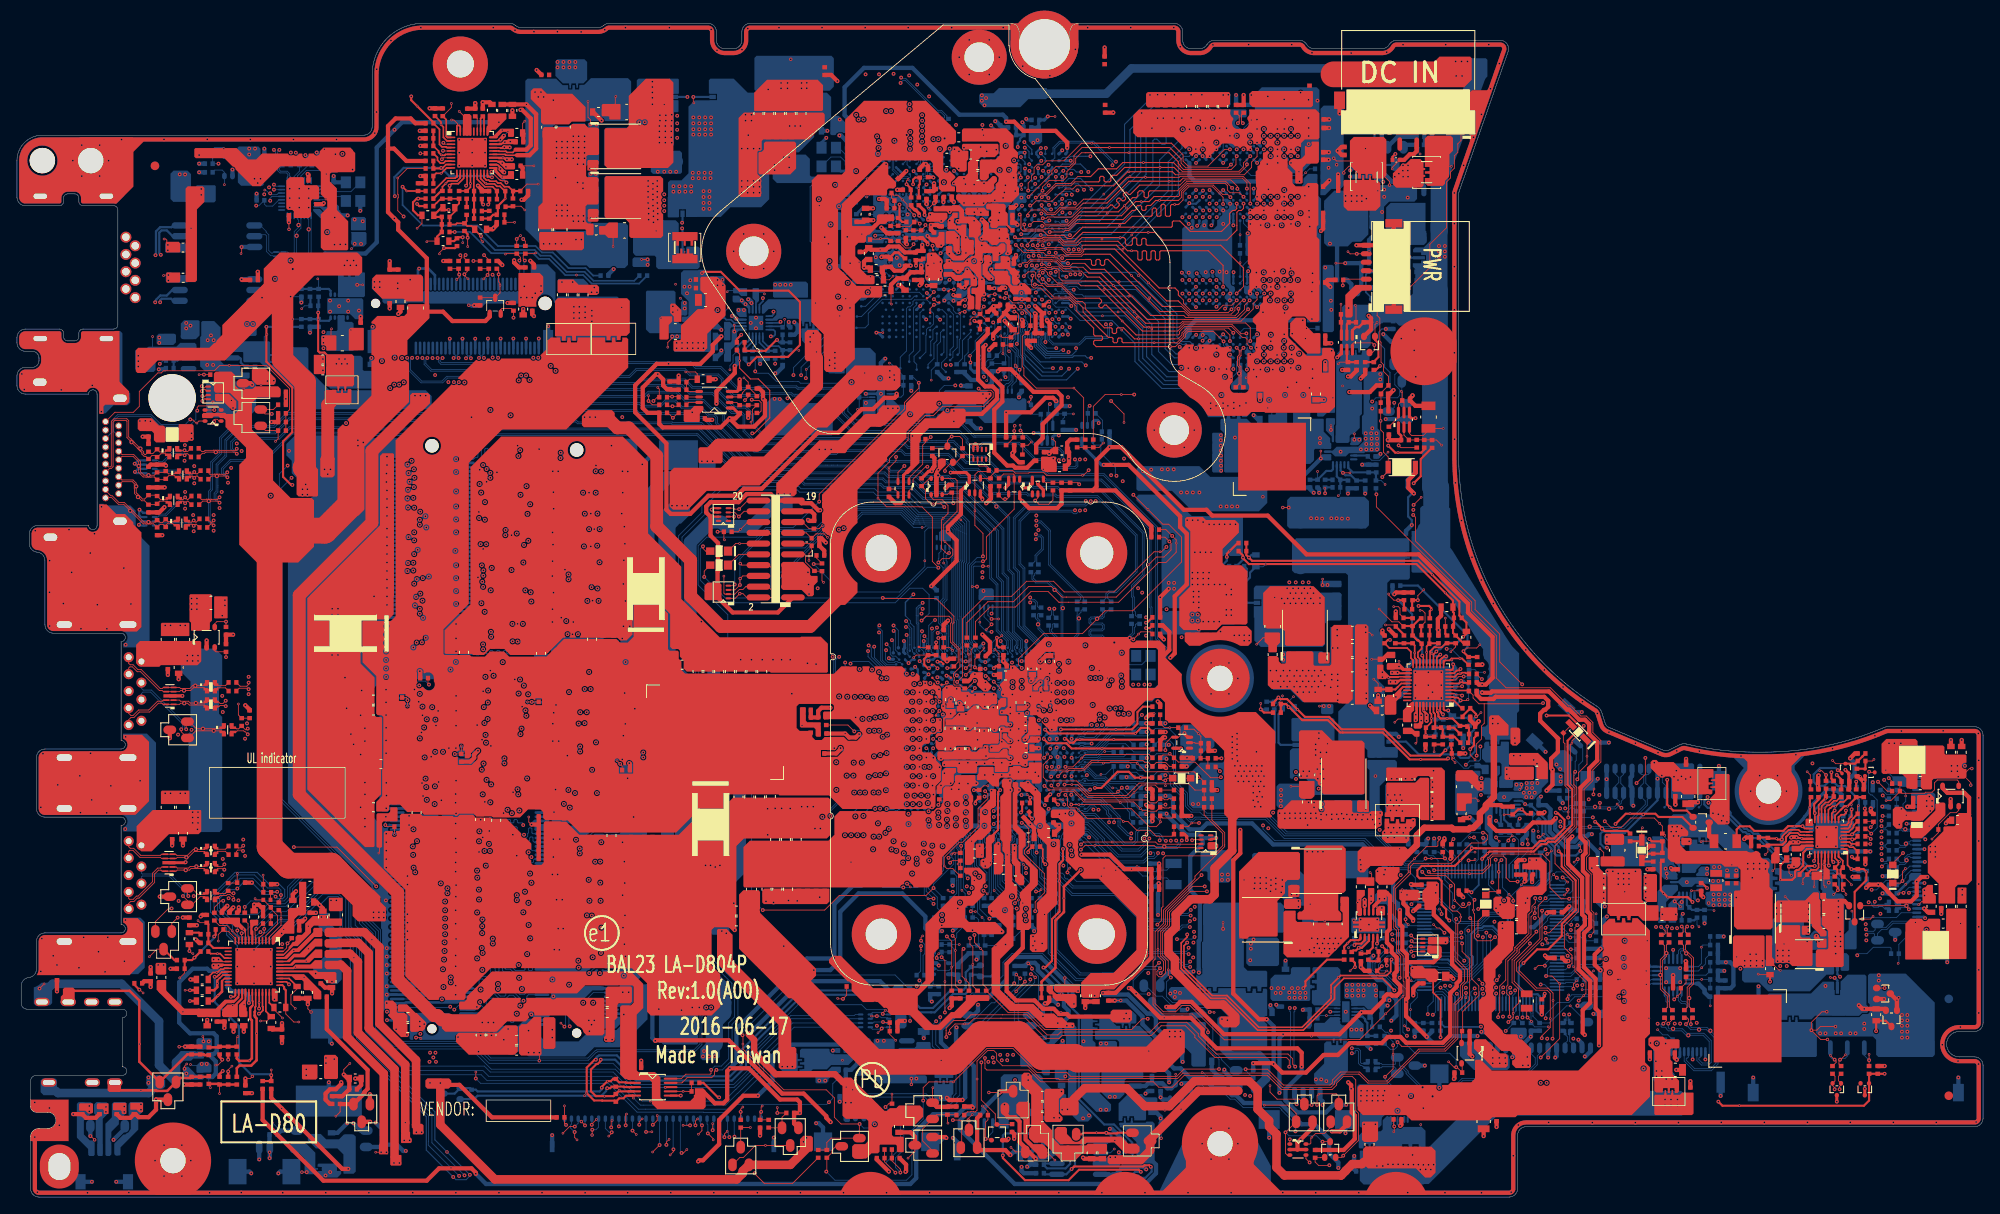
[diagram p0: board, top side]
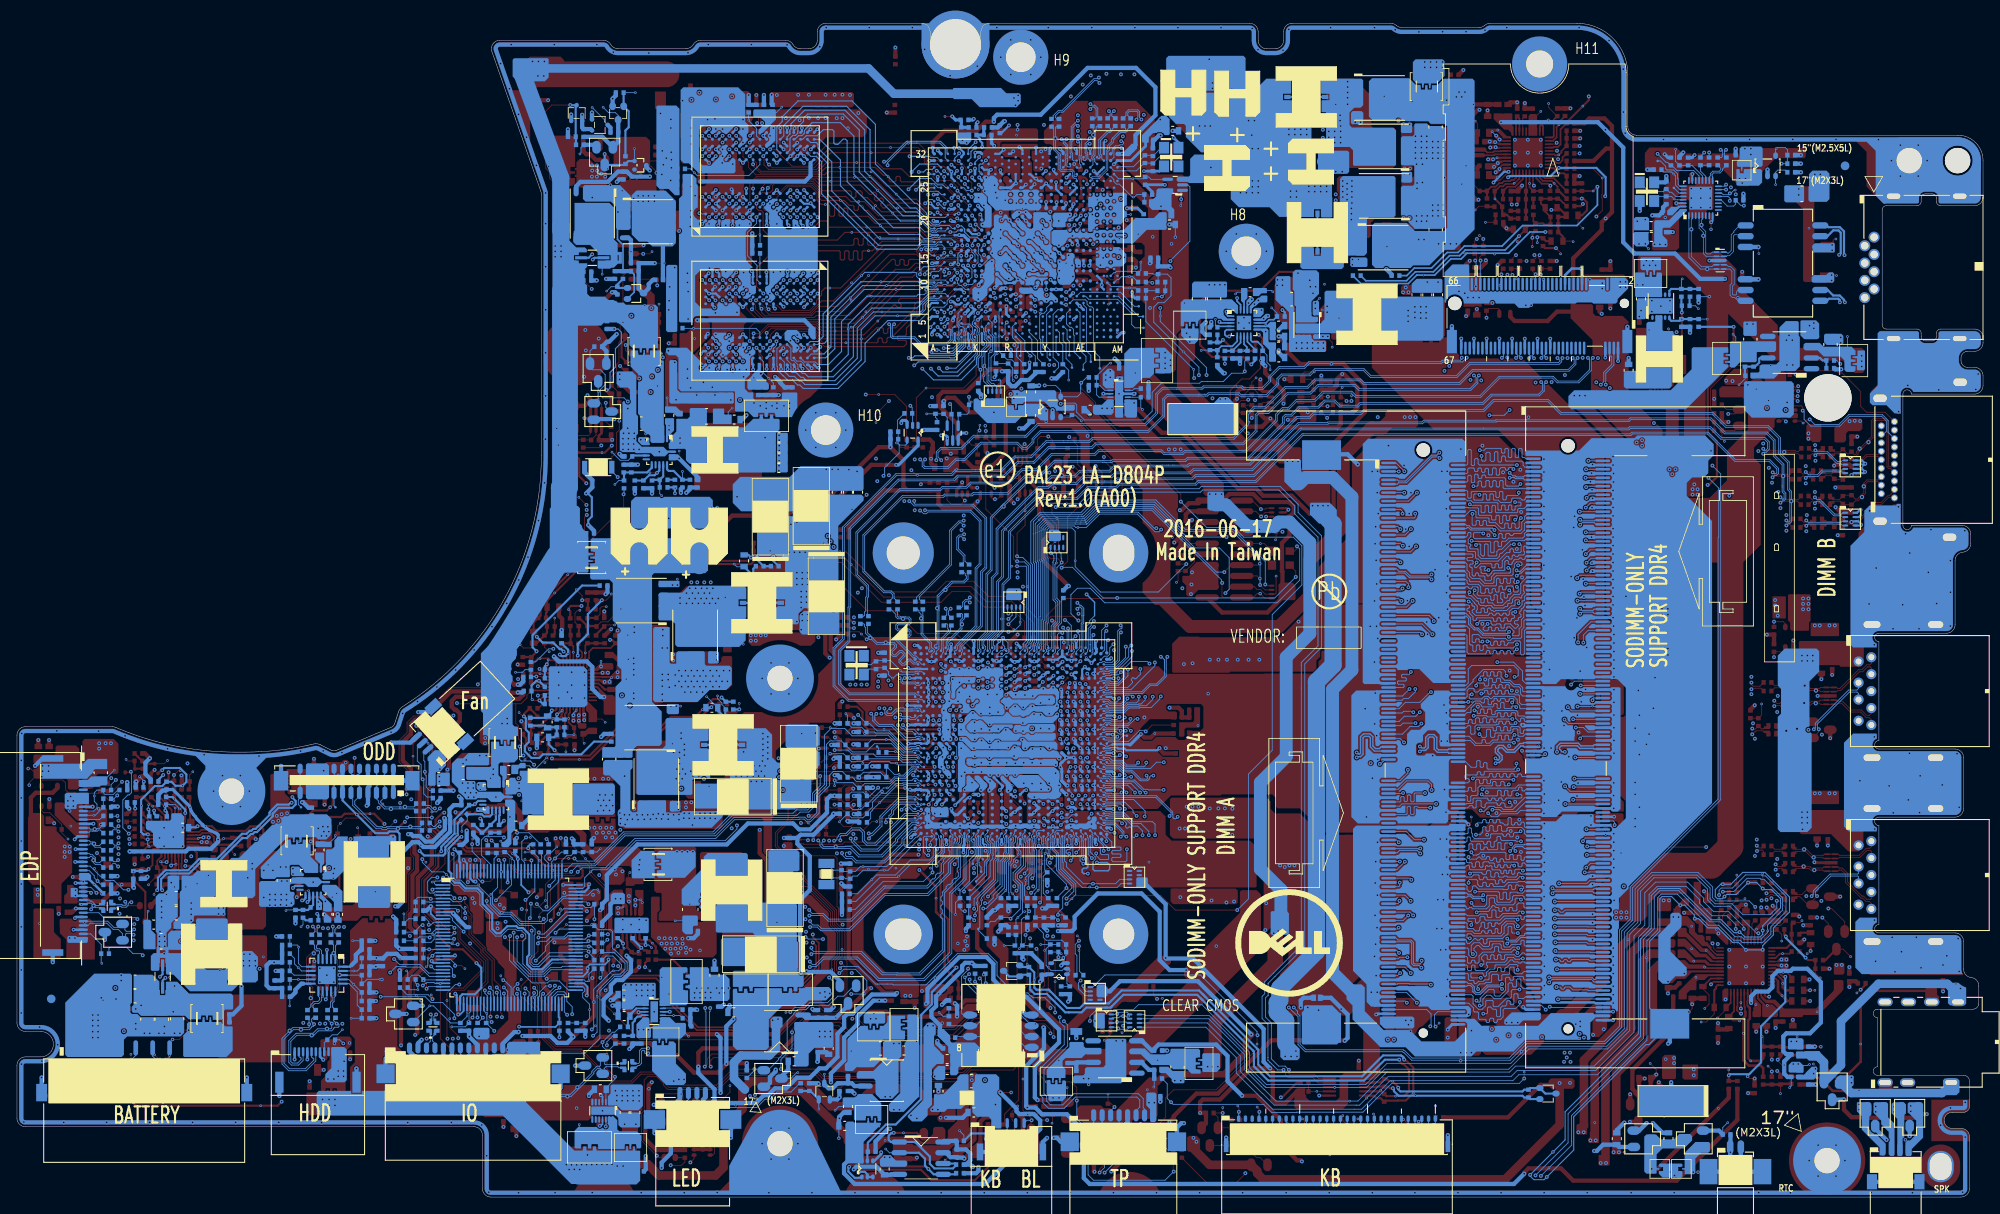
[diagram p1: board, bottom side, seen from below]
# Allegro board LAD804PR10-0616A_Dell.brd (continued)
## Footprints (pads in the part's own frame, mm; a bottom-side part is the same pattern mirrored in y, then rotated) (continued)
ACES_50271-0020N-001_2P
  oval 0.787x1.6 smd: 1(0,0) 2(1.25,0)
  rect 2.108x2.997 smd: 3(3.8,-2.9) 4(-2.55,-2.9)
ACES_50458-00601-001_6P-T
  oval 0.559x1.6 smd: 1(0,0) 2(2,0) 3(4,0) 4(6,0) 5(8,0) 6(10,0)
  rect 1.295x2.057 smd: 7(-3.1,-5.175) 8(13.1,-5.175)
ACES_50458-01001-P01_10P-T
  oval 0.559x1.803 smd: 1(0,0) 2(2,0) 3(4,0) 4(6,0) 5(8,0) 6(10,0) 7(12,0) 8(14,0) 9(16,0) 10(18,0)
  rect 1.295x2.057 smd: 11(-3.1,-5.275) 12(21.1,-5.275)
ACES_50673-0120N-001_12P-T
  oval 0.61x1.499 smd: 1(0,0) 3(-1,0) 5(-2,0) 7(-3,0) 9(-4,0) 11(-5,0) 13(-6,0) 15(-7,0) 17(-8,0) 19(-9,0) 21(-10,0) 23(-11,0)
  oval 0.61x1.194 smd: 2(0,2.85) 4(-1,2.85) 6(-2,2.85) 8(-3,2.85) 10(-4,2.85) 12(-5,2.85) 14(-6,2.85) 16(-7,2.85) 18(-8,2.85) 20(-9,2.85) 22(-10,2.85) 24(-11,2.85)
  rect 1.702x2.311 smd: 25(-13.25,1.425) 26(2.25,1.425)
ACES_51524-0040N-001_4P
  oval 0.61x1.448 smd: 1(0,0) 2(1,0) 3(2,0) 4(3,0)
  rect 2.489x2.21 smd: 5(-3,-3.125) 6(6,-3.125)
ACES_51524-0160N-001_16P
  oval 0.61x1.295 smd: 1(0,0) 2(1,0) 3(2,0) 4(3,0) 5(4,0) 6(5,0) 7(6,0) 8(7,0) 9(8,0) 10(9,0) 11(10,0) 12(11,0) 13(12,0) 14(13,0) 15(14,0) 16(15,0)
  rect 2.159x2.21 smd: 17(-2.825,-3.05) 18(17.825,-3.05)
ACES_51540-04001-P01_40P
  oval 0.305x1.092 smd: 1(0,0) 2(0.5,0) 3(1,0) 4(1.5,0) 5(2,0) 6(2.5,0) 7(3,0) 8(3.5,0) 9(4,0) 10(4.5,0) 11(5,0) 12(5.5,0) 13(6,0) 14(6.5,0) 15(7,0) 16(7.5,0) 17(8,0) 18(8.5,0) 19(9,0) 20(9.5,0) 21(10,0) 22(10.5,0) 23(11,0) 24(11.5,0) 25(12,0) 26(12.5,0) 27(13,0) 28(13.5,0) 29(14,0) 30(14.5,0) 31(15,0) 32(15.5,0) 33(16,0) 34(16.5,0) 35(17,0) 36(17.5,0) 37(18,0) 38(18.5,0) 39(19,0) 40(19.5,0)
  rect 0.787x2.489 smd: 41(21.2,-3.6) 42(-1.7,-3.6)
ACES_51575-00401-001_4P-T
  oval 0.406x1.194 smd: 1(0,0) 2(1,0) 3(2,0) 4(3,0)
  rect 0.787x2.007 smd: 5(-2.2,-3.4) 6(5.2,-3.4)
ACES_51625-01201-001_12P
  oval 0.305x1.092 smd: 1(0,0) 2(0.5,0) 3(1,0) 4(1.5,0) 5(2,0) 6(2.5,0) 7(3,0) 8(3.5,0) 9(4,0) 10(4.5,0) 11(5,0) 12(5.5,0)
  rect 0.991x2.489 smd: 13(-1.8,-3.6) 14(7.3,-3.6)
ACES_91960-0084L_8P-T
  oval 0.889x1.346 smd: 1(0,0) 2(-1.27,0) 3(-2.54,0) 4(-3.81,0) 5(-3.81,-7.35) 6(-2.54,-7.35) 7(-1.27,-7.35) 8(0,-7.35)
ACON_TARA4-9K1311_9P
  round 1.194 hole 0.711: 1(0,0) 2(-2.5,0) 3(-4.5,0) 4(-7,0) 5(-7.5,-1.5) 6(-5.5,-1.5) 7(-3.5,-1.5) 8(-1.5,-1.5) 9(0.5,-1.5)
  oval 1.397x2.591 hole 0.787x2.007: 10(-11.35,-1.59) 13(4.35,-1.59)
  oval 1.397x2.388 hole 0.787x1.803: 11(-11.35,-9.09) 12(4.35,-9.09)
ALC3246-CG_MQFN48_6X6-S
  oval 0.889x0.203 smd: 1(0,0) 2(0,-0.4) 3(0,-0.8) 4(0,-1.2) 5(0,-1.6) 6(0,-2) 7(0,-2.4) 8(0,-2.8) 9(0,-3.2) 10(0,-3.6) 11(0,-4) 12(0,-4.4) 25(6.1,-4.4) 26(6.1,-4) 27(6.1,-3.6) 28(6.1,-3.2) 29(6.1,-2.8) 30(6.1,-2.4) 31(6.1,-2) 32(6.1,-1.6) 33(6.1,-1.2) 34(6.1,-0.8) 35(6.1,-0.4) 36(6.1,0)
  oval 0.203x0.889 smd: 13(0.85,-5.25) 14(1.25,-5.25) 15(1.65,-5.25) 16(2.05,-5.25) 17(2.45,-5.25) 18(2.85,-5.25) 19(3.25,-5.25) 20(3.65,-5.25) 21(4.05,-5.25) 22(4.45,-5.25) 23(4.85,-5.25) 24(5.25,-5.25) 37(5.25,0.85) 38(4.85,0.85) 39(4.45,0.85) 40(4.05,0.85) 41(3.65,0.85) 42(3.25,0.85) 43(2.85,0.85) 44(2.45,0.85) 45(2.05,0.85) 46(1.65,0.85) 47(1.25,0.85) 48(0.85,0.85)
  rect 4.394x4.394 smd: 49(3.05,-2.2)
AO3416_SOT23-3
  oval 1.016x1.524 smd: 1(0,0) 2(0.965,2.083) 3(-0.965,2.083)
AO4430L_SO8
  oval 0.635x1.854 smd: 1(0,0) 2(1.27,0) 3(2.54,0) 4(3.81,0) 5(3.81,5.165) 6(2.54,5.165) 7(1.27,5.165) 8(0,5.165)
AON7934_DFN3X3A8-10
  oval 0.457x0.508 smd: 1(0,0) 2(0.65,0) 3(1.3,0) 4(1.95,0) 5(1.95,2.76) 6(1.3,2.76) 7(0.65,2.76) 8(0,2.76)
  rect 2.54x1.041 smd: 9(0.975,1.813)
  rect 2.54x0.559 smd: 10(0.975,0.708)
AP2138N-1P5TRG1_SOT23-3
  oval 1.016x1.524 smd: 1(0,0) 2(0.965,2.083) 3(-0.965,2.083)
APL5336KAI-TRL_SOP8P8
  oval 0.635x1.854 smd: 1(0,0) 2(1.27,0) 3(2.54,0) 4(3.81,0) 5(3.81,5.165) 6(2.54,5.165) 7(1.27,5.165) 8(0,5.165)
  rect 2.87x2.489 smd: 9(1.905,2.582)
AZ5123-02SPR7G_SOT23-3
  oval 1.016x1.524 smd: 1(0,0) 2(0.965,2.083) 3(-0.965,2.083)
AZ5125-02SPR7G_SOT23-3
  oval 1.016x1.524 smd: 1(0,0) 2(0.965,2.083) 3(-0.965,2.083)
AZ5725-01F_DFN2
  rect 0.559x0.61 smd: 1(0,0) 2(0.85,0)
AZC199-02SPR7G_SOT23-3
  oval 1.016x1.524 smd: 1(0,0) 2(0.965,2.083) 3(-0.965,2.083)
BAS40C_SOT23-3
  oval 1.016x1.524 smd: 1(0,0) 2(0.965,2.083) 3(-0.965,2.083)
BAT54C-7-F_SOT23-3
  oval 1.016x1.524 smd: 1(0,0) 2(0.965,2.083) 3(-0.965,2.083)
BAV99W_SC70-3
  oval 0.508x0.559 smd: 1(0,0) 2(-0.65,-1.85) 3(0.65,-1.85)
BOTH_NS14-1-LF_12P
  oval 0.762x1.905 smd: 1(0,0) 2(1.27,0) 3(2.54,0) 4(6.35,0) 5(7.62,0) 6(8.89,0) 7(8.89,8.8) 8(7.62,8.8) 9(6.35,8.8) 10(2.54,8.8) 11(1.27,8.8) 12(0,8.8)
C_5X4P5
  oval 2.997x1.6 smd: 1(0,0) 2(-4.4,0)
C_25CL33LD
  oval 3.607x1.803 smd: 1(0,0) 2(5.4,0)
C_0402
  rect 0.508x0.559 smd: 1(0,0) 2(0.914,0)
C_0603
  rect 0.635x0.889 smd: 1(0,0) 2(1.397,0)
C_0805
  rect 0.813x1.397 smd: 1(0,0) 2(1.702,0)
C_1206
  rect 1.016x1.651 smd: 1(0,0) 2(2.667,0)
C_D2
  rect 2.388x2.794 smd: 1(0,0) 2(6.4,0)
C_D3
  rect 2.388x2.794 smd: 1(0,0) 2(6.4,0)
CONCR_099AKAC19NBLCNF_19P
  round 0.813 hole 0.559: 1(0,0) 2(0.5,1.55) 3(1,0) 4(1.5,1.55) 5(2,0) 6(2.5,1.55) 7(3,0) 8(3.5,1.55) 9(4,0) 10(4.5,1.55) 11(5,0) 12(5.5,1.55) 13(6,0) 14(6.5,1.55) 15(7,0) 16(7.5,1.55) 17(8,0) 18(8.5,1.55) 19(9,0)
  oval 1.499x2.21 hole 0.889x1.6: 20(-2.75,1.7) 21(-4.65,-6.5) 22(11.75,1.7) 23(13.65,-7.75)
DB2J31400L_SOD323-2
  rect 0.991x1.092 smd: 1(0,0)
  rect 0.991x0.889 smd: 2(2.1,0)
DEREN_40-42261-26001RHF_260P-T
  round 1.092 hole 1.092 unplated: (-67.775,-4.1)
  round 1.6 hole 1.6 unplated: (1.025,-4.1)
  oval 0.305x1.753 smd: 1(0,0) 2(-0.25,-8.2) 3(-0.5,0) 4(-0.75,-8.2) 5(-1,0) 6(-1.25,-8.2) 7(-1.5,0) 8(-1.75,-8.2) 9(-2,0) 10(-2.25,-8.2) 11(-2.5,0) 12(-2.75,-8.2) 13(-3,0) 14(-3.25,-8.2) 15(-3.5,0) 16(-3.75,-8.2) 17(-4,0) 18(-4.25,-8.2) 19(-4.5,0) 20(-4.75,-8.2) 21(-5,0) 22(-5.25,-8.2) 23(-5.5,0) 24(-5.75,-8.2) 25(-6,0) 26(-6.25,-8.2) 27(-6.5,0) 28(-6.75,-8.2) 29(-7,0) 30(-7.25,-8.2) 31(-7.5,0) 32(-7.75,-8.2) 33(-8,0) 34(-8.25,-8.2) 35(-8.5,0) 36(-8.75,-8.2) 37(-9,0) 38(-9.25,-8.2) 39(-9.5,0) 40(-9.75,-8.2) 41(-10,0) 42(-10.25,-8.2) 43(-10.5,0) 44(-10.75,-8.2) 45(-11,0) 46(-11.25,-8.2) 47(-11.5,0) 48(-11.75,-8.2) 49(-12,0) 50(-12.25,-8.2) 51(-12.5,0) 52(-12.75,-8.2) 53(-13,0) 54(-13.25,-8.2) 55(-13.5,0) 56(-13.75,-8.2) 57(-14,0) 58(-14.25,-8.2) 59(-14.5,0) 60(-14.75,-8.2) 61(-15,0) 62(-15.25,-8.2) 63(-15.5,0) 64(-15.75,-8.2) 65(-16,0) 66(-16.25,-8.2) 67(-16.5,0) 68(-16.75,-8.2) 69(-17,0) 70(-17.25,-8.2) 71(-17.5,0) 72(-17.75,-8.2) 73(-18,0) 74(-18.25,-8.2) 75(-18.5,0) 76(-18.75,-8.2) 77(-19,0) 78(-19.25,-8.2) 79(-19.5,0) 80(-19.75,-8.2) 81(-20,0) 82(-20.25,-8.2) 83(-20.5,0) 84(-20.75,-8.2) 85(-21,0) 86(-21.25,-8.2) 87(-21.5,0) 88(-21.75,-8.2) 89(-22,0) 90(-22.25,-8.2) 91(-22.5,0) 92(-22.75,-8.2) 93(-23,0) 94(-23.25,-8.2) 95(-23.5,0) 96(-23.75,-8.2) 97(-24,0) 98(-24.25,-8.2) 99(-24.5,0) 100(-24.75,-8.2) 101(-25,0) 102(-25.25,-8.2) 103(-25.5,0) 104(-25.75,-8.2) 105(-26,0) 106(-26.25,-8.2) 107(-26.5,0) 108(-26.75,-8.2) 109(-27,0) 110(-27.25,-8.2) 111(-27.5,0) 112(-27.75,-8.2) 113(-28,0) 114(-28.25,-8.2) 115(-28.5,0) 116(-28.75,-8.2) 117(-29,0) 118(-29.25,-8.2) 119(-29.5,0) 120(-29.75,-8.2) 121(-30,0) 122(-30.25,-8.2) 123(-30.5,0) 124(-30.75,-8.2) 125(-31,0) 126(-31.25,-8.2) 127(-31.5,0) 128(-31.75,-8.2) 129(-32,0) 130(-32.25,-8.2) 131(-32.5,0) 132(-32.75,-8.2) 133(-33,0) 134(-33.25,-8.2) 135(-33.5,0) 136(-33.75,-8.2) 137(-34,0) 138(-34.25,-8.2) 139(-34.5,0) 140(-34.75,-8.2) 141(-35,0) 142(-35.25,-8.2) 143(-35.5,0) 144(-35.75,-8.2) 145(-38,0) 146(-38.25,-8.2) 147(-38.5,0) 148(-38.75,-8.2) 149(-39,0) 150(-39.25,-8.2) 151(-39.5,0) 152(-39.75,-8.2) 153(-40,0) 154(-40.25,-8.2) 155(-40.5,0) 156(-40.75,-8.2) 157(-41,0) 158(-41.25,-8.2) 159(-41.5,0) 160(-41.75,-8.2) 161(-42,0) 162(-42.25,-8.2) 163(-42.5,0) 164(-42.75,-8.2) 165(-43,0) 166(-43.25,-8.2) 167(-43.5,0) 168(-43.75,-8.2) 169(-44,0) 170(-44.25,-8.2) 171(-44.5,0) 172(-44.75,-8.2) 173(-45,0) 174(-45.25,-8.2) 175(-45.5,0) 176(-45.75,-8.2) 177(-46,0) 178(-46.25,-8.2) 179(-46.5,0) 180(-46.75,-8.2) 181(-47,0) 182(-47.25,-8.2) 183(-47.5,0) 184(-47.75,-8.2) 185(-48,0) 186(-48.25,-8.2) 187(-48.5,0) 188(-48.75,-8.2) 189(-49,0) 190(-49.25,-8.2) 191(-49.5,0) 192(-49.75,-8.2) 193(-50,0) 194(-50.25,-8.2) 195(-50.5,0) 196(-50.75,-8.2) 197(-51,0) 198(-51.25,-8.2) 199(-51.5,0) 200(-51.75,-8.2) 201(-52,0) 202(-52.25,-8.2) 203(-52.5,0) 204(-52.75,-8.2) 205(-53,0) 206(-53.25,-8.2) 207(-53.5,0) 208(-53.75,-8.2) 209(-54,0) 210(-54.25,-8.2) 211(-54.5,0) 212(-54.75,-8.2) 213(-55,0) 214(-55.25,-8.2) 215(-55.5,0) 216(-55.75,-8.2) 217(-56,0) 218(-56.25,-8.2) 219(-56.5,0) 220(-56.75,-8.2) 221(-57,0) 222(-57.25,-8.2) 223(-57.5,0) 224(-57.75,-8.2) 225(-58,0) 226(-58.25,-8.2) 227(-58.5,0) 228(-58.75,-8.2) 229(-59,0) 230(-59.25,-8.2) 231(-59.5,0) 232(-59.75,-8.2) 233(-60,0) 234(-60.25,-8.2) 235(-60.5,0) 236(-60.75,-8.2) 237(-61,0) 238(-61.25,-8.2) 239(-61.5,0) 240(-61.75,-8.2) 241(-62,0) 242(-62.25,-8.2) 243(-62.5,0) 244(-62.75,-8.2) 245(-63,0) 246(-63.25,-8.2) 247(-63.5,0) 248(-63.75,-8.2) 249(-64,0) 250(-64.25,-8.2) 251(-64.5,0) 252(-64.75,-8.2) 253(-65,0) 254(-65.25,-8.2) 255(-65.5,0) 256(-65.75,-8.2) 257(-66,0) 258(-66.25,-8.2) 259(-66.5,0) 260(-66.75,-8.2)
  rect 3.505x4.597 smd: 261(0.425,-16.1) 262(-67.175,-16.1)
DEREN_40-42271-26001RHF_260P-T
  round 1.6 hole 1.6 unplated: (-1.025,4.1)
  round 1.092 hole 1.092 unplated: (67.775,4.1)
  oval 0.305x1.753 smd: 1(0,0) 2(0.25,8.2) 3(0.5,0) 4(0.75,8.2) 5(1,0) 6(1.25,8.2) 7(1.5,0) 8(1.75,8.2) 9(2,0) 10(2.25,8.2) 11(2.5,0) 12(2.75,8.2) 13(3,0) 14(3.25,8.2) 15(3.5,0) 16(3.75,8.2) 17(4,0) 18(4.25,8.2) 19(4.5,0) 20(4.75,8.2) 21(5,0) 22(5.25,8.2) 23(5.5,0) 24(5.75,8.2) 25(6,0) 26(6.25,8.2) 27(6.5,0) 28(6.75,8.2) 29(7,0) 30(7.25,8.2) 31(7.5,0) 32(7.75,8.2) 33(8,0) 34(8.25,8.2) 35(8.5,0) 36(8.75,8.2) 37(9,0) 38(9.25,8.2) 39(9.5,0) 40(9.75,8.2) 41(10,0) 42(10.25,8.2) 43(10.5,0) 44(10.75,8.2) 45(11,0) 46(11.25,8.2) 47(11.5,0) 48(11.75,8.2) 49(12,0) 50(12.25,8.2) 51(12.5,0) 52(12.75,8.2) 53(13,0) 54(13.25,8.2) 55(13.5,0) 56(13.75,8.2) 57(14,0) 58(14.25,8.2) 59(14.5,0) 60(14.75,8.2) 61(15,0) 62(15.25,8.2) 63(15.5,0) 64(15.75,8.2) 65(16,0) 66(16.25,8.2) 67(16.5,0) 68(16.75,8.2) 69(17,0) 70(17.25,8.2) 71(17.5,0) 72(17.75,8.2) 73(18,0) 74(18.25,8.2) 75(18.5,0) 76(18.75,8.2) 77(19,0) 78(19.25,8.2) 79(19.5,0) 80(19.75,8.2) 81(20,0) 82(20.25,8.2) 83(20.5,0) 84(20.75,8.2) 85(21,0) 86(21.25,8.2) 87(21.5,0) 88(21.75,8.2) 89(22,0) 90(22.25,8.2) 91(22.5,0) 92(22.75,8.2) 93(23,0) 94(23.25,8.2) 95(23.5,0) 96(23.75,8.2) 97(24,0) 98(24.25,8.2) 99(24.5,0) 100(24.75,8.2) 101(25,0) 102(25.25,8.2) 103(25.5,0) 104(25.75,8.2) 105(26,0) 106(26.25,8.2) 107(26.5,0) 108(26.75,8.2) 109(27,0) 110(27.25,8.2) 111(27.5,0) 112(27.75,8.2) 113(28,0) 114(28.25,8.2) 115(28.5,0) 116(28.75,8.2) 117(29,0) 118(29.25,8.2) 119(29.5,0) 120(29.75,8.2) 121(30,0) 122(30.25,8.2) 123(30.5,0) 124(30.75,8.2) 125(31,0) 126(31.25,8.2) 127(31.5,0) 128(31.75,8.2) 129(32,0) 130(32.25,8.2) 131(32.5,0) 132(32.75,8.2) 133(33,0) 134(33.25,8.2) 135(33.5,0) 136(33.75,8.2) 137(34,0) 138(34.25,8.2) 139(34.5,0) 140(34.75,8.2) 141(35,0) 142(35.25,8.2) 143(35.5,0) 144(35.75,8.2) 145(38,0) 146(38.25,8.2) 147(38.5,0) 148(38.75,8.2) 149(39,0) 150(39.25,8.2) 151(39.5,0) 152(39.75,8.2) 153(40,0) 154(40.25,8.2) 155(40.5,0) 156(40.75,8.2) 157(41,0) 158(41.25,8.2) 159(41.5,0) 160(41.75,8.2) 161(42,0) 162(42.25,8.2) 163(42.5,0) 164(42.75,8.2) 165(43,0) 166(43.25,8.2) 167(43.5,0) 168(43.75,8.2) 169(44,0) 170(44.25,8.2) 171(44.5,0) 172(44.75,8.2) 173(45,0) 174(45.25,8.2) 175(45.5,0) 176(45.75,8.2) 177(46,0) 178(46.25,8.2) 179(46.5,0) 180(46.75,8.2) 181(47,0) 182(47.25,8.2) 183(47.5,0) 184(47.75,8.2) 185(48,0) 186(48.25,8.2) 187(48.5,0) 188(48.75,8.2) 189(49,0) 190(49.25,8.2) 191(49.5,0) 192(49.75,8.2) 193(50,0) 194(50.25,8.2) 195(50.5,0) 196(50.75,8.2) 197(51,0) 198(51.25,8.2) 199(51.5,0) 200(51.75,8.2) 201(52,0) 202(52.25,8.2) 203(52.5,0) 204(52.75,8.2) 205(53,0) 206(53.25,8.2) 207(53.5,0) 208(53.75,8.2) 209(54,0) 210(54.25,8.2) 211(54.5,0) 212(54.75,8.2) 213(55,0) 214(55.25,8.2) 215(55.5,0) 216(55.75,8.2) 217(56,0) 218(56.25,8.2) 219(56.5,0) 220(56.75,8.2) 221(57,0) 222(57.25,8.2) 223(57.5,0) 224(57.75,8.2) 225(58,0) 226(58.25,8.2) 227(58.5,0) 228(58.75,8.2) 229(59,0) 230(59.25,8.2) 231(59.5,0) 232(59.75,8.2) 233(60,0) 234(60.25,8.2) 235(60.5,0) 236(60.75,8.2) 237(61,0) 238(61.25,8.2) 239(61.5,0) 240(61.75,8.2) 241(62,0) 242(62.25,8.2) 243(62.5,0) 244(62.75,8.2) 245(63,0) 246(63.25,8.2) 247(63.5,0) 248(63.75,8.2) 249(64,0) 250(64.25,8.2) 251(64.5,0) 252(64.75,8.2) 253(65,0) 254(65.25,8.2) 255(65.5,0) 256(65.75,8.2) 257(66,0) 258(66.25,8.2) 259(66.5,0) 260(66.75,8.2)
  rect 3.505x4.597 smd: 261(-0.425,-7.9) 262(67.175,-7.9)
DMN66D0LDW-7_SOT363-6
  oval 0.432x0.61 smd: 1(0,0) 2(0.65,0) 3(1.3,0) 4(1.3,1.9) 5(0.65,1.9) 6(0,1.9)
EMC1403-2-AIZL-TR_MSOP10
  oval 0.254x1.626 smd: 1(0,0) 2(0.5,0) 3(1,0) 4(1.5,0) 5(2,0) 6(2,4.3) 7(1.5,4.3) 8(1,4.3) 9(0.5,4.3) 10(0,4.3)
EMIST_SQ-55G_1P
  rect 7.798x3.658 smd: 1(0,0)
F_1206L150PR
  rect 0.991x1.803 smd: 1(0,0) 2(2.8,0)
F_MF-NSMF050-2
  rect 0.991x1.6 smd: 1(0,0) 2(3,0)
F_SMD1812P110TF-24
  rect 1.778x3.15 smd: 1(0,0) 2(5.23,0)
FDV301N_NL_SOT23-3
  oval 1.016x1.524 smd: 1(0,0) 2(0.965,2.083) 3(-0.965,2.083)
FIDUCIAL_C40M80
  round 1.016 smd: 1(0,0)
H5GC4H24AJR-R0C_BGA_170P
  round 0.343 smd: A1(0,0) A2(0.8,0) A3(1.6,0) A4(2.4,0) A5(3.2,0) A10(7.201,0) A11(8.001,0) A12(8.801,0) A13(9.601,0) A14(10.401,0) B1(0,-0.8) B2(0.8,-0.8) B3(1.6,-0.8) B4(2.4,-0.8) B5(3.2,-0.8) B10(7.201,-0.8) B11(8.001,-0.8) B12(8.801,-0.8) B13(9.601,-0.8) B14(10.401,-0.8) C1(0,-1.6) C2(0.8,-1.6) C3(1.6,-1.6) C4(2.4,-1.6) C5(3.2,-1.6) C10(7.201,-1.6) C11(8.001,-1.6) C12(8.801,-1.6) C13(9.601,-1.6) C14(10.401,-1.6) D1(0,-2.4) D2(0.8,-2.4) D3(1.6,-2.4) D4(2.4,-2.4) D5(3.2,-2.4) D10(7.201,-2.4) D11(8.001,-2.4) D12(8.801,-2.4) D13(9.601,-2.4) D14(10.401,-2.4) E1(0,-3.2) E2(0.8,-3.2) E3(1.6,-3.2) E4(2.4,-3.2) E5(3.2,-3.2) E10(7.201,-3.2) E11(8.001,-3.2) E12(8.801,-3.2) E13(9.601,-3.2) E14(10.401,-3.2) F1(0,-4) F2(0.8,-4) F3(1.6,-4) F4(2.4,-4) F5(3.2,-4) F10(7.201,-4) F11(8.001,-4) F12(8.801,-4) F13(9.601,-4) F14(10.401,-4) G1(0,-4.801) G2(0.8,-4.801) G3(1.6,-4.801) G4(2.4,-4.801) G5(3.2,-4.801) G10(7.201,-4.801) G11(8.001,-4.801) G12(8.801,-4.801) G13(9.601,-4.801) G14(10.401,-4.801) H1(0,-5.601) H2(0.8,-5.601) H3(1.6,-5.601) H4(2.4,-5.601) H5(3.2,-5.601) H10(7.201,-5.601) H11(8.001,-5.601) H12(8.801,-5.601) H13(9.601,-5.601) H14(10.401,-5.601) J1(0,-6.401) J2(0.8,-6.401) J3(1.6,-6.401) J4(2.4,-6.401) J5(3.2,-6.401) J10(7.201,-6.401) J11(8.001,-6.401) J12(8.801,-6.401) J13(9.601,-6.401) J14(10.401,-6.401) K1(0,-7.201) K2(0.8,-7.201) K3(1.6,-7.201) K4(2.4,-7.201) K5(3.2,-7.201) K10(7.201,-7.201) K11(8.001,-7.201) K12(8.801,-7.201) K13(9.601,-7.201) K14(10.401,-7.201) L1(0,-8.001) L2(0.8,-8.001) L3(1.6,-8.001) L4(2.4,-8.001) L5(3.2,-8.001) L10(7.201,-8.001) L11(8.001,-8.001) L12(8.801,-8.001) L13(9.601,-8.001) L14(10.401,-8.001) M1(0,-8.801) M2(0.8,-8.801) M3(1.6,-8.801) M4(2.4,-8.801) M5(3.2,-8.801) M10(7.201,-8.801) M11(8.001,-8.801) M12(8.801,-8.801) M13(9.601,-8.801) M14(10.401,-8.801) N1(0,-9.601) N2(0.8,-9.601) N3(1.6,-9.601) N4(2.4,-9.601) N5(3.2,-9.601) N10(7.201,-9.601) N11(8.001,-9.601) N12(8.801,-9.601) N13(9.601,-9.601) N14(10.401,-9.601) P1(0,-10.401) P2(0.8,-10.401) P3(1.6,-10.401) P4(2.4,-10.401) P5(3.2,-10.401) P10(7.201,-10.401) P11(8.001,-10.401) P12(8.801,-10.401) P13(9.601,-10.401) P14(10.401,-10.401) R1(0,-11.201) R2(0.8,-11.201) R3(1.6,-11.201) R4(2.4,-11.201) R5(3.2,-11.201) R10(7.201,-11.201) R11(8.001,-11.201) R12(8.801,-11.201) R13(9.601,-11.201) R14(10.401,-11.201) T1(0,-12.002) T2(0.8,-12.002) T3(1.6,-12.002) T4(2.4,-12.002) T5(3.2,-12.002) T10(7.201,-12.002) T11(8.001,-12.002) T12(8.801,-12.002) T13(9.601,-12.002) T14(10.401,-12.002) U1(0,-12.802) U2(0.8,-12.802) U3(1.6,-12.802) U4(2.4,-12.802) U5(3.2,-12.802) U10(7.201,-12.802) U11(8.001,-12.802) U12(8.801,-12.802) U13(9.601,-12.802) U14(10.401,-12.802)
H_3P0-G
  round 3.505 hole 2.997: 1(0,0)
H_3P0N
  round 2.997 hole 2.997 unplated: (0,0)
H_3P2
  round 3.708 hole 3.2: 1(0,0)
H_3P2X2P6
  oval 3.708x3.099 hole 3.2x2.591: 1(0,0)
H_3P5-G
  round 4.013 hole 3.505: 1(0,0)
H_3P7
  round 4.216 hole 3.708: 1(0,0)
H_3P7X4P3
  oval 4.216x4.801 hole 3.708x4.293: 1(0,0)
H_3P9
  round 4.42 hole 3.912: 1(0,0)
H_5P6N
  round 5.588 hole 5.588 unplated: (0,0)
H_6P0
  round 6.502 hole 5.994: 1(0,0)
INPAQ_HCM1012GD670A05P_4P
  rect 0.508x0.305 smd: 1(0,0) 2(1.25,0) 3(1.25,-0.55) 4(0,-0.55)
INPAQ_HCM1012GH900BP_4P
  rect 0.711x0.305 smd: 1(0,0) 2(1.25,0) 3(1.25,-0.5) 4(0,-0.5)
INPAQ_MCM1012B900F06BP_4P
  rect 0.711x0.305 smd: 1(0,0) 2(1.25,0) 3(1.25,-0.5) 4(0,-0.5)
ISL62771HRTZ-T_TQFN40_5X5-S
  oval 0.203x1.016 smd: 1(0,0) 2(0.4,0) 3(0.8,0) 4(1.2,0) 5(1.6,0) 6(2,0) 7(2.4,0) 8(2.8,0) 9(3.2,0) 10(3.6,0) 21(3.6,4.975) 22(3.2,4.975) 23(2.8,4.975) 24(2.4,4.975) 25(2,4.975) 26(1.6,4.975) 27(1.2,4.975) 28(0.8,4.975) 29(0.4,4.975) 30(0,4.975)
  oval 1.016x0.203 smd: 11(4.288,0.688) 12(4.288,1.088) 13(4.288,1.488) 14(4.288,1.888) 15(4.288,2.288) 16(4.288,2.688) 17(4.288,3.088) 18(4.288,3.488) 19(4.288,3.888) 20(4.288,4.288) 31(-0.688,4.288) 32(-0.688,3.888) 33(-0.688,3.488) 34(-0.688,3.088) 35(-0.688,2.688) 36(-0.688,2.288) 37(-0.688,1.888) 38(-0.688,1.488) 39(-0.688,1.088) 40(-0.688,0.688)
  rect 3.505x3.505 smd: 41(1.8,2.488)
ISL95520HRZ-T_QFN32_4X4-S
  oval 0.889x0.203 smd: 1(0,0) 2(0,-0.4) 3(0,-0.8) 4(0,-1.2) 5(0,-1.6) 6(0,-2) 7(0,-2.4) 8(0,-2.8) 17(4.1,-2.8) 18(4.1,-2.4) 19(4.1,-2) 20(4.1,-1.6) 21(4.1,-1.2) 22(4.1,-0.8) 23(4.1,-0.4) 24(4.1,0)
  oval 0.203x0.889 smd: 9(0.65,-3.45) 10(1.05,-3.45) 11(1.45,-3.45) 12(1.85,-3.45) 13(2.25,-3.45) 14(2.65,-3.45) 15(3.05,-3.45) 16(3.45,-3.45) 25(3.45,0.65) 26(3.05,0.65) 27(2.65,0.65) 28(2.25,0.65) 29(1.85,0.65) 30(1.45,0.65) 31(1.05,0.65) 32(0.65,0.65)
  rect 2.642x2.642 smd: 33(2.05,-1.4)
JUMP_43X39
  custom 0.191x0.191 smd: 1(0,0) 2(0.914,0)
JUMP_43X79
  custom 0.188x0.188 smd: 1(0,0) 2(1.1,0)
JUMP_43X79-NPM
  custom 0.188x0.188 smd: 1(0,0) 2(1.1,0)
JUMP_43X118
  custom 0.187x0.187 smd: 1(0,0) 2(1.1,0)
JUMP_43X118-NPM
  custom 0.187x0.187 smd: 1(0,0) 2(1.1,0)
JXT_FP202DH-008M10M_8P
  oval 0.61x1.448 smd: 1(0,0) 2(1,0) 3(2,0) 4(3,0) 5(4,0) 6(5,0) 7(6,0) 8(7,0)
  rect 2.159x2.21 smd: 9(-2.825,-3.125) 10(9.825,-3.125)
JXT_FP226H-006S1BM_6P
  oval 0.61x1.295 smd: 1(0,0) 2(1,0) 3(2,0) 4(3,0) 5(4,0) 6(5,0)
  rect 0.991x2.007 smd: 7(-2.6,-3.25) 8(7.6,-3.25)
JXT_WB247H-004S10M_4P
  oval 0.61x1.549 smd: 1(0,0) 2(1,0) 3(2,0) 4(3,0)
  rect 1.194x1.803 smd: 5(-1.3,-3.875) 6(4.3,-3.875)
KB9022QD_LQFP128_14X14
  oval 1.753x0.203 smd: 1(0,0) 2(0,-0.4) 3(0,-0.8) 4(0,-1.2) 5(0,-1.6) 6(0,-2) 7(0,-2.4) 8(0,-2.8) 9(0,-3.2) 10(0,-3.6) 11(0,-4) 12(0,-4.4) 13(0,-4.8) 14(0,-5.2) 15(0,-5.6) 16(0,-6) 17(0,-6.4) 18(0,-6.8) 19(0,-7.2) 20(0,-7.6) 21(0,-8) 22(0,-8.4) 23(0,-8.8) 24(0,-9.2) 25(0,-9.6) 26(0,-10) 27(0,-10.4) 28(0,-10.8) 29(0,-11.2) 30(0,-11.6) 31(0,-12) 32(0,-12.4) 65(15.654,-12.4) 66(15.654,-12) 67(15.654,-11.6) 68(15.654,-11.2) 69(15.654,-10.8) 70(15.654,-10.4) 71(15.654,-10) 72(15.654,-9.6) 73(15.654,-9.2) 74(15.654,-8.8) 75(15.654,-8.4) 76(15.654,-8) 77(15.654,-7.6) 78(15.654,-7.2) 79(15.654,-6.8) 80(15.654,-6.4) 81(15.654,-6) 82(15.654,-5.6) 83(15.654,-5.2) 84(15.654,-4.8) 85(15.654,-4.4) 86(15.654,-4) 87(15.654,-3.6) 88(15.654,-3.2) 89(15.654,-2.8) 90(15.654,-2.4) 91(15.654,-2) 92(15.654,-1.6) 93(15.654,-1.2) 94(15.654,-0.8) 95(15.654,-0.4) 96(15.654,0)
  oval 0.203x1.753 smd: 33(1.627,-14.027) 34(2.027,-14.027) 35(2.427,-14.027) 36(2.827,-14.027) 37(3.227,-14.027) 38(3.627,-14.027) 39(4.027,-14.027) 40(4.427,-14.027) 41(4.827,-14.027) 42(5.227,-14.027) 43(5.627,-14.027) 44(6.027,-14.027) 45(6.427,-14.027) 46(6.827,-14.027) 47(7.227,-14.027) 48(7.627,-14.027) 49(8.027,-14.027) 50(8.427,-14.027) 51(8.827,-14.027) 52(9.227,-14.027) 53(9.627,-14.027) 54(10.027,-14.027) 55(10.427,-14.027) 56(10.827,-14.027) 57(11.227,-14.027) 58(11.627,-14.027) 59(12.027,-14.027) 60(12.427,-14.027) 61(12.827,-14.027) 62(13.227,-14.027) 63(13.627,-14.027) 64(14.027,-14.027) 97(14.027,1.627) 98(13.627,1.627) 99(13.227,1.627) 100(12.827,1.627) 101(12.427,1.627) 102(12.027,1.627) 103(11.627,1.627) 104(11.227,1.627) 105(10.827,1.627) 106(10.427,1.627) 107(10.027,1.627) 108(9.627,1.627) 109(9.227,1.627) 110(8.827,1.627) 111(8.427,1.627) 112(8.027,1.627) 113(7.627,1.627) 114(7.227,1.627) 115(6.827,1.627) 116(6.427,1.627) 117(6.027,1.627) 118(5.627,1.627) 119(5.227,1.627) 120(4.827,1.627) 121(4.427,1.627) 122(4.027,1.627) 123(3.627,1.627) 124(3.227,1.627) 125(2.827,1.627) 126(2.427,1.627) 127(2.027,1.627) 128(1.627,1.627)
KC_FBMA-L11-160808-800LMT_2P
  rect 0.889x1.092 smd: 1(0,0) 2(1.5,0)
KC_FBMA-L11-201209-121LMA50_2P
  rect 0.991x1.702 smd: 1(0,0) 2(1.5,0)
L2N7002WT1G_SC70-3
  oval 0.711x0.889 smd: 1(0,0) 2(0.65,1.9) 3(-0.65,1.9)
L03ESDL5V0CC3-2_SOT23-3
  oval 1.016x1.524 smd: 1(0,0) 2(0.965,2.083) 3(-0.965,2.083)
L05ESDL5V0NA-4_SLP2510P8-10-9
  rect 0.203x0.686 smd: 1(0,0) 2(-0.5,0) 4(-1.5,0) 5(-2,0) 6(-2,-0.875) 7(-1.5,-0.875) 8(-0.5,-0.875) 9(0,-0.875)
  rect 0.406x1.549 smd: 3(-1,-0.437)
L_5X5X3_M_2P
  rect 2.159x2.794 smd: 1(0,0) 2(4.35,0)
L_7X7X3_M_2P
  rect 2.362x3.505 smd: 1(0,0) 2(6.05,0)
L_7X7X4_M
  custom 0.591x0.591 smd: 1(0,0) 4(6.05,0)
  rect 0.762x0.508 smd: 2(0.8,0) 3(5.25,0)
LCN_DAN05-67406-0100_67P
  round 1.092 hole 1.092 unplated: (-0.75,-5.275)
  round 1.6 hole 1.6 unplated: (19.25,-5.275)
  oval 0.305x1.549 smd: 1(0,0) 2(0.25,-7.55) 3(0.5,0) 4(0.75,-7.55) 5(1,0) 6(1.25,-7.55) 7(1.5,0) 8(3.75,-7.55) 9(4,0) 10(4.25,-7.55) 11(4.5,0) 12(4.75,-7.55) 13(5,0) 14(5.25,-7.55) 15(5.5,0) 16(5.75,-7.55) 17(6,0) 18(6.25,-7.55) 19(6.5,0) 20(6.75,-7.55) 21(7,0) 22(7.25,-7.55) 23(7.5,0) 24(7.75,-7.55) 25(8,0) 26(8.25,-7.55) 27(8.5,0) 28(8.75,-7.55) 29(9,0) 30(9.25,-7.55) 31(9.5,0) 32(9.75,-7.55) 33(10,0) 34(10.25,-7.55) 35(10.5,0) 36(10.75,-7.55) 37(11,0) 38(11.25,-7.55) 39(11.5,0) 40(11.75,-7.55) 41(12,0) 42(12.25,-7.55) 43(12.5,0) 44(12.75,-7.55) 45(13,0) 46(13.25,-7.55) 47(13.5,0) 48(13.75,-7.55) 49(14,0) 50(14.25,-7.55) 51(14.5,0) 52(14.75,-7.55) 53(15,0) 54(15.25,-7.55) 55(15.5,0) 56(15.75,-7.55) 57(16,0) 58(16.25,-7.55) 59(16.5,0) 60(16.75,-7.55) 61(17,0) 62(17.25,-7.55) 63(17.5,0) 64(17.75,-7.55) 65(18,0) 66(18.25,-7.55) 67(18.5,0)
  rect 1.194x2.743 smd: 68(-1.1,-0.775) 69(19.6,-0.775)
LM393DR_SO8
  oval 0.635x1.854 smd: 1(0,0) 2(1.27,0) 3(2.54,0) 4(3.81,0) 5(3.81,5.165) 6(2.54,5.165) 7(1.27,5.165) 8(0,5.165)
LMUN5113T1G_SOT323-3
  oval 0.711x0.889 smd: 1(0,0) 2(0.65,1.9) 3(-0.65,1.9)
LN2306LT1G_SOT23-3
  oval 1.016x1.524 smd: 1(0,0) 2(0.965,2.083) 3(-0.965,2.083)
LRB715FT1G_SOT323-3
  oval 0.711x0.889 smd: 1(0,0) 2(0.65,1.9) 3(-0.65,1.9)
LTC015EUBFS8TL_UMT3F
  oval 0.787x0.889 smd: 1(0,0) 2(-0.65,-1.6) 3(0.65,-1.6)
MDU1512RH_POWERDFN56-8-5
  oval 0.61x1.27 smd: 1(0,0) 2(1.27,0) 3(2.54,0) 4(3.81,0)
  custom 1.105x1.105 smd: 5(1.905,3.715)
MESS138W-G_SOT323-3
  oval 0.711x0.889 smd: 1(0,0) 2(-0.65,-1.9) 3(0.65,-1.9)
MMBT3904_NL_SOT23-3
  oval 1.016x1.524 smd: 1(0,0) 2(0.965,2.083) 3(-0.965,2.083)
MMST3904-7-F_SOT323-3
  oval 0.711x0.889 smd: 1(0,0) 2(0.65,1.9) 3(-0.65,1.9)
MURAT_BLM15AG102SN1D_2P
  rect 0.457x0.508 smd: 1(0,0) 2(0.85,0)
MURAT_BLM15BB221SN1D_2P
  rect 0.457x0.508 smd: 1(0,0) 2(0.85,0)
MURAT_BLM15PX330SN1D_2P
  rect 0.508x0.762 smd: 1(0,0) 2(0.75,0)
NC7SZ08P5X_NL_SC70-5
  oval 0.457x0.711 smd: 1(-0.65,-0.925) 2(0,-0.925) 3(0.65,-0.925) 4(0.65,0.925) 5(-0.65,0.925)
PESD5V0U2BT_SOT23-3
  oval 1.016x1.524 smd: 1(0,0) 2(0.965,2.083) 3(-0.965,2.083)
PS8520BTQFN20GTR2_TQFN20_4X4-S
  oval 0.254x1.194 smd: 1(0,0) 2(0.5,0) 3(1,0) 4(1.5,0) 5(2,0) 11(2,3.8) 12(1.5,3.8) 13(1,3.8) 14(0.5,3.8) 15(0,3.8)
  oval 1.194x0.254 smd: 6(2.9,0.9) 7(2.9,1.4) 8(2.9,1.9) 9(2.9,2.4) 10(2.9,2.9) 16(-0.9,2.9) 17(-0.9,2.4) 18(-0.9,1.9) 19(-0.9,1.4) 20(-0.9,0.9)
  rect 2.108x2.108 smd: 21(1,1.9)
R0402_0OHM
  rect 0.508x0.559 smd: 1(0,0) 2(0.914,0)
R0603_0OHM
  rect 0.635x0.889 smd: 1(0,0) 2(1.397,0)
R0805_0OHM
  rect 0.813x1.397 smd: 1(0,0) 2(1.702,0)
R_0402
  rect 0.508x0.559 smd: 1(0,0) 2(0.914,0)
R_0402-NPM
  rect 0.508x0.559 smd: 1(0,0) 2(0.914,0)
R_0603
  rect 0.635x0.889 smd: 1(0,0) 2(1.397,0)
R_0805
  rect 0.813x1.397 smd: 1(0,0) 2(1.702,0)
R_1206
  rect 1.016x1.651 smd: 1(0,0) 2(2.667,0)
R_1206_4P
  custom 0.476x0.476 smd: 1(0,0) 4(5.08,0)
  rect 1.397x0.381 smd: 2(1.206,0) 3(3.873,0)
RB751V-40_SOD323-2
  rect 0.787x0.889 smd: 1(0,0) 2(2.14,0)
RB751V-40TE17_SOD323-2
  rect 0.787x0.889 smd: 1(0,0) 2(0,-2.1)
RHU002N06_SOT323-3
  oval 0.813x0.914 smd: 1(0,0) 2(0.65,1.6) 3(-0.65,1.6)
RP_0804_8P4R
  oval 0.66x0.254 smd: 1(0,0) 2(0,-0.5) 3(0,-1) 4(0,-1.5) 5(1.15,-1.5) 6(1.15,-1) 7(1.15,-0.5) 8(1.15,0)
RT8207PGQW_WQFN20_3X3-S
  oval 0.203x0.889 smd: 1(0,0) 2(0.4,0) 3(0.8,0) 4(1.2,0) 5(1.6,0) 11(1.6,3.1) 12(1.2,3.1) 13(0.8,3.1) 14(0.4,3.1) 15(0,3.1)
  oval 0.889x0.203 smd: 6(2.35,0.75) 7(2.35,1.15) 8(2.35,1.55) 9(2.35,1.95) 10(2.35,2.35) 16(-0.75,2.35) 17(-0.75,1.95) 18(-0.75,1.55) 19(-0.75,1.15) 20(-0.75,0.75)
  rect 1.702x1.702 smd: 21(0.8,1.55)
RT904225GSP_SO8
  oval 0.635x1.854 smd: 1(0,0) 2(1.27,0) 3(2.54,0) 4(3.81,0) 5(3.81,5.157) 6(2.54,5.157) 7(1.27,5.157) 8(0,5.157)
  rect 2.159x2.159 smd: 9(1.905,2.579)
RTL8106E-CG_QFN32_4X4-S
  oval 0.203x0.838 smd: 1(0,0) 2(0.4,0) 3(0.8,0) 4(1.2,0) 5(1.6,0) 6(2,0) 7(2.4,0) 8(2.8,0) 17(2.8,4.15) 18(2.4,4.15) 19(2,4.15) 20(1.6,4.15) 21(1.2,4.15) 22(0.8,4.15) 23(0.4,4.15) 24(0,4.15)
  oval 0.838x0.203 smd: 9(3.475,0.675) 10(3.475,1.075) 11(3.475,1.475) 12(3.475,1.875) 13(3.475,2.275) 14(3.475,2.675) 15(3.475,3.075) 16(3.475,3.475) 25(-0.675,3.475) 26(-0.675,3.075) 27(-0.675,2.675) 28(-0.675,2.275) 29(-0.675,1.875) 30(-0.675,1.475) 31(-0.675,1.075) 32(-0.675,0.675)
  rect 2.692x2.692 smd: 33(1.4,2.075)
RUM002N02GT2L_VMT3
  oval 0.508x0.457 smd: 1(0,0)
  oval 0.406x0.457 smd: 2(-0.4,-1.15) 3(0.4,-1.15)
SAMTE_ASP-136446-07-B_20P-T
  oval 0.737x2.794 smd: 1(0,0) 2(0,4.07) 3(1.27,0) 4(1.27,4.07) 5(2.54,0) 6(2.54,4.07) 7(3.81,0) 8(3.81,4.07) 9(5.08,0) 10(5.08,4.07) 11(6.35,0) 12(6.35,4.07) 13(7.62,0) 14(7.62,4.07) 15(8.89,0) 16(8.89,4.07) 17(10.16,0) 18(10.16,4.07) 19(11.43,0) 20(11.43,4.07)
SANTA_130460-N_8P-T
  round 1.295 hole 0.889: 1(0,0) 2(-1.02,1.1) 3(-2.04,0) 4(-3.06,1.1) 5(-4.08,0) 6(-5.1,1.1) 7(-6.12,0) 8(-7.14,1.1)
  oval 0.991x2.007 hole 0.61x1.6: 9(4.83,-10.1) 10(4.83,-2.3) 11(-11.97,-2.3) 12(-11.97,-10.1)
SDMK0340L-7-F_SOD323-2
  rect 1.346x0.66 smd: 1(0,0) 2(2.4,0)
SHORTPADS
  custom 0.19x0.19 smd: 1(-0.483,0) 2(0.483,0)
SIR472DP-T1-GE3_POWERPAK8-5
  oval 0.61x1.27 smd: 1(0,0) 2(1.27,0) 3(2.54,0) 4(3.81,0)
  custom 1.105x1.105 smd: 5(1.905,3.715)
SIS412DN-T1-GE3_POWERPAK8-5
  oval 0.406x0.991 smd: 1(0,0) 2(0.66,0) 3(1.32,0) 4(1.98,0)
  custom 0.559x0.559 smd: 5(0.99,2.247)
SN74AHC1G08DCKR_SC70-5
  oval 0.381x1.295 smd: 1(0,0.15) 2(0.65,0.15) 3(1.3,0.15) 4(1.3,1.89) 5(0,1.89)
SN74LVC1G07DCKR_SC70-5
  oval 0.381x0.864 smd: 1(0,0) 2(0.65,0) 3(1.3,0) 4(1.3,1.74) 5(0,1.74)
SN74LVC2T45DCTR_SM8
  oval 0.381x0.914 smd: 1(0,0) 2(0.65,0) 3(1.3,0) 4(1.95,0) 5(1.95,3.6) 6(1.3,3.6) 7(0.65,3.6) 8(0,3.6)
SSM3K7002FU_SC70-3
  oval 0.508x0.991 smd: 1(0,0) 2(0.65,1.9) 3(-0.65,1.9)
STARC_132C30-100020-A2-R_30P
  oval 0.406x0.787 smd: 1(0,0) 2(0.8,0) 3(1.6,0) 4(2.4,0) 5(3.2,0) 6(4,0) 7(4.8,0) 8(5.6,0) 9(6.4,0) 10(7.2,0) 11(8,0) 12(8.8,0) 13(9.6,0) 14(10.4,0) 15(11.2,0) 16(12,0) 17(12.8,0) 18(13.6,0) 19(14.4,0) 20(15.2,0) 21(16,0) 22(16.8,0) 23(17.6,0) 24(18.4,0) 25(19.2,0) 26(20,0) 27(20.8,0) 28(21.6,0) 29(22.4,0) 30(23.2,0)
  rect 0.559x1.295 smd: 31(-1.475,-3.3) 32(24.675,-3.3)
SW_TST71-N-220-T170-S017_2P
  rect 0.61x1.499 smd: 1(0,0) 2(3.2,0)
SY6288C20AAC_SOT23-5
  oval 0.559x0.787 smd: 1(0,0) 2(0.95,0) 3(1.9,0) 4(1.9,2.4) 5(0,2.4)
SY6288D20AAC_SOT23-5
  oval 0.559x0.787 smd: 1(0,0) 2(0.95,0) 3(1.9,0) 4(1.9,2.4) 5(0,2.4)
SY8033BDBC_DFN10_3X3-S
  oval 0.305x0.559 smd: 1(0,0) 2(0.5,0) 3(1,0) 4(1.5,0) 5(2,0) 6(2,2.7) 7(1.5,2.7) 8(1,2.7) 9(0.5,2.7) 10(0,2.7)
  rect 2.591x1.753 smd: 11(1,1.35)
SY8286BRAC_QFN20_3X3-S
  oval 0.889x0.254 smd: 1(0,0) 2(0,-0.45) 3(0,-0.9) 4(0,-1.35) 5(0,-1.8) 11(3.1,-1.8) 12(3.1,-1.35) 13(3.1,-0.9) 14(3.1,-0.45) 15(3.1,0)
  oval 0.254x0.889 smd: 6(0.65,-2.45) 7(1.1,-2.45) 8(1.55,-2.45) 9(2,-2.45) 10(2.45,-2.45) 16(2.45,0.65) 17(2,0.65) 18(1.55,0.65) 19(1.1,0.65) 20(0.65,0.65)
  rect 0.991x0.991 smd: 21(1.55,-0.9)
SY8286CRAC_QFN20_3X3-S
  oval 0.889x0.254 smd: 1(0,0) 2(0,-0.45) 3(0,-0.9) 4(0,-1.35) 5(0,-1.8) 11(3.1,-1.8) 12(3.1,-1.35) 13(3.1,-0.9) 14(3.1,-0.45) 15(3.1,0)
  oval 0.254x0.889 smd: 6(0.65,-2.45) 7(1.1,-2.45) 8(1.55,-2.45) 9(2,-2.45) 10(2.45,-2.45) 16(2.45,0.65) 17(2,0.65) 18(1.55,0.65) 19(1.1,0.65) 20(0.65,0.65)
  rect 0.991x0.991 smd: 21(1.55,-0.9)
SY8286RAC_QFN20_3X3-S
  oval 0.889x0.254 smd: 1(0,0) 2(0,-0.45) 3(0,-0.9) 4(0,-1.35) 5(0,-1.8) 11(3.1,-1.8) 12(3.1,-1.35) 13(3.1,-0.9) 14(3.1,-0.45) 15(3.1,0)
  oval 0.254x0.889 smd: 6(0.65,-2.45) 7(1.1,-2.45) 8(1.55,-2.45) 9(2,-2.45) 10(2.45,-2.45) 16(2.45,0.65) 17(2,0.65) 18(1.55,0.65) 19(1.1,0.65) 20(0.65,0.65)
  rect 0.991x0.991 smd: 21(1.55,-0.9)
TAI-T_HCB2012KF-221T30_2P
  rect 0.991x0.991 smd: 1(0,0) 2(2,0)
TPC12
  round 0.305 smd: 1(0,0)
TPS22966DPUR_SON14_2X3-S
  oval 0.254x0.813 smd: 1(0,0) 2(0.4,0) 6(2,0) 7(2.4,0) 8(2.4,2.05) 9(2,2.05) 13(0.4,2.05) 14(0,2.05)
  oval 0.203x0.762 smd: 3(0.8,0) 4(1.2,0) 5(1.6,0) 10(1.6,2.05) 11(1.2,2.05) 12(0.8,2.05)
  rect 2.489x0.889 smd: 15(1.2,1.025)
TPS51212DSCR_SON10_3X3-S
  oval 0.279x0.838 smd: 1(0,0) 2(0.5,0) 3(1,0) 4(1.5,0) 5(2,0) 6(2,2.95) 7(1.5,2.95) 8(1,2.95) 9(0.5,2.95) 10(0,2.95)
  custom 0.412x0.412 smd: 11(1,1.475)
TVNST52302AB0_SOT523-3
  oval 0.508x0.559 smd: 1(0,0) 2(-0.5,-1.4) 3(0.5,-1.4)
TVWDF1004AD0_DFN9
  oval 0.203x0.686 smd: 1(0,0) 2(0.5,0) 4(1.5,0) 5(2,0) 6(2,0.875) 7(1.5,0.875) 8(0.5,0.875) 9(0,0.875)
  oval 0.406x1.549 smd: 3(1,0.437)
W25Q128FVSIQ_SO8
  oval 0.635x1.676 smd: 1(0,0) 2(1.27,0) 3(2.54,0) 4(3.81,0) 5(3.81,7.25) 6(2.54,7.25) 7(1.27,7.25) 8(0,7.25)
Y_7V25000014_4P
  rect 1.397x1.194 smd: 1(0,0) 2(2.2,0) 3(2.2,1.7) 4(0,1.7)
Y_7V27000011_4P
  rect 1.397x1.194 smd: 1(0,0) 2(2.2,0) 3(2.2,1.7) 4(0,1.7)
Y_CM31532768DZFT_2P
  rect 1.092x1.905 smd: 1(0,0) 2(2.5,0)
Y_X3S048000D81H-W_4P
  rect 1.397x1.194 smd: 1(0,0) 2(2.2,0) 3(2.2,1.7) 4(0,1.7)
YUQIU_PJ753-F07J1BE-B_7P-T
  oval 0.991x1.803 hole 0.61x1.397: 1(0,0) 2(9.5,-5.5) 3(9.5,-8.6) 4(0,-7.8) 5(9.5,0) 6(9.5,-2.75) 7(0,-2.65)

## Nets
0.95VS_GATE: C16.1 Q84.1 R1674.2 U4.4
0.95VS_PWR_EN#: Q83.2 Q84.2 RE505.1 UE1.99
0.95VSDGPU_OUT: C625.2 J11.1 U15.13 U15.14
0.775VALW_GATE: Q2514.2 Q2515.2 R54.1 U2.7
1.5VS_VIN: PC402.1 PJP401.2 PU400.3
1.8VGS_0.95VSDGPU_ON: C983.2 R438.2 U15.3 U15.5
1.8VS_GATE: C987.2 R437.2 U2302.5
2.5V_VIN: PC902.1 PJP901.2 PU900.3
3V_FB: PC113.1 PR109.2 PR110.1 PU100.13
3V_SN: PC112.1 PR106.2
3V_VIN: PC100.1 PC103.1 PC104.1 PC105.1 PC130.1 PC131.1 PJP105.2 PL102.2 PU100.2 PU100.3 PU100.4 PU100.5
3VS_GATE: C2322.2 R2318.2 U2302.3
3VS_LS: J511.2 U2302.13 U2302.14
5V_FB: PC127.1 PR115.2 PR118.1 PU102.13
5V_SN: PC125.1 PR112.2
5V_VIN: PC115.1 PC116.1 PC117.1 PC118.1 PC132.1 PC133.1 PJP106.2 PL103.2 PU102.2 PU102.3 PU102.4 PU102.5
5VS: J509.2 J510.2 U2301.13 U2301.14
5VS_GATE: C2309.1 R2313.2 U2301.3
+0.6V_DDR_VTT: CD208.1 CD209.1 CD210.1 CD214.1 CD217.1 CD226.1 CD227.1 CD253.1 CD254.1 CD255.1 JDIMM1.258 JDIMM2.258 PJP203.1
+0.6VSP: PC205.1 PC211.1 PJP203.2 PU200.2 PU200.20
+0.95VALW: C940.1 CC1118.1 CC1119.1 PJP301.2 PJP302.2 RC645.2 U4.5 U4.6 U4.7 U4.8 U15.1 U15.2 UC1.AJ11 UC1.AL11 UC1.AL13
+0.95VALWP: PC307.1 PC310.1 PJP301.1 PJP302.1 PL302.2 PR309.1
+0.95VS: C46.1 C939.1 CC934.1 CC935.1 LC22.2 R1671.1 RC96.2 U4.1 U4.2 U4.3
+0.95VS_APU_GFX: CC203.1 CC245.1 CC949.1 CC950.1 CC951.1 CC1080.1 CC1083.1 CC1104.1 CC1105.1 CC1106.1 CC1107.1 CC1147.1 CC1148.1 CC1150.1 CC1151.1 LC22.1 RC542.1 UC1.AJ21 UC1.AJ23 UC1.AJ25 UC1.AJ27 UC1.AL23 UC1.AL25 UC1.AL27 UC1.AL29
+0.95VSDGPU: J11.2 LV8.1 RV1.2 RV3.2 RV30.2 RV31.1 RV364.1
+0.775VALW: C2619.1 PJP802.1 Q2515.1 Q2516.6
+1.2V_DDR: CC1008.1 CC1057.1 CC1058.1 CC1059.1 CC1060.1 CC1061.1 CC1062.1 CC1063.1 CC1064.1 CC1065.1 CC1066.1 CC1087.1 CC1088.1 CC1089.1 CC1090.1 CC1091.1 CC1092.1 CC1093.1 CC1111.1 CC1112.1 CC1113.1 CC1114.1 CC1115.1 CC1116.1 CD194.1 CD195.1 CD196.1 CD197.1 CD198.1 CD199.1 CD200.1 CD201.1 CD202.1 CD203.1 CD204.1 CD205.1 CD206.1 CD207.1 CD211.1 CD212.1 CD213.1 CD215.1 CD216.1 CD221.1 CD222.1 CD223.1 CD224.1 CD225.1 CD229.1 CD230.1 CD239.1 CD240.1 CD241.1 CD242.1 CD243.1 CD244.1 CD245.1 CD246.1 CD247.1 CD248.1 CD249.1 CD250.1 CD251.1 CD252.1 CD258.1 JDIMM1.111 JDIMM1.112 JDIMM1.117 JDIMM1.118 JDIMM1.123 JDIMM1.124 JDIMM1.129 JDIMM1.130 JDIMM1.135 JDIMM1.136 JDIMM1.141 JDIMM1.142 JDIMM1.147 JDIMM1.148 JDIMM1.153 JDIMM1.154 JDIMM1.159 JDIMM1.160 JDIMM1.163 JDIMM2.111 JDIMM2.112 JDIMM2.117 JDIMM2.118 JDIMM2.123 JDIMM2.124 JDIMM2.129 JDIMM2.130 JDIMM2.135 JDIMM2.136 JDIMM2.141 JDIMM2.142 JDIMM2.147 JDIMM2.148 JDIMM2.153 JDIMM2.154 JDIMM2.159 JDIMM2.160 JDIMM2.163 PJP200.2 PJP201.2 RC5.2 RC6.1 RC75.2 RD23.1 RD24.2 RD27.1 RD32.2 UC1.AA35 UC1.AC32 UC1.AC37 UC1.AE32 UC1.AE35 UC1.AG32 UC1.AG37 UC1.AJ32 UC1.AJ35 UC1.AL32 UC1.AL37 UC1.AR35 UC1.J35 UC1.L32 UC1.L37 UC1.N35 UC1.R37 UC1.U32 UC1.U35 UC1.W32 UC1.W37
+1.2VP: PC215.1 PC216.1 PC217.1 PC218.1 PC219.1 PC220.1 PJP200.1 PJP201.1 PL200.1 PR211.2 PU200.5 PU200.19
+1.5VS: CC1005.1 CC1006.1 CC1007.1 PJP402.2 PR1028.1 RA16.1 RC11.1
+1.5VSP: PC404.1 PC405.1 PJP402.1 PR401.1 PU400.6
+1.8V_ALW: C24.2 C623.2 CC1085.1 CC1086.1 PJP401.1 PJP602.2 PJP801.1 RC346.1 RC1672.1 RE69.1 U15.6 U15.7 U2302.6 U2302.7 UC1.AJ13 UC1.AL15
+1.8V_AVDD: CA12.1 RA5.2 UA1.40
+1.8VALWP: PC603.1 PC605.1 PC606.1 PC607.1 PJP602.1 PL601.2 PR603.2
+1.8VGS: C622.2 CV38.1 CV39.1 CV46.1 CV179.1 CV183.2 LV2.1 LV3.1 LV6.1 LV7.1 PR1113.1 RV8.1 RV11.1 RV15.1 RV27.2 RV28.1 RV71.1 RV81.2 RV82.2 RV152.2 U15.8 U15.9 UV1.AM30 UV4.8
+1.8VS: CC1100.1 CC1101.1 CC1102.1 J10.2 JHDT1.1 JHDT1.19 PR1023.1 QA1.1 QC2.2 QC79.2 QC79.5 RA15.1 RC2.1 RC4.1 RC7.1 RC9.1 RC10.1 RC18.1 RC48.2 RC55.1 RC61.1 RC80.1 RC81.1 RC117.2 RC155.2 RC159.1 RC1675.1 RPC25.6 RPC25.7 RPC25.8 RPC36.1 RPC36.2 RPH1.5 RPH1.6 RPH1.7 RPH1.8 RPH2.7 UC1.AJ15 UC1.AL17 UC64.5 UC65.5
+1.8VS_LS: C26.2 J10.1 U2302.8 U2302.9
+1.35V_MEM_GFX: CV40.1 CV41.1 CV42.1 CV43.1 CV44.1 CV45.1 CV47.1 CV48.1 CV49.1 CV50.1 CV51.1 CV52.1 CV53.1 CV153.1 CV155.1 CV157.1 CV158.1 CV160.1 CV161.1 CV162.1 CV164.1 CV165.1 CV166.1 CV169.1 CV170.1 CV173.1 CV174.1 CV175.1 CV176.1 CV177.1 CV178.1 CV198.1 CV210.1 CV211.1 CV213.1 CV216.1 CV219.1 CV221.1 CV225.1 CV227.1 CV230.1 CV233.1 CV235.1 CV238.1 CV242.1 CV243.1 CV247.1 CV248.1 CV333.1 CV334.1 CV335.1 CV336.1 CV341.1 CV342.1 CV343.1 CV344.1 PJP1402.2 RV32.1 RV33.1 RV48.1 RV50.1 RV52.1 RV54.1 RV79.1 RV80.1 RV85.1 RV86.1 UV1.H13 UV1.H16 UV1.H19 UV1.J9 UV1.J10 UV1.J23 UV1.J24 UV1.K9 UV1.K10 UV1.K23 UV1.K24 UV1.L11 UV1.L12 UV1.L13 UV1.L20 UV1.L21 UV1.L22 UV13.B1 UV13.B3 UV13.B12 UV13.B14 UV13.C5 UV13.C10 UV13.D1 UV13.D3 UV13.D11 UV13.D12 UV13.D14 UV13.E5 UV13.E10 UV13.F1 UV13.F3 UV13.F12 UV13.F14 UV13.G1 UV13.G2 UV13.G4 UV13.G11 UV13.G13 UV13.G14 UV13.H3 UV13.H12 UV13.K3 UV13.K12 UV13.L1 UV13.L2 UV13.L4 UV13.L11 UV13.L13 UV13.L14 UV13.M1 UV13.M3 UV13.M12 UV13.M14 UV13.N5 UV13.N10 UV13.P1 UV13.P3 UV13.P11 UV13.P12 UV13.P14 UV13.R5 UV13.R10 UV13.T1 UV13.T3 UV13.T12 UV13.T14 UV15.B1 UV15.B3 UV15.B12 UV15.B14 UV15.C5 UV15.C10 UV15.D1 UV15.D3 UV15.D11 UV15.D12 UV15.D14 UV15.E5 UV15.E10 UV15.F1 UV15.F3 UV15.F12 UV15.F14 UV15.G1 UV15.G2 UV15.G4 UV15.G11 UV15.G13 UV15.G14 UV15.H3 UV15.H12 UV15.K3 UV15.K12 UV15.L1 UV15.L2 UV15.L4 UV15.L11 UV15.L13 UV15.L14 UV15.M1 UV15.M3 UV15.M12 UV15.M14 UV15.N5 UV15.N10 UV15.P1 UV15.P3 UV15.P11 UV15.P12 UV15.P14 UV15.R5 UV15.R10 UV15.T1 UV15.T3 UV15.T12 UV15.T14
+1.35VGPUP: PC1409.1 PC1411.1 PC1412.1 PC1413.1 PC1414.1 PJP1402.1 PL1401.2 PR1409.2
+2.5V_MEM: CD231.1 CD232.1 CD233.1 CD237.1 CD259.1 CD260.1 CD261.1 CD265.1 JDIMM1.257 JDIMM1.259 JDIMM2.257 JDIMM2.259 PJP902.2
+2.5VP: PC903.1 PC904.1 PJP902.1 PR901.1 PU900.6
+3V_1.8V_CPVDD: CA13.1 CA14.1 RA6.2 RA7.2 UA1.36
+3V_DVDD: CA5.1 CA6.1 CA15.1 CA16.1 RA2.2 RA7.1 RA8.1 RA10.2 UA1.1
+3VALW: C2316.1 C2318.1 CC14.1 CC1124.1 CC1126.1 CL9.1 JP3.2 JPWR1.1 PC802.1 PJP102.2 PJP601.1 PJP803.1 PJP901.1 PR3.2 PR16.2 PR28.1 PR209.1 PR756.2 PR791.1 PR1405.1 PR1406.1 PU800.5 PU800.6 PU800.7 PU800.8 R35.1 R2634.2 RA11.2 RC21.1 RC33.1 RC654.1 RC678.1 RC683.1 RC693.2 RC905.1 RC906.1 RC928.1 RC932.1 RC933.1 RC942.1 RC943.1 RC944.1 RC949.1 RC951.1 RC954.1 RE13.1 RE19.1 RE20.2 RE21.1 RE23.2 RE61.1 RE62.1 RE63.1 RE70.1 RE75.1 RL7.1 RPE1.1 RPE1.2 RV165.2 U2302.1 U2302.2 UC1.AJ17 UC1.AL19 UC4.5 UL3.5
+3VALW_EC: CE3.1 CE4.1 CE10.2 CE13.2 CE14.1 CE17.1 LE3.1 RE4.2 RE13.2 RE50.1 RE505.2 UC61.5 UC62.5 UC63.5 UE1.9 UE1.22 UE1.33 UE1.96 UE1.125
+3VALWP: PC106.1 PC107.1 PC108.1 PC109.1 PC110.1 PJP102.1 PL100.2 PR107.1 PR108.2 PR109.1 PR113.1 PU100.14
+3VGS: C621.2 CV185.2 JP2.1 LV4.1 PR1115.1 QV1.2 QV1.5 RPV34.1 RPV34.2 RPV34.3 RPV34.4 RV5.1 RV6.1 RV72.2 RV73.2 RV91.2 RV92.2 RV102.2 RV154.1 RV162.1 RV164.2 RV260.1 U74.1 UV2.5 UV4.1
+3VLP: JP12.1 JP14.1 PC111.1 PU100.16 PU100.17 RE4.1 RE14.1 RE49.1
+3VS: C17.1 C620.2 C2323.1 C2324.1 C2498.1 CD234.1 CD262.1 CS27.1 CS42.1 CX1.1 J511.1 JDIMM1.255 JDIMM2.255 JDIMM2.256 JIOB1.12 JP2.2 PR302.1 PR1021.1 PR1070.1 PR1112.1 PR1119.1 PR1401.1 Q6.2 QA1.2 QI1.2 QI2.2 QI2.5 QI3.1 QW1.2 R11.1 R16.2 R23.2 R28.1 R439.1 R2448.1 RA2.1 RC16.1 RC17.1 RC43.1 RC44.1 RC45.1 RC46.1 RC50.1 RC70.2 RC119.1 RC350.1 RC690.2 RC691.2 RC708.2 RC710.2 RC712.2 RC902.1 RC904.1 RC925.1 RC938.1 RE66.1 RE68.2 RF1.2 RF2.2 RI19.1 RI20.1 RL3.1 RL11.2 RM7.1 RPC36.3 RPC64.5 RPC64.6 RPE1.3 RPE1.4 RPI3.7 RPI3.8 RS19.1 RS20.1 RS25.1 RS26.1 RS27.1 RS28.1 RS29.1 RS30.1 RS33.2 RS34.2 RS38.2 RX9.1 U1.5 U74.5 U2407.1
+3VS_APU: CC1137.1 RC119.2 UC1.AJ19 UC1.AL21
+3VS_CAM: C18.1 JEDP1.30 R16.1
+3VS_TOUCH: C19.1 JTP1.8 Q9.2 Q12.1 R31.2 R32.2 R38.2 R41.1 RP20.6 RP20.7 RP20.8
+3VS_WLAN_NGFF: CW10.1 CW11.1 CW12.1 CW13.1 CW14.1 CW15.1 CW16.1 CW17.1 JWLAN1.2 JWLAN1.4 JWLAN1.64 JWLAN1.66 RM7.2 RW12.1
+5V_AVDD: CA10.1 CA11.1 RA4.2 UA1.26
+5V_HDD: CS5.1 CS6.1 CS7.1 JHDD1.10 JHDD1.11 JHDD1.12 JP13.2
+5V_HDMI: CI9.1 FI1.1 JHDMI1.18 RPI3.5 RPI3.6
+5V_PVDD: CA1.1 CA2.1 CA3.1 CA4.1 RA1.2 UA1.41 UA1.46
+5V_USB_PWR1: CU11.1 CU12.1 CU13.1 CU14.1 CU16.1 CU17.1 CU18.1 CU19.1 JUSB1.1 JUSB2.1 UI5.1
+5V_USB_PWR2: JIOB1.13 JIOB1.14 JIOB1.15 JIOB1.16 UU3.1
+5VALW: C2305.1 C2306.1 CU6.1 CU7.1 CU20.1 CU21.1 PC306.1 PC401.1 PC901.1 PC1111.1 PD5.3 PD6.3 PJP103.2 PR8.1 PR206.1 PR210.2 PR1114.2 PU300.7 PU400.4 PU900.4 PU1100.26 PU1100.31 Q2.2 Q2.5 Q3.3 Q15.3 Q16.2 Q6102.3 R53.1 R54.2 R56.2 R1674.1 R2635.2 RE504.2 U2.8 U15.4 U2301.1 U2301.2 U2301.4 U2302.4 UI5.5 UU3.5
+5VALWP: PC120.1 PC121.1 PC122.1 PC123.1 PC124.1 PJP103.1 PL101.2 PR115.1 PR117.2 PU102.14
+5VS: C2307.1 C2308.1 CE56.1 CF4.1 CS15.1 F3.2 FI1.2 J509.1 J510.1 JFAN1.1 JP7.1 JP13.1 PC1055.1 PR1026.2 PU1001.12 PU1001.26 Q7.3 R12.1 RA1.1 RA4.1 RE59.1 RE60.1 RF3.2
+5VS_KBL: C34.1 F3.1 JKBBL1.1 RE59.2
+5VS_ODD: CS10.1 CS11.1 CS12.1 JODD1.17 JODD1.18 JODD1.19 JODD1.20 JODD1.21 JODD1.22 JP7.2
+17.4V_BATT+: PC7.1 PC761.1 PC766.1 PC775.1 PC776.1 PC777.1 PC778.1 PJP3.2 PL3.1 PQ710.3 PR745.2 PR765.4 PR780.2
+17.4V_BATT++: PBATT1.8 PBATT1.9 PBATT1.10 PC8.1 PJP3.1 PL3.2
+19V_ADPIN: PC1.1 PC2.1 PJP1.2 PJPDC1.5 PJPDC1.6 PL1.1
+19V_VIN: PC3.1 PC4.1 PC742.2 PD704.2 PJP1.1 PL1.2 PQ740.5 PR5.1 PR7.2 PR31.2 PR729.1
+19VB: C35.2 C36.2 C37.2 C38.2 C39.2 C40.2 C41.1 C42.1 C43.1 C44.1 C45.1 C47.1 C48.1 C49.1 F1.1 PJP105.1 PJP106.1 PJP206.2 PJP303.1 PJP701.1 PJP1001.1 PJP1101.1 PJP1401.1 PL102.1 PL103.1 PL201.1 PL301.2 PL704.1 PL1001.2 PL1101.2 PL1402.1 PQ717.5 PR102.2 PR703.4 R4.1
+19VB_1.2V: PC201.1 PC206.1 PC208.1 PC212.1 PC230.1 PC231.1 PJP206.1 PL201.2 PQ201.2 PQ201.3 PQ201.4 PQ201.10 PR208.1
+19VB_+1.35VGPU: PC1401.1 PC1402.1 PC1403.1 PC1420.1 PC1421.1 PJP1401.2 PL1402.2 PU1400.2 PU1400.3 PU1400.4 PU1400.5
+19VB_APU: PC1000.1 PC1001.1 PC1002.1 PC1003.1 PC1039.1 PC1056.1 PC1067.1 PC1069.1 PC1070.1 PC1071.1 PC1072.1 PC1073.1 PC1074.1 PC1075.1 PC1076.1 PJP1001.2 PL1001.1 PQ1001.5 PQ1007.5
+19VB_GPU: PC1103.1 PC1104.1 PC1105.1 PC1106.1 PC1107.1 PC1112.1 PC1113.1 PC1114.1 PC1115.1 PC1116.1 PC1140.1 PC1141.1 PC1142.1 PC1143.1 PJP1101.2 PL1101.1 PQ1101.5 PQ1104.5
+19VB_VDDP_ALWP: PC302.1 PC303.1 PC304.1 PC308.1 PC320.1 PC321.1 PJP303.2 PL301.1 PQ301.5
+V18R: RE50.2 RE69.2 UE1.124
+VDD_CT: CV61.1 CV62.1 CV63.1 LV3.2 UV1.AA20 UV1.AA21 UV1.AB20 UV1.AB21
+VDD_TOUCH: F2.2 JEDP1.40 R14.2
+VDDCR_FCH_ALW: C431.1 C432.1 C2620.1 C2621.1 C2622.1 CC1108.1 CC1109.1 CC1110.1 Q2513.1 Q2514.1 UC1.AR4 UC1.AR5 UC1.AR7 UC1.AU7
+VDDR3: CV64.1 CV65.1 CV66.1 CV123.1 LV4.2 UV1.AA17 UV1.AA18 UV1.AB17 UV1.AB18
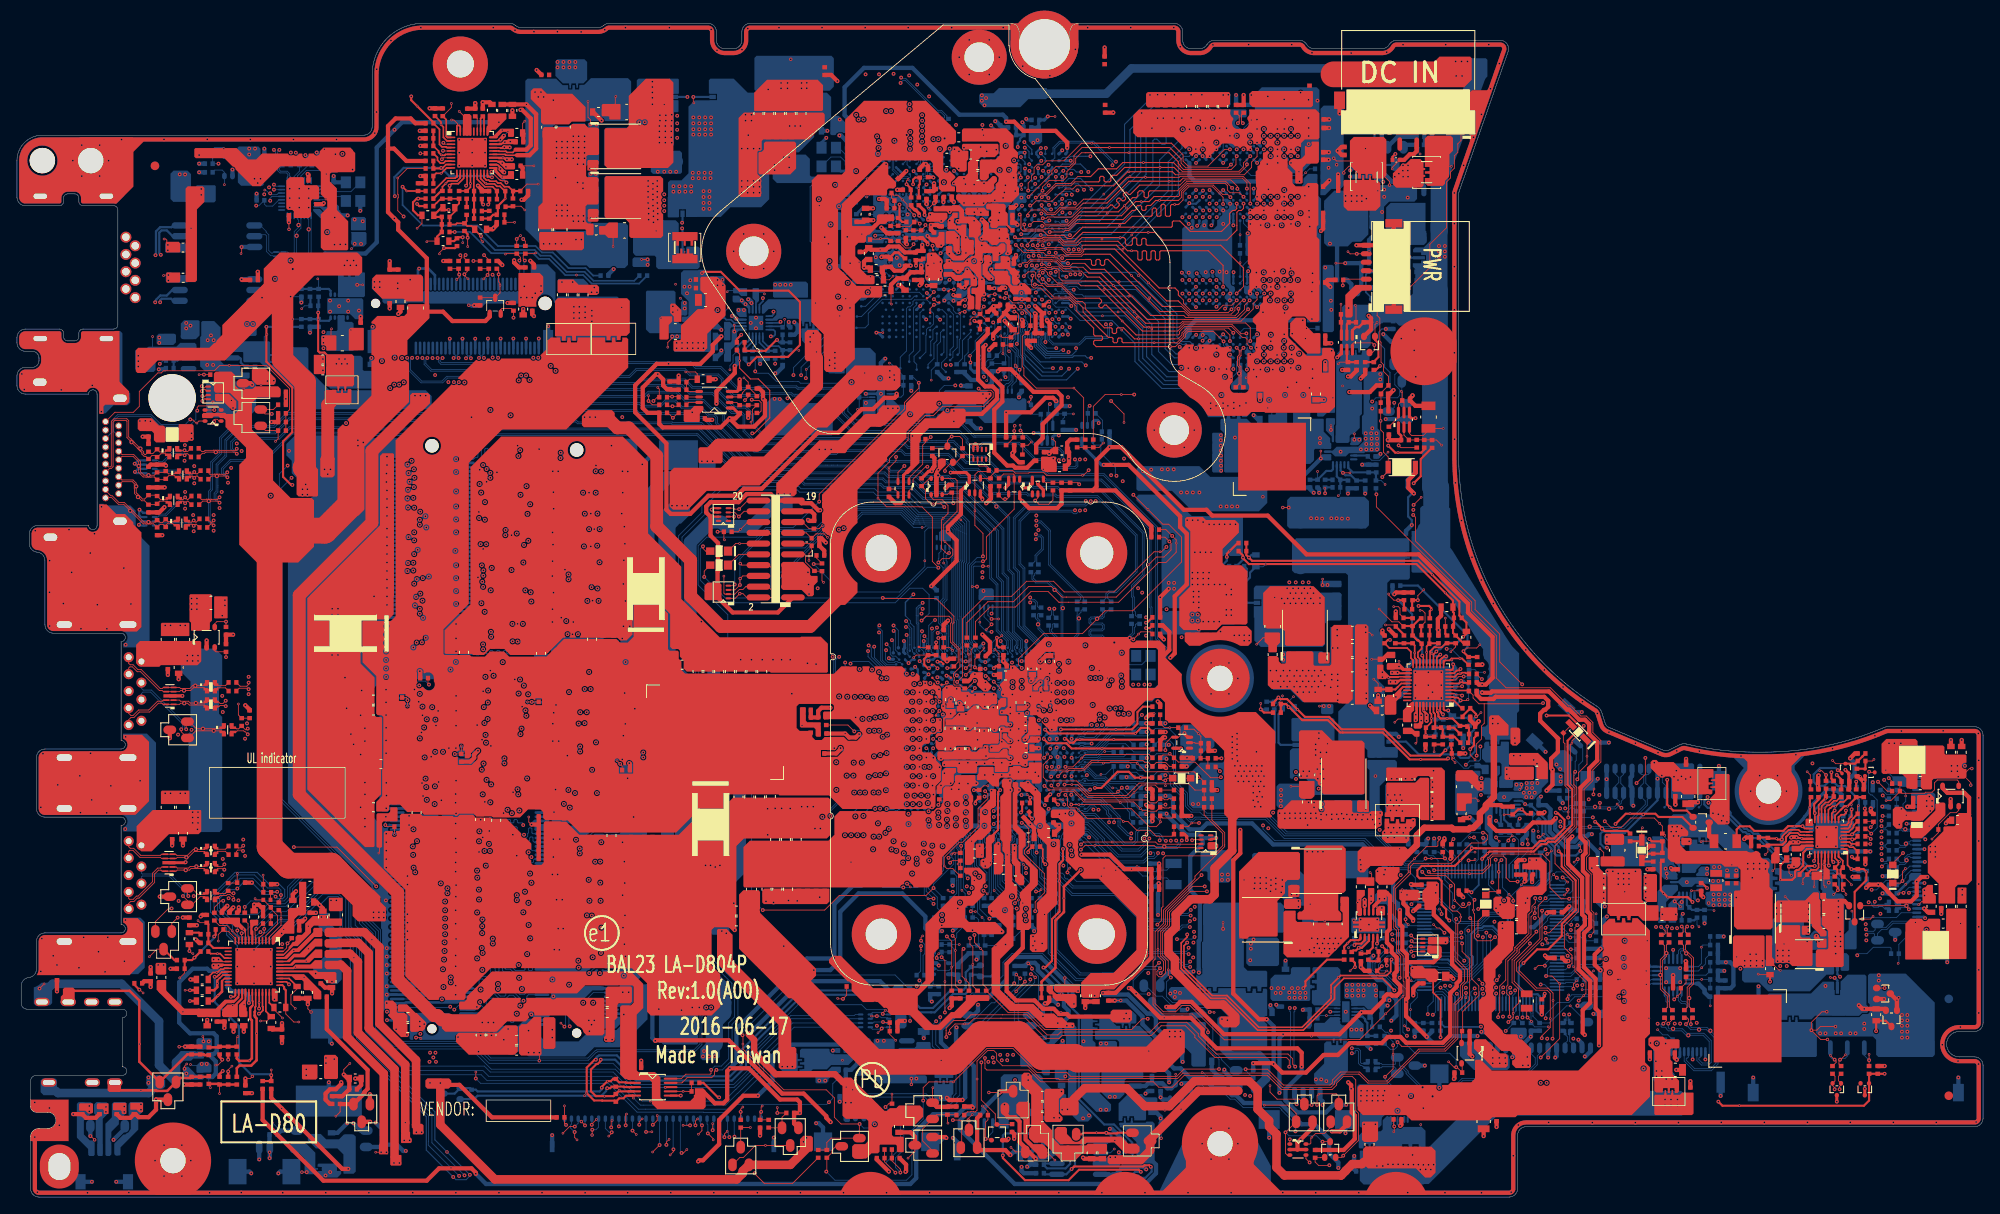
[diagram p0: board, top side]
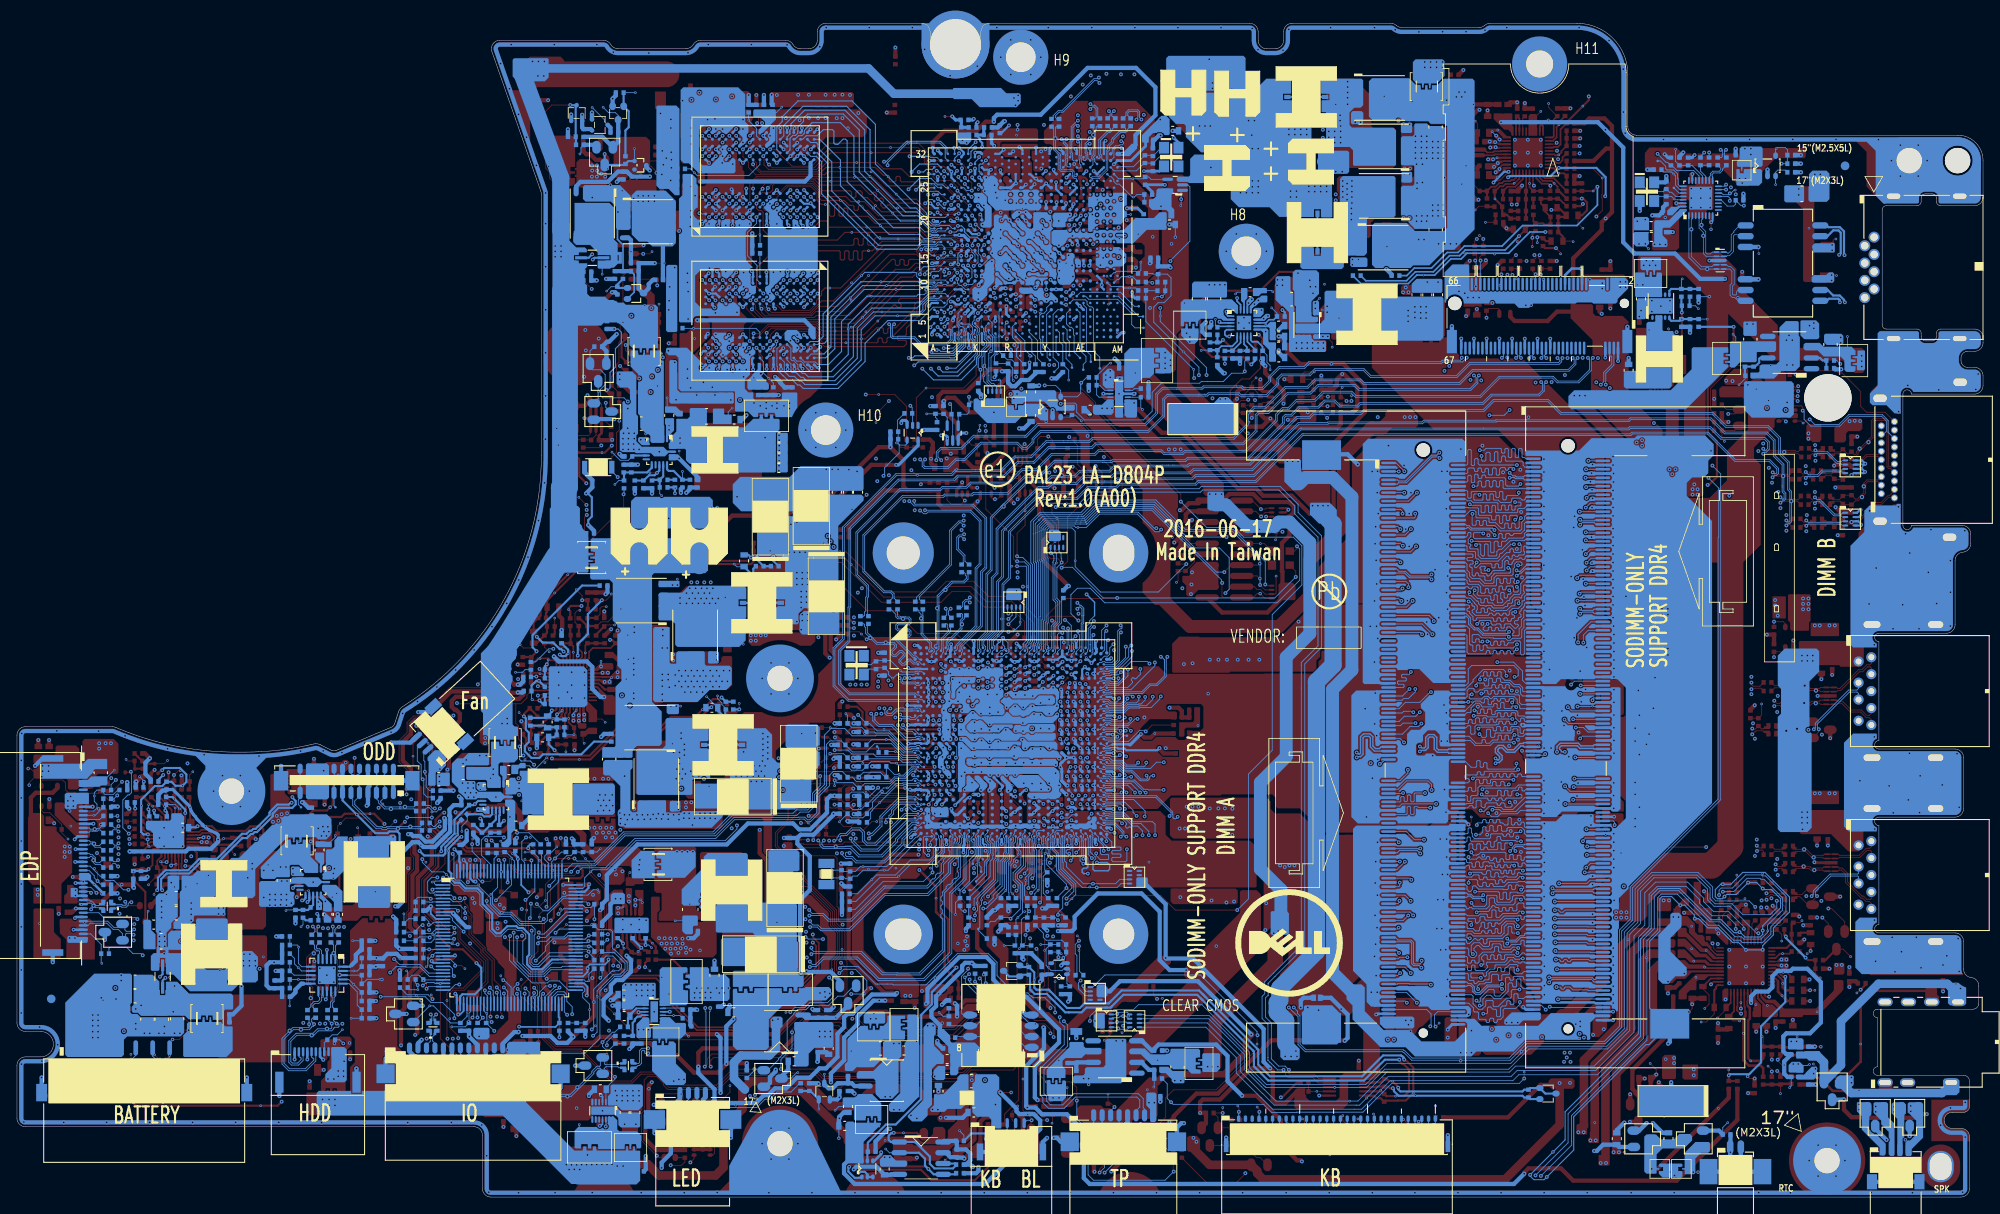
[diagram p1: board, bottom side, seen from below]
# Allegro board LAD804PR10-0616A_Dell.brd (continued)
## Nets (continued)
GND: C2.2 C3.2 C4.2 C5.2 C6.2 C16.2 C17.2 C18.2 C19.2 C24.1 C26.1 C27.2 C34.2 C35.1 C36.1 C37.1 C38.1 C39.1 C40.1 C41.2 C42.2 C43.2 C44.2 C45.2 C46.2 C47.2 C48.2 C49.2 C343.1 C344.1 C349.1 C431.2 C432.2 C551.2 C553.2 C620.1 C621.1 C622.1 C623.1 C625.1 C636.2 C796.2 C797.2 C939.2 C940.2 C983.1 C987.1 C2305.2 C2306.2 C2307.2 C2308.2 C2309.2 C2316.2 C2318.2 C2322.1 C2323.2 C2324.2 C2498.2 C2618.2 C2619.2 C2620.2 C2621.2 C2622.2 C5216.2 C5219.2 CA1.2 CA2.2 CA3.2 CA4.2 CA5.2 CA6.2 CA8.2 CA13.2 CA14.2 CA15.2 CA16.2 CA17.2 CA22.1 CA25.1 CA27.2 CA28.2 CA29.2 CA30.2 CA31.2 CA39.2 CC14.2 CC15.2 CC16.2 CC23.2 CC29.2 CC30.2 CC31.1 CC32.1 CC50.2 CC51.2 CC52.2 CC53.2 CC99.1 CC119.2 CC120.2 CC166.2 CC203.2 CC245.2 CC615.2 CC635.2 CC682.2 CC686.2 CC912.2 CC923.2 CC934.2 CC935.2 CC949.2 CC950.2 CC951.2 CC999.1 CC1000.1 CC1005.2 CC1006.2 CC1007.2 CC1008.2 CC1009.2 CC1010.2 CC1011.2 CC1015.2 CC1016.2 CC1052.2 CC1053.2 CC1054.2 CC1055.2 CC1057.2 CC1058.2 CC1059.2 CC1060.2 CC1061.2 CC1062.2 CC1063.2 CC1064.2 CC1065.2 CC1066.2 CC1067.2 CC1068.2 CC1078.2 CC1079.2 CC1080.2 CC1081.2 CC1082.2 CC1083.2 CC1084.2 CC1085.2 CC1086.2 CC1087.2 CC1088.2 CC1089.2 CC1090.2 CC1091.2 CC1092.2 CC1093.2 CC1095.2 CC1096.2 CC1097.2 CC1098.2 CC1100.2 CC1101.2 CC1102.2 CC1104.2 CC1105.2 CC1106.2 CC1107.2 CC1108.2 CC1109.2 CC1110.2 CC1111.2 CC1112.2 CC1113.2 CC1114.2 CC1115.2 CC1116.2 CC1117.2 CC1118.2 CC1119.2 CC1120.2 CC1121.2 CC1122.2 CC1123.2 CC1124.2 CC1125.2 CC1126.2 CC1127.2 CC1128.2 CC1129.1 CC1137.2 CC1139.2 CC1140.2 CC1141.2 CC1142.2 CC1143.2 CC1144.2 CC1145.2 CC1146.2 CC1147.2 CC1148.2 CC1150.2 CC1151.2 CD193.2 CD194.2 CD195.2 CD196.2 CD197.2 CD198.2 CD199.2 CD200.2 CD201.2 CD202.2 CD203.2 CD204.2 CD205.2 CD206.2 CD207.2 CD208.2 CD209.2 CD210.2 CD211.2 CD212.2 CD213.2 CD214.2 CD215.2 CD216.2 CD217.2 CD218.2 CD219.2 CD220.2 CD221.2 CD222.2 CD223.2 CD224.2 CD225.2 CD226.2 CD227.2 CD228.2 CD229.2 CD230.2 CD231.2 CD232.2 CD233.2 CD234.2 CD237.2 CD239.2 CD240.2 CD241.2 CD242.2 CD243.2 CD244.2 CD245.2 CD246.2 CD247.2 CD248.2 CD249.2 CD250.2 CD251.2 CD252.2 CD253.2 CD254.2 CD255.2 CD256.2 CD258.2 CD259.2 CD260.2 CD261.2 CD262.2 CD265.2 CD266.2 CD267.2 CD268.2 CE3.2 CE4.2 CE10.1 CE13.1 CE14.2 CE17.2 CE20.2 CE23.2 CE24.2 CE25.2 CE33.2 CE39.2 CE40.1 CE41.2 CE42.2 CE47.2 CE56.2 CF4.2 CH1.2 CH2.2 CI9.2 CI10.2 CI11.2 CI12.2 CI13.2 CI14.2 CI15.2 CI16.2 CI17.2 CI18.2 CL5.2 CL6.2 CL7.2 CL8.2 CL9.2 CL10.2 CL11.2 CL12.1 CL13.2 CL14.2 CLIP1.1(TP-1) CLIP2.1(TP-1) CLRP1.2 CS5.2 CS6.2 CS7.2 CS10.2 CS11.2 CS12.2 CS15.2 CS27.2 CS42.2 CU6.2 CU7.2 CU8.2 CU9.2 CU10.2 CU11.2 CU12.2 CU13.2 CU14.2 CU15.2 CU16.2 CU17.2 CU18.2 CU19.2 CU20.2 CU21.2 CU22.2 CU23.2 CV11.2 CV15.2 CV17.2 CV18.2 CV19.2 CV20.2 CV21.2 CV26.2 CV27.2 CV28.2 CV29.2 CV30.2 CV33.2 CV34.2 CV35.2 CV38.2 CV39.2 CV40.2 CV41.2 CV42.2 CV43.2 CV44.2 CV45.2 CV46.2 CV47.2 CV48.2 CV49.2 CV50.2 CV51.2 CV52.2 CV53.2 CV54.2 CV55.2 CV56.2 CV57.2 CV58.2 CV59.2 CV60.2 CV61.2 CV62.2 CV63.2 CV64.2 CV65.2 CV66.2 CV67.2 CV68.2 CV69.2 CV70.2 CV71.2 CV72.2 CV73.2 CV74.2 CV75.2 CV76.2 CV77.2 CV78.2 CV79.2 CV80.2 CV81.2 CV82.2 CV84.2 CV85.2 CV86.2 CV87.2 CV88.2 CV89.2 CV90.2 CV91.2 CV92.2 CV93.2 CV94.2 CV95.2 CV96.2 CV97.2 CV100.2 CV101.2 CV102.2 CV103.2 CV104.2 CV105.2 CV106.2 CV107.2 CV108.2 CV109.2 CV110.2 CV111.2 CV112.2 CV113.2 CV114.2 CV115.2 CV116.2 CV117.2 CV118.2 CV119.2 CV120.2 CV121.2 CV122.2 CV123.2 CV124.2 CV125.2 CV126.2 CV127.2 CV153.2 CV155.2 CV157.2 CV158.2 CV160.2 CV161.2 CV162.2 CV164.2 CV165.2 CV166.2 CV169.2 CV170.2 CV173.2 CV174.2 CV175.2 CV176.2 CV177.2 CV178.2 CV179.2 CV180.1 CV181.1 CV182.1 CV183.1 CV184.1 CV185.1 CV186.2 CV198.2 CV210.2 CV211.2 CV213.2 CV216.2 CV219.2 CV221.2 CV225.2 CV227.2 CV230.2 CV233.2 CV235.2 CV238.2 CV242.2 CV243.2 CV247.2 CV248.2 CV333.2 CV334.2 CV335.2 CV336.2 CV341.2 CV342.2 CV343.2 CV344.2 CV390.2 CV391.2 CV394.2 CV395.2 CVT90.1 CW10.2 CW11.2 CW12.2 CW13.2 CW14.2 CW15.2 CW16.2 CW17.2 CX1.2 DA1.1 DA2.1 DA4.1 DA5.1 DU1.1 DX2.1 EC2901.2 EC2902.2 ED2901.2 EU2601.3 EU2602.1 EU2603.3 EU2604.1 EU3501.3 H1.1(TP-1) H2.1(TP-1) H3.1(TP-1) H4.1(TP-1) H5.1(TP-1) H8.1(TP-1) H9.1(TP-1) H10.1(TP-1) H11.1(TP-1) H12.1(TP-1) H13.1(TP-1) HCPU1.1(TP-1) HCPU2.1(TP-1) HCPU3.1(TP-1) HCPU4.1(TP-1) JDIMM1.1 JDIMM1.2 JDIMM1.5 JDIMM1.6 JDIMM1.9 JDIMM1.10 JDIMM1.14 JDIMM1.15 JDIMM1.18 JDIMM1.19 JDIMM1.22 JDIMM1.23 JDIMM1.26 JDIMM1.27 JDIMM1.30 JDIMM1.31 JDIMM1.35 JDIMM1.36 JDIMM1.39 JDIMM1.40 JDIMM1.43 JDIMM1.44 JDIMM1.47 JDIMM1.48 JDIMM1.51 JDIMM1.52 JDIMM1.56 JDIMM1.57 JDIMM1.60 JDIMM1.61 JDIMM1.64 JDIMM1.65 JDIMM1.68 JDIMM1.69 JDIMM1.72 JDIMM1.73 JDIMM1.77 JDIMM1.78 JDIMM1.81 JDIMM1.82 JDIMM1.85 JDIMM1.86 JDIMM1.89 JDIMM1.90 JDIMM1.93 JDIMM1.94 JDIMM1.98 JDIMM1.99 JDIMM1.102 JDIMM1.103 JDIMM1.106 JDIMM1.107 JDIMM1.166 JDIMM1.167 JDIMM1.168 JDIMM1.171 JDIMM1.172 JDIMM1.175 JDIMM1.176 JDIMM1.180 JDIMM1.181 JDIMM1.184 JDIMM1.185 JDIMM1.188 JDIMM1.189 JDIMM1.192 JDIMM1.193 JDIMM1.196 JDIMM1.197 JDIMM1.201 JDIMM1.202 JDIMM1.205 JDIMM1.206 JDIMM1.209 JDIMM1.210 JDIMM1.213 JDIMM1.214 JDIMM1.217 JDIMM1.218 JDIMM1.222 JDIMM1.223 JDIMM1.226 JDIMM1.227 JDIMM1.230 JDIMM1.231 JDIMM1.234 JDIMM1.235 JDIMM1.238 JDIMM1.239 JDIMM1.243 JDIMM1.244 JDIMM1.247 JDIMM1.248 JDIMM1.251 JDIMM1.252 JDIMM1.256 JDIMM1.260 JDIMM1.261 JDIMM1.262 JDIMM2.1 JDIMM2.2 JDIMM2.5 JDIMM2.6 JDIMM2.9 JDIMM2.10 JDIMM2.14 JDIMM2.15 JDIMM2.18 JDIMM2.19 JDIMM2.22 JDIMM2.23 JDIMM2.26 JDIMM2.27 JDIMM2.30 JDIMM2.31 JDIMM2.35 JDIMM2.36 JDIMM2.39 JDIMM2.40 JDIMM2.43 JDIMM2.44 JDIMM2.47 JDIMM2.48 JDIMM2.51 JDIMM2.52 JDIMM2.56 JDIMM2.57 JDIMM2.60 JDIMM2.61 JDIMM2.64 JDIMM2.65 JDIMM2.68 JDIMM2.69 JDIMM2.72 JDIMM2.73 JDIMM2.77 JDIMM2.78 JDIMM2.81 JDIMM2.82 JDIMM2.85 JDIMM2.86 JDIMM2.89 JDIMM2.90 JDIMM2.93 JDIMM2.94 JDIMM2.98 JDIMM2.99 JDIMM2.102 JDIMM2.103 JDIMM2.106 JDIMM2.107 JDIMM2.167 JDIMM2.168 JDIMM2.171 JDIMM2.172 JDIMM2.175 JDIMM2.176 JDIMM2.180 JDIMM2.181 JDIMM2.184 JDIMM2.185 JDIMM2.188 JDIMM2.189 JDIMM2.192 JDIMM2.193 JDIMM2.196 JDIMM2.197 JDIMM2.201 JDIMM2.202 JDIMM2.205 JDIMM2.206 JDIMM2.209 JDIMM2.210 JDIMM2.213 JDIMM2.214 JDIMM2.217 JDIMM2.218 JDIMM2.222 JDIMM2.223 JDIMM2.226 JDIMM2.227 JDIMM2.230 JDIMM2.231 JDIMM2.234 JDIMM2.235 JDIMM2.238 JDIMM2.239 JDIMM2.243 JDIMM2.244 JDIMM2.247 JDIMM2.248 JDIMM2.251 JDIMM2.252 JDIMM2.260 JDIMM2.261 JDIMM2.262 JEDP1.9 JEDP1.13 JEDP1.16 JEDP1.19 JEDP1.22 JEDP1.27 JEDP1.33 JEDP1.35 JEDP1.38 JEDP1.41 JEDP1.42 JFAN1.4 JFAN1.5 JFAN1.6 JH1.4 JHDD1.1 JHDD1.4 JHDD1.7 JHDD1.13 JHDD1.14 JHDMI1.2 JHDMI1.5 JHDMI1.8 JHDMI1.11 JHDMI1.17 JHDMI1.20 JHDMI1.21 JHDMI1.22 JHDMI1.23 JHDT1.3 JHDT1.5 JHDT1.7 JHDT1.17 JIOB1.1 JIOB1.2 JIOB1.5 JIOB1.6 JIOB1.9 JIOB1.10 JIOB1.17 JIOB1.18 JKB1.31 JKB1.32 JKBBL1.5 JKBBL1.6 JLAN1.9 JLAN1.10 JLAN1.11 JLAN1.12 JLED1.1 JLED1.4 JLED1.5 JLED1.6 JODD1.1 JODD1.2 JODD1.7 JODD1.8 JODD1.13 JODD1.14 JODD1.25 JODD1.26 JPWR1.6 JPWR1.7 JPWR1.8 JRTC1.2 JRTC1.3 JRTC1.4 JSPK1.5 JSPK1.6 JTP1.5 JTP1.9 JTP1.10 JUSB1.4 JUSB1.7 JUSB1.10 JUSB1.11 JUSB1.12 JUSB1.13 JUSB2.4 JUSB2.7 JUSB2.10 JUSB2.11 JUSB2.12 JUSB2.13 JWLAN1.1 JWLAN1.7 JWLAN1.10 JWLAN1.18 JWLAN1.25 JWLAN1.31 JWLAN1.37 JWLAN1.43 JWLAN1.49 JWLAN1.55 JWLAN1.61 JWLAN1.67 JWLAN1.68 JWLAN1.69 LE4.1 PBATT1.1 PBATT1.2 PBATT1.3 PBATT1.4 PBATT1.11 PBATT1.12 PC1.2 PC2.2 PC3.2 PC4.2 PC7.2 PC8.2 PC100.2 PC103.2 PC104.2 PC105.2 PC106.2 PC107.2 PC108.2 PC109.2 PC110.2 PC111.2 PC112.2 PC115.2 PC116.2 PC117.2 PC118.2 PC119.2 PC120.2 PC121.2 PC122.2 PC123.2 PC124.2 PC125.2 PC126.2 PC128.2 PC130.2 PC131.2 PC132.2 PC133.2 PC201.2 PC202.2 PC203.2 PC204.1 PC205.2 PC206.2 PC208.2 PC209.2 PC210.2 PC211.2 PC212.2 PC213.2 PC215.2 PC216.2 PC217.2 PC218.2 PC219.2 PC220.2 PC230.2 PC231.2 PC301.2 PC302.2 PC303.2 PC304.2 PC306.2 PC307.2 PC308.2 PC309.2 PC310.2 PC320.2 PC321.2 PC401.2 PC402.2 PC403.2 PC405.2 PC601.2 PC602.2 PC604.2 PC605.2 PC606.2 PC607.2 PC705.2 PC711.1 PC748.2 PC749.1 PC751.1 PC752.1 PC753.1 PC757.1 PC760.2 PC761.2 PC762.2 PC763.2 PC764.2 PC765.2 PC766.2 PC767.2 PC768.1 PC769.1 PC775.2 PC776.2 PC777.2 PC778.2 PC780.2 PC781.2 PC790.2 PC801.1 PC802.2 PC803.2 PC804.2 PC805.2 PC836.2 PC837.2 PC838.2 PC839.2 PC901.2 PC902.2 PC904.2 PC905.2 PC911.2 PC912.2 PC913.2 PC914.2 PC915.2 PC916.2 PC917.2 PC931.2 PC932.2 PC954.2 PC955.2 PC956.2 PC959.2 PC960.2 PC1000.2 PC1001.2 PC1002.2 PC1003.2 PC1004.1 PC1010.1 PC1013.2 PC1014.2 PC1018.1 PC1037.2 PC1039.2 PC1054.2 PC1055.2 PC1056.2 PC1058.2 PC1059.2 PC1062.1 PC1063.2 PC1064.2 PC1065.2 PC1067.2 PC1069.2 PC1070.2 PC1071.2 PC1072.2 PC1073.2 PC1074.2 PC1075.2 PC1076.2 PC1101.2 PC1103.2 PC1104.2 PC1105.2 PC1106.2 PC1107.2 PC1109.2 PC1110.2 PC1111.2 PC1112.2 PC1113.2 PC1114.2 PC1115.2 PC1116.2 PC1117.1 PC1121.2 PC1124.2 PC1128.2 PC1129.2 PC1131.2 PC1140.2 PC1141.2 PC1142.2 PC1143.2 PC1401.2 PC1402.2 PC1403.2 PC1404.2 PC1405.2 PC1406.2 PC1408.2 PC1411.2 PC1412.2 PC1413.2 PC1414.2 PC1420.2 PC1421.2 PD2.1 PD3.1 PD4.1 PD5.2 PD6.2 PH1001.1 PH1002.1 PH1101.1 PJP2.1 PJPDC1.7 PJPDC1.8 PL4.2 PQ1.1 PQ1.4 PQ2.1 PQ2.4 PQ3.3 PQ5.3 PQ201.5 PQ201.6 PQ201.7 PQ302.1 PQ302.2 PQ302.3 PQ708.1 PQ708.2 PQ708.3 PQ711.3 PQ712.3 PQ720.3 PQ721.3 PQ801.3 PQ1002.1 PQ1002.2 PQ1002.3 PQ1003.1 PQ1003.2 PQ1003.3 PQ1008.1 PQ1008.2 PQ1008.3 PQ1009.1 PQ1009.2 PQ1009.3 PQ1102.1 PQ1102.2 PQ1102.3 PQ1103.1 PQ1103.2 PQ1103.3 PQ1105.1 PQ1105.2 PQ1105.3 PQ1106.1 PQ1106.2 PQ1106.3 PR2.2 PR9.1 PR10.1 PR29.2 PR32.2 PR33.1 PR103.2 PR110.2 PR118.2 PR122.2 PR203.2 PR204.2 PR304.1 PR306.2 PR308.2 PR311.1 PR402.2 PR602.1 PR605.2 PR727.2 PR731.2 PR732.2 PR738.2 PR751.1 PR752.1 PR753.1 PR755.1 PR779.1 PR803.2 PR902.2 PR1005.2 PR1018.1 PR1067.2 PR1076.1 PR1078.2 PR1081.1 PR1086.1 PR1087.1 PR1101.1 PR1105.1 PR1106.1 PR1111.1 PR1117.1 PR1120.1 PR1130.2 PR1140.2 PR1404.2 PR1407.2 PR1411.2 PU100.7 PU100.8 PU100.18 PU100.21 PU102.7 PU102.8 PU102.18 PU102.21 PU200.1 PU200.3 PU200.14 PU200.21 PU300.11 PU400.8 PU400.9 PU600.11 PU703.33 PU800.2 PU800.9 PU900.8 PU900.9 PU1001.41 PU1100.41 PU1400.7 PU1400.8 PU1400.18 PU1400.21 Q8.3 Q83.3 Q84.3 Q85.3 Q91.3 Q2516.4 QE4.3 QI1.3 R5.2 R7.2 R37.2 R1563.2 R2636.1 RA17.2 RA18.2 RA19.2 RA20.2 RA21.2 RA22.2 RA45.1 RC1.1 RC8.1 RC13.1 RC26.1 RC40.1 RC41.1 RC42.1 RC49.1 RC90.2 RC118.2 RC154.2 RC400.2 RC401.2 RC541.2 RC641.2 RC643.2 RC644.2 RC646.2 RC692.1 RC694.1 RC695.1 RC696.1 RC697.1 RC703.1 RC706.1 RC707.1 RC709.1 RC711.1 RC903.2 RC926.2 RC927.2 RC929.2 RC950.2 RC952.2 RC953.2 RD25.1 RD26.1 RD28.1 RD29.2 RD33.1 RE22.1 RE24.1 RE46.2 RE48.2 RE58.2 RH22.1 RH23.1 RH24.1 RI16.2 RI17.2 RI20.2 RL2.1 RL4.2 RL6.1 RP1.2 RP2.2 RP3.2 RPC14.1 RPC14.2 RPC14.3 RPC14.4 RPC30.1 RPC30.2 RPC30.3 RPC30.4 RPC45.3 RPC45.4 RPH2.5 RPH2.6 RS18.2 RS21.2 RS22.1 RS23.2 RS24.2 RS31.2 RS35.2 RS36.2 RS37.2 RV2.1 RV4.2 RV9.2 RV12.2 RV13.2 RV16.2 RV17.1 RV21.1 RV29.1 RV34.2 RV35.2 RV38.2 RV39.1 RV40.1 RV41.1 RV49.2 RV51.2 RV53.2 RV55.2 RV59.1 RV74.1 RV75.1 RV83.2 RV88.1 RV89.1 RV117.2 RV119.2 RV121.2 RV131.2 RV132.2 RV133.2 RV151.1 RV160.2 RV163.2 RV368.1 RV369.2 RW8.2 RW13.2 SW1.1 SW2.1 U1.2 U2.4 U15.11 U15.15 U74.2 U2301.11 U2301.15 U2302.11 U2302.15 U2407.6 UA1.49 UC1.A2 UC1.A8 UC1.A13 UC1.A18 UC1.A23 UC1.A32 UC1.A35 UC1.A39 UC1.AA1 UC1.AA2 UC1.AA3 UC1.AA5 UC1.AA10 UC1.AA39 UC1.AC3 UC1.AC7 UC1.AC10 UC1.AC11 UC1.AC13 UC1.AC15 UC1.AC17 UC1.AC19 UC1.AC21 UC1.AC23 UC1.AC25 UC1.AC27 UC1.AC29 UC1.AC31 UC1.AC38 UC1.AC39 UC1.AC41 UC1.AE3 UC1.AE5 UC1.AE10 UC1.AE39 UC1.AG3 UC1.AG7 UC1.AG10 UC1.AG11 UC1.AG13 UC1.AG15 UC1.AG17 UC1.AG19 UC1.AG21 UC1.AG23 UC1.AG25 UC1.AG27 UC1.AG29 UC1.AG31 UC1.AG39 UC1.AG41 UC1.AJ3 UC1.AJ5 UC1.AJ10 UC1.AJ29 UC1.AJ31 UC1.AJ39 UC1.AL1 UC1.AL2 UC1.AL3 UC1.AL7 UC1.AL10 UC1.AL31 UC1.AL39 UC1.AL41 UC1.AM25 UC1.AM27 UC1.AM29 UC1.AM31 UC1.AN3 UC1.AN5 UC1.AN39 UC1.AR3 UC1.AR11 UC1.AR19 UC1.AR23 UC1.AR27 UC1.AR31 UC1.AR39 UC1.AR41 UC1.AU3 UC1.AU9 UC1.AU21 UC1.AU25 UC1.AU29 UC1.AU39 UC1.AW3 UC1.AW5 UC1.AW7 UC1.AW9 UC1.AW11 UC1.AW13 UC1.AW15 UC1.AW17 UC1.AW19 UC1.AW21 UC1.AW23 UC1.AW25 UC1.AW27 UC1.AW29 UC1.AW31 UC1.AW33 UC1.AW35 UC1.AW37 UC1.AW39 UC1.AW41 UC1.AY1 UC1.AY11 UC1.B8 UC1.B13 UC1.B32 UC1.B39 UC1.BA7 UC1.BA11 UC1.BA15 UC1.BA19 UC1.BA23 UC1.BA31 UC1.BA35 UC1.BA39 UC1.C3 UC1.C5 UC1.C7 UC1.C9 UC1.C11 UC1.C13 UC1.C15 UC1.C17 UC1.C19 UC1.C21 UC1.C23 UC1.C25 UC1.C27 UC1.C29 UC1.C31 UC1.C33 UC1.C35 UC1.C37 UC1.C39 UC1.C41 UC1.E1 UC1.E2 UC1.E3 UC1.E21 UC1.E25 UC1.E29 UC1.E35 UC1.E38 UC1.E39 UC1.G1 UC1.G2 UC1.G3 UC1.G11 UC1.G13 UC1.G23 UC1.G27 UC1.G31 UC1.G35 UC1.G37 UC1.G39 UC1.G41 UC1.H23 UC1.J3 UC1.J8 UC1.J39 UC1.L3 UC1.L8 UC1.L13 UC1.L19 UC1.L21 UC1.L23 UC1.L25 UC1.L27 UC1.L29 UC1.L31 UC1.L39 UC1.L41 UC1.N1 UC1.N2 UC1.N3 UC1.N39 UC1.R3 UC1.R11 UC1.R13 UC1.R15 UC1.R17 UC1.R19 UC1.R21 UC1.R23 UC1.R25 UC1.R27 UC1.R29 UC1.R31 UC1.R39 UC1.R41 UC1.U1 UC1.U2 UC1.U3 UC1.U10 UC1.U39 UC1.W3 UC1.W10 UC1.W11 UC1.W13 UC1.W15 UC1.W17 UC1.W19 UC1.W21 UC1.W23 UC1.W25 UC1.W27 UC1.W29 UC1.W31 UC1.W39 UC1.W41 UC4.3 UC5.4 UC61.3 UC62.3 UC63.3 UC64.3 UC65.3 UC101.2 UE1.11 UE1.24 UE1.35 UE1.94 UE1.113 UI5.2 UL1.33 UL3.2 US2.3 US2.21 UU3.2 UV1.A3 UV1.A30 UV1.AA11 UV1.AA13 UV1.AA16 UV1.AA27 UV1.AB6 UV1.AB10 UV1.AB15 UV1.AB24 UV1.AB32 UV1.AC9 UV1.AC17 UV1.AC24 UV1.AC26 UV1.AC27 UV1.AD6 UV1.AD8 UV1.AD25 UV1.AD32 UV1.AE7 UV1.AE14 UV1.AE27 UV1.AF32 UV1.AG12 UV1.AG27 UV1.AH10 UV1.AH28 UV1.AH32 UV1.B6 UV1.B8 UV1.B10 UV1.B12 UV1.B14 UV1.B16 UV1.B18 UV1.B20 UV1.B22 UV1.B24 UV1.B26 UV1.C1 UV1.C32 UV1.E28 UV1.F2 UV1.F6 UV1.F8 UV1.F10 UV1.F12 UV1.F14 UV1.F16 UV1.F18 UV1.F20 UV1.F22 UV1.F24 UV1.F26 UV1.G8 UV1.G10 UV1.G27 UV1.G31 UV1.H2 UV1.H6 UV1.H14 UV1.H17 UV1.H20 UV1.J7 UV1.J27 UV1.J31 UV1.K2 UV1.K6 UV1.K11 UV1.K22 UV1.K28 UV1.K32 UV1.L27 UV1.M6 UV1.M12 UV1.M32 UV1.N11 UV1.N13 UV1.N16 UV1.N18 UV1.N21 UV1.N25 UV1.N27 UV1.P6 UV1.P9 UV1.P25 UV1.P32 UV1.R11 UV1.R12 UV1.R15 UV1.R17 UV1.R20 UV1.R27 UV1.T6 UV1.T11 UV1.T13 UV1.T16 UV1.T18 UV1.T21 UV1.T25 UV1.T32 UV1.U9 UV1.U15 UV1.U17 UV1.U20 UV1.U25 UV1.U27 UV1.V11 UV1.V13 UV1.V16 UV1.V18 UV1.V32 UV1.W25 UV1.W26 UV1.W27 UV1.Y10 UV1.Y15 UV1.Y17 UV1.Y20 UV1.Y25 UV1.Y32 UV2.3 UV3.3 UV4.4 UV13.A1 UV13.A3 UV13.A12 UV13.A14 UV13.B5 UV13.B10 UV13.C1 UV13.C3 UV13.C4 UV13.C11 UV13.C12 UV13.C14 UV13.D10 UV13.E1 UV13.E3 UV13.E12 UV13.E14 UV13.F5 UV13.F10 UV13.G5 UV13.G10 UV13.H1 UV13.H2 UV13.H13 UV13.H14 UV13.K1 UV13.K2 UV13.K13 UV13.K14 UV13.L5 UV13.L10 UV13.M5 UV13.M10 UV13.N1 UV13.N3 UV13.N12 UV13.N14 UV13.P10 UV13.R1 UV13.R3 UV13.R4 UV13.R11 UV13.R12 UV13.R14 UV13.T5 UV13.T10 UV13.U1 UV13.U3 UV13.U12 UV13.U14 UV15.A1 UV15.A3 UV15.A12 UV15.A14 UV15.B5 UV15.B10 UV15.C1 UV15.C3 UV15.C4 UV15.C11 UV15.C12 UV15.C14 UV15.D10 UV15.E1 UV15.E3 UV15.E12 UV15.E14 UV15.F5 UV15.F10 UV15.G5 UV15.G10 UV15.H1 UV15.H2 UV15.H13 UV15.H14 UV15.K1 UV15.K2 UV15.K13 UV15.K14 UV15.L5 UV15.L10 UV15.M5 UV15.M10 UV15.N1 UV15.N3 UV15.N12 UV15.N14 UV15.P10 UV15.R1 UV15.R3 UV15.R4 UV15.R11 UV15.R12 UV15.R14 UV15.T5 UV15.T10 UV15.U1 UV15.U3 UV15.U12 UV15.U14 YL1.2 YL1.4 YV1.2 YV1.4
GNDA: CA10.2 CA11.2 CA12.2 CA20.1 CA21.1 CA23.2 CA26.2 CA34.2 CA35.2 CA36.2 CA37.2 CA40.2 JHP1.7 RA13.2 RA17.1 RA18.1 RA19.1 RA20.1 RA21.1 RA22.1 RA30.2 RA34.2 RA40.2 UA1.25 UA1.38
V3D3_STB: RA11.1 RA12.1 UA1.20
VCCSENSE_VGA: PR1138.2 RV159.1 RV161.1
VDD_1.2V: PC209.1 PR205.1 PR206.2 PU200.11
VDD_CHG: PC768.2 PR741.1 PR749.2 PR750.2 PR760.1 PR781.1 PU703.19
VDDCR_FCH_S5: PC804.1 PJP802.2 PU800.4
VDDIO_APU: PC1064.1 PR1023.2 PR1028.2 PU1001.6
VDDIO_AUDIO: RC11.2 RC18.2 UC1.AM13
VDDIO_VGA: PC1101.1 PR1113.2 PR1115.2 PU1100.6
VDDP_CHG: PC769.2 PR760.2 PU703.20
VDDR4: UV1.U12 UV1.V12 UV1.Y12
VSS_MECH: UV1.A32 UV1.AM1 UV1.AM32
VSSSENSE_VGA: PR1139.2 RV158.1 RV160.1
0.95_1.8VALW_PWREN: PR301.1 PR601.1 RE46.1 UE1.127
0.775PW_EN: PR801.1 UE1.17
32K_X1: CC686.1 RC914.2 UC1.BA2 YC3.1
32K_X2: CC682.1 RC914.1 UC1.AY2 YC3.2
48M_X1: C797.1 RC939.2 UC1.F2 YC2.1
48M_X2: C796.1 RC939.1 UC1.F1 YC2.3
+0.775MOS: Q2516.1 R2636.2 U2.2 U2.5
+APU_CORE: CC1009.1 CC1010.1 CC1011.1 CC1015.1 CC1016.1 CC1052.1 CC1053.1 CC1054.1 CC1055.1 CC1068.1 CC1117.1 CC1120.1 CC1121.1 CC1122.1 CC1123.1 CC1125.1 CC1127.1 CC1128.1 PC911.1 PC912.1 PC913.1 PC914.1 PC915.1 PC916.1 PC917.1 PC954.1 PC955.1 PC956.1 PL1004.4 PR1051.2 UC1.AA25 UC1.AA27 UC1.AA29 UC1.AA31 UC1.K21 UC1.K23 UC1.K25 UC1.K27 UC1.K29 UC1.K31 UC1.N21 UC1.N23 UC1.N25 UC1.N27 UC1.N29 UC1.N31 UC1.U23 UC1.U25 UC1.U27 UC1.U29 UC1.U31
+APU_CORE_NB: C2618.1 CC1067.1 CC1078.1 CC1079.1 CC1081.1 CC1082.1 CC1084.1 CC1095.1 CC1096.1 CC1097.1 CC1098.1 CC1139.1 CC1140.1 CC1141.1 CC1142.1 CC1143.1 CC1144.1 CC1145.1 CC1146.1 PC931.1 PC932.1 PC959.1 PC960.1 PL1002.4 PR1002.1 Q135.1 U2.3 UC1.AA11 UC1.AA13 UC1.AA15 UC1.AA17 UC1.AA19 UC1.AA21 UC1.AA23 UC1.AE11 UC1.AE13 UC1.AE15 UC1.AE17 UC1.AE19 UC1.AE21 UC1.AE23 UC1.AE25 UC1.AE27 UC1.AE29 UC1.AE31 UC1.E9 UC1.E11 UC1.E13 UC1.E15 UC1.E17 UC1.E19 UC1.G7 UC1.J7 UC1.K11 UC1.K13 UC1.K15 UC1.K17 UC1.K19 UC1.L7 UC1.L10 UC1.L15 UC1.L17 UC1.N7 UC1.N11 UC1.N13 UC1.N15 UC1.N17 UC1.N19 UC1.R7 UC1.U7 UC1.U11 UC1.U13 UC1.U15 UC1.U17 UC1.U19 UC1.U21 UC1.W7
+BIF_VDDC: CV122.1 CV180.2 CV181.2 RV31.2 UV1.R21 UV1.U21
+CHGRTC: DC3803.2 JP12.2
+DCBAT_CAM: JEDP1.3 JEDP1.4 R51.2
+DP_VDDC: CV30.1 CV33.1 CV34.1 RV30.1 UV1.AD14
+DP_VDDR: CV26.1 CV27.1 CV35.1 RV27.1 UV1.AF14
+EC_VCCA: CE21.1 LE3.2 PR24.2 UE1.67
+FB0_VREFCL: CV395.1 RV54.2 RV55.1 UV13.J14
+FB0_VREFDL: CV394.1 RV52.2 RV53.1 UV13.A10 UV13.U10
+FB1_VREFCL: CV391.1 RV50.2 RV51.1 UV15.J14
+FB1_VREFDL: CV390.1 RV48.2 RV49.1 UV15.A10 UV15.U10
+INV_PWR_SRC: C4.1 C5.1 F1.2 JEDP1.1 JEDP1.2 R4.2 R51.1
+LAN_VDD10: CL5.1 CL6.1 UL1.8 UL1.30
+LAN_VDD33: CL7.1 CL8.1 JP3.1 RL1.1 RL5.2 RL10.1 RL12.2 UL1.32 UL3.1
+LAN_VDDREG: CL14.1 RL5.1 UL1.23
+LCDVDD: LX1.1 U1.1
+LCDVDD_CONN: C2.1 C3.1 JEDP1.6 JEDP1.7 JEDP1.8 LX1.2
+LINE1-VREFO-L: RA29.1 UA1.31
+LINE1-VREFO-R: RA33.1 UA1.30
+MEM_VREF: CC29.1 CC99.2 RC5.1 RC8.2 RC458.1
+MIC2-VREFO: RA25.1 RA26.1 UA1.29
+MPLL_PVDD: CV81.1 CV82.1 CV124.1 LV6.2 UV1.L8
+MVREFDA: CV94.1 RV33.2 RV34.1 UV1.K26
+MVREFSA: CV95.1 RV32.2 RV35.1 UV1.J26
+PCIE_VDDC: CV54.1 CV55.1 CV56.1 CV57.1 CV58.1 CV59.1 CV60.1 CV120.1 CV121.1 RV364.2 UV1.L23 UV1.L24 UV1.L25 UV1.L26 UV1.M22 UV1.N22 UV1.N23 UV1.N24 UV1.R22 UV1.T22 UV1.U22 UV1.V22
+RTC_APU: CC119.1 RC93.2 UC101.3
+RTC_APU_R: CC166.1 CC923.1 CC1129.2 CLRP1.1 Q91.1 RC93.1 UC1.AM11
+RTCBATT: JRTC1.1 RC31.2
+RTCVCC: CC120.1 DC3803.1 JP14.2 RA12.2 UC101.1
+SPI_VCC: CC635.1 JH1.8 RC639.2 RC640.2 RC642.2 RC1672.2 RC1675.2 UC5.8
+SPLL_PVDD: CV84.1 CV85.1 CV86.1 LV7.2 UV1.H7
+SPLL_VDDC: CV91.1 CV92.1 CV93.1 LV8.2 UV1.H8
+TSVDD: CV19.1 CV20.1 CV21.1 LV2.2 UV1.AD17
+V_DAC: CL12.2 TL1.3 TL1.4
+VGA_CORE: CV67.1 CV68.1 CV69.1 CV70.1 CV71.1 CV72.1 CV73.1 CV74.1 CV75.1 CV76.1 CV77.1 CV78.1 CV79.1 CV80.1 CV87.1 CV88.1 CV89.1 CV90.1 CV100.1 CV101.1 CV102.1 CV103.1 CV104.1 CV105.1 CV106.1 CV107.1 CV108.1 CV109.1 CV110.1 CV111.1 CV112.1 CV113.1 CV114.1 CV115.1 CV116.1 CV117.1 CV118.1 CV119.1 CV125.1 CV126.1 CV127.1 PC836.1 PC837.1 PC838.1 PC839.1 PL1102.4 PL1103.4 RV161.2 RV367.1 UV1.AA12 UV1.AA15 UV1.M11 UV1.M13 UV1.M15 UV1.M16 UV1.M17 UV1.M18 UV1.M20 UV1.M21 UV1.N12 UV1.N15 UV1.N17 UV1.N20 UV1.R13 UV1.R16 UV1.R18 UV1.T12 UV1.T15 UV1.T17 UV1.T20 UV1.U11 UV1.U13 UV1.U16 UV1.U18 UV1.V15 UV1.V17 UV1.V20 UV1.V21 UV1.Y13 UV1.Y16 UV1.Y18 UV1.Y21
+VGA_CORE_M70: RV367.2 UV1.AB11 UV1.AB12 UV1.AB13 UV1.AC11 UV1.AC13 UV1.AC14 UV1.T10 UV1.U10 UV1.W9 UV1.W10 UV1.Y9
+VREF_CA: CD218.1 CD219.1 CD220.1 CD228.1 JDIMM1.164 RD24.1 RD26.2
+VREFB_CA: CD256.1 CD266.1 CD267.1 CD268.1 JDIMM2.164 RD32.1 RD33.2
A_MIC_CLK: JEDP1.28 LA1.1 RA56.1
A_MIC_DATA: JEDP1.29 RA55.1
ACIN: CE40.2 PR12.1 PR731.1 PR741.2 PU703.2 UE1.110 UV3.1
ACIN_65W: RE51.1 RV150.2 UV3.2
ACIN_CHG: PC711.2 PQ712.1 PR729.2 PR732.1 PU703.1
ACLIM: PR749.1 PR751.2 PU703.16
ACOFF: PQ712.2 UE1.27
AD_BID0: CE39.1 RE20.1 RE22.2 UE1.66
ADJ_1.5VS: PC404.2 PR401.2 PR402.1 PU400.7
ADJ_2.5V: PC903.2 PR901.2 PR902.1 PU900.7
ADP_I: PC748.1 PR774.1 UE1.65
AGPIO5: RC933.2 UC1.AK1
AGPIO8: RC22.1 RC932.2 UC1.AJ4
AGPIO11: RC953.1 RC954.2 UC1.AJ8
AGPIO21: RC643.1 UC1.AC1
AGPIO25: RC661.1 UC1.AY13
APU_ALERT#: RPC25.2 UC1.A30
APU_DBRDY: JHDT1.14 UC1.A26
APU_DBREQ#: RH25.2 RPH1.4 UC1.A25
APU_DBREQ#_R: JHDT1.16 RH25.1
APU_FCH_POK: RC52.2 UE1.32
APU_FCH_PWRGD: CC23.1 CC999.2 CC1000.2 RC51.2 RC52.1 RC53.1 UC61.2
APU_FCH_PWRGD_R: RC21.2 RC53.2 RC350.2 UC1.AE2 UC61.4
APU_HDMI_CLK: QI2.1 RPI3.1 UC1.G17
APU_HDMI_DATA: QI2.4 RPI3.2 UC1.H17
APU_I2C1_SCL: RPC36.8 UC1.AU19
APU_I2C1_SDA: RPC36.7 UC1.AV19
APU_ID: RC707.2 RC708.1 UC1.AL5
APU_MAB_VREFDQ: T45.1(TP-1) UC1.Y41
APU_PCIE_RST#: RC27.1 RC28.2 RC30.2 RL9.2 RW11.2 UC4.4 UV2.2
APU_PCIE_RST#_C: CC912.1 RC25.1 RC30.1 RC907.1
APU_PCIE_RST#_R: RC907.2 UC1.AE4
APU_PCIE_WAKE#: RC967.1 RE41.1 RL10.2 UL1.21
APU_PCIE_WAKE#_R: RC967.2 UC1.AE7
APU_PWRGD: CC50.1 DH1.2 PU1001.9 RC4.2 RC54.1 RC81.2 RC663.2 UC1.G25 UC62.4
APU_PWRGD_BUF: DH1.1 JHDT1.10
APU_PWRGD_EC: RC54.2 UC62.2 UE1.108
APU_PWRGD_R: CC32.2 RC663.1 UC1.AJ2
APU_RST#: CC51.1 DH2.2 RC7.2 RC57.1 RC80.2 RC662.2 UC1.D29 UC63.4
APU_RST#_BUF: DH2.1 JHDT1.12
APU_RST#_EC: RC57.2 UC63.2 UE1.118
APU_RST#_R: CC31.2 RC662.1 UC1.AL4
APU_SCLK0: JDIMM1.253 JDIMM2.253 RPC64.3 UC1.AY33
APU_SDATA0: JDIMM1.254 JDIMM2.254 RPC64.4 UC1.BA32
APU_SIC: QC79.4 RPC25.3 UC1.B30
APU_SID: QC79.1 RPC25.1 UC1.B29
APU_SPI_CLK: C27.1 JH1.6 RC106.1 RC617.1 UC5.6
APU_SPI_CLK_R: RC106.2 UC1.AY17
APU_SPI_CS1#: JH1.1 RC639.1 UC1.AY21 UC5.1
APU_SPI_CS1#_R: RC48.1 T52.1(TP-1) UC1.AY19
APU_SPI_HOLD#: JH1.7 RC642.1 UC1.BA18 UC5.7
APU_SPI_MISO: JH1.2 UC1.BA17 UC5.2
APU_SPI_MOSI: JH1.5 UC1.AY20 UC5.5
APU_SPI_TPMCS#: RC646.1 UC1.BA21
APU_SPI_WP#: JH1.3 RC640.1 UC1.BA20 UC5.3
APU_SPKR: CC15.1 DA3.3 UC1.AP29
APU_SVC: PU1001.3 RC9.2 RC669.1
APU_SVC_R: RC669.2 UC1.E27
APU_SVD: PU1001.5 RC10.2 RC670.1
APU_SVD_R: RC670.2 UC1.D27
APU_SVT: PU1001.7 RC2.2 RC673.1
APU_SVT_R: RC673.2 UC1.H27
APU_TCK: JHDT1.2 RPH1.1 UC1.B27
APU_TDI: JHDT1.6 RPH1.3 UC1.B25
APU_TDO: JHDT1.8 UC1.A27
APU_TEST0: RC40.2 RC678.2 UC1.AF2
APU_TEST1: RC33.2 RC41.2 UC1.AE1
APU_TEST2: RC42.2 RC683.2 UC1.AC8
APU_TEST4: T34.1(TP-1) UC1.H29
APU_TEST5: T35.1(TP-1) UC1.G29
APU_TEST6: T36.1(TP-1) UC1.H25
APU_TEST9: T38.1(TP-1) UC1.R32
APU_TEST10: T39.1(TP-1) UC1.N32
APU_TEST14: RPC30.7 UC1.G21
APU_TEST15: RPC30.8 UC1.H21
APU_TEST16: RPC30.6 UC1.D23
APU_TEST17: RPC30.5 UC1.E23
APU_TEST18: JHDT1.20 RPH2.4 UC1.A28
APU_TEST19: JHDT1.18 RPH2.3 UC1.B28
APU_TEST28_H: T43.1(TP-1) UC1.N8
APU_TEST28_L: T42.1(TP-1) UC1.N10
APU_TEST31: T41.1(TP-1) UC1.H31
APU_TEST36: RC154.1 RC155.1 UC1.D25
APU_TEST41: RC117.1 RC118.1 UC1.B31
APU_TMS: JHDT1.4 RPH1.2 UC1.B26
APU_TRST#: CH2.1 RH21.1 RPH2.2 UC1.A29
APU_TRST#_R: CH1.1 JHDT1.9 RH21.2
APU_VDD_RUN_FB_L: PR1067.1 PR1069.2 RC32.2
APU_VDD_SEN: PR1051.1 PR1075.2 T46.1(TP-1) UC1.D31
APU_VDDIO_MEM_S3_FB_H: PR212.2 UC1.D35
APU_VDDNB_SEN: PR1002.2 PR1006.1 T44.1(TP-1) UC1.E33
APU_VDDP_RUN_FB_H: PR310.2 UC1.AM21
APU_VDDP_RUN_FB_L: PR311.2 RC23.2
APU_VSS_SENSE_A: RC29.1 RC32.1 UC1.D33
APU_VSS_SENSE_B: RC23.1 UC1.AM23
ASGATE: PR762.2 PU703.30
AUD_HP1_JACK_L1: LA8.1 RA27.2 RA28.2 RA29.2
AUD_HP1_JACK_R1: LA9.1 RA31.2 RA32.2 RA33.2
AUD_PORTA_L_R_B: CA35.1 DA4.2 JHP1.1 LA8.2 RA30.1
AUD_PORTA_R_R_B: CA34.1 DA4.3 JHP1.2 LA9.2 RA34.1
AUD_SENSE_A: CA40.1 RA10.1 RA41.1 UA1.13
BA: PD704.3 PQ710.1 PR780.1
BATT_CHG_LED: JLED1.3 Q6102.1
BATT_CHG_LED#: Q2.4 UE1.21
BATT_CHG_LED_R#: Q2.3 Q5.1 Q6102.2
BATT_I: PC749.2 PR775.1 UE1.75
BATT_LOW_LED: JLED1.2 Q3.1
BATT_LOW_LED#: Q2.1 UE1.93
BATT_LOW_LED_R#: Q2.6 Q3.2
BATT_TEMP: CE43.2 PC14.1 PC753.2 PD3.2 PR15.2 PR16.1 PR756.1 PR764.1 UE1.63
BEEP#: DA3.2 UE1.23
BKOFF#: DX1.2 UE1.105
BP_0: RV82.1 UV1.U1
BP_1: RV81.1 UV1.U3
BST1_APU: PR1082.1 PU1001.21
BST1_VGA: PR1123.1 PU1100.21
BST2_VGA: PR1103.1 PU1100.30
BST_1.2V: PR200.2 PU200.18
BST_1.2V_R: PC200.1 PR200.1
BST_3V: PR100.1 PU100.1
BST_5V: PR111.1 PU102.1
BST_+1.35VGPU: PR1402.1 PU1400.1
BST_+1.35VGPU_R: PC1407.1 PR1402.2
BST_NB: PR1008.1 PU1001.31
BST_VDDP_ALWP: PR303.1 PU300.10
BT_ON#: JWLAN1.46 RC45.2 UC1.AV33
CAM_DETECT#: JEDP1.34 UC1.AY26
CAP_LED: JKB1.4 R27.2
CAP_LED_Q: Q7.1 R27.1
CAP_LED_R#: Q6.1 Q7.2
CAPS_LED: Q6.3 R28.2 R36.1 UE1.91
CCLIM: PR750.1 PR752.2 PU703.11
CLK_PCIE_LAN: UC1.M2 UL1.15
CLK_PCIE_LAN#: UC1.M1 UL1.16
CLK_PCIE_WLAN: JWLAN1.39 UC1.L2
CLK_PCIE_WLAN#: JWLAN1.41 UC1.L1
CLK_PEG_VGA: UC1.H2 UV1.AK30
CLK_PEG_VGA#: UC1.H1 UV1.AK32
CLK_SMB: PBATT1.7 PR18.1
CMSRC: PR763.2 PU703.29
COMP: PC751.2 PR754.2 PU703.10
CORE_NB_GATE: Q135.2 Q2513.2 R56.1 U2.1 U2.6
CORETYPE: RC654.2 UC1.D9
CPU_DPB_CTRLCLK_R: JHDMI1.15 QI2.6 RPI3.4
CPU_DPB_CTRLDAT_R: JHDMI1.16 QI2.3 RPI3.3
CS_1.2V: PR205.2 PU200.13
DAT_SMB: PBATT1.6 PR20.1
DBC_EN: R6.2 UE1.89
DBC_EN_R: JEDP1.10 R5.1 R6.1
DDRA_CKE0: JDIMM1.109 UC1.J38
DDRA_CKE1: JDIMM1.110 UC1.J34
DDRA_CLK0: JDIMM1.137 UC1.AC35
DDRA_CLK0#: JDIMM1.139 UC1.AC34
DDRA_CLK1: JDIMM1.138 UC1.AA34
DDRA_CLK1#: JDIMM1.140 UC1.AA32
DDRA_ODT0: JDIMM1.155 UC1.AN37
DDRA_ODT1: JDIMM1.161 UC1.AU38
DDRA_SCS0#: JDIMM1.149 UC1.AL35
DDRA_SCS1#: JDIMM1.157 UC1.AR37
DDRAB_BG0: JDIMM1.115 JDIMM2.115 UC1.N34
DDRAB_BG1: JDIMM1.113 JDIMM2.113 UC1.L38
DDRAB_SBS0#: JDIMM1.150 JDIMM2.150 UC1.AJ38
DDRAB_SBS1#: JDIMM1.145 JDIMM2.145 UC1.AG35
DDRAB_SCAS#: JDIMM1.156 JDIMM2.156 UC1.AN38
DDRAB_SDM0: JDIMM1.12 JDIMM2.12 UC1.B35
DDRAB_SDM1: JDIMM1.33 JDIMM2.33 UC1.D40
DDRAB_SDM2: JDIMM1.54 JDIMM2.54 UC1.K40
DDRAB_SDM3: JDIMM1.75 JDIMM2.75 UC1.T41
DDRAB_SDM4: JDIMM1.178 JDIMM2.178 UC1.AE41
DDRAB_SDM5: JDIMM1.199 JDIMM2.199 UC1.AL40
DDRAB_SDM6: JDIMM1.220 JDIMM2.220 UC1.AU40
DDRAB_SDM7: JDIMM1.241 JDIMM2.241 UC1.BA37
DDRAB_SDQ0: JDIMM1.8 JDIMM2.8 UC1.A34
DDRAB_SDQ1: JDIMM1.7 JDIMM2.7 UC1.B34
DDRAB_SDQ2: JDIMM1.20 JDIMM2.20 UC1.A38
DDRAB_SDQ3: JDIMM1.21 JDIMM2.21 UC1.B38
DDRAB_SDQ4: JDIMM1.4 JDIMM2.4 UC1.A33
DDRAB_SDQ5: JDIMM1.3 JDIMM2.3 UC1.B33
DDRAB_SDQ6: JDIMM1.16 JDIMM2.16 UC1.A37
DDRAB_SDQ7: JDIMM1.17 JDIMM2.17 UC1.B37
DDRAB_SDQ8: JDIMM1.28 JDIMM2.28 UC1.B41
DDRAB_SDQ9: JDIMM1.29 JDIMM2.29 UC1.C40
DDRAB_SDQ10: JDIMM1.41 JDIMM2.41 UC1.F41
DDRAB_SDQ11: JDIMM1.42 JDIMM2.42 UC1.G40
DDRAB_SDQ12: JDIMM1.24 JDIMM2.24 UC1.A40
DDRAB_SDQ13: JDIMM1.25 JDIMM2.25 UC1.B40
DDRAB_SDQ14: JDIMM1.38 JDIMM2.38 UC1.E41
DDRAB_SDQ15: JDIMM1.37 JDIMM2.37 UC1.F40
DDRAB_SDQ16: JDIMM1.50 JDIMM2.50 UC1.J40
DDRAB_SDQ17: JDIMM1.49 JDIMM2.49 UC1.J41
DDRAB_SDQ18: JDIMM1.62 JDIMM2.62 UC1.N40
DDRAB_SDQ19: JDIMM1.63 JDIMM2.63 UC1.N41
DDRAB_SDQ20: JDIMM1.46 JDIMM2.46 UC1.H40
DDRAB_SDQ21: JDIMM1.45 JDIMM2.45 UC1.H41
DDRAB_SDQ22: JDIMM1.58 JDIMM2.58 UC1.M40
DDRAB_SDQ23: JDIMM1.59 JDIMM2.59 UC1.M41
DDRAB_SDQ24: JDIMM1.70 JDIMM2.70 UC1.R40
DDRAB_SDQ25: JDIMM1.71 JDIMM2.71 UC1.T40
DDRAB_SDQ26: JDIMM1.83 JDIMM2.83 UC1.W40
DDRAB_SDQ27: JDIMM1.84 JDIMM2.84 UC1.Y40
DDRAB_SDQ28: JDIMM1.66 JDIMM2.66 UC1.P40
DDRAB_SDQ29: JDIMM1.67 JDIMM2.67 UC1.P41
DDRAB_SDQ30: JDIMM1.79 JDIMM2.79 UC1.V40
DDRAB_SDQ31: JDIMM1.80 JDIMM2.80 UC1.V41
DDRAB_SDQ32: JDIMM1.174 JDIMM2.174 UC1.AD41
DDRAB_SDQ33: JDIMM1.173 JDIMM2.173 UC1.AD40
DDRAB_SDQ34: JDIMM1.187 JDIMM2.187 UC1.AH41
DDRAB_SDQ35: JDIMM1.186 JDIMM2.186 UC1.AH40
DDRAB_SDQ36: JDIMM1.170 JDIMM2.170 UC1.AB40
DDRAB_SDQ37: JDIMM1.169 JDIMM2.169 UC1.AC40
DDRAB_SDQ38: JDIMM1.183 JDIMM2.183 UC1.AF40
DDRAB_SDQ39: JDIMM1.182 JDIMM2.182 UC1.AG40
DDRAB_SDQ40: JDIMM1.195 JDIMM2.195 UC1.AK41
DDRAB_SDQ41: JDIMM1.194 JDIMM2.194 UC1.AK40
DDRAB_SDQ42: JDIMM1.207 JDIMM2.207 UC1.AP41
DDRAB_SDQ43: JDIMM1.208 JDIMM2.208 UC1.AP40
DDRAB_SDQ44: JDIMM1.191 JDIMM2.191 UC1.AJ41
DDRAB_SDQ45: JDIMM1.190 JDIMM2.190 UC1.AJ40
DDRAB_SDQ46: JDIMM1.203 JDIMM2.203 UC1.AN41
DDRAB_SDQ47: JDIMM1.204 JDIMM2.204 UC1.AN40
DDRAB_SDQ48: JDIMM1.216 JDIMM2.216 UC1.AT40
DDRAB_SDQ49: JDIMM1.215 JDIMM2.215 UC1.AU41
DDRAB_SDQ50: JDIMM1.228 JDIMM2.228 UC1.AY40
DDRAB_SDQ51: JDIMM1.229 JDIMM2.229 UC1.BA40
DDRAB_SDQ52: JDIMM1.211 JDIMM2.211 UC1.AR40
DDRAB_SDQ53: JDIMM1.212 JDIMM2.212 UC1.AT41
DDRAB_SDQ54: JDIMM1.224 JDIMM2.224 UC1.AW40
DDRAB_SDQ55: JDIMM1.225 JDIMM2.225 UC1.AY41
DDRAB_SDQ56: JDIMM1.237 JDIMM2.237 UC1.BA38
DDRAB_SDQ57: JDIMM1.236 JDIMM2.236 UC1.AY37
DDRAB_SDQ58: JDIMM1.249 JDIMM2.249 UC1.BA34
DDRAB_SDQ59: JDIMM1.250 JDIMM2.250 UC1.BA33
DDRAB_SDQ60: JDIMM1.232 JDIMM2.232 UC1.AY39
DDRAB_SDQ61: JDIMM1.233 JDIMM2.233 UC1.AY38
DDRAB_SDQ62: JDIMM1.245 JDIMM2.245 UC1.AY35
DDRAB_SDQ63: JDIMM1.246 JDIMM2.246 UC1.AY34
DDRAB_SDQS0: JDIMM1.13 JDIMM2.13 UC1.B36
DDRAB_SDQS0#: JDIMM1.11 JDIMM2.11 UC1.A36
DDRAB_SDQS1: JDIMM1.34 JDIMM2.34 UC1.E40
DDRAB_SDQS1#: JDIMM1.32 JDIMM2.32 UC1.D41
DDRAB_SDQS2: JDIMM1.55 JDIMM2.55 UC1.L40
DDRAB_SDQS2#: JDIMM1.53 JDIMM2.53 UC1.K41
DDRAB_SDQS3: JDIMM1.76 JDIMM2.76 UC1.U41
DDRAB_SDQS3#: JDIMM1.74 JDIMM2.74 UC1.U40
DDRAB_SDQS4: JDIMM1.179 JDIMM2.179 UC1.AF41
DDRAB_SDQS4#: JDIMM1.177 JDIMM2.177 UC1.AE40
DDRAB_SDQS5: JDIMM1.200 JDIMM2.200 UC1.AM40
DDRAB_SDQS5#: JDIMM1.198 JDIMM2.198 UC1.AM41
DDRAB_SDQS6: JDIMM1.221 JDIMM2.221 UC1.AV40
DDRAB_SDQS6#: JDIMM1.219 JDIMM2.219 UC1.AV41
DDRAB_SDQS7: JDIMM1.242 JDIMM2.242 UC1.BA36
DDRAB_SDQS7#: JDIMM1.240 JDIMM2.240 UC1.AY36
DDRAB_SMA0: JDIMM1.144 JDIMM2.144 UC1.AG38
DDRAB_SMA1: JDIMM1.133 JDIMM2.133 UC1.W35
DDRAB_SMA2: JDIMM1.132 JDIMM2.132 UC1.W38
DDRAB_SMA3: JDIMM1.131 JDIMM2.131 UC1.W34
DDRAB_SMA4: JDIMM1.128 JDIMM2.128 UC1.U38
DDRAB_SMA5: JDIMM1.126 JDIMM2.126 UC1.U37
DDRAB_SMA6: JDIMM1.127 JDIMM2.127 UC1.U34
DDRAB_SMA7: JDIMM1.122 JDIMM2.122 UC1.R35
DDRAB_SMA8: JDIMM1.125 JDIMM2.125 UC1.R38
DDRAB_SMA9: JDIMM1.121 JDIMM2.121 UC1.N38
DDRAB_SMA10: JDIMM1.146 JDIMM2.146 UC1.AG34
DDRAB_SMA11: JDIMM1.120 JDIMM2.120 UC1.R34
DDRAB_SMA12: JDIMM1.119 JDIMM2.119 UC1.N37
DDRAB_SMA13: JDIMM1.158 JDIMM2.158 UC1.AN35
DDRAB_SRAS#: JDIMM1.152 JDIMM2.152 UC1.AJ37
DDRAB_SWE#: JDIMM1.151 JDIMM2.151 UC1.AL38
DDRB_CKE0: JDIMM2.109 UC1.L34
DDRB_CKE1: JDIMM2.110 UC1.J37
DDRB_CLK0: JDIMM2.137 UC1.AE38
DDRB_CLK0#: JDIMM2.139 UC1.AE37
DDRB_CLK1: JDIMM2.138 UC1.AA37
DDRB_CLK1#: JDIMM2.140 UC1.AA38
DDRB_ODT0: JDIMM2.155 UC1.AL34
DDRB_ODT1: JDIMM2.161 UC1.AN34
DDRB_SCS0#: JDIMM2.149 UC1.AJ34
DDRB_SCS1#: JDIMM2.157 UC1.AR38
DEVSLP0_HDD: RC44.2 RS8.1 UC1.AV31
DEW1: RS34.1 RS36.1 US2.16
DEW2: RS33.1 RS35.1 US2.6
DGPU_PWROK: PR1122.2 PR1403.1 UE1.18
DIR: CV182.2 CV184.2 RV102.1 UV4.5
DISPOFF#: DX1.1 JEDP1.24 RP2.1
DP0_HPD: R13.2 UC1.D15
DP1_HPD: QI3.3 RI17.1 UC1.D17
DP_AUX_ZVSS: RC401.1 UC1.D21
DP_VSSR: UV1.AF19 UV1.AF20 UV1.AF23 UV1.AG14 UV1.AG23 UV1.AH14 UV1.AM14 UV1.AM16 UV1.AM18 UV1.AM20 UV1.AM22 UV1.AM24
DP_ZVSS: RC400.1 UC1.B18
DRAM_RST: RV36.1 UV13.J2 UV15.J2
DRAM_RST_G: CV97.1 RV37.1 RV38.1 UV1.L10
E51_RX1: JWLAN1.32 RW7.2
E51_RX2: JWLAN1.60 RW10.2
E51_TX1: JWLAN1.30 RW6.2 RW8.1
E51_TX2: JWLAN1.58 RW9.2
EC_ENVDD: RX8.2 UE1.71
EC_LID_OUT#: CE42.1 RC943.2 RE44.1 UC1.AG5
EC_LID_OUT#_R: RE44.2 UE1.101
EC_MUTE#: RA8.2 UA1.47 UE1.83
EC_ON: PR114.1 UE1.112
EC_PME#: RE21.2 RE41.2 UE1.29
EC_RSMRST#: CE41.1 DC3.1 RE48.1 UE1.100
EC_RSMRST#_R: CC52.1 DC3.2 RC346.2 UC1.AG1
EC_RST#: CE23.1 UE1.37
EC_RX: RW7.1 RW10.1 UE1.31
EC_SCI#: RE61.2 RE66.2 UC1.AA8 UE1.20
EC_SMB_CK1: PD2.3 PR18.2 PR770.1 RE31.1
EC_SMB_CK1_R: RE31.2 RPE1.8 UE1.77
EC_SMB_CK2: QC79.3 QV1.6 RC16.2 RE33.1 U2407.10
EC_SMB_CK2_R: RE33.2 RPE1.6 UE1.79
EC_SMB_DA1: PD2.2 PR20.2 PR769.1 RE32.1
EC_SMB_DA1_R: RE32.2 RPE1.7 UE1.78
EC_SMB_DA2: QC79.6 QV1.3 RC17.2 RE34.1 U2407.9
EC_SMB_DA2_R: RE34.2 RPE1.5 UE1.80
EC_SMI#: RC665.1 RC666.2 RE19.2 RE40.1
EC_SMI#_R: RE40.2 UE1.15
EC_TP_INT#: RE338.1 UE1.106
EC_TX: RW6.1 RW9.1 UE1.30
ECAGND: CE21.2 CE43.1 LE4.2 PH1.2 UE1.69
EDP_AUXN: C4322.2 UC1.H15
EDP_AUXN_C: C4322.1 JEDP1.15
EDP_AUXP: C4321.2 UC1.G15
EDP_AUXP_C: C4321.1 JEDP1.14
EDP_HPD: JEDP1.11 R13.1 RP1.1
EDP_TXN0: C4311.2 UC1.B9
EDP_TXN0_C: C4311.1 JEDP1.17
EDP_TXN1: C4313.2 UC1.B10
EDP_TXN1_C: C4313.1 JEDP1.20
EDP_TXP0: C4312.2 UC1.A9
EDP_TXP0_C: C4312.1 JEDP1.18
EDP_TXP1: C4314.2 UC1.A10
EDP_TXP1_C: C4314.1 JEDP1.21
EGPIO131: RC697.2 UC1.AP31
EGPIO145: RC55.2 UC1.AY22
EGPIO146: RC61.2 UC1.BA22
EN_0.6VSP: PC203.1 PR202.2 PU200.7
EN_1.2V: PC202.1 PR201.2 PU200.8
EN_1.5VS: PC403.1 PR403.2 PU400.2
EN_1.8VALW: PC602.1 PR601.2 PR602.2 PU600.5
EN_2.5V: PC905.1 PR903.2 PU900.2
EN_3V: PR121.1 PU100.12
EN_5V: PR120.1 PU102.12
EN_+1.35VGPU: PC1404.1 PR1403.2 PR1404.1 PU1400.11
EN_VDDP_ALWP: PC301.1 PR301.2 PU300.3
ENABLE_APU: PR1085.2 PU1001.8
ENABLE_VGA: PR1116.2 PU1100.8
ENLDO_3V5V: PR102.1 PR103.1 PU100.11 PU102.11
ENVDD: RC59.1 RC690.1 RX7.2 UC64.4
ENVDD_R: RC59.2 RPC45.6 UC1.B24 UC64.2
ENVDD_RE: RX7.1 RX8.1 U1.4
ERP_LOT6: PR14.1 UE1.73
FAN_PWM: JFAN1.2 RF2.1 UE1.26
FAN_SPEED1: DF1.2 RF1.1 UE1.28
FB_1.2V: PC214.1 PR204.1 PR207.1 PU200.6
FB_1.8VALW: PC603.2 PR604.1 PR605.1 PU600.6
FB_+1.35VGPU: PC1409.2 PR1410.1 PR1411.1 PU1400.14
FB_GND: RV158.2 UV1.AD20
FB_VDDC: RV159.2 UV1.AC20
FB_VDDCI: T222.1(TP-1) UV1.W1
FB_VDDP_ALWP: PR307.1 PR308.1 PU300.4
GATEA20: RPC36.6 UC1.AU35 UE1.1
GFX_PWRGD_APU: RC664.2 UC1.AD1
GPIO19_CTF: RV151.2 RV152.1 UV1.M2
GPIO28: RV21.2 UV1.R5
GPU_AC_LIGHT: RE51.2 UE1.68
GPU_VID1: RV76.1 RV94.1 UV1.P8
GPU_VID1_GPIO_20: RV73.1 RV74.2 RV76.2 UV4.3
GPU_VID3: RV93.1 RV103.1 UV1.N1
GPU_VID3_GPIO_15: RV75.2 RV92.1 RV103.2 UV4.2
H_PROCHOT#: PQ2.6 PQ3.1 PQ721.1 PR777.1 PR1021.2 PU1001.4 RC159.2 RC661.2 RE42.2 UC1.A31
HDA_BITCLK: RC13.2 RC706.2 RPC13.7 RPC14.6 UC1.AY6
HDA_BITCLK_AUDIO: RA44.1 RPC13.2 UA1.6
HDA_RST: RPC13.5 RPC14.8 UC1.AY4
HDA_RST#_AUDIO: RA14.1 RPC13.4
HDA_SDIN0: RA43.2 RC703.2 UC1.BA6
HDA_SDIN0_R: RA43.1 UA1.8
HDA_SDIN1: RC695.2 UC1.AY5
HDA_SDIN2: RC696.2 UC1.BA5
HDA_SDOUT: RPC13.8 RPC14.5 UC1.BA4
HDA_SDOUT_AUDIO: RPC13.1 UA1.5
HDA_SYNC: RPC13.6 RPC14.7 UC1.BA3
HDA_SYNC_AUDIO: RPC13.3 UA1.10
HDD_A0_PRE0: RS24.1 RS27.2 US2.9
HDD_A0_PRE1: RS23.1 RS30.2 US2.19
HDD_B0_EQ: RS37.1 RS38.1 US2.13
HDD_B0_PRE0: RS21.1 RS28.2 US2.8
HDD_B0_PRE1: RS18.1 RS29.2 US2.17
HDD_REXT_SATA0: RS26.2 RS31.1 US2.20
HDMI_DP1_TXN0: CI7.2 UC1.B14
HDMI_DP1_TXN1: CI5.2 UC1.B15
HDMI_DP1_TXN2: CI3.2 UC1.B16
HDMI_DP1_TXN3: CI1.2 UC1.B17
HDMI_DP1_TXP0: CI8.2 UC1.A14
HDMI_DP1_TXP1: CI6.2 UC1.A15
HDMI_DP1_TXP2: CI4.2 UC1.A16
HDMI_DP1_TXP3: CI2.2 UC1.A17
HDMI_HPLUG: CI10.1 JHDMI1.19 RI16.1 RI18.2
HPOUT-L: RA27.1 UA1.32
HPOUT-R: RA31.1 UA1.33
HVB_FUNCTION: RC49.2 UC1.AP27
I2C_CLK_TP: JTP1.6 RP20.2 UC1.AC5
I2C_DAT_TP: JTP1.7 RP20.3 UC1.AC4
ILMT_+1.35VGPU: PR1406.2 PR1407.1 PU1400.13
IMON_APU: PC1062.2 PR1076.2 PU1001.10
IMON_NB: PC1018.2 PR1018.2 PU1001.2
IMON_VGA: PC1117.2 PR1117.2 PU1100.10
INT-SPK-L+: LA5.1 UA1.42
INT-SPK-L-: LA6.1 UA1.43
INT-SPK-R+: LA3.1 UA1.45
INT-SPK-R-: LA4.1 UA1.44
INVTPWM: JEDP1.23 RC58.1 RC691.1 RP3.1 UC65.4
INVTPWM_R: RC58.2 UC1.A24 UC65.2
IR_GND: JEDP1.25 JEDP1.26 R7.1
ISEN1_VGA: PC1120.2 PR1124.1 PU1100.13
ISEN2_VGA: PC1119.2 PR1104.1 PU1100.12
ISOLATEB: RL3.2 RL4.1 UL1.20
JACK_PLUG_DET: JHP1.6 RA40.1
JACK_SENSE#: JHP1.5 RA42.2
JACK_SENSE_1#: RA41.2 RA42.1
JHDD_P10: JHDD1.8 RS8.2
JTAG_TCK: RPV34.6 UV1.L3
JTAG_TDI_GPU: RPV34.8 UV1.L5
JTAG_TDO_GPU: RV369.1 UV1.K4
JTAG_TMS_GPU: RPV34.7 UV1.L1
JTAG_TRSTB: RPV34.5 UV1.L6
KB_BL_PWM: JKBBL1.4 Q8.1
KB_DET: JKBBL1.2 QE4.2 RE58.1
KB_DET#: QE4.1 RE68.1 UC1.BA28
KB_LED_PWM: Q8.2 UE1.25
KB_RST#: RC50.2 UC1.BA30 UE1.2
KSI0: JKB1.22 UE1.55
KSI1: JKB1.24 UE1.56
KSI2: JKB1.26 UE1.57
KSI3: JKB1.23 UE1.58
KSI4: JKB1.27 UE1.59
KSI5: JKB1.25 UE1.60
KSI6: JKB1.28 UE1.61
KSI7: JKB1.29 UE1.62
KSO0: JKB1.13 UE1.39
KSO1: JKB1.15 RE62.2 UE1.40
KSO2: JKB1.14 RE63.2 UE1.41
KSO3: JKB1.16 UE1.42
KSO4: JKB1.20 UE1.43
KSO5: JKB1.21 UE1.44
KSO6: JKB1.18 UE1.45
KSO7: JKB1.19 UE1.46
KSO8: JKB1.17 UE1.47
KSO9: JKB1.7 UE1.48
KSO10: JKB1.5 UE1.49
KSO11: JKB1.6 UE1.50
KSO12: JKB1.12 UE1.51
KSO13: JKB1.9 UE1.52
KSO14: JKB1.8 UE1.53
KSO15: JKB1.10 UE1.54
KSO16: JKB1.11 UE1.81
LAN_CLKREQ#: RL11.1 UC1.AY32 UL1.12
LCD_TEST: RX2.1 UE1.72
LCD_TST_C: JEDP1.12 RX2.2
LDO_+1.35VGPU: PC1406.1 PU1400.16 PU1400.17
LG1_APU: PQ1008.4 PQ1009.4 PU1001.24
LG1_VGA: PQ1105.4 PQ1106.4 PU1100.24
LG2_VGA: PQ1102.4 PQ1103.4 PU1100.27
LG_1.2V: PQ201.8 PU200.15
LG_NB: PQ1002.4 PQ1003.4 PU1001.34
LG_VDDP_ALWP: PQ302.4 PU300.6
LGATE_CHG: PQ708.4 PU703.21
LID_SW#: D4.1 EC2902.1 JPWR1.2 RE75.2 UE1.115
LINE1-L: CA32.1 UA1.22
LINE1-L_C: CA32.2 RA28.1
LINE1-L_R: CA33.2 RA32.1
LINE1-R: CA33.1 UA1.21
LPC_AD0: UC1.BA26 UE1.10
LPC_AD1: UC1.AY28 UE1.8
LPC_AD2: UC1.AY25 UE1.7
LPC_AD3: UC1.AY23 UE1.5
LPC_CLK0_EC: CC30.1 RC449.1 RC904.2 RC926.1 RE16.1 UE1.12
LPC_CLK1: RC450.1 RC925.2 RC927.1
LPC_FRAME#: RC902.2 RC903.1 UC1.AY24 UE1.4
LPC_RST_A#: RC602.2 UC1.AY27
LX1_APU: PC1038.2 PL1004.1 PQ1007.1 PQ1007.2 PQ1007.3 PQ1008.5 PQ1009.5 PR1074.1 PU1001.23
LX1_VGA: PC1118.2 PL1103.1 PQ1104.1 PQ1104.2 PQ1104.3 PQ1105.5 PQ1106.5 PR1125.1 PU1100.23
LX2_VGA: PC1108.2 PL1102.1 PQ1101.1 PQ1101.2 PQ1101.3 PQ1102.5 PQ1103.5 PR1107.1 PU1100.28
LX_1.2V: PC200.2 PC207.1 PL200.2 PQ201.9 PU200.16
LX_1.8VALW: PL601.1 PR606.1 PU600.2 PU600.3
LX_3V: PC102.2 PL100.1 PR106.1 PU100.6 PU100.19 PU100.20
LX_5V: PC114.2 PL101.1 PR112.1 PU102.6 PU102.19 PU102.20
LX_+1.35VGPU: PC1407.2 PL1401.1 PR1408.1 PU1400.6 PU1400.19 PU1400.20
LX_NB: PC1009.2 PL1002.1 PQ1001.1 PQ1001.2 PQ1001.3 PQ1002.5 PQ1003.5 PR1010.1 PU1001.33
LX_VDDP_ALWP: PC305.2 PL302.1 PQ301.1 PQ301.2 PQ301.3 PQ302.5 PR305.1 PU300.8
M0_MA0: UV1.K17 UV13.H4
M0_MA1: UV1.J20 UV13.H5
M0_MA2: UV1.H23 UV13.H11
M0_MA3: UV1.G23 UV13.H10
M0_MA4: UV1.G24 UV13.K11
M0_MA5: UV1.H24 UV13.K10
M0_MA6: UV1.J19 UV13.K5
M0_MA7: UV1.K19 UV13.K4
M0_MA8: UV1.G20 UV13.J5
M1_MA0: UV1.J14 UV15.H4
M1_MA1: UV1.K14 UV15.H5
M1_MA2: UV1.J11 UV15.H11
M1_MA3: UV1.J13 UV15.H10
M1_MA4: UV1.H11 UV15.K11
M1_MA5: UV1.G11 UV15.K10
M1_MA6: UV1.J16 UV15.K5
M1_MA7: UV1.L15 UV15.K4
M1_MA8: UV1.G14 UV15.J5
M_ADBI0: UV1.L18 UV13.J4
M_ADBI1: UV1.K16 UV15.J4
M_CAS#0: UV1.G19 UV13.L3
M_CAS#1: UV1.G16 UV15.L3
M_CKE0: UV1.K20 UV13.J3
M_CKE1: UV1.J17 UV15.J3
M_CLK0: RV79.2 UV1.H26 UV13.J12
M_CLK1: RV85.2 UV1.G9 UV15.J12
M_CLK#0: RV80.2 UV1.H25 UV13.J11
M_CLK#1: RV86.2 UV1.H9 UV15.J11
M_CS0B#0: UV1.H22 UV13.G12
M_CS1B#0: UV1.G13 UV15.G12
M_DA0: UV1.K27 UV13.A2
M_DA1: UV1.J29 UV13.B2
M_DA2: UV1.H30 UV13.A4
M_DA3: UV1.H32 UV13.B4
M_DA4: UV1.G29 UV13.F2
M_DA5: UV1.F28 UV13.F4
M_DA6: UV1.F32 UV13.E4
M_DA7: UV1.F30 UV13.E2
M_DA8: UV1.C30 UV13.F11
M_DA9: UV1.F27 UV13.B13
M_DA10: UV1.A28 UV13.E11
M_DA11: UV1.C28 UV13.B11
M_DA12: UV1.E27 UV13.E13
M_DA13: UV1.G26 UV13.A13
M_DA14: UV1.D26 UV13.F13
M_DA15: UV1.F25 UV13.A11
M_DA16: UV1.A25 UV13.M4
M_DA17: UV1.C25 UV13.T4
M_DA18: UV1.E25 UV13.N4
M_DA19: UV1.D24 UV13.U4
M_DA20: UV1.E23 UV13.T2
M_DA21: UV1.F23 UV13.N2
M_DA22: UV1.D22 UV13.U2
M_DA23: UV1.F21 UV13.M2
M_DA24: UV1.E21 UV13.M11
M_DA25: UV1.D20 UV13.M13
M_DA26: UV1.F19 UV13.N13
M_DA27: UV1.A19 UV13.N11
M_DA28: UV1.D18 UV13.U13
M_DA29: UV1.F17 UV13.T13
M_DA30: UV1.A17 UV13.U11
M_DA31: UV1.C17 UV13.T11
M_DA32: UV1.E17 UV15.F4
M_DA33: UV1.D16 UV15.E4
M_DA34: UV1.F15 UV15.F2
M_DA35: UV1.A15 UV15.E2
M_DA36: UV1.D14 UV15.B4
M_DA37: UV1.F13 UV15.A2
M_DA38: UV1.A13 UV15.A4
M_DA39: UV1.C13 UV15.B2
M_DA40: UV1.E11 UV15.B11
M_DA41: UV1.A11 UV15.A11
M_DA42: UV1.C11 UV15.B13
M_DA43: UV1.F11 UV15.A13
M_DA44: UV1.A9 UV15.E11
M_DA45: UV1.C9 UV15.E13
M_DA46: UV1.F9 UV15.F11
M_DA47: UV1.D8 UV15.F13
M_DA48: UV1.E7 UV15.U2
M_DA49: UV1.A7 UV15.M2
M_DA50: UV1.C7 UV15.N2
M_DA51: UV1.F7 UV15.T2
M_DA52: UV1.A5 UV15.T4
M_DA53: UV1.E5 UV15.M4
M_DA54: UV1.C3 UV15.N4
M_DA55: UV1.E1 UV15.U4
M_DA56: UV1.G7 UV15.M11
M_DA57: UV1.G6 UV15.N11
M_DA58: UV1.G1 UV15.N13
M_DA59: UV1.G3 UV15.M13
M_DA60: UV1.J6 UV15.T13
M_DA61: UV1.J1 UV15.U13
M_DA62: UV1.J3 UV15.U11
M_DA63: UV1.J5 UV15.T11
M_DBI0#: UV1.H27 UV13.D2
M_DBI1#: UV1.A27 UV13.D13
M_DBI2#: UV1.C23 UV13.P2
M_DBI3#: UV1.C19 UV13.P13
M_DBI4#: UV1.C15 UV15.D2
M_DBI5#: UV1.E9 UV15.D13
M_DBI6#: UV1.C5 UV15.P2
M_DBI7#: UV1.H4 UV15.P13
M_EDC_0: UV1.H28 UV13.C2
M_EDC_1: UV1.C27 UV13.C13
M_EDC_2: UV1.A23 UV13.R2
M_EDC_3: UV1.E19 UV13.R13
M_EDC_4: UV1.E15 UV15.C2
M_EDC_5: UV1.D10 UV15.C13
M_EDC_6: UV1.D6 UV15.R2
M_EDC_7: UV1.G5 UV15.R13
M_RAS#0: UV1.G22 UV13.G3
M_RAS#1: UV1.G17 UV15.G3
M_WCKA0_0: UV1.E32 UV13.D4
M_WCKA0_0#: UV1.E30 UV13.D5
M_WCKA0_1: UV1.A21 UV13.P4
M_WCKA0_1#: UV1.C21 UV13.P5
M_WCKA1_0: UV1.E13 UV15.D4
M_WCKA1_0#: UV1.D12 UV15.D5
M_WCKA1_1: UV1.E3 UV15.P4
M_WCKA1_1#: UV1.F4 UV15.P5
M_WE#0: UV1.G25 UV13.L12
M_WE#1: UV1.H10 UV15.L12
MCT0: RL14.1 TL1.10
MCT1: RL15.1 TL1.9
MDI0+: EU3501.5 EU3501.6 TL1.6 UL1.1
MDI0-: EU3501.4 EU3501.7 TL1.5 UL1.2
MDI1+: EU3501.2 EU3501.8 TL1.2 UL1.4
MDI1-: EU3501.1 EU3501.9 TL1.1 UL1.5
MDO0+: JLAN1.1 TL1.7
MDO0-: JLAN1.2 TL1.8
MDO1+: JLAN1.3 TL1.11
MDO1-: JLAN1.6 TL1.12
MEM_MAB_ACT#: JDIMM1.114 JDIMM2.114 UC1.L35
MEM_MAB_EVENT#: JDIMM1.134 JDIMM2.134 RC6.2 UC1.AA41
MEM_MAB_RST#: CD193.1 JDIMM1.108 JDIMM2.108 UC1.G38
MEM_MAB_ZVDDIO: RC75.1 UC1.AB41
MEM_VOLT_SEL: RC928.2 RC929.1 UC1.AJ7
MIC1-L: CA26.1 UA1.19
MIC_CLK_C: CA39.1 LA1.2 UA1.3
MIC_DATA_C: RA55.2 UA1.2
OCP_L: PR1112.2 PU1100.4 RV90.2 RV91.1
ODD_DA#: JODD1.23 JODD1.24 T75.1(TP-1)
ODD_DETECT#: JODD1.15 JODD1.16 T74.1(TP-1)
ON/OFF#: CE20.1 EC2901.1 ED2901.1 JPWR1.3 RE49.2 SW1.2 SW2.2 UE1.114
P_ZVDDP: RC542.2 UC1.U8
P_ZVSS: RC541.1 UC1.W8
PANEL_BKLEN: QC2.1 RC60.1 RC70.1 UE1.76
PANEL_BKLEN_EC: QC2.3 RC60.2 RPC45.5 UC1.B23
PBTN_OUT#: RC942.2 UC1.AD2 UE1.122
PC_BEEP: DA3.1 RA49.2
PC_BEEP_C: CA41.2 CA42.1 RA45.2 RA49.1
PCC_GPIO_6: CVT90.2 RV90.1 UV1.T8
PCIE_ARX_DTX_N0: CL2.1 UC1.U5
PCIE_ARX_DTX_N0_C: CL2.2 UL1.18
PCIE_ARX_DTX_N1: JWLAN1.35 UC1.R10
PCIE_ARX_DTX_P0: CL1.1 UC1.U4
PCIE_ARX_DTX_P0_C: CL1.2 UL1.17
PCIE_ARX_DTX_P1: JWLAN1.33 UC1.R8
PCIE_ATX_C_DRX_N0: CC225.2 UL1.14
PCIE_ATX_C_DRX_N1: CC227.2 JWLAN1.29
PCIE_ATX_C_DRX_P0: CC224.2 UL1.13
PCIE_ATX_C_DRX_P1: CC226.2 JWLAN1.27
PCIE_ATX_DRX_N0: CC225.1 UC1.D1
PCIE_ATX_DRX_N1: CC227.1 UC1.C1
PCIE_ATX_DRX_P0: CC224.1 UC1.D2
PCIE_ATX_DRX_P1: CC226.1 UC1.C2
PEG_CLKREQ#: RC56.2 RV153.1
PEG_CLKREQ#_G: RV153.2 RV368.2 UV1.N7
PEG_CLKREQ#_R: RC56.1 UC1.AV35
PEG_GTX_C_HRX_N0: CV2.2 UC1.L4
PEG_GTX_C_HRX_N1: CV4.2 UC1.J4
PEG_GTX_C_HRX_N2: CV6.2 UC1.G4
PEG_GTX_C_HRX_N3: CV8.2 UC1.E7
PEG_GTX_C_HRX_P0: CV1.2 UC1.L5
PEG_GTX_C_HRX_P1: CV3.2 UC1.J5
PEG_GTX_C_HRX_P2: CV5.2 UC1.G5
PEG_GTX_C_HRX_P3: CV7.2 UC1.D7
PEG_GTX_HRX_N0: CV2.1 UV1.AG31
PEG_GTX_HRX_N1: CV4.1 UV1.AF28
PEG_GTX_HRX_N2: CV6.1 UV1.AF26
PEG_GTX_HRX_N3: CV8.1 UV1.AD26
PEG_GTX_HRX_P0: CV1.1 UV1.AH30
PEG_GTX_HRX_P1: CV3.1 UV1.AG29
PEG_GTX_HRX_P2: CV5.1 UV1.AF27
PEG_GTX_HRX_P3: CV7.1 UV1.AD27
PEG_HTX_C_GRX_N0: CV306.1 UC1.B4
PEG_HTX_C_GRX_N1: CV305.1 UC1.B5
PEG_HTX_C_GRX_N2: CV309.1 UC1.B6
PEG_HTX_C_GRX_N3: CV304.1 UC1.B7
PEG_HTX_C_GRX_P0: CV312.1 UC1.A4
PEG_HTX_C_GRX_P1: CV308.1 UC1.A5
PEG_HTX_C_GRX_P2: CV307.1 UC1.A6
PEG_HTX_C_GRX_P3: CV313.1 UC1.A7
PEG_HTX_GRX_N0: CV306.2 UV1.AE31
PEG_HTX_GRX_N1: CV305.2 UV1.AD28
PEG_HTX_GRX_N2: CV309.2 UV1.AC31
PEG_HTX_GRX_N3: CV304.2 UV1.AB28
PEG_HTX_GRX_P0: CV312.2 UV1.AF30
PEG_HTX_GRX_P1: CV308.2 UV1.AE29
PEG_HTX_GRX_P2: CV307.2 UV1.AD30
PEG_HTX_GRX_P3: CV313.2 UV1.AC29
PHASE_CHG: PC721.2 PL700.1 PQ704.1 PQ704.2 PQ704.3 PQ708.5 PR766.1 PU703.22
PID0: CE47.1 RE23.1 RE24.2 UE1.97
PLL_ANALOG_IN: T221.1(TP-1) UV1.AA1
PLL_ANALOG_OUT: RV83.1 UV1.AA3
PLT_RST#: CC615.1 RC1.2 RC27.2 RC602.1 RL8.1 RW4.2 UE1.13
PLT_RST#_R: RL8.2 RL9.1 UL1.19
PLT_RST#_RW: JWLAN1.44 RW4.1 RW11.1
PLT_RST_VGA#: RV4.1 UV1.AL27 UV2.4
PM_SLP_S3#: CE25.1 RE37.1 UC1.AC2
PM_SLP_S3#_R: RE37.2 UE1.6
PM_SLP_S5#: CE33.1 PQ711.2 RE38.1 UC1.AG4
PM_SLP_S5#_R: RE38.2 UE1.14
POK: PR13.1 PR107.2 PR113.2 PU100.9 PU102.9 UE1.34
PROG: PR753.2 PU703.9
PROH: PQ720.2 PR777.2 PR781.2 PU703.5
PS_0: CV29.1 RV8.2 RV9.1 UV1.AC19
PS_1: CV28.1 RV11.2 RV12.1 UV1.AD19
PS_2: CV11.1 RV13.1 RV28.2 UV1.AE17
PS_3: CV15.1 RV15.2 RV16.1 UV1.AE20
PS_ID: PD5.1 PR3.1 PR4.2 UE1.16
PSID: PJPDC1.3 PL2.2
PSID-1: PQ5.2 PR6.1 PR9.2
PSID-2: PQ5.1 PQ6.2 PR8.2 PR11.1
PSID-3: PQ6.3 PR4.1
PTP_DIS#: JTP1.3 R41.2 RE5.1
PTP_DIS#_R: RE5.2 UE1.38
PWR_LED#: Q16.3 R53.2 UE1.92
PWR_LED_R#: Q15.2 Q16.1
PWRGD_VGA: PR1119.2 PR1122.1 PU1100.9 PU1100.20 UC1.AV29
PX_EN: T218.1(TP-1) UV1.AB16
PXS_PWREN: PR1116.1 R438.1 RC938.2 U74.4 UC1.BA29
PXS_RST#: UC1.AU33 UV2.1
REMOTE1+: C2500.1 C2502.1 Q2407.1 Q2407.2 U2407.2
REMOTE1-: C2500.2 C2502.2 Q2407.3 U2407.3
REMOTE2+: C2504.1 C2505.1 Q2408.1 Q2408.2 U2407.4
REMOTE2-: C2504.2 C2505.2 Q2408.3 U2407.5
RESERVE_1: RC711.2 RC712.1 UC1.AK2
RESERVE_2: RC709.2 RC710.1 UC1.AY29
RF_VDDP_ALWP: PR306.1 PU300.5
RING2: LA7.1 RA25.2 UA1.17
RING2_R: CA36.1 DA5.2 JHP1.4 LA7.2
RTC_CLK: RC949.2 RC950.1 UC1.AN4
RTC_DIS: Q91.2 R1563.1 UE1.36
S0A3: RC694.2 RC944.2 UC1.AB1
S5_MUX_CTRL: Q2516.5 R2634.1 UC1.AA7
SATA_ACT#: Q5.3 RC43.2 RE43.2 UC1.AY30
SATA_ACT#_RR: RD15.2 RE43.1 UE1.117
SATA_ARX_C_DTX_N0: CS33.2 US2.4
SATA_ARX_C_DTX_P0: CS35.2 US2.5
SATA_ARX_DTX_N0: CS33.1 RS44.1 UC1.AY12
SATA_ARX_DTX_N1: CS14.1 UC1.BA8
SATA_ARX_DTX_N1_C: CS14.2 JODD1.9 JODD1.10
SATA_ARX_DTX_P0: CS35.1 RS43.1 UC1.BA12
SATA_ARX_DTX_P1: CS13.1 UC1.AY8
SATA_ARX_DTX_P1_C: CS13.2 JODD1.11 JODD1.12
SATA_ARX_RC_DTX_N0: CS31.1 US2.12
SATA_ARX_RC_DTX_N0_C: CS31.2 CS41.2 JHDD1.5
SATA_ARX_RC_DTX_P0: CS34.1 US2.11
SATA_ARX_RC_DTX_P0_C: CS34.2 CS40.2 JHDD1.6
SATA_ATX_C_DRX_N0: CS36.2 US2.2
SATA_ATX_C_DRX_P0: CS37.2 US2.1
SATA_ATX_DRX_N0: CS36.1 RS42.1 UC1.AY10
SATA_ATX_DRX_N1: CS9.1 UC1.BA9
SATA_ATX_DRX_N1_C: CS9.2 JODD1.5 JODD1.6
SATA_ATX_DRX_P0: CS37.1 RS41.1 UC1.BA10
SATA_ATX_DRX_P1: CS8.1 UC1.AY9
SATA_ATX_DRX_P1_C: CS8.2 JODD1.3 JODD1.4
SATA_ATX_RC_DRX_N0: CS32.1 US2.14
SATA_ATX_RC_DRX_N0_C: CS32.2 CS39.2 JHDD1.3
SATA_ATX_RC_DRX_P0: CS30.1 US2.15
SATA_ATX_RC_DRX_P0_C: CS30.2 CS38.2 JHDD1.2
SATA_LED#_R: Q5.2 R23.1 RD15.1
SATA_RX_N0: CS41.1 RS44.2
SATA_RX_P0: CS40.1 RS43.2
SATA_TX_N0: CS39.1 RS42.2
SATA_TX_P0: CS38.1 RS41.2
SATA_ZVDD: RC96.1 UC1.AP11
SATA_ZVSS: RC90.1 UC1.AU11
SERIRQ: UC1.AV27 UE1.3
SKU_ID: RC692.2 RC693.1 UC1.AE8
SLEEVE: LA10.1 RA26.2 UA1.18
SLEEVE_R: CA37.1 DA5.3 JHP1.3 LA10.2
SNUB_+1.35VGPU: PC1408.1 PR1408.2
SPK_L+_CONN: CA28.1 DA1.3 JSPK1.3 LA5.2
SPK_L-_CONN: CA27.1 DA1.2 JSPK1.4 LA6.2
SPK_R+_CONN: CA30.1 DA2.3 JSPK1.1 LA3.2
SPK_R-_CONN: CA29.1 DA2.2 JSPK1.2 LA4.2
SUSP#: PR202.1 PR403.1 R437.1 R2313.1 R2318.1 UE1.116
SVI2_SVC: PU1100.3 RV84.1 RV89.2 RV94.2 RV100.2 RV157.2
SVI2_SVD: PU1100.5 RV87.1 RV88.2 RV93.2 RV101.2 RV155.2
SVI2_SVT: PU1100.7 RV156.2
SYS_RESET_L: CC53.1 RC951.2 RC952.1 UC1.AF1
SYSON: PR201.1 PR903.1 UE1.95
T-GND_L: CL13.1 RL14.2 RL15.2
TESTEN: RV17.2 RV154.2 UV1.K7
TMDS_L_TX0N: CI13.1 JHDMI1.9 LI2.1 RI4.2 RI6.1
TMDS_L_TX0P: CI14.1 JHDMI1.7 LI2.4 RI5.2 RI6.2
TMDS_L_TX1N: CI15.1 JHDMI1.6 LI3.1 RI7.2 RI9.1
TMDS_L_TX1P: CI16.1 JHDMI1.4 LI3.4 RI8.2 RI9.2
TMDS_L_TX2N: CI17.1 JHDMI1.3 LI4.1 RI11.2 RI12.2
TMDS_L_TX2P: CI18.1 JHDMI1.1 LI4.4 RI10.2 RI12.1
TMDS_L_TXCN: CI11.1 JHDMI1.12 LI1.1 RI1.2 RI3.1
TMDS_L_TXCP: CI12.1 JHDMI1.10 LI1.4 RI2.2 RI3.2
TMDS_TX0N: CI3.1 LI2.2 RI4.1 RPI1.1
TMDS_TX0P: CI4.1 LI2.3 RI5.1 RPI1.2
TMDS_TX1N: CI5.1 LI3.2 RI7.1 RPI2.1
TMDS_TX1P: CI6.1 LI3.3 RI8.1 RPI2.2
TMDS_TX2N: CI7.1 LI4.2 RI11.1 RPI2.3
TMDS_TX2P: CI8.1 LI4.3 RI10.1 RPI2.4
TMDS_TXCN: CI1.1 LI1.2 RI1.1 RPI1.3
TMDS_TXCP: CI2.1 LI1.3 RI2.1 RPI1.4
TON_1.2V: PR208.2 PU200.9
TP_CLK: C553.1 JTP1.1 R31.1 UE1.87
TP_DATA: C551.1 JTP1.2 R32.1 UE1.88
TP_EN: R39.1 UE1.82
TP_I2C_INT#: JTP1.4 Q9.3 R150.2 RE338.2 RP20.1
TP_I2C_INT#_APU: Q9.1 R150.1 RC12.2 RC22.2
TP_ON#_GATE: C22.2 Q12.2 Q85.2 R39.2
TPAN_VDD_F: F2.1 R11.2 R12.2 R14.1
TRIP_VDDP_ALWP: PR304.2 PU300.2
TS_EN_R: D4.2 RX25.2
TS_EN_RR: JEDP1.39 RX25.1
UG1_APU: PQ1007.4 PU1001.22
UG1_VGA: PQ1104.4 PU1100.22
UG2_VGA: PQ1101.4 PU1100.29
UG_1.2V: PQ201.1 PU200.17
UG_NB: PQ1001.4 PU1001.32
UG_VDDP_ALWP: PQ301.4 PU300.9
UGATE_CHG: PR761.1 PU703.23
USB3RN1_JUSB1: LU1.3 RU1.1 UC1.W1
USB3RN1_JUSB1_R: EU2601.1 EU2601.9 JUSB1.5 LU1.4 RU1.2
USB3RN2_JUSB2: LU4.3 RU7.1 UC1.Y1
USB3RN2_JUSB2_R: EU2603.1 EU2603.9 JUSB2.5 LU4.4 RU7.2
USB3RP1_JUSB1: LU1.2 RU2.1 UC1.W2
USB3RP1_JUSB1_R: EU2601.2 EU2601.8 JUSB1.6 LU1.1 RU2.2
USB3RP2_JUSB2: LU4.2 RU8.1 UC1.Y2
USB3RP2_JUSB2_R: EU2603.2 EU2603.8 JUSB2.6 LU4.1 RU8.2
USB3TN1_JUSB1: CU1.2 UC1.R2
USB3TN1_JUSB1_C: CU1.1 LU2.3 RU3.1
USB3TN1_JUSB1_R: EU2601.4 EU2601.7 JUSB1.8 LU2.4 RU3.2
USB3TN2_JUSB2: CU3.2 UC1.P2
USB3TN2_JUSB2_C: CU3.1 LU5.3 RU9.1
USB3TN2_JUSB2_R: EU2603.4 EU2603.7 JUSB2.8 LU5.4 RU9.2
USB3TP1_JUSB1: CU2.2 UC1.R1
USB3TP1_JUSB1_C: CU2.1 LU2.2 RU4.1
USB3TP1_JUSB1_R: EU2601.5 EU2601.6 JUSB1.9 LU2.1 RU4.2
USB3TP2_JUSB2: CU4.2 UC1.P1
USB3TP2_JUSB2_C: CU4.1 LU5.2 RU10.1
USB3TP2_JUSB2_R: EU2603.5 EU2603.6 JUSB2.9 LU5.1 RU10.2
USB20_CAM_N3: L3.4 R18.1 UC1.AT2
USB20_CAM_N3_R: JEDP1.31 L3.3 R18.2
USB20_CAM_P3: L3.1 R17.1 UC1.AT1
USB20_CAM_P3_R: JEDP1.32 L3.2 R17.2
USB20_CR_N0: LU8.2 RU17.1 UC1.AW2
USB20_CR_N0_R: JIOB1.3 LU8.1 RU17.2
USB20_CR_P0: LU8.3 RU18.1 UC1.AW1
USB20_CR_P0_R: JIOB1.4 LU8.4 RU18.2
USB20_JUSB1_N2: LU7.2 RU14.1 UC1.AU2
USB20_JUSB1_N2_R: DU1.3 JIOB1.8 LU7.1 RU14.2
USB20_JUSB1_N5: LU3.2 RU6.1 RU15.1 UC1.AP2
USB20_JUSB1_N5_R: EU2602.3 JUSB1.2 LU3.1 RU6.2
USB20_JUSB1_P2: LU7.3 RU13.1 UC1.AU1
USB20_JUSB1_P2_R: DU1.2 JIOB1.7 LU7.4 RU13.2
USB20_JUSB1_P5: LU3.3 RU5.1 UC1.AP1
USB20_JUSB1_P5_R: EU2602.2 JUSB1.3 LU3.4 RU5.2
USB20_JUSB2_N6: LU6.2 RU12.1 RU16.1 UC1.AN2
USB20_JUSB2_N6_R: EU2604.3 JUSB2.2 LU6.1 RU12.2
USB20_JUSB2_P6: LU6.3 RU11.1 UC1.AN1
USB20_JUSB2_P6_R: EU2604.2 JUSB2.3 LU6.4 RU11.2
USB20_MINI1_N4: JWLAN1.5 UC1.AR2
USB20_MINI1_P4: JWLAN1.3 UC1.AR1
USB20_TOUCH_N1: DX2.3 JEDP1.36 UC1.AV2
USB20_TOUCH_P1: DX2.2 JEDP1.37 UC1.AV1
USB_EN#: CU8.1 CU22.1 RE504.1 UE1.84 UI5.4 UU3.4
USB_OC0#: CU9.1 RC905.2 UC1.AB2 UI5.3
USB_OC1#: CU23.1 RC906.2 UC1.AG2 UU3.3
USB_ZVSS: RC641.1 UC1.AN7
USBSS_ZVDD: RC645.1 UC1.W5
USBSS_ZVSS: RC644.1 UC1.W4
VCIN0_PH: PH1.1 PR24.1 UE1.109
VCOUT0: RE39.2 UE1.104
VCOUT0_PH#: PR116.1 R2450.2 RE39.1
VCOUT1_PH: RE42.1 UE1.103
VGA_AC__BATT: RV150.1 RV260.2 UV1.T9 UV3.4
VGA_SMB_CK3: QV1.1 RV6.2 UV1.U7
VGA_SMB_DA3: QV1.4 RV5.2 UV1.U8
VGATE: PR1070.2 PU1001.20 RC51.1 UE1.74
VL: PC126.1 PU102.15
VR_ON: PR1085.1 UE1.121
VSUM+_APU: PC1053.1 PC1066.1 PR1071.1 PR1079.1 PR1084.1 PU1001.14
VSUM+_VGA: PC1125.1 PC1126.1 PR1108.1 PR1126.1 PR1131.1 PR1132.1 PU1100.14
VSUM-_APU: PC1053.2 PC1065.1 PC1066.2 PH1003.2 PR1066.1 PR1068.1 PR1071.2 PR1072.1
VSUM-_VGA: PC1119.1 PC1120.1 PC1125.2 PC1126.2 PC1129.1 PH1102.2 PR1110.1 PR1128.1 PR1132.2 PR1136.1 PR1137.1
VSUMN_NB: PC1011.2 PC1012.2 PC1014.1 PH1000.2 PR1011.2 PR1013.1 PR1014.1 PR1015.1
VSUMP_NB: PC1011.1 PC1012.1 PR1009.1 PR1011.1 PR1012.1 PU1001.40
VTTREF_1.2V: PC210.1 PU200.4
WAKEB: RV162.2 RV163.1 UV1.AJ27
WHITE_LED_PWR: JPWR1.5 Q15.1
WL_OFF#: QW1.3 RC46.2 RW13.1 UC1.AU31
WL_OFF#_R: C6.1 JWLAN1.48 QW1.1 RW12.2
WLAN_CLKREQ#: JWLAN1.45 UC1.AY31
WLAN_WAKE#: JWLAN1.47 RE70.2 UE1.90
WOL_EN: RL6.2 RL12.1 UE1.98 UL3.4
XTALIN: CV17.1 RV20.1 UV1.AM28 YV1.1
XTALOUT: CV18.1 RV20.2 UV1.AK28 YV1.3
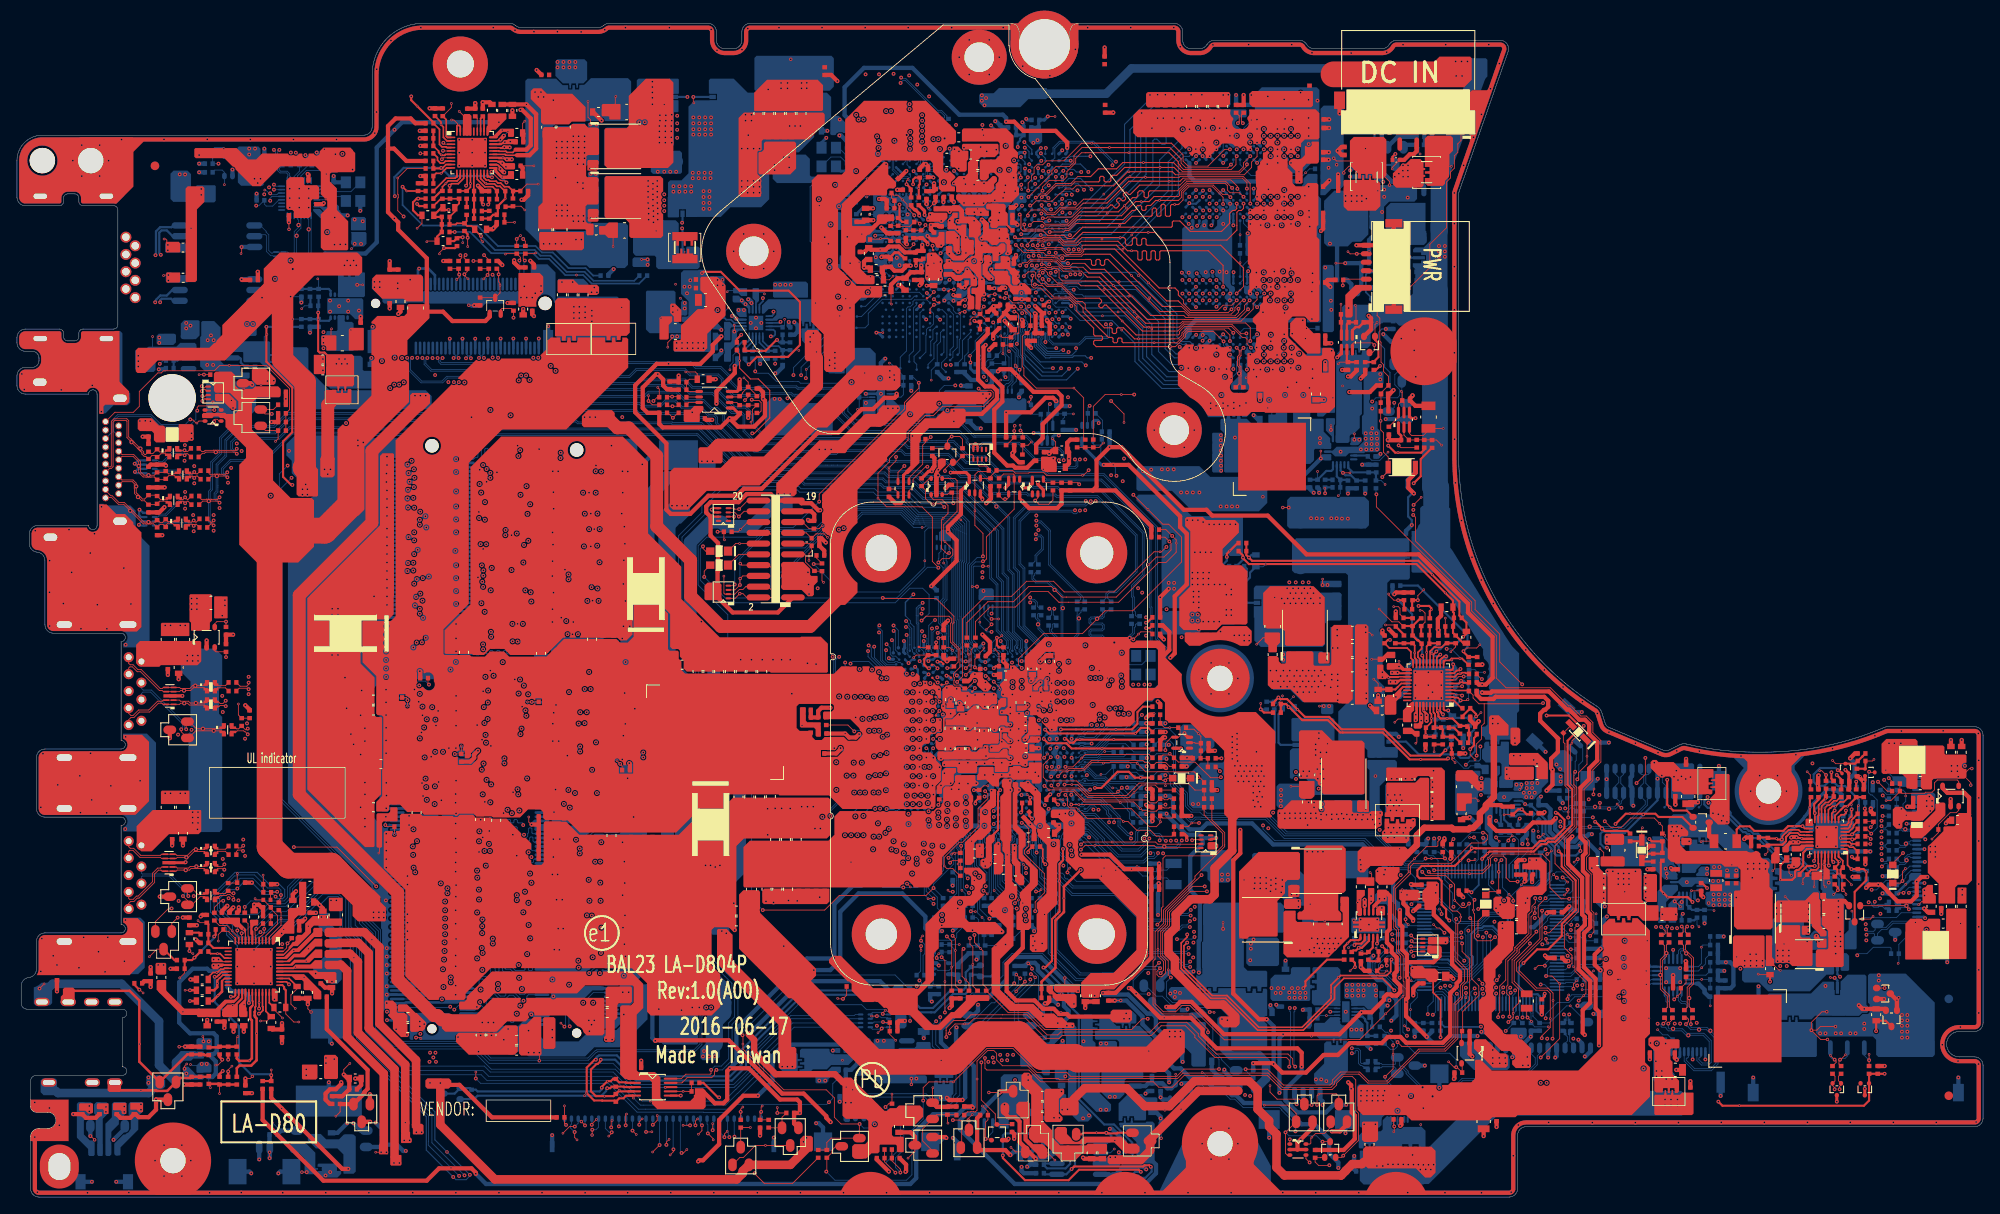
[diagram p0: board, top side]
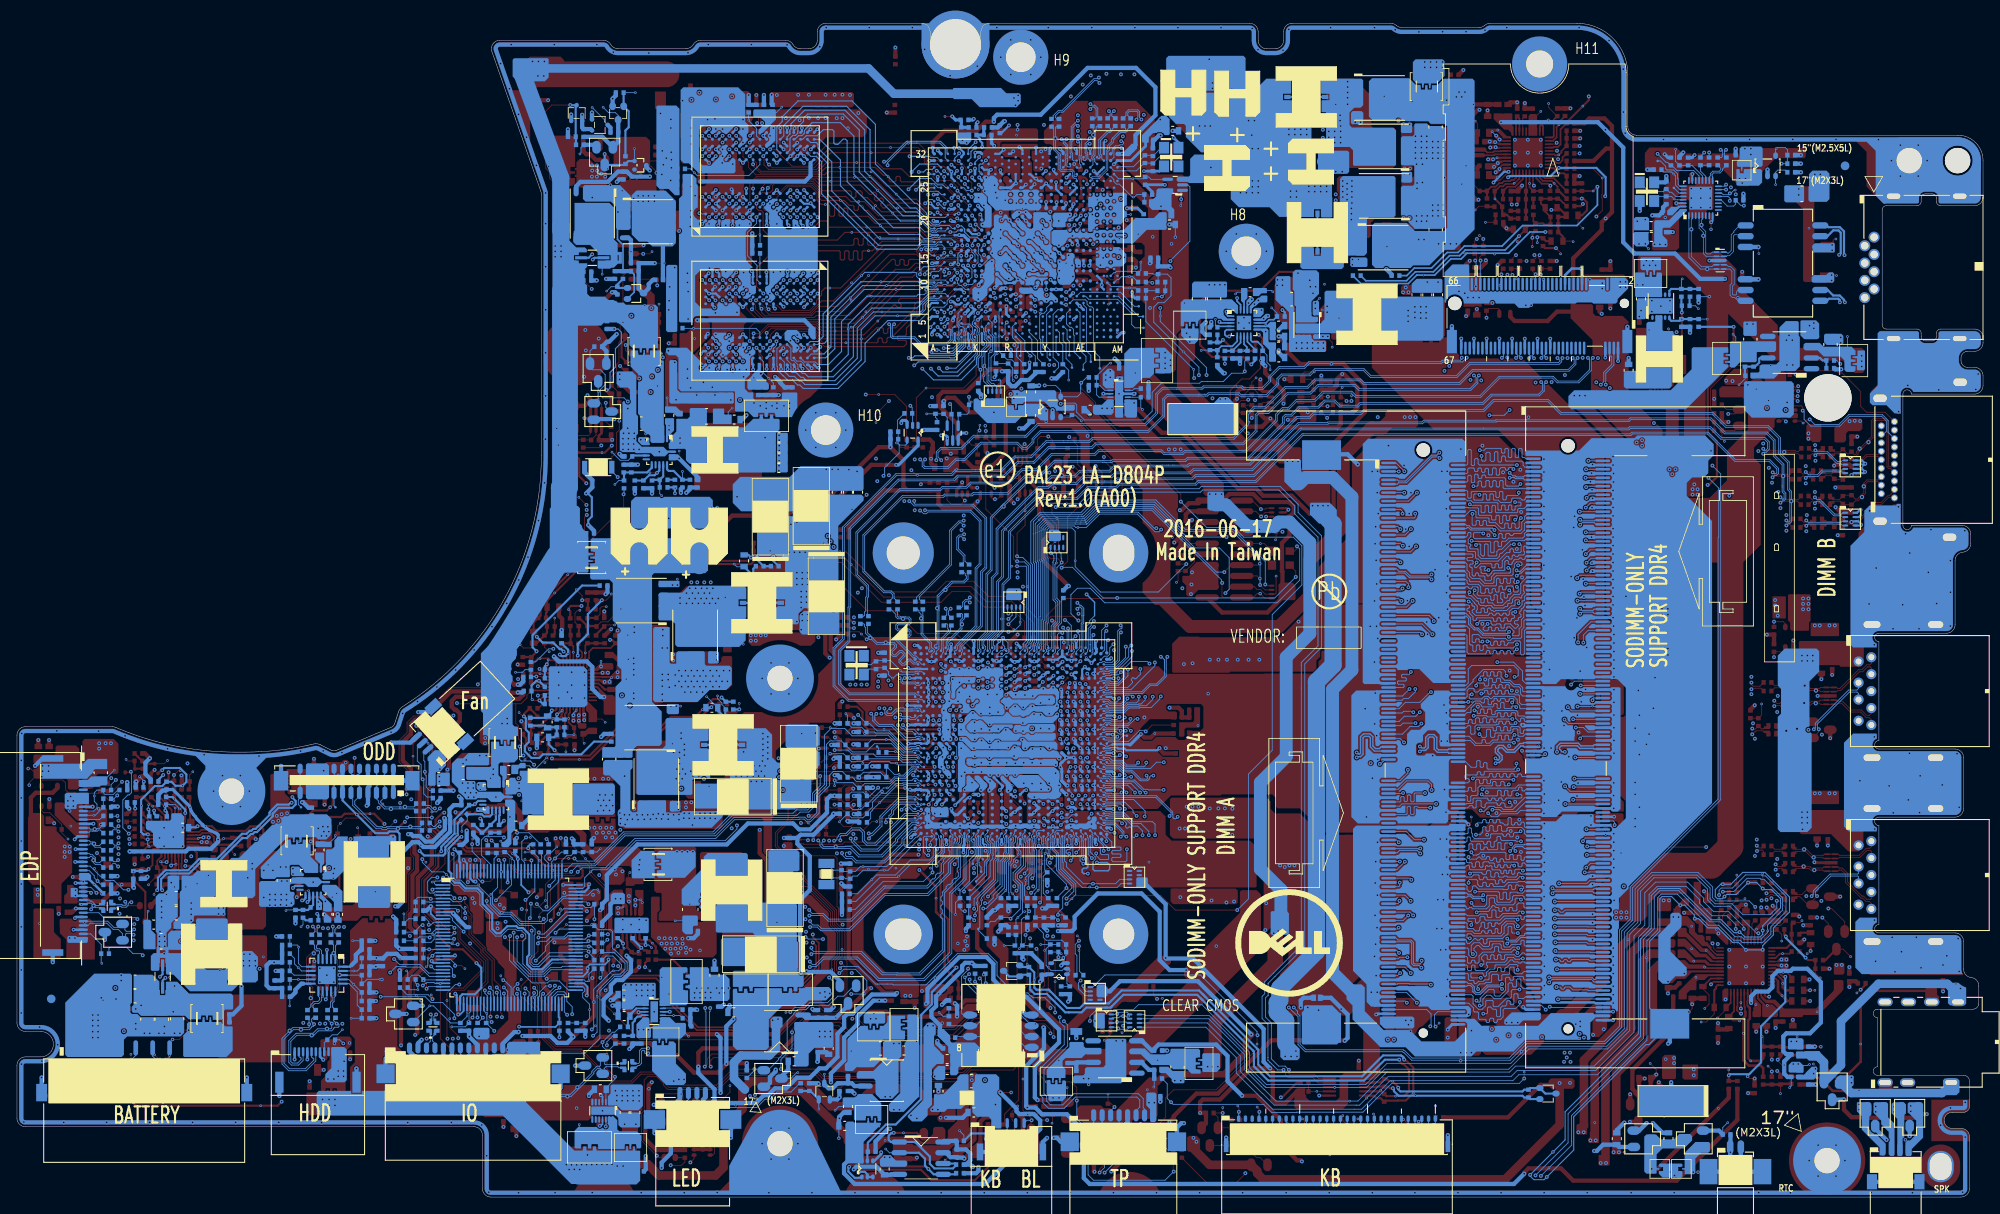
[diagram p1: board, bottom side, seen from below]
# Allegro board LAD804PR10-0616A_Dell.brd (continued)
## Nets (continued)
XTLI: CL10.1 UL1.28 YL1.1
XTLO: CL11.1 UL1.29 YL1.3
N16741477: T212.1(TP-1) UV1.AB8
N16741489: T208.1(TP-1) UV1.AD7
N16741505: T214.1(TP-1) UV1.AB4
N16741517: T206.1(TP-1) UV1.AD9
N16741525: T216.1(TP-1) UV1.Y8
N16741803: RV29.2 UV1.AC22
N16741825: RV59.2 UV1.AB22
N16751828: T209.1(TP-1) UV1.AC8
N16751830: T205.1(TP-1) UV1.AE8
N16751834: T203.1(TP-1) UV1.AE9
N16751836: T201.1(TP-1) UV1.N9
N16751838: T215.1(TP-1) UV1.AB2
N16751842: T211.1(TP-1) UV1.AB9
N16751844: T207.1(TP-1) UV1.AC10
N16751848: T202.1(TP-1) UV1.L9
N16751852: T213.1(TP-1) UV1.AB7
N16751854: T210.1(TP-1) UV1.AC7
N16751856: T204.1(TP-1) UV1.Y11
N16751858: T217.1(TP-1) UV1.Y7
N16808781: RV157.1 UV1.AJ11
N16808782: RV155.1 UV1.AK12
N16808783: RV156.1 UV1.AL11
N16813004: RV71.2 RV72.1 RV84.2 RV87.2
N16855208: R2448.2 R2450.1 U2407.7
N17072999: C5216.1 U2301.12
N17205184: RS19.2 US2.7
N17205187: RS20.2 RS22.2 US2.18
N17205206: RS25.2 US2.10
N17253873: RC12.1 UC1.AY14
N17382836: PC803.1 PQ801.1 PR802.2 PR803.1 PU800.3
N17382859: PC801.2 PJP801.2 PJP803.2 PR802.1 PU800.1
N17415515: PJP2.2 PJPDC1.1 PJPDC1.2 PL4.1
N17481633: PC705.1 PC760.1 PC762.1 PC763.1 PC764.1 PC765.1 PC780.1 PC781.1 PJP701.2 PL704.2 PQ704.5
N17511724: CU10.1 RU15.2
N17735595: Q2516.2 Q2516.3 R2635.1
N17847259: T4935.1(TP-1) UV1.AL9
N17877344: T223.1(TP-1) UV1.R1
N17877347: T224.1(TP-1) UV1.R3
N18155621: RC664.1 T76.1(TP-1)
N18202616: T73.1(TP-1) UC1.AY15
N18390627: PQ710.2 PQ711.1
N19609367: QI3.2 RI18.1
N20135010: PC1130.2 PR1136.2 PU1100.15
N20135022: PC1130.1 PR1137.2
N20135024: PC1110.1 PR1114.1 PU1100.25
N20135039: PR1121.2 PU1100.11
N20135040: PC1122.1 PC1124.1 PR1133.1 PR1138.1 PU1100.16
N20135043: PC1131.1 PR1139.1 PU1100.17
N20135074: PC1121.1 PR1125.2
N20135096: PL1103.2 PR1124.2 PR1126.2
N20135098: PL1103.3 PR1128.2
N20135126: PH1101.2 PR1120.2 PR1121.1
N20135134: PC1123.1 PR1129.2 PR1133.2 PR1134.1 PR1135.1 PU1100.18
N20135137: PC1122.2 PR1129.1
N20135139: PC1128.1 PR1135.2
N20135141: PC1123.2 PC1127.2 PR1130.1 PU1100.19
N20135144: PC1127.1 PR1134.2
N20135171: PH1102.1 PR1131.2
N20135184: PL1102.2 PR1104.2 PR1108.2
N20135197: PC1109.1 PR1107.2
N20135219: PL1102.3 PR1110.2
N20135248: PU1100.39 PU1100.40
N20135251: PR1140.1 PU1100.36 PU1100.37 PU1100.38
N20135257: PR1101.2 PU1100.1
N20135258: PR1111.2 PU1100.2
N20135263: PR1105.2 PU1100.34
N20135264: PR1106.2 PU1100.32 PU1100.33
N20141258: PR1016.2 PU1001.1
N20141272: PH1002.2 PR1080.1 PR1087.2
N20141325: PC1007.2 PR1007.1
N20141337: PC1008.1 PR1000.2 PR1003.2 PR1004.1 PR1007.2 PU1001.37
N20141361: PC1007.1 PC1010.2 PR1003.1 PR1006.2 PU1001.38
N20141372: PC1061.2 PR1066.2 PU1001.15
N20141380: PC1015.1 PR1015.2
N20141402: PC1061.1 PR1072.2
N20141406: PC1063.1 PR1026.1 PU1001.25
N20141448: PC1015.2 PR1013.2 PU1001.39
N20141457: PL1002.2 PR1012.2
N20141459: PL1002.3 PR1014.2
N20141467: PL1004.3 PR1068.2
N20141469: PL1004.2 PR1084.2
N20141477: PC1013.1 PR1010.2
N20141501: PR1080.2 PU1001.11
N20141511: PC1059.1 PC1060.1 PR1047.1 PR1075.1 PU1001.16
N20141517: PC1058.1 PR1069.1 PU1001.17
N20141713: PC1006.2 PC1008.2 PR1005.1 PU1001.36
N20141719: PC1054.1 PR1074.2
N20141862: PC1006.1 PR1004.2
N20141864: PC1004.2 PR1000.1
N20141906: PC1068.1 PR1047.2 PR1065.1 PR1073.2 PR1077.1 PU1001.18
N20141912: PC1060.2 PR1073.1
N20141916: PC1037.1 PR1065.2
N20141920: PC1057.2 PC1068.2 PR1078.1 PU1001.19
N20141926: PC1057.1 PR1077.2
N20142021: PH1000.1 PR1009.2
N20142108: PH1003.1 PR1079.2
N20142189: PH1001.2 PR1016.1 PR1086.2
N20277811: PR307.2 PR309.2 PR310.1
N20277821: PR302.2 PU300.1
N20277901: PC309.1 PR305.2
N20355294: RC449.2 UC1.BA25
N21021316: PC305.1 PR303.2
N21022260: PC1009.1 PR1008.2
N21022300: PC1038.1 PR1082.2
N21024525: PC1108.1 PR1103.2
N21024549: PC1118.1 PR1123.2
N21204075: PR1401.2 PU1400.9
N21204078: PC1405.1 PR1405.2 PU1400.15
N21204129: PR1409.1 PR1410.2
N21218602: PQ1.2 PR2.1 PR12.2 PR13.2 PR14.2
N21230662: PC790.1 PQ721.2 PR790.2
N21230690: PQ720.1 PR790.1 PR791.2
N21465372: CU15.1 RU16.2
N21499708: JDIMM1.116 RD23.2
N21505920: JDIMM1.143 RD25.2
N22072509: T50.1(TP-1) UC1.AY16
N22072512: T49.1(TP-1) UC1.BA16
N22072515: T48.1(TP-1) UC1.BA13
N22479416: JDIMM2.116 RD27.2
N22479746: JDIMM2.143 RD28.2
N22479749: JDIMM2.166 RD29.1
N22643329: T94.1(TP-1) UL1.27
N22643331: T95.1(TP-1) UL1.25
N22643429: RL2.2 UL1.31
N22643935: RL1.2 UL1.26
N22657839: CA17.1 RA15.2 RA16.2 UA1.9
N22661096: CA20.2 RA13.1 UA1.27
N22661869: CA21.2 UA1.39
N22662054: CA22.2 UA1.7
N22663765: CA23.1 UA1.28
N22664360: CA24.2 UA1.37
N22664751: CA24.1 UA1.35
N22664968: CA25.2 UA1.34
N22666744: CA41.1 UA1.16
N22673637: QA1.3 RA5.1 RA6.1
N22675171: CA31.1 RA44.2
N22737223: RL7.2 UL3.3
N23370623: RV100.1 UV4.6
N23370625: RV101.1 UV4.7
N23435447: DC3803.3 RC31.1
N23465138: CV186.1 RV164.1 RV165.1 UV3.5
N23674571: PC213.1 PC214.2 PR207.2 PR211.1 PR212.1
N23700319: PD4.2 PL2.1 PQ6.1 PR6.2
N23821471: C5219.1 U2302.12
N23821473: C349.2 U2302.10
N23827049: JKB1.1 R36.2 R37.1
N24106209: C22.1 Q12.3 R35.2
N24106231: Q85.1 R38.1
N24135897: Q135.3 Q2513.3
N24135899: Q2514.3 Q2515.3
N24142380: DF1.1 JFAN1.3 RF3.1
N24410627: RC29.2 T77.1(TP-1)
N24443071: T51.1(TP-1) UC1.BA14
N24718506: RA14.2 UA1.11
N24718549: CA42.2 UA1.12
N24924773: PC128.1 PD102.2 PR114.2 PR120.2 PR121.2 PR122.1
N25806005: R439.2 U74.3
N25892877: CA8.1 RA56.2
N25893892: RC666.1 UC1.BA27
N25893987: RC665.2 UC1.AH1
N25997876: PC744.2 PQ709.3 PQ718.1 PQ718.2 PQ718.3 PQ740.1 PQ740.2 PQ740.3 PR737.1 PR763.1
N25997900: PC742.1 PC744.1 PQ709.1 PQ718.4 PR762.1 PR778.2
N26351881: JKB1.30 RE60.2
N26702682: RX9.2 U1.3
N27121430: RC458.2 UC1.AA40
N27286345: PD704.1 PR743.2
N27352133: JHDT1.13 RH23.2
N27352135: JHDT1.15 RH24.2
N27352149: JHDT1.11 RH22.2
N27367990: C636.1 RC617.2
N27535100: RE14.2 UE1.111
N27535635: CE24.1 RE16.2
N27539530: CC16.1 RC25.2 RC26.2 RC28.1 UC4.1 UC4.2
N27700813: QI1.1 RPI1.5 RPI1.6 RPI1.7 RPI1.8 RPI2.5 RPI2.6 RPI2.7 RPI2.8
N27705118: Q83.1 R1671.2
N27707965: C344.2 U15.10
N27708054: C343.2 U15.12
N27920326: PR1081.2 PU1001.13
N28483985: PQ1.3 PR5.2
N28484391: PC16.1 PQ2.3 PR28.2
N28484395: PC16.2 PQ2.2 PR29.1
N28484412: PQ2.5 PR31.1 PR33.2
N28484439: PC14.2 PQ3.2 PR32.1
N28484451: PQ1.5 PQ1.6 PR7.1 PR10.2
N28714500: PR769.2 PU703.3
N28714504: PR770.2 PU703.4
N28714524: PC750.1 PU703.27
N28714534: PC752.2 PR754.1
N28714554: PR727.1 PU703.8
N28714559: PR774.2 PU703.6
N28714562: PR775.2 PU703.7
N28714564: PC721.1 PR771.2
N28714572: PC757.2 PR743.1 PU703.18
N28714582: PR755.2 PU703.12
N28714583: PC708.1 PR776.1 PU703.14
N28714585: PC708.2 PR742.1 PU703.15
N28714598: PC747.1 PR740.2 PU703.31
N28714599: PC747.2 PR772.2 PU703.32
N28714601: PC750.2 PU703.28
N28714604: PR773.1 PU703.25
N28714606: PQ704.4 PR761.2
N28714608: PR745.1 PU703.26
N28714612: PR771.1 PU703.24
N28714614: PR757.2 PU703.17
N28714617: PQ718.5 PR703.1
N28714625: PR757.1 PR779.2
N28714693: PC779.1 PL700.2 PQ717.1 PQ717.2 PQ717.3 PR765.1
N28714721: PR742.2 PR765.2
N28714724: PR765.3 PR776.2
N28714743: PQ709.2 PR737.2 PR738.1
N28714752: PR703.2 PR772.1
N28714753: PR703.3 PR740.1
N28714782: PC767.1 PR766.2
N28714793: PC779.2 PQ717.4 PR773.2
N28895147: PC805.1 PQ801.2 PR801.2
N29189918: PR764.2 PU703.13
N32434049: RV121.1 UV15.J13
N32434050: RV117.1 UV15.J1
N32434053: RV119.1 UV15.J10
N32437559: RV132.1 UV13.J13
N32437560: RV131.1 UV13.J1
N32437563: RV133.1 UV13.J10
N32646580: PBATT1.5 PR15.1
N33124395: PC204.2 PR210.1 PU200.12
N33124472: PC207.2 PR203.1
N33726059: PD102.1 PR116.2
N33745668: PR209.2 PU200.10
N36085760: PD6.1 PR11.2
N37640332: RV2.2 UV1.N10
N37640410: RV3.1 UV1.AA22
N37828209: RV1.1 UV1.Y22
N38038746: CV96.1 RV36.2 RV37.2
N38038992: CV98.2 UV1.K8
N38038994: CV99.2 UV1.L7
N38038995: CV98.1 RV40.2
N38038996: CV99.1 RV41.2
N38349725: RV39.2 UV1.K25
N39282118: PC601.1 PJP601.2 PU600.8 PU600.9 PU600.10
N39282176: PC604.1 PR606.2
N39282188: PR603.1 PR604.2
N39352229: PC102.1 PR100.2
N39352417: PC119.1 PU102.16 PU102.17
N39352440: PC114.1 PR111.2
N39352447: PC113.2 PR108.1
N39352755: PC127.2 PR117.1
N43437408: RC450.2 UC1.BA24
N55201771: JHDMI1.13 RI19.2
N279348080: PQ740.4 PR778.1

Pads without a net: FD1 1; FD2 1; FD3 1; FD4 1; JDIMM1 87 88 91 92 95 96 97 100 101 104 105 162 165; JDIMM2 87 88 91 92 95 96 97 100 101 104 105 162 165; JEDP1 5; JHDD1 9; JHDMI1 14; JIOB1 11; JKB1 2 3; JKBBL1 3; JLAN1 4 5 7 8; JPWR1 4; JWLAN1 6 8 9 11 12 13 14 15 16 17 19 20 21 22 23 24 26 28 34 36 38 40 42 50 51 52 53 54 56 57 59 62 63 65; PD3 3; PD4 3; PJPDC1 4; PU100 10 15; PU102 10; PU400 1 5; PU600 1 4 7; PU900 1 5; PU1001 27 28 29 30 35; PU1100 35; PU1400 10 12; RP20 4 5; RPC25 4 5; RPC36 4 5; RPC45 1 2 7 8; RPC64 1 2 7 8; RPH2 1 8; U2301 5 6 7 8 9 10; U2407 8; UA1 4 14 15 23 24 48; UC1 A3 A11 A12 A19 A20 A21 A22 AA4 AE34 AG8 AH2 AJ1 AL8 AM1 AM2 AM15 AM17 AM19 AN8 AP13 AP15 AP17 AP19 AP21 AP23 AP25 AR13 AR15 AR17 AR21 AR25 AR29 AU4 AU13 AU15 AU17 AU23 AU27 AV7 AV9 AV11 AV13 AV15 AV17 AV21 AV23 AV25 AY3 AY7 AY18 B1 B2 B3 B11 B12 B19 B20 B21 B22 D11 D13 D19 E4 E31 G19 H11 H13 H19 J1 J2 K1 K2 L11 N4 N5 R4 R5 T1 T2 V1 V2; UC61 1; UC62 1; UC63 1; UC64 1; UC65 1; UE1 19 64 70 85 86 102 107 119 120 123 126 128; UL1 3 6 7 9 10 11 22 24; UV1 AA5 AA6 AA29 AA31 AB23 AB25 AB26 AB27 AB30 AC1 AC3 AC5 AC6 AC16 AC23 AC25 AD2 AD4 AD10 AD11 AD13 AD16 AD22 AD23 AD24 AE1 AE3 AE5 AE6 AE10 AE11 AE13 AE16 AE19 AE22 AE23 AE24 AE25 AE26 AF2 AF4 AF6 AF7 AF8 AF9 AF10 AF11 AF13 AF16 AF17 AF22 AF24 AF25 AG1 AG3 AG5 AG6 AG7 AG8 AG9 AG10 AG11 AG13 AG15 AG16 AG17 AG18 AG19 AG20 AG21 AG22 AG24 AG25 AG26 AH1 AH3 AH5 AH6 AH8 AH12 AH16 AH18 AH20 AH22 AH24 AH26 AJ7 AJ9 AJ13 AJ15 AJ17 AJ19 AJ21 AJ23 AJ25 AK1 AK3 AK5 AK6 AK8 AK10 AK14 AK16 AK18 AK20 AK22 AK24 AK26 AL7 AL13 AL15 AL17 AL19 AL21 AL23 AL25 AM3 AM5 AM6 AM8 AM10 AM12 AM26 J8 J22 J25 K13 K30 L16 L17 L29 L31 M4 M27 M28 M30 N3 N5 N6 N8 N26 N29 N31 P2 P4 P7 P10 P23 P24 P26 P27 P28 P30 R6 R29 R31 T2 T4 T7 T23 T24 T26 T27 T28 T30 U5 U6 U23 U24 U26 U29 U31 V2 V4 V6 V27 V28 V30 W3 W5 W6 W7 W8 W23 W24 W29 W31 Y2 Y4 Y6 Y23 Y24 Y26 Y27 Y28 Y30; UV13 A5 U5; UV15 A5 U5; YC2 2 4

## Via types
v1: diameter 0.305, hole 0.152, TOP to BOTTOM, 727 vias
v2: diameter 0.457, hole 0.203, TOP to BOTTOM, 4877 vias
v3: diameter 0.508, hole 0.254, TOP to BOTTOM, 56 vias
v4: diameter 0.406, hole 0.203, TOP to BOTTOM, 120 vias

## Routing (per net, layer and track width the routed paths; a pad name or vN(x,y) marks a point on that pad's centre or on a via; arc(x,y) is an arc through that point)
0.95VS_GATE: length 6.3
  BOTTOM w0.508: Q84.1 133.88,22.59 v1(135.32,21.15) R1674.2 136.43,21.16 137.42,21.16 C16.1 138.84,21.15 U4.4
0.95VS_PWR_EN#: length 70.8
  TOP w0.102: v2(144.92,15.09) 147.51,15.09 149.39,13.21 154.88,13.21 155.15,13.48 155.15,13.8 156.1,14.75 158.37,14.75 159.43,13.69 161.57,13.69 165.21,17.32 165.34,17.46 168.39,17.46 169.72,18.78 169.72,22.71 170.49,23.49 170.49,24.9 171.09,25.5 171.09,26.82 169.94,27.96 169.94,32.23 170.29,32.58 v1(170.29,33.04) 170.29,33.36 169.9,33.74 169.31,33.74 168.99,34.05 168.99,36.59 v2(169.12,36.72)
  BOTTOM w0.102: v2(169.12,36.72) 168.42,37.42 UE1.99 ; RE505.1 144.92,14.93 v2(144.92,15.09) 143.94,15.09 Q83.2 143.33,14.95 142.07,16.21 142.07,16.34 141.05,17.35 141.05,20.78 140.27,21.57 140.27,21.69 139.85,22.12 138.83,22.12 138.32,22.63 136.16,22.63 135.08,23.7 134.39,23.7 133.15,24.94 Q84.2
0.95VSDGPU_OUT:
  vias: v1(99.99,97.24)
0.775VALW_GATE: length 12.8
  TOP w0.102: Q2514.2 117.77,5.33 v1(117.24,5.86)
  TOP w0.508: v2(120.17,4.53) 119.37,5.33 Q2514.2 118.94,5.81 118.26,6.5 118.26,8.91 117.75,9.42 116.99,9.42 116.53,9.87 Q2515.2
  BOTTOM w0.508: U2.7 122.32,5.23 121.8,4.7 R54.1 121,4.65 120.29,4.65 v2(120.17,4.53)
1.5VS_VIN:
  vias: v1(97.37,16.15)
1.8VGS_0.95VSDGPU_ON: length 8.1
  BOTTOM w0.102: C983.2 104.18,95.79 103.58,95.18 U15.3 ; C983.2 104.55,94.67 104.27,94.38 U15.5 ; C983.2 R438.2 104.55,96.88 103.03,98.4 v1(102.9,98.4)
1.8VS_GATE: length 4.5
  BOTTOM w0.203: 158.39,21.29 158.22,21.46 U2302.5
  BOTTOM w0.254: 158.39,21.29 158.71,21.29 159.02,20.97 159.02,20.8 159.28,20.55 C987.2 R437.2
2.5V_VIN: length 1.5
  BOTTOM w0.102: 16,100.07 v1(16,101.54)
3V_FB: length 4.8
  BOTTOM w0.254: PR110.1 177.97,43.91 PR109.2 176.96,42.99 PC113.1 175.41,44.54 PU100.13
3V_SN: length 1.8
  TOP w0.102: v1(172.36,46.75) 172.04,47.07 PR106.2
3V_VIN:
  vias: v1(176.04,49.42) v2(175.72,50.5) v2(175.72,49.87)
3VS_GATE: length 3.7
  BOTTOM w0.203: U2302.3 158.84,22.26
  BOTTOM w0.254: 158.84,22.26 159.6,21.5 C2322.2 159.84,21.11 R2318.2
3VS_LS:
  vias: v1(155.85,25.93)
5V_FB: length 4.6
  BOTTOM w0.102: PR118.1 200.09,33.88 v1(200.17,33.8)
  BOTTOM w0.254: PU102.13 196.97,34.48 PR115.2 197.56,33.88 PC127.1 PR118.1
5V_SN: length 1.6
  TOP w0.102: v1(186.71,41.1) 187.15,40.66 PC125.1
5V_VIN:
  vias: v1(202.27,39.2) v2(200.17,38.94) v2(200.81,38.94) v2(201.71,38.55) v2(202.79,38.55)
5VS: length 0.9
  BOTTOM w0.102: 165.58,7.69 v1(165.58,8.55)
5VS_GATE: length 9.2
  TOP w0.102: v2(162.32,17.92) v1(162.32,16.85) 162.32,15.14 v2(161.37,14.19)
  BOTTOM w0.102: R2313.2 161.61,19.02 162.32,18.31 v2(162.32,17.92) ; U2301.3 162.43,12.67 C2309.1 162.39,12.91 161.37,13.93 v2(161.37,14.19)
+0.6V_DDR_VTT: length 89.5
  TOP w0.102: v2(61.62,17.04) v4(61.62,16.08)
  TOP w1.524: 82.19,88.16 82.76,88.73 87.27,88.73 94.32,95.78 94.32,99.01
  BOTTOM w0.305: JDIMM1.258 60.95,20.87 60.35,20.27 v2(60.35,19.64)
  BOTTOM w1.524: 80.67,84.16 79.91,84.91 76.73,84.91 74.44,82.62 74.44,62.19 76.73,59.9 76.73,26.5 74.63,24.4 74.57,24.4
  vias: v2(47.52,20.72) v2(47.52,20.13) v2(48.04,20.41) v2(60.35,17.04) v2(60.98,17.04) v2(80.79,86.82) v2(81.43,86.82) v2(82.06,86.82) v2(93.56,101.49) v2(93.56,100.91) v2(93.94,101.94)
+0.6VSP:
  vias: v1(94.19,105.49)
+0.95VALW: length 91.3
  TOP w0.508: RC645.2 134.84,58.19 v2(134.56,58.47)
  IN1 w0.254: v2(119.25,48.9) 119.52,49.17 120.72,49.17 120.97,49.42 120.97,50.12 120.71,50.39 120.71,50.91 120.48,51.14 120.48,51.83 121.1,52.46 124.21,52.46 125.88,54.12 131.27,54.12 132.04,54.88 132.04,56.98 133.53,58.47 v2(134.56,58.47)
  BOTTOM w0.4: v2(120.12,48.05) UC1.AL11 119.65,48.51 v2(119.25,48.9) ; UC1.AJ11 119.34,49.19 119.34,48.99 v2(119.25,48.9) ; v2(119.25,48.9) 119.22,48.9 119.2,48.88 119.03,48.88 UC1.AL13
  BOTTOM w2.032: 82.25,18.12 82.25,20.8 83.26,21.8 83.26,22.94 82.95,23.24 82.95,24.66 78.63,28.97 78.63,60.8 76.66,62.77 76.66,79.39 77.24,79.96
  vias: v2(77.26,81.58) v2(77.85,81.58) v2(78.46,81.58) v2(79.09,81.58) v2(80.92,16.59) v2(81.05,17.23) v2(81.62,16.59) v2(82.32,16.59) v2(102.95,96.73) v2(102.95,97.49) v2(103.46,97) v2(103.49,96.41) v2(119.84,30.75) v2(119.84,29.66) v2(120.05,30.2) v2(120.16,29.16) v2(136.04,24.02) v2(136.61,24.21) v2(136.57,23.6) v2(137.18,24.08) v4(120.92,29.93)
+0.95VALWP: length 22.5
  TOP w0.102: v2(142.26,31.64) v1(142.26,32.4)
  TOP w0.254: v2(161.02,29.6) 161.51,29.11 PR309.1
  IN2 w0.254: v2(142.26,31.64) 145.31,28.59 150.26,28.59 150.87,27.99 156.51,27.99 157.41,28.89 159.18,28.89 159.39,29.1 160.36,29.1 160.86,29.6 v2(161.02,29.6)
+0.95VS: length 106.1
  TOP w0.254: v2(118.42,45.38) 118.56,45.52 RC96.2
  TOP w3.048: 134.2,16.27 134.16,16.24 125.09,16.24 124.8,16.53 120.88,16.53 118.19,19.22 113.69,19.22 110.43,15.96 101.05,15.96 86.7,30.31
  IN1 w0.254: v2(118.42,45.38) 117.28,45.38 116.5,46.16 114.05,46.16 112.81,44.91 111.59,44.91 111.2,45.31 110.47,45.31 110.29,45.13 110.29,41.73 108.9,40.33 108.9,38.43 108.85,38.37 108.85,33.72 108.61,33.48 108.61,31.7 108.92,31.39 v2(109.11,31.39)
  BOTTOM w0.508: v2(109.11,31.39) 107.46,31.39 107.14,31.7 107.14,33.1 104.41,35.83 99.27,35.83 97.11,33.67 97.11,27.96 95.94,26.78 v2(93.99,26.78)
  vias: v2(135.96,19.55) v2(135.96,18.91) v2(136.59,19.55) v2(136.59,18.91) v2(137.23,19.55) v2(137.23,18.91) v4(90.44,29.61)
+0.95VS_APU_GFX: length 33.1
  TOP w0.508: RC542.1 135.26,54.88 135.27,54.87 v2(135.48,54.87)
  IN1 w0.254: v2(135.48,54.87) 134.89,55.45 134.89,58.06 135.08,58.25 135.08,58.69 134.77,59.01 133.5,59.01 131.66,57.17 131.66,55.33 130.96,54.63 120.29,54.63 119.15,53.49 118.83,53.49 117.69,52.34 116.8,52.34 116.15,51.7 114.91,51.7 114.64,51.43 114.64,50.82 114.26,50.44 113.69,50.44 113.24,49.99 113.24,48.92 v2(113.15,48.83)
  vias: v1(98.38,39.52) v2(110.23,48.13) v2(111.14,48.82) v2(111.1,48.11) v2(112.17,48.78)
+0.95VSDGPU: length 38
  TOP w0.508: v2(114.26,100.54) 114,100.28 114,97.81 116.23,95.59 116.23,93.87 115.27,92.92 115.27,87.84 116.8,86.31 117.5,86.31 117.75,86.06 119.15,86.06 119.97,86.89 LV8.1
  IN1 w0.508: v2(98.25,104.92) 99.59,104.92 102.26,102.25 111.08,102.25 112.8,100.54 v2(114.26,100.54)
  vias: v2(95.84,98.76) v2(95.84,98.13) v2(96.48,99.65) v2(96.48,99.01) v2(96.48,98.38) v2(96.48,97.8) v4(95.71,112.48)
+0.775VALW: length 38.5
  TOP w0.102: v2(115.91,12.34) v4(114.64,12.34)
  TOP w0.508: Q2515.1 116.06,12.49 v2(115.91,12.34)
  BOTTOM w0.508: v2(115.91,12.34) 114,10.43 114,10.11 113.69,9.8 111.97,9.8 111.21,9.04 111.21,8.02 117.69,1.54 133.09,1.54 134.34,2.8 134.34,3.83 133.84,4.34 133.62,4.34
+1.2V_DDR: length 68.3
  BOTTOM w0.254: JDIMM2.136 v2(43.54,53.87)
  BOTTOM w0.3: UC1.AR35 107.22,45.96 107.26,45.96 107.3,46 107.63,46 107.65,46.03 107.72,46.03 107.79,45.96 107.84,45.96 107.86,45.98 107.91,45.98 107.91,45.98 v2(107.92,45.98) ; UC1.L37 106.26,59.36 v2(106.46,59.56) ; UC1.J35 107.06,60.58 v2(107.12,60.64)
  BOTTOM w0.305: JDIMM1.142 64.7,51.87 v2(64.92,52.09) ; v2(106.46,50.76) 106.46,50.41 UC1.AG37 ; JDIMM2.154 v2(43.58,47.38) ; v2(51.74,46.53) 52.14,46.12 JDIMM2.159 ; JDIMM2.112 v2(43.54,59.87) ; JDIMM1.111 71.52,59.62 v2(71.68,59.47) 71.68,58.41 71.4,58.13 JDIMM1.117 ; v2(51.79,49.13) 51.8,49.12 JDIMM2.147 ; v2(71.76,55.83) 71.76,56.22 71.35,56.62 JDIMM1.123 ; JDIMM1.147 71.36,48.62 72.03,49.29 v2(72.03,49.42) ; v2(51.79,45.27) 51.93,45.12 JDIMM2.163 ; JDIMM1.148 63.22,48.38 63.51,48.09 v2(63.52,48.09) 63.52,47.39 63.01,46.87 JDIMM1.154 ; JDIMM1.129 71.28,55.13 71.52,54.88 v2(71.52,54.44) 71.52,53.87 71.28,53.62 JDIMM1.135 ; v2(108.75,59.9) 108.66,59.81 UC1.L32 ; JDIMM2.124 v2(43.54,56.87) ; JDIMM2.135 52.01,54.12 51.77,53.88 v2(51.77,52.98) 52.12,52.62 JDIMM2.141 ; UC1.AJ32 UC1.AG32 108.66,50.56 v2(108.83,50.72) 108.83,51.14 UC1.AE32 108.62,51.31 v2(108.09,51.84) 108.07,51.86 v2(107.26,51.86) 107.06,51.66 UC1.AE35 ; JDIMM2.123 52.04,57.13 v2(51.79,57.38) ; JDIMM2.142 v2(43.54,52.38) ; JDIMM1.160 62.87,45.38 62.87,45.37 63.3,45.37 v2(63.34,45.42) ; JDIMM2.153 51.81,47.62 v2(51.75,47.56) ; JDIMM2.130 v2(43.54,55.38) ; v2(71.39,51.64) 71.39,51.76 71.03,52.13 JDIMM1.141 ; JDIMM2.160 v2(43.56,45.87) ; JDIMM2.118 v2(43.54,58.38) ; JDIMM2.117 52.1,58.62 51.79,58.93 v2(51.79,59.14) 51.79,60 51.92,60.13 JDIMM2.111 ; JDIMM2.148 v2(43.56,48.87) ; JDIMM2.129 v2(51.79,55.62) ; UC1.AC37 106.26,52.76 v2(106.46,52.96) 107.01,53.51 UC1.AA35
  BOTTOM w0.4: UC1.AL32 108.19,47.54 108.14,47.54 v2(108.1,47.5) ; v2(107.26,54.06) 107.06,53.86 UC1.AA35 ; UC1.AJ32 108.11,48.56 v2(108,48.56) ; UC1.R37 106.26,57.16 v2(106.46,57.36) ; UC1.U32 108.66,56.07 v2(108.88,56.29) ; UC1.U35 107.06,56.06 v2(107.26,56.26) ; v2(106.4,48.56) 106.26,48.42 UC1.AL37 ; v2(107.26,58.46) 107.06,58.26 UC1.N35 ; v2(107.26,49.66) 107.06,49.46 UC1.AJ35 ; UC1.W32 108.66,54.9 v2(108.86,55.11) ; UC1.W37 106.26,54.96 v2(106.46,55.16) ; UC1.AC32 v2(108.09,51.84)
  vias: v2(46.88,59.9) v2(47.39,58.44) v2(47.71,54.82) v2(47.84,56.85) v2(47.77,48.85) v2(47.9,47.33) v2(48.85,51.96) v2(49.42,55.64) v2(49.68,57.36) v2(49.74,48.98) v2(50.06,46.82) v2(50.95,52.98) v2(54.27,55.69) v2(54.86,53.97) v2(54.99,59.68) v2(55.19,46.63) v2(55.84,62.12) v2(55.9,53.23) v2(57.4,45.31) v2(58.52,47.77) v2(58.72,61.08) v2(59.58,57.87) v2(63.21,55.86) v2(63.2,53.8) v2(63.31,57.14) v2(63.58,58.06) v2(63.9,53.8) v2(72.73,44.85) v2(96.4,52.97) v2(98.92,56.6) v4(53.61,92.03) v4(72.88,57.63) v4(91.4,59.39)
+1.2VP: length 59.5
  TOP w0.254: PR211.2 84.91,101.22 v2(85.43,101.75)
  IN2 w0.254: v2(67.01,105.05) 67.08,105.11 67.99,105.11 68.33,104.77 68.33,100.81 69.74,99.4 83.27,99.4 85.43,101.55 v2(85.43,101.75)
  IN2 w0.762: v2(87.99,106.08) 87.99,104.46 88.92,103.52 v2(88.92,101.55) 87.4,100.03 84.86,100.03 83.52,98.7 69.43,98.7 67.08,101.05 67.08,103.02
  BOTTOM w0.203: v2(87.99,106.08) 87.99,105.71 87.57,105.3 PU200.19 ; v2(88.92,101.55) 89.22,101.55 89.43,101.76 89.43,102.14 89.22,102.35 PU200.5
  vias: v1(71.33,104.98) v2(65.69,105.05) v2(65.69,104.35) v2(65.69,103.71) v2(66.33,105.05) v2(66.33,104.35) v2(66.33,103.71) v2(67.01,104.41) v2(67.01,103.78) v2(67.81,104.6) v2(67.81,103.97) v2(67.81,103.33)
+1.5VS: length 276.1
  TOP w0.508: v2(25.52,34.17) 25.06,33.72 RA16.1 ; v2(186.6,17.91) 186.6,21.84 186.2,22.24 186.2,25.74 184.83,27.12 184.83,31.11 185.57,31.85 185.57,33.36 185.25,33.67 185.25,37.94 184.7,38.48 184.7,40.27 185.02,40.58 185.02,41.84 184.41,42.45 184.41,48.29 185.44,49.32 185.44,50.56 186.39,51.52 186.39,53.69 185.44,54.64 185.44,55.82 184.94,56.33 184.28,56.33 183.08,57.52 182.83,57.52 180.69,59.66 173.99,59.66 173.83,59.5 172.85,59.5 v2(172.82,59.54) ; v2(131.15,24.66) 131.34,24.66 v4(132,23.99) 134.83,21.16 138.45,21.16 139.85,19.77 139.85,19.2 141.5,17.54 151.02,17.54 151.53,17.04 v2(151.53,15.39) ; v2(111.53,11.45) 109.95,11.45 v2(109.69,11.7)
  IN1 w0.508: v2(108.99,11.7) 107.72,11.7 107.3,12.12 106.03,12.12 106.02,12.12 105.39,12.12 101.03,12.12 100.4,12.12 100.4,12.12 100.14,12.12 99.79,12.12 99.32,12.59 91.84,12.59 90.89,13.54 90.26,13.54 88.21,13.54 84.34,13.54 83.97,13.54 83.37,12.93 83.36,12.93 83.21,12.78 79.97,12.78 78.55,11.36 78.05,11.36 77.52,11.89 74.83,11.89 73.83,11.89 70.43,11.89 69.13,10.59 46.68,10.59 39.58,17.69 39.58,26.76 35.14,31.2 33.23,31.2 30.96,33.46 26.02,33.46 25.52,33.97 v2(25.52,34.17) ; v2(124.67,22.79) 124.35,23.11 124.35,24.53 124.86,25.04 129.62,25.04 130,24.66 v2(131.15,24.66)
  IN2 w0.508: v2(156.79,10.89) 156.87,10.89 158.41,9.34 166.08,9.34 167.07,10.33 168.38,10.33 172.17,14.12 175.29,14.12 177.34,16.17 178.92,16.17 179.58,15.51 186.1,15.51 186.6,16.02 v2(186.6,17.91)
  BOTTOM w0.508: v2(156.79,10.89) 155.29,10.89 154.39,9.99 151.03,9.99 150.26,10.76 149.63,11.39 149.63,12.72 151.53,14.62 v2(151.53,15.39) ; v2(124.67,22.79) 124.51,22.95 124.51,24.57 120.75,28.33 117.55,28.33 116.73,27.51 116.73,25.67 114.7,23.64 112.86,23.64 108.99,19.77 108.99,18.24 111.84,15.39 111.84,11.77 v2(111.53,11.45) ; v2(172.82,59.54) 172.28,59.54 PR1028.1
+1.5VSP:
  vias: v1(109.01,16.12)
+1.8V_ALW: length 195.7
  TOP w0.254: v2(127.15,48.28) 127.91,48.28 129.81,50.18 131.15,50.18 131.85,49.48 v4(132.54,49.48) RC346.1
  TOP w0.508: v2(177.82,39.78) 177.82,39.77 177.12,39.77 176.87,39.52 RE69.1 ; 118.64,31.77 118.64,29.42 116.73,27.51 116.73,24.31 117.85,23.2 120.03,23.2 121,22.22 122.3,22.22 122.92,21.6 123.86,21.6 124.16,21.29 129.05,21.29 129.18,21.16
  TOP w1.524: 97.3,88.6 100.35,91.65 101.68,91.65 102.13,92.09 ; 37.04,93.87 36.66,93.49 36.66,87.14 36.6,87.08 ; 90.51,17.04 90.57,17.1 90.57,20.66 83.65,27.58
  IN1 w0.254: v2(127.15,48.28) 126.88,48.54 125.13,48.54 124.61,48.02 120.99,48.02 120.42,48.6 119.59,48.6 119.44,48.45 118.6,48.45 v2(118.19,48.04)
  IN1 w0.508: v2(162.1,20.81) 162.07,20.78 161.15,20.78 160.69,20.33 158.91,20.33
  IN1 w1.524: 129.75,18.24 130.26,17.73 140.36,17.73 142.26,19.64 148.1,19.64 148.8,20.34 150.39,20.34 150.9,19.83 150.99,19.83 150.99,19.83 152.2,19.83 156.29,19.83
  IN2 w0.508: v2(159.99,28.48) 160.94,28.48 162.14,29.68 162.62,29.68 163.36,30.43 163.36,31.39 163.96,31.98 165.46,31.98 166.26,32.78 166.26,36.85 167.37,37.95 167.4,37.95 167.76,38.31 167.76,38.35 168.3,38.88 175.15,38.88 175.85,39.58 177.63,39.58 v2(177.82,39.78)
  BOTTOM w0.508: v2(162.1,20.81) 162.71,21.42 162.71,23.28 161.85,24.13 161.85,24.98 161.23,25.61 160.46,25.61 159.49,26.59 159.49,27.97 v2(159.99,28.48)
  BOTTOM w1.524: 90.57,81.68 89.3,81.68 86.76,79.14 83.59,79.14 83.08,79.65 81.81,79.65 79.41,77.25 79.41,66.49 82.19,63.71 82.19,51.96 85.24,48.91 85.24,38.69 82.82,36.28 82.82,33.04
  vias: v2(36.28,85.87) v2(36.66,85.3) v2(36.98,85.87) v2(83.14,31.39) v2(83.66,31.13) v2(89.81,82.95) v2(90.25,15.39) v2(90.51,82.95) v2(90.88,15.39) v2(91.21,82.95) v2(91.46,15.39) v2(94.64,88.22) v2(95.33,88.22) v2(96.03,88.22) v2(102.73,93.07) v2(103.32,93.07) v2(103.9,93.07) v2(123.65,14.24) v2(130.58,21.04) v2(130.83,21.67) v2(131.21,21.04) v2(157.41,19.75) v2(158,19.75) v2(158.58,19.75)
+1.8V_AVDD:
  vias: v1(33.87,25.93)
+1.8VALWP: length 8.3
  TOP w0.254: v2(35.53,104.36) v1(35.53,103.59) 35.53,99.83 35.71,99.65 36.28,99.65 36.79,99.14 PC605.1
  BOTTOM w0.254: PC603.1 35.58,105.22 PR603.2 v2(35.53,104.36)
  vias: v2(37.68,98.32) v2(37.99,98.89) v2(38.31,98.32) v2(38.69,98.89) v2(38.95,98.32)
+1.8VGS: length 206.5
  TOP w0.508: LV7.1 120.21,88.78 120.99,89.55 120.99,91.2 123.21,93.43 123.21,94.51 122.7,95.01 119.91,95.01 117.24,97.68 115.95,97.68 v2(115.71,97.44) ; LV6.1 115.15,101.83 v2(115.15,101.28) ; RV8.1 104.84,112.56 v2(104.97,112.44) ; PR1113.1 v2(47.52,125.82)
  IN1 w0.508: v2(97.05,127.15) 96.93,127.03 95.41,127.03 92.23,123.85 92.23,109.36 92.92,108.67 92.92,103.61 91.51,102.2 91.21,101.9 91.21,100.79 90.07,99.65 84.48,99.65 83.08,98.25 65.93,98.25 64.45,99.74 64.45,106.42 64.92,106.89 64.92,108.22 61.23,111.91 61.23,113.74 56.53,118.45 50.9,118.45 49.36,119.99 49.36,123.97 v2(47.52,125.82) ; v2(115.15,101.28) 113.57,101.28 111.97,102.89 102.57,102.89 98.64,106.83 98.64,108.16 98.25,108.54 98.25,110.18 v2(98.27,110.19) 99.41,109.05 104.41,109.05 104.8,109.43 104.8,112.22 104.97,112.39 v2(104.97,112.44) ; v2(115.71,97.44) 112.52,97.44 110.32,99.65 108.66,99.65 104.41,95.4 101.24,95.4 100.86,95.01 100.86,94.43 v2(100.13,93.71) 98.01,91.59 87.8,91.59 86.8,92.59 85.5,92.59 85.1,92.98 80.03,92.98 v2(79.65,92.6)
  IN2 w0.508: v2(115.15,101.28) 115.71,100.72 v2(115.71,97.44)
  BOTTOM w0.254: v2(102.51,121.87) 102.1,122.28 UV1.AM30
  BOTTOM w0.33: UV1.AM30 100.5,122.3 98.78,124.02 CV46.1
  BOTTOM w0.508: RV81.2 RV82.2 111.78,97.17 112.54,96.41 113.43,96.41 114.16,95.69 114.59,95.69 114.99,96.09 RV152.2 v2(115.71,97.44) ; CV179.1 98.2,110.26 v2(98.27,110.19)
  vias: v4(97.94,113.3)
+1.8VS: length 363.6
  TOP w0.254: RPH2.7 81.94,80.29 81.94,80.28
  TOP w0.381: 111.34,83.33 112.34,84.33 UC64.5 112.34,85.11 111.96,85.49 v2(110.13,85.49) ; UC65.5 118.27,82.43 118.59,82.11 v2(118.59,82.09)
  TOP w0.508: JHDT1.1 89.75,68.98 84.42,68.98 RPH1.8 ; QA1.1 v2(41.65,8.88) ; 126.89,83.38 127.34,83.83 127.34,86.95 v2(128.87,88.49) 130.25,88.49 137.64,81.09 140.3,81.09 140.99,80.41 147.53,80.41 152.1,75.84 165.34,75.84 171.15,70.02 171.15,68.98 174.05,66.08 174.05,61.27 173.25,60.47 v2(172.82,60.47) 172.44,60.47 PR1023.1 ; 126.89,83.38 129.57,83.38 133.8,79.15 RC9.1 RC10.1 ; 126.89,83.38 RC81.1 RC4.1 123.21,81.81 122.7,81.3 119.38,81.3 v2(118.59,82.09) ; v2(121.27,22.85) 121.51,22.85 121.75,23.09 RC18.1 ; RA15.1 24.18,33.74 24.79,34.36 v2(24.81,34.36) ; RC155.2 114.76,64.33 114.76,65.49 v2(113.88,66.38) ; v2(107.84,72.09) 110.83,75.08 110.83,77.49 v2(109.81,78.5) 109.81,79.08 111.34,80.6 111.34,83.33 ; v2(109.81,68.03) 109.3,67.52 RC117.2 ; 82.63,72.47 82.63,73.81 82.7,73.87 82.7,77.17 81.81,78.06 81.81,80.16 81.94,80.28 81.81,80.28 81.3,80.78 81.3,81.49 81.81,82 85.11,82 86.06,82.95 88.92,82.95 89.68,82.19 JHDT1.19 92.22,82.19 92.54,81.87 93.68,81.87 94.51,81.04 v2(94.74,81.04)
  IN1 w0.102: v2(109.81,68.03) 109.81,68.09
  IN1 w0.508: v2(41.65,8.88) 41.65,10.52 40.66,11.51 40.66,14.69 38.44,16.92 38.44,26.28 35.89,28.83 31.21,28.83 30.42,29.62 30.42,30.04 30.84,30.46 31.03,30.46 31.03,30.46 31.54,30.46 31.54,30.46 31.57,30.46 31.95,30.84 31.95,31.58 30.7,32.83 25.76,32.83 24.81,33.78 v2(24.81,34.36) ; v2(109.81,68.03) 111.46,66.38 v2(113.88,66.38) ; v2(107.84,72.09) 109.81,70.12 109.81,68.09 ; v2(118.59,82.09) 117.36,80.85 116.42,80.85 113.81,83.46 112.16,83.46 v2(110.13,85.49) 110.13,86.06 109.88,86.31 109.17,86.31 v2(108.67,85.81) ; v2(141.45,41.43) 140.85,41.43 138.96,43.33 133.61,43.33 133.42,43.52 130.12,43.52 129.61,43.01 129.61,38.49 129.1,37.98 125.01,37.98 124.5,38.49 124.5,39.24 123.78,39.96 123.08,39.96 121.75,41.29 121.75,41.32 121.68,41.39 121.68,43.99 119.94,45.73 119.56,45.73 118.82,46.46 117.74,46.46 117.2,47 117.2,48 v2(117.18,48.02) ; v2(94.74,81.04) 94.83,81.04 94.83,81.36 95.33,81.87 102.64,81.87 105.81,78.69 109.62,78.69 v2(109.81,78.5)
  IN2 w0.508: v2(41.65,8.88) 41.65,8.28 42.42,7.51 43.38,7.51 44.82,6.08 61.91,6.08 63.39,4.59 78.7,4.59 79.84,5.73 95.21,5.73 95.59,6.11 95.59,6.11 96.03,6.56 108.61,6.56 109.12,6.05 111.69,6.05 114.35,8.71 125.17,8.71 v2(125.75,9.29)
  BOTTOM w0.508: RC2.1 172.18,60.85 172.56,60.47 v2(172.82,60.47) ; v2(114.96,33.74) RC55.1 RC61.1 ; v2(121.01,21.32) 121.01,22.6 v2(121.27,22.85) ; v2(128.87,88.49) RC7.1 RC80.1 ; RC48.2 116.59,29.81 v2(116.61,29.8) ; RC159.1 107.98,72.09 v2(107.84,72.09)
  vias: v2(117.11,49.1) v2(123.85,20.21) v2(124.48,20.21) v2(126.45,9.64) v2(153.22,13.88) v2(153.83,13.89) v2(154.44,13.68) v4(122.77,20.53)
+1.8VS_LS: length 2.2
  BOTTOM w0.102: v1(152.69,18.98) 153.16,19.45 154.71,19.45
+1.35V_MEM_GFX: length 99.6
  TOP w0.381: CV177.1 119.25,105.95 v2(118.53,105.95) 118.48,105.99 CV176.1
  TOP w0.508: v2(152.34,127.34) CV230.1 CV248.1 ; v2(146.26,127.15) 146.59,127.48 CV247.1 ; CV235.1 CV242.1 148.5,127.72 148.99,127.22 v2(149.58,127.22) ; CV198.1 CV210.1 v2(152.36,126.15) ; CV221.1 146.62,96.37 146.2,96.79 v2(146.2,96.79) ; RV52.1 152.42,125.15 v2(152.36,125.2) ; CV243.1 CV233.1 v2(150.44,127.13) ; CV49.1 CV53.1 117.77,114.97 v2(118,114.74) ; RV79.1 RV80.1 v2(144.69,130.04) ; CV225.1 v2(152.45,95.48) ; CV211.1 153.06,115.1 v2(152.48,114.52) ; CV166.1 v2(152.81,97.7) ; v2(152.42,115.64) 152.67,115.64 CV213.1 ; v2(117.85,117.02) 117.59,116.77 CV42.1 ; CV155.1 v2(152.36,119.23) ; CV227.1 v2(152.81,107.92) ; RV48.1 v2(155.07,99.86)
  BOTTOM w0.254: v2(150.22,109.61) 149.87,109.26 UV15.T1 ; v2(146.69,114.69) 146.67,114.71 UV13.F1 ; UV15.G1 142.67,109.13 v2(142.67,109.13) ; UV15.D1 140.21,108.67 140.21,109.13 v2(140.22,109.14) ; v2(148.67,116.43) 148.29,116.81 UV13.D3 ; RV33.1 119.64,124.64 v2(119.88,124.39) ; UV15.F14 141.8,98.14 141.8,97.73 v2(141.78,97.72) ; UV15.D14 140.27,98.13 140.19,98.04 v2(140.19,97.71) ; v2(118.45,113.62) 119.22,113.62 UV1.H19 ; UV15.M12 146.65,99.81 v2(146.22,100.25) 145.87,100.59 UV15.L11 ; UV15.D12 140.27,99.81 v2(139.87,100.21) 140.27,100.61 UV15.D11 ; v2(148.72,122.03) 149.07,122.38 UV13.C10 ; v2(150.27,123.63) 149.89,124.01 UV13.B12 ; UV13.R10 139.45,122.41 v2(139.07,122.03) ; v2(138.57,114.37) 138.67,114.47 138.67,115.21 UV13.T1 ; UV13.M1 141.89,115.21 v2(142.27,114.83) 142.65,115.21 UV13.L1 ; UV15.P14 148.27,97.79 v2(148.13,97.64) ; UV13.P14 140.27,126.02 140.18,126.12 v2(140.18,126.13) ; UV13.G14 145.87,125.63 v2(146.27,126.03) 146.67,125.63 UV13.F14 ; UV13.N5 141.07,118.43 v2(140.67,118.83) ; UV13.B14 149.87,125.63 v2(149.47,126.03) ; v2(149.56,107.41) 149.87,107.1 UV15.T3 ; UV13.E5 147.47,118.77 v2(147.61,118.91) ; UV15.L4 v2(145.47,106.61) UV15.K3 ; v2(142.67,97.71) UV15.G14 UV15.G13 ; v2(145.47,114.83) 145.85,115.21 UV13.G1 ; UV13.H12 145.09,124.01 v2(145.47,123.63) 145.87,123.23 UV13.G11 ; v2(150.35,99.42) 149.96,99.81 UV15.T12 ; UV15.M3 146.67,107.01 146.28,107.4 v2(146.19,107.4) 146.19,107.49 145.87,107.81 UV15.L2 ; v2(141.86,126.13) 141.87,126.12 UV13.M14 ; v2(141.85,109.19) 141.87,109.18 UV15.F1 ; UV15.N10 147.47,101.41 v2(147.89,100.99) 148.27,100.61 UV15.P11 ; UV13.T3 138.69,116.81 v2(139.07,116.43) ; v2(118.47,117.94) 118.12,118.3 UV1.K24 ; v2(118.47,117.94) 118.83,118.3 UV1.J24 ; v2(118.47,117.94) 118.9,117.52 UV1.J23 ; v2(146.27,118.03) 145.87,117.63 UV13.G4 ; UV13.H3 145.09,116.81 v2(145.47,116.43) 145.87,116.03 UV13.G2 ; UV13.T12 138.69,124.01 v2(139.04,123.66) ; UV15.P3 147.9,107.38 v2(147.9,107.4) ; v2(148.67,126.03) 148.27,125.63 UV13.D14 ; UV15.P12 148.27,99.72 v2(148.63,99.37) ; UV15.B14 138.56,98.21 138.16,97.81 v2(138.16,97.8) ; UV13.G13 145.89,124.81 v2(146.27,124.43) 146.67,124.03 UV13.F12 ; v2(147.47,121.89) 147.47,121.89 UV13.E10 ; UV15.G2 UV15.H3 143.47,106.99 v2(143.09,106.61) ; v2(150.27,114.83) 149.89,115.21 UV13.B1 ; v2(138.21,109.07) 138.67,108.61 UV15.B1 ; UV13.P3 140.29,116.81 v2(140.67,116.43) ; RV32.1 120.52,124.85 v2(120.38,124.71) ; UV13.N10 141.07,122.43 v2(140.67,122.83) 140.29,123.21 UV13.P11 ; v2(143.07,125.23) 143.05,125.23 UV13.L14 142.67,126.13 v2(142.67,126.13) ; v2(138.3,126) 138.67,125.63 UV13.T14 ; UV15.M1 146.67,108.61 v2(146.19,109.09) 145.87,108.77 UV15.L1 ; UV13.M3 141.89,116.81 v2(142.27,116.43) 142.67,116.03 UV13.L2 ; UV15.F3 141.49,107.39 v2(141.49,107.4) ; UV15.R10 v2(149.47,101.81) ; UV13.D12 148.29,124.01 v2(148.67,123.63) ; UV15.C5 139.47,105.41 v2(139.07,105.81) ; v2(141.47,105.81) 141.07,105.41 UV15.E5 ; v2(149.47,118.03) 149.09,118.41 UV13.C5 ; UV13.M12 141.85,124.01 v2(141.47,123.63) ; v2(139.87,106.61) 140.27,107.01 UV15.D3 ; UV13.L11 142.65,123.21 v2(142.29,122.85) ; v2(149.47,116.43) 149.86,116.81 UV13.B3 ; UV13.R5 139.54,118.41 v2(139.89,118.76) ; v2(146.97,104.41) 146.97,104.91 UV15.N5 ; UV1.L21 UV1.L20 117.93,114.7 117.98,114.74 v2(118,114.74) ; UV13.D1 148.27,114.68 v2(148.29,114.66) ; UV13.L4 142.69,117.61 v2(143.09,117.21) 143.47,116.83 UV13.K3 ; UV13.L13 UV13.K12 ; UV15.M14 v2(146.67,97.64) ; v2(148.31,109.21) 148.27,109.17 UV15.P1 ; UV13.F3 146.69,116.81 v2(147.07,116.43) ; UV15.K12 v2(145.47,99.41) UV15.L13 ; UV15.G4 v2(143.07,105.82) ; v2(148.67,122.83) 148.29,123.21 UV13.D11 ; v2(139.87,101.72) 139.78,101.72 UV15.C10 ; v2(116.91,110.41) 117.3,110.02 UV1.L13 ; v2(149.52,104.33) 149.07,104.77 UV15.R5 ; UV13.P1 140.27,114.89 v2(140.04,114.66) ; UV15.B3 v2(139.06,107.4) ; UV15.H12 143.47,99.81 v2(143.07,100.21) 142.67,100.61 UV15.G11 ; UV15.F12 v2(141.51,100.16) ; v2(140.67,101.05) 141.04,101.41 UV15.E10 ; v2(150.24,97.84) UV15.T14 ; UV15.B12 138.67,99.81 v2(138.27,100.21) ; UV1.K10 UV1.L11 UV1.L12 117.76,108.9 118,108.67 v2(118.07,108.67) ; UV15.L14 v2(145.87,97.64) ; UV13.P12 v2(139.87,124.41)
  BOTTOM w0.3: UV1.H13 119.86,109.46 119.92,109.46 120.37,109.91 v2(120.3,109.91)
  BOTTOM w0.305: UV1.L22 117.53,116.7 v2(117.85,117.02) 118.1,117.27 UV1.K23 118.47,117.88 v2(118.47,117.94) ; UV1.K9 118.45,105.95 v2(118.53,105.95)
  BOTTOM w0.381: v2(119.91,111.08) 119.91,111.49 UV1.H16 ; UV1.J10 118.9,107.09 v2(118.49,106.67) 118.1,107.06 UV1.K10 ; UV1.J9 118.55,105.95 v2(118.53,105.95)
  BOTTOM w0.508: RV54.1 v2(143.8,130.04)
  vias: v2(132.65,127.92) v2(134.54,127.31) v2(135.2,127.31) v2(136.52,127.32) v2(137.4,127.32) v2(138.49,127.34) v2(139.58,127.07) v2(140.8,93.68) v2(140.8,93.05) v2(141.21,127.3) v2(141.43,93.36) v2(142.26,93.68) v2(142.26,93.07) v2(142.83,93.36) v2(143.53,93.74) v2(143.53,93.07) v2(144.23,93.36) v2(144.97,93.7) v2(149.88,95.55) v2(150.93,96.14) v2(151.91,118.16) v2(152.36,124.25) v2(152.4,116.38) v2(152.74,106.84) v2(152.74,103.61) v2(152.81,109) v2(152.81,96.62) v2(153.4,129.37) v4(133.88,126.13)
+1.35VGPUP: length 18.6
  TOP w0.102: v1(154.26,83.65) 154.29,83.61 v2(154.29,83.04)
  IN2 w0.254: v2(154.29,83.04) 154.29,83.93 153.75,84.47 144.55,84.47 143.66,85.36 v2(143.66,89.62)
  BOTTOM w0.254: PC1409.1 154.31,83.74 PR1409.2 v2(154.29,83.04)
+2.5V_MEM: length 86.3
  TOP w1.524: 50.88,20.91 50.12,20.91 49.61,21.42 49.17,21.42 44.91,25.67 44.91,35.9 33.29,47.52 33.29,71.01 41.87,79.58 41.87,88.03 47.26,93.43
  vias: v2(46.95,94.57) v2(47.58,94.57) v2(48.22,94.57) v2(54.88,20.59) v2(55.58,20.59) v2(56.22,20.59) v2(67.46,20.85) v2(67.77,20.34) v2(68.09,20.85) v4(67.52,19.58)
+2.5VP: length 1.3
  BOTTOM w0.102: 29.17,100.6 29.17,101.49 v1(29.48,101.81)
+3V_1.8V_CPVDD: length 29.8
  TOP w0.102: v1(39.26,15.77) 38.55,15.05 v2(38.55,14.46)
  TOP w0.508: v2(38.55,14.46) 39.01,13.99 CA13.1 39.2,12.73 CA14.1 38.37,11.91 RA6.2 RA7.2
  IN1 w0.508: v2(38.55,14.46) 37.05,15.95 37.05,17.23 36.25,18.03 36.25,26.26 35.38,27.13 30.75,27.13 29.32,25.7 29.32,24.97 29.68,24.62 30.16,24.62 30.37,24.4 v2(30.37,23.32)
+3V_DVDD: length 40.8
  TOP w0.508: RA7.1 36.9,10.99 36.4,11.49 36.4,12.21 36.91,12.72 37.61,12.72 38.25,13.35 v2(38.25,13.54) ; v2(21.67,33.11) 21.85,33.29 RA10.2
  IN1 w0.508: v2(21.67,33.11) 23.38,33.11 26.18,30.31 29.42,30.31 ; v2(38.25,13.54) 38.53,13.54 39.18,14.19 39.18,14.72 37.78,16.12 37.78,25.77 35.64,27.91 30.04,27.91 29.26,28.69 29.26,30.14 29.42,30.31 ; 29.42,30.31 30.22,31.11 v2(31.22,31.11)
  vias: v1(31.47,31.58)
+3VALW: length 631.1
  TOP w0.254: 114.94,42.44 114.94,42.55 115.72,43.33 115.72,47.77 v2(115.97,48.02)
  TOP w0.508: v2(82.51,93.62) 82.51,95.08 84.67,97.24 v2(84.67,98.06) ; RC943.1 RC932.1 v2(141.56,48.02) ; RC693.2 135.34,50.82 v2(135.53,50.63) ; 163.94,27.56 163.94,25.95 v2(164.04,25.85) 164.04,23.54 163.85,23.35 v4(163.85,23.01) 163.85,21.34 v2(166.29,18.9) ; 163.94,27.56 164.09,27.72 167.07,27.72 167.79,28.43 167.79,29.17 ; 163.94,27.56 163.94,28.63 163.41,29.16 163.41,31.9 163.12,32.18 v2(163.12,33.86) ; v2(216.23,51.78) 216.79,52.34 PR791.1 ; v2(54.12,2.75) 54.12,2.88 53.61,3.38 49.78,3.38 48.33,1.93 36.14,1.93 28.98,9.1 RA11.2 ; PR16.2 v2(220.29,15.46) ; RC654.1 134.84,66.24 v2(135.28,65.8) ; PR28.1 v2(157.08,104.9) ; RC21.1 v2(133.2,55.9) ; v2(186.77,26.75) 186.1,27.42 186.1,28.62 v2(186.77,29.29) ; v2(133.93,44.37) RC949.1 ; v2(112.73,10.56) 112.61,10.69 R35.1 ; v2(133.26,48.19) 133.76,48.19 RC928.1 RC954.1
  TOP w2.54: 34.06,85.81 33.8,86.06 33.99,86.25 33.99,96.16 31.33,98.82 31.33,106.76 34.69,110.13 36.91,110.13
  IN1 w0.508: v2(130.58,87.14) 131.08,86.63 131.08,83.13 131.07,83.12 131.07,82.61 133.75,79.93 133.75,72.85 137.24,69.36 137.24,67.47 138.45,66.26 138.45,59.64 140.67,57.42 140.67,49.87 141.56,48.98 v2(141.56,48.02) ; v2(124.92,90.52) 124.92,90.12 126.64,88.41 126.64,86.76 126.32,86.44 126.19,86.44 125.84,86.08 121.79,86.08 120.48,87.39 120.48,88.79 119.84,89.43 117.62,89.43 115.72,91.33 115.72,94.95 117.24,96.47 117.24,97.62 116.73,98.13 113.69,98.13 112.67,99.14 111.72,99.14 110.58,100.28 102.31,100.28 100.22,98.2 100.22,97.08 95.36,92.22 88.06,92.22 87.06,93.22 85.76,93.22 85.36,93.62 v2(82.51,93.62) ; v2(27.39,123.02) 23.58,123.02 v2(21.48,120.92) ; 113.58,39.13 112.34,39.13 111.02,37.81 111.02,35.4 110.36,34.74 110.36,33.12 111.53,31.95 111.53,30.43 110.7,29.61 110.7,25.93 v2(111.21,25.42) 111.21,20.4 v2(110.83,20.02) ; v2(135.45,55.9) 135.59,56.04 135.59,58.95 135.08,59.45 135.08,65.61 v2(135.28,65.8) ; v2(186.77,26.75) 186.77,21.8 191.16,17.42 201.57,17.42 202.59,16.4 211.22,16.4 212.16,15.46 v2(220.29,15.46) 220.29,21.62 223.77,25.1 223.77,49.04 221.03,51.78 v2(216.23,51.78) ; v2(166.91,125.99) 166.79,125.88 157.63,125.88 156.61,124.86 156.61,120.48 155.33,119.19 155.33,116.3 155.6,116.03 155.6,105.54 156.24,104.9 v2(157.08,104.9)
  IN2 w0.508: v2(177.39,18.95) 176.81,18.95 176.14,18.28 173,18.28 v2(172.27,19) ; v2(141.56,48.02) 140.42,46.88 140.42,43.9 139.78,43.26 135.97,43.26 134.83,44.4 134.77,44.4 ; v2(157.08,104.9) 157.08,99.46 155.7,98.07 155.7,97.1 156.81,95.98 157.25,95.98 159.2,94.03 159.2,92.25 161.01,90.44 162.45,90.44 163.75,89.15 163.75,87.1 162.58,85.93 162.58,84.46 162.07,83.95 159.96,83.95 v2(159.02,83.01) 158.39,82.38 154.1,82.38 153.59,82.89 v2(153.59,83.1) 153.59,83.62 153.37,83.84 141.12,83.84 139.91,85.04 131.78,85.04 130.58,86.25 v2(130.58,87.14) 130,87.71 128.73,87.71 126.45,90 125.44,90 v2(124.92,90.52) ; v2(128.91,8.05) 128.47,8.49 v2(128.47,10.31)
  IN2 w1.524: 37.42,110.38 36.02,111.78 29.74,111.78 26.56,114.95 26.56,121.43 27.01,121.87
  BOTTOM w0.254: UC1.AJ17 UC1.AL19 115.66,48.34 115.72,48.28 v2(115.97,48.02)
  BOTTOM w0.457: CC14.1 110.52,26.23 110.46,26.29 UC4.5
  BOTTOM w0.508: v2(128.91,8.05) 129.15,8.05 130.63,6.57 R2634.2 ; RV165.2 v2(124.92,90.52) ; PR1406.1 v2(159.02,83.01) ; RE61.1 184.94,29.29 v2(186.77,29.29) 187.17,29.69 RE19.1 ; v2(135.45,49.78) 135.07,49.78 RC906.1 ; v2(54.12,2.75) 55.33,1.54 105.37,1.54 106.07,2.24 106.07,7.78 108.06,9.77 110.99,9.77 111.78,10.56 v2(112.73,10.56) 112.86,10.69 112.86,15.45 110.76,17.54 110.76,19.96 v2(110.83,20.02) ; v2(163.12,33.86) 162.88,34.09 RE70.1 162.33,35.12 162.33,37.99 158.71,41.61 148.17,41.61 145.69,44.09 140.36,44.09 139.66,43.39 138.32,43.39 136.35,45.36 136.35,46.94 135.96,47.34 v2(135.47,47.34) 135.45,47.34 135.43,47.33 RC683.1 ; v2(153.59,83.1) 153.59,83.54 PR1405.1 ; RE23.2 164.1,42.12 v2(163.85,42.37) ; RE21.1 186.72,26.7 v2(186.77,26.75) ; v2(133.93,44.37) 133.9,44.34 133.81,44.34 133.79,44.32 132.66,44.32 RC933.1 ; v2(172.27,19) 168.97,19 168.14,18.18 167.01,18.18 v2(166.29,18.9) 166.9,19.51 RE20.2 ; RC693.2 RC33.1 135.45,51.83 v2(135.58,51.71) ; CC14.1 111.02,25.61 v2(111.21,25.42) ; RC905.1 v2(133.2,55.9) ; RL7.1 v2(21.48,120.92) ; RC951.1 v2(131.02,50.82) ; RC944.1 135.4,55.9 135.41,55.9 v2(135.45,55.9) ; RC942.1 v2(135.86,53.36) ; v2(216.23,51.78) 216.75,51.26 216.75,49.93 216.12,49.31 PR756.2 ; PR209.1 84.98,98.38 v2(84.67,98.06) ; PR3.2 v2(166.91,125.99)
  vias: v2(14.31,99.27) v2(14.31,98.63) v2(14.31,98) v2(27.39,123.72) v2(28.09,123.72) v2(33.68,83.52) v2(33.68,82.89) v2(34.06,84.09) v2(34.26,83.52) v2(34.26,82.89) v2(38.63,109.94) v2(38.95,110.51) v2(39.33,109.94) v2(39.71,110.51) v2(40.03,109.94) v2(48.72,17.04) v2(48.66,15.96) v2(49.11,16.46) v2(49.36,17.04) v2(49.42,15.96) v2(113.99,39.6) v2(114.2,39.06) v2(125.8,18.38) v2(127.81,10.3) v2(156.87,25.04) v2(156.87,24.4) v2(156.87,23.77) v2(157.5,25.04) v2(157.5,24.4) v2(157.5,23.77) v2(158.2,25.04) v2(158.2,24.4) v2(158.2,23.77) v2(158.83,25.04) v2(158.83,24.4) v2(158.83,23.77) v2(159.47,25.04) v2(160.1,25.04) v2(160.29,24.4) v2(160.29,23.77) v2(161.31,43.01) v2(161.69,42.44) v2(161.75,43.58) v2(162.07,43.01) v2(162.39,43.58) v2(162.45,42.44) v2(162.77,43.01) v2(163.09,43.58) v2(163.51,42.97) v2(163.79,43.58) v2(164.42,43.57) v2(164.69,44.4) v2(174.45,34.08) v2(174.95,34.49) v4(28.91,106.13) v4(174.71,33.55)
+3VALW_EC: length 171.7
  TOP w0.254: v2(180.2,24) 180.2,23.68 CE14.1
  TOP w0.381: v2(137.32,52.91) 137.28,52.96 UC61.5 ; UC62.5 119.77,84.2 119.26,83.69 v2(118.64,83.69)
  TOP w0.508: v2(144.29,43.33) 144.29,40.57 143.47,39.74 143.47,24.01 146.5,20.97 v2(147.4,20.97) ; CE3.1 167.45,36.85 v2(167.47,36.82) ; v2(180.23,28.5) 180.53,28.21 CE13.2 ; v2(128.2,86.4) v1(129.31,86.4) 131.13,86.4 137.19,80.34 137.19,79.07 137.98,78.28 137.98,72.31 136.56,70.88 136.56,64.16 v2(136.04,63.65) ; v2(145.82,15.8) 148.14,15.8 v2(148.23,15.7) 149.25,14.69 152.04,14.69 154.12,16.76 155.8,16.76 157.2,18.16 160.98,18.16 161.71,18.89 163.18,18.89 163.86,18.21 168.18,18.21 169.06,19.09 169.06,24.08 169.81,24.83 169.81,25.21 170.21,25.61 170.21,26.56 169.28,27.48 169.28,31.14 167.11,33.31 167.11,34.68 ; v2(180.42,33.48) 180.55,33.61 CE4.1
  IN1 w0.508: v2(144.29,43.33) 143.98,43.02 142.56,43.02 139.84,45.74 138.45,45.74 136.55,47.64 136.55,52.13 v2(137.32,52.91) ; v2(118.64,83.69) 120.37,85.43 125.75,85.43 126.07,85.11 126.91,85.11 v2(128.2,86.4)
  IN2 w0.508: v2(137.32,52.91) 137.1,53.13 137.1,56.15 136.04,57.21 136.04,63.65 v2(136.04,63.65)
  IN2 w1.016: 169.18,37.8 169.37,37.99 175.72,37.99 176.36,38.63 178.26,38.63 178.52,38.88
  BOTTOM w0.203: UE1.125 178.82,39.37 v2(179.22,39.77) ; UE1.22 181.64,28.43 180.3,28.43 v2(180.23,28.5) ; UE1.9 180.57,33.63 v2(180.42,33.48) ; v2(167.47,36.82) UE1.96
  BOTTOM w0.254: UE1.33 180.02,23.82 v2(180.2,24)
  BOTTOM w0.381: v2(128.2,86.4) 127.91,86.4 125.61,88.69 UC63.5
  BOTTOM w0.508: 178.57,31.84 178.9,31.84 179.89,32.83 179.89,32.91 180.42,33.44 v2(180.42,33.48) ; RE505.2 v2(145.82,15.8) ; v2(148.23,15.7) 148.23,20.15 v2(147.4,20.97)
  vias: v2(167.34,35.9) v2(177.93,34.7) v2(178.16,35.26) v2(178.46,39.77)
+3VALWP: length 94.2
  TOP w0.102: PR113.1 197.52,36.14 v1(197.51,36.15)
  TOP w0.508: v2(198.9,35.39) 198.65,35.64 PR113.1
  IN1 w0.508: v2(187.28,34.31) 188.36,33.23 192.84,33.23 193.8,34.18 198.3,34.18 198.88,34.75 198.88,34.79 198.9,34.82 v2(198.9,35.39)
  IN2 w0.254: v2(174.45,44.4) 173.94,44.4 173.87,44.33 166.59,44.33 164.1,46.82 v2(163.34,46.82) ; v2(163.02,46.18) 164.1,46.18 166.36,43.92 174.86,43.92 175.6,44.66 v2(177.25,44.66)
  IN2 w0.508: v2(161.69,47.45) 161.56,47.45 161.18,47.83 161.18,49.55 162.58,50.95 169.31,50.95 170.01,51.64 171.41,51.64 172.11,50.95 174.33,50.95 176.3,52.91 178.58,52.91 180.36,51.14 180.36,48.79 179.73,48.15 179.73,47.29 v2(179.76,47.26)
  BOTTOM w0.254: v2(174.45,44.4) 174.95,43.91 PR108.2 175.03,45 174.96,45.07 PU100.14 ; PR109.1 177.06,44.47 v2(177.25,44.66)
  BOTTOM w0.508: v2(187.28,34.31) 186.96,34.31 186.46,34.82 186.46,40.66 185.25,41.87 184.53,41.87 183.97,41.31 182.6,41.31 180.8,43.11 180.8,44.92 180.89,45 180.89,45.74 180.38,46.25 PR107.1 179.48,46.99 v2(179.76,47.26)
  vias: v2(161.63,46.18) v2(162.01,46.82) v2(162.01,45.61) v2(162.39,46.18) v2(162.52,47.45) v2(162.71,46.82) v2(162.71,45.61) v2(163.15,47.45) v2(163.41,45.55)
+3VGS: length 168.5
  TOP w0.356: 104.27,81.88 104.57,82.17 QV1.5 QV1.2 104.57,85.17 105.06,85.67 ; UV4.1 84.47,93.11 85.06,92.52 RV92.2
  TOP w0.508: v2(122.56,93.92) 122.56,93.95 122.19,94.32 121.31,94.32 119.59,92.6 v2(116.67,92.6) RV154.1 ; 111.84,92.41 113.81,92.41 115.59,94.19 115.59,95.14 115.08,95.65 114.19,95.65 113.37,96.47 113.37,100.73 114.49,101.86 RV91.2 ; v2(84.06,91.87) 84.73,91.87 85.24,92.38 RV92.2 ; v2(84.06,91.87) 85.02,90.91 86.97,90.91 88.22,92.16 88.22,93.96 v2(88,94.19) 88,94.98 87.57,95.41 RV73.2 ; v2(84.06,91.87) 83.01,90.82 76.16,90.82 75.76,91.22 RV72.2 74.38,92.54 73.81,93.11 73.81,95.52 75.39,97.11 v2(75.59,97.11) 76.22,96.47 76.22,95.76 76.66,95.32 CV185.2 77.12,95.32 77.17,95.27 RV102.2 ; PR1115.1 v2(47.58,124.04) ; RV5.1 103.6,81.88 104.27,81.88
  IN1 w0.508: v2(75.59,97.11) 75.59,97.05 75.08,96.54 66.7,96.54 63.81,99.42 63.81,106.47 63.67,106.61 63.67,108.57 60.54,111.71 60.54,113.54 56.26,117.81 50.31,117.81 48.66,119.46 48.66,120.92 48.22,121.37 48.22,123.4 v2(47.58,124.04) ; v2(84.06,91.87) 84.58,91.87 85.37,91.08 86.99,91.08 87.37,90.7 104.73,90.7 v2(105.62,89.81) ; v2(88,94.19) 88.7,93.49 91.46,93.49 94.25,96.28 94.25,99.9 96.41,102.06 96.41,105.17 96.79,105.56 97.05,105.56 97.49,106 97.49,106.57 96.96,107.1 v2(96.96,116.91)
  BOTTOM w0.381: UV2.5 96.83,118.79 97.3,118.32 97.3,118.02 97.68,117.64 97.76,117.64 RV162.1
  BOTTOM w0.508: RV164.2 122.61,93.87 v2(122.56,93.92) ; v2(96.96,116.91) 97.16,117.11 97.73,117.11 RV162.1
  vias: v2(110.51,92.76) v4(110.51,91.52)
+3VLP: length 249.3
  TOP w0.508: RE49.1 160.36,95.78 159.57,94.99 v2(157.16,94.99) ; v2(173.76,44.85) 173.69,44.79 173.69,44.02 174.52,43.2 177.82,43.2 178.82,44.2 181,44.2 181.5,44.7 v2(181.5,44.72)
  IN1 w0.508: v2(173.76,44.85) 174.07,45.17 174.07,52.47 173.67,52.88 173.67,53.38 171.79,55.26 171.79,55.99 170.42,57.36 169.75,57.36 168.84,58.27 167.7,58.27 167.2,58.78 167.2,60.74 166.64,61.3 166.2,61.3 165.82,61.68 165.82,62.18 165.12,62.88 165.12,65.36 163.91,66.57 163.91,70.76 160.36,74.31 160.36,81.18 159.67,81.87 159.67,84.98 161.46,86.78 161.46,88 161.07,88.4 161.07,90.49 157.16,94.4 v2(157.16,94.99)
  IN2 w0.508: 175.85,32.56 178.03,32.56 178.27,32.8 178.27,33.66 179.01,34.4 181.57,34.4 182.07,34.9 182.07,36.31 182.65,36.89 182.87,36.89 186.35,40.37 186.35,42.31 185.85,42.82 v2(185.76,42.82)
  IN2 w1.016: 177.31,14.69 175.6,12.97 172.4,12.97 166.75,7.32 158.47,7.32 156.83,8.96 149.84,8.96 147.73,11.07 145.84,11.07 145.8,11.03 136.33,11.03 136.23,10.93 135.95,10.93 135.43,10.4 133.85,10.4 129.56,6.11 119.78,6.11 117.56,3.89 109.05,3.89 107.97,4.97 96.67,4.97 95.78,4.08 81.94,4.08 80.92,3.07 79.33,3.07 62.63,3.07 61.17,4.53 48.09,4.53 46.25,2.69 40.96,2.69 39.19,4.46 37.57,4.46 37.28,4.16
  BOTTOM w0.508: v2(185.76,42.82) 185.4,42.82 185.19,42.6 184.36,42.6 183.71,41.94 182.88,41.94 181.43,43.38 181.43,44.65 v2(181.5,44.72)
  vias: v2(36.39,2.54) v2(36.94,2.95) v2(175.21,32.31) v2(175.22,31.7) v2(177.62,15.53) v2(178.25,15.55) v4(178.14,16.53)
+3VS: length 542
  TOP w0.254: v2(151.72,24.66) 151.98,24.91 151.98,25.47 154.52,28.01 PR302.1 ; RPC36.3 140.89,42.27 141.33,42.27 v2(141.43,42.37) ; U2407.1 72.17,13.97 71.9,14.24 71.9,15 72.16,15.26 C2498.1
  TOP w0.381: v2(107.91,85.65) 107.64,85.65 107.6,85.62 107.51,85.62 RC17.1
  TOP w0.508: v2(117.62,6.88) 117.62,7.43 RE68.2 ; PR1070.1 161.06,66.52 v2(161.06,66.85) ; v2(196.83,27.83) 196.87,27.79 RS38.2 ; 48.34,105.17 48.34,110.76 44.97,114.14 44.97,115.02 v2(44.51,115.48) 43.77,116.22 43.77,123.72 ; RC16.1 109.92,84.04 109.52,83.64 v2(109.52,83.64) ; RC70.2 108.22,87.2 108.22,86.23 108.06,86.07 108.06,85.99 107.91,85.84 v2(107.91,85.65) ; PR1112.1 47,126.71 46.44,127.27 44.66,127.27 43.77,126.38 43.77,123.72 ; v2(133.18,56.53) 133.56,56.91 RC350.1 ; QW1.2 55.76,103.88 55.25,103.37 51.35,103.37 50.25,104.48 48.41,104.48 ; R2448.1 80.92,12.46 82.32,11.07 83.33,11.07 83.78,11.51 83.78,14.88 v2(84.09,15.19) 86.32,15.19 90,11.51 92.03,11.51 92.35,11.19 v2(92.35,9.92) R28.1 91.66,8.68 Q6.2 ; v2(71.58,21.54) 71.52,21.61 CD234.1 ; v2(183.45,42.55) 182.96,42.06 182.96,39.32 184.61,37.67 184.61,33.36 184.93,33.04 184.93,32.11 184.2,31.38 184.2,26.85 185.57,25.48 185.57,22.94 184.68,22.05 184.68,19.39 v2(184.93,19.13) ; v2(180.42,47.96) 181.12,48.66 v2(181.12,50.44) 180.96,50.61 180.96,51.73 181.75,52.52 RF1.2 179.66,56.2 179.66,57.04 180.11,57.49 180.25,57.49 180.61,57.84 180.61,58.55 180.13,59.03 174.41,59.03 174.15,58.77 172.69,58.77 172.18,59.28 PR1021.1 ; 43.77,123.72 44.48,123.72 45.93,122.26 PR1119.1 ; 71.53,17.29 72.71,16.11 C2498.1 ; v2(157.02,13.54) 157.37,13.2 v4(157.37,12.78) 157.44,12.71 157.44,9.99 157.79,9.63 157.79,6.85 156.49,5.56 R23.2 ; RC690.2 114.83,82.87 RC691.2 114.88,82.43 v2(114.32,81.87) ; QA1.2 v2(41.63,12.13) ; C17.1 230.25,45.12 230.25,47.13 229.68,47.71 227.69,47.71 227.13,48.27 U1.5 ; v2(133.19,46.28) 133.4,46.08 133.84,46.08 RC708.2
  TOP w1.524: 96.92,70.69 93.56,67.33 83.01,67.33 79.46,70.88 79.46,75.14 75.46,79.14 75.46,87.46 72.16,90.76 70.82,90.76 69.87,91.71
  TOP w3.048: 29.8,78.19 29.8,41.34 32.04,39.11 37.05,39.11 37.75,38.41 ; 33.23,78.57 33.29,78.63 36.28,78.63 39.33,81.68
  IN1 w0.254: v2(162.07,19.64) 162.37,19.64 166.54,23.81 166.54,25.52 168.5,27.48 v2(168.5,30.07)
  IN1 w0.508: v2(114.32,81.87) 113.81,81.36 112.86,81.36 110.64,83.58 109.58,83.58 v2(109.52,83.64) 107.91,85.26 v2(107.91,85.65) 107.91,85.81 108.03,85.93 108.03,89.05 108.41,89.43 108.41,91.08 107.53,91.97 107.53,93.24 108.67,94.38 113.56,94.38 v2(113.94,94.76) ; v2(181.12,50.44) 181.12,50.11 181.31,49.92 181.31,48.72 181.95,48.09 182.33,48.09 183.57,46.84 183.57,42.67 v2(183.45,42.55) ; 158.39,83.08 158.39,82.25 159.72,80.92 159.72,74 161.82,71.9 161.82,68.15 161.06,67.39 v2(161.06,66.85) ; 158.39,83.08 158.39,84.6 160.83,87.04 v2(160.83,87.69) ; 158.39,83.08 157.69,82.38 133.56,82.38 131.72,84.22 131.72,86.9 131.66,86.96 131.66,92.66 129.75,94.57 124.16,94.57 v2(123.97,94.38) ; v2(201.57,27.7) 201.44,27.83 v2(196.83,27.83) ; v2(34.03,122.95) 32.92,121.85 32.84,121.85 32.61,121.61 32.57,121.57 30.54,121.57 29.36,120.38 29.36,119.72 28.26,118.62 v2(28.26,118.39) 28.26,117.8 28.82,117.24 28.82,116.98 34.17,111.64 41.65,111.64 44.51,114.5 v2(44.51,115.48) ; v2(135.59,45.23) 134.91,45.23 133.86,46.28 v2(133.19,46.28) 132.39,47.08 132.39,53.59 132.94,54.13 133.74,54.13 134.39,54.78 134.39,56.09 133.94,56.53 v2(133.18,56.53)
  IN2 w0.508: v2(172.73,19.5) 173.31,18.91 175.87,18.91 176.55,19.59 181.36,19.59 181.54,19.41 184.65,19.41 v2(184.93,19.13) ; v2(114.7,94.76) 116.48,94.76 117.88,93.36 120.04,93.36 121.24,94.57 123.78,94.57 v2(123.97,94.38) ; v2(139.4,26.5) 141.06,24.84 141.92,24.84 142.17,24.84 142.86,24.84 144.32,24.84 144.39,24.77 147.86,24.77 v2(147.98,24.66)
  BOTTOM w0.254: JDIMM2.256 v2(43.64,21.87)
  BOTTOM w0.305: v2(54.25,22.43) 53.94,22.12 JDIMM2.255 ; v2(71.58,21.54) 71.46,21.54 71.38,21.63 JDIMM1.255
  BOTTOM w0.381: v2(34.03,122.95) 34.32,122.65 RL3.1
  BOTTOM w0.508: RF2.2 180.42,47.96 v2(180.42,47.96) ; RC904.1 112.73,31.52 v2(112.71,31.49) ; 139.85,42.37 v2(141.43,42.37) ; 139.85,42.37 139.85,41.67 138.39,40.21 138.39,36.21 139.53,35.07 139.53,30.35 139.39,30.21 139.39,26.89 139.42,26.86 139.42,26.52 v2(139.4,26.5) ; 139.85,42.37 139.47,42.75 137.94,42.75 135.59,45.1 v2(135.59,45.23) RC712.2 ; 98.83,36.98 96.41,34.56 v2(96.41,28.21) 96.35,28.15 93.17,28.15 84.86,19.83 84.86,15.96 v2(84.09,15.19) ; v2(110.97,34.06) 110.55,34.06 RC710.2 RC938.1 ; RS25.1 RS27.1 200.64,24.64 CS42.1 202.13,24.64 202.46,24.97 202.46,27.32 202.08,27.7 v2(201.57,27.7) RS28.1 RS19.1 RS33.2 ; JIOB1.12 174.6,18.1 173.24,19.46 172.76,19.46 v2(172.73,19.5) ; RS20.1 RS29.1 v2(189.5,24.15) ; v2(116.15,31.34) 115.84,31.64 RC902.1 115.18,32.07 RC925.1 ; RC50.1 v2(109.09,32.07) ; v2(160.83,87.69) 160.53,87.39 PR1401.1 ; v2(189.5,21.1) RS34.2 ; RL11.2 v2(28.26,118.39) ; RS26.1 RS30.1 v2(189.5,28.21) 189.45,28.16 CS27.1 188.21,28.69 187.09,28.69 186.61,28.21 RE66.1
  vias: v2(40.22,89.3) v2(40.22,88.66) v2(40.85,89.05) v2(42.06,33.61) v2(42.06,32.97) v2(42.69,33.61) v2(42.69,32.97) v2(43.28,33.61) v2(43.28,32.97) v2(66.95,92.03) v2(67.58,92.03) v2(68.22,92.03) v2(114.32,94.25) v2(148.47,24.08) v2(148.74,24.66) v2(149.05,24.08) v2(149.37,24.66) v2(150.07,24.15) v2(150.07,23.51) v2(150.39,24.66) v2(150.71,24.15) v2(150.71,23.51) v2(151.09,24.66) v2(151.34,24.1) v2(151.34,23.51) v2(151.98,24.1) v2(151.98,23.51) v2(225.68,41.36) v2(225.69,40.72) v2(226.26,41.36) v2(226.27,40.72) v2(226.27,40.14)
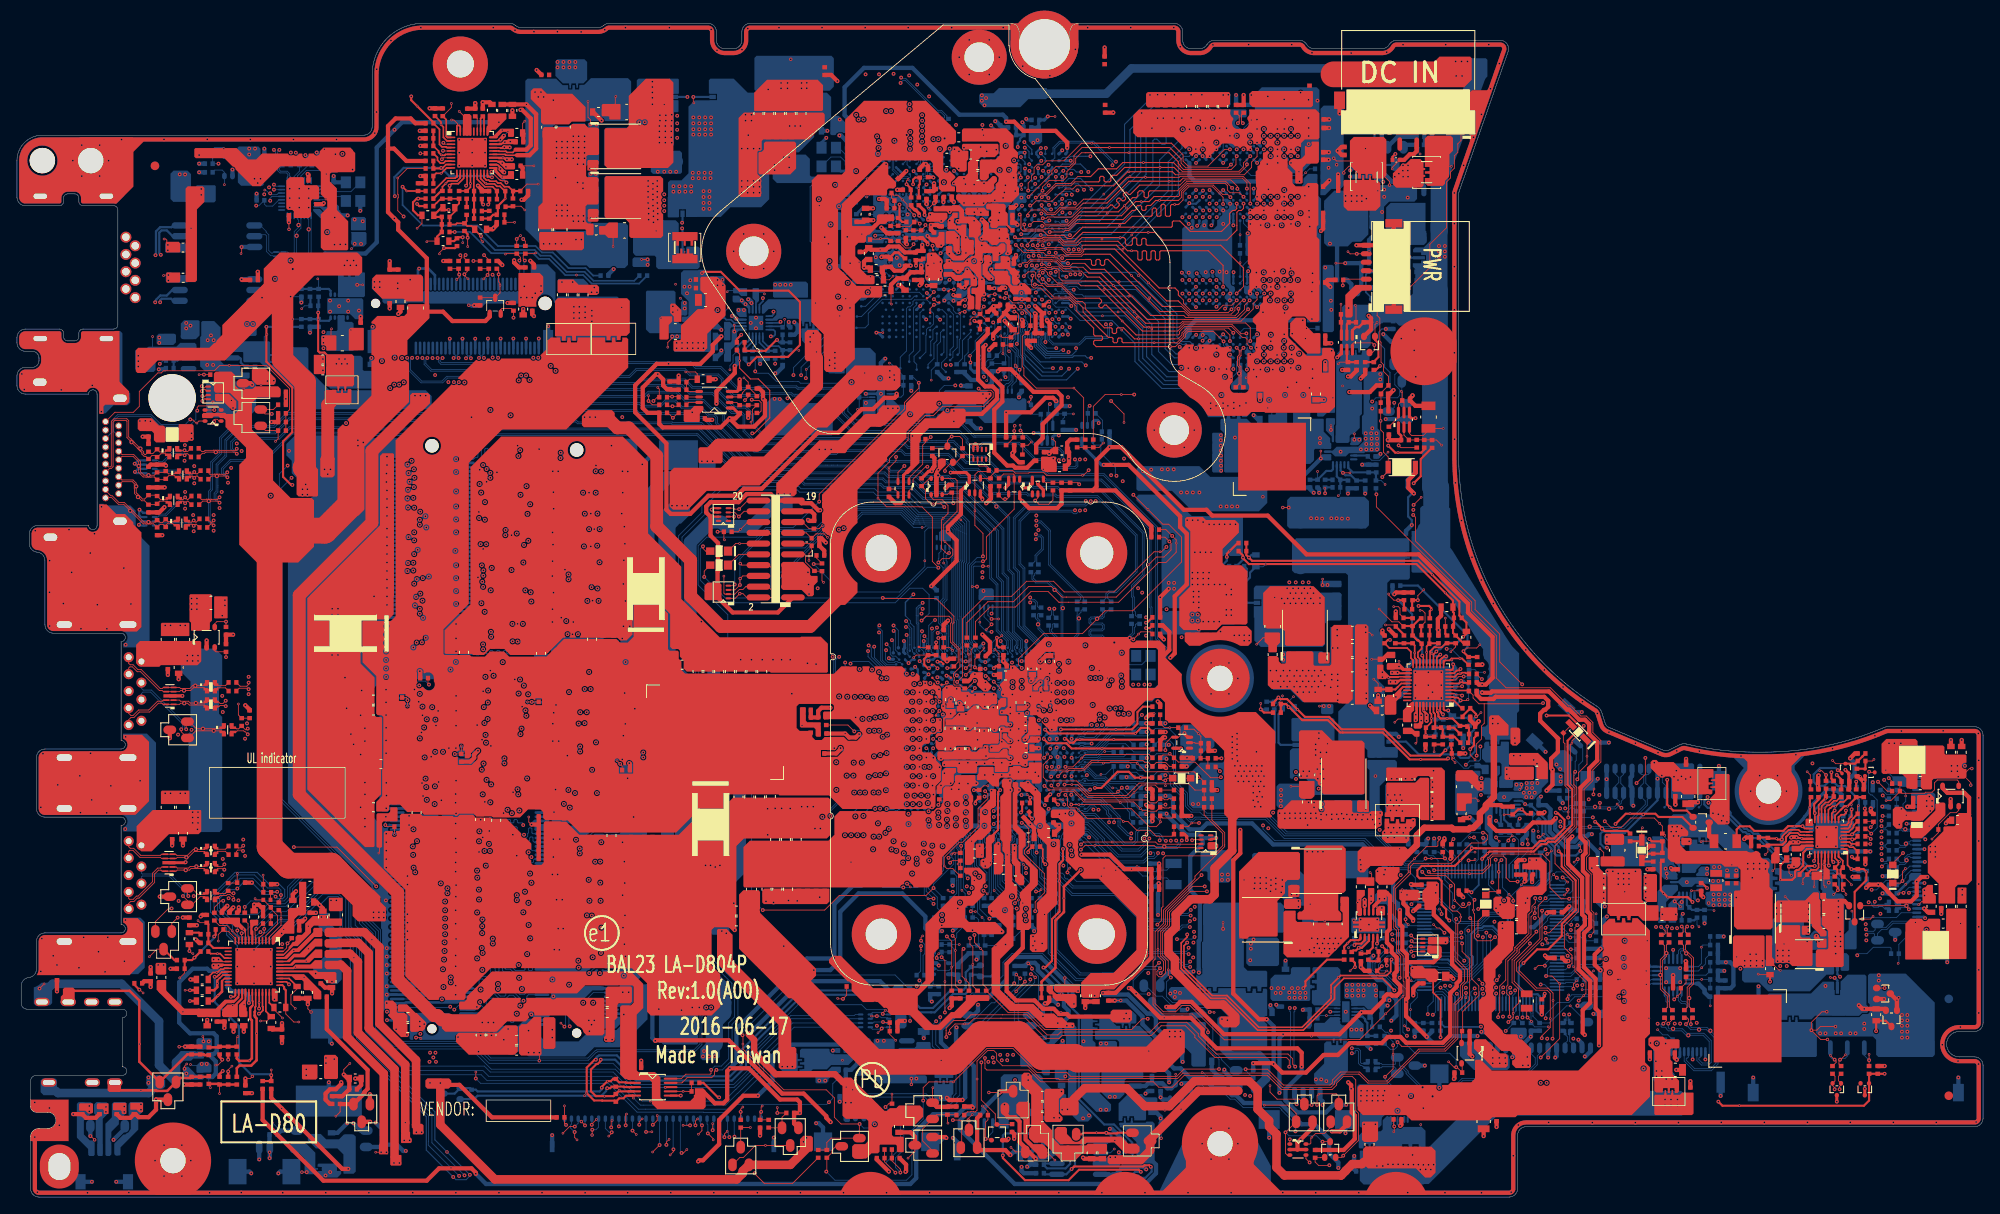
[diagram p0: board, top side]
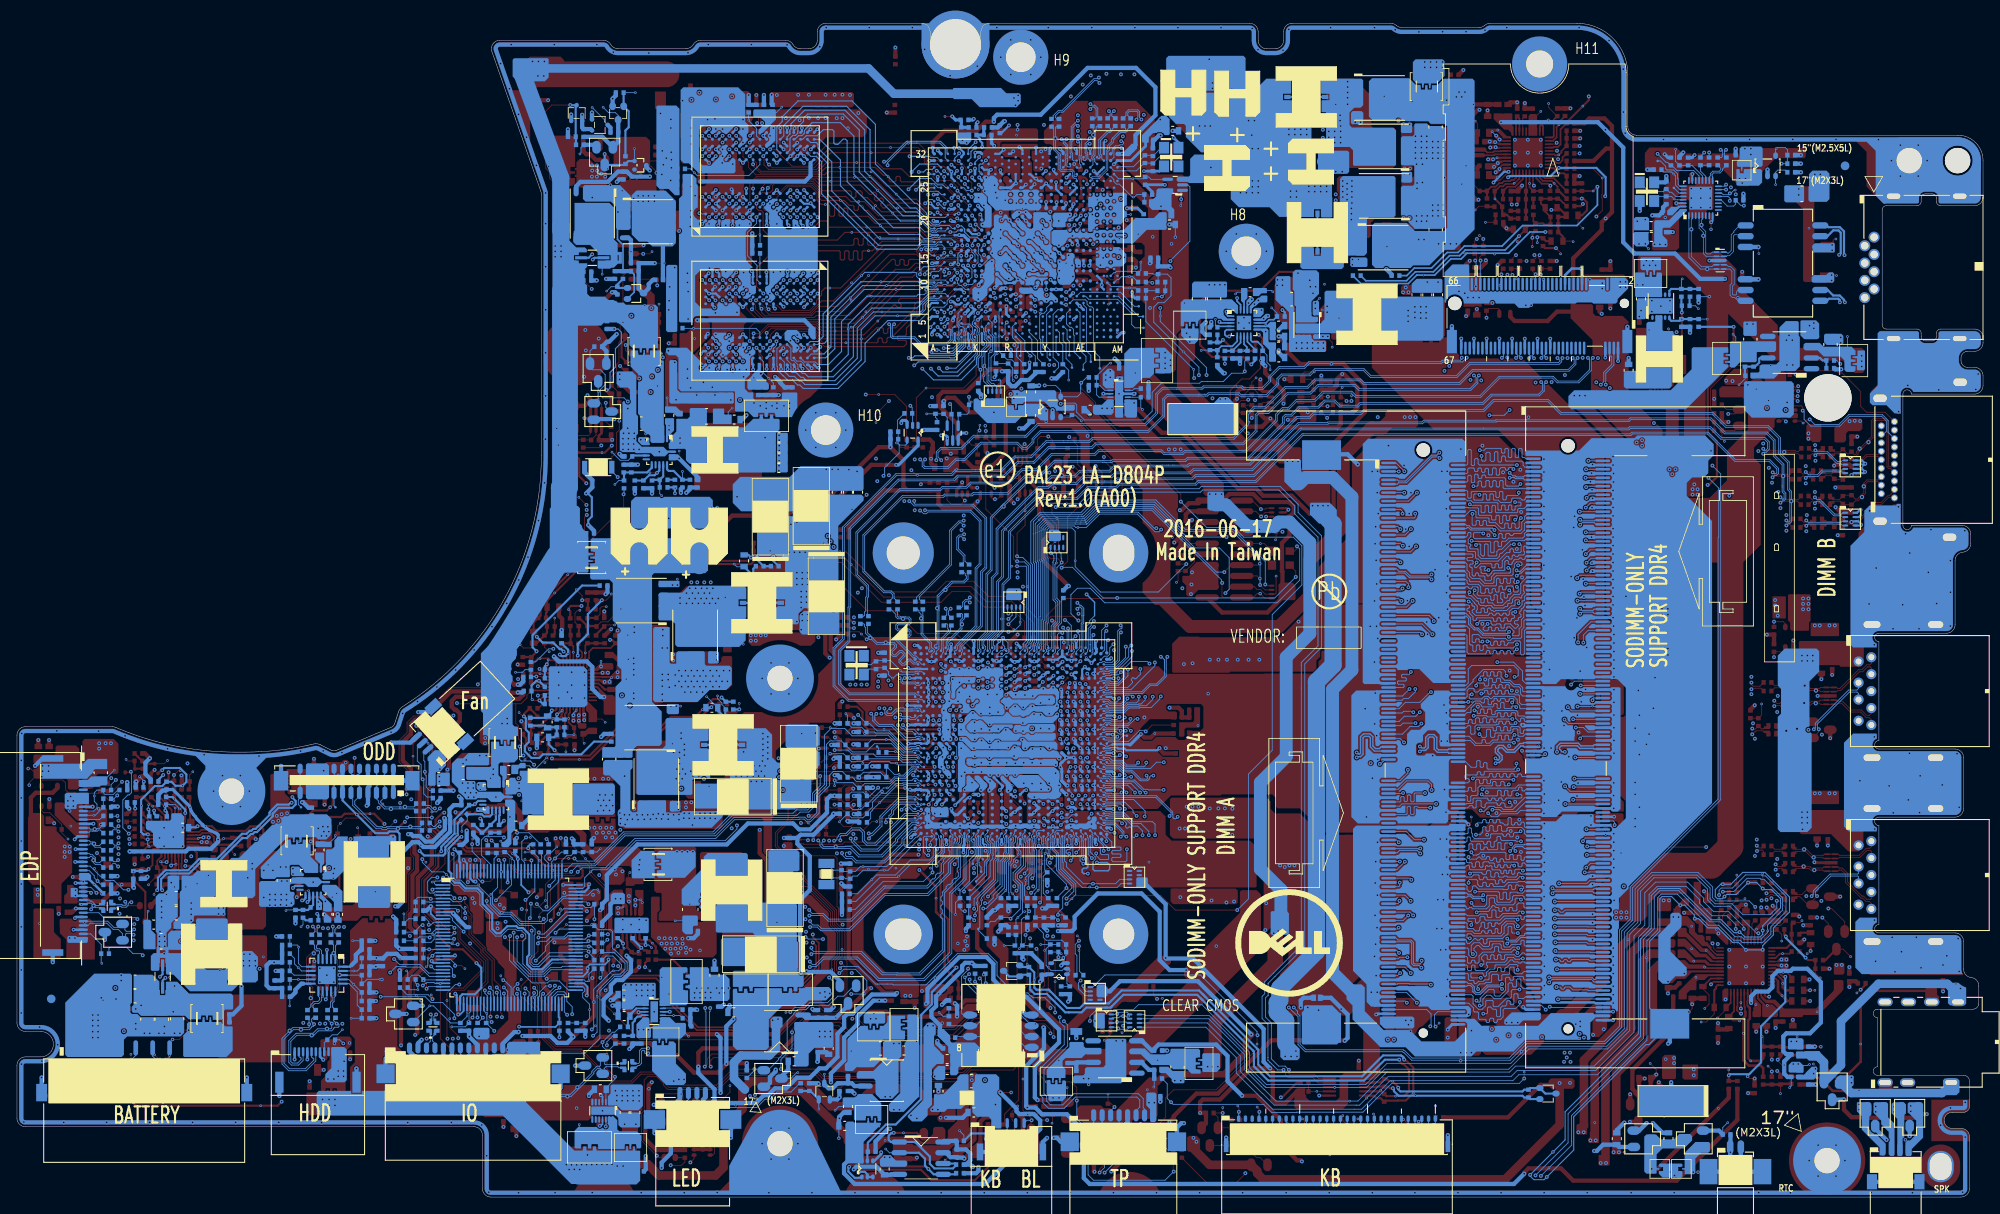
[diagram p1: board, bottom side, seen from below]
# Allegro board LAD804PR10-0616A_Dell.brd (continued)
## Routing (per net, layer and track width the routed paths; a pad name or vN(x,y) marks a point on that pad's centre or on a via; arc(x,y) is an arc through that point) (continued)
+3VS_APU:
  vias: v1(112.61,41.99) v2(114.96,47.96)
+3VS_CAM: length 0.7
  TOP w0.102: 224.87,34.88 224.68,34.88 v1(224.3,34.5)
  vias: v2(224.98,36.21) v2(225,35.58)
+3VS_TOUCH: length 35.2
  TOP w0.762: 97.94,13.54 97.43,13.54 96.48,14.5 89.49,14.5 86.95,17.04 86.95,18.54 v2(86.31,19.18)
  BOTTOM w0.508: v2(86.31,19.18) 92.61,25.47 101.8,25.47 103,24.27 103.57,24.27
  vias: v1(98.57,12.65) v2(97.75,11.13) v2(98.38,11.13)
+3VS_WLAN_NGFF: length 1.3
  TOP w0.102: v2(53.93,105.22) 53.92,105.24 v4(53.3,105.24)
  TOP w0.508: RW12.1 v2(53.93,105.22)
  vias: v2(42.16,107.99) v2(42.16,107.36) v2(42.79,107.99) v2(42.79,107.36) v2(44.91,107.84) v2(44.91,107.21) v2(59.44,106.14) v2(60.13,106.14) v2(60.78,106.14) v2(61.13,106.65) v2(61.82,107.51) v2(61.82,106.88) v4(46.38,108.25) v4(59.84,107.46)
+5V_AVDD: length 5.4
  TOP w0.762: 17.04,24.4 v1(19.58,21.86) 21.42,21.86
+5V_HDD:
  vias: v2(193.38,14.88) v2(193.38,14.24) v2(194.01,14.88) v2(194.01,14.24) v2(194.52,13.92) v2(195.22,13.92) v4(192.68,18.18) v4(193.31,16.02) v4(194.46,18.12)
+5V_HDMI: length 11.5
  IN2 w0.508: v2(25.48,93.11) 25.48,92.41 23.81,90.73 16.56,90.73 v2(15.74,91.55)
  vias: v1(25.29,94) v2(14.5,91.57) v2(15.13,91.6)
+5V_PVDD:
  vias: v1(34.37,31.96) v2(35.22,26.37) v2(35.91,33.04) v2(36.53,33.05) v2(37.15,25.42)
+5V_USB_PWR1:
  vias: v2(20.09,63.9) v2(20.09,63.26) v2(20.72,63.9) v2(20.72,63.26) v2(20.72,45.42) v2(20.72,44.79) v2(20.72,44.15) v2(21.36,63.9) v2(21.36,63.26) v2(21.36,45.42) v2(21.36,44.79) v2(21.36,44.15) v4(21.29,43.39)
+5V_USB_PWR2:
  vias: v2(174.07,16.42) v2(174.07,15.78) v2(174.84,16.42) v2(174.9,15.78) v2(175.53,16.42) v2(175.6,15.78) v4(174.07,17.35)
+5VALW: length 513.1
  TOP w0.203: PU1100.26 56.82,123.44 56.85,123.4 57.67,123.4 57.8,123.26 58.49,123.26 58.82,123.59
  TOP w0.406: Q2.5 Q2.2
  TOP w0.508: v2(155.1,7.75) 156.05,7.75 156.88,8.58 Q3.3 ; 151.02,5.61 151.04,5.62 151.04,6.41 v2(151.44,6.81) 152.81,8.18 Q6102.3 ; PC306.1 161.56,35.9 161.96,35.5 161.96,33.43 161.93,33.4 161.93,31.6 161.59,31.26 161.59,30.03 162.15,29.47 162.15,28.88 162.74,28.29 162.74,26.63 162.48,26.38 162.48,26.12 162.48,26.12 162.48,25.62 163.16,24.93 163.16,24.2 162.75,23.79 162.73,23.79 162.72,23.78 162.21,23.78 162.2,23.79 162.16,23.79 162.05,23.91 161.58,23.91 161.23,23.56 161.23,23.27 159.77,21.8 v2(158.58,21.8) 156,19.22 v2(149.34,19.22) 142.35,19.22 138.54,23.03 137.21,23.03 136.62,22.44 v2(135.57,22.44) ; v2(87.4,11.96) 85.68,11.96 82.82,9.1 82.82,6.24 80.92,4.34 80.47,4.34 v2(80.35,4.21) ; v2(103.76,94.79) 103.76,94.55 103.53,94.32 102.32,94.32 100.99,92.98 99.65,92.98 96.86,90.19 94.44,90.19 87.84,83.58 85.75,83.58 84.92,82.76 81.55,82.76 79.41,80.61 77.11,80.61 76.6,81.12 76.6,88.92 72.92,92.6 72.92,95.78 75.46,98.32 v4(76.86,98.32) 80.6,98.32 82.06,99.78 82.06,100.54 v2(83.08,101.55) ; v2(59.39,128.29) 59.58,128.29 60.6,127.28 60.6,124.1 60.09,123.59 58.82,123.59
  IN1 w0.508: v2(59.39,128.29) 58.69,127.59 57.61,127.59 v2(56.85,126.83) 56.35,126.83 54.57,125.05 54.57,120.1 55.33,119.33 56.54,119.33 61.74,114.13 62.38,114.13 63.27,113.24 64.35,113.24 66.19,111.4 66.19,107.21 65.08,106.1 65.08,100.56 66.7,98.95 80.98,98.95 81.62,99.59 81.62,101.05 82.13,101.55 v2(83.08,101.55) ; 24.21,102.89 25.55,104.22 29.29,104.22 29.99,104.92 29.99,107.9 v2(30.44,108.35)
  IN1 w1.524: 20.98,71.96 20.98,76.76 22.05,77.84 22.05,87.14 26.63,91.71 26.63,93.87 25.23,95.27 25.23,101.87 24.21,102.89 21.61,102.89
  IN2 w0.508: v2(161.45,91.8) 161.45,94.37 159.79,96.03 159.79,98 161.34,99.55 161.34,101.64 v2(161.16,101.82) 160.8,102.18 160.8,104.55 156.06,109.29 156.06,118.6 156.57,119.11 156.88,119.11 157.92,120.15 157.92,125.15 159.34,126.57 164.1,126.57 v2(165.23,127.7) 165.23,131.35 163.47,133.11 163.41,133.11 162.9,133.62 126.39,133.62 123.78,131.02 108.86,131.02 106.13,133.75 82.51,133.75 81.87,134.38 70.19,134.38 68.09,132.29 59.47,132.29 57.73,130.55 46.1,130.55 44.53,128.99 v2(44.53,125.94)
  BOTTOM w0.203: U2301.4 162.83,11.83 v2(163.02,12.02) ; v2(158.58,21.8) 158.57,21.8 158.52,21.86 U2302.4 ; v2(103.76,94.79) 103.75,94.78 U15.4
  BOTTOM w0.508: v2(135.57,22.44) 135.94,22.07 R1674.1 ; 119.97,3.83 119.46,3.83 119.27,3.64 119.21,3.64 v2(119.15,3.57) ; 119.97,3.83 R56.2 ; 119.97,3.83 119.46,4.34 119.46,5.11 119.97,5.62 121.05,5.62 R54.2 121.05,6.55 R2635.2 122.53,6.62 U2.8 ; v2(148.91,12.29) 148.91,18.79 v2(149.34,19.22) ; 161.64,34.79 161.9,34.53 161.9,33.41 162.88,32.43 RE504.2 ; v2(83.08,101.55) PR210.2 PR206.1 ; PD6.3 164.23,126.02 PR8.1 165.23,126.2 PD5.3 v2(165.23,127.7) ; PU400.4 99.21,18.43 98.06,17.29 PC401.1 97.76,17.48 97.25,17.99 90.45,17.99 89.11,16.66 89.11,13.67 v2(87.4,11.96) ; v2(161.45,91.8) 163.77,91.8 Q15.3 ; v2(56.85,126.83) 45.43,126.83 v2(44.53,125.94) 42.44,123.84 42.44,112.67 41.1,111.33 36.34,111.33 33.36,108.35 v2(30.44,108.35) ; v2(161.16,101.82) 162.05,100.93 162.3,100.93 R53.1 162.38,99.84 Q16.2
  vias: v2(19.96,103.14) v2(19.96,102.51) v2(20.47,102.82) v2(20.59,70.63) v2(20.59,70) v2(20.59,69.36) v2(21.23,70.63) v2(21.23,70) v2(21.23,69.36) v2(158.54,12.54) v2(158.52,11.95) v2(158.52,11.33) v2(159.23,11.95) v2(159.23,11.37) v2(159.25,12.54) v2(159.92,12.54) v2(159.9,11.95) v2(159.86,11.36) v2(160.53,12.54) v2(160.5,11.95) v2(160.53,11.36) v2(160.71,35.19) v2(161.14,11.98) v2(161.15,11.37) v2(161.3,35.21) v2(161.32,12.54) v4(165.88,10.5) v4(188.84,25.67)
+5VALWP: length 19.5
  IN2 w0.254: v2(189.5,36.91) 189.63,36.78 189.63,34.56 190.23,33.97 195.94,33.97 v2(196.49,33.42) ; v2(190.14,36.91) 190.01,36.78 190.01,34.75 190.42,34.35 195.89,34.35 v2(196.36,34.82)
  BOTTOM w0.254: PR117.2 196.35,33.28 v2(196.49,33.42)
  vias: v1(189.63,36.02) v2(187.6,38.44) v2(188.23,38.44) v2(188.87,38.18) v2(188.87,37.55) v2(188.87,36.91) v2(189.5,38.18) v2(189.5,37.55) v2(190.14,38.18) v2(190.14,37.55) v2(190.9,38.44)
+5VS: length 288.3
  TOP w0.203: PU1001.12 167.87,63.4 168.02,63.55 168.06,63.55 168.14,63.63 168.15,63.63 168.31,63.8 v2(168.56,63.8)
  TOP w0.508: RE60.1 56.03,9.4 52.19,13.24 51.12,13.24
  TOP w1.016: 159.41,4.15 158.88,4.15 158.63,3.89 157.5,3.89 156.72,3.11 156.72,3.08 156.21,2.58 156.18,2.58 156.16,2.55 149.5,2.55 148.56,3.49 148.56,7.43 147.69,8.3 147.69,9.02 146.34,10.37 146.34,12.66 145.32,13.67 138.88,13.67 135.93,10.72 133.02,10.72 130.89,12.85 125.94,12.85 124.61,11.51 ; v2(49.94,13.45) 49.94,8.52 56.37,2.09 84.89,2.09 85.61,2.8 85.61,3.08 Q7.3 91.23,3.8 93.14,5.72
  IN1 w0.508: v2(168.56,63.8) 168.79,63.57 169.55,63.57 170.06,63.06 170.38,63.06 170.87,62.56 170.87,62.06 171.25,61.68 171.25,60.24 172.61,58.88 173.53,58.88 179.09,53.32 179.09,52.25 180.24,51.1 181.54,51.1 v2(181.59,51.05)
  IN1 w1.016: 18.7,87.27 18.7,75.78 16.59,73.68 16.59,49.87 ; v2(48.72,13.47) 48.67,13.52 45.66,13.52 40.72,18.46 40.72,28.35 40.09,28.99 38.86,30.22 38.86,34.08 38.8,34.14 ; 16.59,49.87 25.48,49.87 37.42,37.93 37.42,35.9 ; 16.59,49.87 16.59,39.52 17.74,38.37 17.74,34.82 17.19,34.27 17.19,28.49 17.17,28.47
  IN2 w1.016: 121.73,10.43 114.82,10.43 112.35,7.96 108.99,7.96 108.6,7.57 95.79,7.57 95.22,7 94.57,7
  BOTTOM w0.508: v2(168.56,63.8) 168.56,63.76 168,63.2 164.68,63.2 164.04,62.57 164.04,59.96 163.09,59.01 v2(162.64,59.01) ; RF3.2 181.93,46.94 182.21,46.67 182.21,46.63 182.33,46.52 v2(182.33,46.49)
  vias: v2(16.66,27.39) v2(17.29,27.39) v2(20.59,90.12) v2(20.59,89.49) v2(37.04,35.01) v2(37.68,35.01) v2(92.78,6.52) v2(93.13,6.98) v2(123.27,10.31) v2(123.91,10.35) v2(160.4,3.66) v2(161.1,3.66) v2(161.72,3.87) v2(162.3,3.85) v2(162.91,3.87) v2(163.52,3.85) v2(164.1,3.83) v2(164.71,3.83) v2(165.3,3.83) v2(165.53,3.24) v2(165.88,3.8) v2(166.16,3.27) v2(166.49,3.8) v2(166.77,3.24) v2(167.1,3.83) v2(182.01,50.5) v2(194.39,11.51) v2(194.39,10.81) v2(195.09,11.51) v2(195.09,10.81) v2(195.85,11.51) v2(195.85,10.81) v2(200.05,45.29) v2(200.68,45.17) v2(201.06,44.4) v2(201.25,44.98) v2(201.7,44.28) v2(229.45,36.28) v2(229.45,35.65) v4(164.61,4.97)
+5VS_KBL:
  vias: v4(116.48,10.91)
+5VS_ODD:
  vias: v2(195.45,49.6) v2(195.92,49.21) v2(196.32,49.64) v2(196.83,49.33) v2(197.39,49.56) v4(193.12,51.26) v4(194.01,49.74) v4(195.73,50.31)
+17.4V_BATT+: length 24.3
  TOP w0.254: PR745.2 210.26,38.17 211.16,39.07 v2(212.05,39.07)
  TOP w0.508: v2(217.25,22.62) 217.68,22.2 v4(217.89,22.2) PR780.2 220.28,22.2 PQ710.3
  IN2 w0.254: v2(212.05,39.07) 212.24,39.07 213.57,37.74 214.75,37.74 215.84,36.64 215.84,25.75 215,24.91 v2(213.32,24.91)
+17.4V_BATT++: length 8.6
  TOP w0.102: v4(213.55,18.6) 212.75,18.6 v2(211.65,19.69) ; v4(213.47,21.86) 212.9,21.86 211.65,20.62 v2(211.65,19.69) ; v2(211.65,19.69) 212.29,19.69 212.72,20.12 v4(214.5,20.12)
+19V_ADPIN: length 5.1
  TOP w0.102: v4(155.32,122.59) 155.65,122.26 157.45,122.26 ; v4(156.5,120.85) 156.5,121.02 157.12,121.65 157.55,121.65 ; v4(161.89,119.41) 161.89,119.83 161.23,120.49
+19V_VIN: length 161.7
  TOP w0.254: v2(194.65,49.23) 194.65,46.31 v4(194.96,45.99) 195.35,45.61 196.95,45.61 PD704.2
  TOP w0.508: v2(218.1,36.49) 218.49,36.87 v4(219.54,36.87) 219.88,36.87 220.67,36.09 220.67,36.04 221.81,34.89 223.41,34.89 224.07,35.55 v4(224.07,37.23) 224.61,37.76 v2(225.32,37.76) ; v2(156.99,96.83) 157.32,96.83 158.01,97.52 PR31.2 ; v2(164.61,94.6) 164.61,94.56 164.31,94.26 PR7.2 164.94,93.36 PR5.1
  IN1 w0.254: v2(156.99,96.83) 156.99,100.67 154.17,103.49 154.17,108.45 154.87,109.15 v2(154.87,112.5)
  IN1 w0.508: v2(211.78,51.17) 211.55,50.95 204.74,50.95 203.9,50.1 198.27,50.1 197.91,50.46 195.45,50.46 195,50.01 ; 195,50.01 194.65,49.66 v2(194.65,49.23) ; 195,50.01 193.94,51.07 190.62,51.07 188.79,52.9 186.64,52.9 182.75,56.79 182.75,57.02 181.29,58.48 181.29,58.63 179.59,60.33 179.59,60.95 177.12,63.42 177.12,63.53 174.83,65.83 174.34,66.31 173.86,66.79 170.96,69.69 170.96,71.84 166.77,76.03 166.77,92.4 164.61,94.56 v2(164.61,94.6)
  IN2 w0.508: v2(164.61,94.6) 164.61,94.12 163.66,93.17 163.66,91.78 162.96,91.08 161.27,91.08 160.52,91.84 160.52,93.97 160.46,94.02 160.46,94.12 160.1,94.48 159.64,94.48 157.3,96.83 v2(156.99,96.83) ; v2(211.78,51.17) 215.95,51.17 215.97,51.15 216.48,51.15 216.5,51.17 221.97,51.17 223.59,49.55 223.59,39.49 v2(225.32,37.76)
  BOTTOM w0.508: PR729.1 218.18,36.57 v2(218.1,36.49) ; PC742.2 155.71,112.44
  vias: v2(156.71,118.14) v2(156.71,117.51) v2(157.41,118.14) v2(157.41,117.51) v2(158.05,118.14) v2(158.05,117.51) v2(158.63,118.14) v2(158.63,117.51) v2(159.16,117.81)
+19VB: length 164.9
  TOP w0.508: 173.26,46.25 175.03,46.25 175.2,46.07 PR102.2
  TOP w0.762: 174.2,55.01 174.2,47.19 173.26,46.25 173.26,45.97 172.55,45.26 172.55,44.34 171.76,43.55 171.39,43.55 171.22,43.39 169.41,43.39 169.22,43.58 166.01,43.58 165.12,42.69 165.12,41.55 164.01,40.44
  TOP w3.048: 167.41,132.48 155.29,132.48
  IN1 w1.524: 171.22,131.02 171.22,128.86 167.98,118.95 167.98,113.37
  BOTTOM w1.016: 170.33,133.18 131.45,133.18 128.47,130.19 121.2,130.19 121.19,130.21
  BOTTOM w2.032: 167.76,114.04 167.76,120.24 172.3,132.48
  BOTTOM w3.048: 167.4,81.52 167.4,83.68 167.26,83.82 167.26,106.93 ; 168.04,75.46 173.95,65.87 175.41,63.65
  vias: v2(63.76,133.94) v2(63.76,133.3) v2(64.46,133.94) v2(64.46,133.3) v2(65.16,133.94) v2(65.16,133.3) v2(65.86,133.94) v2(65.86,133.3) v2(113.81,130) v2(113.81,129.37) v2(114.12,128.82) v2(114.3,129.68) v2(158.43,39.79) v2(158.52,39.21) v2(158.52,38.63) v2(167.72,112.22) v2(167.72,111.59) v2(167.72,110.95) v2(168.42,112.22) v2(168.42,111.59) v2(168.42,110.95) v2(169.69,134) v2(169.76,132.29) v2(170.39,134) v2(170.45,132.29) v2(171.09,134) v2(174.07,56.47) v2(174.06,55.86) v2(174.68,55.87) v2(195.12,43.12) v2(195.23,43.69) v2(195.4,42.6) v2(195.7,43.13) v2(195.82,43.71) v2(195.98,42.61) v2(196.36,43.5) v2(204.15,39.35) v2(204.15,38.71) v2(204.85,39.35) v2(204.85,38.71) v2(205.54,39.35) v2(205.54,38.71) v2(206.24,39.35) v2(206.24,38.71) v2(220.81,53.55) v2(221.44,53.55) v2(222.21,53.55) v2(222.21,52.91) v4(204.68,37.67)
+19VB_1.2V: length 26
  TOP w0.254: v2(86.32,98.25) 86.38,98.25 87.27,99.14 90.95,99.14 92.35,100.54 92.35,105.62 91.02,106.95 85.24,106.95 83.01,109.17 80.95,109.17 v2(80.8,109.02)
  BOTTOM w0.254: PR208.1 85.87,98.7 v2(86.32,98.25)
  vias: v1(77.68,107.71) v2(78.73,107.42) v2(79.03,106.65) v2(79.35,107.42) v2(79.42,108.18)
+19VB_+1.35VGPU:
  vias: v1(156.36,95.71)
+19VB_APU: length 0.9
  TOP w0.102: v2(159.09,66.63) 159.53,66.63 v1(159.85,66.31)
  vias: v2(159.09,67.26) v2(159.15,63.58) v2(159.15,62.95) v2(159.15,62.25) v2(159.15,61.61) v2(159.15,59.45) v2(159.15,58.82)
+19VB_GPU:
  vias: v2(61.11,130.38) v2(61.49,129.81) v2(61.81,130.38) v2(62.12,129.81) v2(62.12,112.48) v2(62.82,112.48) v2(63.52,112.48) v2(64.22,112.48) v2(65.93,112.98) v2(66.57,112.98) v4(63.27,129.43)
+19VB_VDDP_ALWP:
  vias: v1(152.55,34.56) v2(152.17,40.75) v2(152.81,40.75) v2(153.45,40.75) v2(154.04,40.75)
+V18R: length 4
  TOP w0.102: v2(177.82,37.23) v1(177.44,36.85)
  TOP w0.508: v2(177.82,37.23) 177.9,37.31 177.9,38.03 RE50.2 RE69.2
  BOTTOM w0.254: UE1.124 178.42,37.57 178.07,37.23 v2(177.82,37.23)
+VDD_CT: length 13.5
  TOP w0.508: v2(101.01,115.27) CV61.1 99.91,115.08 LV3.2
  IN1 w0.508: v2(101.01,115.27) 101.18,115.27 102.38,116.48 104.67,116.48 104.8,116.6 107.04,116.6 107.1,116.54 107.34,116.54 107.72,116.16 v2(107.72,115.92)
  BOTTOM w0.254: v2(109.02,115.18) 108.54,114.7 UV1.AB20 ; v2(109.02,115.18) 109.3,115.47 109.5,115.66 UV1.AA21 ; v2(109.02,115.18) UV1.AB21 108.28,115.92 v2(107.72,115.92) ; v2(109.02,115.18) UV1.AA20
  vias: v1(107.46,115.35)
+VDD_TOUCH:
  vias: v1(223.92,32.4) v2(225.06,30.56) v2(225.7,30.56)
+VDDCR_FCH_ALW: length 12.5
  IN1 w1.016: 126.91,22.88 126.91,21.86 126.27,21.23 123.5,21.23 122,19.73 122,16.65 120.12,14.77
  vias: v1(128.23,38.82) v2(119.27,14.41) v2(119.27,13.8) v2(122.96,45.17) v2(123.65,45.26) v2(126.52,23.74) v2(127.12,23.75)
+VDDR3: length 4.5
  BOTTOM w0.254: v2(107.41,113.41) 107.43,113.43 108.23,113.43 UV1.AB18 UV1.AA18 UV1.AA17 109.11,112.31 v2(109.01,112.31) 108.62,112.7 UV1.AB17
  vias: v1(99.65,113.62)
GND: length 2726.8
  TOP w0.102: v4(112.42,99.27) 112.46,99.22 v2(112.46,98.48) ; v2(105.5,13.98) 105.5,13.3 v4(105.49,13.29) ; v2(150.01,81.36) v4(149.31,81.36) ; CC1006.2 v4(123.59,25.85) ; v4(9.16,6.75) 8.72,7.19 v2(8.66,7.19)
  TOP w0.127: v2(55.96,120.98) 55.97,120.98 56.92,120.03 56.98,120.03 57.04,119.97 57.17,119.97 57.23,119.91 57.55,119.91 v2(57.74,119.72)
  TOP w0.254: CV93.2 121.17,105.22 121.61,105.67 v2(121.75,105.67) ; v2(111.83,105.86) 111.56,105.86 CV114.2 ; U2407.6 v2(78.3,11.97) ; RPC45.4 112.81,88.61 v2(113.05,88.85) 113.31,88.6 RPC45.3 ; RPH2.6 82.26,80.79 v2(81.94,81.11) 82.11,81.29 RPH2.5 ; CV28.2 104.41,115.06 RV12.2 104.1,115.68 v2(104.1,117.11) ; CV53.2 117.4,114.07 CV89.2
  TOP w0.305: v2(164.96,91.91) 164.93,91.91 164.92,91.9 164.49,91.9 164.25,92.14 PQ1.4 ; CV35.2 104.66,110.77 103.98,111.45 103.53,111.45 103.05,110.97 CV26.2 ; PQ2.1 157.52,102.27 157.91,102.66 158.31,102.66 158.85,103.2 PR29.2 ; PQ1.1 162.95,90.15 163.26,89.84 PR2.2
  TOP w0.356: PC753.1 216.07,49.1 PQ720.3 216.07,50 215.67,50.4 v2(215.67,50.41) ; 85.24,95.34 84.95,95.06 UV4.4 ; PQ2.4 156.22,99.57 v2(155.72,99.08) ; v2(19.9,39.52) 19.83,39.45 EU2603.3 ; PD3.1 v2(217.95,12.78) ; PD2.1 v2(214.65,11.26)
  TOP w0.381: v2(106.04,109.9) 106.04,110.52 CV21.2 106.73,110.55 CV20.2 ; v2(116.59,83.69) 116.97,84.08 UC65.3 ; v2(121.53,61.12) 121.37,60.96 CC1078.2 ; PQ721.3 217.97,49.19 v2(217.83,49.04) ; v2(121.88,47.52) 121.42,47.07 RC641.2 ; UC61.3 138.09,54.26 137.71,54.64 v2(137.71,54.74) ; CV74.2 112.01,107.67 111.77,107.43 v2(111.77,107.32) 111.4,107.32 CV100.2 ; v2(108.1,120.3) 108.06,120.34 CV80.2 ; v2(137.98,42.12) 137.98,42.54 137.7,42.82 CC31.1 ; v2(107.41,112.41) 107.41,112.58 106.83,113.16 CV29.2 RV9.2 ; v2(120.42,84.35) 120.42,84.09 121.07,83.44 UC62.3
  TOP w0.406: EU2601.3 v2(19.51,59.14) ; v2(113.88,82.34) 113.88,82.44 113.64,82.68 UC64.3
  TOP w0.508: CC99.1 CC29.2 94.5,56.6 RC8.1 94.51,57.36 94.89,57.74 v2(95.95,57.74) ; CA31.2 CA39.2 28.84,34.18 28.52,34.5 v2(27.97,34.5) CA22.1 ; v2(43.96,110.44) CW14.2 CW12.2 ; v2(171.34,44.81) 171.25,44.72 170.58,44.72 PC112.2 ; v2(120.73,60.72) 120.16,60.15 CC1084.2 ; RC541.2 RC644.2 135.21,54.24 v2(135.41,54.24) ; CU22.2 169.55,14 v2(169.49,13.94) ; JPWR1.8 162.4,113.55 161.16,112.31 JPWR1.6 v2(157.99,112.31) ; RI20.2 v2(31.72,94.19) RI17.2 ; CC1085.2 119.97,43.52 v2(119.53,43.96) 119.34,44.15 119.34,44.2 RC90.2 ; CV11.2 RV13.2 102.63,113.73 v2(101.95,114.4) ; v2(195.09,38.82) 195.23,38.68 C49.2 ; PR122.2 v2(192.31,38.68) ; RC118.2 109.3,63.63 v2(109.7,63.23) 110,63.53 CC51.2 ; v2(61.3,132.99) 61.86,132.43 C41.2 ; CA5.2 35.33,34.82 v2(35.71,34.44) 36.09,34.05 CA1.2 ; PC751.1 v2(217.83,49.04) 217.78,49.04 217.19,49.63 PC790.2 ; v2(155.83,120.67) PC4.2 PC3.2 ; v2(115.2,105.11) 114.54,104.45 CVT90.1 ; v2(115.2,105.11) 115.8,105.11 CV124.2 ; v2(115.2,105.11) 115.2,104.59 CV82.2 ; LE4.1 169.12,26.05 v2(169.41,25.76) ; v2(195.62,46.31) 195.6,46.33 CS10.2 ; v2(68.96,127.03) 67.95,128.03 PC1109.2 ; SW1.1 164.94,85.43 164.12,84.6 164.12,83.67 v2(164.76,83.03) ; CS7.2 v2(195.71,15) ; v2(195.78,16.2) 195.55,16.43 CS6.2 ; CL12.1 28.42,109.16 v2(28.4,109.17) ; PR308.2 v2(158.52,27.13) 158.96,26.69 PR311.1 ; CS11.2 v2(196.87,51.71) ; PQ3.3 159.71,102.38 159.71,103.21 ; CC1098.2 115.85,61.61 v2(115.22,61.61) ; v2(82,91.71) 81.3,91.71 CV183.1 ; CU10.2 27.44,57.52 v2(26.93,58.03) ; CU19.2 v2(18.31,41.48) ; v2(57.25,109.97) 56.76,110.46 C6.2 ; CD208.2 CD214.2 63.14,18.81 v2(63.14,18.82) ; CU15.2 v2(27.71,37.1) ; v2(14.83,89.73) CI9.2 CI13.2 ; v2(78.05,96.93) CV184.1 77.97,96.23 CV185.1 ; 124.09,87.2 v2(124.09,87.12) 124.09,86.56 CV91.2 ; v2(126,22.31) CC1109.2 CC1108.2 ; 159.71,103.21 159.71,103.71 v2(159.43,103.99) ; 159.71,103.21 159.7,103.22 PR29.2 ; RA19.2 v2(4.72,27.39) ; v2(192.3,41.17) 192.56,41.43 PC128.2 ; CE10.1 165.35,34.35 164.87,33.86 164.8,33.86 v2(164.68,33.74) ; RC929.2 RC953.2 RC707.1 RC950.2 v2(138.51,44.98) ; v2(32.91,36.09) 32.53,35.71 CA15.2 ; CA14.2 40.6,13.21 CA13.2 v2(39.9,13.99) ; RA45.1 v2(18.12,26.94) ; v2(164.42,36.91) 164.49,36.91 164.55,36.85 CE3.2 ; CA2.2 33.29,32.48 CA16.2 33.68,32.53 v2(33.99,32.85) ; RC401.2 116.75,62.81 116.35,63.2 v2(116.35,63.26) RC400.2 ; v2(121.5,103.46) 121.5,103.46 121.55,103.41 121.55,103.34 121.83,103.07 CV92.2 CV86.2 ; C551.2 101.42,4.43 v2(102.83,3.01) ; v2(54.37,119.34) 54.83,118.88 PC1124.2 PC1131.2 ; v2(154.91,107.4) 154.38,107.92 CV227.2 154.61,108.22 EC2902.2 ; v2(103.84,118.85) 103.84,118.85 RV160.2 ; PC1.2 156.25,123.91 v2(155.79,123.45) 156.28,122.96 PC2.2 ; CU21.2 v2(174.52,8.27) ; RV75.1 v2(86.25,91.94) ; CV27.2 100.46,109.69 v2(99.92,109.69) 99.91,109.7 99.91,110.38 100.16,110.64 100.48,110.64 ; v2(114.66,99.97) 115.29,100.6 RV41.1 ; CV155.2 v2(154.79,119.96) ; CV34.2 CV33.2 106.73,107.88 106.63,107.78 106.63,107.74 v2(106.48,107.59) ; v2(161.82,67.01) 162.57,66.26 PR1078.2 ; 171.99,55.69 171.42,56.27 PR1086.1 ; 171.99,55.69 171.99,55.72 172.4,56.13 v2(172.4,56.15) ; 171.99,55.69 PC1010.1 ; CD193.2 47.57,62.01 v2(47.52,62.06) ; CV66.2 109.05,114.55 108.75,114.55 108.6,114.7 v2(107.8,114.7) 107.8,114.18 CV65.2 ; CV213.2 CV211.2 154.06,114.26 v2(153.8,114) ; C2620.2 C2621.2 125.88,4.53 v2(125.75,4.65) ; R37.2 v2(87.65,7.26) ; PC753.1 216.12,48.18 PR755.1 ; C17.2 227.87,44.47 v2(227.52,44.11) ; CU9.2 CU8.2 v2(25.5,66.36) ; CV210.2 v2(154.77,126.15) ; v2(103.95,107.61) 104.16,107.61 CV30.2 ; v2(104.73,20.78) 104.05,20.78 RC13.1 RC706.1 ; PR731.2 v2(218.02,39.26) ; v2(154.15,94.08) CV225.2 ; CV81.2 117.5,102.38 v2(116.5,103.39) ; v2(119.62,100.2) 119.15,100.67 RV38.2 CV85.2 ; CC935.2 84.16,34.28 v2(84.56,34.67) ; PC1065.2 167.98,68.6 167.6,68.22 167.6,66.97 v2(167.66,66.91) PC1059.2 ; v2(63.14,19.75) 63.14,20.34 62.63,20.85 CD226.2 ; CC1139.2 116.53,54.3 117.04,53.79 v2(117.17,53.79) ; CI14.2 15.77,86.43 CI11.2 17.44,86.43 v2(17.57,86.3) ; CS5.2 v2(192.6,16.26) ; v2(101.97,110.91) 102.02,110.96 102.76,110.96 CV26.2 ; PR1106.1 54.95,129.18 v2(54.95,129.18) 55.78,129.18 PC1111.2 ; CW13.2 60.98,110.05 v2(60.55,110.48) ; CE14.2 v2(179.85,21.54) ; v2(159.6,57.99) 160.17,57.42 PC1055.2 ; Q85.3 109.51,7.08 v2(109.61,6.98) ; v2(218.66,45.84) 218.66,45.51 PC748.2 ; PC769.1 PC768.1 203.93,42.44 v2(203.73,42.24) ; v2(30.03,91.46) CI10.2 RI16.2 ; v2(212.5,49.75) 212.44,49.69 PR779.1 212.44,48.15 PR751.1 ; CC1110.2 122.58,43.88 v2(122.92,43.88) 122.92,43.48 CC1118.2 ; CU13.2 v2(19.07,61.11) ; C2498.2 v2(73.63,16.09) ; C40.1 v2(128.29,135.64) ; RV49.2 CV390.2 v2(155.02,100.75) ; CW17.2 60.78,104.16 v2(60.98,103.95) ; v2(110.15,58.73) 110.08,58.65 CC1010.2 ; v2(93.3,73.72) 92.45,74.57 JHDT1.7 ; PQ712.3 215.55,34.94 v2(214.84,34.94) ; 85.24,95.34 RV74.1 v2(85.24,96.47) ; v2(198.27,46.59) 197.3,46.59 CS12.2 ; CV178.2 117.59,110.69 117.83,110.93 v2(117.83,111.16) ; CC999.1 138.63,51.83 v2(138.01,51.83) CC912.2 ; RA18.2 v2(27.72,12.26) ; CC23.2 CC1000.1 v2(141.31,52.66) ; CW11.2 v2(59.71,104.79) ; UI5.2 v2(22.37,65.68) ; CA29.2 11.78,9.78 12.21,9.35 13.37,9.35 CA30.2 14,9.78 14.36,9.42 15.52,9.42 16.4,10.31 v2(16.4,11.51) 16.43,11.49 DA4.1 ; CV15.2 RV16.2 102.38,117.77 v2(101.68,117.77) ; EU2602.1 v2(18.03,54.15) ; PC1063.2 v2(160.55,59.2) ; PR1120.1 48.17,119.63 PR1117.1 PC1117.1 v2(47.58,120.48) ; PC1101.2 v2(47.52,124.93) ; C553.2 104.87,3.83 104.87,3.05 v2(104.81,2.99) ; CC934.2 84.16,32 v2(84.66,31.51) ; CC166.2 CC923.2 v2(134.72,39.35) ; C18.2 225.39,33.61 v2(224.95,34.05) ; CA6.2 v2(35.26,33.55) ; RC49.1 CC15.2 110.26,22.56 v2(110,22.31) ; PR2.2 163.23,89.3 161.75,89.3 v2(161.7,89.35) 161.82,89.46 PR10.1 ; PC1128.2 56.58,114.69 v2(56.22,114.32) 56.09,114.2 PC1129.2 ; v2(113.8,112.29) 113.48,111.97 113.48,111.56 CV103.2 ; v2(180.17,45.42) 180.04,45.29 PR103.2 ; CW15.2 59.22,109.7 58.64,110.27 v2(58.64,110.53) ; CV96.2 124.24,89.38 123.88,89.02 123.88,88.12 CV84.2 124.1,87.9 124.1,87.2 ; PR1067.2 PC1058.2 162.67,71.34 v2(162.46,71.14) ; PQ711.3 v2(220.22,23.37) ; PC1004.1 v2(170.84,52.34) ; v2(222.97,46.05) 222.98,46.06 C2.2 C3.2 ; v2(120.71,63.21) 121.39,63.89 CC1096.2 ; v2(54.04,129.08) 54.06,129.07 PR1105.1 53.12,128.43 PR1140.2 ; v2(169.07,39.92) 169.18,40.02 CE42.2 ; v2(172.84,62.84) 172.8,62.81 PR1087.1 ; v2(17.39,81.4) 16.78,80.79 CI17.2 CI16.2 ; CA28.2 9.72,9.78 9.29,9.35 8.14,9.35 CA27.2 v2(6.64,9.78) ; v2(37.17,24.03) 37.17,24.66 CA3.2 36.33,24.72 CA4.2 ; v2(168.37,42.33) 168.37,42.11 168.17,41.91 CE41.2 ; v2(116.95,6.88) 116.79,6.71 QE4.3 ; v2(31.26,20.53) RA21.2 30.11,19.78 CA25.1 ; CU23.2 171.34,19.56 UU3.2 171.34,16.91 v2(171.66,16.59) ; v2(195.35,26.18) 195.33,26.17 RS37.2 ; PC931.2 118.87,57.69 v2(119.2,58.02) ; v2(178.71,37.17) 178.71,37.97 CE17.2 ; JHDT1.17 93.68,80.92 94.04,80.56 94.04,79.83 RH24.1 93.42,79.79 v2(93.3,79.9) ; RE58.2 113.25,9.31 Q8.3 113.55,5.54 116.58,5.54 v2(117.16,4.96) ; C5216.2 163.29,8.54 v2(163.15,8.4) ; CE20.2 EC2901.2 161.74,93.78 ED2901.2 161.91,94.76 v2(162.37,95.22) ; v2(129.31,127.97) 129.29,127.96 C35.1 ; RA17.2 v2(19.57,32.99) ; CV198.2 v2(154.77,127.16) ; CI18.2 v2(17.14,78.1) ; PJPDC1.8 v2(156,127.87) ; CC1016.2 111.3,58.17 v2(111.17,58.3) ; CX1.2 v2(226.97,33.42) ; PC604.2 v2(40.54,103.9) ; RV40.1 118.19,86.7 117.43,87.46 v2(117.43,87.79) 117.62,87.98 RV17.1 ; v2(119.61,60.91) 119.77,61.07 PC932.2 ; CV182.1 v2(82.41,96.5) ; EU2604.1 v2(16.85,35.45) ; C39.1 96.04,132.4 v2(96.76,131.69) ; v2(48.67,128.47) PR1111.1 49.32,128.46 PR1101.1 ; PR732.2 v2(216.52,37.79) ; U1.2 v2(228.08,46.96) ; CV394.2 v2(154.73,123.29) ; CH2.2 95.22,76.28 RH22.1 RH23.1 94.89,77.74 v2(95.4,77.23) ; CV61.2 v2(100.98,116.67) ; CS15.2 v2(197.38,13.67) ; CC1095.2 120.51,52.98 v2(120.53,52.96) ; PR33.1 v2(156.31,97.6) ; C4.2 v2(228.11,53.93) ; v2(161.71,106.76) 162.4,106.07 JPWR1.7 ; C5.2 v2(229.38,53.93) ; v2(118.54,103.51) 118.63,103.43 CV97.2 ; v2(54.38,52.66) 53.93,52.22 53.93,51.83 53.47,51.38 RD28.1 ; CW10.2 45.23,104.48 v2(44.98,104.22) ; PC1110.2 v2(58.44,128.23) ; v2(17.42,83.74) CI12.2 CI15.2 ; RD25.1 72.3,51.12 v2(72.22,51.2) ; v2(26.17,34.18) 26.17,33.75 CA17.2 ; PC1037.2 v2(162.63,69.11) ; v2(183.09,34.31) 182.39,33.61 CE4.2 ; CE13.1 182.64,27.85 v2(182.98,27.85) ; PJPDC1.7 v2(169.25,129.42) ; CV39.2 103.99,120.17 v2(104.89,121.07) ; CU18.2 v2(19.58,41.48) ; RA20.2 v2(15.77,27.13) ; v2(108.17,119.62) 108.17,119.1 RV59.1 108.11,118.7 RV29.1 ; CU20.2 v2(172.99,7.19) ; RC692.1 v2(137.97,50.82) ; RW8.2 v2(50.29,110.46) ; CC1129.1 134.72,36.96 v2(134.67,37.01) ; CA8.2 v2(30.69,36.91) ; CV221.2 v2(146.62,94.06) ; PR32.2 159.02,97.11 v2(158.5,96.59) ; v2(154.71,122.4) RV53.2 ; RW13.2 v2(57.87,105.5) ; CV166.2 v2(154.31,98.49) ; PR1005.2 v2(166.14,52.72) ; PR1130.2 60.29,118.19 59.78,117.68 v2(59.52,117.68) ; CU14.2 v2(17.8,61.61) ; CW16.2 v2(43.96,104.86)
  VCC w0.203: JLAN1.10 11.73,118.1 ; JLAN1.10 11.73,118.77 ; JLAN1.10 9.37,118.1 ; JLAN1.10 9.37,118.77 ; JLAN1.10 10.55,117.43 ; JLAN1.10 9.37,117.43 ; JLAN1.10 11.73,117.43 ; JLAN1.10 10.55,118.77 ; JHDMI1.21 3.95,78.78 ; JHDMI1.21 2.67,77.85 ; JHDMI1.21 2.67,78.78 ; JHDMI1.21 5.23,76.92 ; JHDMI1.21 5.23,78.78 ; JHDMI1.21 2.67,76.92 ; JHDMI1.21 5.23,77.85 ; JHDMI1.21 3.95,76.92 ; JUSB2.12 6.96,45.85 ; JUSB2.12 4.22,46.73 ; JUSB2.12 4.22,45.85 ; JUSB2.12 5.59,46.73 ; JUSB2.12 6.96,46.73 ; JLAN1.9 2.75,118.77 ; JLAN1.9 3.93,118.77 ; JLAN1.9 1.57,118.1 ; JLAN1.9 3.93,118.1 ; JLAN1.9 3.93,117.43 ; JLAN1.9 1.57,118.77 ; JLAN1.9 2.75,117.43 ; JLAN1.9 1.57,117.43 ; 4.22,50.97 JUSB1.11 ; JUSB1.11 4.22,51.85 ; JUSB1.11 6.96,50.97 ; JUSB1.11 5.59,50.97 ; JUSB1.11 6.96,51.85 ; H2.1 8.7,124.23 ; H2.1 8.7,120.37 ; H2.1 10.12,123.72 ; H2.1 7.28,120.88 ; H2.1 10.63,122.3 ; H2.1 10.12,120.88 ; H2.1 7.28,123.72 ; H2.1 6.77,122.3 ; 11.62,46.73 JUSB2.13 ; JUSB2.13 13.09,44.97 ; JUSB2.13 11.62,45.85 ; JUSB2.13 14.56,44.97 ; JUSB2.13 13.09,46.73 ; JUSB2.13 14.56,45.85 ; JUSB2.13 14.56,46.73 ; 124.78,31.01 HCPU4.1 ; HCPU4.1 129.94,31.01 ; HCPU4.1 129.94,33.3 ; HCPU4.1 127.36,28.72 ; HCPU4.1 124.78,33.3 ; HCPU4.1 127.36,33.3 ; HCPU4.1 124.78,28.72 ; HCPU4.1 129.94,28.72 ; 1.42,95.22 JHDMI1.23 ; JHDMI1.23 3.98,97.08 ; JHDMI1.23 3.98,95.22 ; JHDMI1.23 1.42,96.15 ; JHDMI1.23 3.98,96.15 ; JHDMI1.23 1.42,97.08 ; JHDMI1.23 2.7,95.22 ; JHDMI1.23 2.7,97.08 ; 13.09,29.27 JUSB2.10 ; JUSB2.10 14.56,30.15 ; JUSB2.10 14.56,29.27 ; JUSB2.10 11.62,29.27 ; JUSB2.10 11.62,30.15 ; JUSB2.10 13.09,31.03 ; JUSB2.10 14.56,31.03 ; H12.1 6.73,5.63 ; H12.1 3.27,5.63 ; H12.1 6.73,1.57 ; H12.1 6.73,3.6 ; H12.1 3.27,1.57 ; H12.1 3.27,3.6 ; H12.1 5,5.63 ; H12.1 5,1.57 ; JHDMI1.20 13.43,78.82 ; JHDMI1.20 10.87,80.68 ; JHDMI1.20 13.43,80.68 ; JHDMI1.20 10.87,79.75 ; JHDMI1.20 12.15,80.68 ; JHDMI1.20 10.87,78.82 ; JHDMI1.20 13.43,79.75 ; JHDMI1.20 12.15,78.82 ; 11.54,85.54 JHDMI1.8 ; JHDMI1.8 12.46,86.46 ; JHDMI1.8 11.54,86.46 ; JHDMI1.8 12.46,85.54 ; JHDMI1.8 12.58,86 ; JHDMI1.8 11.42,86 ; 1.57,100.63 JLAN1.12 ; JLAN1.12 1.57,101.97 ; JLAN1.12 3.93,101.3 ; JLAN1.12 1.57,101.3 ; JLAN1.12 2.75,100.63 ; JLAN1.12 3.93,100.63 ; JLAN1.12 3.93,101.97 ; JLAN1.12 2.75,101.97 ; H11.1 52.3,135.73 ; H11.1 54.33,133.7 ; H11.1 52.3,131.67 ; H11.1 53.79,132.21 ; H11.1 53.79,135.19 ; H11.1 50.81,135.19 ; H11.1 50.81,132.21 ; H11.1 50.27,133.7 ; 10.87,93.32 JHDMI1.22 ; JHDMI1.22 13.43,95.18 ; JHDMI1.22 10.87,95.18 ; JHDMI1.22 13.43,94.25 ; JHDMI1.22 13.43,93.32 ; JHDMI1.22 10.87,94.25 ; JHDMI1.22 12.15,95.18 ; JHDMI1.22 12.15,93.32 ; 136.5,88.32 H10.1 ; H10.1 136.5,92.68 ; H10.1 138.1,88.9 ; H10.1 138.1,92.1 ; H10.1 134.9,92.1 ; H10.1 138.69,90.5 ; H10.1 134.9,88.9 ; H10.1 134.32,90.5 ; 12,82.42 JHDMI1.2 ; JHDMI1.2 12.46,83.46 ; JHDMI1.2 11.42,83 ; JHDMI1.2 12.58,83 ; JHDMI1.2 11.54,83.46 ; JHDMI1.2 11.54,82.54 ; JHDMI1.2 12.46,82.54 ; 9.99,90.04 JHDMI1.17 ; JHDMI1.17 9.99,90.96 ; JHDMI1.17 11.03,90.5 ; JHDMI1.17 10.91,90.04 ; JHDMI1.17 10.91,90.96 ; JHDMI1.17 9.87,90.5 ; 14.08,35.1 JUSB2.4 ; JUSB2.4 14.68,33.72 ; JUSB2.4 15.46,34.5 ; JUSB2.4 14.08,33.9 ; JUSB2.4 13.9,34.5 ; JUSB2.4 14.68,35.28 ; JUSB2.4 15.28,35.1 ; JUSB2.4 15.28,33.9 ; 11.62,50.97 JUSB1.10 ; JUSB1.10 11.62,51.85 ; JUSB1.10 14.56,52.73 ; JUSB1.10 13.09,50.97 ; JUSB1.10 14.56,51.85 ; JUSB1.10 13.09,52.73 ; JUSB1.10 14.56,50.97 ; 11.62,68.43 JUSB1.13 ; JUSB1.13 14.56,66.67 ; JUSB1.13 14.56,67.55 ; JUSB1.13 13.09,66.67 ; JUSB1.13 11.62,67.55 ; JUSB1.13 13.09,68.43 ; JUSB1.13 14.56,68.43 ; JLAN1.11 11.73,101.3 ; JLAN1.11 9.37,100.63 ; JLAN1.11 9.37,101.3 ; JLAN1.11 10.55,100.63 ; JLAN1.11 11.73,100.63 ; JLAN1.11 10.55,101.97 ; JLAN1.11 9.37,101.97 ; JLAN1.11 11.73,101.97 ; JUSB2.7 13.96,38 ; JUSB2.7 13.78,38.6 ; JUSB2.7 13.78,37.4 ; JUSB2.7 13.18,38.78 ; JUSB2.7 13.18,37.22 ; JHDMI1.5 10.91,84.04 ; JHDMI1.5 9.99,84.04 ; JHDMI1.5 10.91,84.96 ; JHDMI1.5 9.87,84.5 ; JHDMI1.5 11.03,84.5 ; JHDMI1.5 9.99,84.96 ; 16.98,2.88 H1.1 ; H1.1 18.4,6.23 ; H1.1 19.82,5.72 ; H1.1 18.4,2.37 ; H1.1 20.33,4.3 ; H1.1 19.82,2.88 ; H1.1 16.98,5.72 ; H1.1 16.47,4.3 ; H8.1 88.5,113.2 ; H8.1 88.5,110 ; H8.1 85.3,113.2 ; H8.1 89.08,111.6 ; H8.1 85.3,110 ; H8.1 86.9,109.42 ; H8.1 84.72,111.6 ; H8.1 86.9,113.78 ; 13.9,56.2 JUSB1.4 ; JUSB1.4 14.68,56.98 ; JUSB1.4 14.08,56.8 ; JUSB1.4 15.28,55.6 ; JUSB1.4 14.68,55.42 ; JUSB1.4 15.28,56.8 ; JUSB1.4 14.08,55.6 ; JUSB1.4 15.46,56.2 ; 100.29,29.34 HCPU2.1 ; HCPU2.1 101.96,33.3 ; HCPU2.1 99.67,31.01 ; HCPU2.1 103.63,32.68 ; HCPU2.1 103.63,29.34 ; HCPU2.1 101.96,28.72 ; HCPU2.1 104.25,31.01 ; HCPU2.1 100.29,32.68 ; JHDMI1.11 10.91,87.04 ; JHDMI1.11 11.03,87.5 ; JHDMI1.11 9.99,87.96 ; JHDMI1.11 9.99,87.04 ; JHDMI1.11 10.91,87.96 ; JHDMI1.11 9.87,87.5 ; HCPU1.1 104.25,78.59 ; HCPU1.1 101.96,78.59 ; HCPU1.1 99.67,73.43 ; HCPU1.1 99.67,76.01 ; HCPU1.1 104.25,76.01 ; HCPU1.1 101.96,73.43 ; HCPU1.1 99.67,78.59 ; HCPU1.1 104.25,73.43 ; 4.22,29.27 JUSB2.11 ; JUSB2.11 5.59,29.27 ; JUSB2.11 6.96,30.15 ; JUSB2.11 6.96,29.27 ; JUSB2.11 4.22,30.15 ; 4.22,67.55 JUSB1.12 ; JUSB1.12 6.96,68.43 ; JUSB1.12 6.96,67.55 ; JUSB1.12 5.59,68.43 ; JUSB1.12 4.22,68.43 ; JUSB1.7 13.78,59.1 ; JUSB1.7 13.96,59.7 ; JUSB1.7 13.18,58.92 ; JUSB1.7 13.18,60.48 ; JUSB1.7 13.78,60.3 ; 111.9,136.1 H9.1 ; H9.1 111.9,132.9 ; H9.1 115.1,136.1 ; H9.1 111.32,134.5 ; H9.1 115.69,134.5 ; H9.1 113.5,132.32 ; H9.1 115.1,132.9 ; H9.1 113.5,136.69
  IN1 w0.254: v2(55.96,120.98) 56.48,120.98 v2(57.74,119.72)
  IN2 w0.127: v2(53.42,2.62) 53.42,2.49 53.61,2.3 54.57,2.3 55.84,3.57 60.03,3.57 61.3,2.3 97.43,2.3 99.4,4.27 106.57,4.27 107.65,3.19 118.13,3.19 v2(118.49,3.56) 118.95,4.02 119.4,4.02 120.16,3.26 122.19,3.26 123.85,4.91 125.5,4.91 v2(125.75,4.65) 125.88,4.65 126.64,5.42 129.84,5.42 v2(129.97,5.29) 130.89,5.29 v2(134.89,9.29) 135.59,9.29 136.61,10.31 146.45,10.31 149.05,7.7 149.05,6.75 149.75,6.05 154.33,6.05 155.53,7.26 156.42,7.26 v2(156.7,7.54) 157.03,7.54 158.07,6.5 168.42,6.5 174.14,12.21 174.88,12.21 176.74,12.21 178.26,13.73 178.26,14.05 179.15,14.94 186.01,14.94 187.85,13.1 189.79,13.1 v2(191.86,15.17) 191.86,15.04 193.86,13.04 196.43,13.04 198.65,10.81 214.21,10.81 v2(214.65,11.26) 214.65,11.13 214.97,10.81 218.9,10.81 221.13,13.04 221.13,22.43 221.7,23.01 221.7,30.18 v2(221.53,30.35) 221.53,34.46 222.02,34.94 222.02,36.02 222.33,36.34 223.48,36.34 223.79,36.02 223.79,33.72 222.84,32.77 222.84,21.99 v2(222.33,21.48) v2(222.33,20.85) v2(222.33,20.21) v2(222.33,19.51) v2(222.33,18.81) 222.4,18.75 222.4,12.27 219.92,9.8 198.2,9.8 196.04,11.96 187.28,11.96 185.31,13.92 179.53,13.92 179.28,13.67 179.28,13.1 177.44,11.26 174.65,11.26 168.55,5.16 159.02,5.16 158.71,4.84 v2(157.73,4.84) 157.73,4.93 157.06,5.61 155.72,5.61 155.02,4.91 149.5,4.91 149.25,5.16 149.18,5.16 147.7,6.64 v2(147.7,7) 145.47,9.23 136.99,9.23 133.19,5.43 v2(133.19,3.27) 133.13,3.27 132.85,3.55 124.95,3.55 124.73,3.76 124.23,3.76 122.7,2.24 107.21,2.24 106.46,2.99 v2(104.81,2.99) 104.48,3.32 103.14,3.32 v2(102.83,3.01) 102.7,2.88 99.72,2.88 98.19,1.35 52.47,1.35 v2(51.46,2.37) ; v2(148.17,45.36) 148.17,44.53 148.58,44.11 159.19,44.11 159.79,43.52 160.55,43.52 v2(160.74,43.33)
  IN2 w0.254: v2(57.74,119.72) 57.36,119.72 56.1,120.98 v2(55.96,120.98)
  IN2 w0.508: v2(54.38,52.66) 54.13,52.66 53.14,53.65 49.52,53.65 48.98,53.1 41.74,53.1 v2(41.04,53.8)
  GND w0.203: 124.78,31.01 HCPU4.1 ; HCPU4.1 124.78,28.72 ; HCPU4.1 129.94,31.01 ; HCPU4.1 124.78,33.3 ; HCPU4.1 127.36,33.3 ; HCPU4.1 129.94,33.3 ; HCPU4.1 129.94,28.72 ; HCPU4.1 127.36,28.72 ; 1.42,97.08 JHDMI1.23 ; JHDMI1.23 2.7,95.22 ; JHDMI1.23 1.42,96.15 ; JHDMI1.23 2.7,97.08 ; JHDMI1.23 3.98,95.22 ; JHDMI1.23 1.42,95.22 ; JHDMI1.23 3.98,96.15 ; JHDMI1.23 3.98,97.08 ; JUSB2.10 14.56,31.03 ; JUSB2.10 11.62,29.27 ; JUSB2.10 11.62,30.15 ; JUSB2.10 13.09,31.03 ; JUSB2.10 14.56,29.27 ; JUSB2.10 14.56,30.15 ; JUSB2.10 13.09,29.27 ; 11.62,46.73 JUSB2.13 ; JUSB2.13 13.09,46.73 ; JUSB2.13 13.09,44.97 ; JUSB2.13 11.62,45.85 ; JUSB2.13 14.56,44.97 ; JUSB2.13 14.56,46.73 ; JUSB2.13 14.56,45.85 ; 136.5,88.32 H10.1 ; H10.1 138.1,88.9 ; H10.1 138.69,90.5 ; H10.1 134.32,90.5 ; H10.1 138.1,92.1 ; H10.1 134.9,92.1 ; H10.1 136.5,92.68 ; H10.1 134.9,88.9 ; 5.59,50.97 JUSB1.11 ; JUSB1.11 4.22,50.97 ; JUSB1.11 6.96,50.97 ; JUSB1.11 6.96,51.85 ; JUSB1.11 4.22,51.85 ; JUSB1.12 6.96,67.55 ; JUSB1.12 6.96,68.43 ; JUSB1.12 4.22,67.55 ; JUSB1.12 5.59,68.43 ; JUSB1.12 4.22,68.43 ; HCPU2.1 104.25,31.01 ; HCPU2.1 100.29,29.34 ; HCPU2.1 103.63,32.68 ; HCPU2.1 101.96,33.3 ; HCPU2.1 99.67,31.01 ; HCPU2.1 100.29,32.68 ; HCPU2.1 101.96,28.72 ; HCPU2.1 103.63,29.34 ; JLAN1.11 11.73,101.3 ; JLAN1.11 9.37,101.97 ; JLAN1.11 9.37,101.3 ; JLAN1.11 10.55,100.63 ; JLAN1.11 11.73,101.97 ; JLAN1.11 9.37,100.63 ; JLAN1.11 11.73,100.63 ; JLAN1.11 10.55,101.97 ; JUSB2.7 13.18,38.78 ; JUSB2.7 13.96,38 ; JUSB2.7 13.78,38.6 ; JUSB2.7 13.18,37.22 ; JUSB2.7 13.78,37.4 ; JUSB2.12 6.96,45.85 ; JUSB2.12 6.96,46.73 ; JUSB2.12 4.22,45.85 ; JUSB2.12 4.22,46.73 ; JUSB2.12 5.59,46.73 ; JUSB1.7 13.18,60.48 ; JUSB1.7 13.96,59.7 ; JUSB1.7 13.78,59.1 ; JUSB1.7 13.78,60.3 ; JUSB1.7 13.18,58.92 ; JHDMI1.20 13.43,80.68 ; JHDMI1.20 13.43,79.75 ; JHDMI1.20 10.87,79.75 ; JHDMI1.20 13.43,78.82 ; JHDMI1.20 12.15,78.82 ; JHDMI1.20 10.87,78.82 ; JHDMI1.20 12.15,80.68 ; JHDMI1.20 10.87,80.68 ; 11.54,82.54 JHDMI1.2 ; JHDMI1.2 11.54,83.46 ; JHDMI1.2 12.46,82.54 ; JHDMI1.2 12.46,83.46 ; JHDMI1.2 12,82.42 ; JHDMI1.2 11.42,83 ; JHDMI1.2 12.58,83 ; 2.67,77.85 JHDMI1.21 ; JHDMI1.21 5.23,78.78 ; JHDMI1.21 3.95,76.92 ; JHDMI1.21 2.67,78.78 ; JHDMI1.21 2.67,76.92 ; JHDMI1.21 5.23,77.85 ; JHDMI1.21 5.23,76.92 ; JHDMI1.21 3.95,78.78 ; 1.57,100.63 JLAN1.12 ; JLAN1.12 1.57,101.3 ; JLAN1.12 2.75,101.97 ; JLAN1.12 3.93,100.63 ; JLAN1.12 1.57,101.97 ; JLAN1.12 3.93,101.97 ; JLAN1.12 2.75,100.63 ; JLAN1.12 3.93,101.3 ; JUSB1.13 14.56,67.55 ; JUSB1.13 11.62,68.43 ; JUSB1.13 11.62,67.55 ; JUSB1.13 14.56,66.67 ; JUSB1.13 13.09,68.43 ; JUSB1.13 13.09,66.67 ; JUSB1.13 14.56,68.43 ; HCPU3.1 129.1,77.75 ; HCPU3.1 125.62,77.75 ; HCPU3.1 124.97,76.01 ; HCPU3.1 129.1,74.27 ; HCPU3.1 125.62,74.27 ; HCPU3.1 127.36,73.62 ; HCPU3.1 129.75,76.01 ; HCPU3.1 127.36,78.4 ; 9.37,118.1 JLAN1.10 ; JLAN1.10 10.55,118.77 ; JLAN1.10 11.73,118.77 ; JLAN1.10 9.37,117.43 ; JLAN1.10 9.37,118.77 ; JLAN1.10 11.73,117.43 ; JLAN1.10 10.55,117.43 ; JLAN1.10 11.73,118.1 ; H5.1 143.32,62.62 ; H5.1 141.9,59.27 ; H5.1 141.9,63.13 ; H5.1 140.48,59.78 ; H5.1 140.48,62.62 ; H5.1 143.32,59.78 ; H5.1 143.83,61.2 ; H5.1 139.97,61.2 ; H9.1 113.5,136.69 ; H9.1 115.69,134.5 ; H9.1 113.5,132.32 ; H9.1 111.9,136.1 ; H9.1 115.1,136.1 ; H9.1 111.32,134.5 ; H9.1 115.1,132.9 ; H9.1 111.9,132.9 ; H4.1 208.02,49.32 ; H4.1 208.53,47.9 ; H4.1 204.67,47.9 ; H4.1 206.6,49.83 ; H4.1 206.6,45.97 ; H4.1 205.18,46.48 ; H4.1 208.02,46.48 ; H4.1 205.18,49.32 ; 85.3,110 H8.1 ; H8.1 86.9,109.42 ; H8.1 86.9,113.78 ; H8.1 88.5,110 ; H8.1 88.5,113.2 ; H8.1 89.08,111.6 ; H8.1 84.72,111.6 ; H8.1 85.3,113.2 ; JLAN1.9 3.93,117.43 ; JLAN1.9 1.57,118.77 ; JLAN1.9 1.57,117.43 ; JLAN1.9 2.75,117.43 ; JLAN1.9 3.93,118.77 ; JLAN1.9 3.93,118.1 ; JLAN1.9 2.75,118.77 ; JLAN1.9 1.57,118.1 ; 99.67,78.59 HCPU1.1 ; HCPU1.1 101.96,73.43 ; HCPU1.1 104.25,78.59 ; HCPU1.1 104.25,76.01 ; HCPU1.1 104.25,73.43 ; HCPU1.1 101.96,78.59 ; HCPU1.1 99.67,76.01 ; HCPU1.1 99.67,73.43 ; 14.08,33.9 JUSB2.4 ; JUSB2.4 14.08,35.1 ; JUSB2.4 14.68,35.28 ; JUSB2.4 15.28,35.1 ; JUSB2.4 13.9,34.5 ; JUSB2.4 15.28,33.9 ; JUSB2.4 15.46,34.5 ; JUSB2.4 14.68,33.72 ; 52.3,131.67 H11.1 ; H11.1 53.79,135.19 ; H11.1 53.79,132.21 ; H11.1 50.81,135.19 ; H11.1 52.3,135.73 ; H11.1 50.27,133.7 ; H11.1 50.81,132.21 ; H11.1 54.33,133.7 ; 12.15,93.32 JHDMI1.22 ; JHDMI1.22 10.87,93.32 ; JHDMI1.22 12.15,95.18 ; JHDMI1.22 10.87,94.25 ; JHDMI1.22 13.43,94.25 ; JHDMI1.22 13.43,93.32 ; JHDMI1.22 10.87,95.18 ; JHDMI1.22 13.43,95.18 ; H12.1 6.73,5.63 ; H12.1 3.27,1.57 ; H12.1 3.27,3.6 ; H12.1 5,5.63 ; H12.1 6.73,3.6 ; H12.1 3.27,5.63 ; H12.1 5,1.57 ; H12.1 6.73,1.57 ; 8.7,120.37 H2.1 ; H2.1 10.12,120.88 ; H2.1 8.7,124.23 ; H2.1 7.28,120.88 ; H2.1 10.63,122.3 ; H2.1 10.12,123.72 ; H2.1 7.28,123.72 ; H2.1 6.77,122.3 ; 5.59,29.27 JUSB2.11 ; JUSB2.11 6.96,30.15 ; JUSB2.11 6.96,29.27 ; JUSB2.11 4.22,30.15 ; JUSB2.11 4.22,29.27 ; 11.54,85.54 JHDMI1.8 ; JHDMI1.8 12.58,86 ; JHDMI1.8 11.54,86.46 ; JHDMI1.8 12.46,85.54 ; JHDMI1.8 12.46,86.46 ; JHDMI1.8 11.42,86 ; 11.62,51.85 JUSB1.10 ; JUSB1.10 11.62,50.97 ; JUSB1.10 13.09,50.97 ; JUSB1.10 14.56,52.73 ; JUSB1.10 13.09,52.73 ; JUSB1.10 14.56,50.97 ; JUSB1.10 14.56,51.85 ; 9.87,90.5 JHDMI1.17 ; JHDMI1.17 9.99,90.96 ; JHDMI1.17 9.99,90.04 ; JHDMI1.17 10.91,90.04 ; JHDMI1.17 11.03,90.5 ; JHDMI1.17 10.91,90.96 ; 18.4,2.37 H1.1 ; H1.1 19.82,5.72 ; H1.1 19.82,2.88 ; H1.1 20.33,4.3 ; H1.1 18.4,6.23 ; H1.1 16.47,4.3 ; H1.1 16.98,2.88 ; H1.1 16.98,5.72 ; JHDMI1.5 10.91,84.96 ; JHDMI1.5 10.91,84.04 ; JHDMI1.5 9.99,84.04 ; JHDMI1.5 11.03,84.5 ; JHDMI1.5 9.87,84.5 ; JHDMI1.5 9.99,84.96 ; JUSB1.4 15.46,56.2 ; JUSB1.4 14.08,56.8 ; JUSB1.4 14.68,56.98 ; JUSB1.4 15.28,55.6 ; JUSB1.4 14.08,55.6 ; JUSB1.4 15.28,56.8 ; JUSB1.4 13.9,56.2 ; JUSB1.4 14.68,55.42 ; JHDMI1.11 11.03,87.5 ; JHDMI1.11 10.91,87.04 ; JHDMI1.11 9.99,87.04 ; JHDMI1.11 9.87,87.5 ; JHDMI1.11 10.91,87.96 ; JHDMI1.11 9.99,87.96 ; 140.48,7.72 H3.1 ; H3.1 139.97,6.3 ; H3.1 141.9,4.37 ; H3.1 143.83,6.3 ; H3.1 140.48,4.88 ; H3.1 143.32,7.72 ; H3.1 143.32,4.88 ; H3.1 141.9,8.23
  BOTTOM w0.102: v4(32.28,106.25) 32.29,106.24 PR605.2 ; CV123.2 v4(95.27,113.26) ; v4(113.88,125.94) v2(113.88,126.51) ; v4(134.96,6.94) C2619.2
  BOTTOM w0.127: v2(162.37,95.22) 162.21,95.22 161.95,95.48 161.95,97.3 161.31,97.94 161.31,100.11 160.61,100.81 160.61,102.05 160.99,102.43 v2(161.46,102.43) ; v2(170.9,51.01) 171.34,51.45 172.42,51.45 172.61,51.64 v2(172.61,53.17) ; 30.94,36.91 31.58,36.28 31.58,35.45 31.33,35.2 30.75,35.2 v2(30.5,35.45) 30.25,35.71 29.1,35.71 v2(27.71,37.1) 26.69,37.1 v2(25.99,36.4) 25.86,36.28 24.95,36.28 23.89,35.21 23.89,34.11 25.99,32.01 v2(25.99,31.45) 25.99,31.01 26.31,30.69 28.09,30.69 28.66,31.26 v2(28.72,31.26) 28.79,31.2 29.36,31.2 30.88,32.72 32.09,32.72 35.77,36.4 38.31,36.4 39.14,35.58 39.14,31.7 40.41,30.43 40.41,18.94 49.3,10.05 49.3,6.75 v4(50.72,5.32) v2(53.42,2.62) 53.42,2.49 52.98,2.05 51.77,2.05 v2(51.46,2.37) 48.28,5.54 48.28,9.48 39.77,17.99 39.41,17.99 JDIMM2.262 37.47,20.45 39.33,22.31 39.33,30.18 38.12,31.39 38.12,35.2 37.87,35.45 36.72,35.45 v2(35.71,34.44) 35.2,34.44 34.06,33.29 34.06,32.91 v2(33.99,32.85) 33.55,32.85 32.47,31.77 31.26,31.77 29.55,30.05 28.85,30.05 v2(27.96,29.16) v2(25.99,29.16) 25.99,29.67 24.73,30.94 24.73,31.74 22.83,33.63 22.83,35.41 25.72,38.31 28.34,38.31 29.74,36.91 v2(30.69,36.91) 30.94,36.91
  BOTTOM w0.152: UC1.AY11 UC1.BA11 ; UC1.A18 116.3,64.47 116.3,65.22 116.1,65.42 116.1,65.55 v2(116.03,65.61)
  BOTTOM w0.178: UV1.B10 124.61,107.1 v2(124.65,107.06)
  BOTTOM w0.203: PU200.14 84.96,103.55 v2(84.86,103.65) ; PU200.1 89.03,103.95 89.24,104.16 v2(89.24,104.48) ; v2(183.09,34.31) 183.09,33.43 182.49,32.82 UE1.11 ; PU200.3 89.93,103.15 v2(90.06,103.27) ; v2(179.85,21.54) 179.63,21.54 179.22,21.96 179.22,22.8 UE1.35 ; v2(182.98,27.85) 182.98,27.83 182.78,27.63 UE1.24 ; U2302.11 v2(154.9,21.86) ; U2301.11 162.83,8.6 163.04,8.4 v2(163.15,8.4)
  BOTTOM w0.254: UC1.AL39 104.76,48.39 v2(104.96,48.59) 104.76,48.79 UC1.AJ39 ; UV15.F10 v2(142.27,101.81) 142.67,101.41 UV15.G10 ; v2(139.15,109) 139.26,108.89 139.26,108.82 UV15.C1 ; v2(109.62,121.23) 109.62,121.04 109.3,120.72 UV1.AA27 ; v2(147.13,107.4) 147.13,107.35 147.47,107.01 UV15.N3 ; UC1.N39 104.76,57.56 v2(104.96,57.36) 104.76,57.16 UC1.R39 ; UC1.E39 104.76,61.96 v2(104.96,61.76) 104.76,61.56 UC1.G39 ; RPC14.3 104.49,20.54 v2(104.73,20.78) 104.47,21.04 RPC14.2 ; UV15.M10 146.67,101.41 v2(146.27,101.81) UV15.L10 ; UV1.F2 121.3,100.9 v2(121.31,100.89) ; UV15.U1 150.67,108.66 v2(150.33,109) ; UV1.L27 117.3,120.94 v2(117.02,121.22) 117.82,121.22 UV1.K28 ; UV13.A3 150.67,116.83 v2(150.27,117.23) ; v2(102.64,54.56) 102.69,54.61 UC1.W41 ; v2(142.5,104.83) 142.67,105.01 UV15.G5 ; UV1.AA13 109.96,110.36 v2(109.96,110.43) 110.42,110.9 UV1.Y15 110.5,110.95 v2(111.04,111.49) 111.45,111.9 UV1.V16 ; v2(145.47,124.43) 145.09,124.81 UV13.H13 ; v2(121.66,117.88) 121.3,118.25 UV1.F24 ; UV1.M32 116,123.1 v2(115.51,123.59) ; UV1.V32 v2(111.7,123.83) ; v2(145.87,118.99) 145.87,118.99 UV13.G5 ; v2(118.86,123.23) 118.9,123.19 UV1.J31 ; UV1.AG12 103.95,108.15 v2(103.95,107.61) 103.95,107.35 UV1.AH10 ; v2(138.27,123.63) 137.89,124.01 UV13.U12 ; UV13.M5 141.87,118.43 v2(142.27,118.83) 142.67,118.43 UV13.L5 ; UV15.F5 141.84,105.41 v2(141.48,105.05) ; v2(149.47,118.83) 149.87,118.43 UV13.B5 ; UC1.AW29 109.88,43.61 v2(109.71,43.78) 109.54,43.61 UC1.AW31 ; UV13.U1 137.87,115.18 v2(138.21,114.83) ; v2(147.07,117.23) 147.47,116.83 UV13.E3 ; UC1.N2 125.33,57.98 125.89,57.98 UC1.N1 126.04,57.99 126.81,57.99 126.88,58.07 v2(126.88,58.07) ; v2(145.22,109.26) 145.07,109.11 UV15.K1 145.13,108.56 145.13,107.87 UV15.K2 ; UV13.H14 v2(145.44,125.24) ; v2(150.27,126.03) 150.27,126.01 UV13.A14 ; UV1.K2 118.09,101.89 118.09,100.96 117.94,100.82 v2(117.94,100.67) ; UV1.F10 UV1.G10 120.5,107.06 v2(120.18,106.74) ; UV13.U3 137.87,116.83 138.26,117.21 138.26,117.26 v2(138.28,117.28) 138.35,117.21 139.07,117.21 UV13.R4 ; UV1.T18 UV1.R20 114.83,115.23 v2(114.83,115.27) 115.26,115.7 UV1.N21 115.74,115.26 v2(115.76,115.26) ; v2(149.22,97.7) 149.07,97.85 UV15.R14 ; UV15.R1 149.07,108.95 v2(149.34,109.23) ; UC1.N3 124.36,58.11 v2(124.36,58.48) 124.36,58.81 UC1.L3 124.37,59.2 v2(124.37,59.58) 124.37,59.91 UC1.J3 124.42,60.25 124.42,60.63 v2(124.4,60.65) 124.42,60.67 124.42,61.06 UC1.G3 ; UV1.V11 111.5,107.59 v2(111.77,107.32) ; v2(57.74,119.72) 56.48,120.98 v2(55.96,120.98) ; UV1.AA11 109.65,107.9 v2(109.99,108.24) ; UV15.A12 137.63,99.81 137.15,100.29 v2(137.15,100.32) ; US2.3 v2(195.35,29.16) ; UV13.R1 139.47,114.88 v2(139.2,114.61) ; v2(105.33,123.68) 105.3,123.65 105.31,123.11 UV1.AF32 ; UV13.L10 142.65,122.41 v2(142.27,122.03) 141.89,122.41 UV13.M10 ; UC1.C9 120.91,63.41 v2(120.71,63.21) ; UC1.AA3 UC1.AA2 125.29,53.51 125.36,53.57 125.86,53.57 125.88,53.56 125.91,53.56 UC1.AA1 126.76,53.51 v2(126.76,53.51) ; 107.45,61.68 107.4,61.68 107.16,61.91 UC1.E35 ; 107.45,61.68 107.06,61.28 UC1.G35 ; 107.45,61.68 v2(107.53,61.68) ; v2(187.54,41.23) 187.22,41.23 186.77,41.67 186.77,42.88 187.03,43.13 187.98,43.13 188.17,42.94 189.63,42.94 v4(191.82,45.13) 193.5,46.81 JODD1.13 193.5,47.85 ; v2(139.85,101.05) 140.21,101.41 UV15.D10 ; v2(141,97.7) 141,98.14 UV15.E14 ; v2(143.47,114.66) 143.47,114.66 UV13.K1 UV13.K2 ; UV15.E3 v2(141.47,106.61) ; v2(126.78,62.43) 126.66,62.31 UC1.E1 125.89,62.31 125.85,62.34 125.37,62.34 125.33,62.31 UC1.E2 UC1.E3 ; UC1.R41 102.52,56.81 v2(102.45,56.74) ; v2(110.53,121.08) 110.9,120.71 UV1.W27 ; v2(137.33,97.86) 137.51,97.86 UV15.A14 ; v2(139.91,116.41) 139.89,116.41 139.49,116.81 UV13.R3 ; UC1.AG39 104.76,50.56 v2(104.96,50.76) 104.76,50.96 UC1.AE39 ; UV13.T5 138.67,118.43 v2(139.07,118.83) ; UV15.C4 139.47,106.21 v2(139.07,106.61) 139.47,107.01 UV15.C3 ; UV1.G8 120.54,105.5 120.72,105.32 121.12,105.32 UV1.F8 121.47,105.67 v2(121.75,105.67) ; UV1.T21 113.3,115.6 v2(112.9,115.2) 112.5,114.8 UV1.U20 ; UV1.F18 120.78,113.5 v2(120.76,113.52) ; v2(109.33,119.75) 109.33,118.93 UV1.AB24 ; UV15.T10 v2(149.47,101.01) UV15.R11 ; UV13.T10 138.67,122.43 v2(139.07,122.83) 139.45,123.21 UV13.R11 v2(139.85,122.83) UV13.P10 ; UC1.L41 102.83,59.01 102.64,58.82 102.51,58.82 102.51,58.81 v2(102.5,58.81) ; UV13.E12 147.47,124.03 v2(147.07,124.43) ; v2(123.78,118.28) 123.77,118.3 UV1.B24 ; UV1.AE14 106.1,109.96 v2(106.04,109.9) ; UV15.N12 v2(147.07,99.41) ; v2(137.5,126) 137.87,125.63 UV13.U14 ; UV15.K13 145.18,98.9 145.18,98.32 UV15.K14 145.07,97.64 v2(145.07,97.64) ; v2(114.21,59.92) 113.83,60.31 UC1.H23 ; v2(104.89,121.07) 104.52,120.7 UV1.AG27 104.22,120.98 104.22,120.99 103.96,121.24 103.96,121.24 UV1.AH28 ; UV15.E1 141.01,108.67 141.01,109.18 v2(141.01,109.18) ; UV15.T5 149.87,105.21 v2(149.63,104.97) ; UV13.K14 143.49,125.61 v2(143.87,125.23) 143.47,124.83 UV13.K13 ; UV15.L5 v2(146.27,105.01) UV15.M5 ; UV1.H2 119.7,101.18 119.62,101.09 v2(119.62,100.2) ; UC1.AC3 124.4,52.25 v2(124.4,51.84) 124.56,51.68 UC1.AE3 ; UC1.AC38 105.46,52.76 v2(105.66,52.96) ; UV15.C12 139.47,99.81 v2(139.07,100.21) 139.47,100.61 UV15.C11 ; v2(121.7,108.23) 121.7,108.3 UV1.F12 ; UC1.C39 v2(105.16,63.01) 105.56,63.41 UC1.C37 ; UV13.N1 141.07,114.85 v2(140.88,114.66) ; UC1.AU29 109.82,45.55 v2(109.75,45.55) 109.39,45.91 UC1.AR31 ; UV1.B12 123.66,108.7 v2(123.77,108.59) ; v2(143.5,109.13) 143.47,109.1 UV15.H1 UV15.H2 ; v2(113.66,123.9) 113.3,123.54 UV1.T32 ; UV1.F16 121.3,111.98 v2(120.98,112.3) ; v2(137.4,109.07) 137.87,108.61 UV15.A1 ; UV1.T16 112.5,111.1 UV1.U15 112.5,110.88 112.09,110.47 v2(112.09,110.42) 112.09,110.34 111.64,109.9 UV1.V13 111.5,109.81 v2(110.98,109.29) ; UV13.D10 148.27,122.43 v2(147.87,122.83) ; UV13.A1 150.69,115.21 v2(151.07,114.83) ; v2(151.07,123.63) 150.69,124.01 UV13.A12 ; UC1.AE5 123.06,50.96 v2(122.86,50.76) 122.31,50.21 UC1.AG7 122.26,49.88 v2(121.99,49.61) ; v2(141.47,124.43) 141.07,124.03 UV13.N12 ; v2(149.47,122.83) 149.87,122.43 UV13.B10 ; UC1.J39 104.76,59.76 v2(104.96,59.56) 104.76,59.36 UC1.L39 ; UV1.G27 120.44,120.76 v2(120.44,121.4) ; v2(102.57,52.39) 102.59,52.41 UC1.AC41 ; v2(147.06,109.12) 147.47,108.71 UV15.N1 ; UV1.Y32 110.1,123.44 110.09,123.45 110.09,123.63 v2(110,123.72) ; UV15.U14 150.67,98.21 151.01,97.87 v2(151.15,97.87) ; UE1.94 164.93,36.02 164.49,36.47 164.49,36.85 v2(164.42,36.91) ; v2(114.07,106.53) 114.47,106.53 UV1.P9 ; v2(103.49,124.64) 103.7,124.43 UV1.AH32 ; UV13.R14 139.32,125.76 v2(139.32,126.14) ; UC1.BA15 117.96,41.74 v2(117.68,41.46) ; UV15.U12 150.94,99.81 v2(151.24,99.51) ; UV1.F26 121.68,120.28 v2(121.68,121.01) 122.1,121.42 UV1.E28 ; UC1.L13 118.71,58.51 v2(119.2,58.02) ; UV15.A3 v2(138.27,106.61) ; UV13.H2 145.09,116.01 v2(145.47,115.63) 145.07,115.23 UV13.H1 ; UV15.R4 149.47,106.61 v2(150.27,106.61) UV15.U3 ; UV1.U25 v2(111.87,119.53) ; v2(139.23,97.74) 139.47,97.97 UV15.C14 ; v2(119.33,111.02) 119.33,110.87 UV1.H14 ; v2(107.28,119.48) UV1.AD25 UV1.AC24 ; UV1.V18 111.41,113.7 v2(110.91,113.2) 110.5,112.79 UV1.Y17 ; UV13.C3 149.07,116.83 v2(149.47,117.23) 149.09,117.61 UV13.C4 ; UV1.W26 111.42,119.9 v2(111.7,120.18) 111.86,120.18 112.38,120.7 UV1.U27 ; UC1.C29 109.88,63.41 v2(109.7,63.23) 109.52,63.41 UC1.C31 108.81,63.76 UC1.B32 108.41,63.76 UC1.C33 107.67,63.41 v2(107.51,63.24) 107.35,63.41 UC1.C35 ; UC1.U39 104.76,55.36 v2(104.96,55.16) 104.76,54.96 UC1.W39 ; UV1.W25 111.02,119.1 v2(110.51,119.61) 109.99,119.1 UV1.Y25 ; v2(147.07,118.03) 146.69,118.41 UV13.F5 ; UV1.AC26 107.98,119.62 v2(108.17,119.62) ; UV13.E14 147.47,125.63 v2(147.07,126.03) ; v2(113.73,110.39) 113.3,109.96 UV1.T13 ; UV13.G10 145.89,122.41 v2(146.27,122.03) 146.65,122.41 UV13.F10 ; UV1.M12 UV1.N11 115.26,107.86 114.34,107.86 UV1.R11 114.21,107.9 v2(113.82,108.29) 114.3,108.77 UV1.R12 114.37,108.9 v2(114.9,109.43) 114.98,109.43 115.3,109.76 UV1.N13 ; UV1.U9 112.26,106.3 v2(111.83,105.86) ; UV15.E12 141.07,99.81 v2(141.47,99.41) ; UV1.T25 113.28,119.1 v2(112.9,119.48) ; UV15.R12 149.07,99.81 v2(149.47,99.41) ; UV13.E1 147.47,114.68 v2(147.49,114.66) ; UC1.AA39 104.76,53.16 v2(104.96,52.96) 104.76,52.76 UC1.AC39 ; UV15.P10 148.24,101.41 v2(147.89,101.75) ; UV1.AC17 107.41,112.61 v2(107.41,112.41) ; UV1.N18 UV1.R17 ; UV15.B5 v2(139.07,105.01) ; UV1.B18 v2(124.2,113.5) ; UV13.C14 149.09,125.61 v2(149.47,125.23) ; UV13.C1 149.07,114.77 v2(149.18,114.66) ; UV1.R27 114.1,119.65 v2(114.06,119.62) ; v2(126.6,61.25) 126.57,61.21 UC1.G1 125.9,61.27 125.88,61.27 125.87,61.28 125.35,61.28 125.34,61.27 125.32,61.27 UC1.G2 ; UV1.B8 124.01,105.5 v2(124.36,105.14) ; UC1.AR39 104.76,46.16 v2(104.96,46.36) 104.76,46.56 UC1.AN39 ; v2(141.47,116.43) 141.09,116.81 UV13.N3 ; v2(141.06,126.16) 141.07,126.14 UV13.N14 ; v2(143.07,99.41) 143.07,99.41 UV15.H13 ; UC1.E38 105.68,62.31 v2(105.94,62.57) 106.26,62.24 UC1.G37 ; UV1.AB15 108.5,110.94 v2(108.94,111.38) 109.46,111.9 UV1.AA16 ; UV1.G31 120.5,122.78 120.23,123.05 120.23,123.27 120.74,123.78 120.8,123.78 120.8,123.78 v2(120.77,123.78) ; UV1.N27 115.91,120.91 v2(115.91,121.18) ; UV1.B16 123.98,111.9 v2(124.07,111.81) ; UV1.H20 119.7,115.51 v2(120.04,115.84) ; v2(105.76,121.06) 105.76,121.04 UV1.AE27 ; v2(124.16,117.26) 123.6,116.7 UV1.B22 ; v2(164.52,79.29) 164.52,79.88 164.09,80.31 164.09,82.57 164.55,83.03 v2(164.76,83.03) ; UV13.R12 v2(139.87,123.61) ; UV15.H14 v2(143.47,97.71) ; UC1.C7 122.01,63.76 UC1.B8 ; v2(114.38,123.4) 114.68,123.1 UV1.P32 ; UC1.BA31 109.16,41.41 v2(109.18,41.39) ; UV13.C11 149.07,123.23 v2(149.47,123.63) 149.09,124.01 UV13.C12 ; UV15.B10 139.02,101.76 139.02,101.76 139.09,101.76 v2(139.09,101.75) ; UV1.AC27 v2(108.1,120.3) ; UC1.AC7 v2(122.74,51.93) ; UV15.R3 149.07,107.01 v2(148.67,107.41) ; UE1.113 v2(174.02,37.13) ; UV1.Y20 v2(110.95,115.15) ; v2(102.56,61.21) UC1.G41
  BOTTOM w0.305: JDIMM2.39 52.11,78.13 v2(51.79,78.44) 51.79,78.91 52.01,79.13 JDIMM2.35 ; JDIMM1.201 71,35.13 71.44,35.56 v2(71.44,35.62) 71.44,35.69 71,36.13 JDIMM1.197 ; JDIMM1.5 71.11,86.13 71.42,85.82 v2(71.42,85.64) 71.42,85.49 71.05,85.13 JDIMM1.9 ; JDIMM2.61 52.2,72.62 v2(51.79,73.03) 51.79,73.32 52.1,73.62 JDIMM2.57 ; JEDP1.35 224.93,33.05 v2(225.06,32.91) ; JDIMM1.231 71,27.63 v2(71.78,28.4) 71.55,28.63 JDIMM1.227 ; JDIMM1.196 63.1,36.38 63.65,35.83 v2(63.65,35.09) 63.44,34.87 JDIMM1.202 ; v2(51.79,30.46) 52.13,30.12 JDIMM2.223 ; JDIMM1.230 63.03,27.87 63.38,28.22 v2(63.38,29.2) 63.05,28.87 JDIMM1.226 ; UV1.A3 123.97,102.03 v2(123.97,101.78) ; JDIMM1.19 71.34,82.62 71.46,82.74 v2(71.46,83.11) 71.46,83.2 71.03,83.62 JDIMM1.15 ; JEDP1.9 v2(222.97,46.05) ; JDIMM1.43 71.41,76.62 71.71,76.93 v2(71.71,77.09) 71.71,77.29 71.38,77.62 JDIMM1.39 ; 71.42,42.41 v2(71.42,41.86) 71.18,41.63 JDIMM1.175 ; 71.42,42.41 71.21,42.63 ; 71.42,42.41 71.42,42.65 ; 51.77,67.65 51.77,68.28 52.12,68.62 JDIMM2.77 ; 51.77,67.65 51.77,67.64 v2(51.79,67.62) 51.8,67.62 ; 51.77,67.65 51.8,67.62 ; JEDP1.19 v2(224.99,41.05) ; JDIMM1.205 71.51,34.13 71.71,33.93 v2(71.71,33.24) 71.6,33.13 JDIMM1.209 ; 71.42,42.65 71.42,43.29 71.09,43.63 JDIMM1.167 ; 71.42,42.65 71.4,42.63 71.21,42.63 ; JHDD1.7 196.15,16.57 v2(195.78,16.2) ; JDIMM1.61 71.3,72.13 v2(71.52,72.34) 71.55,72.37 71.55,72.8 71.22,73.13 JDIMM1.57 ; v2(63.97,29.16) 63.96,29.16 63.96,29.48 63.57,29.87 JDIMM1.222 ; JDIMM1.89 71.09,65.13 71.39,65.43 v2(71.39,65.91) 71.18,66.13 JDIMM1.85 ; JDIMM2.176 v2(43.56,41.87) ; JDIMM2.103 52.09,62.13 51.77,62.44 v2(51.77,63.14) 51.78,63.13 JDIMM2.99 ; 71.21,42.63 JDIMM1.171 ; JDIMM1.176 62.98,41.38 63.27,41.66 v2(63.27,42.23) 63.12,42.38 JDIMM1.172 ; JDIMM1.243 71,24.63 v2(71.46,24.17) 71.46,23.89 71.19,23.63 JDIMM1.247 ; JDIMM1.213 71.14,32.13 v2(71.48,31.79) 71.46,31.77 71.46,31.32 71.26,31.13 JDIMM1.217 ; JWLAN1.55 v2(58.55,101.3) ; JDIMM2.175 51.92,42.12 v2(51.75,42.3) ; JEDP1.22 v2(225.04,39.55) ; JDIMM2.51 52.01,75.13 51.79,74.9 v2(51.79,74.55) ; JDIMM2.18 v2(43.64,83.37) ; JDIMM2.231 52.05,28.12 51.75,28.43 v2(51.75,28.51) 51.75,28.82 52.05,29.12 JDIMM2.227 ; JDIMM2.201 51.95,35.63 v2(51.77,35.45) 51.75,35.42 51.75,34.93 52.05,34.63 JDIMM2.205 ; JDIMM1.1 71.68,87.13 72.05,86.75 v2(72.05,85.62) ; JHDD1.1 v2(199.15,16.24) ; JDIMM2.189 51.97,38.63 v2(51.75,38.4) 51.77,38.37 51.77,37.99 52.14,37.63 JDIMM2.193 ; JDIMM2.260 v2(43.64,20.87) ; JDIMM2.202 43.82,35.38 43.52,35.07 v2(43.52,35.01) 43.52,34.63 43.77,34.38 JDIMM2.206 ; JDIMM2.214 v2(46.06,32.38) ; JDIMM2.239 52.03,26.12 51.75,25.84 v2(51.75,24.95) 51.92,25.12 JDIMM2.243 ; JWLAN1.31 v2(52.55,101.29) ; JDIMM1.248 62.97,23.38 v2(63.27,23.68) 63.27,24.07 62.97,24.38 JDIMM1.244 ; v2(51.79,79.96) 51.95,80.13 JDIMM2.31 ; 51.8,67.62 JDIMM2.81 ; v2(72.28,67.35) 72.28,68.66 71.82,69.13 JDIMM1.73 ; v2(225.09,42.21) 224.75,42.55 JEDP1.16 ; JEDP1.27 v2(224.99,37.05) ; JDIMM2.47 51.83,76.13 v2(51.71,76.25) 51.71,76.79 52.04,77.13 JDIMM2.43 ; JDIMM2.22 v2(43.64,82.37) ; JDIMM1.18 62.98,82.88 v2(63.27,83.17) 63.27,83.46 62.85,83.88 JDIMM1.14 ; JDIMM1.239 71.09,25.63 v2(71.58,26.12) 71.08,26.63 JDIMM1.235 ; JDIMM2.86 v2(43.54,66.38) ; JWLAN1.1 v2(43.05,98.65) ; JDIMM1.180 63.01,40.38 v2(63.27,40.12) 63.27,39.68 62.96,39.38 JDIMM1.184 ; UV1.B6 123.98,103.9 124.23,103.65 v2(124.29,103.65) ; JDIMM2.185 51.89,39.63 v2(51.75,39.48) ; JDIMM1.78 63.14,67.88 v2(63.16,67.86) 63.33,67.68 63.33,67.18 63.02,66.88 JDIMM1.82 ; JDIMM2.251 52.1,23.12 51.75,23.48 v2(51.75,23.87) 52,24.12 JDIMM2.247 ; JDIMM2.15 51.93,84.13 51.79,83.99 v2(51.79,83.27) 51.93,83.13 JDIMM2.19 ; JDIMM1.30 62.99,79.88 63.18,79.69 63.18,78.68 63.17,78.67 v2(63.17,78.43) 62.92,78.43 62.87,78.38 JDIMM1.36 ; JDIMM2.23 51.96,82.13 51.79,81.95 v2(51.79,81.49) 52.15,81.13 JDIMM2.27 ; JDIMM2.64 v2(43.64,71.87) ; JDIMM2.48 v2(43.64,75.87) ; JWLAN1.37 v2(54.05,101.29) ; JDIMM2.94 v2(43.54,64.38) ; JDIMM2.167 51.79,44.12 v2(51.75,44.08) 51.75,43.34 51.96,43.12 JDIMM2.171 ; JDIMM2.85 51.9,66.62 51.79,66.51 v2(51.79,65.92) 52.08,65.62 JDIMM2.89 ; JDIMM1.214 63.64,31.87 v2(63.84,31.68) 63.84,31.39 63.33,30.87 JDIMM1.218 ; JWLAN1.7 v2(44.55,99.05) ; JDIMM1.47 71.28,75.62 71.58,75.32 v2(71.58,75.14) 71.58,74.93 71.28,74.62 JDIMM1.51 ; v2(71.65,29.84) 71.44,29.63 JDIMM1.223 ; JDIMM2.181 51.84,40.63 v2(51.79,40.67) ; v2(51.79,64.39) 52.02,64.62 JDIMM2.93 ; JDIMM2.217 52.05,31.63 51.75,31.93 v2(51.75,32.25) 52.12,32.63 JDIMM2.213 ; JWLAN1.67 v2(61.55,101.3) ; JEDP1.13 v2(222.88,44.05) ; JDIMM1.188 62.85,38.38 v2(63.15,38.07) 63.15,37.77 62.76,37.38 JDIMM1.192 ; v2(63.29,71.32) 63.23,71.38 JDIMM1.64 ; JDIMM2.30 v2(43.64,80.37) ; JWLAN1.10 47.3,109.42 v2(47.44,109.56) 48.52,109.56 49.3,108.78 JWLAN1.18 ; JDIMM2.238 v2(43.62,26.38) ; JDIMM2.73 52.15,69.62 v2(51.79,69.98) 51.79,70.4 52.02,70.62 JDIMM2.69 ; JDIMM1.81 71.31,67.13 v2(71.54,67.35) 71.54,67.82 71.23,68.13 JDIMM1.77 ; v2(51.79,71.51) 51.91,71.62 JDIMM2.65 ; JDIMM1.2 63.13,86.88 63.84,86.17 v2(63.84,85.64) ; v2(51.79,85.55) 51.87,85.62 JDIMM2.9 ; JDIMM2.184 v2(43.56,39.87) ; JDIMM2.209 51.96,33.63 v2(51.75,33.84) ; JDIMM2.26 v2(43.64,81.37) ; JEDP1.33 v2(224.95,34.05) ; JWLAN1.49 v2(57.05,101.3) ; JDIMM1.234 62.85,26.87 63.16,26.56 v2(63.16,25.67) 62.96,25.67 62.76,25.87 JDIMM1.238 ; JDIMM1.168 62.9,43.38 v2(64.03,42.25) ; JDIMM2.196 v2(46.06,36.87) ; JDIMM1.256 60.89,21.38 60.72,21.54 v2(60.66,21.54) 60.73,21.61 60.73,22.07 61.03,22.38 JDIMM1.252 ; v2(72.16,24.17) 72.16,24.15 72.28,24.02 72.28,23.13 71.78,22.63 JDIMM1.251 ; JDIMM2.68 v2(43.64,70.87) ; v2(113.82,108.29) 113.69,108.29 UV1.T11 ; v2(118.54,103.51) 118.15,103.9 UV1.K6 ; JDIMM1.210 63.75,32.87 64.42,32.2 v2(64.42,31.68) ; UV1.AE7 v2(106.54,105.14) ; JDIMM1.40 62.9,77.38 63.23,77.04 v2(63.23,76.99) 63.23,76.68 62.92,76.38 JDIMM1.44 ; JDIMM2.172 v2(43.56,42.87) ; v2(64.31,35.09) 64.31,34.78 63.4,33.87 JDIMM1.206 ; JDIMM1.27 71.23,80.62 71.25,80.65 v2(71.33,80.65) 71.39,80.71 71.39,81.32 71.09,81.62 JDIMM1.23 ; JDIMM1.72 63.16,69.38 v2(63.16,69.37) 63.24,69.45 63.24,70.02 62.89,70.38 JDIMM1.68 ; JDIMM2.56 v2(43.64,73.87) ; JDIMM2.6 v2(43.64,86.37) ; JDIMM1.56 63.05,73.38 v2(63.15,73.28) 63.15,72.59 62.93,72.38 JDIMM1.60 ; JDIMM2.72 v2(43.64,69.87) ; JDIMM2.244 v2(43.62,24.87) ; v2(51.75,27.24) 51.86,27.12 JDIMM2.235 ; JDIMM1.185 71.27,39.13 71.58,39.43 71.58,39.52 v2(71.64,39.58) 71.61,39.61 71.61,39.82 71.31,40.13 JDIMM1.181 ; JDIMM1.31 71.29,79.62 71.64,79.28 v2(71.64,79.1) 71.64,79.05 71.22,78.62 JDIMM1.35 ; JDIMM2.40 v2(43.64,77.87) ; JEDP1.38 v2(225.23,31.55) ; JDIMM1.99 71.28,62.62 v2(71.79,63.13) 71.79,63.58 71.25,64.13 JDIMM1.93 ; JDIMM2.52 v2(43.64,74.87) ; JDIMM1.10 62.85,84.88 63.16,85.18 63.16,85.6 v2(63.2,85.64) 62.96,85.88 JDIMM1.6 ; JDIMM2.5 52.1,86.62 51.79,86.93 v2(51.79,87.08) 51.79,87.48 51.94,87.62 JDIMM2.1 ; JDIMM2.230 v2(43.62,28.38) ; JDIMM2.248 v2(43.62,23.87) ; JDIMM1.69 71.56,70.13 v2(71.78,70.34) 71.78,70.57 71.22,71.13 JDIMM1.65 ; JDIMM2.234 v2(43.62,27.38) ; v2(43.62,22.89) 43.64,22.87 JDIMM2.252 ; v2(129.97,5.29) 129.97,5.07 130.77,4.27 Q2516.4 ; v2(46.06,31.37) 46.06,31.38 JDIMM2.218 ; JHDD1.4 v2(197.65,16.24) ; JWLAN1.43 v2(55.55,101.3) ; JDIMM1.22 63,81.88 63.3,81.57 v2(63.3,81.22) 63.3,81.18 63,80.88 JDIMM1.26 ; JDIMM2.180 v2(43.56,40.87) ; v2(51.79,36.81) 51.98,36.63 JDIMM2.197 ; JDIMM1.103 71.08,61.62 ; JDIMM1.107 71.08,60.62 ; JDIMM2.90 v2(43.54,65.38) ; JDIMM2.82 v2(43.58,67.38) ; JDIMM2.10 v2(43.58,85.37) ; v2(147.46,97.64) 147.47,97.65 UV15.N14 ; JDIMM2.78 v2(43.64,68.38) ; JDIMM2.210 v2(46.06,33.38) ; JDIMM2.44 v2(43.64,76.87) ; JWLAN1.61 v2(60.05,101.3) ; JDIMM2.226 v2(43.62,29.38) ; JDIMM2.222 v2(46.06,30.38) ; JDIMM2.60 v2(43.64,72.87) ; JDIMM2.36 v2(43.64,78.87) ; JDIMM2.2 v2(43.64,87.37) ; JDIMM2.102 v2(43.54,62.38) ; JDIMM2.192 v2(46.06,37.87) ; JDIMM2.98 v2(43.54,63.38) ; JDIMM2.14 v2(43.58,84.37) ; JDIMM2.106 v2(43.54,61.38) ; JDIMM1.52 63.08,74.38 63.18,74.48 v2(63.18,75.04) 62.84,75.38 JDIMM1.48 ; JWLAN1.25 v2(51.05,101.29) ; JDIMM1.193 71.62,37.13 v2(71.69,37.06) 71.69,37.82 71.39,38.13 JDIMM1.189 ; JDIMM2.188 v2(43.56,38.87) ; JDIMM2.168 46.23,43.87 v2(46.25,43.9)
  BOTTOM w0.33: v2(108.56,61.33) 108.94,61.33 UC1.G31 ; v2(115.76,41.66) UC1.BA19 ; v2(115.21,45.55) 115.57,45.91 UC1.AR19 ; v2(116.61,96.74) 116.43,96.92 RV151.1 ; v2(123.53,46.32) 123.41,46.44 123.41,46.56 UC1.AN5 ; v2(106.96,41.69) UC1.BA35 ; v2(112.99,61.71) 112.78,61.91 UC1.E25 ; v2(63.14,19.75) 63.14,19.83 62.59,20.38 JDIMM1.260 ; v2(119.37,105.11) 118.96,104.7 UV1.J7 UV1.H6 ; UV1.K22 118.55,116.95 v2(118.55,116.98) ; v2(113.73,110.39) 114.24,110.9 UV1.R15 114.76,111.36 114.76,111.42 115.24,111.9 UV1.N16 115.82,111.38 v2(115.91,111.38) ; v2(96.5,119.44) 96.72,119.44 96.73,119.45 RV4.2 98.01,118.64 RV163.2 ; v2(121.69,45.8) 121.62,45.74 121.62,45.47 UC1.AU9 120.96,45.11 UC1.AR11 ; UV1.F14 121.54,110.06 v2(121.77,110.06) ; UC1.AL7 122.26,47.86 121.92,47.52 v2(121.88,47.52) ; UC1.B8 UC1.A8 121.75,64.52 121.75,64.55 121.71,64.59 v2(121.71,65.23) ; UC1.AW41 102.96,43.56 v2(102.84,43.44) ; 114.21,63.17 v2(114.21,63.12) ; 114.21,63.17 114.18,63.21 113.76,63.21 UC1.C23 ; 114.21,63.17 114.25,63.21 114.46,63.21 UC1.C21 ; UC1.C5 123.69,63.18 v2(124.03,63.18) 124.33,63.18 UC1.C3 ; v2(104.62,65.61) 104.71,65.51 UC1.A39 104.58,64.68 104.58,64.29 UC1.B39 ; UC1.A2 125.65,65.1 v2(126.02,65.1) ; UC1.AA5 123.06,53.46 v2(122.64,53.04) ; RV21.1 112.85,97.37 112.46,97.76 v2(112.46,98.48) ; v2(123.29,120.38) 123.3,120.38 UV1.B26 ; UV1.AD6 v2(107.24,103.56) ; v2(126.77,55.71) UC1.U1 125.95,55.72 125.93,55.72 125.88,55.78 125.35,55.78 125.3,55.72 125.28,55.72 UC1.U2 UC1.U3 124.46,55.81 124.46,56.18 124.4,56.23 124.4,56.3 v2(124.4,56.3) 124.4,56.65 UC1.R3 ; UC1.E21 114.92,61.91 v2(115.22,61.61) ; v2(113.8,112.29) 114.21,112.7 UV1.R17 ; UC1.AU25 112.2,45.11 v2(111.92,45.39) 111.4,45.91 UC1.AR27 v2(111.93,46.48) ; UC1.C13 118.9,63.24 118.5,63.24 v2(118.5,63.24) 118.5,63.24 118.13,63.24 UC1.C15 ; v2(120.71,63.21) 120.36,63.21 UC1.C11 ; UC1.BA39 104.71,41.74 v2(104.59,41.63) ; UV1.Y10 109.34,107.1 v2(109.34,107.11) 109.33,107.1 UV1.AB10 ; UV1.V16 112.3,112.7 UV1.U17 ; UV1.N25 UV1.P25 114.18,119.62 v2(114.06,119.62) ; v2(126.46,42.45) 126.1,42.81 UC1.AY1 ; UC1.AU21 114.35,45.42 v2(114.2,45.42) 113.7,45.91 UC1.AR23 ; UC1.B13 UC1.A13 119.01,64.86 119.01,65.56 v2(119.06,65.61) ; v2(113.99,65.32) 113.56,64.89 UC1.A23 ; UC1.AJ3 124.36,49.31 124.36,49.6 124.4,49.64 v2(124.4,49.65) 124.41,49.65 124.36,49.7 124.36,50.01 UC1.AG3 ; YV1.2 97.17,121.06 CV18.2 v2(98.97,121.06) ; UC1.A32 UC1.B32 ; v2(114.23,60.73) 114.2,60.73 113.83,61.11 UC1.G23 ; v2(121.5,103.46) 121.5,103.7 UV1.F6 ; v2(102.57,45.79) 102.59,45.81 UC1.AR41 ; UV1.F20 121.58,115.1 121.72,115.24 v2(121.76,115.24) ; v2(115.2,105.11) 115.2,104.2 UV1.P6 ; v2(123.8,115.21) 123.72,115.13 123.36,115.13 123.33,115.1 UV1.B20 ; RV89.1 100.02,106.06 100.35,106.39 v2(100.35,106.76) ; UC1.C25 112.26,63.21 v2(111.91,63.21) 111.56,63.21 UC1.C27 ; v2(108.88,103.53) 108.51,103.9 UV1.AB6 ; v2(118.47,107.59) 118.47,107.73 UV1.K11 ; v2(121.97,116.54) 121.94,116.54 121.94,116.57 121.43,116.57 UV1.F22 ; UV1.AD8 v2(106.54,105.14) ; UC1.G27 110.96,61.51 110.89,61.51 v2(110.85,61.55) 110.8,61.55 110.44,61.91 UC1.E29 ; UC1.C19 115.96,63.21 116.24,63.21 116.25,63.22 116.31,63.22 v2(116.35,63.26) 116.36,63.26 116.71,63.26 UC1.C17 ; v2(113.56,41.41) UC1.BA23 ; v2(102.5,48.01) UC1.AL41 ; v2(122.26,41.63) 122.26,42.11 UC1.BA7 ; v2(123.97,110.17) 123.91,110.22 123.38,110.22 UV1.B14 ; UV1.AB32 108.5,123.3 v2(108.86,123.66) ; UV1.M6 116.5,103.39 v2(116.5,103.39) ; v2(100.98,116.67) 100.95,116.69 99.72,116.69 CV64.2 ; v2(102.84,63.58) 102.97,63.46 UC1.C41 ; UV1.C32 123.29,123.49 v2(123.29,123.52) ; UV1.T6 v2(112.88,104.32) ; UC1.AJ5 123.06,48.91 v2(122.8,48.65) ; v2(102.51,49.99) 102.51,49.99 102.73,50.21 UC1.AG41 ; v2(126.58,48.09) 126.5,48.01 UC1.AL1 125.9,48.07 125.88,48.07 125.87,48.08 125.35,48.08 125.34,48.07 125.33,48.07 UC1.AL2 UC1.AL3 124.36,47.81 v2(124.36,47.46) 124.49,47.33 124.49,47.29 124.56,47.22 UC1.AN3 ; v2(123.35,101.78) 123.18,101.78 UV1.C1 ; v2(106.96,65.61) UC1.A35 ; v2(107.05,123.68) 106.9,123.53 UV1.AD32 ; v2(118.86,123.23) 118.81,123.28 118.28,123.28 UV1.K32 ; YV1.4 94.9,124.43 v2(95.46,124.99) ; UC1.BA11 120.16,41.55 120.26,41.45 120.26,40.66 v2(120.27,40.66) ; UC1.AA3 124.42,53.65 124.42,53.84 124.41,53.85 124.41,54.06 v2(124.4,54.08) 124.41,54.09 124.41,54.27 124.42,54.28 124.42,54.47 UC1.W3 ; UV1.A30 124.25,122.3 124.29,122.26 v2(124.29,122.29) ; UV1.J27 v2(118.9,121.37) ; RV368.1 v2(114.66,99.97) ; v2(107.32,106.68) UV1.AC9
  BOTTOM w0.356: v2(119.92,90.16) 120.52,90.16 120.88,89.8 UV3.3 ; UC63.3 126.91,91.47 127.08,91.65 127.46,91.65 127.59,91.52 v2(127.59,91.33)
  BOTTOM w0.381: v2(116.62,124.04) 116.95,124.36 CV94.2 ; CV95.2 118.73,126.68 v2(118.59,126.82) ; UV1.H17 119.7,112.94 120.24,113.47 120.71,113.47 v2(120.76,113.52) ; RV35.2 119.17,127.1 v2(119.04,127.23)
  BOTTOM w0.406: EU3501.3 v2(32.28,110.51)
  BOTTOM w0.457: UC4.3 108.46,27.59 v2(108.73,27.32)
  BOTTOM w0.508: v2(189.57,23.13) RS18.2 RS36.2 ; v2(205.42,24.86) 205.42,22.57 206.44,21.55 PC7.2 206.84,20.64 PC8.2 ; v2(164.76,83.03) 164.03,83.76 164.03,84.6 164.94,85.51 SW1.1 ; PR118.2 v2(199.05,32.3) ; v2(105.48,95.14) 105.48,95.78 C983.1 ; C796.2 v2(130.25,61.54) ; v2(152.95,83.1) 152.52,83.54 PC1405.2 PC1406.2 ; CS42.2 200.74,25.56 RS24.2 RS21.2 v2(201.38,26.69) ; PC804.2 134.39,9.99 134.89,9.48 v2(134.89,9.29) 134.96,9.23 C2619.2 ; JRTC1.2 v2(28.58,4.44) ; CV186.2 v2(124.17,93.34) ; PC401.2 v2(96.23,17.29) ; v2(110.36,36.76) 110.38,36.76 110.38,36.98 110.38,37.23 110.38,37.23 RC709.1 ; v2(161.46,102.43) 161.46,102.43 162.33,102.43 C38.1 ; C26.1 152.47,20.27 C349.1 C5219.2 151.81,22.12 151.79,22.09 v2(151.68,22.09) ; RC694.1 v2(133.24,54.88) ; RV83.2 109.29,96.6 v2(109.88,96.6) ; v2(11.39,6.75) 12.72,8.08 DA2.1 ; DX2.1 v2(221.53,30.35) ; v2(102.42,98.94) 101.9,98.42 C625.1 ; v2(37.36,120.48) CL10.2 37.48,119.74 YL1.4 ; PD6.2 v2(164.08,127.97) ; CC120.2 37.8,7.57 v2(38.95,8.72) ; v2(218.9,48.94) 218.89,48.94 R5.2 ; CV391.2 RV51.2 RV121.2 142.08,94.64 v2(142.07,94.63) ; PC602.2 PR602.1 v2(34.56,102) ; v2(187.54,33.1) 187.17,32.73 CE24.2 CE33.2 ; PBATT1.11 v2(228.99,14.11) ; v2(176.36,16.5) 176.6,16.74 JIOB1.10 ; JIOB1.1 185.6,17.2 185,16.59 v2(184.93,16.59) ; PR738.2 161.34,106.76 v2(161.71,106.76) ; v2(113.69,90.7) 113.11,90.7 112.29,91.52 C621.1 ; v2(220.05,35.83) R7.2 RP2.2 ; DA4.1 16.43,11.49 v2(16.4,11.51) ; PC119.2 194.03,33.31 v2(194.08,33.36) ; v2(91.68,103.24) 92.08,102.84 92.08,102.11 91.72,101.75 PC213.2 ; PD4.1 157.66,121.54 v2(157.27,121.14) ; JH1.4 UC5.4 112.85,21.48 113.36,21.99 v2(113.36,22.69) ; CC30.2 RC926.2 111.02,27.5 CC14.2 ; CC30.2 113.3,28.15 v2(113.18,28.02) ; CC30.2 RC927.2 ; v2(145.59,130.04) RV132.2 145.58,128.88 CV395.2 ; C19.2 97.04,11.27 v2(97.05,11.26) ; JDIMM2.261 v2(32.09,88.05) ; v2(184.07,22.58) 184.08,22.58 184.08,22.57 Q91.3 ; v2(171.34,44.81) 171.38,44.81 PC111.2 ; v2(156.99,83.01) PR1411.2 PR1407.2 ; PC126.2 195.27,32.96 v2(195.66,33.36) ; JHDD1.14 191.85,15.16 v2(191.86,15.17) ; JRTC1.4 31.03,3 v2(30.83,2.8) ; v2(152.72,30.55) 152.09,30.55 151.58,31.06 PC309.2 ; JRTC1.3 27.43,3 v2(27.63,2.8) ; RE24.1 CE47.2 166.26,41.75 166.26,42.12 v2(166.45,42.31) ; v2(220.02,46.08) 220.71,46.08 RP1.2 ; v2(142.41,15.03) 142.41,14.84 143.09,14.16 143.09,13.48 143.54,13.02 Q83.3 ; v2(142.88,130.07) 142.88,128.98 RV55.2 ; v2(163,54.3) 162.64,54.65 PH1001.1 ; CV17.2 97.91,124.68 CV46.2 97.74,124.73 97.2,125.26 v2(97.01,125.26) ; v2(80.47,22.37) 80.47,23.2 80.16,23.51 CLRP1.2 ; v2(117.16,4.96) 117.19,4.96 117.55,5.32 JKBBL1.5 ; v2(148.53,22.69) 148.75,22.47 C2324.2 ; PR1404.2 PC1404.2 v2(158.66,86.42) ; v2(83.08,102.32) 82.57,102.82 PC204.1 ; R1563.2 CE23.2 178.58,18.96 v2(178.55,18.92) 177.6,17.98 JIOB1.9 ; 170.58,54.25 v2(170.58,52.98) ; v2(178.85,43.24) 178.85,42.07 179.36,41.56 RE46.2 ; v2(181.44,16.46) 181.6,16.63 JIOB1.5 ; v2(111.34,95.77) 111.39,95.71 C620.1 ; v2(39.01,115.84) 38.2,115.84 RL2.1 37.74,116.3 37.74,116.78 CL11.2 ; PC210.2 91.04,102.82 v2(91.04,103.26) ; RC643.2 132.68,53.42 v2(133.25,53.42) ; C797.2 v2(130.31,64.23) ; v2(172.94,42.38) 173.12,42.2 CE40.1 ; RE22.1 CE39.2 v2(164.87,18.91) ; PR605.2 v2(33.55,105.56) ; JODD1.2 187.5,49.31 v2(187.5,49.31) 187.5,49.3 JODD1.1 ; C636.2 122.28,23.21 v2(122.8,22.69) ; v2(142.48,96.78) 141.84,96.14 141.84,96.05 141.33,95.55 CV333.2 CV153.2 ; v2(133.12,12.21) 133.42,12.51 PC803.2 ; v2(133.19,3.27) 132.88,3.58 130.52,3.58 C2618.2 128.84,2.62 128.77,2.69 U2.4 ; C24.1 C987.1 159.28,17.86 v2(159.67,17.47) ; PC752.1 217.9,48.96 v2(217.83,49.04) ; v2(137.34,13.36) 137.42,13.43 PC805.2 ; v2(164.43,11.93) 164.43,12.08 C2309.2 ; RV34.2 116.22,126.21 RV39.1 115.48,126.95 v2(115.39,126.95) ; JTP1.10 95.07,8.21 94.57,8.72 v2(94.25,8.72) ; PD5.2 v2(166.53,127.73) ; v2(187.76,53.63) 185.5,53.63 184.83,54.3 JFAN1.4 ; JEDP1.41 v2(227.68,27.71) ; RS35.2 v2(201.32,30.75) ; JODD1.8 190.5,49.68 190.33,49.51 190.33,48.49 190.5,48.32 JODD1.7 190.5,46.33 v2(190.65,46.18) ; JDIMM1.261 77.92,87.65 74.95,87.65 73.76,86.46 v2(73.76,86.46) ; JSPK1.6 v2(8.84,1.8) ; JFAN1.5 179.08,53.75 v2(180.3,52.53) ; v2(162.46,71.14) 162.25,71.35 PH1002.1 ; v2(123.34,18.43) 123.34,18.14 122.74,17.54 CC635.2 ; PH1101.1 69.76,108.87 v2(70.38,109.49) ; JODD1.14 v2(193.5,49.36) 193.5,47.85 ; v2(138.77,26.62) 138.7,26.56 138.64,26.56 138.63,26.55 138.12,26.55 138.11,26.56 135.89,26.56 134.84,25.51 Q84.3 ; v2(118.19,94.38) 118.19,94.7 118.51,95.01 RV369.2 ; C2318.2 161.6,23.28 161.81,23.28 v2(161.88,23.21) ; CC52.2 131.02,48.28 130.98,48.32 v2(130.93,48.32) ; JWLAN1.69 v2(62.65,102.76) ; v2(109.61,6.98) 109.23,6.98 108.78,6.53 JTP1.9 ; RC1.1 CC615.2 110.76,31.82 v2(110.39,31.44) ; UL3.2 v2(25.42,121.24) ; C939.2 136.41,17.09 C46.2 137.43,16.02 v2(137.5,15.96) ; RC41.1 133.26,51.83 v2(133.28,51.81) ; v2(107.91,23.07) 107.72,23.26 CC16.2 RC26.1 ; PC1408.2 146.38,91.74 v2(145.87,92.26) ; CL8.2 v2(36.6,113.86) ; v2(42.31,8.78) 43.2,7.89 CC119.2 ; C2322.1 C2316.2 161.02,22.6 v2(161.66,22.6) ; JFAN1.6 183.44,57.23 v2(184.57,57.23) ; v2(153.99,10.86) 153.99,11.3 153.7,11.59 JLED1.1 ; PC711.1 216.75,37.56 v2(216.52,37.79) ; JIOB1.18 v2(167.78,12.9) ; YL1.2 v2(40.49,116.37) ; RE48.2 v2(167.15,42.31) ; v2(105.35,92.37) 105.89,92.91 C623.1 ; C34.2 120.35,9.35 v2(122.32,9.35) ; JODD1.26 186.23,49.12 v2(186.46,49.35) ; v2(89.44,97.21) 89.58,97.21 90.32,97.94 PR204.2 ; RC646.2 116.03,34.36 v2(116.54,33.85) 116.75,33.85 117.5,33.1 RC903.2 ; CC53.2 v2(130.88,49.55) RC952.2 ; JEDP1.42 228.89,51.75 v2(229.76,50.88) ; v2(163.52,108.16) C36.1 164.17,109.17 C47.2 ; v2(118.49,3.56) 118.49,3.09 118.77,2.81 R2636.1 ; v2(147.85,22.65) 147.85,22.36 148.04,22.17 C940.2 ; PR803.2 v2(134.89,11.77) 135.15,11.51 PQ801.3 ; C45.2 197.52,45.94 198.17,46.59 v2(198.27,46.59) ; v2(134.67,37.01) 134.3,36.64 CC686.2 ; JSPK1.5 v2(11.71,1.8) ; v2(134.59,33.29) RC703.1 RC695.1 RC696.1 ; JDIMM2.262 36.95,18.29 v2(37.14,18.1) ; PBATT1.12 v2(204.79,14.1) ; DA1.1 v2(8.66,7.19) ; RL6.1 v2(21.48,121.94) ; RS31.2 v2(189.63,30.24) ; JKBBL1.6 110.9,6.49 v2(110.41,6.98) ; RS22.1 RS23.2 v2(189.57,27.2) 189.52,27.25 CS27.2 ; JODD1.25 v2(200.75,50.88) ; JKB1.31 v2(89.28,7.02) ; U74.2 v2(109.75,92.84) ; C2307.2 157.73,3.27 v2(157.73,4.84) ; v2(150.95,10.97) 150.95,11.52 150.7,11.77 JLED1.4 ; UC101.2 40.56,7.84 v2(39.68,8.72) ; JLED1.5 v2(156.7,7.54) ; C43.2 163.84,78.61 v2(164.52,79.29) ; JIOB1.6 v2(180.6,16.46) ; DU1.1 v2(166.05,15.51) ; PC601.2 v2(40.34,104.6) ; C2323.2 v2(149.63,27.89) ; PR9.1 161.26,129.99 v2(161.64,129.61) PQ5.3 ; PC1062.1 PR1076.1 ; RV117.2 RV131.2 v2(145.17,113.72) ; v2(183.09,34.31) 183.6,33.8 CE25.2 ; v2(106.95,18.75) PC405.2 ; CV179.2 97.29,109.83 RV88.1 95.98,109.82 v2(95.84,109.68) ; CV123.2 v2(95.97,114.76) ; v2(35.36,123.25) 35.8,122.81 RL4.2 ; CE56.2 v2(123.21,12.46) ; JIOB1.17 v2(188.43,16.34) ; v2(16.73,97.67) 17.44,97.67 PC905.2 ; v2(177.57,41.67) 177.57,42.21 178.07,42.72 PR110.2 ; JHDD1.13 v2(200.95,11.93) ; RC40.1 v2(133.24,50.82) ; C344.1 C343.1 v2(98.43,96.15) ; CLIP2.1 v2(36.79,13.54) ; RP3.2 v2(220.05,37.86) ; PC607.2 v2(41.8,99.01) ; v2(138.06,22.19) 137.94,22.07 C16.2 ; v2(83.08,99.9) 83.08,99.65 82.51,99.08 PC209.2 ; v2(184.17,18.56) 184.6,18.13 JIOB1.2 ; PC203.2 PC202.2 v2(87.65,98.32) ; CC32.1 RC42.1 v2(133.18,47.33) ; v2(119.97,31.39) 119.97,31.64 119.65,31.96 C27.2 ; JKB1.32 v2(63.13,7.3) ; v2(133.19,45.18) 132.68,45.18 132.64,45.23 RC711.1 ; JWLAN1.68 v2(41.95,102.7) ; v2(218.66,45.84) 218.92,46.09 PC749.1 ; 168.74,58.18 PC1018.1 PR1018.1 PC1064.2 ; CC682.2 133.63,39.35 v2(134.72,39.35) ; JLED1.6 v2(147.7,7) ; JTP1.5 100.9,8.87 v2(101.18,8.59) ; PC1059.2 v2(167.66,66.91) ; CL9.2 v2(29.18,123.7) ; CV38.2 v2(95.59,125.81)
  vias: v2(0.58,97.12) v2(0.86,95.29) v2(2.1,11.17) v2(2.1,7.08) v2(2.15,78.63) v2(2.41,0.58) v2(2.81,45.99) v2(2.81,26.62) v2(2.94,30.5) v2(3.07,52.32) v2(3.84,71.36) v2(3.83,10.51) v2(3.85,75.1) v2(3.86,67.38) v2(4.27,28.46) v2(4.81,48.63) v2(5,8.48) v2(5.23,95.24) v2(5.48,70.03) v2(6.14,78.76) v2(6.45,73.71) v2(6.59,122.3) v2(7.31,27.05) v2(7.42,49.7) v2(7.55,67.06) v2(7.49,45.36) v2(7.65,124.13) v2(7.65,120.47) v2(7.87,30.65) v2(8.33,0.5) v2(8.64,75.99) v2(8.68,52.37) v2(8.82,46.86) v2(8.88,95.78) v2(9.14,78.28) v2(9.48,69.89) v2(9.62,28.95) v2(9.75,124.13) v2(9.75,120.47) v2(9.95,92.68) v2(9.98,81.45) v2(10.39,26.58) v2(10.61,67.06) v2(10.59,45.33) v2(10.71,30.65) v2(10.81,122.3) v2(11.08,48.52) v2(12.34,124.78) v2(12.6,74.22) v2(12.67,27.82) v2(12.82,65.17) v2(12.82,54.3) v2(12.77,43.43) v2(12.8,32.68) v2(13.2,0.53) v2(13.44,69.98) v2(14.52,49.12) v2(16.29,4.3) v2(16.78,101.43) v2(16.78,100.79) v2(17.34,124.81) v2(17.35,6.13) v2(17.35,2.47) v2(17.48,67.46) v2(17.48,47.64) v2(18.12,67.46) v2(18.12,47.64) v2(19.01,54.56) v2(19.07,34.94) v2(19.2,120.68) v2(19.26,67.46) v2(19.26,47.64) v2(19.45,6.13) v2(19.45,2.47) v2(19.83,120.67) v2(19.81,88.73) v2(19.77,86.89) v2(19.83,83.2) v2(19.83,81.23) v2(19.84,67.46) v2(19.84,47.64) v2(20.51,4.3) v2(20.59,55.14) v2(20.78,80.47) v2(20.85,78.57) v2(20.85,35.51) v2(20.91,86.25) v2(20.91,84.22) v2(22.45,124.81) v2(22.44,98.19) v2(22.5,101.11) v2(22.73,0.5) v2(22.88,101.68) v2(23.13,98.19) v2(23.2,101.11) v2(23.2,80.47) v2(23.2,78.63) v2(23.9,81.3) v2(24.15,83.2) v2(24.21,68.6) v2(24.21,59.14) v2(24.21,37.99) v2(24.28,57.23) v2(24.28,39.9) v2(24.53,70.44) v2(24.53,69.8) v2(24.89,84.29) v2(24.96,35.26) v2(25.26,86.04) v2(25.93,88.92) v2(25.99,27.2) v2(25.99,25.23) v2(26.12,35.01) v2(26.5,88.03) v2(26.46,0.53) v2(26.69,42.18) v2(26.91,54.08) v2(26.91,40.25) v2(27.13,103.02) v2(27.13,55.9) v2(27.33,61.38) v2(27.33,59.34) v2(27.53,124.79) v2(27.83,103.02) v2(27.96,27.2) v2(27.96,25.23) v2(29.17,118.32) v2(29.55,96.28) v2(29.74,119.14) v2(29.93,29.16) v2(29.93,27.2) v2(29.93,25.23) v2(30.3,96.33) v2(31.35,0.51) v2(32.18,118.99) v2(32.18,117.87) v2(32.18,116.76) v2(32.61,124.79) v2(33.29,118.99) v2(33.29,117.87) v2(33.29,116.76) v2(34.41,118.99) v2(34.41,117.87) v2(34.41,116.76) v2(36.09,98.89) v2(36.09,97.55) v2(36.15,102.06) v2(36.15,100.16) v2(36.44,16.41) v2(36.44,15.8) v2(36.43,0.51) v2(36.93,105.77) v2(36.93,104.48) v2(37.18,69.42) v2(37.17,68.73) v2(37.17,64.72) v2(37.17,63.96) v2(37.69,124.79) v2(37.87,69.42) v2(37.87,68.73) v2(37.87,64.72) v2(37.87,63.96) v2(38,105.13) v2(38.69,61.3) v2(38.76,66.88) v2(38.88,57.68) v2(39.06,105.77) v2(39.06,104.48) v2(39.39,54.63) v2(39.71,53.42) v2(39.83,115.35) v2(40.53,56.85) v2(40.53,52.22) v2(40.53,45.99) v2(40.66,59.77) v2(40.79,115.14) v2(41.04,55.33) v2(41.04,48.91) v2(41.04,47.52) v2(41.04,44.66) v2(41.04,43.71) v2(41.51,0.51) v2(42.21,125.54) v2(42.44,133.09) v2(42.41,128.03) v2(44.02,95.46) v2(44.11,136.47) v2(44.72,19.8) v2(45.42,99) v2(45.62,96.14) v2(45.99,19.13) v2(46.06,86.44) v2(46.12,83.46) v2(46.06,82.44) v2(46.12,81.36) v2(46.12,74.82) v2(46.06,73.87) v2(46.18,85.43) v2(46.18,77.87) v2(46.25,44.98) v2(46.31,84.41) v2(46.69,0.51) v2(46.76,64.85) v2(46.95,69.8) v2(47.07,70.82) v2(47.23,99.03) v2(47.16,72.92) v2(47.26,76.37) v2(47.65,137.99) v2(47.9,68.34) v2(48.18,80.33) v2(48.22,65.99) v2(48.28,79.01) v2(48.58,73.22) v2(49.02,99) v2(50.89,96.17) v2(51.14,62.25) v2(51.77,0.51) v2(52.03,18.88) v2(52.16,124.76) v2(52.16,123.24) v2(52.16,121.71) v2(52.78,96.12) v2(53.69,124.76) v2(53.69,123.24) v2(53.69,121.71) v2(54.38,73.12) v2(54.48,80.84) v2(54.5,40.72) v2(54.58,85.82) v2(54.69,44.53) v2(54.69,19.08) v2(54.94,42.44) v2(54.99,76.47) v2(55.21,124.76) v2(55.21,123.24) v2(55.21,121.71) v2(55.39,84.4) v2(55.71,43.2) v2(55.96,19.08) v2(56.18,137.99) v2(56.61,85.51) v2(56.85,0.51) v2(57.42,18.56) v2(57.93,19.83) v2(58.34,78.1) v2(58.49,42.76) v2(58.74,137.69) v2(58.95,40.28) v2(59.05,88.66) v2(59.05,67.63) v2(59.18,96.37) v2(60.46,96.42) v2(60.98,137.51) v2(61.59,88.26) v2(61.93,0.51) v2(63.65,124.54) v2(63.65,123.84) v2(63.65,123.21) v2(63.65,122.57) v2(63.65,117.05) v2(63.65,116.41) v2(63.65,115.78) v2(63.75,137.51) v2(63.77,38.07) v2(64.2,68.37) v2(64.28,124.54) v2(64.28,123.84) v2(64.28,123.21) v2(64.28,122.57) v2(64.28,117.05) v2(64.28,116.41) v2(64.28,115.78) v2(64.28,107.97) v2(64.64,74.03) v2(64.92,124.54) v2(64.92,123.84) v2(64.92,123.21) v2(64.92,122.57) v2(64.92,117.05) v2(64.92,116.41) v2(64.92,115.78) v2(65.53,66.41) v2(65.62,125.18) v2(65.62,124.54) v2(65.62,123.84) v2(65.62,123.21) v2(65.62,122.57) v2(65.55,115.78) v2(65.63,115.16) v2(65.55,107.97) v2(65.62,67.85) v2(66.12,121.87) v2(66.12,119.72) v2(66.19,115.78) v2(66.24,115.14) v2(66.25,125.18) v2(66.25,124.54) v2(66.25,123.84) v2(66.25,123.21) v2(66.25,122.57) v2(66.54,137.48) v2(66.82,121.87) v2(66.76,119.65) v2(66.76,119.02) v2(66.82,115.78) v2(66.82,115.14) v2(66.95,125.18) v2(66.95,124.54) v2(66.95,123.84) v2(66.95,123.21) v2(66.95,122.57) v2(67.01,0.51) v2(67.48,83.11) v2(67.69,80.65) v2(67.69,76.78) v2(67.77,106.76) v2(67.89,70.38) v2(68.09,107.33) v2(68.09,78.81) v2(68.3,86.33) v2(68.41,106.76) v2(69.34,137.74) v2(69.49,18.58) v2(70.2,18.58) v2(71.78,137.99) v2(72.04,0.51) v2(75.59,120.99) v2(76.35,120.99) v2(76.35,118.32) v2(76.35,117.62) v2(76.35,116.99) v2(76.35,116.35) v2(76.96,137.99) v2(77.05,120.99) v2(77.12,0.51) v2(77.74,120.99) v2(77.81,100.79) v2(77.81,100.16) v2(77.87,127.59) v2(77.87,126.7) v2(77.87,125.94) v2(77.87,124.99) v2(78.44,100.79) v2(78.44,100.16) v2(78.38,22.05) v2(79.08,100.79) v2(79.08,100.16) v2(79.65,22.37) v2(79.71,100.79) v2(79.71,100.16) v2(80.35,100.79) v2(80.35,100.16) v2(80.73,67.9) v2(80.98,100.79) v2(80.98,100.16) v2(81.22,39.13) v2(81.81,39.13) v2(81.88,137.79) v2(82.2,0.51) v2(82.36,38.94) v2(82.57,135.32) v2(82.63,108.22) v2(82.63,107.59) v2(82.91,39.13) v2(83.27,107.59) v2(84.35,103.97) v2(84.54,111.6) v2(85.36,63.41) v2(85.52,135.4) v2(85.72,113.65) v2(85.72,109.55) v2(86.2,137.89) v2(86.55,103.15) v2(86.63,63.41) v2(87.17,103.77) v2(87.17,102.52) v2(87.33,0.51) v2(87.79,103.15) v2(87.9,63.41) v2(88.08,113.65) v2(88.08,109.55) v2(88.35,34.88) v2(88.54,45.81) v2(88.55,42.74) v2(89.17,63.41) v2(89.24,34.76) v2(89.26,111.6) v2(89.36,121.81) v2(89.36,121.18) v2(89.43,107.65) v2(89.36,94.19) v2(89.43,45.87) v2(89.88,137.99) v2(90.01,107.65) v2(89.98,94.16) v2(90.13,131.46) v2(90.13,130.83) v2(90.19,63.41) v2(90.19,45.87) v2(90.44,122.7) v2(90.63,107.65) v2(90.89,131.46) v2(90.89,130.83) v2(91,34.99) v2(91.08,122.7) v2(91.21,63.41) v2(91.21,45.85) v2(91.27,107.65) v2(92.03,34.94) v2(92.41,0.51) v2(92.54,131.46) v2(92.54,130.83) v2(92.56,46.06) v2(93.16,131.48) v2(93.16,130.84) v2(93.24,62.99) v2(93.24,46.06) v2(93.37,72.28) v2(93.43,71.15) v2(93.93,46.06) v2(94.13,43.49) v2(94.25,62.88) v2(94.44,71.84) v2(94.64,13.73) v2(94.68,35.39) v2(94.76,43.49) v2(94.96,137.99) v2(95.33,13.73) v2(97.49,0.51) v2(98.99,127.7) v2(100.04,137.99) v2(100.1,132.48) v2(100.13,94.78) v2(101.43,20.21) v2(101.45,125.16) v2(101.49,18.43) v2(101.68,132.48) v2(101.81,96.6) v2(101.91,94.78) v2(102.26,18.43) v2(102.57,0.51) v2(103.4,132.54) v2(105.12,137.99) v2(105.24,132.35) v2(105.16,44.01) v2(105.37,125.68) v2(106.08,13.98) v2(106.19,131.27) v2(106.69,68.84) v2(106.76,127.65) v2(106.76,125.81) v2(107.59,129.88) v2(107.61,43.83) v2(107.65,0.51) v2(108.99,51.73) v2(108.99,48.57) v2(109.21,56.95) v2(109.39,50.01) v2(110.01,116.26) v2(110.14,48.83) v2(110.26,137.99) v2(110.76,126.51) v2(111.14,134.5) v2(111.17,56.9) v2(111.16,52.86) v2(111.93,56.98) v2(111.91,47.2) v2(111.96,43.77) v2(112.03,36.66) v2(112.12,52.88) v2(112.16,55.3) v2(112.32,136.55) v2(112.32,132.45) v2(112.73,0.51) v2(113.2,57.79) v2(113.25,55.94) v2(113.49,37.8) v2(114,71.52) v2(114.11,43.81) v2(114.22,53.03) v2(114.16,49.8) v2(114.29,52.04) v2(114.26,36.67) v2(114.68,136.55) v2(114.68,132.45) v2(115.1,16.46) v2(115.17,57.76) v2(115.16,49.83) v2(115.27,55.12) v2(115.86,134.5) v2(115.87,116.16) v2(116.16,49.8) v2(116.33,138) v2(116.8,16.15) v2(117.11,49.8) v2(117.16,55.76) v2(117.2,51.83) v2(117.64,40.86) v2(117.81,0.51) v2(118.13,50.16) v2(118.63,133.44) v2(118.93,54.02) v2(118.92,52.01) v2(119.15,57.1) v2(119.15,50.13) v2(120.11,50.12) v2(120.23,80.42) v2(120.49,78.71) v2(120.54,55.16) v2(120.49,49.67) v2(120.66,43.8) v2(121.84,132.31) v2(122.89,0.51) v2(122.96,9.35) v2(124.36,45.26) v2(124.37,44.09) v2(124.84,135.43) v2(125.15,24.31) v2(126,87.04) v2(126,81.04) v2(126.29,137.99) v2(127.24,82.12) v2(127.85,18.12) v2(127.97,0.51) v2(128.29,56.6) v2(128.48,18.12) v2(128.91,11.83) v2(129.5,11.83) v2(129.94,57.04) v2(130.18,57.69) v2(131.37,137.99) v2(133.05,0.51) v2(133.24,42.84) v2(133.64,130.05) v2(133.78,85.83) v2(134.14,90.5) v2(134.54,130.08) v2(135.05,85.87) v2(135.19,40.56) v2(135.32,92.55) v2(135.32,88.45) v2(135.45,130.07) v2(135.74,85.87) v2(136.1,42.06) v2(136.44,85.87) v2(136.45,137.99) v2(136.52,130.07) v2(137.21,135.73) v2(137.31,83.14) v2(137.68,92.55) v2(137.68,88.45) v2(138.01,83.14) v2(138.13,0.51) v2(138.49,130.07) v2(138.64,68.73) v2(138.64,68.03) v2(138.7,83.14) v2(138.74,28.27) v2(138.83,31.3) v2(138.77,30.03) v2(138.86,90.5) v2(138.92,34.24) v2(138.9,32.79) v2(139.28,68.73) v2(139.28,68.03) v2(139.47,83.14) v2(139.76,130.07) v2(139.79,61.2) v2(139.79,6.3) v2(140.85,63.03) v2(140.85,59.37) v2(140.85,8.13) v2(140.85,4.47) v2(141.07,135.96) v2(142.01,89.9) v2(141.99,89.31) v2(141.99,88.66) v2(141.99,88.08) v2(142.02,87.48) v2(142.01,86.87) v2(142.02,86.29) v2(142.03,85.7) v2(141.98,81.49) v2(141.97,66.73) v2(142.13,38.05) v2(142.13,37.42) v2(142.27,130.04) v2(142.68,81.49) v2(142.83,38.05) v2(142.83,37.42) v2(142.95,63.03) v2(142.95,59.37) v2(142.95,8.13) v2(142.95,4.47) v2(143.21,0.51) v2(143.31,81.49) v2(143.58,66.29) v2(143.95,81.49) v2(144.01,61.2) v2(144.01,6.3) v2(144.17,66.29) v2(144.75,66.3) v2(144.75,65.65) v2(145.28,135.99) v2(145.35,66.27) v2(145.33,65.65) v2(145.54,29.89) v2(145.54,29.3) v2(145.46,27.95) v2(145.85,30.38) v2(147.54,129.88) v2(147.7,94.06) v2(147.85,62.12) v2(148.55,62.12) v2(148.74,60.85) v2(148.93,45.29) v2(149.05,61.49) v2(149.05,60.22) v2(149.1,48.04) v2(149.1,47.41) v2(149.08,46.77) v2(149.08,46.13) v2(149.31,0.53) v2(149.37,62.12) v2(149.44,60.85) v2(149.46,129.52) v2(149.55,45.29) v2(149.57,94.64) v2(149.55,44.66) v2(149.82,61.49) v2(149.82,60.22) v2(150.07,72.54) v2(150.13,62.12) v2(150.13,60.85) v2(150.13,45.29) v2(150.13,44.71) v2(150.36,135.99) v2(150.64,61.49) v2(150.64,60.22) v2(150.83,72.54) v2(150.76,45.29) v2(150.77,44.71) v2(150.85,50.16) v2(150.86,49.34) v2(150.96,62.12) v2(150.96,60.85) v2(151.02,59.58) v2(151.34,61.49) v2(151.34,60.22) v2(151.34,45.29) v2(151.4,130.32) v2(151.37,44.7) v2(151.72,94.64) v2(151.66,72.54) v2(151.66,62.12) v2(151.66,60.85) v2(151.72,59.58) v2(152.04,61.49) v2(152.04,60.22) v2(151.98,45.28) v2(151.98,44.7) v2(152.34,129.48) v2(152.36,72.54) v2(152.36,62.12) v2(152.36,60.85) v2(152.42,59.58) v2(152.36,46.58) v2(152.46,29.19) v2(152.64,80.1) v2(152.61,45.28) v2(152.61,44.7) v2(152.74,61.49) v2(152.74,60.22) v2(152.75,135.02) v2(152.99,46.56) v2(152.99,45.98) v2(153,29.42) v2(152.98,28.83) v2(153.06,62.12) v2(153.06,60.85) v2(153.12,59.58) v2(153.19,45.29) v2(153.25,44.71) v2(153.19,0.51) v2(153.31,80.09) v2(153.41,30.49) v2(153.39,29.9) v2(153.5,61.49) v2(153.5,60.22) v2(153.54,48.2) v2(153.61,29.36) v2(153.82,62.12) v2(153.82,60.85) v2(153.82,45.16) v2(153.82,44.53) v2(153.94,80.05) v2(153.88,28.82) v2(154,29.93) v2(154.2,30.5) v2(154.22,29.32) v2(154.31,109.68) v2(154.26,61.61) v2(154.26,60.34) v2(154.45,45.1) v2(154.71,121.45) v2(154.66,29.91) v2(154.85,30.52) v2(154.82,29.3) v2(154.76,28.72) v2(154.98,105.77) v2(155.02,104.69) v2(155.02,80.09) v2(155.09,61.68) v2(155.09,61.04) v2(155.09,45.17) v2(155.09,44.58) v2(155.2,64.79) v2(155.26,29.91) v2(155.43,29.3) v2(155.51,30.54) v2(155.66,80.09) v2(155.72,66.95) v2(155.72,66.25) v2(155.67,45.17) v2(155.79,64.79) v2(155.79,61.68) v2(155.79,60.98) v2(155.79,60.28) v2(155.79,59.33) v2(155.79,58.63) v2(155.86,44.62) v2(155.86,29.91) v2(156.13,87.95) v2(156.17,30.55) v2(156.29,80.05) v2(156.25,45.23) v2(156.48,44.66) v2(156.74,21.86) v2(156.87,45.15) v2(156.98,80.05) v2(157.18,44.6) v2(157.37,134.99) v2(157.5,45.1) v2(157.9,44.57) v2(158.14,45.1) v2(158.27,0.51) v2(158.52,88.22) v2(158.5,32.75) v2(158.5,31.55) v2(158.64,44.53) v2(158.77,45.1) v2(158.9,8.59) v2(159.09,90.12) v2(159.09,89.49) v2(159.15,88.85) v2(159.15,88.22) v2(159.3,44.58) v2(159.47,32.15) v2(159.72,90.12) v2(159.66,45.1) v2(159.85,93.05) v2(159.79,89.49) v2(159.79,88.85) v2(159.79,88.22) v2(159.86,90.72) v2(159.9,44.53) v2(160.24,45.1) v2(160.17,43.96) v2(160.23,8.59) v2(160.36,90.12) v2(160.42,89.49) v2(160.42,88.85) v2(160.42,88.22) v2(160.44,32.75) v2(160.44,31.55) v2(160.48,38.44) v2(160.68,44.66) v2(160.74,44.08) v2(160.8,97.11) v2(160.8,96.47) v2(160.79,45.31) v2(161.25,38.05) v2(161.56,135.1) v2(162.14,49.36) v2(162.52,120.4) v2(162.77,49.36) v2(162.83,10.18) v2(163,120.76) v2(163.28,101.3) v2(163.49,135.98) v2(163.48,121.73) v2(163.47,121.11) v2(163.49,120.4) v2(163.79,49.36) v2(164.04,0.53) v2(164.08,121.73) v2(164.05,121.13) v2(164.08,120.4) v2(164.55,49.36) v2(164.8,99.9) v2(164.87,102.32) v2(164.95,61.93) v2(164.95,60.41) v2(164.95,58.88) v2(164.99,96.79) v2(166.47,61.93) v2(166.47,60.41) v2(166.47,58.88) v2(166.96,48.98) v2(166.96,48.34) v2(166.96,47.07) v2(166.96,46.44) v2(166.96,45.48) v2(166.96,44.85) v2(168,61.93) v2(168,60.41) v2(168,58.88) v2(168.43,0.51) v2(168.52,135.98) v2(169.54,118.48) v2(169.54,114.86) v2(169.54,109.78) v2(169.54,104.7) v2(169.54,99.62) v2(169.54,94.54) v2(169.57,89.43) v2(169.67,84.27) v2(170.38,79.82) v2(170.63,121.73) v2(171.62,75.51) v2(171.8,125.06) v2(172.74,127.75) v2(172.71,72.81) v2(172.74,49.42) v2(172.68,47.45) v2(172.74,0.5) v2(173.6,135.98) v2(173.81,130.78) v2(174.14,70.05) v2(174.85,133.75) v2(175.28,21.29) v2(175.41,47.2) v2(175.86,67.3) v2(176.25,0.58) v2(176.5,4.87) v2(176.55,52.09) v2(176.67,54.16) v2(176.69,53.55) v2(177.08,8.5) v2(177.31,52.09) v2(177.73,47.71) v2(177.97,64.56) v2(178.01,47.19) v2(178.07,48.85) v2(178.07,48.27) v2(178.39,47.71) v2(178.71,48.85) v2(178.71,48.27) v2(178.65,47.18) v2(178.9,51.58) v2(179.03,47.71) v2(179.03,32.92) v2(179.28,51.14) v2(179.34,48.85) v2(179.66,35.26) v2(180.16,62.2) v2(180.49,18.69) v2(180.66,8.81) v2(182.07,49.61) v2(182.08,49.03) v2(182.37,60.19) v2(183.28,31.51) v2(184.65,58.46) v2(185.76,38.82) v2(185.81,8.79) v2(186.41,57.07) v2(187.15,37.61) v2(187.15,36.91) v2(187.15,35.96) v2(187.15,35.26) v2(187.78,54.86) v2(190.9,53.56) v2(190.89,8.79) v2(192.11,37.67) v2(192.11,36.98) v2(192.11,36.02) v2(192.11,35.32) v2(193.33,31.87) v2(193.52,20.45) v2(193.57,52.44) v2(194.52,27.01) v2(194.52,25.35) v2(195.21,31.72) v2(195.54,20.47) v2(195.78,52.65) v2(195.8,31.73) v2(195.97,8.79) v2(196.17,27.01) v2(196.17,25.35) v2(196.17,20.47) v2(196.97,37.16) v2(197.23,41.98) v2(197.61,31.9) v2(198.13,20.55) v2(198.44,52.62) v2(200.05,37.29) v2(200.11,35.71) v2(200.11,35.07) v2(200.11,34.44) v2(200.68,37.29) v2(200.74,35.71) v2(200.74,35.07) v2(200.81,34.49) v2(201.03,8.81) v2(201.44,35.71) v2(201.44,35.07) v2(201.44,34.44) v2(202.08,35.71) v2(202.08,35.07) v2(202.08,34.44) v2(203.35,52.04) v2(203.28,26.94) v2(204.49,47.9) v2(205.55,49.73) v2(205.55,46.07) v2(206.11,8.81) v2(207.65,49.73) v2(207.65,46.07) v2(207.98,27.26) v2(208.71,47.9) v2(208.74,27.26) v2(209.82,52.19) v2(211.19,8.81) v2(211.35,40.21) v2(212.36,43.58) v2(212.36,41.39) v2(212.68,19.32) v2(213.32,19.32) v2(213.46,42.49) v2(213.7,37.1) v2(214.14,52.9) v2(214.55,43.58) v2(214.55,41.39) v2(214.49,30.75) v2(214.46,30.17) v2(214.46,29.59) v2(214.52,19.32) v2(214.84,34.24) v2(214.84,33.61) v2(214.84,32.97) v2(215.03,31.32) v2(215.1,30.74) v2(215.09,30.16) v2(215.09,29.57) v2(215.16,19.32) v2(216.24,19.32) v2(216.24,8.81) v2(216.87,19.32) v2(217.89,20.47) v2(217.89,19.83) v2(218.06,32.2) v2(218.13,30.29) v2(219.15,54.42) v2(219.6,26.18) v2(219.6,25.55) v2(219.74,35.24) v2(219.8,33.43) v2(219.92,44.4) v2(219.92,42.44) v2(219.92,40.47) v2(221.32,8.81) v2(222.27,54.98) v2(222.97,21.48) v2(222.97,20.85) v2(222.97,20.21) v2(222.97,19.51) v2(222.97,18.81) v2(226.38,8.81) v2(227.1,17.98) v2(227.2,55.01) v2(228.95,16.05) v2(229.23,20.06) v2(231.08,8.86) v2(231.34,54.7) v2(231.39,51.53) v2(231.39,47.1) v2(231.39,42.02) v2(231.39,36.94) v2(231.39,31.88) v2(231.39,26.8) v2(231.39,21.72) v2(231.36,15.69) v4(37.42,16.27) v4(42.12,70.88) v4(54.44,17.16) v4(63.52,120.29) v4(70.12,88.66) v4(75.71,22.18) v4(83.22,108.23) v4(88.6,130.7) v4(91.08,121.49) v4(91.27,134.26) v4(132.81,85.63) v4(139.4,66.95) v4(146.96,82.63) v4(148.1,60.85) v4(151.34,29.1) v4(152.23,43.9) v4(154.96,60.15) v4(155.66,121.81) v4(157.69,32.66) v4(160.23,49.68) v4(161.37,38.63) v4(166.96,59.58) v4(167.09,50.31) v4(199.54,34.69) v4(202.79,35.35) v4(214.52,28.72) v4(215.09,42.37) v4(221.95,23.51)
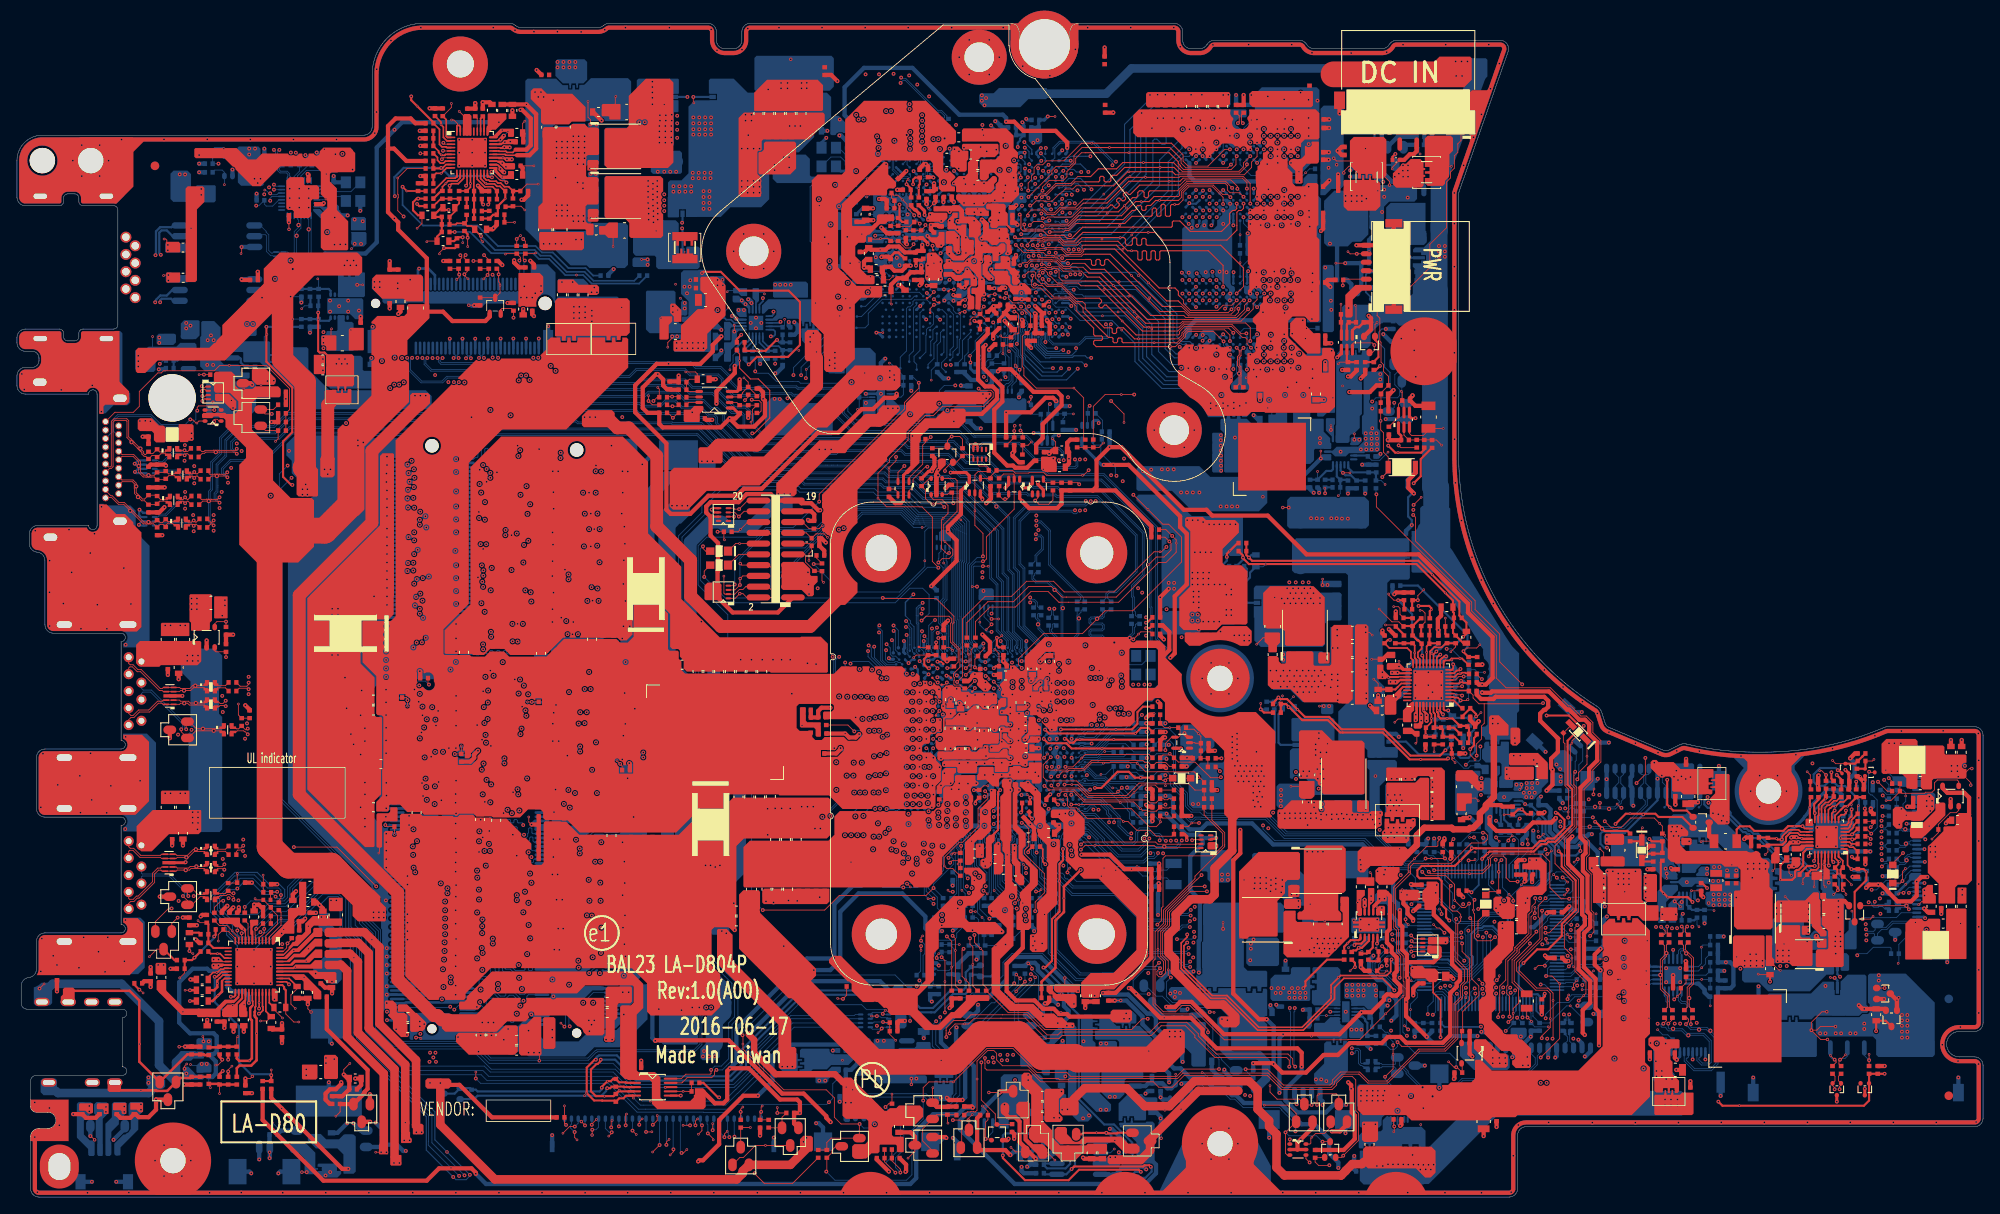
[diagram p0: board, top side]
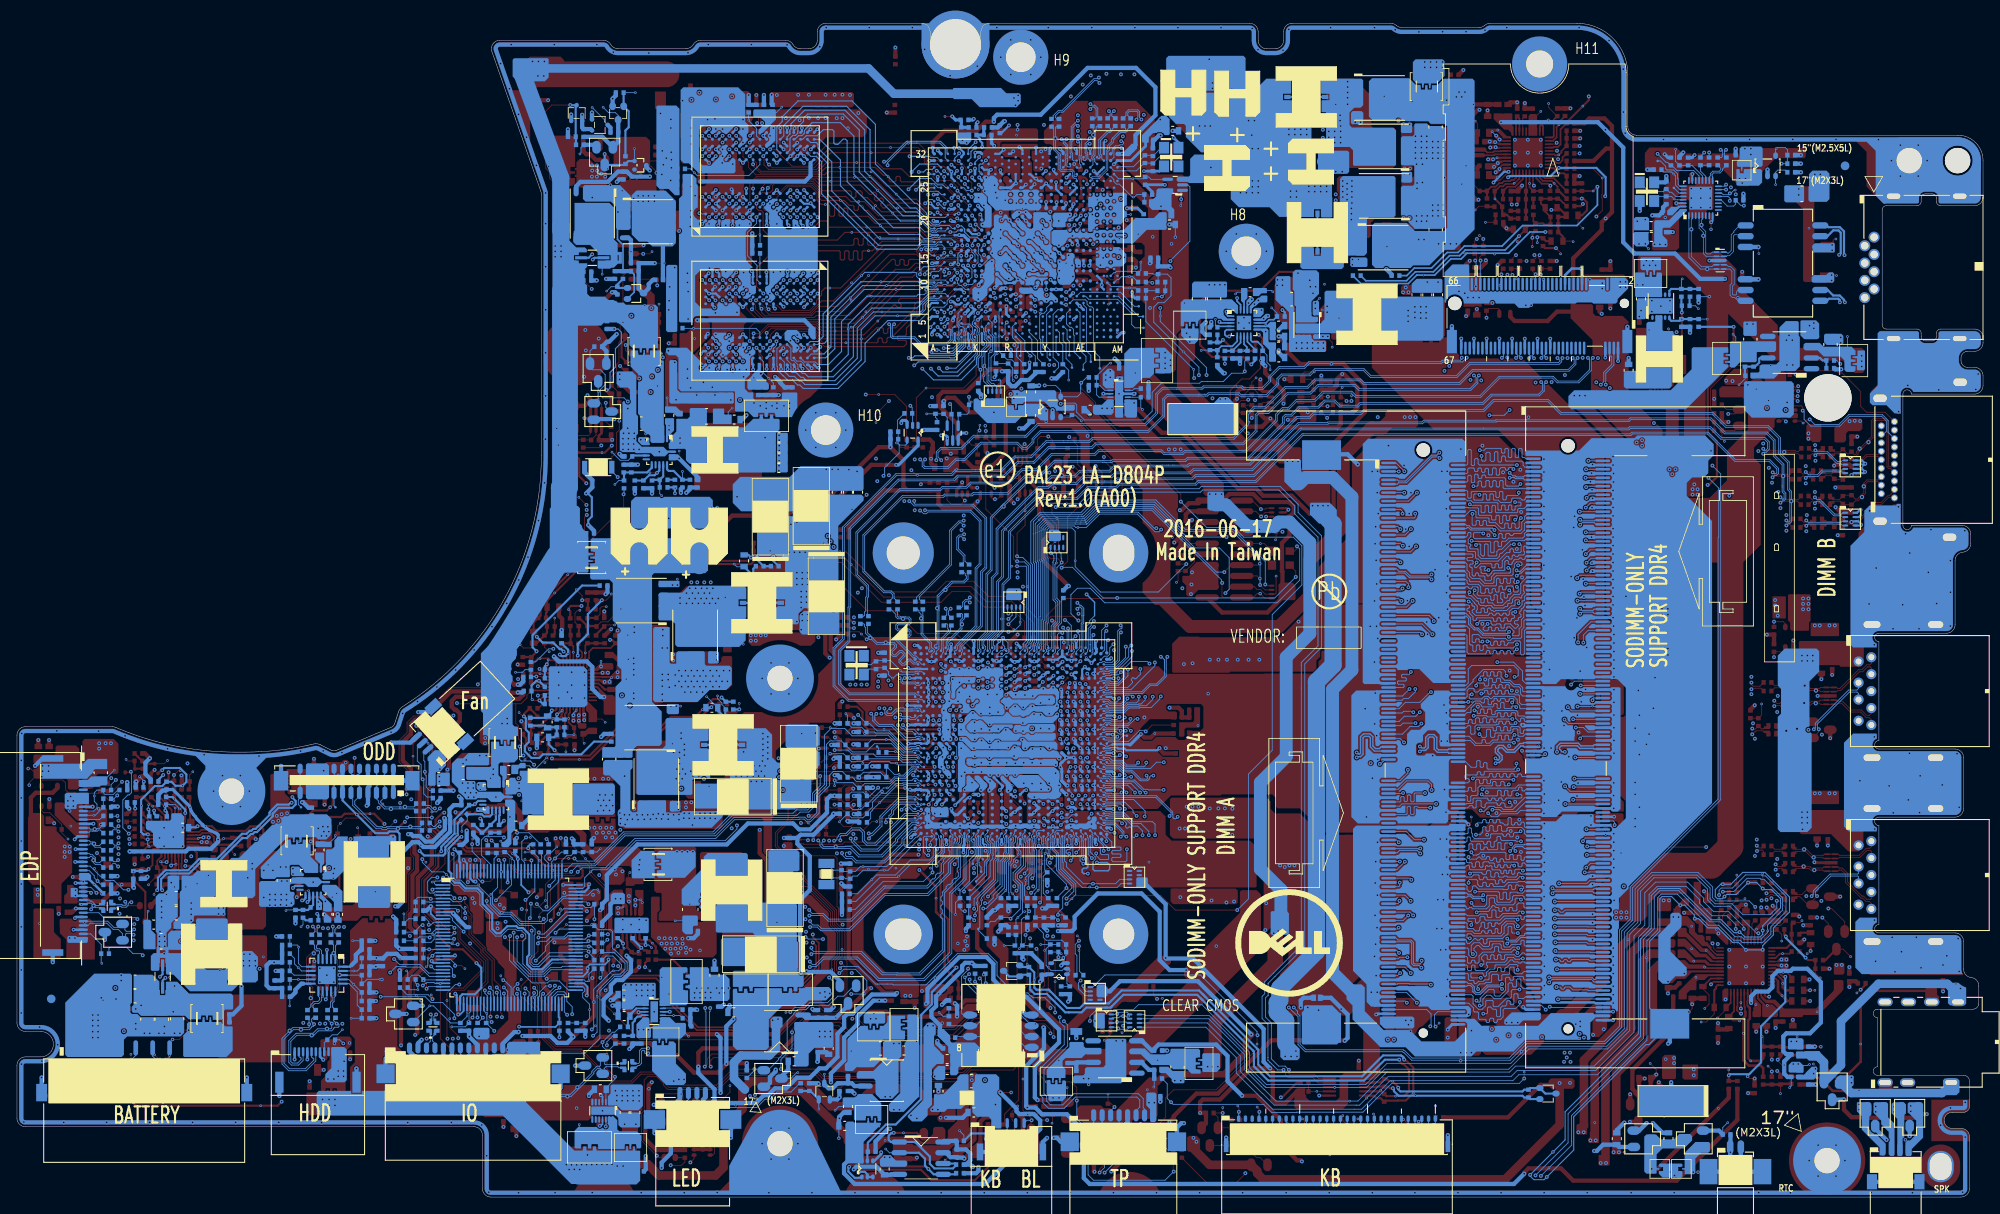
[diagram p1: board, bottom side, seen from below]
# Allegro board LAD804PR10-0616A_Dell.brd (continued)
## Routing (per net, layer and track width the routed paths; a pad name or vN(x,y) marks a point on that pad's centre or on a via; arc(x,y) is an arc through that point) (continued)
GNDA: length 33.5
  TOP w0.102: v4(34.69,21.84) 34.31,22.22 v2(34.31,22.75) ; v4(27.77,14.24) 27.52,13.99 v2(26.94,13.99) ; v4(19.13,17.73) 19.15,17.75 v2(19.83,17.75)
  TOP w0.203: v2(25.23,23.64) 25.61,23.64 25.76,23.79 UA1.25 ; UA1.38 31.79,25.4 v2(32.09,25.1)
  TOP w0.508: v2(21.09,30.4) 21.5,29.99 CA40.2 ; RA30.2 CA35.2 v2(19.72,13.28) ; RA21.1 v2(31.26,18.18) ; v2(19.83,17.75) CA34.2 RA34.2 ; RA40.2 15.01,25.47 RA20.1 v2(15.77,24.78) ; CA11.2 v2(22.44,20.91) ; CA26.2 v2(20.47,25.67) ; CA23.2 v2(26.75,19.51) ; CA21.1 CA12.2 v2(34.31,22.75) ; RA18.1 v2(26.94,13.99) ; CA20.1 v2(25.55,19.51) ; RA19.1 v2(4.72,24.28) ; RA17.1 v2(21.22,32.07) ; v2(24.47,19.96) RA13.2 CA10.2
  VCC w0.203: JHP1.7 9.98,12.84 ; JHP1.7 9.98,13.52 ; JHP1.7 8.9,12.84 ; JHP1.7 7.82,12.84 ; JHP1.7 7.82,13.52
  GND w0.203: 8.9,12.84 JHP1.7 ; JHP1.7 7.82,12.84 ; JHP1.7 9.98,12.84 ; JHP1.7 7.82,13.52 ; JHP1.7 9.98,13.52
  BOTTOM w0.508: CA34.2 v2(19.83,17.75) ; CA35.2 v2(19.72,13.28)
  vias: v2(34.12,15.07) v2(34.12,14.37)
V3D3_STB: length 19.9
  TOP w0.102: v2(29.99,14.37) v1(29.99,15)
  TOP w0.203: v2(23.32,25.99) 23.58,25.99 23.76,26.17 23.78,26.17 24.16,26.55 24.52,26.55 24.57,26.6 UA1.20
  TOP w0.254: RA11.1 RA12.1 v2(29.99,14.37)
  BOTTOM w0.254: v2(29.99,14.37) 29.87,14.5 27.58,14.5 26.18,15.89 26.18,20.15 23.32,23.01 v2(23.32,25.99)
VCCSENSE_VGA: length 93.7
  TOP w0.254: v2(105.7,119.52) 105.7,120.05 105.95,120.3 RV161.1 106.48,119.5 106.37,119.39 v1(106.37,119.02) RV159.1 ; v2(55,117.12) 55,117.13 54.83,117.3 PR1138.2
  IN1 w0.254: v2(105.7,119.52) 105.7,119.28 105.38,118.96 104.74,118.96 104.34,119.36 103.25,119.36 102.42,118.53 94.4,118.53 93.24,117.37 93.24,109.68 93.81,109.11 93.81,103.24 92.85,102.29 92.55,101.98 92.1,101.53 92.1,99.21 90.38,97.49 90.38,96.98 89.81,96.41 88.86,96.41 87.78,95.33 78.63,95.33 78.44,95.14 78.35,95.14 63.15,95.14 62.1,96.19 62.1,99.12 60.53,100.68 60.53,102.51 58.41,104.63 58.41,109.42 57.78,110.05 57.78,110.58 55.77,112.59 55.77,113.15 55,113.92 v2(55,117.12)
VDD_1.2V: length 5
  TOP w0.102: v1(84.6,102.89) 84.61,102.88 v2(84.61,102.12)
  IN1 w0.508: v2(82.63,104.67) 82.63,104.1 v2(84.61,102.12)
  BOTTOM w0.254: PR205.1 82.37,104.4 v2(82.63,104.67)
VDD_CHG: length 30
  TOP w0.203: v2(208.17,42.19) 208.22,42.24 208.22,42.58 208.96,43.31 209,43.31 209.01,43.33 210.14,43.33 210.38,43.09 PU703.19
  TOP w0.254: PR741.1 v2(218.6,40.78) ; v2(208.17,42.19) 207.66,42.19 v1(207.54,42.31) 206.6,42.31 PR760.1 206.47,42.44 PC768.2
  BOTTOM w0.381: PR781.1 213.51,48.09 211.57,46.15 211.33,45.52 211.08,45.13 210.86,44.9 210.66,44.59 210.01,43.93 209.98,43.91 209.98,43.83 209.21,43.29 208.32,42.9 208.16,42.74 208.16,42.2 v2(208.17,42.19)
  BOTTOM w0.508: PR750.2 PR749.2 215.23,47.47 214.73,47.97 214.37,47.97 PR781.1 ; v2(218.6,40.78) 218.6,40.79 211.98,40.79 211.67,41.1 209,41.1 208.17,41.93 v2(208.17,42.19)
VDDCR_FCH_S5: length 1.4
  BOTTOM w0.102: v1(135.4,10.24) 134.96,10.69 134.2,10.69
VDDIO_APU: length 6.4
  TOP w0.203: 170.33,60.88 170.33,60.81 170.12,60.6 PU1001.6 ; 170.33,60.88 170.49,60.71 170.63,60.71 170.67,60.67 171.22,60.67 PR1023.2 ; 170.33,60.88 v2(170.33,60.91)
  BOTTOM w0.102: v1(171.15,58.69) 171.2,58.74 PR1028.2
  BOTTOM w0.254: PR1028.2 171.2,60.36 170.64,60.91 v2(170.33,60.91) 170.33,60.9 PC1064.1
VDDIO_AUDIO: length 35.2
  TOP w0.305: v2(125.46,38.59) 123.49,36.62 v1(123.49,35.26) 123.49,33.63 123.49,33.63 122.49,32.63 122.49,27.04 120.85,25.41 RC11.2 120.85,23.51 RC18.2
  IN1 w0.381: v2(118.49,47.44) 118.82,47.77 119.66,47.77 119.91,47.53 120.15,47.53 120.8,46.88 125.43,46.88 126.04,46.27 126.04,45.51 127.08,44.47 127.08,39.39 126.29,38.59 v2(125.46,38.59)
  BOTTOM w0.4: v2(118.49,47.44) 118.47,47.44 118.47,47.45 118.52,47.51 UC1.AM13
VDDIO_VGA: length 4.5
  TOP w0.203: PU1100.6 50.57,123.04 50.45,122.92 50.1,122.92 v1(50.05,122.98) 50.02,122.98 49.74,123.26 49.74,123.42 PR1115.2
  TOP w0.254: PR1113.2 PC1101.1 PR1115.2
VDDP_CHG: length 8.2
  TOP w0.102: v1(206.2,40.4) 206.52,40.72 PR760.2
  TOP w0.203: 209.13,42.96 210.04,42.96 210.24,42.76 210.27,42.76 210.32,42.71 210.8,42.71 210.82,42.69 PU703.20
  TOP w0.254: PC769.2 206.47,41.42 PR760.2 206.62,41.57 208.24,41.57 208.65,41.99 208.65,42.49 209.13,42.96
VDDR4: length 2.1
  BOTTOM w0.254: UV1.Y12 110.64,108.75 111.35,108.75 UV1.V12 UV1.U12
VSS_MECH: length 69.2
  TOP w0.102: v2(101.37,102) v1(102.13,102)
  TOP w0.508: v2(116.67,126.89) 117.62,126.89 118.7,125.81 122.51,125.81 123.87,124.45 v2(123.87,123.81)
  IN2 w0.508: v2(101.56,123.1) 102.55,123.1 103.14,122.51 103.14,121.3 102.32,120.48 102.32,116.54 101.81,116.03 99.97,116.03 99.14,115.21 99.14,109.37 99.65,108.86 100.22,108.86 101.37,107.71 v2(101.37,102)
  BOTTOM w0.254: v2(123.87,123.81) 123.87,123.27 UV1.A32
  BOTTOM w0.33: v2(101.56,123.1) UV1.AM32 ; v2(101.37,102) 101.6,102 UV1.AM1
  BOTTOM w0.508: 100.19,123.94 99.97,124.16 99.97,125.3 97.62,127.65 97.62,130.96 99.91,133.24 105.62,133.24 111.15,127.72 116.29,127.72 116.67,127.34 v2(116.67,126.89)
VSSSENSE_VGA: length 90.1
  TOP w0.102: v1(105.11,120.1) 104.93,119.92 v2(104.93,119.51)
  TOP w0.254: PR1139.2 55.7,117.23 v2(55.58,117.12) ; RV158.1 105.47,118.8 RV160.1 105.41,119.03 v2(104.93,119.51)
  IN1 w0.254: v2(104.93,119.51) 104.67,119.78 102.82,119.78 101.96,118.92 94.22,118.92 92.79,117.49 92.79,109.56 93.43,108.92 93.43,103.4 92.69,102.67 92.17,102.14 91.71,101.69 91.71,99.36 90.09,97.74 88.86,97.74 86.82,95.71 78.38,95.71 78.19,95.52 63.51,95.52 62.48,96.56 62.48,99.27 60.91,100.84 60.91,102.9 58.96,104.86 58.96,109.43 58.16,110.22 58.16,110.73 56.47,112.43 56.47,113.31 55.58,114.19 v2(55.58,117.12)
0.95_1.8VALW_PWREN: length 258.4
  TOP w0.102: v1(157.25,26.69) 157.69,27.13 v2(157.82,27.13)
  TOP w0.254: v2(29.42,102.68) 29.42,98.57 32.47,95.52 32.47,90.25 31.39,89.17 31.39,84.98 32.34,84.03 v2(32.48,84.03) ; v2(157.82,27.13) 157.82,27.63 PR301.1
  IN1 w0.254: v2(157.82,27.13) 156.56,25.88 143.5,25.88 139.29,21.67 134.7,21.67 134.07,22.31 132.74,22.31 131.85,23.2 130.33,23.2 129.75,22.62 128.75,22.62 125.8,19.68 125.09,19.68 124.39,18.98 123.2,18.98 122.77,18.54 122.77,16.34 119.72,13.29 117.11,13.29 116.8,13.61 112.16,13.61 109.81,15.96 94.44,15.96 93.77,16.63 88.83,16.63 87.88,15.68 83.89,15.68 82.59,14.37 68.51,14.37 67.56,13.42 53.87,13.42 52.2,15.08 46.39,15.08 42.25,19.22 42.25,29.28 40.38,31.14 40.38,37.17 32.48,45.06 v2(32.48,84.03)
  IN2 w0.254: v2(180.3,41.04) 179.85,40.59 179.85,38.82 178.77,37.74 176.82,37.74 176.18,37.1 174.79,37.1 174.15,36.47 170.26,36.47 168.55,34.75 167.72,34.75 166.77,33.8 166.77,32.57 165.67,31.48 164.17,31.48 163.87,31.18 163.87,30.21 162.31,28.65 161.96,28.65 161.15,27.84 158.27,27.84 157.82,27.39 v2(157.82,27.13)
  BOTTOM w0.254: v2(180.3,41.04) 179.9,40.65 RE46.1 179.73,40.58 179.73,39.58 179.62,39.47 UE1.127 ; PR601.1 v2(29.42,102.68)
0.775PW_EN: length 67.8
  TOP w0.102: v2(180.35,30.46) 180.35,30.2 v1(180.55,29.99)
  IN1 w0.127: v2(180.35,30.46) 181.33,29.48 181.33,21.34 182.02,20.65 182.02,14.06 179.79,11.83 173.08,11.83 168.1,6.85 154.65,6.85 153.74,7.75 v2(150.79,7.75)
  BOTTOM w0.102: PR801.1 139.57,13.43 140.6,12.39 142.25,12.39 143.1,11.55 143.65,11.55 144.64,10.56 148.92,10.56 149.18,10.31 149.18,10.24 150.79,8.63 v2(150.79,7.75) ; v2(180.35,30.46) 180.38,30.42 UE1.17
32K_X1: length 13.4
  BOTTOM w0.102: UC1.BA2 125.5,42.21 129.15,38.56 v1(129.6,38.56) 132.1,38.56 132.79,37.88 133.31,37.88 CC686.1 134.17,37.56 134.27,37.66 RC914.2 135.63,37.66 YC3.1
32K_X2: length 13.4
  BOTTOM w0.102: UC1.AY2 125.28,42.91 125.72,42.47 125.85,42.47 129.33,38.99 v1(132.11,38.99) 132.43,38.99 133,38.42 CC682.1 134.49,38.42 RC914.1 135.63,38.58 YC3.2
48M_X1: length 10.2
  BOTTOM w0.102: YC2.1 132.68,62.82 131.15,62.82 130.75,63.21 RC939.2 130.47,63.31 C797.1 128.85,63.31 v1(127.66,62.12) 127.49,61.96 125.96,61.96 125.9,61.98 125.82,61.98 125.74,62.06 125.48,62.06 125.4,61.98 125.13,61.98 UC1.F2
48M_X2: length 7.6
  BOTTOM w0.102: UC1.F1 125.91,61.76 126.23,61.63 128.15,61.63 128.54,61.23 v1(128.61,61.23) 128.67,61.23 129.1,61.66 129.1,61.99 C796.1 130.42,62.45 RC939.1 131.37,62.3 YC2.3
+0.775MOS: length 22.2
  TOP w0.254: v2(133.74,3.57) 133.56,3.75 132.99,3.75 132.85,3.61 124.69,3.61 v2(124.4,3.31)
  BOTTOM w0.102: v1(129.43,5.67) 128.99,5.23 U2.2
  BOTTOM w0.254: R2636.2 121.25,2.69 U2.5 123.77,2.69 v2(124.4,3.31) 124.8,3.71 124.8,4.53 125.5,5.23 U2.2 ; v2(133.74,3.57) 133.84,3.47 133.84,3.01 133.1,2.27 132.34,2.27 Q2516.1
+APU_CORE: length 4.4
  TOP w0.508: v2(135.85,71.77) v4(134.84,70.77) PR1051.2
  BOTTOM w0.254: UC1.K21 114.98,59.51 v2(115.22,59.26)
  vias: v2(109.24,57.93) v2(109.68,60.09) v2(110.13,57.04) v2(110.13,52.95) v2(110.15,55.25) v2(110.84,59.97) v2(111.16,55.3) v2(112.08,59.12) v2(112.12,57.9) v2(113.01,59.24) v2(112.97,52.96) v2(113.24,54.98) v2(113.3,53.95) v2(114.1,59.28) v2(114.08,55) v2(114.17,57.88) v2(128.8,60.41) v2(129.12,60.97) v2(130.32,60.85) v2(130.32,60.22) v2(131.66,60.47) v2(132.29,60.47) v2(132.99,60.47) v2(133.62,60.47) v2(135.85,72.47) v2(136.48,72.47) v2(136.48,71.77) v2(138.03,79.88) v2(138.64,73.68) v2(138.64,72.98) v2(138.64,72.28) v2(138.66,79.88) v2(138.77,71.46) v2(138.77,70.82) v2(138.77,70.19) v2(138.93,76.08) v2(139.3,79.88) v2(139.28,73.68) v2(139.28,72.98) v2(139.28,72.28) v2(139.4,71.46) v2(139.4,70.82) v2(139.4,70.19) v2(139.4,69.55) v2(139.57,76.08) v2(139.91,79.65) v2(139.91,73.68) v2(139.91,72.98) v2(139.91,72.28) v2(139.91,67.9) v2(140.2,76.08) v2(140.55,72.98) v2(140.55,72.28) v2(140.55,67.9) v2(140.62,79.38) v2(140.61,73.68) v2(140.84,76.08) v2(141.2,79.37) v2(141.24,72.28) v2(141.18,67.9) v2(141.82,79.39) v2(141.82,67.9) v2(141.88,72.28) v2(142.45,79.39) v2(142.51,72.28) v2(142.64,71.07) v2(142.64,69.3) v2(142.64,68.66) v2(143.09,79.39) v2(143.23,71.71) v2(143.23,71.07) v2(143.23,69.3) v2(143.23,68.66) v2(143.72,79.39)
+APU_CORE_NB: length 70.6
  TOP w0.254: CC1078.1 121.82,59.58 v2(122.01,59.58)
  TOP w0.508: PR1002.1 135.15,67.46 135.92,66.68 135.92,64.55 135.02,63.65 135.02,62.38
  TOP w1.016: 143.7,20.62 143.7,21.3 142.29,22.71 140.52,22.71 136.58,26.65 136.58,28.05 135.82,28.81 135.82,30.94 136.67,31.79 136.67,33.36 138.45,35.13 140.71,35.13 141.26,35.68 141.26,38.79 143.34,40.87 143.34,44.72 144.1,45.48 ; 144.05,12.53 139.36,12.53 133.65,6.82 Q135.1 133.65,5.49 132.53,4.37 130.4,4.37
  BOTTOM w1.016: 142.37,20.07 142.37,17.51 143.17,16.71 146.51,16.71 147.33,15.89 147.33,13.98 146.03,12.68
  vias: v2(109.37,51.01) v2(111.14,51.18) v2(112.16,51.25) v2(113.16,51.25) v2(114.14,51.17) v2(114.97,53.04) v2(115.16,51.24) v2(116.18,57.22) v2(116.15,55.22) v2(116.16,53.73) v2(116.16,51.24) v2(116.31,59.31) v2(117.16,57.79) v2(117.16,57.06) v2(117.18,55.1) v2(117.18,53.1) v2(117.16,51.13) v2(117.43,62.44) v2(117.41,59.31) v2(118.13,53.87) v2(118.19,57.04) v2(118.16,55.24) v2(118.16,51.25) v2(118.92,55.01) v2(118.93,51.01) v2(118.95,56.03) v2(119.02,52.98) v2(119.53,59.07) v2(119.62,62.38) v2(120.42,57.36) v2(120.53,54.06) v2(120.73,62.31) v2(120.77,59.56) v2(120.9,58.49) v2(121.81,61.77) v2(121.81,54.06) v2(121.94,58.51) v2(122.03,60.63) v2(122.06,55.16) v2(122.31,56.28) v2(122.58,57.42) v2(122.64,54.06) v2(128.95,4.69) v2(129.55,4.7) v2(138.7,46.37) v2(139.34,46.37) v2(142.13,21) v2(142.77,20.87) v2(143.34,54.31) v2(143.34,53.68) v2(143.34,53.04) v2(143.34,52.41) v2(143.34,51.71) v2(143.66,50.88) v2(143.72,49.68) v2(143.91,54.69) v2(143.91,54.06) v2(143.91,53.42) v2(143.91,52.79) v2(143.91,52.09) v2(143.97,51.45) v2(144.04,49.04) v2(144.1,50.25) v2(144.29,50.88) v2(144.42,49.68) v2(144.74,50.25) v2(144.67,49.04) v2(144.85,12.04) v2(144.99,50.88) v2(145.05,49.68) v2(145.31,49.04) v2(145.44,50.25) v2(145.45,11.93) v2(145.63,50.88) v2(145.75,49.68) v2(145.82,48.47) v2(145.82,47.71) v2(145.82,46.82) v2(146.01,46.06) v2(146.13,50.25) v2(146.07,49.04) v2(146.26,50.88) v2(146.26,47.26) v2(146.39,46.63) v2(146.45,49.68) v2(146.45,48.47) v2(146.58,47.83) v2(146.71,49.04) v2(146.71,46.06) v2(146.84,50.88) v2(146.77,50.25) v2(146.87,47.22) v2(147.09,49.68) v2(147.09,48.47) v4(146.2,52.53)
+BIF_VDDC: length 1.5
  BOTTOM w0.254: v2(112.92,116.21) 112.5,115.79 UV1.U21 ; UV1.R21 114.3,115.72 113.85,116.17 v2(113.7,116.17)
  vias: v1(113.3,116.6) v2(110.58,123.65) v2(111.1,123.39) v2(111.08,121.37)
+CHGRTC: length 0.6
  TOP w0.102: v2(34.18,2.94) v4(33.61,2.94)
+DCBAT_CAM: length 2.1
  BOTTOM w0.102: R51.2 221.6,49.21 v1(220.43,50.37)
+DP_VDDC: length 8.1
  TOP w0.102: RV30.1 103.1,105.41 v1(103.14,105.36)
  TOP w0.508: RV30.1 103.1,107.66 103.85,108.41 CV30.1 104.75,108.45 105.43,109.13 CV34.1 CV33.1 106.66,109.21 v2(106.66,109.92)
  BOTTOM w0.254: v2(106.66,109.92) 106.9,110.17 UV1.AD14
+DP_VDDR: length 7.3
  TOP w0.102: v1(103.33,108.67) 102.9,108.23 RV27.1
  TOP w0.508: v2(105.42,109.91) 104.81,109.91 CV35.1 104.75,109.67 104.39,109.31 103.49,109.31 CV26.1 102.33,109.76 CV27.1 102.06,109.05 102.2,108.91 RV27.1
  BOTTOM w0.254: v2(105.42,109.91) 105.3,110.02 UV1.AF14
+EC_VCCA: length 25.9
  TOP w0.508: v2(164.68,32.59) 164.68,32.78 164.03,33.43 164.03,34.13 163.53,34.63 163.53,35.07 ; v2(164.69,23.8) 164.69,24.6 165.31,25.21 CE21.1 ; PR24.2 170.06,35.71 170.26,35.71 v2(170.58,35.39)
  IN1 w0.508: v2(163.95,35.66) 163.99,35.66 164.1,35.77 164.86,35.77 165.62,35.01 168.04,35.01 168.42,35.39 v2(170.58,35.39) ; v2(164.68,32.59) 165.98,31.29 165.98,26.76 165.27,26.04 165.27,24.37 v2(164.69,23.8)
  BOTTOM w0.203: UE1.67 164.99,25.22 164.61,24.84 164.61,23.88 v2(164.69,23.8)
  vias: v1(163.28,35.96)
+FB0_VREFCL: length 1.4
  BOTTOM w0.102: RV55.1 142.33,127.96 v1(141.69,128.61)
+FB0_VREFDL: length 15.9
  BOTTOM w0.254: UV13.A10 150.66,122.41 v2(150.27,122.03) ; UV13.U10 137.92,122.41 138.3,122.03
  BOTTOM w0.508: v2(151.28,119.84) 138.96,119.84 138.3,120.5 138.3,122.03
  vias: v1(151.21,120.99)
+FB1_VREFCL:
  vias: v1(144.99,96.67)
+FB1_VREFDL: length 14.6
  BOTTOM w0.254: UV15.U10 150.67,101.62 v2(150.41,101.88)
  BOTTOM w0.508: v2(151.66,103.46) 139.02,103.46 138.01,102.44
  vias: v1(151.98,101.3)
+INV_PWR_SRC: length 2.5
  TOP w0.102: v4(230.58,50.56) 230.3,50.56 229.79,50.06 ; 229.56,49.75 229.6,49.75 230.45,48.9 v4(230.45,48.61)
  vias: v2(228.18,50.88) v2(228.18,50.25) v2(228.87,50.88) v2(228.87,50.25) v4(228.98,49.6)
+LAN_VDD10: length 9.7
  TOP w0.102: v2(32.07,115.03) 32.07,114.2 v4(32.09,114.19)
  TOP w0.508: CL5.1 36.07,117.16 v2(36.18,117.27) ; CL6.1 v2(32.07,115.03)
  IN1 w0.508: v2(32.07,115.03) 34.76,115.03 36.18,116.45 v2(36.18,117.27)
  BOTTOM w0.203: UL1.30 v2(36.18,117.27) ; v2(32.07,115.03) 31.89,115.21 UL1.8
+LAN_VDD33: length 2.3
  BOTTOM w0.381: v2(37.56,123.06) 37.16,122.65 RL10.1
  BOTTOM w0.508: v2(39.58,121.24) 39.58,121.23 RL1.1 ; RL12.2 v2(21.48,122.95)
  vias: v2(28.02,120.16) v2(28.4,119.65) v2(28.72,120.16) v2(37.46,112.38) v2(38.12,112.41) v2(38.76,112.41) v4(37.49,115.59)
+LAN_VDDREG: length 2.3
  TOP w0.508: CL14.1 34.39,120.62 v2(34.29,120.72)
  BOTTOM w0.102: v2(39.83,112.48) 39.83,112.29 v1(39.45,111.91)
  BOTTOM w0.203: UL1.23 v2(34.29,120.72)
  vias: v2(40.58,112.46)
+LCDVDD:
  vias: v1(225.55,43.77)
+LCDVDD_CONN:
  vias: v2(225.25,46.75) v2(225.25,46.12) v2(225.57,47.26) v2(225.89,46.75) v2(225.89,46.12) v4(222.02,43.96) v4(222.27,45.8) v4(225.67,45.56)
+LINE1-VREFO-L: length 11.9
  TOP w0.203: 28.08,21.9 28.08,22.41 28.16,22.49 UA1.31
  TOP w0.305: RA29.1 25.93,15.21 26.23,15.51 27.63,15.51 28.26,16.14 v1(28.26,19.32) 28.26,21.08 28.09,21.26 28.09,21.35 28.03,21.41 28.03,21.85 28.08,21.9
+LINE1-VREFO-R: length 10.5
  TOP w0.203: 27.71,22.5 27.82,22.61 27.82,23.1 27.76,23.16 UA1.30
  TOP w0.305: 27.71,22.5 27.52,22.31 27.52,21.04 27.71,20.85 27.71,16.38 v1(27.4,16.07) 26.21,16.07 25.93,16.36 RA33.1
+MEM_VREF:
  vias: v1(92.6,55.64)
+MIC2-VREFO: length 30.6
  TOP w0.203: UA1.29 v2(27.36,22.91)
  BOTTOM w0.102: v1(22.82,12.91) 22.63,13.1 RA25.1
  BOTTOM w0.508: v2(27.36,22.91) 27.36,23.67 26.78,24.25 25.36,24.25 24.85,24.76 24.85,26.05 24.21,26.69 22.69,26.69 22.44,26.94 20.72,26.94 19.13,25.35 19.13,20.59 20.4,19.32 23.2,19.32 23.56,18.96 23.56,17.2 23.22,16.87 22.66,16.87 RA26.1 23.45,16.01 23.45,14.56 23.06,14.17 RA25.1
+MPLL_PVDD: length 6.9
  TOP w0.102: v2(117.6,105.07) 117.8,105.07 118.18,104.69 118.71,104.69 119.05,104.36 v1(119.05,104.29)
  TOP w0.381: CV82.1 116.43,104.14 115.84,103.55 LV6.2
  TOP w0.508: CV81.1 117.14,103.75 116.61,104.28 CV82.1 116.87,104.73 CV124.1 117.08,105.07 v2(117.6,105.07)
  BOTTOM w0.381: UV1.L8 117.18,105.5 v2(117.6,105.07)
+MVREFDA: length 9.2
  TOP w0.102: v2(118.4,120.3) 118.4,120.65 v1(118.19,120.86)
  IN1 w0.254: v2(118.05,123.9) 117.07,122.93 117.07,121.97 117.55,121.49 117.55,121.15 v2(118.4,120.3)
  BOTTOM w0.254: v2(118.4,120.3) 118.1,120 UV1.K26 ; v2(118.05,123.9) 118.05,124.39 118.31,124.65 118.31,124.88 118.73,125.3 RV33.2
  BOTTOM w0.381: RV33.2 CV94.1 117.86,126.17 RV34.1
+MVREFSA: length 13.3
  TOP w0.102: v2(121.59,127.51) v1(122.44,127.51)
  IN1 w0.254: v2(119.23,120.33) 119.21,120.35 119.21,120.44 118.96,120.69 118.73,120.69 118.43,120.99 118.43,121.6 119.41,122.59 119.41,125.34 v2(121.59,127.51)
  BOTTOM w0.254: v2(119.23,120.33) 119.23,120.21 118.92,119.9 UV1.J26
  BOTTOM w0.381: v2(121.59,127.51) 121.18,127.1 RV35.1 120.52,127.03 RV32.2 119.65,126.23 CV95.1
+PCIE_VDDC: length 13.1
  BOTTOM w0.254: UV1.N24 116.14,118.54 v2(116.46,118.54) 116.7,118.3 UV1.L24 ; v2(111.7,117.31) UV1.V22 UV1.U22 v2(112.9,117.23) 113.3,116.83 UV1.T22 113.43,116.7 v2(114.02,117.29) 114.22,116.74 UV1.R22 UV1.N22 115.3,117.52 115.34,117.56 v2(115.34,117.62) 115.65,117.62 115.77,117.5 UV1.N23 ; UV1.L25 116.81,119.39 v2(116.59,119.39) ; UV1.L23 v2(116.32,117.9) 115.92,117.5 UV1.N23 ; UV1.N23 116.3,117.1 UV1.M22 ; v2(117.56,120.29) 117.49,120.29 UV1.L26
  BOTTOM w0.381: v2(117.75,118.7) 117.35,118.3 UV1.L24
  vias: v1(114,125.3)
+RTC_APU: length 116.5
  TOP w0.102: v4(130.2,23.2) 130.18,23.18 v2(129.5,23.18)
  TOP w0.508: RC93.2 v2(129.5,23.18)
  IN2 w0.508: v2(135.89,13.54) 135.17,12.82 134.64,12.82 132.95,11.13 127.66,11.13 127.15,10.62 127.15,9.35 127.13,9.33 127.13,8.25 126.21,7.34 119.25,7.34 117.52,5.61 115.59,5.61 114.76,4.78 109.43,4.78 108.35,5.86 96.3,5.86 95.47,5.03 80.09,5.03 79.01,3.96 78.96,3.96 78.96,3.95 78.43,3.95 78.43,3.96 63.08,3.96 61.59,5.44 v2(45.87,5.44)
  BOTTOM w0.508: v2(129.5,23.18) 130.87,23.18 132.76,21.29 132.76,20.4 134.33,18.83 134.33,16.15 135.89,14.58 v2(135.89,13.54) ; UC101.3 42.93,5.91 CC119.1 44.82,6.18 45.56,5.44 v2(45.87,5.44)
+RTC_APU_R: length 192
  TOP w0.508: v2(128.1,24.08) 128.71,24.08 RC93.1 129.57,24.1 131.4,25.93 131.47,25.93 133.8,28.26 CC1129.2 CC166.1 CC923.1 v1(131.47,38.69) 130.64,38.69 128.93,40.4 v2(125.56,40.4) ; v2(75.28,18.44) 75.34,18.5 83.97,18.5 90.25,12.21 92.79,12.21 95.46,9.54 95.46,9.35 v2(95.97,8.84)
  IN1 w0.508: v2(128.1,24.08) 127.78,24.4 125.99,24.4 125.76,24.17 125.76,24 125.31,23.54 125.31,22.5 124.92,22.12 123.13,22.12 121,19.98 121,17.26 117.72,13.99 v2(117.72,13.8) ; v2(155.86,3.44) 157.92,3.44 159.32,4.84 167.92,4.84 169.48,4.84 174.55,9.91 178.46,9.91 180.92,9.91 187.41,16.4 187.41,20.15 v2(185.95,21.61) ; v2(125.56,40.4) 125.75,40.4 126.13,40.79 126.13,41.8 126.08,41.85 125.74,42.19 125.74,44.99 124.89,45.83
  IN2 w0.508: v2(95.97,8.84) 96.67,9.54 98.83,9.54 99.21,9.92 108.86,9.92 110.32,11.38 110.45,11.38 112.86,13.8 v2(117.72,13.8)
  BOTTOM w0.254: v2(121.24,46.25) 120.16,47.33 UC1.AM11
  BOTTOM w0.508: Q91.1 v2(185.95,21.61) ; v2(75.28,18.44) 74.95,18.77 74.95,21.54 76.92,23.51 CLRP1.1 ; v2(128.1,24.08) 128.29,23.89 131.06,23.89 133.31,21.65 133.62,21.65 133.66,21.61 133.96,21.61 134.33,21.24 134.33,20.05 135.12,19.26 135.12,16.54 136.48,15.19 137.26,15.19 138.37,14.08 139.92,14.08 141.17,12.83 142.49,12.83 143.3,12.02 143.8,12.02 144.72,11.1 149,11.1 151.51,8.59 153.05,8.59 154.77,6.87 154.77,5.16 155.86,4.08 v2(155.86,3.44)
+RTCBATT: length 3.5
  TOP w0.102: v2(29.8,4.59) v4(29.8,5.29)
  BOTTOM w0.508: RC31.2 29.79,5.94 JRTC1.1 29.83,4.61 v2(29.8,4.59)
+RTCVCC: length 13.6
  TOP w0.508: RA12.2 29.99,11.7 v1(31.23,10.46) 38.37,3.32 v2(39.07,3.32)
+SPI_VCC: length 13.1
  BOTTOM w0.508: 123.03,19.1 123.03,20.25 124.04,21.27 124.04,21.98 123.49,22.53 123.49,23.69 v1(123.2,23.98) 120.42,26.76 120.42,27.28 120.06,27.64 119.26,27.64 RC639.2 RC640.2
+SPLL_PVDD: length 25.7
  TOP w0.102: CV84.1 122.51,89.11 v1(122.13,89.49)
  TOP w0.508: v2(120.07,104.27) 120.15,104.19 120.15,102.11 120.04,102 CV85.1 120.05,101.94 CV86.1 ; CV84.1 122.13,88.09 v2(121.75,87.71) 121.56,87.9 LV7.2
  IN1 w0.508: v2(120.07,104.27) 120.07,101.59 118.96,100.48 118.96,99.4 119.53,98.82 119.53,95.59 118.96,95.01 118.96,92.41 120.54,90.82 120.54,89.68 121.75,88.47 v2(121.75,87.71)
  BOTTOM w0.381: v2(120.07,104.27) 119.7,104.64 UV1.H7
+SPLL_VDDC: length 22.9
  TOP w0.508: v2(120.09,105.15) 120.93,104.31 CV93.1 120.86,104.04 120.86,102.88 CV92.1
  IN1 w0.508: v2(120.09,105.15) 120.8,104.44 120.8,101.3 120.67,101.17 120.67,92.54 122,91.2 122,89.87 122.74,89.13 122.74,87.75 122.27,87.28 122.27,87.19 v2(122.23,87.15)
  BOTTOM w0.305: v2(120.09,105.15) 120.05,105.15 UV1.H8
  vias: v1(121.05,85.87)
+TSVDD: length 9.7
  TOP w0.508: LV2.2 99.97,111.52 CV19.1 100.73,111.78 v1(101.81,111.78) 102.45,111.78 102.83,112.16 104.02,112.16 104.72,111.47 CV21.1 106.19,111.65 CV20.1 106.78,111.77 v2(106.78,112.35)
  BOTTOM w0.254: UV1.AD17 106.78,112.78 v2(106.78,112.35)
+V_DAC: length 8.6
  TOP w0.102: v1(26.44,111.33) 26.5,111.4 v2(26.5,112.1)
  TOP w0.508: v2(26.5,108.29) 26.56,108.22 CL12.2
  IN2 w0.508: v2(26.5,112.1) v2(26.5,108.29)
  BOTTOM w0.508: TL1.4 26.51,108.3 v2(26.5,108.29) ; v2(26.5,112.1) 26.51,112.11 TL1.3
+VGA_CORE: length 30.8
  TOP w0.381: CV114.1 110.56,106.35 v2(110.45,106.46) ; CV87.1 117.05,111.55 v2(116.87,111.37) ; RV367.1 v2(107.29,107.55)
  TOP w0.508: CV112.1 116.14,107.3 v2(116.57,107.3) ; v2(113.83,115.31) 114.32,114.82 CV78.1 ; CV80.1 107.46,121.63 v2(107.2,121.89) 106.99,121.89 106.48,121.38 RV161.2
  BOTTOM w0.254: UV1.Y18 110.93,114.13 v2(110.93,114.2) 111,114.2 UV1.V20 ; v2(116.8,113.1) 116.3,113.61 UV1.M18 ; v2(112.08,109.46) 112.5,109.88 UV1.U13 112.5,110.04 v2(112.9,110.44) 113.3,110.84 UV1.T15 UV1.R16 ; v2(110.02,115.22) UV1.Y21 110.65,115.85 111.35,115.85 UV1.V21 ; v2(114.92,108.38) 115.3,108.76 UV1.N12 ; UV1.AA12 UV1.Y13 110.93,110.33 110.93,110.4 111.43,110.9 UV1.V15 111.93,111.33 v2(111.93,111.4) 112.43,111.9 UV1.U16 ; UV1.R18 114.3,113.61 v2(113.77,113.09) ; UV1.V17 111.5,112.77 v2(111.93,113.2) 112.43,113.7 UV1.U18 ; UV1.N20 115.86,114.14 v2(115.87,114.14) 115.87,114.27 UV1.M20 UV1.M21 ; UV1.T20 113.3,114.78 v2(113.83,115.31) ; UV1.U11 112.5,108.01 v2(112.91,108.41) 113.3,108.81 UV1.T12 ; UV1.AA15 109.54,110.9 109.94,111.3 v2(109.98,111.3) 109.98,111.34 110.5,111.86 UV1.Y16
  BOTTOM w0.381: UV1.N15 115.3,110.76 v2(114.8,110.26) 114.44,109.9 UV1.R13 ; UV1.R16 114.37,111.9 115.17,112.7 UV1.N17 ; v2(113.77,113.09) 113.39,112.7 UV1.T17 ; UV1.M11 116.3,107.57 v2(116.57,107.3)
  vias: v2(77.43,119.27) v2(77.43,118.64) v2(78.13,119.27) v2(78.13,118.64) v2(78.82,119.27) v2(78.82,118.64) v2(79.52,119.27) v2(79.52,118.64) v2(79.71,120.86) v2(79.71,120.22) v2(79.78,127.4) v2(79.78,126.7) v2(79.78,126) v2(79.78,125.37) v2(80.41,120.86) v2(80.41,120.22) v2(80.47,127.4) v2(80.47,126.7) v2(80.47,126) v2(80.47,125.37) v2(80.98,118.7) v2(80.98,118) v2(80.98,117.3) v2(80.98,116.6) v2(81.11,120.86) v2(81.11,120.22) v2(81.17,127.4) v2(81.17,126.7) v2(81.17,126) v2(81.17,125.37) v2(81.68,118.7) v2(81.68,118) v2(81.68,117.3) v2(81.68,116.6) v2(81.81,120.86) v2(81.81,120.22) v2(81.87,127.4) v2(81.87,126.7) v2(81.87,126) v2(81.87,125.37) v2(85.49,123.72) v2(85.49,119.91) v2(85.49,119.21) v2(85.49,118.51) v2(85.94,127.72) v2(85.94,127.02) v2(86.19,123.72) v2(86.19,119.91) v2(86.19,119.21) v2(86.19,118.51) v2(86.63,127.72) v2(86.63,127.02) v2(86.89,123.72) v2(86.89,119.91) v2(86.89,119.21) v2(86.89,118.51) v2(87.59,123.72) v2(87.59,119.91) v2(87.59,119.21) v2(87.59,118.51) v2(91.14,126.38) v2(91.78,126.38) v2(92.41,126.38) v2(115.88,113.15) v4(86.25,125.3)
+VGA_CORE_M70: length 10.8
  TOP w0.381: RV367.2 108.59,108.95 v2(108.95,109.31)
  BOTTOM w0.254: UV1.Y9 v2(109.39,105.79) ; v2(108.92,110.35) 108.5,109.93 UV1.AB13 ; UV1.AB11 108.5,107.93 v2(108.97,108.4) ; UV1.T10 UV1.U10 111.5,106.3 UV1.W9 ; v2(110.46,105.76) 110.56,105.76 UV1.W9 ; UV1.W9 UV1.W10 ; UV1.AB12 108.54,108.9 v2(108.95,109.31) ; UV1.AC13 107.7,109.67 v2(107.45,109.92) 107.45,110.25 UV1.AC14 107.86,110.66 v2(107.86,111.13) ; UV1.AC11 107.34,108.46 v2(107.34,108.63)
  vias: v1(108.16,110.19)
+VREF_CA: length 8.3
  TOP w0.102: v2(60.7,43.96) 60.66,43.96 60.37,44.25 v1(60.37,44.85)
  TOP w0.508: CD219.1 CD220.1 CD218.1 CD228.1 RD26.2 ; CD219.1 v2(60.7,43.96) ; CD219.1 RD24.1
  BOTTOM w0.305: JDIMM1.164 61.09,44.38 60.7,43.98 v2(60.7,43.96)
+VREFB_CA: length 2.4
  TOP w0.102: RD33.2 42.77,40.67 v1(42.69,40.59)
  BOTTOM w0.305: JDIMM2.164 v2(43.52,44.87)
A_MIC_CLK: length 279.4
  TOP w0.102: v2(222.52,35.9) 222.08,35.9 v1(221.95,35.77) ; v2(30.69,36.02) 30.63,35.96 RA56.1 29.91,35.89 LA1.1
  IN2 w0.127: v2(222.52,35.9) 222.6,35.82 222.6,34.81 221.95,34.16 221.95,22.8 221.4,22.25 221.4,12.73 219.23,10.56 198.52,10.56 196.3,12.78 187.66,12.78 185.83,14.61 179.23,14.61 178.59,13.98 178.59,13.68 176.87,11.96 174.35,11.96 168.37,5.97 157.89,5.97 157.5,6.37 155.29,6.37 154.7,5.77 149.64,5.77 148.8,6.61 148.8,7.58 146.33,10.05 136.8,10.05 130.98,4.23 125.26,4.23 125.04,4.45 123.92,4.45 122.41,2.94 107.5,2.94 106.43,4.01 99.54,4.01 97.57,2.04 79.15,2.04 79.14,2.05 60.89,2.05 60.01,2.93 55.89,2.93 55.01,2.05 53.3,2.05 v2(52.79,2.56)
  BOTTOM w0.102: v2(30.69,36.02) 30.65,36.06 29.38,36.06 27.83,37.61 26.31,37.61 26.19,37.49 25.82,37.49 23.65,35.31 23.65,33.86 25.43,32.07 25.43,31.18 26.18,30.43 28.21,30.43 28.49,30.71 29.26,30.71 31.02,32.48 32.22,32.48 35.89,36.15 38.12,36.15 38.78,35.49 38.78,31.68 40.05,30.41 40.05,18.73 48.94,9.84 48.94,6.41 v2(52.79,2.56) ; v2(222.52,35.9) 223.18,36.55 JEDP1.28
A_MIC_DATA: length 280.5
  TOP w0.102: RA55.1 30.88,35.01 31.14,35.26 v2(31.14,35.64)
  IN2 w0.127: v2(52.15,2.49) 53.04,1.61 55.27,1.61 56.16,2.5 59.84,2.5 60.71,1.62 78.94,1.62 78.95,1.61 97.75,1.61 99.72,3.57 106.26,3.57 107.32,2.51 122.59,2.51 124.1,4.02 124.86,4.02 125.08,3.8 131.16,3.8 136.98,9.62 146.15,9.62 148.37,7.4 148.37,6.43 149.46,5.34 154.52,5.34 154.87,5.34 155.47,5.94 157.32,5.94 157.71,5.54 158.07,5.54 168.55,5.54 174.53,11.52 177.05,11.52 179.03,13.5 179.03,13.8 179.41,14.18 185.65,14.18 187.48,12.35 196.12,12.35 198.34,10.13 219.41,10.13 221.83,12.55 221.83,22.07 222.38,22.62 222.38,33.98 223.03,34.63 223.03,35.77 v2(223.16,35.9)
  BOTTOM w0.102: v2(31.14,35.64) 31.14,36.21 30.88,36.47 29.55,36.47 28,38.02 26.14,38.02 26.02,37.9 25.66,37.9 23.24,35.48 23.24,33.69 25.03,31.9 25.03,31.02 26.01,30.03 28.38,30.03 28.66,30.31 29.42,30.31 31.19,32.07 32.39,32.07 36.06,35.74 37.95,35.74 38.37,35.32 38.37,31.51 39.64,30.24 39.64,18.5 48.53,9.61 48.53,6.56 48.52,6.55 48.52,6.13 v1(51.2,3.45) v2(52.15,2.49) ; JEDP1.29 223.31,36.05 v2(223.16,35.9)
ACIN: length 168.4
  TOP w0.203: PU703.2 215.98,41.49 216.17,41.29 216.59,41.29 PR741.2 PR731.1
  TOP w0.254: PR731.1 216.67,39.9 v2(216.43,40.15) ; v2(180.42,56.82) 183.07,56.82 184.29,55.6 184.29,55.24 182.9,53.85 182.9,48.67 183.45,48.12 183.45,43.91 181.46,41.93 180.65,41.93 180.35,41.64 179.78,41.64 178.91,40.77 178.6,40.77 178.6,40.77 173.7,40.77 v1(173.45,40.52) v2(172.82,39.9) ; v2(164.75,84.23) 165.58,85.06 165.58,87.08 PR12.1
  IN1 w0.254: v2(164.75,84.23) 164.21,83.69 164.21,80.29 165.06,79.44 165.06,75.41 169.31,71.15 169.31,69.01 175.47,62.85 175.47,62.71 176.96,61.21 176.96,59.93 180.07,56.82 v2(180.42,56.82) 180.42,56.76 185.93,51.24 187.89,51.24 189.71,49.42 191.64,49.42 193.52,47.54 196.59,47.54 198.25,45.88 202.8,45.88 204.82,43.86 209.08,43.86 210.01,44.79 211.37,44.79 211.37,44.79 215.18,44.79 216.96,43.01 216.96,40.68 v2(216.43,40.15)
  IN2 w0.254: v2(122.89,89.87) 123.43,89.34 125.77,89.34 127.91,87.2 128.73,87.2 131.66,84.28 139.55,84.28 140.86,82.97 150.87,82.97 150.87,82.97 151.21,82.97 152.32,81.87 158.6,81.87 160.17,83.44 163.96,83.44 v2(164.75,84.23)
  BOTTOM w0.203: UE1.110 v2(172.82,39.9)
  BOTTOM w0.254: v2(122.89,89.87) 122.32,89.87 122.18,89.73 UV3.1 ; CE40.2 173.12,40.4 172.82,40.1 v2(172.82,39.9)
ACIN_65W: length 113.4
  TOP w0.102: v2(167.76,42.37) 167.76,42.13 167.6,41.97 167.6,41.47 167.47,41.35 166.26,41.35 v1(164.83,39.93) 164.1,39.2 164.1,38.27 162.39,36.56 162.39,33.39 162.39,33.2 162.39,33.2 162.39,31.77 162.71,31.45 162.71,28.93 163.22,28.42 163.22,26 v2(163.09,25.87)
  IN1 w0.127: v2(121.84,93.58) 123.63,91.79 129.84,91.79 130.13,91.51 130.13,87.71 129.81,87.39 129.81,86.63 130.13,86.31 130.13,84.77 130.01,84.65 130.01,84.3 130.13,84.18 130.13,82.31 132.99,79.46 132.99,72.6 136.55,69.04 136.55,66.72 136.95,66.31 136.95,64.64 137.75,63.84 137.75,59.5 137.75,59.26 139.59,57.42 139.59,49.89 139.76,49.72 139.76,48.77 143.17,45.36 143.38,45.36 143.38,45.36 146.58,45.36 146.58,45.36 146.79,45.36 148.44,43.71 158.66,43.71 161.01,41.36 167.16,41.36 167.76,41.95 v2(167.76,42.37)
  BOTTOM w0.102: v2(163.09,25.87) 162.88,26.07 RE51.1 ; v2(121.84,93.58) 121.67,93.41 RV150.2 121.53,92.23 UV3.2
ACIN_CHG: length 13.1
  TOP w0.203: v2(216.38,38.7) 215.92,39.16 215.92,40.88 215.72,41.09 PU703.1
  TOP w0.254: PQ712.1 216.76,36.01 218.14,37.39 v1(218.14,38.37) 217.81,38.7 PR732.1 v2(216.38,38.7)
  BOTTOM w0.254: PR729.2 PC711.2 216.61,38.47 v2(216.38,38.7)
ACLIM: length 6.2
  TOP w0.203: 212.06,45.23 PU703.16
  TOP w0.254: PR751.2 212.49,46.88 211.98,46.37 211.98,45.3 212.06,45.23 v2(212.06,45.31)
  BOTTOM w0.254: PR749.1 213.55,47.2 v1(213.32,46.97) 212.06,45.71 v2(212.06,45.31)
ACOFF: length 71.1
  TOP w0.102: PQ712.2 222.73,34.38 v2(223.16,33.96) ; v2(187.42,28.09) v1(186.71,28.09)
  IN1 w0.127: v2(187.42,28.09) 187.42,27.67 187.23,27.48 187.23,21.97 190.26,18.94 193.5,18.94 194.54,17.9 201.72,17.9 202.77,16.85 217.27,16.85 219.84,19.42 219.84,21.8 223.32,25.28 223.32,33.79 v2(223.16,33.96)
  BOTTOM w0.102: v2(187.42,28.09) 186.79,27.45 184.35,27.45 183.33,26.42 UE1.27
AD_BID0: length 7.9
  BOTTOM w0.102: UE1.66 165.17,24.82 164.94,24.59 164.94,24.31 165.17,24.07 165.17,23.57 164.36,22.75 v1(164.36,22.12) 164.36,21.05 CE39.1 RE22.2 RE20.1
ADJ_1.5VS: length 4
  BOTTOM w0.508: PR402.1 PC404.2 ; PC404.2 PR401.2 ; PC404.2 106.88,15.89 PU400.7
ADJ_2.5V: length 5.9
  BOTTOM w0.102: v1(28.79,95.84) 28.04,96.59 PR902.1
  BOTTOM w0.254: PU900.7 26.31,99.01 26.4,98.92 26.4,98.47 26.89,97.99 PC903.2 PR901.2 28.09,96.97 PR902.1
ADP_I: length 79.9
  TOP w0.102: PR774.1 218.92,44.34 PC748.1 218.97,43.96 v2(218.65,43.64) ; v1(188.74,46.37) 189.19,45.93 v2(189.25,45.93)
  IN1 w0.127: v2(189.25,45.93) 189.57,45.61 189.94,45.61 191.68,43.87 192.84,43.87 194.91,41.8 196.43,41.8 197.12,42.5 198.37,42.5 199.74,41.13 206.67,41.13 207.61,40.19 210.61,40.19 211.22,39.58 211.22,39.26 212.71,37.78 215.5,37.78 216.16,37.11 217.05,37.11 219.13,39.19 219.13,43.29 218.78,43.64 v2(218.65,43.64)
  IN2 w0.127: v2(173.74,30.8) 173.73,30.8 173.73,31.37 173.69,31.41 173.69,33.96 175.44,35.71 179.41,35.71 180.23,36.53 180.23,37.25 185.06,42.08 185.06,43.33 185.59,43.86 186.52,43.86 186.84,44.18 186.84,44.53 187.09,44.79 188.3,44.79 189.25,45.74 v2(189.25,45.93)
  BOTTOM w0.102: v2(173.74,30.8) 173.71,30.8 173.8,30.7 173.8,27.94 171.13,25.27 169.33,25.27 169.1,25.49 167.93,25.49 166.86,24.42 UE1.65
AGPIO5: length 8.4
  BOTTOM w0.102: UC1.AK1 125.65,48.6 126.93,48.6 126.99,48.66 127.31,48.66 127.37,48.6 128.09,48.6 v1(130.13,46.56) 131.02,45.67 131.02,45.6 131.21,45.41 131.21,44.65 RC933.2
AGPIO8: length 19.5
  TOP w0.102: v2(123.56,48.67) v1(124.42,48.67) 125.11,48.67 126.39,47.39 130.89,47.39 132.35,48.85 134.34,48.85 134.43,48.76 138.21,48.76 138.94,48.02 RC932.2 RC22.1
  BOTTOM w0.1: v2(123.56,48.67) 123.86,48.97 UC1.AJ4
AGPIO11: length 17.1
  TOP w0.102: v2(121.2,48.51) 121.26,48.51 v1(121.73,48.04) 124.71,48.04 125.9,46.86 133.29,46.86 133.64,46.51 134.35,46.51 RC954.2 135.22,47.01 135.34,46.88 135.72,46.88 135.85,47.01 RC953.1
  BOTTOM w0.1: UC1.AJ8 121.46,48.76 121.21,48.51 v2(121.2,48.51)
AGPIO21: length 6.7
  BOTTOM w0.102: UC1.AC1 127.34,52.41 128.93,53.99 v1(129.37,53.99) 131.07,53.99 RC643.1
AGPIO25: length 10.9
  BOTTOM w0.102: UC1.AY13 119.06,42.64 119.37,42.34 119.37,42.08 119.12,41.84 119.12,41.27 118.88,41.03 118.88,40.44 119.53,39.79 119.53,37.3 120.67,36.15 RC661.1 121.21,34.74 v1(121.21,33.34)
APU_ALERT#: length 12.7
  BOTTOM w0.102: RPC25.2 109.49,76.13 109.3,75.94 v1(109.3,74.82) 109.47,74.66 109.47,70.56 109.14,70.23 109.14,67.87 109.68,67.33 109.68,66.51 109.68,64.49 UC1.A30
APU_DBRDY: length 42.2
  TOP w0.102: v2(89.24,77.88) 88.74,78.38 JHDT1.14
  BOTTOM w0.102: v2(89.24,77.88) 93.92,77.88 97.71,81.68 97.71,81.68 97.76,81.73 104.67,81.73 106.07,80.33 106.13,80.33 106.32,80.33 106.7,80.33 106.7,80.33 110.9,80.33 v1(111.34,79.9) 111.79,79.44 111.79,78.34 111.79,78.34 111.79,74.97 111.66,74.83 111.65,74.83 111.65,65.43 111.79,65.29 111.79,65.1 111.87,65.02 111.87,64.67 111.91,64.62 UC1.A26
APU_DBREQ#: length 60.3
  TOP w0.102: v1(83.46,77.55) 83.38,77.63 RH25.2 v2(82.63,78.5) ; v2(84.66,72.28) 84.52,72.14 RPH1.4
  IN1 w0.127: v2(82.63,78.5) 83.08,78.5 85.68,75.9 85.68,73.3 v2(84.66,72.28)
  BOTTOM w0.102: UC1.A25 112.32,64.95 112.32,65.34 112.11,65.55 112.11,74.64 112.32,74.85 112.32,79.71 111.24,80.79 106.38,80.79 104.92,82.25 97.56,82.25 94.09,78.78 88.44,78.78 84.66,75 v2(84.66,72.28)
APU_DBREQ#_R: length 3.6
  TOP w0.102: RH25.1 85.05,78.5 v1(85.33,78.79) 86.19,79.65 JHDT1.16
APU_FCH_POK: length 83.4
  TOP w0.102: RC52.2 v2(141.89,50.25) ; v2(140.69,21.82) 141.17,21.82 v1(141.21,21.79) ; v2(140.36,36.07) 138.42,36.07 135.94,33.59 135.94,32.03 135.14,31.23 135.14,28.53 135.8,27.87 v1(135.8,26.82) 135.8,26.22 v2(136.1,25.91)
  IN2 w0.127: v2(140.36,36.07) 140.42,36.07 140.74,36.39 140.74,42.69 142.58,44.53 142.58,49.74 142.06,50.25 v2(141.89,50.25) ; v2(140.69,21.82) 141.89,21.82 142.29,21.42 142.96,21.42 143.82,20.55 147.58,20.55 147.68,20.66 153.44,20.66 153.63,20.47 153.68,20.47 153.68,20.46 153.74,20.41 157.94,20.41 157.94,20.4 158,20.4 158,20.4 160.25,20.4 161.08,21.23 162.39,21.23 163.2,22.04 163.39,22.04 163.41,22.05 165.69,22.05 165.7,22.04 167.01,22.04 170.14,25.17 171.43,25.17 171.83,25.57 173.7,25.57 174.11,25.17 176.53,25.17 176.78,24.93 179.58,24.93 v2(179.73,25.08)
  BOTTOM w0.102: v2(140.69,21.82) 140.14,22.37 138.96,22.37 138.39,22.94 136.29,22.94 135.59,23.64 135.59,25.4 v2(136.1,25.91) ; v2(179.73,25.08) 180.19,25.08 180.85,24.42 UE1.32
APU_FCH_PWRGD: length 8
  TOP w0.102: RC52.1 RC51.2 CC999.2 139.64,51.81 CC1000.2 CC23.1 ; CC23.1 139.64,54.39 v1(139.34,54.69) 138.83,55.2 138.08,55.2 RC53.1 ; CC23.1 138.98,53.55 138.92,53.61 UC61.2
APU_FCH_PWRGD_R: length 18.1
  TOP w0.102: v2(135.45,52.74) 135.45,53.53 136.19,54.26 UC61.4 137,54.26 137.18,54.44 137.18,55.19 RC53.2 v1(135.97,55.39) 135.35,55.39 RC21.2 RC350.2
  BOTTOM w0.102: UC1.AE2 125.53,51.31 125.83,51.61 127.47,51.61 127.82,51.96 130.55,51.96 130.88,52.29 133.44,52.29 133.89,52.74 v2(135.45,52.74)
APU_HDMI_CLK: length 130.8
  TOP w0.102: v2(23.26,91.52) 23.26,91.67 23.36,91.78 23.64,91.78 23.85,91.57 QI2.1 ; v2(21.81,95.68) 22,95.49 22.14,95.49 22.29,95.64 RPI3.1
  IN2 w0.102: 117.55,65.55 117.55,65.52 117.56,65.51 117.56,63.42 117.88,63.1 117.88,62.99 117.89,62.98 117.89,60.88 117.74,60.72 117.48,60.72 v2(117.43,60.77)
  IN2 w0.127: v2(21.81,95.68) 21.91,95.79 22.25,95.79 22.39,95.65 22.39,92.33 22.87,91.85 22.94,91.78 23.01,91.78 v2(23.26,91.52) 23.77,92.03 23.77,93.43 24.85,94.51 27.01,94.51 28.45,93.07 34.43,93.07 34.64,93.28 35.78,93.28 40.6,93.28 44.37,97.05 47.48,97.05 50.51,94.02 73.02,94.02 76.47,90.57 96.73,90.57 98.45,88.85 103.15,88.85 105.24,86.77 105.24,85.89 108.83,82.3 109.42,82.3 109.75,81.97 109.75,81.68 109.76,81.67 109.76,81.59 109.83,81.52 109.83,81.41 111.78,79.46 111.78,74.13 113.97,71.94 114.28,71.94 117.55,68.67 117.55,65.55
  BOTTOM w0.102: UC1.G17 116.86,60.91 117,60.77 v2(117.43,60.77)
APU_HDMI_DATA: length 133.2
  TOP w0.102: v2(21.81,95.1) 22,95.29 22.2,95.29 22.35,95.14 RPI3.2 ; QI2.4 v2(23.28,92.87)
  IN2 w0.102: 117.81,65.55 117.81,65.54 117.8,65.52 117.8,63.52 118.12,63.2 118.12,63.09 118.13,63.08 118.13,60.78 117.52,60.17 v2(117.43,60.17)
  IN2 w0.127: 117.81,65.55 117.81,68.78 114.39,72.2 114.08,72.2 112.04,74.24 112.04,79.57 110.09,81.52 110.09,81.63 110.03,81.7 110.03,81.78 110.01,81.79 110.01,82.08 109.53,82.57 108.94,82.57 105.5,86 105.5,86.88 103.26,89.12 98.55,89.12 96.84,90.84 76.58,90.84 73.13,94.29 50.62,94.29 47.59,97.32 44.26,97.32 40.49,93.55 39.09,93.55 35.89,93.55 34.53,93.55 34.32,93.34 28.56,93.34 28.18,93.71 27.12,94.77 24.74,94.77 23.5,93.54 23.5,93 23.38,92.87 v2(23.28,92.87) 23.45,92.7 23.45,92.23 23.26,92.04 23.05,92.04 22.65,92.44 22.65,95.76 22.26,96.14 21.6,96.14 21.37,95.92 21.37,95.47 21.74,95.1 v2(21.81,95.1)
  BOTTOM w0.102: v2(117.43,60.17) 117.43,60.24 117.2,60.47 116.99,60.47 116.86,60.34 UC1.H17
APU_I2C1_SCL: length 29.6
  TOP w0.102: v2(125.49,41) 125.98,41.48 v1(127.15,41.48) 134.13,41.48 134.39,41.22 139.07,41.22 139.12,41.18 RPC36.8
  IN2 w0.102: 124.66,41.78 124.66,42.51 124.46,42.71 115.02,42.71 114.49,43.24 114.49,44.12 v2(115.22,44.85)
  IN2 w0.127: 124.66,41.78 124.66,41.51 124.83,41.34 124.83,41.29 125.12,41 v2(125.49,41)
  BOTTOM w0.1: UC1.AU19 115.56,45.11 115.3,44.85 v2(115.22,44.85)
APU_I2C1_SDA: length 27.8
  TOP w0.102: v2(125.5,41.61) 125.53,41.61 125.81,41.89 v1(129.18,41.89) 134.3,41.89 134.56,41.63 139.07,41.63 139.12,41.68 RPC36.7
  IN2 w0.102: v2(115.21,44.02) 115.12,43.93 115,43.93 114.9,43.83 114.9,43.4 115.19,43.12 124.75,43.12 125.14,42.72 125.14,41.83
  IN2 w0.127: v2(125.5,41.61) 125.27,41.61 125.14,41.74 125.14,41.83
  BOTTOM w0.1: 115.6,44.31 115.5,44.31 v2(115.21,44.02)
  BOTTOM w0.102: UC1.AV19 115.6,44.31
APU_ID: length 15.6
  TOP w0.102: RC707.2 135.97,45.99 135.88,45.9 135.3,45.9 135.21,45.99 RC708.1 134.39,45.53 133.4,45.53 133.34,45.59 132.76,45.59 v1(132.51,45.83) 131.72,46.63 125.84,46.63 124.63,47.84 123.24,47.84 v2(122.86,47.46)
  BOTTOM w0.1: UC1.AL5 123.06,47.66 v2(122.86,47.46)
APU_MAB_VREFDQ: length 3
  BOTTOM w0.102: UC1.Y41 103.58,53.93 101.94,53.93 101.43,54.44 T45.1
APU_PCIE_RST#: length 291.8
  TOP w0.102: RW11.2 55.65,110.59 v2(55.09,111.14) ; v2(108.48,28.21) 108.48,28.47 v1(108.73,28.72)
  IN1 w0.127: v2(108.48,28.21) 108.16,27.89 108.16,27.87 107.45,27.16 105.28,27.16 102.9,24.78 100.98,24.78 97.56,21.36 80.74,21.36 76.54,17.16 72.94,17.16 72.75,16.97 62.46,16.97 62.11,16.62 53.02,16.62 50.88,18.75 48.6,18.75 48.34,19 47.84,19 v2(47.58,19.26) ; v2(32.31,123.25) 32.31,123.56 32.66,123.91 42.44,123.91 44.15,122.19 44.15,119.53 50.96,112.72 51.85,112.72 52.37,112.2 54.04,112.2 v2(55.09,111.14) 55.09,108.22 56.94,106.37 56.94,104.07 58.13,102.88 58.13,97.54 57.51,96.92 57.51,94.55 v2(55.84,92.88) ; v2(58.22,92.25) 58.68,92.7 75.88,92.7 76.92,93.74 79.1,93.74 79.33,93.74 80.35,94.76 88.01,94.76 89.04,95.79 90.05,95.79 90.95,96.69 90.95,96.75 90.95,97.26 92.67,98.97 92.67,101.29 94.59,103.22 94.59,109.26 95.78,110.44 v2(95.84,110.44)
  IN2 w0.127: v2(55.84,92.88) 45.83,92.88 43.9,90.95 39.39,90.95 39.14,90.7 37.61,90.7 31.96,85.04 31.96,83.9 32.09,83.77 32.09,76.35 31.39,75.65 31.39,47.9 41.8,37.48 41.8,35.77 43.93,33.64 43.93,31.61 45.42,30.12 45.42,20.78 46.95,19.26 v2(47.58,19.26)
  BOTTOM w0.102: v2(55.84,92.88) 56.48,92.25 v2(58.22,92.25) ; RC27.1 110.84,31.13 110.84,30.64 110.51,30.31 108.66,30.31 RC28.2 RC30.2 108.15,28.55 v2(108.48,28.21) 108.8,27.89 109.61,27.89 UC4.4 ; v2(95.84,110.44) 95.84,110.51 93.56,112.79 93.56,119.21 93.79,119.44 UV2.2 ; RL9.2 v2(32.31,123.25)
APU_PCIE_RST#_C: length 78
  TOP w0.102: RC907.1 135.17,52.16 136.14,52.16 CC912.1 136.48,51.83 136.99,51.33 138.35,51.33 138.36,51.31 138.97,51.31 140.8,49.48 141.94,49.48 v2(142.01,49.55) ; v2(140.1,36.66) 138.68,36.66 135.71,33.69 135.71,32.12 134.91,31.32 134.91,28.43 135.47,27.87 135.47,26.42 135.03,25.99 134.7,25.99 134.46,26.23 134.46,26.64 v2(134.83,27.01) ; v2(109.06,28.3) 109.45,27.91 v1(109.45,25.42) v2(109.45,21.78)
  IN2 w0.127: v2(140.1,36.66) 140.48,37.04 140.48,42.82 142.01,44.34 v2(142.01,49.55)
  BOTTOM w0.102: v2(109.45,21.78) 109.47,21.8 109.47,22.34 110.65,23.53 112.04,23.53 112.22,23.7 112.29,23.7 112.67,24.08 114.26,24.08 116.3,26.13 116.3,27.69 117.37,28.76 120.95,28.76 124.67,25.04 128.54,25.04 128.63,25.13 129.25,25.13 130.6,25.13 132.67,27.2 134.64,27.2 v2(134.83,27.01) ; v2(109.06,28.3) RC30.1 109.99,28.91 RC25.1
APU_PCIE_RST#_R: length 11.7
  TOP w0.102: v2(123.66,50.76) 124.54,50.76 v1(125.59,51.8) 126,52.22 133.55,52.22 RC907.2
  BOTTOM w0.102: v2(123.66,50.76) 123.86,50.96 UC1.AE4
APU_PCIE_WAKE#: length 328.2
  IN1 w0.127: v2(29.93,82.76) 29.93,83 33.36,86.43 33.36,88.81 42.1,97.55 47.71,97.55 48.34,98.18 55.27,98.18 55.6,98.5 55.6,99.29 55.48,99.4 55.48,99.95 54.76,100.68 54.76,102.88 48.15,109.49 48.15,114.12 45.17,117.09 44.95,117.09 43.63,118.41 43.63,121.82 42.36,123.1 v2(38.39,123.1) ; v2(184.64,25.01) 184.57,25.01 184.43,25.16 184.21,25.38 183.79,25.38 183.17,24.76 183.17,24.11 183.31,23.97 183.31,22.67 184.49,21.49 184.49,18.94 184.74,18.69 184.74,18.24 182.76,16.26 182.76,13.79 180.08,11.12 179.49,11.12 173.49,11.12 168.42,6.05 156.06,6.05 153.43,3.42 151.47,3.42 149.63,1.59 89,1.59 87.14,3.45 74.38,3.45 71.64,6.2 66.45,6.2 62.88,9.76 46.22,9.76 38.88,17.1 38.88,26.47 36.07,29.28 31.86,29.28 v2(31.29,29.85)
  IN2 w0.127: v2(31.29,29.85) 31.29,29.89 31.2,29.98 26.24,29.98 22.12,34.11 22.12,34.29 22.12,34.5 22.12,34.71 22.12,62.61 22.13,62.62 22.13,63.21 23.64,64.72 23.64,71.2 30.25,77.81 30.25,82.44 v2(29.93,82.76)
  BOTTOM w0.102: v2(38.39,123.1) 37.39,122.1 37.2,122.1 36.84,121.74 RL10.2 36.71,121.74 36.1,121.12 34.13,121.12 33.49,120.49 UL1.21 ; RE41.1 184.88,25.26 v2(184.64,25.01) 184.61,24.99 v1(184.61,24.47) 185.55,24.47 RC967.1
APU_PCIE_WAKE#_R: length 88.8
  TOP w0.102: v2(182.89,23.36) 182.89,23.69 v1(183.04,23.85)
  IN1 w0.102: v2(122.06,50.76) 122.13,50.76 122.51,50.37 124,50.37 124.07,50.44 127.59,50.44 129.31,48.72
  IN1 w0.127: v2(182.89,23.36) 182.89,25.06 184.78,26.95 184.78,31.85 184.7,31.93 184.7,32.84 184.11,33.44 184.11,34.02 184.11,37.46 182.92,38.65 181.02,38.65 180.82,38.45 180.8,38.45 180.8,38.45 180.59,38.45 177.26,38.45 177.26,38.45 170.63,38.45 169.88,39.2 168.19,39.2 167.85,39.53 165.97,39.53 165.23,40.27 160.66,40.27 158.47,42.46 158.43,42.46 158.33,42.56 142.39,42.56 140.1,44.85 139.02,44.85 138.7,44.53 134.98,44.53 133.91,45.6 132.43,45.6 129.31,48.72
  BOTTOM w0.102: v2(122.06,50.76) 122.26,50.96 UC1.AE7 ; RC967.2 185.87,23.87 183.4,23.87 v2(182.89,23.36)
APU_PWRGD: length 211.3
  TOP w0.102: v2(108.68,74.26) 108.68,74.3 107.97,75.01 107.97,80.22 106.74,81.45 102.57,81.45 v1(101.56,82.47) 101.56,85.4 102.93,86.77 102.93,87.15 105.11,89.34 105.11,90.19 107.14,92.22 108.1,92.22 109.18,93.3 114.04,93.3 115.15,94.4 115.15,94.95 114.89,95.2 113.62,95.2 v2(113.43,95.4) ; DH1.2 81.06,73.86 v2(81.06,73.17) ; UC62.4 121.07,84.55 121.32,84.3 RC54.1 RC4.2 RC81.2 125.1,84.3 v2(125.29,84.11) ; v2(112.99,60.91) 112.09,60.01 CC50.1 111.67,60.01 111.27,60.41 110.61,60.41 110.51,60.51 110.51,60.93 110.56,60.98 110.56,61.31 110.47,61.4 110.47,61.77 111.22,62.51 111.22,64.66 110.38,65.5 110.38,67.65 110.51,67.77 110.51,68.53 108.41,70.63 102.19,70.63 v2(102.13,70.69)
  TOP w0.203: PU1001.9 169.5,61.8 169.74,62.05 169.77,62.05 169.86,62.13 170.15,62.13 170.26,62.25 v2(170.26,62.31)
  IN1 w0.127: v2(132.24,71.85) 132.24,77.92 126.05,84.11 v2(125.29,84.11)
  IN2 w0.127: v2(125.29,84.11) 125.29,84.59 125.69,84.98 125.69,85.74 126.45,86.51 126.45,87.33 125.62,88.16 123.4,88.16 119.02,92.54 117.69,92.54 116.48,93.74 115.51,93.74 114.23,93.74 113.66,94.31 113.66,94.31 113.43,94.54 v2(113.43,95.4) ; v2(170.26,62.31) 169.18,62.31 168.12,63.37 167.62,63.37 165.95,65.04 165.95,70.36 161.14,75.17 149.09,75.17 148.17,76.09 142.01,76.09 141.24,75.33 134.74,75.33 132.24,72.82 v2(132.24,71.85) 132.24,65.6 132.8,65.04 134.6,65.04 135.11,64.53 135.11,57.06 136.34,55.83 136.34,47.19 v2(135.47,46.31)
  BOTTOM w0.102: UC1.G25 112.78,61.11 v2(112.99,60.91) ; v2(81.06,73.17) 83.54,70.69 v2(102.13,70.69) 103.78,70.69 107.4,74.31 108.63,74.31 v2(108.68,74.26) ; RC663.2 v2(135.47,46.31)
APU_PWRGD_BUF: length 4.1
  TOP w0.102: DH1.1 85.14,75.84 JHDT1.10
APU_PWRGD_EC: length 93.7
  TOP w0.102: RC54.2 122.19,82.25 121.69,81.74 120.54,81.74 v2(120.1,82.19) 120.42,82.5 UC62.2 ; v2(171.85,42.44) v1(171.34,42.44)
  IN1 w0.127: v2(135.59,69.36) 134.64,70.31 125.88,70.31 122.16,74.03 122.16,80.13 v2(120.1,82.19)
  IN2 w0.127: v2(171.85,42.44) 171.34,42.94 166.39,42.94 164.68,41.23 161.27,41.23 158.89,43.6 148.2,43.6 147.53,44.28 143.78,44.28 142.96,45.1 142.96,50.12 142.39,50.69 140.23,50.69 138.13,52.79 138.13,55.96 136.61,57.49 136.61,68.34 v2(135.59,69.36)
  BOTTOM w0.102: UE1.108 172.02,39.49 172.36,39.83 172.36,41.93 v2(171.85,42.44)
APU_PWRGD_R: length 10.6
  BOTTOM w0.102: RC663.1 133.36,45.74 132.34,45.74 131.77,46.31 CC32.2 129.67,48.28 v1(129.24,48.28) 129.12,48.28 128.23,49.17 126.33,49.17 126.09,49.41 125.83,49.41 125.71,49.29 125.7,49.29 125.51,49.11 UC1.AJ2
APU_RST#: length 133.1
  TOP w0.102: v2(139.42,44.14) v1(138.57,44.14) 138.13,43.71 RC662.2 ; DH2.2 81.24,76.22 80.92,76.54 v2(80.92,76.79) ; v2(106.7,68.03) 107.21,68.53 109.94,68.53 110.26,68.22 110.26,67.84 110.13,67.71 110.13,65.47 111.02,64.58 111.02,63.12 CC51.1 110.31,62.42 v2(109.73,62.42)
  IN1 w0.102: 129.31,66.25 125.88,66.25 123.27,63.65 110.95,63.65 109.73,62.42 v2(109.73,62.42)
  IN1 w0.127: 129.31,66.25 v2(133.18,66.25) ; v2(129.69,85.11) 129.56,84.98 129.56,81.17 132.72,78.01 v2(132.72,71.32)
  IN2 w0.127: v2(132.72,71.32) 132.71,71.31 132.71,66.72 v2(133.18,66.25) 134.07,65.36 134.8,65.36 135.59,64.57 135.59,57.03 136.66,55.96 136.66,45.75 138.27,44.14 v2(139.42,44.14)
  BOTTOM w0.102: v2(129.69,85.11) 129.56,85.24 129.56,86.06 127.85,87.78 127.85,88.79 ; UC63.4 126.91,88.9 127.08,88.73 127.78,88.73 127.85,88.79 ; 127.85,88.79 127.96,88.91 RC7.2 RC80.2 128.04,90.39 128.04,91.66 RC57.1 ; v2(109.73,62.42) 109.97,62.42 UC1.D29 ; v2(106.7,68.03) 106.76,68.03 107.59,68.85 107.59,71.07 106.83,71.84 105.3,71.84 103.59,70.12 83.27,70.12 80.6,72.79 80.6,76.47 v2(80.92,76.79)
APU_RST#_BUF: length 4
  TOP w0.102: JHDT1.12 v1(85.24,77.11) 84.76,77.11 DH2.1
APU_RST#_EC: length 107.5
  TOP w0.102: v2(174.45,42.44) 174.45,42.37 v1(174.84,41.99)
  IN1 w0.127: v2(137.37,66.06) 137.37,66.44 136.8,67.01 136.8,69.17 133.26,72.71 133.26,79.44 133.24,79.46 133.24,79.56 130.43,82.38 v2(130.43,84.47)
  IN2 w0.127: v2(174.45,42.44) 173.44,43.45 171.6,43.45 171.41,43.26 166.33,43.26 165.76,42.69 165.76,42.67 164.57,41.48 161.37,41.48 159,43.86 148.33,43.86 147.59,44.6 143.97,44.6 143.28,45.29 143.28,50.18 142.51,50.95 140.36,50.95 138.39,52.91 138.39,56.15 136.93,57.61 136.93,65.87 137.12,66.06 v2(137.37,66.06) ; v2(130.43,84.47) 130.43,85 128.61,86.82 127.78,86.82 125.81,88.79 123.34,88.79 122.38,89.74 122.38,91.46 123.46,92.54 125.69,92.54 v2(126.53,93.37)
  BOTTOM w0.102: UC63.2 126.26,92.42 RC57.2 126.31,93.15 v2(126.53,93.37) ; v2(174.45,42.44) 174.58,42.56 176.68,42.56 177.12,42.12 177.12,40.34 176.02,39.24 UE1.118
APU_RST#_R: length 17.1
  TOP w0.102: v2(123.66,47.46) 123.91,47.21 123.91,46.18 124.16,45.93 124.99,45.93 126.23,44.68 130.13,44.68 v1(130.5,44.31) 131.05,44.31 132.09,43.27 133.68,43.27 134.38,42.58 136.23,42.58 CC31.2 RC662.1
  BOTTOM w0.1: v2(123.66,47.46) 123.86,47.66 UC1.AL4
APU_SCLK0: length 84.4
  TOP w0.102: v2(104.98,36.98) 104.99,36.98 v1(105.37,36.59)
  IN1 w0.127: v2(51.58,22.12) 52.52,21.18 56.29,21.18 56.62,20.85 56.75,20.85 57.13,20.47 63.61,20.47 64.41,19.67 64.91,19.67 65.2,19.96 v2(65.2,20.15) 65.34,20.29 66.39,20.29 67.23,19.45 68.66,19.45 69.17,19.96 72.19,19.96 78.99,26.76 90.98,26.76 98.66,34.44 103.06,34.44 104.97,36.35 104.97,36.39 104.98,36.4 v2(104.98,36.98)
  BOTTOM w0.102: JDIMM2.253 52.09,22.63 v2(51.58,22.12) ; v2(65.2,20.15) 65.11,20.24 65.11,21.61 65.62,22.12 JDIMM1.253 ; UC1.AY33 108.3,42.67 108.3,42.43 108.38,42.35 108.38,42.08 108.36,42.07 108.36,41.9 108.36,41.9 108.36,41.83 108.36,41.83 108.36,39.79 108.34,39.78 108.34,39.69 108.1,39.45 108.1,38.96 106.12,36.98 v2(104.98,36.98) 102.32,36.98 101.81,37.49 RPC64.3
APU_SDATA0: length 86.4
  TOP w0.102: v2(64.58,20.11) 64.57,20.11 v1(64.16,20.53)
  IN1 w0.127: v2(104.54,36.53) 102.89,34.88 98.49,34.88 91,27.38 78.73,27.38 71.93,20.58 69.19,20.58 68.49,19.89 67.4,19.89 66.57,20.72 64.89,20.72 64.58,20.41 v2(64.58,20.11) 63.65,21.04 61.69,21.04 61.55,20.9 57.55,20.9 57.17,21.28 56.93,21.28 56.6,21.61 52.73,21.61 51.77,22.56 51.21,22.56 v2(51.11,22.46)
  BOTTOM w0.102: v2(64.58,20.11) 64.7,20.23 64.7,21.51 64.33,21.87 JDIMM1.254 ; v2(51.11,22.46) 51.14,22.46 51.14,22.43 51.08,22.38 JDIMM2.254 ; UC1.BA32 108.61,41.86 108.56,41.81 108.56,41.75 108.56,41.75 108.56,39.54 108.51,39.49 108.51,38.79 106.25,36.53 v2(104.54,36.53) 102.13,36.53 101.67,36.99 RPC64.4
APU_SIC: length 27.6
  TOP w0.102: v2(108.68,74.88) 109.13,75.33 109.94,75.33 110.38,75.77 110.38,76.41 v1(109.46,77.33) 109.3,77.49 109.3,79.33 110.89,80.92 110.89,84.54 110.64,84.79 QC79.4
  BOTTOM w0.102: RPC25.3 108.99,76.21 108.74,75.96 108.74,75.39 108.68,75.33 v2(108.68,74.88) 108.68,74.83 109.24,74.27 109.24,70.66 108.91,70.33 108.91,67.81 109.46,67.26 109.46,64.67 109.4,64.6 109.4,64.33 109.71,64.01 UC1.B30
APU_SID: length 22.5
  TOP w0.102: QC79.1 107.83,82.58 108.14,82.28 109.14,82.28 109.82,81.6 109.82,80.67 v1(109.24,80.09) 109.05,79.9 109.05,76.55 109.68,75.92 109.86,75.92 v2(109.94,76)
  BOTTOM w0.102: UC1.B29 110.26,64.28 110.24,64.29 110.24,64.38 109.88,64.74 109.88,66.09 109.91,66.12 109.91,67.39 109.37,67.93 109.37,70.14 109.39,70.16 109.7,70.47 109.7,74.83 109.7,74.83 109.7,75.02 109.6,75.12 109.6,75.66 109.85,75.91 109.85,75.91 v2(109.94,76) 109.94,76 109.99,76.05 RPC25.1
APU_SPI_CLK: length 20.1
  TOP w0.102: v2(119.59,26.31) 119.72,26.31 v4(120.1,25.93)
  IN2 w0.127: v2(118.99,32.66) 118.99,30.01 118.99,30.01 118.99,29.31 118.99,29.31 118.99,26.91 v2(119.59,26.31)
  BOTTOM w0.102: v2(118.99,32.66) 119.32,32.99 C27.1 RC106.1 ; v2(119.59,26.31) 120.04,25.86 120.04,25.32 118.1,23.38 118.1,20.9 118.79,20.21 UC5.6 JH1.6 121.77,20.21 RC617.1
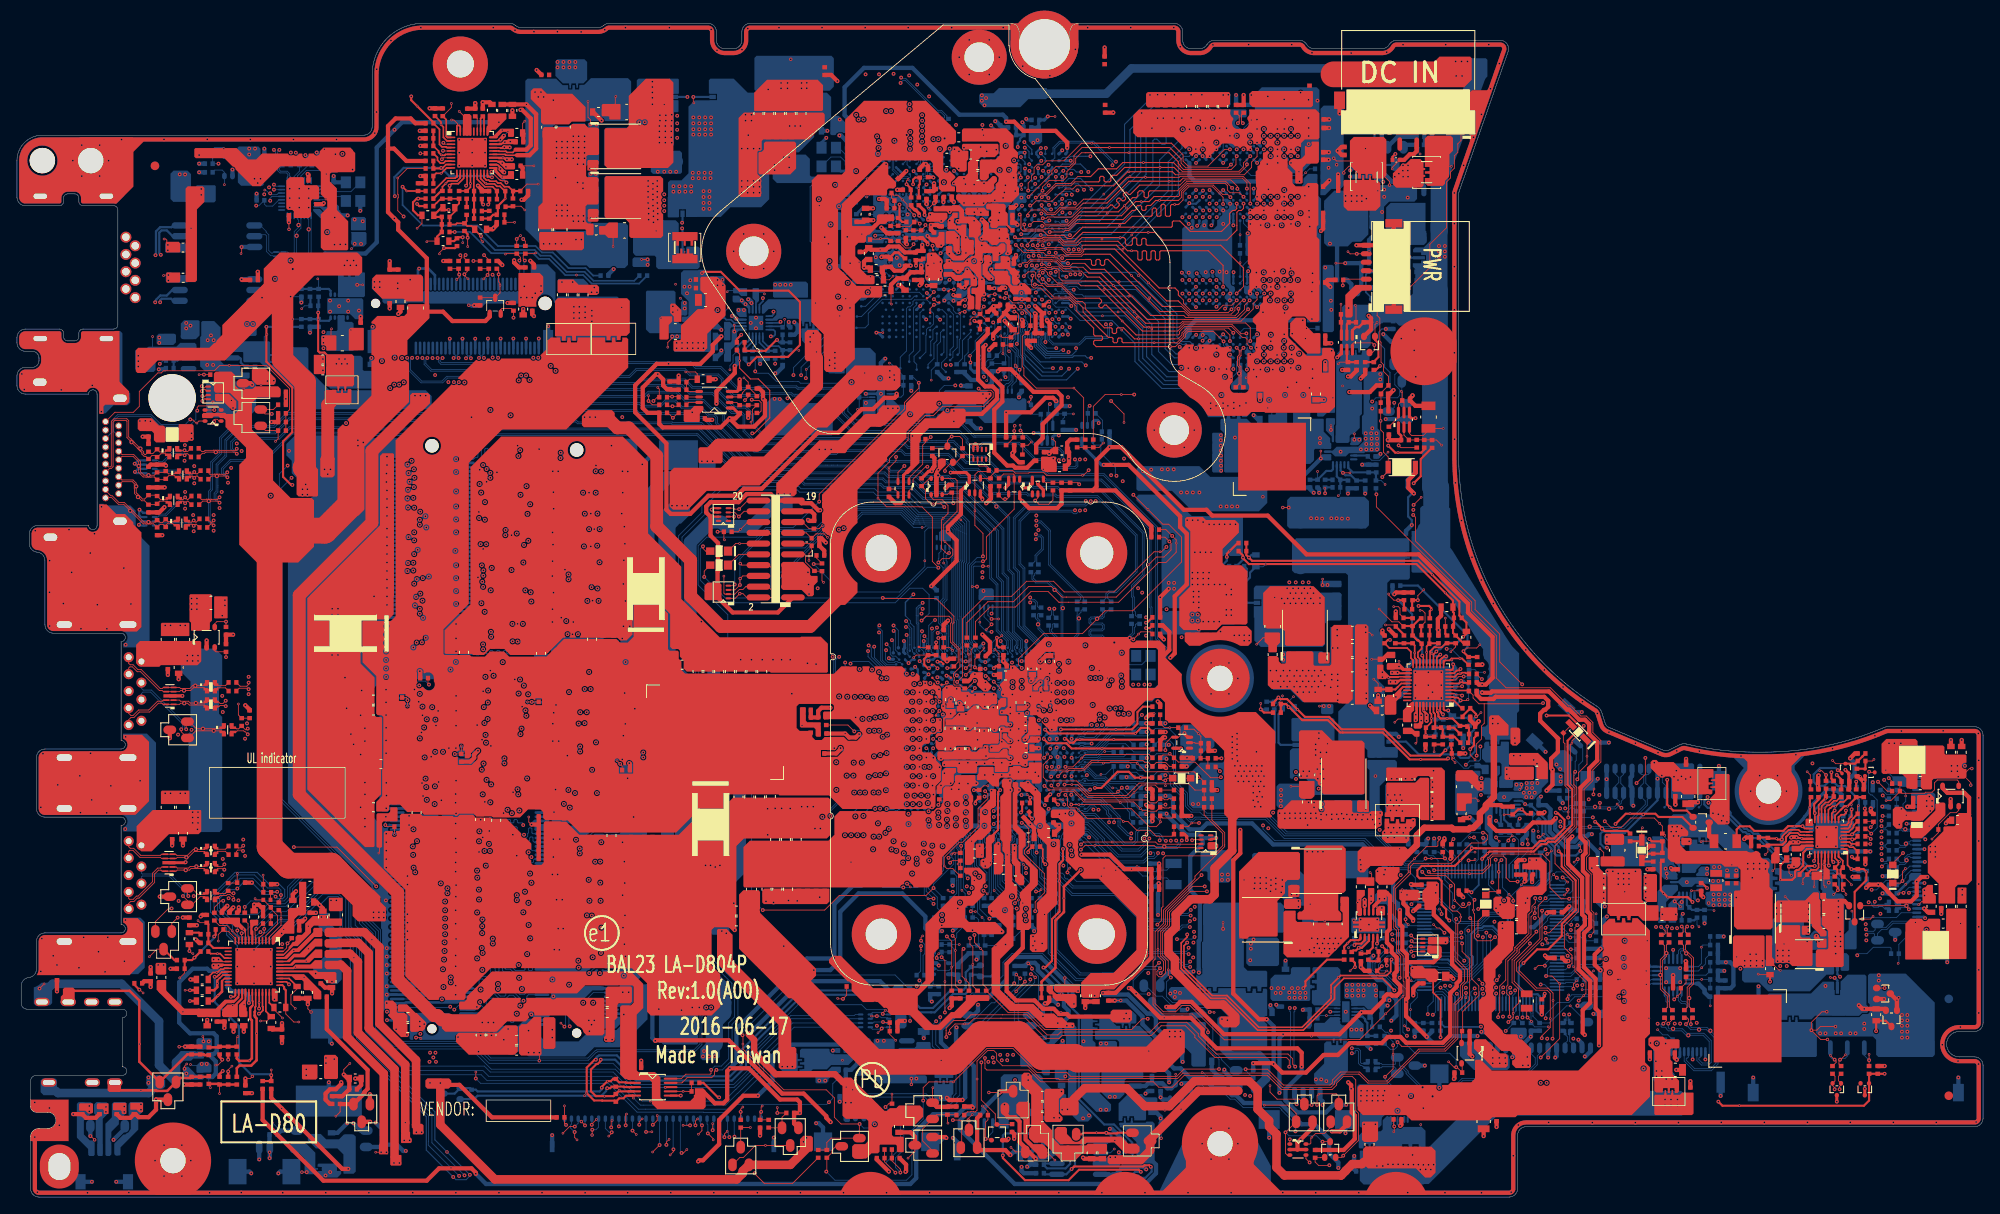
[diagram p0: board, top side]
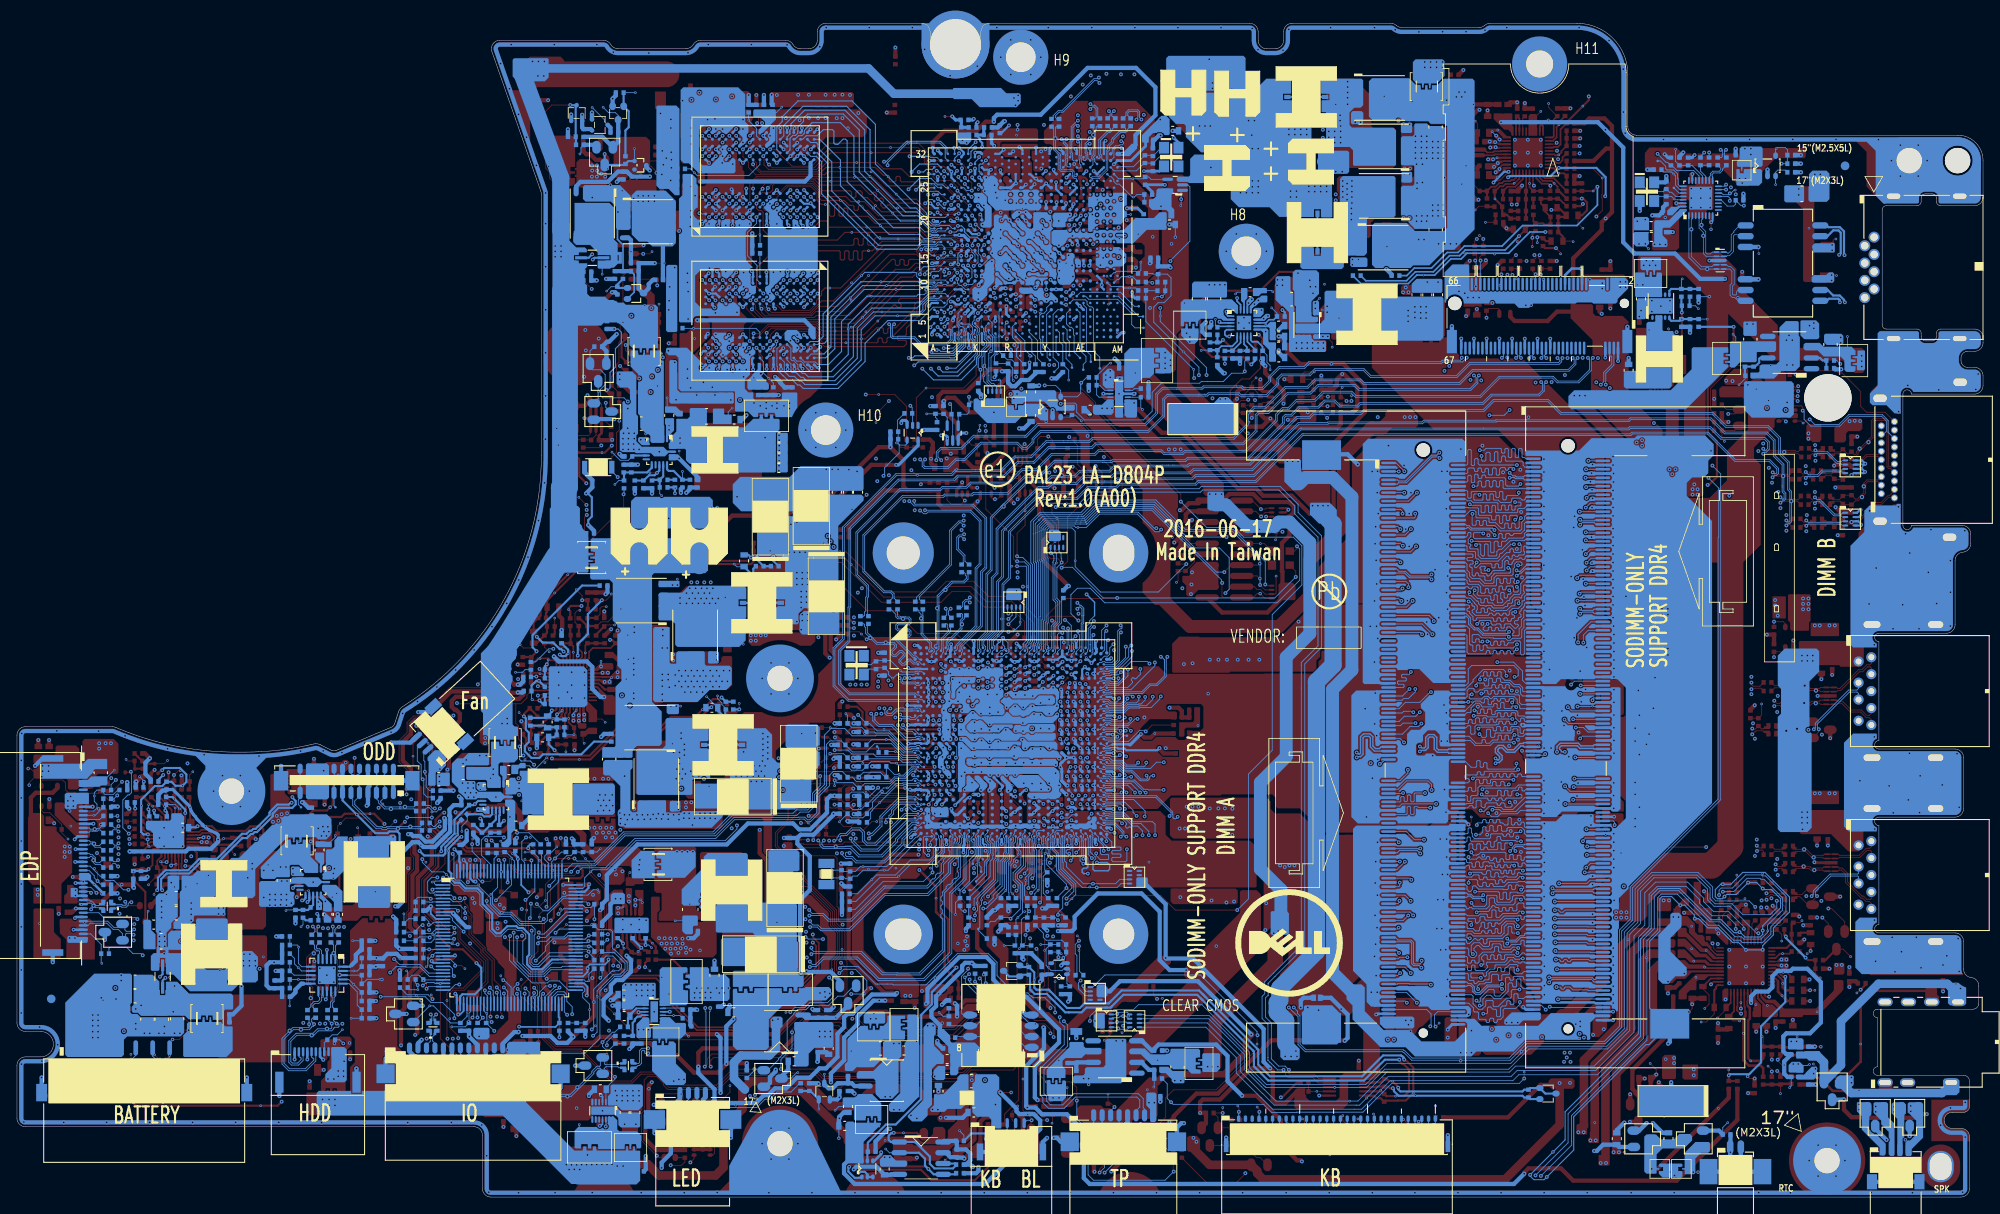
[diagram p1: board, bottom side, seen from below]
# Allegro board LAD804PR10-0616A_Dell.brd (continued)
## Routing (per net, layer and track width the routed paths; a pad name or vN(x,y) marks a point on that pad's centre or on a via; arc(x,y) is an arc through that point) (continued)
APU_SPI_CLK_R: length 9.1
  BOTTOM w0.102: UC1.AY17 117.03,42.74 117.03,42.48 117.18,42.34 117.18,42.09 116.78,41.69 116.78,40.43 116.8,40.4 v1(116.8,40.38) 116.8,39.93 117.11,39.62 117.11,37.81 RC106.2
APU_SPI_CS1#: length 33.5
  TOP w0.102: v4(117.85,24.28) 117.85,24.38 v2(118.89,25.42)
  IN2 w0.127: v2(118.89,25.42) 118.77,25.29 118.25,25.29 117.9,25.64 117.9,26.01 118,26.11 118,28.9 118,33.97 v2(117.92,34.05)
  BOTTOM w0.102: UC1.AY21 114.66,42.66 114.98,42.34 114.98,42.02 114.95,41.99 114.95,40.58 115.03,40.5 115.03,39.95 115.44,39.54 115.44,36.46 116.3,35.6 116.3,35.32 117.58,34.05 v2(117.92,34.05) ; RC639.1 v2(118.89,25.42) 118.64,25.17 118.64,24.96 114.07,20.38 114.07,18.81 112.92,17.67 UC5.1
APU_SPI_CS1#_R: length 14
  BOTTOM w0.102: UC1.AY19 115.91,42.76 115.91,42.51 116.08,42.34 116.08,42.34 116.11,42.31 116.11,41.89 116.14,41.86 116.14,41.5 116.09,41.44 116.09,39.75 116.2,39.64 116.2,37.3 118.13,35.37 118.13,34.5 118.34,34.29 118.34,31.81 T52.1 118.51,31.5 RC48.1
APU_SPI_HOLD#: length 29.4
  IN2 w0.127: v2(118.9,33.23) 118.56,32.89 118.56,30.19 118.56,30.19 118.56,29.13 118.56,29.13 118.56,26.64 v2(119.53,25.67)
  BOTTOM w0.102: RC642.1 121.1,18.94 JH1.7 UC5.7 118.32,18.94 117.64,19.62 117.64,23.5 119.53,25.39 v2(119.53,25.67) ; v2(118.9,33.23) 118.9,33.54 118.6,33.84 118.6,34.46 118.66,34.52 118.66,34.67 v1(118.64,34.69) 118.64,35.22 116.45,37.4 116.45,39.68 116.29,39.84 116.29,41.22 116.37,41.29 116.37,41.92 116.31,41.98 UC1.BA18
APU_SPI_MISO: length 28.3
  TOP w0.102: v4(117.88,26.24) 118.32,25.8 v2(118.34,25.8)
  IN2 w0.127: v2(118.34,25.8) 118.28,25.86 118.28,29.01 118.28,33.2 119,33.93 v2(119,34.02)
  BOTTOM w0.102: UC1.BA17 116.57,41.92 116.57,41.21 116.5,41.13 116.5,39.92 116.71,39.71 116.71,37.51 119,35.21 v2(119,34.02) ; v2(118.34,25.8) 118.13,25.58 118.13,25 116.48,23.35 116.47,23.35 116.23,23.11 116.23,23.1 113.56,20.43 113.56,19.65 112.85,18.94 UC5.2
APU_SPI_MOSI: length 26.2
  TOP w0.102: v2(119.72,26.94) 119.72,27.13 v4(119.27,27.58)
  IN2 w0.127: v2(119.72,26.94) 119.42,27.24 119.42,29.49 119.42,34.24 118.27,35.39 117.45,35.39 v2(117.37,35.47)
  BOTTOM w0.102: v2(119.72,26.94) 119.72,26.82 120.48,26.05 120.48,21.68 120.28,21.48 JH1.5 ; v2(117.37,35.47) 115.95,36.89 115.95,39.61 115.54,40.02 115.54,40.57 115.36,40.75 115.36,41.83 115.4,41.87 115.4,42.3 115.45,42.34 115.45,42.35 115.53,42.43 115.53,42.69 115.33,42.88 115.21,43.01 UC1.AY20
APU_SPI_TPMCS#: length 7.4
  BOTTOM w0.102: RC646.1 115.84,35.59 v1(115.26,36.17) 115.26,36.21 115.18,36.29 115.18,39.51 114.83,39.87 114.83,40.4 114.75,40.48 114.75,42.12 UC1.BA21
APU_SPI_WP#: length 28.1
  TOP w0.102: v2(117.71,34.67) 117.73,34.67 v1(118.13,35.07)
  IN2 w0.127: v2(117.71,34.67) 117.49,34.45 117.49,33.54 117.72,33.32 117.72,26.72 117.62,26.62 v2(117.62,25.23)
  BOTTOM w0.102: v2(117.71,34.67) 117.36,34.67 116.76,35.28 116.76,35.62 115.69,36.69 115.69,39.58 115.23,40.03 115.23,40.59 115.16,40.67 115.16,41.91 115.2,41.95 115.2,42.38 115.21,42.4 UC1.BA20 ; RC640.1 117.69,25.29 v2(117.62,25.23) 115.32,22.93 114.93,22.93 112.22,20.21 UC5.3 JH1.3
APU_SPKR: length 157.8
  TOP w0.102: CC15.1 v1(110.26,27.13) 110.26,30.18 v2(109.68,30.75) ; v2(18.24,34.05) 17.88,34.05 16.33,32.5 DA3.3 ; v2(42.37,36.66) 37.74,41.29 v2(32.66,41.29)
  IN1 w0.127: v2(42.37,36.66) 43.01,36.02 43.01,34.75 43.82,33.94 43.82,30.17 43.2,29.55 43.2,19.77 44.72,18.24 50.5,18.24 53.93,14.81 63.65,14.81 63.9,15.07 75.33,15.07 81.11,20.85 97.81,20.85 101.24,24.28 103.14,24.28 105.49,26.62 109.06,26.62 109.82,27.39 109.82,29.92 109.68,30.05 v2(109.68,30.75) ; v2(32.66,41.29) 30.25,43.71 23.39,43.71 18.44,38.75 18.44,34.24 v2(18.24,34.05)
  IN2 w0.102: v2(109.75,46.37) 109.68,46.37 109.18,45.87 108.41,45.87 108.19,45.64 108.19,43.33 109.56,41.95 109.56,41.01 109.12,40.57 109.12,38.88
  IN2 w0.127: v2(109.68,30.75) 109.53,30.9 109.53,33.46 108.8,34.2 108.8,37.48 109.12,37.81 109.12,38.88
  BOTTOM w0.102: v2(109.75,46.37) 110.08,46.71 UC1.AP29
APU_SVC: length 84.2
  TOP w0.102: RC669.1 113.05,67.9 114.76,69.61 117.76,69.61 119.59,71.44 121.64,71.44 122.89,70.19 123.02,70.19 124.03,70.19 124.03,70.19 129.94,70.19 134.64,74.88 135.53,74.88 136.74,76.09 v1(136.74,77.17) 136.74,77.54 v2(136.27,78.01) 135.52,78.76 RC9.2 ; PU1001.3 169.55,59.41 169.69,59.26 170.37,59.26 v2(170.45,59.17)
  IN2 w0.127: v2(136.27,78.01) 149.3,78.01 150.17,77.14 161.86,77.14 167.48,71.52 167.85,71.15 167.85,69.23 170.07,67.01 170.07,64.02 171.83,62.27 171.83,60.62 170.45,59.25 v2(170.45,59.17)
APU_SVC_R: length 4.6
  TOP w0.102: v2(111.91,61.61) 111.91,61.62 v1(112.42,62.12) 112.54,62.25 112.54,64.58 RC669.2
  BOTTOM w0.102: UC1.E27 111.61,61.91 v2(111.91,61.61)
APU_SVD: length 81
  TOP w0.102: v2(170.45,60.28) 170.38,60.2 169.95,60.2 PU1001.5 ; RC10.2 135.42,77.87 v2(135.92,77.36) 136.13,77.16 136.13,76.36 135.29,75.52 134.39,75.52 v1(133.5,74.63) 129.66,70.8 123.78,70.8 123.78,70.79 123.27,70.79 122.01,72.05 119.34,72.05 117.53,70.25 114.51,70.25 112.03,67.77 RC670.1
  IN2 w0.127: v2(135.92,77.36) 149.05,77.36 149.54,76.88 149.91,76.5 161.6,76.5 167.22,70.89 167.22,68.92 169.31,66.82 169.31,63.89 171.19,62.01 171.19,61.02 v2(170.45,60.28)
APU_SVD_R: length 3.6
  TOP w0.102: RC670.2 112.16,64.97 112.16,64.09 v1(112.19,64.06) 112.29,63.96 112.29,62.76 111.94,62.41 v2(111.91,62.41)
  BOTTOM w0.102: v2(111.91,62.41) 111.61,62.71 UC1.D27
APU_SVT: length 5.3
  TOP w0.102: PU1001.7 169.66,61 170.07,61.42 v2(170.64,61.42)
  BOTTOM w0.102: v2(170.64,61.42) 171.2,61.42 RC2.2 171.28,61.37 RC673.1 171.97,62.24 172.28,61.92 v1(173.1,61.92)
APU_SVT_R: length 80.6
  TOP w0.102: v2(135.58,76.71) 135.01,76.14 v1(134.83,76.14) 134.12,76.14 129.38,71.4 123.52,71.4 122.27,72.66 119.08,72.66 117.3,70.88 114.19,70.88 111.53,68.22 111.53,61.42 v2(110.89,60.79)
  IN2 w0.127: v2(168.64,64.69) 168.64,66.54 166.58,68.6 166.58,70.62 161.34,75.87 149.34,75.87 148.48,76.73 135.59,76.73 v2(135.58,76.71)
  BOTTOM w0.102: RC673.2 170.72,63.15 169.18,64.69 v2(168.64,64.69) ; v2(110.89,60.79) 110.89,60.78 UC1.H27
APU_TCK: length 49
  TOP w0.102: RPH1.1 84.7,70.64 v4(85.26,71.2) 85.63,71.2 86.08,70.76 JHDT1.2 89.62,70.76 89.77,70.91 89.77,72.45 v2(89.75,72.47)
  BOTTOM w0.102: UC1.B27 111.36,64.36 111.06,64.67 111.06,64.93 111.11,64.98 111.11,65.11 111.02,65.2 111.02,68.09 110.97,68.14 110.97,75.11 110.97,75.12 111.11,75.25 111.11,78.63 111.11,78.63 111.11,79.01 110.47,79.65 106.98,79.65 106.98,79.65 106.41,79.65 105.85,79.65 105.84,79.65 105.78,79.65 104.39,81.04 98.05,81.04 89.83,72.83 89.83,72.69 89.75,72.6 v2(89.75,72.47)
APU_TDI: length 54.1
  TOP w0.102: JHDT1.6 85.62,73.3 v4(85.3,72.98) 85.28,72.95 v2(85.28,72.23) 84.69,71.64 RPH1.3
  BOTTOM w0.102: UC1.B25 112.46,64.36 112.07,64.75 112.07,65.11 112.02,65.16 112.02,65.35 111.91,65.46 111.91,68.48 111.88,68.5 111.88,74.73 112.02,74.87 112.02,78.25 112.02,79.68 111.14,80.56 106.23,80.56 104.8,82 97.68,82 94.24,78.55 88.54,78.55 85.28,75.29 v2(85.28,72.23)
APU_TDO: length 44.9
  TOP w0.102: v2(89.49,73.74) 88.67,74.57 JHDT1.8 85.49,74.57 v4(85.31,74.74)
  BOTTOM w0.102: UC1.A27 111.36,64.99 111.34,65.02 111.34,65.17 111.22,65.29 111.22,68.48 111.2,68.5 111.2,75.02 111.34,75.16 111.34,78.53 111.34,79.1 110.56,79.88 106.89,79.88 106.32,79.88 106.32,79.88 105.94,79.88 105.88,79.88 104.48,81.27 97.95,81.27 90.42,73.74 90.23,73.74 v2(89.49,73.74)
APU_TEST0: length 10
  BOTTOM w0.102: RC678.2 133.47,50.36 132.16,50.36 RC40.2 131.13,51.39 129,51.39 128.81,51.2 v1(128.16,51.2) 127.96,50.99 125.83,50.99 125.75,51.07 125.48,51.07 125.16,50.76 UC1.AF2
APU_TEST1: length 10.8
  BOTTOM w0.102: UC1.AE1 127.45,51.31 127.85,51.71 131.58,51.71 RC41.2 132.16,51.38 133.47,51.38 RC33.2 134.41,52.32 v4(135.99,52.32)
APU_TEST2: length 18.2
  TOP w0.102: v2(130.32,48.3) v4(129.86,47.85) 129.66,47.64 126.45,47.64 124.99,49.1 121.5,49.1 121.05,49.55 121.05,51.01 v2(121.94,51.9)
  BOTTOM w0.102: v2(121.94,51.9) 121.94,51.93 UC1.AC8 ; RC683.2 133.47,47.78 132.1,47.78 RC42.2 131.3,47.33 130.32,48.3 v2(130.32,48.3)
APU_TEST4: length 1.5
  TOP w0.102: v2(109.68,60.71) 109.43,60.46 T34.1
  BOTTOM w0.102: v2(109.68,60.71) 109.86,60.71 UC1.H29
APU_TEST5: length 1.4
  TOP w0.102: v2(109.64,61.52) 109.92,61.52 T35.1
  BOTTOM w0.25: v2(109.64,61.52) 110.05,61.11 UC1.G29
APU_TEST6: length 1.2
  TOP w0.102: v2(112.99,60.06) 112.99,59.96 T36.1
  BOTTOM w0.102: UC1.H25 112.74,60.31 v2(112.99,60.06)
APU_TEST9: length 1.3
  TOP w0.102: T38.1 108.39,56.96 v2(108.79,57.36)
  BOTTOM w0.102: UC1.R32 108.66,57.23 v2(108.79,57.36)
APU_TEST10: length 1.4
  TOP w0.102: v2(108.81,58.46) 108.81,58.55 T39.1
  BOTTOM w0.102: v2(108.81,58.46) 108.66,58.31 UC1.N32
APU_TEST14: length 12.8
  TOP w0.102: v1(115.91,59.9) 115.91,60.12 v2(115.22,60.81) ; v1(114.32,66.95) v2(114.96,67.58)
  IN2 w0.102: v2(115.22,60.81) 115.65,61.24 115.65,62.57 114.89,63.33 114.89,65.55
  IN2 w0.127: 114.89,65.55 114.89,65.93 115.4,66.44 115.4,67.14 v2(114.96,67.58)
  BOTTOM w0.102: RPC30.7 114.07,68.47 v2(114.96,67.58) ; v2(115.22,60.81) 114.92,61.11 UC1.G21
APU_TEST15: length 11.6
  IN2 w0.102: 114.64,65.55 114.64,60.79 115.22,60.2 v2(115.22,60.01)
  IN2 w0.127: 114.64,65.55 114.64,66.38 v2(114.96,66.69)
  BOTTOM w0.102: RPC30.8 v1(113.57,67.84) 113.57,67.51 114.38,66.69 v2(114.96,66.69) ; UC1.H21 114.92,60.31 v2(115.22,60.01)
APU_TEST16: length 10.9
  TOP w0.102: v2(114.96,68.22) v1(115.78,68.22)
  IN2 w0.102: v2(114.23,62.32) 113.81,62.74 113.81,64.28 113.05,65.04 113.05,65.55
  IN2 w0.127: 113.05,65.55 113.05,67.07 114.07,68.09 114.83,68.09 v2(114.96,68.22)
  BOTTOM w0.102: UC1.D23 113.95,62.32 v2(114.23,62.32) ; RPC30.6 114.57,69.1 114.51,69.04 114.51,68.66 v2(114.96,68.22)
APU_TEST17: length 12.1
  TOP w0.102: v2(114.25,61.48) 114.45,61.48 114.64,61.3 v1(114.64,61.11)
  IN2 w0.102: v2(114.25,61.48) 114.21,61.52 114.21,61.53 113.56,62.18 113.56,64.09 112.61,65.04 112.61,65.55
  IN2 w0.127: 112.61,65.55 112.61,67.77 113.56,68.73 114.83,68.73 v2(114.96,68.85)
  BOTTOM w0.102: UC1.E23 113.83,61.91 v2(114.25,61.48) ; RPC30.5 115.07,68.97 v2(114.96,68.85)
APU_TEST18: length 46.8
  TOP w0.102: RPH2.4 84.55,81.29 84.67,81.17 v2(85.17,81.17) 86.19,82.19 JHDT1.20
  IN1 w0.127: v2(97.51,78.93) 96.98,79.46 86.89,79.46 v2(85.17,81.17)
  BOTTOM w0.102: UC1.A28 110.81,64.46 110.81,67.96 110.74,68.04 110.74,75.21 110.88,75.35 110.88,78.72 110.88,78.91 110.37,79.42 107.08,79.42 106.51,79.42 105.75,79.42 105.69,79.42 104.29,80.82 99.65,80.82 99.6,80.77 97.76,78.93 v2(97.51,78.93)
APU_TEST19: length 47.4
  TOP w0.102: JHDT1.18 85.76,80.92 v2(85.15,80.3) 84.67,80.79 RPH2.3
  IN1 w0.127: v2(96.95,78.76) 96.5,79.2 86.25,79.2 v2(85.15,80.3)
  BOTTOM w0.102: v2(96.95,78.76) 97.2,78.5 97.66,78.5 99.75,80.59 104.2,80.59 105.77,79.01 v1(106.76,79.01) 107.02,79.01 107.2,79.19 110.28,79.19 110.65,78.82 110.65,75.44 110.51,75.3 110.51,67.87 110.61,67.77 110.61,64.73 110.45,64.57 110.45,64.38 110.81,64.01 UC1.B28
APU_TEST28_H: length 1.2
  TOP w0.102: v2(121.84,57.45) 121.88,57.49 T43.1
  BOTTOM w0.102: v2(121.84,57.45) 121.46,57.84 UC1.N8
APU_TEST28_L: length 1.5
  TOP w0.102: T42.1 120.61,57.93 v2(121.11,57.42)
  BOTTOM w0.102: v2(121.11,57.42) 121.11,57.46 UC1.N10
APU_TEST31: length 1.6
  TOP w0.102: T41.1 108.52,60.72 v2(108.61,60.72)
  BOTTOM w0.102: UC1.H31 109.02,60.31 v2(108.61,60.72)
APU_TEST36: length 4.1
  TOP w0.102: v1(114.05,64.81) 114.05,64.68 113.35,63.99 RC155.1 112.99,63.47 v2(112.99,62.51) 113.17,62.32 RC154.1
  BOTTOM w0.102: UC1.D25 112.78,62.71 v2(112.99,62.51)
APU_TEST41: length 5.1
  TOP w0.102: v1(110.36,64.51) 110,64.86 RC118.1 RC117.1 109.25,66.03 108.74,66.03 v2(108.68,65.97)
  BOTTOM w0.102: UC1.B31 109.16,64.36 108.8,64.72 108.8,65.87 108.69,65.97 v2(108.68,65.97)
APU_TMS: length 55
  TOP w0.102: v2(89.36,71.27) 88.6,72.03 JHDT1.4 85.96,72.03 85.63,71.7 85.22,71.7 84.66,71.14 RPH1.2 83.51,71.14 83.38,71.27 v1(83.38,73.27)
  BOTTOM w0.102: v2(89.36,71.27) 88.92,71.71 88.92,75.46 90.06,76.6 92.95,76.6 97.86,81.5 104.57,81.5 105.97,80.1 106.03,80.1 106.04,80.1 106.22,80.1 106.79,80.1 110.66,80.1 110.79,79.97 111.56,79.2 111.56,78.44 111.56,75.06 111.56,75.06 111.42,74.92 111.42,65.37 111.56,65.23 111.56,65.04 111.67,64.94 111.67,64.68 111.6,64.61 111.6,64.33 111.91,64.01 UC1.B26
APU_TRST#: length 53.7
  TOP w0.102: RPH2.2 v2(84.57,80.29) ; CH2.1 94.3,75.42 RH21.1 94.88,74.69 v2(93.97,74.69)
  IN1 w0.127: v2(84.57,80.29) 85.91,78.95 92.41,78.95 93.97,77.39 v2(93.97,74.69)
  BOTTOM w0.102: v2(93.97,74.69) 97.28,71.39 104.1,71.39 107.08,74.38 v1(107.08,75.08) 107.08,78.57 107.47,78.96 110.18,78.96 110.41,78.73 110.41,75.53 110.28,75.4 110.28,67.75 110.38,67.65 110.38,65.16 110.26,65.04 UC1.A29
APU_TRST#_R: length 6.1
  TOP w0.102: v1(95.14,72.54) 94.95,72.73 RH21.2 94.09,73.86 CH1.1 93.01,74.94 93.01,75.74 92.91,75.84 JHDT1.9
APU_VDD_RUN_FB_L: length 69.8
  TOP w0.102: v1(165.93,71.67) 165.23,70.97 v2(165.23,70.43)
  TOP w0.254: v2(108.41,65.45) RC32.2 ; PR1069.2 164.56,70.38 PR1067.1 v2(165.23,70.43)
  IN1 w0.254: v2(133.18,68.41) 133.12,68.34 125.88,68.34 122.26,64.72 110.1,64.72 109.4,65.42 108.44,65.42 v2(108.41,65.45)
  IN2 w0.254: v2(165.23,70.43) 165.23,70.6 161.21,74.63 143.91,74.63 143.59,74.95 135.15,74.95 133.88,73.68 133.88,69.11 v2(133.18,68.41)
APU_VDD_SEN: length 72
  TOP w0.203: T46.1 109,63.17 v2(108.57,63.17)
  TOP w0.254: v2(133.18,67.77) 133.29,67.77 PR1051.1 ; PR1075.2 166.64,69.13 v1(166.82,69.31) 166.82,69.5 166.57,69.75 v2(165.32,69.75)
  IN1 w0.254: v2(133.18,67.77) 125.94,67.77 122.51,64.34 109.37,64.34 108.56,63.54 108.56,63.18 v2(108.57,63.17)
  IN2 w0.254: v2(133.18,67.77) 133.33,67.92 133.38,67.92 133.66,68.21 133.66,68.26 134.27,68.87 134.27,73.5 135.34,74.57 143.4,74.57 143.75,74.22 160.83,74.22 164.74,70.31 164.74,70.19 165.17,69.75 v2(165.32,69.75)
  BOTTOM w0.254: UC1.D31 109.03,62.71 v2(108.57,63.17)
APU_VDDIO_MEM_S3_FB_H: length 68.9
  TOP w0.127: PR212.2 84.91,99.8 85.24,99.47 v1(85.24,98.7) 85.24,97.81 86.51,96.54 87.44,96.54 88.79,95.19 88.79,91.93 86.98,90.12 v2(86.73,90.12)
  IN1 w0.102: v2(106.47,63.24) 107.53,64.3 107.53,67.33 107.78,67.58 109.43,67.58 111.2,65.82 114.21,65.82 114.45,66.06 114.45,68.09
  IN1 w0.127: v2(86.73,90.12) 86.73,90.12 86.91,89.94 86.94,89.94 87.33,89.55 96.32,89.55 106.61,79.27 109.88,79.27 111.34,77.81 111.34,71.27 114.45,68.15 114.45,68.09
  BOTTOM w0.125: UC1.D35 106.96,62.75 v2(106.47,63.24)
APU_VDDNB_SEN: length 91.9
  TOP w0.102: v2(171.41,52.85) 171.41,52.19 v1(171.98,51.62) ; v2(108.58,62.39) 108.16,62.81 T44.1
  TOP w0.254: v2(133.18,67.14) 133.61,67.14 PR1002.2 ; v2(171.41,52.85) 171.86,53.31 171.86,54.17 172.18,54.49 PR1006.1
  IN1 w0.254: v2(108.58,62.39) 109.24,63.06 109.24,63.45 109.75,63.96 122.83,63.96 126,67.14 v2(133.18,67.14)
  IN2 w0.254: v2(171.41,52.85) 171.41,56.66 169.76,58.31 169.76,61.28 168,63.04 167.38,63.04 165.63,64.79 165.63,68.41 164.36,69.68 164.36,70.12 160.68,73.81 143.59,73.81 143.21,74.19 135.53,74.19 134.7,73.36 134.7,68.61 133.38,67.29 133.33,67.29 v2(133.18,67.14)
  BOTTOM w0.125: v2(108.58,62.39) 108.09,61.91 UC1.E33
APU_VDDP_RUN_FB_H: length 66
  TOP w0.102: v2(119.02,38.82) 119.02,38.94 v1(118.7,39.26)
  TOP w0.254: PR310.2 161.51,27.37 161.56,27.32 v2(161.57,27.32)
  IN1 w0.254: v2(161.57,27.32) 161.57,27.42 161.26,27.73 159.97,27.73 159.45,28.25 157.35,28.25 156,26.9 141.9,26.9 140.74,25.74 138.46,25.74 135.78,28.41 135.78,32.25 135.78,33.04 134.83,33.99 133.18,33.99 132.04,35.13 132.01,35.13 131.99,35.15 122.78,35.15 119.5,38.43 119.5,38.45 119.13,38.82 v2(119.02,38.82)
  IN2 w0.254: v2(114.13,47.26) 113.62,46.75 113.62,42.75 115.27,41.1 115.27,40.72 115.78,40.21 117.62,40.21 v2(119.02,38.82)
  BOTTOM w0.254: v2(114.13,47.26) 114.41,47.26 UC1.AM21
APU_VDDP_RUN_FB_L: length 65.8
  TOP w0.102: PR311.2 160.7,26.42 161.3,26.42 v1(161.56,26.69)
  TOP w0.254: RC23.2 113.05,46.68 v2(113.05,46.44) ; PR311.2 v2(160.99,27.25)
  IN1 w0.254: v2(160.99,27.25) 159.8,27.25 159.18,27.87 157.51,27.87 156.16,26.51 142.05,26.51 140.89,25.35 138.3,25.35 135.4,28.25 135.4,32.4 135,32.8 133.83,32.8 131.88,34.75 131.85,34.75 131.83,34.77 122.62,34.77 119.16,38.23 v2(119.02,38.23)
  IN2 w0.254: v2(113.05,46.44) 113.25,46.24 113.25,42.62 114.89,40.98 114.89,40.59 115.78,39.71 117.43,39.71 118.9,38.23 v2(119.02,38.23)
APU_VSS_SENSE_A: length 5.4
  TOP w0.102: v1(105.76,63.65) 106.07,63.95 RC29.1
  TOP w0.254: v2(107.57,62.4) 107.44,62.4 107.02,62.82 107.02,63.51 RC29.1 RC32.1
  BOTTOM w0.254: v2(107.57,62.4) 107.88,62.71 UC1.D33
APU_VSS_SENSE_B: length 2.8
  TOP w0.102: v1(114.51,48.53) 114,48.53 113.51,48.04 RC23.1
  TOP w0.254: v2(112.86,48.02) 112.88,48.04 RC23.1
  BOTTOM w0.254: v2(112.86,48.02) 112.86,48.02 112.86,48.02 113.05,48.02 UC1.AM23
ASGATE: length 122.6
  TOP w0.203: v2(214.25,39.53) 214.26,39.53 214.26,39.54 214.06,39.74 PU703.30
  IN1 w0.508: v2(214.25,39.53) 214.25,39.53 214.25,40.56 212.62,42.19 211.39,42.19 210.46,41.27 208.06,41.27 206.94,42.39 204.53,42.39 204.03,42.89 199.51,42.89 197,45.4 193.54,45.4 191.55,47.39 189.25,47.39 187.94,48.7 185.76,48.7 185.03,49.42 185.03,50.44 182.2,53.28 181.99,53.28 174.57,60.7 174.57,61.78 173.71,62.64 173.71,62.99 171.2,65.5 170.08,65.5 168.74,66.84 168.74,67.23 167.37,68.61 167.37,71.22 163.06,75.53 163.06,85 164.35,86.28 164.35,89.72 162.76,91.31 162.76,92.48 161.13,94.11 161.13,94.36 159.54,95.94 159.54,96.95 158.68,97.82 158.68,101.98 160.28,103.58 160.28,109.28 158.96,110.6 158.96,115.11 159.93,116.07 159.93,118.57 v2(161.14,119.79)
  BOTTOM w0.102: v2(214.25,39.53) 214.26,39.53 214.28,39.51 214.9,39.51 v1(214.97,39.58)
  BOTTOM w0.508: v2(161.14,119.79) 160.85,120.08 PR762.2
AUD_HP1_JACK_L1: length 4.4
  TOP w0.102: RA27.2 v1(23.9,12.21)
  TOP w0.305: RA29.2 RA28.2 RA27.2 23.81,13.36 LA8.1
AUD_HP1_JACK_R1: length 4.6
  TOP w0.102: RA33.2 25.93,18.81 v1(26.06,18.94)
  TOP w0.305: LA9.1 23.81,17.66 RA31.2 RA32.2 RA33.2
AUD_PORTA_L_R_B: length 11.5
  TOP w0.305: LA8.2 22.54,14.19 RA30.1 CA35.1 20.45,14.05 19.25,14.05 DA4.2 17.72,12.53 16.47,12.53 16.4,12.59 v1(14.63,12.59) 11.89,12.59
AUD_PORTA_R_R_B: length 26.5
  TOP w0.305: LA9.2 22.12,16.75 22.04,16.83 RA34.1 CA34.1 20.1,16.83 DA4.3 14.43,15.97 v1(14.43,18.05) 14.43,23.2 13.29,24.34 6.18,24.34
AUD_SENSE_A: length 6.2
  TOP w0.102: v1(21.36,32.62) 21.6,32.38 RA10.1
  TOP w0.203: UA1.13 24.36,29.4
  TOP w0.254: RA10.1 22.58,32.19 RA41.1 CA40.1 23.17,29.4 24.36,29.4
BA: length 90.4
  TOP w0.254: PD704.3 196.41,44.85 193.63,44.85 193.25,45.23 v1(190.27,45.23) 189.76,45.23 v2(188.55,44.02) ; PQ710.1 220.42,20.8 PR780.1 219.29,19.58 v2(219.29,19.58)
  IN1 w0.254: v2(219.29,19.58) 216.87,17.16 203.05,17.16 202,18.22 194.67,18.22 193.63,19.26 190.46,19.26 188.04,21.67 188.04,23.58 192.11,27.64 195.73,27.64 196.58,28.5 198.49,28.5 198.9,28.91 198.9,31.53 197.9,32.53 187.83,32.53 187.79,32.49 187.28,32.49 186.93,32.85 186.93,33.77 186.65,34.05 186.65,34.05 186.54,34.16 186.54,38.33 186.9,38.69 186.9,42.88 188.04,44.02 v2(188.55,44.02)
BATT_CHG_LED: length 8.5
  TOP w0.102: v2(152.71,10.86) 151.95,10.86 Q6102.1 151.26,11.55 148.64,11.55 147.8,12.39 v1(147.8,13.15)
  BOTTOM w0.102: v2(152.71,10.86) 152.09,10.86 151.7,11.26 151.7,12.27 JLED1.3
BATT_CHG_LED#: length 53.3
  TOP w0.102: v2(152.47,4.09) 152.04,4.52 Q2.4
  IN1 w0.102: v2(152.47,4.09) 154.93,6.54 168.15,6.54 173.19,11.59 179.69,11.59 179.89,11.59 182.29,13.99 182.29,20.72 181.63,21.38 181.63,26.13 182.52,27.02 182.52,28.09 v2(182.9,28.47)
  BOTTOM w0.102: v1(183.6,27.17) 183.44,27.33 183.44,27.97 182.94,28.47 v2(182.9,28.47) 182.54,28.82 UE1.21
BATT_CHG_LED_R#: length 15.7
  TOP w0.102: v1(147.12,10.84) 149.9,10.84 150.88,9.86 Q6102.2 149.64,7.64 v2(149.63,7.64) 149.63,5.16 149.83,4.96 Q2.3 ; v2(153.99,6.53) Q5.1
  BOTTOM w0.102: v2(149.63,7.64) 150.03,7.23 153.29,7.23 v2(153.99,6.53)
BATT_I: length 80.9
  TOP w0.102: v2(185.95,47.52) 185.95,48.09 v1(186.01,48.15)
  TOP w0.254: PR775.1 218.02,45.77 v2(217.95,45.84)
  IN1 w0.127: v2(217.95,45.84) 217.95,40.85 217.13,40.02 217.13,38.86 216.51,38.25 216.38,38.25 216.17,38.03 213.47,38.03 212.47,39.03 212.47,39.86 211.69,40.63 211.17,40.63 210.98,40.44 207.72,40.44 206.78,41.38 199.84,41.38 196.72,44.51 191.72,44.51 189.89,46.35 189.12,46.35 187.6,47.87 186.3,47.87 v2(185.95,47.52)
  IN2 w0.127: v2(171.19,31.44) 171.16,31.47 171.16,31.65 171.91,32.4 171.91,34.14 172.19,34.41 172.91,34.41 174.96,36.47 179.09,36.47 179.41,36.78 179.41,37.5 184.3,42.39 184.3,43.71 184.81,44.21 184.81,45.61 185.88,46.69 185.88,47.45 v2(185.95,47.52)
  BOTTOM w0.102: v2(171.19,31.44) 171.15,31.4 171.15,28.47 171.41,28.21 171.41,27.58 171.03,27.2 170.39,27.2 170.37,27.22 170.3,27.22 169.09,28.42 UE1.75
  BOTTOM w0.254: v2(217.95,45.84) 218,45.89 PC749.2
BATT_LOW_LED: length 6.4
  TOP w0.102: v2(153.35,10.88) 153.35,11.94 v1(153.55,12.15) 153.59,12.18 155.61,12.18 155.91,11.88 Q3.1
  BOTTOM w0.102: v2(153.35,10.88) 152.7,11.52 JLED1.2
BATT_LOW_LED#: length 84
  TOP w0.102: v2(150.14,6.81) Q2.1
  IN1 w0.102: v2(150.14,6.81) 150.14,4.97 151.43,3.68 153.09,3.68 155.72,6.31 168.05,6.31 168.3,6.31 173.35,11.36 179.59,11.36 179.59,11.36 179.98,11.36 182.52,13.89 182.52,20.83 181.88,21.47 181.88,25.48 183.46,27.05 183.46,28.48 183.07,28.87 183.06,28.87 182.87,29.06 182.87,29.06 182.23,29.7 182.23,34.23 180.73,35.73 178.99,35.73 177.52,35.73 176.89,35.1 176.89,34.7 175.48,33.29 174.45,33.29 173.35,34.4 172.19,34.4 172.01,34.22 171.44,34.22 170.92,34.22 v2(170.58,34.56)
  BOTTOM w0.102: v1(163.39,36.26) 163.92,36.26 164.56,35.63 UE1.93 167.04,35.63 167.17,35.49 167.53,35.49 169.18,33.84 169.86,33.84 v2(170.58,34.56)
BATT_LOW_LED_R#: length 4.7
  TOP w0.102: Q3.2 154.95,8.23 154.21,7.5 153.17,7.5 v1(152.74,7.07) 152.61,6.94 152.61,6.37 152.5,6.26 Q2.6
BATT_TEMP: length 212
  TOP w0.254: PR764.1 215.21,48.15 PC753.2 215.21,49.24 v2(214.65,49.8) ; v2(220.29,14.55) PR16.1 PR15.2 218.46,13.43 PD3.2 218.46,13.41 218.46,11.39 217.85,10.77 v1(203.16,10.77) 201.16,10.77 v2(200.68,11.26) ; v2(160.77,98.07) 160.3,97.6 PC14.1
  IN1 w0.254: v2(160.77,98.07) 161.11,98.07 163.72,95.46 163.72,94.73 164.1,94.35 164.1,94.34 164.4,94.05 164.4,94.05 166.2,92.25 166.2,75.88 170.45,71.63 170.45,69.48 173.65,66.28 173.65,66.28 174.13,65.8 174.32,65.62 176.61,63.32 176.61,63.2 177.82,61.99 177.82,61.99 179.08,60.74 179.08,60.12 180.78,58.42 180.78,58.27 182.24,56.81 182.24,56.58 186.44,52.38 188.57,52.38 190.39,50.56 193.1,50.56 194.03,49.64 194.03,49.1 194.44,48.68 197.28,48.68 197.71,49.12 201.29,49.12 205.4,45 206.89,45 207.44,45.12 207.72,45.23 208.67,45.23 211.97,48.54 214.25,48.54 214.9,49.19 214.9,49.55 v2(214.65,49.8) 213.89,49.04 212.17,49.04 211.92,49.29 211.92,49.85 212.57,50.5 213.14,50.5 214.34,51.71 215.35,51.71 215.93,52.28 221.24,52.28 224.3,49.22 224.3,18.56 v2(220.29,14.55)
  IN2 w0.254: v2(172.67,20.11) 172.68,20.11 172.68,20.08 175.39,20.08 175.4,20.08 175.8,20.08 175.81,20.08 175.92,20.08 176.01,20.17 181.5,20.17 181.75,19.92 188.21,19.92 190.67,17.46 192.51,17.46 198.71,11.26 v2(200.68,11.26)
  BOTTOM w0.203: v2(172.67,20.11) 172.68,20.11 172.68,20.08 168.38,20.08 CE43.2 167.91,21.16 168.02,21.26 UE1.63
  BOTTOM w0.254: PC753.2 215.21,49.24 v2(214.65,49.8)
BEEP#: length 202.5
  TOP w0.102: v1(179.06,26.95) 179.45,27.33 180.19,27.33 v2(180.22,27.3) ; v2(18.96,32.97) 18.26,32.28 DA3.2
  IN1 w0.127: v2(18.96,32.97) 19.54,33.56 20.67,33.56 24.06,36.95 26.27,36.95 28.98,34.24 31.01,34.24 33.48,31.77 35.2,31.77 40.03,26.94 40.03,18.01 46.65,11.38 69.3,11.38 69.99,12.08 71.2,13.29 83.09,13.29 83.79,13.99 84.53,13.99 84.53,13.99 90.07,13.99 91.07,13.99 91.07,13.99 91.14,13.99 92.03,13.1 99.82,13.1 100.35,12.57 101.22,12.57 105.21,12.57 107.54,12.57 107.84,12.27 109.75,12.27 111.02,11 121.37,11 122.38,12.02 123.85,12.02 124.67,12.85 125.56,12.85 129.37,16.66 140.77,16.66 142.71,18.59 152.87,18.59 155.89,18.59 156.45,18.59 156.74,18.88 159.87,18.88 161.33,20.34 162.26,20.34 165.97,24.05 165.97,25.75 167.83,27.61 167.83,32.11 169.14,33.42 169.9,33.42 171.11,32.21 173.6,32.21 173.99,31.81 174.15,31.81 174.62,31.35 175.22,30.75 178.26,30.75 179.35,29.67 179.35,29.63 179.72,29.26 179.72,27.8 v2(180.22,27.3)
  BOTTOM w0.102: v2(180.22,27.3) 180.22,27.5 180.74,28.02 UE1.23
BKOFF#: length 94
  TOP w0.102: DX1.2 221.25,39.39 v2(222.46,40.59) ; v2(174.34,30.67) 174.35,30.67 174.35,30.68 174.33,30.68 174.33,30.69 173.88,30.24 172.3,30.24 171.91,30.63 171.91,33.42 171.79,33.55 v1(171.79,33.86) 171.79,34.94 v2(171.91,35.07)
  IN1 w0.127: v2(174.34,30.67) 174.34,28.16 175.05,27.45 176.73,27.45 178.06,26.12 178.06,24.25 180.31,22 v2(180.31,21.1) ; v2(222.46,40.59) 222.91,40.15 222.91,36.91 222.59,36.59 222.27,36.59 221.64,35.96 221.64,34.09 223.07,32.66 223.07,25.51 219.59,22.03 219.59,20.47 216.72,17.61 203.41,17.61 201.25,19.77 192.11,19.77 189,22.88 v2(189,23.64)
  BOTTOM w0.102: UE1.105 170.82,36.1 171.85,35.07 v2(171.91,35.07) ; v2(189,23.64) 183.74,23.64 183.06,22.95 181.69,22.95 180.31,21.58 v2(180.31,21.1)
BP_0: length 3.5
  BOTTOM w0.102: UV1.U1 112.2,101.2 112.2,99.65 111.79,99.24 111.79,98.27 RV82.1
BP_1: length 4.7
  BOTTOM w0.102: UV1.U3 112.5,102.05 111.53,101.07 111.53,98.96 RV81.1
BST1_APU: length 0.6
  BOTTOM w0.102: v2(163.01,62.6) v1(163.01,63.21)
BST1_VGA:
  vias: v1(57.24,120.36)
BST2_VGA:
  vias: v1(57.24,125.9)
BST_1.2V: length 1.1
  BOTTOM w0.102: PR200.2 87.97,106.77 v1(88.17,106.57)
BST_1.2V_R: length 1.1
  BOTTOM w0.102: PC200.1 83.92,106.97 v1(83.78,106.83)
BST_+1.35VGPU: length 0.5
  TOP w0.102: v2(154.99,90.52) v1(154.99,91.03)
BST_+1.35VGPU_R: length 1.5
  BOTTOM w0.102: v1(155.21,94.32) 155.21,93.17 PR1402.2
BST_NB: length 1.6
  TOP w0.102: v1(162.52,56.03) 162.9,56.41 PR1008.1
BST_VDDP_ALWP:
  vias: v1(158.14,34.75)
BT_ON#: length 219.4
  TOP w0.102: RC45.2 112.75,24.91 v1(112.75,27.45) 112.75,29.5 112.4,29.84 v2(112.4,30.53)
  IN1 w0.127: v2(56.1,108.83) 56.36,108.57 56.36,107.93 57.2,107.09 57.2,104.18 59.1,102.27 59.1,98.15 57.76,96.82 57.76,94.21 56,92.45 41.19,92.45 37.73,88.99 37.73,83.51 35.73,81.51 35.73,44.65 44.58,35.8 44.58,25.44 53.05,16.97 58.57,16.97 59.33,17.73 62,17.73 62.44,17.29 72.49,17.29 76.84,21.63 97.39,21.63 100.79,25.04 102.8,25.04 105.17,27.41 107.09,27.41 108.8,29.12 108.8,31.06 108.29,31.57 108.29,33.61 108.53,33.85 108.53,38.51 108.58,38.56 108.58,43.71 v2(108.77,43.9)
  IN2 w0.102: v2(108.77,43.9) 108.91,43.9 110.64,42.17 110.64,38.88
  IN2 w0.127: 110.64,38.88 110.64,38.16 109.56,37.08 109.56,34.52 110.3,33.78 110.3,32.95 112.4,30.84 v2(112.4,30.53)
  BOTTOM w0.102: UC1.AV33 108.36,44.31 v2(108.77,43.9) ; v2(56.1,108.83) 56.3,108.63 JWLAN1.46
CAM_DETECT#: length 155.8
  TOP w0.102: v1(218.93,33.11) 218.61,32.8 v2(217.7,32.8)
  IN1 w0.127: v2(112.61,36.47) 112.61,36.72 112.25,37.08 112.06,37.08 111.73,37.41 111.73,37.79 112.54,38.6 113.65,38.6 114.6,37.65 116.17,37.65 117.85,39.32 119.16,39.32 123.02,35.47 132.76,35.47 133.79,34.44 135.04,34.44 136.1,33.37 136.1,32.11 136.1,28.54 138.59,26.05 140.6,26.05 141.77,27.22 155.88,27.22 157.22,28.57 159.19,28.57 159.62,29 161.14,29 161.53,29.38 161.53,31.48 164.02,33.97 164.02,34.69 164.31,34.98 164.66,34.98 165.33,34.31 168.48,34.31 168.86,34.69 169.69,34.69 169.91,34.47 169.91,34.28 170.62,33.57 173.19,33.57 v2(174.27,32.49)
  IN2 w0.127: v2(217.7,32.8) 216.54,31.64 216.54,25.55 216.54,25.55 216.54,25.21 215.31,23.98 201.1,23.98 199.71,25.37 199.71,30.89 197.94,32.67 185.61,32.67 185.49,32.8 179.65,32.8 177.71,30.85 177.03,30.85 176.98,30.8 175.29,30.8 174.27,31.82 v2(174.27,32.49)
  BOTTOM w0.102: v2(217.7,32.8) 217.87,32.97 221,32.97 221.01,32.98 221.68,32.98 222.25,33.55 JEDP1.34 ; v2(112.61,36.47) 112.55,36.52 112.55,37.78 112.32,38.02 112.24,38.02 112.24,38.09 112.17,38.16 112.17,39.25 112.17,39.46 112.17,39.47 112.17,42 112.15,42.02 112.15,42.34 112.23,42.42 112.23,42.69 112.05,42.86 112.05,43.12 UC1.AY26
CAP_LED: length 2.4
  TOP w0.102: R27.2 v2(85.36,10.05) 85.36,10.37 v1(85.62,10.62)
  BOTTOM w0.102: v2(85.36,10.05) 85.4,10.01 JKB1.4
CAP_LED_Q: length 3.5
  TOP w0.102: Q7.1 R27.1 86.49,8.2 v1(86.51,8.21)
CAP_LED_R#: length 7.8
  TOP w0.102: Q7.2 85.26,4.67 85.68,4.67 87.1,6.09 v1(88.29,6.09) Q6.1
CAPS_LED: length 98.1
  TOP w0.102: v1(89.68,10.56) v2(89.68,9.92) R28.2 90.24,9.42 Q6.3 88.69,8.17 R36.1
  IN1 w0.127: v2(164.49,34.56) 164.28,34.35 164.28,33.87 161.78,31.37 161.78,29.07 162.55,28.31 162.55,27.71 161.59,26.75 159.84,26.75 159.04,27.55 157.64,27.55 156.29,26.2 142.19,26.2 140.95,24.96 136.19,24.96 135.16,25.99 133.88,25.99 v2(133.43,26.43)
  IN2 w0.127: v2(133.43,26.43) 133.31,26.31 133.31,25.48 130.26,22.43 128.74,22.43 124.55,18.25 124.36,18.25 124.04,17.93 116.06,17.93 115.36,17.23 115.35,17.23 115.28,17.16 113.96,17.16 113.05,16.25 113.05,16.04 113.05,15.94 110.47,13.35 107.72,13.35 106.26,11.89 97.05,11.89 96.48,11.32 96.48,11.13 96.1,10.75 90.51,10.75 v2(89.68,9.92)
  BOTTOM w0.102: UE1.91 164.75,34.82 v2(164.49,34.56)
CCLIM: length 4.5
  TOP w0.203: v2(214.4,45.61) 214.06,45.27 PU703.11
  BOTTOM w0.102: PR750.1 213.24,46.31 v1(212.72,45.79)
  BOTTOM w0.254: PR750.1 214.4,46.23 v2(214.4,45.61) 214.22,45.43 PR752.2
CLK_PCIE_LAN: length 160.8
  IN2 w0.127: v2(30.31,118.87) 30.45,119.02 31.01,119.02 31.33,118.7 31.33,116.48 31.9,115.91 37.61,115.91 39.2,114.32 42.82,114.32 45.6,111.53 45.6,110.18 45.6,109.66 45.6,109.44 45.6,109.44 45.6,109.02 45.89,108.73 46.38,108.25 46.38,107.61 47.94,106.04 47.94,99.13 v2(47.82,99.01)
  BOTTOM w0.102: v2(30.31,118.87) UL1.15 ; v2(47.82,99.01) 48.03,98.8 48.03,98.26 48.83,97.45 60.14,97.45 61.69,95.9 73.08,95.9 73.5,96.32 78.75,96.32 79.63,95.45 82.23,95.45 84.58,93.1 85.91,93.1 86.66,92.35 86.66,91.11 88.35,89.43 104.99,89.43 105.37,89.05 107.16,89.05 107.16,89.04 108,89.04 110.43,89.04 110.71,88.77 110.71,88.76 112.23,87.24 112.4,87.24 114.06,87.24 114.06,87.23 114.15,87.23 115.78,85.61 118.92,85.61 121.15,85.61 121.16,85.6 121.17,85.6 121.62,85.15 128.14,85.15 134.32,78.97 134.32,65.84 134.86,65.3 134.86,65.3 135.21,64.94 135.22,64.94 135.43,64.72 135.43,60.36 133.78,58.71 126.09,58.71 126.07,58.69 125.85,58.69 125.83,58.71 125.79,58.71 125.74,58.76 125.44,58.76 125.36,58.68 125.13,58.68 UC1.M2
CLK_PCIE_LAN#: length 160.9
  IN2 w0.127: v2(48.4,99.01) 48.21,99.21 48.21,106.15 46.64,107.72 46.64,108.35 45.87,109.13 45.87,111.64 42.93,114.58 39.31,114.58 37.72,116.17 32.01,116.17 31.59,116.59 31.59,118.81 31.12,119.28 30.5,119.28 30.31,119.46 v2(30.31,119.46)
  BOTTOM w0.102: UL1.16 30.5,119.27 v2(30.31,119.46) ; v2(48.4,99.01) 48.23,98.84 48.23,98.34 48.92,97.66 60.23,97.66 61.78,96.11 72.99,96.11 73.41,96.53 78.84,96.53 79.71,95.65 82.32,95.65 84.67,93.3 86,93.3 86.86,92.44 86.86,91.2 88.43,89.63 105.07,89.63 105.45,89.25 107.25,89.25 107.92,89.25 107.92,89.25 108.49,89.25 110.52,89.25 110.91,88.85 110.91,88.84 112.31,87.44 114.14,87.44 114.15,87.44 114.24,87.44 115.86,85.81 118.84,85.81 118.84,85.81 121.23,85.81 121.24,85.81 121.25,85.81 121.7,85.36 128.22,85.36 134.52,79.06 134.52,65.92 135.06,65.38 135.06,65.38 135.3,65.14 135.3,65.14 135.64,64.81 135.64,60.28 133.86,58.51 126.18,58.51 126.16,58.49 125.76,58.49 125.75,58.5 125.65,58.5 UC1.M1
CLK_PCIE_WLAN: length 120.5
  IN2 w0.127: v2(59.47,96.95) 59.58,97.06 59.58,97.39 59.38,97.59 55.11,97.59 54.58,98.12 54.58,98.94 v2(54.5,99.02)
  BOTTOM w0.102: v2(59.47,96.95) 59.59,96.82 59.59,96.03 60.43,95.19 73.64,95.19 74.13,95.69 78.37,95.69 79.31,94.75 81.98,94.75 84.26,92.46 84.48,92.46 84.65,92.46 84.65,92.46 85.41,92.46 85.64,92.22 85.64,90.34 87.21,88.78 104.62,88.78 105.06,88.35 110.16,88.35 111.9,86.61 111.97,86.61 111.97,86.61 112.66,86.61 113.79,86.61 113.8,86.6 113.8,86.6 115.43,84.97 115.52,84.97 120.87,84.97 121.33,84.52 127.86,84.52 133.56,78.81 133.56,69.62 133.67,69.51 133.67,65.53 134.8,64.41 134.8,60.63 133.64,59.47 125.95,59.47 125.73,59.24 125.5,59.24 UC1.L2 ; JWLAN1.39 54.55,99.45 54.66,99.34 54.66,99.18 v2(54.5,99.02)
CLK_PCIE_WLAN#: length 120.4
  IN2 w0.127: v2(60.05,96.95) 60.02,96.95 59.85,97.12 59.85,97.49 59.49,97.85 55.22,97.85 54.84,98.23 54.84,98.78 v2(55.08,99.02)
  BOTTOM w0.102: v2(55.08,99.02) 54.86,99.24 54.86,99.32 55.05,99.51 JWLAN1.41 ; UC1.L1 125.95,59.02 125.95,59.16 126.05,59.27 133.73,59.27 135,60.54 135,64.49 133.88,65.61 133.88,69.59 133.76,69.71 133.76,78.9 127.94,84.72 121.44,84.72 120.98,85.18 115.96,85.18 115.51,85.18 113.89,86.8 113.88,86.8 113.88,86.81 112.58,86.81 111.98,86.81 110.24,88.55 105.14,88.55 104.71,88.98 87.29,88.98 85.85,90.43 85.85,92.31 85.49,92.66 84.35,92.66 82.06,94.95 79.4,94.95 78.46,95.89 74.05,95.89 73.55,95.4 60.51,95.4 59.79,96.11 59.79,96.71 60.04,96.95 v2(60.05,96.95)
CLK_PEG_VGA: length 86.5
  IN2 w0.127: v2(101.63,123.78) 101.5,123.91 100.92,123.91 100.73,123.72 100.73,122.76 101.31,122.18 101.31,118.52 97.75,114.95 97.75,109.37 98.95,108.16 98.95,103.02 102.24,99.72 103.42,99.72 103.42,99.72 103.7,99.72 109.86,93.56 111.19,93.56 113.36,91.39 114.64,91.39 117.24,88.79 117.94,88.79 119.35,87.38 119.35,85.47 119.54,85.28 119.54,76.63 127.66,68.51 127.66,61.37 v2(127.78,61.24)
  BOTTOM w0.102: UV1.AK30 102.51,122.69 102.51,123.59 102.26,123.84 101.69,123.84 v2(101.63,123.78) ; v2(127.78,61.24) 127.64,61.1 127.64,60.78 127.42,60.56 125.98,60.56 125.78,60.36 125.48,60.36 125.18,60.66 UC1.H2
CLK_PEG_VGA#: length 86.5
  IN2 w0.127: v2(101.66,124.6) 101.66,124.36 101.51,124.2 100.84,124.2 100.47,123.83 100.47,122.65 100.81,122.31 101.05,122.07 101.05,118.63 97.48,115.06 97.48,114.52 97.48,109.78 97.48,109.26 97.64,109.1 97.64,109.1 98.69,108.05 98.69,102.91 98.84,102.75 102.14,99.46 103.59,99.46 109.75,93.3 111.08,93.3 113.25,91.13 114.53,91.13 117.13,88.53 117.83,88.53 119.08,87.27 119.08,85.36 119.27,85.17 119.27,76.52 127.39,68.4 127.39,61.42 127.21,61.24 v2(127.2,61.24)
  BOTTOM w0.089: 101.62,124.6 v2(101.66,124.6)
  BOTTOM w0.102: v2(127.2,61.24) 127.27,61.24 127.44,61.08 127.44,60.86 127.34,60.76 125.89,60.76 125.77,60.64 125.63,60.64 UC1.H1 ; UV1.AK32 102.81,123.1 102.71,123.2 102.71,123.67 102.34,124.05 101.9,124.05 101.79,124.16 101.53,124.16 101.39,124.31 101.39,124.5 101.49,124.6 101.62,124.6
CLK_SMB: length 3.4
  TOP w0.102: PR18.1 214.57,15.89 214.57,16.03 v2(214.4,16.21) v1(213.89,16.72)
  BOTTOM w0.102: v2(214.4,16.21) 214.27,16.34 214.08,16.34 213.89,16.52 PBATT1.7
CMSRC: length 115.4
  TOP w0.203: PU703.29 213.66,39.19 v2(213.72,39.12)
  IN1 w0.508: v2(162.41,108.34) 161.42,108.34 160.92,107.83 160.92,103.32 159.32,101.72 159.32,98.08 160.18,97.21 160.18,96.2 161.94,94.44 162.59,94.44 163.39,93.64 163.39,91.57 165.06,89.91 165.06,89.1 165.06,86.09 163.7,84.73 163.7,75.79 168,71.48 168,69.18 170.21,66.97 170.63,66.97 174.35,63.25 174.35,62.9 175.2,62.05 175.2,60.97 182.25,53.92 182.46,53.92 185.64,50.73 187.66,50.73 190.37,48.02 192.32,48.02 193.31,47.03 196.26,47.03 199.77,43.52 204.3,43.52 204.46,43.35 209.34,43.35 209.61,43.08 210.84,43.08 211.32,43.56 211.32,43.73 211.83,44.24 215,44.24 215.46,43.78 215.46,39.4 214.95,38.89 213.95,38.89 v2(213.72,39.12)
  BOTTOM w0.102: v2(213.72,39.12) 213.58,39.26 v1(213.13,39.26)
  BOTTOM w0.508: PR763.2 v2(162.41,108.34)
COMP: length 4.8
  TOP w0.203: PU703.10 214.46,45.02 215.09,45.66
  TOP w0.254: PC751.2 PR754.2 216.94,47.14 215.92,46.12 v1(215.89,46.12) 215.55,46.12 215.09,45.66
CORE_NB_GATE: length 19.6
  TOP w0.254: Q135.2 129.83,7.59 129.75,7.51 128.68,7.51 128.62,7.57 v2(128.48,7.57) v1(127.34,7.57) 125.75,7.57 125.58,7.41 Q2513.2
  BOTTOM w0.254: v2(128.48,7.57) 128.67,7.57 128.7,7.54 128.76,7.54 129.08,7.23 129.08,6.75 128.83,6.5 U2.1 125.94,6.5 124.22,4.78 124.22,3.92 123.69,3.38 121.5,3.38 121.13,3.75 R56.1 121.25,3.96 122.66,3.96
CORETYPE: length 14.4
  TOP w0.102: v2(131.67,65.81) v1(132.29,66.44) 132.55,66.69 133.67,66.69 RC654.2
  IN1 w0.102: 129.31,65.81 125.82,65.81 123.4,63.39 121.94,63.39 v2(121.75,63.2)
  IN1 w0.127: v2(131.67,65.81) 129.31,65.81
  BOTTOM w0.102: v2(121.75,63.2) 121.26,62.71 UC1.D9
CPU_DPB_CTRLCLK_R: length 19
  TOP w0.102: RPI3.4 22.33,94.14 22.28,94.19 22.14,94.19 v2(21.87,93.93) ; v2(20.44,91.76) 20.5,91.7 20.75,91.7 21.13,91.33 v1(21.23,91.33) 21.47,91.57 QI2.6
  IN1 w0.127: v2(21.87,93.93) 21.87,93.93 21.74,93.8 21.74,93.56 21.99,93.31 21.99,92.41 21.59,92.01 20.69,92.01 v2(20.44,91.76)
  BOTTOM w0.102: JHDMI1.15 11.21,90.26 11.2,90.26 11.2,91.65 11.87,92.32 15.84,92.32 17,91.17 19.85,91.17 v2(20.44,91.76)
CPU_DPB_CTRLDAT_R: length 21.9
  TOP w0.102: RPI3.3 22.35,94.64 22.15,94.44 21.95,94.44 v2(21.87,94.51) ; v2(21.27,92.79) 21.27,93.19 21.43,93.36 23.6,93.36 QI2.3
  IN1 w0.127: v2(21.27,92.79) 21.13,92.78 21.01,92.63 20.96,92.58 20.96,92.41 21.1,92.27 21.48,92.27 21.73,92.52 21.73,93.2 21.45,93.48 21.45,94.23 21.74,94.51 v2(21.87,94.51)
  BOTTOM w0.102: v2(21.27,92.79) 21.1,92.63 21.1,91.76 20.3,90.96 16.91,90.96 15.76,92.12 11.96,92.12 11.4,91.56 11.4,90.35 11.75,90 JHDMI1.16
CS_1.2V: length 3.9
  BOTTOM w0.102: PR205.2 83.28,104.3 v1(83.9,104.92)
  BOTTOM w0.203: PR205.2 83.66,103.52 84.22,103.52 84.6,103.15 PU200.13
DAT_SMB: length 3.8
  TOP w0.102: PR20.1 214.9,15.72 214.9,16.08 v2(215.03,16.21) 215.09,16.21 v1(215.67,16.78)
  BOTTOM w0.102: PBATT1.6 215.89,16.63 215.6,16.34 215.16,16.34 v2(215.03,16.21)
DBC_EN: length 80.9
  TOP w0.102: v1(167.79,33.99) 168.03,33.75 v2(168.03,33.4)
  IN1 w0.127: v2(220.23,49.22) 220.63,48.83 220.63,39.04 220.17,38.59 219.25,38.59 217.27,36.61 215.95,36.61 215.62,36.94 214.4,36.94 214.11,36.64 213.08,36.64 210.71,39.01 210.71,39.32 210.36,39.68 207.4,39.68 206.46,40.62 199.53,40.62 198.85,41.29 194.94,41.29 194.7,41.29 192.63,43.36 191.46,43.36 189.73,45.1 188.95,45.1 187.13,46.93 v2(185.39,46.93)
  IN2 w0.127: v2(168.03,33.4) 170.82,33.4 172.08,34.66 172.8,34.66 174.86,36.72 175.41,36.72 175.41,36.72 178.96,36.72 179.15,36.91 179.15,37.61 181.06,39.52 181.06,40.85 184.42,44.21 184.42,45.96 v2(185.39,46.93)
  BOTTOM w0.102: R6.2 220.8,48.66 v2(220.23,49.22) ; UE1.89 167.41,34.02 v2(168.03,33.4)
DBC_EN_R: length 7.4
  BOTTOM w0.102: R5.1 220.01,48.02 220.52,47.52 221.52,47.52 221.71,47.71 R6.1 222.46,48.02 222.78,47.71 v1(222.78,47.33) 222.78,46.69 222.46,46.37 222.46,45.93 222.84,45.55 JEDP1.10
DDRA_CKE0: length 62.5
  IN1 w0.102: 100.1,67.36 100.53,67.36 100.79,67.1 100.79,66.24 100.91,66.13 101.85,65.19 101.85,64.63 101.92,64.55 101.92,63.66 105.06,60.53 v2(105.85,60.53)
  IN1 w0.211: v2(67.49,61.96) 66.05,61.96 65.68,62.33 65.68,63.38 65.89,63.59 73.35,63.59 74.16,64.41 74.73,64.41 74.94,64.62 74.94,65.12 75.15,65.33 75.82,65.33 76.08,65.59 76.08,65.89 75.98,65.98 75.98,66.28 76.28,66.58 76.58,66.58 76.63,66.53 76.93,66.53 77.17,66.77 77.17,67.13 77.4,67.36 77.8,67.36 78.01,67.15 78.01,66.77 78.22,66.56 78.64,66.56 78.85,66.77 78.85,67.13 79.09,67.36 79.49,67.36 79.7,67.15 79.7,66.77 79.91,66.56 80.41,66.56 80.72,66.86 81.26,66.86 81.56,66.56 82.19,66.56 82.5,66.86 83.1,66.86 83.61,67.36 84.18,67.36 84.58,66.96 85.02,66.96 85.43,67.36 85.87,67.36 86.27,66.96 86.71,66.96 87.11,67.36 87.55,67.36 87.96,66.96 88.4,66.96 88.8,67.36 89.24,67.36 89.64,66.96 90.08,66.96 90.49,67.36 90.93,67.36 91.33,66.96 91.77,66.96 92.17,67.36 92.61,67.36 93.02,66.96 93.46,66.96 93.86,67.36 94.3,67.36 94.7,66.96 95.14,66.96 95.55,67.36 95.99,67.36 96.39,66.96 96.83,66.96 97.23,67.36 97.67,67.36 98.08,66.96 98.4,66.96 98.8,67.36 100.1,67.36
  BOTTOM w0.102: v2(67.49,61.96) 67.49,61.87 67.68,61.68 68.47,61.68 68.57,61.58 68.57,61.38 68.47,61.28 68.13,61.28 68.03,61.17 68.03,60.99 68.13,60.89 68.99,60.89 69.07,60.81 69.07,60.61 68.96,60.51 68.38,60.51 68.28,60.41 68.28,60.23 68.38,60.13 JDIMM1.109 ; UC1.J38 105.85,60.5 v2(105.85,60.53)
DDRA_CKE1: length 67.7
  IN1 w0.102: 101.68,68.09 101.87,67.9 102.45,67.9 102.56,67.79 102.56,66.83 103.29,66.1 103.36,66.1 104.03,65.43 104.03,63.6 105.29,62.34 105.61,62.34 106.94,61.02 107.37,61.02 v2(107.73,60.65)
  IN1 w0.211: v2(56.22,61.51) 56.77,61.51 58.01,62.76 61.59,62.76 63.5,64.66 72.01,64.66 76.38,69.03 100.74,69.03 101.68,68.09
  BOTTOM w0.102: v2(107.73,60.65) 107.86,60.53 UC1.J34 ; v2(56.22,61.51) 56.34,61.64 56.34,62.02 56.57,62.25 58.95,62.25 60.15,61.05 60.15,60.84 61.11,59.88 JDIMM1.110
DDRA_CLK0: length 68
  IN1 w0.102: v2(107.26,52.96) 107.34,52.88 107.34,52.71 107.2,52.58 104.48,52.58 104.33,52.72 103.52,52.72 103.19,52.39 103.11,52.39 102.87,52.16 102.87,52.07 102.81,52.01 102.81,51.99
  IN1 w0.221: v2(73.88,52.46) 74.01,52.33 78.9,52.33 79.46,51.77 79.46,51.01 79.69,50.78 81.47,50.78 82.13,50.12 82.13,48.76 82.35,48.54 83.06,48.54 83.28,48.76 83.28,50.72 83.77,51.21 84.91,51.21 85.4,50.72 85.4,48.62 85.62,48.4 86.28,48.4 86.44,48.55 86.44,50.53 86.99,51.08 88.16,51.08 88.78,50.47 88.78,48.69 89.06,48.41 89.72,48.41 90.01,48.69 90.01,52.82 90.5,53.31 91.67,53.31 92.16,52.82 92.16,48.72 92.47,48.41 93.23,48.41 93.47,48.65 93.47,50.63 93.96,51.11 95.74,51.11 96.49,50.36 97.19,50.36 97.63,50.8 99.84,50.8 100.61,51.56 101.51,51.56 102.18,50.89 102.59,50.89 102.81,51.11 102.81,51.99
  BOTTOM w0.102: v2(107.26,52.96) 107.42,52.96 107.53,52.86 107.53,52.53 107.3,52.31 107.16,52.31 UC1.AC35
  BOTTOM w0.163: v2(73.88,52.46) 73.7,52.28 73.53,52.28 73.43,52.38 73.43,54.32 73.09,54.65 72.3,54.65 71.97,54.32 71.97,53.23 71.66,52.92 71.19,52.92 70.99,53.13 JDIMM1.137
DDRA_CLK0#: length 68
  IN1 w0.102: 103.27,51.99 103.66,52.39 104.19,52.39 104.34,52.24 107.34,52.24 v2(108.06,52.96)
  IN1 w0.221: 103.27,51.99 103.27,50.92 102.78,50.43 101.99,50.43 101.32,51.1 100.8,51.1 100.03,50.34 97.82,50.34 97.38,49.9 96.3,49.9 95.55,50.66 94.15,50.66 93.92,50.44 93.92,48.46 93.42,47.95 92.28,47.95 91.7,48.53 91.7,52.63 91.48,52.85 90.69,52.85 90.47,52.63 90.47,48.5 89.91,47.95 88.87,47.95 88.32,48.5 88.32,50.28 87.98,50.62 87.18,50.62 86.9,50.34 86.9,48.37 86.47,47.94 85.43,47.94 84.94,48.43 84.94,50.53 84.72,50.75 83.96,50.75 83.74,50.53 83.74,48.57 83.25,48.09 82.16,48.09 81.67,48.57 81.67,49.93 81.28,50.32 79.5,50.32 79,50.82 79,51.58 78.71,51.87 v2(73.88,51.87)
  BOTTOM w0.102: v2(108.06,52.96) 107.86,52.76 UC1.AC34
  BOTTOM w0.163: JDIMM1.139 71.78,52.62 72.26,53.11 72.26,54.19 72.43,54.36 72.97,54.36 73.13,54.19 73.13,52.26 73.43,51.96 73.79,51.96 v2(73.88,51.87)
DDRA_CLK1: length 64.7
  IN1 w0.102: v2(108.06,54.06) 108.15,53.97 108.15,53.83 108,53.68 103.4,53.68 102.83,53.11 101.13,53.11 100.48,52.46 100.14,52.46 100.1,52.5
  IN1 w0.221: v2(66.43,53.16) 66.56,53.04 68.41,53.04 69.35,53.98 73.57,53.98 73.82,53.72 78.48,53.72 79.46,54.7 80.47,54.7 81.15,54.01 81.15,52.39 81.37,52.17 82.1,52.17 82.32,52.39 82.32,54.21 82.81,54.7 83.8,54.7 84.34,54.16 84.34,52.82 84.56,52.6 85.22,52.6 85.44,52.82 85.44,54.21 85.93,54.7 86.97,54.7 87.46,54.21 87.46,52.69 87.68,52.47 88.35,52.47 88.57,52.69 88.57,54.21 89.06,54.7 92.55,54.7 93.94,53.3 93.94,52.73 94.17,52.5 96.95,52.5 97.27,52.18 98.16,52.18 98.48,52.5 100.1,52.5
  BOTTOM w0.102: UC1.AA34 107.95,53.42 108.1,53.42 108.34,53.66 108.34,53.91 108.19,54.06 v2(108.06,54.06)
  BOTTOM w0.163: v2(66.43,53.16) 66.37,53.16 66.21,53 65.89,53 65.74,53.14 65.74,54.24 65.41,54.58 64.77,54.58 64.43,54.24 64.43,52.97 64.23,52.77 63.12,52.77 63.02,52.87 JDIMM1.138
DDRA_CLK1#: length 64.8
  IN1 w0.102: v2(108.86,54.06) 108.14,53.34 103.54,53.34 102.97,52.77 101.27,52.77 100.62,52.12 100.2,52.12 100.13,52.05 100.1,52.05
  IN1 w0.221: 100.1,52.05 98.67,52.05 98.35,51.73 97.08,51.73 96.76,52.05 93.98,52.05 93.49,52.54 93.49,53.11 92.36,54.24 89.25,54.24 89.03,54.02 89.03,52.5 88.54,52.01 87.49,52.01 87.01,52.5 87.01,54.02 86.79,54.24 86.12,54.24 85.9,54.02 85.9,52.63 85.41,52.14 84.37,52.14 83.88,52.63 83.88,53.97 83.61,54.24 83,54.24 82.78,54.02 82.78,52.2 82.29,51.71 81.18,51.71 80.69,52.2 80.69,53.83 80.28,54.24 79.65,54.24 78.67,53.26 73.64,53.26 73.38,53.52 69.54,53.52 68.6,52.58 v2(66.43,52.58)
  BOTTOM w0.102: v2(108.86,54.06) 108.66,53.86 UC1.AA32
  BOTTOM w0.163: JDIMM1.140 63.02,52.38 63.12,52.48 64.35,52.48 64.73,52.85 64.73,54.12 64.89,54.28 65.28,54.28 65.45,54.12 65.45,53.02 65.77,52.7 66.3,52.7 66.34,52.66 66.35,52.66 v2(66.43,52.58)
DDRA_ODT0: length 62.3
  IN1 w0.102: v2(105.87,47.36) 105.47,47.77 104.81,47.77 103.93,46.89 103.93,45.39 102.95,44.41 102.95,44.1 102.06,43.2 102.06,42.7 102.08,42.68 102.08,42.37 102,42.29 102,42.28 101.37,41.65 101.37,40.88 100.89,40.4 100.1,40.4
  IN1 w0.211: 100.1,40.4 99.67,40.4 98.73,39.46 95.8,39.46 95.51,39.74 95.51,40.24 95.3,40.45 94.88,40.45 94.67,40.24 94.67,39.67 94.46,39.46 94.11,39.46 93.82,39.74 93.82,40.24 93.61,40.45 93.19,40.45 92.98,40.24 92.98,39.67 92.77,39.46 92.35,39.46 92.14,39.67 92.14,40.24 91.93,40.45 91.51,40.45 91.29,40.24 91.29,39.67 91.08,39.46 84.61,39.46 83.96,40.11 80.37,40.11 75.05,45.43 73.82,45.43 72.11,47.14 71.81,47.14 71.59,46.92 71.29,46.92 70.5,47.71 69.09,47.71 68.6,47.21 67.75,47.21 67.19,47.77 65.97,47.77 65.87,47.67 v2(65.82,47.67)
  BOTTOM w0.102: v2(65.82,47.67) 67,47.67 67.1,47.57 67.1,46.75 67.2,46.64 67.4,46.64 67.5,46.75 67.5,47.34 67.62,47.45 67.8,47.45 67.9,47.35 67.9,46.76 68,46.66 68.19,46.66 68.29,46.76 68.29,47.17 68.39,47.27 68.57,47.27 68.68,47.17 68.68,46.73 68.78,46.63 JDIMM1.155 ; UC1.AN37 106.26,46.97 v2(105.87,47.36)
DDRA_ODT1: length 62.6
  IN1 w0.102: v2(105.15,45.23) 104.1,44.18 104.1,43.23 102.57,41.7 102.57,40.39 101.07,38.88
  IN1 w0.211: v2(65.21,45.95) 65.35,46.09 66.1,46.09 66.43,45.76 70.07,45.76 72.7,43.13 73.68,43.13 73.98,42.83 73.98,42.53 73.58,42.13 73.58,41.83 73.88,41.54 74.18,41.54 74.96,42.31 75.25,42.31 75.55,42.01 75.55,41.72 74.71,40.88 74.71,40.58 74.95,40.34 75.25,40.34 76.09,41.18 76.39,41.18 76.69,40.88 76.69,40.58 75.97,39.87 75.97,39.57 78.14,37.4 99.58,37.4 101.07,38.88
  BOTTOM w0.102: v2(65.21,45.95) 66.6,45.95 66.73,46.08 67,46.08 67.11,45.98 67.11,45.23 67.21,45.13 67.42,45.13 67.52,45.23 67.52,46 67.63,46.1 67.82,46.1 67.93,45.99 67.93,45.23 68.03,45.13 JDIMM1.161 ; v2(105.15,45.23) 105.46,44.92 UC1.AU38
DDRA_SCS0#: length 62.4
  IN1 w0.102: v2(107.21,48.57) 107.21,48.47 106.89,48.15 105.53,48.15 105.38,48 104.75,48 103.73,46.98 103.73,45.47 102.75,44.49 102.75,44.18 101.73,43.16 101.14,43.16 100.66,42.68 100.66,42.25 100.31,41.9
  IN1 w0.211: v2(65.04,48.04) 65.2,48.04 65.3,48.14 69.61,48.14 69.67,48.07 70.65,48.07 71.21,47.51 72.26,47.51 73.82,45.95 75.26,45.95 80.59,40.63 84.17,40.63 84.59,40.21 89.76,40.21 90.51,40.96 95.8,40.96 96.01,40.75 96.01,40.45 96.24,40.21 96.71,40.21 96.87,40.37 96.87,41.49 97.1,41.72 97.52,41.72 97.73,41.51 97.73,40.42 97.94,40.21 98.31,40.21 98.52,40.42 98.52,41.51 98.73,41.72 99.11,41.72 99.32,41.51 99.32,41.13 99.53,40.92 99.85,40.92 100.06,41.13 100.06,41.65 100.31,41.9
  BOTTOM w0.102: v2(107.21,48.57) 107.2,48.55 107.2,48.49 107.06,48.36 UC1.AL35 ; JDIMM1.149 68.98,48.13 68,49.1 65.46,49.1 65.04,48.68 v2(65.04,48.04)
DDRA_SCS1#: length 62.5
  IN1 w0.102: 100.34,38.88 100.59,39.13 100.86,39.13 102.37,40.64 102.37,41.79 103.78,43.2 103.78,44.34 104.54,45.1 104.54,46.48 104.84,46.78 105.87,46.78 106.3,46.36 v2(106.46,46.36)
  IN1 w0.211: v2(64.51,46.39) 64.7,46.39 64.8,46.49 66.22,46.49 66.58,46.12 70.22,46.12 72.85,43.49 74.8,43.49 77.52,40.78 77.52,40.4 76.86,39.74 76.86,39.45 77.16,39.15 77.46,39.15 78.15,39.84 78.45,39.84 78.77,39.52 78.77,39.22 78.06,38.51 78.06,38.21 78.36,37.91 78.66,37.91 79.37,38.63 79.67,38.63 80.38,37.91 99.37,37.91 100.34,38.88
  BOTTOM w0.102: v2(106.46,46.36) 106.26,46.16 UC1.AR37 ; v2(64.51,46.39) 68.55,46.39 68.81,46.13 JDIMM1.157
DDRAB_BG0: length 76.7
  IN1 w0.102: v2(107.99,58.46) 107.99,58.63 107.61,59.01 106.2,59.01 106.12,59.09 104.9,59.09 103.86,60.12 103.86,60.82 101.39,63.29 100.18,63.29 100.1,63.38
  IN1 w0.211: 100.1,63.38 99.27,63.38 97.86,64.78 94.67,64.78 94.67,64.78 94.31,64.78 94.14,64.96 94.14,65.21 93.94,65.42 83.85,65.42 83.44,65.01 77.71,65.01 75.44,62.74 74.43,62.74 74.01,62.33 73.42,62.33 73.03,61.94 69.92,61.94 68.76,60.77 64.36,60.77 63.72,61.42 63.01,61.42 62.45,60.86 61.66,60.86 61.45,60.65 61.45,60.53 61.24,60.32 59.82,60.32 v2(59.79,60.35)
  IN2 w0.211: v2(66.96,59.95) 66.33,60.58 63.95,60.58 63.67,60.3 59.83,60.3 v2(59.79,60.35)
  BOTTOM w0.102: v2(66.96,59.95) 66.96,59.63 67.75,58.84 68.32,58.84 68.54,58.62 JDIMM1.115 ; v2(59.79,60.35) 59.79,60.52 59.65,60.66 58.92,60.66 58.82,60.56 58.82,60.41 58.71,60.3 58.42,60.3 58.31,60.41 58.31,61.11 58.2,61.22 57.97,61.22 57.87,61.12 57.87,60.83 57.77,60.72 57.5,60.72 57.4,60.83 57.4,61.12 57.3,61.22 57.02,61.22 56.92,61.12 56.92,60.85 56.79,60.72 55.89,60.72 55.38,60.22 54.76,60.22 54.55,60.01 54.55,59.38 54.3,59.13 JDIMM2.115 ; v2(107.99,58.46) 107.86,58.33 UC1.N34
DDRAB_BG1: length 77.3
  IN1 w0.102: v2(105.66,59.56) 105.66,59.66 105.24,60.08 104.89,60.08 101.07,63.89 100.1,63.89
  IN1 w0.211: 100.1,63.89 99.66,63.89 99.46,64.09 99.46,64.39 99.75,64.69 99.75,64.99 99.53,65.21 99.24,65.21 98.9,64.88 98.52,64.88 98.31,65.09 98.31,65.72 98.09,65.93 97.59,65.93 97.37,65.72 97.37,65.57 97.16,65.36 96.74,65.36 96.53,65.57 96.53,65.72 96.32,65.93 95.9,65.93 95.69,65.72 95.69,65.57 95.48,65.36 95.06,65.36 94.84,65.57 94.84,65.72 94.63,65.93 83.63,65.93 83.23,65.52 77.5,65.52 75.23,63.26 74.05,63.26 73.64,62.84 73.42,62.84 72.88,62.31 69.77,62.31 68.6,61.14 64.51,61.14 63.84,61.81 62.89,61.81 62.3,61.22 59.76,61.22 59.61,61.07 v2(59.34,61.07)
  IN2 w0.211: v2(59.34,61.07) 60.19,61.07 60.43,60.83 61.27,60.83 61.86,61.42 63.59,61.42 66.22,61.42 67.65,59.98 67.65,59.95 v2(67.66,59.95)
  BOTTOM w0.102: v2(67.66,59.95) 67.66,59.94 68.47,59.13 JDIMM1.113 ; v2(59.34,61.07) 59.34,61.35 59.22,61.47 59.01,61.47 58.91,61.57 58.91,61.89 58.8,61.99 58.6,61.99 58.5,61.89 58.5,61.57 58.4,61.47 58.19,61.47 58.09,61.57 58.09,61.89 57.99,61.99 57.79,61.99 57.69,61.89 57.69,61.57 57.59,61.47 57.36,61.47 57.25,61.57 57.25,61.89 57.15,61.99 56.95,61.99 56.85,61.89 56.85,61.41 56.42,60.98 55.79,60.98 55.28,60.47 54.65,60.47 54.3,60.12 54.3,59.73 54.2,59.62 JDIMM2.113 ; v2(105.66,59.56) 105.66,59.21 UC1.L38
DDRAB_SBS0#: length 80.3
  IN1 w0.102: 100.1,44.19 100.82,44.19 101.31,44.68 101.79,44.68 102.19,45.08 102.19,46.31 102.92,47.03 102.92,47.32 103.42,47.82 103.42,48.16 104.92,49.66 v2(105.66,49.66)
  IN1 w0.211: 100.1,44.19 96.55,44.19 95.38,43.03 89.65,43.03 88.89,42.27 85.46,42.27 85.05,42.69 81.44,42.69 76.12,48.01 73.81,48.01 72.89,48.93 72.87,48.96 71.82,48.96 71.25,49.52 70.27,49.52 70.21,49.59 63,49.59 61.99,48.57 59.76,48.57 59.2,49.13 56.19,49.13 56.09,49.23 v2(55.39,49.23)
  IN2 w0.211: v2(55.39,49.23) 55.07,49.23 54.45,49.86 49.76,49.86 v2(48.28,48.38)
  BOTTOM w0.102: v2(55.39,49.23) 55.46,49.29 58,49.29 58.1,49.19 58.1,48.88 58.2,48.78 58.41,48.78 58.51,48.88 58.51,49.19 58.61,49.29 58.88,49.29 58.95,49.23 58.95,48.89 59.06,48.78 59.29,48.78 59.39,48.88 59.39,49.17 59.49,49.27 59.74,49.27 59.84,49.17 59.84,47.98 59.94,47.87 60.21,47.87 60.32,47.98 60.32,48.24 60.42,48.34 60.62,48.34 60.72,48.24 60.72,47.98 60.82,47.87 JDIMM1.150 ; UC1.AJ38 105.66,49.31 v2(105.66,49.66) ; JDIMM2.150 v2(48.28,48.38)
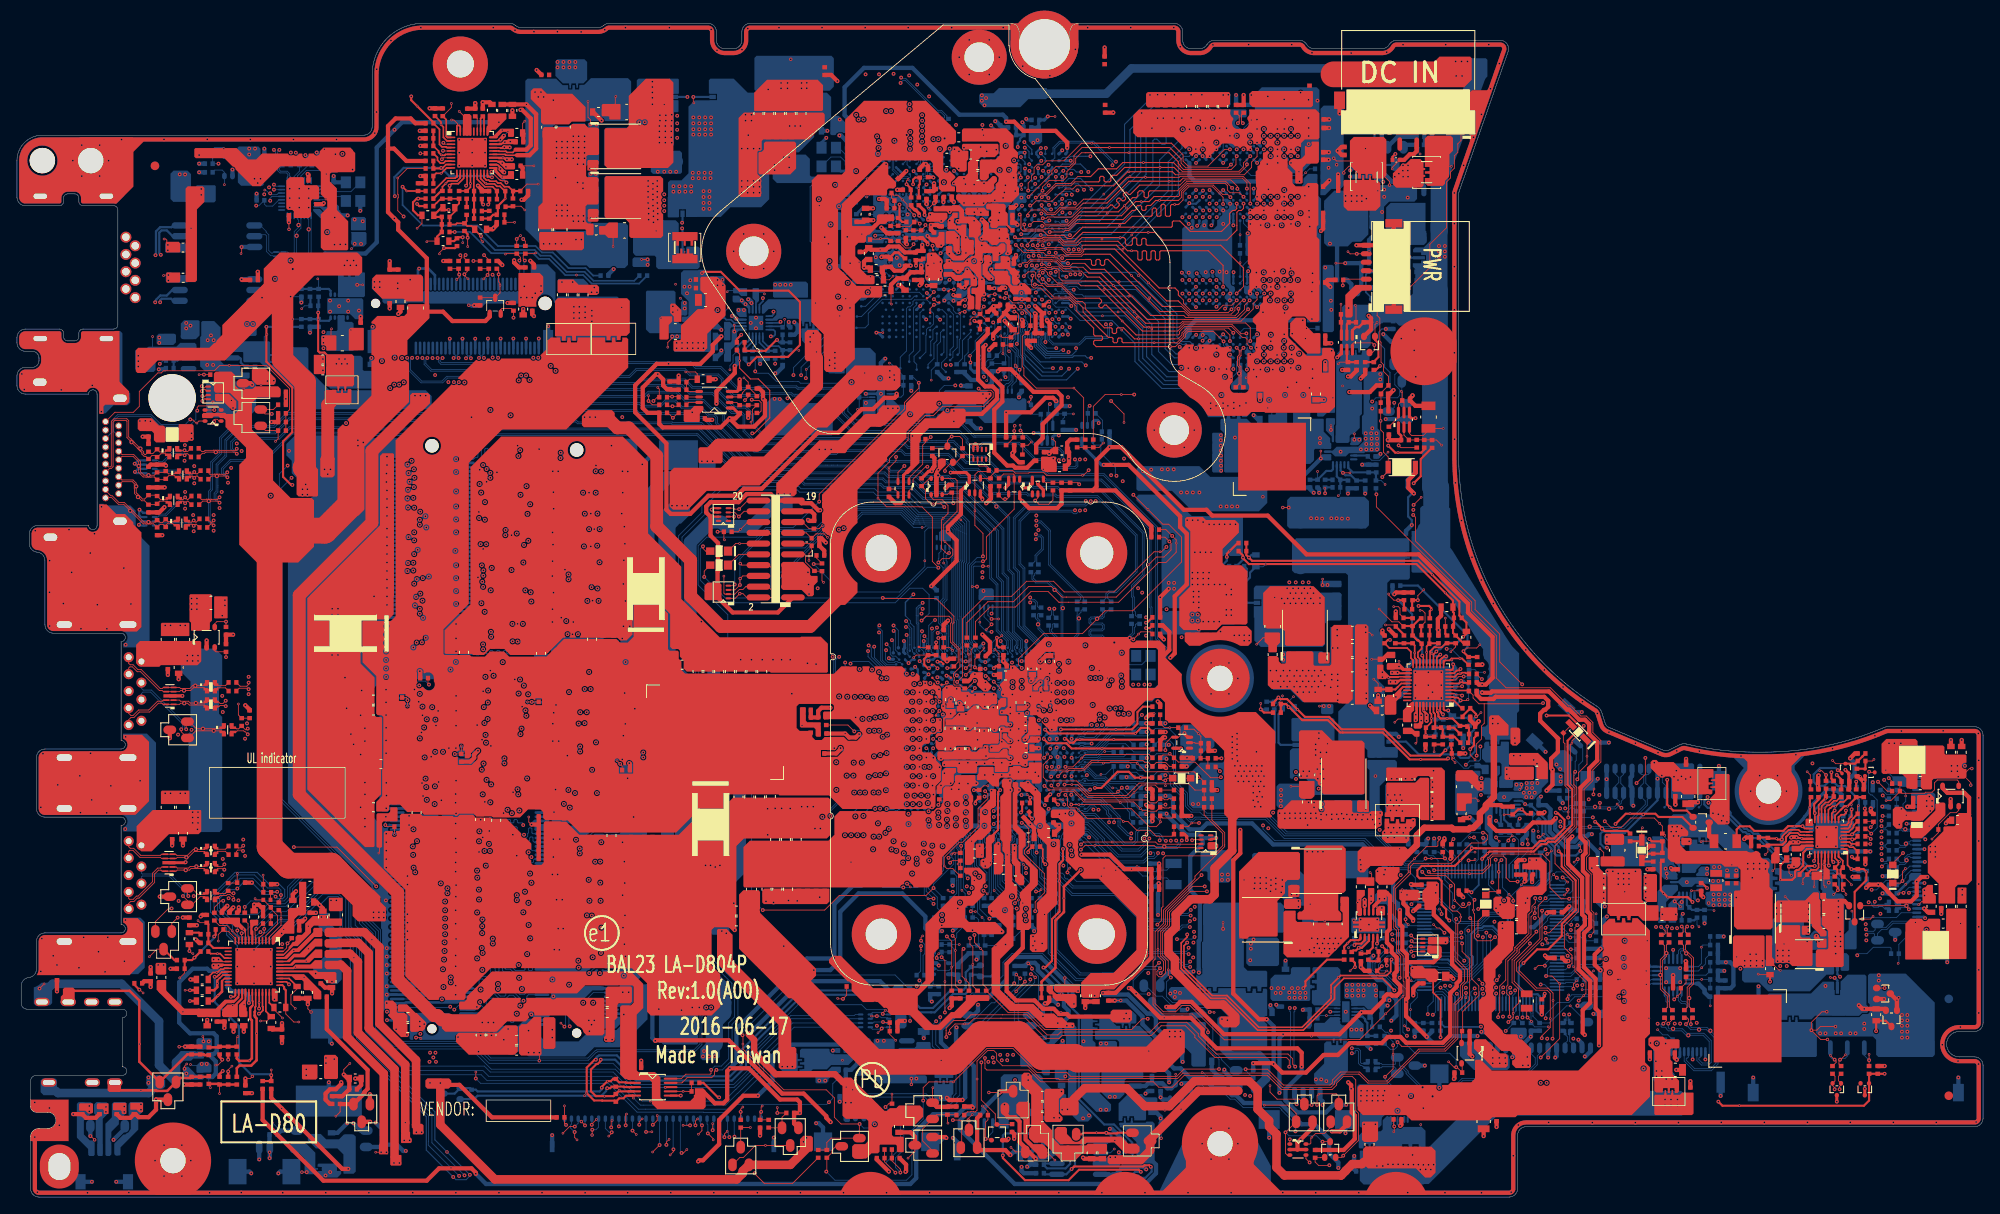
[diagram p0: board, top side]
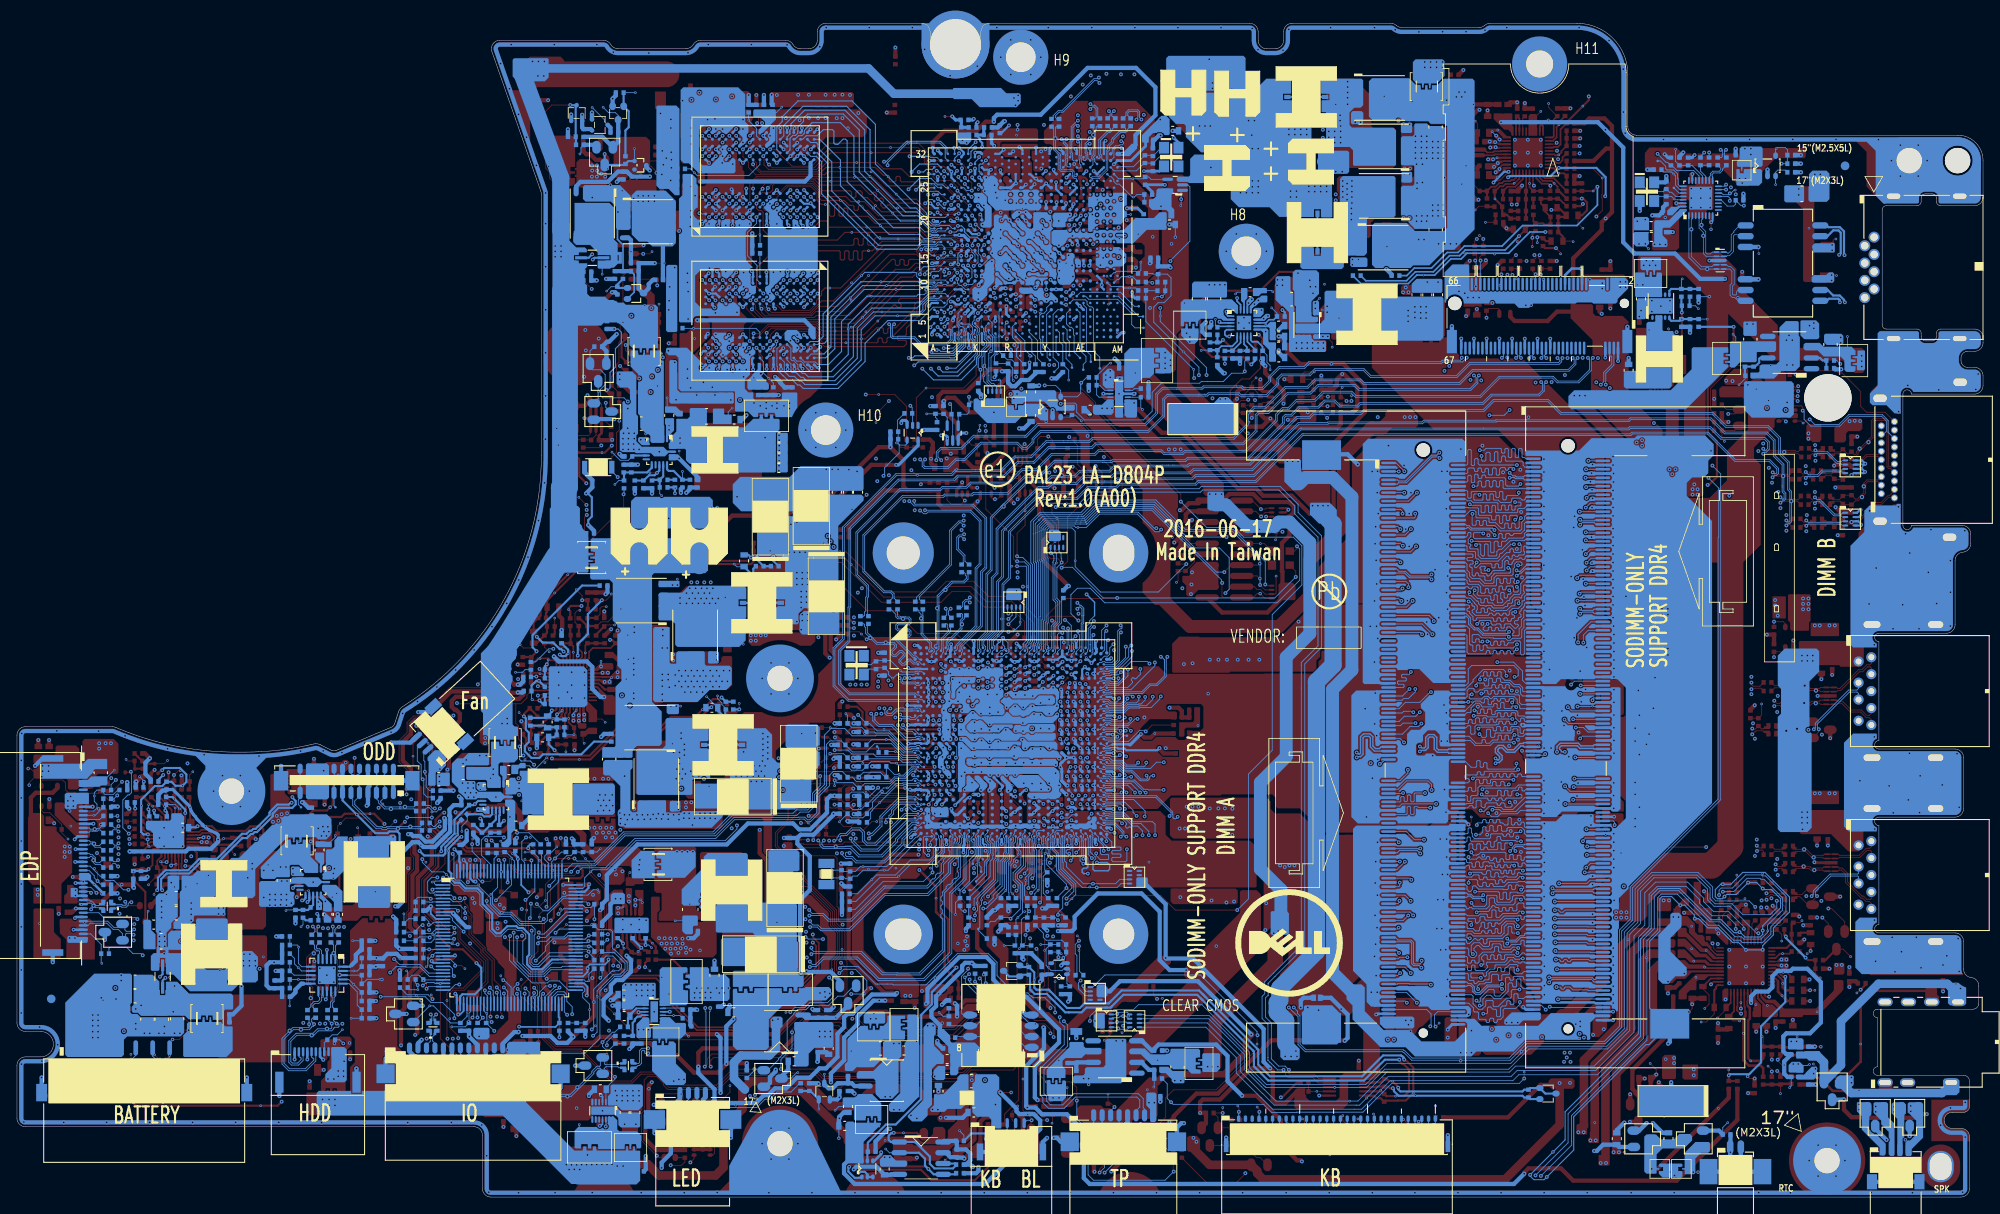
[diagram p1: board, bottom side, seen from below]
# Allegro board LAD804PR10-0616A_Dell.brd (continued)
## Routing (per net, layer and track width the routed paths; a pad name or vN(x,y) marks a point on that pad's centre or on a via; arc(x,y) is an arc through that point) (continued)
DDRAB_SBS1#: length 75.8
  IN1 w0.102: 100.1,45.96 100.55,45.96 101.01,46.42 101.72,46.42 102.51,47.2 102.51,47.48 103.01,47.99 103.01,48.33 104.8,50.12 105.24,50.12 105.43,50.31 106.81,50.31 107.04,50.54 v2(107.04,50.75)
  IN1 w0.211: v2(60.18,49.4) 61.78,49.4 62.77,50.38 65.81,50.38 66.31,50.87 69.98,50.87 70.57,50.29 72,50.29 72.01,50.29 72.31,50.29 72.35,50.25 72.37,50.25 72.85,49.76 72.85,49.74 72.91,49.68 73.17,49.68 73.18,49.68 73.24,49.68 73.87,49.04 76.55,49.04 81.86,43.73 88.39,43.73 89.17,44.51 93.98,44.51 95.43,45.96 100.1,45.96
  IN2 w0.211: v2(60.18,49.4) 60.35,49.23 65.62,49.23 66.8,50.41 v2(67.84,50.41)
  BOTTOM w0.102: UC1.AG35 107.06,50.74 v2(107.04,50.75) ; JDIMM1.145 68.77,49.13 67.84,50.05 v2(67.84,50.41) ; v2(60.18,49.4) 60.03,49.55 58.34,49.55 58.24,49.65 58.24,49.89 58.13,49.99 57.93,49.99 57.83,49.89 57.83,49.65 57.73,49.55 57.53,49.55 57.42,49.65 57.42,49.89 57.32,49.99 57.12,49.99 57.02,49.89 57.02,49.65 56.92,49.55 56.71,49.55 56.61,49.65 56.61,49.89 56.51,49.99 56.31,49.99 56.2,49.89 56.2,49.65 56.1,49.55 55.9,49.55 55.8,49.65 55.8,49.84 55.65,49.99 55.46,49.99 55.29,49.82 55.29,49.68 55.19,49.58 54.98,49.58 54.88,49.68 54.88,49.83 54.78,49.93 54.54,49.93 54.44,49.83 54.44,49.7 54.36,49.62 JDIMM2.145
DDRAB_SCAS#: length 80.7
  IN1 w0.102: v2(104.96,47.38) 104.87,47.38 104.13,46.65 104.13,45.3 103.37,44.54 103.37,43.37 101.87,41.87 101.87,41.1 100.66,39.88 100.1,39.88
  IN1 w0.211: v2(54.94,47.52) 55.14,47.52 55.6,47.06 63.12,47.06 63.28,47.21 67.24,47.21 67.6,46.85 70.79,46.85 71.27,46.37 72.37,46.37 73.82,44.92 74.84,44.92 80.16,39.6 83.74,39.6 84.4,38.94 98.94,38.94 99.88,39.88 100.1,39.88
  IN2 w0.211: v2(48.34,46.87) 48.92,47.45 50.19,47.45 50.63,47.01 52.79,47.01 52.93,46.86 54.33,46.86 54.94,47.47 v2(54.94,47.52)
  BOTTOM w0.102: v2(54.94,47.52) 54.5,47.52 54.4,47.41 54.4,47.18 54.5,47.08 56.23,47.08 56.33,46.98 56.33,46.91 56.43,46.8 56.63,46.8 56.74,46.91 56.74,46.99 56.84,47.09 57.04,47.09 57.14,46.99 57.14,46.87 57.24,46.77 57.42,46.77 57.55,46.89 57.55,46.98 57.65,47.08 57.88,47.08 57.99,46.98 57.99,46.87 58.09,46.77 58.27,46.77 58.39,46.89 58.39,46.98 58.49,47.08 60.05,47.08 60.15,46.97 60.15,46.54 60.26,46.44 60.89,46.44 60.95,46.38 JDIMM1.156 ; JDIMM2.156 v2(48.34,46.87) ; v2(104.96,47.38) 104.99,47.38 UC1.AN38
DDRAB_SDM0: length 100.9
  IN1 w0.211: v2(54.57,84.14) 54.3,84.41 50.6,84.41 50.47,84.54 50.47,85.16 50.34,85.28 49.75,85.28 49.63,85.16 49.63,84.54 49.5,84.41 47.48,84.41 47.01,84.88 v2(46.89,84.88)
  IN2 w0.211: v2(54.57,84.14) 54.57,83.87 54.78,83.66 55.87,83.66 56.08,83.87 56.08,84 56.29,84.22 56.72,84.22 56.93,84 56.93,83.87 57.14,83.66 57.67,83.66 60.63,86.62 64.63,86.62 65.09,86.15 67.47,86.15 68.1,86.79 68.87,86.79 69.08,86.58 69.08,86.46 69.29,86.25 69.3,86.26 69.8,86.26 70.01,86.47 70.01,86.61 70.22,86.82 70.64,86.82 70.85,86.61 70.85,86.47 71.06,86.26 71.4,86.26 71.61,86.47 71.61,86.68 71.82,86.89 72.16,86.89 72.38,86.68 72.38,86.08 72.93,85.52 91.83,85.52 92.6,84.76 99.15,84.76 99.36,84.55 99.36,83.75 99.57,83.54 99.99,83.54 100.2,83.75 100.2,84.55 100.41,84.76 100.99,84.76 107.38,78.37 107.38,73.59 106.25,72.47 106.25,70.37 106.07,70.19 106.07,67.46 v2(106.75,66.77)
  BOTTOM w0.102: JDIMM2.12 v2(46.89,84.88) ; JDIMM1.12 60.9,84.37 60.78,84.5 60.78,85.07 60.68,85.17 60.47,85.17 60.37,85.07 60.37,84.39 60.27,84.29 60.07,84.29 59.96,84.39 59.96,85.2 59.86,85.3 59.66,85.3 59.56,85.2 59.56,84.9 59.46,84.8 59.21,84.8 59.11,84.9 59.11,85.08 58.99,85.21 58.8,85.21 58.69,85.11 58.69,84.98 58.59,84.88 56.43,84.88 56.31,84.75 56.31,84.05 56.14,83.89 54.82,83.89 v2(54.57,84.14) ; v2(106.75,66.77) 106.75,66.51 106.58,66.33 106.58,64.74 106.96,64.36 UC1.B35
DDRAB_SDM1: length 88.2
  IN1 w0.211: v2(58.95,78.3) 60.18,79.53 68.03,79.53 68.73,78.83 v2(68.73,78.81)
  IN2 w0.211: v2(58.95,78.3) 58.95,78.29 59.73,79.07 61.1,79.07 61.95,79.92 62.44,79.92 64.99,79.92 65.28,79.63 65.28,79.63 65.57,79.34 67.61,79.34 67.83,79.34 67.83,79.35 68.85,79.35 69.32,78.87 69.66,78.87 69.93,79.14 70.72,79.14 70.99,78.87 71.25,78.61 72.58,78.61 73,79.03 73.48,79.03 73.91,78.61 74.68,78.61 77.22,76.06 77.56,76.06 77.77,76.27 77.77,76.61 77.98,76.82 78.4,76.82 78.61,76.61 78.61,76.27 78.82,76.06 79.25,76.06 79.46,76.27 79.46,76.61 79.67,76.82 80.09,76.82 80.27,76.64 80.27,76.54 80.3,76.5 80.3,76.27 80.51,76.06 80.89,76.06 81.24,76.41 81.73,76.41 82.08,76.06 83.87,76.06 84.08,76.27 84.08,76.52 84.3,76.73 84.72,76.73 84.93,76.52 84.93,76.27 85.14,76.06 85.56,76.06 85.77,76.27 85.77,76.61 85.98,76.82 86.4,76.82 86.61,76.61 86.61,76.27 86.83,76.06 87.25,76.06 87.46,76.27 87.46,76.52 87.67,76.73 88.09,76.73 88.3,76.52 88.3,76.27 88.51,76.06 88.9,76.06 89.11,76.27 89.11,76.37 89.32,76.58 89.99,76.58 90.25,76.32 90.25,76.03 90.08,75.86 90.08,75.56 90.38,75.26 90.68,75.26 90.89,75.47 91.19,75.47 91.6,75.07 91.6,74.77 91.37,74.54 91.37,74.15 91.47,74.05 91.47,73.19 91.99,72.66 92.52,72.66 92.78,72.4 92.78,71.89 92.99,71.68 93.89,71.68 94.1,71.47 94.1,71.4 94.31,71.19 94.82,71.19 94.99,71.37 94.99,71.57 95.1,71.68 96.06,71.68 100.48,67.26 100.48,67.06 102.01,65.53 102.01,64.27 102.16,64.12 102.35,64.12 102.51,64.28 v2(102.51,64.53)
  BOTTOM w0.102: v2(102.51,64.53) 102.45,64.47 102.45,63.4 102.75,63.09 103.5,63.09 103.6,63.17 103.84,63.17 103.93,63.08 104.19,63.08 UC1.D40 ; JDIMM2.33 53.94,79.62 54.1,79.46 54.1,78.69 54.5,78.3 55.3,78.3 55.41,78.2 55.41,78.16 55.51,78.06 55.71,78.06 55.81,78.16 55.81,78.2 55.91,78.3 56.2,78.3 56.31,78.2 56.31,77.81 56.43,77.69 56.59,77.69 56.71,77.81 56.71,78.2 56.81,78.3 57.02,78.3 57.12,78.2 57.12,77.81 57.24,77.69 59.98,77.69 60.11,77.82 60.11,78.3 60.01,78.4 59.05,78.4 v2(58.95,78.3) ; v2(68.73,78.81) 68.73,78.82 69.03,79.13 JDIMM1.33
DDRAB_SDM2: length 81.1
  IN1 w0.211: v2(54.88,72.61) 53.77,72.61 52.57,73.81 50.57,73.81 50.36,74.02 50.36,74.03 50.14,74.25 49.73,74.25 49.26,73.78 46.91,73.78 v2(46.76,73.93)
  IN2 w0.211: v2(54.88,72.61) 54.9,72.63 57.99,72.63 58.19,72.43 58.61,72.43 59.61,73.43 61.96,73.43 62.26,73.12 62.57,72.81 63.92,72.81 64.28,72.45 64.28,72.45 64.31,72.42 68.51,72.42 69.07,71.86 69.58,71.86 69.9,72.19 70.29,72.19 70.62,71.86 71.93,71.86 72.26,72.19 73.2,72.19 74.16,71.23 79.06,66.33 83.44,66.33 83.69,66.08 83.69,65.52 84.03,65.17 84.51,65.17 84.72,65.38 84.72,65.9 84.94,66.12 85.35,66.12 85.56,65.91 85.56,65.38 85.77,65.17 94.14,65.17 96.31,63 97.61,63 v2(97.68,63.07)
  BOTTOM w0.102: v2(46.76,73.93) 46.31,74.38 JDIMM2.54 ; v2(97.68,63.07) 97.68,62.69 100.51,59.87 103.1,59.87 103.18,59.79 103.49,59.79 103.57,59.87 103.84,59.87 103.93,59.78 104.19,59.78 UC1.K40 ; JDIMM1.54 61.2,73.88 60.87,73.54 60.87,73.16 60.55,72.84 60.55,72.67 60.48,72.61 59.41,72.61 58.91,72.12 57.48,72.12 57.38,72.22 57.38,72.92 57.28,73.02 57.14,73.02 56.97,72.85 56.97,72.51 56.87,72.41 56.67,72.41 56.57,72.51 56.57,72.92 56.47,73.02 56.26,73.02 56.16,72.92 56.16,72.51 56.06,72.41 55.86,72.41 55.75,72.51 55.75,72.92 55.65,73.02 55.37,73.02 55.27,72.92 55.27,72.75 55.36,72.65 55.36,72.51 55.26,72.41 54.99,72.41 54.88,72.51 v2(54.88,72.61)
DDRAB_SDM3: length 82.5
  IN1 w0.211: v2(64.79,67.96) 64.22,67.39 60.24,67.39 60.02,67.17 58.86,67.17 58.44,67.59 v2(58.44,67.63)
  IN2 w0.211: v2(58.44,67.63) 58.02,68.05 57.37,68.05 57.16,67.84 57.16,67.33 57.37,67.12 61.38,67.12 61.72,66.78 63.71,66.78 64.53,65.95 67.76,65.95 69.93,65.95 71.12,64.77 72.16,64.77 72.53,65.14 72.83,65.14 77.4,60.57 77.7,60.57 77.83,60.7 78.13,60.7 78.43,60.4 78.43,60.1 78.29,59.97 78.29,59.67 78.59,59.37 78.89,59.37 79.02,59.51 79.32,59.51 79.62,59.21 79.62,58.91 79.49,58.78 79.49,58.48 79.92,58.05 81.09,58.05 81.3,57.84 81.3,57.55 81.53,57.32 82.26,57.32 82.47,57.53 82.47,57.84 82.68,58.05 83.09,58.05 83.31,57.82 83.31,57.53 83.52,57.32 90,57.32 90.42,57.74 92.48,57.74 92.69,57.95 92.69,58.12 92.9,58.33 93.32,58.33 93.53,58.12 93.53,57.95 93.74,57.74 94.79,57.74 94.95,57.9 94.95,58.12 95.16,58.33 96.28,58.33 96.71,57.9 100.26,57.9 101.24,56.91 v2(101.24,56.6)
  BOTTOM w0.102: JDIMM2.75 53.84,69.13 53.97,69.26 54.07,69.26 54.17,69.16 54.17,68.41 54.46,68.12 54.46,67.32 54.71,67.07 54.71,66.34 54.82,66.23 55.41,66.23 55.49,66.31 55.49,66.46 55.33,66.63 55.33,66.78 55.83,67.28 56.07,67.28 56.17,67.18 56.17,67 56.35,66.82 57.04,66.82 57.14,66.92 57.14,67.1 57.24,67.2 57.44,67.2 57.54,67.1 57.54,66.92 57.65,66.82 57.85,66.82 57.95,66.92 57.95,67.17 58.05,67.27 58.26,67.27 58.36,67.17 58.36,66.92 58.46,66.82 58.79,66.82 58.97,67 58.97,67.14 58.47,67.63 v2(58.44,67.63) ; v2(101.24,56.6) 101.68,56.15 102.85,56.15 102.96,56.26 UC1.T41 ; v2(64.79,67.96) 64.79,68.09 65.32,68.62 JDIMM1.75
DDRAB_SDM4: length 78.1
  IN1 w0.211: v2(55.67,41.67) 55.67,41.64 55.36,41.32 47.17,41.32 47.12,41.38 v2(46.69,41.38)
  IN2 w0.211: v2(55.67,41.67) 56.16,41.67 56.37,41.88 56.37,42.48 56.58,42.69 57,42.69 57.21,42.48 57.21,41.57 57.49,41.29 58.13,41.29 58.94,42.11 61.54,42.11 61.67,42.24 62.62,42.24 63.12,42.74 64.19,42.74 64.56,42.36 64.56,41.94 64.79,41.7 66.89,41.7 67.21,42.02 68.42,42.02 68.73,42.33 73.87,42.33 83.02,51.48 94.09,51.48 94.5,51.89 95.37,51.89 95.78,51.48 96.46,51.48 v2(96.63,51.31)
  BOTTOM w0.102: v2(96.63,51.31) 97.48,51.31 98.22,50.57 101.17,50.57 101.73,51.13 103.18,51.13 UC1.AE41 ; JDIMM2.178 v2(46.69,41.38) ; JDIMM1.178 60.78,40.87 60.65,41 60.65,41.58 60.55,41.68 60.29,41.68 60.19,41.58 60.19,41.14 60.03,40.98 59.82,40.98 59.72,41.08 59.72,41.58 59.62,41.68 59.39,41.68 59.29,41.58 59.29,41.09 59.19,40.99 58.96,40.99 58.86,41.09 58.86,41.2 58.76,41.31 58.55,41.31 58.45,41.2 58.45,41.09 58.35,40.99 57.34,40.99 57.23,41.09 57.23,41.75 57.15,41.84 56.94,41.84 56.85,41.75 56.85,41.09 56.75,40.99 56.51,40.99 56.41,41.09 56.41,41.67 56.31,41.78 55.77,41.78 v2(55.67,41.67)
DDRAB_SDM5: length 81.2
  IN1 w0.211: v2(67.52,34.96) 66.45,36.03 v2(59.92,36.03)
  IN2 w0.211: v2(59.92,36.03) 59.94,36.05 61.37,36.05 61.87,35.55 66.05,35.55 66.18,35.42 69.17,35.42 69.44,35.16 73.04,35.16 73.51,35.63 80.33,35.63 80.54,35.84 80.54,37.34 80.75,37.55 81.23,37.55 81.44,37.34 81.44,35.9 81.65,35.69 81.98,35.69 82.25,35.96 82.25,37.48 82.37,37.6 82.88,37.6 83.15,37.86 83.5,37.86 83.7,37.67 84.11,37.67 84.41,37.97 84.41,38.27 84.07,38.61 84.07,38.91 84.37,39.21 84.67,39.21 85.01,38.87 85.31,38.87 85.61,39.16 85.61,39.46 85.26,39.8 85.26,40.1 85.56,40.4 85.86,40.4 86.2,40.06 86.5,40.06 86.8,40.36 86.8,40.65 86.46,41 86.46,41.3 86.75,41.59 87.05,41.59 87.39,41.26 87.7,41.26 87.99,41.55 87.99,41.85 87.65,42.19 87.65,42.49 88.52,43.36 88.82,43.36 89.16,43.02 89.46,43.02 90.15,43.71 91.53,43.71 92.9,45.08 94.33,45.08 94.72,45.47 100.27,45.47 101.07,46.27 101.41,46.27 101.62,46.48 v2(101.62,47.73)
  BOTTOM w0.102: UC1.AL40 103.84,47.79 103.59,47.79 103.49,47.69 103.49,47.69 103.44,47.64 102.84,47.64 102.79,47.59 101.76,47.59 v2(101.62,47.73) ; v2(67.52,34.96) 68.19,35.63 JDIMM1.199 ; v2(59.92,36.03) 57.18,36.03 57.02,35.87 57.02,35.22 56.9,35.1 56.72,35.1 56.61,35.2 56.61,35.87 56.51,35.97 56.31,35.97 56.21,35.87 56.21,35.22 56.09,35.1 55.9,35.1 55.8,35.2 55.8,35.87 55.7,35.97 54.96,35.97 54.86,35.87 54.31,35.87 54.06,36.12 JDIMM2.199
DDRAB_SDM6: length 81.5
  IN1 w0.211: v2(54.87,31.15) 54.57,31.15 54.44,31.28 53.53,31.28 53.32,31.06 53.32,30.96 53.11,30.75 52.69,30.75 52.48,30.96 52.48,31.06 52.26,31.28 50.77,31.28 v2(50.5,31.01)
  IN2 w0.211: v2(54.87,31.15) 54.87,30.64 55.07,30.43 55.37,30.43 55.58,30.65 55.58,30.89 55.79,31.1 57.46,31.1 58.15,30.41 59.9,30.41 60.34,29.97 60.8,29.97 61.21,29.56 62.36,29.56 63.29,28.63 66.65,28.63 67.46,27.83 70.73,27.83 71.14,27.42 74.9,27.42 75.96,28.48 87.82,28.48 91.85,32.51 91.85,33.96 93.38,35.49 93.38,35.93 94.21,36.75 94.64,36.75 101.24,43.35 101.24,43.79 v2(101.55,44.1)
  BOTTOM w0.102: JDIMM1.220 61.04,30.38 60.92,30.25 60.92,30.05 60.77,29.9 60.58,29.9 60,30.49 59.83,30.49 59.65,30.31 59.44,30.31 59.27,30.49 59.04,30.49 58.94,30.39 58.94,30.01 58.81,29.88 58.65,29.88 58.52,30.01 58.52,30.39 58.42,30.49 56.7,30.49 56.3,30.9 56.17,30.9 56.03,31.04 56.03,31.84 55.93,31.94 55.69,31.94 55.59,31.84 55.59,31.27 55.47,31.15 v2(54.87,31.15) ; v2(50.5,31.01) 46.74,31.01 46.61,30.87 JDIMM2.220 ; v2(101.55,44.1) 101.85,44.39 103.49,44.39 103.58,44.49 103.84,44.49 UC1.AU40
DDRAB_SDM7: length 102.6
  IN1 w0.211: v2(59.75,23.17) 59.75,23.23 60.35,23.83 62.39,23.83 63.21,24.65 64.72,24.65 v2(65.13,25.06)
  IN2 w0.211: v2(59.75,23.17) 59.75,22.95 60.03,22.67 60.03,22.26 60.28,22.01 60.85,22.01 61.12,21.74 61.12,21.16 62.07,20.21 63.82,20.21 64.39,19.65 64.83,19.65 65.11,19.37 65.11,18.43 65.33,18.22 66.93,18.22 67.14,18.43 67.14,18.83 67.35,19.04 67.77,19.04 67.98,18.83 67.98,18.43 68.19,18.22 68.77,18.22 69.03,18.47 69.03,18.77 69.3,19.04 70.45,19.04 70.66,18.83 70.66,18.43 70.87,18.22 71.29,18.22 71.5,18.43 71.5,18.83 71.71,19.04 72.14,19.04 72.35,18.83 72.35,18.43 72.56,18.22 72.98,18.22 73.19,18.43 73.19,18.83 73.4,19.04 73.77,19.04 74,18.81 74,18.43 74.21,18.22 74.61,18.22 74.82,18.43 74.82,18.83 75.03,19.04 75.56,19.04 75.78,18.83 75.78,18.43 75.99,18.22 76.38,18.22 76.59,18.43 76.59,18.83 76.8,19.04 77.3,19.04 79.3,21.03 83.94,21.03 84.77,21.86 91.93,21.86 93.64,23.57 96.23,23.57 97.02,24.36 99.37,24.36 100.19,25.18 100.49,25.18 100.79,24.88 101.15,24.88 101.44,25.17 101.44,25.47 101.1,25.8 101.1,26.1 101.4,26.39 101.71,26.39 102.03,26.06 102.33,26.06 102.63,26.36 102.63,26.66 102.17,27.12 102.17,27.42 102.46,27.72 102.77,27.72 103.23,27.26 103.53,27.26 105.59,29.32 105.59,33.19 105.37,33.41 104.43,33.41 104.22,33.62 104.22,34.04 104.43,34.25 105.37,34.25 105.59,34.46 105.59,34.88 105.37,35.09 104.91,35.09 104.7,35.3 104.7,35.72 104.91,35.93 105.37,35.93 105.59,36.15 v2(105.59,38.17)
  BOTTOM w0.102: 105.59,39.39 105.59,39.99 105.86,40.26 UC1.BA37 ; JDIMM2.241 54.08,25.63 54.2,25.74 54.2,25.94 54.3,26.04 55.31,26.04 55.41,25.94 55.41,25.69 55.51,25.58 55.71,25.58 55.81,25.69 55.81,25.83 55.92,25.94 56.22,25.94 56.33,25.83 56.33,24.39 57.01,23.71 57.53,23.71 57.66,23.84 57.66,24.39 57.76,24.49 58.29,24.49 59.29,23.49 59.29,23.12 59.42,23 59.57,23 v2(59.75,23.17) ; JDIMM1.241 69.08,25.13 69.02,25.19 67.72,25.19 67.68,25.15 65.22,25.15 v2(65.13,25.06)
  BOTTOM w0.163: 105.59,39.39 105.59,38.96 105.75,38.8 106.09,38.8 106.26,38.63 106.26,38.33 106.09,38.17 v2(105.59,38.17)
DDRAB_SDQ0: length 101.2
  IN1 w0.211: v2(46.82,85.88) 48.98,85.88 49.12,86.01 53.11,86.01 53.77,85.36 54.85,85.36 v2(55.39,85.9)
  IN2 w0.211: v2(108.29,68.09) 108.29,68.57 110.45,70.73 110.45,78.81 102.02,87.24 101.59,87.24 101.59,87.24 94.12,87.24 92.22,89.14 75.54,89.14 74.34,90.34 59.72,90.34 59.1,89.72 59.1,89.61 57,87.51 57,87.21 57.26,86.95 57.26,86.65 56.97,86.35 56.67,86.35 56.4,86.62 56.1,86.62 v2(55.39,85.9)
  BOTTOM w0.102: JDIMM2.8 v2(46.82,85.88) ; v2(108.29,68.09) 108.19,67.99 108.1,67.99 107.54,67.44 107.54,65.19 107.51,65.16 UC1.A34 ; v2(55.39,85.9) 55.56,86.07 55.9,86.07 56,85.97 56,85.87 56.1,85.77 56.24,85.77 56.34,85.87 56.34,86 56.42,86.07 56.84,86.07 57.02,85.9 57.02,85.29 57.12,85.18 57.32,85.18 57.42,85.29 57.42,85.92 57.53,86.02 57.77,86.02 57.87,85.92 57.87,85.31 57.97,85.21 58.24,85.21 58.34,85.31 58.34,85.9 58.44,86 58.64,86 58.74,85.9 58.74,85.62 58.85,85.51 59.05,85.51 59.15,85.62 59.15,85.92 59.25,86.02 59.48,86.02 59.58,85.92 59.58,85.7 59.68,85.6 59.89,85.6 59.99,85.7 59.99,85.92 60.09,86.02 60.65,86.02 60.77,85.9 60.77,85.5 60.9,85.37 JDIMM1.8
DDRAB_SDQ1: length 104.7
  IN1 w0.211: v2(59.15,87.44) 60.49,86.1 64.03,86.1 64.95,85.18 68.45,85.18 68.88,85.62 v2(68.91,85.62)
  IN2 w0.211: v2(59.15,87.44) 59.4,87.44 60.03,88.07 60.9,88.07 61.11,88.28 61.11,89.1 61.32,89.31 61.98,89.31 62.19,89.1 62.19,88.98 62.4,88.77 62.82,88.77 63.03,88.98 63.03,89.1 63.24,89.31 63.63,89.31 63.84,89.1 63.84,88.63 64.05,88.42 64.47,88.42 64.68,88.63 64.68,89.1 64.89,89.31 68.2,89.31 68.41,89.1 68.41,88.93 68.62,88.72 69.05,88.72 69.26,88.93 69.26,89.1 69.47,89.31 69.89,89.31 70.1,89.1 70.1,88.93 70.31,88.72 70.73,88.72 70.94,88.93 70.94,89.1 71.15,89.31 71.58,89.31 71.79,89.1 71.79,88.93 72,88.72 72.34,88.72 72.55,88.93 72.55,89.1 72.76,89.31 73.18,89.31 73.39,89.1 73.39,88.93 73.6,88.72 73.77,88.72 75.51,86.98 75.85,86.98 76.06,87.19 76.06,87.63 76.27,87.84 76.69,87.84 76.9,87.63 76.9,87.19 77.11,86.98 77.53,86.98 77.74,87.19 77.74,87.58 77.98,87.81 78.4,87.81 78.61,87.6 78.61,87.19 78.82,86.98 80.19,86.98 80.54,87.33 82.37,87.33 82.72,86.98 84.6,86.98 84.89,87.27 85.53,87.27 85.82,86.98 86.29,86.98 86.58,87.27 87.27,87.27 87.56,86.98 87.98,86.98 88.26,87.27 88.91,87.27 89.19,86.98 89.66,86.98 89.95,87.27 90.59,87.27 90.88,86.98 91.35,86.98 91.57,87.2 92.21,87.2 93.21,86.21 101.59,86.21 108.83,78.97 108.83,75.37 109.14,75.07 109.14,74.01 108.83,73.7 108.83,72.52 108.62,72.31 108.54,72.31 108.33,72.1 108.33,71.68 108.54,71.47 108.97,71.47 109.18,71.26 109.18,70.92 107.19,68.93 107.19,66.33 v2(107.04,66.19)
  BOTTOM w0.102: UC1.B34 107.51,64.01 107.2,64.33 107.2,64.59 107.28,64.67 107.28,64.68 107.28,64.68 107.28,65.28 107.34,65.34 107.34,65.89 v2(107.04,66.19) ; v2(68.91,85.62) 68.92,85.62 68.93,85.62 JDIMM1.7 ; v2(59.15,87.44) 59.15,86.96 59.02,86.84 58.77,86.84 58.64,86.96 58.64,87.75 58.52,87.88 58.26,87.88 58.14,87.75 58.14,86.94 58.01,86.81 57.75,86.81 57.63,86.94 57.63,87.83 57.51,87.95 57.34,87.95 57.22,87.83 57.22,86.86 57.09,86.73 56.92,86.73 56.79,86.86 56.79,87.32 56.66,87.44 56.47,87.44 56.34,87.32 56.34,86.94 56.24,86.84 54.41,86.84 54.24,86.67 54.24,86.33 54.04,86.13 JDIMM2.7
DDRAB_SDQ2: length 101.4
  IN1 w0.211: v2(46.76,82.5) 47.87,82.5 48.08,82.72 48.08,82.8 48.3,83.01 48.72,83.01 48.93,82.8 48.93,82.72 49.14,82.5 50.72,82.5 51.22,82 v2(55.2,82)
  IN2 w0.211: v2(104.86,67.26) 104.86,66.95 105.07,66.74 105.37,66.74 105.55,66.92 105.55,69.61 105.22,69.94 105.22,72.89 106.35,74.02 106.35,77.94 101.78,82.5 94.74,82.5 94.53,82.72 94.53,83.51 94.32,83.73 93.99,83.73 93.77,83.51 93.77,82.72 93.56,82.5 93.14,82.5 92.93,82.72 92.93,83.51 92.72,83.73 91.92,83.73 91.15,84.49 90.59,84.49 90.3,84.2 89.75,84.2 89.46,84.49 88.9,84.49 88.61,84.2 88.06,84.2 87.77,84.49 87.22,84.49 86.93,84.2 86.37,84.2 86.08,84.49 85.53,84.49 85.24,84.2 84.69,84.2 84.4,84.49 83.84,84.49 83.55,84.2 83,84.2 82.71,84.49 82.16,84.49 81.87,84.2 81.32,84.2 81.02,84.49 80.47,84.49 80.18,84.2 79.63,84.2 79.34,84.49 78.79,84.49 78.49,84.2 77.94,84.2 77.65,84.49 77.31,84.49 77.02,84.2 76.47,84.2 76.18,84.49 72.51,84.49 72.4,84.61 71.54,84.61 67,84.61 66.84,84.77 65.01,84.77 64.61,85.18 60.65,85.18 57.47,82 56.45,82 55.49,81.04 54.93,81.04 54.67,81.3 54.65,81.3 54.44,81.51 54.44,81.81 54.65,82.02 55.18,82.02 v2(55.2,82)
  BOTTOM w0.102: UC1.A38 105.31,65.16 105.31,65.16 105.31,65.22 105.32,65.23 105.32,65.99 105.31,65.99 105.31,66.99 105.04,67.26 v2(104.86,67.26) ; JDIMM1.20 61.04,82.37 60.82,82.16 60.37,82.16 60.14,81.93 57.32,81.93 57.22,81.83 57.22,81.16 57.11,81.06 56.89,81.06 56.79,81.16 56.79,81.55 56.69,81.65 56.48,81.65 56.38,81.55 56.38,81.16 56.27,81.06 56.07,81.06 55.97,81.16 55.97,81.55 55.87,81.65 55.68,81.65 55.58,81.55 55.58,81.13 55.51,81.06 55.29,81.06 55.19,81.16 55.19,81.45 55.09,81.55 54.6,81.55 54.5,81.65 54.5,81.9 54.61,82 v2(55.2,82) ; JDIMM2.20 46.39,82.87 v2(46.76,82.5)
DDRAB_SDQ3: length 104.5
  IN1 w0.211: v2(59.39,82.87) 61.76,82.87 61.92,82.71 63.8,82.71 63.93,82.84 63.93,83.05 64.05,83.18 65.12,83.18 65.25,83.05 65.25,82.67 65.37,82.54 66.2,82.54 v2(66.78,83.11)
  IN2 w0.211: v2(104.93,66.33) 104.42,66.84 104.42,68.29 104.19,68.53 104.19,69.52 103.98,69.73 103.2,69.73 102.99,69.94 102.99,70.37 103.2,70.58 103.98,70.58 104.19,70.79 104.19,71.21 103.98,71.42 101.64,71.42 101.43,71.63 101.43,72.05 101.64,72.26 103.98,72.26 104.19,72.47 104.19,73.32 105.32,74.45 105.32,77.51 103.3,79.53 99.24,79.53 99.03,79.32 99.03,78.27 98.81,78.06 98.39,78.06 98.18,78.27 98.18,78.91 97.7,79.39 96.04,79.39 95.83,79.18 95.83,78.08 95.62,77.87 95.2,77.87 94.99,78.08 94.99,78.98 94.78,79.19 94.28,79.19 93.76,79.7 93.76,80.42 93.01,81.17 92.72,81.17 92.28,80.73 91.98,80.73 91.68,81.03 91.68,81.33 91.9,81.55 91.9,82 91.52,82.38 89.56,82.38 89.35,82.58 89.35,82.96 89.14,83.17 88.85,83.17 88.64,82.96 88.64,82.33 88.43,82.11 88,82.11 87.79,82.33 87.79,82.96 87.58,83.17 87.24,83.17 87.03,82.96 87.03,82.33 86.82,82.11 86.4,82.11 86.19,82.33 86.19,82.96 85.98,83.17 72.38,83.17 71.97,83.58 66.58,83.58 66.41,83.74 64.59,83.74 64.18,84.15 61.2,84.15 60.4,83.35 59.87,83.35 v2(59.39,82.87)
  BOTTOM w0.102: v2(59.39,82.87) 59.49,82.97 59.96,82.97 60.07,82.87 60.07,82.34 59.96,82.24 59.08,82.24 58.98,82.34 58.98,82.87 58.88,82.97 58.67,82.97 58.57,82.87 58.57,82.34 58.47,82.24 58.27,82.24 58.17,82.34 58.17,82.87 58.07,82.97 57.86,82.97 57.76,82.87 57.76,82.34 57.66,82.24 57.19,82.24 56.91,81.96 55.75,81.96 55.59,82.11 55.59,82.38 55.5,82.47 54.59,82.47 54.38,82.25 54.12,82.25 54,82.37 54,82.52 53.89,82.62 JDIMM2.21 ; JDIMM1.21 67.76,82.13 v2(66.78,83.11) ; v2(104.93,66.33) 105.08,66.18 105.08,64.67 105,64.58 105,64.33 105.09,64.24 105.09,63.98 UC1.B38
DDRAB_SDQ4: length 101.4
  IN1 w0.211: v2(54.99,86.37) 53.86,86.37 53.44,86.79 53.44,87.11 53.23,87.32 52.81,87.32 52.6,87.11 52.6,86.74 52.39,86.53 51.23,86.53 50.88,86.88 v2(46.55,86.88)
  IN2 w0.211: v2(108.51,67.19) 108.8,67.48 108.8,68.36 110.97,70.52 110.97,78.6 110.97,79.03 104.44,85.56 102.24,87.76 102.23,87.76 94.33,87.76 92.44,89.66 75.75,89.66 74.55,90.86 59.36,90.86 54.99,86.48 v2(54.99,86.37)
  BOTTOM w0.102: JDIMM1.4 60.9,86.37 60.78,86.5 60.78,88.12 60.68,88.22 60.47,88.22 60.37,88.12 60.37,86.43 60.27,86.33 60.07,86.33 59.96,86.43 59.96,87.04 59.86,87.14 59.66,87.14 59.56,87.04 59.56,86.53 59.4,86.37 v2(54.99,86.37) ; v2(108.51,67.19) 108.51,67.13 108.03,66.65 108.03,64.84 UC1.A33 ; JDIMM2.4 v2(46.55,86.88)
DDRAB_SDQ5: length 104.5
  IN1 w0.211: v2(59.35,88.13) 60.87,86.62 67.28,86.62 v2(68.26,85.64)
  IN2 w0.211: v2(107.93,67.09) 107.7,67.31 107.7,68.72 109.93,70.95 109.93,75.36 109.35,75.94 109.35,79.18 101.81,86.73 93.42,86.73 92.43,87.72 91.31,87.72 90.95,88.08 90.34,88.08 90.05,87.78 89.62,87.78 89.41,87.99 89.41,88.35 89.2,88.56 88.78,88.56 88.57,88.35 88.57,87.99 88.36,87.78 87.94,87.78 87.73,87.99 87.73,88.35 87.52,88.56 87.09,88.56 86.88,88.35 86.88,87.99 86.67,87.78 86.25,87.78 86.04,87.99 86.04,88.35 85.83,88.56 85.41,88.56 85.2,88.35 85.2,87.99 84.99,87.78 84.56,87.78 84.35,87.99 84.35,88.35 84.14,88.56 83.72,88.56 83.51,88.35 83.51,87.76 83.3,87.55 82.88,87.55 82.67,87.76 82.67,88.35 82.46,88.56 82.03,88.56 81.82,88.35 81.82,88.06 81.61,87.84 81.19,87.84 80.98,88.06 80.98,88.35 80.77,88.56 80.43,88.56 80.22,88.35 80.22,87.74 80.01,87.53 79.59,87.53 79.38,87.74 79.38,88.35 79.17,88.56 75.39,88.56 74.83,89.13 74.13,89.83 59.93,89.83 59.61,89.5 59.61,88.39 v2(59.35,88.13)
  BOTTOM w0.102: JDIMM1.3 69.24,86.62 v2(68.26,85.64) ; UC1.B33 107.84,64.33 107.84,64.59 107.75,64.68 107.75,65.04 107.83,65.13 107.83,66.99 v2(107.93,67.09) ; v2(59.35,88.13) 58.85,88.13 58.63,88.35 56.91,88.35 56.81,88.24 56.81,87.88 56.71,87.78 56.5,87.78 56.4,87.88 56.4,88.24 56.3,88.35 56.1,88.35 56,88.24 56,87.35 55.89,87.25 55.69,87.25 55.59,87.35 55.59,88.24 55.49,88.35 55.28,88.35 55.18,88.24 55.18,87.35 55.08,87.25 54.88,87.25 54.78,87.35 54.78,88.24 54.68,88.35 54.47,88.35 54.37,88.24 54.37,87.35 54.27,87.25 54.04,87.25 53.92,87.13 JDIMM2.3
DDRAB_SDQ6: length 101.4
  IN1 w0.211: v2(54.76,83.12) 54.44,82.8 53.76,82.8 53.55,83.02 53.55,83.26 53.34,83.47 52.93,83.47 52.7,83.25 52.7,83.02 52.49,82.8 51.47,82.8 50.5,83.77 v2(46.82,83.77)
  IN2 w0.211: v2(54.76,83.12) 54.69,83.05 54.69,82.75 54.9,82.54 55.68,82.54 55.89,82.75 55.89,82.98 56.1,83.19 56.52,83.19 56.73,82.98 56.73,82.75 56.94,82.54 57.28,82.54 60.61,85.87 62.2,85.87 62.43,86.1 64.41,86.1 64.81,85.71 64.81,85.71 65.23,85.29 67.05,85.29 67.22,85.12 69.37,85.12 69.59,85.33 69.59,85.53 69.8,85.74 70.22,85.74 70.43,85.53 70.43,85.33 70.64,85.12 71.33,85.12 71.33,85.12 72.61,85.12 72.73,85.01 91.62,85.01 92.39,84.24 95.05,84.24 95.26,84.03 95.26,83.23 95.47,83.02 95.89,83.02 96.1,83.23 96.1,84.03 96.31,84.24 96.74,84.24 96.95,84.03 96.95,83.23 97.16,83.02 97.58,83.02 97.79,83.23 97.79,84.03 98,84.24 98.42,84.24 98.63,84.03 98.63,83.23 98.84,83.02 100.52,83.02 100.74,83.24 100.74,83.52 100.91,83.69 101.33,83.69 106.86,78.15 106.86,73.81 105.73,72.68 v2(105.73,71.12)
  BOTTOM w0.102: 104.8,68.6 104.8,68.59 105.4,67.99 105.4,67.71 105.81,67.3 105.81,64.86 UC1.A37 ; JDIMM2.16 46.72,83.87 v2(46.82,83.77) ; v2(54.76,83.12) 54.76,82.9 54.88,82.77 56.1,82.77 56.24,82.63 56.24,82.36 56.34,82.26 56.54,82.26 56.64,82.36 56.64,83.17 56.74,83.27 56.95,83.27 57.05,83.17 57.05,82.64 57.15,82.54 57.35,82.54 57.46,82.64 57.46,83.17 57.56,83.27 60.27,83.27 60.37,83.17 60.37,82.58 60.49,82.46 60.66,82.46 60.78,82.58 60.78,83.25 60.9,83.37 JDIMM1.16
  BOTTOM w0.163: 104.8,68.6 104.8,70.18 v2(105.73,71.12)
DDRAB_SDQ7: length 104.7
  IN1 w0.211: v2(60.1,83.88) 63.33,83.88 63.54,84.09 63.54,84.95 63.67,85.07 64.26,85.07 64.38,84.95 64.38,84.44 64.94,83.88 67.5,83.88 v2(68.27,83.11)
  IN2 w0.211: v2(60.1,83.88) 60.89,84.66 64.39,84.66 64.8,84.26 66.62,84.26 66.79,84.09 71.76,84.09 72.18,84.09 72.3,83.97 73.22,83.97 73.22,83.98 73.77,83.98 74.06,83.68 91.23,83.68 93.22,81.69 93.52,81.69 93.76,81.94 94.06,81.94 94.36,81.64 94.36,81.34 94.28,81.26 94.28,80.64 94.28,80.64 94.28,80.07 94.57,79.78 94.92,79.78 95.2,80.06 95.2,81.78 95.41,81.99 95.75,81.99 95.98,81.75 95.98,80.37 96.19,80.16 96.62,80.16 96.83,80.37 96.83,81.78 97.04,81.99 97.35,81.99 97.59,81.75 97.59,80.1 97.8,79.89 98.22,79.89 98.43,80.1 98.43,81.78 98.64,81.99 99.04,81.99 99.25,81.78 99.25,80.26 99.46,80.05 99.82,80.05 100.09,80.32 100.09,81.78 100.3,81.99 100.72,81.99 100.93,81.78 100.93,80.26 101.15,80.05 101.57,80.05 101.78,80.26 101.78,80.94 101.99,81.15 102.41,81.15 102.62,80.94 102.62,80.26 102.83,80.05 103.51,80.05 105.83,77.73 105.83,74.24 104.7,73.11 104.7,69.71 105.03,69.38 105.03,68.13 v2(104.88,67.97)
  BOTTOM w0.102: JDIMM1.17 68.28,83.13 v2(68.27,83.11) ; UC1.B37 105.64,64.33 105.64,64.59 105.55,64.68 105.55,67.08 105.21,67.42 105.21,67.64 v2(104.88,67.97) ; v2(60.1,83.88) 59.68,83.88 59.56,84.01 59.56,84.37 59.43,84.5 59.28,84.5 59.15,84.37 59.15,83.91 59.02,83.79 58.77,83.79 58.64,83.91 58.64,84.44 58.52,84.56 58.36,84.56 58.24,84.44 58.24,83.91 58.12,83.79 57.95,83.79 57.83,83.91 57.83,84.44 57.71,84.56 57.54,84.56 57.42,84.44 57.42,83.91 57.3,83.79 57.14,83.79 57.02,83.91 57.02,84.44 56.9,84.56 56.73,84.56 56.61,84.44 56.61,83.7 56.49,83.58 56.32,83.58 55.49,83.58 54.69,83.58 54.65,83.62 JDIMM2.17
DDRAB_SDQ8: length 85
  IN1 w0.211: v2(47.57,80.87) 49.44,80.87 49.56,80.75 49.56,80.16 49.69,80.03 50.08,80.03 50.21,80.16 50.21,80.74 50.34,80.87 50.79,80.87 50.92,80.74 50.92,80.6 51.05,80.47 54.13,80.47 54.48,80.13 v2(54.51,80.13)
  IN2 w0.211: v2(54.51,80.13) 54.66,80.13 54.92,80.39 55.57,80.39 56.66,81.48 57.71,81.48 58.63,82.41 59.66,82.41 60.09,82.83 60.62,82.83 61.42,83.63 63.97,83.63 64.37,83.23 65.93,83.23 66.5,82.65 85.07,82.65 86.13,81.6 90.38,81.6 96.15,75.82 96.16,75.82 103.84,68.14 103.84,66.36 v2(103.2,65.72)
  BOTTOM w0.102: JDIMM1.28 61.12,80.37 60.47,81.02 60,81.02 59.81,80.83 59.81,80.24 59.71,80.14 58.37,80.14 58.27,80.04 58.27,79.69 58.17,79.58 57.5,79.58 56.82,78.91 56.51,78.91 56.41,79.01 56.41,79.42 56.31,79.52 56.11,79.52 56,79.42 56,79.01 55.9,78.91 55.7,78.91 55.6,79.01 55.6,79.42 55.5,79.52 55.29,79.52 55.19,79.42 55.19,79.01 55.09,78.91 54.84,78.91 54.71,79.04 54.71,79.93 v2(54.51,80.13) ; UC1.B41 103.36,65.56 v2(103.2,65.72) ; JDIMM2.28 v2(47.57,80.87)
DDRAB_SDQ9: length 87.9
  IN1 w0.211: v2(60.22,80.61) 60.32,80.51 65.18,80.51 65.39,80.72 65.39,81.02 65.6,81.23 66.03,81.23 66.24,81.02 66.24,80.62 66.45,80.41 66.75,80.41 v2(66.97,80.64)
  IN2 w0.211: v2(102.57,65.23) 102.32,65.48 102.32,67.47 96.66,73.13 95.22,73.13 94.44,73.91 94.44,74.95 94.23,75.16 93.56,75.16 90.38,78.34 89.38,78.34 89.17,78.55 89.17,78.9 88.96,79.11 88.54,79.11 88.32,78.9 88.32,78.55 88.11,78.34 87.69,78.34 87.48,78.55 87.48,78.9 87.27,79.11 86.85,79.11 86.64,78.9 86.64,78.55 86.43,78.34 86.01,78.34 85.79,78.55 85.79,78.9 85.58,79.11 85.16,79.11 84.95,78.9 84.95,78.55 84.74,78.34 84.4,78.34 84.19,78.55 84.19,78.86 83.98,79.08 83.56,79.08 83.35,78.86 83.35,78.08 83.14,77.87 82.27,77.87 82.06,78.08 82.06,79.09 81.85,79.31 81.43,79.31 81.22,79.09 81.22,78.48 81.01,78.27 80.59,78.27 80.38,78.48 80.38,79.12 80.17,79.33 79.75,79.33 79.53,79.12 79.53,78.48 79.32,78.27 78.99,78.27 78.77,78.48 78.77,79.18 78.56,79.39 78.14,79.39 77.93,79.18 77.93,78.48 77.72,78.27 77.07,78.27 74.83,80.51 72.12,80.51 71.52,81.11 70.95,81.11 70.64,80.8 69.03,80.8 68.73,81.11 65.86,81.11 65.59,81.38 63.79,81.38 63.5,81.68 63.11,81.68 62.81,81.37 61.35,81.37 61.21,81.23 60.85,81.23 60.23,80.61 v2(60.22,80.61)
  BOTTOM w0.102: JDIMM1.29 67.11,80.13 66.97,80.26 v2(66.97,80.64) ; v2(102.57,65.23) 103,64.8 103,64.06 103.24,63.82 103.65,63.82 UC1.C40 ; v2(60.22,80.61) 60.26,80.57 60.26,79.37 60.15,79.27 59.89,79.27 59.79,79.37 59.79,79.74 59.69,79.84 59.49,79.84 59.39,79.74 59.39,79.33 59.28,79.23 59.08,79.23 58.98,79.33 58.98,79.74 58.88,79.84 58.67,79.84 58.57,79.74 58.57,79.33 58.47,79.23 57.58,79.23 56.95,78.61 54.62,78.61 54.41,78.82 54.41,79.62 54.1,79.93 54.1,80.26 53.74,80.62 JDIMM2.29
DDRAB_SDQ10: length 88.5
  IN1 w0.211: v2(68.44,76.86) 67.85,77.45 66.9,77.45 66.77,77.58 66.77,78.07 66.64,78.2 65.88,78.2 65.76,78.07 65.76,77.58 65.63,77.45 61.48,77.45 60.88,76.85 59.9,76.85 v2(59.81,76.94)
  IN2 w0.211: v2(59.81,76.94) 62.08,76.94 62.59,77.45 63.42,77.45 63.83,77.04 64.95,77.04 65.19,76.81 66.07,76.81 66.56,76.32 67.88,76.32 67.96,76.4 70.29,76.4 70.58,76.11 74.25,76.11 78.34,72.03 78.84,72.03 79.05,71.82 79.05,71.57 79.26,71.36 79.68,71.36 79.89,71.57 79.89,72.58 80.1,72.79 80.53,72.79 80.74,72.58 80.74,71.57 80.95,71.36 81.37,71.36 81.58,71.57 81.58,72.72 81.79,72.93 82.13,72.93 82.34,72.72 82.34,71.57 82.55,71.36 82.97,71.36 83.18,71.57 83.18,72.72 83.39,72.93 83.82,72.93 84.03,72.72 84.03,71.59 84.24,71.37 85.53,71.37 85.74,71.59 85.74,72.72 85.95,72.93 86.37,72.93 86.58,72.72 86.58,71.59 86.79,71.37 87.13,71.37 87.34,71.59 87.34,72.65 87.55,72.86 87.97,72.86 88.18,72.65 88.18,71.38 89.02,70.54 89.32,70.54 89.44,70.67 89.74,70.67 89.95,70.46 89.95,69.61 90.81,68.76 96.06,68.76 100.39,64.43 v2(100.39,64.43)
  BOTTOM w0.102: UC1.F41 103.06,61.76 102.89,61.93 102.22,61.93 100.39,63.77 v2(100.39,64.43) ; v2(59.81,76.94) 59.7,77.05 59.34,77.05 59.25,76.96 59.25,75.84 59.06,75.65 58.91,75.65 58.81,75.75 58.81,76.95 58.71,77.05 58.48,77.05 58.38,76.95 58.38,75.75 58.28,75.65 57.45,75.65 57.35,75.75 57.35,76.17 57.07,76.44 56.77,76.44 55.76,77.45 54.11,77.45 53.93,77.62 JDIMM2.41 ; v2(68.44,76.86) 68.48,76.86 68.75,77.13 JDIMM1.41
DDRAB_SDQ11: length 84.5
  IN1 w0.211: v2(46.86,77.49) 47.3,77.04 47.7,77.04 47.91,77.25 47.91,77.7 48.12,77.91 48.54,77.91 48.75,77.7 48.75,77.25 48.96,77.04 v2(54.69,77.04)
  IN2 w0.211: v2(101.68,61.93) 101.92,62.17 102.45,62.17 102.66,62.38 102.66,62.81 101.7,63.77 101.7,65.28 100.41,66.57 100.41,66.59 96.33,70.68 93.25,70.68 90.87,73.06 90.87,74.04 89.36,75.55 77.01,75.55 74.46,78.09 74.24,78.09 71.75,78.09 71.04,78.09 70.77,78.35 65.83,78.35 65.18,79 65.05,79.14 64.78,79.4 62.65,79.4 62.65,79.4 62.16,79.4 61.56,78.79 61.32,78.55 59.95,78.55 58.9,77.51 57.36,77.51 57.13,77.74 54.84,77.74 54.57,77.47 54.57,77.17 v2(54.69,77.04)
  BOTTOM w0.102: JDIMM2.42 46.74,77.38 v2(46.86,77.49) ; UC1.G40 103.84,61.43 103.59,61.43 103.49,61.53 103.49,61.53 103.46,61.56 102.98,61.56 102.97,61.56 102.86,61.56 102.79,61.63 101.98,61.63 v2(101.68,61.93) ; JDIMM1.42 60.97,76.88 60.87,76.77 60.87,76.28 60.76,76.18 59.96,76.18 59.86,76.08 59.86,75.43 59.72,75.29 59.56,75.29 59.31,75.04 57.2,75.04 56.19,76.04 55.87,76.04 55.8,76.12 55.8,76.37 55.66,76.51 55.52,76.51 55.38,76.37 55.38,76.17 55.28,76.07 54.82,76.07 54.82,76.07 54.58,76.07 54.48,76.17 54.48,76.94 54.58,77.04 v2(54.69,77.04)
DDRAB_SDQ12: length 85.3
  IN1 w0.211: v2(46.86,81.35) 46.9,81.39 51.23,81.39 51.59,81.03 54.01,81.03 54.29,81.3 54.67,81.3 55.19,80.78 v2(55.19,79.93)
  IN2 w0.211: v2(55.19,79.93) 55.19,79.58 55.4,79.37 56.45,79.37 56.66,79.58 56.66,80.76 56.87,80.97 57.92,80.97 58.84,81.89 59.87,81.89 60.3,82.31 60.83,82.31 60.93,82.41 61.23,82.71 62.08,82.71 65.72,82.71 66.02,82.41 66.29,82.14 72.5,82.14 72.71,81.93 72.71,81.8 72.92,81.59 73.34,81.59 73.55,81.8 73.55,81.93 73.76,82.14 82.38,82.14 82.59,81.93 82.59,81.74 82.8,81.53 83.23,81.53 83.44,81.74 83.44,81.93 83.65,82.14 84.86,82.14 85.91,81.08 90.17,81.08 96.48,74.77 96.48,74.77 103.39,67.86 v2(103.39,67.44)
  BOTTOM w0.102: JDIMM2.24 46.33,81.87 v2(46.86,81.35) ; v2(103.39,67.44) 103.96,66.87 103.96,64.81 UC1.A40 ; JDIMM1.24 60.7,81.37 60.64,81.32 59.61,81.32 59.51,81.22 59.51,80.55 59.41,80.45 58.06,80.45 57.96,80.35 57.96,79.99 57.86,79.89 57.56,79.89 57.46,79.99 57.46,80.35 57.36,80.45 57.15,80.45 57.05,80.35 57.05,79.59 56.95,79.49 56.77,79.49 56.64,79.62 56.64,80.35 56.54,80.45 56.34,80.45 56.24,80.35 56.24,79.93 56.14,79.82 55.93,79.82 55.83,79.93 55.83,80.35 55.73,80.45 55.05,80.45 54.94,80.35 54.94,80.13 55.14,79.93 v2(55.19,79.93)
DDRAB_SDQ13: length 87.9
  IN1 w0.211: v2(60.54,81.75) 63.84,81.75 63.96,81.62 63.96,81.17 64.09,81.04 64.65,81.04 64.78,81.17 64.78,81.62 64.9,81.75 67.37,81.75 v2(68.47,80.65)
  IN2 w0.211: v2(103.41,66.81) 102.85,66.81 102.64,67.02 102.64,67.89 96.88,73.65 96.3,73.65 95.6,74.35 95.6,74.92 93.99,76.53 93.69,76.53 93.45,76.3 93.15,76.3 92.86,76.59 92.86,76.89 93.09,77.13 93.09,77.43 92.79,77.73 92.5,77.73 92.26,77.49 91.96,77.49 91.66,77.79 91.66,78.09 91.9,78.32 91.9,78.62 91.66,78.86 91.36,78.86 91.13,78.62 90.83,78.62 90.53,78.92 90.53,79.22 90.77,79.46 90.77,79.75 89.95,80.57 89.62,80.57 89.4,80.36 89.4,79.83 89.19,79.62 88.77,79.62 88.56,79.83 88.56,80.36 88.35,80.57 87.93,80.57 87.72,80.36 87.72,80.03 87.51,79.82 87.17,79.82 86.96,80.03 86.96,80.33 86.75,80.54 86.33,80.54 86.11,80.33 86.11,80.03 85.9,79.82 83.97,79.82 83.76,80.03 83.76,80.39 83.54,80.6 83.12,80.6 82.91,80.39 82.91,80.03 82.7,79.82 81.74,79.82 80.54,81.03 80.2,81.03 79.99,80.82 79.99,80.18 79.78,79.96 79.36,79.96 79.15,80.18 79.15,80.82 78.93,81.03 78.51,81.03 78.3,80.82 78.3,80.18 78.09,79.96 77.67,79.96 77.46,80.18 77.46,80.82 77.25,81.03 72.33,81.03 71.74,81.62 70.73,81.62 70.43,81.32 69.25,81.32 68.94,81.62 66.08,81.62 65.5,82.19 65.18,82.19 64.88,81.9 64.13,81.9 63.83,82.19 62.9,82.19 62.6,81.89 62.04,81.89 61.74,82.19 61.44,82.19 61.14,81.9 60.99,81.75 v2(60.54,81.75)
  BOTTOM w0.102: v2(68.47,80.65) 68.47,80.9 68.7,81.13 JDIMM1.25 ; v2(103.41,66.81) 103.6,66.61 103.6,64.57 UC1.B40 ; JDIMM2.25 53.74,81.62 54.12,81.25 54.78,81.25 54.88,81.15 54.88,80.85 54.99,80.75 57.42,80.75 57.52,80.85 57.52,81.53 57.62,81.63 57.83,81.63 57.93,81.53 57.93,80.85 58.03,80.75 58.23,80.75 58.33,80.85 58.33,81.53 58.43,81.63 58.64,81.63 58.74,81.53 58.74,80.85 58.84,80.75 59.1,80.75 59.2,80.85 59.2,81.55 59.28,81.63 60.42,81.63 v2(60.54,81.75)
DDRAB_SDQ14: length 84.5
  IN1 w0.211: v2(55.34,77.03) 55.34,77.1 54.63,77.81 51.53,77.81 50.9,78.44 v2(46.86,78.44)
  IN2 w0.211: v2(55.34,77.03) 55.46,77.03 55.67,76.82 55.67,76.33 55.91,76.09 56.37,76.09 56.54,76.26 56.54,76.8 56.68,76.94 59.07,76.94 60.12,78 60.15,78 60.15,78 61.49,78 61.56,78.07 61.56,78.07 61.77,78.28 62.07,78.58 62.38,78.89 62.86,78.89 64.56,78.89 64.83,78.62 64.97,78.48 65.61,77.84 67.07,77.84 67.08,77.83 67.26,77.83 67.27,77.84 70.56,77.84 70.82,77.57 71.54,77.57 71.54,77.57 74.25,77.57 76.79,75.03 81.71,75.03 81.92,74.82 81.92,74.69 82.13,74.48 82.55,74.48 82.76,74.69 82.76,74.82 82.97,75.03 83.39,75.03 83.61,74.82 83.61,74.69 83.82,74.48 84.24,74.48 84.45,74.69 84.45,74.82 84.66,75.03 86.02,75.03 86.57,74.48 86.95,74.48 87.5,75.03 87.92,75.03 88.13,74.82 88.13,74.17 88.34,73.96 88.7,73.96 88.91,74.17 88.91,74.43 89.12,74.64 89.54,74.64 90.35,73.83 90.35,72.84 91.57,71.63 91.57,71.27 91.32,71.02 91.32,70.72 91.62,70.42 91.91,70.42 92.16,70.67 92.52,70.67 93.08,70.12 96.16,70.12 101.11,65.17 v2(101.11,64.95)
  BOTTOM w0.102: v2(101.11,64.95) 101.11,64.95 101.15,64.91 101.15,63.66 102.47,62.34 103.21,62.34 103.23,62.31 UC1.E41 ; JDIMM2.38 46.79,78.38 v2(46.86,78.44) ; v2(55.34,77.03) 55.7,77.03 56.76,75.96 56.92,75.96 57.04,75.84 57.04,75.62 57.32,75.34 59.18,75.34 59.55,75.71 59.55,76.38 59.66,76.48 60.44,76.48 60.54,76.59 60.54,76.73 60.42,76.85 60.42,76.99 60.51,77.08 60.68,77.08 60.73,77.13 60.73,77.61 60.41,77.92 60.41,78.33 60.5,78.42 60.68,78.42 60.78,78.31 60.78,78.1 61,77.88 JDIMM1.38
DDRAB_SDQ15: length 88.4
  IN1 w0.211: v2(60.32,77.44) 60.85,77.97 63.6,77.97 63.72,78.09 63.72,78.89 63.85,79.01 64.31,79.01 64.43,78.89 64.43,78.63 64.56,78.5 65.02,78.5 65.15,78.63 65.15,78.89 65.27,79.01 67.28,79.01 v2(67.48,78.81)
  IN2 w0.211: v2(60.32,77.44) 60.37,77.49 61.89,77.49 62.37,77.97 63.63,77.97 63.92,77.68 64.22,77.68 64.48,77.94 64.78,77.94 65.4,77.32 66.86,77.32 66.86,77.32 67.47,77.32 67.48,77.32 68.63,77.32 69.04,76.92 69.62,76.92 70.02,77.32 70.35,77.32 71.04,76.63 72.14,76.63 72.35,76.84 72.35,76.85 72.56,77.06 73.09,77.06 73.3,76.85 73.3,76.84 73.51,76.63 74.47,76.63 76.58,74.51 77.73,74.51 77.94,74.3 77.94,73.15 78.15,72.94 78.58,72.94 78.79,73.15 78.79,74.3 79,74.51 79.37,74.51 79.59,74.3 79.59,73.52 79.8,73.3 80.18,73.3 80.39,73.52 80.39,74.3 80.6,74.51 81.02,74.51 81.23,74.3 81.23,73.66 81.44,73.45 81.86,73.45 82.08,73.66 82.08,73.75 82.29,73.96 82.71,73.96 82.92,73.75 82.92,73.66 83.13,73.45 83.55,73.45 83.76,73.66 83.76,73.75 83.97,73.96 84.33,73.96 84.55,73.75 84.55,73.13 84.76,72.92 85.18,72.92 85.39,73.13 85.39,74.05 85.6,74.26 86.06,74.26 86.28,74.04 86.28,73.64 86.49,73.43 86.91,73.43 87.12,73.64 87.12,73.72 87.33,73.93 87.63,73.93 88.34,73.23 88.61,73.23 88.78,73.4 89.07,73.4 89.28,73.19 89.28,72.99 89.08,72.79 89.08,72.49 89.6,71.97 89.89,71.97 90.05,72.12 90.35,72.12 90.64,71.82 90.64,71.53 90.49,71.37 90.49,71.08 90.8,70.76 90.8,70.46 90.46,70.13 90.46,69.83 90.91,69.38 91.21,69.38 91.72,69.89 92.01,69.89 92.58,69.32 93.19,69.32 93.47,69.61 93.98,69.61 94.32,69.27 94.83,69.27 95.16,69.61 95.94,69.61 v2(100.46,65.09)
  BOTTOM w0.102: v2(67.48,78.81) 68.17,78.13 JDIMM1.37 ; UC1.F40 104.19,61.98 103.93,61.98 103.84,62.07 103.57,62.07 103.49,61.99 103.18,61.99 103.1,62.07 103.04,62.07 102.97,62.13 102.39,62.13 100.77,63.75 100.77,64.78 v2(100.46,65.09) ; JDIMM2.37 53.74,78.62 54.1,78.26 54.1,77.95 54.3,77.76 55.93,77.76 56.3,77.39 56.69,77.39 56.79,77.28 56.79,76.85 56.9,76.75 57.1,76.75 57.2,76.85 57.2,77.28 57.3,77.39 57.54,77.39 57.67,77.26 57.67,76.13 57.77,76.03 57.97,76.03 58.07,76.13 58.07,77.26 58.18,77.36 60.24,77.36 v2(60.32,77.44)
DDRAB_SDQ16: length 81
  IN1 w0.211: v2(46.76,74.85) 46.92,75.01 47.84,75.01 48.05,74.8 48.05,74.63 48.29,74.39 48.64,74.39 48.89,74.64 48.89,74.8 49.1,75.01 54.36,75.01 v2(54.83,74.54)
  IN2 w0.211: v2(54.83,74.54) 55.63,74.54 57.52,76.43 62.29,76.43 62.39,76.53 64.58,76.53 64.81,76.29 65.86,76.29 66.35,75.8 68.09,75.8 68.17,75.88 70.08,75.88 70.36,75.6 74.04,75.6 78.79,70.84 87.99,70.84 90.59,68.24 95.85,68.24 100.86,63.23 v2(100.86,62.25)
  BOTTOM w0.102: JDIMM1.50 61.07,74.88 60.87,74.67 60.87,73.97 60.56,73.67 60.56,73.29 60.25,72.97 59.34,72.97 58.78,72.42 57.81,72.42 57.69,72.55 57.69,73.04 57.41,73.32 55.6,73.32 55.43,73.49 55.43,74.12 55.24,74.3 55.24,74.71 55,74.95 54.54,74.95 54.38,74.78 54.38,74.64 54.47,74.54 v2(54.83,74.54) ; UC1.J40 103.79,60.11 103.49,60.41 103.12,60.41 103.09,60.39 101.97,60.39 100.86,61.51 v2(100.86,62.25) ; JDIMM2.50 46.23,75.38 v2(46.76,74.85)
DDRAB_SDQ17: length 84.2
  IN1 w0.211: v2(58.33,73.99) 62.78,73.99 63.69,74.9 v2(68.71,74.9)
  IN2 w0.211: v2(99.4,62.31) 99.32,62.39 99.32,63.31 95.42,67.21 89.17,67.21 88.96,67.42 88.96,68.41 88.75,68.62 88.33,68.62 88.12,68.41 88.12,67.52 87.81,67.21 87.23,67.21 87.02,67.42 87.02,68.45 87.75,69.18 87.75,69.48 87.41,69.81 78.37,69.81 74.02,74.16 69.56,74.16 69.3,74.42 65.77,74.42 65.33,74.85 65.1,75.09 64.55,75.09 64.25,75.39 64.15,75.5 62.82,75.5 62.72,75.4 59.3,75.4 59.04,75.14 59.04,75.02 58.78,74.76 58.34,74.76 58,75.1 57.65,75.1 57.24,74.7 57.24,74.31 57.45,74.1 58.22,74.1 v2(58.33,73.99)
  BOTTOM w0.102: v2(58.33,73.99) 58.42,73.91 58.74,73.91 58.82,73.98 58.82,74.09 58.72,74.19 58.72,74.34 58.81,74.43 59.18,74.43 59.33,74.28 59.33,74.15 59.21,74.03 59.21,73.7 59.09,73.58 58.61,73.58 58.52,73.49 58.52,73.35 58.46,73.3 58.29,73.3 58.01,73.58 58.01,73.66 57.74,73.93 56.51,73.93 56.41,74.03 56.41,74.96 56.25,75.12 56.1,75.12 56,75.02 56,74.74 55.9,74.64 55.65,74.64 55.54,74.74 55.54,74.87 55.34,75.08 55.34,75.15 55.24,75.25 54.79,75.25 54.62,75.42 54.48,75.42 54.3,75.24 54.12,75.24 54.01,75.35 54.01,75.52 53.91,75.62 JDIMM2.49 ; UC1.J41 100.9,60.11 100.32,60.69 100.32,60.84 100.46,60.98 100.46,61.12 100.32,61.27 100.17,61.27 100.06,61.16 99.92,61.16 99.4,61.68 v2(99.4,62.31) ; v2(68.71,74.9) 68.94,75.13 JDIMM1.49
DDRAB_SDQ18: length 81.1
  IN1 w0.211: v2(46.86,72.38) 47.21,72.03 52.89,72.03 53.38,71.54 55.83,71.54 v2(55.88,71.6)
  IN2 w0.211: v2(100.92,58.84) 101.11,59.03 101.11,59.43 100.68,59.86 100.22,59.86 98.14,61.94 95.91,61.94 93.76,64.09 92.87,64.09 92.66,63.88 92.66,63.78 92.45,63.57 91.91,63.57 91.76,63.72 91.76,63.93 91.6,64.09 83.66,64.09 82.78,64.97 82.27,64.97 82.03,64.72 80.83,64.72 80.62,64.94 80.62,65.09 80.41,65.3 79.99,65.3 79.78,65.09 79.78,64.94 79.57,64.72 79.21,64.72 73.1,70.83 71.62,70.83 71.18,70.39 70.62,70.39 70.17,70.83 68.08,70.83 68.08,70.84 66.39,70.84 65.85,71.38 64.32,71.38 63.9,71.38 63.86,71.42 63.85,71.42 63.49,71.78 62.96,71.78 62.82,71.65 62.28,71.65 61.84,72.08 61.84,72.09 61.53,72.4 60.04,72.4 59.04,71.4 56.08,71.4 v2(55.88,71.6)
  BOTTOM w0.102: v2(55.88,71.6) 55.68,71.4 55.68,71.25 55.78,71.15 55.97,71.15 56.07,71.05 56.07,70.78 56.18,70.68 56.38,70.68 56.48,70.78 56.48,71.25 56.58,71.35 56.79,71.35 56.89,71.25 56.89,70.64 56.79,70.54 56.76,70.54 56.65,70.43 56.65,70.24 56.77,70.12 57.22,70.12 57.29,70.19 57.29,70.97 57.4,71.07 57.6,71.07 57.68,71 57.68,70.52 57.78,70.41 57.97,70.41 58.07,70.52 58.07,70.85 58.17,70.95 59.48,70.95 59.67,71.13 59.67,71.31 59.56,71.43 59.56,71.9 59.66,72 60.18,72 60.27,71.91 60.27,71.87 60.37,71.77 60.56,71.77 60.66,71.87 60.66,71.91 60.76,72.01 61,72.01 61.13,71.88 JDIMM1.62 ; UC1.N40 103.84,58.13 103.58,58.13 103.49,58.22 103.24,58.22 103.02,58 101.61,58 100.92,58.69 v2(100.92,58.84) ; JDIMM2.62 v2(46.86,72.38)
DDRAB_SDQ19: length 83.5
  IN1 w0.211: v2(68.47,71.81) 68.04,71.38 67.42,71.38 67.21,71.59 67.21,71.68 67,71.89 66.57,71.89 66.36,71.68 66.36,71.59 66.15,71.38 65.73,71.38 65.52,71.59 65.52,71.68 65.31,71.89 64.89,71.89 64.68,71.68 64.68,71.59 64.47,71.38 64,71.38 63.48,71.89 61.12,71.89 v2(60.59,71.36)
  IN2 w0.211: v2(99.57,59.05) 98.56,60.07 98.37,60.07 97.52,60.91 91.81,60.91 91.6,61.12 91.6,61.55 91.39,61.77 90.96,61.77 90.75,61.55 90.75,61.12 90.54,60.91 90.2,60.91 89.99,61.12 89.99,61.51 89.72,61.78 89.36,61.78 89.15,61.57 89.15,61.12 88.94,60.91 88.52,60.91 88.31,61.12 88.31,61.47 88.05,61.73 87.67,61.73 87.46,61.52 87.46,61.12 87.25,60.91 86.83,60.91 86.62,61.12 86.62,61.38 86.41,61.59 85.67,61.59 85.46,61.38 85.46,61.12 85.25,60.91 84.76,60.91 84.55,61.12 84.55,62.48 84.34,62.69 83.9,62.69 83.69,62.48 83.69,61.12 83.48,60.91 83.06,60.91 82.84,61.12 82.84,62.48 82.63,62.69 82.21,62.69 82,62.48 82,61.25 81.79,61.04 81.43,61.04 81.16,61.32 81.16,62.48 80.95,62.69 79.78,62.69 73.12,69.36 72.78,69.36 72.47,69.05 71.93,69.05 71.63,69.36 71.09,69.36 70.79,69.05 70.25,69.05 69.94,69.36 65.56,69.36 65.35,69.57 65.35,70.15 65.16,70.35 64.81,70.35 64.6,70.13 64.6,70.06 64.41,69.86 64.11,69.86 63.9,70.07 63.9,70.15 63.71,70.35 63.47,70.35 62.12,70.35 61.1,71.36 v2(60.59,71.36)
  BOTTOM w0.102: UC1.N41 103.25,57.8 101.49,57.8 101.39,57.91 101.39,57.91 100.97,58.32 99.86,58.32 99.58,58.6 99.58,58.77 99.57,58.77 v2(99.57,59.05) ; JDIMM1.63 68.66,71.62 v2(68.47,71.81) ; JDIMM2.63 53.86,72.13 53.96,72.22 54.12,72.22 54.22,72.12 54.22,71.52 54.1,71.4 54.1,71.27 54.41,70.97 54.41,70.74 54.46,70.69 54.57,70.69 54.66,70.78 55.23,70.78 55.51,70.5 55.51,70.17 55.61,70.07 55.96,70.07 56.05,69.98 56.05,69.78 56.15,69.68 56.36,69.68 56.52,69.51 57.77,69.51 57.91,69.65 57.91,69.71 58.01,69.8 58.5,69.8 58.58,69.73 58.72,69.73 58.8,69.8 59.27,69.8 59.53,70.06 59.53,70.25 59.62,70.34 59.74,70.34 60.38,70.98 60.59,70.98 60.7,71.09 60.7,71.26 v2(60.59,71.36)
DDRAB_SDQ20: length 81.6
  IN1 w0.211: v2(46.86,75.86) 47.19,75.53 54.71,75.53 v2(56,74.24)
  IN2 w0.211: v2(56,74.24) 56.14,74.1 56.46,74.1 56.73,74.36 56.73,74.91 57.73,75.91 62.51,75.91 62.61,76.01 64.36,76.01 64.77,75.61 65.81,75.61 66.13,75.28 68.3,75.28 68.38,75.36 69.75,75.36 70.43,74.67 74.23,74.67 78.58,70.33 87.78,70.33 90.38,67.72 95.64,67.72 99.99,63.37 99.99,62.35 101.13,61.21 v2(101.98,61.21)
  BOTTOM w0.102: JDIMM1.46 60.26,75.88 60.16,75.77 60.16,75.56 60.26,75.46 60.76,75.46 60.87,75.36 60.87,75.19 60.76,75.09 60.24,75.09 60.14,74.99 60.14,74.79 60.24,74.68 60.45,74.68 60.55,74.58 60.55,74.41 60.45,74.31 60.35,74.31 60.26,74.22 60.26,73.41 60.13,73.29 59.96,73.29 59.86,73.39 59.86,73.55 59.76,73.65 59.62,73.65 59.52,73.55 59.52,73.39 59.4,73.28 58.87,73.28 58.76,73.16 58.76,72.83 58.66,72.73 58.11,72.73 57.99,72.85 57.99,73.17 57.71,73.45 57.71,73.53 57.61,73.63 55.83,73.63 55.73,73.73 55.73,74.14 55.83,74.24 v2(56,74.24) ; v2(46.86,75.86) 46.35,76.38 JDIMM2.46 ; v2(101.98,61.21) 101.98,60.97 102.14,60.81 102.81,60.81 102.9,60.89 103.5,60.89 103.58,60.97 103.84,60.97 103.93,60.88 104.19,60.88 UC1.H40
DDRAB_SDQ21: length 84
  IN1 w0.211: v2(59.73,74.88) 60.91,76.06 66.16,76.06 v2(66.87,76.78)
  IN2 w0.211: v2(59.73,74.88) 62.68,74.88 62.99,74.57 64.88,74.57 65.12,74.34 65.55,73.91 69.09,73.91 69.35,73.64 73.81,73.64 78.15,69.3 79.17,69.3 79.38,69.09 79.38,68.07 79.65,67.8 80.01,67.8 80.22,68.01 80.22,69.09 80.43,69.3 80.86,69.3 81.07,69.09 81.07,68.3 81.3,68.07 81.7,68.07 81.91,68.28 81.91,69.09 82.12,69.3 82.54,69.3 82.75,69.09 82.75,68.25 82.96,68.04 83.39,68.04 83.6,68.25 83.6,69.09 83.81,69.3 84.39,69.3 84.6,69.09 84.6,68.22 84.81,68.01 85.39,68.01 85.6,68.22 85.6,69.09 85.81,69.3 86.29,69.3 86.5,69.09 86.5,67.09 86.9,66.69 95.21,66.69 95.53,66.37 95.53,66.32 96,65.85 96.05,65.85 98.32,63.58 v2(98.32,62.95)
  BOTTOM w0.102: UC1.H41 103.01,60.66 102.95,60.6 102.05,60.6 101.24,61.41 101.24,62.44 100.48,63.2 98.57,63.2 v2(98.32,62.95) ; JDIMM2.45 53.69,76.62 53.88,76.81 54.1,76.81 54.17,76.74 54.17,76.22 54.1,76.15 54.1,75.87 54.21,75.76 54.75,75.76 54.81,75.7 54.81,75.66 54.92,75.56 55.1,75.56 55.31,75.76 55.42,75.76 55.54,75.64 55.54,75.38 55.64,75.28 55.82,75.28 55.92,75.38 55.92,75.51 56.03,75.62 56.19,75.62 56.71,75.09 56.71,74.34 56.81,74.24 57.05,74.24 57.15,74.34 57.15,74.63 57.25,74.73 57.45,74.73 57.55,74.63 57.55,74.34 57.66,74.24 57.83,74.24 57.93,74.34 57.93,74.62 58.05,74.73 59.31,74.73 59.77,74.27 59.89,74.27 59.97,74.35 59.97,74.52 59.84,74.66 59.84,74.78 v2(59.73,74.88) ; v2(66.87,76.78) 67.52,76.13 JDIMM1.45
DDRAB_SDQ22: length 81
  IN1 w0.211: v2(54.99,72) 54.89,72.1 53.55,72.1 53.11,72.54 50.35,72.54 50.14,72.75 50.14,72.88 49.93,73.09 49.52,73.09 49.3,72.87 49.3,72.75 49.09,72.54 48.36,72.54 v2(47.87,73.03)
  IN2 w0.211: v2(101.91,58.85) 101.91,59.48 100.92,60.47 100.34,60.47 98.32,62.49 96.1,62.49 93.98,64.61 83.87,64.61 82.66,65.81 82.21,65.81 82,65.6 82,65.42 81.82,65.24 81.32,65.24 81.11,65.45 81.11,65.62 80.92,65.81 78.85,65.81 73.64,71.02 73.64,71.02 73.31,71.35 68.3,71.35 68.29,71.35 67.73,71.35 67.19,71.89 64.11,71.89 64.07,71.93 64.07,71.93 63.7,72.3 62.35,72.3 61.74,72.91 59.82,72.91 58.82,71.91 56.56,71.91 56.36,72.11 55.11,72.11 55.1,72.1 55.08,72.1 v2(54.99,72)
  BOTTOM w0.102: v2(54.99,72) 54.93,72 54.83,71.9 54.83,71.49 54.93,71.39 55.29,71.39 55.39,71.49 55.39,71.96 55.53,72.1 56.14,72.1 56.25,71.99 56.25,71.76 56.35,71.66 56.58,71.66 56.68,71.76 56.68,72 56.79,72.1 56.99,72.1 57.09,72 57.09,71.49 57.2,71.38 57.39,71.38 57.5,71.48 57.5,71.68 57.6,71.79 57.8,71.79 57.9,71.68 57.9,71.35 58,71.25 58.21,71.25 58.31,71.35 58.31,71.71 58.41,71.81 58.61,71.81 58.72,71.71 58.72,71.35 58.82,71.25 59.15,71.25 59.25,71.35 59.25,72.03 59.53,72.31 60.69,72.31 60.85,72.47 60.85,72.71 61.01,72.88 JDIMM1.58 ; v2(101.91,58.85) 101.91,58.7 102.2,58.41 102.85,58.41 103.14,58.69 103.5,58.69 103.58,58.77 103.84,58.77 103.93,58.68 104.19,58.68 UC1.M40 ; v2(47.87,73.03) 47.53,73.38 JDIMM2.58
DDRAB_SDQ23: length 83.4
  IN1 w0.211: v2(59.96,71.6) 59.96,72.2 60.17,72.41 67.56,72.41 67.77,72.2 v2(67.77,71.96)
  IN2 w0.211: v2(100.29,59.05) 100.29,59.06 97.93,61.42 95.7,61.42 95.45,61.68 95.21,61.68 94.95,61.42 94.75,61.42 94.53,61.63 94.53,62.21 94.32,62.42 93.9,62.42 93.69,62.21 93.69,61.63 93.48,61.42 92.99,61.42 92.78,61.63 92.78,62.74 92.57,62.95 92.14,62.95 91.93,62.74 91.93,62.51 91.72,62.3 91.29,62.3 91.08,62.51 91.08,62.82 90.87,63.03 90.45,63.03 90.24,62.82 90.24,62.51 90.03,62.3 89.5,62.3 89.29,62.51 89.29,62.77 89.11,62.95 88.74,62.95 88.52,62.74 88.52,62.46 88.31,62.25 87.87,62.25 87.66,62.46 87.66,62.95 87.45,63.16 87.03,63.16 86.82,62.94 86.82,62.31 86.61,62.1 86.19,62.1 85.98,62.31 85.98,62.42 85.77,62.63 85.13,62.63 84.91,62.86 84.91,63.34 84.67,63.57 83.26,63.57 83.07,63.76 83.07,63.94 82.86,64.15 82.44,64.15 82.23,63.94 82.23,63.41 81.97,63.15 81.6,63.15 81.39,63.36 81.39,63.94 81.18,64.15 80.75,64.15 80.54,63.94 80.54,63.42 80.33,63.21 80,63.21 72.89,70.32 72.41,70.32 71.97,69.87 70.4,69.87 69.96,70.32 69.23,70.32 68.78,69.87 66.16,69.87 65.95,70.09 65.95,70.56 65.64,70.86 63.68,70.86 63.68,70.86 62.33,70.86 61.31,71.88 60.25,71.88 v2(59.96,71.6)
  BOTTOM w0.102: v2(100.29,59.05) 100.46,59.22 101.15,59.22 101.3,59.07 101.3,58.6 101.69,58.21 102.94,58.21 103.19,58.46 UC1.M41 ; v2(59.96,71.6) 60.09,71.47 60.09,71.12 59.61,70.64 59.33,70.64 59.23,70.54 59.23,70.21 59.13,70.11 58.93,70.11 58.83,70.21 58.83,70.53 58.72,70.64 58.54,70.64 58.43,70.53 58.43,70.21 58.32,70.11 57.88,70.11 57.59,69.82 56.65,69.82 56.09,70.38 55.91,70.38 55.81,70.48 55.81,70.63 55.35,71.09 54.72,71.09 54.53,71.28 54.53,72.39 53.8,73.13 JDIMM2.59 ; JDIMM1.59 68.05,72.62 67.77,72.34 v2(67.77,71.96)
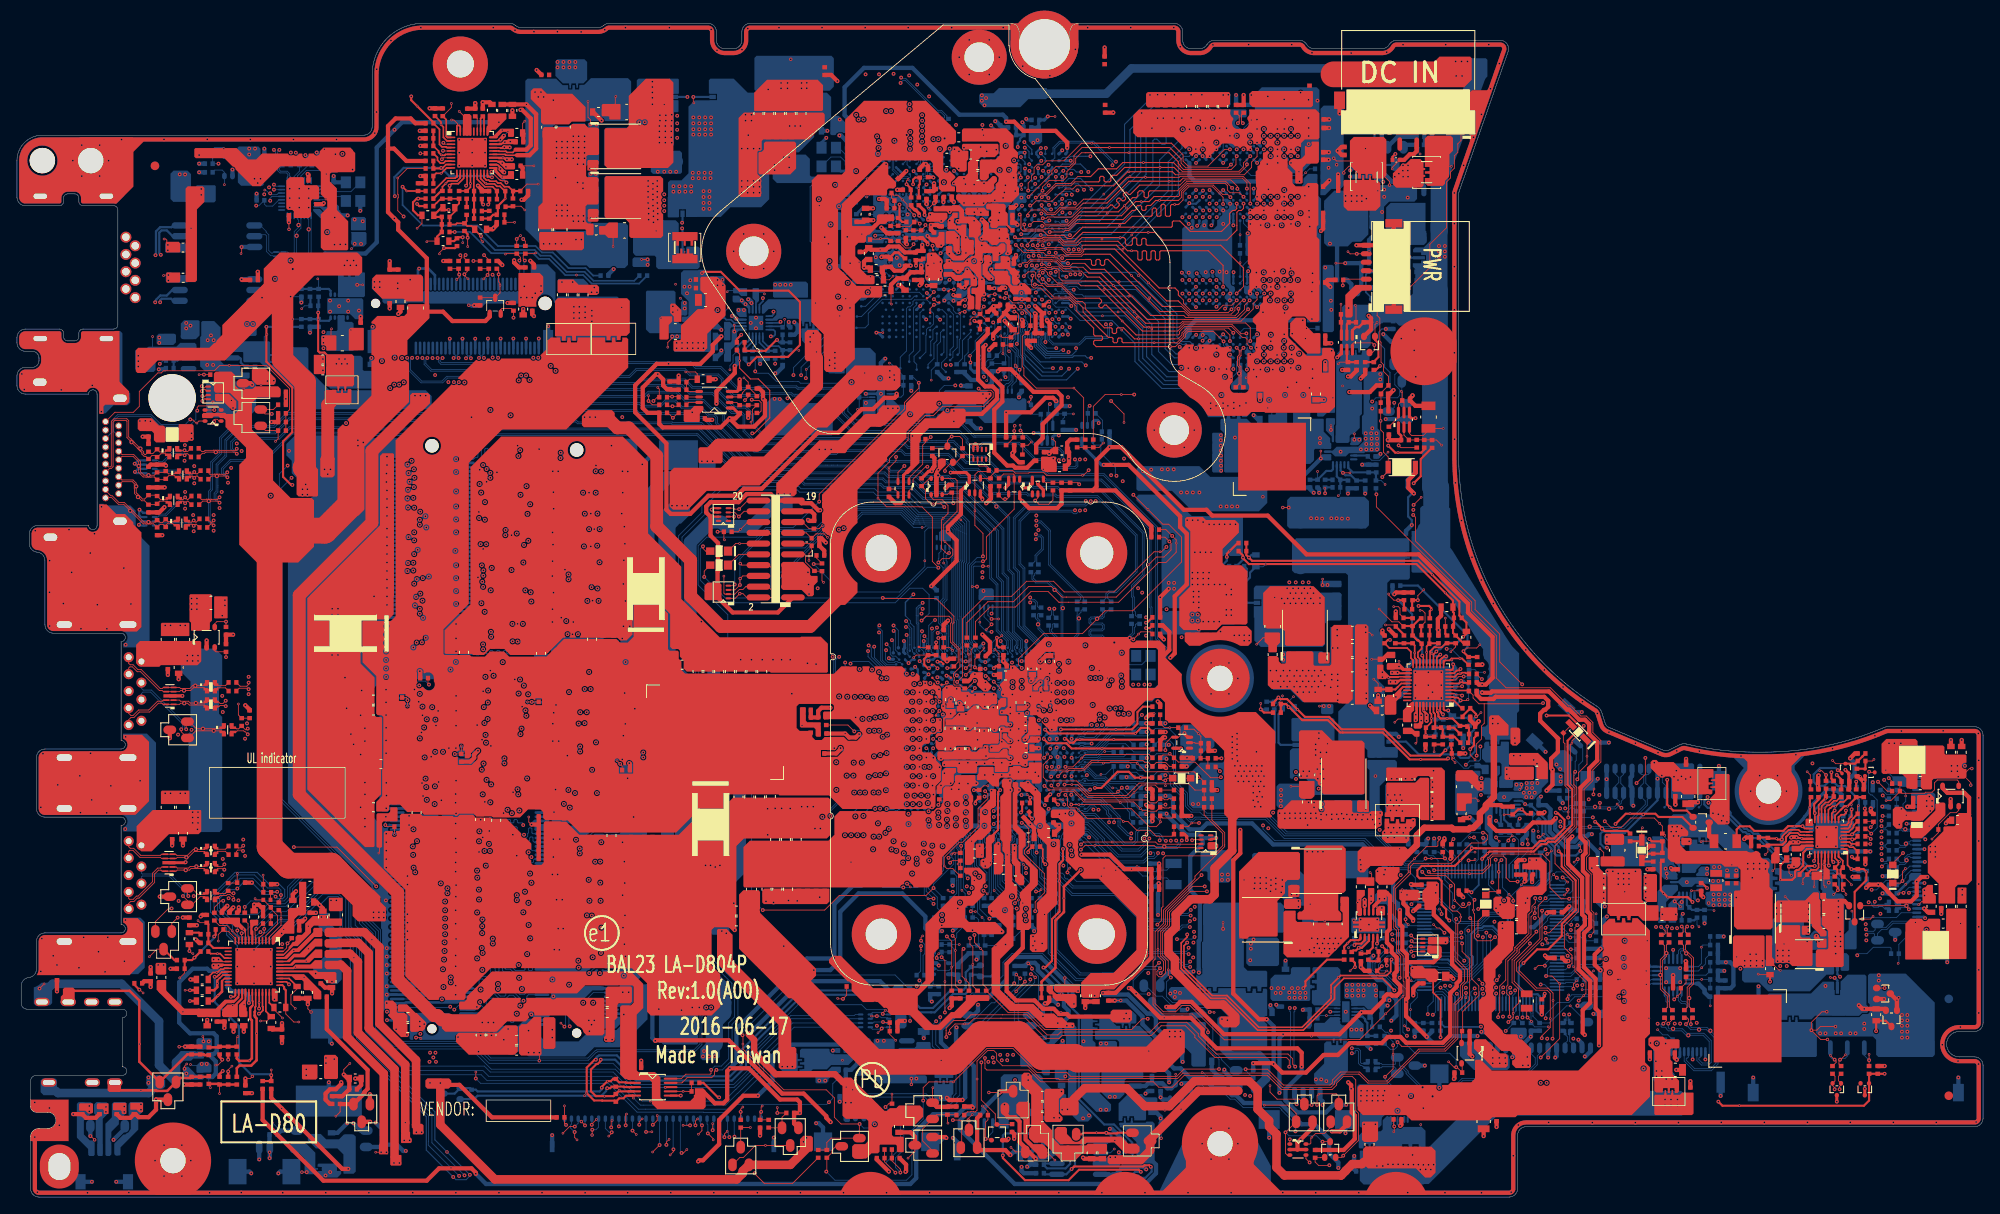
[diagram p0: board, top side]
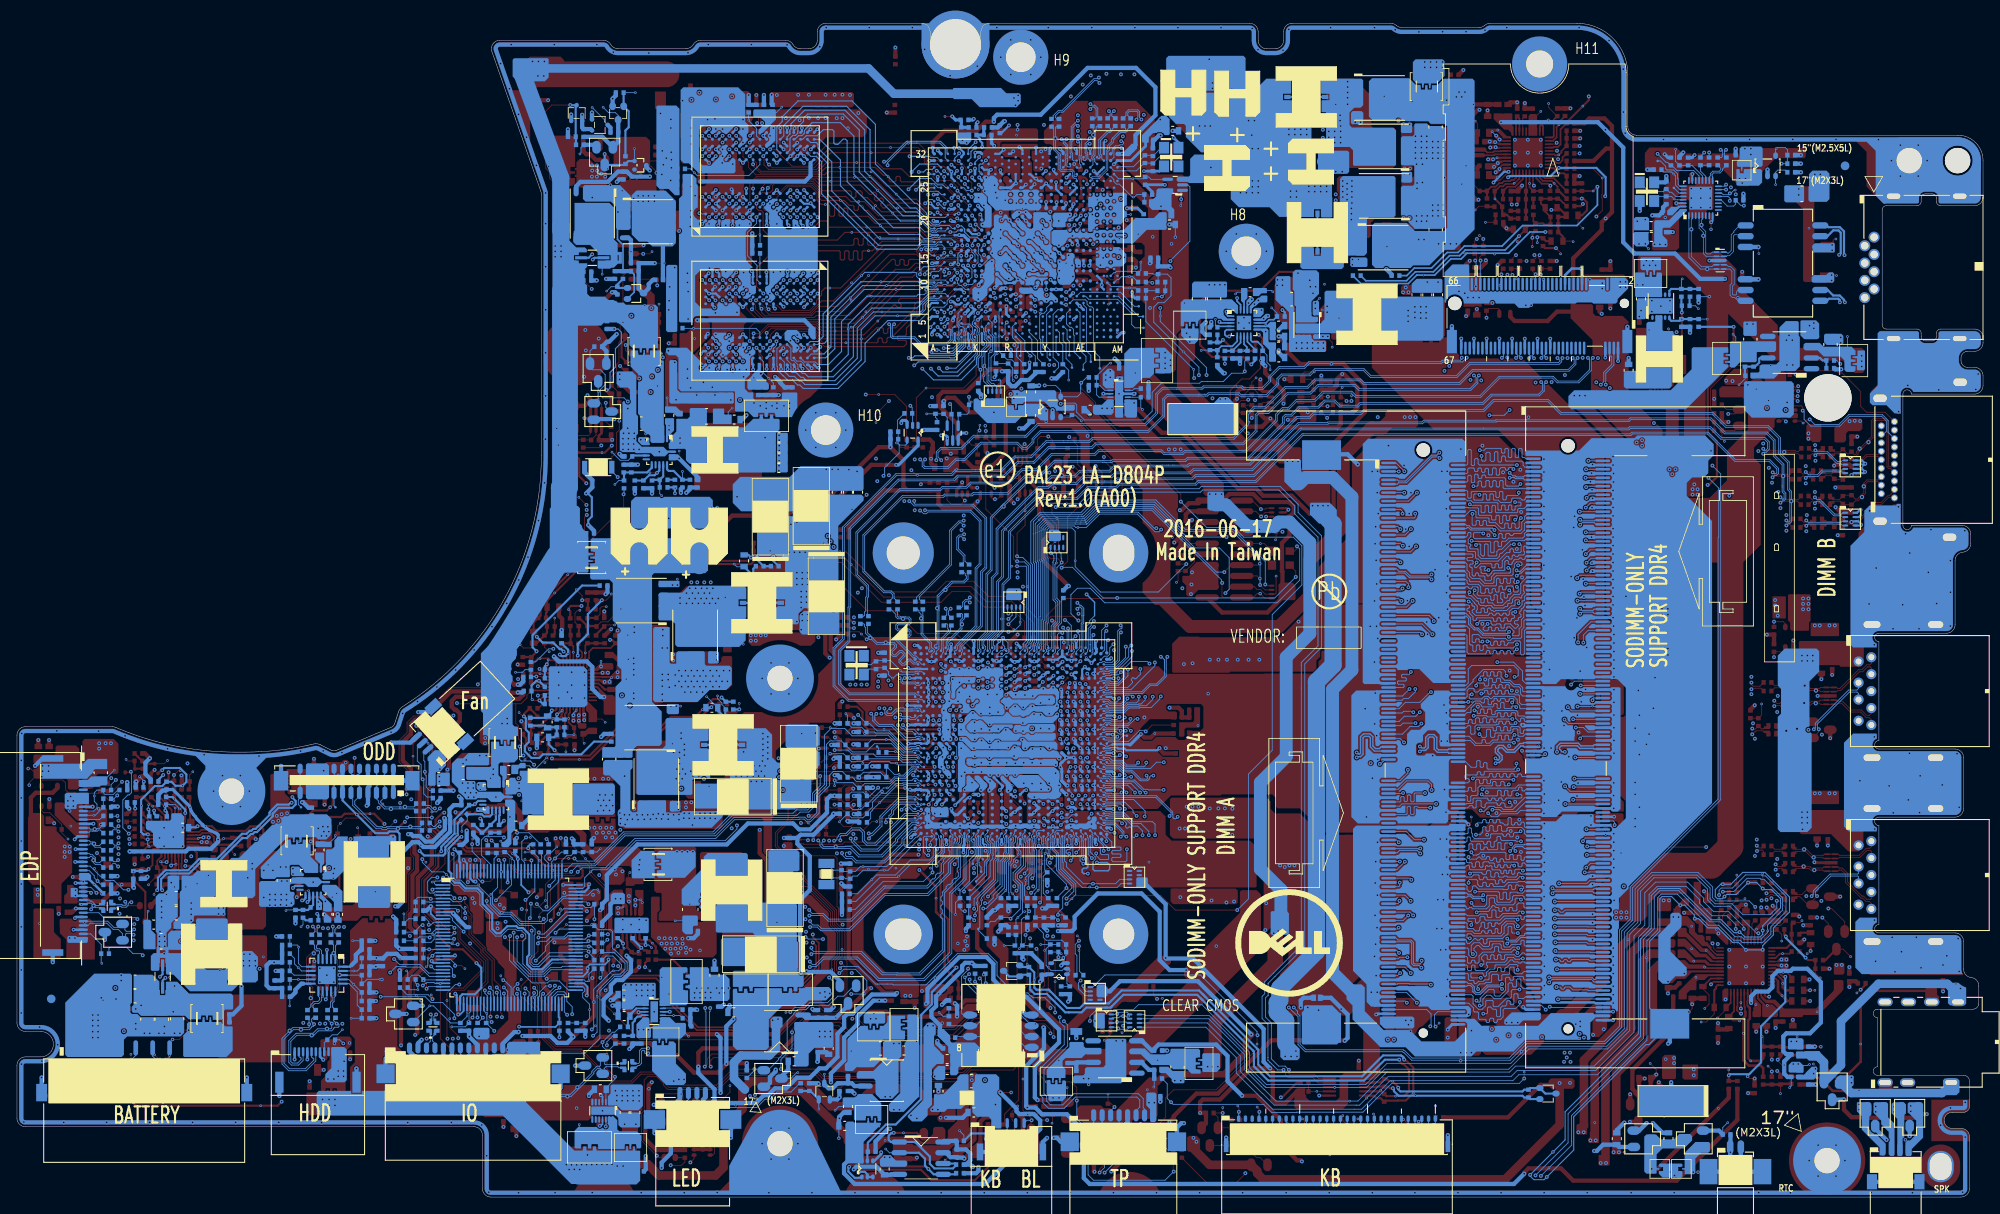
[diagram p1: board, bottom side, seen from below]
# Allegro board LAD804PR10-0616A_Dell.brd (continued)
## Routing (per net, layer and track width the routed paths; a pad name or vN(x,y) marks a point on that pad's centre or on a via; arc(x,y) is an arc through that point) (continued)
DDRAB_SDQ24: length 79.2
  IN1 w0.211: v2(55.17,69.06) 54.7,69.52 51.39,69.52 51.18,69.73 51.18,70 50.97,70.21 50.4,70.21 50.19,69.99 50.19,69.73 49.98,69.52 48.69,69.52 v2(47.84,70.38)
  IN2 w0.211: v2(55.17,69.06) 55.8,69.06 56.01,68.84 56.01,68.58 56.22,68.37 56.65,68.37 56.86,68.58 56.86,68.84 57.07,69.06 58.05,69.06 58.26,68.84 58.26,68.59 58.47,68.38 58.97,68.38 59.18,68.59 59.18,68.84 59.39,69.06 61.17,69.06 61.9,68.32 63.62,68.32 63.74,68.2 63.74,68.18 64.01,67.91 64.03,67.91 64.55,67.39 66.57,67.39 66.97,66.98 71.23,66.98 71.33,66.88 71.78,66.88 71.78,66.89 72.63,66.89 77.78,61.73 78.55,61.73 79.13,61.16 79.13,61.16 80.92,59.36 96.71,59.36 96.98,59.09 v2(96.98,59.07)
  BOTTOM w0.102: v2(96.98,59.07) 97.1,58.95 97.1,58.77 98.1,57.78 98.97,57.78 99.08,57.78 99.41,57.78 99.48,57.71 100.72,57.71 101.24,57.19 102.83,57.19 102.86,57.16 102.97,57.16 102.98,57.16 103.46,57.16 103.58,57.03 103.84,57.03 UC1.R40 ; v2(55.17,69.06) 55.48,69.06 55.58,68.95 55.58,68.8 55.48,68.7 55.37,68.7 55.27,68.6 55.27,68.39 55.37,68.29 55.54,68.29 55.65,68.19 55.65,68.04 55.75,67.94 56,67.94 56.1,68.04 56.1,68.24 56.21,68.34 56.41,68.34 56.51,68.24 56.51,68.04 56.61,67.94 56.81,67.94 56.92,68.04 56.92,68.24 57.02,68.34 57.22,68.34 57.32,68.24 57.32,68.04 57.42,67.94 57.65,67.94 57.74,68.03 57.74,68.24 57.84,68.34 59.67,68.34 59.77,68.24 59.77,68.11 59.85,68.04 60.06,68.04 60.16,68.14 60.16,68.49 60.56,68.89 60.56,69.04 60.63,69.11 60.76,69.11 60.87,69.21 60.87,69.39 60.76,69.49 60.67,69.49 60.57,69.59 60.57,69.73 60.7,69.87 60.92,69.87 60.92,69.88 JDIMM1.70 ; v2(47.84,70.38) JDIMM2.70
DDRAB_SDQ25: length 82
  IN1 w0.211: v2(59.67,67.63) 60.89,68.85 65.79,68.85 v2(67.28,70.35)
  IN2 w0.211: v2(101.85,56.65) 101.85,57.19 100.63,58.41 96.93,58.41 96.49,58.85 92.25,58.85 91.72,58.32 91.1,58.32 90.89,58.53 90.89,58.63 90.68,58.85 90.11,58.85 89.83,58.57 89.83,58.03 89.63,57.83 89.13,57.83 88.96,58 88.96,58.56 88.74,58.78 88.43,58.78 88.22,58.57 88.22,58.07 87.98,57.83 87.56,57.83 87.35,58.04 87.35,58.56 87.13,58.78 86.74,58.78 86.53,58.57 86.53,58.07 86.3,57.83 85.88,57.83 85.66,58.04 85.66,58.52 85.44,58.74 85.06,58.74 84.85,58.53 84.85,58.07 84.61,57.83 84.19,57.83 83.98,58.04 83.98,58.24 83.65,58.57 80.99,58.57 78.34,61.22 77.57,61.22 72.41,66.37 72.08,66.37 71.86,66.15 71.86,65.5 71.64,65.28 71.33,65.28 70.15,66.47 67.55,66.47 67.55,66.47 66.76,66.47 66.35,66.87 64.34,66.87 63.92,67.29 61.94,67.29 61.6,67.63 60.79,67.63 60.6,67.82 60.6,68.33 60.39,68.54 59.88,68.54 59.67,68.33 v2(59.67,67.63)
  BOTTOM w0.102: JDIMM1.71 68,69.62 v2(67.28,70.35) ; JDIMM2.71 53.97,70.13 54.07,70.02 54.07,69.78 54.18,69.67 54.18,69.58 54.28,69.48 54.37,69.48 54.48,69.37 54.48,69.19 54.65,69.02 54.65,68.88 54.5,68.72 54.5,68.51 54.62,68.4 54.72,68.4 54.82,68.29 54.82,68.12 54.92,68.01 55.16,68.01 55.27,67.91 55.27,67.71 55.16,67.61 54.92,67.61 54.82,67.51 54.82,67.39 55.09,67.12 55.24,67.12 55.75,67.63 56.36,67.63 56.47,67.52 56.47,67.21 56.56,67.12 56.76,67.12 56.86,67.23 56.86,67.51 56.99,67.63 57.35,67.63 57.48,67.5 57.85,67.5 58.03,67.69 58.03,67.94 58.14,68.04 59.34,68.04 59.44,67.94 59.44,67.75 59.56,67.63 v2(59.67,67.63) ; UC1.T40 104.19,56.48 103.93,56.48 103.84,56.57 103.58,56.57 103.5,56.49 102.9,56.49 102.76,56.36 102.15,56.36 v2(101.85,56.65)
DDRAB_SDQ26: length 82.5
  IN1 w0.211: v2(66.16,66.41) 65.99,66.59 65.99,66.6 65.72,66.87 64.67,66.87 64.5,66.7 60.28,66.7 60.08,66.51 59.28,66.51 58.49,65.72 58.49,65.6 v2(58.47,65.58)
  IN2 w0.211: v2(101.12,55.03) 101.12,54.79 100.91,54.58 100.21,54.58 99.47,55.32 99.27,55.32 99.09,55.5 98.37,55.5 97.94,55.93 97.53,55.93 97.11,55.5 96.2,55.5 95.96,55.74 94.99,55.74 94.75,55.5 93.83,55.5 93.59,55.74 92.99,55.74 92.75,55.5 92.14,55.5 91.91,55.74 91.21,55.74 90.56,55.09 88.88,55.09 88.62,55.34 88.03,55.34 87.78,55.09 87.19,55.09 86.93,55.34 86.35,55.34 86.09,55.09 85.5,55.09 85.25,55.34 84.66,55.34 84.4,55.09 83.82,55.09 83.56,55.34 82.97,55.34 82.72,55.09 82.13,55.09 81.87,55.34 81.29,55.34 81.03,55.09 79.81,55.09 79.6,55.3 79.6,55.58 79.39,55.79 78.97,55.79 78.75,55.58 78.75,55.3 78.54,55.09 77.62,55.09 77.27,55.43 77.27,55.78 77.48,55.99 77.48,56.27 77.16,56.58 76.78,56.58 76.6,56.4 76.3,56.4 75.98,56.72 75.98,57.12 76.27,57.4 76.27,58.03 72.34,61.96 70.7,61.96 70.45,62.21 70.45,62.65 70.22,62.89 69.77,62.89 69.49,63.17 69.49,63.61 69.12,63.98 63.63,63.98 62.99,64.61 62.38,64.61 62.19,64.81 61.52,64.81 61.33,64.61 60.32,64.61 59.81,65.12 59.38,65.12 58.91,64.65 58.61,64.65 58.24,65.03 58.24,65.35 v2(58.47,65.58)
  BOTTOM w0.102: v2(101.12,55.03) 101.51,54.65 101.93,54.65 102.23,54.94 103.47,54.94 103.58,54.83 103.84,54.83 UC1.W40 ; JDIMM2.83 53.79,67.13 54.1,66.81 54.1,64.1 54.23,63.98 54.44,63.98 54.57,64.1 54.57,65.49 54.7,65.62 55.19,65.62 55.42,65.4 55.99,65.4 56.09,65.3 56.09,65.21 56.19,65.11 56.37,65.11 56.47,65.21 56.47,65.5 56.57,65.6 56.81,65.6 56.88,65.53 56.88,65.19 56.98,65.09 57.16,65.09 57.28,65.22 57.28,65.5 57.39,65.6 57.56,65.6 57.69,65.47 57.69,65.22 57.82,65.09 57.97,65.09 58.1,65.22 58.1,65.47 58.22,65.6 58.44,65.6 v2(58.47,65.58) ; JDIMM1.83 66.37,66.62 v2(66.16,66.41)
DDRAB_SDQ27: length 78.8
  IN1 w0.211: v2(54.99,64.63) 53.79,64.63 53.49,64.94 47.63,64.94 v2(47.14,65.42)
  IN2 w0.211: v2(102.11,54.31) 101.53,54.31 100.87,53.65 98.58,53.65 97.76,54.47 91.4,54.47 90.98,54.06 77.19,54.06 74.95,56.29 74.95,57.75 71.78,60.93 70.28,60.93 68.3,62.91 63.24,62.91 62.57,63.58 58.22,63.58 57.17,64.63 v2(54.99,64.63)
  BOTTOM w0.102: v2(102.11,54.31) 102.24,54.18 103.39,54.18 103.57,54.36 103.85,54.36 103.91,54.31 104.16,54.31 UC1.Y40 ; JDIMM2.84 46.57,66.87 47.14,66.3 v2(47.14,65.42) ; v2(54.99,64.63) 55.14,64.48 55.24,64.48 55.34,64.38 55.34,64.19 55.44,64.09 55.64,64.09 55.75,64.19 55.75,64.38 55.85,64.48 56.05,64.48 56.15,64.38 56.15,64.19 56.25,64.09 56.46,64.09 56.56,64.19 56.56,64.38 56.66,64.48 56.86,64.48 56.97,64.38 56.97,64.19 57.07,64.09 57.27,64.09 57.37,64.19 57.37,64.38 57.47,64.48 57.68,64.48 57.78,64.38 57.78,64.19 57.88,64.09 58.08,64.09 58.18,64.19 58.18,64.38 58.29,64.48 58.49,64.48 58.59,64.38 58.59,64.19 58.69,64.09 60.66,64.09 60.87,64.29 60.87,66.25 60.99,66.38 JDIMM1.84
DDRAB_SDQ28: length 78.9
  IN1 w0.211: v2(47.58,71.2) 48.72,71.2 48.85,71.07 48.85,70.69 48.98,70.57 49.61,70.57 49.74,70.69 49.74,70.85 49.87,70.98 54.63,70.98 54.88,70.72 54.88,70.27 54.78,70.17 v2(54.78,70.07)
  IN2 w0.211: v2(98.83,59.01) 98.29,59.55 98.15,59.55 97.6,60.1 97.31,60.39 81.35,60.39 73.21,68.54 69.35,68.54 69.04,68.84 65.32,68.84 64.81,69.35 63.84,69.35 63.36,69.83 63.26,69.83 61.85,69.83 60.83,70.85 56.1,70.85 55.33,70.07 v2(54.78,70.07)
  BOTTOM w0.102: v2(47.58,71.2) 47.41,71.38 JDIMM2.66 ; v2(98.83,59.01) 98.83,58.66 99.3,58.18 99.58,58.18 99.64,58.12 100.89,58.12 101.41,57.6 103.17,57.6 103.18,57.59 103.49,57.59 103.57,57.67 103.84,57.67 103.93,57.58 104.19,57.58 UC1.P40 ; JDIMM1.66 61.12,70.88 60.92,70.68 60.51,70.68 60,70.17 60,70.1 59.66,69.76 59.66,69.3 59.78,69.18 59.78,69.03 59.71,68.95 59.27,68.95 59.2,69.02 59.2,69.4 59.1,69.5 58.92,69.5 58.82,69.4 58.82,69.06 58.72,68.95 58.55,68.95 58.45,69.06 58.45,69.38 58.34,69.5 58.19,69.5 58.09,69.4 58.09,69.32 57.98,69.21 57.84,69.21 57.74,69.1 57.6,69.1 57.49,69.21 56.19,69.21 55.63,69.77 55.3,69.77 55.2,69.87 55.2,70.38 55.1,70.48 54.78,70.48 54.68,70.38 54.68,70.17 v2(54.78,70.07)
DDRAB_SDQ29: length 82.4
  IN1 w0.211: v2(60.68,70.27) 61.45,70.27 62.04,70.86 63.08,70.86 63.29,70.65 63.29,70.27 63.5,70.06 63.92,70.06 64.13,70.27 64.13,70.65 64.34,70.86 64.76,70.86 64.98,70.65 64.98,70.27 65.19,70.06 65.61,70.06 65.82,70.27 65.82,70.65 66.03,70.86 68.23,70.86 68.44,70.65 68.44,70.47 68.57,70.34 v2(68.6,70.34)
  IN2 w0.211: v2(97.94,59.04) 97.1,59.88 81.14,59.88 78.37,62.65 78.07,62.65 77.98,62.56 77.68,62.56 77.39,62.86 77.39,63.16 77.47,63.24 77.47,63.54 77.18,63.84 76.88,63.84 76.79,63.75 76.49,63.75 76.19,64.05 76.19,64.35 76.28,64.44 76.28,64.73 75.98,65.03 75.68,65.03 75.6,64.95 75.3,64.95 75,65.24 75,65.54 75.09,65.63 75.09,65.93 74.82,66.19 74.52,66.19 74.44,66.11 74.14,66.11 73.84,66.4 73.84,66.7 73.93,66.79 73.93,67.09 73.61,67.41 72.98,67.41 72.36,68.02 69.13,68.02 68.83,68.33 68.41,68.33 68.2,68.12 68.2,67.71 67.99,67.5 67.56,67.5 67.35,67.71 67.35,68.12 67.14,68.33 65.1,68.33 64.6,68.83 62.12,68.83 61.38,69.57 57.91,69.57 57.7,69.78 57.7,70.12 57.91,70.33 60.62,70.33 v2(60.68,70.27)
  BOTTOM w0.102: JDIMM2.67 53.82,71.13 54.1,70.84 54.1,70.42 54.18,70.35 54.31,70.35 54.38,70.29 54.38,69.9 54.82,69.46 55.5,69.46 55.89,69.08 55.89,68.74 55.98,68.65 56.14,68.65 56.24,68.75 56.24,68.8 56.34,68.9 56.55,68.9 56.65,68.8 56.65,68.75 56.75,68.65 56.95,68.65 57.06,68.75 57.06,68.8 57.16,68.9 57.36,68.9 57.46,68.8 57.46,68.75 57.56,68.65 57.77,68.65 57.87,68.75 57.87,68.8 57.97,68.9 58.17,68.9 58.27,68.8 58.27,68.75 58.38,68.65 59.89,68.65 60.25,69.01 60.25,69.22 60.15,69.33 60.07,69.33 59.96,69.43 59.96,69.63 60.07,69.73 60.18,69.73 60.28,69.83 60.28,69.99 60.57,70.27 v2(60.68,70.27) ; v2(97.94,59.04) 97.94,58.71 98.67,57.98 99.08,57.98 99.49,57.98 99.56,57.91 100.8,57.91 101.32,57.39 103.03,57.39 103.06,57.36 UC1.P41 ; JDIMM1.67 68.93,70.62 68.65,70.34 v2(68.6,70.34)
DDRAB_SDQ30: length 82.6
  IN1 w0.211: v2(64.94,66.41) 64.72,66.19 60.49,66.19 60.3,65.99 59.49,65.99 v2(59.05,65.55)
  IN2 w0.211: v2(100.52,55.02) 100.52,55.62 100.3,55.84 99.48,55.84 99.18,56.14 98.46,56.14 98.16,56.44 97.32,56.44 96.97,56.09 96.6,56.09 96.25,56.44 95.79,56.44 95.6,56.25 90.99,56.25 90.34,55.6 89.09,55.6 88.83,55.86 81.07,55.86 80.82,55.6 80.31,55.6 80.08,55.83 80.08,56.33 79.82,56.59 79.03,56.59 78.56,56.13 78.26,56.13 77.97,56.42 77.97,56.72 78.43,57.18 78.43,57.48 78.16,57.75 77.86,57.75 77.38,57.27 77.08,57.27 76.78,57.56 76.78,57.86 77.27,58.34 77.27,58.64 76.44,59.47 76.13,59.47 75.99,59.33 75.7,59.33 75.4,59.63 75.4,59.93 75.54,60.07 75.54,60.36 75.24,60.66 74.94,60.66 74.8,60.52 74.5,60.52 74.2,60.82 74.2,61.12 74.35,61.26 74.35,61.56 74.05,61.86 73.75,61.86 73.61,61.72 73.31,61.72 73.01,62.01 73.01,62.31 73.15,62.45 73.15,62.76 72.76,63.15 72.46,63.15 71.79,62.47 71.3,62.47 71.04,62.74 71.04,63.1 70.83,63.31 70.51,63.31 69.33,64.5 68.37,64.5 63.84,64.5 63.21,65.13 62.6,65.13 62.4,65.32 61.31,65.32 61.19,65.2 60.46,65.2 60,65.66 59.16,65.66 v2(59.05,65.55)
  BOTTOM w0.102: v2(59.05,65.55) 59.15,65.45 59.33,65.45 59.43,65.55 59.43,65.77 59.53,65.87 59.74,65.87 59.84,65.77 59.84,65.55 59.94,65.45 60.16,65.45 60.26,65.55 60.26,66.27 60.16,66.38 59.52,66.38 59.13,65.98 57.78,65.98 57.7,65.91 56.3,65.91 56.1,65.7 55.76,65.7 55.53,65.93 54.56,65.93 54.41,66.08 54.41,66.94 54.15,67.2 54.15,68 54.03,68.13 JDIMM2.79 ; v2(100.52,55.02) 100.94,55.44 101.97,55.44 102.06,55.35 103.46,55.35 103.61,55.51 103.8,55.51 104.14,55.16 UC1.V40 ; v2(64.94,66.41) 66.15,67.62 JDIMM1.79
DDRAB_SDQ31: length 78.9
  IN1 w0.211: v2(54.98,65.22) 54.95,65.19 54.69,65.19 54.43,65.46 v2(47.76,65.46)
  IN2 w0.211: v2(54.98,65.22) 55.88,65.22 56.24,65.58 57.18,65.58 57.39,65.36 57.39,65.15 58.44,64.1 62.35,64.1 62.78,64.1 63.45,63.42 68.51,63.42 70.49,61.44 72.12,61.44 75.47,58.1 75.47,56.51 77.4,54.57 90.77,54.57 91.18,54.98 97.97,54.98 98.79,54.17 100.94,54.17 101.72,54.94 v2(101.72,55.03)
  BOTTOM w0.102: JDIMM1.80 60.9,67.38 60.56,67.04 60.56,65.26 60.45,65.14 60.28,65.14 60.18,65.04 60.18,64.5 60.07,64.39 59.87,64.39 59.77,64.5 59.77,65.04 59.67,65.14 59.46,65.14 59.36,65.04 59.36,64.58 59.26,64.48 59.08,64.48 58.96,64.61 58.96,65.04 58.86,65.14 58.61,65.14 58.5,65.04 58.5,64.89 58.4,64.79 55.41,64.79 54.98,65.22 v2(54.98,65.22) ; v2(47.76,65.46) 47.76,66.37 46.26,67.87 JDIMM2.80 ; v2(101.72,55.03) 101.77,55.03 101.9,55.15 103.7,55.15 UC1.V41
DDRAB_SDQ32: length 76.9
  IN1 w0.211: v2(47.19,41.99) 49.2,41.99 49.35,41.84 53.59,41.84 53.79,42.04 54.44,42.04 v2(54.5,41.98)
  IN2 w0.211: v2(99.65,51.26) 99.08,51.83 97.73,51.83 97.05,52.51 96.21,52.51 95.79,52.92 92.04,52.92 91.62,52.51 82.54,52.51 82.07,52.03 81.02,52.03 76.11,47.12 75.19,47.12 73.85,45.78 73.85,44.59 72.62,43.36 68.3,43.36 68.08,43.14 65.24,43.14 64.62,43.77 61.16,43.77 60.61,43.22 56.38,43.22 55.14,41.98 v2(54.5,41.98)
  BOTTOM w0.102: v2(47.19,41.99) 47.19,42.07 46.88,42.38 JDIMM2.174 ; v2(54.5,41.98) 55.03,41.98 55.13,42.08 56.75,42.08 56.92,42.25 56.92,42.46 57.02,42.56 57.23,42.56 57.33,42.46 57.33,42.11 57.46,41.98 57.56,41.98 57.66,41.88 57.66,41.39 57.76,41.29 57.97,41.29 58.07,41.39 58.07,41.88 58.17,41.98 58.4,41.98 58.5,41.88 58.5,41.71 58.6,41.61 58.81,41.61 58.91,41.71 58.91,41.88 59.01,41.98 60.37,41.98 60.47,42.09 60.47,42.37 60.59,42.49 60.76,42.49 60.87,42.39 60.87,42.02 61.01,41.87 JDIMM1.174 ; UC1.AD41 103.54,51.86 103.54,51.86 103.06,51.86 102.74,51.54 101.56,51.54 101,50.97 99.94,50.97 v2(99.65,51.26)
DDRAB_SDQ33: length 80.7
  IN1 w0.211: v2(59.81,42.75) 60.79,41.77 65.55,41.77 65.73,41.59 66.27,41.59 66.45,41.77 68.82,41.77 v2(68.92,41.86)
  IN2 w0.211: v2(59.81,42.75) 59.94,42.62 60.97,42.62 61.18,42.83 61.18,43.04 61.39,43.25 64.4,43.25 65.03,42.63 68.3,42.63 68.51,42.84 72.83,42.84 73.16,43.17 73.46,43.17 73.58,43.04 73.86,43.04 74.29,43.48 74.29,43.77 74.18,43.89 74.18,44.19 74.47,44.48 74.77,44.48 74.89,44.37 75.18,44.37 75.51,44.7 75.51,45 74.8,45.71 74.8,46.01 75.1,46.3 75.4,46.3 76.11,45.59 76.41,45.59 76.71,45.89 76.71,46.19 76.46,46.43 76.46,46.73 76.76,47.03 77.06,47.03 77.3,46.79 77.6,46.79 77.9,47.08 77.9,47.38 77.66,47.63 77.66,47.92 77.95,48.22 78.25,48.22 78.5,47.98 78.79,47.98 79.09,48.28 79.09,48.58 78.85,48.82 78.85,49.12 79.15,49.42 79.44,49.42 79.69,49.17 79.99,49.17 80.28,49.47 80.28,49.77 80.04,50.01 80.04,50.31 80.34,50.61 80.64,50.61 80.88,50.36 81.18,50.36 81.55,50.74 81.55,51.31 81.77,51.52 82.33,51.52 82.81,51.99 91.84,51.99 92.25,52.41 93.03,52.41 93.45,51.99 93.87,51.99 94.29,52.41 95.58,52.41 95.99,51.99 96.84,51.99 97.52,51.31 98.31,51.31 98.36,51.26 v2(98.7,51.26)
  BOTTOM w0.102: v2(59.81,42.75) 59.32,42.75 59.01,43.06 59.01,43.6 58.91,43.7 58.74,43.7 58.63,43.6 58.63,43.27 58.53,43.17 58.29,43.17 58.19,43.27 58.19,43.74 58.08,43.85 57.88,43.85 57.78,43.74 57.78,43.27 57.68,43.17 57.35,43.17 57.25,43.27 57.25,43.74 57.15,43.85 56.9,43.85 56.79,43.73 56.79,43.27 56.69,43.17 56.25,43.17 56.15,43.27 56.15,43.46 56,43.6 54.41,43.6 54.1,43.3 54.1,42.93 53.8,42.63 JDIMM2.173 ; JDIMM1.173 69.18,42.13 v2(68.92,41.86) ; v2(98.7,51.26) 98.7,51.05 98.97,50.77 101.08,50.77 101.64,51.33 102.88,51.33 103.18,51.62 103.49,51.62 103.57,51.54 103.84,51.54 103.93,51.64 104.19,51.64 UC1.AD40
DDRAB_SDQ34: length 80.5
  IN1 w0.211: v2(60.68,40.12) 61.44,40.12 61.99,39.57 v2(68.2,39.57)
  IN2 w0.211: v2(60.68,40.12) 60.68,40.29 60.92,40.53 62.02,40.53 62.27,40.78 63.27,40.78 63.96,40.09 64.6,40.09 64.73,39.96 67.2,39.96 67.81,40.57 72.29,40.57 72.44,40.41 74.01,40.41 74.51,40.91 80.87,47.27 81.17,47.27 82.21,46.23 82.51,46.23 82.81,46.53 82.81,46.82 81.77,47.87 81.77,48.17 82.08,48.48 82.38,48.48 83.43,47.44 83.72,47.44 84.02,47.74 84.02,48.03 82.99,49.07 82.99,49.39 83.62,50.02 84.59,50.02 84.8,49.81 84.8,49.34 85.01,49.13 85.43,49.13 85.64,49.34 85.64,49.81 85.85,50.02 86.21,50.02 86.42,49.81 86.42,49.42 86.63,49.21 87.05,49.21 87.26,49.42 87.26,49.81 87.47,50.02 87.89,50.02 88.1,49.81 88.1,49.42 88.31,49.21 88.74,49.21 88.95,49.42 88.95,49.81 89.16,50.02 89.58,50.02 89.79,49.81 89.79,49.42 90,49.21 90.42,49.21 90.63,49.42 90.63,49.81 90.84,50.02 95.86,50.02 96.14,49.74 97.2,49.74 97.67,49.27 100.16,49.27 v2(100.48,49.58)
  BOTTOM w0.102: v2(68.2,39.57) 69.14,38.63 JDIMM1.187 ; UC1.AH41 103.53,49.66 103.53,49.66 103.06,49.66 102.81,49.41 101.04,49.41 100.87,49.58 v2(100.48,49.58) ; JDIMM2.187 53.8,39.12 54.09,39.42 54.27,39.42 54.38,39.32 54.38,39.08 54.48,38.98 54.73,38.98 54.83,39.08 54.83,39.39 54.96,39.52 56.46,39.52 56.56,39.62 56.56,39.81 56.67,39.91 56.87,39.91 56.97,39.81 56.97,39.62 57.07,39.52 57.28,39.52 57.38,39.61 57.38,39.91 57.48,40.02 57.67,40.02 57.78,39.91 57.78,39.82 57.88,39.72 58.08,39.72 58.19,39.82 58.19,40.08 58.29,40.18 58.49,40.18 58.59,40.08 58.59,39.95 58.67,39.87 59.12,39.87 59.37,40.12 59.51,40.12 59.76,39.87 60.57,39.87 60.68,39.98 v2(60.68,40.12)
DDRAB_SDQ35: length 78
  IN1 w0.211: v2(46.79,38.87) 47.53,38.87 47.74,39.08 47.74,39.24 47.95,39.45 48.38,39.45 48.59,39.24 48.59,39.08 48.8,38.87 49.22,38.87 49.55,39.2 50.16,39.2 50.48,38.87 53.92,38.87 v2(54.27,38.52)
  IN2 w0.211: v2(54.27,38.52) 54.66,38.13 56.9,38.13 57.69,38.92 58.94,38.92 59.23,38.63 62.44,38.63 62.54,38.53 63.96,38.53 64.09,38.41 68,38.41 68.19,38.59 72.48,38.59 72.72,38.83 74.62,38.83 77.92,42.13 78.73,42.13 79.44,41.42 80.19,41.42 86.43,47.67 91.22,47.67 91.63,48.07 96.63,48.07 v2(96.65,48.05)
  BOTTOM w0.102: v2(54.27,38.52) 54.42,38.67 55.13,38.67 55.23,38.57 55.23,38.21 55.35,38.09 55.49,38.09 55.6,38.19 55.6,38.47 55.69,38.57 55.83,38.57 55.93,38.47 55.93,38.28 56.03,38.18 56.16,38.18 56.23,38.25 56.23,38.5 56.31,38.57 56.43,38.57 56.53,38.47 56.53,38.25 56.63,38.15 56.77,38.15 56.87,38.25 56.87,38.48 57,38.6 57.83,38.6 57.93,38.7 57.93,39 58.03,39.1 58.17,39.1 58.25,39.02 58.4,39.02 58.49,39.11 58.58,39.11 58.68,39.01 58.68,38.72 58.78,38.62 60.46,38.62 60.57,38.73 60.57,39.04 60.67,39.15 60.86,39.15 61.13,38.87 JDIMM1.186 ; v2(46.79,38.87) 46.28,39.38 JDIMM2.186 ; UC1.AH40 104.19,49.44 103.93,49.44 103.85,49.36 103.56,49.36 103.49,49.42 103.18,49.42 102.95,49.2 100.07,49.2 98.98,48.11 98.53,48.11 98.47,48.05 v2(96.65,48.05)
DDRAB_SDQ36: length 77.3
  IN1 w0.211: v2(54.54,43.16) 49.92,43.16 49.69,43.39 48.47,43.39 48.22,43.65 47.57,43.65 47.32,43.39 v2(46.77,43.39)
  IN2 w0.211: v2(54.54,43.16) 55.02,43.16 55.61,43.75 57.96,43.75 58.66,44.44 59.56,44.44 60.05,44.94 64.91,44.94 65.48,44.37 67.84,44.37 67.86,44.39 71.01,44.39 72.82,46.2 72.82,46.98 79.37,53.54 91.2,53.54 91.61,53.95 97.54,53.95 98.63,52.87 101.1,52.87 v2(101.81,52.15)
  BOTTOM w0.102: UC1.AB40 104.41,52.29 104.22,52.11 103.94,52.11 103.87,52.17 103.55,52.17 103.48,52.11 102.91,52.11 102.81,52.01 101.95,52.01 v2(101.81,52.15) ; JDIMM1.170 60.84,42.87 60.74,42.98 60.74,43.46 60.64,43.56 60.43,43.56 60.33,43.46 60.33,42.98 60.24,42.89 60.24,42.57 59.96,42.29 58.21,42.29 58.08,42.41 58.08,42.76 57.98,42.86 56.72,42.86 56.61,42.76 56.61,42.66 56.51,42.56 56.31,42.56 56.21,42.66 56.21,42.76 56.11,42.86 55.94,42.86 55.84,42.76 55.84,42.6 55.73,42.5 55.52,42.5 55.39,42.63 55.39,42.88 55.26,43.01 54.69,43.01 v2(54.54,43.16) ; JDIMM2.170 46.75,43.38 v2(46.77,43.39)
DDRAB_SDQ37: length 81.3
  IN1 w0.211: v2(65.94,42.17) 65.1,43.01 60.6,43.01 v2(59.71,43.9)
  IN2 w0.211: v2(101.09,52) 100.74,52.35 98.42,52.35 97.33,53.44 91.83,53.44 91.41,53.02 79.59,53.02 79.22,52.66 79.22,52.36 79.77,51.81 79.77,51.52 79.48,51.22 79.18,51.22 78.63,51.77 78.33,51.77 78.03,51.47 78.03,51.17 78.58,50.62 78.58,50.32 78.28,50.02 77.98,50.02 77.44,50.57 77.14,50.57 76.84,50.28 76.84,49.98 77.39,49.43 77.39,49.13 77.09,48.83 76.79,48.83 76.24,49.38 75.94,49.38 75.65,49.08 75.65,48.78 76.2,48.24 76.2,47.94 75.9,47.64 75.6,47.64 75.21,48.03 74.91,48.03 73.33,46.46 73.33,44.8 72.4,43.87 68.09,43.87 67.87,43.66 65.46,43.66 64.69,44.42 60.27,44.42 59.74,43.9 v2(59.71,43.9)
  BOTTOM w0.102: v2(59.71,43.9) 59.71,44.05 59.61,44.15 59.13,44.15 59.02,44.25 59.02,44.44 58.92,44.54 58.72,44.54 58.62,44.44 58.62,44.25 58.52,44.15 58.31,44.15 58.21,44.25 58.21,44.47 58.11,44.57 57.91,44.57 57.81,44.47 57.81,44.25 57.7,44.15 57.5,44.15 57.4,44.25 57.4,44.47 57.3,44.57 57.09,44.57 56.99,44.47 56.99,44.25 56.89,44.15 56.66,44.15 56.41,43.9 56.13,43.9 56.03,44 56.03,44.68 55.93,44.79 55.75,44.79 55.65,44.68 55.65,44.01 55.54,43.91 55.33,43.91 55.23,44.01 55.23,44.11 55.13,44.21 54.99,44.21 54.88,44.11 54.88,44.02 54.77,43.91 54.61,43.91 54.51,44.01 54.51,44.14 54.41,44.24 54.21,44.24 54.1,44.14 54.1,43.73 54,43.63 JDIMM2.169 ; JDIMM1.169 68.02,43.13 67.06,42.17 v2(65.94,42.17) ; UC1.AC40 103.87,52.6 103.61,52.6 103.47,52.73 102.8,52.73 102.74,52.79 102.4,52.79 102.21,52.6 101.68,52.6 v2(101.09,52)
DDRAB_SDQ38: length 80.3
  IN1 w0.211: v2(60.35,40.68) 64.28,40.68 64.88,40.09 68.33,40.09 68.79,39.63 v2(68.79,39.59)
  IN2 w0.211: v2(60.35,40.68) 60.09,40.43 60.09,39.87 60.3,39.66 63.08,39.66 63.18,39.56 64.39,39.56 64.51,39.44 67.42,39.44 68.02,40.05 69.28,40.05 69.49,39.84 69.49,39.84 69.7,39.63 70.74,39.63 71.17,40.05 72.07,40.05 72.23,39.9 74.23,39.9 78.19,43.85 78.48,43.85 79.63,42.71 80.02,42.71 80.34,43.03 80.34,43.33 79.2,44.47 79.2,44.87 79.55,45.22 79.85,45.22 81.01,44.06 81.37,44.06 81.58,44.27 81.58,44.7 80.45,45.82 80.45,46.12 80.87,46.54 81.17,46.54 82.1,45.62 82.63,45.62 85.71,48.7 90.64,48.7 91.45,49.51 95.64,49.51 96.05,49.1 97.11,49.1 97.46,48.75 100.66,48.75 101.24,49.33 v2(101.24,49.79)
  BOTTOM w0.102: v2(60.35,40.68) 60.35,40.6 60.09,40.34 59.72,40.34 59.64,40.43 59.5,40.43 59.24,40.68 56.41,40.68 56.28,40.56 56.28,39.92 56.18,39.82 55.92,39.82 55.82,39.92 55.82,40.33 55.72,40.43 55.51,40.43 55.41,40.33 55.41,39.92 55.31,39.82 55.05,39.82 54.94,39.93 54.94,40.25 54.87,40.33 54.6,40.33 54.5,40.22 54.5,39.83 54.4,39.73 54.22,39.73 54.12,39.83 54.12,40.02 54.02,40.12 JDIMM2.183 ; v2(68.79,39.59) 69.17,39.59 69.21,39.63 JDIMM1.183 ; v2(101.24,49.79) 101.98,50.53 103.49,50.53 103.49,50.52 103.5,50.52 103.58,50.44 103.84,50.44 103.93,50.54 104.19,50.54 UC1.AF40
DDRAB_SDQ39: length 77.3
  IN1 w0.211: v2(46.73,40.38) 47.02,40.09 54.33,40.09 v2(55.3,39.11)
  IN2 w0.211: v2(55.3,39.11) 55.38,39.04 57.08,39.04 57.52,39.48 59.11,39.48 59.44,39.15 62.64,39.15 62.74,39.05 64.18,39.05 64.3,38.92 67.78,38.92 67.97,39.11 72.27,39.11 72.51,39.35 74.41,39.35 78.06,42.99 78.59,42.99 79.41,42.18 80.22,42.18 86.22,48.18 91.01,48.18 91.82,48.99 92.59,48.99 92.82,48.76 93.61,48.76 93.84,48.99 95.43,48.99 95.83,48.58 96.89,48.58 97.26,48.21 100.79,48.21 101.82,49.25 v2(101.82,49.79)
  BOTTOM w0.102: v2(46.73,40.38) JDIMM2.182 ; v2(101.82,49.79) 102.01,49.61 102.72,49.61 102.97,49.86 102.97,49.86 103.01,49.89 103.49,49.89 103.59,49.99 103.84,49.99 UC1.AG40 ; JDIMM1.182 61.02,39.87 60.92,39.77 60.92,39.56 60.82,39.45 60.37,39.45 60.26,39.35 60.26,39.03 60.16,38.93 59.96,38.93 59.86,39.03 59.86,39.44 59.73,39.57 59.49,39.57 59.39,39.46 59.39,39.03 59.29,38.93 59.08,38.93 58.98,39.03 58.98,39.44 58.86,39.57 58.36,39.57 58.21,39.42 57.72,39.42 57.62,39.32 57.62,39.03 57.5,38.91 57.33,38.91 57.23,39.01 57.23,39.14 57.16,39.21 56.99,39.21 56.92,39.14 56.92,38.95 56.81,38.85 56.63,38.85 56.53,38.95 56.53,39.11 56.43,39.21 56.23,39.21 56.13,39.11 56.13,38.98 56.03,38.88 55.82,38.88 55.72,38.98 55.72,39.11 55.62,39.21 55.4,39.21 v2(55.3,39.11)
DDRAB_SDQ40: length 80.7
  IN1 w0.211: v2(68.8,37.1) 68.74,37.04 68.54,37.04 68.26,36.76 61.64,36.76 61.3,37.1 60.69,37.1 v2(60.68,37.08)
  IN2 w0.211: v2(60.68,37.08) 61.79,37.08 62.3,36.58 66.62,36.58 66.75,36.45 69.42,36.45 69.56,36.59 72.09,36.59 72.4,36.9 78.07,36.9 81.27,40.11 81.57,40.11 81.98,39.69 82.37,39.69 82.62,39.94 82.62,40.24 82.16,40.7 82.16,41 82.43,41.27 82.73,41.27 83.7,40.3 84,40.3 84.28,40.57 84.28,40.91 83.32,41.86 83.32,42.16 83.62,42.46 83.94,42.46 84.9,41.5 85.2,41.5 85.49,41.79 85.49,42.08 84.52,43.06 84.52,43.35 84.81,43.65 85.11,43.65 85.97,42.79 86.27,42.79 86.57,43.09 86.57,43.39 85.71,44.25 85.71,44.55 85.98,44.82 86.35,44.82 87.14,44.02 87.51,44.02 88.27,44.79 91.14,44.79 91.91,45.55 91.91,46.16 92.27,46.52 99.82,46.52 100.03,46.73 v2(100.03,47.73)
  BOTTOM w0.102: JDIMM1.195 68.92,36.63 68.8,36.74 v2(68.8,37.1) ; v2(60.68,37.08) 60.68,37.36 60.58,37.46 59.76,37.46 59.6,37.31 59.6,36.88 59.36,36.64 59.11,36.64 59,36.74 59,37.04 58.9,37.14 58.7,37.14 58.6,37.04 58.6,36.74 58.5,36.64 58.3,36.64 58.2,36.74 58.2,36.9 58.1,37 57.89,37 57.79,36.9 57.79,36.75 57.68,36.64 56.5,36.64 55.99,37.14 54.88,37.14 54.77,37.24 54.08,37.24 53.96,37.12 JDIMM2.195 ; UC1.AK41 103.01,48.56 102.98,48.59 100.89,48.59 v2(100.03,47.73)
DDRAB_SDQ41: length 78.1
  IN1 w0.211: v2(49.99,37.01) 50.97,37.01 51.33,36.65 51.33,36.62 51.6,36.35 54.41,36.35 v2(54.48,36.28)
  IN2 w0.211: v2(54.48,36.28) 54.67,36.47 58.51,36.47 58.61,36.57 61.58,36.57 62.09,36.06 66.41,36.06 66.53,35.94 69.63,35.94 69.77,36.08 72.55,36.08 72.86,36.39 78.28,36.39 80.01,38.12 80.78,38.12 80.99,38.33 80.99,38.46 81.2,38.67 81.62,38.67 81.83,38.46 81.83,38.33 82.04,38.12 82.55,38.12 87.37,42.94 87.37,43.16 88.48,44.27 91.36,44.27 92.69,45.6 94.12,45.6 94.5,45.98 100.35,45.98 101.23,46.86 101.23,47.55 v2(101.04,47.74)
  BOTTOM w0.102: UC1.AK40 104.19,48.34 103.93,48.34 103.84,48.24 103.58,48.24 103.5,48.32 103.49,48.32 103.49,48.33 102.89,48.33 102.83,48.39 101.69,48.39 v2(101.04,47.74) ; v2(49.99,37.01) 46.72,37.01 46.35,37.38 JDIMM2.194 ; v2(54.48,36.28) 54.34,36.28 54.22,36.39 54.22,36.61 54.33,36.71 54.73,36.71 54.85,36.84 55.05,36.84 55.16,36.73 55.16,36.39 55.27,36.28 55.49,36.28 55.59,36.38 55.59,36.71 55.69,36.81 55.9,36.81 56,36.71 56,36.39 56.11,36.28 56.57,36.28 56.63,36.34 59.49,36.34 59.87,36.72 60.12,36.72 60.22,36.61 60.22,36.3 60.46,36.07 60.64,36.07 60.87,36.29 60.87,36.7 61.05,36.87 JDIMM1.194
DDRAB_SDQ42: length 80.8
  IN1 w0.211: v2(67.22,33.24) 66.85,33.6 v2(59.73,33.6)
  IN2 w0.211: v2(59.73,33.6) 60.17,33.16 60.75,33.16 60.85,33.06 62.08,33.06 62.49,32.65 65.4,32.65 66.33,31.73 67.93,31.73 68.33,31.33 72.67,31.33 73.12,31.78 73.42,31.78 73.87,31.33 74.2,31.33 74.42,31.55 74.42,31.85 74,32.28 74,32.59 74.32,32.92 74.62,32.92 75.09,32.45 75.5,32.45 75.71,32.66 75.71,32.93 75.92,33.14 76.38,33.14 76.59,32.93 76.59,32.66 76.81,32.45 77.23,32.45 77.44,32.66 77.44,32.93 77.65,33.14 78.07,33.14 78.28,32.93 78.28,32.7 78.53,32.45 78.91,32.45 79.12,32.66 79.12,32.93 79.34,33.14 79.76,33.14 79.97,32.93 79.97,32.66 80.18,32.45 80.6,32.45 80.81,32.66 80.81,32.93 81.02,33.14 81.44,33.14 81.65,32.93 81.65,32.66 81.86,32.45 83.42,32.45 84.04,33.07 84.04,33.37 83.83,33.57 83.83,33.87 84.13,34.17 84.43,34.17 84.77,33.83 85.07,33.83 85.48,34.23 85.48,34.53 85.13,34.87 85.13,35.17 85.37,35.41 85.67,35.41 85.92,35.16 86.22,35.16 86.52,35.46 86.52,35.76 86.27,36.01 86.27,36.31 86.56,36.61 86.86,36.61 87.07,36.4 87.37,36.4 87.62,36.66 89.07,36.66 92.67,40.25 93.77,40.25 97.44,43.92 99.52,43.92 101.22,45.63 v2(101.22,45.8)
  BOTTOM w0.102: v2(101.22,45.8) 101.22,45.93 101.69,46.39 103.68,46.39 UC1.AP41 ; JDIMM1.207 67.61,33.63 v2(67.22,33.24) ; JDIMM2.207 54.04,34.12 54.16,34.24 54.16,34.6 54.26,34.7 54.78,34.7 54.98,34.5 54.98,33.89 55.1,33.77 55.38,33.77 55.48,33.87 55.48,34.07 55.58,34.18 55.78,34.18 55.89,34.07 55.89,33.87 55.99,33.77 56.19,33.77 56.29,33.87 56.29,34.07 56.39,34.18 56.6,34.18 56.7,34.07 56.7,33.81 56.8,33.71 57,33.71 57.11,33.81 57.11,34.07 57.21,34.18 57.47,34.18 57.7,34.4 57.84,34.4 57.94,34.3 57.94,34.2 58.23,33.91 58.23,33.82 58.35,33.7 59.62,33.7 v2(59.73,33.6)
DDRAB_SDQ43: length 78
  IN1 w0.211: v2(54.28,33.58) 54.08,33.38 51.37,33.38 50.91,33.84 v2(50.5,33.84)
  IN2 w0.211: v2(54.28,33.58) 56.86,33.58 56.87,33.57 59.03,33.57 59.95,32.64 60.53,32.64 60.63,32.54 61.87,32.54 62.28,32.14 65.19,32.14 66.11,31.21 67.72,31.21 68.12,30.81 74.65,30.81 75.77,31.94 83.63,31.94 85,33.31 85.29,33.31 88.06,36.09 89.23,36.09 92.88,39.74 93.98,39.74 97.65,43.41 99.73,43.41 101.81,45.48 v2(101.81,45.83)
  BOTTOM w0.102: v2(101.81,45.83) 102.16,46.19 103.39,46.19 103.45,46.13 103.49,46.13 103.56,46.06 103.84,46.06 104.14,46.36 UC1.AP40 ; v2(50.5,33.84) 50.47,33.87 50.1,33.87 49.83,33.61 49.55,33.61 49.28,33.87 JDIMM2.208 ; JDIMM1.208 61,33.38 60.82,33.19 59.56,33.19 59.35,33.4 58.56,33.4 58.46,33.3 58.46,33.08 58.36,32.98 58.03,32.98 57.93,33.08 57.93,33.78 57.83,33.88 57.56,33.88 57.45,33.77 57.45,33.1 57.35,32.99 57.09,32.99 56.62,33.46 54.97,33.46 54.7,33.74 54.44,33.74 v2(54.28,33.58)
DDRAB_SDQ44: length 80.6
  IN1 w0.211: v2(67.44,37.43) 67.15,37.43 66.97,37.61 61.52,37.61 60.96,38.17 v2(60.52,38.17)
  IN2 w0.211: v2(60.52,38.17) 60.58,38.12 62.22,38.12 62.73,37.61 63.96,37.61 64.24,37.89 68.21,37.89 68.4,38.08 72.7,38.08 72.94,38.32 74.84,38.32 75.78,39.26 76.08,39.26 77.37,37.96 77.67,37.96 77.96,38.26 77.96,38.56 76.67,39.86 76.67,40.15 77,40.48 77.3,40.48 78.59,39.19 78.89,39.19 79.17,39.46 79.17,39.81 77.9,41.08 77.9,41.38 78.13,41.62 78.51,41.62 79.67,40.45 80.16,40.45 85.55,45.85 86.18,45.85 86.39,46.06 86.39,46.9 86.65,47.15 86.98,47.15 87.2,46.94 87.2,46.09 87.43,45.85 87.83,45.85 88.04,46.06 88.04,46.94 88.25,47.15 88.67,47.15 88.88,46.94 88.88,46.55 89.11,46.33 89.57,46.33 89.72,46.48 89.72,46.94 89.94,47.15 91.44,47.15 91.84,47.55 98.58,47.55 v2(98.76,47.73)
  BOTTOM w0.102: v2(67.44,37.43) 67.44,37.52 67.54,37.63 JDIMM1.191 ; JDIMM2.191 54.02,38.12 54.03,38.11 54.44,38.11 54.6,38.28 54.81,38.28 54.93,38.16 54.93,37.95 55.13,37.75 56.06,37.75 56.18,37.87 56.46,37.87 56.58,37.75 57.06,37.75 57.17,37.86 57.17,38.18 57.27,38.28 57.47,38.28 57.57,38.18 57.57,37.85 57.67,37.75 57.95,37.75 58.06,37.86 58.06,38.41 58.22,38.56 58.41,38.56 58.57,38.4 58.57,38.18 58.67,38.08 58.98,38.08 59.08,38.18 59.08,38.22 59.18,38.32 60.42,38.32 60.52,38.22 v2(60.52,38.17) ; v2(98.76,47.73) 98.89,47.73 100.16,49 103.25,49 UC1.AJ41
DDRAB_SDQ45: length 77.7
  IN1 w0.211: v2(54.3,37.69) 49.79,37.69 49.23,38.25 47.05,38.25 v2(46.98,38.32)
  IN2 w0.211: v2(54.3,37.69) 54.38,37.61 55.17,37.61 55.24,37.54 57.36,37.54 57.86,38.05 59.68,38.05 60.13,37.6 62.01,37.6 62.51,37.09 66.83,37.09 66.96,36.97 68.02,36.97 68.61,37.56 72.91,37.56 73.15,37.8 73.71,37.8 74.1,37.42 74.52,37.42 74.84,37.74 75.26,37.74 75.83,38.31 76.25,38.31 76.46,38.1 76.46,37.63 76.67,37.42 77.85,37.42 85.77,45.33 86.56,45.33 87.05,44.85 87.6,44.85 88.09,45.33 90.44,45.33 90.65,45.54 90.65,46.42 90.86,46.63 91.65,46.63 92.05,47.04 99.21,47.04 99.43,47.26 v2(99.43,47.73)
  BOTTOM w0.102: UC1.AJ40 103.84,48.89 103.58,48.89 103.49,48.79 103.13,48.79 103.12,48.8 100.49,48.8 v2(99.43,47.73) ; v2(46.98,38.32) 46.47,38.32 46.41,38.38 JDIMM2.190 ; v2(54.3,37.69) 54.3,37.7 54.41,37.81 54.64,37.81 55,37.45 56.2,37.45 56.31,37.35 56.31,37.26 56.45,37.12 56.61,37.12 56.71,37.22 56.71,37.35 56.81,37.45 57.02,37.45 57.12,37.35 57.12,37.05 57.22,36.94 57.42,36.94 57.53,37.05 57.53,37.35 57.63,37.45 58.41,37.45 58.51,37.55 58.51,37.67 58.61,37.77 58.81,37.77 58.92,37.67 58.92,37.55 59.02,37.45 59.31,37.45 59.44,37.57 59.44,37.91 59.54,38.01 60.1,38.01 60.35,37.76 60.97,37.76 61.08,37.87 JDIMM1.190
DDRAB_SDQ46: length 80.6
  IN1 w0.211: v2(68.84,34.96) 68.82,34.94 68.76,34.94 68.32,34.5 65.74,34.5 65.62,34.62 60.42,34.62 v2(60.33,34.72)
  IN2 w0.211: v2(60.33,34.72) 60.45,34.6 60.76,34.6 61.27,34.09 62.51,34.09 62.92,33.68 65.85,33.68 66.78,32.76 68.52,32.76 68.54,32.78 71.41,32.78 72.72,32.78 74.12,34.17 82.67,34.17 86.95,38.45 87.25,38.45 87.88,37.82 88.18,37.82 88.48,38.12 88.48,38.42 87.85,39.05 87.85,39.35 88.15,39.65 88.45,39.65 89.38,38.72 89.68,38.72 89.98,39.02 89.98,39.32 89.05,40.25 89.05,40.55 89.33,40.83 89.63,40.83 89.99,40.48 90.29,40.48 90.5,40.69 90.5,42 90.71,42.21 91.08,42.21 91.27,42.02 91.27,41.04 91.48,40.83 91.78,40.83 92.03,41.08 92.03,42.06 92.23,42.26 92.65,42.26 92.86,42.05 92.86,41.58 93.07,41.37 93.43,41.37 93.68,41.63 93.68,42.54 93.89,42.75 94.81,42.75 97.01,44.95 98.85,44.95 v2(98.89,44.91)
  BOTTOM w0.102: v2(98.89,44.91) 98.83,44.98 98.83,45.55 100.19,46.91 UC1.AN41 ; JDIMM1.203 69.01,34.63 68.84,34.8 v2(68.84,34.96) ; v2(60.33,34.72) 60.18,34.56 60.18,34.45 60.04,34.31 58.78,34.31 58.55,34.55 58.55,35.5 58.45,35.6 57.43,35.6 57.33,35.5 57.33,34.89 57.22,34.79 55.79,34.79 55.5,35.08 55.5,35.43 55.36,35.57 54.28,35.57 54.12,35.41 54.12,35.25 54,35.12 JDIMM2.203
DDRAB_SDQ47: length 78.1
  IN1 w0.211: v2(50.5,34.87) 52.67,34.87 52.88,34.66 52.88,34.65 53.09,34.44 53.5,34.44 53.93,34.87 54.27,34.87 v2(54.5,35.11)
  IN2 w0.211: v2(54.5,35.11) 54.1,34.7 54.1,34.4 54.4,34.11 57.37,34.11 57.4,34.08 60.55,34.08 61.06,33.58 62.3,33.58 62.7,33.17 65.62,33.17 65.83,32.96 65.85,32.96 66.57,32.24 68.73,32.24 68.75,32.26 72.94,32.26 74.33,33.66 82.89,33.66 86.4,37.17 88.86,37.17 92.45,40.77 93.55,40.77 97.22,44.44 99.3,44.44 v2(99.84,44.98)
  BOTTOM w0.102: v2(99.84,44.98) 100.26,45.39 100.26,45.64 101.21,46.59 103.49,46.59 103.58,46.69 103.84,46.69 UC1.AN40 ; v2(50.5,34.87) JDIMM2.204 ; JDIMM1.204 61.07,34.38 60.97,34.27 60.97,34.12 60.87,34.01 60.72,34.01 60.55,34.18 60.35,34.18 60.17,34.01 58.57,34.01 58.24,34.33 58.24,35.17 58.11,35.3 57.73,35.3 57.63,35.2 57.63,34.76 57.35,34.48 55.43,34.48 55.19,34.72 55.19,35.15 55.08,35.26 54.66,35.26 v2(54.5,35.11)
DDRAB_SDQ48: length 81.6
  IN1 w0.211: v2(54.88,31.96) 54.71,31.79 53.21,31.79 52.92,32.09 52.44,32.09 52.14,31.79 50.61,31.79 v2(50.5,31.9)
  IN2 w0.211: v2(99.14,42.7) 99.13,42.7 94.62,38.19 93.52,38.19 90.21,34.88 90.21,33.78 85.94,29.51 80.78,29.51 79.9,30.39 76.41,30.39 74.88,28.86 71.16,28.86 70.75,29.27 67.48,29.27 67.08,29.66 65.47,29.66 64.95,30.18 63.2,30.18 62.79,30.59 61.64,30.59 61.23,31 60.01,31 59.55,31.45 59.14,31.45 58.69,31 58.29,31 57.67,31.61 56.75,31.61 56.53,31.82 56.53,32.22 56.31,32.44 55.91,32.44 55.69,32.22 55.69,31.87 55.48,31.66 55.18,31.66 v2(54.88,31.96)
  BOTTOM w0.102: JDIMM2.216 46.61,31.87 46.64,31.9 50.5,31.9 v2(50.5,31.9) ; v2(99.14,42.7) 99.14,43.19 99.72,43.77 100.3,43.77 101.48,44.95 103.1,44.95 103.18,45.02 103.49,45.02 103.57,44.94 103.84,44.94 103.93,45.04 104.19,45.04 UC1.AT40 ; v2(54.88,31.96) 54.88,32.16 55.27,32.55 56.24,32.55 56.41,32.38 56.41,32.38 56.79,32 56.79,31.27 56.96,31.1 57.14,31.1 57.23,31.2 57.23,31.62 57.31,31.69 57.48,31.69 57.55,31.62 57.55,31.2 57.65,31.1 57.86,31.1 57.96,31.2 57.96,31.39 58.06,31.49 58.27,31.49 58.37,31.39 58.37,31.2 58.47,31.1 58.65,31.1 58.75,31.2 58.75,31.31 58.86,31.42 59.06,31.42 59.16,31.31 59.16,31.2 59.26,31.1 60.01,31.1 60.28,31.38 JDIMM1.216
DDRAB_SDQ49: length 84.1
  IN1 w0.211: v2(68.93,31.79) 68.05,31.79 66.74,30.48 60.59,30.48 v2(60.53,30.53)
  IN2 w0.211: v2(60.53,30.53) 60.58,30.48 61.02,30.48 61.42,30.08 62.58,30.08 62.98,29.67 64.74,29.67 65.26,29.15 66.87,29.15 67.26,28.75 68.12,28.75 68.53,28.34 69.18,28.34 69.58,28.75 70.16,28.75 70.56,28.34 70.94,28.34 71.35,27.94 72.4,27.94 72.8,28.34 73.8,28.34 74.21,27.94 74.69,27.94 76.27,29.52 76.5,29.52 76.66,29.35 76.66,29.19 76.86,29 77.22,29 77.43,29.21 77.43,29.66 77.64,29.88 78,29.88 78.21,29.66 78.21,29.21 78.42,29 78.84,29 79.05,29.21 79.05,29.66 79.26,29.88 79.68,29.88 79.89,29.66 79.89,29.21 80.1,29 87.35,29 87.56,29.21 87.56,29.5 87.26,29.8 87.26,30.1 87.52,30.36 87.81,30.36 88.24,29.93 88.54,29.93 88.84,30.23 88.84,30.52 88.41,30.95 88.41,31.25 88.77,31.61 89.07,31.61 89.5,31.18 89.8,31.18 90.09,31.48 90.09,31.78 89.67,32.21 89.67,32.51 90.02,32.86 90.32,32.86 90.74,32.44 91.05,32.44 91.33,32.72 91.33,33.04 90.88,33.49 90.88,33.79 91.46,34.37 91.46,35.32 91.67,35.53 92.02,35.53 92.16,35.39 92.55,35.39 92.78,35.62 92.78,35.91 92.53,36.17 92.53,36.46 92.82,36.76 93.07,36.76 93.12,36.71 93.42,36.71 93.62,36.91 93.62,37.46 93.83,37.67 94.83,37.67 99.84,42.68 v2(99.84,42.7)
  BOTTOM w0.102: JDIMM2.215 54.08,32.12 54.65,31.55 55.05,31.55 55.29,31.79 55.29,32.11 55.42,32.25 56.11,32.25 56.28,32.08 56.49,31.87 56.49,31.14 56.83,30.8 60.14,30.8 60.41,31.07 60.76,31.07 60.87,30.96 60.87,30.63 60.76,30.53 v2(60.53,30.53) ; JDIMM1.215 69.1,31.63 v2(68.93,31.79) ; v2(99.84,42.7) 100.1,42.44 100.29,42.44 100.45,42.6 100.45,43.53 100.59,43.67 100.73,43.67 100.87,43.54 101.01,43.54 101.15,43.68 101.15,43.83 101.02,43.96 101.02,44.11 101.62,44.71 UC1.AU41
DDRAB_SDQ50: length 81.3
  IN1 w0.211: v2(54.92,28.81) 54.85,28.74 52.17,28.74 51.62,29.28 50.69,29.28 v2(50.44,29.04)
  IN2 w0.211: v2(103.4,41.99) 101.54,40.13 94.7,33.29 94.7,31.03 89.66,25.99 76.99,25.99 75.63,24.63 70.51,24.63 70.21,24.94 65.9,24.94 65.21,25.63 64.53,25.63 64.02,26.14 62.26,26.14 61.33,27.07 60.15,27.07 58.79,28.44 56.56,28.44 56.07,27.95 55.77,27.95 v2(54.92,28.81)
  BOTTOM w0.102: JDIMM2.228 46.31,28.87 46.34,28.9 50.31,28.9 v2(50.44,29.04) ; JDIMM1.228 60.92,28.38 60.81,28.27 60.81,27.7 60.71,27.6 60.44,27.6 60.34,27.7 60.34,27.85 60.24,27.96 60.04,27.96 59.94,27.85 59.94,27.71 59.83,27.61 59.58,27.61 59.45,27.74 59.45,28.45 58.99,28.9 57.75,28.9 57.61,29.04 57.61,29.48 57.5,29.58 57.24,29.58 57.14,29.48 57.14,29 57.04,28.9 55.64,28.9 55.35,29.18 55.19,29.18 54.92,28.91 v2(54.92,28.81) ; v2(103.4,41.99) 103.4,41.99 103.4,42.25 UC1.AY40
DDRAB_SDQ51: length 84.7
  IN1 w0.211: v2(67.9,28.29) 67.84,28.35 64.81,28.35 63.84,27.39 v2(59.19,27.39)
  IN2 w0.211: v2(59.19,27.39) 59.11,27.39 58.74,27.75 56.81,27.75 56.6,27.54 56.6,27.06 56.81,26.85 59.65,26.85 59.94,26.56 61.12,26.56 62.05,25.63 62.5,25.63 62.95,25.17 64.29,25.17 65.05,24.42 69.85,24.42 70.06,24.21 70.06,23.77 70.4,23.43 70.93,23.43 71.21,23.71 72.37,23.71 72.78,24.12 73.2,24.12 73.41,23.9 73.41,23.64 73.62,23.43 74.01,23.43 74.25,23.66 74.25,23.96 74.41,24.12 75.84,24.12 77.2,25.48 89.88,25.48 95.21,30.82 95.21,33.08 v2(103.16,41.02)
  BOTTOM w0.102: JDIMM2.229 53.96,28.63 54.14,28.8 54.35,28.8 54.75,28.4 55.09,28.4 55.28,28.59 56.35,28.59 56.45,28.49 56.45,28.11 56.55,28.01 56.76,28.01 56.86,28.11 56.86,28.49 56.96,28.59 57.16,28.59 57.26,28.49 57.26,28.11 57.36,28.01 57.55,28.01 57.67,28.13 57.67,28.49 57.77,28.59 57.97,28.59 58.08,28.49 58.08,28.11 58.18,28.01 58.37,28.01 58.48,28.13 58.48,28.49 58.59,28.6 58.86,28.6 59.14,28.32 59.14,28.09 58.88,27.83 58.88,27.48 58.99,27.38 59.18,27.38 v2(59.19,27.39) ; v2(103.16,41.02) 103.16,41.16 103.96,41.97 UC1.BA40 ; JDIMM1.229 68.98,28.13 68.81,28.29 v2(67.9,28.29)
DDRAB_SDQ52: length 84.6
  IN1 w0.211: v2(60.36,32.11) 60.5,32.25 66.88,32.25 67.8,33.17 v2(67.8,33.22)
  IN2 w0.211: v2(97.66,42.7) 97.66,42.69 94.19,39.22 93.09,39.22 89.06,35.18 88.75,35.18 88.47,35.47 88.17,35.47 87.77,35.06 87.77,34.76 88.52,34.01 88.52,33.57 88.22,33.27 87.87,33.27 87.07,34.06 86.77,34.06 86.56,33.85 86.56,33.55 87.39,32.72 87.39,32.42 87.09,32.12 86.8,32.12 86.05,32.87 85.73,32.87 85.45,32.59 85.45,32.38 86.25,31.58 86.25,31.28 86.04,31.07 85.74,31.07 85.24,31.58 85.24,31.58 84.79,32.02 84.45,32.02 84.13,31.71 84.13,31.38 84.46,31.05 84.46,30.75 84.25,30.54 82.89,30.54 82.68,30.75 82.68,31.21 82.47,31.42 82.05,31.42 81.84,31.21 81.84,30.75 81.62,30.54 81.2,30.54 80.99,30.75 80.99,31.21 80.78,31.42 75.99,31.42 74.86,30.3 67.91,30.3 67.51,30.7 65.9,30.7 65.38,31.22 63.62,31.22 63.22,31.62 62.06,31.62 61.66,32.03 60.43,32.03 v2(60.36,32.11)
  BOTTOM w0.102: v2(97.66,42.7) 97.66,44 97.95,44.29 100.24,44.29 101.36,45.41 102.81,45.41 102.86,45.46 103.46,45.46 103.49,45.49 103.49,45.49 103.59,45.59 103.84,45.59 UC1.AR40 ; JDIMM2.211 54.02,33.12 54.12,33.02 54.12,32.85 54.22,32.75 54.4,32.75 54.5,32.85 54.5,33.17 54.58,33.24 54.76,33.24 54.85,33.16 56.49,33.16 56.98,32.67 58.64,32.67 58.76,32.8 58.76,32.99 58.86,33.09 59.23,33.09 59.33,32.99 59.33,32.62 59.62,32.33 59.76,32.33 59.86,32.43 59.86,32.79 59.96,32.89 60.66,32.89 60.76,32.79 60.76,32.62 60.66,32.51 60.36,32.51 60.26,32.41 60.26,32.2 v2(60.36,32.11) ; JDIMM1.211 68.4,32.63 v2(67.8,33.22)
DDRAB_SDQ53: length 81.5
  IN1 w0.211: v2(50.5,32.86) 53.23,32.86 53.57,32.53 54.08,32.53 54.41,32.86 54.75,32.86 54.86,32.75 v2(54.9,32.75)
  IN2 w0.211: v2(54.9,32.75) 55.18,33.04 57.04,33.04 57.3,32.78 57.3,32.34 57.51,32.13 57.95,32.13 58.16,32.34 58.16,32.77 58.37,32.98 58.79,32.98 59,32.77 59,32.34 59.21,32.13 59.6,32.13 60.22,31.51 61.44,31.51 61.85,31.11 63,31.11 63.41,30.7 65.17,30.7 65.69,30.18 67.29,30.18 67.69,29.78 70.97,29.78 71.37,29.38 72.66,29.38 73.02,29.74 73.55,29.74 73.91,29.38 74.67,29.38 76.2,30.91 80.11,30.91 80.99,30.03 85.73,30.03 89.7,33.99 89.7,35.09 93.31,38.7 94.41,38.7 v2(98.4,42.7)
  BOTTOM w0.102: JDIMM1.212 60.96,32.38 60.85,32.27 60.85,31.78 60.75,31.68 60.16,31.68 59.88,31.41 59.49,31.41 59.39,31.51 59.39,31.77 59.2,31.96 59.2,32.31 59.08,32.43 58.89,32.43 58.79,32.33 58.79,31.79 58.69,31.69 58.5,31.69 58.38,31.81 58.38,32.27 58.28,32.37 58.08,32.37 57.97,32.27 57.97,32.02 57.87,31.92 57.69,31.92 57.57,32.04 57.57,32.27 57.47,32.37 57.32,32.37 57.19,32.24 56.99,32.24 56.37,32.85 55,32.85 v2(54.9,32.75) ; v2(98.4,42.7) 98.4,43.15 99.33,44.09 100.33,44.09 101.43,45.19 102.99,45.19 103.03,45.23 103.68,45.23 UC1.AT41 ; JDIMM2.212 50.49,32.87 v2(50.5,32.86)
DDRAB_SDQ54: length 81.7
  IN1 w0.211: v2(50.44,30.05) 50.69,29.8 54.4,29.8 v2(54.82,29.38)
  IN2 w0.211: v2(54.82,29.38) 55.17,29.38 55.6,28.95 59,28.95 60.37,27.59 61.55,27.59 62.47,26.66 64.23,26.66 64.74,26.15 65.42,26.15 66.12,25.45 70.42,25.45 70.73,25.15 75.41,25.15 76.78,26.51 89.45,26.51 94.14,31.2 94.14,33.47 102.44,41.76 v2(102.44,42.97)
  BOTTOM w0.102: JDIMM1.224 60.81,29.38 60.67,29.23 60.67,28.58 60.35,28.26 60,28.26 59.77,28.5 59.77,28.84 60.06,29.13 60.06,29.32 59.71,29.67 59.47,29.67 59.05,29.25 58.09,29.25 57.91,29.43 57.91,29.78 57.81,29.88 57,29.88 56.84,29.72 56.84,29.4 56.64,29.2 55.76,29.2 55.48,29.48 54.92,29.48 v2(54.82,29.38) ; UC1.AW40 103.62,43.17 103.21,43.17 103.02,42.97 v2(102.44,42.97) ; JDIMM2.224 46.59,29.87 46.77,30.05 v2(50.44,30.05)
DDRAB_SDQ55: length 85.2
  IN1 w0.211: v2(60.17,28.67) 60.25,28.59 63.01,28.59 63.01,28.58 63.39,28.58 63.4,28.59 64.15,28.59 64.88,29.32 68.63,29.32 68.88,29.07 v2(68.88,28.81)
  IN2 w0.211: v2(60.17,28.67) 60.17,28.51 60.58,28.1 61.76,28.1 62.69,27.18 64.44,27.18 64.96,26.66 65.64,26.66 66.33,25.97 67.69,25.97 67.98,26.25 68.27,26.25 68.56,25.97 69.21,25.97 69.57,26.33 70.17,26.33 70.55,25.95 71,25.95 71.29,25.66 71.83,25.66 72.13,25.97 72.75,25.97 73.06,25.66 73.54,25.66 73.85,25.97 74.34,25.97 74.64,25.66 75.2,25.66 76.56,27.02 88.43,27.02 88.8,27.4 89.1,27.4 89.2,27.3 89.52,27.3 89.8,27.59 89.8,27.89 89.7,28 89.7,28.3 89.99,28.59 90.31,28.59 90.41,28.5 90.71,28.5 91,28.79 91,29.08 90.89,29.19 90.89,29.49 91.19,29.79 91.49,29.79 91.59,29.68 91.89,29.68 92.19,29.98 92.19,30.28 92.08,30.38 92.08,30.68 92.38,30.98 92.68,30.98 92.79,30.87 93.08,30.87 93.38,31.17 93.38,31.47 93.27,31.58 93.28,31.87 93.63,32.23 93.63,32.58 93.39,32.83 93.39,33.12 93.63,33.36 93.63,33.68 v2(100.99,41.04)
  BOTTOM w0.102: JDIMM2.225 54.02,29.63 54.12,29.73 54.12,30.21 54.22,30.31 54.39,30.31 54.5,30.19 54.5,29.89 54.6,29.79 55.61,29.79 55.89,29.51 56.42,29.51 56.53,29.62 56.53,30.06 56.66,30.19 58.11,30.19 58.22,30.09 58.22,29.69 58.35,29.56 58.92,29.56 59.37,30.01 60.05,30.01 60.36,29.69 60.36,28.86 v2(60.17,28.67) ; v2(68.88,28.81) 69.2,29.13 JDIMM1.225 ; UC1.AY41 103.36,42.5 102.76,41.9 102.76,41.4 102.66,41.3 101.79,41.3 101.68,41.2 101.68,40.99 101.79,40.89 102.66,40.89 102.76,40.79 102.76,40.59 102.66,40.49 101.79,40.49 101.68,40.38 101.68,40.18 101.79,40.08 102.66,40.08 102.76,39.98 102.76,39.71 102.63,39.57 101.12,39.57 100.99,39.71 v2(100.99,41.04)
DDRAB_SDQ56: length 102.6
  IN1 w0.211: v2(68.75,26.43) 68.69,26.36 68.69,26.36 68.17,25.84 64.76,25.84 64.08,25.17 60.18,25.17 59.57,24.55 v2(59.56,24.55)
  IN2 w0.211: v2(59.56,24.55) 59.61,24.49 60.26,24.49 61.2,23.56 61.36,23.56 62.56,22.36 63.79,22.36 64,22.15 64,21.88 64.21,21.67 64.63,21.67 64.84,21.88 64.84,22.15 65.05,22.36 65.55,22.36 65.96,21.95 66.27,21.95 66.42,21.8 66.42,21.41 66.63,21.2 67.02,21.2 67.18,21.37 67.18,21.82 67.31,21.95 67.73,21.95 69.19,20.49 76.44,20.49 76.65,20.7 76.65,21 76.29,21.35 76.29,21.65 76.56,21.92 76.86,21.92 77.21,21.57 77.51,21.57 77.74,21.81 77.74,22.11 77.43,22.43 77.43,22.78 78.06,23.42 78.56,23.42 78.77,23.2 78.77,23 78.98,22.79 79.4,22.79 79.61,23 79.61,23.2 79.82,23.42 80.25,23.42 80.46,23.2 80.46,23 80.67,22.79 81.09,22.79 81.3,23 81.3,23.2 81.51,23.42 81.93,23.42 82.25,23.09 82.25,22.7 82.46,22.49 82.78,22.49 82.99,22.7 82.99,23.2 83.2,23.42 91.43,23.42 93.04,25.03 95.39,25.03 96.67,26.31 97.09,26.31 97.58,25.82 97.87,25.82 98.22,26.17 98.22,26.47 97.71,26.98 97.71,27.35 97.98,27.62 98.28,27.62 99.24,26.66 99.6,26.66 99.86,26.91 99.86,27.21 97.79,29.28 97.79,32.74 100.23,35.18 102.53,35.18 103.24,35.89 103.24,37.08 104.12,37.95 104.12,39.07 v2(104.52,39.47)
  BOTTOM w0.102: JDIMM2.237 54.12,26.63 54.4,26.35 55.18,26.35 55.3,26.47 55.3,27.04 55.4,27.14 55.7,27.14 55.84,27 55.84,26.37 55.97,26.24 56.66,26.24 56.76,26.14 56.76,25.65 56.86,25.55 57.06,25.55 57.17,25.65 57.17,26.18 57.27,26.29 57.84,26.29 57.96,26.17 57.96,25.42 58.05,25.33 58.64,25.33 58.81,25.16 59.37,25.16 59.66,24.87 59.66,24.65 v2(59.56,24.55) ; v2(68.75,26.43) 69.05,26.13 JDIMM1.237 ; 104.99,39.39 104.99,39.58 104.73,39.83 104.73,40.15 105.31,40.73 UC1.BA38
  BOTTOM w0.163: v2(104.52,39.47) 103.31,39.47 103.02,39.18 103.02,38.69 103.21,38.5 104.8,38.5 104.99,38.69 104.99,39.39
DDRAB_SDQ57: length 99.2
  IN1 w0.211: v2(54.9,26.81) 53.69,26.81 53.48,27.02 53.48,27.21 53.27,27.42 52.85,27.42 52.64,27.21 52.64,26.99 52.43,26.78 50.35,26.78 v2(50.25,26.87)
  IN2 w0.211: v2(54.9,26.81) 54.53,27.18 52.87,27.18 52.35,27.7 51.09,27.7 50.88,27.49 50.88,26.71 51.09,26.5 52.09,26.5 52.77,25.81 55.89,25.81 56.06,25.64 57.71,25.64 58.34,25.01 60.48,25.01 61.41,24.08 61.67,24.08 62.12,23.63 62.36,23.63 62.79,23.2 64.08,23.2 64.41,22.87 65.76,22.87 66.17,22.47 67.95,22.47 69.41,21.01 74.92,21.01 77.84,23.93 91.21,23.93 92.83,25.54 95.17,25.54 97.61,27.98 97.61,28.74 97.28,29.07 97.28,32.95 100.02,35.7 102.32,35.7 102.73,36.1 102.73,37.29 103.6,38.16 103.6,39.17 104.42,39.99 v2(105.11,39.99)
  BOTTOM w0.102: UC1.AY37 105.64,42.69 105.64,42.43 105.55,42.34 105.55,40.42 v2(105.11,39.99) ; JDIMM2.236 v2(50.25,26.87) ; JDIMM1.236 60.82,26.38 60.71,26.27 60.71,25.71 60.57,25.57 60.14,25.57 60.04,25.46 60.04,25.28 59.94,25.18 59.78,25.18 59.5,25.46 58.93,25.46 58.77,25.63 58.37,25.63 58.27,25.73 58.27,26.39 58.07,26.59 57.41,26.59 57.26,26.74 57.26,27 57.16,27.1 56.95,27.1 56.85,27 56.85,26.69 56.75,26.59 56.51,26.59 56.41,26.69 56.41,26.97 56.28,27.1 56.17,27.1 55.83,27.44 55,27.44 54.88,27.32 54.88,26.83 v2(54.9,26.81)
DDRAB_SDQ58: length 102.5
  IN1 w0.211: v2(67.97,22.93) 67.14,22.1 60.47,22.1 60.23,21.86 59.18,21.86 v2(58.95,21.64)
  IN2 w0.211: v2(107.78,40.53) 107.02,39.76 107.02,38.75 106.62,38.35 106.62,31.01 107.34,30.28 107.34,29.62 101.58,23.85 100.95,23.85 100.43,23.33 99.63,23.33 99.42,23.12 99.42,22.32 99.21,22.11 98.84,22.11 98.58,22.37 98.58,23.12 98.37,23.33 98.02,23.33 97.37,22.67 97.37,22.28 97.13,22.05 96.56,22.05 96.41,22.2 96.41,22.33 96.2,22.54 95.67,22.54 95.46,22.33 95.46,22.26 95.25,22.05 94.83,22.05 94.62,22.26 94.62,22.33 94.41,22.54 94.07,22.54 92.36,20.83 85.2,20.83 84.37,20 79.73,20 76.91,17.19 63.58,17.19 63.24,17.52 62.95,17.52 62.88,17.45 62.58,17.45 62.29,17.74 62.29,18.05 62.63,18.39 62.63,18.69 62.2,19.12 61.9,19.12 60.95,18.16 60.65,18.16 60.38,18.43 60.38,18.73 61.06,19.4 61.06,19.77 60.32,20.51 59.98,20.51 59.77,20.3 59.77,19.76 59.56,19.54 59.2,19.54 58.96,19.79 58.96,20.44 58.72,20.68 58.72,21.4 v2(58.95,21.64)
  BOTTOM w0.102: UC1.BA34 107.51,42.67 107.61,42.77 107.76,42.77 107.84,42.7 107.84,42.44 107.58,42.18 107.58,41.62 107.58,41.17 107.74,41.02 107.99,41.02 108.15,40.85 108.15,40.63 108.05,40.53 v2(107.78,40.53) ; JDIMM2.249 53.98,23.63 54.2,23.41 54.75,23.41 54.85,23.51 54.85,23.87 54.97,23.99 55.23,23.99 55.34,23.87 55.34,22.8 55.44,22.7 55.66,22.7 55.77,22.81 55.77,23.06 55.88,23.17 56.08,23.17 56.18,23.06 56.18,22.72 56.35,22.54 56.7,22.54 56.92,22.33 56.92,21.38 57.02,21.28 57.29,21.28 57.39,21.38 57.39,22.06 57.49,22.16 57.81,22.16 58.07,22.42 58.34,22.42 58.44,22.32 58.44,21.74 58.54,21.64 v2(58.95,21.64) ; JDIMM1.249 68.16,23.12 v2(67.97,22.93)
DDRAB_SDQ59: length 99.4
  IN1 w0.211: v2(54.63,23.01) 54.63,23.28 54.42,23.49 53.93,23.49 53.72,23.28 53.72,22.9 53.51,22.69 53.09,22.69 52.88,22.9 52.88,23.15 52.67,23.36 50.93,23.36 50.89,23.33 v2(50.13,23.33)
  IN2 w0.211: v2(107.96,41.46) 108.32,41.1 108.32,38.27 107.65,37.59 107.65,31.43 108.38,30.71 108.38,29.08 100.32,21.02 94.01,21.02 92.79,19.8 85.63,19.8 84.8,18.97 80.15,18.97 76.81,15.63 61.1,15.63 56.68,20.05 56.68,20.96 v2(54.63,23.01)
  BOTTOM w0.102: v2(107.96,41.46) 107.96,42.11 UC1.BA33 ; v2(50.13,23.33) 50.08,23.38 JDIMM2.250 ; JDIMM1.250 60.66,22.87 60.09,22.3 60.09,21.96 59.96,21.84 59.62,21.84 59.51,21.72 59.51,21.07 59.41,20.97 58.71,20.97 58.61,20.87 58.61,20.69 58.51,20.59 58.31,20.59 58.2,20.69 58.2,20.97 58.08,21.1 57.81,21.1 57.71,21 57.71,20.69 57.61,20.59 57.41,20.59 57.31,20.69 57.31,20.87 57.2,20.97 56.89,20.97 56.61,21.25 56.61,22.08 56.45,22.24 55.14,22.24 54.63,22.75 v2(54.63,23.01)
DDRAB_SDQ60: length 99.1
  IN1 w0.211: v2(50.38,28.02) 50.38,27.65 50.59,27.44 51.26,27.44 51.84,28.02 54.15,28.02 v2(54.28,28.15)
  IN2 w0.211: v2(103.71,40.85) 95.73,32.86 95.73,30.6 90.09,24.96 77.42,24.96 75.36,22.91 70.19,22.91 69.2,23.9 64.83,23.9 64.08,24.66 62.74,24.66 62.28,25.11 61.83,25.11 60.9,26.04 59.72,26.04 59.43,26.33 56.6,26.33 55.23,27.69 53.51,27.69 53.3,27.9 53.3,28.76 53.09,28.97 51.86,28.97 51.65,29.18 51.65,29.68 51.86,29.9 53.09,29.9 53.3,30.11 53.3,30.71 53.09,30.92 51.92,30.92 51.71,31.13 51.71,31.55 51.92,31.76 54.07,31.76 54.28,31.55 v2(54.28,28.15)
  BOTTOM w0.102: v2(54.28,28.15) 54.54,28.15 54.64,28.05 55.17,28.05 55.41,28.29 56.04,28.29 56.15,28.19 56.15,27.99 56.43,27.71 58.48,27.71 58.58,27.61 58.58,27.4 58.45,27.27 58.45,27.06 58.78,26.74 59.82,26.74 59.92,26.84 59.92,27.26 60.02,27.37 60.23,27.37 60.33,27.26 60.33,26.82 60.43,26.71 60.7,26.71 60.8,26.82 60.8,27.25 60.92,27.38 JDIMM1.232 ; JDIMM2.232 46.38,27.87 46.53,28.02 48.52,28.02 48.62,27.92 48.62,27.87 48.72,27.77 48.93,27.77 49.03,27.87 49.03,27.92 49.13,28.02 49.36,28.02 49.46,27.92 49.46,27.87 49.56,27.77 49.77,27.77 49.87,27.87 49.87,27.92 49.97,28.02 v2(50.38,28.02) ; v2(103.71,40.85) 103.78,40.91 103.78,41.5 104.35,42.06 104.35,42.49 UC1.AY39
DDRAB_SDQ61: length 102.4
  IN1 w0.211: v2(67.5,26.43) 64.21,26.43 63.94,26.16 59.51,26.16 59.24,25.89 v2(59.24,25.87)
  IN2 w0.211: v2(104.6,40.56) 104.04,40.56 102.68,39.2 102.68,38.79 102.94,38.53 102.94,38.23 102.64,37.94 102.35,37.94 102.09,38.19 101.79,38.19 101.49,37.9 101.49,37.6 102.21,36.88 102.21,36.53 101.94,36.25 101.64,36.25 100.89,37 100.6,37 96.76,33.16 96.76,32.37 96.55,32.16 96.46,32.16 96.25,31.95 96.25,31.53 96.46,31.32 96.55,31.32 96.76,31.11 96.76,30.46 96.6,30.31 96.17,30.31 95.87,30.01 95.87,29.58 97.03,28.42 97.03,28.13 96.59,27.69 96.28,27.69 95.15,28.83 94.74,28.83 94.5,28.59 94.5,28.29 95.65,27.13 95.65,26.77 95.3,26.42 95,26.42 93.84,27.58 93.44,27.58 93.16,27.31 93.16,27.01 93.57,26.6 93.57,26.3 93.33,26.06 92.85,26.06 92.53,26.38 92.23,26.38 91.52,25.67 91.52,25.08 91.16,24.72 90.58,24.72 90.3,24.45 77.63,24.45 75.58,22.39 74.89,22.39 74.68,22.18 74.68,21.74 74.47,21.52 74.05,21.52 73.84,21.74 73.84,22.18 73.63,22.39 73.21,22.39 73,22.18 73,21.74 72.78,21.52 72.36,21.52 72.15,21.74 72.15,22.18 71.94,22.39 71.18,22.39 70.97,22.18 70.97,21.74 70.76,21.52 70.33,21.52 70.12,21.74 70.12,22.22 69.91,22.43 68.71,22.43 68.43,22.72 68.43,23.17 68.2,23.39 64.62,23.39 63.87,24.14 62.33,24.14 61.88,24.59 61.63,24.59 60.69,25.53 59.45,25.53 59.24,25.74 v2(59.24,25.87)
  BOTTOM w0.102: v2(67.5,26.43) 68.2,27.13 JDIMM1.233 ; v2(59.24,25.87) 60.31,25.87 60.41,25.97 60.41,26.33 60.31,26.43 59.05,26.43 58.95,26.33 58.95,26.16 58.85,26.05 58.67,26.05 58.57,26.16 58.57,26.52 58.19,26.9 57.67,26.9 57.57,27 57.57,27.3 57.46,27.4 56.3,27.4 55.72,27.98 55.53,27.98 55.3,27.75 54.87,27.75 54.73,27.61 54.53,27.61 54.4,27.75 54.14,27.75 54.01,27.63 JDIMM2.233 ; UC1.AY38 105.09,43.04 105.09,42.78 105,42.69 105,42.45 105.08,42.35 105.08,41.45 104.87,41.25 104.28,41.25 104.1,41.06 104.1,40.53 103.97,40.4 103.21,40.4 103.14,40.33 103.14,39.9 103.21,39.83 104.13,39.83 104.6,40.31 v2(104.6,40.56)
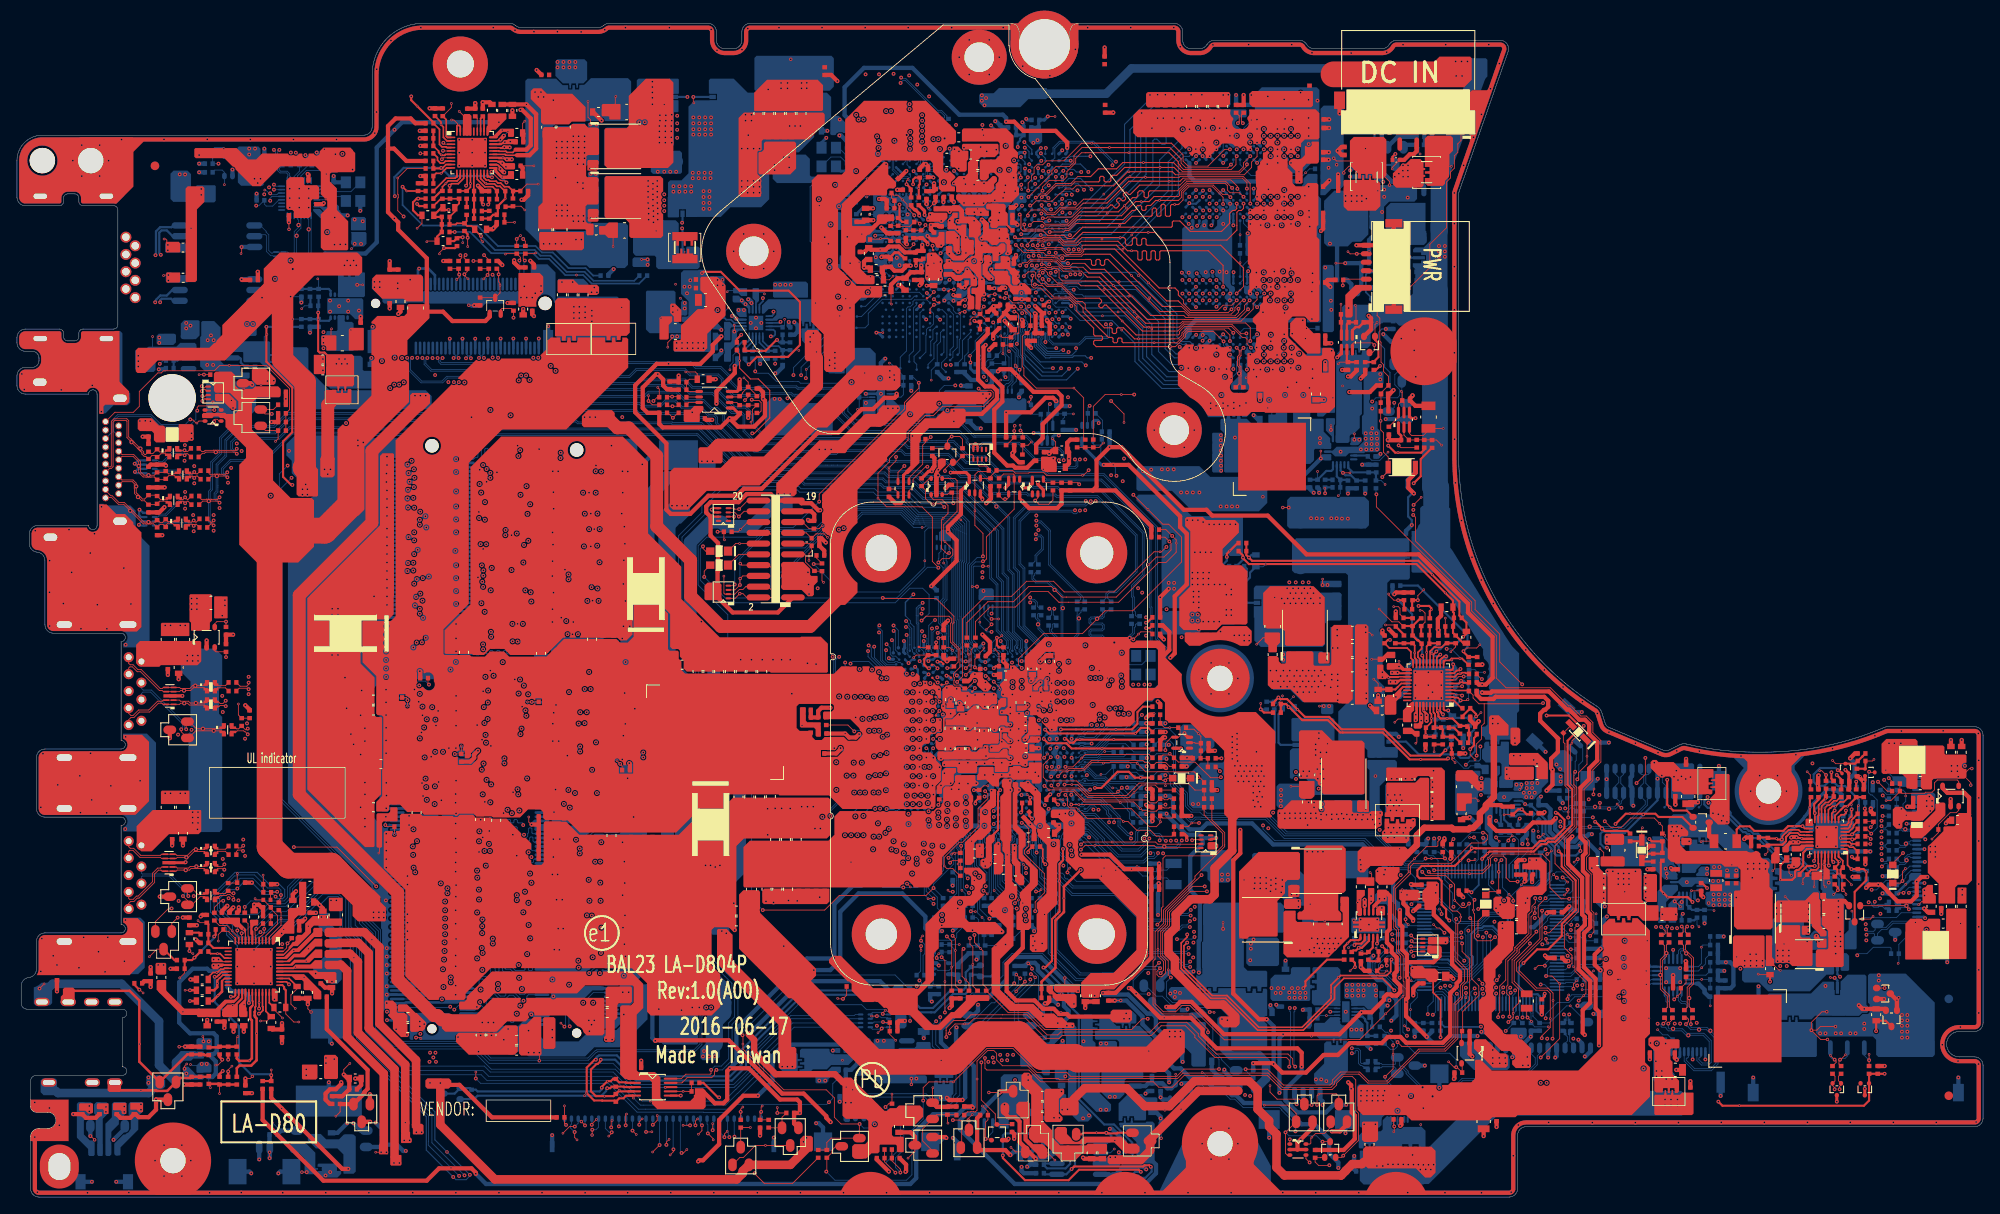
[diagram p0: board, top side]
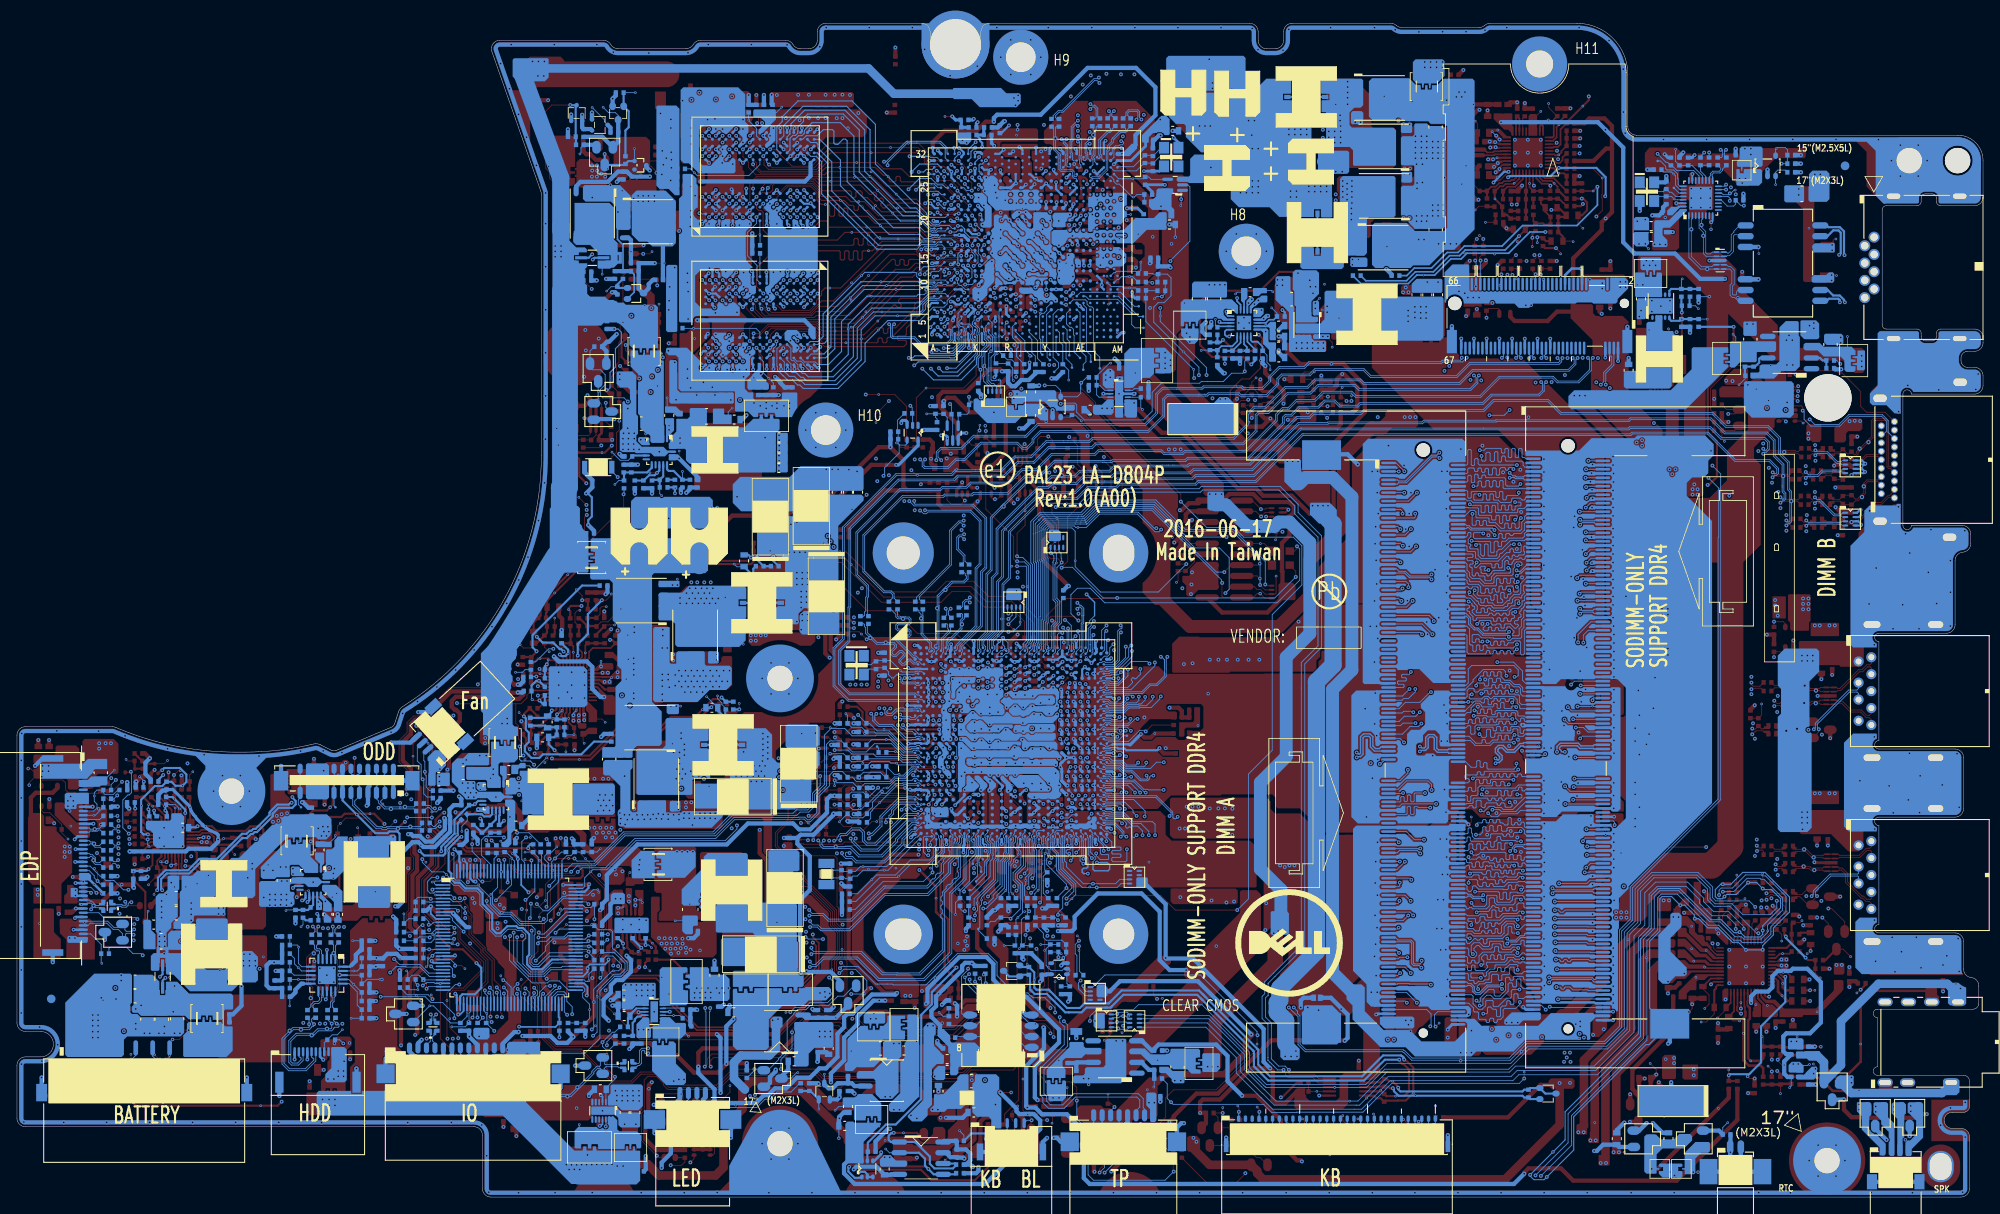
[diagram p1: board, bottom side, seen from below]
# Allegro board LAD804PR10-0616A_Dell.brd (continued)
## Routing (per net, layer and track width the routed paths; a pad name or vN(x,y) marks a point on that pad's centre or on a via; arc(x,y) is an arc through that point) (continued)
DDRAB_SDQ62: length 102.5
  IN1 w0.211: v2(66.79,22.93) 65.69,22.93 65.37,22.61 59.39,22.61 v2(59.37,22.59)
  IN2 w0.211: v2(106.96,40.65) 106.96,40.95 106.27,41.64 105.98,41.64 105.68,41.35 105.68,40.98 106.64,40.02 106.64,39.1 106.1,38.57 106.1,29.1 101.36,24.36 100.1,24.36 99.58,23.85 97.24,23.85 96.45,23.06 93.86,23.06 92.15,21.35 84.99,21.35 84.16,20.52 79.51,20.52 76.7,17.7 63.79,17.7 63.63,17.86 63.63,18.22 63.84,18.43 64.39,18.43 64.6,18.64 64.6,18.92 64.39,19.13 64.17,19.13 64.01,19.29 62.95,19.29 62.54,19.7 61.86,19.7 60.42,21.14 60.1,21.14 59.02,22.22 58.57,22.22 58.34,21.99 57.92,21.99 56.58,23.33 56.58,23.63 56.97,24.02 57.27,24.02 58.25,23.04 58.93,23.04 v2(59.37,22.59)
  BOTTOM w0.102: v2(66.79,22.93) 67.98,24.13 JDIMM1.245 ; v2(59.37,22.59) 59.34,22.56 59.11,22.56 58.99,22.69 58.99,23.36 58.54,23.81 58.07,23.81 57.66,23.41 56.88,23.41 56.02,24.26 56.02,25.12 55.87,25.28 55.62,25.28 55.48,25.15 55.48,24.9 55.38,24.8 55.12,24.8 55.02,24.9 55.02,25.63 54.91,25.74 54.62,25.74 54.5,25.62 54.5,24.88 54.25,24.63 JDIMM2.245 ; v2(106.96,40.65) 106.56,41.06 106.56,41.86 106.64,41.94 106.64,42.34 106.83,42.53 106.83,42.53 106.96,42.65 UC1.AY35
DDRAB_SDQ63: length 99.1
  IN1 w0.211: v2(54.69,24.49) 54.11,24.49 53.77,24.15 53.37,24.15 53.03,24.49 51.94,24.49 50.6,24.49 v2(50.31,24.78)
  IN2 w0.211: v2(54.69,24.49) 55.39,23.79 55.39,23.02 58.44,19.97 58.44,19.02 59.96,17.5 61.81,17.5 62.63,16.67 77.12,16.67 79.94,19.49 84.59,19.49 85.42,20.32 92.57,20.32 93.79,21.53 99.37,21.53 100.99,23.16 101.62,23.16 107.86,29.4 107.86,30.49 107.13,31.22 107.13,37.98 107.61,38.46 v2(107.61,39.71)
  BOTTOM w0.102: v2(54.69,24.49) 55.47,24.49 55.64,24.32 55.64,23.57 55.75,23.47 56.2,23.47 57.21,22.47 57.68,22.47 57.78,22.57 57.78,23.1 57.88,23.2 58.56,23.2 58.66,23.1 58.66,22.57 59.07,22.16 59.51,22.16 60.15,22.8 60.15,23.7 60.33,23.87 JDIMM1.246 ; JDIMM2.246 46.55,24.38 46.63,24.45 48.4,24.45 48.72,24.78 49.27,24.78 49.37,24.68 49.37,24.63 49.47,24.53 49.67,24.53 49.78,24.63 49.78,24.68 49.88,24.78 v2(50.31,24.78) ; UC1.AY34 107.29,43.04 107.29,42.78 107.2,42.69 107.2,42.43 107.36,42.26 107.36,39.96 v2(107.61,39.71)
DDRAB_SDQS0: length 84.9
  IN2 w0.147: v2(106.83,70.12) 106.85,70.1 107.13,70.1 107.32,70.3 107.32,70.62 106.95,70.99 106.95,72.34 107.96,73.35 107.96,78.61 101.23,85.34 92.84,85.34 92.08,86.11 74.72,86.11 72.98,87.85 67.72,87.85 66.61,86.74 65.33,86.74 64.69,87.38 64.31,87.38 64.13,87.2 v2(64.11,87.2) 64.11,87.23 63.91,87.43 62.66,87.43 62.43,87.2 60.39,87.2 57.99,84.8 56.32,84.8 56.1,85.01 55.98,85.01 v2(55.84,84.87)
  BOTTOM w0.102: UC1.B36 106.41,64 106.07,64.34 106.07,64.55 106.17,64.66 106.17,67.61 106.08,67.7 106.08,68.59 106.07,68.6
  BOTTOM w0.114: v2(106.83,70.12) 106.54,69.83 106.41,69.83 106.07,69.5 106.07,68.6 ; v2(55.84,84.87) 55.81,84.9 55.27,84.9 55.15,84.77 54.22,84.77 54.08,84.62 JDIMM2.13 ; v2(64.11,87.2) 64.24,87.33 64.97,87.33 68.02,84.28 68.94,84.28 69.09,84.13 JDIMM1.13
DDRAB_SDQS0#: length 84.9
  IN2 w0.147: v2(106.83,69.41) 106.85,69.43 106.85,69.54 107.13,69.81 107.24,69.81 107.61,70.18 107.61,70.74 107.24,71.11 107.24,72.22 108.25,73.23 108.25,78.73 101.35,85.63 92.96,85.63 92.2,86.39 74.84,86.39 73.1,88.13 67.6,88.13 66.49,87.02 65.45,87.02 64.81,87.67 64.3,87.67 v2(64.13,87.84) 64.06,87.84 63.94,87.72 62.55,87.72 62.31,87.49 60.27,87.49 57.87,85.09 56.43,85.09 56.22,85.3 56,85.3 v2(55.84,85.46)
  BOTTOM w0.102: 106.28,68.6 106.28,68.58 106.27,68.57 106.27,67.78 106.37,67.69 106.37,64.5 UC1.A36
  BOTTOM w0.114: v2(64.13,87.84) 64.43,87.54 65.06,87.54 68.11,84.49 68.94,84.49 69.07,84.62 JDIMM1.11 ; v2(55.84,85.46) 55.49,85.11 55.19,85.11 55.06,84.98 54.22,84.98 54.08,85.13 JDIMM2.11 ; 106.28,68.6 106.28,69.41 106.5,69.63 106.61,69.63 v2(106.83,69.41)
DDRAB_SDQS1: length 76.8
  IN2 w0.147: v2(101.68,66.63) 101.4,66.92 101.08,66.92 100.76,67.24 100.76,67.81 96.3,72.26 94.86,72.26 94.14,72.99 93.02,72.99 92.59,73.42 92.59,74.9 90.32,77.17 88.47,77.17 88.24,77.4 84.15,77.4 83.74,77 81.6,77 81.19,77.4 76.71,77.4 74.49,79.62 71.74,79.62 71.43,79.93 67.59,79.93 67.61,79.92 67.39,79.92 67.38,79.93 67.37,79.92 66.68,79.92 66.68,79.92 66.48,79.92 66.47,79.93 65.81,79.93 65.6,80.14 65.6,80.14 65.23,80.51 63.61,80.51 63.6,80.5 62.19,80.5 61.71,80.5 61.09,79.89 60.86,79.66 59.36,79.66 58.23,78.53 58.16,78.53 58.06,78.42 58.02,78.42 57.7,78.1 v2(57.6,78.1) 57.35,78.35 52.88,78.35 52.02,79.2 48.72,79.2 48.38,79.54 47.73,79.54 v2(47.52,79.33)
  BOTTOM w0.102: UC1.E40 103.79,62.31 103.49,62.61 102.54,62.61 101.87,63.29 101.87,66.51 101.75,66.63 101.69,66.63 v2(101.68,66.63)
  BOTTOM w0.114: v2(57.6,78.1) 58.22,78.71 60.4,78.71 60.7,79.01 60.83,79.01 60.97,78.88 JDIMM1.34 ; v2(47.52,79.33) 47.27,79.58 45.87,79.58 45.66,79.38 JDIMM2.34
DDRAB_SDQS1#: length 76.7
  IN2 w0.147: v2(47.52,79.92) 47.61,79.83 48.5,79.83 48.84,79.49 52.14,79.49 53,78.63 57.55,78.63 v2(57.63,78.71) 57.66,78.67 57.89,78.67 57.92,78.71 57.94,78.71 58.04,78.81 58.11,78.81 59.24,79.94 60.74,79.94 60.81,80.01 61.59,80.79 61.83,80.79 61.83,80.79 62.31,80.79 63.48,80.79 63.49,80.8 65.35,80.8 65.75,80.39 65.75,80.39 65.92,80.22 66.79,80.22 66.8,80.21 67.15,80.21 67.16,80.22 71.54,80.22 71.86,79.9 74.61,79.9 76.83,77.69 81.31,77.69 81.72,77.28 83.62,77.28 84.03,77.69 88.36,77.69 88.59,77.45 90.44,77.45 92.87,75.02 92.87,73.54 93.14,73.27 94.25,73.27 94.98,72.55 96.42,72.55 101.04,67.93 101.04,67.36 101.2,67.2 101.54,67.2 101.68,67.35 101.68,67.42 v2(101.72,67.46)
  BOTTOM w0.102: v2(101.72,67.46) 101.66,67.46 101.56,67.35 101.56,67.15 101.66,67.05 101.81,67.05 102.07,66.8 102.07,63.37 102.62,62.81 103.66,62.81 UC1.D41
  BOTTOM w0.114: v2(57.63,78.71) 57.84,78.92 60.32,78.92 60.61,79.22 60.88,79.22 61.04,79.38 JDIMM1.32 ; v2(47.52,79.92) 47.39,79.79 45.85,79.79 45.77,79.87 JDIMM2.32
DDRAB_SDQS2: length 65.3
  IN2 w0.147: v2(55.01,73.32) 55.21,73.32 55.32,73.21 58.57,73.21 59.37,74.01 62.2,74.01 62.34,73.87 62.51,73.7 63.85,73.7 64.36,73.2 64.52,73.04 64.9,73.04 v2(65.05,72.89) 65.2,73.04 68.73,73.04 68.99,72.77 73.45,72.77 79.31,66.91 85.45,66.91 86.61,65.75 94.38,65.75 95.51,64.63 96.04,64.63 96.46,64.22 96.46,63.99 v2(96.22,63.75)
  BOTTOM w0.102: 96.34,62.3 96.34,61.43 97.43,60.34 98.23,60.34 99.15,59.43 102.79,59.43 102.86,59.36 103.45,59.36 103.58,59.23 103.84,59.23 UC1.L40
  BOTTOM w0.114: 96.34,62.3 96.34,63.62 v2(96.22,63.75) ; v2(65.05,72.89) 65.24,73.07 67.66,73.07 68.21,73.62 JDIMM1.55 ; JDIMM2.55 53.98,74.13 54.48,73.62 54.61,73.62 54.81,73.42 54.91,73.42 v2(55.01,73.32)
DDRAB_SDQS2#: length 65.5
  IN2 w0.147: v2(96.98,63.75) 96.74,63.99 96.74,64.33 96.16,64.92 95.63,64.92 94.5,66.04 86.73,66.04 85.57,67.2 79.42,67.2 73.56,73.06 69.11,73.06 68.85,73.32 65.2,73.32 v2(65.05,73.47) 64.9,73.32 64.64,73.32 63.97,73.99 62.62,73.99 62.32,74.3 59.25,74.3 58.45,73.5 55.44,73.5 55.02,73.92 v2(55.02,73.95)
  BOTTOM w0.102: 96.55,62.51 96.55,61.88 96.54,61.87 96.54,61.51 97.51,60.54 98.31,60.54 99.23,59.62 102.87,59.62 102.94,59.56 UC1.K41
  BOTTOM w0.114: v2(65.05,73.47) 65.24,73.28 67.57,73.28 68.12,73.83 68.88,73.83 69.17,74.13 JDIMM1.53 ; v2(96.98,63.75) 96.9,63.75 96.55,63.4 96.55,62.51 ; v2(55.02,73.95) 54.9,73.83 54.57,73.83 54.22,74.18 54.22,74.19 53.78,74.62 JDIMM2.53
DDRAB_SDQS3: length 73.7
  IN2 w0.147: v2(47.52,68.83) 47.67,68.98 48.4,68.98 48.79,68.6 51.59,68.6 53.48,66.7 55.28,66.7 55.72,66.27 55.78,66.27 55.93,66.12 ; 55.93,66.12 55.96,66.12 56.24,66.4 56.86,66.4 57.01,66.25 61.02,66.25 61.36,65.91 63.35,65.91 64.17,65.08 68.12,65.08 68.12,65.08 69.57,65.08 70.76,63.9 72.84,63.9 79.56,57.18 80.44,57.18 81.17,56.45 90.36,56.45 90.75,56.84 95.36,56.84 95.55,57.03 99.99,57.03 100.18,56.83 100.18,56.58 100.03,56.42 v2(99.73,56.42) ; 55.93,66.12 v2(55.93,66.11)
  BOTTOM w0.102: v2(99.73,56.42) 100.02,56.42 100.79,55.65 102.91,55.65 103.09,55.83 103.24,55.83 UC1.U41
  BOTTOM w0.114: v2(55.93,66.11) 55.93,66.19 56.04,66.3 59,66.3 59.63,66.93 60.01,66.93 60.68,67.6 60.68,68.28 60.95,68.55 61.12,68.55 61.29,68.38 JDIMM1.76 ; JDIMM2.76 45.88,68.87 46.02,69.02 47.29,69.02 47.47,68.83 v2(47.52,68.83)
DDRAB_SDQS3#: length 73.5
  IN2 w0.147: v2(47.52,69.42) 47.67,69.27 48.52,69.27 48.9,68.88 51.7,68.88 53.6,66.99 55.61,66.99 v2(55.9,66.69) 55.91,66.68 56.98,66.68 57.13,66.53 61.14,66.53 61.48,66.19 63.46,66.19 64.29,65.37 68,65.37 68.01,65.37 69.69,65.37 70.87,64.18 72.95,64.18 79.67,57.46 80.56,57.46 81.29,56.73 90.24,56.73 90.63,57.12 95.24,57.12 95.43,57.31 100.1,57.31 100.48,56.94 100.48,56.5 v2(100.56,56.42)
  BOTTOM w0.102: v2(100.56,56.42) 100.56,56.16 100.88,55.84 102.82,55.84 103.01,56.03 103.48,56.03 103.79,55.71 UC1.U40
  BOTTOM w0.114: JDIMM2.74 45.88,69.38 46.02,69.23 47.33,69.23 v2(47.52,69.42) ; v2(55.9,66.69) 56.09,66.51 58.92,66.51 59.55,67.14 59.93,67.14 60.47,67.68 60.47,68.36 60.99,68.88 JDIMM1.74
DDRAB_SDQS4: length 63.2
  IN2 w0.147: v2(55.15,40.83) 55.36,40.62 55.36,40.48 55.68,40.17 58.23,40.17 59.26,41.2 60.66,41.2 60.75,41.11 61.77,41.11 62.03,41.37 63.74,41.37 64.43,40.68 66.25,40.68 v2(66.38,40.55) 66.5,40.67 67.08,40.67 67.57,41.15 72.53,41.15 72.68,41 73.77,41 83.38,50.61 96.1,50.61 96.27,50.44 98.01,50.44 98.21,50.24 98.21,50.08 v2(97.86,49.73)
  BOTTOM w0.102: v2(97.86,49.73) 98.15,49.73 98.33,49.55 98.33,49.34 98.54,49.12 99.42,49.12 100.46,50.17 101.33,50.17 101.89,50.73 103.68,50.73 UC1.AF41
  BOTTOM w0.114: v2(66.38,40.55) 66.57,40.74 66.74,40.91 68.81,40.91 69.09,40.63 JDIMM1.179 ; v2(55.15,40.83) 55.31,40.99 55.31,41.16 55.11,41.36 54.31,41.36 54.08,41.12 JDIMM2.179
DDRAB_SDQS4#: length 63.1
  IN2 w0.147: 66.38,41.12 v2(66.38,41.13) ; 66.38,41.12 66.22,40.96 64.55,40.96 63.86,41.65 61.91,41.65 61.66,41.4 60.86,41.4 60.78,41.48 59.14,41.48 58.12,40.45 55.8,40.45 55.65,40.6 55.65,40.7 v2(55.79,40.83) ; 66.38,41.12 66.54,40.95 66.97,40.95 67.45,41.44 72.65,41.44 72.8,41.28 73.65,41.28 83.26,50.89 96.22,50.89 96.39,50.72 98.13,50.72 98.5,50.36 98.5,49.89 v2(98.66,49.73)
  BOTTOM w0.102: v2(98.66,49.73) 98.52,49.59 98.52,49.42 98.62,49.32 99.34,49.32 100.38,50.36 101.25,50.36 101.81,50.93 103.42,50.93 103.61,51.11 103.86,51.11 UC1.AE40
  BOTTOM w0.114: v2(66.38,41.13) 66.38,41.12 66.43,41.06 66.6,41.06 66.65,41.12 70.11,41.12 JDIMM1.177 ; v2(55.79,40.83) 55.52,41.1 55.52,41.24 55.2,41.56 54.14,41.56 54.08,41.63 JDIMM2.177
DDRAB_SDQS5: length 70
  IN2 w0.147: v2(50.78,35.85) 50.93,35.99 53.22,35.99 53.67,35.54 57.25,35.54 57.66,35.13 58.86,35.13 v2(58.95,35.04) 59.1,35.18 61,35.18 61.51,34.68 62.75,34.68 63.16,34.27 66.1,34.27 66.12,34.25 73.36,34.25 73.87,34.76 82.43,34.76 90.52,42.84 92.21,42.84 93.28,43.92 95.14,43.92 95.69,44.46 95.69,44.72 v2(95.95,44.97)
  BOTTOM w0.102: v2(95.95,44.97) 95.78,45.14 95.78,45.36 97.58,47.15 103.1,47.15 103.18,47.22 103.49,47.22 103.57,47.14 103.84,47.14 103.93,47.24 104.19,47.24 UC1.AM40
  BOTTOM w0.114: JDIMM2.200 45.88,35.87 46.04,36.04 50.59,36.04 v2(50.78,35.85) ; JDIMM1.200 60.89,35.38 60.75,35.52 60.48,35.52 60.18,35.22 59.13,35.22 v2(58.95,35.04)
DDRAB_SDQS5#: length 69.9
  IN2 w0.147: v2(95,44.87) 95.19,44.87 95.34,44.72 95.34,44.51 95.03,44.2 93.17,44.2 92.09,43.13 90.4,43.13 82.31,35.04 73.76,35.04 73.25,34.53 66.24,34.53 66.22,34.55 63.28,34.55 62.87,34.96 61.63,34.96 61.12,35.47 59.11,35.47 v2(58.95,35.62) 58.75,35.42 57.77,35.42 57.37,35.82 53.78,35.82 53.33,36.28 50.94,36.28 v2(50.78,36.43)
  BOTTOM w0.102: 95.27,44.65 95.46,44.65 95.56,44.76 95.56,45.14 95.58,45.16 95.58,45.44 97.49,47.35 103.02,47.35 103.09,47.42 103.67,47.42 UC1.AM41
  BOTTOM w0.114: JDIMM1.198 60.89,35.87 60.75,35.73 60.39,35.73 60.09,35.43 59.15,35.43 v2(58.95,35.62) ; v2(95,44.87) 95,44.82 95.17,44.65 95.27,44.65 ; JDIMM2.198 45.88,36.38 46.01,36.24 50.59,36.24 v2(50.78,36.43)
DDRAB_SDQS6: length 68.8
  IN2 w0.147: v2(56.13,29.91) 57.03,29.91 57.41,29.54 59.54,29.54 59.98,29.1 60.44,29.1 60.85,28.69 62,28.69 62.93,27.76 64.69,27.76 65.09,27.36 65.96,27.36 v2(66.25,27.07) 66.27,27.09 66.97,27.09 67.15,26.91 70.42,26.91 70.77,26.55 75.26,26.55 76.32,27.61 88.18,27.61 92.72,32.14 92.72,33.6 94.25,35.13 94.25,35.57 94.57,35.88 95,35.88 100.56,41.44 101.03,41.44 101.62,42.03 101.62,42.45 v2(101.7,42.52)
  BOTTOM w0.102: UC1.AV40 103.93,43.94 103.84,43.84 103.6,43.84 103.48,43.94 102.43,43.94 101.54,43.05 101.54,42.68 v2(101.7,42.52)
  BOTTOM w0.114: v2(56.13,29.91) 55.94,30.1 55.04,30.1 54.51,30.63 JDIMM2.221 ; JDIMM1.221 67.56,30.13 67.39,29.96 67.39,27.54 67.16,27.31 66.49,27.31 v2(66.25,27.07)
DDRAB_SDQS6#: length 69.1
  IN2 w0.147: v2(101.04,42.52) 101.16,42.52 101.34,42.35 101.34,42.15 100.91,41.72 100.44,41.72 94.88,36.16 94.45,36.16 93.97,35.68 93.97,35.25 92.43,33.71 92.43,32.26 88.06,27.89 76.2,27.89 75.14,26.84 70.89,26.84 70.53,27.2 67.27,27.2 67.09,27.37 66.56,27.37 66.25,27.68 66.25,27.86 v2(66.22,27.89) 66.12,27.8 66.12,27.79 65.98,27.64 65.21,27.64 64.8,28.05 63.05,28.05 62.12,28.97 60.97,28.97 60.56,29.38 60.1,29.38 59.66,29.82 57.53,29.82 57.15,30.2 56.45,30.2 56.15,30.5 v2(56.13,30.5)
  BOTTOM w0.102: v2(101.04,42.52) 101.21,42.52 101.34,42.66 101.34,43.13 102.35,44.14 103.48,44.14 103.5,44.16 UC1.AV41
  BOTTOM w0.114: JDIMM1.219 69.3,30.63 69.01,30.33 67.47,30.33 67.19,30.05 67.19,27.63 67.07,27.51 66.39,27.51 66.22,27.69 v2(66.22,27.89) ; v2(56.13,30.5) 55.94,30.31 55.12,30.31 54.6,30.83 54.17,30.83 54.06,30.94 54.06,31.07 54.01,31.12 JDIMM2.219
DDRAB_SDQS7: length 90.3
  IN2 w0.147: v2(51.17,25.33) 51.32,25.48 51.82,25.48 52.36,24.94 55.47,24.94 55.7,24.71 56.58,24.71 v2(56.73,24.56) 56.94,24.77 57.35,24.77 58.5,23.62 59.9,23.62 60.84,22.69 61,22.69 62.89,20.8 65.81,20.8 66.98,19.62 77.06,19.62 79.06,21.62 83.14,21.62 84.06,22.55 91.79,22.55 93.4,24.16 95.99,24.16 96.78,24.95 99.13,24.95 100.73,26.55 100.73,27.57 98.66,29.64 98.66,32.38 100.59,34.31 103.02,34.31 104.11,35.4 104.11,36.71 104.99,37.59 104.99,38.86 105.62,39.5 105.96,39.5 105.97,39.48 105.97,39.48 v2(106.12,39.33)
  BOTTOM w0.102: UC1.BA36 106.36,42.51 106.36,41.98 106.31,41.93 106.31,40.27 106.5,40.08 106.5,39.71 106.18,39.39
  BOTTOM w0.114: JDIMM2.242 45.88,25.38 46.17,25.67 50.83,25.67 v2(51.17,25.33) ; JDIMM1.242 60.89,24.87 60.79,24.97 60.47,24.97 60.18,24.69 60.18,24.23 59.87,23.92 59.3,23.92 58.42,24.81 56.98,24.81 v2(56.73,24.56) ; 106.18,39.39 v2(106.12,39.33)
DDRAB_SDQS7#: length 90.1
  IN2 w0.147: v2(106.12,39.92) 105.99,39.78 105.5,39.78 104.7,38.98 104.7,37.71 103.83,36.83 103.83,35.52 102.9,34.59 100.48,34.59 98.38,32.49 98.38,29.53 100.45,27.46 100.45,26.67 99.01,25.23 96.66,25.23 95.87,24.44 93.28,24.44 91.67,22.83 83.95,22.83 83.02,21.9 78.94,21.9 76.94,19.91 67.1,19.91 65.92,21.08 63.01,21.08 61.12,22.97 60.96,22.97 60.02,23.91 58.62,23.91 57.47,25.05 56.82,25.05 v2(56.73,25.14) 56.59,25 55.82,25 55.59,25.23 52.48,25.23 51.94,25.77 51.32,25.77 v2(51.17,25.92)
  BOTTOM w0.102: v2(106.12,39.92) 106.11,39.93 106.11,42.01 106.16,42.06 106.16,42.37 106.11,42.43 106.11,42.73 106.41,43.03 UC1.AY36
  BOTTOM w0.114: v2(51.17,25.92) 51.1,25.85 50.94,25.85 50.92,25.87 46.08,25.87 45.88,25.68 45.72,25.68 45.52,25.87 JDIMM2.240 ; JDIMM1.240 60.89,25.38 60.7,25.18 60.38,25.18 59.97,24.77 59.97,24.32 59.78,24.13 59.39,24.13 58.5,25.01 56.86,25.01 v2(56.73,25.14)
DDRAB_SMA0: length 79
  IN1 w0.102: v2(105.66,50.76) 105.5,50.76 105.12,50.38 104.33,50.38 102.11,48.17 102.11,47.31 101.75,46.94 101.11,46.94 100.64,46.47 100.1,46.47
  IN1 w0.211: 100.1,46.47 95.22,46.47 93.77,45.02 88.95,45.02 88.18,44.25 82.07,44.25 76.76,49.56 74.06,49.56 73.55,50.07 73.06,50.07 72.48,50.65 72.46,50.65 70.72,50.65 70.13,51.24 66.16,51.24 65.66,50.75 62.62,50.75 61.73,49.86 56.88,49.86 55.59,51.15 v2(55.03,51.15)
  IN2 w0.211: v2(55.03,51.15) 48.81,51.15 v2(48.09,51.87)
  BOTTOM w0.102: v2(48.09,51.87) JDIMM2.144 ; v2(105.66,50.76) 105.66,50.41 UC1.AG38 ; JDIMM1.144 61.03,51.38 60.37,50.71 59.83,50.71 59.72,50.82 59.72,51.41 59.62,51.52 59.42,51.52 59.32,51.41 59.32,50.82 59.22,50.71 59.01,50.71 58.91,50.82 58.91,51.16 58.81,51.26 58.61,51.26 58.51,51.16 58.51,50.63 58.38,50.5 55.33,50.5 55.03,50.8 v2(55.03,51.15)
DDRAB_SMA1: length 76.3
  IN1 w0.102: v2(107.26,55.16) 106.84,55.58 105.37,55.58 105.2,55.74 103.74,55.74 103.53,55.96 100.1,55.96
  IN1 w0.211: 100.1,55.96 98.91,55.96 98.27,56.6 95.71,56.6 94.24,58.06 85.48,58.06 84.79,58.76 82.34,58.76 82.13,58.97 82.13,59.43 81.91,59.64 81.47,59.64 81.3,59.48 81.3,58.97 81.09,58.76 80.79,58.76 80.54,59.01 80.54,59.33 80.22,59.64 79.78,59.64 79.48,59.35 79.48,59.05 79.79,58.75 79.79,58.45 79.51,58.17 79.21,58.17 78.84,58.55 78.54,58.55 77.17,57.18 77.17,57.17 70.29,57.17 69.39,56.27 67.98,56.27 67.11,55.4 62.26,55.4 61.56,54.7 59.46,54.7 v2(59.39,54.63)
  IN2 w0.211: v2(68.29,53.65) 65.2,53.65 64.19,54.66 59.42,54.66 v2(59.39,54.63)
  BOTTOM w0.102: JDIMM2.133 54,54.62 54.26,54.37 54.75,54.37 54.86,54.48 54.86,55.13 54.98,55.25 55.35,55.25 55.46,55.15 55.46,54.92 55.62,54.76 57.48,54.76 57.58,54.65 57.58,54.35 57.68,54.25 57.99,54.25 58.09,54.35 58.09,55.1 58.19,55.2 58.47,55.2 58.57,55.1 58.57,54.37 58.7,54.24 59.07,54.24 59.19,54.36 59.19,54.42 v2(59.39,54.63) ; v2(68.29,53.65) 68.77,54.13 JDIMM1.133 ; UC1.W35 107.06,54.96 v2(107.26,55.16)
DDRAB_SMA2: length 76.4
  IN1 w0.102: 100.1,55.44 100.41,55.44 100.5,55.54 105.12,55.54 105.5,55.16 v2(105.66,55.16)
  IN1 w0.211: 100.1,55.44 95.83,55.44 93.73,57.55 85.26,57.55 84.75,58.06 83.03,58.06 82.51,57.55 78.28,57.55 77.39,56.66 70.29,56.66 69.54,55.9 68.13,55.9 67.2,54.97 64.46,54.97 64.37,54.88 62.47,54.88 61.43,53.84 60.2,53.84 59.9,53.55 58.86,53.55 57.21,55.2 55.48,55.2 55.27,54.99 v2(55.27,54.54)
  IN2 w0.211: v2(55.27,54.54) 55.06,54.54 54.52,55.07 48.36,55.07 v2(48.03,55.41)
  BOTTOM w0.102: v2(48.03,55.41) 47.14,55.41 46.6,54.87 JDIMM2.132 ; v2(55.27,54.54) 55.52,54.28 55.52,54.06 55.65,53.93 55.88,53.93 55.98,54.03 55.98,54.4 56.08,54.5 56.28,54.5 56.39,54.4 56.39,54.03 56.49,53.93 56.69,53.93 56.79,54.03 56.79,54.4 56.89,54.5 57.1,54.5 57.2,54.4 57.2,54.03 57.3,53.93 57.85,53.93 58.23,53.55 58.58,53.55 58.69,53.65 58.69,53.88 58.79,53.98 58.99,53.98 59.09,53.88 59.09,53.65 59.19,53.55 59.8,53.55 60.62,54.38 JDIMM1.132 ; UC1.W38 105.66,54.81 v2(105.66,55.16)
DDRAB_SMA3: length 75.9
  IN1 w0.102: 100.1,57.12 102.66,57.12 103.83,55.95 105.29,55.95 105.45,55.78 106.92,55.78 107.06,55.64 107.58,55.64 v2(108.06,55.16)
  IN1 w0.211: 100.1,57.12 95.92,57.12 95.49,57.55 95.49,58.37 95.28,58.58 86.12,58.58 85.69,59.01 85.26,59.01 84.7,59.57 84.7,60 84.55,60.15 83.75,60.15 83.54,59.94 83.54,59.8 83.33,59.59 82.9,59.59 82.69,59.8 82.69,59.95 82.48,60.16 79.43,60.16 76.95,57.69 73.4,57.69 73.27,57.56 70.16,57.56 69.24,56.63 67.83,56.63 67.59,56.38 64.42,56.38 64.35,56.32 62.45,56.32 61.33,55.2 59.6,55.2 v2(59.52,55.28)
  IN2 w0.211: v2(59.52,55.28) 65.48,55.28 66.07,55.87 v2(66.25,55.87)
  BOTTOM w0.102: v2(108.06,55.16) 107.86,54.96 UC1.W34 ; JDIMM2.131 54.11,55.13 54.19,55.05 54.19,54.8 54.29,54.7 54.48,54.7 54.6,54.82 54.6,55.36 54.78,55.53 55.61,55.53 55.71,55.43 55.71,55.11 55.81,55.01 56.01,55.01 56.12,55.11 56.12,55.43 56.22,55.53 56.42,55.53 56.52,55.43 56.52,55.11 56.62,55.01 56.83,55.01 56.93,55.11 56.93,55.43 57.03,55.53 57.27,55.53 57.38,55.43 57.38,55.11 57.48,55.01 57.68,55.01 57.78,55.11 57.78,55.35 57.88,55.45 59.34,55.45 v2(59.52,55.28) ; JDIMM1.131 68.49,54.62 67.6,55.52 66.6,55.52 v2(66.25,55.87)
DDRAB_SMA4: length 75.4
  IN1 w0.102: 100.1,57.63 102.62,57.63 103.99,56.26 v2(105.66,56.26)
  IN1 w0.211: v2(55.14,55.94) 55.47,55.94 55.53,55.88 61.5,55.88 62.3,56.68 64.2,56.68 64.26,56.75 67.44,56.75 67.68,56.99 69.08,56.99 70.01,57.92 73.12,57.92 73.4,58.2 76.74,58.2 79.21,60.68 84.76,60.68 86.34,59.1 95.58,59.1 97.04,57.63 100.1,57.63
  IN2 w0.211: v2(55.14,55.94) 54.72,55.94 54.46,56.19 49.51,56.19 v2(49.36,56.34)
  BOTTOM w0.102: JDIMM1.128 60.99,55.38 60.75,55.62 60.54,55.62 60.43,55.52 60.43,54.72 60.33,54.62 60.05,54.62 59.93,54.75 59.93,55.52 59.74,55.71 57.46,55.71 57.38,55.79 57.19,55.79 57.09,55.89 57.09,56.05 56.99,56.15 56.79,56.15 56.69,56.05 56.69,55.89 56.59,55.79 56.38,55.79 56.28,55.89 56.28,56.05 56.18,56.15 55.98,56.15 55.87,56.05 55.87,55.89 55.77,55.79 55.29,55.79 v2(55.14,55.94) ; v2(105.66,56.26) 105.66,55.91 UC1.U38 ; JDIMM2.128 48.89,55.87 v2(49.36,56.34)
DDRAB_SMA5: length 76.8
  IN1 w0.102: 100.1,58.15 102.39,58.15 103.9,56.64 106.08,56.64 v2(106.46,56.26)
  IN1 w0.211: 100.1,58.15 97.25,58.15 95.79,59.61 86.55,59.61 84.87,61.3 79.1,61.3 76.52,58.72 73.4,58.72 73.27,58.59 72.97,58.28 69.86,58.28 69.25,57.67 64.18,57.67 64.11,57.6 62.71,57.6 61.35,56.24 55.68,56.24 v2(55.52,56.41)
  IN2 w0.211: v2(48.34,56.38) 48.82,56.85 49.14,56.85 49.15,56.86 49.57,56.86 49.58,56.85 52.92,56.85 53.06,56.71 54.68,56.71 54.93,56.46 55.35,56.46 55.4,56.41 v2(55.52,56.41)
  BOTTOM w0.102: JDIMM1.126 60.78,55.88 60.67,55.98 60.67,56.24 60.57,56.34 60.37,56.34 60.27,56.24 60.27,55.98 60.17,55.88 59.94,55.88 59.85,55.96 59.85,56.44 59.75,56.55 59.5,56.55 59.4,56.44 59.4,56.06 59.3,55.96 59.09,55.96 58.99,56.06 58.99,56.44 58.89,56.55 58.69,56.55 58.59,56.44 58.59,56.06 58.48,55.96 58.28,55.96 58.18,56.06 58.18,56.31 58.08,56.41 57.87,56.41 57.77,56.31 57.77,56.13 57.67,56.03 57.47,56.03 57.37,56.13 57.37,56.31 57.27,56.41 55.52,56.41 v2(55.52,56.41) ; JDIMM2.126 v2(48.34,56.38) ; v2(106.46,56.26) 106.26,56.06 UC1.U37
DDRAB_SMA6: length 75.8
  IN1 w0.102: 100.1,59.79 101.35,59.79 101.9,59.23 102.61,59.23 103.91,57.93 103.91,57.87 104.84,56.94 106.21,56.94 106.49,56.66 107.4,56.66 107.8,56.26 v2(108.05,56.26)
  IN1 w0.211: 100.1,59.79 96.59,59.79 96.25,60.13 86.76,60.13 86.44,60.45 86.44,60.75 86.81,61.11 86.81,61.41 86.55,61.67 86.17,61.67 85.85,61.34 85.55,61.34 85.08,61.81 78.89,61.81 76.31,59.23 73.4,59.23 72.82,58.65 69.71,58.65 69.1,58.03 64.43,58.03 63.88,58.59 63.12,58.59 61.75,57.22 60.51,57.22 v2(60.08,56.79)
  IN2 w0.211: v2(60.08,56.79) 60.51,57.22 61.12,57.22 61.81,56.53 66.42,56.53 66.95,56 v2(66.95,55.92)
  BOTTOM w0.102: v2(60.08,56.79) 60.05,56.79 60.04,56.8 58.58,56.8 58.44,56.66 57.39,56.66 57.29,56.76 57.29,57.05 57.19,57.15 56.99,57.15 56.89,57.05 56.89,56.76 56.78,56.66 56.58,56.66 56.48,56.76 56.48,57.05 56.38,57.15 56.17,57.15 56.07,57.05 56.07,56.83 55.97,56.73 55.77,56.73 55.67,56.83 55.67,57.04 55.56,57.15 55.23,57.15 55.12,57.04 55.12,56.5 54.75,56.13 54.61,56.13 54.54,56.19 54.54,56.42 54.45,56.51 54.21,56.51 54.11,56.41 54.11,56.22 54.02,56.13 JDIMM2.127 ; v2(66.95,55.92) 68.41,55.92 68.7,55.62 JDIMM1.127 ; UC1.U34 107.86,56.07 v2(108.05,56.26)
DDRAB_SMA7: length 78.9
  IN1 w0.102: v2(107.26,57.36) 107.26,57.37 106.89,57.74 105.41,57.74 105.2,57.94 104.81,57.94 102.96,59.79 101.92,59.79 100.89,60.82 100.1,60.82
  IN1 w0.211: v2(55.06,57.81) 55.45,57.42 58.49,57.42 59.39,58.33 59.77,58.33 60.13,57.97 61.47,57.97 62.81,59.32 64.18,59.32 64.73,58.76 68.8,58.76 69.97,59.93 73.07,59.93 73.41,60.26 74.87,60.26 75.28,60.68 76.3,60.68 78.5,62.88 88.32,62.88 88.77,62.43 89.05,62.43 89.29,62.19 90.76,62.19 91.79,61.16 96.69,61.16 97.03,60.82 100.1,60.82
  IN2 w0.211: v2(55.06,57.81) 52.66,57.81 52.54,57.93 49.11,57.93 v2(48.98,57.8)
  BOTTOM w0.102: v2(107.26,57.36) 107.06,57.16 UC1.R35 ; v2(55.06,57.81) 55.2,57.95 55.51,57.95 55.59,57.87 55.59,57.74 55.67,57.66 56.39,57.66 56.5,57.76 56.5,58.27 56.6,58.37 56.8,58.37 56.9,58.27 56.9,57.76 57,57.66 57.21,57.66 57.31,57.76 57.31,58.15 57.41,58.25 57.61,58.25 57.71,58.15 57.71,57.97 57.84,57.84 59.06,57.84 59.19,57.97 59.19,58.05 59.41,58.27 59.83,58.27 60.39,57.71 60.39,57.27 60.49,57.17 60.87,57.17 61.16,56.88 JDIMM1.122 ; v2(48.98,57.8) 48.55,57.38 JDIMM2.122
DDRAB_SMA8: length 76.3
  IN1 w0.102: v2(105.66,57.36) 105.5,57.36 105.12,57.74 104.73,57.74 102.88,59.59 101.83,59.59 101.12,60.3 100.1,60.3
  IN1 w0.211: 100.1,60.3 96.82,60.3 96.48,60.64 90.87,60.64 90.61,60.91 90.61,61.47 90.4,61.68 89.98,61.68 89.77,61.47 89.77,60.85 89.56,60.64 89.1,60.64 88.88,60.85 88.88,61.71 88.67,61.92 88.28,61.92 88.07,61.71 88.07,60.88 87.83,60.64 87.53,60.64 87.32,60.85 87.32,62.12 87.11,62.33 78.67,62.33 76.1,59.75 73.41,59.75 72.66,59.01 71.4,59.01 71.01,59.39 70.5,59.39 70.12,59.01 69.56,59.01 68.95,58.4 64.58,58.4 64.03,58.95 62.96,58.95 61.6,57.58 60.14,57.58 v2(59.99,57.42)
  IN2 w0.211: v2(66.44,57.21) 66.27,57.37 63.73,57.37 63.5,57.6 62.64,57.6 62.5,57.74 60.3,57.74 v2(59.99,57.42)
  BOTTOM w0.102: JDIMM1.125 68.87,56.13 68.25,56.74 66.91,56.74 v2(66.44,57.21) ; v2(105.66,57.36) 105.66,57.01 UC1.R38 ; JDIMM2.125 53.96,56.62 54.1,56.76 54.77,56.76 54.87,56.86 54.87,57.22 55.05,57.4 57.41,57.4 57.55,57.27 57.55,57.02 57.65,56.91 57.85,56.91 57.95,57.02 57.95,57.48 58.05,57.58 58.35,57.58 58.45,57.48 58.45,57.16 58.55,57.05 58.76,57.05 58.86,57.16 58.86,57.48 58.96,57.58 59.16,57.58 59.27,57.48 59.27,57.16 59.37,57.05 59.57,57.05 59.67,57.16 59.67,57.32 59.77,57.42 v2(59.99,57.42)
DDRAB_SMA9: length 75.5
  IN1 w0.102: 100.1,61.87 100.54,61.87 102.21,60.2 103.21,60.2 104.95,58.46 v2(105.58,58.46)
  IN1 w0.211: 100.1,61.87 100.08,61.85 97.52,61.85 97.09,62.29 97.09,63.02 96.86,63.24 96.57,63.24 96.3,62.98 96.3,62.44 96.09,62.23 95.79,62.23 95.54,62.48 95.54,63.15 95.33,63.36 94.93,63.36 94.72,63.15 94.72,62.4 94.5,62.19 92.86,62.19 92.48,62.58 92.48,63.51 92.27,63.72 91.54,63.72 90.88,64.38 84.27,64.38 83.8,63.91 78.07,63.91 75.87,61.71 74.85,61.71 74.44,61.3 73.41,61.3 72.77,60.66 69.67,60.66 68.49,59.49 65.87,59.49 65.31,60.04 64.61,60.04 64.6,60.04 62.51,60.04 61.8,59.32 v2(60.3,59.32)
  IN2 w0.211: v2(60.3,59.32) 60.68,58.95 65.7,58.95 67.2,57.45 v2(67.2,57.21)
  BOTTOM w0.102: JDIMM2.121 54.55,57.62 54.66,57.73 54.66,57.98 54.94,58.27 54.94,58.69 55.34,59.08 57.71,59.08 57.97,58.82 58.11,58.82 58.37,59.08 58.82,59.08 59.13,58.78 60.5,58.78 60.6,58.88 60.6,59.28 60.5,59.38 60.35,59.38 v2(60.3,59.32) ; v2(67.2,57.21) 67.31,57.32 68.33,57.32 68.53,57.13 JDIMM1.121 ; v2(105.58,58.46) 105.58,58.33 105.46,58.2 UC1.N38
DDRAB_SMA10: length 80.9
  IN1 w0.102: v2(107.63,50.75) 106.91,50.04 105.5,50.04 105.33,49.87 104.84,49.87 103.21,48.24 103.21,47.9 102.71,47.4 102.71,47.12 101.81,46.21 101.1,46.21 100.32,45.44 100.1,45.44
  IN1 w0.211: 100.1,45.44 97.07,45.44 95.62,43.99 89.38,43.99 88.6,43.21 81.64,43.21 76.33,48.53 73.81,48.53 73.02,49.32 72.76,49.32 72.49,49.59 72.49,49.61 72.22,49.88 72.2,49.88 72.16,49.92 70.39,49.92 70.36,49.95 62.85,49.95 61.84,48.93 59.99,48.93 59.43,49.49 56.52,49.49 55.59,50.42 54.83,50.42 v2(54.82,50.44)
  IN2 w0.211: v2(48.2,49.38) 49.26,50.44 v2(54.82,50.44)
  BOTTOM w0.102: UC1.AG34 107.86,50.52 v2(107.63,50.75) ; v2(54.82,50.44) 55.01,50.25 58.74,50.25 58.84,50.14 58.84,49.9 58.95,49.8 59.15,49.8 59.25,49.9 59.25,50.08 59.35,50.18 59.56,50.18 59.66,50.08 59.66,49.9 59.76,49.8 61.01,49.8 61.11,49.7 61.11,49.48 61.01,49.38 60.75,49.38 60.6,49.23 60.6,49.04 60.76,48.87 JDIMM1.146 ; v2(48.2,49.38) JDIMM2.146
DDRAB_SMA11: length 80.1
  IN1 w0.102: 100.1,61.33 100.78,61.33 101.6,60.52 102.12,60 103.05,60 104.9,58.15 105.29,58.15 105.49,57.94 107.26,57.94 107.85,57.35 v2(108.02,57.35)
  IN1 w0.211: 100.1,61.33 97.25,61.33 96.91,61.67 92.01,61.67 90.97,62.71 89.73,62.71 89.49,62.95 88.98,62.95 88.54,63.39 88.54,63.43 88.1,63.87 84.49,63.87 84.02,63.4 78.29,63.4 76.08,61.19 75.07,61.19 74.65,60.78 73.41,60.78 72.92,60.29 69.82,60.29 68.64,59.12 64.89,59.12 64.33,59.68 62.66,59.68 61.88,58.89 60.53,58.89 60.33,58.69 59.07,58.69 58.9,58.52 55.71,58.52 v2(55.54,58.35)
  IN2 w0.211: v2(47.84,57.87) 48.46,58.5 53.23,58.5 53.82,59.09 54.48,59.09 55.21,58.35 v2(55.54,58.35)
  BOTTOM w0.102: UC1.R34 107.86,57.19 v2(108.02,57.35) ; JDIMM1.120 61.09,57.38 59.94,58.53 59.31,58.53 59.09,58.31 58.89,58.31 58.82,58.38 58.82,58.73 58.72,58.83 58.48,58.83 58.38,58.73 58.38,58.19 58.27,58.09 58.07,58.09 57.97,58.19 57.97,58.4 57.87,58.5 57.78,58.5 57.68,58.6 57.68,58.76 57.61,58.83 57.4,58.83 57.3,58.73 57.3,58.6 57.2,58.5 57.03,58.5 56.92,58.62 56.92,58.76 56.84,58.83 56.45,58.83 56.34,58.73 56.34,58.57 56.24,58.47 56,58.47 55.9,58.57 55.9,58.73 55.8,58.83 55.45,58.83 55.34,58.73 55.34,58.55 v2(55.54,58.35) ; JDIMM2.120 v2(47.84,57.87)
DDRAB_SMA12: length 76.8
  IN1 w0.102: 100.1,62.77 101.62,62.77 103.6,60.79 103.6,60.1 104.81,58.88 106.04,58.88 v2(106.46,58.46)
  IN1 w0.211: v2(59.17,59.41) 59.54,59.79 61.74,59.79 62.37,60.41 68.91,60.41 70.07,61.58 73.18,61.58 73.42,61.81 74.23,61.81 74.64,62.22 75.65,62.22 77.92,64.49 83.65,64.49 84.06,64.9 91.73,64.9 91.94,64.69 91.94,64.48 92.18,64.24 92.54,64.24 92.78,64.48 92.78,64.69 92.99,64.9 93.41,64.9 93.63,64.69 93.63,63.82 93.87,63.57 94.38,63.57 95.08,64.27 97.65,64.27 99.14,62.77 100.1,62.77
  IN2 w0.211: v2(59.17,59.41) 59.54,59.79 64.92,59.79 v2(65.12,59.58)
  BOTTOM w0.102: v2(59.17,59.41) 58.95,59.41 58.82,59.54 58.82,59.69 58.72,59.79 58.51,59.79 58.41,59.69 58.41,59.45 58.29,59.34 58.11,59.34 58.01,59.44 58.01,59.69 57.91,59.79 57.7,59.79 57.6,59.69 57.6,59.44 57.5,59.34 57.3,59.34 57.2,59.44 57.2,59.69 57.09,59.79 56.89,59.79 56.79,59.69 56.79,59.44 56.69,59.34 56.49,59.34 56.38,59.44 56.38,59.69 56.28,59.79 56.08,59.79 55.98,59.69 55.98,59.46 55.88,59.36 55.26,59.36 55.16,59.26 54.79,59.26 54.69,59.16 54.69,58.37 54.44,58.13 JDIMM2.119 ; v2(106.46,58.46) 106.26,58.26 UC1.N37 ; v2(65.12,59.58) 65.23,59.58 66.43,58.37 68.13,58.37 68.88,57.62 JDIMM1.119
DDRAB_SMA13: length 81.9
  IN1 w0.102: 100.1,39.37 100.24,39.52 100.58,39.52 102.17,41.1 102.17,41.87 103.58,43.28 103.58,44.46 104.34,45.22 104.34,46.56 104.76,46.98 106.24,46.98 v2(106.67,47.4)
  IN1 w0.211: 100.1,39.37 99.15,38.43 80.6,38.43 75.02,44.01 72.85,44.01 70.37,46.49 67.45,46.49 67.09,46.85 63.43,46.85 63.27,46.69 55.95,46.69 v2(55.84,46.58)
  IN2 w0.211: v2(55.84,46.58) 55.33,46.07 50.05,46.07 49.74,46.38 v2(49.27,46.38)
  BOTTOM w0.102: UC1.AN35 107.06,47.01 v2(106.67,47.4) ; v2(55.84,46.58) 55.55,46.29 55.55,46.14 55.7,45.99 56.28,45.99 56.38,46.09 56.38,46.35 56.55,46.51 56.8,46.51 56.9,46.41 56.9,46.32 57,46.22 57.21,46.22 57.31,46.32 57.31,46.41 57.41,46.51 58.55,46.51 58.73,46.33 58.73,46.05 58.83,45.94 59.03,45.94 59.2,46.11 59.2,46.72 59.3,46.82 59.67,46.82 59.79,46.7 59.79,46.02 59.89,45.92 60.09,45.92 60.17,45.99 60.17,46.08 60.27,46.18 60.53,46.18 60.78,45.93 61.04,45.93 61.1,45.87 JDIMM1.158 ; v2(49.27,46.38) JDIMM2.158
DDRAB_SRAS#: length 80.3
  IN1 w0.102: 100.1,43.67 100.59,43.67 101.4,44.48 101.88,44.48 103.12,45.72 103.12,47.23 103.62,47.73 103.62,48.07 104.83,49.28 106.05,49.28 106.43,49.66 v2(106.46,49.66)
  IN1 w0.211: v2(55.93,48.69) 56.03,48.59 59.23,48.59 59.61,48.21 62.14,48.21 63.15,49.23 70.06,49.23 70.12,49.16 71.1,49.16 71.67,48.59 72.72,48.59 72.74,48.57 73.81,47.5 75.9,47.5 81.23,42.17 84.81,42.17 85.23,41.76 89.12,41.76 89.87,42.51 95.6,42.51 96.76,43.67 100.1,43.67
  IN2 w0.211: v2(49.3,48.47) 55.21,48.47 55.33,48.59 55.83,48.59 v2(55.93,48.69)
  BOTTOM w0.102: JDIMM2.152 48.7,47.87 v2(49.3,48.47) ; v2(106.46,49.66) 106.26,49.46 UC1.AJ37 ; v2(55.93,48.69) 56.1,48.52 56.38,48.52 56.48,48.63 56.48,48.94 56.58,49.04 56.78,49.04 56.89,48.94 56.89,48.63 56.99,48.52 57.34,48.52 57.44,48.63 57.44,48.94 57.54,49.04 57.75,49.04 57.85,48.94 57.85,48.63 57.95,48.52 59.34,48.52 59.58,48.28 59.58,47.52 59.72,47.38 60.32,47.38 60.42,47.27 60.42,46.79 60.52,46.69 60.73,46.69 60.83,46.79 60.83,47.27 60.93,47.38 JDIMM1.152
DDRAB_SWE#: length 76.2
  IN1 w0.102: 100.1,42.24 100.35,42.24 100.46,42.34 100.46,42.83 100.99,43.37 101.65,43.37 102.55,44.27 102.55,44.58 103.53,45.55 103.53,47.06 104.67,48.21 105.29,48.21 105.65,48.56 v2(105.66,48.56)
  IN1 w0.211: v2(59.14,47.52) 59.17,47.48 62.5,47.48 62.6,47.58 63.93,47.58 64.85,48.5 69.76,48.5 69.82,48.43 70.8,48.43 71.37,47.87 72.41,47.87 73.82,46.46 75.48,46.46 80.8,41.14 84.39,41.14 84.8,40.73 89.55,40.73 90.3,41.48 96.03,41.48 96.78,42.24 100.1,42.24
  IN2 w0.211: v2(59.14,47.52) 59.15,47.5 65,47.5 65.28,47.21 67.95,47.21 v2(68.41,47.67)
  BOTTOM w0.102: v2(105.66,48.56) 105.46,48.36 UC1.AL38 ; JDIMM1.151 68.46,47.62 v2(68.41,47.67) ; v2(59.14,47.52) 58.95,47.33 57.36,47.33 57.26,47.43 57.26,47.9 57.16,48 56.95,48 56.85,47.9 56.85,47.43 56.75,47.33 56.55,47.33 56.44,47.43 56.44,47.9 56.34,48 56.14,48 56.04,47.9 56.04,47.43 55.94,47.33 55.71,47.33 55.58,47.46 55.58,47.82 55.4,48 54.89,48 54.79,48.1 54.79,48.27 54.69,48.37 54.48,48.37 54.38,48.27 54.38,48.02 54.28,47.92 54.1,47.92 53.89,48.12 JDIMM2.151
DDRB_CKE0: length 66.7
  IN1 w0.102: v2(108,59.56) 108.16,59.72 108.16,60.77 107.67,61.25 107.25,61.25 106.83,61.68 106.83,62.27 104.23,64.86 104.23,65.51 103.3,66.44 103.23,66.44 102.76,66.91 102.76,68.09
  IN1 w0.211: v2(57.3,63.12) 57.32,63.14 61.46,63.14 63.44,65.12 71.74,65.12 76.17,69.55 101.88,69.55 102.76,68.66 102.76,68.09
  BOTTOM w0.102: JDIMM2.109 53.96,60.62 54.32,60.99 54.32,62.06 55.37,63.12 v2(57.3,63.12) ; UC1.L34 107.86,59.42 v2(108,59.56)
DDRB_CKE1: length 70.5
  IN1 w0.102: 100.1,67.88 100.4,67.88 101.1,67.18 101.1,66.23 102.05,65.28 102.05,65.06 102.13,64.98 102.13,63.76 104.91,60.97 106.15,60.97 v2(106.52,60.6)
  IN1 w0.211: 100.1,67.88 83.39,67.88 82.89,67.38 80.54,67.38 80.03,67.88 76.86,67.88 72.93,63.95 63.7,63.95 61.74,61.99 58.25,61.99 56.87,60.61 55.34,60.61 55.12,60.39 51.46,60.39 51.07,60.01 47.82,60.01 v2(47.45,60.38)
  BOTTOM w0.102: v2(47.45,60.38) JDIMM2.110 ; v2(106.52,60.6) 106.26,60.34 UC1.J37
DDRB_CLK0: length 70.6
  IN1 w0.102: v2(105.66,51.86) 105.74,51.78 105.74,51.62 105.6,51.48 104.12,51.48 103.7,51.05 103.7,50.61 102.2,49.11 101.99,49.11
  IN1 w0.221: v2(57.5,51.76) 57.63,51.64 58.13,51.64 59.01,50.75 60.4,50.75 60.88,51.24 61.71,51.24 62.75,52.28 64.07,52.28 64.72,51.62 65.3,51.62 65.79,52.11 68.74,52.11 69.72,53.09 70.45,53.09 70.98,52.57 71.29,52.57 71.82,53.09 72.68,53.09 73.24,52.54 73.24,51.24 73.53,50.94 77.56,50.94 79.12,49.39 80.11,49.39 80.6,48.9 80.6,47.67 81.08,47.2 81.87,47.2 82.36,46.71 82.36,45.91 82.65,45.63 83.61,45.63 83.83,45.85 83.83,46.52 84.32,47.01 85.62,47.01 86.13,46.5 86.13,45.89 86.39,45.63 87.39,45.63 87.62,45.85 87.62,46.5 88.1,46.98 93.77,46.98 94.64,47.86 95.42,47.86 95.64,48.08 95.64,48.48 96.13,48.97 97.03,48.97 97.52,48.48 98.07,48.48 98.88,49.29 99.91,49.29 100.53,48.67 101,48.67 101.44,49.11 101.99,49.11
  BOTTOM w0.102: v2(105.66,51.86) 105.7,51.9 105.91,51.9 106.01,51.8 106.01,51.59 105.73,51.31 UC1.AE38
  BOTTOM w0.163: JDIMM2.137 54.15,53.62 54.25,53.52 54.63,53.52 55.37,52.79 56.09,52.79 56.6,53.29 57.16,53.29 57.52,52.94 57.52,52.46 57.02,51.97 57.02,51.74 57.19,51.58 57.31,51.58 57.5,51.77 v2(57.5,51.76)
DDRB_CLK0#: length 70.6
  IN1 w0.102: 101.99,48.65 102,48.65 102.06,48.71 102.15,48.71 102.21,48.77 102.34,48.77 104.03,50.47 104.03,50.91 104.26,51.14 105.74,51.14 v2(106.46,51.86)
  IN1 w0.221: 101.99,48.65 101.63,48.65 101.19,48.21 100.34,48.21 99.72,48.84 99.07,48.84 98.25,48.02 97.33,48.02 96.84,48.51 96.32,48.51 96.1,48.29 96.1,47.89 95.61,47.4 94.83,47.4 93.96,46.53 88.29,46.53 88.07,46.31 88.07,45.66 87.58,45.17 86.2,45.17 85.67,45.7 85.67,46.31 85.43,46.55 84.51,46.55 84.29,46.33 84.29,45.66 83.8,45.17 82.46,45.17 81.9,45.73 81.9,46.52 81.68,46.74 80.89,46.74 80.14,47.48 80.14,48.71 79.92,48.93 78.93,48.93 77.37,50.49 73.35,50.49 72.78,51.05 72.78,52.35 72.49,52.64 72.01,52.64 71.48,52.11 70.79,52.11 70.26,52.64 69.91,52.64 68.93,51.66 65.98,51.66 65.49,51.16 64.53,51.16 63.88,51.82 62.94,51.82 61.9,50.78 61.07,50.78 60.59,50.3 58.82,50.3 57.94,51.18 v2(57.5,51.18)
  BOTTOM w0.102: v2(106.46,51.86) 106.26,51.66 UC1.AE37
  BOTTOM w0.163: JDIMM2.139 54.15,53.12 54.25,53.23 54.51,53.23 55.24,52.49 56.22,52.49 56.72,53 57.04,53 57.22,52.82 57.22,52.59 56.73,52.09 56.73,51.62 57.06,51.28 57.4,51.28 v2(57.5,51.18)
DDRB_CLK1: length 67.3
  IN1 w0.102: 100.1,53.98 100.11,53.98 100.17,53.92 100.26,53.92 100.27,53.91 100.67,53.91 102.53,53.91 103.39,54.78 105.48,54.78 106.2,54.06 v2(106.46,54.06)
  IN1 w0.221: 100.1,53.98 95.23,53.98 93.12,56.09 78.89,56.09 77.91,55.11 73.78,55.11 73.53,55.36 70.11,55.36 69.86,55.12 68.46,55.12 67.61,54.27 65.23,54.27 64.29,53.34 62.39,53.34 61.69,52.64 60.34,52.64 60.29,52.69 55.15,52.69 54.28,51.81 50.65,51.81 50.25,52.21 v2(50.25,52.53)
  BOTTOM w0.102: UC1.AA37 106.26,53.86 v2(106.46,54.06)
  BOTTOM w0.163: v2(50.25,52.53) 50.25,53.16 49.87,53.55 47.73,53.55 47.42,53.24 45.99,53.24 45.85,53.38 JDIMM2.138
DDRB_CLK1#: length 67.2
  IN1 w0.102: v2(105.66,54.06) 105.66,54.12 105.34,54.44 103.53,54.44 102.67,53.57 100.53,53.57 100.53,53.57 100.19,53.57 100.14,53.53 100.1,53.53
  IN1 w0.221: 100.1,53.53 95.04,53.53 92.93,55.63 79.08,55.63 78.1,54.65 73.59,54.65 73.34,54.91 70.29,54.91 70.05,54.66 68.65,54.66 67.8,53.82 65.42,53.82 64.48,52.88 62.58,52.88 61.88,52.18 60.15,52.18 60.1,52.23 55.34,52.23 54.47,51.36 50.46,51.36 49.33,52.49 v2(49.33,52.53)
  BOTTOM w0.102: UC1.AA38 105.46,53.86 v2(105.66,54.06)
  BOTTOM w0.163: JDIMM2.140 45.89,52.87 45.96,52.94 47.54,52.94 47.86,53.25 49.74,53.25 49.96,53.04 49.96,52.85 49.64,52.53 v2(49.33,52.53)
DDRB_ODT0: length 67.8
  IN1 w0.102: 102.52,38.88 104.16,40.52 104.16,42.18 105.74,43.77 105.74,45.54 106.07,45.87 106.51,45.87 106.84,46.2 106.84,46.78 v2(107.41,47.35)
  IN1 w0.211: v2(59.27,45.61) 59.61,45.96 61.71,45.96 62.71,44.96 69.76,44.96 72.86,41.86 72.86,40.98 77.47,36.36 100.01,36.36 102.52,38.88
  BOTTOM w0.102: UC1.AL34 107.43,47.58 107.43,47.43 107.42,47.42 107.42,47.36 v2(107.41,47.35) ; JDIMM2.155 54.07,47.12 55.46,45.74 56.6,45.74 56.83,45.97 57.56,45.97 57.7,46.11 58.24,46.11 58.86,45.48 59.14,45.48 v2(59.27,45.61)
DDRB_ODT1: length 66.8
  IN1 w0.102: v2(107.43,46.48) 106.56,45.61 106.1,45.61 105.95,45.46 105.95,43.39 105.27,42.71 105.27,40.69 104.73,40.15 104.66,40.15 103.39,38.88
  IN1 w0.211: v2(58.38,45.29) 58.63,45.04 62.11,45.04 62.56,44.6 69.61,44.6 71.97,42.24 72.34,41.86 72.34,40.76 77.25,35.85 100.35,35.85 103.39,38.88
  BOTTOM w0.102: JDIMM2.161 54.55,45.63 54.95,45.23 56.9,45.23 57.26,44.87 57.96,44.87 v2(58.38,45.29) ; v2(107.43,46.48) 107.86,46.91 UC1.AN34
DDRB_SCS0#: length 64.3
  IN1 w0.102: v2(108.06,49.66) 108.06,49.64 107.5,49.08 104.91,49.08 103.82,47.99 103.82,47.65 103.32,47.15 103.32,45.64 102.34,44.66 102.34,44.35 101.56,43.57 100.91,43.57 100.5,43.16 100.1,43.16
  IN1 w0.211: v2(59.05,48.12) 59.08,48.09 59.22,48.09 59.46,47.84 62.29,47.84 63.3,48.86 69.91,48.86 69.97,48.79 70.95,48.79 71.52,48.23 72.57,48.23 73.82,46.98 75.69,46.98 81.01,41.66 84.6,41.66 85.01,41.24 89.34,41.24 90.09,41.99 95.81,41.99 96.98,43.16 100.1,43.16
  BOTTOM w0.102: UC1.AJ34 107.86,49.46 v2(108.06,49.66) ; JDIMM2.149 54.79,48.62 55.16,48.25 58.91,48.25 v2(59.05,48.12)
DDRB_SCS1#: length 64.7
  IN1 w0.102: 101.8,38.88 102.78,39.86 102.78,41.18 103.14,41.55 103.49,41.55 103.96,42.01 103.96,42.27 105.54,43.85 105.54,46.24 v2(105.66,46.36)
  IN1 w0.211: v2(57.87,45.7) 57.87,45.74 58.08,45.74 58.66,46.32 63.4,46.32 64.32,45.4 69.92,45.4 73.22,42.1 73.22,41.34 77.68,36.88 99.8,36.88 101.8,38.88
  BOTTOM w0.102: JDIMM2.157 53.97,46.63 55.11,45.48 56.79,45.48 57.02,45.71 57.86,45.71 v2(57.87,45.7) ; v2(105.66,46.36) 105.46,46.16 UC1.AR38
DEVSLP0_HDD: length 112.3
  TOP w0.102: v2(112.93,30.92) 112.93,30.05 v1(113.66,29.33) 113.94,29.04 113.94,25.09 114.32,24.71 RC44.2 116.91,21.76 119.25,21.76 121.24,19.77 131.47,19.77 132.74,21.04 v2(133.37,21.04)
  IN2 w0.102: 110.89,38.88 110.89,42.25 110.37,42.77 110.37,43.85 v2(109.68,44.53)
  IN2 w0.127: v2(133.37,21.04) 134.07,21.04 135.02,20.08 137.69,20.08 139.85,17.93 144.3,17.93 144.3,17.93 144.54,17.93 145.46,17.93 145.65,17.73 155.6,17.73 157.19,16.15 160.42,16.15 161.25,16.97 166.83,16.97 171.28,21.42 174.14,21.42 174.45,21.74 178.96,21.74 180.21,20.49 181.63,20.49 181.88,20.24 188.34,20.24 188.74,19.83 190.45,18.13 v2(193.41,18.13) ; 110.89,38.88 110.89,38.05 109.81,36.97 109.81,34.62 110.55,33.89 110.55,33.05 112.68,30.92 v2(112.93,30.92)
  BOTTOM w0.102: v2(193.41,18.13) 193.84,18.56 RS8.1 ; UC1.AV31 109.42,44.31 109.64,44.53 v2(109.68,44.53)
DEW1: length 6.7
  BOTTOM w0.102: v1(192.49,21.1) RS34.1 RS36.1 191.76,22.65 191.76,24.21 192.73,25.18 US2.16
DEW2: length 5.7
  BOTTOM w0.102: US2.6 198.31,27.18 198.68,27.55 v1(198.68,29.48) 198.68,29.58 198.84,29.74 RS33.1 RS35.1
DGPU_PWROK: length 355.4
  TOP w0.102: v2(45.61,115.71) 44.91,116.4 44.91,117.87 44.98,117.93 44.98,118.27 44.91,118.33 v1(44.91,120.24) 46.04,121.37 PR1122.2 ; v2(160.34,82.92) 160.34,81.44 171.58,70.2 171.58,69.16 174.48,66.26 174.48,61.24 175.63,60.1 180.87,60.1 183.01,57.96 183.26,57.96 184.46,56.76 185.12,56.76 185.88,56 185.88,54.82 186.82,53.87 186.82,51.34 185.87,50.38 185.87,49.14 184.84,48.11 184.84,42.63 185.45,42.02 185.45,40.4 185.13,40.09 185.13,38.66 185.68,38.12 185.68,33.85 186,33.53 186,31.26 v2(185.55,30.82)
  IN1 w0.127: v2(45.61,115.71) 45.73,115.58 45.73,103.38 43.9,101.55 43.9,100.15 32.85,89.11 32.85,88.43 32.85,88.43 32.85,88.01 32.85,86.64 29.14,82.93 29.14,52.15 29.17,52.12 29.17,47.21 39.56,36.82 39.56,30.51 41.42,28.64 41.42,18.75 45.91,14.26 46.04,14.26 46.73,14.26 46.73,14.26 51.86,14.26 53.53,12.59 67.9,12.59 68.85,13.54 82.99,13.54 83.69,14.24 87.97,14.24 89.53,15.8 93.43,15.8 94.1,15.13 109.47,15.13 111.82,12.78 116.45,12.78 116.77,12.46 120.1,12.46 124.42,16.78 124.42,17.8 125.47,18.85 126.14,18.85 129.03,21.74 130.2,21.74 130.66,22.2 131.67,22.2 132.39,21.48 133.65,21.48 134.32,20.81 134.34,20.81 140.98,20.81 142.25,22.08 142.85,22.08 143.51,21.42 147.85,21.42 147.98,21.29 148.02,21.29 150.83,21.29 151.28,20.85 160.58,20.85 161.23,21.49 163.06,21.49 165.71,24.15 165.71,25.86 167.57,27.72 167.57,32.25 168.99,33.67 170.01,33.67 171.19,32.49 173.68,32.49 174.1,32.07 174.26,32.07 174.72,31.61 174.72,31.61 175.32,31.01 178.52,31.01 179.7,29.82 v2(179.92,29.82)
  IN2 w0.127: v2(185.55,30.82) 183.76,30.82 183.52,31.06 182.58,31.06 181.35,29.82 v2(179.92,29.82)
  BOTTOM w0.102: PR1403.1 160.29,82.97 v2(160.34,82.92) ; v2(179.92,29.82) 180.64,29.82 180.84,30.02 UE1.18
DIR: length 6
  TOP w0.102: v1(78.89,97.36) 80.02,97.36 80.24,97.15 CV182.2 79.31,96.5 CV184.2 RV102.1 79.17,95.06 UV4.5
DISPOFF#: length 6.1
  TOP w0.102: DX1.1 222.15,37.05 v2(222.4,37.29) 222.4,38.42 v1(222.75,38.78)
  BOTTOM w0.102: JEDP1.24 223.41,38.55 222.78,37.92 222.78,37.68 v2(222.4,37.29) 221.95,36.85 RP2.1
DP0_HPD: length 151.2
  TOP w0.102: v2(118.52,62.44) 118.12,62.83 118.12,63.51 121.11,66.5 125.69,66.5 128.36,69.18 131.6,69.18 137.37,74.95 137.37,77.87 135.85,79.39 135.15,79.39 v1(133.4,81.14) v2(131.68,82.86) ; v2(192.07,51.82) 192.07,49.89 v2(191.03,48.85) ; v2(164.69,80.49) 164.95,80.22 164.95,77.4 171.99,70.37 171.99,69.33 174.89,66.43 174.89,63.15 v2(177.54,60.5)
  IN2 w0.127: v2(131.68,82.86) 132.64,81.91 150.86,81.91 151.98,80.79 164.39,80.79 v2(164.69,80.49) ; v2(177.54,60.5) 177.54,58.78 183.6,52.72 184.74,52.72 185.65,51.82 186.35,51.82 186.79,51.37 188.7,51.37 191.03,49.03 191.03,48.85 v2(191.03,48.85) ; v2(192.07,51.82) 192.86,51.03 197.89,51.03 199.42,49.51 202.99,49.51 204.22,50.74 208.11,50.74 209.86,48.99 215.45,48.99 215.99,49.54 217.98,49.54 218.33,49.18 218.33,48.7 218.73,48.3 219.05,48.3 219.96,47.39 v2(220.07,47.39)
  BOTTOM w0.102: v2(118.52,62.44) 118.52,62.5 118.3,62.71 UC1.D15 ; v2(220.07,47.39) 220.45,47.01 R13.2
DP1_HPD: length 115
  TOP w0.102: v2(30.06,92.41) 29.27,92.41 QI3.3 30.25,92.93 RI17.1 ; v2(113.24,72.03) v1(112.67,72.03)
  IN1 w0.127: v2(113.24,72.03) 113.24,77.87 111.08,80.03 106.38,80.03 96.16,90.25 87.19,90.25 86.81,90.63 77.74,90.63 76.35,92.03 v2(71.39,92.03)
  IN2 w0.102: v2(117.37,63.07) 116.92,63.52 116.92,65.55
  IN2 w0.127: 116.92,65.55 116.92,68.53 115.15,70.31 113.94,70.31 113.3,70.95 113.3,71.96 v2(113.24,72.03) ; v2(30.06,92.41) 30.28,92.64 34.61,92.64 34.82,92.85 35.61,92.85 40.78,92.85 44.55,96.62 47.26,96.62 50.29,93.59 69.83,93.59 v2(71.39,92.03)
  BOTTOM w0.102: UC1.D17 116.94,62.71 117.3,63.07 v2(117.37,63.07)
DP_AUX_ZVSS: length 3.6
  TOP w0.102: v1(115.34,64.64) 115.83,64.14 RC401.1
  TOP w0.254: v2(115.22,62.41) 115.44,62.63 RC401.1
  BOTTOM w0.25: UC1.D21 114.92,62.71 v2(115.22,62.41)
DP_VSSR: length 7.2
  BOTTOM w0.102: 101.29,115.94 v1(100.53,115.94)
  BOTTOM w0.254: UV1.AH14 103.78,110.38 v2(103.78,110.82) ; UV1.AG14 104.45,110.3 v2(104.1,109.96)
  BOTTOM w0.305: UV1.AM18 101.29,113.5 v2(101.23,113.44) ; UV1.AM14 101.7,110.3 101.3,110.7 v2(101.3,110.89) 101.3,111.22 101.99,111.9 UV1.AM16
  BOTTOM w0.381: UV1.AF19 UV1.AF20 105.29,115.31 105.29,115.71 v2(105.05,115.94)
DP_ZVSS: length 8.9
  TOP w0.102: v1(116.16,66.25) 115.91,65.99 v2(115.59,65.99)
  TOP w0.254: RC400.1 115.83,64.86 115.58,65.12 115.58,65.8 115.59,65.82 v2(115.59,65.99)
  BOTTOM w0.102: 115.65,65.93 v2(115.59,65.99) 115.02,65.42 115.02,64.72 114.89,64.6 114.89,64.34 115.08,64.15 115.27,64.15 115.67,63.76 UC1.B18 116.31,64 115.84,64.47 115.65,64.47 115.4,64.72 115.4,64.98 115.65,65.23 115.65,65.93
DRAM_RST: length 67.9
  TOP w0.102: RV36.1 126.96,93.3 128.35,94.7 v1(130.26,94.7) v2(131.78,94.7)
  IN2 w0.102: v2(144.67,115.63) 144.93,115.37 144.93,114.65
  IN2 w0.127: v2(131.78,94.7) 137.43,94.7 137.94,94.19 142.45,94.19 142.74,94.48 148.51,94.48 148.93,94.06 152.67,94.06 153.69,95.08 153.69,109.37 149.88,113.18 146.39,113.18 144.93,114.64 144.93,114.65
  BOTTOM w0.102: UV13.J2 144.29,116.01 v2(144.67,115.63) 144.67,114.89 145.75,113.81 145.75,111.08 144.61,109.94 144.61,108.22 144.27,107.88 UV15.J2
DRAM_RST_G: length 26
  TOP w0.102: RV37.1 125.81,89.57 125.81,94.32 v1(124.67,95.46) 120.23,95.46 118.77,96.92 118.77,97.81 118.57,98 118.57,101.55 118.97,101.95 RV38.1 119.54,102.34 CV97.1 119.54,104.29 118.98,104.85 118.98,105.19 118.66,105.51 117.46,105.51 116.98,105.98 116.98,106.35 v2(116.66,106.67)
  BOTTOM w0.102: v2(116.66,106.67) 117.09,107.1 UV1.L10
E51_RX1: length 2.7
  TOP w0.102: v1(53.18,108.35) 52.78,108.76 v2(52.78,108.88) 53.11,109.21 RW7.2
  BOTTOM w0.102: JWLAN1.32 52.8,108.86 v2(52.78,108.88)
E51_RX2: length 5.1
  TOP w0.102: v2(59.9,110.51) 59.71,110.7 59.71,111.07 RW10.2 61.09,111.32 v1(61.17,111.4)
  BOTTOM w0.102: JWLAN1.60 59.8,110.41 v2(59.9,110.51)
E51_TX1: length 3.6
  TOP w0.102: RW8.1 RW6.2 52.09,108.93 v2(52.17,108.86) 52.17,108.55 v1(51.89,108.27)
  BOTTOM w0.102: v2(52.17,108.86) 52.3,108.72 JWLAN1.30
E51_TX2: length 5.2
  TOP w0.102: v1(57.61,111.27) 57.67,111.32 RW9.2 59.39,110.88 59.39,110.64 v2(59.27,110.51)
  BOTTOM w0.102: v2(59.27,110.51) 59.3,110.47 JWLAN1.58
EC_ENVDD: length 86.8
  TOP w0.102: v2(220.78,49.43) 221.18,49.03 RX8.2 ; v2(186.71,46.51) v1(186.71,45.93)
  IN1 w0.127: v2(220.78,49.43) 220.88,49.33 220.88,38.94 220.28,38.33 219.35,38.33 217.37,36.35 215.84,36.35 215.51,36.68 214.51,36.68 214.22,36.39 212.88,36.39 210.46,38.82 210.46,39.2 210.23,39.43 207.3,39.43 206.36,40.37 199.36,40.37 198.75,40.98 194.65,40.98 193.76,41.86 193.76,41.88 192.53,43.11 191.36,43.11 189.62,44.85 188.63,44.85 186.96,46.51 v2(186.71,46.51)
  IN2 w0.127: v2(186.71,46.51) 186.71,46.37 185.31,44.98 185.31,43.96 184.81,43.45 184.81,42.18 179.98,37.36 179.98,36.64 179.3,35.96 175.33,35.96 173.43,34.05 173.43,31.31 v2(173.31,31.2)
  BOTTOM w0.102: UE1.71 168.91,26.82 169.66,26.08 169.67,26.08 169.69,26.05 171.53,26.05 173.31,27.83 v2(173.31,31.2)
EC_LID_OUT#: length 55.7
  TOP w0.102: v2(122.79,49.65) 123.32,50.18 123.9,50.18 124.08,50.35 124.71,50.35 124.73,50.37 125.88,50.37 126.77,51.26 132.04,51.26 v1(132.13,51.17) 133.12,50.18 138.89,50.18 138.96,50.12 138.96,50.06 139.21,49.8 139.28,49.8 139.34,49.74 v2(139.34,49.55) 139.47,49.55 140.02,48.99 RC943.2 ; CE42.1 169.18,41.99 v2(169.44,42.25)
  IN1 w0.127: v2(169.44,42.25) 168.3,41.1 160.91,41.1 158.56,43.45 148.34,43.45 146.68,45.1 143.48,45.1 143.48,45.1 143.06,45.1 139.34,48.83 v2(139.34,49.55)
  BOTTOM w0.1: v2(122.79,49.65) 122.85,49.65 123.06,49.86 UC1.AG5
  BOTTOM w0.102: CE42.1 169.18,41.99 v2(169.44,42.25)
EC_LID_OUT#_R: length 3.8
  BOTTOM w0.102: v1(168.22,41.32) 168.83,40.71 RE44.2 169.64,40.25 169.64,39.81 169.22,39.39 UE1.101
EC_MUTE#: length 171.3
  TOP w0.102: RA8.2 32.41,30.43 v2(31.91,29.93) 31.81,29.83 31.81,29.39 31.41,29 UA1.47 ; v2(168.37,31.18) 167.8,31.75 167.49,31.75 v1(167.09,32.15)
  IN1 w0.127: v2(168.37,31.18) 168.08,30.89 168.08,27.51 166.22,25.65 166.22,23.94 162.36,20.08 161.44,20.08 159.98,18.62 156.87,18.62 156.58,18.34 155.78,18.34 152.77,18.34 142.81,18.34 140.88,16.4 129.5,16.4 125.69,12.59 124.86,12.59 124.04,11.77 122.51,11.77 121.43,10.69 114.2,10.69 113.62,10.69 113.62,10.69 113.56,10.69 112.99,10.12 111.91,10.12 111.34,10.69 111.09,10.69 103.91,10.69 102.92,11.68 100.85,11.68 100.85,11.68 100.59,11.68 100.59,11.68 100.32,11.68 99.5,11.68 99.22,11.96 99.03,12.15 91.66,12.15 90.7,13.1 90.44,13.1 88.4,13.1 88.4,13.1 87.03,13.1 87.03,13.1 84.16,13.1 83.81,12.75 83.55,12.49 83.55,12.49 83.4,12.34 80.16,12.34 78.74,10.92 77.86,10.92 77.46,11.32 73.77,11.32 73.65,11.45 70.75,11.45 69.45,10.15 69.32,10.15 69.32,10.15 68.95,10.15 68.95,10.15 46.34,10.15 39.14,17.35 39.14,26.57 36.18,29.53 32.31,29.53 v2(31.91,29.93)
  BOTTOM w0.102: v2(168.37,31.18) 167.93,31.63 UE1.83
EC_ON: length 32.4
  TOP w0.102: v2(187.28,44.34) 188.03,43.59 189.2,43.59 190.33,44.72 193.12,44.72 v1(193.76,44.09) 194.08,43.77 PR114.1
  IN2 w0.127: v2(175.41,35.01) 175.41,34.84 176.11,34.13 178.12,34.13 178.83,34.84 181.27,34.84 181.63,35.2 181.63,36.5 182.46,37.33 182.69,37.33 184.68,39.32 184.68,40.15 185.31,40.79 185.31,43.07 185.82,43.58 186.84,43.58 187.28,44.02 v2(187.28,44.34)
  BOTTOM w0.102: v2(175.41,35.01) 173.57,36.85 173.57,37.42 173.62,37.47 UE1.112
EC_PME#: length 5.7
  BOTTOM w0.102: UE1.29 183.92,25.63 RE41.2 183.98,25.67 184.49,26.18 185.3,26.18 RE21.2 185.81,26.55 v1(185.95,26.69)
EC_RSMRST#: length 42.5
  TOP w0.102: v2(137.16,49.68) 137.42,49.42 DC3.1 ; CE41.1 168.29,40.58 168.29,40.1 v2(168.44,39.95) v1(166.83,39.95) 166.15,39.95 v2(166.14,39.95)
  BOTTOM w0.102: v2(137.16,49.68) 137.16,48.55 138.07,47.64 138.07,46.25 138.64,45.67 139.97,45.67 140.35,45.29 147.59,45.29 149.8,43.08 160.36,43.08 163.8,39.64 165.83,39.64 166.14,39.95 v2(166.14,39.95) ; UE1.100 168.82,39.57 v2(168.44,39.95) 167.68,40.71 RE48.1
EC_RSMRST#_R: length 13.1
  TOP w0.102: DC3.2 135.7,49.42 v2(135.45,49.17) 135.11,49.17 RC346.2
  BOTTOM w0.102: UC1.AG1 126,50.25 126.28,50.25 127.16,49.37 128.31,49.37 128.9,48.79 131.92,48.79 132.43,48.28 CC52.1 132.67,48.28 133.31,48.91 135.2,48.91 v2(135.45,49.17) 135.45,48.55 v1(135.47,48.53)
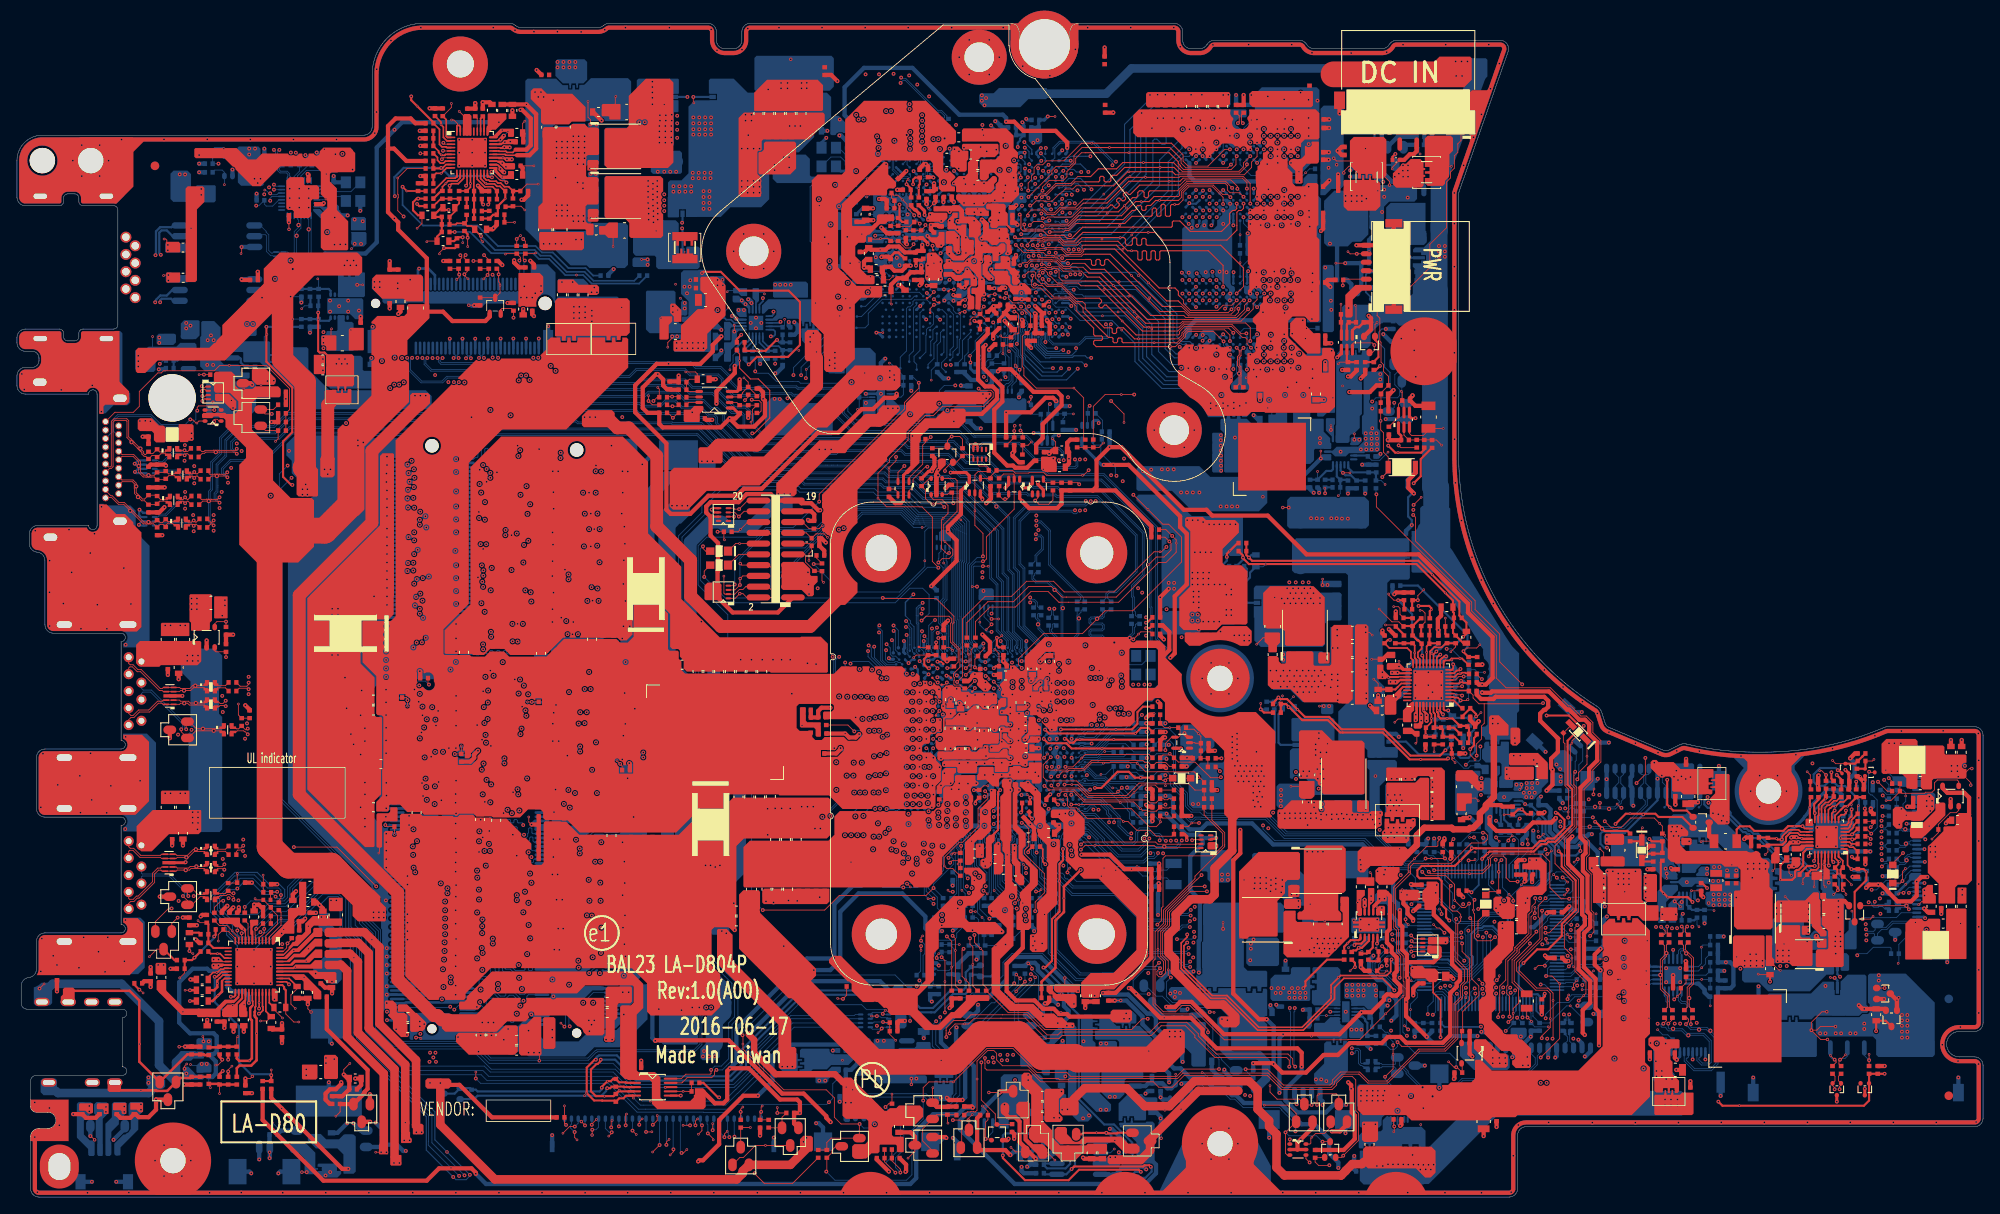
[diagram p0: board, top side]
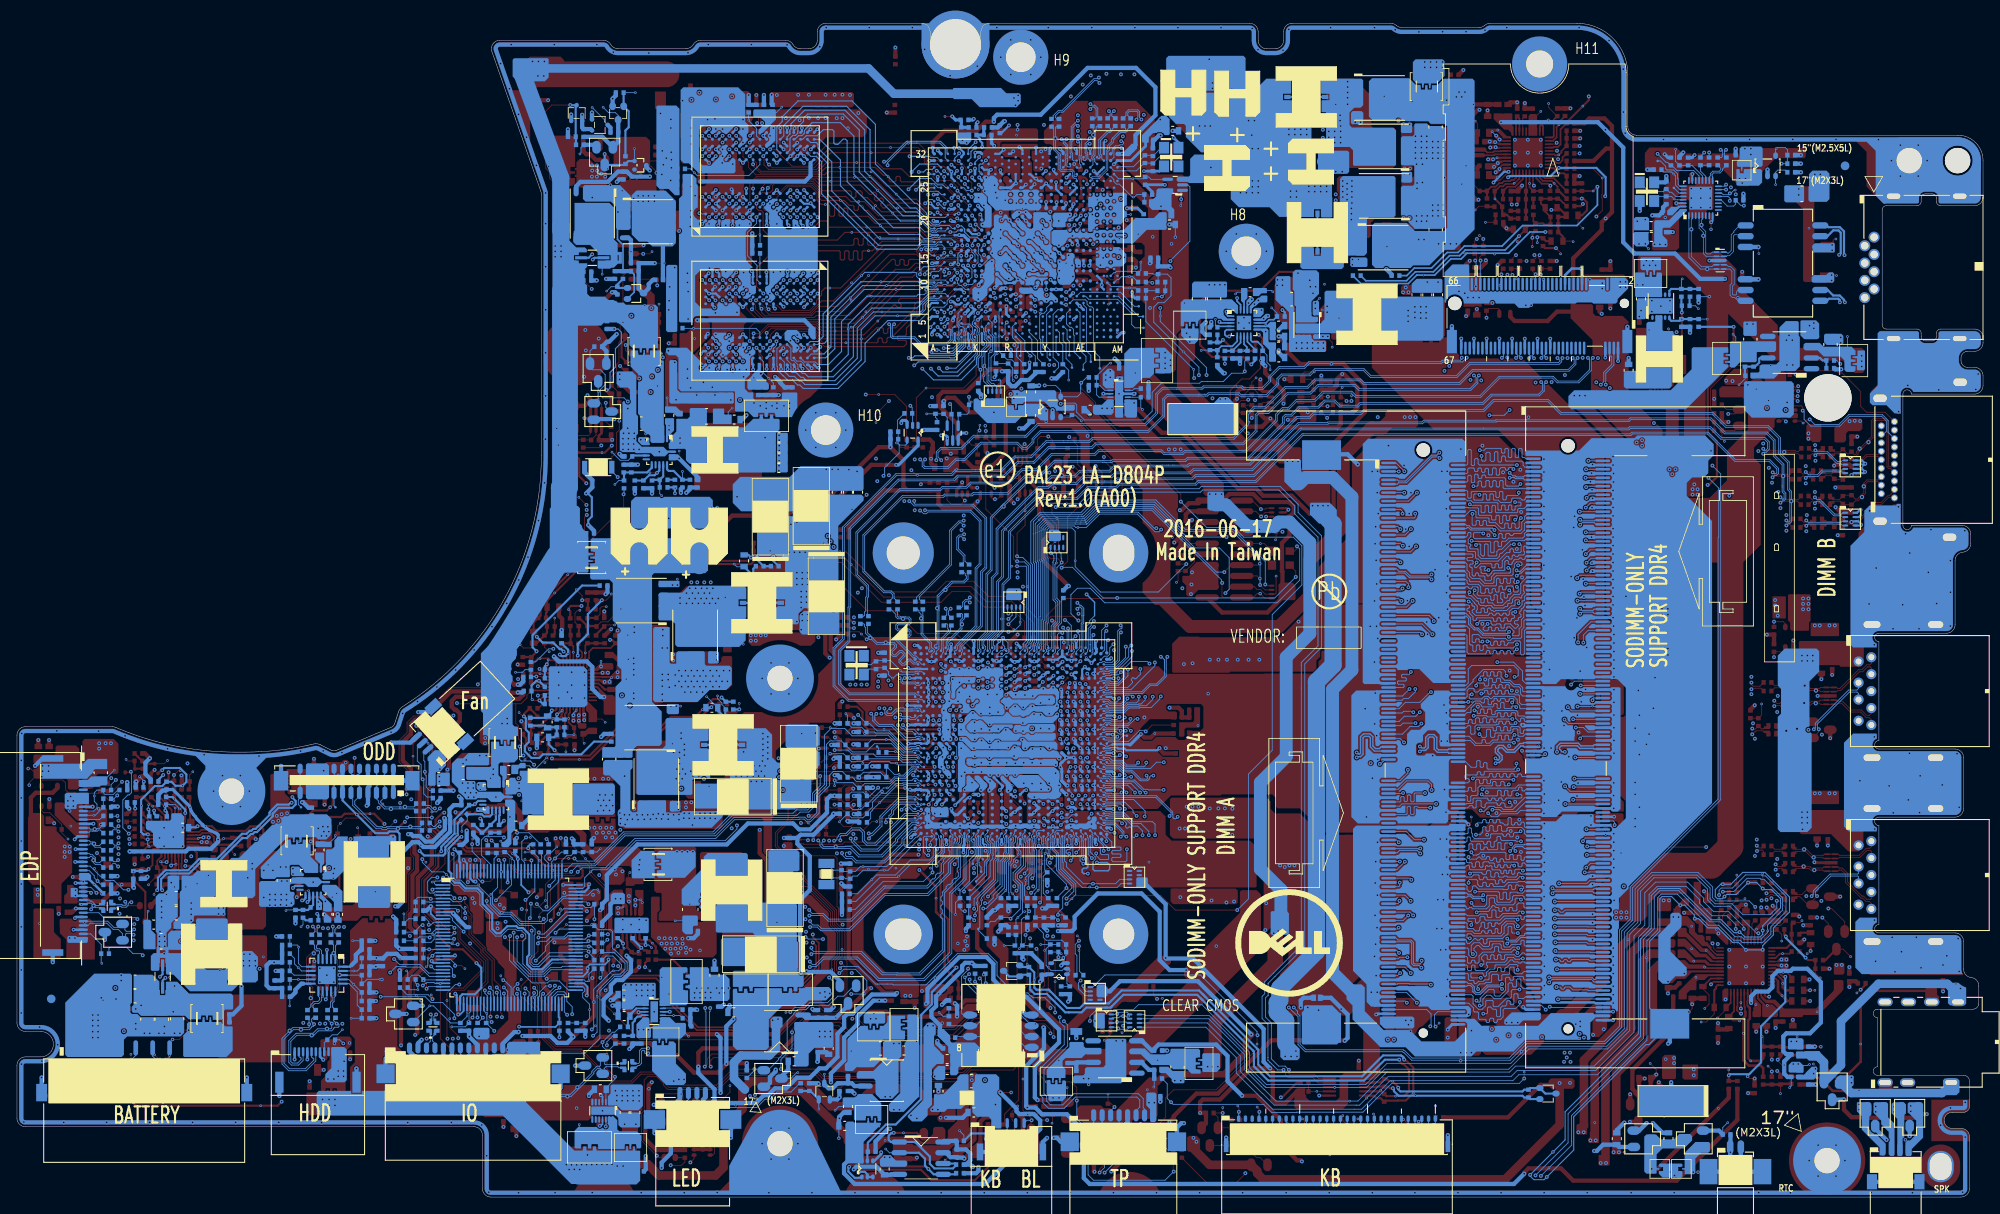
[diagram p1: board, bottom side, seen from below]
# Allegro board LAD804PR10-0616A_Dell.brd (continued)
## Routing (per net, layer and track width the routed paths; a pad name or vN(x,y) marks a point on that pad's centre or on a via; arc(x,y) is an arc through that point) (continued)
EC_RST#: length 4.6
  BOTTOM w0.102: v1(180.61,20.08) 179.03,20.08 178.58,20.53 CE23.1 178.58,21.71 178.42,21.87 UE1.37
EC_RX: length 210.4
  TOP w0.102: v2(52.92,111.16) 52.74,110.98 52.74,110.83 RW7.1 ; v2(183.59,24.58) 183.59,25.14 v1(183.97,25.52) ; v2(59.71,113.05) 59.96,112.79 RW10.1
  IN1 w0.127: v2(113.88,73.74) 115.28,72.34 121.48,72.34 124.57,69.24 134.37,69.24 134.83,68.79 134.83,68.69 134.83,67.24 136.04,66.03 136.04,64.34 136.52,63.86 136.52,59.25 138.7,57.07 138.7,50.37 138.39,50.06 138.39,48.7 143.06,44.02 145.6,44.02 145.61,44.02 145.82,44.02 146.77,43.07 158.58,43.07 160.83,40.82 168.99,40.82 170.86,38.96 177.47,38.96 180.61,38.96 180.82,39.17 183.11,39.17 184.61,37.67 184.61,33.65 185.21,33.05 185.21,32.14 186.04,31.31 186.04,30.26 185.31,29.54 185.31,24.54 185.03,24.26 183.91,24.26 v2(183.59,24.58)
  IN2 w0.127: v2(59.71,113.05) 59.46,112.79 59.46,112.03 59.05,111.63 52.96,111.63 52.78,111.44 52.78,111.3 v2(52.92,111.16) 52.73,110.97 52.73,110.28 53.94,109.06 53.94,106.25 56.95,103.24 60.42,103.24 60.61,103.43 62.93,103.43 64.87,101.49 64.87,100.29 67.16,98 83.63,98 84.78,99.14 91.25,99.14 91.31,99.21 91.52,99.21 94.45,96.28 94.46,96.28 98.97,91.77 99.52,91.22 99.52,91.2 100.67,90.06 103.23,90.06 103.23,90.06 103.44,90.06 106.45,87.05 106.45,86.26 108.1,84.61 109.53,84.61 111.21,82.93 111.21,81.43 112.8,79.84 112.8,74.55 113.6,73.74 v2(113.88,73.74)
  BOTTOM w0.102: UE1.31 183.35,24.82 v2(183.59,24.58)
EC_SCI#: length 85
  TOP w0.102: v2(121.16,51.83) 121.16,51.87 v1(121.56,52.28)
  IN1 w0.102: v2(121.16,51.83) 120.99,51.67 120.99,50.5 121.28,50.21 121.28,49.61 121.72,49.17 122.13,49.17 122.19,49.23 128.04,49.23 129.31,47.96
  IN1 w0.127: v2(183.28,29.23) 183.28,30.1 183.74,30.56 183.74,30.74 183.43,31.04 183.12,31.04 182.86,31.3 182.86,32.77 183.6,33.51 183.6,34.23 183.6,37.25 182.71,38.14 181.27,38.14 181.07,37.94 181.01,37.94 177.05,37.94 170.42,37.94 169.67,38.69 167.91,38.69 167.56,39.02 165.76,39.02 165.02,39.77 160.45,39.77 158.26,41.95 140.96,41.95 139.09,43.83 133.74,43.83 133.46,44.11 133.16,44.11 129.31,47.96
  BOTTOM w0.102: v2(121.16,51.83) 121.05,51.94 121.05,53.1 UC1.AA8 ; RE66.2 RE61.2 v2(183.28,29.23) 182.6,29.23 182.6,29.22 UE1.20
EC_SMB_CK1: length 111.6
  TOP w0.102: v2(218.65,42.25) 218.34,42.56 PR770.1 ; v2(164.09,19.78) v1(163.66,20.21) ; PR18.2 214.43,14.25 214.43,13.7 PD2.3 214.15,13.15 214.4,12.91 v2(214.4,12.72)
  IN2 w0.127: v2(164.09,19.78) 164.09,19.82 164.2,19.93 164.87,19.93 165.29,19.51 168.13,19.51 170.78,22.17 179.14,22.17 179.22,22.09 180.64,22.09 182.06,20.67 188.64,20.67 190.59,18.72 195.85,18.72 196.53,18.04 199.68,18.04 202.33,15.38 202.69,15.38 202.69,15.39 213.57,15.39 214.52,14.43 214.52,12.85 v2(214.4,12.72) 214.4,12.17 214.92,11.65 218.41,11.65 219.51,12.75 219.51,16.06 220.49,17.05 220.49,22.26 221.37,23.13 221.37,26.42 221.04,26.75 221.04,34.35 221.37,34.68 221.37,36.1 221.37,36.46 220.85,36.98 220.49,36.98 219.82,36.98 219.31,37.48 219.31,40.28 219.45,40.43 219.45,41.61 218.81,42.25 v2(218.65,42.25)
  BOTTOM w0.102: v2(164.09,19.78) 163.88,19.99 163.88,24.51 161.68,26.7 160.92,26.7 160.59,27.03 160.59,27.42 160.82,27.65 161.61,28.44 162.41,28.44 162.77,28.09 162.77,28.07 RE31.1
EC_SMB_CK1_R: length 4.3
  TOP w0.102: RPE1.8 164.47,28.99 v2(164.46,28.97)
  BOTTOM w0.102: UE1.77 164.72,29.22 164.47,28.97 v2(164.46,28.97) 164.45,28.96 164.45,28.81 163.8,28.16 RE31.2
EC_SMB_CK2: length 233.1
  TOP w0.102: v2(107.38,86.17) 107.17,86.17 105.7,84.7 105.7,83.83 105.22,83.35 QV1.6 ; v2(150.07,15.39) 150.07,16.14 149.74,16.47 141.3,16.47 141.06,16.71 138.93,18.84 138.93,19.09 137.82,20.21 134.96,20.21 133.81,19.07 123.44,19.07 123.27,19.07 122.93,18.73 121.34,18.73 118.96,21.1 116.07,21.1 112.91,21.1 112.24,20.43 v1(111.78,20.43) 110.66,20.43 110,19.77 v2(110,19.32) ; v2(110.45,81.87) 110.38,81.93 110.38,83 RC16.2 109.99,83.13 109.75,82.89 QC79.3 ; v2(81.87,15) 81.87,14.6 81.77,14.5 78.89,14.5 78.36,13.97 U2407.10
  IN1 w0.127: v2(110,19.32) 109.63,19.69 106.08,19.69 105.82,19.44 101.16,19.44 100.57,20.03 98.22,20.03 81.72,20.03 79.41,17.72 79.41,17.09 79.41,15.94 79.95,15.4 81.48,15.4 v2(81.87,15) ; v2(150.13,22.31) 150.13,22.43 150.69,22.99 160.37,22.99 160.74,23.36 160.74,25.29 163.02,27.57 163.02,28.44 162.26,29.2 v2(162.26,30.36) ; v2(107.38,86.17) 107.31,86.24 107.13,86.24 106.26,85.36 106.26,83.9 107.65,82.5 109.81,82.5 v2(110.45,81.87)
  BOTTOM w0.102: RE33.1 162.63,29.99 v2(162.26,30.36) ; v2(150.07,15.39) 150.22,15.54 150.22,21.83 150.13,21.92 v2(150.13,22.31) ; v2(81.87,15) 81.96,15.09 82.32,15.45 83.08,15.45 83.94,16.31 83.94,20.21 83.94,20.55 84.63,21.23 84.63,23.51 84.32,23.81 84.32,23.81 84.32,24.09 84.32,24.09 84.32,25.22 84.32,25.22 80,29.54 80,62.91 78.04,64.88 78.04,78.03 80.79,80.79 80.79,81.75 82.88,83.84 92.22,83.84 92.48,83.58 101.18,83.58 101.56,83.2 105.24,83.2 106.64,81.81 108.92,81.81 108.99,81.87 v2(110.45,81.87)
EC_SMB_CK2_R: length 3.8
  TOP w0.102: RPE1.6 164.71,29.99 v2(164.49,30.21)
  BOTTOM w0.102: RE33.2 164.02,30.21 v2(164.49,30.21) 164.67,30.02 UE1.79
EC_SMB_DA1: length 112.3
  TOP w0.102: v2(218.6,41.67) PR769.1 ; v2(214.98,12.72) 214.98,13.05 215.15,13.22 PD2.2 214.84,13.73 214.84,14.23 PR20.2
  IN2 w0.127: v2(218.6,41.67) 218.78,41.67 219.02,41.43 219.02,40.61 218.88,40.46 218.88,37.3 219.64,36.54 220.67,36.54 220.94,36.28 220.94,34.86 220.61,34.52 220.61,26.57 220.94,26.24 220.94,23.31 220.06,22.44 220.06,17.23 219.08,16.24 219.08,15.88 219.08,12.93 218.23,12.08 215.09,12.08 214.9,12.27 214.9,12.64 v2(214.98,12.72) 214.95,12.74 214.95,14.61 213.75,15.82 202.51,15.82 199.86,18.47 196.7,18.47 196.03,19.15 190.77,19.15 188.82,21.1 182.24,21.1 180.82,22.52 180.47,22.52 179.4,22.52 179.32,22.6 170.61,22.6 167.95,19.94 165.46,19.94 165.05,20.36 164.4,20.36 164.36,20.4 164.04,20.4 163.66,20.02 163.66,20 163.66,20 163.66,19.35 163.66,19.35 163.66,19.32 v2(163.95,19.03)
  BOTTOM w0.102: RE32.1 162.76,28.85 161.44,28.85 160.66,28.06 160.66,28.06 160.18,27.58 160.18,26.86 160.75,26.29 161.51,26.29 163.47,24.34 v1(163.47,23.69) 163.47,19.47 163.9,19.03 v2(163.95,19.03)
EC_SMB_DA1_R: length 4
  TOP w0.102: RPE1.7 164.64,29.49 164.56,29.57 v2(164.43,29.57)
  BOTTOM w0.102: UE1.78 164.61,29.63 164.55,29.57 v2(164.43,29.57) 164.19,29.57 163.8,29.18 RE32.2
EC_SMB_DA2: length 234.3
  TOP w0.102: v2(104.67,86.26) 103.92,85.51 QV1.3 ; QC79.6 107.6,84.79 RC17.2 107.16,83.43 107.16,82.43 107.78,81.81 v1(108.1,81.81) 108.99,81.81 v2(109.38,81.41) ; v2(109.62,18.88) 109.62,19.13 109.6,19.15 109.6,19.34 109.6,19.34 109.6,19.68 109.6,19.94 110.49,20.83 111.84,20.83 112.51,21.51 112.74,21.51 113.08,21.51 113.08,21.51 116.24,21.51 119.13,21.51 121.51,19.13 122.76,19.13 123.11,19.47 123.61,19.47 133.65,19.47 134.79,20.62 137.98,20.62 139.34,19.26 139.34,19 141.46,16.88 149.91,16.88 150.48,16.31 150.48,15.68 v2(150.77,15.39) ; U2407.9 78.43,13.47 78.53,13.57 78.53,13.57 79.06,14.09 81.94,14.09 82.28,14.43 82.28,14.84 82.44,15 v2(82.51,15)
  IN1 w0.127: v2(109.38,81.41) 108.72,82.07 107.47,82.07 105.82,83.72 105.82,84.46 104.67,85.62 v2(104.67,86.26) ; v2(162.2,31.01) 162.33,31.01 162.69,30.64 162.69,29.38 163.46,28.62 163.46,27.39 161.17,25.11 161.17,23.18 160.55,22.56 150.9,22.56 150.72,22.38 v2(150.72,22.31) ; v2(109.62,18.88) 109.24,19.26 106.26,19.26 106,19 100.99,19 100.39,19.6 81.9,19.6 79.84,17.54 79.84,16.12 80.13,15.83 81.68,15.83 v2(82.51,15)
  BOTTOM w0.102: v2(150.72,22.31) 150.72,21.92 150.63,21.83 150.63,15.52 v2(150.77,15.39) ; v2(109.38,81.41) 109.37,81.43 109.15,81.43 109.12,81.4 106.8,81.4 106.47,81.4 105.07,82.8 101.39,82.8 101.01,83.18 92.31,83.18 92.05,83.43 83.05,83.43 81.2,81.58 81.2,80.62 78.44,77.87 78.44,65.05 80.17,63.31 80.41,63.08 80.41,60.06 80.41,29.71 83.69,26.43 84.73,25.39 84.73,25.39 84.73,23.98 85.03,23.67 85.03,21.07 84.35,20.38 84.35,16.48 84.35,16.14 83.93,15.72 83.21,15 v2(82.51,15) ; RE34.1 v2(162.2,31.01)
EC_SMB_DA2_R: length 4
  TOP w0.102: RPE1.5 164.82,30.49 v2(164.44,30.87)
  BOTTOM w0.102: RE34.2 163.8,30.99 163.93,30.87 v2(164.44,30.87) 164.88,30.42 UE1.80
EC_SMI#: length 106.6
  TOP w0.102: v2(183.22,30.63) v1(182.85,31) ; RC665.1 RC666.2 110.31,39.69 v2(110.07,39.45)
  IN1 w0.102: 122.04,38.88 122.04,38.99 122.07,39.01 122.07,39.67 120.38,41.36 118.7,41.36 117.75,42.31 111.27,42.31 110.26,41.29 110.26,39.64 v2(110.07,39.45)
  IN1 w0.127: 122.04,38.88 122.04,38.66 122.57,38.13 122.57,38.13 123.13,37.57 123.13,37.57 123.72,36.98 134,36.98 134.96,36.02 139.12,36.02 140.46,34.68 140.46,31.6 143.44,28.62 149.85,28.62 150.36,28.11 154.98,28.11 157.31,30.44 157.31,32.21 158.26,33.17 160.68,33.17 160.83,33.01 161.21,33.01 161.88,33.67 161.88,35.11 161.88,35.54 162.07,35.73 162.07,38.5 162.53,38.95 163.72,38.95 165.34,37.33 165.41,37.33 165.41,37.33 167.02,37.33 167.24,37.55 169.67,37.55 170.09,37.12 170.3,37.12 172.68,37.12 173.52,36.28 181.67,36.28 182.24,36.84 183.03,36.84 183.34,36.53 183.34,36.03 183.08,35.77 182.84,35.77 182.52,35.45 182.52,31.07 182.96,30.63 v2(183.22,30.63)
  BOTTOM w0.102: v2(183.22,30.63) 183.29,30.7 184.43,30.7 184.88,30.25 RE40.1 RE19.2
EC_SMI#_R: length 3.2
  BOTTOM w0.102: RE40.2 183.78,30.05 183.05,30.05 182.7,30.41 182.7,30.94 182.42,31.22 UE1.15
EC_TP_INT#: length 154.2
  TOP w0.102: v2(87.02,2.81) 87.02,2.75 88.15,1.61 91.48,1.61 RE338.1 ; v2(171.22,39.72) 171.87,39.72 v1(171.98,39.83)
  IN1 w0.127: v2(87.02,2.81) 88.49,1.33 149.75,1.33 151.47,3.05 153.5,3.05 156.24,5.8 168.32,5.8 168.67,5.8 173.74,10.86 179.39,10.86 180.19,10.86 185.5,16.18 185.5,20.71 185,21.21 185,22.08 185.69,22.78 185.69,29.56 186.29,30.16 186.29,31.42 185.47,32.24 185.47,33.16 184.87,33.76 184.87,37.78 183.22,39.43 180.72,39.43 180.5,39.21 171.69,39.21 171.22,39.69 v2(171.22,39.72)
  BOTTOM w0.102: UE1.106 v2(171.22,39.72)
EC_TX: length 209.1
  TOP w0.102: RW9.1 v2(58.95,113.05) 59.35,113.45 v1(59.41,113.45) ; v2(52.3,111.14) 52.46,110.97 52.46,110.83 RW6.1
  IN1 w0.127: v2(184.03,24.96) 184.04,24.96 184.04,24.97 184.5,24.51 184.89,24.51 185.06,24.68 185.06,31.93 184.96,32.03 184.96,32.95 184.36,33.55 184.36,37.57 183.02,38.91 182.2,38.91 180.91,38.91 180.71,38.71 180.69,38.71 170.75,38.71 170,39.45 168.32,39.45 167.25,40.53 160.76,40.53 158.47,42.82 146.66,42.82 145.71,43.77 142.96,43.77 138.07,48.66 138.07,50.25 138.45,50.63 138.45,56.96 135.56,59.85 135.56,63.81 135.78,64.03 135.78,65.93 134.58,67.13 134.58,67.35 134.58,68.39 134.07,68.9 124.28,68.9 121.09,72.08 114.9,72.08 v2(113.88,73.11)
  IN2 w0.127: v2(58.95,113.05) 59.2,112.79 59.2,112.14 58.94,111.88 52.85,111.88 52.52,111.55 52.52,111.36 v2(52.3,111.14) 52.47,110.97 52.47,110.17 53.69,108.95 53.69,106.14 56.84,102.99 60.52,102.99 60.71,103.18 62.82,103.18 64.56,101.44 64.56,100.19 67.01,97.74 83.42,97.74 83.74,97.74 84.88,98.89 91.35,98.89 91.42,98.95 94.34,96.03 94.35,96.03 98.86,91.52 99.27,91.11 99.27,91.1 100.56,89.81 103.33,89.81 106.19,86.95 106.19,86.31 106.19,86.1 107.93,84.36 109.42,84.36 110.95,82.82 110.95,81.3 112.54,79.71 112.54,74.44 v2(113.88,73.11)
  BOTTOM w0.102: v2(184.03,24.96) 184.04,24.96 184.04,24.97 183.98,24.97 183.74,25.21 183.64,25.21 183.54,25.32 183.54,25.32 182.71,25.32 182.61,25.22 UE1.30
ECAGND: length 75
  TOP w0.203: v2(119.27,40.69) 119.27,40.86 PH1.2 ; v2(138.03,30.03) 137.65,29.65 137.65,27.1 140.97,23.78 142.73,23.78 146.48,20.03 151.59,20.03 155,23.44 v1(155,23.96) 155,25.01 156.13,26.14 161.56,26.14 162.04,26.62 162.04,27.95 v2(162.13,28.03) ; v2(167.91,18.85) 167.91,23.25 167.04,24.13 LE4.2
  IN1 w0.203: v2(138.03,30.03) 136.67,31.39 136.67,33.95 135.58,35.04 135.2,35.04 134.67,35.04 133.7,36.01 123.24,36.01 120.97,38.29 120.97,38.99 v2(119.27,40.69)
  BOTTOM w0.203: CE43.1 v2(167.91,18.85) ; UE1.69 165.14,26.02 164.6,26.56 v2(164.6,26.98) 164.6,27.17 164.32,27.45 162.54,27.45 162.13,27.86 v2(162.13,28.03)
EDP_AUXN: length 148
  IN2 w0.102: 126.22,57.04 126.22,57.04 124.77,55.6 120.19,55.6 119.73,56.05 119.73,58.16 119.99,58.41 119.99,59.67 119.37,60.29 119.35,60.29 119.25,60.39 118.79,60.39 v2(118.51,60.11)
  IN2 w0.127: v2(219.92,43.13) 219.74,43.31 219.44,43.31 219.16,43.6 219.16,44.32 218.94,44.53 217.83,44.53 217.14,45.22 217.14,45.62 216.48,46.28 212.01,46.28 208.69,42.96 204.61,42.96 204.24,43.33 203.3,43.33 202.69,42.72 200.4,42.72 199.04,44.08 198.98,44.08 198.92,44.08 197.49,44.08 197.21,44.08 196.6,44.68 194.89,44.68 193.58,45.99 191.42,45.99 191.07,46.34 191.07,46.36 190.82,46.6 190.81,46.6 187.63,49.77 185.24,49.77 184.05,50.96 182.84,50.96 182.25,51.55 182.19,51.55 174.71,59.03 174.71,61.97 171.2,65.48 171.2,66.78 168.54,69.44 168.54,71.36 168.49,71.41 168.11,71.79 167.74,72.16 162.12,77.78 161.6,77.78 161.6,77.77 150.67,77.77 149.79,78.66 135.93,78.66 131.06,73.79 131.06,59.48 129.9,58.32 128.62,58.32 127.71,57.41 126.58,57.41 126.22,57.04
  BOTTOM w0.102: v2(219.92,43.13) 220.12,43.34 220.54,43.34 220.8,43.08 C4322.2 ; v2(118.51,60.11) 118.31,60.31 UC1.H15
EDP_AUXN_C: length 2.6
  BOTTOM w0.102: C4322.1 222.08,43.31 222.28,43.31 222.42,43.17 223.01,43.17 223.04,43.2 223.23,43.2 223.38,43.05 JEDP1.15
EDP_AUXP: length 148
  IN2 w0.102: 126.03,57.23 126.02,57.22 126.02,57.2 125.97,57.15 125.97,57.13 124.67,55.83 120.29,55.83 119.97,56.15 119.97,58.06 120.23,58.31 120.23,59.77 119.47,60.53 119.45,60.53 119.35,60.63 118.79,60.63 v2(118.51,60.91)
  IN2 w0.127: v2(219.92,43.77) 219.73,43.58 219.55,43.58 219.42,43.71 219.42,44.43 219.05,44.8 217.94,44.8 217.4,45.33 217.4,45.73 216.59,46.54 211.9,46.54 208.58,43.23 204.72,43.23 204.35,43.59 203.19,43.59 202.58,42.98 200.51,42.98 199.15,44.34 198.98,44.34 197.6,44.34 197.31,44.34 196.71,44.94 195,44.94 193.68,46.26 191.53,46.26 191.33,46.45 191.33,46.47 190.93,46.87 190.92,46.87 187.74,50.04 185.35,50.04 184.16,51.23 182.95,51.23 182.36,51.82 182.3,51.82 174.97,59.14 174.97,62.08 171.46,65.59 171.46,66.89 168.8,69.55 168.8,71.47 168.75,71.52 167.93,72.35 167.85,72.42 162.23,78.04 161.49,78.04 161.49,78.04 150.78,78.04 149.9,78.92 135.82,78.92 130.8,73.9 130.8,59.59 129.79,58.59 128.51,58.59 127.6,57.67 126.47,57.67 126.03,57.23
  BOTTOM w0.102: v2(219.92,43.77) 220.15,43.54 220.38,43.54 C4321.2 ; v2(118.51,60.91) 118.31,61.11 UC1.G15
EDP_AUXP_C: length 2.7
  BOTTOM w0.102: JEDP1.14 223.38,43.55 223.23,43.4 v3(222.73,43.4) 222.48,43.4 222.37,43.52 222.16,43.52 C4321.1
EDP_HPD: length 3.8
  BOTTOM w0.102: JEDP1.11 v1(222.84,45.05) 222.65,45.05 RP1.1 R13.1
EDP_TXN0: length 147
  IN2 w0.127: v2(219.92,41.74) 220.49,41.74 220.62,41.86 220.62,45 220.23,45.39 219.7,45.39 218.84,46.26 217.78,46.26 216.95,47.08 211.64,47.08 208.31,43.76 205.09,43.76 204.55,44.31 202.95,44.31 202.16,43.52 200.88,43.52 200.72,43.68 200.69,43.68 199.5,44.87 198.71,44.87 197.82,44.87 197.82,44.87 197.65,44.87 196.92,45.6 195.36,45.6 193.97,47 191.55,47 187.98,50.57 185.57,50.57 184.38,51.76 183.17,51.76 176.36,58.57 176.36,61.44 172,65.81 172,66.66 172,67.11 172,67.12 169.36,69.75 169.36,71.66 169.28,71.74 169.28,71.75 168.15,72.88 168.07,72.96 162.46,78.57 161.27,78.57 151.17,78.57 149.93,79.81 140.77,79.81 140.28,80.3 125.48,80.3 125.19,80.59 125.19,80.59 124.8,80.98 v2(124.8,81.04)
  BOTTOM w0.102: v2(124.8,81.04) 119.39,81.04 118.19,79.84 118.19,74.63 118.68,74.15 118.68,67.3 120.95,65.03 120.95,64.69 121.13,64.51 121.2,64.51 121.31,64.4 121.31,64.15 UC1.B9 ; v2(219.92,41.74) 220.14,41.52 220.39,41.52 C4311.2
EDP_TXN0_C: length 2.8
  BOTTOM w0.102: JEDP1.17 223.38,42.05 223.23,41.9 223,41.9 v3(222.8,41.7) 222.59,41.48 222.16,41.48 C4311.1
EDP_TXN1: length 152.9
  IN2 w0.127: v2(126.07,82.14) 126.07,82.12 126.23,81.96 126.23,81.67 126.8,81.1 140.8,81.1 141.3,80.61 150.26,80.61 151.5,79.37 160.94,79.37 162.84,79.37 170.19,72.02 170.19,70.07 172.79,67.47 172.79,66.42 172.79,66.16 178.8,60.15 178.8,58.39 179.89,57.3 180.61,57.3 184.3,53.61 185.34,53.61 187.05,51.9 189.18,51.9 192.87,48.21 195.61,48.21 197.94,45.88 198.15,45.67 198.15,45.67 199.04,45.67 199.83,45.67 199.87,45.71 199.9,45.71 199.94,45.75 202.01,45.75 204.24,45.75 205.31,44.68 207.99,44.68 208.1,44.79 211.51,48.2 217.3,48.2 218.35,47.15 219.08,47.15 219.73,46.49 221.15,46.49 221.64,46 221.64,40.15 221.01,39.53 220.22,39.53 v2(219.97,39.77)
  BOTTOM w0.102: v2(126.07,82.14) 126.07,81.86 125.97,81.76 119.11,81.76 117.52,80.17 117.52,74.23 118.04,73.71 118.04,67.36 120.47,64.93 120.47,64.66 120.4,64.59 120.4,64.33 120.49,64.24 120.49,63.98 UC1.B10 ; v2(219.97,39.77) 220.16,39.58 220.48,39.58 C4313.2
EDP_TXN1_C: length 3.3
  BOTTOM w0.102: JEDP1.20 223.38,40.55 223.23,40.4 223,40.4 222.65,40.05 222.65,39.55 222.55,39.45 222.16,39.45 C4313.1
EDP_TXP0: length 147
  IN2 w0.127: v2(125.38,81.01) 125.38,80.78 125.59,80.57 140.39,80.57 140.88,80.07 150.04,80.07 151.28,78.84 161.16,78.84 161.16,78.84 162.56,78.84 168.18,73.22 168.26,73.14 169.55,71.85 169.63,71.77 169.63,69.86 172.26,67.23 172.26,67.21 172.26,65.92 176.62,61.55 176.62,58.68 182.69,52.62 183.28,52.02 184.49,52.02 185.68,50.84 188.09,50.84 191.66,47.26 194.08,47.26 195.47,45.87 197.03,45.87 197.76,45.14 197.93,45.14 198.59,45.14 198.59,45.14 198.82,45.14 199.61,45.14 200.8,43.94 200.83,43.94 200.99,43.78 202.05,43.78 202.84,44.57 204.66,44.57 205.2,44.02 208.2,44.02 211.53,47.35 217.06,47.35 217.88,46.52 218.95,46.52 219.81,45.66 220.34,45.66 220.88,45.11 220.88,41.76 220.68,41.55 220.48,41.36 220.12,41.36 v2(219.92,41.15)
  BOTTOM w0.102: UC1.A9 121.26,64.88 121.15,64.99 121.15,65.12 118.88,67.38 118.88,74.23 118.4,74.71 118.4,79.76 119.48,80.84 124.43,80.84 124.63,80.64 124.97,80.64 125.34,81.01 125.34,81.01 v2(125.38,81.01) ; v2(219.92,41.15) 220.09,41.32 220.39,41.32 C4312.2
EDP_TXP0_C: length 2.7
  BOTTOM w0.102: C4312.1 222.08,41.28 222.71,41.28 223.11,41.68 223.25,41.68 223.38,41.55 JEDP1.18
EDP_TXP1: length 152.9
  IN2 w0.127: v2(126.65,82.12) 126.49,81.96 126.49,81.78 126.91,81.37 140.91,81.37 141.41,80.87 144.12,80.87 150.37,80.87 151.61,79.63 160.83,79.63 162.95,79.63 163.1,79.48 170.45,72.13 170.45,70.18 173.06,67.57 173.06,66.31 173.06,66.27 179.06,60.26 179.06,58.5 180,57.56 180.72,57.56 184.41,53.88 185.45,53.88 187.16,52.17 189.29,52.17 192.98,48.48 195.72,48.48 198.26,45.93 199.72,45.93 199.76,45.98 199.79,45.98 199.83,46.01 201.9,46.01 204.35,46.01 205.41,44.94 207.88,44.94 207.99,45.05 208.07,45.13 208.09,45.15 211.4,48.46 217.41,48.46 218.46,47.41 219.19,47.41 219.84,46.76 221.25,46.76 221.9,46.11 221.9,40.04 221.12,39.26 220.23,39.26 v2(219.97,39.01)
  BOTTOM w0.102: UC1.A10 120.67,64.5 120.67,65.02 118.24,67.44 118.24,73.8 117.73,74.32 117.73,80.08 119.2,81.55 126.07,81.55 126.64,82.12 v2(126.65,82.12) ; C4314.2 220.8,39.13 220.56,39.38 220.34,39.38 v2(219.97,39.01)
EDP_TXP1_C: length 3.3
  BOTTOM w0.102: C4314.1 221.71,38.91 222.05,39.25 222.66,39.25 222.88,39.47 v3(222.88,39.74) 222.88,39.99 223.09,40.2 223.23,40.2 223.38,40.05 JEDP1.21
EGPIO131: length 1.4
  TOP w0.102: RC697.2 108.8,46.39 v2(108.68,46.28)
  BOTTOM w0.102: v2(108.68,46.28) 109.11,46.71 UC1.AP31
EGPIO145: length 8.4
  BOTTOM w0.102: RC55.2 114.89,35.34 114.89,35.89 114.93,35.93 114.93,39.33 v1(114.83,39.43) 114.57,39.69 114.57,40.36 114.55,40.39 114.55,41.82 114.35,42.02 114.35,42.34 114.42,42.41 114.42,42.7 114.25,42.87 114.25,43.12 UC1.AY22
EGPIO146: length 8.2
  BOTTOM w0.102: UC1.BA22 114.11,41.91 114.32,41.7 114.32,41.34 113.8,40.82 v1(113.8,40.39) 113.8,40.32 114.37,39.76 114.37,39.46 114.67,39.16 114.67,35.99 114.07,35.39 RC61.2
EN_0.6VSP: length 3
  BOTTOM w0.203: PC203.1 87.57,100.82 PU200.7
  BOTTOM w0.254: PR202.2 PC203.1
EN_1.2V: length 2.8
  BOTTOM w0.203: PU200.8 87.17,100.63 86.82,100.28 86.82,99.92 PR201.2
  BOTTOM w0.254: PR201.2 PC202.1
EN_1.5VS: length 4.5
  BOTTOM w0.102: v1(97.81,12.97) 97.76,13.02 PR403.2
  BOTTOM w0.508: PU400.2 99.27,15.89 98.38,15 PC403.1 PR403.2
EN_1.8VALW: length 4.8
  BOTTOM w0.102: v1(32.53,103.59) 32.54,103.6 PR601.2
  BOTTOM w0.254: PR601.2 PR602.2 PC602.1 35.78,103.4 36.79,103.4 37,103.6 PU600.5
EN_2.5V: length 2.8
  BOTTOM w0.254: PC905.1 PR903.2 18.93,98.72 19.22,99.01 PU900.2
EN_3V: length 6
  BOTTOM w0.102: v1(179.42,43.15) 179.42,43.75 178.79,44.39 178.79,44.87 178.83,44.91 PR121.1
  BOTTOM w0.254: PU100.12 175.86,45.17 176.11,44.91 176.8,44.91 177.06,45.17 177.19,45.17 177.19,45.17 PR121.1
EN_5V: length 8.8
  TOP w0.254: v2(197.63,34.82) 197.06,35.39 v1(194.71,35.39) 193.89,36.21 193.89,39.5 PR120.1
  BOTTOM w0.254: PU102.12 197.42,35.03 v2(197.63,34.82)
EN_+1.35VGPU: length 6.1
  BOTTOM w0.102: v1(161.37,84.09) 160.92,84.55 PR1403.2
  BOTTOM w0.254: PR1403.2 160.29,85.47 PR1404.1 PC1404.1 157.57,85.51 157.03,86.05 PU1400.11
EN_VDDP_ALWP: length 5.2
  TOP w0.254: PR301.2 157.61,29.1 157.94,29.1 v2(158.26,29.42) 158.64,29.42 159.47,30.24 PU300.3
  BOTTOM w0.102: v1(158.64,28.97) 158.26,29.36 v2(158.26,29.42)
  BOTTOM w0.254: v2(158.26,29.42) 159.28,30.43 PC301.1
ENABLE_APU: length 2.6
  TOP w0.203: PR1085.2 171.2,61.8 170.91,61.8 170.83,61.88 170.46,61.88 170.33,61.75 v1(170.2,61.75) 169.95,61.75 169.6,61.41 PU1001.8
ENABLE_VGA: length 2.8
  TOP w0.203: PU1100.8 50.54,122.24 50.31,122.01 49.94,122.01 49.6,122.34 49.6,122.67 PR1116.2
ENLDO_3V5V: length 35.9
  TOP w0.102: v1(175.41,45.1) 175.46,45.15 PR102.1
  TOP w0.254: PR102.1 176.47,45.15 177.07,45.75 v2(177.49,45.75) 178.08,45.16 178.44,45.16 PR103.1
  IN2 w0.254: v2(198.27,35.01) 198.27,35.07 197.89,35.45 196.36,35.45 195.94,35.87 194.26,35.87 193.5,36.63 193.5,42.66 191.19,44.98 190.39,44.98 189.76,45.61 189.76,46.22 188.65,47.33 188.08,47.33 187.31,48.09 187.28,48.09 186.99,48.38 182.65,48.38 180.2,45.93 178.19,45.93 178.01,45.75 v2(177.49,45.75)
  BOTTOM w0.254: PU102.11 197.87,35.26 198.11,35.02 198.11,35.01 198.12,35.01 v2(198.27,35.01)
ENVDD: length 133.7
  TOP w0.102: v2(126.41,85.77) 125.8,85.17 v1(125.69,85.17) 121.43,85.17 121.12,85.48 119.39,85.48 119.34,85.43 117.75,85.43 117.46,85.72 115.57,85.72 RC59.1 114.83,85.03 RC690.1 113.67,84.8 UC64.4 ; v2(219.51,49) 220.61,47.9 RX7.2
  IN1 w0.127: v2(164.7,81.09) 165.37,80.41 165.37,75.54 169.63,71.28 169.63,70.14 169.63,69.14 173.31,65.46 175.79,62.98 175.79,62.84 177.47,61.16 177.49,61.16 178.05,60.6 178.05,59.29 180.06,57.27 180.59,57.27 180.81,57.05 180.81,57.04 181.41,56.44 181.41,56.22 186.07,51.56 188.13,51.56 189.95,49.74 191.77,49.74 193.65,47.86 197.67,47.86 198.06,48.25 200.96,48.25 205.03,44.18 206.97,44.18 207.69,44.32 207.79,44.37 209.14,44.37 212.48,47.71 214.81,47.71 218.26,47.71 219.51,48.96 v2(219.51,49)
  IN2 w0.127: v2(164.7,81.09) 164.49,81.3 152.08,81.3 151.04,82.34 133.39,82.34 132.37,83.36 130.2,83.36 127.79,85.77 v2(126.41,85.77)
ENVDD_R: length 27.5
  TOP w0.102: RPC45.6 113.31,86.44 113.5,86.25 114.38,86.25 114.62,86.01 RC59.2 114.5,85.62 113.37,85.62 112.99,85.24 UC64.2 v1(112.99,80.98) 112.99,79.27 113.94,78.31 v2(113.94,75.61)
  BOTTOM w0.102: v2(113.94,75.61) 113.94,75.56 113.84,75.46 113.25,75.46 112.34,74.54 112.34,65.61 112.53,65.42 112.53,65.24 112.78,64.99 112.78,64.68 112.7,64.6 112.7,64.33 113.01,64.01 UC1.B24
ENVDD_RE: length 11.8
  TOP w0.102: RX7.1 222.09,47.85 221.03,46.78 v1(220.47,46.78) ; RX7.1 222.35,47.64 225,47.64 225.13,47.77 225.89,47.77 226.17,48.05 226.17,48.87 226.51,49.22 228.85,49.22 229.03,49.04 U1.4 ; RX7.1 RX8.1
ERP_LOT6: length 92.7
  TOP w0.102: v2(162.98,88.69) 163.23,88.43 PR14.1 ; v2(184.09,39.87) 184.02,39.87 v1(183.66,39.52)
  IN1 w0.127: v2(184.09,39.87) 183.52,40.44 183.52,40.94 184.23,41.65 184.23,41.67 184.55,41.99 184.55,47.69 182.98,49.26 182.98,50.92 182.98,50.97 181.75,52.2 181.54,52.2 173.46,60.28 173.46,61.36 173.06,61.77 172.12,61.77 171.55,62.34 171.55,62.84 170.66,63.73 170.34,63.73 169.78,64.29 169.76,64.29 167.81,66.24 167.38,66.24 166.29,67.33 166.29,70.77 161.98,75.08 161.98,85.45 162.77,86.23 162.77,88.49 v2(162.98,88.69)
  BOTTOM w0.102: UE1.73 168.77,27.63 169.82,26.57 169.87,26.57 169.88,26.56 171.28,26.56 172.23,27.51 172.23,30.18 171.88,30.53 171.88,30.96 172.36,31.44 172.9,31.44 173.07,31.61 173.98,31.61 174.8,30.79 175.44,30.79 176.15,31.5 176.15,33.32 177.3,34.47 177.3,35.72 177.69,36.11 179.12,36.11 179.79,36.79 180.39,36.79 180.97,37.37 180.97,37.78 181.57,38.37 182.96,38.37 184.09,39.5 v2(184.09,39.87)
FAN_PWM: length 33
  TOP w0.102: v2(183.79,50.18) 183.64,50.03 183.64,48.68 183.98,48.34 183.98,43.69 182.52,42.23 182.52,39.13 184.17,37.48 184.17,33.69 182.52,32.04 182.52,29.42 182.87,29.06 182.87,29.06 183.11,28.82 183.12,28.82 183.31,28.63 183.31,28.63 183.42,28.52 v1(183.42,28.21) 183.42,27.58 v2(183.05,27.22)
  BOTTOM w0.102: UE1.26 182.66,26.82 v2(183.05,27.22) ; RF2.1 183.22,47.96 183.64,48.38 183.64,49.71 183.79,49.87 v2(183.79,50.18) 183.79,51.39 183.92,51.52 183.92,52.33 JFAN1.2
FAN_SPEED1: length 41
  TOP w0.102: 183.33,55.73 183.33,55.68 RF1.1 182.4,53.67 182.58,53.49 182.58,48.55 183.02,48.11 183.02,45.49 v1(182.96,45.43) v2(182.96,44.79)
  IN1 w0.127: v2(187.88,26.5) 187.88,31.3 187.13,32.05 187.1,32.05 186.48,32.66 186.48,33.58 186.2,33.86 186.2,33.87 186.08,34 186.08,38.5 186.2,38.63 186.2,43.33 185.69,43.83 185.69,44.62 v2(185.88,44.8)
  BOTTOM w0.102: UE1.28 183.25,26.02 184.36,27.13 186.01,27.13 186.08,27.2 187.18,27.2 v2(187.88,26.5) ; v2(182.96,44.79) 185.88,44.79 185.88,44.8 v2(185.88,44.8)
FB_1.2V: length 6.2
  BOTTOM w0.102: PR207.1 92.19,99.94 v1(92.22,99.9)
  BOTTOM w0.203: PU200.6 87.97,100.98 88.54,100.41 89.83,100.41 PC214.1
  BOTTOM w0.254: PR207.1 91.18,99.93 PC214.1 90.32,99.93 PR204.1
FB_1.8VALW: length 5.2
  BOTTOM w0.102: PC603.2 35.58,108.25 v1(35.48,108.35)
  BOTTOM w0.254: PR605.1 PR604.1 PC603.2 36.77,107.16 37,106.93 PU600.6
FB_+1.35VGPU: length 4.9
  BOTTOM w0.102: v1(155.85,82.76) 156.09,83 PC1409.2
  BOTTOM w0.254: PR1410.1 155.68,85.04 PU1400.14 ; PR1410.1 PC1409.2 ; PR1410.1 156.91,84.63 PR1411.1
FB_GND: length 2.4
  TOP w0.381: v2(106.42,115.81) 106.42,116.05 105.99,116.48 105.88,116.48 105.47,116.89 RV158.2
  BOTTOM w0.254: UV1.AD20 106.42,115.78 v2(106.42,115.81)
FB_VDDC: length 2.3
  TOP w0.381: v2(107.05,115.89) 107.05,116.35 RV159.2
  BOTTOM w0.254: v2(107.05,115.89) 107.05,115.85 107.6,115.3 UV1.AC20
FB_VDDCI: length 3.1
  BOTTOM w0.102: UV1.W1 110.9,100.23 110.4,99.73 110.4,99.09 T222.1
FB_VDDP_ALWP: length 3
  TOP w0.254: PR308.1 159.21,28.73 PR307.1 159.91,29.43 159.91,30.12 159.97,30.17 PU300.4
GATEA20: length 91.4
  TOP w0.102: v2(138.6,42.1) 138.68,42.18 RPC36.6 ; v1(181.25,38.05) 181.62,37.68 v2(181.63,37.68)
  IN1 w0.102: 122.89,38.88 122.89,39.58 121.18,41.29 121.18,43.91 119.77,45.32 119.39,45.32 118.65,46.06 117.57,46.06 117.19,46.44 113.94,46.44 113.43,45.93 110.7,45.93 109.81,45.04 109.43,45.04 109.18,44.79 v2(108.67,44.79)
  IN1 w0.127: 122.89,38.88 122.89,38.6 123.96,37.54 130.18,37.54 130.96,38.31 130.96,40.91 131.59,41.55 138.05,41.55 v2(138.6,42.1) 139.55,42.1 140.74,40.91 142.39,40.91 142.74,41.26 142.79,41.26 143.16,41.64 158.22,41.64 160.34,39.51 164.02,39.51 165.58,37.95 165.93,37.95 165.93,37.95 166.86,37.95 167.01,38.11 169.9,38.11 170.32,37.68 v2(181.63,37.68)
  BOTTOM w0.102: UC1.AU35 107.45,45.11 107.84,44.72 108.61,44.72 v2(108.67,44.79) ; v2(181.63,37.68) 182.02,37.29 182.54,37.29 182.65,37.19 182.65,36.98 182.5,36.82 UE1.1
GFX_PWRGD_APU: length 4.1
  BOTTOM w0.102: RC664.2 129.25,52.57 v1(128.29,52.57) 128.14,52.57 127.43,51.86 UC1.AD1
GPIO19_CTF: length 7.4
  BOTTOM w0.102: v1(114.37,96.33) 114.4,96.33 114.5,96.44 114.5,97.86 114.99,98.35 RV152.1 116.41,98.36 RV151.2 116.61,98.55 116.61,99.21 116.42,99.39 116.42,101.82 UV1.M2
GPIO28: length 5.7
  BOTTOM w0.102: UV1.R5 114.49,102.71 114.49,101.42 113.81,100.74 113.81,100.28 114,100.09 114,99.18 RV21.2
GPU_AC_LIGHT: length 3.4
  BOTTOM w0.102: RE51.2 164.45,26.29 v1(164.45,25.52) 164.53,25.43 164.81,25.43 165,25.63 UE1.68
GPU_VID1: length 58.6
  TOP w0.102: v2(75.08,93.93) 75.52,94.38 RV94.1 75.76,95.34 v1(75.59,95.52) ; RV76.1 86.25,94.42 v2(85.87,94.03)
  IN1 w0.127: v2(115.18,105.9) 114.62,105.34 114.62,104.48 116.1,103 116.1,99.8 115.57,99.27 115.36,99.27 113.49,99.27 113.05,99.71 111.78,99.71 110.76,100.73 102.13,100.73 94.06,92.66 88.25,92.66 87.25,93.67 86.24,93.67 v2(85.87,94.03)
  IN2 w0.127: v2(75.08,93.93) 75.08,93.43 76.98,91.52 80.03,91.52 81.49,92.98 84.82,92.98 v2(85.87,94.03)
  BOTTOM w0.102: UV1.P8 114.78,105.5 v2(115.18,105.9)
GPU_VID1_GPIO_20: length 5.5
  TOP w0.102: RV76.2 85.59,94.94 85.59,94.85 RV74.2 85.15,94.41 UV4.3 ; RV76.2 87.21,94.65 87.21,94.56 RV73.1 ; RV76.2 86.25,96.16 v1(85.75,96.67)
GPU_VID3: length 59
  TOP w0.102: RV93.1 74.94,93.49 v2(74.49,93.93) v1(74.49,94.56) ; RV103.1 87.55,92.52 87.78,92.75 87.78,93.74 87.52,94 86.76,94 v2(86.67,94.08)
  IN1 w0.127: v2(115.15,103.21) 115.46,103.21 115.84,102.82 115.84,99.9 115.46,99.52 113.75,99.52 113.3,99.97 111.91,99.97 110.89,100.98 101.94,100.98 93.87,92.92 88.35,92.92 87.19,94.08 v2(86.67,94.08)
  IN2 w0.127: v2(86.67,94.08) 85.12,92.54 81.68,92.54 80.41,91.27 76.86,91.27 74.49,93.63 v2(74.49,93.93)
  BOTTOM w0.102: UV1.N1 115.52,101.67 115.35,101.85 115.35,102.94 115.15,103.14 v2(115.15,103.21)
GPU_VID3_GPIO_15: length 5.6
  TOP w0.102: UV4.2 84.92,93.76 RV92.1 RV75.2 RV103.2 86.75,92.92 86.75,91.61 v1(86.58,91.44)
H_PROCHOT#: length 283.8
  TOP w0.102: 173.07,58.21 179.89,58.21 179.97,58.29 v2(180,58.29) ; 173.07,58.21 172.43,58.21 171.75,58.89 171.75,59.23 PR1021.2 ; 173.07,58.21 173.07,55.91 172.74,55.58 172.74,54.06 172.17,53.49 v2(172.17,52.09) ; PQ721.1 218.53,50.11 v2(218.46,50.18) ; v2(218.71,42.88) 218.14,43.45 PR777.1 ; PQ2.6 157.52,100.64 157.67,100.79 159.85,100.79 v2(160.1,100.54) 160.1,99.89 159.86,99.65 PQ3.1 ; v2(134.7,27.64) 134.23,27.17 134.23,22.84 135.21,21.86 136.67,21.86 137.41,22.6 138.36,22.6 142.4,18.56 156.99,18.56 157.02,18.59 158.41,18.59 v1(161.43,21.62) 163.6,23.79 163.6,25.41 163.51,25.5 163.51,28.45 162.96,29 162.96,31.58 162.62,31.92 162.62,36.4 164.36,38.14 164.36,39.01 164.74,39.39 169.16,39.39 171.55,41.78 173.04,41.78 173.44,42.18 173.44,42.69 173.14,42.99 v2(172.91,42.99) ; v2(118.51,44.15) 118.61,44.06 118.73,44.06 119.34,43.45 119.34,41.42 118.83,40.91 118.83,40.53 121.18,38.18 121.18,35.9 120.1,34.82 v2(120.1,33.74)
  TOP w0.203: PU1001.4 169.6,59.8 169.63,59.77 171.2,59.77 PR1021.2
  IN1 w0.102: v2(118.51,44.15) 117.24,42.88 114.19,42.88 112.67,44.4 v2(111.91,44.4)
  IN1 w0.127: v2(218.46,50.18) 218.07,50.57 216.73,50.57 214.38,48.22 212.11,48.22 208.77,44.87 207.69,44.87 207.54,44.81 206.92,44.69 205.27,44.69 202.41,47.55 202.38,47.55 201.15,48.79 197.84,48.79 197.42,48.37 193.9,48.37 192.02,50.25 190.24,50.25 188.42,52.06 186.31,52.06 181.92,56.45 181.92,56.65 181.32,57.25 181.32,57.27 180.81,57.78 180.74,57.78 180.74,57.78 180.51,57.78 v2(180,58.29) 179.15,59.14 179.15,59.36 178.56,59.96 178.56,60.81 177.71,61.66 177.68,61.66 176.3,63.05 176.3,63.19 174,65.48 170.14,69.35 170.14,71.49 165.88,75.75 165.88,92.09 163.41,94.57 163.41,95.27 161.12,97.55 160.59,97.55 160.26,97.88 160.26,100.39 v2(160.1,100.54) ; v2(134.7,27.64) 134.32,27.64 132.39,29.56 132.39,32.57 130.77,34.2 120.56,34.2 v2(120.1,33.74) ; v2(172.91,42.99) 173.18,43.26 173.18,44.91 173.57,45.29 173.57,50.69 v2(172.17,52.09)
  IN2 w0.102: v2(111.91,44.4) 111.91,44.79 111.27,45.42 111.27,46.88 110.95,47.2 109.24,47.2 108.54,47.9 108.54,50.44 108.41,50.56 108.41,50.88 108.48,50.95 108.48,55.33 109.62,56.47 109.62,59.2 109.24,59.58 109.24,65.99 108.67,66.57 v2(108.61,66.57)
  BOTTOM w0.102: RC661.2 120.67,34.06 120.35,33.74 v2(120.1,33.74) ; UC1.A31 109.16,66.39 108.99,66.57 v2(108.61,66.57) 109.08,67.04 109.08,67.36 108.68,67.76 108.68,70.48 RC159.2 ; RE42.2 171.5,42.99 v2(172.91,42.99) ; v2(218.71,42.88) 219.41,43.58 219.41,46.85 218.81,47.45 218.65,47.45 218.4,47.71 218.4,50.12 v2(218.46,50.18)
HDA_BITCLK: length 43.9
  TOP w0.097: v1(103.65,18.5) 102.94,19.21 RC706.2 RC13.2 102.21,20.59 v2(102.15,20.66)
  IN2 w0.122: v2(123.43,39.1) 123.11,39.1 120.82,36.81 118.32,36.81 118.09,37.04 116.86,37.04 115.59,35.77 115.59,35.76 115.59,33.26 115.62,33.23 115.62,32.47 115.15,31.99 115.15,31.04 115.15,31.04 115.15,27.58 114.57,27 111.79,27 109.45,24.66 108.2,24.66 106.78,23.24 106.47,23.24 106.47,23.24 105.82,23.24 104.56,21.98 104.14,21.98 103.81,21.98 102.5,20.66 102.42,20.66 102.42,20.66 v2(102.15,20.66)
  BOTTOM w0.097: RPC14.6 102.26,20.54 v2(102.15,20.66) 101.09,20.66 100.98,20.54 RPC13.7 ; UC1.AY6 122.91,43.01 122.6,42.69 122.6,42.42 122.68,42.34 122.68,41.7 122.64,41.67 122.64,41.48 122.48,41.32 122.48,40.7 122.68,40.5 122.68,40.07 123.43,39.32 v2(123.43,39.1)
HDA_BITCLK_AUDIO: length 101.4
  TOP w0.097: UA1.6 28.16,30.86 28.09,30.93 28.09,31.51 v2(28.21,31.64) 28.39,31.64 RA44.1
  BOTTOM w0.097: v2(28.21,31.64) 28.21,31.9 29.99,33.67 31.77,33.67 32.34,34.25 32.97,34.88 32.97,35.3 34.84,37.17 38.63,37.17 39.9,35.9 39.9,32.09 41.17,30.82 41.17,19.45 45.68,14.94 54.95,14.94 55.65,14.24 70.15,14.24 v1(72.71,11.68) 73.55,10.84 73.94,10.84 83.59,10.84 84.96,12.21 84.98,12.21 87.6,14.83 87.6,15.23 87.6,16.65 91.5,20.54 RPC13.2
HDA_RST: length 39.8
  TOP w0.097: v1(102.45,22.05) 102.13,21.74 v2(102.13,21.61)
  IN2 w0.102: 121.5,38.88 121.5,38.93 121.62,39.06 121.62,39.07 121.68,39.13 121.68,40.02 123.21,41.55 v2(124.16,41.55)
  IN2 w0.122: v2(102.13,21.61) 103.43,22.91 104.17,22.91 104.19,22.92 105.44,24.17 106.15,24.17 106.15,24.17 106.39,24.17 107.81,25.59 107.83,25.59 107.97,25.74 109.21,25.74 111.41,27.93 111.43,27.93 111.49,27.99 112.45,27.99 114.22,29.76 114.22,31.42 114.22,31.93 113.91,32.24 113.91,35.42 116.42,37.93 116.43,37.93 116.47,37.97 118.47,37.97 118.7,37.74 120.44,37.74 121.5,38.8 121.5,38.88
  BOTTOM w0.097: RPC14.8 102.19,21.54 v2(102.13,21.61) 101.94,21.8 100.91,21.8 RPC13.5
  BOTTOM w0.102: v2(124.16,41.55) 124.16,41.94 123.71,42.4 123.71,42.69 124.01,42.99 UC1.AY4
HDA_RST#_AUDIO: length 104.9
  TOP w0.097: v2(24.33,34.96) 24.06,34.96 23.29,34.18 RA14.1
  BOTTOM w0.097: RPC13.4 98.89,21.54 98.76,21.42 91.27,21.42 86.83,16.97 86.83,15.15 86.65,14.98 84.66,12.99 84.62,12.99 84.56,12.93 v1(76.47,12.93) 72.72,12.93 70.57,15.09 55.94,15.09 53.55,17.48 44.28,17.48 41.99,19.77 41.99,31.13 40.72,32.4 40.72,36.21 38.95,37.99 33.72,37.99 32.2,36.47 32.2,35.2 32.02,35.02 31.6,34.61 29.61,34.61 28.32,33.32 25.12,33.32 24.33,34.12 v2(24.33,34.96)
HDA_SDIN0: length 156.1
  TOP w0.097: RA43.2 v2(26.87,34.23) ; v2(123.91,38.31) 123.91,38.56 v1(124.16,38.82)
  IN2 w0.122: v2(105.34,20.78) 106.87,22.31 107.91,22.31 109.29,23.7 109.36,23.7 109.37,23.7 109.81,23.7 110.68,24.57 111.56,24.57 112.97,25.99 116.16,25.99 117.29,27.11 117.29,33.02 116.96,33.35 116.96,34.46 116.87,34.54 116.87,35.59 117.24,35.96 117.69,35.96 117.81,35.83 118.83,35.83 119.59,35.07 120.61,35.07 123.71,38.17 123.74,38.17 123.88,38.31 v2(123.91,38.31)
  BOTTOM w0.097: UC1.BA6 122.91,42.43 122.87,42.39 122.87,41.62 122.84,41.59 122.84,41.39 122.68,41.23 122.68,40.78 122.87,40.58 122.87,40.55 123.9,39.52 123.9,38.31 v2(123.91,38.31) 124.96,37.25 129.71,37.25 133.04,33.93 RC703.2 ; v2(105.34,20.78) 105.34,21.33 104.75,21.93 103.51,21.93 102.45,21.93 102.26,22.12 100.21,22.12 99.63,22.7 92.13,22.7 86.53,17.1 86.53,15.28 84.54,13.29 72.79,13.29 70.3,15.78 55.7,15.78 53.68,17.8 44.41,17.8 42.31,19.89 42.31,31.26 41.04,32.53 41.04,36.34 39.07,38.31 33.61,38.31 31.9,36.59 31.9,35.32 31.52,34.94 27.58,34.94 v2(26.87,34.23)
HDA_SDIN0_R: length 2.6
  TOP w0.097: UA1.8 27.36,30.72 27.26,30.82 27.26,32.25 RA43.1
HDA_SDIN1: length 15.6
  BOTTOM w0.097: RC695.2 132.96,34.87 130.12,37.7 128.07,37.7 v1(127.91,37.86) 126.51,39.26 124.46,39.26 124.03,39.69 124.03,39.71 122.87,40.86 122.87,41.15 123.03,41.31 123.03,41.5 123.07,41.54 123.07,42.25 123.21,42.39 123.21,42.66 UC1.AY5
HDA_SDIN2: length 13.8
  BOTTOM w0.097: RC696.2 132.75,35.78 v1(131.07,37.46) 130.53,38 128.28,38 126.51,39.77 124.26,39.77 123.75,40.28 123.75,41.23
  BOTTOM w0.102: UC1.BA5 123.46,41.52 123.75,41.23
HDA_SDOUT: length 43.4
  TOP w0.097: v1(101.56,19.39) 102,19.83 v2(102,19.89)
  IN2 w0.122: v2(124.42,40.33) 123.97,39.89 123.97,39.01 123.56,38.6 123.53,38.6 120.51,35.58 120.04,35.58 119.31,36.31 118.11,36.31 118.07,36.34 118.07,36.34 117.94,36.47 117,36.47 116.1,35.57 116.1,33.46 116.12,33.44 116.12,32.26 116.1,32.23 116.1,32.21 115.65,31.77 115.65,27.13 115.02,26.5 112.99,26.5 112.98,26.49 112.87,26.49 111.38,25 110.55,25 110.54,24.99 110.5,24.99 109.66,24.16 108.41,24.16 106.99,22.74 106.26,22.74 106.03,22.74 104.77,21.47 104.03,21.47 102.71,20.16 102.63,20.16 102.62,20.15 102.26,20.15 v2(102,19.89)
  BOTTOM w0.097: RPC13.8 100.89,19.81 101.91,19.81 v2(102,19.89) 102.15,20.04 RPC14.5
  BOTTOM w0.102: UC1.BA4 124.02,42.57 124.86,42.57 124.99,42.44 124.99,40.72 124.61,40.34 124.42,40.34 124.42,40.33 v2(124.42,40.33)
HDA_SDOUT_AUDIO: length 99.5
  TOP w0.097: UA1.5 28.56,30.59 28.7,30.73 28.71,30.73 28.84,30.86 28.89,30.86 29.13,31.1 29.13,31.15 29.17,31.19 v2(29.17,31.64)
  BOTTOM w0.097: v2(29.17,31.64) 29.17,32.15 30.21,33.2 31.97,33.2 32.54,33.77 33.45,34.68 33.45,35.1 35.01,36.66 38.44,36.66 39.39,35.71 39.39,31.9 40.66,30.63 40.66,19.26 45.49,14.43 54.76,14.43 55.46,13.73 69.93,13.73 v1(71.04,12.62) 73.3,10.37 74.14,10.37 74.14,10.37 83.79,10.37 85.16,11.73 85.18,11.74 88.08,14.63 88.08,15.43 88.08,16.45 91.67,20.04 RPC13.1
HDA_SYNC: length 41.3
  TOP w0.097: v2(101.43,21.35) v1(100.79,21.35)
  IN2 w0.122: v2(124.35,40.91) 123.81,40.91 123.61,40.71 123.52,40.71 123.41,40.59 123.4,40.59 123.34,40.53 123.31,40.53 122.07,39.29 122.07,38.77 120.61,37.31 118.52,37.31 118.3,37.54 116.65,37.54 115.09,35.98 115.09,35.96 114.34,35.21 114.34,33.63 114.7,33.26 114.87,33.26 115.12,33.02 115.12,32.67 114.64,32.2 114.64,31.96 114.64,28.09 114.11,27.56 111.67,27.56 111.61,27.5 111.58,27.5 109.24,25.16 107.99,25.16 106.57,23.74 105.97,23.74 105.62,23.74 104.35,22.48 103.6,22.48 102.29,21.16 101.62,21.16 v2(101.43,21.35)
  BOTTOM w0.097: RPC13.6 100.8,21.04 101.11,21.35 v2(101.43,21.35) 101.75,21.35 101.94,21.16 102.69,21.16 RPC14.7
  BOTTOM w0.102: v2(124.35,40.91) 124.42,40.91 124.61,41.11 UC1.BA3
HDA_SYNC_AUDIO: length 102.3
  TOP w0.097: v2(26.5,31.13) 26.5,30.82 26.56,30.76 UA1.10
  BOTTOM w0.097: v2(26.5,31.13) 26.69,31.13 29.87,34.31 30.99,34.31 31.73,34.31 32.15,34.72 32.5,35.08 32.5,36.35 33.82,37.67 38.82,37.67 40.41,36.09 40.41,32.28 41.68,31.01 41.68,19.64 45.87,15.45 55.14,15.45 55.84,14.75 70.31,14.75 70.56,14.51 73.74,11.32 v1(74.7,11.32) 83.4,11.32 84.76,12.69 84.79,12.69 85.14,13.04 85.14,13.04 86.78,14.68 87.13,15.03 87.13,16.85 91.32,21.04 RPC13.3
HDD_A0_PRE0: length 3.5
  BOTTOM w0.102: US2.9 v1(198.71,25.68) 199.71,25.68 RS24.1 RS27.2
HDD_A0_PRE1: length 3.4
  BOTTOM w0.102: US2.19 v1(192.17,26.68) 191.75,26.68 RS23.1 RS30.2
HDD_B0_EQ: length 4.2
  TOP w0.102: RS38.1 196.87,25.28 RS37.1 196.25,24.1 v1(195.84,23.68) v2(195.47,23.32)
  BOTTOM w0.102: v2(195.47,23.32) 195.47,23.39 195.35,23.51 US2.13
HDD_B0_PRE0: length 3.7
  BOTTOM w0.102: US2.8 199.21,26.18 RS21.1 RS28.2
HDD_B0_PRE1: length 3.9
  BOTTOM w0.102: RS18.1 RS29.2 v1(192.18,25.09) 192.76,25.68 US2.17
HDD_REXT_SATA0: length 5.6
  BOTTOM w0.102: v1(192.3,30.24) RS31.1
  BOTTOM w0.254: US2.20 192.62,27.18 192.44,27.35
  BOTTOM w0.508: 192.44,27.35 191.93,27.87 191.93,28.59 191.42,29.09 191.37,29.09 RS26.2 RS31.1
HDMI_DP1_TXN0: length 129.4
  TOP w0.102: v2(23.2,79.84) 23.2,79.81 23,79.62 22.86,79.62 CI7.2
  BOTTOM w0.102: v2(23.2,79.84) 23.2,79.82 23.04,79.66 22.89,79.66 22.79,79.76 22.79,83.2 23.06,83.47 23.06,86.65 24.1,87.69 24.1,87.92 24.1,89.52 25.39,90.81 30.35,90.81 31.91,92.37 49.83,92.37 51.35,93.9 57.68,93.9 58.86,92.72 72.96,92.72 73.32,92.35 78.94,92.35 79.4,91.89 79.57,91.89 80.89,91.89 86.4,86.38 93.57,86.38 93.78,86.16 102.37,86.16 102.98,85.55 106.48,85.55 107.07,84.96 108.35,84.96 108.37,84.93 108.94,84.93 108.96,84.96 109.8,84.96 110.47,84.28 112.73,84.28 v3(115.53,81.49) 116.89,80.13 116.89,73.97 117.41,73.45 117.41,66.63 118.37,65.67 118.37,64.77 118.21,64.6 118.21,64.33 118.57,63.97 118.57,63.82 UC1.B14
HDMI_DP1_TXN1: length 124.1
  TOP w0.102: v2(23.9,82.57) 23.65,82.32 22.93,82.32 22.91,82.35 22.34,82.35 22.32,82.32 21.75,82.32 21.5,82.58 CI5.2
  BOTTOM w0.102: UC1.B15 117.83,64.24 117.83,64.5 117.65,64.68 117.65,64.94 117.76,65.05 117.76,65.06 117.86,65.16 117.86,65.6 116.77,66.69 116.77,73 116.2,73.58 116.2,78.8 111.36,83.65 110.21,83.65 109.78,84.08 106.93,84.08 106.1,84.92 103.42,84.92 102.72,84.92 102.29,85.35 93.47,85.35 93.09,85.73 86.15,85.73 80.69,91.19 77.26,91.19 77.2,91.25 66.1,91.25 65.9,91.46 57.41,91.46 57.36,91.51 41.75,91.51 41.52,91.74 32.18,91.74 30.5,90.06 25.54,90.06 24.73,89.26 24.73,87.43 23.7,86.39 23.7,83.94 23.7,83.93 23.7,83.77 23.7,83.2 23.46,82.97 23.46,82.45 23.57,82.35 23.68,82.35 v2(23.9,82.57)
HDMI_DP1_TXN2: length 117.8
  TOP w0.102: CI3.2 21.81,87.97 22.05,87.97 22.19,88.11 23.14,88.11 23.17,88.13 23.73,88.13 23.76,88.11 25.83,88.11 25.93,88.21 v2(25.93,88.3)
  BOTTOM w0.102: UC1.B16 117.41,64.01 117.1,64.33 117.1,64.59 117.21,64.7 117.21,65.68 116.14,66.75 116.14,72.56 115.55,73.15 115.55,78.56 111.09,83.01 107.05,83.01 105.78,84.28 103.68,84.28 102.46,84.28 102.09,84.65 93.22,84.65 92.84,85.03 85.95,85.03 80.45,90.53 76.14,90.53 76.13,90.53 41.76,90.53 41.61,90.68 32.2,90.68 30.94,89.43 25.8,89.43 25.42,89.05 25.42,88.32 25.63,88.11 25.83,88.11 25.93,88.21 v2(25.93,88.3)
HDMI_DP1_TXN3: length 116
  TOP w0.102: CI1.2 22.58,85.48 22.77,85.29 23.27,85.29 23.3,85.31 23.86,85.31 23.89,85.29 24.6,85.29 24.81,85.49 v2(24.81,85.52)
  BOTTOM w0.102: UC1.B17 116.86,64.38 116.56,64.68 116.56,64.94 116.64,65.02 116.64,65.03 116.71,65.1 116.71,65.61 115.5,66.81 115.5,72.24 114.73,73.02 114.73,78.48 110.9,82.31 106.86,82.31 106.79,82.38 106.78,82.38 105.51,83.65 103.94,83.65 102.19,83.65 101.83,84.02 92.84,84.02 92.52,84.33 85.75,84.33 80.23,89.86 41.53,89.86 41.34,90.05 32.52,90.05 29.28,86.81 25.23,86.81 24.33,85.91 24.33,85.46 24.43,85.36 24.65,85.36 v2(24.81,85.52)
HDMI_DP1_TXP0: length 129.5
  TOP w0.102: v2(23.2,79.25) 23.04,79.42 22.85,79.42 CI8.2
  BOTTOM w0.102: UC1.A14 118.51,64.62 118.57,64.68 118.57,65.75 117.61,66.72 117.61,73.53 117.09,74.05 117.09,80.21 115.89,81.41 115.89,81.45 115.49,81.85 115.45,81.85 112.82,84.49 110.56,84.49 109.88,85.16 v3(108.66,85.16) 107.16,85.16 106.56,85.76 103.07,85.76 102.46,86.37 96.8,86.37 96.8,86.36 96.27,86.36 96.27,86.37 96.1,86.37 96.1,86.36 95.58,86.36 95.58,86.37 95.4,86.37 95.4,86.36 93.87,86.36 93.65,86.58 86.48,86.58 80.97,92.09 80.8,92.09 80.8,92.09 79.48,92.09 79.02,92.56 73.41,92.56 73.05,92.92 58.95,92.92 57.77,94.1 51.27,94.1 49.75,92.58 31.83,92.58 30.27,91.01 25.3,91.01 23.9,89.61 23.9,88 23.9,88 23.9,87.78 22.86,86.74 22.86,83.55 22.59,83.28 22.59,79.68 22.81,79.46 22.99,79.46 v2(23.2,79.25)
HDMI_DP1_TXP1: length 124.1
  TOP w0.102: CI6.2 21.91,82.12 v3(22.63,82.12) 23.71,82.12 v2(23.9,81.93)
  BOTTOM w0.102: UC1.A15 117.96,64.97 118.07,65.08 118.07,65.69 116.97,66.78 116.97,73.09 116.4,73.66 116.4,78.89 111.44,83.85 110.29,83.85 109.86,84.28 107.02,84.28 106.18,85.12 103.33,85.12 103.33,85.12 102.8,85.12 102.37,85.55 93.56,85.55 93.17,85.93 86.23,85.93 80.77,91.39 77.35,91.39 77.28,91.46 66.19,91.46 65.98,91.66 57.5,91.66 57.45,91.71 41.84,91.71 41.61,91.94 32.09,91.94 30.42,90.26 25.45,90.26 24.53,89.34 24.53,87.51 23.49,86.47 23.49,83.29 23.26,83.06 23.26,82.37 23.48,82.15 23.68,82.15 v2(23.9,81.93)
HDMI_DP1_TXP2: length 117.8
  TOP w0.102: CI4.2 21.86,87.76 22.13,87.76 22.27,87.9 v3(23.45,87.9) 25.74,87.9 v2(25.93,87.71)
  BOTTOM w0.102: v2(25.93,87.71) 25.74,87.9 25.55,87.9 25.22,88.23 25.22,89.13 25.72,89.63 30.86,89.63 32.12,90.89 41.69,90.89 41.84,90.73 58.95,90.73 58.95,90.73 80.38,90.73 80.54,90.73 86.03,85.24 92.92,85.24 93.3,84.85 102.17,84.85 102.54,84.49 103.59,84.49 105.86,84.49 107.13,83.22 111.18,83.22 115.75,78.64 115.75,73.23 116.34,72.64 116.34,66.84 117.41,65.77 UC1.A16
HDMI_DP1_TXP3: length 116
  TOP w0.102: v2(24.82,84.93) 24.82,84.93 24.71,85.04 24.7,85.04 24.66,85.08 v3(23.58,85.08) 22.96,85.08 CI2.2
  BOTTOM w0.102: UC1.A17 116.91,64.86 116.91,65.69 115.7,66.9 115.7,72.33 114.93,73.1 114.93,78.56 110.98,82.51 106.94,82.51 106.88,82.58 106.87,82.58 105.6,83.85 103.86,83.85 102.28,83.85 101.91,84.22 92.92,84.22 92.6,84.54 85.83,84.54 80.31,90.06 80.15,90.06 80.15,90.06 41.62,90.06 41.43,90.25 32.44,90.25 29.2,87.01 25.15,87.01 24.13,85.99 24.13,85.38 24.35,85.16 24.6,85.16 v2(24.82,84.93)
HDMI_HPLUG: length 31.7
  TOP w0.102: JHDMI1.19 11.55,92.6 13.74,92.6 14.43,93.3 14.43,95.06 16.62,97.25 17.03,97.25 17.28,97.5 23.27,97.5 23.9,98.13 v1(25.04,98.13) 29.42,98.13 32.15,95.4 32.15,92.91 RI16.1 CI10.1 RI18.2
HPOUT-L: length 13.7
  TOP w0.203: UA1.32 v1(28.56,22.94) v2(28.56,22.24)
  TOP w0.305: RA27.1 23.9,14.5 v2(24.28,14.88)
  IN2 w0.305: v2(28.56,22.24) 28.28,22.24 27.58,21.54 27.58,19.35 26.9,18.67 25.06,18.67 23.58,17.19 23.58,15.77 24.28,15.07 v2(24.28,14.88)
HPOUT-R: length 12.9
  TOP w0.102: v1(23.45,15.58) 23.71,15.58 24.21,16.08 v2(24.21,16.21)
  TOP w0.203: v2(28.54,21.64) 28.63,21.64 29.02,22.03 29.02,22.43 28.96,22.49 UA1.33
  TOP w0.305: v2(24.21,16.21) 23.9,16.53 RA31.1
  IN2 w0.305: v2(28.54,21.64) 28.15,21.25 28.15,19.13 27.13,18.12 25.29,18.12 24.21,17.04 v2(24.21,16.21)
HVB_FUNCTION: length 26.3
  TOP w0.102: v2(110.36,30.83) 110.68,30.51 v1(110.68,29.1) 110.68,24.94 RC49.2
  IN2 w0.102: v2(110.83,46.4) 110.66,46.4 110.26,46 109.89,45.99 109.62,45.99 109.33,45.7 109.33,44.75 108.99,44.4 108.56,44.4 108.39,44.24 108.39,43.41 109.86,41.94 109.86,41.02 109.39,40.56 109.39,38.88
  IN2 w0.127: v2(110.36,30.83) 109.79,31.4 109.79,33.57 109.05,34.31 109.05,37.38 109.39,37.72 109.39,38.88
  BOTTOM w0.102: UC1.AP27 111.14,46.71 v2(110.83,46.4)
I2C_CLK_TP: length 79.4
  IN1 w0.127: v2(108.9,21.23) 106.21,23.92 106.21,24.83 v2(106.13,24.91)
  IN2 w0.102: 113.62,38.88 113.19,39.31 112.86,39.31 112.61,39.57 112.61,46.82 113.81,48.02 113.81,48.09 114.19,48.47 116.16,48.47 116.35,48.28 116.35,46.69 116.73,46.31 120.1,46.31 120.8,47.01 120.8,48.66 121.31,49.17 121.31,49.74 121.05,49.99 121.05,50.99 121.26,51.2 122.83,51.2 v2(123.55,51.92)
  IN2 w0.127: v2(106.13,24.91) 106.44,24.91 107.75,26.21 109.08,26.21 110.26,27.39 110.26,28.29 110.38,28.42 111.99,28.42 113.79,30.22 113.79,31.6 113.56,31.83 113.56,31.84 113.48,31.92 113.48,36.71 113.72,36.95 113.85,36.95 114.35,37.45 114.35,38.15 113.85,38.65 113.85,38.65 113.62,38.88
  BOTTOM w0.1: UC1.AC5 v2(123.55,51.92)
  BOTTOM w0.102: JTP1.6 99.9,10.18 99.46,10.62 99.46,11.45 99.8,11.79 107.06,11.79 107.3,11.55 108.14,10.71 108.38,10.47 110.23,10.47 110.89,11.13 110.89,11.7 111.21,12.02 111.21,15.16 108.38,17.99 108.38,20.11 108.9,20.63 v2(108.9,21.23) ; v2(106.13,24.91) 106.13,24.6 105.8,24.27 RP20.2
I2C_DAT_TP: length 82
  IN1 w0.127: v2(106.45,25.55) 106.14,25.55 105.51,24.93 105.51,23.87 108.42,20.96 v2(108.42,20.75)
  IN2 w0.102: v2(123.46,52.98) 123.46,52.37 123.17,52.08 123.17,51.83 122.8,51.46 121.24,51.46 120.73,50.96 120.73,49.99 121.05,49.68 121.05,49.29 120.54,48.79 120.54,47.26 119.84,46.56 116.8,46.56 116.61,46.75 116.61,48.41 116.29,48.72 114.13,48.72 113.56,48.15 113.56,48.09 112.35,46.88 112.35,46.75 112.4,46.7 112.4,39.48 113.01,38.88
  IN2 w0.127: 113.01,38.88 113.01,38.8 113.2,38.6 113.22,38.6 113.47,38.36 113.47,38.33 113.58,38.22 113.67,38.22 113.91,37.97 113.91,37.63 113.67,37.38 113.54,37.38 113.05,36.89 113.05,36.53 113.05,31.74 113.13,31.66 113.13,31.65 113.36,31.42 113.36,30.4 111.81,28.85 109.95,28.85 109.82,28.72 109.82,27.57 108.9,26.65 107.57,26.65 106.48,25.55 v2(106.45,25.55)
  BOTTOM w0.1: UC1.AC4 123.86,52.58 v2(123.46,52.98)
  BOTTOM w0.102: v2(106.45,25.55) 106.7,25.3 106.7,24.59 105.88,23.77 RP20.3 ; v2(108.42,20.75) 107.97,20.3 107.97,17.82 110.76,15.03 110.76,12.21 110.45,11.89 110.45,11.32 110,10.88 108.55,10.88 107.7,11.72 107.47,11.96 107.23,12.2 99.64,12.2 99.05,11.62 99.05,10.53 98.9,10.38 JTP1.7
ILMT_+1.35VGPU: length 4.9
  TOP w0.102: v2(156.4,85.46) v1(157.23,85.46)
  BOTTOM w0.254: PU1400.13 156.13,85.73 v2(156.4,85.46) 156.69,85.17 157.34,85.17 157.96,84.55 PR1407.1 PR1406.2
IMON_APU: length 3.3
  TOP w0.203: PU1001.10 169.2,62.2 169.4,62.41 v2(169.4,62.86)
  BOTTOM w0.102: v2(169.4,62.86) 169.4,62.98 169.25,63.14 v1(169.25,63.39)
  BOTTOM w0.254: PR1076.2 PC1062.2 169.64,62.62 v2(169.4,62.86)
IMON_NB: length 4.2
  TOP w0.102: v1(171.09,58.69) 171,58.6 v2(170.28,58.6)
  TOP w0.203: PU1001.2 169.46,59 169.53,58.93 169.95,58.93 v2(170.28,58.6)
  BOTTOM w0.254: v2(170.28,58.6) 169.86,58.18 PC1018.2 PR1018.2
IMON_VGA: length 3.4
  TOP w0.203: PU1100.10 50.68,121.44 v1(50.04,120.8) 49.43,120.8 PC1117.2
  TOP w0.254: PR1117.2 PC1117.2
INT-SPK-L+:
  vias: v1(32.85,27.13)
INT-SPK-L-:
  vias: v1(34.12,27.83)
INT-SPK-R+:
  vias: v1(32.66,29.1)
INT-SPK-R-:
  vias: v1(34.37,29.29)
INVTPWM: length 157.1
  TOP w0.102: UC65.4 116.97,82.55 116.77,82.35 v2(116.54,82.35) 116.26,82.35 RC691.1 115.79,83.15 115.84,83.2 RC58.1 ; v2(164.73,81.67) v1(165.63,82.57)
  IN1 w0.127: v2(129.05,85.18) 128.54,84.66 124.8,84.66 123.27,83.14 117.33,83.14 v2(116.54,82.35) ; v2(164.73,81.67) 164.73,81.65 165.63,80.75 165.63,75.64 169.88,71.39 169.88,69.24 173.41,65.71 173.75,65.38 173.75,65.38 176.04,63.08 176.04,62.94 177.58,61.41 177.6,61.41 178.3,60.71 178.3,59.39 180.17,57.53 180.7,57.53 181.07,57.16 181.07,57.14 181.67,56.54 181.67,56.34 186.2,51.81 188.26,51.81 190.08,49.99 191.9,49.99 193.78,48.11 197.56,48.11 197.96,48.51 201.07,48.51 202.13,47.44 205.14,44.43 206.94,44.43 207.61,44.57 207.74,44.62 209,44.62 212.34,47.96 214.66,47.96 216.29,49.59 218.06,49.59 218.26,49.4 219.07,49.4 219.59,49.92 221.06,49.92 221.44,49.53 221.44,42.89 221.2,42.64 221.2,38.19 220.36,37.35 220.36,36.75 219.86,36.25 v2(218.76,36.25)
  IN2 w0.127: v2(129.05,85.18) 129.05,85.11 130.48,83.68 139.7,83.68 140.54,82.84 140.54,82.84 140.73,82.65 151.08,82.65 152.18,81.55 164.61,81.55 v2(164.73,81.67)
  BOTTOM w0.102: v2(218.76,36.25) 219.35,36.25 220.45,37.36 221.41,37.36 221.71,37.66 RP3.1 222.08,37.86 223.27,39.05 JEDP1.23
INVTPWM_R: length 25.6
  TOP w0.102: v2(113.94,75.02) 113.96,75.05 114.11,75.05 114.35,75.29 114.35,77.89 v1(115.27,78.82) 117.62,81.17 UC65.2 117.62,85.22 117.52,85.32 116.36,85.32 RC58.2
  BOTTOM w0.102: UC1.A24 112.99,64.48 112.99,65.13 112.73,65.39 112.73,65.5 112.57,65.67 112.57,74.45 113.07,74.95 113.86,74.95 v2(113.94,75.02)
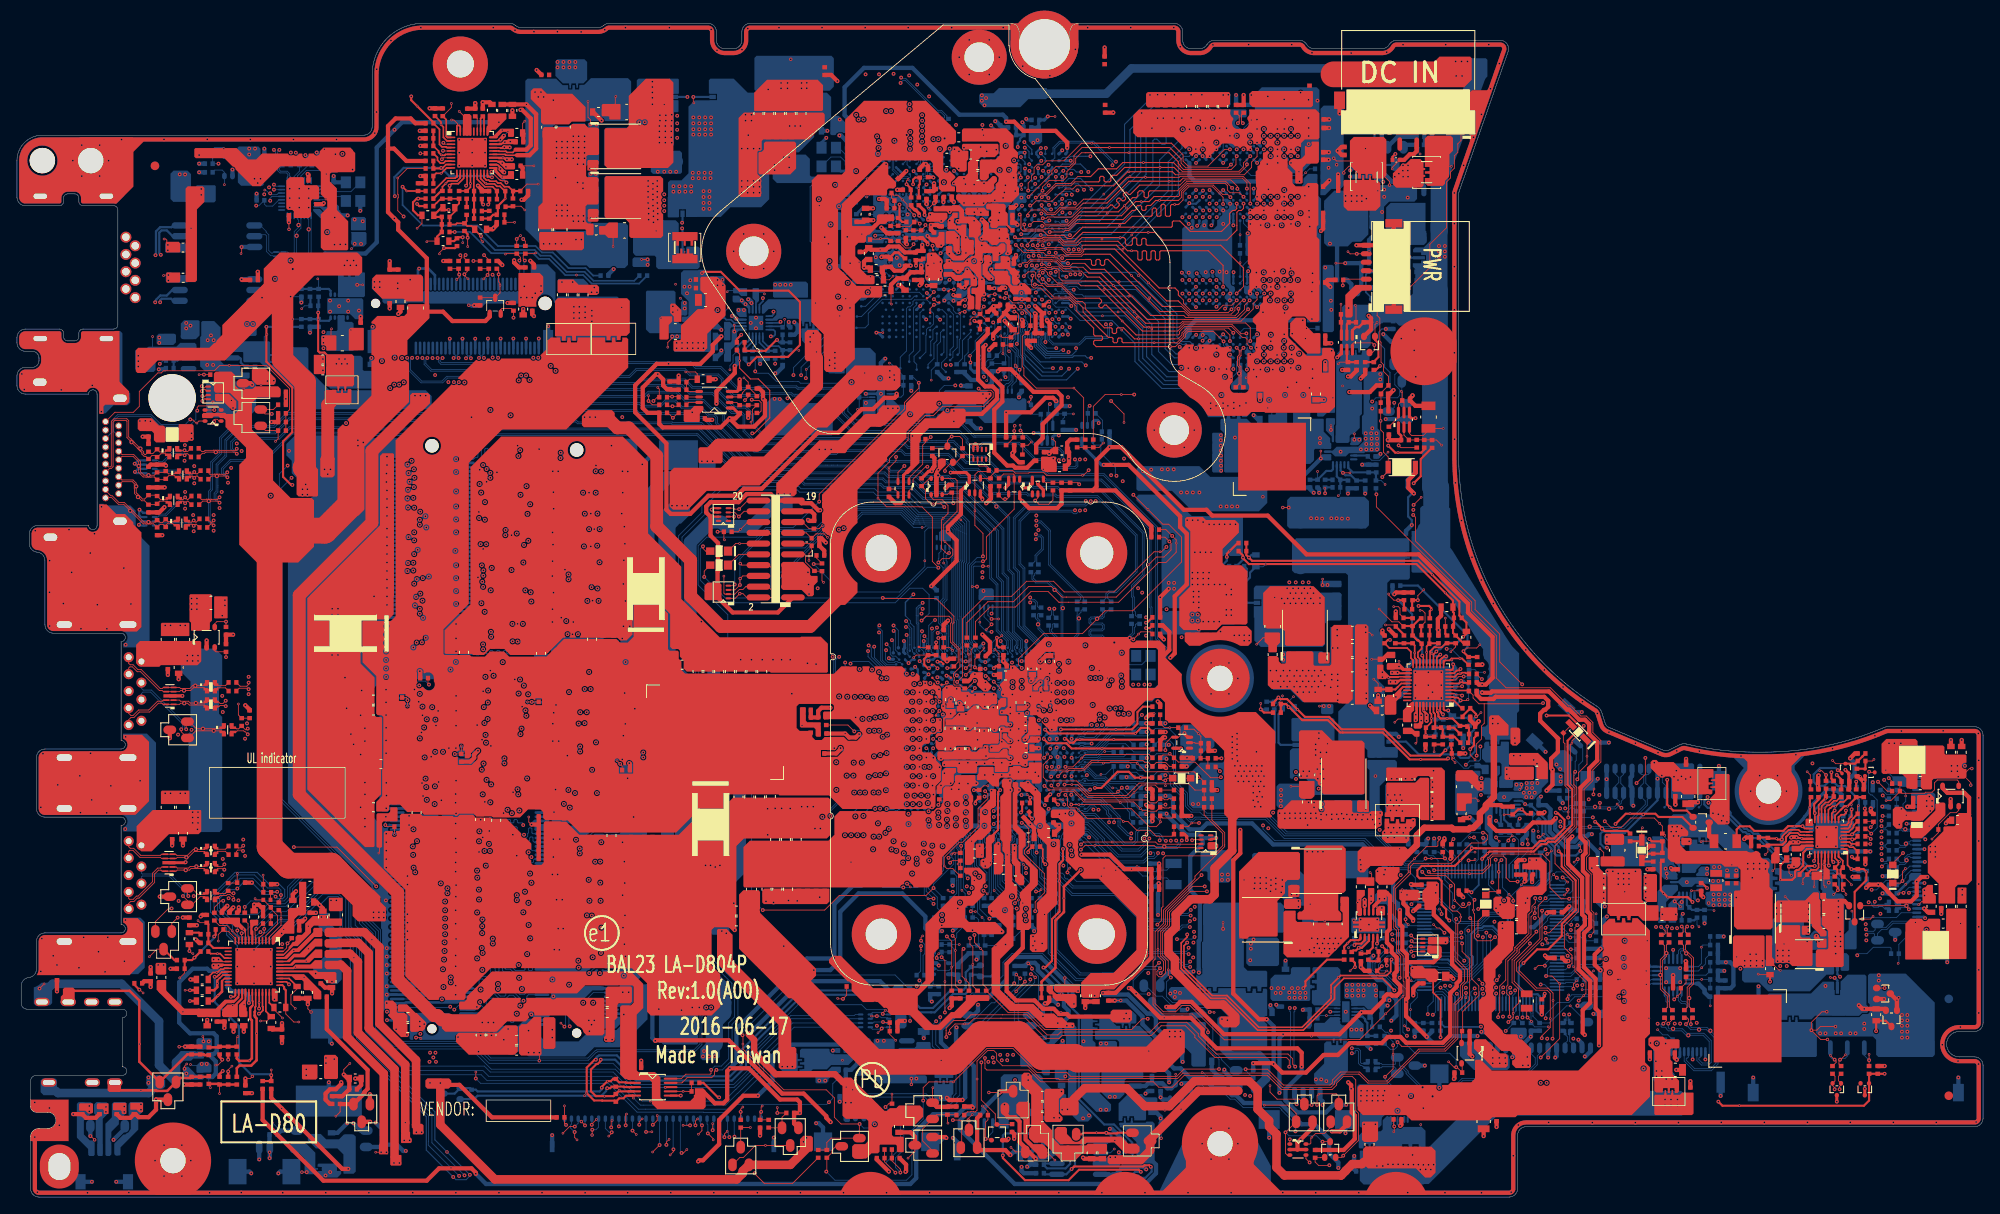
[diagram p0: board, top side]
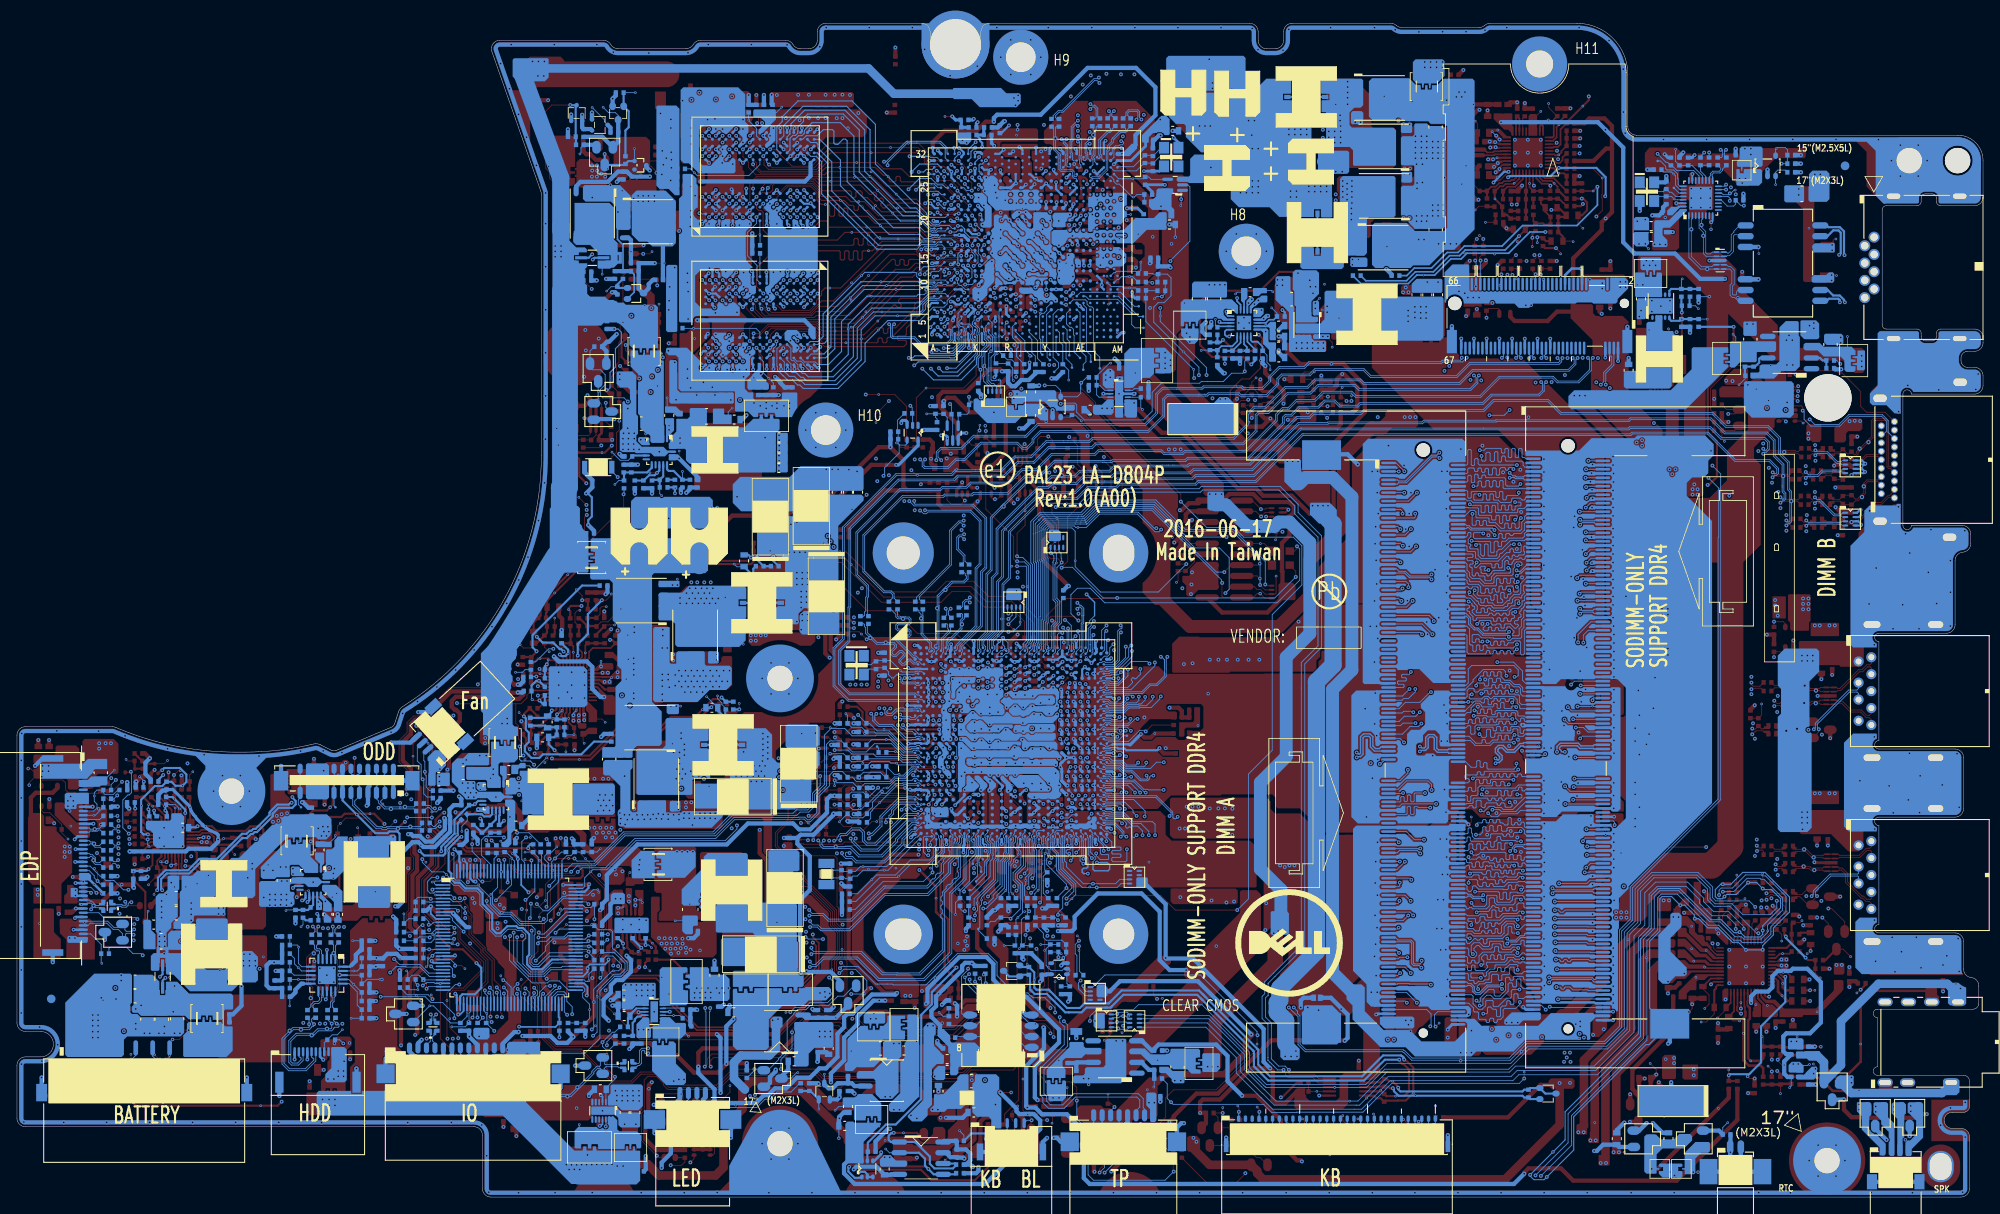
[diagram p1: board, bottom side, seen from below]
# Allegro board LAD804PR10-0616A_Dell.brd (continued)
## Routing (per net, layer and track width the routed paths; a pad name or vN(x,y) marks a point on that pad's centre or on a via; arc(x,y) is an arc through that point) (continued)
IR_GND: length 3.1
  BOTTOM w0.305: R7.1 v1(222.78,36.91) 223.43,37.55 JEDP1.26
ISEN1_VGA: length 13.4
  TOP w0.102: v1(49.83,111.3) 49.83,111.43 v2(50.37,111.97)
  TOP w0.203: PC1120.2 51.03,118.76 v2(51.03,119.34) 51.26,119.57 52.05,119.57 52.69,120.21 PU1100.13
  TOP w0.254: v2(50.37,111.97) 51.66,111.97 PR1124.1
  IN2 w0.254: v2(50.37,111.97) 50.37,118.68 v2(51.03,119.34)
ISEN2_VGA: length 5
  TOP w0.203: PU1100.12 52.29,120.28 51.91,119.9 50.87,119.9 v1(50.59,119.62) 50.18,119.21 PC1119.2
  TOP w0.254: PC1119.2 50.02,118.72 49.12,117.82 PR1104.1
ISOLATEB: length 5.9
  BOTTOM w0.102: UL1.20 33.09,120.5 34.33,121.74 RL3.2 RL4.1 36.27,122.2 v1(36.27,123.64)
JACK_PLUG_DET: length 7.2
  TOP w0.102: v1(14.88,24.08) 14.5,24.47 v2(14.43,24.47)
  TOP w0.254: v2(14.43,24.47) 13.85,25.05 RA40.1
  IN2 w0.254: v2(14.43,24.47) 9.67,24.47 9.1,23.89
JACK_SENSE#: length 13.3
  TOP w0.102: v2(20.34,29.04) 20.65,28.72 v1(20.75,28.72)
  TOP w0.254: RA42.2 v2(20.34,29.04)
  IN2 w0.254: 12.4,23.58 12.59,23.77 18.05,23.77 19.83,25.55 19.83,28.53 v2(20.34,29.04)
JACK_SENSE_1#: length 1.4
  TOP w0.254: RA41.2 21.47,31.2 RA42.1
JHDD_P10: length 3.8
  BOTTOM w0.102: v1(193.52,19.74) 194.11,19.14 194.71,19.14 RS8.2 195.65,18.21 JHDD1.8
JTAG_TCK: length 8.1
  BOTTOM w0.102: RPV34.6 116.36,95.65 116.7,95.99 116.95,95.99 117.27,96.31 117.27,96.93 117.28,96.93 117.28,97.39 117.27,98.91 117.27,99.55 v4(117.01,99.81) 116.83,99.99 116.83,101.49 117.3,101.96 UV1.L3
JTAG_TDI_GPU: length 9
  BOTTOM w0.102: RPV34.8 117.36,95.75 117.88,96.27 v1(117.88,96.91) 117.88,97.78 118.07,97.97 118.07,99.09 117.95,99.21 117.95,99.83 117.24,100.54 117.24,100.98 117.6,101.35 117.6,101.68 117.59,101.69 117.59,102.11 117.6,102.12 117.67,102.18 117.67,102.45 117.61,102.5 117.61,102.79 UV1.L5
JTAG_TDO_GPU: length 8.2
  TOP w0.102: v2(118.26,97.62) v4(117.81,98.06)
  BOTTOM w0.102: UV1.K4 117.87,102.47 117.87,102.1 117.79,102.03 117.79,101.77 117.81,101.76 117.81,101.23 117.53,100.95 117.53,100.54 118.15,99.92 118.15,99.29 118.51,98.93 118.51,97.87 v2(118.26,97.62) 118.26,96.3 RV369.1
JTAG_TMS_GPU: length 7.2
  BOTTOM w0.102: UV1.L1 117.03,101.23 117.03,100.33 117.74,99.63 v1(117.74,98.19) 117.74,97.92 117.48,97.67 117.48,96.2 116.86,95.58 RPV34.7
JTAG_TRSTB: length 10.4
  BOTTOM w0.102: RPV34.5 115.86,96.31 115.96,96.41 v1(116.03,96.41) 116.37,96.41 116.44,96.33 116.91,96.33 117.01,96.44 117.01,99.09 116.63,99.47 116.63,101.58 116.87,101.82 116.87,103.15 117.3,103.58 UV1.L6
KB_BL_PWM: length 3
  TOP w0.102: v1(112.67,9.73) 112.22,9.29 v2(112.22,9.06) 112.29,9 Q8.1
  BOTTOM w0.102: JKBBL1.4 112.77,9.06 112.22,9.06 v2(112.22,9.06)
KB_DET: length 7.2
  TOP w0.102: QE4.2 114.8,6.85 v2(114.26,6.85) 114.26,6.86 114.26,8.84 114.52,9.11 RE58.1 114.52,10.1 v1(113.88,10.75)
  BOTTOM w0.102: JKBBL1.2 115.1,7.69 v2(114.26,6.85)
KB_DET#: length 38.5
  TOP w0.102: RE68.1 117.33,8.56 QE4.1 115.4,8.75 115.4,9.8 113.75,11.45 v2(113.75,15.89)
  IN1 w0.127: v2(111.24,34.75) 111.24,34.55 111.97,33.82 111.97,30.24 111.15,29.42 111.15,26.18 111.72,25.61 111.72,22.62 113.74,20.6 113.74,15.91 v2(113.75,15.89)
  BOTTOM w0.102: UC1.BA28 110.85,42.52 110.85,42 110.86,42 110.86,41.76 110.78,41.68 110.78,41.19 111.01,40.96 v1(111.01,39.3) 111.08,39.22 111.08,34.91 v2(111.24,34.75)
KB_LED_PWM: length 96.6
  TOP w0.102: v2(180.36,26.08) 181.05,26.08 v1(181.97,25.17) 181.97,18.7 v2(179.73,16.47) ; v2(110.39,9.08) 111.21,9.08 111.43,8.85 111.43,5.94 Q8.2
  IN2 w0.127: v2(110.39,9.08) 110.39,9.93 111.15,10.69 111.91,10.69 114,12.78 120.65,12.78 121.22,13.35 123.72,13.35 124.86,14.5 131.47,14.5 132.42,15.45 136.8,15.45 137.05,15.19 138.77,15.19 139.66,14.31 149.43,14.31 149.82,14.69 154.52,14.69 155.4,13.8 155.4,12.75 156.43,11.72 157.09,11.72 158.79,10.02 161.63,10.02 162.86,11.25 165.43,11.25 168.61,14.43 170.91,14.43 171.41,14.93 175.46,14.93 177.12,16.59 177.19,16.59 177.38,16.78 179.42,16.78 v2(179.73,16.47)
  BOTTOM w0.102: UE1.25 180.81,27.22 180.54,26.95 180.54,26.26 v2(180.36,26.08)
KB_RST#: length 112.5
  TOP w0.102: v1(182.52,35.64) 182.9,36.02 v2(182.9,36.28)
  IN1 w0.102: 121.75,38.88 121.75,39.64 121.11,40.28 120.1,40.28 119.84,40.53 119.84,40.79 119.53,41.1 118.64,41.1 117.69,42.06 112.56,42.06 112.11,41.61 112.11,40.93 110.07,38.88
  IN1 w0.127: v2(109.11,33.29) 109.16,33.34 109.16,37.98 110.07,38.88 ; v2(182.9,36.28) 182.65,36.02 173.42,36.02 172.57,36.87 170.4,36.87 169.98,36.87 169.56,37.29 167.35,37.29 167.13,37.07 165.24,37.07 163.62,38.7 162.63,38.7 162.33,38.39 162.33,35.62 162.14,35.43 162.14,35.42 162.14,35.21 162.14,35.21 162.14,33.55 160.87,32.28 160.08,32.28 159.98,32.28 159.66,32.59 159.28,32.59 159.02,32.34 159.02,31.43 158.19,30.6 157.83,30.6 155.09,27.86 150.26,27.86 149.75,28.36 143.16,28.36 140.15,31.37 140.15,34.58 138.96,35.77 134.85,35.77 133.89,36.73 123.61,36.73 122.32,38.02 122.32,38.03 121.75,38.6 121.75,38.88
  BOTTOM w0.102: RC50.2 108.53,33.29 v2(109.11,33.29) 109.11,33.55 108.55,34.1 108.55,35.39 107.47,36.47 107.47,36.76 109.28,38.57 109.28,40.51 109.78,41 109.78,41.72 109.74,41.76 109.74,41.76 109.71,41.79 UC1.BA30 ; UE1.2 182.75,36.42 v2(182.9,36.28)
KSI0: length 115.7
  TOP w0.102: v1(170.9,23.51) 170.91,23.53 v2(170.91,24.08)
  IN1 w0.127: v2(71,8.35) 72.07,9.42 72.8,9.42 72.99,9.23 76.68,9.23 77.02,8.89 79.58,8.89 79.92,9.23 84.32,9.23 84.48,9.07 85.6,9.07 85.73,8.95 91.99,8.95 93.87,7.07 94.38,7.07 106.53,7.07 107.42,6.18 114.33,6.18 114.54,6.18 115.94,7.57 119.7,7.57 120.27,7 120.29,7 121.56,7 121.56,7 121.69,7 121.69,7 125.66,7 125.66,7 125.81,7 128.1,9.29 129.43,9.29 130.26,10.11 136.21,10.11 138.94,12.84 141.04,12.84 141.04,12.85 143.53,12.85 144.16,13.48 151.66,13.48 152.89,14.71 155.06,14.71 155.53,14.25 155.56,14.25 159.47,14.25 159.9,14.25 160.42,14.77 160.79,14.77 160.93,14.91 166.13,14.91 168.49,17.27 168.49,18.14 168.49,18.35 168.49,18.35 168.49,18.98 168.48,20.25 168.87,20.63 168.87,21.72 170.91,23.77 v2(170.91,24.08)
  BOTTOM w0.102: v2(170.91,24.08) 170.91,23.89 171.22,23.58 UE1.55 ; JKB1.22 v2(71,8.35)
KSI1: length 119.1
  TOP w0.102: v1(69.81,7.19) 70.15,7.54 v2(70.15,7.64)
  IN1 w0.127: v2(70.15,7.64) 70.56,8.05 70.56,8.5 71.73,9.67 72.91,9.67 73.1,9.48 76.79,9.48 77.12,9.14 79.47,9.14 79.81,9.48 84.45,9.48 84.6,9.33 85.7,9.33 85.83,9.2 91.89,9.2 92.1,9.2 93.98,7.32 94.28,7.32 94.28,7.32 95.12,7.32 106.63,7.32 107.52,6.43 114.44,6.43 115.83,7.83 119.8,7.83 120.38,7.26 120.4,7.26 121.45,7.26 121.45,7.26 122.77,7.26 125.56,7.26 128.16,9.86 128.62,9.86 129.19,10.43 136.16,10.43 138.83,13.1 138.98,13.1 138.98,13.1 140.93,13.1 140.93,13.1 143.42,13.1 144.06,13.73 151.55,13.73 153.49,15.67 155.63,15.67 156.8,14.5 159.58,14.5 159.79,14.5 160.31,15.02 160.68,15.02 160.88,15.21 164.39,15.21 167.48,18.31 167.48,19.61 168.61,20.74 168.61,21.91 170.48,23.78 170.48,24.28 v2(170.9,24.7)
  BOTTOM w0.102: JKB1.24 69.4,8.1 69.86,7.64 v2(70.15,7.64) ; v2(170.9,24.7) 170.49,24.29 170.49,23.93 170.82,23.6 UE1.56
KSI2: length 120.1
  TOP w0.102: v1(68.35,9.16) 67.8,8.62 v2(67.8,8.53)
  IN1 w0.127: v2(169.03,24.91) 169.03,23.55 168.1,22.62 168.1,20.95 166.98,19.82 166.98,19.4 166.98,19.4 166.98,18.52 164.18,15.72 160.67,15.72 160.47,15.53 160.1,15.53 159.63,15.06 159.21,15.06 159.21,15.06 156.96,15.06 155.84,16.18 153.28,16.18 151.34,14.24 143.85,14.24 143.21,13.61 140.72,13.61 140.72,13.61 139.19,13.61 139.19,13.61 138.58,13.61 135.97,11 127.2,11 126.89,10.69 126.89,10.68 126.81,10.61 126.64,10.43 126.64,10.43 126.28,10.06 126.26,10.06 125.91,10.06 125.31,9.46 125.31,9.46 123.61,7.76 122.98,7.76 122.98,7.77 121.24,7.77 120.61,7.76 120.04,8.34 114.66,8.34 113.39,7.07 112.97,7.07 111.34,7.07 110.7,7.7 108.22,7.7 107.51,7.7 107.38,7.83 95.55,7.83 95.02,8.36 95.02,8.84 93.39,10.47 84.47,10.47 84.18,10.18 84.18,10.18 83.99,9.99 79.6,9.99 79.26,9.65 77.34,9.65 77,9.99 73.31,9.99 73.12,10.18 71.35,10.18 69.69,8.53 v2(67.8,8.53)
  BOTTOM w0.102: JKB1.26 v2(67.8,8.53) ; UE1.57 170.42,23.57 170.25,23.74 170.25,24.19 169.52,24.91 v2(169.03,24.91)
KSI3: length 116.2
  TOP w0.102: v2(70.09,8.22) 70.09,8.93 v1(70.19,9.04)
  IN1 w0.127: v2(169.83,23.99) 168.36,22.51 168.36,20.85 167.23,19.72 167.23,19.51 167.23,19.5 167.23,18.42 164.28,15.47 160.77,15.47 160.58,15.28 160.21,15.28 159.69,14.76 156.9,14.76 155.73,15.93 153.38,15.93 151.45,13.99 143.95,13.99 143.32,13.35 140.83,13.35 138.68,13.35 136.08,10.75 127.66,10.75 127.27,10.36 127.27,9.48 125.31,7.51 122.87,7.51 122.87,7.51 121.35,7.51 121.35,7.51 120.5,7.51 119.93,8.08 114.89,8.08 113.62,6.81 113.49,6.81 113.49,6.81 112.86,6.81 112.86,6.81 111.21,6.81 110.57,7.45 108.33,7.45 107.4,7.45 107.27,7.57 95.23,7.57 94.09,7.57 92.21,9.45 85.94,9.45 85.81,9.58 84.79,9.58 84.64,9.73 79.71,9.73 79.37,9.39 77.23,9.39 76.89,9.73 73.21,9.73 73.01,9.92 71.45,9.92 70.09,8.56 v2(70.09,8.22)
  BOTTOM w0.102: JKB1.23 70.2,8.34 v2(70.09,8.22) ; v2(169.83,23.99) 170.02,23.81 UE1.58
KSI4: length 120
  TOP w0.102: v2(67,8.45) 67,8.48 v4(66.57,8.91)
  IN1 w0.127: v2(67,8.45) 67.57,9.02 69.83,9.02 71.24,10.43 73.23,10.43 73.42,10.24 77.1,10.24 77.44,9.9 79.16,9.9 79.5,10.24 83.88,10.24 84.37,10.72 93.52,10.72 95.27,8.97 95.27,8.46 95.65,8.08 107.48,8.08 107.61,7.96 108.12,7.96 110.83,7.96 111.46,7.32 113.07,7.32 113.28,7.32 114.55,8.59 120.14,8.59 120.71,8.02 121.13,8.02 121.13,8.02 123.08,8.02 123.08,8.02 123.51,8.02 125.05,9.56 125.05,9.57 125.8,10.31 126.17,10.31 126.42,10.57 126.43,10.58 126.53,10.69 126.53,10.69 126.63,10.79 126.78,10.94 127.12,11.28 135.86,11.28 138.44,13.86 139.3,13.86 143.11,13.86 143.74,14.5 145.63,14.5 147.56,16.43 155.94,16.43 157.06,15.31 159.31,15.31 159.52,15.31 159.99,15.78 160.37,15.78 160.56,15.98 164.07,15.98 166.72,18.63 166.72,19.29 166.72,19.29 166.72,19.93 167.85,21.06 167.85,22.73 168.45,23.33 v2(168.45,24.94)
  BOTTOM w0.102: JKB1.27 v2(67,8.45) ; v2(168.45,24.94) 168.45,24.8 169.62,23.63 UE1.59
KSI5: length 122.4
  TOP w0.102: v2(67.85,7.94) 67.85,7.34 v4(67.84,7.32)
  IN1 w0.127: v2(167.91,24.72) 167.91,23.14 167.6,22.83 167.6,21.2 165.84,19.45 165.84,18.37 163.76,16.29 160.51,16.29 160.26,16.04 159.89,16.04 159.42,15.57 157.17,15.57 156.05,16.69 145.57,16.69 143,14.12 140.51,14.12 140.51,14.11 139.4,14.11 139.4,14.12 138.3,14.12 138.3,14.11 138.09,14.11 138.09,14.12 129.6,14.12 126.36,10.88 126.24,10.76 126.23,10.75 126.06,10.57 126.05,10.57 125.84,10.57 125.69,10.57 124.8,9.67 123.4,8.27 123.19,8.27 120.82,8.27 120.25,8.84 114.38,8.84 113.11,7.57 111.59,7.57 110.95,8.21 108.01,8.21 107.72,8.21 107.59,8.34 102.03,8.34 101.08,9.29 95.31,9.29 93.62,10.98 84.26,10.98 83.78,10.5 79.39,10.5 79.05,10.16 77.55,10.16 77.21,10.5 73.52,10.5 73.33,10.69 71.13,10.69 69.72,9.27 66.92,9.27 66.53,8.88 66.53,8.15 66.73,7.94 v2(67.85,7.94)
  BOTTOM w0.102: UE1.60 169.22,23.63 168.35,24.5 168.13,24.5 v2(167.91,24.72) ; v2(67.85,7.94) 68.3,7.94 68.6,8.25 JKB1.25
KSI6: length 120.9
  TOP w0.102: v1(64.4,7.54) 65.18,8.32 v2(65.8,8.32)
  IN1 w0.127: v2(166.41,21.58) 166.41,20.75 165.29,19.63 165.29,18.53 163.55,16.79 160.3,16.79 160.05,16.55 159.53,16.55 159.11,16.12 157.33,16.12 156.26,17.2 143.29,17.2 141.36,15.27 141.36,15.26 141.35,15.26 141.2,15.11 140.71,14.62 140.3,14.62 140.3,14.62 139.61,14.62 139.61,14.62 129.38,14.62 126,11.23 125.92,11.15 125.84,11.08 125.48,11.08 124.29,9.88 124.29,9.88 123.19,8.78 121.11,8.78 120.54,9.35 114.07,9.35 112.8,8.08 111.89,8.08 111.29,8.68 111.29,8.82 110.57,9.54 106.52,9.54 106.52,9.54 102.45,9.54 102.19,9.8 95.52,9.8 93.83,11.49 93.62,11.49 93.62,11.49 84.05,11.49 83.88,11.32 79.5,11.32 78.84,10.66 77.76,10.66 77.42,11 73.73,11 73.54,11.19 70.92,11.19 69.51,9.78 66.34,9.78 65.8,9.24 v2(65.8,8.32)
  BOTTOM w0.102: UE1.61 168.82,23.57 168.17,24.22 167.36,24.22 167.05,23.91 167.05,23.1 166.41,22.46 v2(166.41,21.58) ; JKB1.28 66.2,8.72 v2(65.8,8.32)
KSI7: length 120.5
  TOP w0.102: v1(66.06,6.75) 65.78,7.03 v2(65.78,7.67)
  IN1 w0.127: v2(167,21.51) 167,20.99 165.54,19.53 165.54,18.43 163.65,16.54 160.41,16.54 160.16,16.29 159.72,16.29 159.27,15.83 157.26,15.83 156.15,16.94 145.47,16.94 142.9,14.37 140.4,14.37 129.49,14.37 126.18,11.06 126.08,10.96 125.95,10.82 125.59,10.82 124.54,9.78 124.54,9.77 123.3,8.53 120.92,8.53 120.35,9.1 114.26,9.1 112.99,7.83 111.72,7.83 111.08,8.46 107.91,8.46 107.78,8.59 102.14,8.59 101.19,9.54 95.42,9.54 93.73,11.23 84.15,11.23 83.67,10.75 79.29,10.75 78.95,10.41 77.65,10.41 77.31,10.75 73.63,10.75 73.44,10.94 71.03,10.94 69.62,9.53 66.69,9.53 66.23,9.07 66.23,8.13 v2(65.78,7.67)
  BOTTOM w0.102: v2(65.78,7.67) 65.76,7.67 65.29,8.15 65.29,8.49 65.4,8.6 JKB1.29 ; v2(167,21.51) 167.33,21.84 167.33,23.81 167.44,23.92 168.11,23.92 168.42,23.6 UE1.62
KSO0: length 120.4
  TOP w0.102: v2(78.39,5.21) 78.62,5.21 v1(79.01,5.61)
  IN1 w0.127: v2(78.39,5.21) 79.9,3.7 87.25,3.7 89.11,1.84 136.19,1.84 136.58,2.24 146.07,2.24 148.8,4.97 148.8,7.57 149.4,8.17 154.93,8.17 154.93,8.17 156.88,8.17 157.91,7.14 157.96,7.14 168.03,7.14 176.98,16.09 176.98,17.74 176.68,18.05 176.68,19.07 177.58,19.98 v2(177.58,21.2)
  BOTTOM w0.102: UE1.39 177.62,21.23 v2(177.58,21.2) ; JKB1.13 78.25,9.2 78.25,5.35 v2(78.39,5.21)
KSO1: length 121.4
  TOP w0.102: v1(76.92,6.81) 76.6,6.49 v2(76.6,6.16)
  IN1 w0.127: v2(76.6,6.16) 77.87,6.16 77.98,6.05 79.31,6.05 80.33,5.03 80.83,5.03 81.66,4.21 87.7,4.21 89.56,2.35 135.97,2.35 136.37,2.75 145.86,2.75 148.29,5.18 148.29,7.3 148.29,7.51 148.29,7.51 148.29,7.72 148.29,7.79 149.19,8.68 157.09,8.68 157.12,8.65 157.16,8.65 158.17,7.65 167.39,7.65 173.4,13.66 173.4,18 175.5,20.1 176.25,20.1 176.94,20.79 v2(176.94,21.16)
  BOTTOM w0.102: v2(76.6,6.16) JKB1.15 ; RE62.2 v2(176.94,21.16) 177.22,21.44 UE1.40
KSO2: length 120
  TOP w0.102: v2(77.43,5.63) 77.43,5.36 v1(77.05,4.97)
  IN1 w0.127: v2(77.43,5.63) 79.24,5.63 80.09,4.78 80.22,4.78 80.23,4.78 80.73,4.78 81.55,3.96 87.35,3.96 89.21,2.1 136.08,2.1 136.48,2.49 145.96,2.49 148.55,5.08 148.55,7.41 148.55,7.68 149.29,8.43 156.98,8.43 158.02,7.39 158.07,7.39 167.66,7.39 173.65,13.38 173.65,17.66 v2(175.6,19.6)
  BOTTOM w0.102: v2(175.6,19.6) 175.61,19.6 RE63.2 176.48,20.61 176.48,21.63 176.82,21.97 UE1.41 ; JKB1.14 77.4,5.66 v2(77.43,5.63)
KSO3: length 126.6
  TOP w0.102: v1(74.98,5.31) 75.8,6.14 v2(75.8,6.14)
  IN1 w0.127: v2(75.8,6.14) 76.24,6.58 77.81,6.58 78.08,6.3 79.42,6.3 80.44,5.29 80.94,5.29 81.76,4.46 87.87,4.46 89.73,2.6 94.43,2.6 95.33,3.51 97.55,3.51 104.88,3.51 105.79,2.6 128.53,2.6 129.43,3.5 130.21,3.5 130.98,4.27 135.63,4.27 136.9,3 145.75,3 147.09,4.34 147.09,7.77 148.28,8.96 157.22,8.96 158.26,7.92 167.3,7.92 169.97,10.59 169.97,10.6 173.15,13.77 173.15,18.1 173.97,18.92 173.97,21.09 176.71,23.83 v2(176.71,24.39)
  BOTTOM w0.102: JKB1.16 v2(75.8,6.14) ; UE1.42 176.42,23.76 176.71,24.05 v2(176.71,24.39)
KSO4: length 122.9
  TOP w0.102: v1(73.05,7.38) 72.6,7.83 v2(72.6,7.84)
  IN1 w0.127: v2(176.19,24.12) 176.19,23.77 173.6,21.17 173.6,18.91 172.89,18.21 172.89,13.88 168.01,9 160.7,9 160.58,9.13 157.51,9.13 157.4,9.24 150.05,9.24 145.4,9.24 140.43,9.24 135.72,4.53 130.88,4.53 130.11,3.76 129.26,3.76 128.36,2.86 105.89,2.86 104.99,3.76 97.44,3.76 95.23,3.76 94.32,2.86 89.84,2.86 87.98,4.72 81.87,4.72 81.05,5.54 80.54,5.54 79.53,6.56 78.19,6.56 77.73,7.01 73.42,7.01 v2(72.6,7.84)
  BOTTOM w0.102: UE1.43 176.02,23.94 v2(176.19,24.12) ; JKB1.20 v2(72.6,7.84)
KSO5: length 126.1
  TOP w0.102: v2(71.8,8.47) 71.8,9.7 v1(71.9,9.8)
  IN1 w0.127: v2(71.8,8.47) 72.83,8.47 74.03,7.27 77.84,7.27 78.3,6.81 79.63,6.81 80.65,5.8 81.15,5.8 81.98,4.97 88.08,4.97 89.94,3.11 94.22,3.11 95.12,4.02 97.34,4.02 105.09,4.02 106,3.11 123.61,3.11 124.26,3.76 124.61,3.76 125.26,3.11 128.26,3.11 129.16,4.01 130,4.01 130.86,4.87 135.7,4.87 140.32,9.49 140.53,9.49 140.53,9.49 157.51,9.49 157.62,9.38 160.68,9.38 160.81,9.25 167.83,9.25 172.05,13.47 172.05,15.76 172.55,16.25 172.55,17.8 171.85,18.5 171.85,19.2 171.98,19.32 171.98,20.12 175.75,23.89 175.75,24.41 176.06,24.71 v2(176.13,24.71)
  BOTTOM w0.102: JKB1.21 v2(71.8,8.47) ; v2(176.13,24.71) 175.72,24.3 175.72,23.77 175.62,23.67 UE1.44
KSO6: length 121.8
  TOP w0.102: v2(74.2,7.69) 74.87,7.69 v1(74.89,7.7)
  IN1 w0.127: v2(175.31,24.12) 175.15,23.96 175.15,23.77 175.14,23.76 175.14,23.74 174.75,23.35 174.73,23.35 171.66,20.27 171.66,19.39 171.6,19.32 171.6,18.31 172.3,17.61 172.3,16.36 170.99,15.05 170.99,13.07 167.42,9.5 160.92,9.5 160.79,9.63 157.72,9.63 157.53,9.82 150.22,9.82 140.3,9.82 135.59,5.12 130.75,5.12 129.89,4.26 129.05,4.26 128.15,3.37 125.37,3.37 124.71,4.02 124.14,4.02 123.5,3.38 120,3.38 119.24,4.15 118.49,4.15 118.32,3.98 118.32,3.98 118.07,3.73 117.71,3.37 106.1,3.37 105.2,4.27 97.23,4.27 96.14,4.27 96.14,4.27 95.93,4.27 95.02,4.27 94.11,3.37 90.05,3.37 88.19,5.23 82.08,5.23 81.26,6.05 81.17,6.05 80.75,6.05 79.74,7.07 78.4,7.07 77.78,7.69 v2(74.2,7.69)
  BOTTOM w0.102: UE1.45 175.22,24.03 v2(175.31,24.12) ; JKB1.18 v2(74.2,7.69)
KSO7: length 122.6
  TOP w0.102: v2(73.4,8.53) 73.4,8.88 v1(73.74,9.23)
  IN1 w0.127: v2(73.4,8.53) 73.82,8.11 77.72,8.11 78.51,7.32 79.84,7.32 80.86,6.3 81.36,6.3 82.19,5.48 88.29,5.48 90.15,3.62 94.01,3.62 94.91,4.53 95.75,4.53 97.13,4.53 105.3,4.53 106.21,3.62 117.54,3.62 118.32,4.4 119.34,4.4 120.1,3.64 123.4,3.64 124.03,4.27 124.82,4.27 125.37,3.73 125.79,3.73 125.79,3.73 127.38,3.73 129.01,5.36 129.39,5.36 129.96,5.92 130.32,5.92 130.53,5.92 130.53,5.92 131.17,5.92 131.17,5.92 131.53,5.92 132.16,5.92 132.37,5.92 132.58,5.92 133.73,5.92 133.94,5.92 133.94,5.92 136.04,5.92 140.19,10.08 157.64,10.08 157.83,9.89 160.89,9.89 161.02,9.76 167.31,9.76 170.73,13.18 170.73,15.15 171.03,15.45 171.03,19.2 171.41,19.58 171.41,20.38 174.63,23.6 174.64,23.6 174.89,23.85 174.89,23.86 174.89,23.86 174.89,24.32 v2(175.3,24.74)
  BOTTOM w0.102: v2(175.3,24.74) 174.88,24.31 174.88,23.87 174.82,23.82 UE1.46 ; JKB1.19 v2(73.4,8.53)
KSO8: length 118.9
  TOP w0.102: v1(75.52,9.61) 75.52,9.05 v2(75,8.53)
  IN1 w0.127: v2(75,8.53) 77.75,8.53 78.7,7.57 79.95,7.57 80.96,6.56 81.47,6.56 82.29,5.73 88.4,5.73 90.26,3.87 93.9,3.87 94.81,4.78 95.65,4.78 97.02,4.78 105.41,4.78 106.32,3.87 117.43,3.87 118.21,4.65 119.45,4.65 120.17,3.93 123.33,3.93 123.93,4.53 124.92,4.53 125.47,3.98 125.68,3.98 127.28,3.98 128.91,5.61 129.28,5.61 129.85,6.18 130.43,6.18 130.43,6.18 130.64,6.18 130.64,6.18 131.06,6.18 131.06,6.18 131.42,6.18 131.43,6.18 132.27,6.18 132.48,6.18 132.69,6.18 133.84,6.18 135.09,6.18 135.89,6.18 140.06,10.35 157.72,10.35 157.93,10.14 162.2,10.14 162.76,10.71 167.9,10.71 170.48,13.28 170.48,15.26 170.77,15.55 170.77,19.09 170.77,19.3 171.15,19.68 171.15,20.49 174.31,23.64 174.31,23.86 v2(174.47,24.02)
  BOTTOM w0.102: JKB1.17 v2(75,8.53) ; UE1.47 174.42,23.97 v2(174.47,24.02)
KSO9: length 112.5
  TOP w0.102: v1(83.78,7.77) 83.44,7.43 v2(83.44,7.07)
  IN1 w0.127: v2(174.47,24.73) 174.04,24.31 174.04,23.73 170.9,20.59 170.9,19.79 170.52,19.41 170.52,19.2 170.52,19.2 170.52,18.98 170.52,15.66 170.22,15.36 170.22,15.15 170.22,13.39 167.8,10.96 162.65,10.96 162.09,10.4 158.04,10.4 157.04,11.4 152.81,11.4 152.8,11.38 150.04,11.38 149.34,10.69 140.04,10.69 135.78,6.43 135.61,6.43 135.19,6.43 135.19,6.43 132.8,6.43 132.58,6.43 132.37,6.43 131.32,6.43 130.96,6.43 130.96,6.43 130.75,6.43 130.74,6.43 130.53,6.43 129.96,6.43 129.75,6.43 129.18,5.86 128.8,5.86 127.17,4.23 125.58,4.23 124.84,4.97 119.45,4.97 119.45,4.97 119.07,4.97 119.01,4.91 118.11,4.91 117.33,4.13 106.53,4.13 105.62,5.03 96.92,5.03 95.54,5.03 94.7,5.03 93.79,4.13 90.36,4.13 88.5,5.99 84.52,5.99 83.86,6.65 83.85,6.65 83.61,6.9 83.61,6.9 v2(83.44,7.07)
  BOTTOM w0.102: UE1.48 174.02,23.83 174.02,23.83 174.02,24.28 v2(174.47,24.73) ; v2(83.44,7.07) 83.46,7.07 83,7.53 JKB1.7
KSO10: length 110.4
  TOP w0.102: v1(174.84,26.12) 174.84,25.88 v2(174.54,25.59)
  IN1 w0.127: v2(174.54,25.59) 174.42,25.59 173.75,24.91 173.75,23.8 170.64,20.7 170.64,19.89 170.26,19.51 170.26,19.09 170.26,19.09 170.26,18.88 170.26,16.53 164.95,11.21 162.55,11.21 161.98,10.65 158.14,10.65 157.1,11.7 153.57,11.7 151.1,11.7 149.99,11.7 149.23,10.94 139.76,10.94 135.51,6.69 135.3,6.69 132.9,6.69 132.69,6.69 132.48,6.69 132.48,6.69 131.21,6.69 130.85,6.69 130.06,6.69 129.64,6.69 129.07,6.12 128.63,6.12 127.73,5.22 119.55,5.22 119.18,5.23 119.17,5.23 118.96,5.23 118.9,5.16 117.98,5.16 117.2,4.38 106.63,4.38 105.73,5.29 96.81,5.29 95.44,5.29 94.6,5.29 93.69,4.38 90.47,4.38 88.61,6.24 85.52,6.24 v2(84.63,7.13)
  BOTTOM w0.102: UE1.49 173.62,24.79 174.42,25.59 v2(174.54,25.59) ; JKB1.5 84.6,7.45 84.63,7.42 v2(84.63,7.13)
KSO11: length 109.8
  TOP w0.102: v1(172.42,25.67) 172.86,25.24 v2(172.86,25.15)
  IN1 w0.127: v2(172.86,25.15) 173.38,24.63 173.38,23.79 170.39,20.8 170.39,20 170.01,19.62 170.01,18.98 170.01,18.98 170.01,18.77 170.01,16.63 164.84,11.47 162.44,11.47 161.88,10.9 158.25,10.9 157.2,11.95 153.46,11.95 151,11.95 151,11.95 149.88,11.95 149.13,11.19 139.66,11.19 135.4,6.94 133.01,6.94 132.8,6.94 132.8,6.94 132.58,6.94 131.11,6.94 131.11,6.94 129.53,6.94 128.97,6.37 128.52,6.37 127.63,5.48 119.66,5.48 119.66,5.48 119.28,5.48 119.07,5.48 118.86,5.48 118.86,5.48 118.52,5.48 118.45,5.42 116.07,5.42 115.29,4.64 106.74,4.64 105.83,5.54 96.71,5.54 96.7,5.54 96.66,5.54 94.49,5.54 93.58,4.64 90.57,4.64 88.61,6.6 85.92,6.6 84.97,7.55 84.45,7.55 84.03,7.12 v2(84.03,7.07)
  BOTTOM w0.102: v2(172.86,25.15) 173.39,24.62 173.39,23.88 173.22,23.71 UE1.50 ; JKB1.6 83.8,7.67 83.9,7.57 83.9,7.19 v2(84.03,7.07)
KSO12: length 109.9
  TOP w0.102: v2(79.4,8.46) v1(78.57,8.46)
  IN1 w0.127: v2(172.92,23.99) 172.92,23.89 170.14,21.1 170.14,20.1 169.75,19.72 169.75,19.51 169.76,19.51 169.76,18.88 169.76,18.88 169.76,18.67 169.76,16.74 165.99,12.97 158.21,12.97 157.44,12.2 153.36,12.2 150.89,12.2 149.78,12.2 149.02,11.45 139.53,11.45 135.58,7.5 129.61,7.5 128.8,6.69 128.42,6.69 127.46,5.73 119.76,5.73 119.39,5.73 119.39,5.73 119.18,5.73 119.18,5.73 118.75,5.73 118.75,5.73 118.35,5.73 118.28,5.67 115.94,5.67 115.16,4.89 106.91,4.89 106,5.8 95.23,5.8 95.23,5.8 94.38,5.8 93.48,4.89 91.99,4.89 89.21,7.68 85.2,7.68 85.07,7.8 83.16,7.8 82.36,7 80.98,7 80.09,7.89 79.97,7.89 v2(79.4,8.46)
  BOTTOM w0.102: JKB1.12 79,8.57 79.1,8.46 v2(79.4,8.46) ; v2(172.92,23.99) 172.82,23.89 UE1.51
KSO13: length 109.5
  TOP w0.102: v1(82.13,6.75) 82.13,6.88 v2(81.49,7.51)
  IN1 w0.127: v2(81.49,7.51) 81.53,7.47 82.38,7.47 82.97,8.06 85.18,8.06 85.3,7.93 89.31,7.93 92.07,5.17 93.4,5.17 94.28,6.05 95.12,6.05 106.11,6.05 106.99,5.16 113.91,5.16 114.12,5.16 114.96,5.16 114.97,5.17 115.07,5.17 115.82,5.92 118.15,5.92 118.22,5.99 118.65,5.99 119.28,5.99 119.49,5.99 119.49,5.99 119.87,5.99 119.87,5.99 127.27,5.99 128.29,7 128.67,7 129.5,7.83 135,7.83 135.21,7.83 135.42,7.83 139.42,11.83 141.46,11.83 143.95,11.83 144.58,12.46 145.69,12.46 146.39,11.77 148.98,11.77 149.67,12.46 153.04,12.46 157.33,12.46 158.1,13.22 165.88,13.22 169.5,16.84 169.5,18.56 169.5,18.56 169.5,18.77 169.5,18.77 169.5,19.41 169.5,19.83 169.88,20.21 169.88,21.21 172.5,23.83 172.5,24.23 v2(172.84,24.57)
  BOTTOM w0.102: UE1.52 172.42,23.56 172.51,23.65 172.51,24.23 v2(172.84,24.57) ; JKB1.9 81.4,8.62 81.49,8.53 v2(81.49,7.51)
KSO14: length 106
  TOP w0.102: v2(82.06,7.89) v1(82.06,8.65)
  IN1 w0.127: v2(172.02,24.01) 171.85,23.84 171.85,23.62 169.63,21.41 169.63,20.31 169.25,19.93 169.25,19.3 169.25,18.67 169.25,18.67 169.25,18.46 169.25,16.95 165.78,13.48 157.99,13.48 157.23,12.71 153.14,12.71 153.14,12.72 144.48,12.72 143.84,12.08 141.35,12.08 141.35,12.08 139.32,12.08 135.32,8.08 135.11,8.08 130.07,8.08 129.62,8.53 128.42,8.53 126.13,6.24 119.98,6.24 119.6,6.24 119.6,6.24 119.39,6.24 118.54,6.24 118.54,6.24 118.01,6.24 117.94,6.18 115.63,6.18 114.89,5.44 114.88,5.44 114.86,5.42 114.22,5.42 114.01,5.42 107.1,5.42 106.21,6.3 95.02,6.3 94.7,6.3 94.17,6.3 93.31,5.44 92.16,5.44 89.42,8.18 85.41,8.18 85.28,8.31 82.48,8.31 v2(82.06,7.89)
  BOTTOM w0.102: v2(172.02,24.01) UE1.53 ; JKB1.8 82.2,8.03 v2(82.06,7.89)
KSO15: length 108.1
  TOP w0.102: v2(80.79,8.46) 80.79,7.83 v1(80.38,7.42)
  IN1 w0.127: v2(80.79,8.46) 80.89,8.57 85.39,8.57 85.51,8.44 89.52,8.44 92.22,5.74 93.25,5.74 94.07,6.56 94.5,6.56 94.59,6.56 106.32,6.56 107.21,5.67 114.12,5.67 114.12,5.67 114.33,5.67 114.75,5.67 115.51,6.43 117.84,6.43 117.9,6.5 118.44,6.5 119.49,6.5 119.7,6.5 120.08,6.5 120.08,6.49 126.02,6.49 128.31,8.78 129.75,8.78 130.2,8.34 135.21,8.34 139.21,12.34 141.25,12.34 143.74,12.34 144.37,12.97 153.24,12.97 153.25,12.97 157.13,12.97 157.89,13.73 165.67,13.73 168.99,17.06 168.99,18.35 168.99,18.56 168.99,18.56 168.99,19.19 168.99,19.2 168.99,20.04 169.37,20.42 169.37,21.51 171.59,23.73 171.59,24.28 v2(171.93,24.62)
  BOTTOM w0.102: JKB1.10 80.6,8.66 v2(80.79,8.46) ; v2(171.93,24.62) 171.49,24.18 171.49,23.75 171.62,23.62 UE1.54
KSO16: length 116.7
  TOP w0.102: v1(80.28,9.23) 80.03,8.97 v2(80.03,8.46)
  IN1 w0.127: v2(170.71,27.89) 170.77,27.89 171.34,27.33 171.34,23.84 169.12,21.62 169.12,20.52 168.74,20.14 168.74,19.09 168.74,18.46 168.74,18.46 168.74,18.25 168.74,17.16 166.21,14.63 161.01,14.63 160.9,14.51 160.52,14.51 160,13.99 159.37,13.99 159.37,13.99 156.09,13.99 155.42,13.99 154.96,14.46 152.99,14.46 151.76,13.23 144.27,13.23 143.63,12.59 141.14,12.59 141.14,12.59 139.04,12.59 135.21,8.76 130.6,8.76 130.32,9.04 128.21,9.04 125.92,6.75 120.16,6.75 119.59,7.32 116.04,7.32 114.65,5.92 114.44,5.92 114.43,5.92 114.22,5.92 107.31,5.92 106.42,6.81 94.91,6.81 94.32,6.81 93.96,6.81 93.17,6.02 92.31,6.02 89.63,8.69 85.62,8.69 85.49,8.82 84.16,8.82 84.01,8.97 80.6,8.97 80.09,8.46 v2(80.03,8.46)
  BOTTOM w0.102: v2(170.71,27.89) 169.57,29.04 169.57,29.58 168.67,30.47 167.29,30.47 166.94,30.82 UE1.81 ; JKB1.11 79.8,8.69 v2(80.03,8.46)
LAN_CLKREQ#: length 217.4
  TOP w0.102: v1(107.46,35.2) 107.48,35.22 v2(108.11,35.22)
  IN1 w0.127: v2(31.93,86.31) 32.6,86.98 32.6,87.9 32.6,89.21 43.64,100.26 43.64,101.65 45.48,103.49 45.48,110.37 44.73,111.11 33.74,111.11 28.21,116.64 v2(28.21,116.99) ; v2(81.88,22.37) 82.2,22.69 97.73,22.69 100.58,25.55 102.59,25.55 104.96,27.92 106.88,27.92 108.27,29.31 108.27,30.87 107.63,31.51 107.63,34.74 v2(108.11,35.22)
  BOTTOM w0.102: UL1.12 30.91,117.67 30.16,116.93 29.41,116.93 29.18,117.16 RL11.1 28.54,116.99 v2(28.21,116.99) ; v2(108.11,35.22) 107.25,36.08 107.25,36.86 109.05,38.66 109.05,39.9 109.07,39.92 109.07,40.59 109.57,41.09 109.57,41.64 109.54,41.67 109.54,41.68 109.51,41.71 109.51,42.31 109.5,42.32 109.5,42.32 109.4,42.42 109.4,42.69 109.48,42.77 109.48,43.04 109.26,43.26 UC1.AY32 ; v2(31.93,86.31) 30.95,85.33 30.95,46.88 41.36,36.47 41.36,32.66 42.63,31.39 42.63,20.02 44.53,18.12 53.8,18.12 55.77,16.15 67.4,16.15 68.31,17.06 68.38,17.06 68.47,17.15 79.95,17.15 80.79,17.99 80.79,21.28 v2(81.88,22.37)
LCD_TEST: length 80.9
  IN1 w0.127: v2(220.06,44.97) 219.9,44.97 219.38,44.46 219.38,39.08 217.16,36.86 216.05,36.86 215.39,37.52 212.58,37.52 210.97,39.13 210.97,39.45 210.48,39.93 207.51,39.93 206.57,40.87 199.63,40.87 198.96,41.55 194.81,41.55 192.74,43.62 191.57,43.62 189.83,45.36 189.12,45.36 187.03,47.45 v2(186.65,47.45)
  IN2 w0.127: v2(172.91,30.66) 172.8,30.76 172.8,32.57 173.12,32.89 173.12,34.11 175.23,36.21 179.2,36.21 179.66,36.68 179.66,37.4 184.55,42.29 184.55,43.58 185.06,44.09 185.06,45.48 186.14,46.56 186.14,46.94 v2(186.65,47.45)
  BOTTOM w0.102: v2(172.91,30.66) 172.91,27.81 171.41,26.31 169.76,26.31 168.99,27.07 167.72,27.07 167.57,27.22 UE1.72 ; v2(220.06,44.97) 220.09,44.94 220.76,44.94 RX2.1
LCD_TST_C: length 2.5
  BOTTOM w0.102: JEDP1.12 222.14,44.55 RX2.2
LDO_+1.35VGPU: length 0.9
  TOP w0.102: v2(153.79,87.15) v1(153.79,88.03)
LG1_APU: length 7.8
  IN2 w0.762: 161.27,60.61 158.5,60.61 155.4,63.71 155.34,63.71
  BOTTOM w0.102: v2(162.01,60.79) 162.01,61.04 v1(161.75,61.3)
  vias: v2(149.35,64.03) v2(149.35,63.39) v2(154.52,64.03) v2(154.52,63.33) v2(162.59,60.79)
LG1_VGA: length 7.8
  IN2 w0.762: 59.71,122.38 60.54,121.56 65.36,121.56 66.12,120.8 66.82,120.8
  vias: v1(57.32,122.64) v2(57.79,122.45) v2(58.38,122.45) v2(67.65,120.73) v2(67.65,115.52) v2(68.28,120.73) v2(68.35,115.52)
LG2_VGA: length 15.3
  TOP w0.102: v2(67.65,126.57) 67.65,127.13 67.36,127.42 v1(67.36,129.28)
  IN2 w0.762: 67.9,125.81 67.9,122.13 ; 59.39,123.78 60.41,123.78 62.63,126 67.27,126
  vias: v2(57.49,123.87) v2(58.12,123.84) v2(67.58,121.37) v2(68.22,121.37) v2(68.35,126.57)
LG_1.2V: length 7.8
  TOP w0.102: v1(76.77,100.28) 76.77,100.84 77.29,101.36 v2(77.29,101.55)
  IN2 w0.762: 78.7,101.68 79.14,102.13 81.24,102.13 83.78,104.67
  vias: v2(77.87,101.55) v2(85.11,104.67) v2(85.75,104.67)
LG_NB: length 13.5
  IN2 w0.762: 166.39,55.39 166.39,54.82 165.18,53.61 163.66,53.61 159.91,49.87 159.91,46.12
  BOTTOM w0.102: v2(166.26,56.85) 166.26,57.1 v1(165.95,57.42)
  vias: v2(153.92,46.37) v2(153.88,45.74) v2(159.09,46.56) v2(159.09,45.8) v2(166.26,56.22)
LG_VDDP_ALWP: length 9
  IN2 w0.762: 151.91,34.44 152.86,33.48 159.91,33.48
  BOTTOM w0.102: v2(160.99,34.12) 160.55,34.12 v1(160.42,34.24)
  vias: v2(151.15,34.94) v2(151.15,34.24) v2(160.99,33.48)
LGATE_CHG: length 13.5
  IN2 w0.762: 212.87,30.94 212.94,31.01 212.94,33.42 212.17,34.18 212.17,37.36 210.59,38.94 210.59,40.59 211.16,41.17 211.16,42.5
  BOTTOM w0.102: v1(210.52,42.31) 210.4,42.44 v2(209.9,42.44)
  vias: v2(209.28,42.42) v2(212.24,30.82) v2(212.55,30.18)
LID_SW#: length 97.1
  TOP w0.102: JPWR1.2 156.52,108.31 EC2902.1 156.38,108.17 v2(156.38,107.57) ; D4.1 173.65,36.04 RE75.2 v4(174.77,38.37) 174.77,39.45 v2(175.09,39.77)
  IN1 w0.127: v2(156.38,107.57) 156.38,106.83 157.6,105.61 157.6,94.61 162.29,89.93 162.29,86.43 161.5,85.65 161.5,74.88 165.81,70.57 165.81,66.32 166.96,65.17 166.96,64.22 169.69,61.49 169.69,60.45 170.28,59.86 171.01,59.86 172.43,58.44 173.34,58.44 178.37,53.42 178.37,51.33 179.45,50.25 180.36,50.25 180.87,49.74 180.87,48.53 181.12,48.28 181.12,47.64 181.08,47.6 181.08,43.01 179.9,41.83 178.62,41.83 177.25,43.2 176.4,43.2 175.47,42.27 175.47,40.49 175.19,40.2 175.19,39.86 v2(175.09,39.77)
  BOTTOM w0.102: UE1.115 174.82,39.5 v2(175.09,39.77)
LINE1-L: length 4.2
  TOP w0.203: UA1.22 24.49,25.8 24.19,25.49
  TOP w0.305: CA32.1 23.07,23.13 v1(23.71,23.77) 24.19,24.25 24.19,25.49
LINE1-L_C: length 16.1
  TOP w0.102: v2(24.91,14.81) 24.91,15 v1(25.36,15.45)
  TOP w0.305: RA28.1 v2(24.91,14.81) ; CA32.2 v2(20.4,23.13)
  IN2 w0.305: v2(24.91,14.81) 24.91,14.52 24.5,14.12 22.53,14.12 18.99,17.65 18.99,21.72 v2(20.4,23.13)
LINE1-L_R: length 20.9
  TOP w0.102: v2(20.4,24.4) v1(19.83,24.4)
  TOP w0.305: RA32.1 v2(24.91,16.21) ; CA33.2 v2(20.4,24.4)
  IN2 w0.305: v2(20.4,24.4) 20.4,24.08 18.44,22.12 18.44,17.42 22.31,13.54 24.72,13.54 25.48,14.31 25.48,15.64 v2(24.91,16.21)
LINE1-R: length 3.6
  TOP w0.203: 23.63,25.57 23.89,25.84 23.92,25.84 24.27,26.2 UA1.21
  TOP w0.305: CA33.1 23.26,24.4 23.63,24.77 v1(23.63,25.21) 23.63,25.57
LPC_AD0: length 108.9
  TOP w0.102: v2(179.22,31.32) 179.22,31.26 178.29,30.33 178.29,30.33 178.05,30.09 178.05,30.09 177.19,29.23 177.19,28.83 176.35,27.99 176.35,25.32 177.11,24.56 177.11,22.88 176.48,22.24 v1(176.48,21.67) 176.48,21.16 176.45,21.13 176.45,21.12 176.21,20.88 176.14,20.88 v2(175.92,20.66)
  IN1 w0.127: v2(112.15,37.61) 112.22,37.61 113.18,36.66 113.18,34.92 114.83,33.27 114.87,33.27 115.12,33.02 115.12,27.07 115.17,27.02 115.17,23.08 116.16,22.09 116.16,17.18 116.39,16.96 116.39,16.61 116.16,16.38 v2(116.16,16.15)
  IN2 w0.127: v2(175.92,20.66) 175.69,20.43 173.94,20.43 173.94,20.44 173.01,20.44 172.9,20.54 171.74,20.54 167.18,15.98 161.59,15.98 160.8,15.19 156.96,15.19 155.26,16.9 149.39,16.9 149.34,16.89 149.29,16.89 149.21,16.81 145.39,16.81 145.11,17.09 144.88,17.09 144.65,17.09 144.65,17.09 139.46,17.09 138.88,17.67 131.21,17.67 131.2,17.66 131.2,17.66 129.94,16.4 118.48,16.4 117.72,15.64 116.48,15.64 116.16,15.96 v2(116.16,16.15)
  BOTTOM w0.102: UE1.10 180.85,33.22 180.53,32.9 180.53,32.63 v2(179.22,31.32) ; UC1.BA26 111.91,41.74 111.97,41.68 111.97,40.91 111.92,40.86 111.92,37.84 v2(112.15,37.61)
LPC_AD1: length 120.5
  TOP w0.102: v2(181.12,18.69) 181.18,18.75 v1(181.18,23.2) 181.18,24.06 180.59,24.66 179.26,24.66 177.2,26.72 177.2,27.69 179.88,30.37 v2(179.88,33.79)
  IN1 w0.127: v2(115.21,15.89) 115.21,15.89 115.21,15.89 115.21,15.89 115.53,16.21 115.53,21.93 114.61,22.85 114.61,25.95 114.32,26.24 114.32,32.59 112.29,34.63 v2(112.29,35.9)
  IN2 w0.127: v2(181.12,18.69) 180.34,17.9 176.91,17.9 176.49,17.48 169.57,17.48 166.71,14.62 161.12,14.62 161.06,14.56 156.8,14.56 155.02,16.34 149.63,16.34 149.54,16.25 145.16,16.25 144.88,16.53 139.23,16.53 138.88,16.88 131.99,16.88 131.86,16.75 131.53,16.75 130.54,15.77 125.39,15.77 118.64,15.77 117.95,15.08 115.75,15.08 115.21,15.62 v2(115.21,15.89)
  BOTTOM w0.102: v2(179.88,33.79) 180.12,34.02 UE1.8 ; UC1.AY28 111.46,43.26 111.67,43.06 111.67,42.76 111.56,42.66 111.56,42.46 111.71,42.32 111.71,41.65 111.75,41.61 111.75,41.1 111.63,40.98 111.63,36.49 112.22,35.9 v2(112.29,35.9)
LPC_AD2: length 109.3
  TOP w0.102: v1(179.03,34.18) v2(179.03,33.51) 178.58,33.06 178.58,30.99 178.18,30.59 176.93,29.34 176.93,29.33 176.93,29.12 176.93,29.12 176.93,28.94 175.85,27.86 175.85,25.01 175.72,24.88 175.72,24.01 176.04,23.69 v2(176.04,21.29)
  IN1 w0.127: v2(116.84,16.78) 116.84,21.81 115.45,23.19 115.45,26.9 115.45,27.13 115.4,27.18 115.4,34.13 113.46,36.07 113.46,36.77 113.05,37.18 v2(113.05,38.18)
  IN2 w0.127: v2(116.84,16.78) 116.9,16.78 117.41,16.27 117.69,16.27 118.19,16.78 129.61,16.78 130.79,17.97 131.07,17.97 131.08,17.99 138.96,17.99 139.58,17.37 144.54,17.37 144.77,17.37 145.23,17.37 145.5,17.1 149.05,17.1 149.13,17.18 155.37,17.18 157.03,15.51 160.68,15.51 161.5,16.34 167.09,16.34 171.53,20.78 171.58,20.78 171.62,20.82 173.02,20.82 173.12,20.72 174.05,20.72 174.06,20.71 175.34,20.71 175.84,21.22 175.97,21.22 v2(176.04,21.29)
  BOTTOM w0.102: UC1.AY25 112.46,42.66 112.78,42.34 112.78,41.97 112.67,41.87 112.67,38.63 113.05,38.25 v2(113.05,38.18) ; v2(179.03,33.51) 179.03,33.8 179.65,34.42 UE1.7
LPC_AD3: length 109.4
  TOP w0.102: v2(174.7,21.23) 174.71,21.23 174.71,21.61 174.89,21.79 174.89,24.9 175.6,25.61 175.6,28 176.68,29.08 176.68,29.44 177.28,30.05 177.54,30.3 177.54,30.31 178.08,30.84 178.33,31.09 178.33,33.38 178.7,33.74 178.7,34.32 179.09,34.71 179.09,35.26 v2(179.08,35.26) ; v2(114,36.15) 114.07,36.15 v1(114.45,35.77)
  IN1 w0.127: v2(117.5,16.78) 117.5,21.55 115.73,23.31 115.73,26.78 115.73,27.25 115.7,27.27 115.7,34.97 114.52,36.15 v2(114,36.15)
  IN2 w0.127: v2(117.5,16.78) 117.81,17.1 129.42,17.1 130.61,18.28 130.68,18.28 130.7,18.31 139.04,18.31 139.7,17.65 144.42,17.65 144.65,17.65 145.35,17.65 145.58,17.42 148.93,17.42 148.97,17.46 155.49,17.46 157.11,15.83 160.55,15.83 161.37,16.66 166.96,16.66 171.41,21.1 174.57,21.1 v2(174.7,21.23)
  BOTTOM w0.102: v2(114,36.15) 113.81,36.34 113.81,36.81 114.41,37.4 114.41,38.27 113.49,39.19 113.49,40.81 113.94,41.25 113.94,41.68 113.91,41.71 113.91,41.82 113.91,41.83 113.91,42.31 113.88,42.34 113.88,42.36 113.56,42.68 UC1.AY23 ; UE1.5 180.83,35.22 180.7,35.1 180.7,35.09 180.46,34.85 180.46,34.85 179.5,34.85 179.49,34.85 179.26,35.09 179.26,35.1 179.09,35.26 v2(179.08,35.26)
LPC_CLK0_EC: length 118.3
  TOP w0.102: v2(112.51,33.72) 113,33.72 v1(113.05,33.67)
  IN1 w0.127: v2(183.57,18.69) 183.59,18.69 183.54,18.75 183.54,21.72 182.38,22.88 182.38,25.27 183.95,26.84 183.95,30.05 184.27,30.37 184.27,30.93 183.79,31.41 183.79,31.66 v2(183.33,32.12) ; v2(114.57,15.96) 114.57,16.08 114.68,16.19 114.68,20.74 113.81,21.61 113.81,32.28 112.51,33.57 v2(112.51,33.72)
  IN2 w0.127: v2(114.57,15.96) 114.57,15.54 115.54,14.57 115.64,14.57 115.65,14.56 118.19,14.56 118.89,15.26 124.55,15.26 131.08,15.26 132.2,16.38 138.67,16.38 139.02,16.02 144.67,16.02 145.44,15.26 149.31,15.26 149.88,15.83 154.64,15.83 156.49,13.98 157.91,13.98 158.23,13.66 166.51,13.66 169.1,16.25 171.37,16.25 171.47,16.15 172.79,16.15 173.62,16.97 176.74,16.97 176.87,17.1 176.93,17.1 177.21,17.38 182.2,17.38 182.33,17.5 182.33,17.59 183.42,18.69 183.6,18.69 183.6,18.69 v2(183.57,18.69)
  BOTTOM w0.102: RC926.1 CC30.1 113.43,29.81 113.43,32.72 113.16,32.99 RC904.2 112.73,33.5 v2(112.51,33.72) 112.73,33.94 RC449.1 ; RE16.1 183.66,32.85 183.33,32.51 v2(183.33,32.12) 183.06,32.12 182.76,32.42 UE1.12
LPC_CLK1: length 3.5
  BOTTOM w0.102: RC925.2 RC450.1 114.07,29.81 RC927.1 115.45,29.69 v1(115.46,29.67)
LPC_FRAME#: length 123.3
  TOP w0.102: v2(179.85,18.75) 179.85,19 180.85,20.01 v1(180.85,21.05) 180.85,24.03 180.48,24.41 179.15,24.41 176.85,26.7 176.85,27.7 179.63,30.48 179.63,32.87 179.43,33.06 179.43,34.4 v2(180.3,35.26)
  IN1 w0.127: v2(114.7,32.85) 114.7,26.25 114.89,26.06 114.89,22.96 115.84,22.01 115.84,16.91 v2(115.97,16.78)
  IN2 w0.127: v2(179.85,18.75) 179.85,18.47 179.73,18.34 176.93,18.34 176.83,18.24 176.8,18.24 176.37,17.81 169.45,17.81 166.58,14.94 160.99,14.94 160.93,14.88 156.88,14.88 155.14,16.62 149.51,16.62 149.49,16.62 149.48,16.61 149.45,16.61 149.37,16.53 145.28,16.53 145,16.81 144.77,16.81 139.35,16.81 138.8,17.35 131.36,17.35 130.05,16.05 125.5,16.05 118.52,16.05 117.84,15.36 115.87,15.36 115.72,15.51 115.72,16.53 v2(115.97,16.78)
  BOTTOM w0.102: RC903.1 117.04,32.53 116.54,32.53 116.09,32.99 RC902.2 114.84,32.99 v2(114.7,32.85) 113.56,33.99 113.56,36.78 113.56,36.78 113.56,36.91 114.15,37.51 114.15,38.17 113.18,39.14 113.18,41.57 113.23,41.61 113.23,42.32 113.32,42.42 113.32,42.72 113.01,43.03 UC1.AY24 ; UE1.4 180.66,35.63 v2(180.3,35.26)
LPC_RST_A#: length 8.2
  BOTTOM w0.102: UC1.AY27 111.36,42.66 111.13,42.43 111.13,42.43 111.06,42.36 111.06,42.34 111.06,42.34 111.06,42.08 111.06,42.08 111.06,41.68 110.98,41.6 110.98,41.28 111.34,40.91 111.34,36.31 v1(111.46,36.19) 111.84,35.81 RC602.2
LX1_APU: length 11.3
  IN2 w0.762: 160.93,62.88 160.89,62.88 159.11,64.66 158.01,64.66 156.74,65.93 156.74,68.99 155.42,70.31 154.52,70.31
  vias: v1(148.36,70.76) v2(149.18,70.63) v2(149.5,70.06) v2(149.82,71.84) v2(149.88,70.63) v2(150.2,71.27) v2(150.2,70.06) v2(150.52,71.84) v2(150.58,70.63) v2(150.83,71.27) v2(150.83,70.06) v2(151.15,71.84) v2(151.21,70.63) v2(151.53,71.27) v2(151.53,70.06) v2(151.85,71.84) v2(151.91,70.63) v2(152.23,71.27) v2(152.23,70.06) v2(152.55,71.84) v2(152.61,70.63) v2(152.93,71.27) v2(152.93,70.06) v2(153.69,70.69) v2(153.69,70.06) v2(161.06,61.93) v2(161.06,61.35)
LX1_VGA: length 16.5
  IN2 w0.762: 73.59,117.91 66.6,117.91 64.54,119.97 60.28,119.97 59.01,121.24 58.5,121.24
  vias: v1(75.39,114) v2(57.23,122.01) v2(57.68,121.56) v2(74.44,119.91) v2(74.44,119.27) v2(74.44,118.64) v2(74.44,118) v2(74.44,117.3) v2(74.51,116.67) v2(74.51,116.03) v2(74.51,115.33) v2(75.01,119.59) v2(75.01,118.95) v2(75.01,118.32) v2(75.01,117.68) v2(75.01,116.99) v2(75.08,116.35) v2(75.08,115.72) v2(75.08,115.02) v2(75.52,119.91) v2(75.52,119.27) v2(75.52,118.64) v2(75.52,118) v2(75.52,117.3) v2(75.59,116.67) v2(75.59,116.03) v2(75.59,115.33)
LX2_VGA: length 17.5
  IN2 w0.762: 59.46,125.49 61.93,127.97 69.3,127.97 71.65,125.62 74.92,125.62 74.94,125.63
  vias: v1(76.35,128.92) v2(57.55,124.48) v2(58.19,124.54) v2(74.95,131.62) v2(74.95,130.98) v2(74.95,130.35) v2(74.95,129.71) v2(74.95,128.95) v2(75.84,127.65) v2(75.84,127.02) v2(75.78,126.38) v2(75.78,125.75) v2(75.78,125.05) v2(75.78,124.41) v2(76.54,127.65) v2(76.54,127.02) v2(76.47,126.38) v2(76.47,125.75) v2(76.47,125.05) v2(76.47,124.41) v2(77.24,127.72) v2(77.24,127.02) v2(77.17,126.38) v2(77.17,125.75) v2(77.17,125.05) v2(77.24,124.41)
LX_1.2V: length 7.9
  IN2 w0.762: 77.55,103.46 79.75,103.46 81.91,105.62 84.54,105.62
  vias: v1(77.93,104.67) v2(77.36,105.11) v2(77.36,104.41) v2(85.49,105.81) v2(85.94,105.36)
LX_1.8VALW: length 1.7
  TOP w0.102: v1(37.1,102.44) 37.04,102.38 PR606.1
  vias: v2(36.15,101.43) v2(36.15,100.79)
LX_3V: length 0.7
  TOP w0.102: v1(177.25,48.09) 177.45,48.29 v2(177.45,48.66)
  vias: v2(172.68,48.84) v2(172.68,48.21) v2(176.87,48.66)
LX_5V: length 0.6
  TOP w0.102: v2(194.58,38.18) v1(194.58,37.61)
  vias: v2(187.54,42.5) v2(187.54,41.86) v2(194.46,38.75) v2(199.35,38.75) v2(199.35,38.12)
LX_+1.35VGPU: length 0.7
  TOP w0.102: v2(157.74,89.36) 157.74,90.05 v1(157.75,90.06)
  vias: v2(153.69,89.55) v2(153.69,88.97) v2(158.33,89.36)
LX_NB: length 11.5
  IN2 w0.762: 154.83,54.44 156.47,56.08 163.41,56.08 164.16,55.33 165.37,55.33
  vias: v1(154.58,53.49) v2(151.47,49.68) v2(151.72,50.25) v2(152.17,49.68) v2(152.42,50.25) v2(153.06,49.93) v2(153.18,53.42) v2(153.18,52.79) v2(153.18,52.15) v2(153.37,50.5) v2(153.44,49.36) v2(153.56,54.76) v2(153.56,54.12) v2(153.75,52.47) v2(153.75,51.77) v2(153.75,51.14) v2(153.75,49.93) v2(153.82,48.85) v2(154.07,50.5) v2(154.13,49.36) v2(154.45,52.47) v2(165.63,56.85) v2(165.63,56.22)
LX_VDDP_ALWP: length 9.9
  IN2 w0.762: 159.3,36.13 158.07,37.36 149.94,37.36
  vias: v1(144.74,37.42) v2(145.94,36.4) v2(146.01,37.67) v2(146.01,37.04) v2(146.64,37.67) v2(146.64,37.04) v2(146.64,36.4) v2(147.34,37.67) v2(147.34,37.04) v2(147.34,36.4) v2(147.85,36.09) v2(147.91,37.42) v2(147.91,36.78) v2(148.48,37.61) v2(148.48,36.98) v2(148.48,36.34) v2(149.12,35.96) v2(149.25,37.42) v2(149.25,36.66) v2(159.72,35.51) v2(159.72,34.88)
M0_MA0: length 31.4
  TOP w0.102: v2(144.67,118.03) 144.19,118.51 143.09,118.51 142.77,118.83 142.77,119.35 142.5,119.62 138.04,119.62 137.14,118.71 137.14,118.21 136.99,118.06 ; v2(120.92,114.59) 124.01,114.59 125.22,115.8 126,115.8
  TOP w0.127: 136.99,118.06 136.52,118.06
  TOP w0.13: 126,115.8 130.28,115.8 131.95,117.47 v1(132.61,117.47) 133.53,117.47 134.12,118.06 136.52,118.06
  BOTTOM w0.102: v2(144.67,118.03) 145.07,117.63 UV13.H4
  BOTTOM w0.127: v2(120.92,114.59) 120.47,114.59 120.13,114.25 120.13,113.87 119.53,113.27 118.65,113.27 118.28,112.9 UV1.K17
M0_MA1: length 30.4
  TOP w0.102: 126,117.29 125.77,117.29 125.07,116.59 123.13,116.59 122.47,115.93 121.5,115.93 120.95,116.48 119.65,116.48 119.24,116.06 v2(119.24,115.81) ; v2(145.07,118.99) 145.07,119.7 144.54,120.22 137.54,120.22 137.39,120.07
  TOP w0.127: 137.39,120.07 137.18,119.86 136.52,119.86
  TOP w0.13: 136.52,119.86 v1(135.91,119.86) 131.14,119.86 128.57,117.29 126,117.29
  BOTTOM w0.102: v2(119.24,115.81) 118.9,115.48 UV1.J20 ; v2(145.07,118.99) 145.07,118.99 UV13.H5
M0_MA2: length 29.7
  TOP w0.102: 126,120.41 125.12,120.41 124.29,119.59 122.51,119.59 121.29,118.37 120.73,118.37 120.3,117.94 120.17,117.94 v2(120.17,117.93) ; 137.21,121.27 137.44,121.04 144.14,121.04 144.67,121.57 144.67,122.03 v2(145.47,122.83)
  TOP w0.13: 126,120.41 126.64,120.41 127.55,121.33 129.7,121.33 130.43,122.07 v1(132.86,122.07) 136.42,122.07 137.21,121.27
  BOTTOM w0.102: UV1.H23 120.13,117.93 v2(120.17,117.93) ; v2(145.47,122.83) 145.09,123.21 UV13.H11
M0_MA3: length 28.9
  TOP w0.102: 126,119.79 124.78,119.79 124.32,119.33 122.55,119.33 121.37,118.16 121.06,118.16 v2(120.88,117.99) ; 136.92,121.05 137.14,120.83 144.22,120.83 145.07,121.68 v2(145.07,121.86)
  TOP w0.13: 126,119.79 127.57,119.79 127.7,119.92 127.7,120.31 127.83,120.44 128.09,120.44 128.22,120.31 128.22,119.92 128.35,119.79 128.9,119.79 129.03,119.92 129.03,120.39 129.2,120.57 129.71,120.57 130.64,121.49 v1(134.83,121.49) 136.48,121.49 136.92,121.05
  BOTTOM w0.102: v2(145.07,121.86) 145.07,121.86 UV13.H10 ; UV1.G23 120.88,117.88 v2(120.88,117.99)
M0_MA4: length 29.1
  TOP w0.102: v2(120.97,118.75) 120.97,119.19 121.75,119.97 123.42,119.97 123.85,120.4 123.85,121.02 124.87,122.05 124.87,122.55 125.55,123.23 126,123.23 ; v2(143.87,122.83) 143.78,122.74 143.78,121.81 143.21,121.24 137.61,121.24 137.37,121.48
  TOP w0.127: 136.98,121.96 137.21,121.73 137.21,121.64 137.37,121.48
  TOP w0.13: 126,123.23 v1(131.15,123.23) 135.9,123.23 136.98,122.15 136.98,121.96
  BOTTOM w0.102: UV13.K11 143.49,123.21 v2(143.87,122.83) ; v2(120.97,118.75) 120.52,118.3 UV1.G24
M0_MA5: length 29.6
  TOP w0.102: 137.31,122.51 137.31,122.01 137.88,121.44 142.8,121.44 v2(143.19,121.83) ; v2(119.31,118.02) 122.07,120.78 122.07,121.12 122.56,121.62 124.16,121.62 124.67,122.13 124.67,122.89 125.62,123.84 126,123.84
  TOP w0.13: 126,123.84 v1(128.86,123.84) 135.97,123.84 137.31,122.51
  BOTTOM w0.102: v2(143.19,121.83) 143.47,122.11 UV13.K10 ; v2(119.31,118.02) 119.42,118.02 UV1.H24
M0_MA6: length 29.6
  TOP w0.102: 136.52,118.74 136.88,118.74 137.96,119.82 142.59,119.82 v2(143.33,119.08) ; v2(119.46,114.68) 119.9,115.11 120.95,115.11 121.27,114.8 123.93,114.8 125.39,116.26 126,116.26
  TOP w0.13: 126,116.26 129.91,116.26 v1(130.64,116.98) 131.59,117.93 132,117.93 132.2,118.13 132.2,118.54 132.39,118.74 132.77,118.74 132.95,118.56 132.95,118.08 133.1,117.92 133.33,117.92 133.46,118.05 133.46,118.56 133.64,118.74 136.52,118.74
  BOTTOM w0.102: UV13.K5 143.47,118.94 v2(143.33,119.08)
  BOTTOM w0.127: UV1.J19 118.9,114.12 v2(119.46,114.68)
M0_MA7: length 30.5
  TOP w0.102: v2(118.81,114.76) 118.81,114.34 118.94,114.21 121.26,114.21 121.31,114.25 123.98,114.25 125.06,115.34 ; 137,117.6 137.34,117.95 137.34,118.63 138.12,119.41 141.1,119.41 142.2,118.32 142.79,118.32 v2(143.13,117.98)
  TOP w0.127: 136.52,117.6 137,117.6
  TOP w0.13: 125.06,115.34 130.47,115.34 131.55,116.42 131.86,116.42 132.05,116.6 132.05,116.88 132.18,117.01 132.53,117.01 132.66,116.88 132.66,116.56 132.79,116.43 133.04,116.43 133.17,116.56 133.17,116.88 133.3,117.01 133.72,117.01 134.31,117.6 v1(134.77,117.6) 136.52,117.6
  BOTTOM w0.102: UV1.K19 118.15,114.1 v2(118.81,114.76) ; v2(143.13,117.98) 143.47,117.64 UV13.K4
M0_MA8: length 29
  TOP w0.102: v2(121,115.49) 121.4,115.49 121.56,115.65 124.42,115.65 125.48,116.72 126,116.72 ; 137.16,119.4 137.78,120.02 143.19,120.02 143.95,119.26 v2(143.95,118.97)
  TOP w0.127: 137.16,119.4 136.63,119.4
  TOP w0.13: 126,116.72 v1(128.04,116.72) 128.65,116.72 129,117.07 129.17,117.07 129.52,116.72 129.72,116.72 130.02,117.01 130.02,117.19 129.7,117.5 129.7,117.69 129.89,117.87 130.07,117.87 130.38,117.56 130.57,117.56 130.76,117.75 130.76,117.93 130.5,118.2 130.5,118.38 130.68,118.56 130.86,118.56 131.12,118.3 131.31,118.3 132.41,119.4 136.63,119.4
  BOTTOM w0.102: v2(121,115.49) 120.8,115.3 UV1.G20 ; v2(143.95,118.97) 144.27,118.65 UV13.J5
M1_MA0: length 32.2
  TOP w0.102: v2(143.87,105.81) 143.3,105.24 142.26,105.24 141.65,104.63 138.41,104.63 137.58,105.45 137.58,105.85 137.16,106.28 ; 126,112.32 125.72,112.32 125.62,112.22 125.62,111.65 125.4,111.43 123.88,111.43 123.26,112.05 121.32,112.05 121.18,111.91 120.23,111.91 v2(119.82,112.32)
  TOP w0.13: 137.16,106.28 136.99,106.44 136.99,106.87 136.59,107.27 v1(136.04,107.27) 134.73,107.27 129.67,112.32 126,112.32
  BOTTOM w0.102: v2(119.82,112.32) 119.27,111.77 119.27,111.53 118.9,111.17 UV1.J14 ; UV15.H4 v2(143.87,105.81)
M1_MA1: length 31.7
  TOP w0.102: 137.16,105.57 138.34,104.39 142.88,104.39 v2(143.25,104.76) ; v2(118.51,112.35) 119.16,111.7 121.29,111.7 121.44,111.85 123.17,111.85 123.79,111.23 125.48,111.23 125.82,111.57 125.82,111.76 125.93,111.86 126,111.86
  TOP w0.13: 126,111.86 129.48,111.86 v1(133.47,107.88) 135.6,105.75 136.98,105.75 137.16,105.57
  BOTTOM w0.102: UV15.H5 143.47,104.97 v2(143.25,104.76) ; v2(118.51,112.35) 118.51,111.35 118.19,111.03 118.19,110.83 118.1,110.73 UV1.K14
M1_MA2: length 30.9
  TOP w0.102: 126,104.17 125.75,104.43 125.75,104.95 125.22,105.48 124.85,105.48 124.14,106.19 122.31,106.19 120.92,107.57 120.49,107.57 120.38,107.68 v2(120.07,107.68) ; v2(143.07,101.01) 143.07,101.7 142.44,102.33 138.05,102.33 137.61,101.89 137.61,101.61 136.81,100.81 136.52,100.81
  TOP w0.13: 126,104.17 128.74,101.44 129.15,101.44 129.28,101.31 129.28,100.94 129.41,100.81 129.69,100.81 129.82,100.94 129.82,101.23 129.95,101.36 130.21,101.36 130.34,101.23 130.34,100.94 130.47,100.81 v1(134.13,100.81) 136.52,100.81
  BOTTOM w0.102: v2(120.07,107.68) 119.24,107.68 118.9,108.02 UV1.J11 ; v2(143.07,101.01) 143.47,100.61 UV15.H11
M1_MA3: length 32.1
  TOP w0.102: v2(118.77,108.67) 119.27,109.17 120.04,109.17 120.16,109.05 120.16,108.41 120.8,107.78 121.18,107.78 121.51,107.44 123.18,107.44 124.94,105.68 125.66,105.68 126,105.34 126,104.82 ; v2(143.47,101.98) 142.91,102.53 137.97,102.53 137.41,101.97 137.41,101.72 136.96,101.27 136.52,101.27
  TOP w0.13: 136.52,101.27 v1(132.29,101.27) 131.82,101.27 130.51,102.57 129.83,102.57 129.7,102.44 129.7,102.03 129.57,101.9 129.31,101.9 129.19,102.03 129.19,102.44 129.06,102.57 128.26,102.57 126,104.82
  BOTTOM w0.102: v2(118.77,108.67) 118.9,108.8 UV1.J13 ; v2(143.47,101.98) 143.47,101.97 UV15.H10
M1_MA4: length 34.3
  TOP w0.102: 126,108.1 123.31,108.1 122.92,108.49 122.92,109.34 122.69,109.57 122.14,109.57 122.05,109.47 121.45,109.47 121.25,109.67 120.77,109.67 120.59,109.49 120.16,109.49 v2(119.72,109.94) ; v2(145.47,101.01) 145.47,102.6 144.93,103.14 137.58,103.14 137.08,102.65 136.52,102.65
  TOP w0.13: 136.52,102.65 v1(133.5,102.65) 132.94,102.65 127.49,108.1 126,108.1
  BOTTOM w0.102: UV15.K11 v2(145.47,101.01) ; v2(119.72,109.94) 119.26,109.47 119.26,108.54 UV1.H11
M1_MA5: length 30.1
  TOP w0.102: 126,107.52 125.5,107.52 125.18,107.85 122.73,107.85 121.91,108.67 121.78,108.67 121.55,108.89 121.55,109.05 121.15,109.45 120.83,109.45 120.55,109.17 v2(120.55,108.73) ; 136.52,102.19 136.91,102.19 137.66,102.94 143.33,102.94 144.4,101.87 144.97,101.87 v2(145.01,101.91)
  TOP w0.13: 136.52,102.19 v1(135.4,102.19) 132.75,102.19 127.41,107.52 126,107.52
  BOTTOM w0.102: v2(145.01,101.91) 145.07,101.85 UV15.K10 ; v2(120.55,108.73) 120.5,108.68 UV1.G11
M1_MA6: length 32.8
  TOP w0.102: v2(145.22,104.76) 144.01,103.55 137.73,103.55 137.71,103.57 136.52,103.57 ; 126,109.46 125.74,109.72 124.34,109.72 124.21,109.59 123.38,109.59 122.6,110.36 122.04,110.36 121.96,110.44 119.62,110.44 v2(119.05,109.87)
  TOP w0.13: 126,109.46 126.45,109.01 127.87,109.01 v1(129.33,107.55) 133.32,103.57 136.52,103.57
  BOTTOM w0.102: v2(119.05,109.87) 118.96,109.87 118.54,110.28 118.54,111.1 118.9,111.45 UV1.J16 ; v2(145.22,104.76) 145.07,104.9 UV15.K5
M1_MA7: length 33.7
  TOP w0.102: v2(145.39,105.81) 144.8,105.22 144.8,104.73 143.85,103.78 137.88,103.78 137.63,104.03 136.52,104.03 ; 126,110.11 125.93,110.18 124.51,110.18 124.12,109.79 123.46,109.79 122.69,110.57 122.12,110.57 122.04,110.65 119.54,110.65 119.53,110.64 119.53,110.64 119.15,110.25 118.64,110.25 v2(118.32,109.94)
  TOP w0.13: 126,110.11 126.64,109.47 128.28,109.47 v1(131.42,106.33) 133.73,104.03 136.52,104.03
  BOTTOM w0.102: v2(118.32,109.94) 118.07,109.94 117.3,110.7 UV1.L15 ; UV15.K4 145.07,106.13 v2(145.39,105.81)
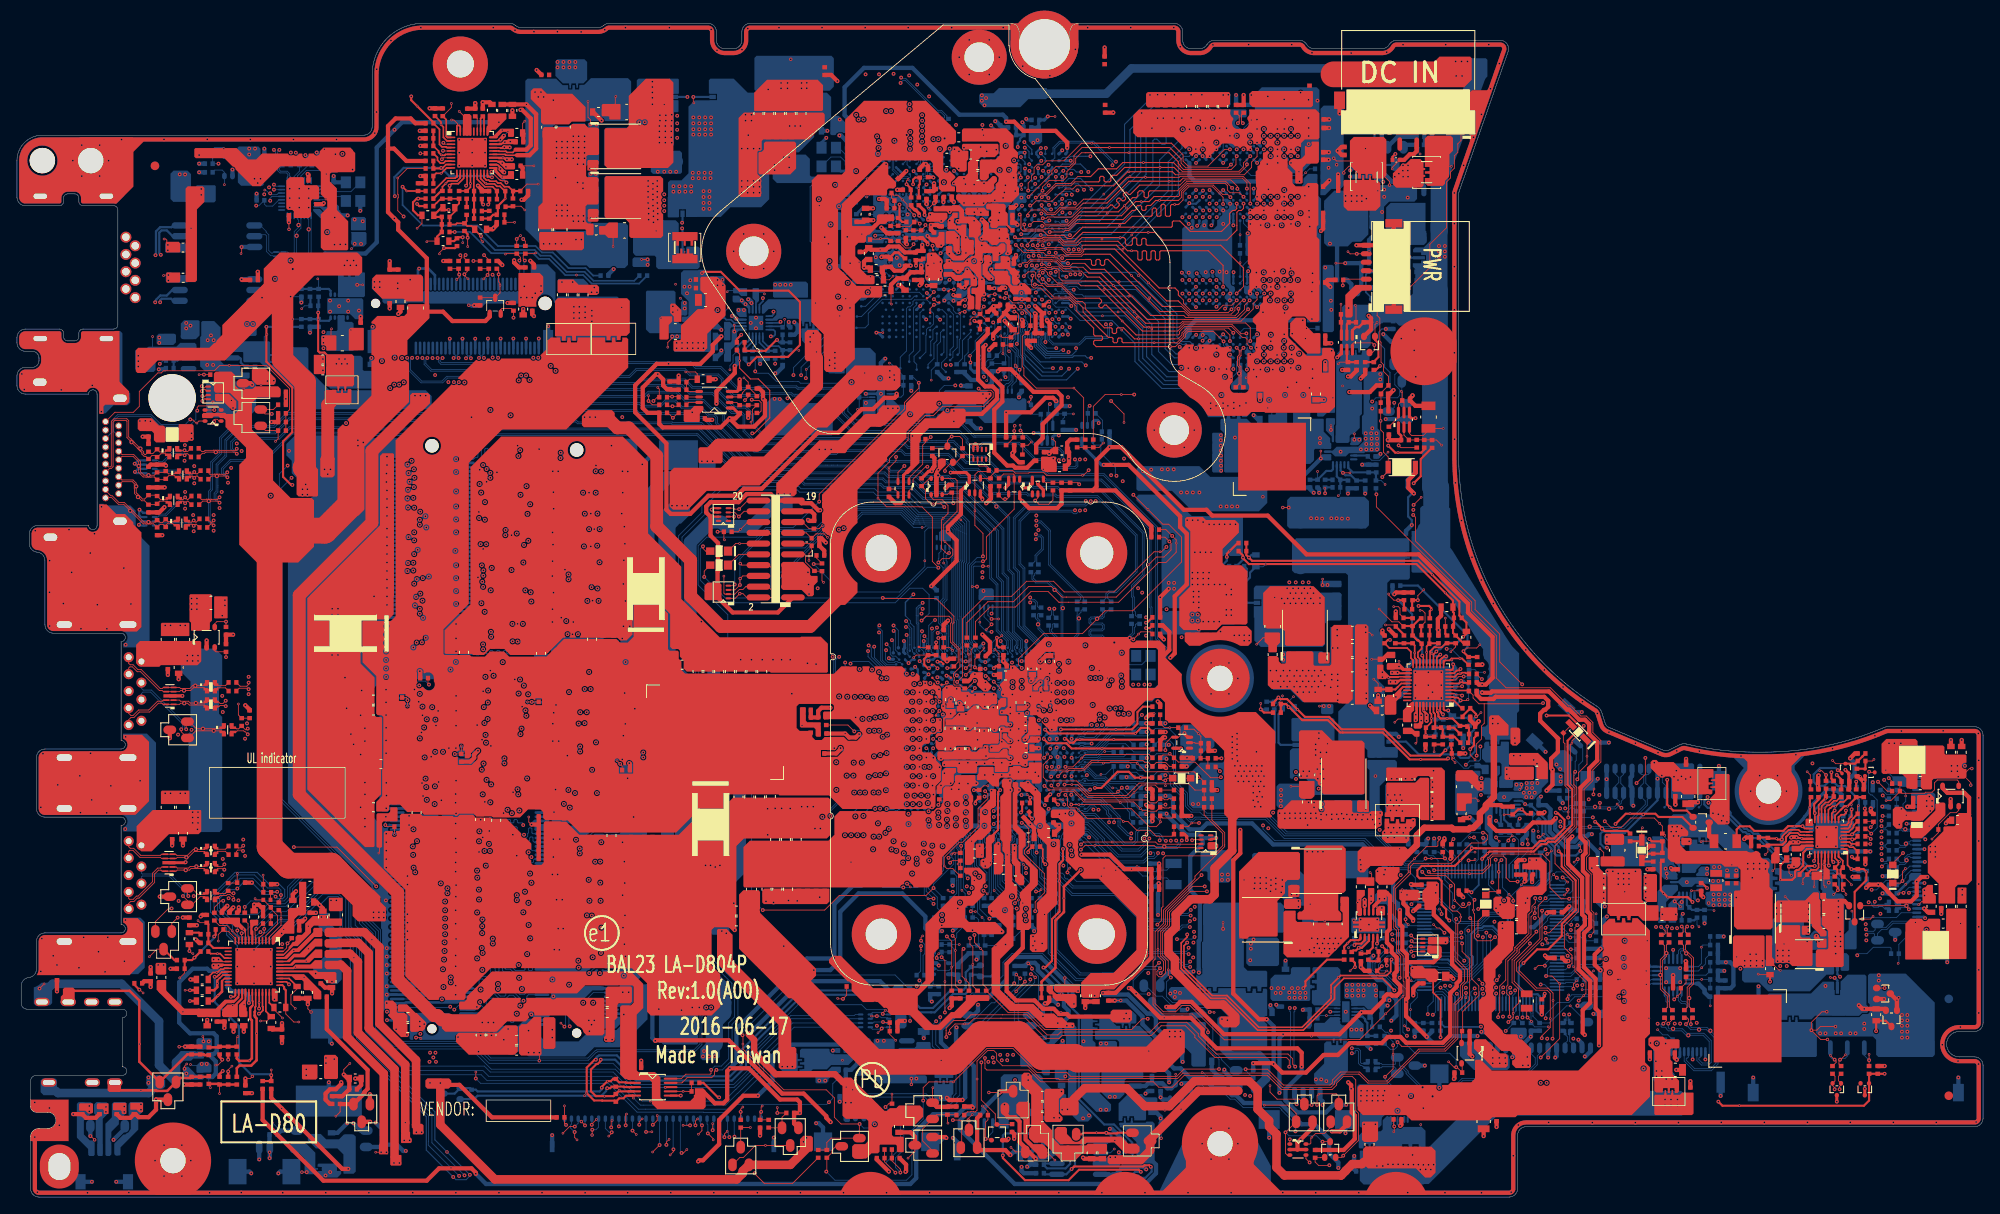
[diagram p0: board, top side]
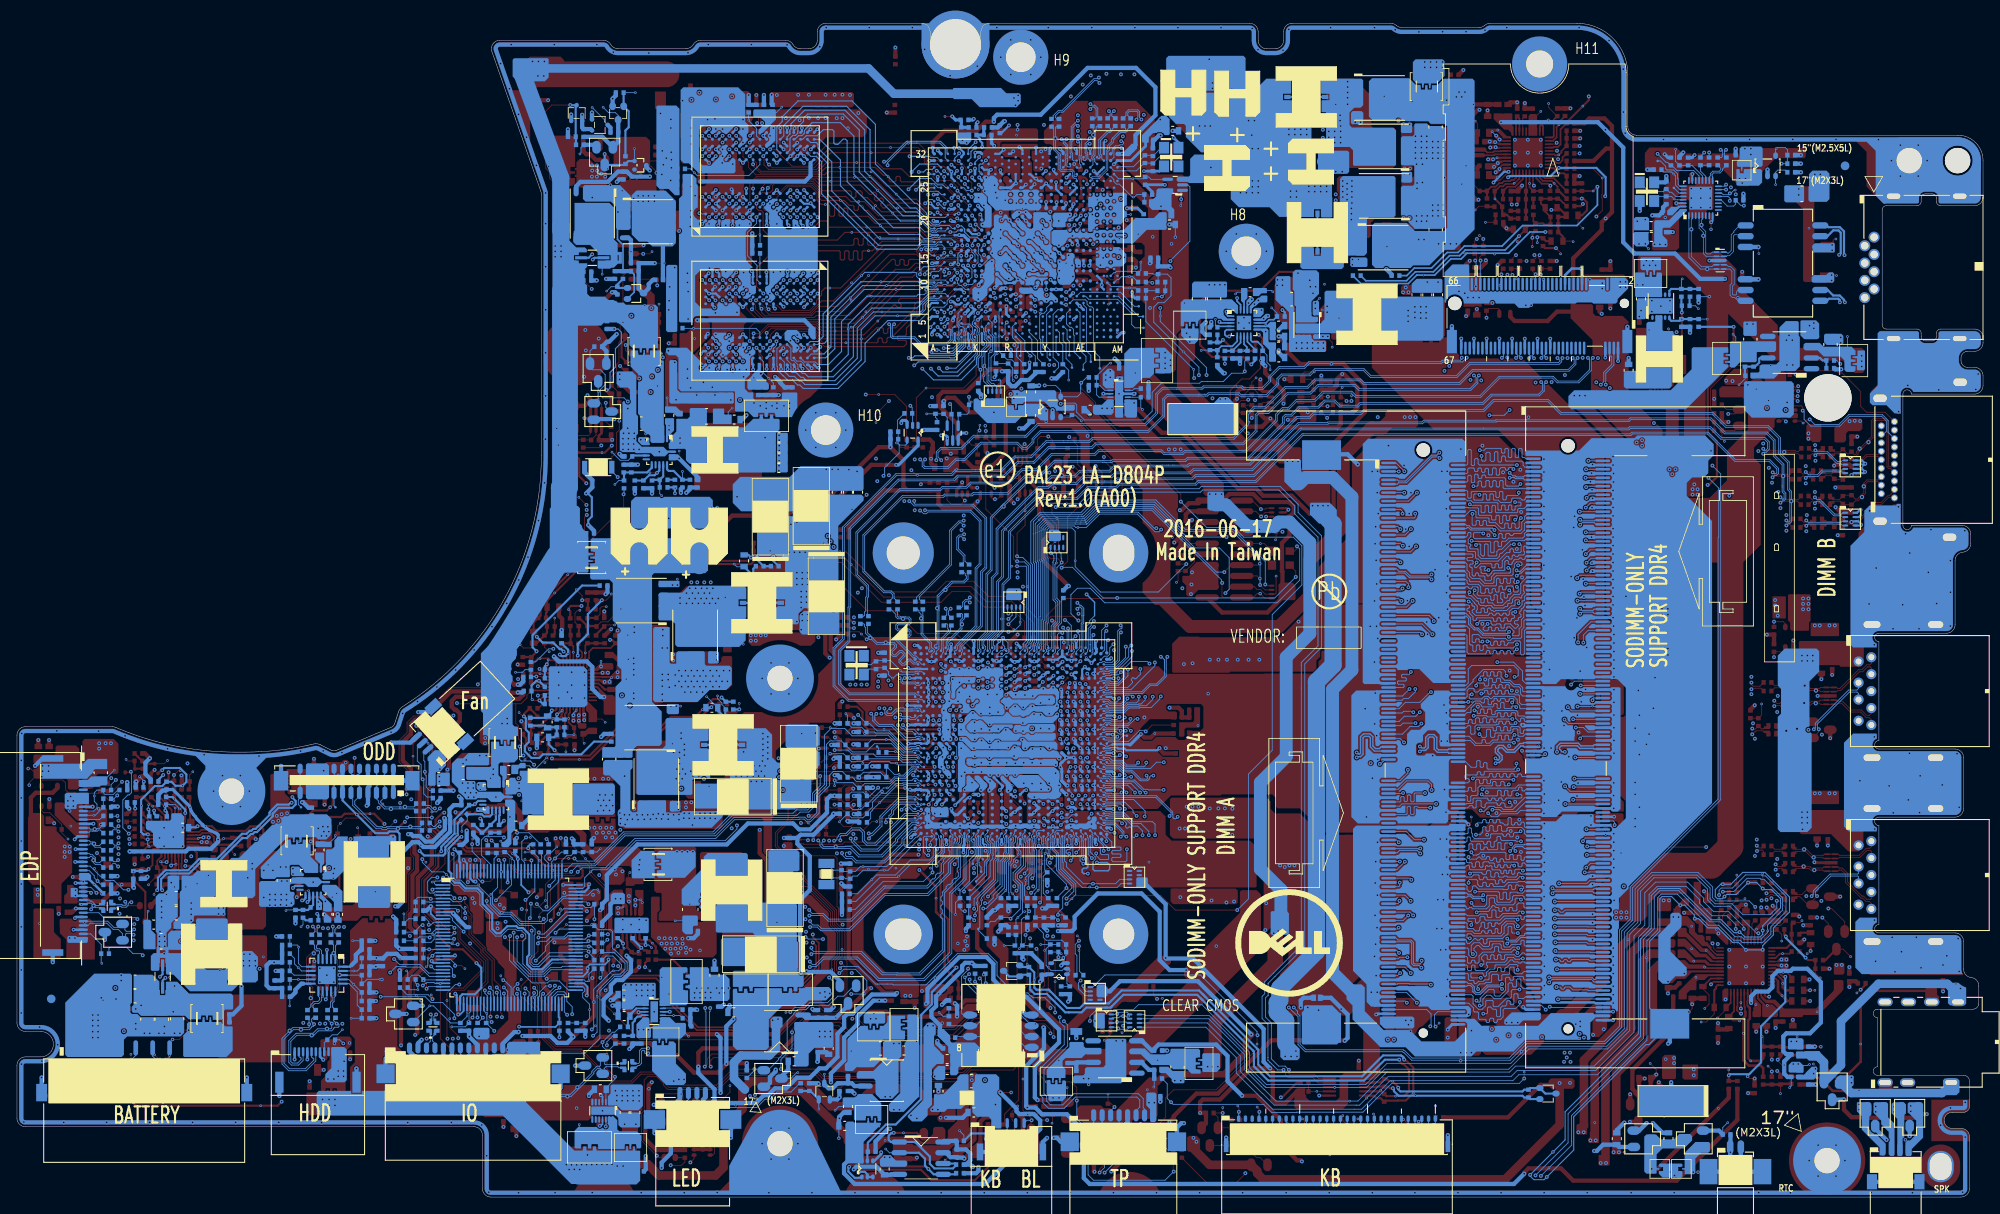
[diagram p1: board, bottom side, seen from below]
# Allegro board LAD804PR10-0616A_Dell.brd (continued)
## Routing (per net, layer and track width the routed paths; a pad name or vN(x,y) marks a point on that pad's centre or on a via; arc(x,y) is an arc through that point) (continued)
M1_MA8: length 30.7
  TOP w0.102: v2(120.53,111.08) 120.73,110.88 122.23,110.88 122.28,110.83 122.71,110.83 123.12,110.42 123.57,110.42 123.79,110.64 126,110.64 ; 136.52,104.49 137.67,104.49 138.17,103.98 143.67,103.98 144.08,104.39 v2(144.08,104.81)
  TOP w0.13: 126,110.64 126.61,110.64 126.74,110.51 126.74,110.09 126.89,109.93 127.13,109.93 127.26,110.06 127.26,110.51 127.39,110.64 127.65,110.64 127.78,110.51 127.78,110.09 127.93,109.93 128.16,109.93 128.29,110.06 128.29,110.51 128.42,110.64 128.69,110.64 v1(133.51,105.82) 134.84,104.49 136.52,104.49
  BOTTOM w0.102: UV1.G14 120.53,110.53 v2(120.53,111.08) ; v2(144.08,104.81) 144.27,105.01 UV15.J5
M_ADBI0: length 32.6
  TOP w0.127: v2(144.67,117.23) 144.67,116.67 144.42,116.41 144.1,116.41 143.89,116.2 143.89,114.65 ; 126,113.83 125.73,113.83 124.69,112.79 123.47,112.79 123.01,113.25 121.05,113.25 120.92,113.13 117.85,113.13 v2(117.71,113.26)
  TOP w0.13: 143.89,114.65 143.89,114.1 142.71,112.92 135.15,112.92 134.24,113.83 v1(133.43,113.83) 126,113.83
  BOTTOM w0.102: UV1.L18 117.71,113.29 v2(117.71,113.26) ; UV13.J4 144.29,117.61 v2(144.67,117.23)
M_ADBI1: length 32.9
  TOP w0.102: 126,111.25 125.79,111.25 125.57,111.02 123.6,111.02 123.44,111.18 123.12,111.18 122.98,111.04 122.36,111.04 122.32,111.08 121.43,111.08 121.05,111.46 118.7,111.46 v2(117.81,112.35) ; 136.52,105.1 137.34,105.1 138.26,104.18 143.22,104.18 143.66,104.62 143.66,104.93 144.53,105.81 v2(144.74,105.81)
  TOP w0.13: 136.52,105.1 135.1,105.1 v1(131.47,108.73) 128.94,111.25 126,111.25
  BOTTOM w0.102: v2(144.74,105.81) 144.33,106.21 UV15.J4 ; v2(117.81,112.35) 118.1,112.06 UV1.K16
M_CAS#0: length 31.2
  TOP w0.102: v2(142.26,117.18) 142.26,117.97 141.02,119.21 138.21,119.21 137.55,118.54 137.55,117.66 137.08,117.2 ; v2(121.81,113.87) 123.46,113.87 123.64,114.05 124.07,114.05 124.89,114.88 126,114.88
  TOP w0.13: 126,114.88 130.66,114.88 131.51,115.73 133.77,115.73 133.9,115.86 133.9,116.54 134.06,116.7 134.27,116.7 134.42,116.54 134.42,115.86 134.55,115.73 134.81,115.73 134.94,115.86 134.94,117.01 135.07,117.14 135.3,117.14 135.46,116.99 135.46,115.86 135.59,115.73 135.93,115.73 136.06,115.86 136.06,116.99 136.19,117.12 v1(136.55,117.12) 137,117.12 137.08,117.2
  BOTTOM w0.102: v2(142.26,117.18) 142.63,116.81 UV13.L3 ; v2(121.81,113.87) 121.11,113.87 120.89,114.1 UV1.G19
M_CAS#1: length 33
  TOP w0.102: v2(120.87,110.06) 121.19,110.06 121.57,109.68 121.97,109.68 122.06,109.77 122.91,109.77 123.42,109.26 125.55,109.26 126,108.81 ; v2(146.27,106.61) 146.27,105.88 145.82,105.43 145.82,104.79 144.37,103.35 137.49,103.35 137.25,103.11 136.52,103.11
  TOP w0.13: 126,108.81 126.26,108.55 127.68,108.55 v1(131.77,104.46) 133.13,103.11 136.52,103.11
  BOTTOM w0.102: UV15.L3 v2(146.27,106.61)
  BOTTOM w0.127: UV1.G16 120.92,111.28 120.92,110.11 v2(120.87,110.06)
M_CKE0: length 33
  TOP w0.127: v2(143.87,117.23) 143.87,116.63 143.66,116.41 143.38,116.41 143.02,116.06 143.02,114.89 142.78,114.65 ; v2(118.28,115.94) 118.42,115.8 118.42,114.25 118.68,113.99 121.06,113.99 121.57,113.48 123.51,113.48 123.88,113.11 124.36,113.11 125.7,114.44 126,114.44
  TOP w0.13: 142.78,114.65 142.08,113.95 138.39,113.95 137.16,115.18 136.41,115.18 136.28,115.05 136.28,114.57 136.15,114.44 v1(131.66,114.44) 126,114.44
  BOTTOM w0.102: v2(143.87,117.23) 144.27,116.83 UV13.J3
  BOTTOM w0.127: UV1.K20 118.1,115.76 v2(118.28,115.94)
M_CKE1: length 35.6
  TOP w0.102: v2(119.19,112.29) 119.19,112.42 119.69,112.91 121.01,112.91 121.14,113.04 122.92,113.04 123.38,112.57 124.96,112.57 125.6,113.22 126,113.22 ; v2(143.86,106.62) 144.67,107.43 144.67,109.3
  TOP w0.13: 126,113.22 v1(130.13,113.22) 130.56,113.22 130.74,113.04 130.74,112.53 130.95,112.31 131.43,112.31 131.56,112.44 131.56,113.07 131.69,113.2 131.95,113.2 132.08,113.07 132.08,112.44 132.21,112.31 132.53,112.31 132.66,112.44 132.66,112.99 132.79,113.12 133.05,113.12 133.18,112.99 133.18,112.44 133.31,112.31 141.99,112.31 144.67,109.62 144.67,109.3
  BOTTOM w0.102: v2(143.86,106.62) 144.25,107.01 UV15.J3
  BOTTOM w0.127: v2(119.19,112.29) 119.19,112.61 UV1.J17
M_CLK0: length 34.4
  TOP w0.114: RV79.2 144.17,127.58 144.17,126.87 v2(144.01,126.72)
  IN1 w0.147: v2(144.01,126.72) 144.19,126.54 144.19,126.27 144.39,126.07 144.39,124.66 144.13,124.4 144.13,123.89 v2(143.87,123.63)
  IN2 w0.147: v2(143.87,123.63) 144.28,123.22 144.28,121.7 144.39,121.59 144.39,121.14 144.05,120.79 144.03,120.8 143.02,120.8 142.51,121.3 127.52,121.3 126.56,120.35 124.46,120.35 123.85,119.75 122.44,119.75 122.06,120.13 121.23,120.13 121.07,119.97 120.4,119.97 v2(120.1,120.27)
  BOTTOM w0.102: UV13.J12 144.25,124.01 v2(143.87,123.63) ; UV1.H26 119.73,119.9 v2(120.1,120.27)
M_CLK1: length 36.5
  TOP w0.114: v2(144.67,100.21) 144.37,99.91 144.37,99.29 144.17,99.08 144.17,98.19 144.36,97.99 144.36,97.49 144.39,97.46 144.39,96.89 144.36,96.85 144.36,95.84 RV85.2
  IN2 w0.147: v2(120.9,105.9) 120.78,105.78 120.78,102.59 122,101.36 124.94,101.36 125.64,102.07 133.99,102.07 134.65,102.73 143.69,102.73 144.16,102.26 144.16,101.88 144.3,101.74 144.3,100.58 v2(144.67,100.21)
  BOTTOM w0.102: v2(120.9,105.9) UV1.G9 ; UV15.J12 v2(144.67,100.21)
M_CLK#0: length 34.7
  TOP w0.114: v2(144.6,126.72) 144.42,126.9 144.42,127.68 RV80.2
  IN1 w0.147: v2(144.6,126.72) 144.48,126.6 144.48,126.39 144.67,126.19 144.67,124.54 144.41,124.28 144.41,123.89 v2(144.67,123.63)
  IN2 w0.147: v2(144.67,123.63) 144.56,123.52 144.56,121.82 144.67,121.71 144.67,121.02 144.17,120.51 143.91,120.51 142.9,120.51 142.4,121.02 127.64,121.02 126.68,120.06 124.57,120.06 123.97,119.46 122.32,119.46 121.94,119.84 121.35,119.84 121.18,119.68 120.23,119.68 v2(120.1,119.55)
  BOTTOM w0.102: UV1.H25 120.1,119.5 v2(120.1,119.55) ; v2(144.67,123.63) 144.27,123.23 UV13.J11
M_CLK#1: length 36.5
  TOP w0.114: RV86.2 144.15,95.95 v3(144.15,97.17) 144.15,97.91 143.96,98.1 143.96,99.16 144.17,99.37 144.17,99.91 v2(143.87,100.21)
  IN2 w0.147: v2(120.1,105.9) 120.1,105.88 120.49,105.49 120.49,102.47 121.89,101.08 125.06,101.08 125.76,101.78 134.1,101.78 134.77,102.44 143.57,102.44 143.87,102.14 143.87,101.76 144.01,101.62 144.01,100.35 v2(143.87,100.21)
  BOTTOM w0.102: v2(120.1,105.9) UV1.H9 ; UV15.J11 v2(143.87,100.21)
M_CS0B#0: length 31.9
  TOP w0.102: v2(119.5,117) 119.67,117 120.23,117.56 121.11,117.56 121.17,117.5 122.08,117.5 122.96,118.38 123.08,118.38 123.65,118.95 124.54,118.95 124.92,119.33 126,119.33 ; 136.65,120.63 144.76,120.63 145.63,121.49 145.63,122.13 146.27,122.77 v2(146.27,123.63)
  TOP w0.127: 136.65,120.63 136.52,120.76
  TOP w0.13: 136.52,120.76 136.29,120.99 v1(131.15,120.99) 131,120.99 129.34,119.33 128.3,119.33 128.29,119.33 126,119.33
  BOTTOM w0.102: v2(146.27,123.63) 145.89,124.01 UV13.G12 ; UV1.H22 119.7,116.81 v2(119.5,117)
M_CS1B#0: length 33.7
  TOP w0.102: 126,103.52 124.92,104.6 124.92,105.12 124.06,105.99 122.02,105.99 120.73,107.27 119.94,107.27 119.68,107.52 119.68,108.19 119.78,108.29 v2(119.78,108.73) ; v2(142.32,100.97) 142.3,100.97 141.14,102.13 138.14,102.13 137.82,101.8 137.82,101.52 136.64,100.35 136.52,100.35
  TOP w0.13: 126,103.52 126.99,102.53 126.99,101.77 127.15,101.62 127.91,101.62 128.04,101.49 128.04,101.23 127.91,101.1 127.12,101.1 126.99,100.97 126.99,100.65 127.3,100.35 v1(136.1,100.35) 136.52,100.35
  BOTTOM w0.102: v2(142.32,100.97) 142.32,100.48 142.67,100.13 UV15.G12 ; v2(119.78,108.73) 119.93,108.73 UV1.G13
M_DA0: length 61
  IN2 w0.168: v2(151.4,116.09) 153.39,118.08 153.39,128.49 152.9,128.98 152.9,129.55 150.51,131.94 126.32,131.94 124.17,129.78 120.18,129.78 117.16,126.76 117.16,123.36 117.61,122.9 v2(117.61,122.33)
  BOTTOM w0.102: 151.34,116.03 151.32,116.01 UV13.A2
  BOTTOM w0.127: v2(117.61,122.33) 118.05,121.89 118.3,121.89 118.42,121.77 118.42,121.02 UV1.K27
  BOTTOM w0.13: 151.34,116.03 v2(151.4,116.09)
M_DA1: length 57.9
  IN2 w0.168: v2(118.42,122.72) 117.63,123.5 117.63,126.56 120.38,129.3 124.36,129.3 126.52,131.46 149.5,131.46 152.8,128.16 152.8,118.43 151.34,116.96
  IN2 w0.175: 151.34,116.96 150.27,115.9 v2(150.27,115.63)
  BOTTOM w0.102: UV13.B2 149.89,116.01 v2(150.27,115.63)
  BOTTOM w0.127: v2(118.42,122.72) 118.42,122.72 118.42,122.59 118.9,122.12 UV1.J29
M_DA2: length 52
  IN2 w0.168: 151.34,118.29 151.82,118.78 151.82,128.19 149.02,130.99 126.72,130.99 124.46,128.73 121.17,128.73 118.36,125.92 118.36,124.35 v2(118.87,123.83)
  IN2 w0.175: 151.34,118.29 v2(151.07,118.03)
  BOTTOM w0.102: UV13.A4 150.67,117.63 v2(151.07,118.03)
  BOTTOM w0.127: UV1.H30 119.7,122.33 119.38,122.66 119.38,123.35 118.9,123.83 v2(118.87,123.83)
M_DA3: length 48.3
  IN2 w0.102: 150.69,125.62 150.69,118.45 v2(150.27,118.03)
  IN2 w0.168: 118.83,124.99 118.83,125.37 121.55,128.1 124.49,128.1 126.91,130.52 147.68,130.52 150.88,127.32 150.88,125.81 150.69,125.62
  IN2 w0.175: 118.83,124.99 118.82,124.98 v2(118.82,124.48)
  BOTTOM w0.102: UV13.B4 149.87,117.63 v2(150.27,118.03)
  BOTTOM w0.127: v2(118.82,124.48) 119.7,123.6 UV1.H32
M_DA4: length 46.5
  IN2 w0.102: 144.97,124.82 145.66,124.82 145.89,124.59 145.89,124.27 146.11,124.05 146.43,124.05 146.69,123.79 146.69,116.05 v2(146.27,115.63)
  IN2 w0.168: 137.16,124.9 131.35,124.9 131.18,124.73 131.18,123.35 131.01,123.18 130.67,123.18 130.5,123.35 130.5,124.73 130.34,124.9 129.99,124.9 129.83,124.73 129.83,123.35 129.66,123.18 129.32,123.18 129.15,123.35 129.15,124.73 128.98,124.9 128.64,124.9 128.48,124.73 128.48,123.35 128.31,123.18 127.97,123.18 127.8,123.35 127.8,124.73 127.63,124.9 127.06,124.9 126.12,123.96 126,123.96
  IN2 w0.175: 144.97,124.82 144.96,124.81 142.9,124.81 142.4,125.31 139.12,125.31 138.72,124.9 137.16,124.9 ; v2(120.82,122.27) 121.13,122.59 123.25,122.59 124.61,123.96 126,123.96
  BOTTOM w0.102: v2(146.27,115.63) 146.65,116.01 UV13.F2
  BOTTOM w0.127: v2(120.82,122.27) 120.82,122.22 UV1.G29
M_DA5: length 47.8
  IN2 w0.102: 144.65,124.31 144.91,124.05 145.59,124.05 145.85,123.79 145.85,119.51 145.49,119.15 145.49,117.94 146.2,117.23 v2(146.27,117.23)
  IN2 w0.168: 122.31,121.89 122.51,121.7 124.77,121.7 124.94,121.86 124.94,122.89 125.1,123.05 125.59,123.05 125.76,122.89 125.76,121.86 125.93,121.7 126.78,121.7 127.79,122.71 131.74,122.71 131.9,122.88 131.9,124.11 132.07,124.28 132.41,124.28 132.58,124.11 132.58,122.88 132.75,122.71 133.09,122.71 133.26,122.88 133.26,124.11 133.42,124.28 133.76,124.28 133.93,124.11 133.93,122.88 134.1,122.71 134.44,122.71 134.61,122.88 134.61,124.11 134.77,124.28 135.12,124.28 135.28,124.11 135.28,122.88 135.45,122.71 136,122.71 136.17,122.88 136.17,123.96 136.34,124.13 136.68,124.13 136.85,123.96 136.85,122.88 137.01,122.71 137.58,122.71 137.78,122.91 137.78,123.9 138.09,124.22
  IN2 w0.175: 122.31,121.89 121.77,121.89 v2(121.68,121.8) ; 138.09,124.22 138.78,124.22 139.41,124.85 142.01,124.85 142.55,124.31 144.65,124.31
  BOTTOM w0.102: UV13.F4 146.65,117.61 v2(146.27,117.23)
  BOTTOM w0.127: UV1.F28 121.6,121.8 v2(121.68,121.8)
M_DA6: length 45.8
  IN2 w0.102: v2(147.87,117.23) 148.25,117.61 148.25,118.19 148.2,118.23 148.2,122.62 148.25,122.67 148.25,125.39 147.66,125.98
  IN2 w0.168: 147.66,126.07 147.15,126.57 145.82,126.57 144.61,127.78 142.3,127.78 142.06,127.54 142.06,127.03 141.83,126.8 140.86,126.8 140.6,127.06 140.6,127.41 140.23,127.78 139.26,127.78 139.09,127.61 139.09,126.73 138.92,126.56 138.09,126.56 137.94,126.71 137.94,127.6 137.75,127.78 136.16,127.78 135.83,127.45 135.83,127.01 136.07,126.78 136.73,126.78 136.85,126.65 136.85,126.16 136.71,126.02 135.78,126.02 135.08,126.72 127.16,126.72 125.74,125.3 122.87,125.3 122.15,124.59
  IN2 w0.175: 147.66,126.07 147.66,125.98 ; v2(121.35,123.79) 122.15,124.59
  BOTTOM w0.102: UV13.E4 147.49,117.61 v2(147.87,117.23)
  BOTTOM w0.127: v2(121.35,123.79) 121.34,123.79 121.34,123.8 121.3,123.76 UV1.F32
M_DA7: length 46
  IN2 w0.102: 145.66,125.65 146.39,125.65 146.65,125.39 146.65,125.11 146.91,124.85 147.19,124.85 147.45,124.59 147.45,122.41 147.09,122.05 147.09,118.55 147.45,118.19 147.45,116.11 147.44,116.1 147.44,116.05 147.07,115.68 v2(147.07,115.63)
  IN2 w0.168: 126,124.64 126.1,124.64 126.86,125.4 127.26,125.4 127.42,125.57 127.42,125.98 127.59,126.15 127.93,126.15 128.1,125.98 128.1,125.57 128.27,125.4 128.61,125.4 128.78,125.57 128.78,125.98 128.94,126.15 129.28,126.15 129.45,125.98 129.45,125.57 129.62,125.4 129.96,125.4 130.13,125.57 130.13,125.98 130.29,126.15 130.63,126.15 130.8,125.98 130.8,125.57 130.97,125.4 131.31,125.4 131.48,125.57 131.48,125.98 131.65,126.15 131.99,126.15 132.15,125.98 132.15,125.57 132.32,125.4 132.66,125.4 132.83,125.57 132.83,125.98 133,126.15 133.34,126.15 133.5,125.98 133.5,125.57 133.67,125.4 134.01,125.4 134.18,125.57 134.18,125.98 134.35,126.15 134.69,126.15 134.86,125.98 134.86,125.57 135.02,125.4 137.16,125.4
  IN2 w0.175: 126,124.64 123.68,124.64 122.2,123.16 v2(120.77,123.16) ; 145.66,125.65 145.62,125.65 145.61,125.66 145.27,125.66 145.25,125.65 138.54,125.65 138.29,125.4 137.16,125.4
  BOTTOM w0.102: UV13.E2 147.45,116.01 v2(147.07,115.63)
  BOTTOM w0.127: v2(120.77,123.16) 120.77,123.1 121.3,122.57 UV1.F30
M_DA8: length 30.9
  IN1 w0.168: v2(126.61,122.81) 126.61,123.53 128.26,125.18 132.89,125.18 133.05,125.35 133.05,126.41 133.22,126.57 133.56,126.57 133.73,126.41 133.73,125.35 133.89,125.18 141.56,125.18 142.47,124.27 142.47,123.44 143.53,122.38 145.83,122.38 v2(147.07,123.63)
  BOTTOM w0.102: v2(147.07,123.63) 146.67,123.23 UV13.F11 ; 124.47,122.81 124.28,122.81 124.15,122.68 123.39,122.68 123.01,122.3 UV1.C30
  BOTTOM w0.127: 124.47,122.81 126,122.81
  BOTTOM w0.13: 126,122.81 v2(126.61,122.81)
M_DA9: length 41.4
  IN1 w0.145: v2(121.02,121.1) 121.02,121.91 121.22,122.11 121.22,122.87 121.94,123.59
  IN1 w0.168: v2(150.27,125.23) 150.88,125.84 150.88,127.48 146.75,131.61 128.3,131.61 121.94,125.25 121.94,123.59
  BOTTOM w0.102: UV13.B13 149.87,124.83 v2(150.27,125.23)
  BOTTOM w0.127: v2(121.02,121.1) 121.3,120.82 UV1.F27
M_DA10: length 29.5
  IN1 w0.168: v2(147.87,123.63) 146.95,122.71 146.95,121.91 146.36,121.32 144.77,121.32 144.19,121.89 143.86,121.89 143.39,121.42 143.02,121.42 142.82,121.61 134.52,121.61 131.78,124.35 129.08,124.35 126.16,121.43 126,121.43 v2(125.53,120.96)
  BOTTOM w0.102: UV13.E11 147.47,123.23 v2(147.87,123.63)
  BOTTOM w0.127: v2(125.53,120.96) 124.95,120.96 124.65,121.26 123.94,121.26 UV1.A28
M_DA11: length 31.9
  IN1 w0.168: v2(150.27,122.83) 149.66,122.22 149.66,121.58 149.01,120.92 134.04,120.92 131.34,123.62 129.15,123.62 126.49,120.97 v2(126.37,120.97)
  BOTTOM w0.102: UV13.B11 149.89,123.21 v2(150.27,122.83)
  BOTTOM w0.127: UV1.C28 122.92,121.5 123.31,121.89 125.44,121.89 126,121.33
  BOTTOM w0.13: 126,121.33 v2(126.37,120.97)
M_DA12: length 37.9
  IN1 w0.145: 122.51,123.8 122.51,121.11 v2(122.55,121.07)
  IN1 w0.168: v2(147.87,125.23) 148.23,125.59 148.23,128.57 146.02,130.78 130.98,130.78 130.81,130.61 130.81,130.51 130.64,130.35 130.17,130.35 129.97,130.54 129.97,130.58 129.81,130.75 128.59,130.75 122.51,124.67 122.51,123.8
  BOTTOM w0.102: UV1.E27 122.47,121.07 v2(122.55,121.07) ; v2(147.87,125.23) 147.47,124.83 UV13.E13
M_DA13: length 45.1
  IN1 w0.145: 121.01,124.99 121.01,124.71 119.96,123.67 119.96,121.31 120.86,120.41 v2(120.86,120.38)
  IN1 w0.168: v2(151.07,125.23) 151.59,125.75 151.59,128.16 147.46,132.29 128.31,132.29 121.01,124.99
  BOTTOM w0.102: v2(151.07,125.23) 150.67,124.83 UV13.A13 ; UV1.G26 120.86,120.26 v2(120.86,120.38)
M_DA14: length 36
  IN1 w0.145: v2(122.54,120.38) 123.02,120.86 123.02,122.32 122.83,122.51 122.83,124.1 123.72,124.99
  IN1 w0.168: v2(147.07,125.23) 147.66,125.81 147.66,128.16 146.22,129.6 128.33,129.6 123.72,124.99
  BOTTOM w0.102: v2(147.07,125.23) 146.67,124.83 UV13.F13
  BOTTOM w0.127: UV1.D26 122.54,119.94 v2(122.54,120.38)
M_DA15: length 34.6
  IN1 w0.168: v2(121.69,119.38) 125.73,119.38 129.32,122.97 131.02,122.97 133.64,120.35 149.52,120.35 151.07,121.91 v2(151.07,122.83)
  BOTTOM w0.102: UV1.F25 121.38,119.1 121.66,119.38 v2(121.69,119.38) ; v2(151.07,122.83) 150.69,123.21 UV13.A11
M_DA16: length 21.5
  IN2 w0.168: v2(141.47,117.23) 141.47,119.01 140.39,120.1 137.85,120.1 137.65,120.3 127.86,120.3 126.96,119.4 125.71,119.4 v2(125.09,118.78)
  BOTTOM w0.102: v2(125.09,118.78) 125.03,118.72 124.58,118.72 124.2,119.1 UV1.A25 ; v2(141.47,117.23) 141.85,117.61 UV13.M4
M_DA17: length 18.2
  IN2 w0.168: v2(125.86,118.85) 126.48,118.23 128.18,118.23 128.89,118.93 138.17,118.93 v2(139.07,118.03)
  BOTTOM w0.102: UV1.C25 123.27,119.1 123.71,119.54 124.01,119.54 ; UV13.T4 138.67,117.63 v2(139.07,118.03)
  BOTTOM w0.127: 124.01,119.54 124.03,119.57 125.14,119.57 v2(125.86,118.85)
M_DA18: length 23
  IN2 w0.168: v2(140.67,117.23) 141.09,117.65 141.09,119 140.7,119.39 137.6,119.39 137.38,119.61 127.91,119.61 127.21,118.91 v2(126.74,118.91)
  BOTTOM w0.102: UV13.N4 141.05,117.61 v2(140.67,117.23) ; UV1.E25 122.35,119.1 122.69,119.44 123.32,119.44 124.03,120.16
  BOTTOM w0.127: 126,119.65 125.45,120.2 124.08,120.2 124.03,120.16
  BOTTOM w0.13: 126,119.65 v2(126.74,118.91)
M_DA19: length 17.5
  IN2 w0.168: v2(124.42,118.27) 124.7,118 125.15,118 125.25,117.89 125.85,117.89 126.2,117.54 128.46,117.54 129.17,118.25 136.95,118.25 137.17,118.03 v2(138.27,118.03)
  BOTTOM w0.102: v2(138.27,118.03) 137.87,117.63 UV13.U4 ; UV1.D24 122.87,118.3 123.25,118.68 124.19,118.68 124.42,118.45 v2(124.42,118.27)
M_DA20: length 18.9
  IN2 w0.168: v2(138.27,115.63) 136.83,114.19 125.54,114.19 123.73,116.01 123.73,116.36 123.36,116.73 122.95,116.73 v2(122.49,117.2)
  BOTTOM w0.102: v2(122.49,117.2) 122.4,117.2 UV1.E23 ; v2(138.27,115.63) 138.65,116.01 UV13.T2
M_DA21: length 23.9
  IN2 w0.168: v2(140.67,115.63) 140.45,115.41 140.45,114.29 139.88,113.71 125.26,113.71 124.19,114.78 123.31,114.78 122,116.1 121.57,116.1 121.33,116.34 121.33,116.68 121.57,116.92 121.58,116.92 v2(121.73,117.07)
  BOTTOM w0.102: UV13.N2 141.05,116.01 v2(140.67,115.63) ; UV1.F23 v2(121.73,117.07)
M_DA22: length 17.1
  IN2 w0.168: v2(123.26,117.18) 123.46,117.18 123.89,116.75 124.47,116.75 124.77,116.45 124.77,115.87 125.54,115.1 136.94,115.1 v2(137.46,115.62)
  BOTTOM w0.102: v2(137.46,115.62) 137.85,116.01 UV13.U2
  BOTTOM w0.127: v2(123.26,117.18) 123.09,117.18 122.61,116.7 UV1.D22
M_DA23: length 25.1
  IN2 w0.168: v2(141.51,115.63) 141.51,113.95 140.98,113.42 140.98,113.41 140.58,113.02 137.84,113.02 137.61,113.24 125.05,113.24 124.16,114.13 123.46,114.13 121.78,115.81 121.4,115.81 121.15,116.06 v2(120.82,116.06)
  BOTTOM w0.102: UV13.M2 141.87,115.99 v2(141.51,115.63)
  BOTTOM w0.127: v2(120.82,116.06) 121.14,116.06 UV1.F21
M_DA24: length 33.6
  BOTTOM w0.102: 126,117.26 125.77,117.26 124.61,116.1 124.61,115.97 124.23,115.6 122.4,115.6 UV1.E21
  BOTTOM w0.13: UV13.M11 142.28,123.62 142.28,126.27 141.63,126.91 141.63,127.48 139.77,129.34 133.41,129.34 130.64,126.58 130.64,121.89 v1(129.14,120.39) 126,117.26
M_DA25: length 30.2
  BOTTOM w0.102: 126,116.7 125.85,116.7 123.95,114.81 123.49,114.81 123.46,114.78 123.17,114.78 122.98,114.97 122.98,114.99 122.87,115.1 UV1.D20
  BOTTOM w0.13: 126,116.7 126.55,116.7 v1(128.2,118.35) 131.28,121.43 131.28,125.94 134.04,128.71 139.18,128.71 141.45,126.44 141.45,125.23 UV13.M13
M_DA26: length 30.7
  BOTTOM w0.102: UV1.F19 121.57,114.3 121.91,114.64 123.03,114.64 123.08,114.58 123.55,114.58 123.57,114.6 124.1,114.6 125.74,116.24
  BOTTOM w0.13: 125.74,116.24 127.1,116.24 v1(131.27,120.41) 131.91,121.05 131.91,125.93 134.23,128.25 138.99,128.25 140.61,126.63 140.61,126.05 140.74,125.92 140.74,125.76 140.73,125.75 140.73,125.47 140.74,125.47 140.74,125.43 141.07,125.1 UV13.N13
M_DA27: length 29.2
  BOTTOM w0.102: UV1.A19 124.14,114.3 125.63,115.78 126,115.78
  BOTTOM w0.13: 126,115.78 127.4,115.78 v1(130.41,118.8) 132.55,120.93 132.55,125.91 134.42,127.79 138.64,127.79 139.12,127.31 139.12,126.93 139.78,126.27 139.78,125.77 139.81,125.75 139.81,125.53 140.07,125.27 140.39,125.27 140.72,124.93 140.72,123.56 UV13.N11
M_DA28: length 22.2
  BOTTOM w0.102: UV1.D18 122.87,113.5 123.17,113.2 123.48,113.2 123.49,113.21 123.95,113.21 124.04,113.12 124.93,113.12 125.4,113.59 126,113.59
  BOTTOM w0.13: 126,113.59 129.02,113.59 v1(130.07,114.64) 134.77,119.34 134.77,122.38 137.21,124.81 UV13.U13
M_DA29: length 24.8
  BOTTOM w0.102: 126,113.05 125.37,113.05 125.24,112.92 123.96,112.92 123.87,113 123.57,113 123.56,112.99 123.09,112.99 123.01,113.07 121.67,113.07 UV1.F17
  BOTTOM w0.127: UV13.T13 138.29,124.43 137.62,124.43 137.43,124.24
  BOTTOM w0.13: 137.43,124.24 137.43,123.79 135.79,122.15 135.79,118.71 130.13,113.05 v1(127.97,113.05) 126,113.05
M_DA30: length 21
  BOTTOM w0.102: UV1.A17 125.21,112.7
  BOTTOM w0.127: UV13.U11 137.5,123.21 ; 125.21,112.7 125.61,112.3 126,112.3
  BOTTOM w0.13: 137.5,123.21 136.25,121.96 136.25,118.3 v1(131.49,113.53) 130.26,112.3 126,112.3
M_DA31: length 23
  BOTTOM w0.102: UV1.C17 123.26,112.7 123.57,112.4 125.2,112.4 125.75,111.84
  BOTTOM w0.127: 136.99,119.3 136.99,122.16 137.63,122.8 138.25,122.8 UV13.T11 ; 125.75,111.84 126,111.84
  BOTTOM w0.13: 136.99,119.3 136.99,118.38 v1(130.45,111.84) 126,111.84
M_DA32: length 29
  IN1 w0.102: v2(142.28,106.62) 142.43,106.62 143.09,107.27 143.09,109.3 ; v2(121.7,112.43) 121.7,112.68 123.25,114.23 125.21,114.23 125.37,114.38 126,114.38
  IN1 w0.168: 143.09,109.3 143.09,109.87 142.45,110.51 141.88,110.51 139.35,113.04 137.14,113.04 135.8,114.38 126,114.38
  BOTTOM w0.102: v2(121.7,112.43) 121.69,112.43 121.69,112.44 121.83,112.44 122.1,112.7 UV1.E17 ; UV15.F4 v2(142.28,106.62)
M_DA33: length 24.6
  IN1 w0.102: v2(125.24,111.81) 125.24,112.58 125.47,112.81 126,112.81 ; 140.61,109.3 140.61,108.86 140.29,108.54 140.29,106.99 v2(140.67,106.61)
  IN1 w0.168: 140.61,109.3 140.61,109.47 138.46,111.62 136.55,111.62 135.36,112.81 126,112.81
  BOTTOM w0.102: v2(140.67,106.61) 141.07,106.21 UV15.E4 ; v2(125.24,111.81) 125.26,111.81 125.26,111.83 125.18,111.83 124.81,112.19 123.48,112.19 123.32,112.36 122.78,112.36 122.5,112.08 UV1.D16
M_DA34: length 26.2
  IN1 w0.102: v2(141.47,108.21) 141.61,108.21 142.13,108.73 142.16,108.73 142.26,108.83 142.26,109.3 ; 126,113.91 125.21,113.91 123.72,112.41 122.89,112.41 121.94,111.46 v2(121.75,111.46)
  IN1 w0.168: 142.26,109.3 142.26,109.4 139.1,112.56 136.95,112.56 135.6,113.91 126,113.91
  BOTTOM w0.102: UV1.F15 121.39,111.1 v2(121.75,111.46) ; UV15.F2 v2(141.47,108.21)
M_DA35: length 23.1
  IN1 w0.102: v2(124.65,111.81) 124.65,112.84 125.25,113.44 126,113.44 ; v2(140.73,108.18) 140.82,108.18 141.43,108.79 141.43,109.3
  IN1 w0.168: 126,113.44 135.4,113.44 136.75,112.09 138.77,112.09 141.43,109.43 141.43,109.3
  BOTTOM w0.102: v2(124.65,111.81) 124.65,111.76 124,111.1 UV1.A15 ; v2(140.73,108.18) 140.73,108.15 UV15.E2
M_DA36: length 18.5
  IN1 w0.102: v2(138.27,105.81) 138.27,105.81 137.16,105.81 ; v2(125.39,108.88) 125.47,108.96 126,108.96
  IN1 w0.168: 126,108.96 133.4,108.96 136.55,105.81 137.16,105.81
  BOTTOM w0.102: v2(125.39,108.88) 125.39,109.01 125.27,109.13 125.27,109.46 124.94,109.79 123.8,109.79 123.72,109.87 122.93,109.87 UV1.D14 ; v2(138.27,105.81) 138.67,106.21 UV15.B4
M_DA37: length 19
  IN1 w0.102: 126,110.38 125.17,110.38 124.92,110.13 124.8,110.13 124.35,109.68 122.13,109.68 122,109.56 121.62,109.56 121.14,109.07 v2(120.99,109.07) ; v2(137.47,108.21) 137.16,108.21
  IN1 w0.168: 126,110.38 133.98,110.38 136.15,108.21 137.16,108.21
  BOTTOM w0.102: v2(120.99,109.07) 120.99,109.11 121.3,109.42 UV1.F13 ; UV15.A2 v2(137.47,108.21)
M_DA38: length 16.3
  IN1 w0.102: 137.16,106.57 137.43,106.57 v2(137.47,106.61) ; 126,109.43 125.03,109.43 124.83,109.24 v2(124.83,108.88)
  IN1 w0.168: 126,109.43 133.59,109.43 136.45,106.57 137.16,106.57
  BOTTOM w0.102: UV15.A4 v2(137.47,106.61) ; UV1.A13 124.35,109.5 124.55,109.3 124.55,109.3 124.83,109.02 v2(124.83,108.88)
M_DA39: length 18.5
  IN1 w0.102: 137.16,107.46 138.03,107.46 138.13,107.56 138.13,108.07 v2(138.27,108.21) ; 126,109.9 124.86,109.9 124.52,109.56 124.52,109.34 124.27,109.1 v2(124.27,108.88)
  IN1 w0.168: 137.16,107.46 136.23,107.46 133.79,109.9 126,109.9
  BOTTOM w0.102: v2(124.27,108.88) 123.96,109.2 123.2,109.2 UV1.C13 ; UV15.B2 v2(138.27,108.21)
M_DA40: length 22.4
  BOTTOM w0.102: 126,109.11 125.87,109.11 125.77,109.01 125.77,108.62 125.36,108.2 122.4,108.2 UV1.E11
  BOTTOM w0.13: UV15.B11 138.33,100.95 137.41,100.95 136.81,101.54 136.81,104.2 v1(132.29,108.73) 131.9,109.11 126.01,109.11 126,109.11
M_DA41: length 19
  BOTTOM w0.102: UV15.A11 137.43,100.61 137.31,100.73 136.67,100.73 136.52,100.88
  BOTTOM w0.127: UV1.A11 123.75,107.95 125.52,107.95 125.58,108.01
  BOTTOM w0.13: 136.52,100.88 136.35,101.05 136.35,104.01 132.35,108.01 v1(130,108.01) 125.58,108.01
M_DA42: length 21.6
  BOTTOM w0.102: 137.16,99.49 138.19,99.49 UV15.B13 ; UV1.C11 123.27,107.9 123.57,107.6 123.83,107.6 123.96,107.73 125.31,107.73 125.48,107.55 126,107.55
  BOTTOM w0.13: 126,107.55 132.16,107.55 v1(133.61,106.11) 135.89,103.82 135.89,100.3 136.71,99.49 137.16,99.49
M_DA43: length 22.4
  BOTTOM w0.102: 137.16,99.03 137.85,99.03 UV15.A13 ; UV1.F11 121.6,107.6 122.23,107.6 122.33,107.69 122.63,107.69 122.73,107.6 123.29,107.6 123.49,107.39 124.11,107.39 124.16,107.44 124.99,107.44 125.34,107.09 126,107.09
  BOTTOM w0.13: 126,107.09 v1(128.23,107.09) 131.97,107.09 135.44,103.63 135.44,100.11 136.52,99.03 137.16,99.03
M_DA44: length 26
  BOTTOM w0.102: UV15.E11 140.61,100.15 140.61,98.81 140.48,98.69 140.25,98.69 139.79,98.23 139.79,97.74 ; 125.74,104.9 124.44,106.2 123.8,106.2 UV1.A9
  BOTTOM w0.127: 125.74,104.9 126,104.9
  BOTTOM w0.13: 126,104.9 131.06,104.9 v1(132.14,103.82) 133.24,102.72 133.24,99.16 135.61,96.79 138.58,96.79 138.98,97.2 139.25,97.2 139.79,97.74
M_DA45: length 26.5
  BOTTOM w0.102: 126,104.44 125.31,104.44 125.05,104.7 125.05,105.28 124.85,105.48 124.34,106 123.57,106 123.52,106.04 123.16,106.04 122.9,106.3 UV1.C9 ; UV15.E13 141.07,98.78 140.61,98.32 140.61,97.91 140.61,97.9 140.61,97.63
  BOTTOM w0.13: 126,104.44 v1(129.88,104.44) 130.87,104.44 132.78,102.53 132.78,98.97 135.42,96.33 138.77,96.33 139.17,96.74 139.44,96.74 140.01,97.3 140.48,97.3 140.61,97.43 140.61,97.49 140.61,97.5 140.61,97.63
M_DA46: length 31
  BOTTOM w0.102: UV15.F11 141.87,100.48 142.26,100.09 142.26,98.04 142.19,97.96 142.19,97.63 ; 126,103.43 125.4,103.43 123.83,105 122.56,105 122.18,105.38 122.18,105.77 121.66,106.3 UV1.F9
  BOTTOM w0.13: 126,103.43 129.18,103.43 v1(130.31,102.3) 131.86,100.75 131.86,98.59 135.04,95.41 139.15,95.41 139.55,95.82 139.82,95.82 140.39,96.38 140.99,96.38 141.53,96.92 141.54,96.92 142.19,97.57 142.19,97.63
M_DA47: length 28
  BOTTOM w0.102: 125.3,104.16 124.74,104.72 124.74,105.3 124.25,105.79 123.49,105.79 123.44,105.84 122.93,105.84 122.58,105.5 UV1.D8 ; UV15.F13 141.39,98.53 141.39,97.63
  BOTTOM w0.127: 125.3,104.16 125.48,103.98
  BOTTOM w0.13: 125.48,103.98 v1(128.04,103.98) 130.68,103.98 132.32,102.34 132.32,98.78 135.23,95.87 138.96,95.87 139.36,96.28 139.63,96.28 140.2,96.84 140.8,96.84 141.39,97.43 141.39,97.63
M_DA48: length 36.2
  IN2 w0.168: v2(121.75,105.04) 121.92,105.21 121.94,105.21 122.18,105.45 122.18,107.76 125.55,111.13 149.38,111.13 150.83,109.68 150.83,108.79 150.96,108.67 150.96,108.34 v2(151.08,108.22)
  BOTTOM w0.13: UV15.U2 150.67,107.81 v2(151.08,108.22) ; UV1.E7 122.09,104.7 v2(121.75,105.04)
M_DA49: length 27.9
  IN2 w0.168: v2(123.32,104.4) 123.32,105.1 123.78,105.56 124.19,105.56 128.24,109.61 144.05,109.61 145.31,108.35 146.45,108.35 146.51,108.29 146.96,108.29 v2(147.03,108.21)
  BOTTOM w0.13: UV1.A7 123.64,104.7 123.34,104.4 v2(123.32,104.4) ; v2(147.03,108.21) 146.67,107.85 UV15.M2
M_DA50: length 31.1
  IN2 w0.168: v2(147.78,108.21) 147.72,108.27 147.72,109.62 147.26,110.08 127.9,110.08 125.34,107.52 124.1,107.52 123.62,107.05 123.62,105.9 122.51,104.79 v2(122.51,104.38)
  BOTTOM w0.13: UV1.C7 122.83,104.7 v2(122.51,104.38) ; v2(147.78,108.21) 147.47,107.91 UV15.N2
M_DA51: length 34.5
  IN2 w0.168: v2(150.18,108.21) 149.94,108.44 149.94,108.6 149.82,108.73 149.82,109.4 148.64,110.57 127.72,110.57 125.31,108.16 124.04,108.16 122.83,106.95 122.83,105.49 121.76,104.43 v2(121.76,104.33)
  BOTTOM w0.13: v2(150.18,108.21) 149.87,107.89 UV15.T2 ; v2(121.76,104.33) 121.39,104.7 UV1.F7
M_DA52: length 27.9
  IN2 w0.168: v2(149.51,105.81) 149.31,105.61 149.31,105.49 148.8,104.98 146.9,104.98 145.84,103.93 127.57,103.93 126.87,103.23 125.71,103.23 125.12,102.64 v2(124.16,102.64)
  BOTTOM w0.13: v2(149.51,105.81) 149.87,106.17 UV15.T4 ; UV1.A5 v2(124.16,102.64)
M_DA53: length 27.4
  IN2 w0.102: 124.93,103.77 124.67,103.52 124.67,103.46 124.48,103.27 124.42,103.27 124.39,103.24 123.84,103.24 123.72,103.11 122.91,103.11 v2(122.5,102.7) ; 138.1,106.23 146.72,106.23 v2(147.11,106.62)
  IN2 w0.168: 138.1,106.23 137.82,106.23 137.61,106.03 128.33,106.03 126.48,104.18 125.33,104.18 124.93,103.77
  BOTTOM w0.13: UV1.E5 v2(122.5,102.7) ; v2(147.11,106.62) 146.7,106.21 UV15.M4
M_DA54: length 27.4
  IN2 w0.102: v2(123.31,102.66) 123.52,102.88 123.82,102.88 123.94,103 123.99,103 124.01,103.02 124.61,103.02
  IN2 w0.168: v2(147.87,106.61) 147.53,106.27 147.53,106.19 147.15,105.81 146.26,105.81 145.75,105.3 142.31,105.3 141.49,104.48 127.45,104.48 126.68,103.71 125.81,103.71 125.61,103.5 125.6,103.5 125.5,103.4 124.99,103.4 124.61,103.02
  BOTTOM w0.13: UV15.N4 147.47,106.21 v2(147.87,106.61) ; UV1.C3 123.23,102.63 123.28,102.63 v2(123.31,102.66)
M_DA55: length 31.4
  IN2 w0.168: v2(122.49,101.89) 122.82,102.22 123.51,102.22 123.54,102.19 125.05,102.19 125.62,102.76 127.07,102.76 127.74,103.43 149.34,103.43 150.26,104.35 150.26,105.81 v2(150.25,105.82)
  BOTTOM w0.13: UV1.E1 v2(122.49,101.89) ; v2(150.25,105.82) 150.64,106.21 UV15.U4
M_DA56: length 33.6
  IN2 w0.102: v2(147.1,100.22) 147.09,100.22 146.64,100.67 145.69,100.67 145.63,100.6 145.24,100.6 145.05,100.41 145.05,99.96 144.93,99.83 142.78,99.83 141.98,100.63 138.61,100.63 137.53,101.71 136.52,101.71
  IN2 w0.168: 136.52,101.71 135.34,101.71 134.74,101.12 126.04,101.12 125.51,100.59 124.75,100.59 124.74,100.57 122.99,100.57 v2(122.58,100.17)
  BOTTOM w0.102: UV15.M11 146.71,100.61 v2(147.1,100.22) ; v2(122.58,100.17) 121.48,100.17 120.88,100.77 120.88,101.16 121.01,101.29 121.01,101.71 120.87,101.84 120.87,101.94 120.8,102.01 120.8,102.64 121.01,102.84 121.01,103.63 120.9,103.74 120.9,104.3 UV1.G7
M_DA57: length 35.5
  IN2 w0.102: v2(147.85,100.22) 147.43,99.81 145.19,99.81 144.85,99.46 144.09,99.46 143.66,99.03 140.91,99.03 140.23,99.71 138.23,99.71 137.88,100.06 137.88,100.79 137.43,101.24 136.52,101.24
  IN2 w0.168: 136.52,101.24 135.53,101.24 134.93,100.64 126.23,100.64 125.82,100.23 125.81,100.23 125.75,100.17 v2(124.92,100.17)
  BOTTOM w0.102: 120.22,100.82 120.2,100.84 120.2,101.64 120.2,101.64 120.2,101.68 120.21,101.69 120.21,102.11 120.2,102.12 120.2,102.17 120.16,102.21 120.16,102.51 120.35,102.71 120.58,102.71 120.8,102.92 120.8,103.31 120.5,103.61 UV1.G6 ; UV15.N11 147.47,100.6 v2(147.85,100.22)
  BOTTOM w0.127: 120.22,100.82 120.22,100.47 121.12,99.57 121.12,99.56 121.36,99.32 124.41,99.32 124.92,99.83 v2(124.92,100.17)
M_DA58: length 30.5
  IN2 w0.102: 136.52,100.77 137.23,100.77 137.68,100.33 137.68,99.98 138.14,99.51 140.14,99.51 140.83,98.83 143.74,98.83 144.17,99.26 144.94,99.26 145.18,99.01 146.66,99.01 v2(147.07,98.61)
  IN2 w0.168: 136.52,100.77 135.73,100.77 135.13,100.17 126.43,100.17 126.02,99.76 124.08,99.76 v2(124.04,99.72)
  BOTTOM w0.102: UV15.N13 v2(147.07,98.61) ; UV1.G1 120.45,101.45 120.45,100.89
  BOTTOM w0.127: v2(124.04,99.72) 124.04,99.68 123.91,99.55 121.46,99.55 120.45,100.56 120.45,100.89
M_DA59: length 30.1
  IN2 w0.102: v2(146.27,98.61) 146.07,98.81 145.1,98.81 144.86,99.05 144.26,99.05 143.83,98.62 140.74,98.62 140.06,99.31 138.01,99.31
  IN2 w0.168: 138.01,99.31 137.44,99.88 135.88,99.88 135.7,99.7 126.62,99.7 126,99.08 124.04,99.08 123.41,99.7 v2(123.41,99.94)
  BOTTOM w0.102: 120.68,100.66 120.68,101.25 120.8,101.37 120.8,101.63 120.67,101.76 120.67,101.85 120.5,102.02 UV1.G3 ; UV15.M13 v2(146.27,98.61)
  BOTTOM w0.127: 120.68,100.66 121.56,99.78 122.94,99.78 123.11,99.94 v2(123.41,99.94)
M_DA60: length 40.6
  IN2 w0.168: v2(124.1,97.74) 125.19,96.66 140.94,96.66 141.25,96.34 146.76,96.34 147.05,96.63 148.99,96.63 149.69,97.33 149.69,98.39 v2(149.47,98.61)
  BOTTOM w0.102: UV1.J6 119,103.8 119,103.45 119.2,103.24 119.2,102.97 119.2,102.97 119.2,102.96 118.97,102.72 118.89,102.72 118.58,102.41 118.58,102.18 118.68,102.08 118.68,101.71 118.59,101.62 118.59,99.47 118.97,99.09 118.97,98.82 ; UV15.T13 v2(149.47,98.61)
  BOTTOM w0.13: 118.97,98.82 120.9,96.89 123.24,96.89 v2(124.1,97.74)
M_DA61: length 38.3
  IN2 w0.168: v2(123.15,97.81) 123.37,97.81 124.99,96.18 140.74,96.18 141.06,95.87 147.24,95.87 147.53,96.16 149.19,96.16 150.2,97.17 150.39,97.17 150.68,97.47 150.68,98.2 v2(150.27,98.61)
  BOTTOM w0.102: UV1.J1 118.79,101.39 118.79,99.55 119.49,98.86 ; UV15.U13 v2(150.27,98.61)
  BOTTOM w0.13: v2(123.15,97.81) 122.69,97.35 120.99,97.35 119.49,98.86
M_DA62: length 42.2
  IN2 w0.168: v2(150.35,100.22) 150.82,99.75 150.82,99.34 150.83,99.33 150.83,99.08 151.66,98.25 151.66,97.17 151.15,96.67 150.36,96.67 148.96,95.26 141,95.26 140.55,95.71 124.79,95.71 124.03,96.47 123.27,96.47 122.19,97.55 v2(122.19,97.81)
  BOTTOM w0.102: v2(150.35,100.22) 150.67,100.54 UV15.U11 ; UV1.J3 118.97,102.23 118.97,101.9 119.2,101.67 119.2,101.37 118.99,101.16 118.99,99.96 121.15,97.81 121.73,97.81
  BOTTOM w0.13: 121.73,97.81 v2(122.19,97.81)
M_DA63: length 40.5
  IN2 w0.102: v2(149.41,100.24) 149.05,99.88 149.05,98.44 148.57,97.96 148.57,97.63
  IN2 w0.168: 148.57,97.63 148.57,97.46 148.33,97.23 125.63,97.23 v2(125.12,97.74)
  BOTTOM w0.102: UV1.J5 118.9,103.04 118.36,102.5 118.36,102.11 118.43,102.04 118.43,101.75 118.37,101.69 118.37,99.38 ; UV15.T11 149.79,100.61 v2(149.41,100.24)
  BOTTOM w0.13: 118.37,99.38 118.73,99.01 118.73,98.22 120.53,96.43 123.8,96.43 v2(125.12,97.74)
M_DBI0#: length 46.6
  IN2 w0.102: 148.23,126.17 148.23,125.93 148.51,125.65 148.79,125.65 149.05,125.39 149.05,122.23 149.1,122.19 149.1,121.87 148.84,121.61 148.84,118.4 149.05,118.19 149.05,116.01 v2(148.67,115.63)
  IN2 w0.168: 121.11,124.78 122.4,126.07 125.54,126.07 126.9,127.42 133.73,127.42 134.77,128.46 146.22,128.46 147.43,127.25 147.43,127.25 148.08,126.6 148.08,126.6 148.23,126.45 148.23,126.17
  IN2 w0.175: v2(119.42,121.09) 119.44,121.09 120.16,121.82 120.16,123.83 121.11,124.78
  BOTTOM w0.102: UV13.D2 148.29,116.01 v2(148.67,115.63)
  BOTTOM w0.127: v2(119.42,121.09) 119.44,121.09 119.44,120.96 UV1.H27
M_DBI1#: length 33
  IN1 w0.102: 145.85,125.58 145.85,124.31 145.89,124.27 145.89,124.27 146.11,124.05 148.29,124.05 v2(148.67,124.43)
  IN1 w0.145: 145.76,126.32 145.76,125.68 145.85,125.58
  IN1 w0.168: 145.76,126.32 145.76,127.42 145.33,127.84 133.2,127.84 131.21,125.85 127.73,125.85 125.13,123.25 125.13,121.52 v2(124.36,120.75)
  BOTTOM w0.102: UV13.D13 148.29,124.81 v2(148.67,124.43)
  BOTTOM w0.127: v2(124.36,120.75) 124.31,120.7 UV1.A27
M_DBI2#: length 19.6
  IN2 w0.168: v2(123.28,117.79) 124.05,117.79 124.12,117.72 125.01,117.72 125.87,116.86 128.75,116.86 129.45,117.56 137.34,117.56 137.99,116.92 137.99,116.92 138.1,116.81 138.44,116.81 138.55,116.92 139.28,116.92 139.49,116.71 139.49,116.01 v2(139.87,115.63)
  BOTTOM w0.102: v2(139.87,115.63) 140.25,116.01 UV13.P2
  BOTTOM w0.127: v2(123.28,117.79) 122.99,117.5 UV1.C23
M_DBI3#: length 26.4
  BOTTOM w0.102: 126,115.17 125.3,115.17 124.23,114.1 123.93,114.1 123.83,114 123.57,114 123.27,114.3 UV1.C19
  BOTTOM w0.13: 126,115.17 127.68,115.17 v1(128.61,116.1) 133.18,120.67 133.18,125.18 134.78,126.77 138.12,126.77 139.02,125.87 139.02,125.53 139.3,125.25 139.71,125.25 140.15,124.81 UV13.P13
M_DBI4#: length 21.4
  IN1 w0.102: 126,112.13 125.79,112.13 125.62,111.97 125.62,111.65 125.11,111.14 123.97,111.14 123.7,111.42 v2(122.52,111.42) ; 139.82,109.3 139.84,109.28 139.84,108.24 v2(139.87,108.21)
  IN1 w0.168: 126,112.13 135.08,112.13 136.27,110.94 138.18,110.94 139.82,109.3
  BOTTOM w0.102: v2(122.52,111.42) 122.84,111.1 UV1.C15 ; UV15.D2 v2(139.87,108.21)
M_DBI5#: length 25
  BOTTOM w0.102: UV1.E9 122.4,106.6 123.08,106.6 123.09,106.59 123.51,106.59 123.55,106.63 124.2,106.63 124.35,106.48 124.47,106.48 125.25,105.69 125.25,105.67 125.41,105.51 126,105.51 ; UV15.D13 139.89,98.63 139.4,98.63 139.09,98.32 139.09,98.17 138.55,97.63
  BOTTOM w0.13: 126,105.51 131.32,105.51 133.86,102.97 v1(133.86,102.44) 133.86,99.42 135.87,97.41 138.32,97.41 138.45,97.53 138.55,97.63
M_DBI6#: length 30.1
  IN2 w0.102: 137.16,107.79 148.24,107.79 v2(148.65,108.19)
  IN2 w0.168: v2(122.13,103.59) 122.51,103.97 122.68,103.97 122.75,104.04 123.1,104.04 123.15,103.99 123.49,103.99 124.24,104.73 124.53,104.73 124.78,104.97 124.78,105.19 127.37,107.79 137.16,107.79
  BOTTOM w0.102: v2(148.65,108.19) 148.27,107.82 UV15.P2
  BOTTOM w0.13: UV1.C5 122.62,103.1 v2(122.13,103.59)
M_DBI7#: length 32.4
  IN2 w0.102: v2(147.87,98.61) 147.61,98.61 147.23,98.23 144.51,98.23 144.32,98.42 140.66,98.42 139.98,99.09 138.98,99.09 138.91,99.02 137.69,99.02 137.51,99.2 137.16,99.2
  IN2 w0.168: 137.16,99.2 136.16,99.2 135.98,99.02 v2(126.7,99.02)
  BOTTOM w0.102: 119.99,100.77 119.99,100.77 119.99,101.72 120,101.72 120,101.77 120,101.77 120,102.03 120,102.03 120,102.09 119.96,102.13 119.96,102.45 UV1.H4 ; UV15.P13 v2(147.87,98.61)
  BOTTOM w0.127: 119.99,100.77 119.99,100.37 121.34,99.02 121.82,99.02
  BOTTOM w0.13: 121.82,99.02 121.89,99.09 124.51,99.09 124.69,99.27 126,99.27 126.24,99.02 v2(126.7,99.02)
M_EDC_0: length 53.5
  IN2 w0.102: v2(149.47,115.63) 149.47,115.67 149.86,116.05 149.86,126.23
  IN2 w0.168: 149.86,126.23 146.73,129.36 132.86,129.36 132.58,129.64 132.24,129.64 132.08,129.47 132.08,128.47 131.91,128.3 131.57,128.3 131.41,128.47 131.41,129.47 131.24,129.64 130.9,129.64 130.74,129.47 130.74,128.47 130.57,128.3 130.23,128.3 130.06,128.47 130.06,129.47 129.9,129.64 129.56,129.64 129.39,129.47 129.39,128.58 129.22,128.4 126.5,128.4 125.04,126.94 121.85,126.94 119.89,124.99
  IN2 w0.175: 119.89,124.99 119.4,124.49 v2(119.4,121.87)
  BOTTOM w0.102: v2(149.47,115.63) 149.09,116.01 UV13.C2
  BOTTOM w0.127: UV1.H28 119.7,121.57 v2(119.4,121.87)
M_EDC_1: length 37.3
  IN1 w0.102: 146.68,126.32 146.68,125.04 146.87,124.85 148.29,124.85 v2(148.67,125.23)
  IN1 w0.168: 146.68,126.32 146.68,126.94 146.71,126.97 146.71,127.72 145.7,128.72 131.31,128.72 131.05,128.47 131.05,127.25 130.8,126.99 130.38,126.99 130.12,127.25 130.12,128.47 129.87,128.72 128.7,128.72 124.29,124.31 124.29,123.19 123.73,122.64 123.73,121.41 v2(123.42,121.09)
  BOTTOM w0.102: UV13.C13 149.07,124.83 v2(148.67,125.23)
  BOTTOM w0.127: v2(123.42,121.09) 123.4,121.07 123.27,121.07 UV1.C27
M_EDC_2: length 17.7
  IN2 w0.168: v2(139.07,115.63) 138.15,116.54 129.69,116.54 129.13,115.98 125.49,115.98 125.28,116.19 125.28,116.75 v2(124.77,117.26)
  BOTTOM w0.102: v2(139.07,115.63) 139.45,116.01 UV13.R2 ; v2(124.77,117.26) 124.33,117.7 123.9,117.7 UV1.A23
M_EDC_3: length 27.2
  BOTTOM w0.102: UV1.E19 122.4,114 123.29,114 123.49,113.79 123.91,113.79 124.01,113.89 124.82,113.89 125.31,114.38 126,114.38
  BOTTOM w0.13: 126,114.38 128.54,114.38 v1(130.86,116.7) 133.98,119.82 133.98,124.64 134.17,124.83 134.45,124.83 135.06,124.22 135.39,124.22 135.55,124.38 135.55,125.78 135.72,125.96 136.78,125.96 137.5,125.24 138.8,125.24 139.23,124.81 UV13.R13
M_EDC_4: length 21.8
  IN1 w0.102: v2(123.28,110.8) 123.42,110.94 124.15,110.94 124.25,110.84 124.25,110.43 124.35,110.33 124.55,110.33 124.65,110.43 124.65,110.84 124.75,110.94 125.36,110.94 125.67,111.25 126,111.25 ; 138.58,109.3 138.66,109.22 138.66,108.03 138.74,107.96 138.97,107.96 139.07,108.06 v2(139.07,108.21)
  IN1 w0.168: 138.58,109.3 137.82,110.06 137.21,110.06 137.04,109.9 137.04,109.66 136.88,109.49 136.54,109.49 136.37,109.66 136.37,109.9 136.2,110.06 135.91,110.06 134.72,111.25 126,111.25
  BOTTOM w0.102: v2(123.28,110.8) 123.28,110.8 122.54,110.8 122.24,111.1 UV1.E15 ; UV15.C2 v2(139.07,108.21)
M_EDC_5: length 23.1
  BOTTOM w0.102: UV1.D10 122.79,106.81 123.16,106.81 123.17,106.8 123.43,106.8 123.46,106.83 124.28,106.83 124.44,106.68 124.69,106.68 124.89,106.48 125.62,106.48 125.8,106.3 126,106.3 ; UV15.C13 138.99,98.53 137.73,98.53 137.43,98.24 137.16,98.24
  BOTTOM w0.13: 126,106.3 v1(131.15,106.3) 131.64,106.3 134.65,103.3 134.65,99.77 136.18,98.24 137.16,98.24
M_EDC_6: length 30
  IN2 w0.102: 137.65,107.02 148.86,107.02 149.05,107.21 149.05,107.8 v2(149.48,108.22)
  IN2 w0.168: v2(122.9,103.58) 122.97,103.65 123.65,103.65 124.29,104.29 124.8,104.29 126.05,105.54 126.6,105.54 127.97,106.91 137.18,106.91 137.3,107.02 137.64,107.02 137.65,107.02
  BOTTOM w0.102: UV15.R2 v2(149.48,108.22)
  BOTTOM w0.13: UV1.D6 122.82,103.58 v2(122.9,103.58)
M_EDC_7: length 35.5
  IN2 w0.102: 137.16,98.32 140.42,98.32 140.53,98.22 144.24,98.22 144.43,98.03 148.09,98.03 v2(148.67,98.61)
  IN2 w0.168: v2(126.07,98.14) 136.35,98.14 136.53,98.32 137.16,98.32
  BOTTOM w0.102: UV1.G5 120.4,103 119.57,103 119.2,102.64 119.2,101.96 119.41,101.76 119.41,101.29 119.21,101.09 119.21,100.05 ; UV15.R13 v2(148.67,98.61)
  BOTTOM w0.127: 119.21,100.05 119.67,99.59
  BOTTOM w0.13: 119.67,99.59 120.71,98.55 125.6,98.55 126,98.14 v2(126.07,98.14)
M_RAS#0: length 30.9
  TOP w0.102: v2(120.86,117.05) 120.86,116.85 121.59,116.13 122.35,116.13 123.02,116.79 124.85,116.79 125.8,117.75 126,117.75 ; 136.52,120.32 137.09,120.32 137.19,120.43 144.63,120.43 145.45,119.6 145.45,117.25 v2(145.47,117.23)
  TOP w0.13: 126,117.75 128.38,117.75 130.95,120.32 v1(133.12,120.32) 136.52,120.32
  BOTTOM w0.102: v2(145.47,117.23) 145.87,116.83 UV13.G3
  BOTTOM w0.127: UV1.G22 120.86,116.86 v2(120.86,117.05)
M_RAS#1: length 33.2
  TOP w0.102: v2(120.4,112.29) 120.4,112.46 120.65,112.71 121.1,112.71 121.22,112.83 122.83,112.83 123.35,112.31 125.08,112.31 125.55,112.78 126,112.78 ; 142.27,109.3 142.27,109.02 142.26,109.01 v2(142.26,107.4)
  TOP w0.13: 142.27,109.3 142.27,109.37 142.26,109.38 142.26,109.93 140.53,111.66 134.93,111.66 134.8,111.53 134.8,110.7 134.67,110.57 134.41,110.57 134.28,110.7 134.28,111.53 134.15,111.66 133.89,111.66 133.76,111.53 133.76,110.7 133.63,110.57 133.37,110.57 133.24,110.7 133.24,111.53 133.11,111.66 132.85,111.66 132.72,111.53 132.72,110.7 132.59,110.57 132.34,110.57 132.21,110.7 132.21,111.53 132.08,111.66 v1(131.47,111.66) 130.99,111.66 130.5,112.15 130.5,112.15 129.87,112.78 126,112.78
  BOTTOM w0.102: v2(120.4,112.29) 120.4,112.29 120.4,112.8 UV1.G17 ; UV15.G3 142.28,107.4 v2(142.26,107.4)
M_WCKA0_0: length 39.3
  IN1 w0.147: v2(148.67,118.03) 148.44,118.26 148.44,119.4 147.97,119.86 147.5,119.86 138.51,119.86 138.34,119.69 137.52,119.69 137.2,119.37 137.2,117.8 137.05,117.66 136.61,117.66 136.47,117.8 136.47,119.37 136.15,119.69 135.47,119.69 135.16,119.37 135.16,117.8 135.01,117.66 134.57,117.66 134.42,117.8 134.42,119.37 134.11,119.69 132.28,119.69 132.13,119.83 132.13,120.57 131.4,121.3 130.26,121.3 129.63,121.94 129.62,122.07 v2(129.62,122.17)
  BOTTOM w0.102: UV13.D4 148.27,117.63 v2(148.67,118.03)
  BOTTOM w0.114: UV1.E32 122.2,123.2 122.2,123.82 122.96,124.58 125.74,124.58 125.74,124.58 126.89,124.58 126.89,124.58 126.99,124.58 129.39,122.17 v2(129.62,122.17)
M_WCKA0_0#: length 39.4
  IN1 w0.147: v2(129.21,121.76) 129.4,121.76 130.14,121.02 131.28,121.02 131.85,120.45 131.85,119.71 132.16,119.4 133.99,119.4 134.14,119.25 134.14,117.69 134.45,117.37 135.13,117.37 135.44,117.69 135.44,119.25 135.59,119.4 136.03,119.4 136.18,119.25 136.18,117.69 136.49,117.37 137.17,117.37 137.49,117.69 137.49,119.25 137.63,119.4 138.45,119.4 138.63,119.58 147.62,119.58 147.86,119.58 148.15,119.28 148.15,118.31 v2(147.87,118.03)
  BOTTOM w0.102: UV13.D5 148.25,118.41 v2(147.87,118.03)
  BOTTOM w0.114: v2(129.21,121.76) 129.21,122.06 126.9,124.37 126.8,124.37 126.8,124.37 125.83,124.37 125.83,124.37 123.04,124.37 122.41,123.74 122.41,122.61 UV1.E30
M_WCKA0_1: length 18.6
  IN1 w0.147: v2(140.67,118.03) 140.35,117.71 140.35,117.53 139.86,117.04 139.06,117.04 138.46,116.43 124.35,116.43 124.2,116.28 v2(124.2,116.12)
  BOTTOM w0.102: UV13.P4 140.27,117.63 v2(140.67,118.03)
  BOTTOM w0.112: v2(124.2,116.12) 123.92,116.12 UV1.A21
M_WCKA0_1#: length 18.9
  IN1 w0.147: v2(139.87,118.03) 140.07,117.83 140.07,117.64 139.75,117.32 138.95,117.32 138.34,116.72 124.23,116.72 123.92,116.4 123.81,116.4 123.6,116.19 v2(123.31,116.19)
  BOTTOM w0.102: v2(139.87,118.03) 140.25,118.41 UV13.P5
  BOTTOM w0.112: UV1.C21 123.02,115.9 v2(123.31,116.19)
M_WCKA1_0: length 23.4
  IN1 w0.147: v2(122.53,109.18) 122.39,109.04 122.39,108.36 125.03,105.71 135.7,105.71 136.77,104.64 138.91,104.64 139.04,104.51 139.56,104.51 140.37,105.31 140.37,105.54 140.1,105.81 v2(139.87,105.81)
  BOTTOM w0.102: UV15.D4 140.22,106.26 140.02,106.26 139.79,106.03 139.79,105.89 v2(139.87,105.81)
  BOTTOM w0.112: v2(122.53,109.18) 122.6,109.25 122.6,109.43 122.39,109.64 122.24,109.64 UV1.E13
M_WCKA1_0#: length 23.4
  IN1 w0.147: v2(121.93,109.05) 122.1,108.88 122.1,108.24 124.91,105.43 135.58,105.43 136.65,104.36 138.79,104.36 138.92,104.22 139.68,104.22 140.67,105.21 v2(140.67,105.81)
  BOTTOM w0.102: v2(140.67,105.81) 140.27,105.41 UV15.D5
  BOTTOM w0.112: UV1.D12 122.28,108.7 v2(121.93,109.05)
M_WCKA1_1: length 34.5
  IN1 w0.147: v2(128.44,102.99) 128.58,103.13 128.58,103.58 129.34,104.34 132.74,104.34 133.83,103.25 146.69,103.25 147.71,104.28 147.71,104.67 148.24,105.2 148.24,105.83 148.13,105.93 147.91,105.93 v2(147.79,105.81)
  BOTTOM w0.102: UV15.P4 147.87,105.81 v2(147.79,105.81) ; UV1.E3 122.08,102.37 121.95,102.43 121.74,102.37 121.72,102.34 121.72,102.19 121.81,102.1 121.81,101.64 121.8,101.63 121.8,101.22 122.26,100.75 125.26,100.75 125.8,101.28 125.8,101.3 126,101.51
  BOTTOM w0.114: v2(128.44,102.99) 128.65,102.78 128.65,101.62 128.54,101.51 126,101.51
M_WCKA1_1#: length 34.5
  IN1 w0.147: v2(148.67,105.81) 148.52,105.66 148.52,105.08 148,104.56 148,104.16 146.8,102.96 133.72,102.96 132.62,104.06 129.46,104.06 128.86,103.46 128.86,103.16 v2(129.03,102.99)
  BOTTOM w0.102: 126,101.21 125.34,100.55 122.18,100.55 121.6,101.14 121.6,101.71 121.62,101.73 121.62,102.01 121.52,102.11 121.52,102.59 UV1.F4 ; UV15.P5 148.27,105.41 v2(148.67,105.81)
  BOTTOM w0.114: v2(129.03,102.99) 128.86,102.83 128.86,101.54 128.63,101.3 126.09,101.3 126,101.21
M_WE#0: length 31.6
  TOP w0.102: 126,124.35 125.56,124.35 123.48,122.28 121.45,122.28 120.99,121.81 120.31,121.81 119.97,121.47 119.97,120.8 119.65,120.48 119.65,120.03 119.27,119.65 v2(119.27,118.76) ; v2(143.07,123.63) 142.46,123.63 140.48,121.65 138.14,121.65 137.54,122.24 137.54,122.97 137.16,123.36
  TOP w0.13: 126,124.35 v1(126.77,124.35) 136.16,124.35 137.16,123.36
  BOTTOM w0.102: v2(119.27,118.76) 119.87,118.76 120.21,119.1 UV1.G25 ; v2(143.07,123.63) 142.69,124.01 UV13.L12
M_WE#1: length 33
  TOP w0.102: v2(120.98,108.34) 121.67,107.64 123.26,107.64 124.85,106.06 126,106.06 ; v2(145.55,100.22) 145.09,100.68 145.09,101.21 144.86,101.43 144.55,101.43 143.25,102.74 137.75,102.74 137.12,102.11 137.12,101.86 136.99,101.73 136.52,101.73
  TOP w0.13: 136.52,101.73 132.01,101.73 v1(130.36,103.37) 128.48,105.26 128.29,105.26 127.97,104.94 127.79,104.94 127.61,105.12 127.61,105.3 127.93,105.62 127.93,105.81 127.67,106.06 126,106.06
  BOTTOM w0.102: UV1.H10 120.05,107.1 120.54,107.59 120.73,107.59 120.98,107.83 v2(120.98,108.34) ; UV15.L12 145.87,99.9 v2(145.55,100.22)
MCT0: length 1
  TOP w0.102: v2(17.8,112.35) 17.67,112.48 17.67,112.92 17.55,113.05 v1(17.36,113.05)
  vias: v2(17.8,111.71)
MCT1: length 0.6
  TOP w0.102: v1(17.29,108.73) 17.36,108.79 v2(17.86,108.79)
  vias: v2(17.86,108.16)
MDI0+: length 15.7
  BOTTOM w0.089: TL1.6 28.9,105.76 29.3,106.16 29.58,106.16 29.84,106.42 29.84,107.61 29.63,107.82 29.63,109.26 29.88,109.51 EU3501.6 EU3501.5 v3(32.53,109.51) 33.32,109.51 34.41,110.59 34.41,110.59 34.58,110.76 34.69,110.88 UL1.1
MDI0-: length 15.7
  BOTTOM w0.089: TL1.5 28.9,107.03 29.08,106.85 29.08,106.53 29.17,106.44 29.47,106.44 29.56,106.54 29.56,107.49 29.35,107.7 29.35,109.37 29.76,109.79 30.04,109.79 30.25,110.01 EU3501.7 EU3501.4 31.76,110.01 31.98,109.79 33.21,109.79 34.41,110.99 v3(34.41,114.19) 34.41,115.36 34.29,115.48 UL1.2
MDI1+: length 12
  BOTTOM w0.089: UL1.4 33.49,114.32 32.99,113.82 v3(32.99,113.43) 32.99,111.33 32.67,111.01 EU3501.2 EU3501.8 30.25,111.01 30.18,111.08 29.92,111.08 29.42,111.58 29.42,113.43 29.29,113.56 28.79,113.56 28.61,113.38 TL1.2
MDI1-: length 12
  BOTTOM w0.089: UL1.5 33.09,115.41 33.21,115.29 v3(33.21,114.7) 33.21,114.44 32.71,113.93 32.71,111.45 32.55,111.29 32.15,111.29 31.93,111.51 EU3501.1 EU3501.9 30.27,111.51 30.14,111.38 30.02,111.38 29.7,111.7 29.7,113.55 29.39,113.86 29.39,113.97 28.71,114.65 TL1.1
MDO0+: length 16.7
  IN2 w0.178: JLAN1.1 12.87,113.29 17.55,113.29 17.62,113.36 18.12,113.36 18.55,112.93 18.55,110.89 16.89,109.22 v2(16.89,105.59)
  BOTTOM w0.267: v2(16.89,105.59) 16.89,105.82 17.07,106 18.18,106 18.42,105.76 TL1.7
MDO0-: length 16.7
  IN2 w0.178: v2(16.3,105.59) 16.3,105.63 16.58,105.91 16.58,109.35 18.24,111.01 18.24,112.81 18,113.06 17.74,113.06 17.67,112.98 14.13,112.98 13.95,112.81 JLAN1.2
  BOTTOM w0.267: v2(16.3,105.59) 16.4,105.69 16.4,105.87 16.91,106.38 17.67,106.38 18.32,107.03 TL1.8
MDO1+: length 11.3
  IN2 w0.178: v2(16.97,111.18) 16.72,111.43 16.72,111.71 16.4,112.03 15.77,112.03 15.37,111.64 15.37,110.99 15.05,110.67 14.91,110.67 14.35,111.23 JLAN1.3
  BOTTOM w0.267: TL1.11 18.36,113.38 17.67,114.06 17.05,114.06 16.78,113.8 16.78,111.36 v2(16.97,111.18)
MDO1-: length 11.3
  IN2 w0.178: JLAN1.6 13.95,108.99 15.01,110.04 15.01,110.19 15.68,110.86 15.68,111.51 15.89,111.73 16.28,111.73 16.4,111.6 16.4,111.21 v2(16.34,111.14)
  BOTTOM w0.267: TL1.12 18.45,114.65 18.24,114.45 16.89,114.45 16.4,113.96 16.4,111.21 v2(16.34,111.14)
MEM_MAB_ACT#: length 80.8
  IN1 w0.102: v2(107.22,59.57) 106.64,60.15 105.49,60.15 105.37,60.28 105.02,60.28 101.72,63.58 101.72,64.46 101.64,64.54 101.64,64.96 100.3,66.3 100.1,66.3
  IN1 w0.211: 100.1,66.3 99.85,66.3 99.65,66.1 99.65,65.9 99.47,65.73 99.01,65.73 98.74,65.99 98.74,66.22 98.51,66.45 83.42,66.45 83.01,66.04 77.28,66.04 75.01,63.77 74.05,63.77 73.49,63.21 73.27,63.21 72.73,62.67 69.62,62.67 68.45,61.5 64.66,61.5 63.98,62.18 62.44,62.18 61.87,61.61 58.44,61.61 56.59,59.77 v2(55.58,59.77)
  IN2 w0.211: v2(55.58,59.77) 55.19,60.15 54.38,60.15 53.93,59.71 51.58,59.71 51.25,59.38 v2(47.52,59.38)
  BOTTOM w0.102: JDIMM2.114 v2(47.52,59.38) ; UC1.L35 107.06,59.41 v2(107.22,59.57) ; v2(55.58,59.77) 55.89,60.08 55.89,60.37 56,60.47 56.2,60.47 56.3,60.37 56.3,60.15 56.4,60.05 56.61,60.05 56.71,60.15 56.71,60.37 56.81,60.47 57.01,60.47 57.11,60.37 57.11,60.15 57.22,60.05 57.42,60.05 57.52,60.15 57.52,60.37 57.62,60.47 57.83,60.47 57.93,60.37 57.93,60.15 58.03,60.05 58.83,60.05 59.03,59.85 59.32,59.85 59.57,59.59 59.9,59.59 60.03,59.73 60.03,59.92 60.13,60.03 60.6,60.03 60.85,59.77 60.85,59.07 61.05,58.88 JDIMM1.114
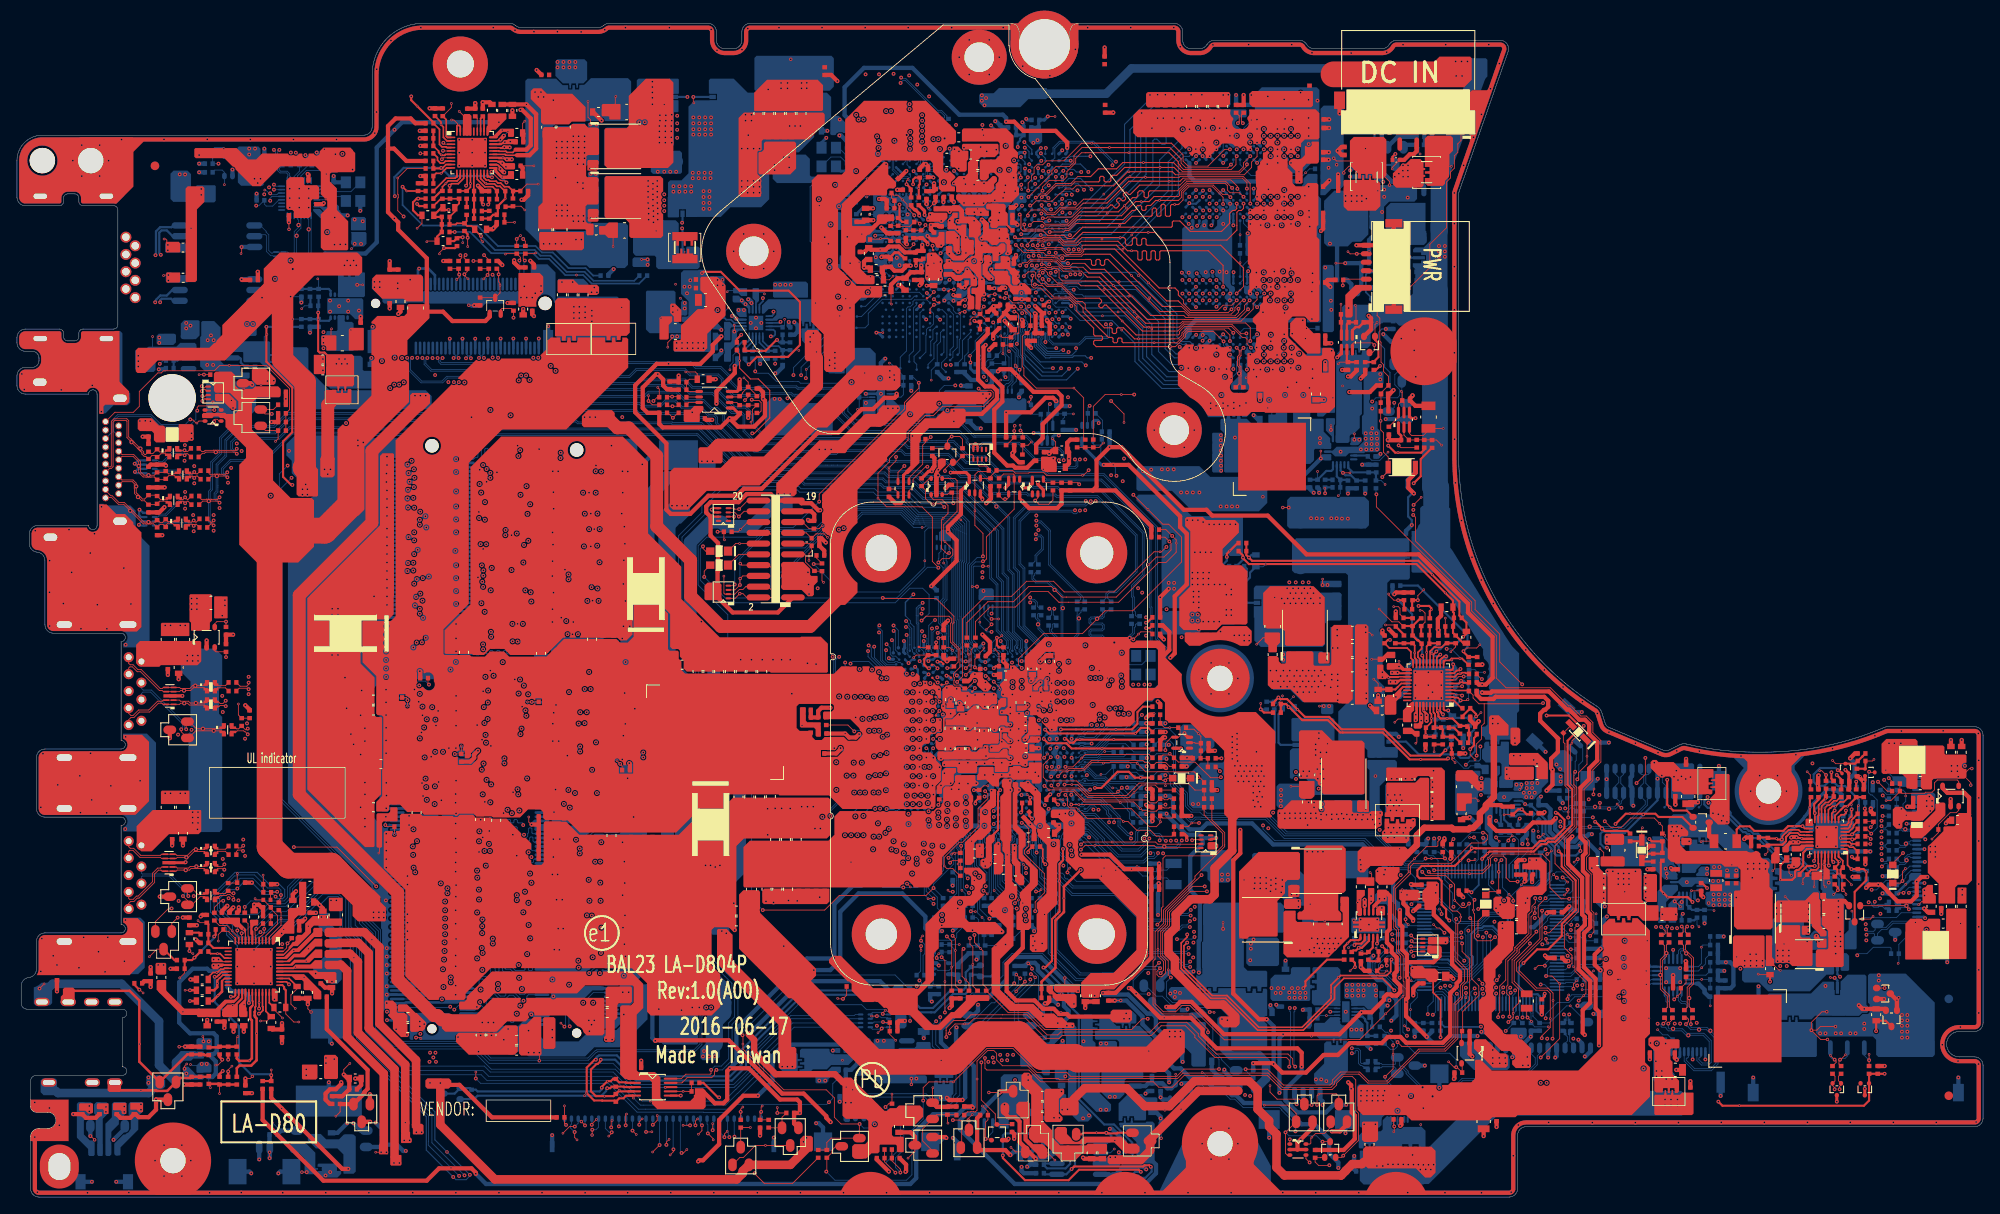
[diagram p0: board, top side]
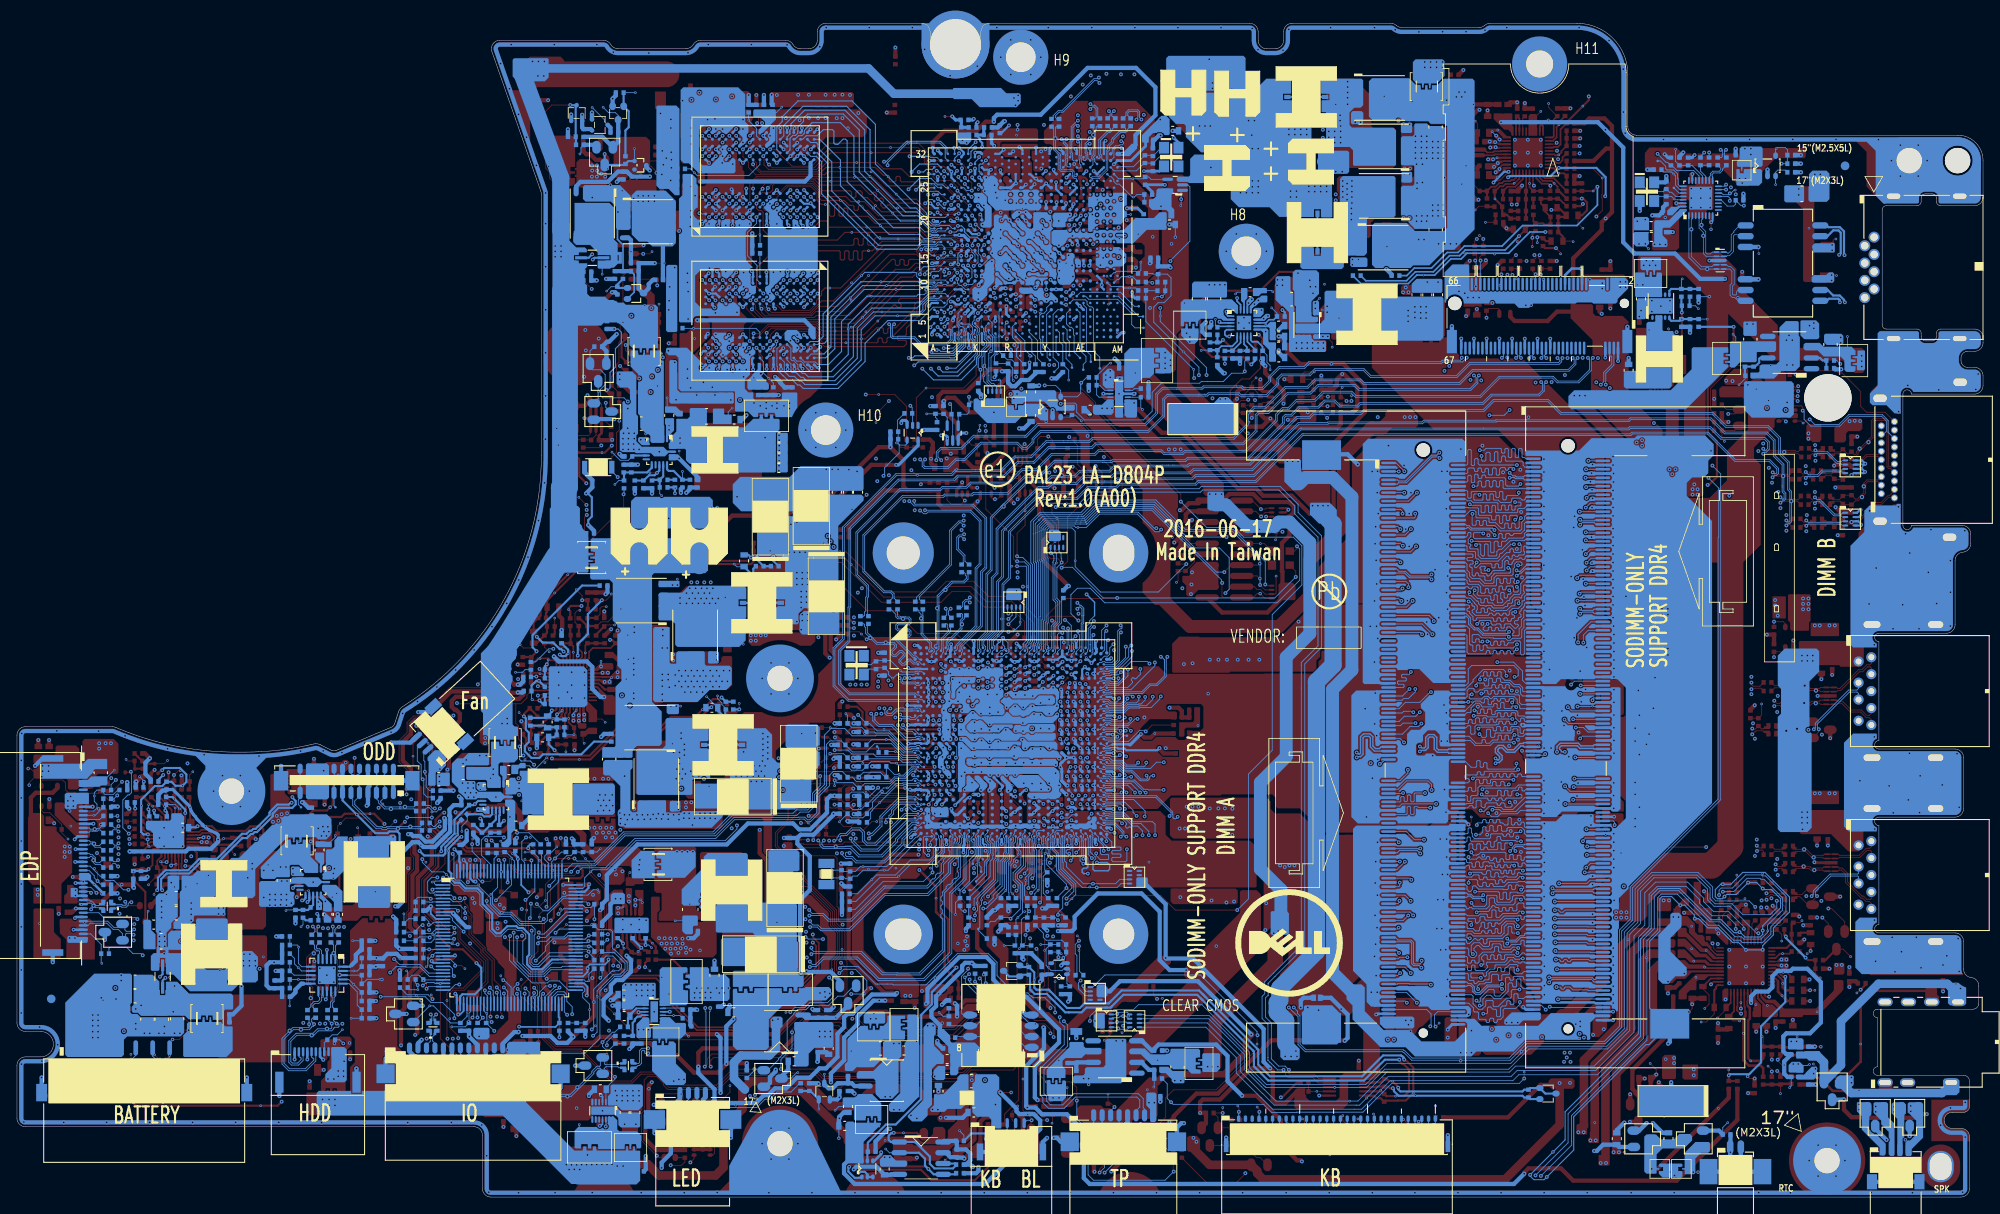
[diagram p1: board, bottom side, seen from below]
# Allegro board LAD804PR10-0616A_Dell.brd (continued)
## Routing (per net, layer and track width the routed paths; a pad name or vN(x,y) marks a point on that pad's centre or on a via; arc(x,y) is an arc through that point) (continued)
MEM_MAB_EVENT#: length 74.9
  TOP w0.102: RC6.2 98.01,55.69 v2(98.76,54.95)
  IN1 w0.127: v2(98.76,54.95) 98.69,54.87 95.59,54.87 93.49,56.97 84.77,56.97 84.64,57.1 84.64,57.36 84.51,57.49 84.28,57.49 84.13,57.33 84.13,57.1 84,56.97 83.75,56.97 83.62,57.1 83.62,57.36 83.49,57.49 83.26,57.49 83.11,57.33 83.11,57.1 82.98,56.97 78.52,56.97 77.62,56.08 73.7,56.08 73.5,56.28 70.43,56.28 69.66,55.52 68.26,55.52 67.39,54.65 65.01,54.65 64.61,54.25 62.71,54.25 61.99,53.52 60.36,53.52 60.07,53.23 58.72,53.23 58.03,53.93 55.65,53.93 v2(55.33,53.61)
  IN2 w0.127: v2(47.52,54.12) 48.71,54.12 48.96,54.37 53.04,54.37 53.88,53.54 55.26,53.54 v2(55.33,53.61)
  BOTTOM w0.102: JDIMM1.134 60.48,53.87 59.9,53.29 58.12,53.29 57.74,53.68 55.58,53.68 55.52,53.61 v2(55.33,53.61) ; v2(98.76,54.95) 98.89,55.07 99.48,55.07 100.81,53.74 101.46,53.74 101.47,53.73 103.14,53.73 UC1.AA41 ; v2(47.52,54.12) 47.26,54.38 JDIMM2.134
MEM_MAB_RST#: length 80.9
  TOP w0.102: CD193.1 48.48,60.58 v2(48.6,60.47)
  IN1 w0.102: v2(105.66,61.76) 105.28,62.14 104.97,62.14 103.83,63.28 103.83,64.55 102.26,66.12 101.49,66.12 101.3,66.31 101.3,67.66 100.87,68.09
  IN1 w0.127: v2(55.26,61.38) 55.66,60.98 56.69,60.98 58.09,62.38 61.66,62.38 63.63,64.34 72.51,64.34 76.62,68.46 100.5,68.46 100.87,68.09
  IN2 w0.127: v2(48.6,60.47) 48.72,60.34 53.11,60.34 54.14,61.38 v2(55.26,61.38)
  BOTTOM w0.102: v2(105.66,61.76) 105.46,61.56 UC1.G38 ; v2(48.6,60.47) 48.19,60.87 JDIMM2.108 ; JDIMM1.108 61.01,60.38 60.73,60.66 60.73,62.31 60.33,62.71 55.33,62.71 54.82,62.21 54.82,61.56 55,61.38 v2(55.26,61.38)
MEM_MAB_ZVDDIO: length 9.1
  TOP w0.508: RC75.1 96.63,52.34 97.14,52.85 v2(97.14,52.98)
  BOTTOM w0.15: 103.6,52.96 103,52.96 102.93,53.03 102.12,53.03
  BOTTOM w0.152: UC1.AB41 103.6,52.96
  BOTTOM w0.254: 102.12,53.03 102,52.91 101.24,52.91 101.05,52.72 97.39,52.72 v2(97.14,52.98)
MEM_VOLT_SEL: length 16.6
  TOP w0.102: v2(122.01,48.56) 122.3,48.27 125.19,48.27 126.3,47.16 131.17,47.16 v1(131.75,47.74) 132.63,48.62 134.25,48.62 RC928.2 RC929.1
  BOTTOM w0.1: v2(122.01,48.56) 122.06,48.56 122.26,48.76 UC1.AJ7
MIC1-L: length 3.1
  TOP w0.203: CA26.1 22.56,25.94 23.12,26.5 23.53,26.5 23.54,26.51 v1(23.57,26.51) 23.65,26.51 24.02,26.88 24.35,26.88 24.47,27 UA1.19
MIC_CLK_C: length 7.1
  TOP w0.102: v1(28.09,35.21) 28.09,35.17 28.19,35.07 LA1.2 29.06,35.06 CA39.1 29.94,34 30.74,33.2 30.74,32.24 29.36,30.86 UA1.3
MIC_DATA_C: length 4.3
  TOP w0.102: RA55.2 31.15,33.58 v1(31.15,32.87) 31.15,32.07 29.76,30.69 29.76,30.67 29.76,30.67 UA1.2
OCP_L: length 105.6
  TOP w0.203: PU1100.4 50.7,123.84 50.62,123.92 50.13,123.92 49.84,124.21 49.84,125.99 PR1112.2
  TOP w0.254: v2(112.92,103.4) 113.04,103.28 RV90.2 113.59,102.42 RV91.1 ; v2(46.5,129.88) 46.5,129.43 v1(47.2,128.73) 49.12,126.82 PR1112.2
  IN2 w0.254: v2(46.5,129.88) 46.67,130.04 57.94,130.04 59.68,131.78 68.35,131.78 70.31,133.75 80.6,133.75 81.3,133.05 105.68,133.05 109.75,128.99 109.75,125.11 109.49,124.86 109.49,123.21 108.73,122.45 108.73,117.05 108.41,116.73 108.41,114.32 110.51,112.22 110.51,111.27 111.53,110.25 111.53,108.86 113.56,106.83 113.56,105.3 113.49,105.24 113.49,104.86 113.56,104.79 113.56,103.9 113.05,103.4 v2(112.92,103.4)
ODD_DA#: length 4.8
  BOTTOM w0.102: T75.1 198.71,46.31 198.71,46.88 198.5,47.09 JODD1.23 JODD1.24
ODD_DETECT#: length 5
  BOTTOM w0.102: JODD1.16 194.5,49.95 194.08,49.52 194.08,48.94 194.5,48.51 JODD1.15 194.5,46.16 T74.1
ON/OFF#: length 92.6
  TOP w0.102: v2(161.04,84.95) 161.74,85.65 SW1.2 161.74,87.33 161.18,87.89 161.18,90.19 160.85,90.52 v4(160.85,91.59) CE20.1 EC2901.1 160.89,93.78 ED2901.1 160.89,94.89 RE49.2 161.77,96.84 161.18,97.43 161.18,98.23 160.89,98.52 160.89,100.87 160.75,101.01 160.75,103.7 160.43,104.02 160.43,108.69 159.82,109.31 JPWR1.3
  IN1 w0.127: v2(174.42,39.8) 175.22,40.59 175.22,42.37 176.3,43.45 177.35,43.45 178.72,42.08 179.77,42.08 180.83,43.14 180.83,47.73 180.87,47.77 180.87,48.15 180.61,48.41 180.61,49.63 180.25,49.99 179.34,49.99 178.11,51.22 178.11,53.31 176.46,54.96 173.68,54.96 173.24,55.41 173.24,57.74 172.8,58.18 172.32,58.18 170.9,59.61 170.17,59.61 169.44,60.34 169.44,61.36 166.71,64.09 166.71,65.06 164.78,67 164.78,71.16 161.25,74.69 161.25,83.15 161.04,83.36 v2(161.04,84.95)
  BOTTOM w0.102: UE1.114 v2(174.42,39.8) ; SW1.2 161.74,85.65 v2(161.04,84.95)
P_ZVDDP: length 14
  TOP w0.254: RC542.2 133.45,55.36 132.58,55.36 v1(131.92,54.7) 121.73,54.7 v2(121.27,55.16)
  BOTTOM w0.2: UC1.U8 121.46,55.35 v2(121.27,55.16)
P_ZVSS: length 14
  TOP w0.254: v2(121.11,54.06) 121.62,53.55 123.77,53.55 124.06,53.26 124.07,53.26 124.4,52.93 v1(127.97,52.93) 133.85,52.93 RC541.1
  BOTTOM w0.2: v2(121.11,54.06) 121.11,54.26 UC1.W8
PANEL_BKLEN: length 130.7
  TOP w0.102: v2(176.49,34.94) 176.49,35.24 v1(175.99,35.73) ; RC60.1 111.53,89.43 111.21,89.74 v2(110.26,89.74) 110.19,89.74 109.75,89.3 QC2.1 109.51,88.36 RC70.1
  IN1 w0.127: v2(147.59,43.52) 147.59,43.83 146.9,44.53 146.03,44.53 143.27,44.53 138.89,48.91 138.89,49.85 139.21,50.16 139.21,50.75 139.21,50.75 139.21,50.96 139.21,51.17 139.21,57.34 137.03,59.52 137.03,64.11 136.55,64.6 136.55,66.24 135.4,67.39 135.4,68.96 134.38,69.98 126.25,69.98 126.16,69.89 125.02,69.89 119.34,75.58 119.34,82.42 118.93,82.82 118.26,82.82 116.99,81.55 116.71,81.55 111.32,86.94 111.32,88.68 v2(110.26,89.74) ; v2(176.49,34.94) 176.49,35.01 175.72,35.77 174.26,35.77 174.01,35.51 171.09,35.51 170.77,35.83 168.17,35.83 167.79,35.45 165.82,35.45 164.87,36.4 164.23,36.4 163.22,37.42 v2(163.22,37.99)
  IN2 w0.127: v2(163.22,37.99) 163.22,38.5 161.64,40.07 161.64,40.5 158.79,43.35 147.76,43.35 v2(147.59,43.52)
  BOTTOM w0.102: UE1.76 169.09,28.82 170.49,27.42 170.93,27.42 171.18,27.67 171.18,28.06 170.9,28.34 170.9,30.88 170.78,30.99 170.78,31.61 171.23,32.05 172.65,32.05 173.7,33.1 175.03,33.1 176.49,34.56 v2(176.49,34.94)
PANEL_BKLEN_EC: length 30.2
  TOP w0.102: v2(109.45,85.67) 109.45,85.9 110.25,86.7 QC2.3 110.78,86.7 RC60.2 111.68,87.59 112.67,87.59 112.81,87.45 RPC45.5 ; v2(113.94,74.44) v1(114.57,74.44)
  IN2 w0.127: v2(113.94,74.44) 113.85,74.53 113.77,74.53 113.49,74.8 113.49,79.58 111.65,81.43 111.65,83.17 109.45,85.37 v2(109.45,85.67)
  BOTTOM w0.102: v2(113.94,74.44) 112.9,74.44 112.8,74.34 112.8,65.72 113.21,65.31 113.21,65.2 113.21,65.19 113.21,64.69 113.56,64.34 UC1.B23
PBTN_OUT#: length 70.1
  TOP w0.102: v2(166.53,38.38) 166.76,38.15 v1(171.34,38.15) 172.85,38.15 173.79,39.1 173.79,39.93 174.1,40.24 175.32,40.24 175.66,39.9 175.66,37.67 176.11,37.23 v2(176.99,37.23)
  BOTTOM w0.102: UC1.AD2 125.16,51.86 125.48,52.17 125.75,52.17 125.84,52.09 127.34,52.09 128.75,53.5 130.75,53.5 131.73,52.52 133.34,52.52 RC942.2 134.2,53.36 134.67,53.83 136,53.83 136.42,53.41 136.42,48.53 137.56,47.39 137.56,45.35 138.39,44.52 138.67,44.52 138.97,44.82 139.75,44.82 139.78,44.79 147.34,44.79 149.5,42.63 160.17,42.63 163.72,39.08 165.83,39.08 v2(166.53,38.38) ; UE1.122 177.62,37.66 177.19,37.23 v2(176.99,37.23)
PC_BEEP: length 4.2
  TOP w0.102: DA3.1 16.5,29.25 v1(15.62,28.36)
  TOP w0.254: DA3.1 18.59,27.96 RA49.2
PC_BEEP_C: length 9
  TOP w0.102: RA45.2 19.78,26.45 v1(19.2,25.86)
  TOP w0.254: RA45.2 RA49.1 20.64,27.96 v2(20.94,28.25) CA41.2 ; CA42.1 23.44,30.93 v2(23.26,30.75)
  BOTTOM w0.254: v2(20.94,28.25) 23.26,30.57 v2(23.26,30.75)
PCC_GPIO_6: length 4.9
  TOP w0.102: RV90.1 114.25,103.54 CVT90.2 ; RV90.1 113.82,104.42 113.82,104.85 v2(114.04,105.07) ; RV90.1 113.53,104.2 113.18,103.84 112.73,103.84 112.42,103.52 v1(112.42,103.02)
  BOTTOM w0.102: UV1.T8 113.61,105.5 v2(114.04,105.07)
PCIE_ARX_DTX_N0: length 164.1
  IN2 w0.102: 126.33,58.62 126.31,58.61 126.31,58.59 125.06,57.34 124.07,57.34 124.07,57.34 123.87,57.34 123.35,56.82 123.35,56.62 123.35,56.39 123.23,56.28 v2(123.11,56.28)
  IN2 w0.127: v2(30.95,123.57) 30.9,123.57 30.64,123.3 30.64,122.84 31.08,122.4 41.71,122.4 42.89,121.22 42.89,115.89 46.87,111.92 46.87,111.74 46.87,109.82 46.87,109.4 47.54,108.73 47.54,108.09 49.98,105.65 49.98,99.21 50.18,99.01 v2(50.2,99.01) ; v2(124.79,87.04) 124.79,85.41 123.87,84.49 123.87,77.82 123.86,77.81 123.86,77.5 123.76,77.4 123.76,74.59 129.55,68.79 129.55,60.39 128.69,59.53 127.23,59.53 126.33,58.62
  BOTTOM w0.102: CL2.1 30.86,122.67 30.76,122.77 30.76,122.96 30.71,123.01 30.71,123.47 30.81,123.57 v2(30.95,123.57) ; v2(124.79,87.04) 124.8,87.04 124.92,86.92 124.92,86.31 124.8,86.19 122.13,86.19 121.21,87.11 120.19,87.11 118.24,89.06 113.86,89.06 113.25,88.45 112.82,88.45 112.16,89.11 112.16,89.49 111.2,90.44 98.53,90.44 96.74,92.22 96.74,94.04 96.74,94.21 96.23,94.73 96.06,94.73 92.48,94.73 91.56,94.73 91.38,94.9 87.73,94.9 87.53,94.7 84.54,94.7 83.28,95.95 83.28,96.59 82.76,97.11 79.45,97.11 78.82,97.74 73.01,97.74 72.19,96.92 62.13,96.92 60.58,98.47 50.08,98.47 49.91,98.64 49.91,98.72 50.19,99.01 v2(50.2,99.01) ; v2(123.11,56.28) 123.15,56.28 123.39,56.04 123.39,55.86 123.24,55.71 UC1.U5
PCIE_ARX_DTX_N0_C: length 3
  BOTTOM w0.102: UL1.18 32.29,120.36 32.16,120.49 32.16,120.76 31.87,121.05 31.11,121.05 30.93,121.22 30.93,121.39 CL2.2
PCIE_ARX_DTX_N1: length 119.7
  IN2 w0.102: v2(120.53,56.26) 120.81,56.54 120.81,56.79 121.05,57.03 122.72,57.03 123.76,58.06 124.76,58.06 125.57,58.88 125.57,59.21 126.33,59.96
  IN2 w0.127: v2(122.88,86.95) 122.88,86.94 123.2,86.62 123.2,86.39 122.97,86.16 122.97,85.36 122.97,78.19 122.96,78.18 122.96,77.87 122.82,77.73 122.82,74.25 128.34,68.73 128.34,61.02 127.8,60.48 126.85,60.48 126.69,60.33 126.33,59.96 ; v2(60.9,99.04) 61.07,99.21 61.07,99.5 60.9,99.67 53.47,99.67 53.31,99.51 53.31,99.22 v2(53.55,98.98)
  BOTTOM w0.102: JWLAN1.35 53.55,99.42 53.4,99.27 53.4,99.13 v2(53.55,98.98) ; v2(122.88,86.95) 122.89,86.95 123.26,87.32 123.26,87.85 122.86,88.25 120.45,88.25 119.02,89.68 113.12,89.68 113,89.68 112.83,89.68 111.44,91.06 98.77,91.06 97.37,92.46 97.37,94.7 96.73,95.34 95.11,95.34 92.23,95.34 92.06,95.34 91.88,95.51 87.99,95.51 87.48,95.51 87.28,95.31 84.94,95.31 84.03,96.22 84.03,96.39 84.03,96.39 84.03,96.73 82.96,97.8 80.01,97.8 79.44,98.37 63.88,98.37 63.7,98.54 61.4,98.54 v2(60.9,99.04) ; UC1.R10 120.8,56.67 120.8,56.36 120.7,56.26 v2(120.53,56.26)
PCIE_ARX_DTX_P0: length 164.2
  IN2 w0.102: v2(123.81,56.27) 123.69,56.27 123.59,56.37 123.59,56.72 123.97,57.1 125.16,57.1 126.48,58.42 126.49,58.42 126.51,58.44
  IN2 w0.127: 126.51,58.44 127.34,59.27 128.8,59.27 129.82,60.29 129.82,68.9 124.02,74.7 124.02,77.29 124.12,77.39 124.12,77.7 124.13,77.71 124.13,84.38 125.05,85.3 125.05,86.35 125.37,86.67 v2(125.37,87.04) ; v2(49.61,99.01) 49.71,99.11 49.71,105.54 47.27,107.98 47.27,108.62 46.6,109.29 46.6,109.93 46.6,111.81 42.63,115.78 42.63,121.11 41.6,122.14 30.97,122.14 30.37,122.73 30.37,123.51 v2(30.31,123.57)
  BOTTOM w0.102: CL1.1 30.5,122.89 30.5,123.38 v2(30.31,123.57) ; v2(123.81,56.27) 123.69,56.27 123.59,56.16 123.59,55.81 123.69,55.71 UC1.U4 ; v2(49.61,99.01) 49.7,98.92 49.7,98.56 49.99,98.27 60.5,98.27 62.05,96.72 72.27,96.72 73.1,97.54 78.74,97.54 79.37,96.91 82.67,96.91 83.08,96.5 83.08,96.04 83.08,95.87 84.45,94.49 87.61,94.49 87.82,94.7 91.3,94.7 91.47,94.52 91.72,94.52 92.56,94.52 92.56,94.52 96.14,94.52 96.54,94.13 96.54,92.14 98.44,90.24 111.12,90.24 111.96,89.4 111.96,89.02 112.74,88.24 113.33,88.24 113.94,88.85 118.16,88.85 120.11,86.91 121.13,86.91 122.05,85.98 124.88,85.98 125.13,86.23 125.13,86.82 125.35,87.04 v2(125.37,87.04)
PCIE_ARX_DTX_P0_C: length 3
  BOTTOM w0.102: UL1.17 31.89,120.42 31.96,120.48 31.96,120.68 31.79,120.85 31.02,120.85 30.73,121.14 30.73,121.3 CL1.2
PCIE_ARX_DTX_P1: length 119.7
  IN2 w0.102: v2(121.33,56.26) 121.05,56.54 121.05,56.69 121.15,56.79 122.82,56.79 123.85,57.82 124.85,57.82 125.86,58.83 125.86,59.12 126.51,59.77
  IN2 w0.127: v2(123.46,86.95) 123.46,86.28 123.23,86.05 123.23,85.25 123.23,78.09 123.22,78.08 123.22,77.76 123.08,77.62 123.08,74.36 128.61,68.84 128.61,60.91 127.91,60.22 126.96,60.22 126.51,59.77 ; v2(61.49,99.04) 61.34,99.19 61.34,99.61 61.01,99.94 53.36,99.94 53.04,99.62 53.04,99.06 v2(52.96,98.98)
  BOTTOM w0.102: v2(52.96,98.98) 53.2,99.21 53.2,99.28 53.05,99.43 JWLAN1.33 ; v2(61.49,99.04) 61.49,98.9 61.64,98.75 63.79,98.75 63.96,98.57 79.52,98.57 80.09,98 83.05,98 84.23,96.81 84.23,96.64 84.23,96.3 85.03,95.51 87.19,95.51 87.4,95.71 88.07,95.71 91.97,95.71 92.14,95.54 95.02,95.54 95.02,95.54 96.81,95.54 97.57,94.78 97.57,92.55 98.85,91.27 111.36,91.27 111.53,91.27 112.91,89.88 113,89.88 119.1,89.88 120.53,88.45 122.78,88.45 122.95,88.45 123.46,87.94 v2(123.46,86.95) ; v2(121.33,56.26) 121.33,56.68 UC1.R8
PCIE_ATX_C_DRX_N0: length 144.1
  IN2 w0.127: v2(46.6,99.03) 46.44,99.19 46.44,106.64 45.74,107.34 45.74,107.98 44.79,108.93 44.79,109.08 44.79,111.05 44.79,111.27 42.61,113.45 42.45,113.6 42.23,113.6 38.74,113.6 37.08,115.26 36.86,115.26 36.86,115.26 33.51,115.26 32.68,114.44 31.3,114.44 30.68,115.06 30.68,117.49 30.68,117.49 30.68,117.54 30.68,117.65 30.68,117.65 30.68,118.07 30.5,118.26 30.05,118.26 v2(29.87,118.44)
  BOTTOM w0.102: v1(29.23,118.83) 29.36,118.83 29.75,118.44 v2(29.87,118.44) 30.03,118.28 30.65,118.28 30.85,118.47 UL1.14 ; CC225.2 132.02,68.55 131.92,68.65 131.92,69.04 131.8,69.17 131.8,70.78 131.66,70.92 131.66,72.09 132.94,73.38 132.94,78.44 127.8,83.58 123.03,83.58 122.76,83.85 119.96,83.85 119.45,84.36 114.99,84.36 113.42,85.93 111.71,85.93 109.91,87.74 104.8,87.74 104.37,88.17 96.9,88.17 96.54,87.81 94.47,87.81 94.17,88.11 87.02,88.11 83.46,91.66 83.46,92.35 82.63,93.17 81.94,93.17 81,94.11 78.84,94.11 77.87,95.08 74.44,95.08 73.95,94.58 59.33,94.58 57.07,96.84 50.7,96.84 50.14,96.28 47.75,96.28 46.41,97.62 46.41,98.83 v2(46.6,99.03)
PCIE_ATX_C_DRX_N1: length 103.4
  IN2 w0.127: v2(52.09,99.01) 51.93,98.85 51.93,96.35 v2(52.12,96.17)
  BOTTOM w0.102: JWLAN1.29 52.05,99.48 51.91,99.34 51.91,99.19 v2(52.09,99.01) ; v2(52.12,96.17) 51.96,96.01 51.96,95.19 52.42,94.73 58.03,94.73 59.02,93.74 73.49,93.74 73.81,93.43 75.82,93.43 76.43,94.04 77.7,94.04 78.44,93.3 80.67,93.3 81.61,92.36 82.3,92.36 82.63,92.02 82.63,91.34 86.69,87.28 93.85,87.28 94.13,87 102.72,87 102.83,86.89 103.76,86.89 103.79,86.92 109.56,86.92 111.36,85.12 113.08,85.12 115.07,83.13 119.11,83.13 119.3,82.95 122.52,82.95 122.69,82.77 127.46,82.77 132.12,78.11 132.12,73.76 129.67,71.32 128.84,71.32 128.65,71.12 128.65,70.67 CC227.2
PCIE_ATX_C_DRX_P0: length 143.3
  IN2 w0.127: v2(29.87,117.56) 29.85,117.58 29.78,117.58 29.66,117.69 29.66,117.87 29.79,118 30.29,118 30.41,117.87 30.41,117.6 30.42,117.6 30.42,114.95 31.19,114.17 32.79,114.17 33.62,115 36.97,115 38.63,113.34 42.34,113.34 44.52,111.16 44.52,109.19 44.52,108.83 45.48,107.87 45.48,107.23 46.18,106.53 46.18,99.18 v2(46.02,99.03)
  BOTTOM w0.102: v2(29.87,117.56) 29.79,117.64 29.79,117.79 30.07,118.07 UL1.13 ; v2(46.02,99.03) 46.21,98.84 46.21,97.53 47.66,96.08 50.23,96.08 50.78,96.64 56.99,96.64 59.25,94.38 74.03,94.38 74.53,94.87 77.79,94.87 78.75,93.91 80.92,93.91 81.86,92.97 82.03,92.97 82.55,92.97 83.26,92.26 83.26,91.58 86.93,87.9 94.09,87.9 94.38,87.61 94.72,87.61 96.63,87.61 96.98,87.97 104.29,87.97 104.72,87.53 109.82,87.53 111.63,85.73 113.33,85.73 114.91,84.16 119.37,84.16 119.88,83.65 122.68,83.65 122.95,83.38 127.72,83.38 132.74,78.36 132.74,73.46 131.45,72.17 131.45,70.83 131.59,70.69 131.59,68.67 CC224.2
PCIE_ATX_C_DRX_P1: length 103.5
  IN2 w0.127: v2(51.53,96.17) 51.63,96.26 51.63,96.32 51.67,96.35 51.67,98.85 v2(51.51,99.01)
  BOTTOM w0.102: JWLAN1.27 51.55,99.5 51.71,99.34 51.71,99.21 v2(51.51,99.01) ; CC226.2 128.44,70.67 128.44,71.2 128.76,71.52 129.59,71.52 131.92,73.85 131.92,78.03 127.38,82.57 122.61,82.57 122.43,82.75 119.21,82.75 119.03,82.93 114.98,82.93 113,84.92 111.28,84.92 109.47,86.72 103.87,86.72 103.84,86.69 102.91,86.69 102.74,86.69 102.64,86.8 94.05,86.8 93.77,87.08 86.61,87.08 82.43,91.26 82.43,91.42 82.43,91.94 82.21,92.16 81.52,92.16 80.58,93.1 78.36,93.1 77.62,93.84 76.52,93.84 75.9,93.22 73.72,93.22 73.41,93.54 58.94,93.54 57.95,94.53 52.34,94.53 51.76,95.11 51.76,95.94 v2(51.53,96.17)
PCIE_ATX_DRX_N0: length 12.8
  BOTTOM w0.102: UC1.D1 125.65,62.9 126.19,62.9 126.56,63.27 126.71,63.27 127.22,62.76 127.53,62.76 127.87,63.1 127.87,63.41 127.35,63.92 127.35,64.06 127.57,64.28 127.71,64.28 128.23,63.77 128.54,63.77 128.87,64.1 128.87,64.41 128.36,64.93 128.36,65.07 128.52,65.23 129.12,65.23 129.15,65.21 129.72,65.21 129.74,65.23 130.52,65.23 v3(131.24,65.96) 131.8,66.51 131.8,67.18 131.92,67.31 131.92,67.54 132.02,67.64 132.41,67.64 CC225.1
PCIE_ATX_DRX_N1: length 13
  BOTTOM w0.102: UC1.C1 125.96,63.55 126.06,63.65 126.2,63.65 128.24,65.69 128.24,66.09 128.02,66.31 126.75,66.31 126.65,66.41 126.65,66.71 126.75,66.82 128.02,66.82 128.24,67.04 128.24,67.51 128.02,67.73 126.75,67.73 126.65,67.83 126.65,68.14 126.75,68.24 v3(127.4,68.24) 128.02,68.24 128.24,68.46 128.24,68.77 128.82,69.35 CC227.1
PCIE_ATX_DRX_P0: length 12.8
  BOTTOM w0.102: UC1.D2 125.18,62.86 125.48,63.16 125.74,63.16 125.8,63.1 126.11,63.1 126.48,63.48 126.79,63.48 127.3,62.96 127.45,62.96 127.66,63.18 127.66,63.32 127.15,63.84 127.15,64.15 127.49,64.48 127.8,64.48 128.31,63.97 128.45,63.97 128.67,64.19 128.67,64.33 128.16,64.84 128.16,65.15 128.44,65.44 v3(129.43,65.44) 130.43,65.44 130.88,65.89 130.88,65.92 131.28,66.32 131.32,66.32 131.59,66.6 131.59,67.51 CC224.1
PCIE_ATX_DRX_P1: length 12.9
  BOTTOM w0.102: CC226.1 128.04,68.54 127.93,68.44 127.71,68.44 127.68,68.47 127.12,68.47 127.09,68.44 126.67,68.44 126.45,68.22 126.45,67.75 126.67,67.53 127.93,67.53 128.04,67.43 128.04,67.12 127.93,67.02 126.67,67.02 126.45,66.8 126.45,66.32 126.67,66.1 127.93,66.1 128.04,66 128.04,65.77 126.12,63.85 125.85,63.85 125.41,63.41 UC1.C2
PEG_CLKREQ#: length 224.1
  TOP w0.102: v2(106.64,30.24) 106.64,30.63 v1(106.83,30.82)
  IN1 w0.127: v2(114.04,96.79) 113.83,97 112.34,97 110.13,99.21 108.84,99.21 103.68,94.04 101.34,94.04 98.44,91.14 87.62,91.14 87.24,91.52 85.55,91.52 84.54,92.54 80.21,92.54 79.71,92.03 79.01,92.03 78.59,92.45 60.76,92.45 59.7,91.39 41.56,91.39 38.74,88.57 38.74,85.6 38.74,83.09 36.75,81.09 36.75,45.07 45.41,36.4 45.42,36.4 45.61,36.21 45.61,25.93 51.01,20.53 52.98,20.53 53.04,20.47 53.82,20.47 54.59,19.7 57.17,19.7 58.12,18.75 61.57,18.75 62.5,18.75 62.95,18.31 68.28,18.31 69.24,19.26 72.73,19.26 77.62,24.15 97.43,24.15 99.91,26.62 100.1,26.62 100.14,26.58 102.18,26.58 105.85,30.24 v2(106.64,30.24)
  BOTTOM w0.102: RC56.2 106.88,26.33 106.88,28.52 107.08,28.72 107.08,29.8 v2(106.64,30.24) ; RV153.1 v2(114.04,96.79)
PEG_CLKREQ#_G: length 7.6
  BOTTOM w0.102: RV153.2 114.55,98.79 115.08,98.79 RV368.2 116.07,99.78 116.07,104.53 UV1.N7
PEG_CLKREQ#_R: length 20.7
  TOP w0.102: v2(106.64,29.61) v1(106.64,29.1)
  IN1 w0.127: v2(107.53,44.47) 106.57,43.51 106.57,38.66 106.25,38.34 106.25,35.05 106.61,34.68 106.61,31.09 107.08,30.62 107.08,30.05 v2(106.64,29.61)
  BOTTOM w0.102: UC1.AV35 107.37,44.31 v2(107.53,44.47) ; RC56.1 106.59,26.65 106.59,29.56 v2(106.64,29.61)
PEG_GTX_C_HRX_N0: length 92.2
  IN2 w0.102: 125.44,65.55 125.44,65.44 125.42,65.41 125.42,64.93 125.99,64.36 125.99,60.2 124.69,58.9 123.36,58.9 123.21,58.74 123.18,58.67 123.38,58.44 v2(123.52,58.43)
  IN2 w0.127: 125.44,65.55 125.44,69.45 118.52,76.37 118.52,81.34 118.14,81.73 118.14,86.43 114.31,90.26 113.2,90.26 111.12,92.34 109.47,92.34 105.63,96.19 104.89,96.19 104.42,96.65 104.42,97.44 104.42,97.66 104.42,97.66 103.8,98.29 102.35,98.29 96.16,104.48 96.16,107.39 96.41,107.64 96.8,108.03 96.8,115.53 100.37,119.1 100.37,119.32 100.37,121.85 99.83,122.39 99.83,124.22 100.9,125.29 103.02,127.41 103.02,128.06 v2(103.1,128.14)
  BOTTOM w0.102: UC1.L4 123.86,58.78 v2(123.52,58.43) ; CV2.2 102.97,127.58 102.97,128.01 v2(103.1,128.14)
PEG_GTX_C_HRX_N1: length 96
  IN2 w0.102: 124.51,65.55 124.51,65.44 124.48,65.41 124.48,64.72 125.16,64.04 125.16,60.43 124.71,59.98 123.31,59.98 123.17,59.83 123.17,59.64 123.27,59.53 v2(123.52,59.53)
  IN2 w0.127: 124.51,65.55 124.51,69.39 117.75,76.14 117.75,80.87 117.44,81.19 117.44,85.66 113.54,89.56 112.52,89.56 112.08,90.01 110.57,91.52 110.35,91.52 110.35,91.52 109.11,91.52 106.48,94.15 105.37,94.15 103.8,95.71 103.33,95.71 102.52,96.52 102.52,96.97 102.36,97.12 95.38,104.11 95.38,115.9 95.38,116.01 99.66,120.29 99.66,121.36 99.14,121.88 99.14,124.53 100.99,126.38 100.99,128.23 101.41,128.66 105,128.66 105.28,128.38 v2(105.28,128.38)
  BOTTOM w0.102: CV4.2 104.74,127.28 104.62,127.4 104.62,128.39 104.85,128.63 105.06,128.63 105.28,128.4 v2(105.28,128.38) ; v2(123.52,59.53) 123.46,59.59 123.46,60.01 123.56,60.11 UC1.J4
PEG_GTX_C_HRX_N2: length 87.3
  IN2 w0.102: 123.66,65.55 123.66,65.44 123.64,65.41 123.64,63.03 123.65,63.02 123.65,61.97 123.13,61.45 123.13,60.7 123.23,60.6 123.46,60.6 v2(123.53,60.67)
  IN2 w0.127: v2(99.85,127.15) 99.75,127.04 99.75,126.61 98.44,125.3 98.44,122.35 98.44,120.06 94.68,116.3 94.68,116.3 94.68,116.08 94.67,116.07 94.67,103.76 100.29,98.14 100.29,97.41 103.38,94.32 103.72,94.32 104.75,93.28 106.26,93.28 109.03,90.52 110.5,90.52 115.98,85.03 115.98,81.66 117.06,80.58 117.06,75.84 123.66,69.23 123.66,65.55
  BOTTOM w0.102: UC1.G4 123.82,61.25 123.57,61.25 123.39,61.08 123.39,60.77 123.49,60.67 v2(123.53,60.67) ; CV6.2 100.88,127.63 100.88,127.91 100.71,128.08 99.79,128.08 99.69,127.98 99.69,127.31 v2(99.85,127.15)
PEG_GTX_C_HRX_N3: length 102.2
  IN2 w0.102: v2(122.9,62.1) 122.62,62.39 122.38,62.39 122.14,62.63 122.14,63.71 121.81,64.04 120.95,64.04 119.86,65.13 119.86,65.51 119.85,65.52 119.85,65.55
  IN2 w0.127: v2(104.29,132.1) 104.22,132.03 99.59,132.03 99.21,131.65 93.72,126.16 92.85,125.29 92.85,120.52 92.09,119.76 92.09,119.48 92.09,103.42 92.1,103.41 92.1,103.06 92.09,103.05 92.09,100.37 92.09,99.76 92.09,99.76 92.09,99.54 94.71,96.91 94.72,96.91 99.23,92.41 100.16,91.48 100.16,91.47 100.93,90.7 102.97,90.7 103.7,90.7 103.72,90.7 107.47,86.94 109.27,86.94 112.29,83.92 112.29,81.75 114.69,79.35 114.69,73.5 119.85,68.34 119.85,65.55
  BOTTOM w0.102: CV8.2 109.68,127.41 109.68,127.59 109.05,128.22 108.61,128.22 104.86,131.97 104.41,131.97 v2(104.29,132.1) ; v2(122.9,62.1) 122.55,62.1 UC1.E7
PEG_GTX_C_HRX_P0: length 92.2
  IN2 w0.102: 125.18,65.55 125.18,64.83 125.75,64.26 125.75,60.3 124.59,59.14 123.26,59.14 123,58.87 122.93,58.67 v2(122.72,58.48)
  IN2 w0.127: 125.18,65.55 125.18,69.34 118.26,76.26 118.26,81.23 117.88,81.62 117.88,86.32 114.2,90 113.09,90 111.01,92.08 109.36,92.08 105.52,95.92 104.78,95.92 104.16,96.54 104.16,97.55 103.69,98.02 102.25,98.02 95.89,104.37 95.89,107.5 96.54,108.14 96.54,115.64 100.11,119.21 100.11,121.74 99.57,122.28 99.57,124.33 100.64,125.4 100.64,125.4 102.75,127.52 102.75,127.9 v2(102.51,128.14)
  BOTTOM w0.102: UC1.L5 123.06,58.83 v2(122.72,58.48) ; CV1.2 102.47,127.3 102.76,127.59 102.76,127.89 v2(102.51,128.14)
PEG_GTX_C_HRX_P1: length 96
  IN2 w0.102: 124.24,65.55 124.24,64.63 124.92,63.94 124.92,60.53 124.61,60.22 123.23,60.22 122.96,59.94 122.96,59.71 122.8,59.55 v2(122.71,59.55)
  IN2 w0.127: v2(105.28,128.97) 105.24,128.92 101.3,128.92 100.72,128.34 100.72,126.49 100.15,125.93 99.03,124.8 98.87,124.64 98.87,122.17 98.87,121.77 99.39,121.25 99.39,120.4 95.11,116.12 95.11,115.9 95.11,115.9 95.11,115.79 95.11,104 95.27,103.84 102.26,96.86 102.26,96.41 103.22,95.45 103.69,95.45 105.26,93.88 106.37,93.88 109,91.25 110.46,91.25 111.97,89.74 112.42,89.3 113.43,89.3 117.18,85.55 117.18,81.08 117.49,80.76 117.49,76.03 124.24,69.28 124.24,65.55
  BOTTOM w0.102: v2(105.28,128.97) 105.15,128.83 104.77,128.83 104.41,128.48 104.41,127.53 CV3.2 ; UC1.J5 123.06,59.9 v2(122.71,59.55)
PEG_GTX_C_HRX_P2: length 87.3
  IN2 w0.102: 123.4,65.55 123.4,62.93 123.41,62.92 123.41,62.07 122.89,61.55 122.89,60.83 v2(122.73,60.67)
  IN2 w0.127: v2(99.27,127.15) 99.48,126.94 99.48,126.72 98.33,125.56 98.18,125.41 98.18,122.46 98.18,120.17 94.42,116.41 94.42,116.36 94.42,116.19 94.4,116.18 94.4,103.87 94.4,103.65 100.02,98.04 100.02,97.3 103.27,94.05 103.61,94.05 104.64,93.02 106.15,93.02 108.92,90.25 110.39,90.25 115.72,84.93 115.72,81.55 116.79,80.48 116.79,75.73 123.4,69.12 123.4,65.55
  BOTTOM w0.102: UC1.G5 123.06,61 v2(122.73,60.67) ; v2(99.27,127.15) 99.49,127.37 99.49,128.07 99.71,128.29 100.79,128.29 101.09,128 101.09,127.63 CV5.2
PEG_GTX_C_HRX_P3: length 102.3
  IN2 w0.102: 120.11,65.55 120.11,65.44 120.1,65.43 120.1,65.23 121.05,64.28 121.91,64.28 122.38,63.81 122.38,62.73 122.48,62.63 122.63,62.63 v2(122.91,62.91)
  IN2 w0.127: v2(104.22,131.46) 104.22,131.57 104.03,131.77 99.7,131.77 99.32,131.39 93.83,125.9 93.11,125.18 93.11,120.41 92.35,119.65 92.35,119.37 92.35,119.37 92.35,118.79 92.35,103.53 92.36,103.52 92.36,102.95 92.35,102.94 92.35,100.27 92.35,100.26 92.35,99.65 94.82,97.18 94.83,97.18 94.91,97.1 95.91,96.1 99.34,92.67 100.42,91.59 100.42,91.58 101.04,90.96 102.86,90.96 103.83,90.96 107.58,87.2 109.38,87.2 112.55,84.03 112.55,81.86 114.96,79.46 114.96,73.61 120.03,68.53 120.11,68.45 120.11,68.45 120.11,68.11 120.11,68.11 120.11,65.55
  BOTTOM w0.102: CV7.2 109.27,127.22 109.42,127.37 109.42,127.57 108.96,128.02 108.69,128.02 108.52,128.02 104.77,131.77 104.52,131.77 104.22,131.47 v2(104.22,131.46) ; v2(122.91,62.91) 122.94,62.88 122.94,62.68 122.61,62.35 122.41,62.35 122.28,62.48 122.28,62.63 UC1.D7
PEG_GTX_HRX_N0: length 5.1
  BOTTOM w0.102: CV2.1 102.93,126.06 102.93,125.93 103.05,125.81 103.26,125.81 104.3,124.77 104.3,122.98 104.22,122.9 104.22,122.88 104.15,122.81 104.15,122.67 104.16,122.66 104.16,122.65 104.25,122.56 104.36,122.56 UV1.AG31
PEG_GTX_HRX_N1: length 5.2
  BOTTOM w0.102: UV1.AF28 104.99,121.81 104.99,122.42 105.12,122.55 105.12,122.83 104.95,123 v3(104.95,125.33) 104.95,126.25 CV4.1
PEG_GTX_HRX_N2: length 9.2
  BOTTOM w0.089: 102.49,124.84 102.5,124.83 102.51,124.83 102.52,124.83 102.59,124.76 102.59,124.45 103.06,123.98 103.06,123.77 103.05,123.77 103.05,123.55 103.24,123.37 103.24,121.19 104.22,120.2 105,120.2 UV1.AF26
  BOTTOM w0.102: CV6.1 100.92,125.99 100.92,125.83 101.14,125.61 101.73,125.61 102.49,124.84
PEG_GTX_HRX_N3: length 8.5
  BOTTOM w0.089: 109.62,123.58 109.01,122.97 109.01,122.84 109,122.83 109,122.54 109.01,122.52 109.01,122.05 109,122.04 109,121.76 109,121.25 108.8,121.05 108.74,121.05 108.7,121.01 108.3,121.01 108.26,121.05 107.53,121.05 107.39,120.92 107.39,120.41 107.19,120.2 106.99,120.2 106.9,120.12 UV1.AD26
  BOTTOM w0.102: CV8.1 109.62,126.05 109.62,123.58
PEG_GTX_HRX_P0: length 5.1
  BOTTOM w0.102: CV1.1 102.72,126.01 102.72,125.85 102.97,125.61 103.17,125.61 104.09,124.69 104.09,123.06 104.02,122.99 104.02,122.97 103.94,122.9 103.94,122.54 UV1.AH30
PEG_GTX_HRX_P1: length 5.2
  BOTTOM w0.102: UV1.AG29 104.78,122.18 104.78,122.5 104.92,122.64 104.92,122.74 104.75,122.92 104.75,125.02 104.72,125.05 104.72,125.61 104.75,125.64 104.75,125.86 104.61,126 104.61,126.26 104.51,126.36 CV3.1
PEG_GTX_HRX_P2: length 9.3
  BOTTOM w0.089: UV1.AF27 105.39,120.61 105.39,120.38 105.3,120.29 105.18,120.29 105.07,120.4 104.3,120.4 103.41,121.28 103.41,123.46 103.26,123.61 103.26,123.77 103.25,123.77 103.25,124.06 102.78,124.53 102.78,124.83 102.69,124.92 102.65,124.97 102.65,124.97 102.64,124.99
  BOTTOM w0.102: 102.64,124.99 101.81,125.81 101.23,125.81 101.12,125.91 101.12,126.08 101.42,126.37 CV5.1
PEG_GTX_HRX_P3: length 8.6
  BOTTOM w0.089: 109.42,123.65 108.8,123.04 108.8,122.93 108.79,122.92 108.79,122.45 108.8,122.44 108.8,122.15 108.79,122.14 108.79,121.66 108.8,121.65 108.8,121.33 108.72,121.24 108.66,121.24 108.62,121.2 108.38,121.2 108.34,121.24 107.45,121.24 107.2,121 107.2,120.48 107.11,120.4 106.97,120.4 106.85,120.52 106.85,120.65 UV1.AD27
  BOTTOM w0.102: 109.42,123.65 v3(109.42,124.92) 109.42,126.21 109.32,126.31 CV7.1
PEG_HTX_C_GRX_N0: length 6.3
  BOTTOM w0.102: CV306.1 125.05,68.59 125.03,68.56 125.03,68 125.05,67.97 125.05,66.44 124.02,65.41 124.02,64.84 123.95,64.76 123.88,64.76 123.71,64.59 123.71,64.33 124.01,64.03 UC1.B4
PEG_HTX_C_GRX_N1: length 12.1
  BOTTOM w0.102: CV305.1 119.72,73.6 119.72,72.92 120.16,72.47 121.56,72.47 v3(122.38,71.65) 123.16,70.87 123.16,69.8 123.13,69.77 123.13,69.2 123.16,69.18 123.16,64.94 123.16,64.94 123.16,64.68 123.46,64.38 UC1.B5
PEG_HTX_C_GRX_N2: length 4.2
  BOTTOM w0.102: CV309.1 121.8,67.33 121.8,66.71 122.66,65.84 122.66,64.68 122.61,64.62 122.61,64.33 122.69,64.25 122.91,63.77 UC1.B6
PEG_HTX_C_GRX_N3: length 5.5
  BOTTOM w0.102: CV304.1 120.16,68.39 120.16,68.25 120.44,67.97 v3(120.44,67.58) 120.44,67.04 122.09,65.39 122.09,65.07 122.06,65.04 122.06,64.69 122.07,64.68 122.07,64.66 122.18,64.55 UC1.B7
PEG_HTX_C_GRX_P0: length 6.3
  BOTTOM w0.102: UC1.A4 124.01,64.42 124.11,64.31 124.26,64.31 124.36,64.42 124.36,64.56 124.23,64.69 124.23,65.33 125.26,66.36 125.26,66.52 v3(125.25,68.28) 125.25,68.77 125.51,69.02 125.51,69.19 125.66,69.35 CV312.1
PEG_HTX_C_GRX_P1: length 12
  BOTTOM w0.102: CV308.1 120.21,73.73 120.05,73.56 120.05,73.4 119.92,73.27 119.92,73 120.25,72.67 121.64,72.67 122.31,72.01 122.35,72.01 122.75,71.61 122.75,71.57 123.36,70.96 v3(123.36,69.49) 123.36,65.27 123.46,65.17 123.6,65.17 123.7,65.07 123.7,64.91 123.6,64.81 UC1.A5
PEG_HTX_C_GRX_P2: length 4.1
  BOTTOM w0.102: CV307.1 122.37,67.65 122.22,67.65 122.12,67.54 122.12,67.06 122,66.95 122,66.79 122.87,65.93 122.87,64.5 UC1.A6
PEG_HTX_C_GRX_P3: length 5.5
  BOTTOM w0.102: CV313.1 120.8,68.67 120.61,68.86 120.47,68.86 120.37,68.76 120.37,68.33 120.64,68.06 120.64,67.13 121.73,66.04 121.96,66.04 122.17,65.82 122.17,65.59 122.29,65.47 122.29,64.88 UC1.A7
PEG_HTX_GRX_N0: length 77.9
  IN2 w0.127: v2(105.37,124.92) 105.52,124.92 105.81,125.21 105.81,125.88 105.56,126.13 104.73,126.13 104.42,125.82 104.42,120.24 103.41,119.22 103.41,113.82 100.87,111.28 100.87,110.36 102.46,108.78 102.46,108.56 102.46,102.24 110.08,94.61 111.42,94.61 113.71,92.32 115.05,92.32 116.64,90.72 116.65,90.72 117.56,89.81 118.26,89.81 120.25,87.82 120.25,86.23 121.39,85.09 121.39,79.84 121.11,79.56 120.56,79.56 120.24,79.24 v2(120.23,79.24)
  BOTTOM w0.102: v2(105.37,124.92) 105.37,124.82 105.58,124.61 105.59,124.61 105.91,124.28 105.91,123.23 105.81,123.12 105.81,122.89 105.8,122.88 105.8,122.41 105.9,122.31 106.04,122.31 106.14,122.41 106.14,122.66 UV1.AE31 ; v2(120.23,79.24) 120.23,79.25 120.56,79.58 120.71,79.58 121.69,78.6 121.69,74.6 125.46,70.82 125.46,70.52 125.21,70.26 CV306.2
PEG_HTX_GRX_N1: length 69
  IN2 w0.127: v2(106.76,124.54) 106.57,124.35 106.57,118.19 104.36,115.98 104.36,112.18 103.22,111.03 103.22,102.54 110.41,95.35 111.72,95.35 113.96,93.11 115.24,93.11 115.4,92.95 116.89,91.46 118.96,91.46 119.4,91.01 119.4,89.93 121.19,88.14 121.19,87 122.25,85.94 122.25,78.38 121.81,77.94 121.05,77.94 120.51,77.94 120.19,77.62 v2(120.18,77.62)
  BOTTOM w0.102: v2(120.18,77.62) 120.18,77.63 120.47,77.92 120.7,77.92 120.85,77.77 120.85,76.5 120.09,75.74 120.09,75.03 119.69,74.64 CV305.2 ; v2(106.76,124.54) 106.67,124.54 106.57,124.44 106.57,122.97 106.62,122.92 106.62,122.48 106.57,122.43 106.57,121.94 106.41,121.77 106.41,121.53 106.51,121.43 106.83,121.43 UV1.AD28
PEG_HTX_GRX_N2: length 94.6
  IN2 w0.127: v2(121.77,69.43) 121.92,69.58 121.92,69.6 116.1,75.43 116.1,80.1 115.02,81.18 115.02,84.41 110.89,88.54 109.58,88.54 108.95,89.16 108.94,89.16 106.71,91.39 105.34,91.39 104.39,92.35 102.38,92.35 101.94,92.79 101.94,93.69 99.32,96.3 99.32,97.64 93.71,103.25 93.71,103.37 93.71,118.53 95.24,120.07 95.24,120.07 95.4,120.22 95.79,120.61 96.01,120.61 96.01,120.61 97.32,120.61 97.48,120.77 97.48,121.38 97.48,124.01 97.48,124.9 97.48,127.96 97.75,128.23 99.78,130.26 100,130.26 105.23,130.26 106.26,129.24 106.26,127.04 106.38,126.91 106.65,126.91 v2(106.76,127.02)
  BOTTOM w0.102: CV309.2 122.03,68.7 122.03,69.16 v2(121.77,69.43) ; UV1.AC31 107.59,122.81 107.59,123.07 107.69,123.17 107.69,124.61 107.55,124.74 107.55,126.29 106.82,127.02 v2(106.76,127.02)
PEG_HTX_GRX_N3: length 96.3
  IN2 w0.127: v2(119.51,70.16) 119.4,70.27 118.94,70.27 115.4,73.81 115.4,79.71 113.04,82.07 113.04,84.31 109.59,87.76 108.5,87.76 105.69,90.57 105.18,90.57 104.24,91.51 101.13,91.51 92.78,99.86 92.78,100.3 92.78,102.76 92.79,102.77 92.79,103.7 92.78,103.71 92.78,118.97 92.78,119.19 93.55,119.95 93.55,125.01 96.78,128.25 99.5,130.96 100.29,130.96 105.55,130.96 108.23,128.28 108.23,125.99 108.66,125.57 108.66,124.86 v2(108.68,124.83)
  BOTTOM w0.102: v2(108.68,124.83) 108.49,124.64 108.49,124.37 108.16,124.03 108.16,123.01 108.18,122.99 108.18,122.97 108.25,122.9 108.25,122.49 108.2,122.43 108.2,122.16 108.25,122.1 108.25,121.75 UV1.AB28 ; v2(119.51,70.16) 119.67,70.32 119.93,70.32 120.16,70.1 120.16,69.81 CV304.2
PEG_HTX_GRX_P0: length 77.8
  IN2 w0.127: v2(105.37,124.29) 105.37,124.33 105.89,124.85 105.89,124.91 106.08,125.1 106.08,125.98 105.67,126.39 104.62,126.39 104.16,125.93 104.16,120.35 103.14,119.33 103.14,113.93 100.6,111.39 100.6,110.25 102.19,108.67 102.19,102.13 109.98,94.35 111.31,94.35 113.6,92.05 114.94,92.05 116.5,90.5 116.5,90.5 117.45,89.54 118.15,89.54 119.98,87.71 119.98,86.12 121.12,84.98 121.12,79.95 121,79.82 v2(120.23,79.82)
  BOTTOM w0.102: v2(105.37,124.29) 105.39,124.31 105.59,124.31 105.71,124.19 105.71,123.31 105.6,123.21 105.6,122.97 105.59,122.96 105.59,122.59 UV1.AF30 ; CV312.2 125.81,70.39 125.81,70.76 121.89,74.68 121.89,78.51 121.89,78.68 120.79,79.78 120.27,79.78 v2(120.23,79.82)
PEG_HTX_GRX_P1: length 69
  IN2 w0.127: v2(106.76,125.18) 106.31,124.72 106.31,118.3 104.1,116.09 104.1,112.29 102.95,111.14 102.95,102.43 110.3,95.08 111.61,95.08 113.85,92.84 115.13,92.84 116.78,91.19 118.85,91.19 119.14,90.9 119.14,89.82 120.92,88.03 120.92,86.89 121.99,85.83 121.99,78.49 121.7,78.2 121.05,78.2 120.36,78.21 v2(120.18,78.21)
  BOTTOM w0.102: v2(120.18,78.21) 120.27,78.12 120.78,78.12 121.05,77.85 121.05,76.41 120.29,75.65 120.29,74.83 CV308.2 ; UV1.AE29 106.37,122.17 106.37,122.54 106.4,122.57 106.4,122.84 106.36,122.89 106.36,123.6 106.36,123.6 106.36,124.77 v2(106.76,125.18)
PEG_HTX_GRX_P2: length 94.6
  IN2 w0.127: v2(106.76,126.4) 106.52,126.64 106.27,126.64 105.99,126.93 105.99,129.13 105.13,130 99.89,130 97.74,127.85 97.74,125.59 97.74,124.7 97.74,122.64 97.74,120.67 97.43,120.35 95.9,120.35 93.97,118.42 93.97,104.05 93.97,103.36 99.59,97.74 99.59,96.41 102.2,93.8 102.2,92.9 102.49,92.61 104.5,92.61 105.45,91.66 106.82,91.66 109.05,89.43 109.06,89.43 109.68,88.8 111,88.8 115.28,84.52 115.28,81.29 116.36,80.21 116.36,75.54 122.19,69.71 122.19,69.59 v2(122.35,69.43)
  BOTTOM w0.102: v2(122.35,69.43) 122.23,69.31 122.23,68.7 CV307.2 ; UV1.AD30 106.93,122.27 107.26,122.27 107.39,122.4 107.39,123.15 107.48,123.25 107.48,124.52 107.35,124.66 107.35,126.21 107.01,126.55 106.87,126.55 106.76,126.44 v2(106.76,126.4)
PEG_HTX_GRX_P3: length 96.3
  IN2 w0.127: v2(108.1,124.83) 108.1,124.84 108.39,125.13 108.39,125.46 107.97,125.88 107.97,128.17 105.44,130.69 100.18,130.69 99.61,130.69 97.57,128.66 93.81,124.9 93.81,119.84 93.05,119.08 93.05,103.82 93.06,103.81 93.06,103.59 93.06,102.66 93.05,102.65 93.05,100.55 93.05,99.97 101.24,91.78 104.35,91.78 105.29,90.84 105.8,90.84 108.6,88.03 109.7,88.03 113.3,84.42 113.3,82.18 115.66,79.82 115.66,73.92 119.05,70.54 119.3,70.54 v2(119.51,70.75)
  BOTTOM w0.102: v2(119.51,70.75) 119.73,70.52 120.01,70.52 120.36,70.18 120.36,69.69 120.49,69.56 CV313.2 ; UV1.AC29 107.64,121.84 107.64,121.63 107.72,121.56 107.95,121.56 108.05,121.66 108.05,122.02 107.99,122.07 107.99,122.51 108.03,122.55 108.03,122.57 108.04,122.57 108.04,122.83 107.98,122.88 107.98,122.9 107.96,122.92 107.96,124.12 108.29,124.45 108.29,124.64 v2(108.1,124.83)
PHASE_CHG: length 12.2
  IN2 w0.762: 208.81,29.86 208.94,29.99 208.94,37.17 208.11,37.99 208.11,39.77 209.44,41.1
  vias: v1(208.43,29.86) v2(207.67,29.1) v2(207.67,28.47) v2(207.67,27.83) v2(208.3,29.1) v2(208.3,28.47) v2(208.3,27.83) v2(209,29.1) v2(209,28.47) v2(209,27.83) v2(209.5,41.88) v2(210.12,41.89) v2(211.16,30.18)
PID0: length 6.4
  BOTTOM w0.102: UE1.97 167.62,39.71 167.05,40.28 166.57,40.28 CE47.1 RE24.2 RE23.1 163.48,40.71 v1(163.09,41.1)
PLL_ANALOG_IN: length 2.2
  BOTTOM w0.102: UV1.AA1 109.34,101.46 109.34,99.68 T221.1
PLL_ANALOG_OUT: length 6.5
  BOTTOM w0.102: UV1.AA3 109.22,102.3 108.92,102 108.92,100.92 108.54,100.54 RV83.1 107.84,97.57 v1(107.84,96.4)
PLT_RST#: length 327.3
  TOP w0.102: v1(47.65,18.71) 47.54,18.81 v2(47.07,18.81) ; RW4.2 v2(53.84,110.46)
  IN1 w0.127: v2(38.82,91.33) 40.91,93.43 55.75,93.43 57.26,94.94 57.26,97.33 57.88,97.95 57.88,102.78 56.62,104.03 56.62,106.1 53.84,108.88 v2(53.84,110.46) 53.84,111.53 53.43,111.94 52.26,111.94 51.74,112.46 50.85,112.46 48.87,114.45 48.85,114.45 43.9,119.4 43.9,119.78 43.89,119.79 43.89,121.93 42.16,123.65 36.41,123.65 35.58,122.83 35.14,122.83 34.88,123.08 34.88,123.35 34.57,123.65 33.04,123.65 32.89,123.51 v2(32.89,123.23) ; v2(136.82,30.43) 136.55,30.43 136.35,30.63 136.35,32.01 136.35,33.86 135.46,34.75 135.33,34.75 134.55,34.75 133.58,35.72 123.12,35.72 118.78,40.06 111.61,40.06 109.53,37.99 109.53,33.01 109.2,32.68 v2(109.11,32.68) 109.53,32.26 109.53,31.21 109.27,30.95 109.27,29.65 109.56,29.35 109.56,27.51 108.93,26.88 105.37,26.88 103.02,24.53 101.11,24.53 97.68,21.1 81,21.1 76.81,16.91 73.05,16.91 72.85,16.72 62.57,16.72 61.68,15.83 53.42,15.83 50.76,18.5 47.39,18.5 v2(47.07,18.81) ; v2(172.36,33.99) 172.34,33.98 170.57,33.98 170.16,34.39 170.16,34.58 169.8,34.94 168.61,34.94 168.23,34.56 165.44,34.56 164.76,35.24 164.21,35.24 163.88,34.9 163.46,34.9 162.39,33.84 162.39,33.44 161.21,32.26 161.21,31.3 159.74,29.83 159.74,29.48 159.08,28.82 157.12,28.82 155.77,27.48 142.7,27.48 139.49,30.69 v2(138.89,30.69)
  IN2 w0.127: v2(38.82,91.33) 38.76,91.27 37.61,91.27 31.71,85.36 31.71,83.58 31.83,83.46 31.83,76.79 31.14,76.09 31.14,47.71 41.55,37.29 41.55,32.85 42.31,32.09 43.01,32.09 45.11,29.99 45.11,21.35 45.17,21.29 45.17,20.66 47.01,18.81 v2(47.07,18.81) ; v2(180.3,31.77) 180.28,31.77 178.86,30.35 177.29,30.35 177.06,30.12 174.84,30.12 174.65,29.93 172.61,29.93 171.85,30.69 171.85,31.01 171.98,31.13 171.98,32.11 172.19,32.32 172.19,33.82 v2(172.36,33.99)
  BOTTOM w0.102: v2(180.3,31.77) 180.3,31.77 180.55,32.02 UE1.13 ; v2(136.82,30.43) 138.58,30.43 138.83,30.69 v2(138.89,30.69) ; RL8.1 33.33,122.8 v2(32.89,123.23) ; v2(109.11,32.68) 109.11,32.68 109.11,32.66 109.44,32.99 RC1.2 CC615.1 RC27.2 111.84,33.05 RC602.1
PLT_RST#_R: length 3.1
  BOTTOM w0.102: RL9.1 RL8.2 33.33,121.06 32.69,120.43 UL1.19
PLT_RST#_RW: length 3.7
  TOP w0.102: RW4.1 RW11.1 55.65,108.94 v2(55.51,108.81) v1(55.04,108.34)
  BOTTOM w0.102: JWLAN1.44 55.8,108.52 v2(55.51,108.81)
PLT_RST_VGA#: length 6.8
  BOTTOM w0.102: UV2.4 98.13,120.09 98.4,120.37 RV4.1 99.03,120.16 v1(100.29,120.16) 101.96,120.16 UV1.AL27
PM_SLP_S3#: length 78.9
  TOP w0.102: v2(167.15,38.56) v1(168.68,38.56) 172.93,38.56 173.57,39.2 173.57,40.02 174.01,40.47 178.47,40.47 179.04,40.47 179.04,40.47 179.92,40.47 180.8,39.58 180.8,36.53 182.14,35.2 v2(183.09,35.2)
  BOTTOM w0.102: CE25.1 RE37.1 184.88,35.1 184.6,35.37 183.27,35.37 v2(183.09,35.2) ; v2(167.15,38.56) 166.4,39.31 163.81,39.31 160.27,42.86 149.66,42.86 147.48,45.04 139.91,45.04 139.53,45.42 138.51,45.42 137.82,46.12 137.82,47.52 136.65,48.68 136.65,54.53 135.9,55.28 134.25,55.28 133.4,54.42 130.63,54.42 130.56,54.5 129.15,54.5 127.26,52.61 126.26,52.61 126.15,52.72 125.83,52.72 125.75,52.64 125.5,52.64 UC1.AC2
PM_SLP_S3#_R: length 2.4
  BOTTOM w0.102: RE37.2 183.96,34.82 183.29,34.82 183.26,34.79 182.92,34.79 182.89,34.82 UE1.6
PM_SLP_S5#: length 129
  TOP w0.102: PQ711.2 v2(220.29,24.67) ; v2(184.04,32.09) 183.76,31.81 183.76,26.65 185.06,25.35 185.06,24.03 v1(184.8,23.77) v2(184.21,23.18)
  IN1 w0.102: v2(123.59,49.65) 123.63,49.65 123.81,49.83 123.81,49.9 124.15,50.24 127.41,50.24 129.31,48.34
  IN1 w0.127: 129.31,48.34 132,45.64 132,45.62 132.97,44.66 133.54,44.66 133.69,44.81 134.31,44.81 134.88,44.24 138.93,44.24 139.25,44.56 140.01,44.56 142.32,42.25 146.07,42.25 146.11,42.21 153.02,42.21 158.36,42.21 160.55,40.02 165.12,40.02 165.87,39.28 167.75,39.28 168.08,38.94 169.78,38.94 170.52,38.2 177.16,38.2 180.48,38.2 180.48,38.2 180.9,38.2 180.95,38.2 181.15,38.4 182.81,38.4 183.85,37.36 183.85,34.13 183.85,33.34 184.04,33.14 v2(184.04,32.09)
  IN2 w0.127: v2(184.21,23.18) 186.96,23.18 188.49,21.66 189.9,21.66 191.64,19.92 199.05,19.92 201.12,17.85 216.72,17.85 219.5,20.63 219.5,23.79 220.29,24.59 v2(220.29,24.67)
  BOTTOM w0.1: UC1.AG4 123.86,49.86 123.65,49.65 v2(123.59,49.65)
  BOTTOM w0.102: CE33.1 RE38.1 184.88,31.44 184.23,32.09 v2(184.04,32.09)
PM_SLP_S5#_R: length 2.6
  BOTTOM w0.102: RE38.2 183.8,31.09 183,31.09 182.47,31.63 UE1.14
POK: length 126.8
  TOP w0.254: v2(161.74,88.66) 162.57,87.84 v1(162.9,87.84) 165.63,87.84 165.99,88.2 PR13.1 ; v2(177.7,27.61) 179.31,29.23 180.61,29.23 182.21,30.83 182.21,32.22 183.85,33.86 183.85,37.36 182.2,39.01 182.2,40.46 v2(181.85,40.81) ; v2(199.35,36.47) 198.76,37.05 PR113.2
  IN1 w0.254: v2(161.74,88.66) 161.97,88.43 161.97,86.57 160.18,84.77 160.18,83.77 160.87,83.09 160.87,74.57 164.42,71.01 164.42,66.88 166.39,64.92 166.39,63.45 167.41,62.44 167.41,61.3 167.79,60.91 168.49,60.91 168.99,60.41 168.99,59.14 170.26,57.87 172.66,57.87 172.92,57.61 172.92,55.28 173.55,54.64 175.47,54.64 175.88,54.23 175.88,53.36 176.55,52.68 177.46,52.68 177.79,52.35 177.79,50.6 176.3,49.1 176.3,47.96 v2(177.88,46.37)
  IN2 w0.254: v2(177.88,46.37) 178.21,46.7 180.43,46.7 182.49,48.76 187.18,48.76 188.23,47.71 188.81,47.71 190.14,46.37 190.14,45.8 190.58,45.36 191.35,45.36 193.89,42.82 193.89,36.78 194.42,36.25 196.09,36.25 196.45,35.9 198.78,35.9 v2(199.35,36.47)
  BOTTOM w0.254: v2(177.7,27.61) 177.13,27.05 177.13,24.68 177.88,23.93 179.37,23.93 179.62,23.68 UE1.34 ; v2(181.85,40.81) 181.85,41.35 180.29,42.9 180.29,44.52 PR107.2 178.01,46.25 v2(177.88,46.37) 177.51,46.75 PU100.9 ; v2(199.35,36.47) 199.11,36.71 PU102.9
PROG: length 2.4
  TOP w0.203: v2(215.72,45.61) 215.72,45.32 215.52,45.12 215.17,45.12 214.86,44.8 PU703.9
  BOTTOM w0.254: v2(215.72,45.61) 215.72,45.24 PR753.2
PROH: length 18
  TOP w0.203: PU703.5 216.34,42.69 v2(216.45,42.79) PR777.2
  TOP w0.254: PQ720.2 214.88,50.37 v2(214.77,50.37)
  BOTTOM w0.254: v2(214.77,50.37) 214.52,50.63 212.68,50.63 211.92,49.87 211.92,48.98 v1(212.36,48.53) 213.2,48.53 213.64,48.97 213.71,49 PR781.2 214.76,48.49 215.64,48.49 217.25,46.88 217.25,43.07 216.98,42.79 v2(216.45,42.79)
PS_0: length 3.5
  TOP w0.102: v2(107.16,114.7) 107.16,114.59 CV29.1 RV9.1 104.86,114.07 RV8.2
  BOTTOM w0.102: UV1.AC19 107.7,114.16 v2(107.16,114.7)
PS_1: length 4.7
  TOP w0.102: v2(106.49,114.85) 106.28,115.06 CV28.1 105.31,114.54 104.02,114.54 RV12.1 103.06,114.61 RV11.2
  BOTTOM w0.102: UV1.AD19 106.49,114.51 v2(106.49,114.85)
PS_2: length 6.5
  TOP w0.102: RV28.2 100.67,113.04 101.8,113.04 v1(101.87,113.11) 102.75,113.11 RV13.1 CV11.1 103.98,112.82 104.81,111.99 105.38,111.99 105.76,112.37 v2(105.76,112.44)
  BOTTOM w0.102: v2(105.76,112.44) 105.76,112.56 UV1.AE17
PS_3: length 6.6
  TOP w0.102: CV15.1 RV16.1 103.15,117.92 RV15.2 103.41,118.22 103.91,118.22 v1(104.46,117.67) 104.98,117.15 104.98,116.74 105.83,115.89 v2(105.83,115.85)
  BOTTOM w0.102: UV1.AE20 105.83,115.57 v2(105.83,115.85)
PS_ID: length 123
  TOP w0.102: v2(164.1,107.16) 166.64,109.7 166.64,112.41 168.61,114.38 168.61,119.78 169.09,120.26 169.09,120.95 169.54,121.4 169.54,122.87 169.95,123.27 169.95,124.29 170.33,124.67 170.33,127.34 168.8,128.86 v2(166.64,128.86) ; v2(180.29,31.19) 180.73,31.19 183.54,33.99 183.54,37.23 181.41,39.35 181.41,41.45 183.75,43.78 183.75,48.25 183.22,48.78 183.22,53.36 v1(183.41,53.55) 183.41,53.82 184.59,55 184.59,55.39 v2(184.8,55.6)
  IN1 w0.127: v2(164.1,107.16) 164.1,96.22 167.53,92.79 167.53,76.09 171.6,72.03 171.6,69.68 175.27,66.01 175.27,66.01 177.57,63.71 177.57,63.6 180.03,61.14 180.03,60.52 184.8,55.75 v2(184.8,55.6)
  BOTTOM w0.102: v2(180.29,31.19) 180.65,30.82 UE1.16
  BOTTOM w0.254: PR4.2 165.96,125.08 PR3.1 165.99,128.72 PD5.1 166.62,128.84 v2(166.64,128.86)
PSID: length 4.7
  TOP w0.102: PL2.2 162.22,121.51 v1(162.22,121.32)
  TOP w0.508: PJPDC1.3 165.1,123.41 164.74,123.05 164.29,123.05 163.62,122.38 PL2.2
PSID-1: length 9.3
  BOTTOM w0.102: PR9.2 v1(158.96,130.32)
  BOTTOM w0.254: PR6.1 160.13,125.85 159.74,126.24 159.74,128.11 PQ5.2 160.34,128.72 PR9.2
PSID-2: length 10.1
  BOTTOM w0.102: v1(162.76,128.59) 162.12,127.96 161.31,127.96 160.99,127.64 PQ5.1
  BOTTOM w0.508: PR8.2 162.85,125.11 PQ6.2 160.98,124.51 PR11.1 160.98,127.1 PQ5.1
PSID-3: length 2.9
  BOTTOM w0.102: v1(165.5,123.08) 165.37,123.21 165.37,123.84 165.05,124.17 PR4.1
  BOTTOM w0.508: PQ6.3 163.84,124.17 PR4.1
PTP_DIS#: length 103.4
  TOP w0.102: v2(102.45,10.62) 102.84,11.02 R41.2 v1(103.21,12.15) ; v2(178.46,29.93) 178.46,29.74 176.6,27.89 176.6,25.46 RE5.1
  IN1 w0.127: v2(178.46,29.93) 177.88,30.5 175.32,30.5 175.11,30.5 174.51,31.1 174.05,31.56 173.89,31.56 173.58,31.87 170.4,31.87 169.91,31.37 169.91,27.54 167.49,25.12 167.49,23.4 165.77,21.68 165.77,20.47 164.44,19.15 164.44,18.29 163.2,17.05 160.2,17.05 159.95,16.8 159.39,16.8 159.05,16.46 157.35,16.46 156.36,17.45 143.18,17.45 140.94,15.21 140.61,14.88 140.19,14.88 129.28,14.88 125.81,11.41 125.74,11.33 125.38,11.33 124.92,10.88 122.88,10.88 121.61,9.61 113.88,9.61 112.66,8.39 111.94,8.39 111.55,8.78 111.55,8.95 110.7,9.8 106.63,9.8 103.27,9.8 v2(102.45,10.62)
  BOTTOM w0.102: v2(102.45,10.62) 102.9,10.17 JTP1.3
PTP_DIS#_R: length 3.5
  TOP w0.102: RE5.2 178.07,21.28 v2(178.17,21.18) 178.18,21.18 v1(178.65,20.72)
  BOTTOM w0.102: UE1.38 178.02,21.33 v2(178.17,21.18)
PWR_LED#: length 102
  TOP w0.102: v1(181,40.85) 180.64,40.49 v2(180.5,40.49)
  IN1 w0.102: v2(180.5,40.49) 180.65,40.34 182.47,40.34 184.3,42.16 184.3,47.6 182.73,49.16 182.73,50.87 181.65,51.96 181.44,51.96 173.22,60.18 173.22,61.26 172.96,61.52 172.02,61.52 171.3,62.24 171.3,62.74 170.56,63.49 170.24,63.49 169.73,64 168.97,64 168.73,64.24 168.23,64.24 166.05,66.42 166.05,70.67 161.74,74.98 161.74,85.55 162.53,86.33 162.53,90.03 160.68,91.88 160.68,92.83 159.85,93.65 v2(159.85,93.87)
  BOTTOM w0.102: R53.2 164.31,99.84 Q16.3 164.31,97.88 164.04,97.62 163.09,97.62 162.52,97.05 162.52,95.86 163.09,95.29 163.09,94.57 162.83,94.32 160.29,94.32 v2(159.85,93.87) ; v2(180.5,40.49) 180.36,40.35 180.36,37.62 180.14,37.4 179.54,37.4 178.86,36.72 177.44,36.72 176.04,35.32 176.04,34.49 175.06,33.51 174.93,33.38 173.66,33.38 172.56,32.28 169.71,32.28 169.35,32.64 169.35,33.34 167.43,35.26 166.83,35.26 166.79,35.22 UE1.92
PWR_LED_R#: length 2.8
  BOTTOM w0.102: Q16.1 163.34,94.16 Q15.2
PWRGD_VGA: length 241.6
  TOP w0.102: v1(109.81,36.21) 110,36.02 v2(110.38,36.02)
  TOP w0.203: v2(50.04,121.44) 50.22,121.44 50.61,121.84 PU1100.9 ; v2(56.03,120.33) 55.98,120.38 55.69,120.38 55.49,120.58 PU1100.20
  TOP w0.254: PR1119.2 PR1122.1 49.97,121.37 v2(50.04,121.44)
  IN1 w0.254: v2(44.57,118.1) 44.61,118.1 48.47,114.24 48.47,112.05 48.46,112.04 48.46,109.62 52.32,105.77 55.05,105.77 56.31,104.51 56.31,103.9 57.56,102.64 57.56,98.08 56.94,97.46 56.94,95.07 55.62,93.74 40.71,93.74 40.23,93.74 34.82,88.33 34.82,43.63 41.02,37.43 41.02,31.41 42.51,29.91 42.88,29.54 42.88,19.49 44.6,17.77 50.46,17.77 53.74,14.5 63.84,14.5 64.09,14.75 75.52,14.75 81.3,20.53 97.92,20.53 98,20.53 101.43,23.96 103.33,23.96 105.68,26.31 109.24,26.31 110.14,27.2 110.14,29.81 111.02,30.69 111.02,31.7 109.85,32.87 109.85,35.49 v2(110.38,36.02)
  IN2 w0.254: v2(110.38,36.02) 111.08,36.72 111.08,37.79 111.91,38.62 111.91,42.25 111.4,42.75 111.4,44.03 v2(110.75,44.68)
  BOTTOM w0.254: UC1.AV29 110.38,44.31 v2(110.75,44.68) ; v2(44.57,118.1) 44.52,118.16 44.52,120.34 45.61,121.44 v2(50.04,121.44) 50.99,120.48 55.84,120.48 55.99,120.33 v2(56.03,120.33)
PX_EN: length 1.2
  TOP w0.102: T218.1 107.98,111.83 v2(107.98,112.26)
  BOTTOM w0.102: UV1.AB16 108.14,112.26 v2(107.98,112.26)
PXS_PWREN: length 348.7
  TOP w0.102: v2(94.62,82.06) 94.62,82.94 104.68,92.99 104.68,93.74 106.37,95.44 v2(106.37,96.08) ; v2(87.97,33.86) 95.27,33.86 96.98,35.58 107.22,35.58 v2(108.11,36.47) ; PR1116.1 v2(47.58,123.15) ; v2(129.05,93.93) 130.58,92.41 v1(130.58,91.39)
  IN1 w0.127: v2(108.11,36.47) 107.38,35.74 107.38,31.41 108.02,30.76 108.02,29.42 106.78,28.17 104.85,28.17 102.48,25.8 100.48,25.8 97.62,22.94 77.57,22.94 72.17,17.54 62.57,17.54 62.12,17.99 62.1,17.99 58.38,17.99 57.74,17.35 54.97,17.35 52.62,19.71 50.67,19.71 44.84,25.54 44.84,35.9 35.99,44.75 35.99,81.41 37.98,83.4 37.98,88.89 41.25,92.15 56.06,92.15 58.02,94.11 58.02,96.71 59.35,98.04 59.35,102.38 57.45,104.28 57.45,109.14 55.95,110.64 55.95,111.16 54.66,112.45 52.47,112.45 48.22,116.71 48.22,120.73 47.58,121.37 v2(47.58,123.15)
  IN2 w0.127: v2(129.05,93.93) 125.31,93.93 124.23,95.01 121.05,95.01 119.84,93.81 118.06,93.81 116.66,95.2 115.91,95.2 115.78,95.33 114.76,95.33 113.84,96.26 111.16,96.26 v2(110.68,95.77)
  BOTTOM w0.102: UC1.BA29 110.32,42.15 110.32,41.07 110.27,41.02 110.27,40.07 110.45,39.9 110.45,39.26 108.11,36.92 v2(108.11,36.47) 109.24,35.34 RC938.2 ; R438.1 105.74,96.72 v2(106.37,96.08) 106.45,96.01 106.45,95.4 106.43,95.38 106.43,94.84 106.83,94.44 U74.4 108.8,95.18 109.39,95.77 v2(110.68,95.77) ; v2(94.62,82.06) 91.57,79.01 88.35,79.01 87.21,77.87 81.36,77.87 80.35,76.85 80.35,72.22 83.84,68.73 83.84,52.72 86.63,49.93 86.63,35.2 v2(87.97,33.86)
PXS_RST#: length 236.4
  IN1 w0.127: v2(107.52,45.52) 108.05,45 108.05,43.14 107.39,42.49 107.39,40.4 107.02,40.02 107.02,38.75 106.5,38.24 106.5,35.16 106.87,34.79 106.87,31.19 107.51,30.55 107.51,29.63 106.56,28.68 104.64,28.68 102.29,26.33 100.01,26.33 97.53,23.85 77.7,23.85 71.9,18.05 62.82,18.05 62.38,18.5 62.31,18.5 58.12,18.5 57.55,17.93 55.2,17.93 52.85,20.27 50.88,20.27 45.34,25.81 45.34,36.11 36.49,44.96 36.49,81.2 38.49,83.19 38.49,85.29 38.49,88.67 41.46,91.64 56.78,91.64 58.1,92.96 75.75,92.96 76.79,94 79.2,94 80.22,95.01 87.91,95.01 88.99,96.09 89.94,96.09 90.13,96.28 90.7,96.85 90.7,97.36 92.41,99.07 92.41,101.4 94.13,103.11 94.13,109.3 93.56,109.87 93.56,116.72 v2(94.58,117.75)
  BOTTOM w0.102: v2(107.52,45.52) 107.52,45.52 107.52,45.54 107.53,45.54 107.96,45.11 UC1.AU33 ; UV2.1 94.58,118.64 v2(94.58,117.75) 94.58,117.04 v1(94.64,116.99)
REMOTE1+: length 23.8
  TOP w0.254: U2407.2 72.79,13.48 71.86,13.48 71.8,13.54 71.03,13.54 C2502.1 70.3,13.94 70.04,13.67 v1(69.64,13.67) 68.98,13.01 v2(68.98,12.91)
  BOTTOM w0.254: v2(68.98,12.91) 68.98,12.72 68.73,12.46 54.33,12.46 54.12,12.67 C2500.1 53.42,12.86 Q2407.2 51.63,12.21 Q2407.1
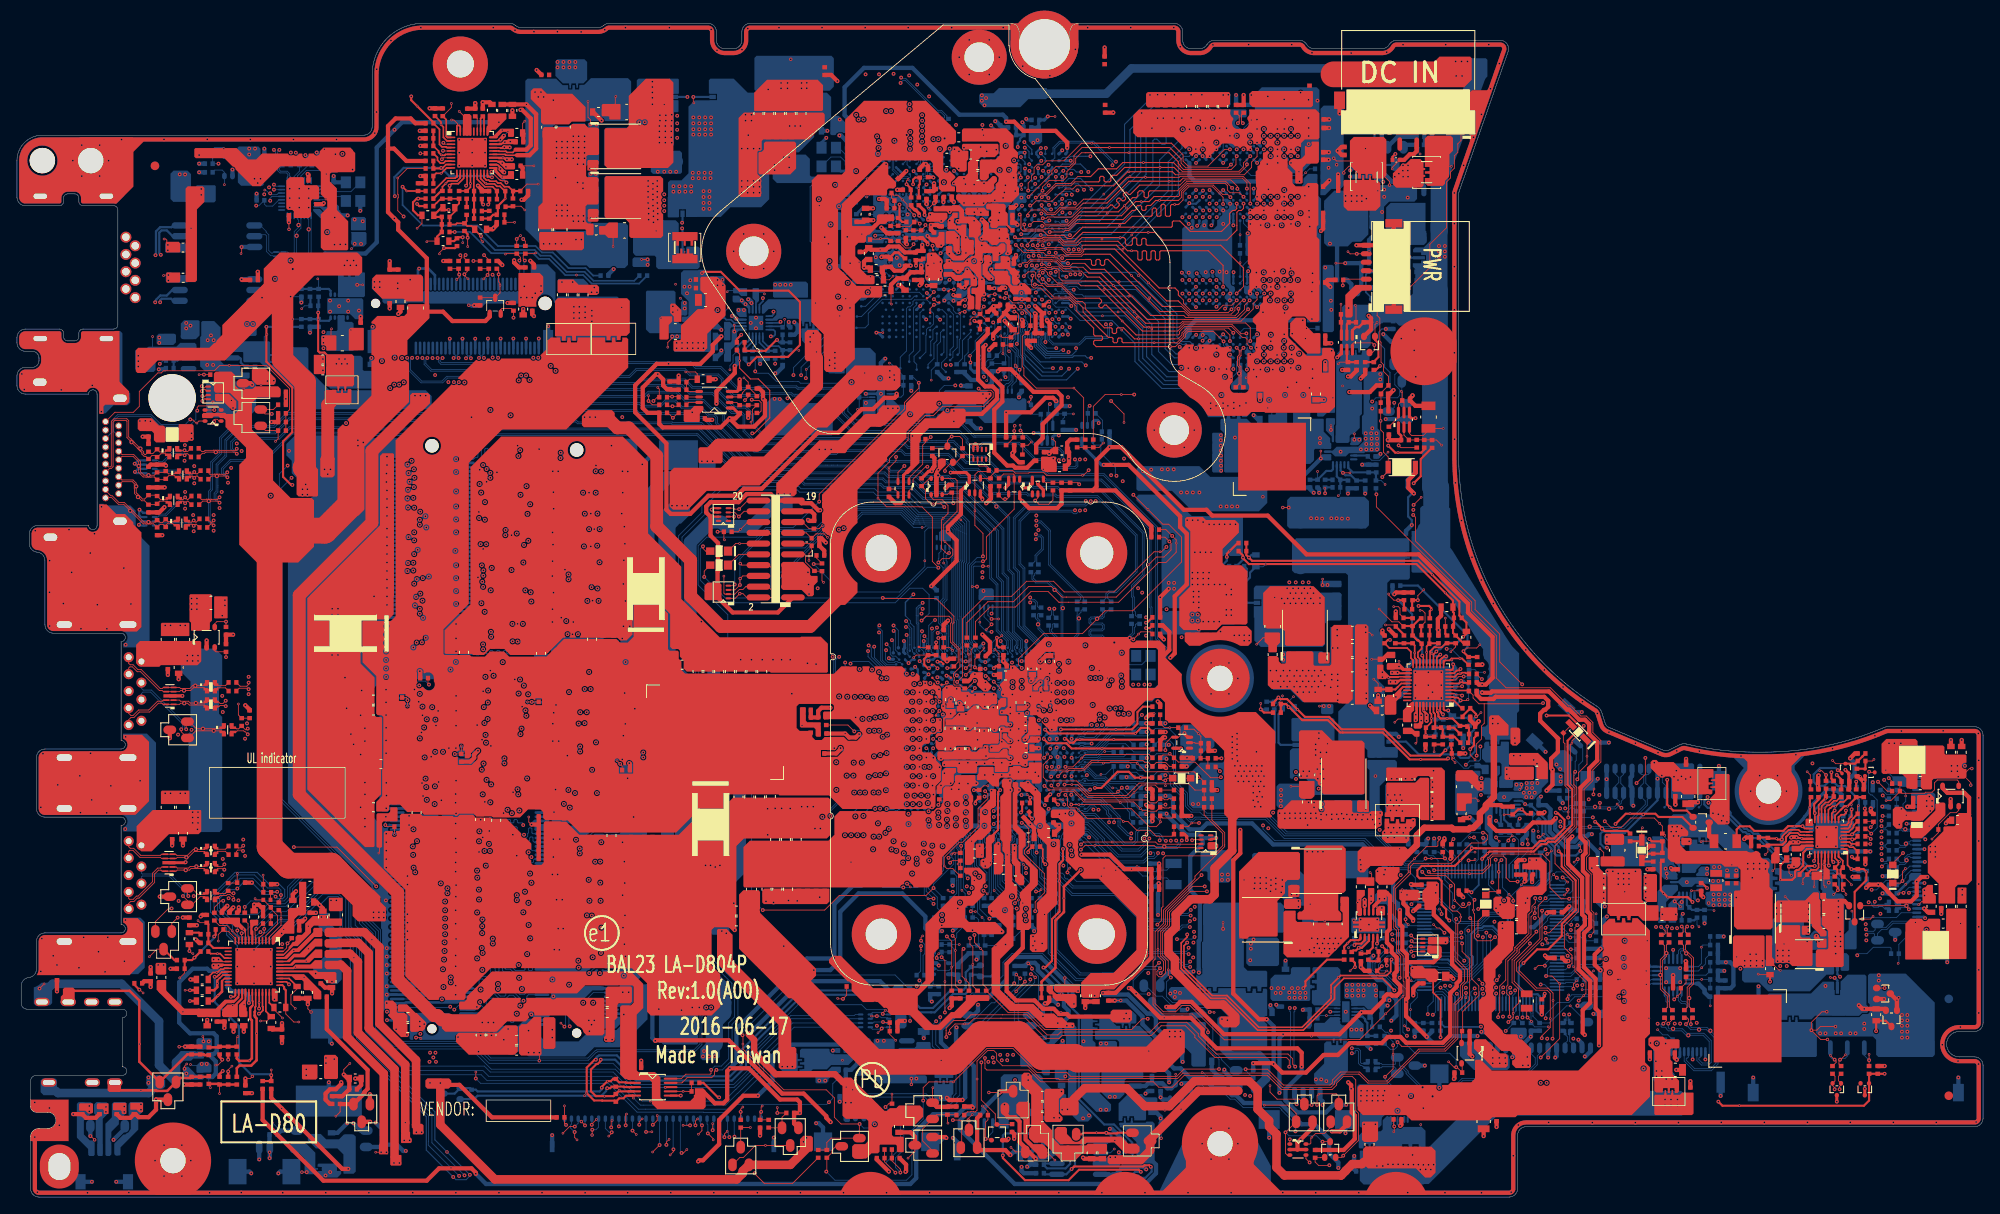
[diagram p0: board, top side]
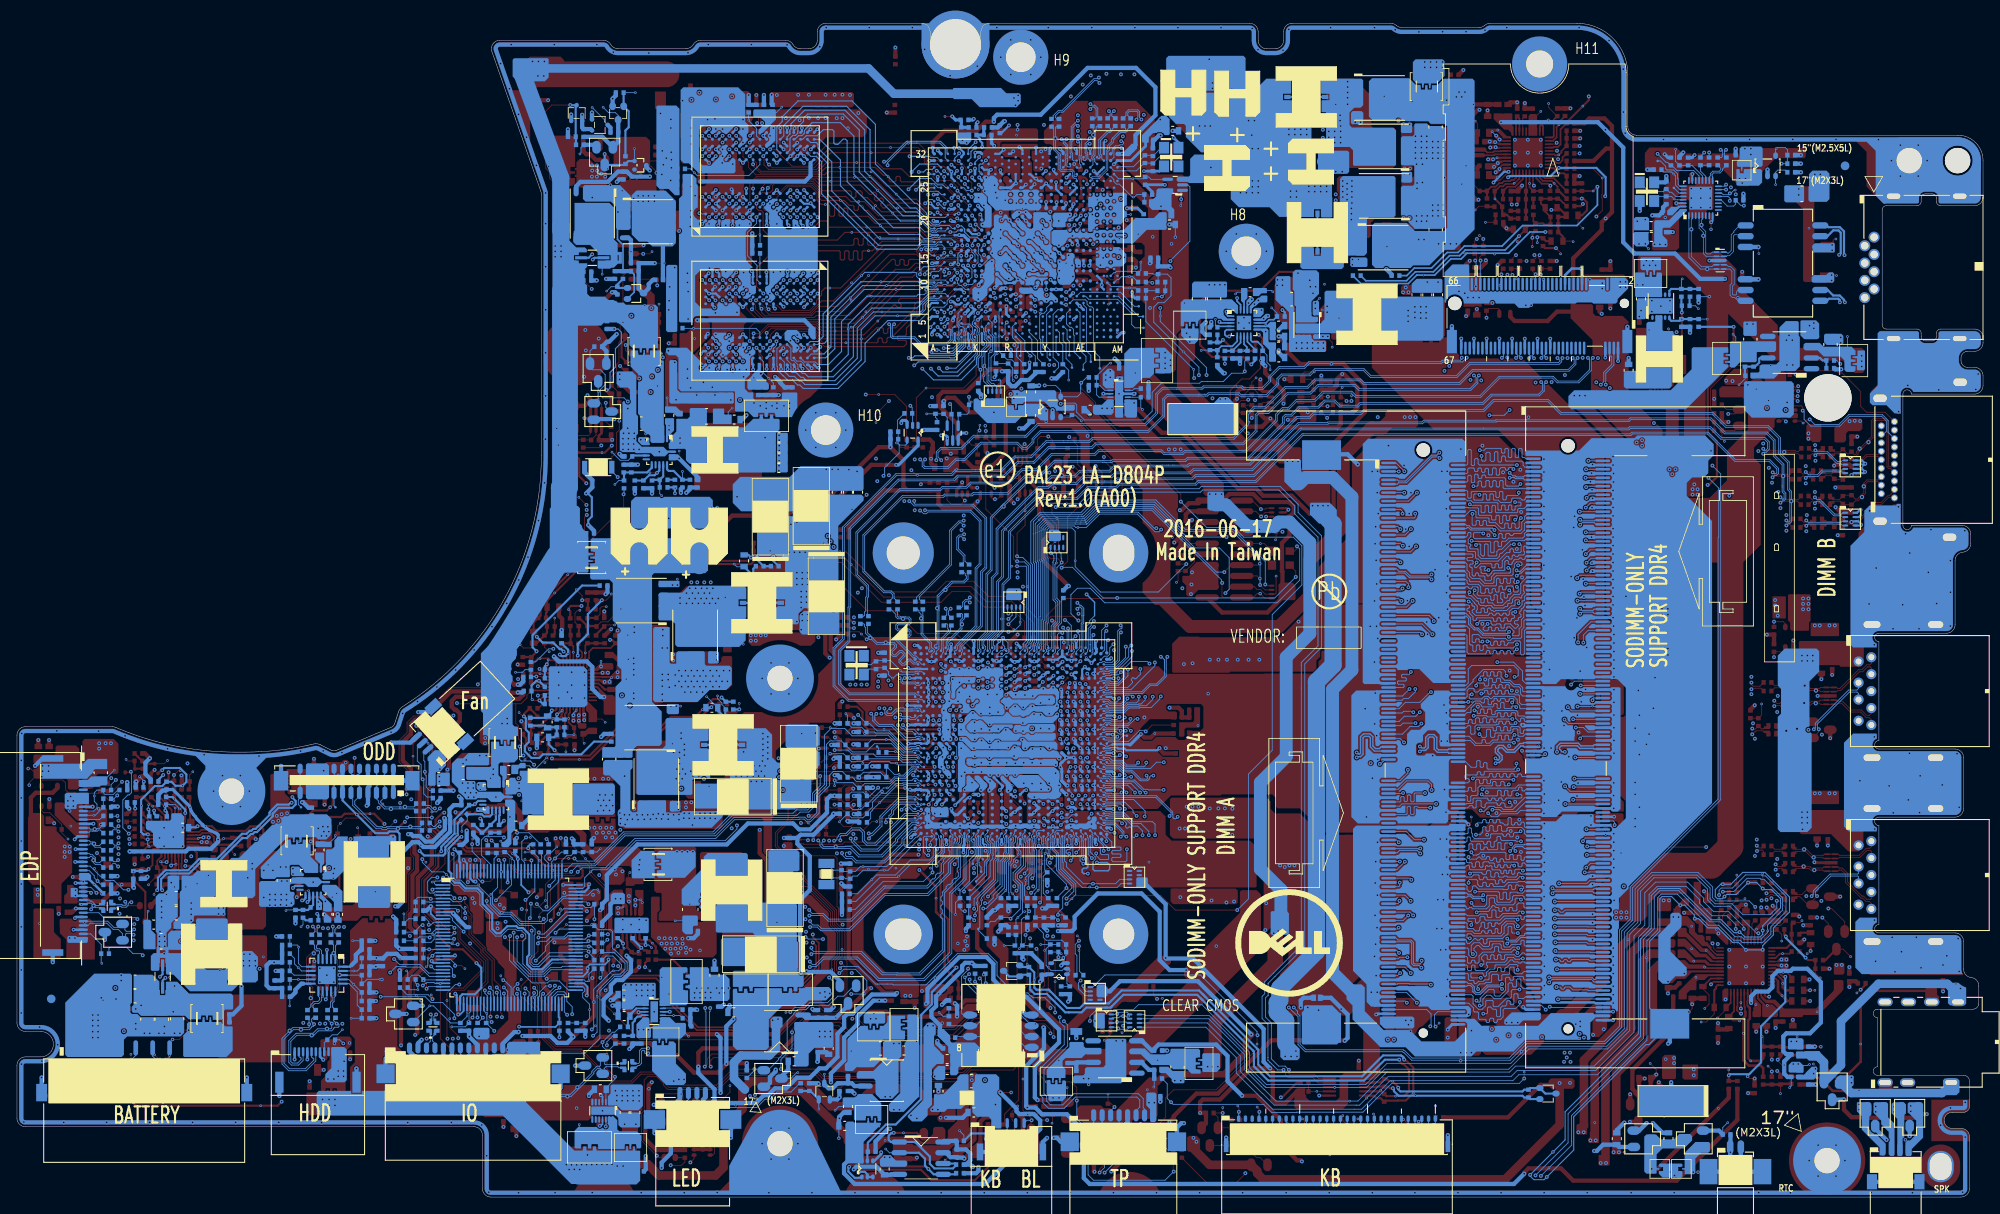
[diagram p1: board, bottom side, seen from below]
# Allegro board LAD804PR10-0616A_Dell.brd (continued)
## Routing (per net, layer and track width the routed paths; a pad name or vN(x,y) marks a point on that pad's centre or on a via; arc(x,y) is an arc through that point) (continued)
REMOTE1-: length 21.3
  TOP w0.254: v2(69.62,12.85) 69.97,12.85 70.15,13.02 C2502.2 70.75,13.02 70.76,13.04 71.58,13.04 71.65,12.97 U2407.3
  BOTTOM w0.254: Q2407.3 53.42,11.56 C2500.2 54.12,11.75 54.33,11.96 v1(66.95,11.96) 68.94,11.96 69.49,12.51 69.49,12.72 v2(69.62,12.85)
REMOTE2+: length 66.7
  TOP w0.254: v2(68.86,16.21) 68.79,16.13 68.79,16 68.49,15.7 68.35,15.7 67.71,15.06 67.71,12.48 68.28,11.91 v1(69.3,11.91) 70.38,11.91 C2504.1 70.94,12.47 U2407.4
  BOTTOM w0.254: v2(68.86,16.21) 70.55,16.21 73.02,13.74 84.31,13.74 86,15.43 86,17.16 86.1,17.26 86.1,17.28 92.1,23.28 92.25,23.42 92.25,23.42 92.69,23.87 101.4,23.87 102.76,22.5 102.91,22.35 103.33,22.35 103.33,22.36 103.54,22.36 103.54,22.35 105.76,22.35 106.32,21.8 107.83,21.8 108.25,21.8 110.41,23.96 111.86,23.96 112.42,24.51 112.42,26.1 C2505.1 113.43,26.23 Q2408.2 114.87,26.04 Q2408.1
REMOTE2-: length 66.7
  TOP w0.254: U2407.5 72.57,11.97 72.56,11.96 71.84,11.96 71.53,11.65 71.04,11.65 C2504.2 70.51,11.37 69.05,11.37 69.02,11.4 68.07,11.4 v1(67.2,12.27) 67.2,15.27 68.14,16.21 v2(68.28,16.21)
  BOTTOM w0.254: v2(68.28,16.21) 68.35,16.28 68.35,16.42 68.35,16.42 68.35,16.49 68.49,16.63 68.56,16.63 68.65,16.72 70.76,16.72 73.23,14.25 84.1,14.25 85.49,15.64 85.49,17.37 85.59,17.47 85.59,17.49 91.74,23.64 91.89,23.78 92.04,23.93 92.48,24.38 101.61,24.38 103.12,22.86 103.12,22.86 103.75,22.86 103.75,22.86 105.97,22.86 106.53,22.31 108.04,22.31 110.2,24.47 111.65,24.47 111.91,24.72 111.91,26.51 C2505.2 113.43,27.15 Q2408.3
RESERVE_1: length 12.9
  BOTTOM w0.102: UC1.AK2 125.16,48.56 125.48,48.87 125.75,48.87 125.83,48.8 126.84,48.8 126.9,48.86 127.39,48.86 127.45,48.8 128.21,48.8 129.37,47.64 129.94,47.64 130.99,46.6 130.99,46.02 131.64,45.37 RC711.2 132.12,44.75 133.45,44.75 RC712.1 133.94,45.23 v1(134.89,44.28)
RESERVE_2: length 8.4
  BOTTOM w0.102: UC1.AY29 110.26,42.66 110.58,42.34 110.58,42.08 110.52,42.03 110.52,40.63 v1(110.61,40.54) 110.68,40.48 110.68,38.61 RC709.2 110.85,37.85 110.85,37.34 110.84,37.33 110.84,35.86 RC710.1
RF_VDDP_ALWP: length 2.3
  TOP w0.254: v2(160.41,29.91) 160.47,29.97 PU300.5
  BOTTOM w0.102: v1(160.29,29.36) 160.41,29.47 v2(160.41,29.91)
  BOTTOM w0.254: PR306.1 160.99,30.55 160.41,29.97 v2(160.41,29.91)
RING2: length 13.3
  IN2 w1.016: 21.93,27.96 21.93,22.18 20.7,20.95 20.7,17.76 21.86,16.59
  BOTTOM w0.102: 21.36,15.51 20.72,15.51 20.59,15.64 v1(20.47,15.64)
  vias: v2(21.8,15.7) v2(22.38,15.7) v2(23.2,28.02) v2(23.78,28.02)
RING2_R: length 13.6
  TOP w0.102: v2(19.77,15.13) 19.77,15.45 v1(20.02,15.7)
  BOTTOM w1.016: 4.59,12.53 4.85,12.27 15.54,12.27 DA5.2
  vias: v2(15.51,14.12) v2(15.51,13.48) v2(19.98,14.58)
RTC_CLK: length 15.2
  TOP w0.102: v2(124.35,46.31) v1(125.24,46.31) 128.93,46.31 129.4,45.83 131.43,45.83 133.56,43.71 134.39,43.71 134.84,44.16 RC949.2 134.89,44.98 135.15,44.72 136.21,44.72 RC950.1
  BOTTOM w0.1: UC1.AN4 124.35,46.42 v2(124.35,46.31)
RTC_DIS: length 9.8
  BOTTOM w0.102: UE1.36 178.82,21.72 178.81,21.72 178.81,21.38 178.82,21.37 178.82,21.32 R1563.1 180.75,20.54 182.77,22.56 v1(183.22,22.56) 185.14,20.64 Q91.2
S0A3: length 10.9
  BOTTOM w0.102: UC1.AB1 125.78,52.96 125.78,52.96 126.34,52.96 126.46,52.84 127.13,52.84 129.05,54.76 130.64,54.76 130.77,54.88 RC694.2 132.27,55.44 133.47,55.44 RC944.2 133.93,56.84 v1(134.13,57.04)
S5_MUX_CTRL: length 63.1
  TOP w0.254: v2(123.37,41.07) 123.37,39.73 123.08,39.44 123.08,39.4 122.97,39.29 v1(122.97,37.29) 122.97,33.69 122.08,32.8 122.08,27.88 121.33,27.13 121.12,27.13 v2(121.07,27.09)
  IN1 w0.254: v2(121.88,52.91) 121.27,53.52 120.45,53.52 120.07,53.15 120.07,51.93 119.65,51.52 119.65,49.87 119.27,49.48 118.96,49.48 117.69,48.21 117.69,47.2 117.94,46.94 119.02,46.94 119.76,46.21 120.14,46.21 121.69,44.66 123.02,44.66 123.37,44.3 v2(123.37,41.07)
  BOTTOM w0.254: Q2516.5 131.59,5.3 R2634.1 131.54,6.42 129.4,8.56 128.25,8.56 125.24,11.56 125.24,21.5 124,22.74 124,24.16 v2(121.07,27.09) ; UC1.AA7 121.88,53.13 v2(121.88,52.91)
SATA_ACT#: length 163.6
  TOP w0.102: Q5.3 156.23,4.68 v2(156.43,4.88) 158.22,6.67 158.22,9.9 157.91,10.22 157.91,13.82 157.48,14.24 156.47,14.24 155.66,13.43 155.66,13.23 155.13,12.69 149.14,12.69 147.48,14.36 137.68,14.36 136.28,12.96 134.67,12.96 134.02,13.61 120.75,13.61 119.36,14.99 114.4,14.99 114.18,15.21 114.18,15.78 114.17,15.79 114.17,16.12 114.18,16.13 v2(114.18,16.4) ; RC43.2 112.29,25.24 v1(111.91,25.61) 111.47,26.05 111.47,29.11 v2(111.65,29.29)
  IN1 w0.127: v2(114.18,16.4) 114.18,20.52 112.05,22.65 112.05,25.8 111.67,26.18 111.67,29.27 v2(111.65,29.29) ; v2(156.43,4.88) 156.52,4.88 156.93,5.29 168.11,5.29 169.09,5.29 174.16,10.36 178.64,10.36 179.18,10.36 180.4,10.36 186.01,15.97 186.01,20.92 185.5,21.42 185.5,21.87 186.33,22.7 186.33,29.48 186.96,30.11 186.96,31.46 185.97,32.45 185.97,33.37 185.38,33.97 185.38,37.99 183.34,40.02 180.23,40.02 179.73,40.53 176.78,40.53 176.23,41.08 176.23,41.67 176.55,41.99 v2(176.55,42.12)
  IN2 w0.127: v2(111.65,29.29) 111.65,31.23 110.04,32.84 110.04,33.68 109.3,34.41 109.3,37.27 109.65,37.62 109.65,39.79 v2(109.88,40.02)
  BOTTOM w0.102: RE43.2 176.36,41.51 176.36,41.93 v2(176.55,42.12) ; UC1.AY30 109.71,43.01 110.03,42.69 110.03,42.42 109.95,42.34 109.95,41.84 109.98,41.8 109.98,41.12 110.07,41.04 110.07,40.28 109.88,40.09 v2(109.88,40.02)
SATA_ACT#_RR: length 3.3
  BOTTOM w0.102: RE43.1 RD15.2 175.35,40.18 175.62,39.91 UE1.117
SATA_ARX_C_DTX_N0: length 2.5
  BOTTOM w0.102: CS33.2 196.55,29.7 196.55,29.39 196.45,29.29 196.19,29.29 195.98,29.08 195.98,28.72 195.85,28.59 US2.4
SATA_ARX_C_DTX_P0: length 2.5
  BOTTOM w0.102: US2.5 196.35,28.61 196.22,28.74 196.22,28.98 196.29,29.05 196.49,29.05 196.55,29.05 196.79,29.29 196.79,29.56 196.79,29.71 CS35.2
SATA_ARX_DTX_N0: length 102.5
  TOP w0.102: RS44.1 196.54,31.28 196.54,31.74 v2(196.36,31.92)
  IN2 w0.127: v2(138.37,27.79) 138.5,27.67 140.41,27.67 141.78,26.29 152.62,26.29 152.88,26.29 153.38,25.79 159.71,25.79 159.9,25.98 160.15,25.98 162.09,25.98 162.84,26.73 164.19,26.73 164.36,26.56 165.38,26.56 167.44,28.63 171.01,28.63 171.13,28.51 178.23,28.51 178.61,28.14 179.93,28.14 180.02,28.05 181.63,28.05 182.88,26.8 185.2,26.8 186.07,27.67 187.91,27.67 188.8,26.78 190.16,26.78 192.11,28.73 195.68,28.73 196.49,29.55 196.49,31.79 v2(196.36,31.92)
  BOTTOM w0.102: v2(138.37,27.79) 138.37,27.73 138.08,27.43 137.72,27.43 136.83,28.32 132.76,28.32 130.24,25.8 130.08,25.8 128.35,25.8 128.33,25.77 124.97,25.77 121.88,28.87 121.88,35.9 120.2,37.57 120.2,40.19 119.89,40.5 119.89,41.06 119.75,41.19 119.75,41.83 119.84,41.92 119.84,42.34 119.91,42.41 119.91,42.69 119.55,43.05 119.55,43.2 UC1.AY12 ; v2(196.36,31.92) 196.49,31.79 196.49,31.23 RS44.1
SATA_ARX_DTX_N1: length 82.3
  IN2 w0.127: v2(138.46,33.87) 138.46,33.79 138.72,33.53 139.51,33.53 141.37,35.38 141.37,40.66 143.13,42.41 143.53,42.82 158.57,42.82 161.11,40.27 161.11,39.33 163.07,37.38 163.85,37.38 164.18,37.7 164.18,39.02 165.1,39.95 165.1,39.95 166.69,41.53 167.59,41.53 167.59,41.53 167.85,41.53 169.09,41.53 169.09,41.53 170.93,41.53 171.29,41.9 174.55,41.9 175.85,43.2 177.19,43.2 178.03,44.04 181.76,44.04 182.04,44.32 v2(182.04,44.32)
  BOTTOM w0.102: v2(182.04,44.32) 182.64,43.72 182.78,43.72 CS14.1 ; UC1.BA8 121.94,42.43 121.94,42.08 121.86,42 121.86,41.5 121.99,41.36 121.99,40.94 121.86,40.8 121.86,40.35 122.07,40.13 122.29,40.13 122.6,39.82 122.6,39.6 122.87,39.33 122.87,38.41 123.06,38.21 123.32,38.21 123.55,37.98 123.55,37.73 123.74,37.54 123.92,37.54 124.19,37.27 124.19,37.09 124.57,36.71 129.46,36.71 129.66,36.71 133.57,32.79 136.11,32.79 136.77,33.45 138.1,33.45 138.46,33.81 v2(138.46,33.87)
SATA_ARX_DTX_N1_C: length 14.3
  BOTTOM w0.102: CS14.2 184.12,43.92 184.32,43.72 184.71,43.72 184.73,43.71 v3(185.5,43.71) 188.29,43.71 188.38,43.62 188.72,43.62 188.81,43.71 189.44,43.71 192.06,46.32 192.06,46.74 191.5,47.3 JODD1.9 191.5,48.48 191.88,48.86 191.88,49.75 191.78,49.85 191.6,49.85 191.5,49.95 JODD1.10
SATA_ARX_DTX_P0: length 102.5
  TOP w0.102: RS43.1 196.8,31.28 196.8,31.73 v2(197,31.92)
  IN2 w0.127: v2(197,31.92) 196.81,31.73 196.81,29.42 195.81,28.42 192.24,28.42 190.29,26.46 188.67,26.46 187.78,27.35 186.2,27.35 185.33,26.49 182.75,26.49 181.5,27.73 179.89,27.73 179.8,27.82 178.48,27.82 178.1,28.2 171,28.2 170.88,28.31 167.57,28.31 165.51,26.25 164.23,26.25 164.06,26.41 162.97,26.41 162.22,25.67 160.02,25.67 159.84,25.48 153.25,25.48 152.75,25.98 141.66,25.98 140.28,27.35 138.57,27.35 v2(138.37,27.15)
  BOTTOM w0.102: UC1.BA12 119.6,42.55 119.6,42.01 119.51,41.92 119.51,41.1 119.65,40.96 119.65,40.4 119.96,40.09 119.96,37.48 121.64,35.8 121.64,28.77 124.87,25.53 128.43,25.53 128.45,25.56 129.43,25.56 130.33,25.56 132.86,28.09 136.74,28.09 137.62,27.2 138.33,27.2 v2(138.37,27.15) ; RS43.1 196.74,31.34 196.74,31.67 v2(197,31.92)
SATA_ARX_DTX_P1: length 82.3
  IN2 w0.127: v2(138.44,33.21) 139.64,33.21 141.68,35.26 141.68,40.53 143.35,42.19 143.66,42.5 158.44,42.5 160.8,40.14 160.8,39.2 162.94,37.06 163.98,37.06 164.49,37.57 164.49,38.89 165.23,39.63 165.23,39.63 166.82,41.22 168.96,41.22 168.96,41.22 171.06,41.22 171.42,41.59 171.77,41.59 171.78,41.58 171.84,41.58 171.84,41.59 174.68,41.59 175.98,42.89 177.32,42.89 178.16,43.73 v2(182.04,43.73)
  BOTTOM w0.102: UC1.AY8 121.81,43 121.51,42.7 121.51,42.43 121.62,42.31 121.62,40.25 122.63,39.23 122.63,38.31 124.47,36.47 129.56,36.47 133.47,32.56 136.21,32.56 136.87,33.21 v2(138.44,33.21) ; CS13.1 182.98,43.49 182.54,43.49 182.29,43.73 v2(182.04,43.73)
SATA_ARX_DTX_P1_C: length 14.3
  BOTTOM w0.102: CS13.2 184.33,43.47 v3(186.96,43.47) 188.2,43.47 188.28,43.38 188.82,43.38 188.91,43.47 189.54,43.47 192.3,46.23 192.3,46.93 192.5,47.13 JODD1.11 192.5,48.44 192.12,48.82 192.12,49.75 192.22,49.85 192.4,49.85 192.5,49.95 JODD1.12
SATA_ARX_RC_DTX_N0: length 3.1
  BOTTOM w0.102: CS31.1 196.98,22.38 196.98,22.62 196.77,22.83 196.32,22.83 195.96,23.18 195.96,23.57 195.85,23.69 US2.12
SATA_ARX_RC_DTX_N0_C: length 15.1
  TOP w0.102: v2(196.86,20.4) 197.14,20.68 197.14,21 196.98,21.15 CS41.2
  BOTTOM w0.102: CS41.2 196.97,21.15 197.14,20.99 197.14,20.68 v2(196.86,20.4) 196.85,20.4 196.85,20.25 196.95,20.15 197.09,20.15 197.19,20.04 197.19,19.99 197.42,19.76 v3(198.41,19.76) 199.27,19.76 200.4,18.62 200.4,15.8 199.75,15.15 197.89,15.15 196.89,16.15 196.89,16.31 196.99,16.41 197.05,16.41 197.15,16.52 JHDD1.5
SATA_ARX_RC_DTX_P0: length 3.1
  BOTTOM w0.102: US2.11 196.35,23.67 196.2,23.53 196.2,23.28 196.42,23.07 196.87,23.07 197.22,22.72 197.22,22.48 CS34.1
SATA_ARX_RC_DTX_P0_C: length 14.7
  TOP w0.102: CS40.2 197.44,20.96 v2(197.44,20.4)
  BOTTOM w0.102: CS40.2 197.44,20.96 v2(197.44,20.4) 197.43,20.39 197.43,20.09 197.52,20 199.37,20 v3(199.74,19.62) 200.64,18.72 200.64,15.7 199.85,14.91 197.79,14.91 196.65,16.05 JHDD1.6
SATA_ATX_C_DRX_N0: length 2.2
  BOTTOM w0.102: CS36.2 194.57,29.75 194.57,28.82 194.85,28.54 US2.2
SATA_ATX_C_DRX_P0: length 2.1
  BOTTOM w0.102: US2.1 194.35,28.7 194.33,28.72 194.33,29.66 CS37.2
SATA_ATX_DRX_N0: length 95.9
  TOP w0.102: v2(194.65,31.92) 194.65,31.92 194.65,31.17 RS42.1
  IN2 w0.127: v2(138.2,28.67) 138.22,28.69 140.32,28.69 142.04,26.97 153.63,26.97 154.27,26.33 159.24,26.33 159.43,26.51 159.54,26.51 161.87,26.51 162.88,27.52 165.34,27.52 166.98,29.16 171.23,29.16 171.35,29.04 178.58,29.04 178.67,28.95 182.24,28.95 183.09,29.8 188.52,29.8 189.01,29.31 190.45,29.31 192.19,31.05 194.22,31.05 194.53,31.36 194.53,31.81 v2(194.65,31.92)
  BOTTOM w0.102: v2(138.2,28.67) 138.11,28.76 132.39,28.76 129.86,26.23 128.17,26.23 128.15,26.2 125.36,26.2 122.51,29.05 122.51,35.87 120.63,37.75 120.63,40.11 120.67,40.15 120.67,41.6 120.48,41.8 120.48,42.34 120.47,42.35 120.47,42.35 120.41,42.42 120.41,42.7 120.71,43.01 UC1.AY10 ; v2(194.65,31.92) 194.65,31.65 194.65,31.65 194.65,31.17 RS42.1
SATA_ATX_DRX_N1: length 89.3
  IN2 w0.127: v2(138.35,32.56) 138.35,32.45 138.63,32.17 140,32.17 143.27,35.44 143.27,41.36 143.88,41.97 157.9,41.97 159.79,40.09 159.79,38.37 160.61,37.55 161.7,37.55 162.71,36.53 164.21,36.53 164.28,36.46 164.71,36.46 165.23,36.97 165.23,37.86 165.02,38.07 165.02,38.67 165.46,39.11 166.37,39.11 167.94,40.68 168.74,40.68 168.74,40.68 176.64,40.68 176.77,40.81 176.88,40.81 177.03,40.81 177.14,40.81 177.27,40.81 177.39,40.81 177.4,40.81 178.61,40.81 180.68,42.88 181.88,42.88 183.46,44.45 183.46,45.03 183.18,45.31 182.58,45.31 182.2,45.68 182.19,45.68 v2(182.01,45.86)
  BOTTOM w0.102: v2(182.01,45.86) 182.42,45.46 182.78,45.46 183.3,45.97 183.48,45.97 CS9.1 ; UC1.BA9 121.22,42.17 121.22,42.02 121.38,41.86 121.38,40.1 122.04,39.43 122.04,38.28 124.51,35.82 129.6,35.82 133.74,31.67 136.99,31.67 137.42,32.1 138.01,32.1 138.35,32.44 v2(138.35,32.56)
SATA_ATX_DRX_N1_C: length 9.3
  BOTTOM w0.102: CS9.2 185.07,45.8 v3(187.79,45.8) 188.55,45.8 189.23,46.49 189.23,46.73 189.5,46.99 JODD1.5 189.5,48.47 189.17,48.8 189.17,49.56 189.5,49.89 JODD1.6
SATA_ATX_DRX_P0: length 96.4
  TOP w0.102: v2(193.92,31.88) 194.41,31.4 194.41,31.08 194.28,30.96 RS41.1
  IN2 w0.127: v2(138.2,29.41) 138.2,29.26 138.45,29 140.45,29 142.17,27.28 153.76,27.28 154.4,26.64 159.11,26.64 159.3,26.82 159.54,26.82 159.55,26.83 160.5,26.83 160.5,26.82 161.74,26.82 162.75,27.83 165.21,27.83 166.86,29.48 171.36,29.48 171.48,29.36 178.71,29.36 178.8,29.27 182.12,29.27 182.96,30.11 188.65,30.11 189.14,29.62 190.32,29.62 192.06,31.36 194.09,31.36 194.22,31.49 194.22,31.59 v2(193.92,31.88)
  BOTTOM w0.102: v2(193.92,31.88) 194.11,31.88 194.41,31.59 194.41,31.23 194.13,30.96 RS41.1 ; UC1.BA10 120.72,42.55 120.72,41.89 120.91,41.7 120.91,40.06 120.87,40.02 120.87,38.92 121,38.79 121,38.41 120.87,38.28 120.87,37.85 121.13,37.59 121.33,37.59 121.59,37.33 121.59,37.13 121.85,36.87 122.05,36.87 122.31,36.61 122.31,36.41 122.75,35.97 122.75,35.56 122.93,35.38 122.93,35.06 122.75,34.88 122.75,34.55 122.93,34.37 122.93,34.04 122.75,33.86 122.75,33.53 122.93,33.35 122.93,33.02 122.75,32.84 122.75,29.15 125.46,26.44 128.05,26.44 128.07,26.47 129.76,26.47 132.29,28.99 137.95,28.99 138.2,29.24 v2(138.2,29.41)
SATA_ATX_DRX_P1: length 89.4
  IN2 w0.127: v2(182.62,45.86) 182.86,45.62 183.31,45.62 183.77,45.16 183.77,44.32 182.01,42.56 180.8,42.56 178.74,40.5 177.27,40.5 177.27,40.5 177.14,40.5 177.01,40.5 176.9,40.5 176.77,40.37 168.61,40.37 168.61,40.37 168.07,40.37 166.5,38.8 165.59,38.8 165.33,38.54 165.33,38.2 165.54,37.99 165.54,36.84 164.84,36.15 164.15,36.15 164.08,36.22 162.59,36.22 161.57,37.23 160.74,37.23 160.74,37.23 160.48,37.23 159.47,38.24 159.47,38.5 159.47,39.96 157.77,41.66 144.01,41.66 143.58,41.23 143.58,35.31 140.13,31.86 v2(138.35,31.86)
  BOTTOM w0.102: v2(138.35,31.86) 137.52,31.86 137.08,31.43 133.65,31.43 129.5,35.58 124.41,35.58 121.81,38.18 121.81,39.33 121.14,40 121.14,41.76 120.96,41.94 120.96,42.35 121.26,42.66 UC1.AY9 ; v2(182.62,45.86) 182.85,45.86 183.2,46.21 183.67,46.21 CS8.1
SATA_ATX_DRX_P1_C: length 9.2
  BOTTOM w0.102: CS8.2 184.82,46.29 185.07,46.04 v3(186.14,46.04) 188.45,46.04 189,46.59 189,46.72 188.5,47.21 JODD1.3 188.5,48.48 188.93,48.91 188.93,49.5 188.5,49.93 JODD1.4
SATA_ATX_RC_DRX_N0: length 2.5
  BOTTOM w0.102: US2.14 194.85,23.7 194.74,23.59 194.74,23.17 194.9,23.01 194.9,22.42 CS32.1
SATA_ATX_RC_DRX_N0_C: length 13.6
  TOP w0.102: v2(194.77,20.47) 195.26,20.95 CS39.2
  BOTTOM w0.102: JHDD1.3 198.15,16.11 198.68,15.58 199.52,15.58 199.84,15.9 199.84,18.46 198.98,19.32 196.98,19.32 196.45,19.86 v3(195.33,19.86) 194.88,19.86 194.77,19.96 v2(194.77,20.47) 195.26,20.95 CS39.2
SATA_ATX_RC_DRX_P0: length 2.5
  BOTTOM w0.102: CS30.1 194.66,22.4 194.66,22.91 194.5,23.07 194.5,23.55 194.35,23.7 US2.15
SATA_ATX_RC_DRX_P0_C: length 13.7
  TOP w0.102: v2(194.19,20.46) 194.53,20.8 194.53,20.95 CS38.2
  BOTTOM w0.102: CS38.2 194.53,20.95 194.53,20.8 v2(194.19,20.46) 194.02,20.46 193.92,20.36 193.92,20.13 194.02,20.03 194.43,20.03 194.54,19.93 194.54,19.86 194.78,19.62 196.35,19.62 196.88,19.09 v3(197.14,19.09) 198.88,19.09 199.6,18.36 199.6,15.99 199.42,15.82 198.78,15.82 198.39,16.21 198.39,16.4 198.49,16.5 198.53,16.5 198.65,16.62 JHDD1.2
SATA_LED#_R: length 76.1
  TOP w0.102: v2(154.79,3.76) 154.77,3.73 153.52,3.73 153.12,4.14 R23.1 153.75,4.64 153.79,4.68 Q5.2 ; v1(176.36,42.63) 175.92,42.18 v2(175.92,42.07)
  IN1 w0.127: v2(175.92,42.07) 175.92,42.07 175.98,42.01 175.98,40.98 176.68,40.28 179.62,40.28 180.13,39.77 183.24,39.77 185.12,37.89 185.12,33.86 185.72,33.27 185.72,32.35 186.71,31.36 186.71,30.22 186.08,29.58 186.08,22.8 185.25,21.98 185.25,21.32 185.76,20.81 185.76,16.07 180.29,10.61 179.28,10.61 179.28,10.61 178.96,10.61 173.97,10.61 168.9,5.54 168.78,5.54 156.36,5.54 154.79,3.98 v2(154.79,3.76)
  BOTTOM w0.102: v2(175.92,42.07) 175.92,42.07 RD15.1
SATA_RX_N0: length 8.9
  TOP w0.102: RS44.2 196.57,29.69 196.57,29.08 v3(196.89,28.75) 197.51,28.14 197.51,25.25 197,24.75 197,22.4 CS41.1
SATA_RX_P0: length 8.9
  TOP w0.102: CS40.1 197.24,22.45 v3(197.24,23.47) 197.24,24.65 197.74,25.15 197.74,28.23 196.8,29.17 196.8,29.72 RS43.2
SATA_TX_N0: length 8.8
  TOP w0.102: CS39.1 194.89,22.43 194.89,23.81 194.08,24.63 194.08,27.92 194.55,28.39 v3(194.55,28.78) 194.55,29.72 RS42.2
SATA_TX_P0: length 8.8
  TOP w0.102: RS41.2 194.31,29.68 194.31,28.49 193.84,28.02 v3(193.84,26.21) 193.84,24.53 194.66,23.71 194.66,22.39 CS38.1
SATA_ZVDD: length 2
  TOP w0.102: v2(119.53,47.14) v1(119.15,47.52)
  TOP w0.254: v2(119.53,47.14) 119.48,47.08 RC96.1
  BOTTOM w0.254: UC1.AP11 119.74,47.14 v2(119.53,47.14)
SATA_ZVSS: length 1.6
  TOP w0.254: v2(119.72,44.66) 119.41,44.97 RC90.1
  BOTTOM w0.254: UC1.AU11 120.16,45.04 119.78,44.66 v2(119.72,44.66)
SERIRQ: length 87.7
  TOP w0.102: v2(182.31,37.72) 182.34,37.72 v1(182.9,37.17)
  IN1 w0.102: v2(110.75,43.86) 110.75,43.73 111.97,42.51 117.83,42.51 118.79,41.56 120.46,41.56 122.51,39.51 122.51,38.88
  IN1 w0.127: 122.51,38.88 122.51,38.59 123.84,37.26 130.3,37.26 131.24,38.2 131.24,40.8 131.71,41.27 138.59,41.27 138.98,41.66 139.6,41.66 140.66,40.59 142.51,40.59 143.28,41.36 158.1,41.36 160.23,39.23 160.45,39.23 163.9,39.23 165.53,37.61 166.91,37.61 167.12,37.83 169.78,37.83 170.2,37.4 172.79,37.4 173.64,36.56 181.15,36.56 v2(182.31,37.72)
  BOTTOM w0.102: v2(110.75,43.86) 111.2,44.31 UC1.AV27 ; UE1.3 182.58,36.02 182.73,35.87 183.18,35.87 183.45,36.15 183.45,37.25 182.98,37.72 v2(182.31,37.72)
SKU_ID: length 17
  TOP w0.102: RC692.2 135.95,50.82 135.49,51.28 134.39,51.28 RC693.1 133.48,51.26 133.05,51.26 132.8,51.52 126.73,51.52 125.79,50.58 124.65,50.58 124.63,50.56 124,50.56 123.82,50.38 v1(122.51,50.38) 121.64,50.38 121.48,50.54 v2(121.48,50.75)
  BOTTOM w0.102: UC1.AE8 121.46,50.77 v2(121.48,50.75)
SLEEVE: length 8.6
  TOP w0.102: v1(21.93,18.94) 21.99,18.88 v2(21.99,18.37)
  IN2 w1.016: 22.31,19.51 24.34,21.54 24.34,26.62
  vias: v2(22.63,18.37) v2(23.19,27.31) v2(23.77,27.32)
SLEEVE_R: length 27.2
  TOP w0.102: v2(2.66,24.61) v1(3.2,25.14)
  BOTTOM w1.016: 19.58,16.72 18.77,15.91 DA5.3 16.76,15.58 16.76,20.74 12.34,25.16 4.21,25.16 3.83,24.78
SNUB_+1.35VGPU: length 1.6
  BOTTOM w0.102: PC1408.1 148.01,92.63 v1(147.53,93.11)
SPK_L+_CONN: length 56.5
  TOP w0.102: v2(42.95,5.29) v1(42.31,5.29)
  TOP w1.016: 38.18,27.45 38.95,26.69 38.95,18.89 43.26,14.57 43.26,6.24
  IN2 w1.016: 11.01,8.97 22.5,8.97 23.22,8.25 34.69,8.25 35.74,7.2 40.22,7.2 42.08,5.33
  vias: v2(10.5,10.64) v2(10.5,10.05) v2(43.58,5.29)
SPK_L-_CONN: length 64.4
  TOP w1.016: 37.99,28.72 39.26,28.72 v1(39.74,28.24) 40.22,27.77 40.22,19.41 44.53,15.09 44.53,4.88
  IN2 w1.016: 8.66,9.23 10.18,7.7 21.8,7.7 22.63,6.88 34.12,6.88 35.17,5.82 39.63,5.82 41.49,3.96 43.61,3.96
  vias: v2(8.53,10.75) v2(8.53,10.11) v2(44.47,4.02) v2(45.11,4.02)
SPK_R+_CONN: length 59.8
  TOP w1.016: 38.06,31.26 40.98,31.26 v1(41.87,30.37) 42.76,29.48 42.76,20.47 47.07,16.15 47.07,8.59
  IN1 w1.016: 15.64,10.69 15.96,10.37 36.02,10.37 38.62,7.77 46.15,7.77
  vias: v2(14.63,10.94) v2(14.63,10.31) v2(47.11,7.65) v2(47.74,7.65)
SPK_R-_CONN: length 58.8
  TOP w1.016: 37.99,29.99 40.28,29.99 41.49,28.78 41.49,19.94 45.8,15.62 v1(45.8,8.78) 45.8,7.64
  IN1 w1.016: 13.93,9.04 35.55,9.04 38.09,6.5 44.79,6.5
  vias: v2(12.66,10.69) v2(12.66,10.05) v2(45.68,6.69) v2(46.31,6.69)
SUSP#: length 329
  TOP w0.102: v2(169.76,32.81) 169.71,32.77 169.71,27.81 170.73,26.79 170.73,25.46 170.4,25.12 170.24,24.97 170.24,23.56 169.49,22.81 169.49,18.91 168.36,17.78 163.34,17.78 v2(162.84,18.28) ; v2(54.12,13.99) v1(54.12,14.75)
  IN1 w0.127: v2(62.96,98.07) 62.96,97.12 64.24,95.84 78,95.84 79.14,96.98 87.59,96.98 88.94,98.33 v2(89.43,98.33) ; v2(49.32,97) 49.12,96.79 42.44,96.79 34.12,88.47 34.12,85.55 32.9,84.33 32.9,45.09 40.7,37.3 40.7,31.28 42.38,29.6 42.57,29.41 42.57,19.35 44.46,17.45 44.73,17.45 44.73,17.46 50.28,17.46 53.75,13.99 v2(54.12,13.99) ; v2(169.76,32.81) 169.76,31.58 169.65,31.48 169.65,27.64 167.24,25.23 167.24,23.52 162.53,18.81 161.12,18.81 160.29,17.99 157.25,17.99 156.96,17.7 143.08,17.7 140.69,15.32 140.5,15.13 140.09,15.13 140.09,15.13 139.83,15.13 139.83,15.13 129.17,15.13 126.63,12.59 125.8,11.75 125.63,11.58 125.26,11.58 124.81,11.13 122.77,11.13 121.5,9.86 113.75,9.86 113.37,9.48 111.4,9.48 110.83,10.05 107.26,10.05 107.26,10.05 106.73,10.05 106.73,10.05 103.64,10.05 102.65,11.04 99.31,11.04 98.76,10.5 96.92,10.5 96.22,11.19 v2(95.78,11.19)
  IN2 w0.127: v2(49.32,97) 49.32,96.59 50.93,94.98 61.72,94.98 62.96,96.22 v2(62.96,98.07)
  BOTTOM w0.102: R437.1 R2313.1 161.98,17.43 162.48,17.43 162.84,17.78 v2(162.84,18.28) 161.67,19.45 161.39,19.45 R2318.1 ; UE1.116 175.22,36.53 175.81,35.93 175.81,34.59 174.83,33.61 173.56,33.61 172.46,32.5 170.06,32.5 v2(169.76,32.81) ; PR403.1 96.22,13.37 96.22,11.64 v2(95.78,11.19) 95.52,10.94 84.86,10.94 83.9,9.99 80.98,9.99 80.95,10.02 73.14,10.02 69.74,13.42 54.69,13.42 v2(54.12,13.99) ; v2(89.43,98.33) PR202.1
SVI2_SVC: length 89.6
  TOP w0.102: RV100.2 77.98,94.45 v2(77.27,94.45) 76.75,94.45 RV94.2 ; PU1100.3 50.46,124.24 v2(50.29,124.4)
  IN2 w0.127: v2(50.29,124.4) 49.73,124.4 48.28,122.95 48.28,108.25 50.64,105.89 50.64,104.11 54.17,100.57 61.37,100.57 62.25,99.7 62.36,99.7 66.58,95.48 72.84,95.48 72.98,95.33 76.39,95.33 v2(77.27,94.45) 77.05,94.45 76.6,94 76.6,93.04 76.99,92.65 78.11,92.65 80.79,95.33 91.72,95.33 91.98,95.59 91.99,95.59 92.06,95.65 92.06,95.65 v2(93.05,96.64)
  BOTTOM w0.102: RV84.1 98.7,106.95 RV157.2 98.75,106.95 RV89.2 98.75,103.31 v1(93.1,97.66) 93.1,96.73 93.05,96.68 v2(93.05,96.64)
SVI2_SVD: length 91.5
  TOP w0.102: v2(50.25,123.46) 50.27,123.44 PU1100.5 ; RV93.2 76.85,93.31 v2(77.32,93.31) 77.87,93.31 RV101.2
  IN2 w0.127: v2(50.25,123.46) 50.12,123.46 48.92,122.26 48.92,108.51 51.27,106.15 51.27,104.85 54.4,101.72 61.72,101.72 63.02,100.42 63.02,99.94 66.84,96.11 73.1,96.11 73.25,95.97 76.85,95.97 77.93,94.89 77.93,94.64 77.93,93.93 v2(77.32,93.31) 77.35,93.28 77.84,93.28 79.65,95.09 79.65,95.14 79.97,95.46 80.02,95.46 80.53,95.97 87.39,95.97 87.39,95.97 87.91,95.97 87.91,95.97 91.46,95.97 91.71,96.22 91.73,96.22 v2(92.49,96.98)
  BOTTOM w0.102: v2(92.49,96.98) 92.49,97.91 v1(94.3,99.73) 97.81,103.23 97.81,105.02 97.3,105.53 96.59,105.53 95.78,106.35 95.78,108.47 96.22,108.91 RV88.2 ; RV155.2 97.97,108.98 97.9,108.91 RV88.2 ; RV88.2 97.3,108.04 RV87.1
SVI2_SVT: length 78.1
  TOP w0.102: PU1100.7 50.3,122.64 v2(50.13,122.47)
  IN2 w0.127: v2(50.13,122.47) 50.02,122.47 49.55,121.99 49.55,108.77 51.91,106.41 51.91,105.11 54.67,102.35 61.99,102.35 63.69,100.65 63.69,100.16 67.11,96.75 73.36,96.75 73.51,96.6 77.49,96.6 77.74,96.35 79.01,96.35 79.59,96.92 82.24,96.92 82.24,96.92 82.59,96.92 82.59,96.92 86.38,96.92 86.44,96.86 89.2,96.86 89.27,96.79 89.62,96.79 89.69,96.86 91.45,96.86 v2(91.59,96.99) ; v2(97.05,104.92) 97.05,105.3 97.81,106.06 97.81,107.7 v2(97.99,107.88)
  BOTTOM w0.102: RV156.2 98.08,107.97 v2(97.99,107.88) ; v2(97.05,104.92) v1(97.05,103.97) 97.05,103.33 91.59,97.87 v2(91.59,96.99)
SYS_RESET_L: length 9.6
  BOTTOM w0.102: RC952.1 132.05,50.12 130.06,50.12 129.49,49.55 CC53.1 RC951.2 128.42,49.88 v1(127.86,49.88) 127.76,49.78 127.33,49.78 126.35,50.76 UC1.AF1
SYSON: length 206.8
  IN1 w0.127: v2(63.53,97.49) 64.92,96.09 77.87,96.09 79.14,97.36 87.08,97.36 v2(87.08,97.43) ; v2(146.98,43.85) 146.35,43.85 145.92,44.28 145.5,44.28 143.17,44.28 138.64,48.81 138.64,49.95 138.96,50.27 138.96,50.86 138.96,51.07 138.96,51.07 138.96,57.23 136.77,59.42 136.77,63.99 136.29,64.47 136.29,66.14 135.08,67.35 135.08,68.16 135.08,68.92 134.36,69.64 124.92,69.64 119.08,75.47 119.08,82.31 118.83,82.57 118.44,82.57 117.17,81.3 116.6,81.3 108.99,88.91 108.99,92.16 108.8,92.35 v2(108.8,93.62)
  IN2 w0.127: v2(63.53,97.49) 63.53,96.17 62.08,94.72 50.83,94.72 47.8,97.75 44.08,97.75 40.31,93.98 39.27,93.98 39.26,93.98 36.07,93.98 36.07,93.98 34.35,93.98 34.14,93.77 29.14,93.77 26.69,96.22 23.1,96.22 22.71,96.6 20.53,96.6 18.82,98.32 v2(16.85,98.32)
  BOTTOM w0.102: PR903.1 17.25,98.72 v2(16.85,98.32) ; PR201.1 87.08,98.62 v2(87.08,97.43) 87.3,97.21 88.63,97.21 89.6,96.24 91.53,96.24 91.53,96.24 92.05,96.24 92.21,96.24 92.41,96.03 96.92,96.03 96.98,95.97 96.99,95.97 98,94.96 98,92.73 99.03,91.7 105.99,91.7 106.9,92.61 106.9,93.48 107.11,93.68 108.73,93.68 v2(108.8,93.62) ; v2(146.98,43.85) 146.98,43.43 148.36,42.06 158.9,42.06 162.33,38.63 163.98,38.63 v1(164.23,38.37) 164.94,37.66 164.94,36.63 165.15,36.42 UE1.95
T-GND_L:
  vias: v1(20.53,114.32) v2(21.74,118.95) v2(21.74,118.26)
TESTEN: length 18.5
  TOP w0.102: v4(117.69,91.01) 117.62,90.95 v2(117.62,90.39) RV17.2 116.71,88.71 RV154.2
  IN1 w0.102: 118.41,102.63 118.41,102.68 118.99,103.26 118.99,103.96 118.65,104.3 v2(118.56,104.3)
  IN1 w0.127: v2(117.62,90.39) 117.3,90.71 117.3,95.9 117.69,96.28 117.69,98.45 117.5,98.64 117.5,100.86 118.13,101.49 118.13,102.35 118.41,102.63
  BOTTOM w0.102: v2(118.56,104.3) 118.5,104.3 UV1.K7
TMDS_L_TX0N: length 16.9
  TOP w0.102: JHDMI1.9 10.79,86.16 11.03,86.16 11.13,86.26 11.13,91.52 11.45,91.84 12.96,91.84 13.18,91.62 13.18,89.7 13.44,89.44 13.48,89.44 13.88,89.04 13.88,89 v3(14.56,88.32) 14.94,87.94 14.94,87.75 15.08,87.61 15.17,87.61 CI13.1 15.75,87.72 16.02,87.72 RI6.1 16.84,87.92 17.5,87.92 17.67,88.09 LI2.1 17.98,88.26 RI4.2
TMDS_L_TX0P: length 16.9
  TOP w0.102: RI5.2 17.98,87.42 LI2.4 17.75,87.65 17.55,87.65 17.48,87.72 16.98,87.72 16.58,87.32 RI6.2 16.34,87.51 15.93,87.51 CI14.1 15.2,87.41 15,87.41 14.74,87.67 14.74,87.85 14.63,87.96 14.6,87.96 14.2,88.36 14.2,88.39 v3(13.51,89.08) 12.97,89.62 12.97,91.53 12.87,91.64 11.53,91.64 11.34,91.44 11.34,86.18 11.12,85.96 10.91,85.96 JHDMI1.7
TMDS_L_TX1N: length 8.4
  TOP w0.102: RI7.2 18.04,82.63 LI3.1 17.73,82.31 16.94,82.31 RI9.1 16.43,82.82 CI15.1 15.06,82.36 14.8,82.36 14.64,82.53 14.64,82.56 14.24,82.96 14.2,82.96 14.07,83.1 v3(14.07,83.86) 14.07,84.24 13.69,84.61 12.39,84.61 JHDMI1.6
TMDS_L_TX1P: length 8.4
  TOP w0.102: JHDMI1.4 12.41,84.41 13.61,84.41 13.84,84.18 13.84,83.58 13.86,83.56 13.86,83.01 v3(14.28,82.6) 14.71,82.16 15.06,82.16 CI16.1 16.43,81.7 RI9.2 16.83,82.11 17.72,82.11 LI3.4 18.04,81.79 RI8.2
TMDS_L_TX2N: length 10.9
  TOP w0.102: JHDMI1.3 10.45,83.38 11.07,82.75 11.24,82.75 12.04,81.95 12.68,81.95 13.28,81.34 13.32,81.34 13.72,80.94 13.72,80.9 14.98,79.65 v3(15.51,79.65) 16.3,79.65 CI17.1 16.62,79.88 16.91,79.58 17.15,79.58 RI12.2 17.8,79.72 18.58,79.72 18.62,79.77 LI4.1 18.83,79.86 RI11.2
TMDS_L_TX2P: length 10.9
  TOP w0.102: JHDMI1.1 10.52,82.56 11.15,82.55 11.96,81.74 12.59,81.74 v3(13.36,80.98) 14.89,79.44 15.21,79.44 15.23,79.42 15.8,79.42 15.82,79.44 16.1,79.44 CI18.1 16.9,79.38 17.23,79.38 RI12.1 17.55,79.27 17.8,79.52 18.32,79.52 18.57,79.27 LI4.4 18.99,79.1 RI10.2
TMDS_L_TXCN: length 9.6
  TOP w0.102: RI1.2 19.12,85.63 LI1.1 18.68,85.46 18.56,85.34 17.88,85.34 RI3.1 17.39,85.51 CI11.1 16.19,85.17 v3(15.51,85.17) 14.98,85.17 14.56,85.59 14.56,85.96 14.59,85.98 14.59,86.55 14.56,86.57 14.56,86.82 13.78,87.6 12.4,87.6 JHDMI1.12
TMDS_L_TXCP: length 9.6
  TOP w0.102: RI2.2 19.12,84.79 LI1.4 18.75,84.96 18.58,85.13 17.92,85.13 RI3.2 17.44,84.65 CI12.1 16.21,84.97 15.82,84.97 15.8,84.94 15.23,84.94 15.21,84.97 14.89,84.97 14.36,85.5 v3(14.36,86.26) 14.36,86.74 13.7,87.4 12.4,87.4 JHDMI1.10
TMDS_TX0N: length 6.2
  TOP w0.102: RI4.1 18.89,88.26 LI2.2 19.74,88.09 v2(19.77,88.12) 19.93,87.96 20.13,87.96 CI3.1
  BOTTOM w0.102: v2(19.77,88.12) 19.59,87.94 18.33,87.94 17.16,86.78 16.74,86.78 16.59,86.92 RPI1.1
TMDS_TX0P: length 6.2
  TOP w0.102: CI4.1 20.14,87.71 19.96,87.71 v2(19.78,87.53) 19.73,87.59 LI2.3 18.89,87.42 RI5.1
  BOTTOM w0.102: v2(19.78,87.53) 19.58,87.74 18.41,87.74 17.25,86.57 16.8,86.57 16.65,86.42 RPI1.2
TMDS_TX1N: length 6.7
  TOP w0.102: RI7.1 19.12,82.55 LI3.2 19.27,82.31 19.58,82.31 v2(19.83,82.57) 20.09,82.31 20.17,82.31 CI5.1
  BOTTOM w0.102: RPI2.1 16.57,80.74 16.72,80.59 17.5,80.59 19.23,82.32 19.58,82.32 v2(19.83,82.57)
TMDS_TX1P: length 6.7
  TOP w0.102: RI8.1 19.12,81.87 LI3.3 19.27,82.11 19.59,82.11 v2(19.83,81.87) 20.07,82.11 20.17,82.11 CI6.1
  BOTTOM w0.102: v2(19.83,81.87) 19.58,82.12 19.31,82.12 17.58,80.38 16.75,80.38 16.6,80.24 RPI2.2
TMDS_TX2N: length 6.9
  TOP w0.102: CI7.1 21.53,80.02 21.17,79.65 21.04,79.65 v2(20.85,79.84) 20.78,79.84 20.59,79.65 20.2,79.65 LI4.2 19.91,79.94 RI11.1
  BOTTOM w0.102: v2(20.85,79.84) 20.63,79.62 16.75,79.62 16.63,79.74 RPI2.3
TMDS_TX2P: length 6.9
  TOP w0.102: RI10.1 19.91,79.1 LI4.3 20.2,79.39 20.66,79.39 v2(20.85,79.2) 21.04,79.39 21.15,79.39 CI8.1
  BOTTOM w0.102: v2(20.85,79.2) 20.63,79.42 16.76,79.42 16.58,79.24 RPI2.4
TMDS_TXCN: length 7.3
  TOP w0.102: CI1.1 21.28,85.34 21.13,85.34 v2(20.91,85.55) 20.7,85.34 20.33,85.34 LI1.2 20.2,85.55 RI1.1
  BOTTOM w0.102: RPI1.3 16.53,85.92 16.67,85.78 19.01,85.78 19.55,85.24 20.59,85.24 v2(20.91,85.55)
TMDS_TXCP: length 7.2
  TOP w0.102: CI2.1 21.28,85.08 21.14,85.08 v2(20.91,84.85) 20.68,85.08 20.33,85.08 LI1.3 20.2,84.87 RI2.1
  BOTTOM w0.102: v2(20.91,84.85) 20.73,85.03 19.46,85.03 18.92,85.57 16.65,85.57 16.5,85.43 RPI1.4
TON_1.2V: length 2.1
  BOTTOM w0.203: PU200.9 86.77,100.93 85.87,100.03 PR208.2
TP_CLK: length 120.3
  TOP w0.102: R31.1 C553.1 103.19,4.29 104.2,3.28 v2(104.2,2.9)
  IN1 w0.127: v2(170.39,30.63) 170.47,30.7 170.63,30.7 174.57,26.76 176.45,26.76 177.38,25.84 177.38,22.98 178.62,21.74 178.62,19.56 178.98,19.21 178.98,18.17 178.79,17.98 178.79,16.2 179.79,15.19 179.79,13.54 v2(179.73,13.48)
  IN2 w0.127: v2(179.73,13.48) 179.86,13.34 179.86,12.54 178.14,10.81 174.84,10.81 168.74,4.72 160.25,4.72 158.53,2.99 152.92,2.99 151.85,1.92 131.03,1.92 130.9,1.8 105.29,1.8 104.2,2.89 v2(104.2,2.9)
  BOTTOM w0.102: JTP1.1 104.9,8.78 104.6,8.48 104.6,5.6 103.63,4.63 103.63,3.47 v2(104.2,2.9) ; v2(170.39,30.63) 169.56,30.63 166.96,33.22 166,33.22 UE1.87
TP_DATA: length 123.3
  TOP w0.102: v2(103.61,2.88) 102.33,4.16 C551.1 R32.1
  IN1 w0.127: v2(170.35,31.22) 170.43,31.13 170.81,31.13 174.75,27.2 176.63,27.2 177.81,26.02 177.81,23.16 179.05,21.91 179.05,19.74 179.41,19.39 179.41,17.99 179.22,17.8 179.22,16.38 180.22,15.37 180.22,13.68 v2(180.42,13.48)
  IN2 w0.127: v2(180.42,13.48) 180.3,13.35 180.3,12.36 178.32,10.38 175.01,10.38 168.92,4.29 160.43,4.29 158.71,2.56 153.09,2.56 152.03,1.49 131.21,1.49 131.08,1.36 105.1,1.36 103.61,2.85 v2(103.61,2.88)
  BOTTOM w0.102: v2(103.61,2.88) 102.53,3.96 102.53,4.11 104.2,5.77 104.2,8.48 103.9,8.78 JTP1.2 ; UE1.88 167.13,33.63 169.72,31.03 170.24,31.03 170.35,31.13 v2(170.35,31.22)
TP_EN: length 88.4
  TOP w0.102: v2(170.45,29.93) 170.45,28.97 171.35,28.08 171.35,23.26 169.95,21.86 169.95,18.69 168.49,17.23 165.44,17.23 161.66,13.44 159.35,13.44 158.28,14.52 158.26,14.5 156.29,14.5 155.4,13.61 155.4,13.35 155,12.95 149.27,12.95 147.59,14.63 137.52,14.63 136.88,13.99 124.16,13.99 124.01,13.84 122.98,13.84 122.83,13.99 120.69,13.99 119.18,15.5 116.24,15.5 115.55,16.18 115.55,16.96 115.22,17.29 114.49,17.29 113.24,16.04 v1(113.24,13.92) 113.24,10.24 113.05,10.05 112.86,10.05 112.8,10.11 112.54,10.11 112.48,10.05 112.11,10.05 R39.1
  BOTTOM w0.102: UE1.82 166.86,31.22 167.38,30.7 168.91,30.7 169.43,30.18 170.35,30.18 170.45,30.08 v2(170.45,29.93)
TP_I2C_INT#: length 55.7
  TOP w0.102: v2(85.58,19.1) 85.63,19.04 v1(85.63,18.05) 85.63,17.47 90.44,12.65 95.46,12.65 96.41,11.7 96.41,9.42 97.21,8.62 v2(99.39,8.62) 99.36,8.59 Q9.3 96.03,6.95 95.52,6.44 R150.2 RE338.2
  BOTTOM w0.102: RP20.1 105.01,24.77 103.58,26.2 92.31,26.2 85.63,19.53 85.63,19.15 v2(85.58,19.1) ; v2(99.39,8.62) 99.87,8.15 101.75,8.15 101.9,8.3 JTP1.4
TP_I2C_INT#_APU: length 105.6
  TOP w0.102: Q9.1 96.59,5.99 96.12,5.52 96.12,5.24 R150.1 95.52,3.07 v2(95.46,3) ; RC22.2 RC12.2 140.94,44.51 142.45,43 142.45,41.55 142.45,41.36 141.27,40.18 138.95,37.86 138.95,37.57 135.22,33.85 135.22,32.29 134.25,31.31 134.25,28.07 134.01,27.83 134.01,22.69 135.08,21.61 138.64,21.61 140.48,19.77 v2(140.48,19.45) ; v2(106.89,11.38) 106.89,12.91 107.57,13.59 v1(110.46,13.59) 114.39,17.52 117.48,17.52 120.31,14.69 123.85,14.69 124.29,14.24 136.8,14.24 137.66,15.1 v2(141.78,15.1)
  BOTTOM w0.102: v2(106.89,11.38) 106.89,9.22 105.56,7.88 105.56,2.62 104.92,1.99 96.48,1.99 v2(95.46,3) ; v2(140.48,19.45) 140.48,17.54 141.78,16.24 v2(141.78,15.1)
TP_ON#_GATE: length 9.1
  TOP w0.102: C22.2 110.76,9.72 R39.2 ; C22.2 108.5,9.72 Q12.2 106.83,8.04 106.83,6.62 108,5.45 Q85.2 ; C22.2 109.75,8.78 v1(109.81,8.72)
TPAN_VDD_F:
  vias: v1(229.26,32.28)
TRIP_VDDP_ALWP: length 3.5
  TOP w0.254: PU300.2 158.97,30.32 158.55,29.9 157.92,29.9 v2(157.75,29.74)
  BOTTOM w0.102: v2(157.75,29.74) 157.37,29.74 v1(157.06,29.42)
  BOTTOM w0.254: PR304.2 v2(157.75,29.74)
TS_EN_R: length 65
  TOP w0.102: v2(172.33,30.83) v1(172.33,32.15) 172.33,32.57 D4.2
  IN2 w0.127: v2(217.06,28.53) 216.95,28.41 216.95,25.26 215.41,23.73 201,23.73 199.46,25.26 199.46,30.79 197.83,32.42 185.51,32.42 185.38,32.54 179.75,32.54 177.81,30.6 177.16,30.6 176.99,30.43 174.77,30.43 174.52,30.18 172.74,30.18 172.33,30.59 v2(172.33,30.83)
  BOTTOM w0.102: RX25.2 221.05,29.37 220.95,29.47 218.96,29.47 218.21,28.72 217.25,28.72 v2(217.06,28.53)
TS_EN_RR: length 4.9
  BOTTOM w0.102: JEDP1.39 223.2,31.05 221.97,29.81 RX25.1 221.97,27.65 v1(221.89,27.58)
UG1_APU: length 13.5
  TOP w0.102: v1(154.01,72.92) 153.99,72.9 v2(153.99,72.22)
  IN2 w0.762: 162.2,62.82 162.2,62.95 159.6,65.55 158.52,65.55 157.63,66.44 157.63,69.36 155.6,71.39 155.6,72.22
  vias: v2(154.58,72.22) v2(162.2,61.87) v2(162.83,61.87)
UG1_VGA: length 21.7
  TOP w0.102: v2(74.38,110.64) v1(73.68,110.64)
  IN2 w0.762: 73.74,111.52 73.17,112.1 73.17,115.72 72.06,116.83 66.28,116.83 64.16,118.95 59.65,118.95 58.44,120.16
  vias: v2(57.04,121.31) v2(57.49,120.93) v2(74.39,110)
UG2_VGA: length 16.8
  IN2 w0.762: 58.44,126.51 59.01,126.51 61.55,129.05 69.87,129.05 71.97,126.95 72.64,126.95 72.65,126.94
  BOTTOM w0.102: v2(57.42,125.25) 57.44,125.25 v1(57.91,125.71)
  vias: v2(57.03,124.79) v2(73.41,126.83) v2(74.05,126.83)
UG_1.2V: length 7.9
  IN2 w0.762: 79.59,105.36 80.4,105.36 81.54,106.51 83.52,106.51 84.06,107.05 85.33,107.05 85.81,106.57
  BOTTOM w0.102: v1(78.25,106.06) 78.76,105.56 v2(78.76,105.49)
  vias: v2(78.76,104.86) v2(86.25,105.94) v2(86.63,105.49)
UG_NB: length 9.4
  TOP w0.102: v2(154.13,57.93) v1(153.63,57.93)
  IN2 w0.762: 155.6,57.61 156.24,56.96 164.26,56.96
  vias: v2(154.77,57.93) v2(164.99,56.91) v2(164.99,56.28)
UG_VDDP_ALWP: length 7.9
  IN2 w0.762: 151.79,35.9 152.32,36.43 157.6,36.43 158.44,35.59
  BOTTOM w0.102: v2(158.96,35.07) v1(158.33,35.07)
  vias: v2(150.32,35.71) v2(150.96,35.71) v2(158.96,34.44)
USB3RN1_JUSB1: length 174
  TOP w0.102: v2(24.62,57.93) 24.56,57.99 23.95,57.99 23.84,57.88 LU1.3 23.34,57.72 RU1.1
  IN2 w0.127: v2(24.62,57.93) 24.76,57.93 24.77,57.94 25.82,57.94 28.29,55.47 28.29,46.36 38.41,36.24 38.41,31.54 41.87,28.08 41.87,18.64 48.42,12.09 77.62,12.09 77.75,12.22 77.76,12.22 79,13.46 83.63,13.46 86,15.83 92.79,15.83 93.36,16.4 93.42,16.4 93.42,16.4 94.21,16.4 94.21,16.4 103.06,16.4 104.65,17.99 108.29,17.99 109.13,18.83 109.13,19.06 109.9,19.84 109.96,19.84 111.77,21.65 112.13,21.65 112.65,21.65 112.96,21.96 113.66,21.96 114.09,22.38 114.09,22.39 114.13,22.43 120.16,22.43 122.83,25.11 122.83,26.22 122.83,33.04 128.34,38.54 128.34,38.63 128.34,38.63 128.34,40.46 128.34,40.46 128.34,43.02 128.26,43.1 128.26,44.32 128.93,44.98 128.93,46.02 127.9,47.04 127.9,49.05 127.9,52.1 127.9,52.1 127.9,54.77 127.84,54.83 127.84,55.57 127.97,55.7 v2(127.98,55.7)
  BOTTOM w0.102: v2(127.98,55.7) 127.93,55.7 127.55,55.32 127.35,55.32 126.99,54.96 126.31,54.96 UC1.W1
USB3RN1_JUSB1_R: length 11.1
  TOP w0.102: RU1.2 22.42,57.72 LU1.4 22.08,58.06 20.34,58.06 20.13,58.27 v3(19.73,58.27) 19.3,58.27 19.17,58.14 EU2601.1 EU2601.9 17.24,58.14 17.11,58.27 16.68,58.27 15.64,57.23 14.44,57.23 13.79,56.58 13.44,56.58 13.16,56.3 13.16,55.72 JUSB1.5
USB3RN2_JUSB2: length 180.6
  TOP w0.102: v2(24.46,38.63) 24.34,38.75 23.68,38.75 LU4.3 23.34,38.41 RU7.1
  IN2 w0.127: v2(131.15,57.04) 130.97,56.87 130.97,55.64 129.81,54.48 129.81,47.95 131.97,45.79 131.97,43.71 132.36,43.33 132.36,41.93 132.17,41.74 132.17,34.43 133.05,33.55 133.05,32.63 133.05,27.64 124.29,18.88 122.9,18.88 122.64,18.62 115.79,18.62 115.02,17.86 113.75,17.86 109.95,14.05 107.4,14.05 105.88,12.53 96.67,12.53 96.06,11.92 94.76,11.92 94.54,11.7 88.48,11.7 85.83,9.06 82.4,9.06 81.52,8.18 81.52,8.16 80.94,7.57 75.65,7.57 74.98,6.91 64.77,6.91 63.56,8.12 46.97,8.12 37.93,17.16 37.93,26.43 31.57,32.79 26.69,32.79 26.68,32.78 25.1,32.78 23.39,34.49 23.39,36.47 25.04,38.12 25.04,38.56 24.92,38.69 24.52,38.69 v2(24.46,38.63)
  BOTTOM w0.102: UC1.Y1 125.78,54.06 125.85,53.99 126.31,53.99 126.3,53.99 126.37,53.92 126.91,53.92 126.98,53.99 127.18,53.99 128.7,55.52 130.28,55.52 130.96,56.19 130.96,56.24 130.96,56.24 130.96,56.85 v2(131.15,57.04)
USB3RN2_JUSB2_R: length 12.5
  TOP w0.102: RU7.2 22.42,38.41 LU4.4 22.07,38.77 20.53,38.77 20.35,38.58 v3(19.91,38.58) 18.9,38.58 18.77,38.45 EU2603.1 EU2603.9 17.11,38.45 16.99,38.58 16.69,38.58 16.24,38.12 16.24,37.12 14.39,35.27 14.19,35.27 13.8,34.88 13.42,34.88 13.18,34.64 JUSB2.5
USB3RP1_JUSB1: length 174
  TOP w0.102: RU2.1 23.34,58.6 LU1.2 23.77,58.43 23.98,58.23 24.29,58.23 v2(24.62,58.57)
  IN2 w0.127: v2(127.39,55.7) 127.53,55.57 127.53,54.7 127.59,54.64 127.59,51.97 127.59,51.05 127.59,49.18 127.59,46.91 128.61,45.89 128.61,45.11 127.95,44.45 127.95,42.97 128.03,42.89 128.03,40.33 128.03,38.67 122.52,33.16 122.52,26.09 122.52,25.24 120.03,22.75 114.79,22.75 114,22.75 113.78,22.52 113.78,22.51 113.53,22.27 112.83,22.27 112.52,21.96 112,21.96 112,21.96 111.64,21.96 109.83,20.15 109.78,20.15 108.82,19.19 108.82,18.96 108.16,18.3 104.52,18.3 102.93,16.71 94.34,16.71 93.24,16.71 92.66,16.14 86.13,16.14 85.87,16.14 83.5,13.77 78.87,13.77 77.63,12.53 77.62,12.53 77.49,12.4 48.55,12.4 42.18,18.77 42.18,28.21 38.72,31.67 38.72,36.37 28.61,46.49 28.61,55.6 25.95,58.25 24.9,58.25 24.8,58.35 24.75,58.35 24.62,58.47 v2(24.62,58.57)
  BOTTOM w0.102: UC1.W2 125.55,54.61 125.65,54.71 125.65,54.74 126.11,55.2 126.89,55.2 127.25,55.56 127.29,55.56 127.39,55.66 v2(127.39,55.7)
USB3RP1_JUSB1_R: length 11.1
  TOP w0.102: RU2.2 22.42,58.6 LU1.1 22.12,58.3 v3(21.1,58.3) 20.44,58.3 20.23,58.51 19.3,58.51 19.17,58.64 EU2601.2 EU2601.8 17.24,58.64 17.11,58.51 16.58,58.51 15.54,57.47 14.34,57.47 13.7,56.82 13.44,56.82 13.18,57.09 JUSB1.6
USB3RP2_JUSB2: length 180.6
  TOP w0.102: RU8.1 23.34,39.3 LU4.2 23.64,38.99 24.2,38.99 v2(24.47,39.26)
  IN2 w0.127: v2(24.47,39.26) 24.73,39 25.05,39 25.36,38.69 25.36,37.99 23.71,36.34 23.71,34.62 25.23,33.1 26.55,33.1 26.56,33.1 31.7,33.1 38.24,26.56 38.24,26.19 38.24,17.29 47.1,8.44 63.69,8.44 64.9,7.22 74.86,7.22 75.52,7.89 80.81,7.89 81.21,8.29 81.21,8.31 82.27,9.37 85.7,9.37 88.35,12.01 94.41,12.01 94.63,12.23 94.89,12.23 95.93,12.23 96.54,12.85 105.75,12.85 107.27,14.36 109.82,14.36 113.48,18.03 113.48,18.03 113.62,18.17 114.89,18.17 115.66,18.94 115.71,18.94 122.51,18.94 122.77,19.2 123.02,19.2 124.16,19.2 132.73,27.77 132.73,32.76 132.74,32.76 132.74,33.42 131.86,34.3 131.86,41.87 132.05,42.06 132.05,43.2 131.66,43.58 131.66,45.66 129.5,47.82 129.5,54.61 130.66,55.77 130.66,56.89 v2(130.53,57.02)
  BOTTOM w0.102: UC1.Y2 125.13,54.28 125.39,54.28 125.48,54.37 125.75,54.37 125.81,54.31 125.87,54.31 125.95,54.23 127.08,54.23 128.6,55.76 130.18,55.76 130.72,56.29 130.72,56.34 130.72,56.34 130.72,56.6 130.72,56.6 130.72,56.84 v2(130.53,57.02)
USB3RP2_JUSB2_R: length 12.6
  TOP w0.102: JUSB2.6 13.18,35.24 13.28,35.13 13.72,35.13 14.09,35.51 14.29,35.51 16,37.22 16,38.22 16.59,38.81 16.95,38.81 17.08,38.95 EU2603.8 EU2603.2 18.78,38.95 18.91,38.82 20.25,38.82 20.43,39.01 v3(21.17,39.01) 22.13,39.01 LU4.1 22.42,39.3 RU8.2
USB3TN1_JUSB1: length 173.9
  TOP w0.102: v2(27.33,59.93) 27.21,60.04 26.21,60.04 CU1.2
  IN2 w0.127: v2(127.72,56.35) 127.66,56.41 126.45,56.41 125.85,55.81 125.85,52.81 126.96,51.7 126.96,51.45 126.96,49.36 125.85,48.26 125.85,42.46 126.45,41.87 126.45,39.7 126.07,39.32 125.12,39.32 124.99,39.2 124.99,37.96 120.92,33.89 120.92,29.91 120.92,29.91 120.92,29.65 120.92,29.65 120.92,28.59 120.48,28.15 120.48,25.44 119.37,24.33 119.12,24.33 112.65,24.33 111.87,23.55 110.99,23.55 110.19,22.75 109.99,22.75 109.99,22.75 109.81,22.75 108.35,21.29 107.27,21.29 106.82,20.84 106.82,20.84 105.99,20.02 104.68,20.02 103.96,20.02 102.83,18.88 100.58,18.88 99.93,19.53 94.14,19.53 92.98,18.36 85.77,18.36 85.26,17.85 80.62,17.85 77.27,14.51 50.84,14.51 50.35,15 48.19,15 43.89,19.3 43.89,20.26 44.16,20.53 44.16,29.54 43.14,30.56 42.44,30.56 40.54,32.46 40.54,36.91 30.19,47.26 30.19,58.75 28.91,60.03 27.43,60.03 v2(27.33,59.93)
  BOTTOM w0.102: UC1.R2 125.49,56.81 125.96,56.35 126.53,56.35 126.63,56.45 127.62,56.45 v2(127.72,56.35)
USB3TN1_JUSB1_C: length 2
  TOP w0.102: CU1.1 24.58,60.09 23.68,60.09 LU2.3 23.34,59.75 RU3.1
USB3TN1_JUSB1_R: length 11.6
  TOP w0.102: RU3.2 22.42,59.75 LU2.4 22.07,60.1 20.82,60.1 20.48,59.77 v3(19.71,59.77) 19.3,59.77 19.17,59.64 EU2601.4 EU2601.7 17.26,59.64 17.13,59.77 16.8,59.77 14.57,61.99 14.18,61.99 13.61,62.57 13.33,62.57 13.18,62.42 JUSB1.8
USB3TN2_JUSB2: length 172.7
  TOP w0.102: v2(26.66,40.84) 26.56,40.94 26.04,40.94 25.88,40.77 CU3.2
  IN2 w0.127: v2(128.87,57.65) 129.02,57.65 129.21,57.46 129.21,56.69 128.54,56.02 128.54,47.44 129.92,46.06 129.92,33.31 130.84,32.4 130.84,28.8 129.42,27.39 125.87,27.39 124.42,25.94 124.42,23.58 122.63,21.79 122.24,21.79 121.3,20.84 115.97,20.84 115.97,20.84 115.31,20.84 115.31,20.84 114.78,20.84 114.01,20.07 112.84,20.07 109.17,16.4 108.99,16.4 105.29,16.4 103.7,14.8 94.69,14.8 94.43,14.8 93.61,13.98 86.57,13.98 83.9,11.32 81.36,11.32 80.47,10.43 47.84,10.43 41.22,17.06 40.22,18.06 40.22,27.5 35.32,32.39 35.32,32.79 34.37,33.73 34.37,36.28 31.52,39.13 31.26,39.13 31.26,39.13 26.88,39.13 25.93,40.08 25.93,40.93 26.14,41.14 26.36,41.14 v2(26.66,40.84)
  BOTTOM w0.102: v2(128.87,57.65) 128.99,57.65 129.3,57.35 129.3,57.17 129.19,57.07 128.76,57.07 128.23,57.6 127.85,57.6 127.71,57.73 127.34,57.73 127.21,57.6 126.5,57.6 126.35,57.6 126.25,57.6 125.84,57.6 125.74,57.7 125.48,57.7 125.31,57.52 125.31,57.32 125.2,57.22 125.05,57.22 UC1.P2
USB3TN2_JUSB2_C: length 2
  TOP w0.102: RU9.1 23.34,40.44 LU5.3 23.69,40.8 24.57,40.8 CU3.1
USB3TN2_JUSB2_R: length 11
  TOP w0.102: RU9.2 22.42,40.44 LU5.4 22.08,40.79 20.91,40.79 20.21,40.08 v3(19.98,40.08) 18.91,40.08 18.78,39.95 EU2603.4 EU2603.7 17.06,39.95 16.93,40.08 14.5,40.08 13.67,40.91 13.29,40.91 13.18,40.8 JUSB2.8
USB3TP1_JUSB1: length 173.8
  TOP w0.102: v2(27.33,60.7) 27.33,60.48 27.12,60.28 26.32,60.28 CU2.2
  IN2 w0.127: v2(27.33,60.7) 27.33,60.47 27.45,60.34 29.04,60.34 30.5,58.88 30.5,47.39 40.85,37.04 40.85,32.59 42.57,30.87 43.27,30.87 44.47,29.67 44.47,20.4 44.2,20.13 44.2,19.43 48.32,15.32 50.48,15.32 50.97,14.83 77.15,14.83 80.49,18.17 85.13,18.17 85.64,18.68 92.85,18.68 93.75,19.57 93.75,19.58 94.01,19.84 100.06,19.84 100.71,19.19 102.7,19.19 103.84,20.33 104.81,20.33 104.81,20.33 105.86,20.33 106.69,21.15 106.69,21.15 107.14,21.6 108.22,21.6 109.68,23.06 109.94,23.06 109.94,23.06 110.06,23.06 110.86,23.86 110.91,23.86 111.74,23.86 112.52,24.65 119.25,24.65 120.17,25.57 120.17,28.28 120.61,28.72 120.61,34.02 124.68,38.09 124.68,39.33 124.99,39.64 125.94,39.64 126.13,39.83 126.13,41.74 125.54,42.33 125.54,48.38 126.64,49.49 126.64,51.57 125.54,52.68 125.54,55.94 126.32,56.72 127.51,56.72 v2(127.72,56.93)
  BOTTOM w0.102: v2(127.72,56.93) 127.47,56.69 126.53,56.69 126.43,56.59 126.06,56.59 125.96,56.69 UC1.R1
USB3TP1_JUSB1_C: length 2
  TOP w0.102: CU2.1 24.58,60.34 23.63,60.34 LU2.2 23.34,60.63 RU4.1
USB3TP1_JUSB1_R: length 11.7
  TOP w0.102: RU4.2 22.42,60.63 LU2.1 22.13,60.34 v3(21.04,60.34) 20.72,60.34 20.38,60.01 19.3,60.01 19.17,60.14 EU2601.5 EU2601.6 17.26,60.14 17.13,60.01 16.9,60.01 14.67,62.23 14.28,62.23 13.71,62.81 13.35,62.81 13.18,62.98 JUSB1.9
USB3TP2_JUSB2: length 172.7
  TOP w0.102: CU4.2 26.11,41.19 26.42,41.19 v2(26.69,41.46)
  IN2 w0.127: v2(129.58,57.65) 129.52,57.6 129.52,56.56 128.86,55.9 128.86,47.57 130.24,46.19 130.24,33.44 131.15,32.53 131.15,28.67 129.55,27.07 126,27.07 124.73,25.81 124.73,23.45 122.76,21.48 122.38,21.48 121.91,21 121.9,21 121.43,20.53 114.91,20.53 114.14,19.76 112.97,19.76 109.3,16.08 108.86,16.08 108.86,16.08 105.42,16.08 103.83,14.49 94.56,14.49 93.74,13.67 86.7,13.67 84.03,11 83.77,11 83.77,11 81.49,11 80.6,10.12 47.71,10.12 41.09,16.75 39.9,17.93 39.9,27.37 35.01,32.27 35.01,32.66 34.06,33.6 34.06,36.15 31.39,38.82 26.75,38.82 25.62,39.95 25.62,41.06 26.01,41.45 26.68,41.45 v2(26.69,41.46)
  BOTTOM w0.102: v2(129.58,57.65) 129.54,57.61 129.54,57.07 129.29,56.83 128.66,56.83 128.13,57.36 126.49,57.36 126.35,57.36 126.34,57.36 126.24,57.36 125.61,57.36 UC1.P1
USB3TP2_JUSB2_C: length 2
  TOP w0.102: CU4.1 24.58,41.04 23.63,41.04 LU5.2 23.34,41.33 RU10.1
USB3TP2_JUSB2_R: length 10.9
  TOP w0.102: JUSB2.9 13.18,41.34 13.37,41.15 13.77,41.15 14.6,40.32 16.93,40.32 17.06,40.45 EU2603.6 EU2603.5 18.73,40.45 18.86,40.32 20.11,40.32 20.81,41.02 v3(21.1,41.02) 22.12,41.02 LU5.1 22.42,41.33 RU10.2
USB20_CAM_N3: length 138.4
  IN2 w0.127: v2(134.79,42.09) 134.84,42.04 134.84,41.55 136.06,40.33 137.65,40.33 137.77,40.21 137.77,36.38 135.97,34.58 135.97,29.04 136.27,28.75 136.27,26.4 140.04,22.62 141.38,22.62 141.58,22.63 141.96,22.63 141.98,22.63 143.15,22.63 144.16,21.61 147.78,21.61 148.1,21.3 153.75,21.3 153.94,21.1 153.95,21.1 154.01,21.04 154.26,21.04 159.41,21.04 159.98,21.04 160.8,21.87 161.82,21.87 161.82,21.87 162.07,21.87 162.1,21.89 162.1,21.89 162.9,22.69 165.49,22.69 167.49,24.69 167.49,25.23 168.48,26.22 176.62,26.22 177.25,25.59 179.82,25.59 180.09,25.31 180.98,25.31 182.47,23.82 187.57,23.82 189.04,22.34 192.93,22.34 193.71,21.56 198.67,21.56 199.82,20.4 216.68,20.4 218.84,22.56 218.84,23.65 218.84,23.65 218.84,26.41 219.94,27.51 219.94,31.81 219.07,32.68 219.07,34.78 v2(219.13,34.84)
  BOTTOM w0.102: UC1.AT2 125.18,45.26 125.48,44.96 125.73,44.96 125.79,45.01 127.1,45.01 130.59,41.52 131.68,41.52 132.19,42.03 132.19,43.01 132.51,43.33 133.36,43.33 134.03,42.65 134.68,42.65 134.79,42.55 v2(134.79,42.09) ; v2(219.13,34.84) 219.02,34.73 219.02,34.54 219.12,34.44 219.44,34.44 219.54,34.54 220.61,34.54 L3.4 220.8,34.73 R18.1
USB20_CAM_N3_R: length 2.9
  BOTTOM w0.102: JEDP1.31 223.38,35.05 223.25,34.92 223.08,34.92 222.55,34.39 222.25,34.39 222.08,34.56 L3.3 221.71,34.73 R18.2
USB20_CAM_P3: length 138.3
  IN2 w0.127: v2(218.41,34.79) 218.6,34.79 218.76,34.63 218.76,32.55 219.62,31.68 219.62,27.64 218.53,26.54 218.53,23.78 218.53,23.78 218.53,22.69 216.55,20.71 199.95,20.71 198.8,21.87 198.54,21.87 198.54,21.87 193.84,21.87 193.06,22.66 189.17,22.66 187.7,24.13 182.6,24.13 181.11,25.62 180.22,25.62 179.95,25.9 177.38,25.9 176.75,26.53 168.35,26.53 167.18,25.36 167.18,24.82 165.36,23.01 162.77,23.01 161.95,22.18 160.68,22.18 159.85,21.35 154.13,21.35 153.88,21.61 148.23,21.61 147.91,21.93 144.29,21.93 143.28,22.94 141.98,22.94 141.95,22.94 141.58,22.94 141.37,22.94 140.17,22.94 136.58,26.53 136.58,28.87 136.29,29.17 136.29,34.45 138.09,36.25 138.09,40.34 137.78,40.65 136.19,40.65 135.16,41.68 135.16,41.9 135.3,42.04 v2(135.52,42.04)
  BOTTOM w0.102: R17.1 220.8,33.89 L3.1 220.26,34.06 220.02,34.3 219.64,34.3 219.53,34.2 219.02,34.2 218.78,34.44 218.78,34.64 218.63,34.79 v2(218.41,34.79) ; UC1.AT1 125.62,45.25 127.2,45.25 130.69,41.76 131.58,41.76 131.95,42.13 131.95,43.11 132.41,43.56 133.46,43.56 134.13,42.89 134.78,42.89 135.02,42.65 135.02,42.53 135.18,42.37 135.18,42.18 135.33,42.04 v2(135.52,42.04)
USB20_CAM_P3_R: length 2.8
  BOTTOM w0.102: JEDP1.32 223.74,34.55 223.61,34.68 223.18,34.68 v3(222.87,34.37) 222.64,34.15 221.97,34.15 L3.2 221.71,33.89 R17.2
USB20_CR_N0: length 84.5
  IN2 w0.127: v2(183.09,21.54) 183.09,22.17 181.72,23.55 170.17,23.55 167.53,20.91 165.88,20.91 165.44,21.35 163.6,21.35 162.64,20.4 162.64,20.4 162.58,20.34 162.58,19.51 162.01,18.94 157.56,18.94 156.8,19.7 156.54,19.7 152.29,19.7 152.04,19.96 147.88,19.96 147.84,19.92 141.37,19.92 138.37,22.93 138.11,22.93 138.11,22.93 136.31,22.93 135.53,23.7 135.53,25.29 135.63,25.39 135.63,28.3 135.33,28.6 135.33,35.01 134.13,36.21 134.13,39.58 134.43,39.88 134.43,40.44 v2(134.59,40.59)
  BOTTOM w0.102: v2(183.09,21.54) 182.96,21.41 182.96,20.83 LU8.2 183.25,20.54 RU17.1 ; v2(134.59,40.59) 134.59,40.4 134.13,39.95 133.45,39.95 132.93,39.43 129.52,39.43 127.27,41.67 127.27,42.17 126.29,43.16 126.02,43.16 126.02,43.17 125.85,43.17 125.41,43.61 UC1.AW2
USB20_CR_N0_R: length 2.4
  BOTTOM w0.102: RU17.2 183.25,19.63 LU8.1 183.14,19.41 183.14,18.38 183.6,17.92 JIOB1.3
USB20_CR_P0: length 84.5
  IN2 w0.127: v2(133.69,40.59) 133.81,40.71 133.99,40.71 134.12,40.59 134.12,40.01 133.82,39.71 133.82,36.08 135.02,34.88 135.02,28.47 135.31,28.17 135.31,25.52 135.22,25.42 135.22,23.83 135.22,23.83 135.22,23.57 136.18,22.61 138.24,22.61 141.24,19.61 147.97,19.61 148.01,19.64 151.91,19.64 152.16,19.39 152.42,19.39 156.67,19.39 157.43,18.63 161.88,18.63 161.88,18.63 162.14,18.63 162.39,18.88 162.39,18.88 162.83,19.32 162.83,19.32 162.89,19.38 162.89,19.64 162.89,20.21 163.72,21.04 163.79,21.04 163.79,21.04 165.29,21.04 165.3,21.04 165.31,21.04 165.63,20.71 165.64,20.71 165.75,20.6 166.01,20.6 166.01,20.6 167.4,20.6 167.4,20.6 167.66,20.6 170.3,23.24 181.59,23.24 182.78,22.05 182.78,21.87 v2(182.46,21.54)
  BOTTOM w0.102: RU18.1 182.42,20.54 LU8.3 182.73,20.85 182.73,21.28 v2(182.46,21.54) ; UC1.AW1 125.96,43.5 126.06,43.4 126.39,43.4 127.51,42.27 127.51,41.77 129.62,39.66 132.83,39.66 133.35,40.19 134.03,40.19 134.18,40.33 134.18,40.59 134.08,40.69 133.78,40.69 v2(133.69,40.59)
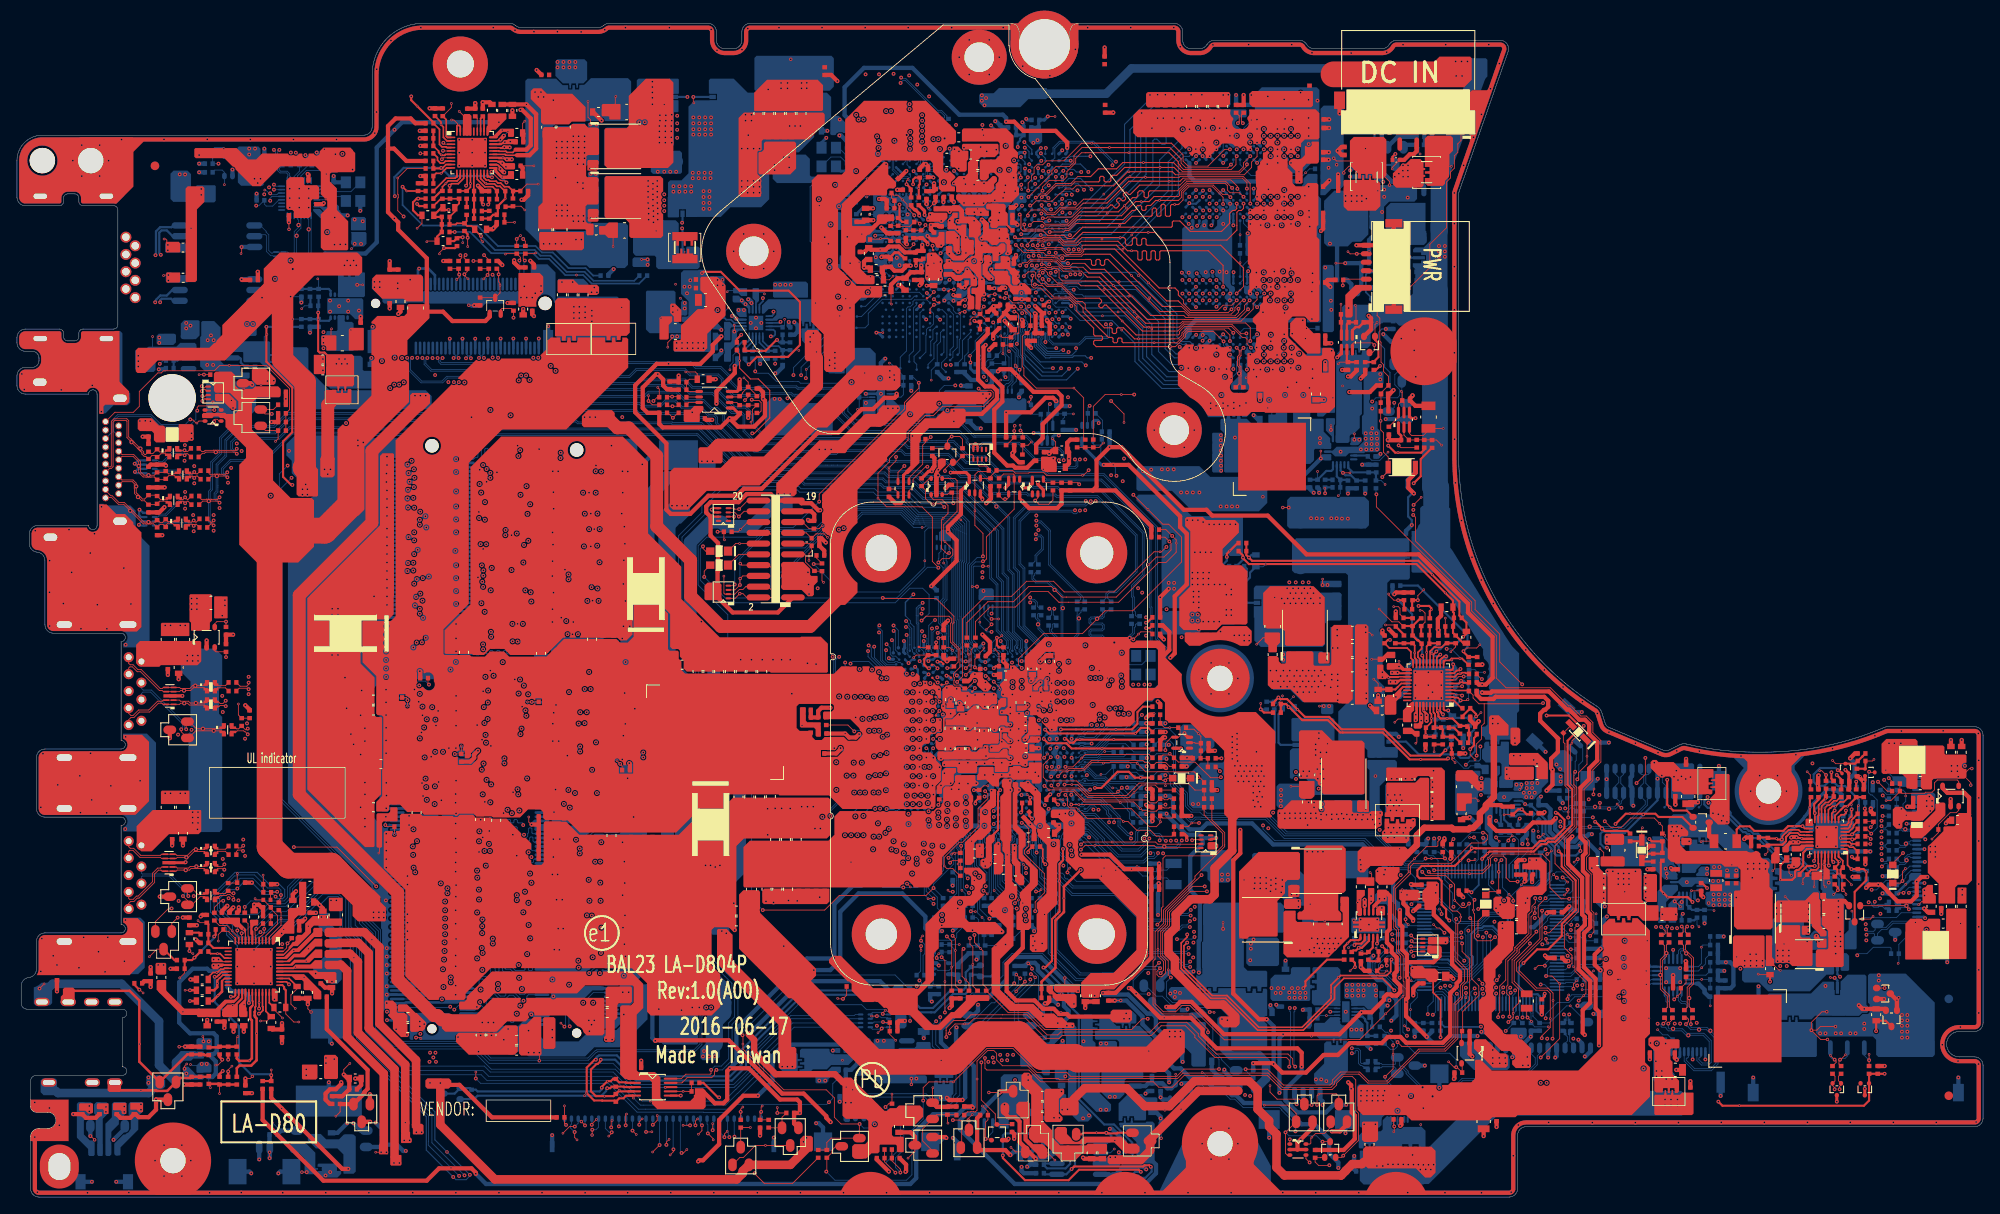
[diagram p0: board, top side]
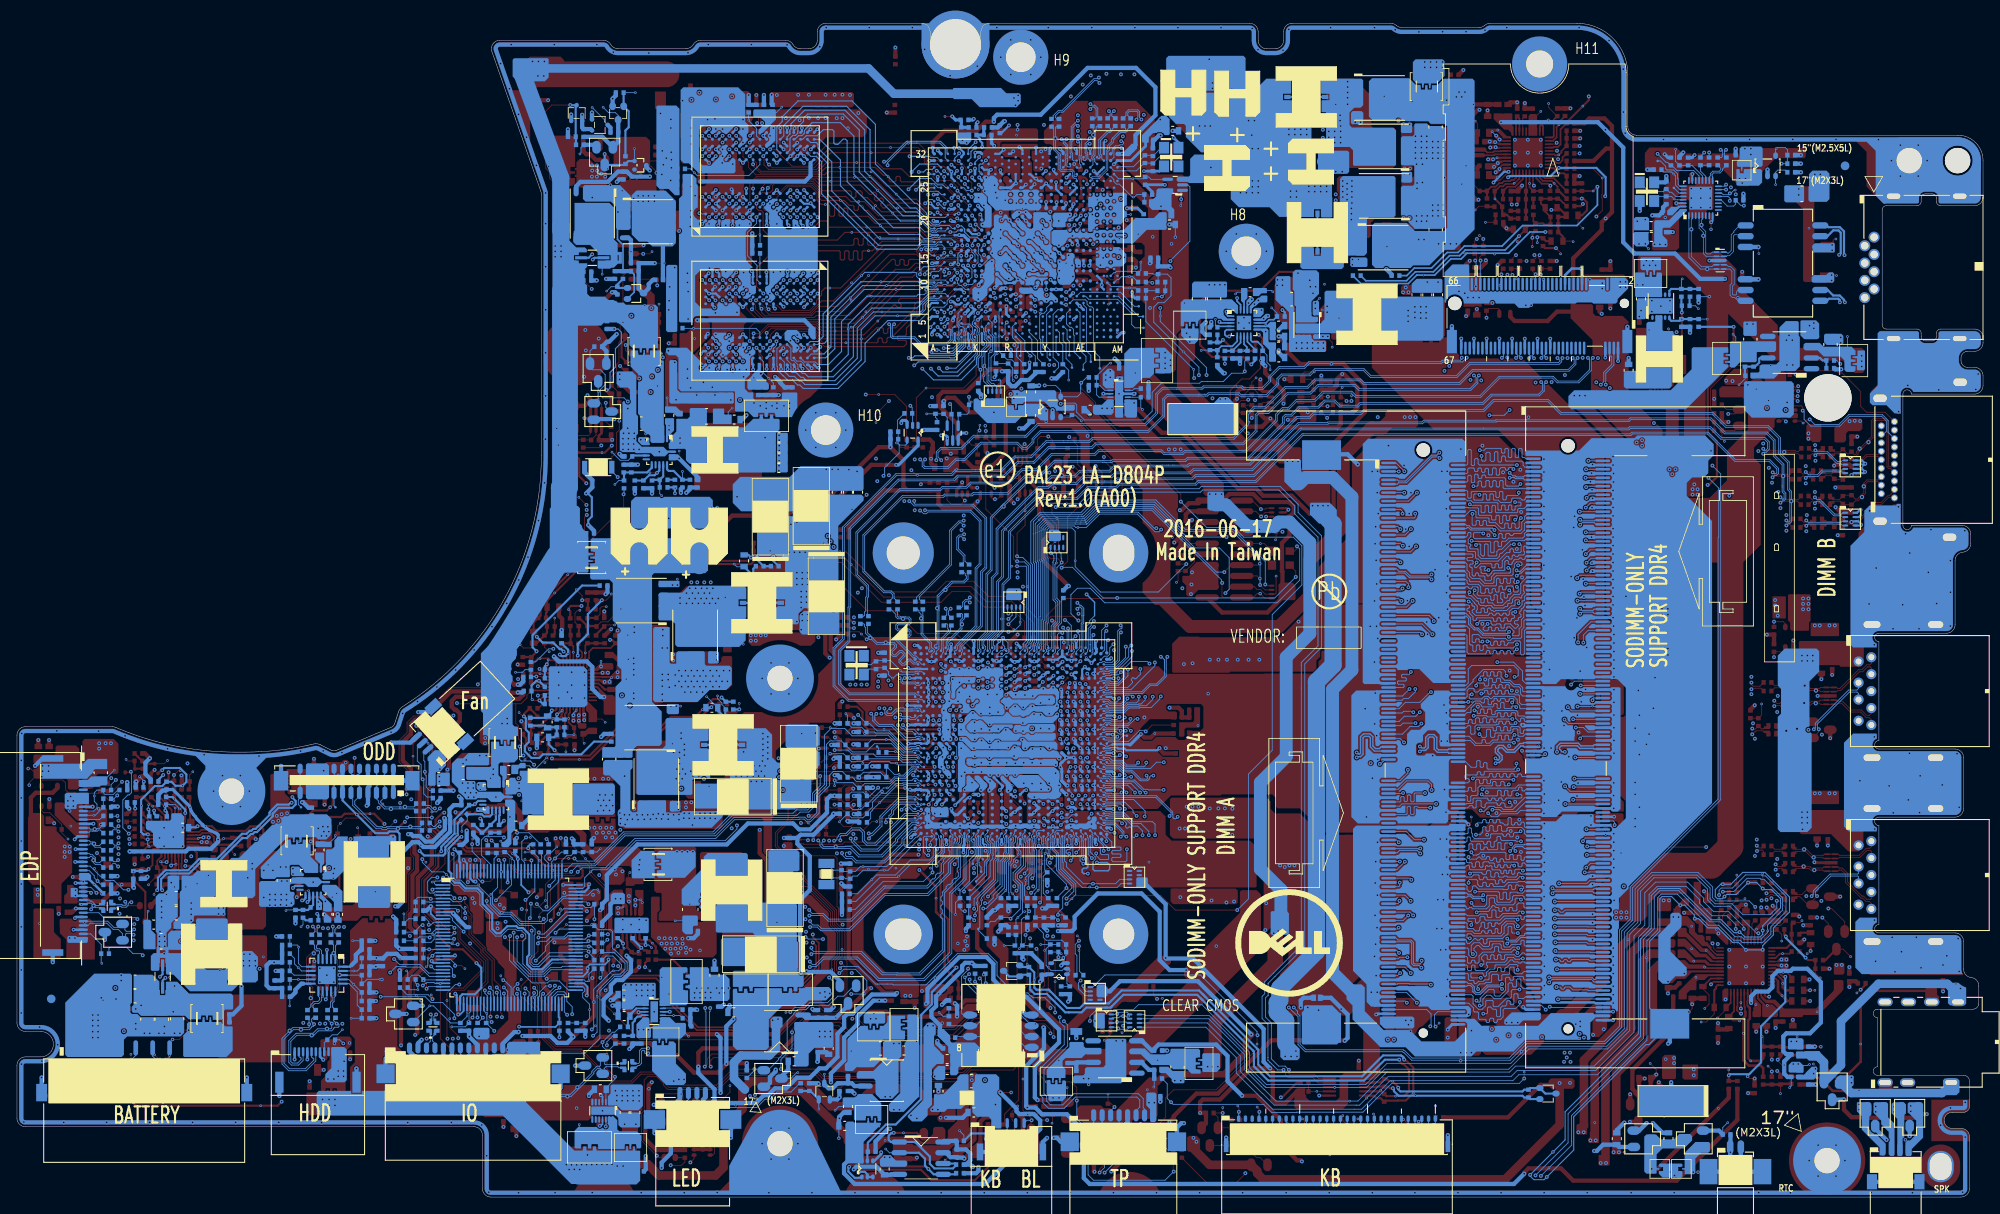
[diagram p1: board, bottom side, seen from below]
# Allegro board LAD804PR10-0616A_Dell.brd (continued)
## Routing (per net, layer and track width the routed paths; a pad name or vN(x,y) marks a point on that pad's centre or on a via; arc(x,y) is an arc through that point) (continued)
USB20_CR_P0_R: length 2.4
  BOTTOM w0.102: JIOB1.4 182.6,18.13 182.9,18.43 182.9,18.89 182.71,19.08 182.71,19.34 LU8.4 182.42,19.63 RU18.2
USB20_JUSB1_N2: length 60
  IN2 w0.127: v2(133.56,42.31) 133.53,42.28 133.53,41.45 133.17,41.1 133.17,35.29 134.01,34.46 134.01,27.26 134.44,26.82 134.44,26.56 134.44,22.31 135.59,21.16 138,21.16 140.29,18.87 143.91,18.87 144.14,18.87 145.85,18.87 146.04,18.69 155.99,18.69 157.15,17.52 157.43,17.52 v2(157.45,17.55)
  BOTTOM w0.102: RU14.1 159.33,15.93 LU7.2 158.58,15.76 158.48,15.86 158.48,17.28 158.2,17.55 v2(157.45,17.55) ; UC1.AU2 125.51,44.71 125.84,44.38 126.74,44.38 130.29,40.83 132.36,40.83 133.45,41.91 133.45,42.2 v2(133.56,42.31)
USB20_JUSB1_N2_R: length 25.6
  BOTTOM w0.102: JIOB1.8 178.6,16.9 179.09,16.42 179.09,15.71 177.35,13.97 170.42,13.97 168.57,12.12 166.63,12.12 v3(165.8,12.95) 164.09,14.66 164.09,14.85 163.5,15.43 163.21,15.43 163.17,15.43 163.09,15.51 163.09,16.2 DU1.3 162.58,16.25 162.58,15.7 162.5,15.62 161.06,15.62 160.91,15.76 LU7.1 160.24,15.93 RU14.2
USB20_JUSB1_N5: length 163.5
  TOP w0.102: v2(27.22,55.28) 27.09,55.14 26.95,55.14 RU15.1 26.16,55.25 25.92,55.25 25.78,55.39 LU3.2 25.32,55.55 RU6.1
  IN2 w0.127: v2(27.22,55.28) 27.66,54.84 27.66,45.34 36.15,36.85 36.15,35.49 36.53,35.11 36.53,34.6 37.75,33.38 37.75,31.3 41.24,27.82 41.24,18.38 41.61,18.01 48.17,11.45 79.9,11.45 81.28,12.83 83.89,12.83 86.03,14.97 92.89,14.97 93.69,15.77 103.32,15.77 104.91,17.35 108.73,17.35 108.78,17.35 111.31,19.87 112.45,21.02 113.62,21.02 114.4,21.79 114.92,21.79 120.42,21.79 120.95,22.32 121.34,22.32 123.47,24.45 123.47,28.87 123.47,32.76 128.98,38.27 128.98,44.07 v2(128.81,44.23)
  BOTTOM w0.102: v2(128.81,44.23) 128.81,44.9 128.52,45.2 128.52,45.55 127.71,46.37 126.07,46.37 125.76,46.06 125.46,46.06 125.15,46.36 UC1.AP2
USB20_JUSB1_N5_R: length 14.1
  TOP w0.102: v2(19.96,55.2) 19.96,56 20.06,56.1 EU2602.3 20.33,56.1 21.17,55.26 v3(21.94,55.26) 24.11,55.26 LU3.1 24.4,55.55 RU6.2
  BOTTOM w0.102: JUSB1.2 14.68,60.03 14.89,59.82 15.87,59.82 19.79,55.9 19.79,55.37 v2(19.96,55.2)
USB20_JUSB1_P2: length 60
  IN2 w0.127: v2(132.97,42.31) 133.21,42.07 133.21,41.58 132.86,41.23 132.86,35.16 133.69,34.33 133.69,27.13 134.13,26.69 134.13,22.44 134.13,22.18 135.46,20.85 137.87,20.85 140.16,18.56 144.04,18.56 144.27,18.56 145.73,18.56 145.91,18.37 155.86,18.37 157.02,17.21 157.21,17.21 v2(157.45,16.97)
  BOTTOM w0.102: v2(132.97,42.31) 133,42.31 133.21,42.1 133.21,42.01 132.26,41.06 130.39,41.06 126.84,44.62 126.05,44.62 UC1.AU1 ; v2(157.45,16.97) 157.5,16.93 157.77,16.93 157.84,17 157.84,17.21 157.94,17.31 158.1,17.31 158.24,17.18 158.24,15.76 158.48,15.52 158.63,15.52 158.74,15.41 158.82,15.41 158.97,15.26 LU7.3 159.33,15.09 RU13.1
USB20_JUSB1_P2_R: length 25.5
  BOTTOM w0.102: JIOB1.7 179.6,16.94 179.33,16.66 179.33,15.61 177.45,13.73 170.52,13.73 168.67,11.88 v3(166.97,11.88) 166.53,11.88 163.85,14.56 163.85,14.75 163.41,15.19 163.13,15.19 163.02,15.09 163.02,14.76 DU1.2 162.64,14.71 162.64,15.16 162.43,15.38 161.04,15.38 160.92,15.26 LU7.4 160.24,15.09 RU13.2
USB20_JUSB1_P5: length 163.4
  TOP w0.102: v2(27.22,54.6) 27.22,54.6 26.92,54.91 26.85,54.91 26.74,55.01 25.97,55.01 25.84,54.89 LU3.3 25.32,54.72 RU5.1
  IN2 w0.127: v2(27.22,54.6) 27.35,54.48 27.35,45.21 35.84,36.72 35.84,35.36 36.22,34.98 36.22,34.47 37.44,33.25 37.44,31.17 40.92,27.69 40.92,18.25 41.48,17.69 48.04,11.14 80.03,11.14 81.41,12.51 84.02,12.51 86.16,14.65 93.01,14.65 93.81,15.45 103.45,15.45 105.04,17.04 108.6,17.04 108.91,17.04 111.62,19.74 112.58,20.7 113.75,20.7 114.53,21.48 120.55,21.48 121.08,22.01 121.47,22.01 123.78,24.32 123.78,24.58 123.78,24.58 123.78,28.87 123.78,32.63 129.29,38.14 129.29,44.12 v2(129.4,44.23)
  BOTTOM w0.102: UC1.AP1 125.61,46.5 125.71,46.61 127.8,46.61 128.76,45.65 128.76,45.3 129.05,45 129.05,44.79 129.16,44.68 129.34,44.68 129.44,44.58 129.44,44.27 v2(129.4,44.23)
USB20_JUSB1_P5_R: length 14.1
  TOP w0.102: v2(19.37,55.2) 19.37,54.91 EU2602.2 20.26,54.17 21.11,55.02 v3(23.21,55.02) 24.11,55.02 LU3.4 24.4,54.72 RU5.2
  BOTTOM w0.102: JUSB1.3 14.68,59.41 14.85,59.58 15.77,59.58 19.55,55.8 19.55,55.37 v2(19.37,55.2)
USB20_JUSB2_N6: length 158.2
  TOP w0.102: v2(25.55,35.84) 25.31,35.84 25.03,36.13 RU16.1 24.6,35.83 LU6.2 23.34,36 RU12.1
  IN2 w0.127: v2(131.43,42.91) 131.41,42.91 130.87,42.37 130.87,33.76 131.79,32.85 131.79,28.41 129.49,26.11 127.07,26.11 125.65,24.7 125.65,23.1 123.39,20.84 122.64,20.84 121.69,19.88 116.37,19.88 115.32,19.88 115.27,19.88 114.5,19.12 113.24,19.12 113.09,18.97 113.08,18.97 109.5,15.38 105.62,15.38 104.09,13.85 96.09,13.85 95.42,13.18 95.28,13.18 94.21,13.18 93.99,12.97 86.89,12.97 84.29,10.37 83.51,10.37 81.87,10.37 80.92,9.42 47.52,9.42 40.82,16.11 40.82,16.11 39.34,17.59 39.27,17.67 39.27,26.88 32.78,33.36 32.78,33.93 31.9,34.81 29.87,34.81 28.83,35.84 v2(25.55,35.84)
  BOTTOM w0.102: UC1.AN2 125.52,46.91 125.62,47.01 125.63,47.01 125.83,47.21 125.93,47.21 125.94,47.22 126.92,47.22 127,47.15 127.89,47.15 130.11,44.93 130.11,44.24 130.11,43.88 131.08,42.91 131.43,42.91 v2(131.43,42.91)
USB20_JUSB2_N6_R: length 11.4
  TOP w0.102: RU12.2 22.42,36 LU6.1 22.13,35.71 21.36,35.71 20.64,36.42 EU2604.3 20.11,35.62 v2(20.21,35.51)
  BOTTOM w0.102: JUSB2.2 14.68,38.22 14.78,38.12 18.04,38.12 20.02,36.13 20.02,35.71 v2(20.21,35.51)
USB20_JUSB2_P6: length 158.2
  TOP w0.102: v2(25.54,35.07) 25.55,35.07 25.65,35.17 25.65,35.32 25.53,35.44 25.37,35.44 25.1,35.71 24.82,35.71 24.7,35.59 24.03,35.59 23.9,35.45 23.63,35.45 LU6.3 23.34,35.16 RU11.1
  IN2 w0.127: v2(25.54,35.07) 25.46,35.15 25.46,35.33 25.56,35.43 25.72,35.43 25.83,35.53 28.7,35.53 29.74,34.5 31.77,34.5 32.47,33.8 32.47,33.24 38.96,26.75 38.96,17.54 39.03,17.46 47.39,9.1 81.05,9.1 82,10.06 83.38,10.06 84.42,10.06 87.02,12.65 94.12,12.65 94.34,12.87 94.37,12.87 95.55,12.87 96.22,13.54 104.22,13.54 105.75,15.07 109.63,15.07 113.21,18.66 113.22,18.66 113.37,18.81 114.63,18.81 115.39,19.57 115.45,19.57 115.45,19.57 116.24,19.57 116.24,19.57 121.81,19.57 122.77,20.53 123.52,20.53 125.97,22.97 125.97,24.57 127.2,25.8 129.62,25.8 132.1,28.28 132.1,32.98 131.18,33.89 131.18,42.09 v2(131.4,42.31)
  BOTTOM w0.102: UC1.AN1 126.04,46.99 126.82,46.99 126.9,46.91 127.79,46.91 129.87,44.83 129.87,44.34 129.87,44.34 129.87,43.78 130.98,42.67 131.1,42.67 131.26,42.51 131.33,42.51 131.4,42.44 v2(131.4,42.31)
USB20_JUSB2_P6_R: length 11.5
  TOP w0.102: v2(19.58,35.51) 20.11,34.98 EU2604.2 20.64,34.49 21.61,35.45 22.13,35.45 LU6.4 22.42,35.16 RU11.2
  BOTTOM w0.102: v2(19.58,35.51) 19.78,35.72 19.78,36.03 17.94,37.88 14.78,37.88 14.68,37.78 JUSB2.3
USB20_MINI1_N4: length 212.3
  IN2 w0.127: v2(126.97,45.71) 126.97,45.49 126.49,45.01 126.49,43.09 127.08,42.5 127.08,39.94 127.08,39.94 127.08,39.15 127.08,39.15 126.04,38.11 126.04,38.06 125.24,37.26 125.19,37.26 121.56,33.63 121.56,32.49 121.56,32.26 121.56,31.28 121.56,28.36 121.56,25.62 119.64,23.7 118.85,23.7 118.85,23.7 114,23.7 113.31,23.7 112.92,23.7 112.13,22.91 111.69,22.91 111.25,22.91 109.57,21.23 109.49,21.23 108.47,20.21 107.72,20.21 107.38,20.21 107.38,20.21 107.08,20.21 106.25,19.38 104.26,19.38 102.8,17.92 100.54,17.92 99.72,18.75 99.46,18.75 94.31,18.75 93.24,17.67 92.73,17.67 92.16,17.1 85.05,17.1 83.9,15.95 81.42,15.95 80.2,14.72 78.87,14.72 78.74,14.72 78.48,14.72 77.4,13.64 56.25,13.64 56.03,13.42 51.01,13.42 50.12,14.31 47.99,14.31 43.13,19.16 43.13,28.66 39.67,32.12 39.67,34.59 39.67,36.82 29.55,46.94 29.55,56.52 26.37,59.7 26.37,63.26 30.09,66.98 30.09,76 31.2,77.11 31.2,83.14 31.01,83.33 31.01,87.63 35.28,91.9 38.4,91.9 41.57,91.9 44.81,95.14 44.81,95.55 45.08,95.82 v2(45.08,95.86)
  BOTTOM w0.102: v2(45.08,95.86) 44.74,96.21 44.74,97.31 43.79,98.26 43.79,99.16 43.86,99.23 43.97,99.23 44.05,99.31 JWLAN1.5 ; UC1.AR2 125.2,45.81 125.1,45.71 125.1,45.6 125.2,45.5 125.38,45.5 125.5,45.62 125.68,45.62 125.79,45.51 126.21,45.51 126.63,45.92 126.87,45.92 126.97,45.82 v2(126.97,45.71)
USB20_MINI1_P4: length 212.3
  IN2 w0.127: v2(127.57,45.7) 127.57,45.65 126.8,44.88 126.8,43.22 127.39,42.63 127.39,40.07 127.39,40.06 127.39,39.02 126.35,37.98 126.35,37.93 125.37,36.95 125.32,36.95 121.87,33.5 121.87,33.2 121.87,32.26 121.87,31.28 121.87,28.36 121.87,25.49 119.77,23.39 118.72,23.39 113.18,23.39 113.05,23.39 112.26,22.6 111.82,22.6 111.38,22.6 109.7,20.91 109.62,20.91 108.6,19.89 107.21,19.89 106.38,19.07 104.39,19.07 102.93,17.61 100.41,17.61 99.59,18.43 94.44,18.43 93.37,17.36 92.86,17.36 92.29,16.79 85.18,16.79 84.03,15.64 83.77,15.64 83.77,15.64 81.55,15.64 80.33,14.41 78.74,14.41 78.74,14.41 78.61,14.41 77.53,13.33 56.38,13.33 56.16,13.1 50.88,13.1 49.99,13.99 47.86,13.99 42.82,19.03 42.82,28.53 39.36,31.99 39.36,34.72 39.36,36.69 29.24,46.81 29.24,56.39 26.06,59.57 26.06,63.39 29.78,67.11 29.78,73.8 29.78,73.8 29.78,74.06 29.78,76.13 30.89,77.24 30.89,83.01 30.7,83.2 30.7,87.76 35.15,92.22 38.53,92.22 39.99,92.21 41.44,92.21 44.5,95.27 v2(44.5,95.86)
  BOTTOM w0.102: UC1.AR1 126.18,45.81 126.53,46.16 127.1,46.16 v2(127.57,45.7) ; v2(44.5,95.86) 44.5,97.21 43.55,98.16 JWLAN1.3
USB20_TOUCH_N1: length 134.5
  IN2 w0.127: v2(218.09,31.59) 217.85,31.35 217.6,31.35 217.22,30.97 217.22,29.69 217.58,29.33 217.58,24.17 215.69,22.28 201.34,22.28 199.57,24.05 195.13,24.05 193.37,25.82 182.32,25.82 181.29,26.85 177.78,26.85 177.15,27.48 167.82,27.48 164.92,24.57 164.39,24.57 163.77,23.95 161.4,23.95 160.76,23.32 154.01,23.32 153.75,23.32 153.31,22.88 151.18,22.88 151.02,23.04 150.44,23.04 149.59,23.04 149.17,23.45 144.54,23.45 143.98,24.02 140.49,24.02 137.56,26.94 137.56,33.99 139.16,35.59 139.16,35.59 139.22,35.65 139.22,35.91 139.22,40.78 138.39,41.61 137.37,41.61 137.24,41.73 137.24,41.92 v2(137.4,42.08)
  BOTTOM w0.102: v2(137.4,42.08) 137.37,42.08 137.19,41.9 137.19,41.48 136.83,41.12 133.6,41.12 132.62,40.14 129.83,40.14 128.04,41.93 128.04,42.17 126.27,43.93 125.83,43.93 125.72,43.83 125.48,43.83 125.16,44.16 UC1.AV2 ; v2(218.09,31.59) 218.31,31.36 219,31.36 219.17,31.53 219.17,31.95 DX2.3 219.85,31.82 220.46,31.82 221.19,32.55 JEDP1.36
USB20_TOUCH_P1: length 134.5
  IN2 w0.127: v2(218.15,30.95) 218.06,31.04 217.73,31.04 217.53,30.84 217.53,29.82 217.89,29.46 217.89,24.04 215.82,21.97 201.47,21.97 201.21,21.97 199.44,23.74 195,23.74 193.24,25.51 182.19,25.51 181.16,26.53 177.65,26.53 177.02,27.16 167.95,27.16 165.04,24.25 164.52,24.25 163.9,23.64 161.53,23.64 160.89,23.01 153.88,23.01 153.44,22.57 151.05,22.57 150.89,22.73 150.31,22.73 149.46,22.73 149.04,23.14 144.41,23.14 143.85,23.7 140.36,23.7 137.25,26.81 137.25,34.12 138.9,35.77 138.9,40.65 138.26,41.29 137.24,41.29 136.93,41.6 136.93,41.88 v2(136.73,42.07)
  BOTTOM w0.102: v2(218.15,30.95) 218.32,31.12 218.99,31.12 219.1,31.02 219.1,30.65 DX2.2 219.45,31.08 219.95,31.59 220.56,31.59 221.29,32.31 223.25,32.31 223.51,32.05 JEDP1.37 ; UC1.AV1 125.62,44.17 126.37,44.17 128.27,42.27 128.27,42.03 129.93,40.38 132.52,40.38 133.51,41.36 v3(135.33,41.36) 136.73,41.36 136.95,41.58 136.95,41.85 v2(136.73,42.07)
USB_EN#: length 241.7
  TOP w0.102: v1(168.87,15.96) 169.5,15.32 v2(169.76,15.32) 169.83,15.32 CU22.1 170.47,15.7 UU3.4 ; UI5.4 23.32,67.64 23.58,67.9 v2(24.66,67.9) CU8.1
  IN2 w0.127: v2(24.66,67.9) 24.47,67.71 24.47,64.6 22.37,62.5 22.37,34.6 22.37,34.21 26.28,30.31 30.75,30.31 30.97,30.52 32.57,30.52 36.47,26.62 36.47,17.23 39.12,14.58 39.12,13.19 41.73,10.59 43.01,10.59 46.77,6.84 61.78,6.84 63.41,5.21 77.66,5.21 78.89,6.43 89.44,6.43 91.28,8.27 96.22,8.27 97.05,9.1 99.08,9.1 99.28,9.3 109.24,9.3 110.95,11 111.78,11 113.81,13.04 120.54,13.04 121.11,13.61 123.61,13.61 124.76,14.75 124.97,14.75 131.34,14.75 132.29,15.7 136.69,15.7 136.9,15.7 137.16,15.45 138.87,15.45 139.76,14.56 149.33,14.56 149.71,14.94 154.77,14.94 155.7,14.01 155.7,13.27 155.96,13.01 157.12,13.01 157.23,13.12 157.98,13.12 158.01,13.1 166.71,13.1 168.93,15.32 v2(169.76,15.32)
  BOTTOM w0.102: UE1.84 165.99,32.02 RE504.1 163.32,31.55 161.87,31.55 161.65,31.32 161.65,29.36 161.52,29.23 161.46,29.23 161.33,29.1 161.31,29.1 159.98,27.77 159.98,27.74 159.93,27.69 159.93,26.76 160.64,26.04 161.41,26.04 163.14,24.31 163.14,18.74 164.91,16.97 169,16.97 169.76,16.21 v2(169.76,15.32)
USB_OC0#: length 227.3
  TOP w0.102: v2(139.72,37.99) 139.15,37.42 139.12,37.42 135.45,33.75 135.45,32.19 134.58,31.31 v1(134.58,29.22) 134.58,28.44 135.24,27.78 135.24,26.77 v2(134.9,26.42) ; v2(24.66,63.71) CU9.1 24.65,64.34 23.45,64.34 23.32,64.47 UI5.3
  IN2 w0.127: v2(24.66,63.71) 22.63,61.68 22.63,34.32 24.79,32.15 30.82,32.15 31.9,31.07 32.38,31.07 36.72,26.73 36.72,17.35 39.48,14.59 39.48,13.19 41.83,10.84 43.16,10.84 46.84,7.17 62.51,7.17 63.4,6.28 75.29,6.28 75.95,6.94 82.25,6.94 83.73,8.42 89.07,8.42 90.99,10.34 98.48,10.34 99.46,11.32 106.13,11.32 107.59,12.78 110.32,12.78 113.3,15.77 113.3,16.15 114.07,16.91 115.4,16.91 116.1,17.61 125.75,17.61 129.94,21.8 130.07,21.8 130.96,22.69 132.23,22.69 v2(133.5,23.96) ; v2(132.69,56.89) 132.7,56.89 132.7,56.89 132.35,56.55 132.35,55.58 130.45,53.68 130.45,49.17 130.83,48.79 131.27,48.79 131.59,48.47 131.59,47.07 132.61,46.06 132.61,43.98 132.89,43.7 134.78,43.7 135.78,42.69 139.53,42.69 140.04,42.18 140.04,38.31 v2(139.72,37.99)
  BOTTOM w0.102: UC1.AB2 125.16,52.96 125.48,53.27 125.75,53.27 125.86,53.16 126.54,53.16 126.6,53.1 127.11,53.1 129.02,55.01 130.45,55.01 131.34,55.9 RC905.2 132.7,56.89 132.7,56.89 v2(132.69,56.89) ; v2(133.5,23.96) 132.23,23.96 131.66,24.53 131.66,25.55 132.99,26.88 134.38,26.88 134.83,26.43 134.88,26.43 v2(134.9,26.42)
USB_OC1#: length 75.2
  TOP w0.102: v2(165.75,38.37) 166.2,37.93 168.53,37.93 169.57,36.89 v1(169.57,35) 170.41,34.16 170.81,34.16 v2(171.28,34.63) ; UU3.3 170.39,19.53 CU23.1 170.52,19.65 170.52,21.87 172.43,23.78 172.43,24.91 171.6,25.74 171.6,32.72 v2(171.41,32.91)
  BOTTOM w0.1: UC1.AG2 125.51,50.21
  BOTTOM w0.102: v2(171.28,34.63) 171.28,33.04 v2(171.41,32.91) ; v2(165.75,38.37) 165.27,38.86 162.48,38.86 159.02,42.31 149.48,42.31 147.26,44.53 139.66,44.53 139.59,44.6 139.06,44.6 138.76,44.29 138.3,44.29 137.29,45.3 137.29,47.31 136.06,48.53 136.06,49.78 135.63,50.21 134.54,50.21 133.93,49.6 RC906.2 133.34,49.55 133.13,49.34 133.13,49.28 132.9,49.04 128.93,49.04 128.4,49.57 127.25,49.57 126.3,50.51 125.83,50.51 125.82,50.5 125.81,50.5 125.51,50.21
USB_ZVSS: length 2.6
  TOP w0.102: v1(123.39,46.88) RC641.1
  TOP w0.254: v2(122.8,46.31) 122.33,46.78 RC641.1
  BOTTOM w0.2: v2(122.8,46.31) 122.26,46.85 UC1.AN7
USBSS_ZVDD: length 13.3
  TOP w0.254: v2(123.13,55.18) v1(129.62,55.18) 131.51,55.18 132.16,55.84 132.16,57.23 132.8,57.87 RC645.1
  BOTTOM w0.2: UC1.W5 123.06,55.11 v2(123.13,55.18)
USBSS_ZVSS: length 11.4
  TOP w0.254: v2(123.58,54.07) 123.75,54.07 124.21,53.62 124.58,53.62 124.6,53.63 124.63,53.63 124.96,53.97 v1(125.37,53.97) 133.83,53.97 RC644.1
  BOTTOM w0.2: UC1.W4 123.86,54.35 v2(123.58,54.07)
VCIN0_PH: length 80.7
  TOP w0.203: PR24.1 171.28,36.15 171.47,35.96 v2(171.56,35.96) ; v2(121.3,39.27) 121,39.57 v1(121,40.02) 121,41.04 PH1.1 ; v2(162.46,24.39) 162.46,24.4 161.06,25.81 156.51,25.81 155.4,24.71 155.4,23.38 151.72,19.7 146.34,19.7 142.59,23.45 140.83,23.45 137.32,26.96 137.32,29.98 138.03,30.69 v2(138.03,30.98)
  IN1 w0.203: v2(162.46,24.39) 162.88,24.81 162.94,24.81 163.58,25.46 163.58,26.97 163.77,27.16 163.77,27.5 v2(164.71,28.44) ; v2(121.3,39.27) 121.3,38.42 123.38,36.34 133.84,36.34 134.75,35.43 135.67,35.43 137,34.09 137,32.01 v2(138.03,30.98)
  IN2 w0.203: v2(164.71,28.44) 165.03,28.76 165.03,30.33 167.13,32.43 167.13,33.65 167.87,34.4 168.7,34.4 170.26,35.96 v2(171.56,35.96)
  BOTTOM w0.203: UE1.109 172.42,36.82 v2(171.56,35.96)
VCOUT0: length 3.5
  BOTTOM w0.102: UE1.104 170.42,40.1 RE39.2 v1(171.98,40.7)
VCOUT0_PH#: length 152.5
  TOP w0.254: PR116.1 189.96,43.2 187.28,43.2 186.2,44.28 v2(186.14,44.28) ; v2(168.94,32.63) 168.57,33 168.57,33.95 168.04,34.48 168.04,37.29 167.71,37.62 165.44,37.62 165.18,37.88 165.18,38.56 165.69,39.07 169.61,39.07 v1(170.29,39.75) 171.6,41.06 v2(171.6,41.17) 172.08,41.17 172.09,41.15 178.76,41.15 179.62,42.02 180.2,42.02 180.49,42.31 181.3,42.31 182.53,43.53 182.53,44.52 181.77,45.27 181.59,45.27 v2(181.5,45.36) ; v2(82.82,11.77) 82.68,11.77 80.96,13.48 R2450.2
  IN1 w0.254: v2(168.94,32.63) 168.94,32.29 169.34,31.89 169.34,27.78 166.92,25.36 166.92,23.65 162.4,19.13 160.99,19.13 160.8,18.95 160.16,18.31 157.06,18.31 156.77,18.02 155.65,18.02 152.64,18.02 152.63,18.02 142.95,18.02 140.37,15.45 129.04,15.45 126.5,12.91 126.5,12.91 126.31,12.72 125.73,12.14 125.49,11.9 125.13,11.9 124.94,11.72 124.68,11.45 122.64,11.45 122.46,11.26 121.56,10.37 114.07,10.37 113.75,10.37 113.18,9.8 111.59,9.8 111.02,10.37 110.96,10.37 110.96,10.37 110.7,10.37 107.13,10.37 106.87,10.37 106.86,10.37 103.77,10.37 102.78,11.36 100.72,11.36 99.37,11.36 99.18,11.54 99.18,11.55 98.9,11.83 91.52,11.83 90.57,12.78 88.53,12.78 84.29,12.78 84.13,12.62 83.68,12.17 83.27,11.77 v2(82.82,11.77)
  IN2 w0.254: v2(181.5,45.36) 181.5,45.55 181.44,45.61 181.44,46.63 182.81,48 186.8,48 187.22,47.58 187.22,46.06 186.36,45.2 186.36,44.6 186.14,44.38 v2(186.14,44.28)
  BOTTOM w0.254: v2(171.6,41.17) 171.6,41.36 171.34,41.61 RE39.1
VCOUT1_PH: length 2.3
  BOTTOM w0.102: RE42.1 170.02,40.59 UE1.103
VGA_AC__BATT: length 19.7
  TOP w0.102: v1(119.34,93.81) 119.6,94.07 v2(119.6,94.42)
  IN2 w0.102: 116.72,98.82 116.72,100.36 116.35,100.73
  IN2 w0.127: v2(119.6,94.42) 119.6,95.46 116.72,98.34 116.72,98.82 ; 116.35,100.73 115.7,101.38 115.7,103.72 114.67,104.76 114.67,105.32 v2(114.09,105.9)
  BOTTOM w0.102: UV3.4 120.88,92.25 RV150.1 119.82,92.37 119.6,92.59 RV260.2 v2(119.6,94.42) ; UV1.T9 113.69,106.3 v2(114.09,105.9)
VGA_SMB_CK3: length 25.7
  TOP w0.102: QV1.1 105.22,84.87 106.83,86.48 106.83,88.72 107.16,89.05 RV6.2 107.53,89.43 v2(107.78,89.68) ; v2(111.79,104.46) 111.39,104.46 v1(111.21,104.29)
  IN1 w0.127: v2(107.78,89.68) 106.9,90.56 106.9,93.55 108.05,94.7 108.05,95.99 109.25,97.19 109.61,97.19 110.12,97.69 110.12,98.16 v2(110.14,98.19)
  IN2 w0.127: v2(111.79,104.46) 111.13,104.46 110,103.33 110,98.33 v2(110.14,98.19)
  BOTTOM w0.102: v2(111.79,104.46) 112.03,104.7 UV1.U7
VGA_SMB_DA3: length 29.4
  TOP w0.102: v2(103.69,87.33) 103.69,86.89 v1(102.85,86.05) RV5.2 103.54,83.55 103.92,83.17 QV1.4
  IN1 w0.127: v2(109.56,98.19) 109.68,98.06 109.68,97.87 109.43,97.62 109.07,97.62 107.62,96.17 107.62,94.88 106.47,93.73 106.47,89.53 106.13,89.18 106.13,87.65 105.81,87.33 v2(103.69,87.33)
  IN2 w0.127: v2(111.79,105.15) 111.54,104.9 110.95,104.9 109.57,103.51 109.57,98.2 v2(109.56,98.19)
  BOTTOM w0.102: UV1.U8 111.95,105.15 v2(111.79,105.15)
VGATE: length 140.8
  TOP w0.102: v2(179.47,42.5) 179.73,42.5 v1(180.04,42.82)
  TOP w0.203: PU1001.20 164.67,63.35 164.42,63.6 164.42,64.34 163.98,64.79 161.87,64.79 PR1070.2
  TOP w0.254: RC51.1 v2(142.07,51.77) ; PR1070.2 161.7,65.74 v2(161.95,65.74)
  IN1 w0.254: v2(179.47,42.5) 178.75,42.5 177.3,43.96 175.72,43.96 175.15,43.39 174.39,43.39 173.76,42.75 173.76,42.25 173.37,41.86 172.68,41.86 172.42,42.12 172.42,43.2 172.87,43.64 172.87,45.1 173.25,45.48 173.25,49.99 172.61,50.63 171.91,50.63 171.53,51.01 171.53,52.22 172.04,52.72 172.04,53.42 171.28,54.19 171.28,55.78 170.59,56.47 167.79,56.47 166.01,58.25 166.01,58.63 164.42,60.22 164.42,62.12 164.61,62.31 164.61,65.11 163.98,65.74 v2(161.95,65.74) 161.82,65.61 160.93,65.61 160.29,66.25 160.29,67.39 161.31,68.41 161.31,71.65 158.45,74.5 138.77,74.5 138.13,73.87 138.13,72.46 137.38,71.71 137.38,69.94 137.79,69.53 137.79,67.72 139.9,65.61 143.4,65.61 145.69,63.33 145.69,59.58 142.07,55.96 v2(142.07,51.77)
  BOTTOM w0.203: UE1.74 168.1,28.02
  BOTTOM w0.254: v2(179.47,42.5) 179.61,42.5 180.98,41.13 180.98,38.49 180.66,38.17 180.66,37.5 180.26,37.09 179.67,37.09 178.99,36.42 177.57,36.42 176.98,35.83 176.98,34.59 175.84,33.45 175.84,31.63 175.35,31.13 174.89,31.13 174.06,31.96 172.99,31.96 172.78,31.74 172.21,31.74 171.47,31.01 171.47,28.59 171.72,28.34 171.72,27.45 171.15,26.88 169.95,26.88 168.8,28.02 168.1,28.02
VL: length 0.9
  TOP w0.102: v1(196.21,34.26) 195.57,34.89 v2(195.52,34.89)
VR_ON: length 36.2
  TOP w0.102: PR1085.1 172.18,61.68 172.74,61.12 v2(172.79,61.12) ; v2(178.21,41.64) 178.21,42.17 v1(178.14,42.25)
  IN1 w0.127: v2(172.79,61.12) 172.4,60.72 172.4,60.3 172.72,59.97 173.06,59.97 179.53,53.51 179.53,52.44 180.3,51.67 181.6,51.67 182.49,50.77 182.49,49.06 184.04,47.51 184.04,42.25 183.27,41.48 178.37,41.48 v2(178.21,41.64)
  BOTTOM w0.102: v2(178.21,41.64) 178.21,40.79 177.22,39.8 UE1.121
VSUM+_APU: length 39.9
  TOP w0.203: v2(167.42,64.37) 167.07,64.03 PU1001.14
  TOP w0.254: PR1079.1 PR1071.1 145,75.76 v2(145.31,75.46) 145.69,75.08 165.3,75.08 v1(166.95,73.42) 170.14,70.24 170.14,68.61 PC1066.1 170.96,67.79 PC1053.1 170.96,66.49 v2(170.58,66.11)
  BOTTOM w0.254: PR1084.1 145.63,75.77 v2(145.31,75.46) ; v2(170.58,66.11) 169.9,65.42 168.65,65.42 167.88,64.65 167.7,64.65 v2(167.42,64.37)
VSUM+_VGA: length 12.9
  TOP w0.102: v1(48.34,112.73) 48.41,112.8 PR1126.1
  TOP w0.203: PU1100.14 53.09,119.45 v2(52.98,119.34)
  TOP w0.254: PR1126.1 49.55,113.32 PR1131.1 PR1132.1 PC1125.1 49.36,115.66 PR1108.1 50.06,116.74 PC1126.1 50.5,116.48 v2(50.92,116.48)
  IN2 w0.254: v2(52.98,119.34) 52.98,118.22 51.24,116.48 v2(50.92,116.48)
VSUM-_APU: length 36.1
  TOP w0.254: PR1071.2 144.61,75.7 v2(144.61,75.46) 144.61,75.39 145.31,74.69 165.07,74.69 v1(168.48,71.28) 169.37,70.39 PC1065.1 169.37,69.06 169.49,68.94 PC1066.2 169.49,67.7 169.39,67.59 PR1072.1 169.39,66.57 PR1066.1 170.59,65.36 PC1053.2
  BOTTOM w0.254: v2(144.61,75.46) 144.61,75.21 PR1068.1 PH1003.2
VSUM-_VGA: length 34.3
  TOP w0.102: v2(54.73,113.39) 54.73,112.94 v1(54.95,112.73)
  TOP w0.203: PR1128.1 53.04,115.16 PR1137.1 ; PR1128.1 53.11,114.58 53.61,114.58 PC1129.1 53.99,114.13 v2(54.73,113.39) ; PR1128.1 51.9,114.91 51.76,114.77 PR1132.2 PC1125.2 51.64,116.28 PC1126.2 52.15,117.24 PR1136.1 PC1120.1 PC1119.1 50,117.8 49.48,117.28 49.47,117.28 PR1110.1
  BOTTOM w0.203: PH1102.2 72.8,108.12 68,108.12 66.95,109.17 64.83,109.17 62.93,111.08 61.74,111.08 61.07,111.75 56.38,111.75 v2(54.73,113.39)
VSUMN_NB: length 32.4
  TOP w0.254: v2(168.49,52.72) 167.85,52.09 164.36,52.09 161.25,55.2 156.23,55.2 154.77,56.66 151.91,56.66 v1(151.05,57.52) 149.82,58.76 148.99,58.76 v2(148.79,58.95) 148.15,58.31 PR1011.2
  BOTTOM w0.254: v2(168.49,52.72) 169.18,53.42 PC1014.1 168.54,54.25 PR1015.1 168.24,54.55 PR1013.1 169.24,55.44 PC1012.2 169.57,55.63 PC1011.2 ; v2(148.79,58.95) PR1014.1 PH1000.2
VSUMP_NB: length 34.1
  TOP w0.203: PU1001.40 168.27,57.55 168.4,57.42 v2(168.82,57.42)
  TOP w0.254: 150.07,57.8 149.69,58.18 PR1011.1 PR1009.1 ; 150.07,57.8 151.59,56.28 154.61,56.28 156.07,54.82 156.39,54.82 161.09,54.82 164.26,51.64 v1(165.56,51.64) 168.68,51.64 v2(168.8,51.76) ; 150.07,57.8 v2(149.99,57.8)
  IN2 w0.254: v2(168.82,57.42) 169.06,57.18 169.06,52.02 v2(168.8,51.76)
  BOTTOM w0.254: v2(149.99,57.8) 150.07,57.8 150.13,57.74 PR1012.1 ; v2(168.82,57.42) 168.82,57.26 PC1012.1 169.53,56.55 PC1011.1
VTTREF_1.2V: length 2.7
  BOTTOM w0.102: v1(90.55,103.57) 90.55,102.88 PC210.1
  BOTTOM w0.203: PC210.1 90.2,102.75 PU200.4
WAKEB: length 6.7
  BOTTOM w0.102: RV162.2 RV163.1 99.8,118.29 100.1,118 v1(100.22,118) 100.35,118 101.87,119.52 102.21,119.52 102.52,119.84 102.52,120.09 102.83,120.39 102.99,120.39 UV1.AJ27
WHITE_LED_PWR: length 23.8
  TOP w0.102: v1(156.99,111.55) 157.25,111.3 v2(158.03,111.3) 158.05,111.3 158.06,111.31 JPWR1.5
  IN2 w0.102: v2(158.03,111.3) 158.03,107.93 162.14,103.83 162.14,99.74 161.25,98.85 161.25,95.2 161.88,94.57 161.88,94.29 v2(162.45,93.72)
  BOTTOM w0.102: v2(162.45,93.72) 162.45,93.18 161.95,92.69 Q15.1
WL_OFF#: length 194.9
  TOP w0.102: v1(96.79,23.45) 96.86,23.39 v2(97.43,23.39) 97.86,23.82 RC46.2 ; v2(58.57,103.76) RW13.1 58.31,104.84 57.2,104.84 57.06,104.71 QW1.3
  IN1 w0.127: v2(108.68,45.37) 108.68,45.35 108.27,44.95 108.27,43.4 108.36,43.32 108.36,39.65 106.76,38.05 106.76,35.26 107.12,34.9 107.12,31.3 107.77,30.66 107.77,29.52 106.67,28.43 104.75,28.43 102.37,26.05 100.1,26.05 v2(97.43,23.39) 77.66,23.39 72.07,17.8 62.69,17.8 62.25,18.24 62.23,18.24 58.25,18.24 57.61,17.61 55.07,17.61 55.07,17.67 52.73,20.02 50.72,20.02 45.09,25.65 45.09,36.01 36.24,44.86 36.24,81.3 38.24,83.3 38.24,88.78 41.35,91.89 56.17,91.89 58.27,94 58.27,96.61 59.61,97.94 59.61,102.72 v2(58.57,103.76)
  BOTTOM w0.102: UC1.AU31 108.94,45.11 108.68,45.37 v2(108.68,45.37)
WL_OFF#_R: length 6.8
  TOP w0.102: RW12.2 54.65,106.12 QW1.1 56.98,106.7 v1(56.98,107.59) 56.98,107.83 56.81,107.99 v2(56.81,108.88) 56.81,109.33 C6.1
  BOTTOM w0.102: JWLAN1.48 56.8,108.87 v2(56.81,108.88)
WLAN_CLKREQ#: length 193
  IN1 w0.127: v2(32.39,84.87) 33.61,86.09 33.61,88.71 42.21,97.3 47.82,97.3 48.44,97.92 55.38,97.92 56.12,98.66 v2(56.12,99.07) ; v2(81.3,22.37) 81.3,22.24 81.59,21.95 82.32,21.95 82.63,22.27 97.67,22.27 100.69,25.29 102.69,25.29 105.07,27.67 106.99,27.67 108.54,29.22 108.54,30.96 107.88,31.62 107.88,34.37 v2(108.11,34.59)
  BOTTOM w0.102: UC1.AY31 108.93,42.68 108.93,42.43 108.85,42.35 108.85,41.74 108.76,41.66 108.76,38.72 107.7,37.66 107.7,37.64 107.02,36.95 107.02,35.69 v2(108.11,34.59) ; v2(32.39,84.87) 31.18,83.66 31.18,77.89 31.25,77.82 31.25,46.96 41.61,36.59 41.61,32.78 42.88,31.51 42.88,20.15 44.66,18.37 53.93,18.37 55.9,16.4 67.33,16.4 68.22,17.29 68.29,17.29 68.38,17.38 79.86,17.38 80.56,18.08 80.56,21.37 80.86,21.66 80.86,21.93 v2(81.3,22.37) ; JWLAN1.45 56.05,99.13 v2(56.12,99.07)
WLAN_WAKE#: length 253.2
  TOP w0.102: v1(164.1,32.15) 163.79,32.47 v2(163.79,32.78)
  IN1 w0.127: v2(56.75,99.03) 56.75,98.94 55.23,97.41 48.29,97.41 47.92,97.05 42.31,97.05 33.87,88.6 33.87,85.66 32.66,84.45 32.31,84.45 32.02,84.17 32.02,45.07 40.06,37.03 40.06,30.92 41.93,29.05 41.93,19.09 46.26,14.77 46.52,14.77 52.07,14.77 53.74,13.1 67.69,13.1 68.64,14.05 82.78,14.05 83.48,14.75 83.69,14.75 83.9,14.75 87.71,14.75 89.28,16.31 93.64,16.31 94.31,15.64 109.68,15.64 111.84,13.48 112.03,13.29 116.66,13.29 116.8,13.16 116.98,12.97 119.85,12.97 123.08,16.21 123.08,16.21 123.46,16.59 123.46,17.61 125.22,19.36 125.93,19.36 128.82,22.24 129.94,22.24 130.58,22.88 131.71,22.88 132.6,21.99 133.88,21.99 134.55,21.32 139.38,21.32 140.88,22.81 142.83,22.81 143.72,21.93 148.1,21.93 148.23,21.8 151.09,21.8 151.53,21.35 160.37,21.35 161.02,22 162.39,22 163.46,23.07 163.46,23.82 164.57,24.93 164.57,26.33 165.29,27.05 165.29,31 163.79,32.49 v2(163.79,32.78)
  BOTTOM w0.102: v2(56.75,99.03) 56.55,99.23 JWLAN1.47 ; UE1.90 165.11,34.42 164.84,34.16 164.21,34.16 RE70.2 163.79,34.55 v2(163.79,32.78)
WOL_EN: length 311.3
  IN1 w0.127: v2(169.44,34.24) 169.09,34.24 168.68,33.83 165.47,33.83 164.74,33.1 164.55,33.1 164.21,32.76 164.21,32.43 165.54,31.1 165.54,26.94 164.82,26.23 164.82,24.83 163.71,23.71 163.71,22.97 162.49,21.75 161.12,21.75 160.48,21.1 151.4,21.1 150.96,21.54 148.33,21.54 148.12,21.54 148,21.67 143.62,21.67 142.95,22.33 142.14,22.33 140.87,21.06 134.66,21.06 134.42,21.06 133.75,21.74 132.5,21.74 131.78,22.46 130.51,22.46 130.05,21.99 128.92,21.99 126.04,19.11 125.34,19.11 124.11,17.87 124.11,16.92 123.72,16.53 123.72,16.49 123.34,16.11 123.34,16.1 119.95,12.72 116.88,12.72 116.56,13.04 112.4,13.04 111.92,13.04 111.3,13.66 109.57,15.39 94.21,15.39 93.53,16.06 89.4,16.06 87.84,14.5 83.79,14.5 83.58,14.5 82.88,13.8 68.75,13.8 67.8,12.85 53.63,12.85 51.96,14.51 46.62,14.51 46.15,14.51 41.68,18.99 41.68,28.87 39.81,30.74 39.81,36.93 29.42,47.32 29.42,72.05 29.42,72.67 29.42,72.67 29.42,72.88 29.42,74.25 29.42,74.25 29.42,74.31 29.42,82.85 33.1,86.54 33.1,88.11 33.1,88.11 33.1,88.32 33.1,88.92 41.99,97.81 47.61,97.81 48.23,98.43 53.86,98.43 54.08,98.65 54.08,100 54.49,100.41 54.49,102.63 47.86,109.26 47.86,109.73 47.43,110.16 47.43,114.48 45.27,116.63 45.01,116.63 43.33,118.31 43.33,121.68 42.72,122.29 35.29,122.29 34.63,122.95 34.63,123.24 34.47,123.39 33.7,123.39 32.59,122.29 24.12,122.29 v2(23.77,121.94)
  BOTTOM w0.102: UL3.4 24.47,123.65 v1(24.4,123.72) 24.28,123.84 23.32,123.84 23.07,123.59 23.07,122.97 RL12.1 RL6.2 v2(23.77,121.94) ; v2(169.44,34.24) 169.35,34.34 169.35,35.86 168.02,37.19 UE1.98
XTALIN: length 6.5
  BOTTOM w0.102: UV1.AM28 102.02,121.58 100.21,121.58 RV20.1 98,122.92 CV17.1 96.93,123.82 YV1.1
XTALOUT: length 9.3
  BOTTOM w0.102: UV1.AK28 102.49,121.09 99.86,121.09 98.95,122.01 RV20.2 97.95,122.01 CV18.1 97.16,122.72 96,122.72 YV1.3
XTLI: length 6.1
  BOTTOM w0.102: YL1.1 39.39,118.64 37.74,118.64 37.43,118.94 CL10.1 36.98,118.57 36.73,118.57 36.24,118.07 UL1.28
XTLO: length 3.8
  BOTTOM w0.102: YL1.3 38.25,118.08 CL11.1 36.75,118.08 v1(36.44,117.77) 36.35,117.68 36.01,117.68 36.01,117.67 UL1.29
N16741477: length 1.7
  TOP w0.102: T212.1 107.72,104.84 v2(108.16,105.29)
  BOTTOM w0.102: UV1.AB8 108.49,105.29 v2(108.16,105.29)
N16741489: length 7.7
  BOTTOM w0.102: T208.1 106.13,98.25 105.81,98.57 105.81,99.21 106.51,99.9 106.51,104.35 106.86,104.7 UV1.AD7
N16741505: length 3.7
  BOTTOM w0.102: T214.1 107.78,100.98 108.03,101.24 108.03,102.32 108.42,102.7 UV1.AB4
N16741517: length 8.2
  BOTTOM w0.102: UV1.AD9 106.9,106.31 106.45,106.76 101.75,106.76 100.1,105.11 T206.1
N16741525: length 7
  BOTTOM w0.102: UV1.Y8 110.45,104.95 110.45,104.6 110.76,104.29 111.02,104.29 111.27,104.03 111.27,101.3 111.15,101.17 111.15,99.59 T216.1
N16741803: length 1.5
  TOP w0.508: v2(107.29,117.17) 107.28,117.17 RV29.2
  BOTTOM w0.254: UV1.AC22 107.39,116.81 107.39,117.07 v2(107.29,117.17)
N16741825: length 2.5
  TOP w0.102: v2(108.16,117.29) 107.56,116.68 v1(107.49,116.68)
  TOP w0.508: v2(108.16,117.29) 108.34,117.47 RV59.2
  BOTTOM w0.254: UV1.AB22 108.16,117.04 v2(108.16,117.29)
N16751828: length 10.9
  BOTTOM w0.102: UV1.AC8 107.33,105.87 105.87,105.87 105.68,105.68 105.68,105.36 105.37,105.05 105.11,105.05 104.92,104.86 104.92,99.84 104.19,99.1 T209.1
N16751830: length 7.3
  BOTTOM w0.102: UV1.AE8 106.1,105.27 105.75,104.92 105.75,99.84 105.24,99.33 T205.1
N16751834: length 9.4
  BOTTOM w0.102: UV1.AE9 105.86,106.3 105.49,105.94 102.06,105.94 100.41,104.29 100.41,102.95 100.03,102.57 T203.1
N16751836: length 1.5
  TOP w0.102: T201.1 114.79,106.53 v2(115.35,106.53)
  BOTTOM w0.102: UV1.N9 115.67,106.53 v2(115.35,106.53)
N16751838: length 4.5
  BOTTOM w0.102: T215.1 107.46,98.25 108.16,98.95 108.16,100.71 108.5,101.05 UV1.AB2
N16751842: length 1.5
  TOP w0.102: T211.1 108.54,105.56 v2(108.16,105.94)
  BOTTOM w0.102: UV1.AB9 108.52,106.3 v2(108.16,105.94)
N16751844: length 1.7
  TOP w0.102: T207.1 107.41,106.06 v2(108.15,106.8)
  BOTTOM w0.102: UV1.AC10 108,106.8 v2(108.15,106.8)
N16751848: length 1.3
  TOP w0.102: T202.1 116.07,106.09 v2(116.51,106.09)
  BOTTOM w0.102: UV1.L9 116.94,106.14 116.55,106.14 v2(116.51,106.09)
N16751852: length 8.5
  BOTTOM w0.102: UV1.AB7 109.14,104.7 109.68,104.16 109.68,99.08 109.05,98.44 109.05,97.87 T213.1
N16751854: length 6.6
  BOTTOM w0.102: UV1.AC7 107.7,104.68 108.1,104.29 108.1,103.02 107.72,102.63 107.53,102.63 107.27,102.38 107.27,101.75 107.21,101.68 107.21,99.71 T210.1
N16751856: length 1.5
  TOP w0.102: v2(110.5,107.09) 110.07,107.09 T204.1
  BOTTOM w0.102: UV1.Y11 110.5,107.09 v2(110.5,107.09)
N16751858: length 5.7
  BOTTOM w0.102: UV1.Y7 110.45,104.15 110.45,100.35 110.07,99.97 T217.1
N16808781: length 4
  BOTTOM w0.102: UV1.AJ11 102.84,107.44 101.54,107.44 101.37,107.27 v1(100.67,107.27) 99.93,107.27 RV157.1
N16808782: length 5
  BOTTOM w0.102: v1(99.33,110.32) 99.33,109.37 99.66,109.03 RV155.1 99.92,109.24 102.19,109.24 102.35,109.08 102.52,109.08 UV1.AK12
N16808783: length 3.4
  BOTTOM w0.102: UV1.AL11 102.11,108.29 101.94,108.29 101.62,108.6 v1(100.67,108.6) 100.3,108.6 RV156.1
N16813004: length 34.3
  TOP w0.102: RV72.1 76.78,92.54 v2(77.37,91.95) 77.96,92.54 RV71.2
  IN1 w0.127: v2(90.89,94.25) 91.33,94.25 93.75,96.67 93.75,100.09 95.84,102.19 95.84,105.24 v2(96.86,106.25)
  IN2 w0.127: v2(90.89,94.25) 90.44,94.7 81.06,94.7 78.3,91.95 v2(77.37,91.95)
  BOTTOM w0.102: v1(97.75,106) 97.49,106.25 v2(96.86,106.25) 96.46,106.65 RV84.2 RV87.2
N16855208: length 3.5
  TOP w0.102: R2450.1 R2448.2 79.23,12.46 79.22,12.47 v1(78.58,12.47) U2407.7
N17072999: length 2.3
  TOP w0.102: C5216.1 162.38,8.41 v2(162.45,8.34) 162.45,7.77 v1(162.39,7.7)
  BOTTOM w0.102: v2(162.45,8.34) 162.43,8.36 U2301.12
N17205184: length 3.7
  BOTTOM w0.102: RS19.2 199.71,28.71 199.16,28.15 199.16,27.51 v1(198.72,27.06) 198.33,26.68 US2.7
N17205187: length 5.6
  BOTTOM w0.102: US2.18 RS22.2 RS20.2 191.13,25.16 190.6,25.7 v1(189.08,25.7)
N17205206: length 4.4
  BOTTOM w0.102: v1(199.73,22.56) 199.71,22.57 RS25.2
  BOTTOM w0.254: US2.10 198.12,25.18
  BOTTOM w0.508: RS25.2 199.56,23.64 199.05,24.15 199.05,24.47 198.34,25.18 198.12,25.18
N17253873: length 46.1
  TOP w0.102: RC12.1 140.02,45.1 142.22,42.9 142.22,41.46 141.02,40.26 135.46,40.26 135.17,39.97 135.17,34.28 135,34.1 135,32.63 v2(134.51,32.15) ; v1(120.8,36.28) 120.57,36.05 v2(120.2,36.05)
  IN1 w0.127: v2(120.2,36.05) 120.54,36.05 122.14,34.45 131.7,34.45 134.01,32.15 v2(134.51,32.15)
  BOTTOM w0.102: UC1.AY14 118.51,43.01 118.83,42.69 118.83,42.43 118.69,42.29 118.69,41.41 118.48,41.2 118.48,40.17 118.64,40.01 118.64,39.01 118.61,38.98 118.61,37.89 120.2,36.3 v2(120.2,36.05)
N17382836: length 7.4
  BOTTOM w0.102: v1(136.67,14.5) PQ801.1
  BOTTOM w0.508: PC803.1 PR803.1 135.09,13.43 135.69,12.83 136.16,12.83 136.67,13.34 PQ801.1 ; PC803.1 PR802.2 ; PC803.1 133.44,13.43 133.11,13.1 131.89,13.1
N17382859:
  vias: v1(133.5,17.23)
N17415515: length 0.3
  TOP w0.102: 168.87,121.62 v1(169.18,121.62)
N17481633: length 2.2
  TOP w0.102: v1(208.55,35.45) 209.76,34.24 PQ704.5
  vias: v2(207.54,34.1) v2(207.54,33.41) v2(208.1,34.7) v2(208.12,34.1) v2(208.12,33.41) v2(211.35,34.69) v2(211.35,33.99) v2(211.35,33.36) v2(211.35,32.66)
N17511724: length 2.8
  TOP w0.102: v1(26.12,58.18) 26.12,56.89 RU15.2 CU10.1
N17735595: length 28.5
  TOP w0.254: v2(132.56,2.97) 132.31,3.22 125.27,3.22 124.04,1.99 118.9,1.99 116.29,4.6 v2(116.29,4.91)
  BOTTOM w0.102: R2635.1 120.21,7.31 v1(120.73,7.83)
  BOTTOM w0.254: v2(132.56,2.97) 131.88,2.97 131.59,2.68 Q2516.2 Q2516.3 ; R2635.1 119.33,7.51 116.54,7.51 116.29,7.25 v2(116.29,4.91)
N17847259: length 4.4
  BOTTOM w0.102: UV1.AL9 102,106.3 99.61,103.9 T4935.1
N17877344: length 2.5
  BOTTOM w0.102: T223.1 113.49,99.33 113.49,100.89 UV1.R1
N17877347: length 3.8
  BOTTOM w0.102: UV1.R3 114.1,102.11 113.02,101.03 113.02,100 T224.1
N18155621: length 0.8
  BOTTOM w0.102: T76.1 130.27,52.99 RC664.1
N18202616: length 3.3
  BOTTOM w0.105: UC1.AY15 118.19,42.68 118.19,42.43 118.27,42.35 118.27,41.59 118.07,41.38 118.07,39.93 T73.1
N18390627: length 2.3
  TOP w0.508: PQ710.2 v1(221.75,23.23) PQ711.1
N19609367: length 3.7
  TOP w0.102: v1(30.5,89.17) 30.8,89.48 RI18.1 29.31,90.44 QI3.2
N20135010: length 3.1
  TOP w0.203: PU1100.15 v1(53.49,119.6) 53.49,119.17 PC1130.2 PR1136.2
N20135022: length 1
  TOP w0.254: PC1130.1 PR1137.2
N20135024: length 14
  TOP w0.203: 58.97,122.93 57.67,122.93 57.57,123.04 PU1100.25
  TOP w0.508: 58.97,122.93 60.45,122.93 61.23,123.72 61.23,127.79 v1(60.09,128.93) PC1110.1 PR1114.1
N20135039: length 3.8
  TOP w0.203: PU1100.11 51.89,120.43 51.69,120.23 50.64,120.23 PR1121.2
N20135040: length 5.3
  TOP w0.203: PU1100.16 53.89,118.73 PC1124.1
  TOP w0.254: PC1124.1 PR1138.1 53.92,116.35 PC1122.1 53.92,116.35 PR1133.1
N20135043: length 4.5
  TOP w0.203: PU1100.17 54.29,120.11 55.18,119.21 56.1,119.21 PC1131.1
  TOP w0.254: PR1139.1 PC1131.1
N20135074: length 1.9
  TOP w0.102: PR1125.2 v1(70.31,112.16)
N20135096: length 39.9
  TOP w0.254: PR1126.2 51.57,112.8 PR1124.2 52.03,113.26 v2(52.58,113.26)
  IN2 w0.254: v2(52.58,113.26) 52.58,112.98 53.34,112.22 56.6,112.22 58.19,113.81 60.09,113.81 60.54,113.37 60.54,112.63 60.54,112.32 61.33,111.52 65.85,111.52 69.02,108.35 74.92,108.35 75.9,109.33 75.9,112.89 77.44,114.43 78.33,114.43 v2(78.46,114.31)
  BOTTOM w0.102: v2(52.58,113.26) v1(52.58,112.61)
  BOTTOM w0.254: v2(78.46,114.31) 78.51,114.25 PL1103.2
N20135098: length 37
  TOP w0.102: v1(53.17,112.16) 53.16,112.17 v2(53.16,113.2)
  TOP w0.254: v2(53.16,113.2) 53.15,113.21 53.15,113.63 PR1128.2
  IN2 w0.254: v2(53.16,113.2) 53.16,112.94 53.49,112.61 56.32,112.61 57.9,114.19 60.25,114.19 60.92,113.52 60.92,112.48 61.49,111.91 66,111.91 69.18,108.73 74.76,108.73 75.52,109.49 75.52,113.05 77.28,114.81 78.3,114.81 v2(78.46,114.97)
  BOTTOM w0.254: v2(78.46,114.97) 78.51,115.02 PL1103.3
N20135126: length 31.9
  TOP w0.203: v2(45.49,119.21) v1(45.98,118.71) PR1120.2 47.32,118.71 PR1121.1
  BOTTOM w0.203: v2(45.49,119.21) 45.49,117.05 47.9,114.64 54.31,114.64 56.73,112.22 61.17,112.22 61.93,111.46 63.2,111.46 65.04,109.62 67.08,109.62 67.97,108.73 PH1101.2
N20135134: length 9.3
  TOP w0.203: PC1123.1 57.54,118.71 56.97,119.27 56.6,119.27 56.33,119.54 55.39,119.54 v1(55.31,119.63) 55.24,119.63 54.69,120.18 PU1100.18
  TOP w0.254: PC1123.1 57.6,117.82 v1(57.57,117.79) 56.71,116.93 PR1134.1 56.71,116.04 PR1135.1 56.17,115.91 PR1129.2 55.7,115.47 PR1133.2
N20135137: length 0.9
  TOP w0.254: PR1129.1 55.69,116.35 PC1122.2
N20135139: length 2.1
  TOP w0.102: v1(58.69,115.02) 58.69,115.02 PC1128.1
  TOP w0.254: PC1128.1 PR1135.2
N20135141: length 8.8
  TOP w0.102: v1(61.49,119.53) 60.15,119.53 59.38,118.75 PR1130.1
  TOP w0.203: PC1123.2 58.01,119.21 57.5,119.21 57.06,119.65 56.73,119.65 56.5,119.87 55.77,119.87 55.64,120.01 55.36,120.01 55.09,120.28 PU1100.19
  TOP w0.254: PR1130.1 PC1123.2 58.5,118.69 PC1127.2
N20135144: length 2.5
  TOP w0.102: PC1127.1 59.46,116.91 v1(59.9,116.48)
  TOP w0.254: PC1127.1 58.45,116.86 PR1134.2
N20135171: length 26.2
  TOP w0.203: v2(51.64,113.88) PR1131.2
  BOTTOM w0.203: v2(51.64,113.88) 53.44,113.88 55.95,111.37 60.88,111.37 61.55,110.7 62.77,110.7 64.68,108.79 v1(66,108.79) 66.79,108.79 67.79,107.79 73.39,107.79 PH1102.1
N20135184: length 55.7
  TOP w0.102: v1(47.2,114.32) 47.77,114.89 PR1108.2
  TOP w0.254: PR1104.2 v2(47.33,117.82) 47.15,117.82 46.72,117.38 46.72,116.43 47.3,115.85 PR1108.2
  IN2 w0.254: v2(79.08,129.81) 79.2,129.94 79.2,131.88 78.28,132.8 73.84,132.8 72.06,131.02 60.03,131.02 57.47,128.47 52.88,128.47 52.19,129.16 47.72,129.16 46.18,127.62 46.18,120.67 47.01,119.84 47.01,118.13 v2(47.33,117.82)
  BOTTOM w0.254: PL1102.2 v2(79.08,129.81)
N20135197: length 1.9
  TOP w0.102: v1(70.63,129.88) 70.57,129.81 PR1107.2
N20135219: length 54.1
  TOP w0.102: v2(79.78,129.81) 79.78,129.18 v1(79.84,129.11)
  TOP w0.254: v2(47.2,117.18) 47.45,116.93 PR1110.2
  IN2 w0.254: v2(79.78,129.81) 79.59,130 79.59,132.03 78.44,133.18 73.68,133.18 71.9,131.4 59.84,131.4 58.1,129.66 47.68,129.66 45.8,127.78 45.8,120.48 46.63,119.65 46.63,117.75 v2(47.2,117.18)
  BOTTOM w0.254: v2(79.78,129.81) PL1102.3
N20135248: length 2.8
  TOP w0.102: 51.96,126.45 51.96,126.66 51.53,127.09 v1(51.26,127.09)
  TOP w0.203: PU1100.40 51.89,126.38 51.96,126.45 52.17,126.45 52.29,126.33 PU1100.39
N20135251: length 1.2
  TOP w0.102: PR1140.1 52.76,127.51 v1(52.17,128.11)
N20135257: length 5.1
  TOP w0.102: v1(51.24,129.04) 51.24,128.56 PR1101.2
  TOP w0.203: PR1101.2 50.63,127.14 50.63,125.18 50.77,125.04 PU1100.1
N20135258: length 4
  TOP w0.203: PU1100.2 50.71,124.64 50.3,125.04 50.3,126.26 v1(50.02,126.54) 50.02,126.85 PR1111.2
N20135263: length 1.9
  TOP w0.102: PR1105.2 54.29,127.29 PU1100.34
N20135264: length 3.8
  TOP w0.203: PU1100.32 55.09,127.38 PR1106.2 54.69,127.26 PU1100.33
N20141258: length 1.9
  TOP w0.203: PR1016.2 170.39,57.68 169.46,58.6 PU1001.1
N20141272: length 16.6
  TOP w0.102: v2(170.62,64.41) 170.99,64.79 172.17,64.79 v1(172.55,65.17)
  TOP w0.254: PR1087.2 PR1080.1 170.62,64.32 v2(170.62,64.41)
  BOTTOM w0.254: v2(170.62,64.41) 171.09,64.88 171.09,66.31 165.25,72.15 PH1002.2
N20141325: length 1.6
  TOP w0.254: PC1007.2 169.49,55.39 PR1007.1
N20141337: length 7.1
  TOP w0.203: PU1001.37 167.07,57.21 167.16,57.11 167.16,57.09 167.28,56.98 167.28,56.79
  TOP w0.254: 167.28,56.79 167.28,55.57 PC1008.1 PR1007.2 168.17,55.19 PR1004.1 PR1000.2 169.54,54.32 PR1003.2
N20141361: length 7.2
  TOP w0.203: PU1001.38 167.47,57.27 167.49,57.25 167.49,57.23 167.61,57.11 167.61,57.09 167.66,57.04 167.66,56.91
  TOP w0.254: PR1003.1 171.27,53.71 PR1006.2 171.27,55.33 PC1010.2 171,55.59 PC1007.1 169.32,56.47 v1(168.68,56.47) 167.91,56.47 167.66,56.72 167.66,56.91
N20141372: length 6.2
  TOP w0.102: v1(169.12,64.34) 169.69,64.92 PR1066.2
  TOP w0.203: PC1061.2 168.52,65.35 168.03,64.86 167.29,64.86 167.24,64.92 167.2,64.92 166.67,64.38 PU1001.15
  TOP w0.254: PR1066.2 PC1061.2
N20141380: length 2
  BOTTOM w0.102: v1(166.2,54.56) 166.22,54.54 PR1015.2
  BOTTOM w0.254: PR1015.2 167.32,54.55 PC1015.1
N20141402: length 2.1
  TOP w0.102: v1(168.47,68.32) PR1072.2
  TOP w0.254: PR1072.2 168.47,66.46 PC1061.1
N20141406: length 5.1
  TOP w0.102: v1(160.04,61.11) 160.55,60.6 PC1063.1
  TOP w0.203: 162.87,60.18 163.29,60.6 PU1001.25
  TOP w0.254: PC1063.1 PR1026.1 162.58,59.9 162.87,60.18
N20141448: length 3.4
  TOP w0.203: v2(168.2,56.96) 167.99,57.17 167.99,57.18 167.94,57.23 167.94,57.25 167.87,57.32 PU1001.39
  BOTTOM w0.102: v1(167.6,57.42) 168.05,56.96 v2(168.2,56.96)
  BOTTOM w0.254: v2(168.2,56.96) 168.24,56.92 PR1013.2 168.24,56.35 PC1015.2
N20141457: length 8.3
  BOTTOM w0.102: PR1012.2 150.54,59.03 v1(150.57,59.03)
  BOTTOM w0.254: PR1012.2 149.25,57.42 148.8,56.98 148.8,53.61 149.05,53.36 PL1002.2
N20141459: length 8
  BOTTOM w0.102: v1(149.27,59.14) 149.27,58.82 148.75,58.3 148.75,58.12 148.29,57.67 PR1014.2
  BOTTOM w0.254: PL1002.3 148.1,53.36 148.36,53.61 148.36,57.47 PR1014.2
N20141467: length 7.1
  BOTTOM w0.254: PL1004.3 144.01,70.12 144.42,70.53 144.42,72.63 145.05,73.26 145.05,74.14 PR1068.2
N20141469: length 7.4
  BOTTOM w0.102: v1(147.3,74.69) 146.98,74.38 PR1084.2
  BOTTOM w0.254: PL1004.2 145.05,70.12 144.8,70.38 144.8,72.47 145.44,73.11 145.44,73.68 PR1084.2
N20141477: length 1
  TOP w0.102: 151.28,48.47 v1(150.26,48.47)
N20141501: length 3.7
  TOP w0.203: PU1001.11 168.27,63.12 168.48,63.33 168.98,63.33 169.21,63.56 v1(170.2,63.56) 170.45,63.56 171.2,62.81 PR1080.2
N20141511: length 5.7
  TOP w0.203: PR1047.1 166.27,64.98 v1(166.27,64.28) PU1001.16
  TOP w0.254: PR1075.1 166.64,66.36 PC1060.1 PR1047.1 166.64,65.35 PC1059.1
N20141517: length 12
  TOP w0.102: v1(161.79,71.16) 161.79,71.04 162.4,70.43 v2(162.91,70.43)
  TOP w0.203: PU1001.17 165.87,63.78 v2(165.76,63.9)
  TOP w0.254: PR1069.1 163.6,69.41 PC1058.1 v2(162.91,70.43)
  BOTTOM w0.254: v2(165.76,63.9) 165.76,65.25 164.56,66.45 164.56,68.78 v2(162.91,70.43)
N20141713: length 5
  TOP w0.203: PU1001.36 166.67,57.14 166.83,56.98 v1(166.83,56.47) 166.83,56.04 PC1008.2
  TOP w0.254: PC1008.2 166.14,55.34 PR1005.1 PC1006.2
N20141719: length 2.2
  TOP w0.102: PR1074.2 146.98,65.99 v1(146.22,65.23)
N20141862: length 1.9
  TOP w0.102: v1(167.15,52.53) PC1006.1
  TOP w0.254: PC1006.1 PR1004.2
N20141864: length 2.3
  TOP w0.102: v1(169.63,51.26) 169.23,51.66 PC1004.2
  TOP w0.254: PC1004.2 169.23,52.86 169.18,52.91 PR1000.1
N20141906: length 11.5
  TOP w0.102: PR1077.1 163,67.87 162.19,67.87 v1(160.68,69.39)
  TOP w0.203: PU1001.18 165.47,63.48 165.25,63.71 165.25,64.27 165.68,64.7 PR1047.2
  TOP w0.254: PR1065.1 PC1068.1 165.18,65.7 165.28,65.7 PR1047.2 ; PR1065.1 165.53,68.29 PR1073.2 ; PR1065.1 163.6,67.38 PR1077.1
N20141912: length 3.5
  TOP w0.102: PR1073.1 166.09,67.84 166.09,68.9 165.76,69.23 v1(165.5,69.23)
  TOP w0.254: PR1073.1 165.63,66.36 PC1060.2
N20141916: length 3.2
  TOP w0.102: v1(162.39,69.66) 162.94,69.66 163.13,69.47 163.13,68.76 PC1037.1
  TOP w0.254: PC1037.1 164.56,68.34 PR1065.2
N20141920: length 4.7
  TOP w0.203: PU1001.19 165.07,63.42 164.87,63.62 v1(164.87,64.22) 164.87,65.09 PC1068.2
  TOP w0.254: PR1078.1 PC1057.2 PC1068.2
N20141926: length 2.8
  TOP w0.102: v1(161.41,67.51) 162.47,67.51 162.63,67.34 PR1077.2
  TOP w0.254: PC1057.1 163.6,66.36 PR1077.2
N20142021: length 3
  TOP w0.102: v2(146.71,57.55) v1(146.71,58.25)
  TOP w0.254: v2(146.71,57.55) 147.09,57.17 PR1009.2
  BOTTOM w0.254: v2(146.71,57.55) 146.72,57.54 PH1000.1
N20142108: length 3.6
  TOP w0.254: v2(142.7,75.53) 142.7,75.9 v1(143.05,76.25) 143.97,77.17 PR1079.2
  BOTTOM w0.254: PH1003.1 142.7,75.09 v2(142.7,75.53)
N20142189: length 19.2
  TOP w0.102: v2(172.11,56.72) 172.23,56.72 v1(172.68,57.17)
  TOP w0.254: PR1086.2 170.5,56.76 PR1016.1 172.11,56.99 v2(172.11,56.72)
  BOTTOM w0.254: v2(172.11,56.72) 171.88,56.49 171.88,55.16 171.53,54.82 171.53,53.68 171.98,53.23 171.98,52.59 171.22,51.82 170.27,51.82 169.86,52.24 165.34,52.24 163.84,53.74 PH1001.2
N20277811: length 2.3
  TOP w0.254: PR307.2 159.58,27.83 160.47,27.83 PR310.1 PR309.2
N20277821: length 3.1
  TOP w0.254: PR302.2 156.55,29.55 v1(156.96,29.96) 157.31,30.31 158.25,30.31 158.47,30.52 PU300.1
N20277901: length 1.8
  BOTTOM w0.102: PR305.2 v1(154.26,32.59)
N20355294: length 7.4
  BOTTOM w0.102: UC1.BA25 112.46,40.64 112.42,40.59 112.42,38.24 112.92,37.73 v1(112.92,37.36) 112.92,36.85 113.05,36.72 113.05,35.59 RC449.2
N21021316: length 1.3
  TOP w0.102: v1(159.61,38.3) 159.79,38.12 PC305.1
N21022260: length 1.2
  TOP w0.102: v1(164.99,53.55) 165.12,53.68 PC1009.1
N21022300: length 1
  TOP w0.102: PC1038.1 159.8,63.47 v1(159.79,63.45)
N21024525: length 2.6
  TOP w0.102: PR1103.2 59.65,126.7 v1(59.9,126.95)
  TOP w0.508: PR1103.2 59.72,125.49 PC1108.1
N21024549: length 2.7
  TOP w0.102: PC1118.1 v1(60.98,121.68)
  TOP w0.508: PC1118.1 59.65,121.44 PR1123.2
N21204075: length 4.7
  BOTTOM w0.102: PR1401.2 159.79,86.94 160.75,86.94 v1(161.72,87.9)
  BOTTOM w0.254: PU1400.9 159.22,87.5 PR1401.2
N21204078: length 4.7
  BOTTOM w0.102: 153.41,84.65 v1(153.41,85.62)
  BOTTOM w0.254: PC1405.1 PR1405.2 153.41,84.65 154.44,85.68 155.02,85.68 155.23,85.88 PU1400.15
N21204129: length 0.9
  BOTTOM w0.254: PR1410.2 155.16,84.64 PR1409.1
N21218602: length 5.9
  TOP w0.102: PQ1.2 163.6,89.92 PR2.1 165.09,89.33 PR14.2 PR13.2 166.89,89.35 PR12.2 167.44,89.32 v1(168.04,88.73)
N21230662: length 3
  TOP w0.102: v1(219.03,51.64) 218.84,51.45 PR790.2
  TOP w0.254: PR790.2 218.03,50.57 PQ721.2 217.94,50.54 PC790.1
N21230690: length 4.5
  TOP w0.102: PQ720.1 214.52,51.14 v1(214.14,51.52)
  TOP w0.254: PR791.2 217.67,51.99 217.67,51.99 217.14,51.45 PR790.1 216.8,51.14 PQ720.1
N21465372: length 2.2
  TOP w0.102: RU16.2 25.93,37.05 CU15.1 25.98,38.17 v1(25.99,38.18)
N21499708: length 2.6
  TOP w0.102: RD23.2 60.73,58.44 v2(60.72,58.43) v1(60.21,58.43)
  BOTTOM w0.102: JDIMM1.116 60.77,58.38 v2(60.72,58.43)
N21505920: length 2.6
  TOP w0.102: RD25.2 71.38,50.88 v2(71.15,51.11) 71.15,51.11 v1(70.78,51.48)
  BOTTOM w0.102: JDIMM1.143 70.53,51.62 71.04,51.11 v2(71.15,51.11)
N22072509: length 7
  BOTTOM w0.102: 118.54,37.48 T50.1
  BOTTOM w0.105: 118.54,37.48 117.75,38.27 117.75,39.59 117.44,39.9 117.44,40.52 117.26,40.7 117.26,41.6 117.62,41.96 117.62,42.32 117.73,42.43 117.73,42.69 117.41,43 UC1.AY16
N22072512: length 7.7
  BOTTOM w0.102: T49.1 119.29,36.21 118.99,36.52
  BOTTOM w0.105: 118.99,36.52 117.52,37.98 117.52,39.51 117.23,39.8 117.23,40.43 117.05,40.61 117.05,41.68 117.41,42.04 UC1.BA16
N22072515: length 3.2
  BOTTOM w0.102: UC1.BA13 118.92,42.07 118.92,41.35 118.68,41.11 118.68,40.26 118.85,40.09 118.85,40.01 119.15,39.71 T48.1
N22479416: length 3
  TOP w0.102: RD27.2 45.93,58.95 46.06,58.82 v2(46.06,58.63) v1(46.06,57.93)
  BOTTOM w0.102: JDIMM2.116 45.96,58.87 46.06,58.77 v2(46.06,58.63)
N22479746: length 3.2
  TOP w0.102: v2(51.65,52.28) 51.66,52.29 RD28.2 v1(52.41,53.24)
  BOTTOM w0.102: JDIMM2.143 51.8,52.12 v2(51.65,52.28)
N22479749: length 3.9
  TOP w0.102: v2(43.45,43.9) 43.64,43.71 RD29.1 v1(44.52,42.77)
  BOTTOM w0.102: JDIMM2.166 43.62,44.38 43.45,44.21 v2(43.45,43.9)
N22643329: length 1.4
  BOTTOM w0.102: T94.1 35.86,118.47 UL1.27
N22643331: length 5.1
  BOTTOM w0.102: UL1.25 35.77,119.27 35.96,119.46 35.96,120.14 36.04,120.22 36.04,120.74 36.49,121.19 37.27,121.19 37.43,121.35 37.43,121.64 38.05,122.26 T95.1
N22643935: length 4.2
  BOTTOM w0.102: UL1.26 35.75,118.87 36.27,119.39 36.27,120.5 v1(36.48,120.72) 36.71,120.95 37.64,120.95 RL1.2
N22657839:
  vias: v1(26.72,31.62)
N22661096:
  vias: v1(25.45,22.61)
N22661869: length 5.5
  TOP w0.102: v1(32.82,22.26) 32.32,22.76 32.32,23.86 33.04,24.58 CA21.2
  TOP w0.203: CA21.2 32.09,25.8 UA1.39
N22663765:
  vias: v1(26.79,22.7)
N22664360: length 5.8
  TOP w0.102: v1(33.24,20.66) 32.66,20.66 31.71,21.61 CA24.2
  TOP w0.203: 31.52,24.79 31.31,25 UA1.37
  TOP w0.254: CA24.2 31.71,24.4 31.52,24.59 31.52,24.79
N22664751: length 3.7
  TOP w0.102: CA24.1 30.31,22.14 v1(31.33,21.13)
  TOP w0.203: UA1.35 29.76,22.92 CA24.1
N22664968: length 4.6
  TOP w0.102: CA25.2 29.48,20.78 v1(28.72,20.78)
  TOP w0.203: CA25.2 29.36,21.92 UA1.34
N22666744: length 2.7
  TOP w0.203: CA41.1 22.83,28.72 v1(23.64,28.72) 23.96,28.72 24.48,28.2 UA1.16
N22673637: length 18.6
  TOP w0.102: v1(37.61,9.54) 38.12,10.05 RA6.1
  TOP w0.508: RA6.1 38.15,10.97 QA1.3 40.99,12.26 40.99,12.4 41.36,12.77 41.36,15 36.55,19.82 RA5.1
N22675171: length 0.9
  TOP w0.102: RA44.2 CA31.1
N22737223: length 3.1
  BOTTOM w0.102: v1(24.47,119.46) 24.47,119.46 UL3.3 24.47,120.92 24.21,121.18 23.34,121.18 RL7.2
N23370623: length 1.5
  TOP w0.102: RV100.1 79,94.41 UV4.6
N23370625: length 1.6
  TOP w0.102: RV101.1 79.23,93.76 UV4.7
N23435447: length 4.1
  BOTTOM w0.102: RC31.1 30.7,8.2 v1(30.12,8.78)
  BOTTOM w0.508: RC31.1 31.16,7.84 DC3803.3
N23465138: length 4.7
  BOTTOM w0.102: UV3.5 122.18,91.99 RV164.1 CV186.1 ; CV186.1 123.56,92 123.37,91.81 RV165.1 ; CV186.1 124.59,92.42 v1(124.61,92.41)
N23674571: length 7.9
  TOP w0.254: PR211.1 PR212.1 85.94,99.85 v1(87.27,99.85) 88.3,99.85 89.59,101.14 v2(89.65,101.14)
  BOTTOM w0.254: PC213.1 90.3,100.85 PC214.2 ; v2(89.65,101.14) 89.94,100.85 PC214.2 ; PR207.2 91.18,100.85 PC214.2
N23700319: length 7.3
  TOP w0.254: PL2.1 162.24,122.74 v2(162.58,123.08)
  BOTTOM w0.102: PD4.2 v1(159.06,123.72)
  BOTTOM w0.254: v2(162.58,123.08) 162.58,123.08 PQ6.1 160.24,121.79 PR6.2 159.78,122.25 PD4.2
N23821471: length 2.4
  BOTTOM w0.102: C5219.1 153.58,22.31 155.67,22.31 U2302.12
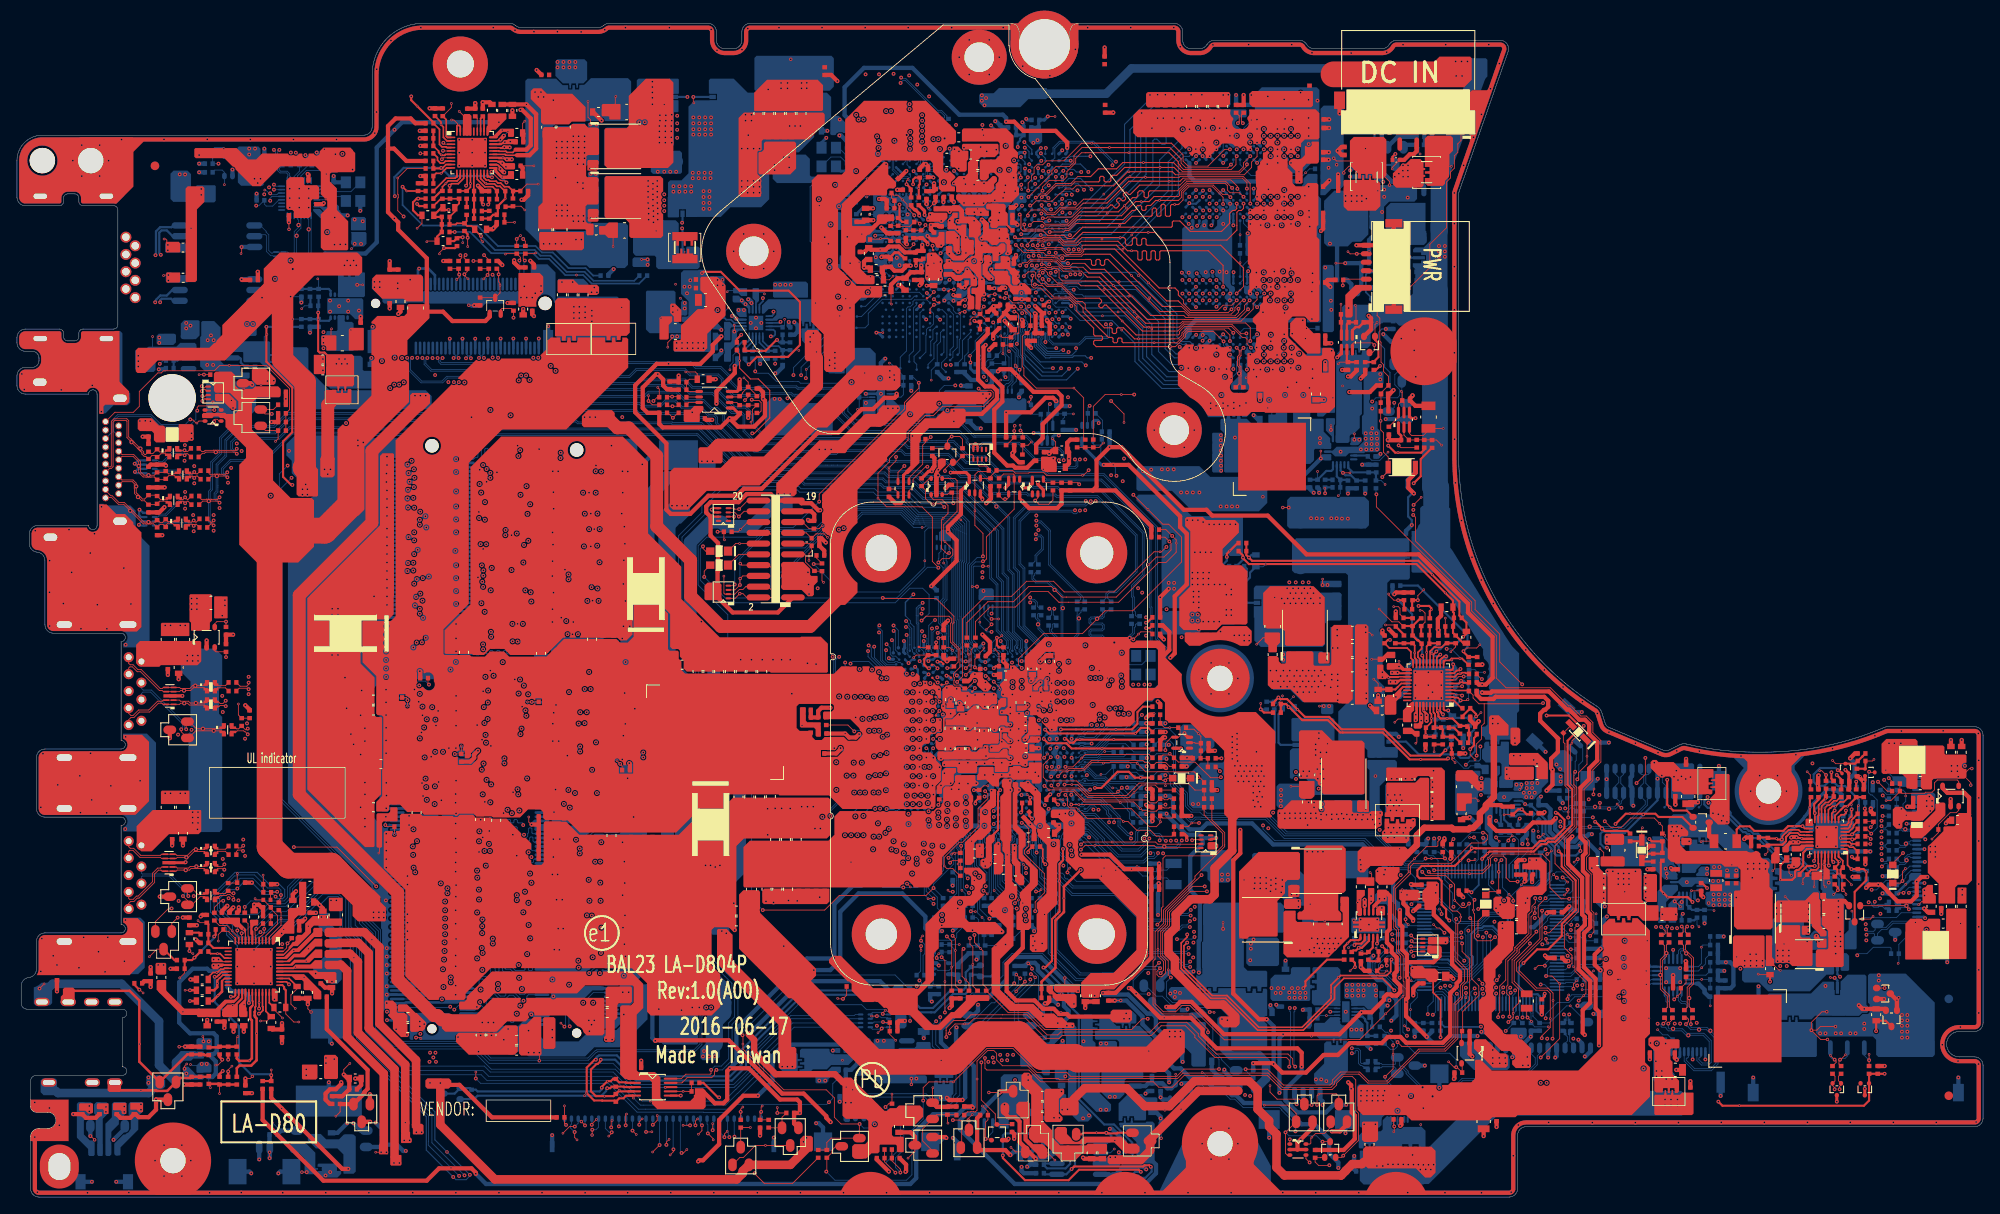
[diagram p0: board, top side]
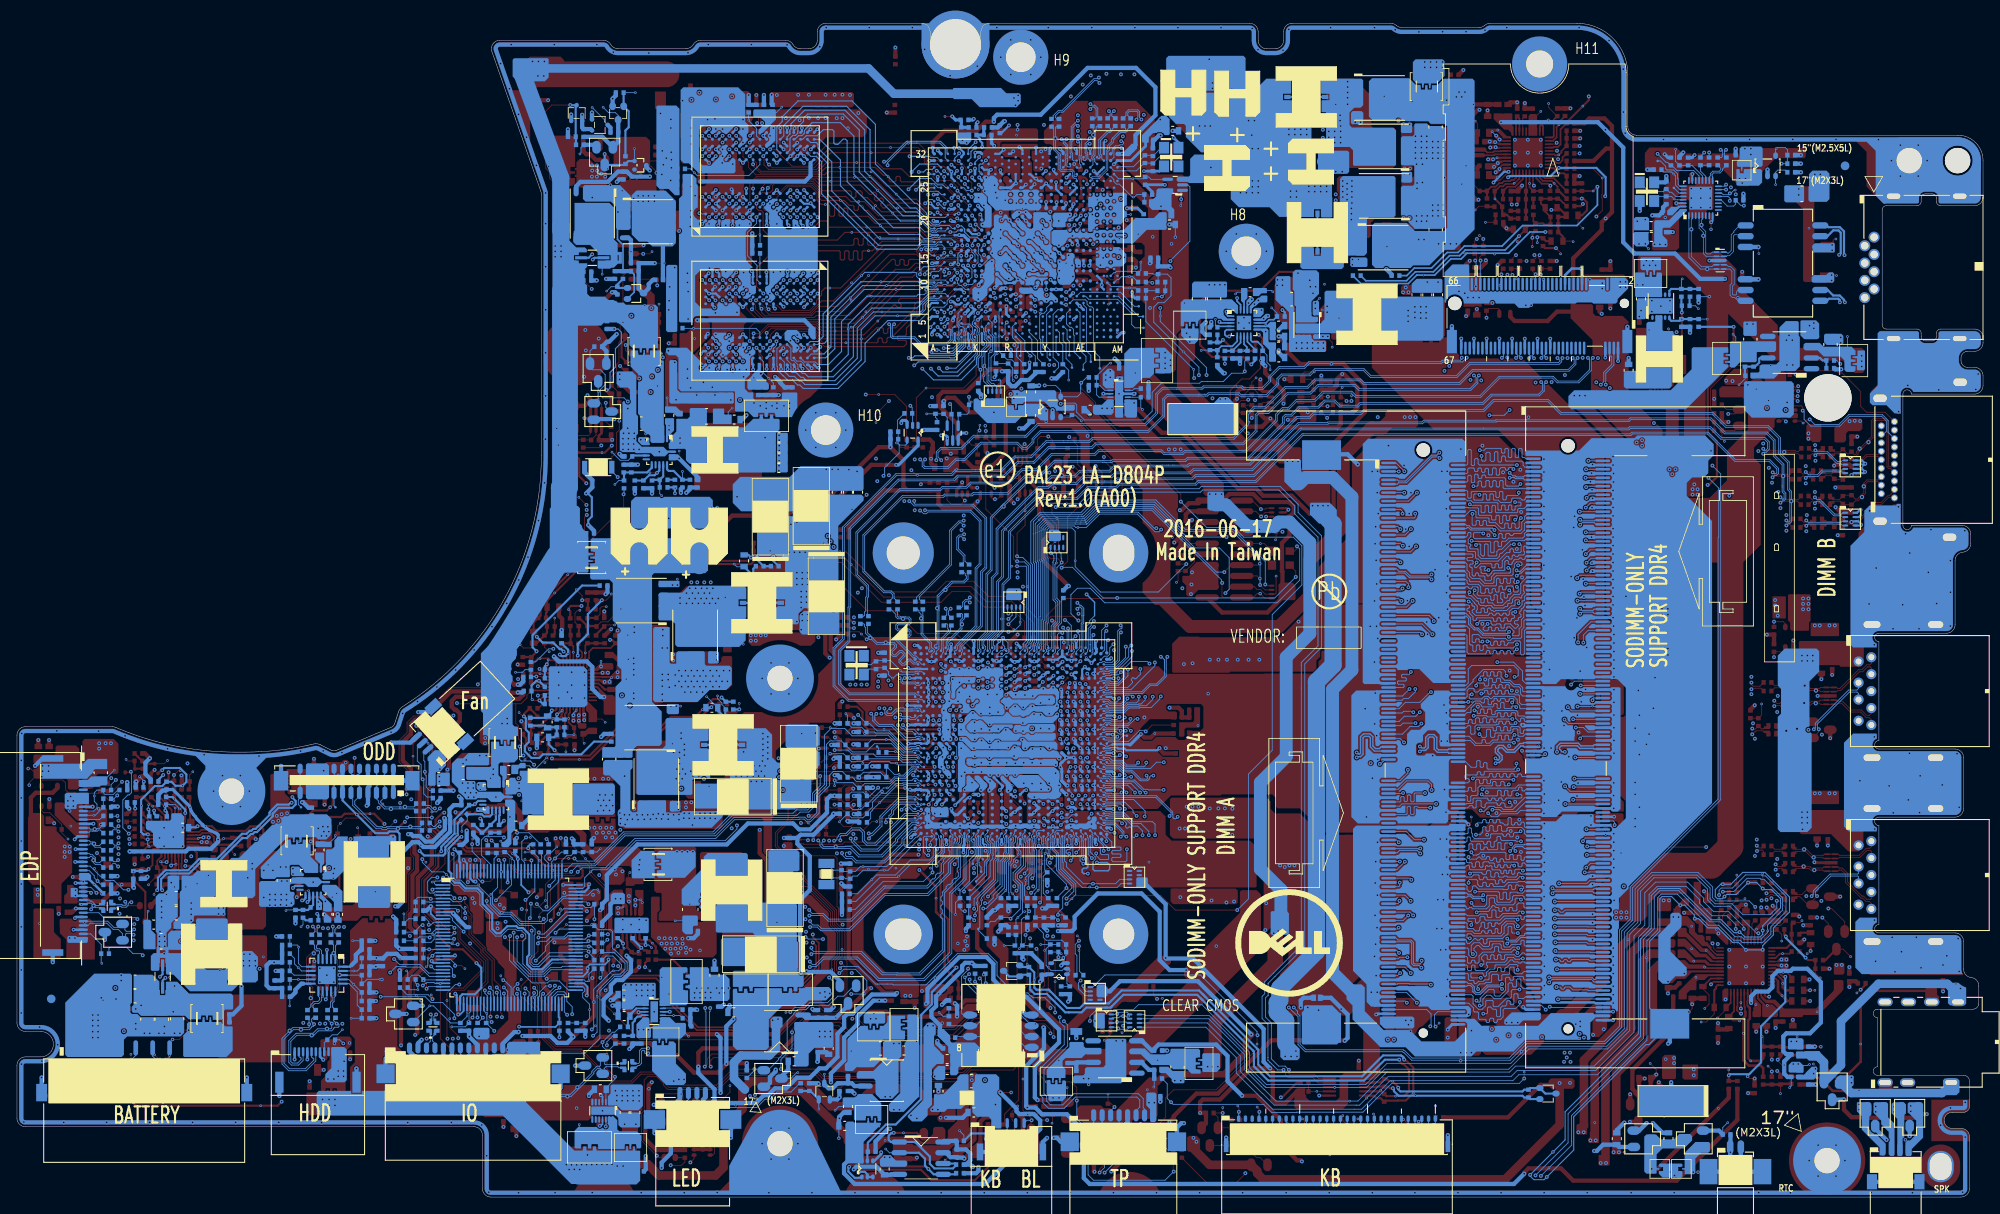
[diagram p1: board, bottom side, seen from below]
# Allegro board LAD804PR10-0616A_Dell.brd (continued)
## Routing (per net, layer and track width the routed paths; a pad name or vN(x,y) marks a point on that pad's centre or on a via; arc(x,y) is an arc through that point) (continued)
N23821473: length 2.5
  BOTTOM w0.102: C349.2 153.7,21.42 v1(154.45,21.42) 155.67,21.42 U2302.10
N23827049: length 3.6
  TOP w0.102: v1(87.9,10.75) 87.78,10.62 v2(87.78,10.05) 87.65,9.92 R37.1 R36.2
  BOTTOM w0.102: JKB1.1 87.8,10.03 v2(87.78,10.05)
N24106209: length 4.8
  TOP w0.102: Q12.3 108,12.87 v1(108.03,12.91)
  TOP w0.508: Q12.3 108.5,10.64 C22.1 109.8,10.69 R35.2
N24106231: length 5
  TOP w0.102: v1(105.1,4.59) 105.91,5.4 Q85.1
  TOP w0.508: Q85.1 105.91,7.13 105.4,7.64 R38.1
N24135897:
  vias: v1(129.5,6.69)
N24135899: length 1.9
  TOP w0.102: Q2514.3 121.46,5.33 v1(122.42,4.36)
N24142380: length 13.2
  TOP w0.102: v2(184.04,49.29) 184.2,49.45 184.2,50.08 185.19,51.07 v1(185.19,52.02) 185.19,53.86 DF1.1
  BOTTOM w0.102: 184.11,49.29 v2(184.04,49.29) ; 184.11,49.29 183.92,49.1 183.92,47.58 183.54,47.2 182.98,47.2 RF3.1 ; 184.11,49.29 184.22,49.41 184.22,51 184.68,51.45 184.68,52.98 JFAN1.3
N24410627: length 1.1
  TOP w0.102: RC29.2 106.43,64.86 T77.1
N24443071: length 4.4
  BOTTOM w0.102: 118.18,38.93 T51.1
  BOTTOM w0.105: 118.18,38.93 118.41,39.16 118.41,39.48 118.44,39.51 118.44,39.9 118.27,40.07 118.27,41.28 118.48,41.5 118.48,42.53 UC1.BA14
N24718506: length 4.1
  TOP w0.102: RA14.2 23.88,32.03 24.77,32.03 v1(25.39,31.42) 26.16,30.65 UA1.11
N24718549: length 3.8
  TOP w0.102: UA1.12 25.76,30.54 24.94,31.36 24.58,31.36 CA42.2 23.74,30.97 v1(23.74,30.21)
N24924773: length 29.4
  TOP w0.102: v2(184.41,40.84) 184.41,41.36 v1(184.26,41.51)
  TOP w0.254: PR122.1 191.8,39.59 PD102.2 192.44,40.52 PC128.1 193.99,40.52 PR120.2 PR114.2 192.82,41.98 v2(192.55,42.25)
  IN1 w0.254: v2(192.55,42.25) 191.35,42.25 189.06,44.53 188.23,44.53 187.28,45.48 185.76,45.48 185.12,44.85 185.12,44.71 185.12,41.55 v2(184.41,40.84)
  BOTTOM w0.254: v2(184.41,40.84) 183.88,40.3 181.62,40.3 181.37,40.56 181.37,40.97 181.37,41.29 179.91,42.74 179.91,44.09 PR121.2
N25806005: length 2.8
  BOTTOM w0.102: U74.3 107.7,92.04 R439.2 107.03,92.27 v1(106.36,91.6)
N25892877: length 2
  TOP w0.102: v1(29.04,37.99) 29.06,37.97 CA8.1 RA56.2
N25893892: length 2.7
  TOP w0.102: v2(111.36,41.44) 111.36,40.7 RC666.1 110.4,40.61 v1(110.26,40.47)
  BOTTOM w0.102: UC1.BA27 v2(111.36,41.44)
N25893987: length 29.1
  TOP w0.102: RC665.2 111.22,37.91 110.38,38.75 109.68,38.75 v1(109.37,39.07) 109.37,40.09 111.15,41.86 111.53,41.86 113.37,43.71 113.37,45.87 114.51,47.01 114.51,47.58 v2(114.19,47.9)
  IN2 w0.102: 125.5,49.79 123.79,48.09 121.88,48.09 121.37,47.58 121.37,47.07 120.35,46.06 115.78,46.06 115.15,46.69 115.15,46.94 v2(114.19,47.9)
  IN2 w0.127: 125.5,49.79 v2(126.2,49.79)
  BOTTOM w0.102: v2(126.2,49.79) 126.19,49.79 126.19,49.76 126.09,49.66 UC1.AH1
N25997876: length 11
  BOTTOM w0.203: 161.07,114.34 161.07,113.01 160.42,112.36 PR737.1 ; PQ709.3 159.1,106.77 159.1,108.86 PC744.2
  BOTTOM w0.508: PR763.1 PR737.1 159.49,109.26 PC744.2
  vias: v1(160.51,118.74) v2(161.02,116.24) v2(161.27,118.88) v2(161.26,118.03) v2(164.04,117.94)
N25997900: length 30.4
  TOP w0.102: v2(156.67,110.2) v1(155.56,110.2)
  IN1 w0.508: v2(156.67,110.2) 156.23,110.64 156.23,116.3 155.96,116.56 155.96,118.83 157.25,120.11 v2(157.25,120.41)
  BOTTOM w0.508: v2(157.25,120.41) 159.37,120.41 159.95,121 PR762.1 161.01,121 162.21,119.79 165.44,119.79 165.95,119.28 PQ718.4 ; v2(156.67,110.2) PR778.2 PC744.1 158.57,107.19 PQ709.1 157.39,107.23 157.39,107.72 156.88,108.23 PC742.1
N26351881: length 3.1
  TOP w0.102: v2(64.76,8.51) 64.57,8.7 RE60.2 v1(64.57,10.76)
  BOTTOM w0.102: v2(64.76,8.51) 64.6,8.68 JKB1.30
N26702682: length 5.6
  TOP w0.102: U1.3 229.03,45.64 228.75,45.36 228.02,45.36 226.63,43.96 RX9.2 226.63,42.99 v1(225.88,42.25)
N27121430: length 9.6
  TOP w0.508: RC458.2 v1(97.69,54.69) 98.15,54.23 98.93,54.23 v2(99.33,54.63)
  BOTTOM w0.11: 102.79,53.38 103.2,53.2 103.47,53.2 UC1.AA40
  BOTTOM w0.2: 102.79,53.38 102.68,53.38
  BOTTOM w0.3: 100.69,53.38 100.73,53.42 102.63,53.42 102.68,53.38
  BOTTOM w0.38: v2(99.33,54.63) 100.58,53.38 100.69,53.38
N27286345: length 4
  TOP w0.102: v1(198.65,41.93) 198.71,41.99 PR743.2
  TOP w0.508: PR743.2 199.6,42.57 PD704.1
N27352133: length 4.7
  TOP w0.102: v1(95.61,77.84) 95.19,78.26 94.25,78.26 RH23.2 93.1,78.38 JHDT1.13
N27352135: length 3.9
  TOP w0.102: v1(94.98,79.22) 94.64,78.87 RH24.2 93.43,78.87 92.65,79.65 JHDT1.15
N27352149: length 4.2
  TOP w0.102: JHDT1.11 93.48,77.11 RH22.2 93.73,76.23 93.42,75.91 v1(93.42,75.12)
N27367990: length 2.3
  BOTTOM w0.102: v1(123.13,21.79) 122.68,21.33 RC617.2 C636.1
N27535100: length 2.9
  BOTTOM w0.102: UE1.111 173.22,39.65 v1(173.54,39.97) 173.54,40.06 174.19,40.71 RE14.2
N27535635: length 2.8
  BOTTOM w0.102: RE16.2 185.68,32.85 CE24.1 186.25,33.41 v1(186.27,33.42)
N27539530: length 11.2
  BOTTOM w0.102: RC26.2 CC16.1 108.06,25.2 UC4.1 107.72,26.64 107.72,26.82 107.84,26.94 UC4.2 108.41,26.94 108.61,26.75 109.94,26.75 110.51,27.32 110.51,29.3 RC25.2 ; RC25.2 111.13,29.81 v1(111.15,29.8) ; RC25.2 109.99,29.8 RC28.1
N27700813: length 22.8
  TOP w0.508: v2(27.74,95.84) 27.54,96.03 QI1.1
  IN1 w0.508: v2(23.11,93.77) 22.64,93.3 22.64,91.72 21.7,90.78 17.71,90.78 14.09,87.17
  BOTTOM w0.254: RPI1.6 14.27,85.92 v2(13.91,85.57) 14.05,85.43 RPI1.5 ; RPI2.7 14.64,80.24 14.41,80.47 14.41,81.07 v2(14.45,81.11) 14.5,81.11 14.87,80.74 RPI2.8 ; RPI1.8 14.28,86.92 v2(13.89,86.53) 13.99,86.42 RPI1.7 ; RPI2.5 14.46,79.24 v2(14.38,79.32) 14.38,79.41 14.71,79.74 RPI2.6
  vias: v1(26.75,95.33)
N27705118: length 4.6
  BOTTOM w0.102: Q83.1 140.62,13.99 139.93,14.69 v1(139.8,14.69)
  BOTTOM w0.508: Q83.1 141.73,14.24 140.93,15.04 R1671.2
N27707965: length 3.1
  BOTTOM w0.102: v1(99.14,92.93) 99.35,93.13 C344.2 99.35,94.38 100.29,94.38 100.29,94.38 U15.10
N27708054: length 1.6
  BOTTOM w0.102: U15.12 100.31,95.18 100.1,95.4 C343.2
N27920326: length 4
  TOP w0.203: PU1001.13 167.47,63.68 167.83,64.03 167.85,64.03 167.85,64.01 v2(167.88,64.01)
  BOTTOM w0.254: v2(167.88,64.01) 167.85,64.01 167.67,63.84 167.22,63.84 v1(166.9,64.15) 166.9,64.58 PR1081.2
N28483985: length 5.3
  TOP w0.102: v1(168.23,90.7) 168.23,90.7 PR5.2 166.49,90.48 165.88,89.87 164.49,89.87 164.25,90.11 PQ1.3
N28484391: length 3.7
  TOP w0.102: PR28.2 156.16,105.36 v1(156.17,105.36)
  TOP w0.254: PR28.2 PC16.1 156.22,103.17 PQ2.3
N28484395: length 4.5
  TOP w0.102: v1(157.86,105.22) 157.94,105.14 PR29.1
  TOP w0.254: PR29.1 PC16.2 156.87,103.01 PQ2.2
N28484412: length 3.8
  TOP w0.102: v1(155.85,98.32) 156.05,98.52 PR33.2
  TOP w0.254: PQ2.5 156.87,98.65 PR33.2 PR31.1
N28484439: length 6.2
  TOP w0.102: PQ3.2 160.18,102.97 v1(160.42,103.21)
  TOP w0.254: PR32.1 PC14.2 160.04,98.57 160.59,99.12 160.59,100.74 160.18,101.15 PQ3.2
N28484451: length 6.4
  TOP w0.102: PR7.1 162.95,93.55 PQ1.6 162.95,92.03 PR10.2 ; PR7.1 163.6,93.79 PQ1.5 ; PR7.1 163.39,94.96 v1(163.28,95.08)
N28714500: length 1.7
  TOP w0.203: PU703.3 216.15,41.89 216.37,41.67 PR769.2
N28714504: length 2.7
  TOP w0.203: PU703.4 216.4,42.29 v2(216.48,42.21) 216.75,42.21 PR770.2
  BOTTOM w0.102: v1(216.33,41.39) 216.48,41.55 v2(216.48,42.21)
N28714524: length 1.4
  TOP w0.102: PC750.1 211.98,37.86 v1(211.98,36.59)
N28714534: length 2.4
  TOP w0.254: PR754.1 v2(216.94,49.02)
  BOTTOM w0.102: v2(216.94,49.02) 216.94,49.1 v1(217.44,49.61)
  BOTTOM w0.254: PC752.2 216.99,48.97 v2(216.94,49.02)
N28714554: length 3.8
  TOP w0.203: v2(216.4,45.75) 216.4,44.97 216.29,44.85 216.29,44.84 216.05,44.6 216.05,44.18 215.75,43.89 PU703.8
  BOTTOM w0.102: v1(216.36,46.31) 216.4,46.27 v2(216.4,45.75)
  BOTTOM w0.254: v2(216.4,45.75) 216.3,45.65 PR727.1
N28714559: length 2.2
  TOP w0.203: PU703.6 216.06,43.09 216.62,43.65 216.62,43.82 216.71,43.91 216.71,43.94 PR774.2
N28714562: length 3.7
  TOP w0.102: PR775.2 217.11,46.1 v1(217.19,46.18)
  TOP w0.203: PR775.2 216.85,44.97 216.85,44.94 216.62,44.71 216.62,44.71 216.38,44.46 216.38,44.04 216.18,43.85 216.18,43.75 216.17,43.74 216.17,43.67 216,43.49 PU703.7
N28714564: length 1.5
  TOP w0.102: v1(207.09,38.5) 207.35,38.75 PR771.2
N28714572: length 11.8
  TOP w0.203: PU703.18 210.87,43.49 210.61,43.74 v2(210.61,43.76)
  TOP w0.254: PR743.1 202.84,43.38 203.21,43.74 204.38,43.74 204.91,43.21 208.36,43.21 208.91,43.76 v1(209.63,43.76) 210.61,43.76 v2(210.61,43.76)
  BOTTOM w0.254: PC757.2 211.41,43.58 211.35,43.64 210.73,43.64 v2(210.61,43.76)
N28714582: length 4.2
  TOP w0.203: PU703.12 213.66,45.7 213.86,45.9 213.92,45.9 214.13,46.11 v1(214.51,46.11) 215.03,46.63 215.49,46.63 PR755.2
N28714583: length 4.5
  TOP w0.203: PU703.14 212.86,46.1 213.31,46.56 213.65,46.56 214.28,47.19 PC708.1
  TOP w0.254: PR776.1 214.27,47.27 PC708.1
N28714585: length 4
  TOP w0.203: 212.8,46.55 212.51,46.27 212.51,45.04 212.46,44.98 PU703.15
  TOP w0.254: 212.8,46.55 213.37,47.12 PC708.2 213.38,47.27 PR742.1
N28714598: length 3.2
  TOP w0.203: PC747.1 214.84,39.27 214.84,39.6 214.46,39.99 PU703.31
  TOP w0.254: PC747.1 214.71,38.61 214.71,38.13 PR740.2
N28714599: length 4.5
  TOP w0.102: v1(216.38,36.84) 216.38,36.91 215.48,37.81 PR772.2
  TOP w0.203: PU703.32 214.86,40.18 215.36,39.68 PC747.2
  TOP w0.254: PC747.2 215.09,38.61 215.09,38.13 PR772.2
N28714601: length 1.5
  TOP w0.102: v1(213.32,36.59) 213.13,36.78 213.13,37.61 PC750.2
N28714604: length 30.1
  TOP w0.102: v1(205.38,26.31) 205.44,26.24 PR773.1
  TOP w0.203: v2(211.96,39.66) 212.06,39.76 PU703.25
  TOP w0.254: v2(206.78,25.42) PR773.1
  IN2 w0.254: v2(211.96,39.66) 212.22,39.66 213.76,38.12 214.9,38.12 216.22,36.8 216.22,25.6 215.06,24.43 207.77,24.43 v2(206.78,25.42)
N28714606: length 8.1
  TOP w0.102: v2(209.01,39.01) 209.01,38.26 v1(209.32,37.95)
  IN2 w0.762: 210.52,31.58 209.82,32.28 209.82,38.18
  vias: v2(209.6,39.01) v2(211.28,31.78) v2(211.28,31.2)
N28714608: length 4.6
  TOP w0.102: v1(210.65,36.98) 210.65,37.53 PR745.1
  TOP w0.203: PR745.1 211.17,38.13 211.5,38.46 211.5,38.47 211.63,38.6 211.64,38.6 211.67,38.63 211.84,38.63 211.86,38.61 212.24,38.61 212.5,38.88 212.5,39.32 212.46,39.37 PU703.26
N28714612: length 8.9
  TOP w0.203: 210.9,40.85 211.14,41.09 PU703.24
  TOP w0.254: PR771.1 208.01,39.16 v1(208.01,37.43) 209.38,37.43 209.74,37.79 209.74,38.43 209.91,38.6 210.15,38.6 210.69,39.14 210.69,40.63 210.9,40.85
N28714614: length 2.8
  TOP w0.254: PR757.2 211.48,47.06 v1(211.48,45.99) 211.48,44.47
N28714617: length 0.8
  BOTTOM w0.102: 162.87,109.71 v1(162.87,108.9)
N28714625: length 2.3
  TOP w0.102: v1(211.16,50.18) 211.53,49.81 PR779.2
  TOP w0.254: PR779.2 211.53,48.18 PR757.1
N28714693:
  vias: v1(202.84,28.34) v2(203.79,27.88) v2(203.78,27.28) v2(204.43,28.66) v2(204.49,27.88) v2(204.48,27.28) v2(205.13,28.66) v2(205.19,27.88) v2(205.18,27.28) v2(205.89,27.88) v2(205.87,27.28)
N28714721: length 41.5
  TOP w0.102: v2(213.38,49.8) 212.87,50.31 v1(212.63,50.31)
  TOP w0.254: PR742.2 v2(213.38,49.8)
  IN1 w0.254: v2(213.38,49.8) 213.38,50.2 214.44,51.27 220.79,51.27 222.14,49.92 222.14,42.6 221.9,42.35 221.9,37.72 221.32,37.13 221.32,32.07 218.47,29.23 216.46,29.23 214.9,27.67 214.9,26.12 v2(215.03,25.99)
  BOTTOM w0.254: v2(215.03,25.99) 214.72,26.3 PR765.2
N28714724: length 39.7
  TOP w0.102: v2(214.4,25.86) 213.95,25.86 v1(213.89,25.93)
  TOP w0.254: v2(214.02,50.12) 214.02,49.37 PR776.2
  IN1 w0.254: v2(214.02,50.12) 214.02,50.3 214.6,50.89 220.63,50.89 221.76,49.76 221.76,42.75 221.52,42.51 221.52,37.88 220.94,37.29 220.94,32.23 218.31,29.61 216.3,29.61 214.52,27.83 214.52,25.99 v2(214.4,25.86)
  BOTTOM w0.254: PR765.3 214.72,25.54 v2(214.4,25.86)
N28714743: length 3.9
  BOTTOM w0.102: v1(162.34,106.9) 161.82,107.42 PR738.1
  BOTTOM w0.254: PR737.2 161.08,107.68 PR738.1 160.93,107.27 PQ709.2
N28714752: length 109.1
  TOP w0.102: v2(215.36,36.21) 215.73,35.84 v1(215.73,35.71)
  TOP w0.254: PR772.1 215.29,36.77 215.29,36.28 215.35,36.21 v2(215.36,36.21)
  IN2 w0.254: v2(163.98,110.62) 164.07,110.71 166,110.71 166.46,110.25 166.46,109.81 168.1,108.16 168.1,78.71 169.27,77.54 169.27,77.53 169.31,77.49 169.31,74.63 171.46,72.48 171.52,72.34 171.52,70.2 174.07,67.65 174.07,66.44 181.8,58.71 181.8,57.32 184.65,54.47 185.69,54.47 187.4,52.76 189.54,52.76 192.14,50.16 197.53,50.16 198.39,49.29 198.39,47.77 198.84,47.33 198.84,47.2 198.93,47.11 198.93,47 199.39,46.53 v2(199.51,46.53)
  BOTTOM w0.254: v2(163.98,110.62) 163.77,110.83 PR703.2 ; v2(215.36,36.21) 215.27,36.3 215.27,37.68 214.4,38.56 211.73,38.56 210.4,39.9 208.33,39.9 205.36,42.87 204.81,42.87 204.46,43.22 204.25,43.22 204.03,43.44 203.75,43.44 202.12,45.08 202.12,45.34 202.08,45.41 202.05,45.46 201.2,46.31 199.85,46.31 199.63,46.53 v2(199.51,46.53)
N28714753: length 110
  TOP w0.102: v1(214.27,35.71) v2(214.78,36.21)
  TOP w0.254: PR740.1 214.78,36.52 v2(214.78,36.21)
  IN2 w0.254: v2(164.05,111.24) 164.21,111.09 166.15,111.09 166.84,110.41 166.84,109.97 168.49,108.32 168.49,78.86 169.65,77.7 169.65,77.68 169.69,77.65 169.69,74.79 171.79,72.69 171.9,72.41 171.9,70.35 174.4,67.86 174.45,67.78 174.45,67.33 174.45,66.6 182.18,58.87 182.18,57.48 184.81,54.85 185.85,54.85 187.56,53.14 189.7,53.14 192.3,50.54 197.69,50.54 198.78,49.45 198.78,48.02 199.41,47.39 v2(199.41,47.2)
  BOTTOM w0.254: v2(164.05,111.24) 164.47,110.83 PR703.3 ; v2(199.41,47.2) 199.41,47.12 199.02,46.73 199.02,46.33 199.43,45.93 201.05,45.93 201.73,45.24 201.73,45.24 201.73,44.92 203.59,43.06 203.87,43.06 204.09,42.84 204.3,42.84 204.78,42.36 205.33,42.36 208.17,39.52 210.24,39.52 211.57,38.18 214.24,38.18 214.89,37.53 214.89,36.33 v2(214.78,36.21)
N28714782: length 1.6
  BOTTOM w0.102: v1(216.43,33.74) 216.49,33.67 PC767.1
N28714793: length 1.6
  TOP w0.102: PR773.2 206.97,27.64 207.86,26.75 v1(207.98,26.75)
N28895147: length 3.7
  BOTTOM w0.102: PQ801.2 137.32,10.38 v1(137.31,10.37)
  BOTTOM w0.254: PQ801.2 138.32,12.51 PC805.1 PR801.2
N29189918: length 3.8
  TOP w0.203: PR764.2 215.06,47.19 214.63,46.75 214.31,46.75 213.79,46.23 213.56,46.23 v1(213.24,45.91) 213.24,45.59 213.26,45.57 PU703.13
N32434049: length 4.1
  BOTTOM w0.102: UV15.J13 144.27,98.99 143.85,98.57 143.85,97.87 143.85,97.87 143.85,97.55 143.85,97.55 143.85,97.23 v1(143.22,96.6) 142.68,96.06 RV121.1
N32434050: length 2.7
  BOTTOM w0.102: RV117.1 144.27,111.34 v1(144.27,110.25) UV15.J1
N32434053: length 10
  BOTTOM w0.102: UV15.J10 144.27,102.04 144.74,102.51 v1(152.1,102.51) 153.38,102.51 RV119.1
N32437559: length 3.7
  BOTTOM w0.102: RV132.1 v1(145.59,127.08) 145.59,127.01 144.67,126.1 144.67,125.21 UV13.J13
N32437560: length 2.9
  BOTTOM w0.102: RV131.1 144.25,113.33 144.27,113.34 v1(144.27,113.56) UV13.J1
N32437563: length 10.3
  BOTTOM w0.102: RV133.1 152.46,121.33 v1(151.99,120.86) 151.67,120.54 145.56,120.54 144.27,121.83 UV13.J10
N32646580: length 3.1
  TOP w0.102: v1(218.46,16.85) v2(218.46,16.15) PR15.1
  BOTTOM w0.102: PBATT1.5 217.89,16.71 v2(218.46,16.15)
N33124472:
  vias: v1(75.97,103.71)
N33726059: length 2.9
  TOP w0.102: v1(191.73,43.58) 191.65,43.51 PD102.1
  TOP w0.254: PD102.1 191.5,41.98 PR116.2
N33745668: length 5.3
  BOTTOM w0.102: PR209.2 84.46,99.34 84.46,98.49 84.09,98.13 v1(84.09,97.62)
  BOTTOM w0.203: PU200.10 86.37,101.1 86.19,100.92 85.55,100.92 84.98,100.35 84.98,99.86 PR209.2
N36085760: length 3.8
  BOTTOM w0.102: v1(164.05,128.57) 162.61,127.12 162.61,126.9 PD6.1
  BOTTOM w0.508: PD6.1 161.89,126.18 PR11.2
N37640332: length 1.4
  TOP w0.381: v2(115.28,107.23) 114.75,107.23 RV2.2
  BOTTOM w0.381: v2(115.28,107.23) 115.35,107.23 115.38,107.26 115.74,107.26 UV1.N10
N37640410: length 1.4
  TOP w0.508: RV3.1 109.28,117.97 v2(109.28,117.39)
  BOTTOM w0.254: UV1.AA22 109.28,116.92 v2(109.28,117.39)
N37828209: length 1.5
  TOP w0.508: v2(110.52,117.41) 110.26,117.67 RV1.1
  BOTTOM w0.254: UV1.Y22 110.52,116.72 110.52,117.41 v2(110.52,117.41)
N38038746: length 3.3
  TOP w0.102: v1(128.16,88.98) 127.64,88.46 RV36.2 RV37.2 CV96.1
N38038992: length 18.5
  TOP w0.102: CV98.2 118.64,90.17 v2(118.37,90.45)
  IN1 w0.102: v2(118.44,105.07) 119.27,104.24 119.27,103.08 118.82,102.63
  IN1 w0.127: v2(118.37,90.45) 117.62,91.19 117.62,95.84 119.02,97.24 119.02,98.44 118.51,98.95 118.51,102.32 118.82,102.63
  BOTTOM w0.102: v2(118.37,90.45) 118.37,91.03 v1(118.32,91.08) ; UV1.K8 118.1,105.41 v2(118.44,105.07)
N38038994: length 5.9
  TOP w0.102: v2(117.63,104.48) 117.81,104.48 118.13,104.16 118.13,103.3 118.17,103.26 118.17,101.97 118.08,101.88 118.05,101.88 118.02,101.85 117.65,101.85 CV99.2 116.21,101.44 v1(116.03,101.62)
  BOTTOM w0.102: v2(117.63,104.48) 117.32,104.48 UV1.L7
N38038995: length 2.3
  TOP w0.102: v1(119.65,89.11) 119.26,88.71 CV98.1 118.64,87.66 RV40.2
N38038996: length 2.1
  TOP w0.102: v1(116.29,99.52) 116.3,99.54 RV41.2 116.38,100.53 CV99.1
N38349725: length 11.5
  TOP w0.102: v2(118.45,119.45) 118.45,118.95 v1(118.51,118.89)
  IN1 w0.254: v2(114.89,126.45) 116.16,125.18 116.16,123.84 116.48,123.53 116.48,120.54 117.57,119.45 v2(118.45,119.45)
  BOTTOM w0.254: RV39.2 115.79,125.54 v2(114.89,126.45)
  BOTTOM w0.3: v2(118.45,119.45) UV1.K25
N39282118: length 0.7
  TOP w0.102: v2(40.13,107.64) v1(40.79,107.64)
N39282176:
  vias: v1(39.39,102.32)
N39282188: length 2.3
  BOTTOM w0.102: PR603.1 33.93,105.17 v1(33.58,104.82)
  BOTTOM w0.254: PR603.1 34.61,106.19 PR604.2
N39352229: length 3.4
  BOTTOM w0.102: v1(169.43,51.83) 170.66,50.6 171.18,50.6 171.47,50.89 PC102.1
N39352417:
  vias: v1(194.2,35.83)
N39352440: length 1.4
  BOTTOM w0.102: PC114.1 195.09,41.72 194.36,42.46 v1(194.36,42.66)
N39352447: length 1
  BOTTOM w0.254: PR108.1 PC113.2
N39352755: length 2.2
  BOTTOM w0.102: v1(198.39,31.9) 198.16,32.13 PC127.2
  BOTTOM w0.254: PC127.2 197.85,32.66 PR117.1
N43437408: length 11.7
  BOTTOM w0.102: RC450.2 114.07,32.77 v1(113.84,33) 113.3,33.53 113.3,37.04 113.66,37.39 113.66,37.39 113.9,37.63 113.9,38.06 112.92,39.04 112.92,41.77 113.01,41.86 UC1.BA24
N55201771: length 19.5
  TOP w0.102: v1(21.48,97.05) v2(22.05,97.05) RI19.2
  IN1 w0.127: v2(22.05,97.05) 21.61,97.49 17.22,97.49 16.98,97.25 16.62,97.25 14.43,95.06 14.43,93.32 13.71,92.6 11.77,92.6 11.26,92.09 11.26,89.31 JHDMI1.13
N279348080: length 3.5
  BOTTOM w0.508: PQ740.4 159.75,113.19 159.48,112.92 v1(159.48,111.56) PR778.1

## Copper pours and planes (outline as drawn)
0.95VSDGPU_OUT on BOTTOM (solid shape): 101.3,99.53 101.3,95.57 101.22,95.49 100.25,95.49 99.08,96.67 98.27,96.67 97.77,97.17 97.77,97.84 97.74,97.87 97.23,97.87 97.23,97.88 97.23,98.32 97.23,98.33 97.77,98.33 97.77,98.34 97.77,99.06 97.76,99.07 97.23,99.07 97.23,99.07 97.23,99.52 97.23,99.52 97.78,99.52 97.78,99.52 97.78,100.2 97.78,100.2 100.63,100.2
1.5VS_VIN on BOTTOM (solid shape): 100.67,17.35 100.67,17.1 100.48,16.91 99.4,16.91 98.06,15.58 96.03,15.58 95.52,15.07 93.87,15.07 93.37,14.56 92.35,14.56 92.29,14.62 92.29,15.07 92.86,15.07 92.86,15.64 92.35,15.64 92.35,15.89 92.86,15.89 92.86,16.46 92.35,16.46 92.35,17.32 92.54,17.51 95.75,17.51 95.86,17.4 95.86,17.37 95.93,17.05 96.23,16.91 96.35,16.91 96.41,16.85 98.19,16.85 98.89,17.54 100.48,17.54
2.5V_VIN on BOTTOM (solid shape): 21.17,100.6 21.17,100.09 20.98,99.9 19.51,99.9 18.79,99.18 16.82,99.18 16.36,98.71 16.36,97.72 16.35,97.67 16.36,97.6 16.12,97.36 15.23,97.36 15.1,97.49 15.1,97.5 15.03,97.57 15.04,97.57 15.04,98.04 15.59,98.04 15.59,98.55 15.04,98.55 15.04,98.84 15.59,98.84 15.59,99.35 15.04,99.35 15.04,99.82 15.03,99.82 15.03,99.87 15.51,100.35 18.82,100.35 19.26,100.79 20.98,100.79
3V_SN on TOP (solid shape): 171.6,47.58 171.6,46.5 171.53,46.44 171.03,46.44 170.9,46.31 170.9,45.61 170.84,45.55 169.95,45.55 169.82,45.67 169.82,47.58 169.88,47.64 171.53,47.64
3V_VIN on TOP (solid shape): 178.92,50.68 178.92,49.36 178.79,49.23 175.6,49.23 175.47,49.36 175.47,50.69 175.55,50.77 178.83,50.77
3V_VIN on BOTTOM (solid shape): 174.45,53.23 175.03,53.23 175.03,53.74 175.92,53.74 175.98,53.68 175.98,50.88 176.11,50.75 178.84,50.75 178.9,50.69 178.9,49.36 178.77,49.23 177.89,49.23 177.89,49.23 176.61,49.23 176.42,49.04 176.42,48.9 176.42,48.4 176.3,48.28 174.9,48.28 174.84,48.34 174.84,49.51 175.1,49.78 175.1,51.07 174.9,51.28 173.25,51.28 172.8,51.72 172.8,52.79 173.06,53.04 173.06,53.55 173.26,53.75 173.65,53.75 173.65,53.23 174.2,53.23 174.2,53.8 174.45,53.8
3VS_LS on BOTTOM (solid shape): 156.1,26.82 156.1,22.62 156.04,22.56 154.83,22.56 154.77,22.62 152.99,22.62 152.74,22.88 152.74,24.4 153.31,24.4 153.31,25.23 152.74,25.23 152.74,25.61 153.31,25.61 153.31,26.5 152.8,26.5 152.8,27.01 152.93,27.13 155.79,27.13
5V_SN on TOP (solid shape): 189.63,40.02 189.63,39.13 189.5,39.01 186.9,39.01 186.77,39.13 186.77,40.09 186.9,40.21 189.44,40.21
5V_VIN on BOTTOM (solid shape): 198.2,41.74 198.2,41.67 198.78,41.67 198.78,42.18 198.97,42.18 198.97,41.61 199.6,41.61 199.6,42.18 199.92,42.18 203.16,38.94 203.16,37.79 202.9,37.53 201.48,37.53 201.28,37.74 199.79,37.74 199.73,37.8 199.73,39.07 199.6,39.2 198.65,39.2 198.08,38.63 198.08,38.44 197.89,38.25 196.43,38.25 196.36,38.31 196.36,39.26 197.25,40.15 197.25,41.62 197.29,41.63 197.53,41.78 197.58,42.06 197.6,42.14 197.68,42.18 198.2,42.18
5V_VIN on TOP: 199.73,39.07 199.85,39.2 200.93,39.2 201.33,38.8 202.88,38.8 203.09,38.59 203.09,37.71 203.05,37.67 199.79,37.67 199.73,37.74
5VS on BOTTOM (solid shape): 162.21,8.87 162.22,8.8 162.25,8.74 162.26,8.73 162.26,8.63 162.2,8.09 162.75,8.13 162.82,8.18 162.9,8.15 163.21,8.05 163.47,8.24 163.49,8.27 165.69,8.27 166.14,7.83 166.14,5.86 166.01,5.73 165.37,5.73 165.37,6.24 164.55,6.24 164.55,5.73 164.17,5.73 164.17,6.24 163.34,6.24 163.34,5.67 160.23,5.67 160.23,6.24 159.66,6.24 159.66,5.67 159.47,5.67 159.47,6.24 158.83,6.24 158.83,5.73 158.39,5.73 158.26,5.86 158.26,7.26 158.77,7.77 160.87,7.77 161.09,7.99 161.09,9.07 161.5,9.48 162.21,9.48
+0.6V_DDR_VTT on TOP (solid shape): 94.89,101.81 94.89,98.89 94.64,98.63 93.17,98.63 92.92,98.89 92.92,102 93.24,102.32 94.38,102.32
+0.6V_DDR_VTT on TOP (solid shape): 83.01,88.24 83.01,88.18 83.24,87.96 83.24,86.75 83.05,86.56 80.52,86.56 80.38,86.71 80.38,88.31 80.55,88.48 82.78,88.48
+0.6V_DDR_VTT on TOP (solid shape): 61.84,21.22 61.84,17.51 61.87,17.49 61.87,16.85 61.71,16.69 59.46,16.69 59.22,16.94 59.22,20.1 59.52,20.4 60.1,20.4 60.98,21.28 61.78,21.28
+0.6V_DDR_VTT on TOP (solid shape): 47.01,21.74 47.14,21.74 48.28,20.59 48.28,20.29 48.27,20.28 48.19,20.1 48.15,19.91 48.15,19.89 47.8,19.54 47.77,19.56 47.54,19.61 47.33,19.51 46.5,19.51 46.38,19.64 46.38,21.29 45.87,21.8 45.8,21.86 44.98,21.86 44.91,21.93 44.91,22.62 45.04,22.75 45.99,22.75
+0.6V_DDR_VTT on BOTTOM (solid shape): 82.41,86.99 82.41,84.41 81.4,83.39 80.89,83.39 80.38,83.9 80.38,85.67 80.45,85.67 80.45,86.92 80.55,87.03 82.38,87.03
+0.6V_DDR_VTT on BOTTOM (solid shape): 93.27,103.04 93.27,102.51 93.29,102.49 93.76,102.49 93.8,102.54 93.8,102.61 93.81,102.63 93.81,103.05 94.06,103.05 94.07,103.04 94.07,102.69 94.07,102.69 94.07,102.53 94.1,102.5 94.57,102.5 94.59,102.48 94.59,102.05 94.59,102.05 94.59,101.66 93.59,100.67 92.98,100.67 92.59,101.06 92.59,101.35 92.52,101.42 92.52,102.45 92.58,102.51 92.96,102.51 93,102.54 93,102.61 93.01,102.61 93.01,103.06 93.02,103.07 93.24,103.07
+0.6V_DDR_VTT on BOTTOM (solid shape): outline of 490 points within 44.03,16.59 75.08,25.1
+0.6VSP on BOTTOM (solid shape): 94.64,105.56 94.64,102.76 94.25,102.76 94.25,103.27 93.68,103.27 93.68,102.76 93.47,102.76 93.47,103.23 93.43,103.27 92.86,103.27 92.86,102.76 92.62,102.76 92.62,103.31 92.29,103.64 91.08,103.64 91.04,103.64 90.82,103.64 90.81,103.67 90.55,103.85 90.28,103.67 90.27,103.64 89.86,103.64 89.62,103.4 88.35,103.4 88.28,103.47 88.28,103.59 88.34,103.65 89.11,103.65 89.56,104.09 89.56,104.31 89.56,104.32 89.59,104.48 89.56,104.63 89.56,104.64 89.56,104.67 89.43,104.79 89.4,104.79 89.39,104.8 89.24,104.83 89.09,104.8 89.08,104.79 88.67,104.79 88.12,104.25 87.94,104.25 87.87,104.31 87.87,105.2 88.6,105.94 94.25,105.94
+0.95VALW on TOP (solid shape): outline of 111 points within 76.98,81.11 104.22,98.13
+0.95VALW on TOP (solid shape): outline of 224 points within 118.28,28.9 123.02,49.1
+0.95VALW on BOTTOM (solid shape): 79.4,81.81 79.4,80.54 78.32,79.46 76.92,79.46 76.22,80.16 76.22,81.11 77.05,81.93 79.27,81.93
+0.95VALW on BOTTOM (solid shape): 82.89,17.86 82.89,16.53 82.51,16.15 80.86,16.15 80.6,16.4 80.6,17.48 81.3,18.18 82.57,18.18
+0.95VALW on BOTTOM (solid shape): 103.84,97.15 103.84,95.82 103.45,95.42 102.62,95.42 102.54,95.5 102.54,96.32 102.45,96.41 102.45,97.39 102.81,97.75 103.24,97.75
+0.95VALW on BOTTOM (solid shape): 119.91,49.61 119.91,48.6 119.93,48.57 119.93,48.55 120.31,48.17 120.31,47.92 120.23,47.83 120.2,47.84 120.15,47.84 120.09,47.83 119.13,47.83 119.08,47.84 119.01,47.84 118.45,48.41 118.45,48.64 119.06,49.25 119.06,49.27 119.53,49.74 119.78,49.74
+0.95VALW on BOTTOM (solid shape): 139.02,24.66 139.22,24.66 139.66,24.66 139.66,24.08 140.48,24.08 140.48,24.66 140.86,24.66 140.86,24.08 141.69,24.08 141.69,24.66 144.93,24.66 144.93,24.08 145.75,24.08 145.75,24.59 146.13,24.59 146.13,24.08 146.9,24.08 146.96,24.15 146.96,24.59 147.34,24.59 147.47,24.47 147.47,21.45 147.44,21.39 147.37,21.35 147.05,21.11 147.13,20.7 147.47,20.37 147.47,17.82 147,17.36 143.52,17.36 143.21,17.67 143.21,20.97 141.56,22.62 139.09,22.62 138.51,23.2 136.47,23.2 135.88,23.79 135.88,24.53 136.14,24.78 138.89,24.78
+0.95VALW on IN1 (solid shape): outline of 610 points within 80.6,13.92 137.5,31.07
+0.95VALWP on BOTTOM (solid shape): 149.47,34.34 149.47,31.36 149.31,31.2 145.88,31.2 145.87,31.19 145.13,31.19 144.71,30.77 144.71,27.14 145.15,26.71 147.33,26.71 147.47,26.57 147.47,24.85 147.41,24.79 146.79,24.79 146.79,24.78 146.77,24.78 146.77,24.28 146.32,24.28 146.32,24.85 145.5,24.85 145.5,24.28 145.12,24.28 145.12,24.78 145.09,24.78 145.09,24.79 144.32,24.79 144.32,24.78 142.3,24.78 142.3,24.79 141.52,24.79 141.52,24.78 141.5,24.78 141.5,24.28 141.05,24.28 141.05,24.78 141.02,24.78 141.02,24.79 140.32,24.79 140.32,24.78 140.29,24.78 140.29,24.28 139.85,24.28 139.85,24.78 139.82,24.78 139.82,24.79 139.27,24.79 139.1,24.96 139.1,26.16 139.15,26.21 139.18,26.19 139.43,26.12 139.67,26.23 139.81,26.36 139.81,27.01 139.77,27.05 139.77,30.05 139.91,30.19 139.91,34.5 140.16,34.75 149.05,34.75
+0.95VS on TOP (solid shape): 137.75,19.45 137.75,17.1 135.4,14.75 132.48,14.75 132.04,15.19 132.04,16.59 135.28,19.83 137.37,19.83
+0.95VS on TOP (solid shape): 87.65,36.02 87.65,34.03 87.65,34.01 87.61,33.86 87.65,33.71 87.65,33.7 87.65,33.55 94.25,26.94 94.25,26.12 91.59,23.45 91.02,23.45 85.17,29.29 85.17,35.71 85.68,36.21 87.46,36.21
+0.95VS on BOTTOM (solid shape): 140.23,20.53 140.23,19.7 140.13,19.45 140.23,19.2 140.23,15.51 140.1,15.39 138.7,15.39 138.51,15.58 138.51,16.91 137.82,17.61 135.78,17.61 135.59,17.8 135.59,20.47 135.78,20.66 140.1,20.66
+0.95VS_APU_GFX on TOP (solid shape): outline of 2118 points within 85.68,36.53 113.43,49.78
+0.95VS_APU_GFX on BOTTOM (solid shape): 113.84,49.65 113.84,49.64 114.21,49.45 114.51,49.74 114.76,49.74 114.85,49.66 114.87,49.62 114.89,49.6 114.89,49.29 113.88,48.28 113.1,48.28 112.72,48.34 112.51,48.01 112.51,47.99 112.35,47.83 111.43,47.83 111.36,47.84 111.29,47.83 110.33,47.83 110.27,47.84 110.22,47.84 110.19,47.83 109.94,48.09 109.94,48.28 110.13,48.47 110.15,48.47 110.39,48.58 110.5,48.82 110.5,48.84 111.46,49.8 113.69,49.8
+0.95VSDGPU on TOP (solid shape): outline of 1548 points within 93.68,97.36 110.76,129.37
+0.95VSDGPU on BOTTOM (solid shape): 97.63,100.2 97.63,99.67 97.63,99.66 97.09,99.66 97.08,99.65 97.08,98.94 97.1,98.92 97.63,98.92 97.63,98.92 97.63,98.48 97.62,98.47 97.09,98.47 97.09,98.46 97.09,97.73 97.09,97.72 97.63,97.72 97.63,97.72 97.63,97.2 97.62,97.19 95.83,97.19 95.62,97.4 95.62,99.36 96.48,100.22 97.62,100.22
+0.775VALW on BOTTOM (solid shape): 130.77,8.78 131.4,8.78 131.4,9.35 131.59,9.35 131.59,8.78 133.12,8.78 133.24,8.91 133.94,8.91 134.2,8.65 134.2,4.27 133.88,3.96 133.05,3.96 133.04,3.97 132.09,3.97 132.04,4.02 132.04,6.5 130,8.53 130,8.72 130.07,8.78 130.58,8.78 130.58,9.35 130.77,9.35
+1.2V_DDR on TOP (solid shape): 89.84,49.86 74.84,49.86 74.84,59.86 89.84,59.86
+1.2V_DDR on TOP (solid shape): outline of 10201 points within 40.76,43.01 109.07,101.43
+1.2V_DDR on BOTTOM (solid shape): outline of 1111 points within 61.08,44.09 74.51,59.77
+1.2V_DDR on BOTTOM (solid shape): outline of 1547 points within 42.76,44.85 54.6,60.28
+1.2V_DDR on VCC: 77.21,35.45 68.39,44.28 62.48,44.28 61.97,44.79 56.51,44.79 50.54,50.75 47.88,50.75 46.69,51.94 46.69,60.87 47.24,61.42 54.48,61.42 56.58,63.52 61.47,63.52 63.31,65.36 71.56,65.36 76.13,69.93 102.09,69.93 104.41,67.6 104.41,64.81 108.48,60.75 108.48,56.3 109.11,55.67 109.11,53.97 108.35,53.21 108.35,43.45 107.67,43.45 106.07,41.84 106.07,40.57 100.94,35.45
+1.2V_DDR on GND: 57.02,44.72 56.64,45.1 54.61,45.1 54.35,45.36 51.94,45.36 51.69,45.61 43.43,45.61 43.33,45.72 43.33,60.24 44.07,60.98 53.08,60.98 55.5,63.39 57.45,63.39 57.89,62.95 62.08,62.95 62.78,62.25 68.05,62.25 70.02,60.28 71.29,60.28 71.9,59.67 71.9,58.65 74.32,56.24 74.32,51.69 74.15,51.52 73.53,51.52 73.02,52.02 71.92,52.02 71.46,51.56 71.46,45.69 70.74,44.98 65.99,44.98 65.38,45.59 59.71,45.59 59.35,45.23 58.46,45.23 57.95,44.72
+1.2VP on TOP (solid shape): 72.28,105.75 72.28,102 71.9,101.62 71.2,101.62 71.2,101.11 70.76,101.11 70.76,101.62 70,101.62 70,101.11 69.55,101.11 69.55,101.62 65.93,101.62 65.93,101.05 65.49,101.05 65.49,101.62 64.73,101.62 64.73,101.05 64.28,101.05 64.28,101.55 64.26,101.55 64.26,101.56 63.51,101.56 63.46,101.62 63.46,105.75 63.77,106.06 71.97,106.06
+1.2VP on BOTTOM (solid shape): 71.01,106.06 71.01,101.36 70.7,101.05 64.03,101.05 63.65,101.43 63.65,106.06 63.84,106.25 70.82,106.25
+1.2VP on IN2 (solid shape): 67.46,104.48 67.46,103.02 67.33,102.89 66.7,102.89 66.7,104.48 66.82,104.6 67.33,104.6
+1.5VS on TOP (solid shape): 122.19,24.85 122.19,24.36 122.3,24.26 122.3,24.16 122.4,24.16 122.6,23.96 124.8,23.96 124.99,23.77 124.99,22.5 124.8,22.31 124.35,22.31 123.53,23.13 122.58,23.13 122.13,23.58 122.13,23.91 121.8,23.91 121.43,24.28 121.43,24.85 121.5,24.91 122.13,24.91
+1.5VS on BOTTOM (solid shape): 109.43,13.32 110,13.32 110,13.83 110.32,13.83 110.45,13.7 110.45,12.18 110.24,11.98 110.24,11.5 110.07,11.32 108.57,11.32 108.16,11.73 108.16,13.64 108.29,13.77 108.61,13.77 108.61,13.32 109.18,13.32 109.18,13.83 109.43,13.83
+1.5VSP on BOTTOM (solid shape): 107.77,18.19 107.77,17.74 107.78,17.72 107.78,17.67 110.45,15 110.45,14.12 110.38,14.05 109.81,14.05 109.81,13.48 109.62,13.48 109.62,14.05 108.99,14.05 108.99,13.48 108.8,13.48 108.8,14.05 108.29,14.05 108.22,14.12 108.22,15.07 108.57,15.42 108.57,16.05 108.22,16.4 106.32,16.4 105.87,16.85 104.1,16.85 103.97,16.97 103.97,17.48 104.1,17.61 105.87,17.61 106.07,17.8 106.07,18.18 106.19,18.31 107.65,18.31
+1.8V_ALW on TOP (solid shape): 37.49,87.2 37.49,85.17 37.23,84.92 35.96,84.92 35.77,85.11 35.77,87.2 35.96,87.39 37.29,87.39
+1.8V_ALW on TOP (solid shape): 84.41,30.94 84.41,27.39 84.03,27.01 83.14,27.01 82.57,27.58 82.57,31.51 82.7,31.64 83.71,31.64
+1.8V_ALW on TOP (solid shape): 91.94,17.51 91.94,15.29 91.75,15.1 90.03,15.1 89.84,15.29 89.84,17.39 90.16,17.7 91.75,17.7
+1.8V_ALW on TOP (solid shape): 104.1,93.3 104.1,92.79 102.38,91.08 101.94,91.08 101.62,91.39 101.62,92.92 102.13,93.43 103.97,93.43
+1.8V_ALW on TOP (solid shape): 131.53,21.93 131.53,20.91 131.21,20.59 129.31,20.59 128.99,20.91 128.99,21.86 129.24,22.12 131.34,22.12
+1.8V_ALW on TOP (solid shape): 97.87,88.92 97.87,87.97 97.68,87.78 96.03,87.78 91.97,83.71 91.97,83.01 91.65,82.7 89.71,82.7 89.56,82.85 89.56,84.22 94.64,89.3 97.49,89.3
+1.8V_ALW on TOP (solid shape): 38.44,94.89 39.01,94.89 39.01,95.33 39.39,95.33 39.45,95.27 39.45,93.68 39.33,93.55 36.47,93.55 36.28,93.74 36.28,95.08 36.44,95.24 37.14,95.24 37.17,95.27 37.68,95.27 37.68,94.89 38.25,94.89 38.25,95.33 38.44,95.33
+1.8V_ALW on TOP (solid shape): outline of 190 points within 117.43,31.51 120.42,48.97
+1.8V_ALW on BOTTOM (solid shape): 84.03,33.61 84.03,31.07 83.9,30.94 82.06,30.94 81.87,31.13 81.87,33.48 82.13,33.74 83.9,33.74
+1.8V_ALW on BOTTOM (solid shape): 91.49,83.11 91.49,81.27 91.24,81.01 89.71,81.01 89.52,81.2 89.52,83.11 89.64,83.23 91.37,83.23
+1.8V_ALW on BOTTOM (solid shape): 123.81,14.91 123.81,14.14 123.47,13.8 122.59,13.8 122.41,13.99 122.41,15.38 122.51,15.48 123.24,15.48
+1.8V_ALW on BOTTOM (solid shape): 158.83,20.4 158.83,18.88 158.71,18.75 157.25,18.75 157.12,18.88 157.12,19.96 157.31,20.15 157.31,20.49 157.31,21.04 157.44,21.16 158.07,21.16
+1.8V_ALW on BOTTOM (solid shape): 103.93,93.49 104.82,93.49 105,93.31 105,92.54 104.76,92.3 102.81,92.3 102.55,92.56 102.55,94 102.65,94.1 103.32,94.1
+1.8V_ALW on BOTTOM (solid shape): 92.1,16.85 92.1,16.27 92.6,16.27 92.6,16.08 92.1,16.08 92.1,15.45 92.67,15.45 92.67,15.26 92.1,15.26 92.1,14.88 91.97,14.75 90.38,14.75 90,15.13 90,16.85 90.13,16.97 91.97,16.97
+1.8V_ALW on BOTTOM (solid shape): 132.04,21.48 132.04,20.59 131.91,20.47 131.34,20.47 131.34,19.89 131.15,19.89 131.15,20.47 130.51,20.47 130.51,19.96 130.32,19.96 130.32,20.47 129.62,20.47 129.5,20.59 129.5,21.74 129.69,21.93 131.59,21.93
+1.8V_ALW on BOTTOM (solid shape): 118.96,49.68 118.96,49.29 118.32,48.66 118.32,48.34 118.45,48.21 118.45,47.96 118.26,47.77 118.17,47.77 118.15,47.78 118.09,47.82 118.01,47.84 118,47.84 117.43,48.41 117.43,48.72 118.45,49.74 118.89,49.74
+1.8V_ALW on IN1 (solid shape): 158.96,20.47 158.96,19.32 158.71,19.07 156.29,19.07 156.17,19.2 156.17,20.53 156.23,20.59 158.83,20.59
+1.8V_ALW on IN1 (solid shape): outline of 325 points within 89.68,11.19 131.85,21.8
+1.8V_ALW on VCC: 36.45,84.85 36.02,85.28 36.02,86.97 40.64,91.59 75.16,91.59 77.32,89.43 95.8,89.43 96.35,88.88 96.35,87.31 95.86,86.82 89.66,86.82 88.83,87.65 84.75,87.65 84.69,87.58 76.64,87.58 74.17,90.06 41.89,90.06 38.31,86.48 38.31,85.28 37.89,84.85
+1.8V_AVDD on TOP (solid shape): 35.9,24.28 35.9,23.39 35.83,23.32 35.07,23.32 34.95,23.45 34.95,24.02 34.56,24.4 33.93,24.4 33.8,24.53 33.8,25.42 33.61,25.61 32.85,25.61 32.41,26.05 30.63,26.05 30.56,26.12 30.56,26.25 30.62,26.31 33.87,26.31
+1.8VALWP on TOP (solid shape): 39.77,99.21 39.77,95.84 39.58,95.65 38.82,95.65 38.82,95.08 38.63,95.08 38.63,95.65 37.99,95.65 37.99,95.08 37.8,95.08 37.8,95.65 36.6,95.65 36.47,95.78 36.47,99.27 36.66,99.46 39.52,99.46
+1.8VALWP on BOTTOM (solid shape): 40.79,99.01 40.79,97.62 40.91,97.49 42.12,97.49 42.37,97.24 42.37,95.65 42.12,95.4 36.98,95.4 36.72,95.65 36.72,99.08 36.91,99.27 40.53,99.27
+1.8VGS on TOP (solid shape): 80.98,93.24 80.98,92.86 80.54,92.41 80.54,91.52 80.47,91.46 78.76,91.46 78.63,91.59 78.63,92.86 78.7,92.92 79.46,92.92 79.9,93.36 80.86,93.36
+1.8VGS on TOP (solid shape): 102.78,121.92 102.78,120.68 103.69,119.76 103.69,119.25 103.57,119.12 103.52,119.07 103.49,119.02 102.82,119.02 102.64,118.83 102.64,118.33 102.51,118.2 100.56,118.2 100.56,118.2 100.04,118.2 98.51,116.67 98.51,114.64 98.57,114.57 100.79,114.57 101.13,114.91 101.14,114.91 101.28,115 101.36,115.13 101.37,115.14 101.43,115.21 101.43,115.78 101.62,115.97 103.33,115.97 103.46,115.84 103.46,115.21 103.4,115.14 102.76,115.14 102.45,114.83 101.81,114.83 100.54,113.56 100.35,113.56 100.16,113.37 100.16,112.79 99.97,112.6 99.26,112.6 98.88,112.22 98.88,111.02 99.52,110.38 99.52,109.55 99.54,109.53 99.54,109.49 100.26,108.77 100.98,108.77 101.15,108.6 101.15,107.82 101.04,107.7 99.89,107.7 99.86,107.74 99.06,107.74 97.21,109.59 97.21,116.66 97.32,116.89 97.24,117.13 102.26,122.15 102.54,122.15
+1.8VGS on BOTTOM (solid shape): 101.28,94.04 101.28,92.26 100.99,91.97 99.97,91.97 99.78,92.16 99.78,94.06 99.82,94.11 101.21,94.11
+1.8VGS on BOTTOM (solid shape): 99.21,125.3 99.21,124.54 99.08,124.41 98.46,124.41 98.4,124.48 98.4,125.05 97.89,125.56 97.45,125.56 97.36,125.65 97.01,125.65 96.89,125.63 96.78,125.57 96.76,125.56 96.73,125.56 96.48,125.3 96.1,125.3 95.94,125.46 95.94,125.66 95.94,125.67 95.97,125.81 95.94,125.96 95.94,125.97 95.94,127.18 96.35,127.59 96.92,127.59
+1.8VS on TOP (solid shape): 83.1,72.26 83.1,70.56 82.97,70.42 81.24,70.42 81.09,70.57 81.09,72.15 81.45,72.51 82.86,72.51
+1.8VS on TOP (solid shape): 141.69,41.61 141.69,41.26 141.43,41.01 140.54,41.01 140.42,41.13 140.42,41.75 140.55,41.89 141.41,41.89
+1.8VS on TOP (solid shape): 109.56,87.08 109.56,86.38 108.73,85.55 108.73,82.7 108.61,82.57 108.29,82.57 108.16,82.7 108.16,82.71 108.17,82.76 108.17,82.8 108.17,82.98 108.17,83.02 108.16,83.06 108.16,84.61 108.17,84.66 108.17,84.7 108.17,84.88 108.17,84.92 108.16,84.96 108.16,85.37 108.25,85.5 108.29,85.65 108.29,85.68 108.44,85.83 108.44,85.89 108.61,86.06 108.61,86.95 108.8,87.14 109.49,87.14
+1.8VS on TOP (solid shape): outline of 176 points within 114.53,19.94 124.73,49.36
+1.8VS on BOTTOM (solid shape): 110.18,78.71 110.18,77.46 110.11,77.39 108.9,77.39 108.76,77.53 108.76,78.44 109.08,78.76 110.13,78.76
+1.8VS on BOTTOM (solid shape): 117.88,49.61 117.88,49.36 117.24,48.72 117.24,48.34 117.43,48.15 117.43,47.83 117.3,47.71 117.13,47.71 117.08,47.76 117.02,47.8 116.42,48.41 116.42,48.79 117.05,49.42 117.24,49.42 117.5,49.68 117.81,49.68
+1.8VS on BOTTOM (solid shape): 155.85,17.93 156.42,17.93 156.42,18.43 156.83,18.43 156.99,18.27 156.99,14.88 155.33,13.22 153.28,13.22 152.99,13.51 152.99,14.56 154.18,15.75 154.18,18.1 154.45,18.37 155.02,18.37 155.02,17.93 155.6,17.93 155.6,18.43 155.85,18.43
+1.8VS on BOTTOM (solid shape): 124.99,20.02 124.99,11.46 126.83,9.62 126.83,9.42 126.32,8.91 125.18,8.91 124.48,9.61 124.48,10.37 123.97,10.88 123.97,14.08 123.98,14.09 124.01,14.24 123.98,14.39 123.97,14.4 123.97,15.13 123.4,15.7 122.66,15.7 122.58,15.79 122.58,16.73 122.61,16.77 122.66,16.77 123.03,17.14 123.03,17.18 123.72,17.86 123.72,18.43 123.72,18.45 123.72,19 123.53,19.2 123.53,20.22 123.9,20.59 124.42,20.59
+1.8VS on IN2 (solid shape): outline of 93 points within 125.24,8.84 154.71,15.13
+1.8VS on IN2 (solid shape): outline of 896 points within 109.62,47.77 118.32,68.34
+1.8VS_LS on BOTTOM (solid shape): 156.04,21.1 156.04,20.53 156.29,20.27 156.8,20.27 156.93,20.15 156.93,18.75 156.87,18.69 156.23,18.69 156.23,18.18 156.04,18.18 156.04,18.69 155.4,18.69 155.4,18.18 155.21,18.18 155.21,18.69 153.59,18.69 152.99,19.28 152.99,20.43 153.12,20.55 154.22,20.55 154.9,21.23 155.91,21.23
+1.35V_MEM_GFX on TOP (solid shape): 117.18,110.76 117.18,109.81 117.19,109.8 117.19,109.76 117.23,109.76 117.37,109.62 117.71,109.62 117.94,109.37 118.26,109.25 118.26,109.13 118.08,108.63 118.3,108.16 118.32,108.14 118.32,107.97 118,107.65 117.56,107.65 117.37,107.84 117.37,108.73 117.08,109.02 117.08,109.21 116.8,109.49 115.34,109.49 115.34,110.13 115.4,110.19 115.91,110.19 116.03,110.32 116.03,110.95 116.1,111.02 116.92,111.02
+1.35V_MEM_GFX on TOP (solid shape): outline of 4620 points within 131.66,92.18 155.47,128.35
+1.35V_MEM_GFX on BOTTOM (solid shape): 120.92,125.56 120.92,124.54 120.61,124.22 119.72,124.22 119.34,124.61 119.34,125.56 119.4,125.62 120.86,125.62
+1.35V_MEM_GFX on BOTTOM (solid shape): 143.09,126.26 143.09,125.62 143.18,125.52 143.19,125.51 143.24,125.42 143.32,125.36 143.34,125.34 143.34,125.08 143.32,125.07 143.17,124.8 143.33,124.55 143.34,124.54 143.66,124.22 143.66,123.91 143.61,123.87 143.57,123.82 143.53,123.78 143.39,123.78 143.3,123.9 143.16,123.97 143.14,123.98 142.45,124.67 142.45,126.32 142.51,126.38 142.96,126.38
+1.35V_MEM_GFX on BOTTOM (solid shape): 119.08,118.38 119.08,118.3 119.07,118.28 118.95,118.01 119.08,117.74 119.08,117.43 118.96,117.3 118.69,117.3 118.68,117.31 118.39,117.29 118.21,117.07 118.2,117.06 117.93,116.78 117.86,116.73 117.82,116.67 117.75,116.6 117.75,115.21 117.8,115.15 117.81,115.15 117.97,115 118.19,114.98 118.22,114.99 118.26,114.95 118.26,114.57 118.12,114.43 118.1,114.43 118.01,114.42 117.94,114.39 117.93,114.38 117.11,114.38 116.92,114.57 116.92,116.73 117.5,117.3 117.5,118 117.85,118.36 117.86,118.36 117.97,118.42 118.05,118.51 118.96,118.51
+1.35V_MEM_GFX on BOTTOM (solid shape): 141.37,102 141.37,101.37 141.37,101.34 141.35,101.31 141.35,101.15 141.24,101.05 141.05,101.05 140.42,100.41 140.42,99.71 140.36,99.65 139.97,99.65 139.76,99.86 139.76,99.87 139.71,99.99 139.62,100.07 139.59,100.08 139.59,100.34 139.62,100.35 139.69,100.41 139.75,100.49 139.75,100.5 139.95,100.71 139.96,100.71 140.1,100.79 140.18,100.93 140.19,100.94 140.38,101.13 140.38,101.13 140.48,101.62 139.99,101.52 139.99,101.51 139.88,101.4 139.86,101.4 139.68,101.36 139.55,101.24 139.34,101.24 139.28,101.3 139.28,101.44 139.41,101.6 139.44,101.81 139.43,101.84 139.91,102.32 141.05,102.32
+1.35V_MEM_GFX on BOTTOM (solid shape): 116.98,110.7 117.08,110.59 117.21,110.53 117.22,110.53 117.75,110 117.75,109.37 117.77,109.34 117.77,109.32 117.88,109.05 118.17,108.98 118.2,108.98 118.32,108.86 118.32,108.48 118.24,108.4 118.21,108.41 117.82,108.27 117.88,107.86 117.88,107.71 118.15,107.44 118.15,107.43 118.45,107.23 118.77,107.4 118.96,107.4 119.21,107.14 119.21,106.06 118.93,105.78 118.9,105.78 118.76,105.74 118.66,105.64 118.64,105.62 118.36,105.62 118.34,105.64 118.24,105.74 118.11,105.78 118.1,105.78 117.43,106.44 117.43,107.21 117.4,107.24 117.4,107.24 117.33,107.33 117.24,107.4 117.24,107.4 116.68,107.96 116.67,107.98 116.65,108.06 116.61,108.13 116.61,108.67 116.68,108.9 116.61,109.13 116.61,109.67 116.68,109.9 116.61,110.13 116.61,110.57 116.73,110.7
+1.35V_MEM_GFX on BOTTOM (solid shape): 149.75,101.94 149.75,101.69 149.73,101.67 149.63,101.58 149.58,101.45 149.57,101.44 149.5,101.37 149.48,101.37 149.22,101.26 149.11,101 149.11,100.98 149.04,100.91 149.03,100.91 148.77,100.65 148.96,100.33 148.99,100.32 148.99,100.1 148.96,100.09 148.77,99.81 148.96,99.53 148.99,99.52 148.99,99.33 148.94,99.28 148.86,99.22 148.8,99.14 148.74,99.08 148.56,99.08 148.55,99.11 148.42,99.27 148.22,99.31 148.2,99.3 147.76,99.74 147.77,99.78 147.8,99.84 147.86,99.87 148.2,100.22 147.86,100.58 147.8,100.6 147.77,100.66 147.65,100.85 147.45,100.91 147.37,100.94 147.34,101.01 147.34,101.75 147.37,101.77 147.47,101.8 147.54,101.71 147.66,101.48 147.9,101.4 147.92,101.4 147.98,101.34 147.98,101.33 148.5,101.22 148.3,101.71 148.26,101.72 148.25,101.76 148.24,101.81 148.23,101.87 148.24,101.96 148.33,102 149.69,102
+1.35V_MEM_GFX on BOTTOM (solid shape): outline of 405 points within 145.63,120.8 153.63,130.96
+1.35V_MEM_GFX on BOTTOM (solid shape): outline of 446 points within 139.85,92.03 155.34,100.86
+1.35V_MEM_GFX on BOTTOM (solid shape): outline of 186 points within 137.43,105.56 143.78,117.81
+1.35V_MEM_GFX on BOTTOM (solid shape): outline of 208 points within 144.74,103.21 153.82,120.73
+1.35V_MEM_GFX on VCC: 140.59,92.6 133.48,99.71 127.76,99.71 125.22,102.25 118.36,102.25 117.62,102.99 117.62,123.74 126.62,132.73 151.43,132.73 154.83,129.33 154.83,95.88 151.55,92.6
+1.35VGPUP on BOTTOM (solid shape): 143.09,91.84 143.91,91.84 143.91,92.35 144.29,92.35 144.29,91.84 145.05,91.84 146.07,90.82 148.42,90.82 148.67,90.57 148.67,85.74 148.42,85.49 142.51,85.49 142.39,85.62 142.39,90.12 141.94,90.57 141.94,91.71 142.07,91.84 142.7,91.84 142.7,92.35 143.09,92.35
+2.5V_MEM on TOP (solid shape): 48.72,94.63 48.72,93.68 47.77,92.73 46.88,92.73 46.38,93.24 46.38,94.63 46.63,94.89 48.47,94.89
+2.5V_MEM on TOP (solid shape): outline of 295 points within 50.12,19.07 69.3,23.51
+2.5V_MEM on BOTTOM (solid shape): 71.14,21.23 71.14,20.4 70.63,19.89 67.27,19.89 67.08,20.08 67.08,21.1 67.27,21.29 71.08,21.29
+2.5V_MEM on BOTTOM (solid shape): 56.47,20.91 56.47,20.47 56.34,20.34 54.76,20.34 54.25,20.85 52.34,20.85 52.15,21.04 52.15,21.67 52.28,21.8 55.58,21.8
+2.5V_MEM on BOTTOM (solid shape): 34.37,100.09 34.37,97.68 36.85,95.2 43.77,95.2 44.02,95.1 44.27,95.2 48.22,95.2 48.92,94.51 48.92,93.3 48.57,92.96 35.05,92.96 30.04,97.96 30.04,98.27 30.6,98.27 30.6,98.83 30.04,98.83 30.04,99.08 30.6,99.08 30.6,99.63 30.04,99.63 30.04,100.08 30.06,100.09 30.06,100.22 30.12,100.28 34.18,100.28
+2.5VP on BOTTOM (solid shape): 29.87,100.86 29.87,99.46 30.37,99.46 30.37,99.27 29.87,99.27 29.87,98.63 30.44,98.63 30.44,98.44 29.87,98.44 29.87,98 29.74,97.87 29.29,97.87 28.66,98.51 26.82,98.51 26.69,98.63 26.69,99.65 26.63,99.71 24.59,99.71 24.4,99.9 24.4,100.86 24.53,100.98 29.74,100.98
+3V_1.8V_CPVDD on TOP (solid shape): 30.75,24.35 30.75,23.13 30.69,23.07 30.25,23.07 30.06,23.26 30.06,24.53 30.13,24.6 30.5,24.6
+3V_DVDD on TOP (solid shape): 34.12,37.15 34.12,33.48 33.87,33.23 33.17,33.23 32.72,32.78 32.72,31.13 32.66,31.07 31.58,31.07 30.31,29.8 30.12,29.8 30.06,29.86 30.06,30.69 31.35,31.99 31.35,32.05 31.96,32.66 31.96,33.93 32.15,34.12 33.1,34.12 33.29,34.31 33.29,37.18 33.32,37.2 34.07,37.2
+3VALW on TOP (solid shape): 35.52,85.87 35.52,82.79 35.39,82.66 33.23,82.66 32.98,82.92 32.98,85.87 33.42,86.31 35.07,86.31
+3VALW on TOP (solid shape): 167.85,29.67 168.04,29.48 168.04,28.85 167.9,28.7 166.55,28.7 166.34,28.91 166.34,29.56 166.47,29.69 167.85,29.69
+3VALW on TOP (solid shape): 159.8,107.49 159.8,107.12 159.63,106.95 158.62,106.95 157.56,105.9 157.56,103.97 157.37,103.78 156.8,103.78 156.67,103.9 156.67,106.44 157.87,107.64 159.65,107.64
+3VALW on TOP (solid shape): 115.34,42.69 115.34,42.03 114.98,41.67 114.98,39.2 114.54,38.75 114,38.75 113.62,39.13 113.62,39.71 113.83,39.92 114.11,39.92 114.27,40.09 114.27,42.34 114.69,42.75 115.27,42.75
+3VALW on TOP (solid shape): 164.99,44.6 164.99,43.82 164.23,43.06 164.23,42.1 163.89,41.77 161.5,41.77 160.99,42.27 160.99,43.07 161.31,43.39 161.31,44.65 161.33,44.67 161.84,44.67 161.86,44.65 161.86,44.09 162.64,44.09 162.64,44.6 163.02,44.6 163.02,44.09 163.85,44.09 163.85,44.6 164.42,44.6 164.55,44.72 164.87,44.72
+3VALW on TOP (solid shape): 175.11,35.46 175.21,35.39 175.18,35.28 175.41,34.65 175.64,35.28 175.61,35.39 175.7,35.46 175.93,35.46 175.98,35.45 176.23,35.19 176.2,35.16 176.18,34.76 176.55,34.59 176.63,34.57 176.67,34.49 176.67,33.1 176.39,32.81 175.22,32.81 174.14,33.9 174.14,35.21 174.39,35.46
+3VALW on TOP (solid shape): outline of 200 points within 14.01,97.24 40.72,111.46
+3VALW on BOTTOM (solid shape): 178.08,19.81 178.08,19.07 178.07,19.07 178.07,18.99 177.68,18.6 176.42,18.6 176.17,18.85 176.17,19.85 176.3,19.98 177.91,19.98
+3VALW on BOTTOM (solid shape): 28.72,123.72 28.72,122.51 29.04,122.19 29.04,121.68 28.91,121.56 28.53,121.56 28.53,121.05 28.4,121.05 28.4,121.56 26.18,121.56 25.99,121.75 25.99,123.78 26.18,123.97 28.47,123.97
+3VALW on BOTTOM (solid shape): 14.82,99.84 14.82,99.21 15.39,99.21 15.39,99.01 14.88,99.01 14.88,98.38 15.39,98.38 15.39,98.19 14.88,98.19 14.88,97.62 14.82,97.55 14.05,97.55 13.93,97.68 13.93,99.84 13.99,99.9 14.75,99.9
+3VALW on BOTTOM (solid shape): 40.41,110.83 40.41,109.56 40.22,109.37 39.71,109.37 39.71,108.79 39.52,108.79 39.52,109.37 38.88,109.37 38.88,108.79 38.69,108.79 38.69,109.37 38.06,109.37 37.99,109.43 37.99,110.83 38.06,110.89 40.34,110.89
+3VALW on BOTTOM (solid shape): 160.54,24.99 160.54,22.29 160.36,22.12 159.34,22.12 158.9,22.56 157.44,22.56 157.37,22.62 157.37,23.2 157.18,23.39 156.67,23.39 156.55,23.51 156.55,25.16 156.67,25.29 160.23,25.29
+3VALW on BOTTOM (solid shape): 126.89,21.42 126.89,20.85 127.46,20.85 127.46,20.66 126.89,20.66 126.89,20.02 127.46,20.02 127.46,19.83 126.89,19.83 126.89,18.5 127.21,18.18 127.21,16.46 127.72,15.96 127.72,12.27 129.05,10.94 129.05,10.24 128.86,10.05 127.31,10.05 125.5,11.86 125.5,21.16 125.88,21.54 126.77,21.54
+3VALW on VCC (solid shape): outline of 5404 points within 46.88,9.92 187.22,44.72
+3VALW on IN1 (solid shape): 114.81,39.35 114.81,38.43 114.45,38.07 113.73,38.79 113.48,38.79 113.48,39.21 113.49,39.21 113.49,39.5 113.64,39.65 114.51,39.65
+3VALW on IN2 (solid shape): 28.6,123.78 28.6,121.75 28.4,121.56 26.63,121.56 26.37,121.81 26.37,123.84 26.5,123.97 28.4,123.97
+3VALW on IN2 (solid shape): 40.28,111.14 40.28,109.75 39.96,109.43 37.17,109.43 36.91,109.68 36.91,111.14 37.1,111.33 40.09,111.33
+3VALW on IN2 (solid shape): outline of 474 points within 130.77,44.09 136.04,56.22
+3VALW on IN2 (solid shape): outline of 1644 points within 32.85,15.77 53.04,84.6
+3VALW_EC on TOP (solid shape): 167.72,36.98 167.72,34.67 166.94,33.88 166.14,33.88 166.01,34.01 166.01,34.75 165.76,35.01 165.76,36.09 166.26,36.59 166.25,36.6 166.25,37.18 166.31,37.23 167.47,37.23
+3VALW_EC on TOP (solid shape): 180.42,39.39 180.42,36.15 179.92,35.64 178.87,35.64 178.53,35.31 178.53,34.44 178.49,34.4 178.49,33.83 178.12,33.46 178.12,31.18 177.96,31.01 177.12,31.01 176.85,31.28 176.85,35.33 176.86,35.33 176.86,36.08 177.36,36.58 177.39,36.57 177.53,36.58 177.64,36.66 179.34,36.66 179.66,36.98 179.66,38.44 179.47,38.63 178.21,38.63 178.16,38.68 177.62,38.68 177.59,38.71 177.59,39.34 177.63,39.39 177.97,39.39 178.12,39.39 178.24,39.5 178.24,40.02 178.3,40.09 179.73,40.09
+3VALW_EC on IN2 (solid shape): 179.6,39.9 179.6,39.01 178.96,38.37 178.33,38.37 178.2,38.5 178.2,39.72 178.21,39.78 178.2,39.9 178.33,40.02 179.47,40.02
+3VALW_EC on IN2 (solid shape): 169.63,37.74 169.63,36.19 168.51,35.07 167.22,35.07 167.03,35.26 167.03,36.75 168.76,36.75 168.76,36.69 168.77,36.64 168.79,36.59 168.81,36.54 168.84,36.5 168.88,36.46 168.92,36.43 168.97,36.4 169.02,36.38 169.07,36.37 169.12,36.36 169.17,36.37 169.23,36.38 169.28,36.4 169.32,36.43 169.36,36.46 169.4,36.5 169.43,36.54 169.45,36.59 169.47,36.64 169.48,36.69 169.48,36.75 169.47,36.8 169.45,36.85 169.43,36.9 169.4,36.94 169.36,36.98 169.32,37.02 169.28,37.04 169.23,37.06 169.17,37.07 169.12,37.08 169.07,37.07 169.02,37.06 168.97,37.04 168.92,37.02 168.88,36.98 168.84,36.94 168.81,36.9 168.79,36.85 168.77,36.8 168.76,36.75 167.03,36.75 167.03,36.85 168.3,38.12 169.25,38.12
+3VALW_EC on BOTTOM: 177.71,35.54 178.43,35.54 178.71,35.26 178.71,34.45 178.7,34.44 178.7,30.74 179.39,30.04 179.39,29.86 180.54,28.72 180.54,28.3 179.83,27.59 179.83,25.74 179.39,25.3 179.39,25.04 179.61,24.82 180.22,24.82 180.75,24.29 180.75,22.15 180.49,21.89 179.98,21.89 179.9,21.96 179.9,23.73 179.51,24.12 178.01,24.12 177.39,24.74 177.39,26.73 178.12,27.46 178.12,27.9 176.68,29.34 176.68,33.63 177.41,34.37 177.41,35.25
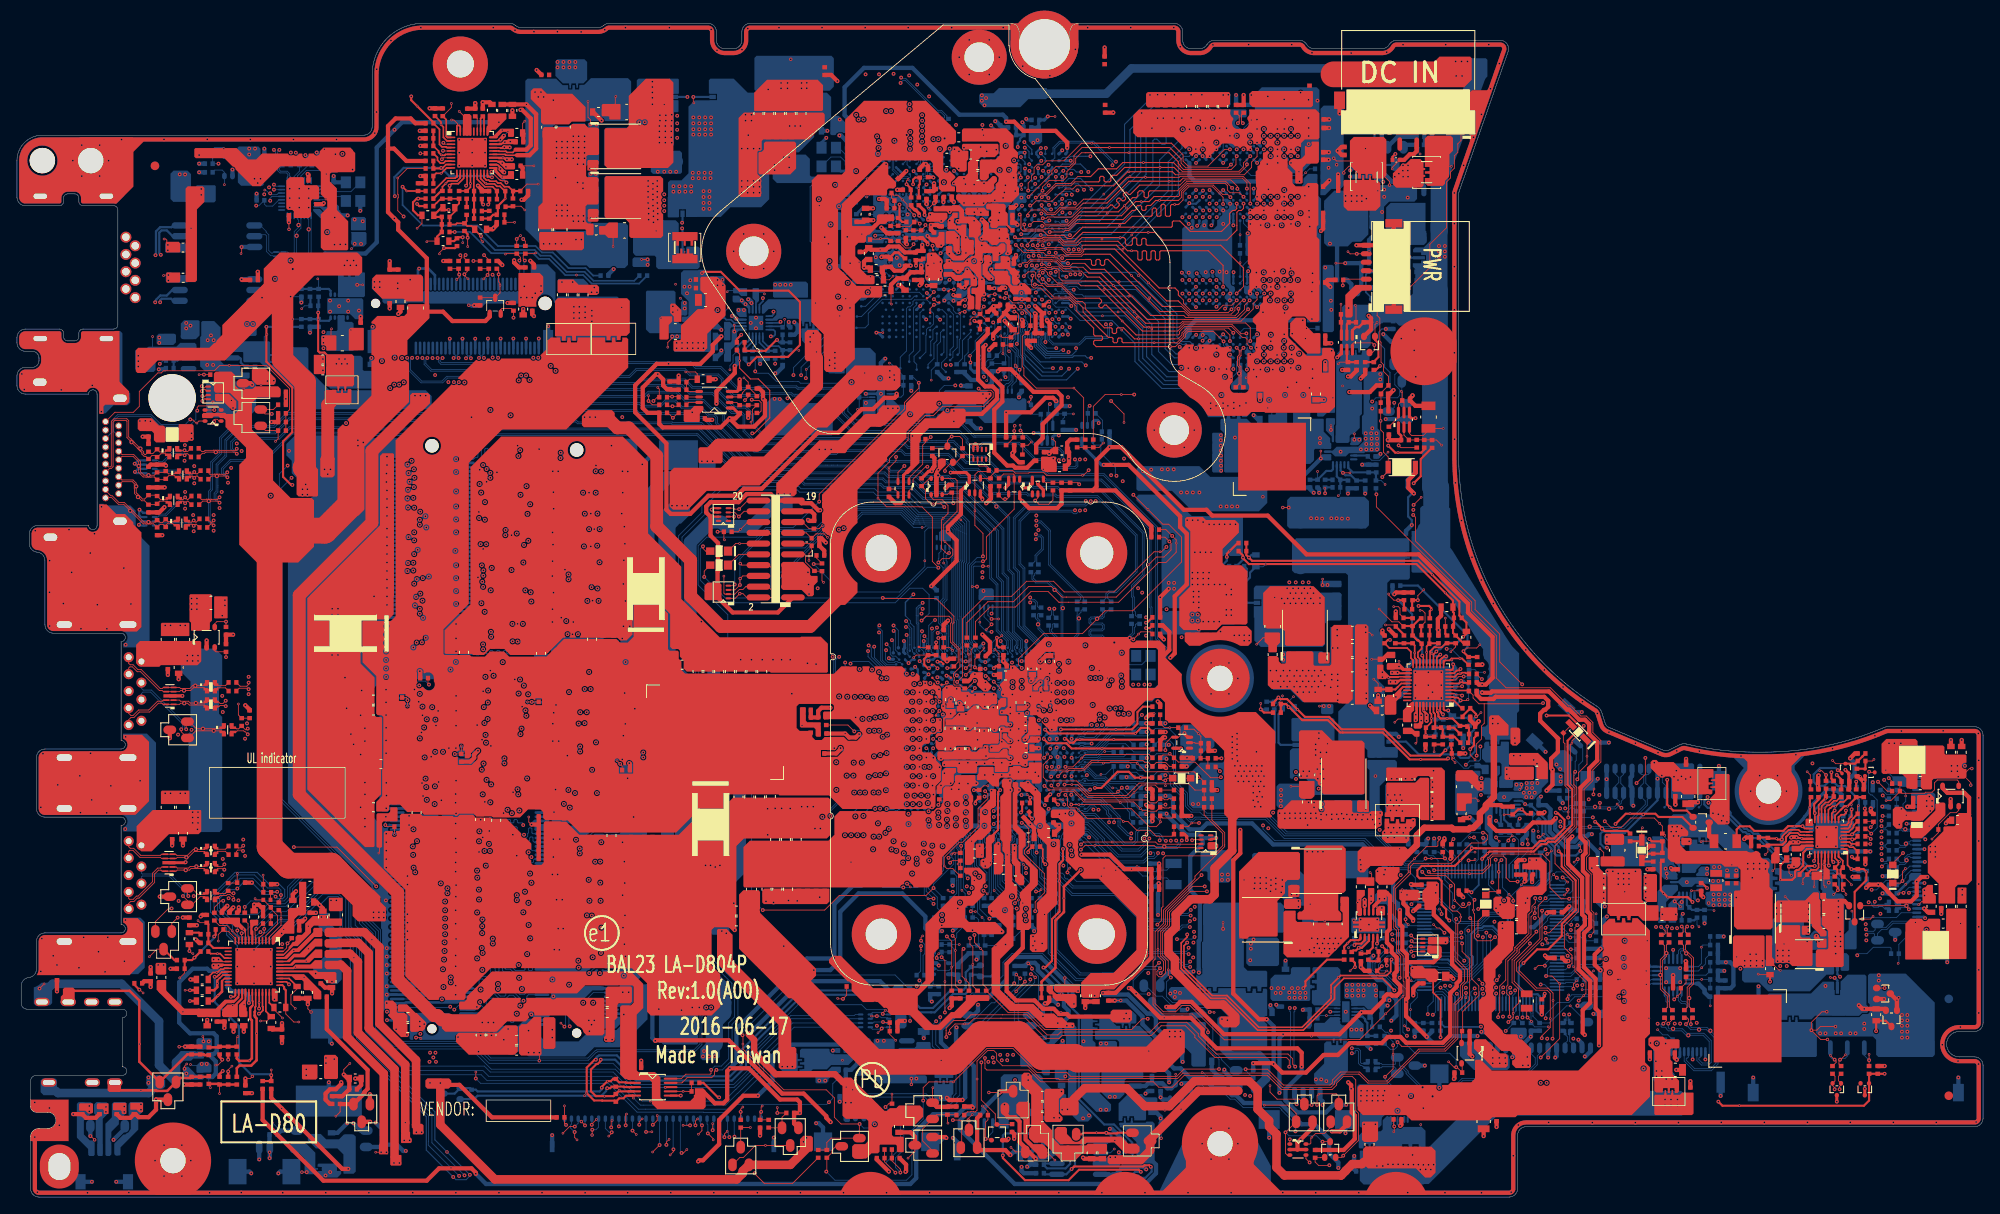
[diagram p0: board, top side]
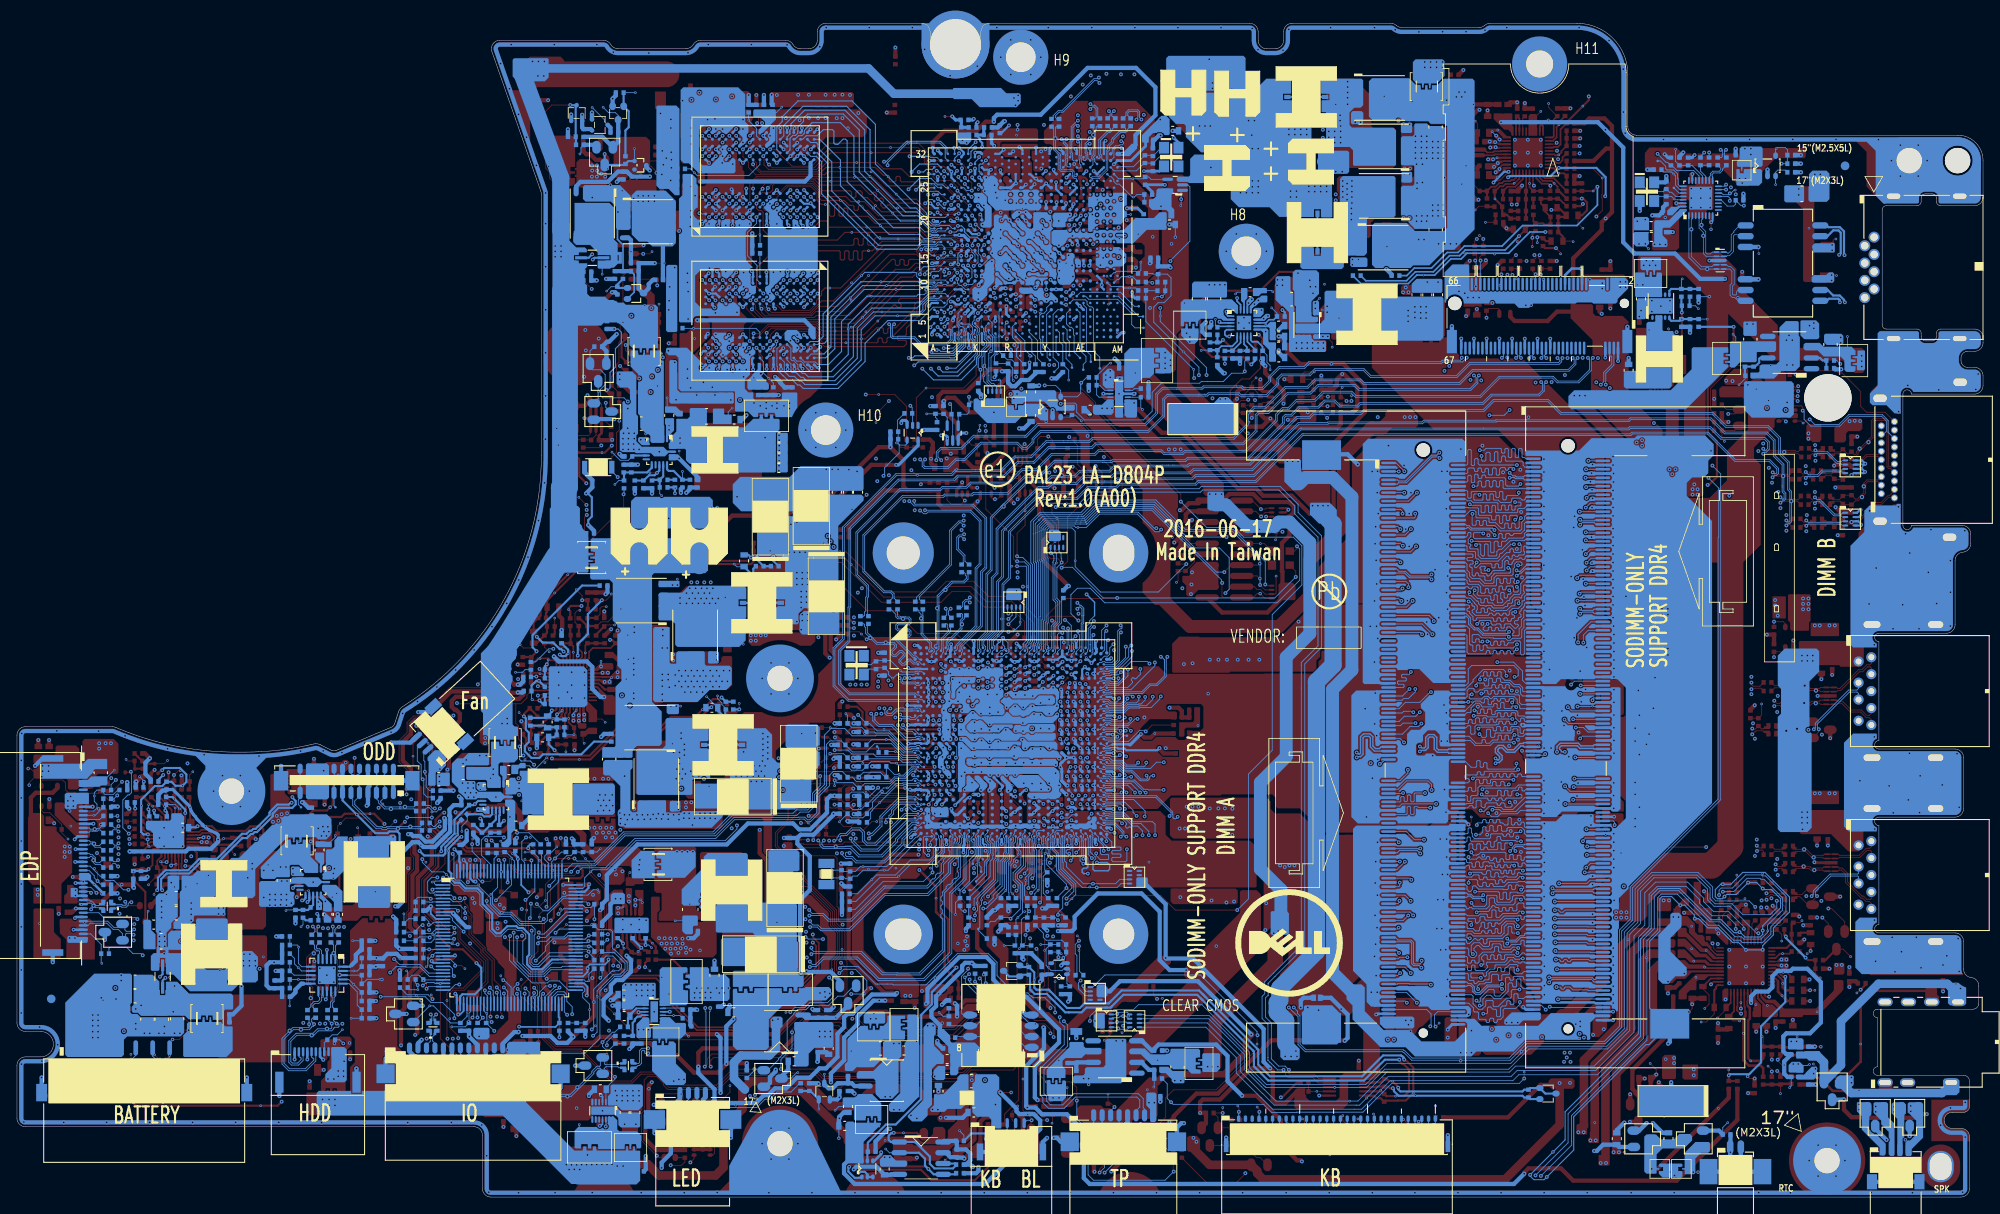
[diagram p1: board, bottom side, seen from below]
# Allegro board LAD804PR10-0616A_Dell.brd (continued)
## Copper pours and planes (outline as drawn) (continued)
+3VALWP on TOP (solid shape): 166.58,49.36 166.58,44.47 165.61,44.47 165.23,44.85 164.92,44.85 164.92,44.85 164.5,44.85 164.5,44.85 163.66,44.85 163.66,44.28 163.22,44.28 163.22,44.85 162.45,44.85 162.45,44.34 162.01,44.34 162.01,44.85 161.37,44.85 161.31,44.91 161.31,45.17 161.5,45.36 161.5,48.79 161.63,48.91 164.93,48.91 165.5,49.48 166.45,49.48
+3VALWP on BOTTOM (solid shape): 166.33,48.66 166.33,45.17 166.26,45.1 161.63,45.1 161.37,45.36 161.37,48.6 161.56,48.79 166.2,48.79
+3VGS on TOP (solid shape): 111.9,92.86 111.9,91.51 111.12,90.73 107.59,90.73 106.61,89.76 106.61,89.17 106.45,89 106.45,86.63 105.11,85.29 104.92,85.29 104.78,85.43 104.78,85.7 105.37,86.29 105.37,90.19 107.08,91.9 108.37,91.9 109.24,92.77 109.34,92.8 109.41,92.73 109.84,92.5 110.1,92.91 110.12,93 110.2,93.04 110.63,93.04 110.64,93.05 111.72,93.05
+3VGS on BOTTOM (solid shape): 97.49,118.83 97.49,118.06 97.63,117.93 97.63,117.89 97.67,117.89 97.81,117.75 98.32,117.75 98.38,117.68 98.38,116.86 98,116.48 96.35,116.48 96.1,116.22 96.1,115.52 96.03,115.46 95.46,115.46 95.4,115.52 95.4,116.54 95.71,116.86 95.71,118.32 95.52,118.51 95.52,118.95 95.59,119.02 97.3,119.02
+3VGS on BOTTOM (solid shape): 117.85,94.22 118.19,94 118.54,94.22 118.55,94.25 118.88,94.25 119.07,94.06 119.07,92.93 117.47,91.33 114.15,91.33 113.37,92.11 111.61,92.11 111.15,91.65 110.31,91.65 110.27,91.69 110.27,92.89 110.99,93.61 113.06,93.61 113.22,93.44 113.82,93.44 113.83,93.44 113.83,92.89 113.83,92.88 114.3,92.88 114.31,92.89 114.31,93.44 114.31,93.44 114.57,93.44 114.57,93.44 114.96,93.44 115.15,93.63 115.15,94 115.4,94.25 117.83,94.25
+3VLP on TOP (solid shape): outline of 81 points within 172.43,15.22 178.58,32.55
+3VLP on BOTTOM (solid shape): 174.33,46.82 174.33,46.25 174.07,45.99 174.07,42.31 174.45,41.93 174.71,41.93 174.77,41.86 174.77,41.42 174.65,41.29 173.95,41.29 173.57,41.67 173.57,42.94 173.12,43.39 173.12,46.69 173.31,46.88 174.26,46.88
+3VLP on BOTTOM (solid shape): 38.25,3.83 38.25,3.57 37.74,3.57 37.74,3.07 38.25,3.07 38.25,2.75 37.8,2.3 35.6,2.3 35.46,2.45 35.46,2.75 35.45,2.75 35.45,3.07 35.96,3.07 35.96,3.57 35.45,3.57 35.45,3.83 35.58,3.96 38.12,3.96
+3VLP on IN2 (solid shape): 38.24,4.06 38.24,2.64 37.85,2.25 36.08,2.25 36.04,2.3 36.04,3.95 36.63,4.54 37.76,4.54
+3VLP on IN2 (solid shape): 176.02,32.62 176.02,31.37 175.72,31.07 175.3,31.07 174.78,31.58 174.78,32.51 175.13,32.86 175.78,32.86
+3VLP on IN2 (solid shape): 178.79,15.57 178.79,15.27 178.2,14.69 178.2,14.62 177.82,14.24 177.19,14.24 176.93,14.5 176.93,15.19 177.53,15.78 178.57,15.78
+3VS on TOP (solid shape): 70.51,92.54 70.51,91.39 69.93,90.82 66.89,90.82 66.63,91.08 66.63,92.16 67.33,92.86 70.19,92.86
+3VS on TOP (solid shape): 167.6,30.67 168.76,30.67 168.85,30.57 168.85,30 168.67,29.82 166.51,29.82 166.42,29.91 166.42,30.58 166.51,30.67 167.6,30.67
+3VS on TOP (solid shape): 42.06,36.21 42.12,36.21 42.88,35.45 42.88,34.82 43.52,34.18 43.52,32.66 43.39,32.53 40.22,32.53 39.58,33.17 39.58,34.44 38.25,35.77 35,35.77 34.98,35.78 34.98,38.09 36.15,39.26 39.01,39.26
+3VS on TOP (solid shape): 230.59,44.82 230.59,37.36 230.08,36.85 228.94,36.85 228.62,36.53 228.62,34.69 228.56,34.63 226.72,34.63 226.65,34.69 226.65,35.9 226.65,36.79 226.65,36.98 225.38,38.25 225.38,39.47 225.39,39.55 225.38,39.63 225.38,41.34 227.01,42.97 227.01,42.97 227.22,43.19 227.22,43.62 227.36,43.76 227.38,43.76 227.51,43.73 227.64,43.75 227.65,43.76 228.52,43.76 228.68,43.92 228.68,44.96 229.04,45.32 230.09,45.32
+3VS on TOP (solid shape): outline of 117 points within 21.82,74.87 35.04,97.41
+3VS on TOP (solid shape): outline of 286 points within 94.95,69.87 114.97,95.01
+3VS on TOP (solid shape): outline of 391 points within 37.8,80.41 48.66,105.36
+3VS on TOP (solid shape): outline of 408 points within 95.78,19.7 116.48,38.88
+3VS on TOP (solid shape): outline of 517 points within 52.15,10.37 81.24,26.62
+3VS on BOTTOM (solid shape): 99.32,37.73 99.72,37.73 99.75,37.73 99.87,37.61 99.87,36.66 99.68,36.47 98.7,36.47 98.51,36.66 98.51,37.61 98.62,37.72 98.91,37.72 98.92,37.74 99.27,37.74
+3VS on BOTTOM (solid shape): 152.55,27.07 152.55,26.24 153.06,26.24 153.06,25.86 152.55,25.86 152.55,24.97 153.06,24.97 153.06,24.66 152.55,24.66 152.55,23.26 152.42,23.13 148.1,23.13 147.85,23.39 147.85,25.74 148.36,26.24 150.13,26.24 150.26,26.37 150.26,26.94 150.45,27.13 152.48,27.13
+3VS on BOTTOM (solid shape): 113.13,95.2 113.43,95.04 113.73,95.2 114.51,95.2 114.59,95.12 114.55,95.08 114.54,95.08 114.35,94.75 114.56,94.43 114.59,94.42 114.59,93.6 114.56,93.57 114.39,93.57 114.39,93.57 114.23,93.57 114.23,93.57 114.18,93.57 114.18,93.52 114.17,93.51 114.17,93.03 114.16,93.02 113.98,93.02 113.96,93.04 113.96,93.56 113.93,93.59 113.32,93.59 113.05,93.86 110.74,93.86 110,93.13 109.97,93.15 109.57,93.18 109.37,92.84 109.37,92.77 107.26,92.77 107.14,92.9 107.14,93.46 107.18,93.5 108.46,93.5 108.47,93.47 108.99,93.32 109.05,93.86 109.02,93.94 109.06,94.01 109.11,94.06 109.15,94.11 109.3,94.27 109.3,95.01 109.49,95.2
+3VS on IN2 (solid shape): 68.6,92.98 68.6,91.84 68.36,91.6 59.05,91.6 59.04,91.59 58.62,91.59 57.67,90.64 48.43,90.64 46.27,88.47 39.9,88.47 39.52,88.85 39.52,90.32 39.9,90.7 45.21,90.7 46.78,92.27 57.87,92.27 57.87,92.22 57.88,92.17 57.89,92.12 57.92,92.07 57.95,92.02 57.98,91.98 58.02,91.95 58.07,91.92 58.12,91.9 58.17,91.89 58.22,91.89 58.28,91.89 58.33,91.9 58.38,91.92 58.43,91.95 58.47,91.98 58.5,92.02 58.53,92.07 58.56,92.12 58.57,92.17 58.58,92.22 58.58,92.27 58.57,92.32 58.56,92.38 58.53,92.42 58.5,92.47 58.47,92.51 58.43,92.54 58.38,92.57 58.33,92.59 58.28,92.6 58.22,92.6 58.17,92.6 58.12,92.59 58.07,92.57 58.02,92.54 57.98,92.51 57.95,92.47 57.92,92.42 57.89,92.38 57.88,92.32 57.87,92.27 46.78,92.27 47.06,92.55 55.71,92.55 55.74,92.54 55.79,92.53 55.84,92.52 55.89,92.53 55.94,92.54 55.97,92.55 56.26,92.55 57.07,93.36 68.22,93.36
+3VS on VCC: 45.21,4.84 41.17,8.89 41.17,34.31 45.44,34.31 45.93,33.82 45.93,25.88 46.38,25.44 46.38,12.42 48.81,9.99 96.5,9.99 96.94,9.54 100.2,9.54 100.65,9.99 126.6,9.99 127.17,9.42 128.65,9.42 129.31,10.07 129.31,12.17 137.22,20.08 140.46,20.08 145.29,24.91 152.63,24.91 157.46,20.08 162.35,20.08 162.45,19.98 162.45,19.05 162.07,18.67 162.07,17.82 162.73,17.16 170.81,17.16 171.58,17.93 183.18,17.93 183.43,17.67 184.28,17.67 184.81,18.2 184.81,18.92 184.55,19.17 184.55,21.76 185.82,23.03 185.82,25.67 187.2,25.67 187.73,26.2 187.73,37.36 201.46,37.36 202.08,36.74 202.08,25.88 203.18,24.78 207.9,24.78 209.68,26.56 215.45,26.56 216.24,27.34 216.24,35.28 216.66,35.71 222.12,35.71 223.16,36.74 223.16,41.31 223.65,41.8 226.48,41.8 226.59,41.7 226.59,27.05 221.25,21.71 221.25,14.86 220.26,13.86 200.93,13.86 200.93,18.41 199.03,20.32 199.03,25.46 198.39,26.09 198.39,32.39 197.87,32.91 193.11,32.91 192.55,32.35 192.55,19.85 196.11,16.3 196.11,13.23 139.49,13.23 131.11,4.84
+3VS_APU on TOP (solid shape): outline of 145 points within 111.81,39.2 115.53,48.16
+3VS_APU on BOTTOM (solid shape): 115.82,49.68 115.86,49.6 115.91,49.55 115.91,49.29 115.27,48.66 115.27,47.83 115.08,47.64 114.96,47.64 114.95,47.67 114.85,47.78 114.71,47.84 114.7,47.84 114.53,48 114.53,48.01 114.5,48.08 114.45,48.15 114.45,48.6 115.59,49.74 115.76,49.74
+3VS_CAM on TOP (solid shape): 225.98,36.8 225.98,35.92 226.33,35.57 226.33,34.69 226.27,34.63 224.81,34.63 224.75,34.69 224.75,36.34 224.94,36.53 225.06,36.53 225.38,36.85 225.93,36.85
+3VS_CAM on BOTTOM (solid shape): 225.57,36.4 225.57,35.45 225.51,35.39 223.67,35.39 223.6,35.45 223.6,35.64 223.67,35.71 224.68,35.71 224.75,35.77 224.75,36.05 224.75,36.4 224.81,36.47 225.51,36.47
+3VS_TOUCH on TOP (solid shape): outline of 93 points within 97.37,4.53 106.89,14.12
+3VS_TOUCH on BOTTOM (solid shape): 104.56,24.89 104.56,23.73 104.39,23.56 103.51,23.56 103.27,23.81 103.27,24.72 103.66,25.11 104.34,25.11
+3VS_TOUCH on BOTTOM (solid shape): 98.7,12.21 98.7,10.81 98.25,10.37 98.25,8.97 98.13,8.84 97.68,8.84 97.49,9.04 97.49,12.15 97.68,12.34 98.57,12.34
+3VS_WLAN_NGFF on TOP (solid shape): 47.9,108.6 47.9,105.75 47.84,105.68 45.93,105.68 45.61,106 43.09,106 41.9,107.18 41.9,108.4 42.36,108.86 47.65,108.86
+3VS_WLAN_NGFF on TOP (solid shape): 62.07,108.63 62.07,106.76 61.42,106.11 61.42,106.04 61.42,106.03 61.26,105.6 61.29,105.14 61.3,105.11 61.23,105.05 59.99,105.05 59.71,105.17 59.43,105.05 59.2,105.05 59.14,105.11 59.14,108.98 59.2,109.05 61.65,109.05
+3VS_WLAN_NGFF on BOTTOM (solid shape): outline of 106 points within 41.85,104.92 63.52,110.06
+5V_AVDD on TOP (solid shape): 17.61,25.55 17.61,24.15 17.48,24.02 16.91,24.02 16.47,24.47 16.47,25.48 16.59,25.61 17.55,25.61
+5V_AVDD on TOP (solid shape): 26.25,24.47 26.25,23.51 25.59,22.85 25.56,22.87 25.43,22.89 25.31,22.86 25.3,22.85 24.77,22.85 24.74,22.82 24.73,22.82 24.02,22.12 24.02,21.29 23.96,21.23 22.65,21.23 22.44,21.29 22.22,21.23 21.36,21.23 21.23,21.35 21.23,22.12 21.36,22.24 23.45,22.24 24.51,23.3 25.12,23.3 25.13,23.3 25.23,23.28 25.33,23.3 25.34,23.3 25.59,23.3 25.7,23.41 25.71,23.41 25.99,23.69 25.99,23.7 26.06,23.77 26.06,24.47 26.12,24.53 26.18,24.53
+5V_HDD on TOP (solid shape): 194.46,18.62 195.98,18.62 196.11,18.5 196.11,17.67 195.98,17.54 195.16,17.54 195.03,17.42 195.03,16.21 195.28,15.96 195.28,14.5 196.04,13.73 196.04,12.46 195.85,12.27 195.54,12.27 195.54,12.85 194.97,12.85 194.97,12.27 194.71,12.27 194.71,12.85 194.14,12.85 194.14,12.34 193.31,12.34 193.12,12.53 193.12,17.23 192.98,17.37 192.98,17.44 192.91,17.44 192.43,17.93 192.43,18.15 193.05,18.15 193.05,18.1 193.06,18.05 193.07,17.99 193.1,17.95 193.13,17.9 193.16,17.86 193.21,17.83 193.25,17.8 193.3,17.78 193.35,17.77 193.41,17.77 193.46,17.77 193.51,17.78 193.56,17.8 193.61,17.83 193.65,17.86 193.68,17.9 193.71,17.95 193.74,17.99 193.75,18.05 193.76,18.1 193.76,18.15 193.75,18.2 193.74,18.26 193.71,18.3 193.68,18.35 193.65,18.39 193.61,18.42 193.56,18.45 193.51,18.47 193.46,18.48 193.41,18.48 193.35,18.48 193.3,18.47 193.25,18.45 193.21,18.42 193.16,18.39 193.13,18.35 193.1,18.3 193.07,18.26 193.06,18.2 193.05,18.15 192.43,18.15 192.43,18.69 192.68,18.94 194.14,18.94
+5V_HDD on BOTTOM (solid shape): 194.82,17.62 194.82,15.21 195.54,14.5 195.54,13.73 195.35,13.54 193.25,13.54 193,13.8 193,17.4 193.3,17.71 194.74,17.71
+5V_HDMI on TOP (solid shape): 25.86,93.9 25.86,93.11 25.61,92.86 25.36,92.86 24.31,93.91 23.52,93.91 23.36,94.06 23.36,94.69 23.45,94.78 24.99,94.78
+5V_HDMI on TOP (solid shape): 16.75,91.04 17.27,91.04 17.55,90.77 17.55,89.17 17.42,89.05 16.4,89.05 16.15,89.3 16.15,90.12 15.9,90.38 14.5,90.38 14.24,90.63 14.24,91.65 14.5,91.9 15.89,91.9
+5V_HDMI on IN1 (solid shape): 16.55,91.48 16.55,90.76 16.38,90.59 11.85,90.59 11.61,90.83 11.61,92.12 11.78,92.28 15.75,92.28
+5V_PVDD on TOP (solid shape): 35.52,26.56 37.55,26.56 37.68,26.43 37.68,25.35 37.55,25.23 36.66,25.23 36.15,25.74 35.14,25.74 34.37,26.5 30.69,26.5 30.61,26.5 30.56,26.55 30.56,26.67 30.64,26.75 35.33,26.75
+5V_PVDD on TOP (solid shape): 36.86,33.09 36.86,32.94 36.94,32.86 38.29,32.86 38.35,32.8 38.35,32.06 38.31,32.02 35.01,32.02 34.69,31.7 34.69,31.2 33.1,29.61 32.6,29.61 31.45,28.47 30.64,28.47 30.56,28.54 30.56,28.65 30.63,28.72 31.45,28.72 32.02,29.29 32.02,29.51 32.38,29.86 32.38,29.95 32.54,30.12 32.72,30.12 32.85,30.24 32.85,30.69 33.1,30.94 33.61,30.94 33.99,31.32 33.99,32.28 34.88,33.17 35.61,33.17 35.72,33.28 36.67,33.28
+5V_PVDD on BOTTOM (solid shape): 36.89,33.32 36.89,32.35 37.93,31.31 37.93,31.31 38.31,30.93 38.31,25.67 37.8,25.16 37.17,25.16 36.28,26.05 35.2,26.05 34.95,26.31 34.95,27.07 36.85,28.97 36.85,30.59 35.57,31.87 35.57,33.27 35.85,33.55 36.66,33.55
+5V_USB_PWR1 on TOP (solid shape): 21.74,45.61 21.74,43.13 21.42,42.82 17.93,42.82 15.9,40.79 14.68,40.79 14.12,41.34 14.12,43.77 16.02,45.67 21.67,45.67
+5V_USB_PWR1 on TOP (solid shape): 21.74,65.49 21.74,63.2 21.29,62.76 16.97,62.76 16.78,62.57 14.88,62.57 14.83,62.61 14.44,62.61 14.05,63 14.05,65.17 14.5,65.61 21.61,65.61
+5V_USB_PWR1 on BOTTOM (solid shape): 24.21,63.9 24.21,60.34 23.83,59.96 23.83,57.04 24.21,56.66 24.21,43.39 23.9,43.07 20.72,43.07 20.21,43.58 20.21,54.69 20.37,54.85 20.41,54.83 20.94,55.05 20.57,55.49 20.5,55.52 20.47,55.59 20.47,60.85 19.32,61.99 19.32,64.41 19.64,64.72 23.39,64.72
+5V_USB_PWR2 on TOP (solid shape): 174.91,16.96 175.58,16.96 175.85,16.69 175.85,15.51 175.6,15.26 174.11,15.26 171.85,17.51 171.85,18.43 172.04,18.62 173.25,18.62
+5V_USB_PWR2 on BOTTOM (solid shape): 174.11,18.05 174.11,17.05 174.31,16.85 174.47,16.85 174.5,16.83 174.57,16.83 174.63,16.83 174.7,16.83 174.73,16.85 175.47,16.85 175.5,16.83 175.57,16.83 175.63,16.83 175.7,16.83 175.73,16.85 175.82,16.85 176.01,16.66 176,16.6 175.99,16.55 175.98,16.49 175.99,16.44 176,16.38 176.02,16.33 176.05,16.29 176.06,16.26 176.06,15.28 175.78,15 171.85,15 170.23,16.62 171.3,16.62 171.3,16.56 171.31,16.51 171.33,16.46 171.35,16.41 171.38,16.37 171.42,16.33 171.46,16.3 171.51,16.27 171.56,16.25 171.61,16.24 171.66,16.23 171.71,16.24 171.77,16.25 171.82,16.27 171.86,16.3 171.9,16.33 171.94,16.37 171.97,16.41 171.99,16.46 172.01,16.51 172.02,16.56 172.02,16.62 172.01,16.67 171.99,16.72 171.97,16.77 171.94,16.81 171.9,16.85 171.86,16.89 171.82,16.91 171.77,16.93 171.71,16.94 171.66,16.95 171.61,16.94 171.56,16.93 171.51,16.91 171.46,16.89 171.42,16.85 171.38,16.81 171.35,16.77 171.33,16.72 171.31,16.67 171.3,16.62 170.23,16.62 170.2,16.64 170.2,18.18 170.34,18.32 173.84,18.32
+5VALW on TOP (solid shape): 23.01,71.01 23.01,68.03 22.75,67.77 22.75,67.01 22.56,66.82 20.59,66.82 20.53,66.88 20.53,67.77 20.34,67.96 20.34,71.01 20.47,71.14 22.88,71.14
+5VALW on TOP (solid shape): 57.74,127.79 57.74,127.21 56.47,125.94 56.03,125.94 55.64,125.56 55.64,125.37 55.52,125.25 55.45,125.25 55.39,125.31 55.39,126.33 55.52,126.45 55.52,127.79 55.58,127.85 57.68,127.85
+5VALW on TOP (solid shape): 161.56,36.21 161.56,35.01 161.44,34.88 160.93,34.88 160.1,34.05 160.1,33.36 160.04,33.29 159.91,33.29 159.85,33.36 159.85,34.44 160.42,35.01 160.42,36.15 160.55,36.28 161.5,36.28
+5VALW on TOP (solid shape): outline of 746 points within 158.14,9.04 192.62,32.91
+5VALW on BOTTOM (solid shape): 161.86,35.65 161.86,34.64 161.78,34.56 160.31,34.56 160.19,34.69 160.19,35.7 160.4,35.91 161.6,35.91
+5VALW on BOTTOM (solid shape): 21.55,103.33 21.55,101.68 21.1,101.24 19.51,101.24 19.32,101.43 19.32,103.08 19.71,103.46 21.42,103.46
+5VALW on BOTTOM (solid shape): 161.88,13.16 161.88,12.21 161.95,12.15 162.2,11.89 162.2,10.94 162.07,10.81 161.19,10.81 161.12,10.81 160.55,10.24 158.58,10.24 158.07,10.75 158.07,13.1 158.26,13.29 161.75,13.29
+5VALW on IN1 (solid shape): 22.25,71.84 22.25,69.11 21.86,68.73 20.09,68.73 19.9,68.92 19.9,72.09 19.96,72.15 21.93,72.15
+5VALW on IN1 (solid shape): 22.31,103.71 22.31,102.32 21.93,101.94 19.77,101.94 19.58,102.13 19.58,103.52 19.96,103.9 22.12,103.9
+5VALW on VCC: 36.34,1.27 36.34,35.56 28.09,43.81 28.09,61.85 27.3,62.63 21.33,62.63 20.34,63.62 20.34,71.54 20.57,71.77 31.03,71.77 33.17,69.64 33.17,46.59 40.66,39.09 40.66,8.68 45,4.34 131.32,4.34 139.7,12.72 163.47,12.72 163.47,7.62 162.6,6.75 159.93,6.75 158.9,5.71 158.9,1.27
+5VALWP on TOP (solid shape): 191.6,38.63 191.6,35.13 192.3,34.44 193.57,34.44 193.63,34.37 193.63,32.72 193.5,32.59 191.79,32.59 191.22,33.17 190.33,33.17 190.33,32.66 189.95,32.66 189.95,33.17 189.06,33.17 189.06,32.66 188.74,32.66 188.74,33.17 187.92,33.17 187.88,33.21 187.87,33.22 187.79,33.35 187.65,33.44 187.64,33.44 187.6,33.48 187.6,34.15 187.6,34.16 187.64,34.31 187.6,34.46 187.6,34.47 187.6,34.7 187.6,38.04 187.6,38.05 187.35,38.31 187.35,38.56 187.54,38.75 191.47,38.75
+5VALWP on BOTTOM (solid shape): 191.66,38.44 191.66,34.24 191.54,34.12 188.04,34.12 187.85,34.31 187.85,37.55 187.35,38.05 187.35,38.56 187.47,38.69 191.41,38.69
+5VALWP on BOTTOM (solid shape): 196.62,35.96 196.62,33.93 196.55,33.86 195.98,33.86 195.92,33.93 195.92,34.75 196.36,35.2 196.36,35.96 196.43,36.02 196.55,36.02
+5VS on TOP (solid shape): 17.61,27.51 17.61,26.37 17.48,26.24 16.53,26.24 16.34,26.43 16.34,27.51 16.47,27.64 17.48,27.64
+5VS on TOP (solid shape): 38.44,35.2 38.44,33.86 38.31,33.74 36.91,33.74 36.79,33.86 36.79,35.26 36.85,35.32 38.31,35.32
+5VS on TOP (solid shape): 125.24,11.26 125.24,9.89 124.99,9.64 123.32,9.64 123.02,9.93 123.02,11.45 123.27,11.7 124.8,11.7
+5VS on TOP (solid shape): 229.95,36.47 229.95,34.69 229.89,34.63 228.94,34.63 228.87,34.69 228.87,36.47 228.94,36.53 229.89,36.53
+5VS on TOP (solid shape): 49.98,14.01 50.96,14.01 51.24,13.73 51.24,13.1 50.92,12.78 48.4,12.78 48.17,13.01 48.17,13.77 48.43,14.02 49.97,14.02
+5VS on TOP (solid shape): 163.44,5.96 165.6,5.96 165.61,5.94 166.84,5.94 167.33,5.45 167.33,2.89 166.75,2.3 166.09,2.3 165.01,3.38 159.34,3.38 158.77,3.96 158.77,5.67 159.09,5.99 163.41,5.99
+5VS on TOP (solid shape): 93.88,7.02 93.88,5.82 93.88,5.82 93.88,5.51 93.73,5.35 92.52,5.35 92.35,5.52 92.35,6.06 92.35,6.06 92.35,6.83 92.75,7.23 93.68,7.23
+5VS on TOP (solid shape): 20.84,91.03 20.84,89.37 20.71,89.24 19.99,89.24 19.98,89.24 19.83,89.27 19.68,89.24 19.67,89.24 19.2,89.24 19.07,89.36 19.07,91.14 19.13,91.2 20.67,91.2
+5VS on TOP (solid shape): 194.52,12.08 195.16,12.08 195.16,12.65 195.35,12.65 195.35,12.08 196.17,12.08 196.43,12.34 197.7,12.34 197.76,12.27 197.76,9.86 197.57,9.67 193.25,9.67 193.12,9.8 193.12,11.96 193.25,12.08 194.33,12.08 194.33,12.65 194.52,12.65
+5VS on TOP (solid shape): 164.49,60.26 164.49,60.12 164.47,60.1 163.57,60.1 163.49,60.02 163.48,60.01 163.42,59.97 163.37,59.9 163.37,59.89 163.29,59.82 163.29,59.09 162.71,58.5 162.71,57.04 162.58,56.91 161.44,56.91 161.31,57.04 161.31,58.95 161.63,59.26 162.36,59.26 163.41,60.31 164.44,60.31
+5VS on TOP (solid shape): 202.01,49.8 202.01,44.15 201.82,43.96 200.62,43.96 200.08,44.5 200.03,44.56 199.97,44.6 199.66,44.91 199.66,46.21 199.86,46.53 199.66,46.85 199.66,46.95 199.68,46.96 199.72,47.02 199.75,47.09 200.3,47.64 200.3,48.28 199.73,48.28 199.73,48.47 200.3,48.47 200.3,49.1 199.79,49.1 199.79,49.29 200.3,49.29 200.3,49.87 200.36,49.93 201.89,49.93
+5VS on BOTTOM (solid shape): 183.47,51.9 183.47,51.52 183.34,51.39 183.34,48.6 183.28,48.53 182.65,48.53 182.52,48.66 182.52,49.92 182.52,50.06 182.39,50.18 182.01,50.18 181.69,50.5 181.69,50.51 181.51,50.69 181.51,50.69 181.3,50.9 181.3,51.87 181.69,52.27 181.69,52.47 181.95,52.72 182.65,52.72
+5VS on BOTTOM (solid shape): 120.99,14.12 120.99,13.8 122.64,12.15 123,12.15 123.21,12.08 123.42,12.15 123.65,12.15 123.75,12.05 123.75,10.84 124.16,10.43 124.16,10.18 124.04,10.05 122.5,10.05 122.15,10.4 120.51,10.4 119.65,11.26 119.65,14.43 119.72,14.5 120.61,14.5
+5VS on BOTTOM (solid shape): 191.23,12.18 192.47,12.18 192.47,12.53 196.3,12.53 196.55,12.27 196.55,9.8 196.36,9.61 174.58,9.61 166.52,1.54 165.95,1.54 165.88,1.48 158.83,1.48 158.39,1.92 158.39,5.42 158.45,5.48 159.02,5.48 159.02,5.99 159.21,5.99 159.21,5.48 159.85,5.48 159.85,6.05 160.04,6.05 160.04,5.48 163.6,5.48 163.6,5.99 163.98,5.99 163.98,5.48 164.74,5.48 164.74,5.99 165.12,5.99 165.12,5.48 166.14,5.48 173.18,12.53 191.23,12.53
+5VS on IN1 (solid shape): 17.88,28.87 17.88,27.25 17.61,26.98 16.5,26.98 16.19,27.28 16.19,28.79 16.45,29.04 17.71,29.04
+5VS on IN1 (solid shape): 39.2,36.09 39.2,34.33 38.68,33.81 36.82,33.81 36.47,34.16 36.47,36.01 36.71,36.26 39.03,36.26
+5VS on IN1 (solid shape): 50.27,13.84 50.27,12.9 50.04,12.67 48.44,12.67 48.29,12.82 48.29,13.55 48.81,14.07 50.04,14.07
+5VS on IN1 (solid shape): 20.84,90.25 20.84,89.37 20.72,89.25 19.97,89.25 19.96,89.25 19.83,89.27 19.71,89.25 19.7,89.25 19.67,89.25 19.58,89.17 19.54,89.12 19.26,88.84 19.26,87.14 19.02,86.9 18.39,86.9 18.16,87.13 18.16,89.56 19.01,90.4 20.68,90.4
+5VS on IN2 (solid shape): 95.37,7.42 95.37,6.53 95.04,6.21 92.6,6.21 92.41,6.4 92.41,7.32 92.67,7.57 95.21,7.57
+5VS on IN2 (solid shape): 124.46,11.11 124.46,10.67 123.72,9.93 121.97,9.93 121.71,10.18 121.71,10.96 122.16,11.41 123.12,11.41 123.15,11.43 124.14,11.43
+5VS on VCC: 159.41,1.27 159.41,5.5 160.15,6.24 162.81,6.24 163.98,7.41 163.98,12.72 200.15,12.72 200.79,13.35 220.47,13.35 221.76,14.64 221.76,21.5 227.1,26.84 227.1,41.91 226.69,42.31 223.43,42.31 222.65,41.53 222.65,36.95 221.91,36.21 216.45,36.21 215.88,35.64 208.28,35.64 206.82,37.1 202.44,37.1 201.67,37.86 187.73,37.86 187.73,40.49 188.09,40.85 189.74,40.85 190.08,41.19 190.08,42.92 189.55,43.45 186.56,43.45 184.66,45.36 182.24,45.36 181.5,46.1 181.5,51.45 183.18,51.45 189.27,45.36 192.95,45.36 194.46,43.85 194.46,42.33 194.86,41.93 197.99,41.93 198.78,42.71 198.78,44.62 199.9,45.74 201.59,45.74 205.27,42.06 207.67,42.06 207.67,39.41 208.83,38.25 210.44,38.25 213.25,41.06 213.25,46.01 213.87,46.63 223.01,46.63 223.79,47.41 223.79,54.23 230.63,54.23 230.63,20.81 228.84,20.81 228.82,20.8 226.33,18.04 228.82,15.28 228.84,15.27 230.63,15.27 230.63,9.57 177.74,9.57 177.72,9.55 176.4,8.91 175.75,7.58 175.73,7.56 175.73,1.27
+5VS_KBL on BOTTOM (solid shape): outline of 85 points within 115.78,8.08 119.21,14.5
+5VS_ODD on TOP (solid shape): 193.63,51.33 195.41,51.33 196.24,50.5 200.05,50.5 200.11,50.44 200.11,49.55 200.05,49.48 199.54,49.48 199.54,48.91 200.05,48.91 200.05,48.72 199.54,48.72 199.54,48.09 199.98,48.09 199.98,47.64 199.85,47.52 199.57,47.52 199.56,47.52 199.41,47.55 199.26,47.52 199.25,47.52 196.55,47.52 196.24,47.83 195.35,47.83 195.22,47.96 195.22,49.36 194.97,49.61 194.39,49.61 194.27,49.48 193.84,49.48 193.82,49.51 193.74,49.63 193.61,49.7 193.6,49.7 192.68,50.63 192.68,51.33 192.93,51.58 193.38,51.58
+5VS_ODD on BOTTOM (solid shape): 197.82,51 197.82,47.14 197.63,46.92 195.31,46.92 195.09,47.14 195.09,50.9 195.36,51.17 197.65,51.17
+17.4V_BATT+ on BOTTOM (solid shape): 218.14,26.05 218.14,22.69 218.33,22.5 218.33,21.86 218.21,21.74 217.63,21.74 217.29,21.39 212.08,21.39 211.67,20.97 210.21,20.97 210.21,21.42 209.57,21.42 209.57,20.91 209.38,20.91 209.38,21.42 208.81,21.42 208.81,20.91 207.73,20.91 207.6,21.04 207.6,21.86 207.35,22.12 206.52,22.12 206.4,22.24 206.4,23.77 206.65,24.02 211.6,24.02 213,25.42 214.27,25.42 214.33,25.35 214.33,23.83 215.09,23.83 215.09,25.42 215.92,26.24 217.95,26.24
+17.4V_BATT++ on BOTTOM (solid shape): 209.19,20.66 209.76,20.66 209.76,21.23 210.01,21.23 210.01,20.66 211.67,20.66 211.86,20.47 211.86,19.51 212.3,19.07 212.3,16.66 212.17,16.53 207.18,16.53 206.46,17.25 206.46,20.08 206.52,20.15 207.35,20.15 207.86,20.66 209,20.66 209,21.23 209.19,21.23
+19V_ADPIN on TOP (solid shape): 161.53,124.76 161.53,120.56 161.29,120.32 161.28,120.29 161.27,120.27 161.17,120.17 159.89,120.17 159.86,120.2 159.86,120.73 159.39,120.73 159.39,120.72 159.3,120.72 159.3,120.21 159.09,120.21 159.09,120.73 158.59,120.73 158.59,120.72 158.53,120.72 158.53,120.2 158.52,120.19 158.2,120.19 158.16,120.22 158.16,120.78 157.22,121.72 157.22,124.64 157.68,125.1 161.18,125.1
+19V_VIN on TOP (solid shape): 158.87,120.02 159.5,120.02 159.5,120.6 159.69,120.6 159.69,120.02 160.42,120.02 160.81,119.63 160.81,116.92 160.28,116.39 156.95,116.39 156.48,116.86 156.48,119.93 156.58,120.02 158.67,120.02 158.67,120.6 158.87,120.6
+19V_VIN on BOTTOM (solid shape): 159.39,118.22 159.39,117.96 159.39,117.63 159.39,114.25 159.39,113.58 158.54,112.73 157.53,112.73 156.97,112.17 154.57,112.17 154.18,112.56 154.18,117.55 155.39,118.76 158.85,118.76
+19VB on TOP (solid shape): 171.6,134.38 171.6,131.84 170.71,130.96 167.66,130.96 167.34,131.27 167.34,134.13 167.79,134.57 171.41,134.57
+19VB on TOP (solid shape): 175.94,55.7 175.94,54.52 175.87,54.46 173.9,54.46 173.63,54.72 173.63,56.63 173.85,56.85 174.79,56.85
+19VB on TOP (solid shape): 224.18,53.8 224.18,48.21 224.16,48.2 222.98,48.2 222.84,48.34 222.84,49.42 222.33,49.93 221.03,49.93 220.78,49.99 220.53,49.93 220.11,49.93 219.92,50.12 219.92,53.49 220.49,54.06 223.92,54.06
+19VB on TOP (solid shape): 164.23,40.85 164.23,40.12 163.54,39.43 163.54,39.27 163.34,39.07 159.66,39.07 159.41,38.82 159.4,38.81 159.21,38.69 159.09,38.51 159.09,38.5 158.9,38.31 158.39,38.31 158.14,38.56 158.14,40.79 158.71,41.36 163.72,41.36
+19VB on TOP (solid shape): 197.13,43.14 197.13,42.71 196.98,42.56 196.31,42.56 196.17,42.42 196.17,41.55 196.87,40.85 204.04,40.85 204.53,40.66 205.03,40.84 205.05,40.85 205.18,40.85 205.27,40.81 205.36,40.79 205.37,40.79 205.65,40.51 205.65,40.48 205.81,40.01 206.28,39.85 206.31,39.85 206.71,39.45 206.71,38.91 206.7,38.89 206.53,38.49 206.71,38.09 206.71,36.59 207.09,36.21 207.09,31.83 206.84,31.58 202.9,31.58 202.52,31.96 202.52,36.02 202.65,36.15 203.02,36.15 203.16,36.15 203.28,36.28 203.28,37.09 203.28,38.63 202.92,38.99 201.4,38.99 201.06,39.32 200.99,39.33 199.8,39.33 199.8,39.32 196.26,39.32 196.06,39.41 195.85,39.44 195.53,39.44 195.52,39.45 195.32,39.54 195.11,39.58 195.09,39.58 194.71,39.96 194.71,40.59 194.71,40.61 194.71,41.98 194.71,42 194.71,43.83 194.84,43.96 196.31,43.96
+19VB on BOTTOM (solid shape): 173.44,134.19 173.44,132.23 172.87,131.65 169.63,131.65 169.18,132.1 169.18,134.26 169.31,134.38 173.25,134.38
+19VB on BOTTOM (solid shape): 159.41,39.77 159.41,37.74 159.28,37.61 156.74,37.61 156.67,37.67 156.67,38.75 156.17,38.75 156.17,38.94 156.67,38.94 156.67,39.58 156.17,39.58 156.17,39.77 156.67,39.77 156.67,40.72 156.8,40.85 158.33,40.85
+19VB on BOTTOM (solid shape): 121.49,130.81 121.49,129.67 121.38,129.56 119.3,129.56 118.35,128.61 114,128.61 113.49,129.11 113.49,130.06 113.67,130.24 113.81,130.24 113.95,130.26 115.21,130.26 115.83,130.88 121.43,130.88
+19VB on BOTTOM (solid shape): 67.25,133.94 67.25,131.84 66.81,131.4 66.17,131.4 66.17,130.89 65.98,130.89 65.98,131.4 65.35,131.4 65.35,130.83 65.16,130.83 65.16,131.4 64.4,131.4 63.51,132.29 63.51,133.24 63.54,133.27 63.54,134.03 63.76,134.26 66.94,134.26
+19VB on BOTTOM (solid shape): 169.06,81.23 169.06,73.93 168.8,73.68 164.61,73.68 164.49,73.81 164.49,74.95 163.98,74.95 163.98,75.14 164.49,75.14 164.49,75.77 163.91,75.77 163.91,75.96 164.42,75.96 164.49,76.03 164.49,77.91 164.57,78.09 164.6,78.28 164.6,78.3 165.06,78.75 165.21,78.97 165.28,79.22 165.28,79.23 165.5,79.46 165.5,81.3 165.76,81.55 168.74,81.55
+19VB on BOTTOM (solid shape): 199.72,45.14 199.95,44.95 200.24,45 200.32,45.01 200.38,44.97 200.58,44.82 200.83,44.84 200.86,44.86 200.95,44.77 200.91,44.73 200.9,44.72 200.75,44.23 201.26,44.11 201.34,44.12 201.4,44.08 201.56,43.95 201.76,43.93 201.79,43.93 203.39,42.33 203.38,42.3 203.48,41.99 203.8,41.89 203.83,41.89 205.7,40.02 206.59,40.02 207.09,39.52 207.09,37.8 207.67,37.8 207.67,37.42 207.09,37.42 207.09,36.59 207.6,36.59 207.6,36.21 207.09,36.21 207.09,35.45 206.9,35.26 204.11,35.26 203.79,35.58 203.79,38.69 200.05,42.44 199.35,42.44 199.35,41.86 199.16,41.86 199.16,42.44 198.58,42.44 198.58,41.86 198.33,41.86 198.33,42.44 196.62,42.44 196.36,42.18 195.43,42.18 194.91,42.69 194.91,42.71 194.88,42.87 194.79,43.01 194.79,44.61 195.35,45.17 199.71,45.17
+19VB on BOTTOM (solid shape): 177.19,64.15 177.19,57.36 176.93,57.1 176.93,54.59 176.89,54.51 176.79,54.5 176.63,54.52 176.47,54.46 176.34,54.3 176.32,54.09 176.3,54 176.22,53.97 174.85,53.97 174.85,53.41 174.6,53.41 174.6,53.96 174.05,53.96 174.05,53.41 173.8,53.41 173.8,53.97 173.26,53.97 173.19,54 173.16,54.07 173.07,54.3 172.85,54.41 172.8,54.42 172.8,55.45 172.87,55.52 173.18,55.52 173.44,55.77 173.44,58.96 173.75,59.49 173.58,60.07 173.63,60.38 173.55,60.69 173.5,60.8 173.44,60.91 173.44,61.48 173.65,61.87 173.51,62.29 173.6,62.77 173.38,63.2 173.05,63.54 173.04,63.56 173.01,63.75 172.93,63.92 172.93,64.53 173.69,65.3 176.04,65.3
+19VB on BOTTOM (solid shape): outline of 148 points within 156.29,99.65 168.74,115.02
+19VB on IN1 (solid shape): 168.68,113.24 168.68,110.83 168.49,110.64 167.22,110.64 166.96,110.89 166.96,113.3 167.09,113.43 168.49,113.43
+19VB on IN1 (solid shape): 172.23,134.19 172.23,131.08 171.91,130.76 169.37,130.76 168.99,131.15 168.99,134.07 169.31,134.38 172.04,134.38
+19VB on TOP: outline of 111 points within 62.5,111.89 155.41,137.18
+19VB on VCC: 195.07,42.44 194.97,42.54 194.97,44.07 193.17,45.87 189.48,45.87 183.39,51.96 181.5,51.96 181.5,53.46 180.97,53.99 174.88,53.99 174.39,54.48 174.39,56.81 178.96,61.38 178.96,62.3 182.17,59.36 185.71,56.82 186.21,55.26 186.23,55.25 186.57,54.75 187.04,54.37 187.05,54.34 187.29,54.24 193.69,51.55 193.94,51.45 193.96,51.46 194.56,51.39 195.16,51.5 195.19,51.49 195.42,51.61 196.65,52.22 200.69,51.49 204.79,51.23 204.79,51.23 206.31,51.23 206.31,51.23 213.66,52.01 220.7,54.23 223.29,54.23 223.29,47.62 222.8,47.14 213.66,47.14 209.97,43.45 209.21,43.45 208.32,42.56 205.48,42.56 201.8,46.25 199.69,46.25 198.27,44.83 198.27,42.92 197.78,42.44
+19VB_1.2V on BOTTOM (solid shape): 81.43,109.09 81.43,107.08 81.24,106.89 81.24,105.24 81.05,105.05 81.05,103.27 80.98,103.21 78.57,103.21 78.44,103.33 78.44,103.84 78.51,103.9 78.69,103.9 78.7,103.9 78.8,103.89 78.9,103.9 78.91,103.9 79.08,103.9 79.2,104.03 79.2,105.69 78.32,106.58 78.32,109.05 78.63,109.36 80.34,109.36 80.39,109.42 81.1,109.42
+19VB_1.2V on TOP: 76.66,106.44 77,106.11 78.68,106.11 79.18,105.62 79.18,105.01 79.27,104.92 80.03,104.92 80.04,104.93 80.81,104.93 81.01,105.12 81.01,106.37 80.46,106.91 80.46,108.51 80.67,108.72 80.84,108.72 81.11,108.99 81.11,111.16 80.53,111.73 77.18,111.73 76.66,111.22
+19VB_+1.35VGPU on BOTTOM (solid shape): outline of 229 points within 155.53,88.98 159.53,99.97
+19VB_APU on TOP (solid shape): 159.41,67.33 159.41,58.37 159.15,58.12 157.88,58.12 157.82,58.18 157.82,67.39 158.01,67.58 159.15,67.58
+19VB_APU on BOTTOM (solid shape): outline of 159 points within 150.39,51.83 164.29,77.74
+19VB_GPU on TOP (solid shape): 66.89,113.75 66.89,111.97 66.63,111.71 61.87,111.71 61.62,111.97 61.62,113.81 61.68,113.87 66.76,113.87
+19VB_GPU on TOP (solid shape): 62.5,130.19 65.49,130.19 67.08,128.61 67.08,126.95 67.01,126.89 65.43,126.89 65.11,126.57 62.06,126.57 61.81,126.83 61.81,128.35 60.6,129.56 60.6,130.51 60.92,130.83 61.87,130.83
+19VB_GPU on BOTTOM (solid shape): 72.44,131.66 72.44,127.49 71.9,126.95 69.3,126.95 68.96,127.39 68.61,126.95 65.43,126.95 65.11,126.64 63.52,126.64 63.2,126.32 63.2,114.38 63.58,114 67.01,114 67.97,114.95 71.76,114.95 72.07,114.64 72.07,110 71.69,109.62 70.74,109.62 70.73,109.65 70.45,109.87 70.11,109.76 69.97,109.62 67.52,109.62 67.2,109.94 65.3,109.94 63.46,111.78 62.38,111.78 59.96,114.19 59.96,131.72 60.22,131.97 63.6,131.97 64.36,131.21 65.01,131.21 65.01,130.69 65.52,130.69 65.52,131.21 65.81,131.21 65.81,130.69 66.32,130.69 66.32,131.21 66.44,131.21 66.47,131.24 66.91,131.24 67.7,132.03 72.07,132.03
+19VB_VDDP_ALWP on TOP (solid shape): 156.74,41.1 156.74,36.15 156.48,35.9 155.98,35.9 155.85,35.77 155.85,33.86 156.17,33.55 156.17,32.66 156.1,32.59 152.99,32.59 152.86,32.72 151.15,32.72 151.02,32.85 151.02,33.48 151.25,33.7 151.56,33.7 151.79,33.93 151.79,41.17 152.1,41.48 156.36,41.48
+19VB_VDDP_ALWP on BOTTOM (solid shape): 156.48,40.53 156.48,39.96 155.91,39.96 155.91,39.39 156.48,39.39 156.48,39.2 155.91,39.2 155.91,38.56 156.42,38.56 156.42,37.86 156.23,37.67 153.12,37.67 151.84,38.95 151.84,40.66 152.03,40.85 156.17,40.85
+VDD_CT on TOP (solid shape): 108.05,116.22 108.11,116.16 109.63,116.16 109.71,116.09 109.73,116.05 109.75,116.03 109.75,115.52 109.15,114.93 108.91,114.93 108.76,115.08 107.37,115.08 107.24,115.21 107.24,115.52 107.46,115.75 107.46,116.1 107.59,116.22 108.03,116.22
+VDD_CT on BOTTOM (solid shape): 109.75,115.91 109.75,115.45 109.66,115.22 109.75,114.99 109.75,114.57 109.62,114.45 108.29,114.45 108.22,114.51 108.22,115.02 108.02,115.22 108.03,115.24 107.94,115.53 107.66,115.63 107.64,115.63 107.46,115.8 107.46,116.1 107.53,116.16 109.49,116.16
+VDD_TOUCH on TOP (solid shape): 224.73,32.79 224.75,32.74 224.78,32.69 224.82,32.65 224.86,32.62 224.91,32.59 224.96,32.57 225.01,32.56 225.06,32.55 225.12,32.56 225.17,32.57 225.22,32.59 225.27,32.62 225.31,32.65 225.35,32.69 225.38,32.74 225.4,32.79 225.42,32.85 226.75,32.85 226.84,32.76 226.84,31.13 226.08,30.37 226.08,28.21 225.89,28.02 222.78,28.02 222.71,28.09 222.71,31.32 222.74,31.35 222.74,31.58 224.87,31.58 224.87,31.52 224.88,31.47 224.89,31.42 224.92,31.37 224.95,31.33 224.98,31.29 225.03,31.26 225.07,31.23 225.12,31.21 225.17,31.2 225.23,31.19 225.28,31.2 225.33,31.21 225.38,31.23 225.43,31.26 225.47,31.29 225.51,31.33 225.54,31.37 225.56,31.42 225.57,31.47 225.58,31.52 225.58,31.58 225.57,31.63 225.56,31.68 225.54,31.73 225.51,31.77 225.47,31.81 225.43,31.84 225.38,31.87 225.33,31.89 225.28,31.9 225.23,31.91 225.17,31.9 225.12,31.89 225.07,31.87 225.03,31.84 224.98,31.81 224.95,31.77 224.92,31.73 224.89,31.68 224.88,31.63 224.87,31.58 222.74,31.58 222.74,32.27 223.32,32.85 224.71,32.85
+VDD_TOUCH on BOTTOM (solid shape): 225.95,30.69 225.95,30.12 225.83,29.99 223.67,29.99 223.54,30.12 223.54,30.63 223.6,30.69 224.81,30.69 224.94,30.82 225.83,30.82
+VDDCR_FCH_ALW on TOP (solid shape): 119.28,14.68 119.34,14.68 119.74,14.28 119.74,13.93 121.03,12.65 121.03,9.01 121.03,9.01 121.03,8.94 122.1,7.87 122.1,7.03 123.03,6.1 126.11,6.1 126.31,6.3 128.45,6.3 128.58,6.18 128.58,5.3 128.37,5.08 125.59,5.08 124.79,4.28 123.2,4.28 121.07,6.41 119.93,6.41 119.37,6.97 119.37,8.04 119.63,8.29 119.63,12.08 118.48,13.22 118.48,14.38 118.77,14.68 119.27,14.68
+VDDCR_FCH_ALW on TOP (solid shape): outline of 316 points within 121.94,23.51 133.42,45.74
+VDDCR_FCH_ALW on BOTTOM (solid shape): 122.56,46.06 122.8,45.96 123.04,46.06 123.29,46.06 123.53,45.96 123.77,46.06 124.04,46.06 124.1,45.99 124.1,45.5 124.02,45.37 124.01,45.23 124.01,45.2 123.85,45.04 123.83,45.04 123.68,44.99 123.57,44.87 123.56,44.85 122.19,44.85 122,45.04 122,45.64 122.01,45.65 122.04,45.76 122.04,45.87 122.03,45.89 122.19,46.06
+VDDCR_FCH_ALW on IN1 (solid shape): 120.5,14.44 120.5,14.43 119.61,13.54 119.03,13.54 118.93,13.65 118.93,14.65 119.28,15.01 119.93,15.01
+VDDCR_FCH_ALW on IN1 (solid shape): 127.51,23.74 127.51,22.88 127.39,22.76 126.44,22.76 126.25,22.95 126.25,23.79 126.43,23.98 127.28,23.98
+VDDR3 on TOP (solid shape): 109.42,113.8 109.42,112.37 109.06,112.01 108.52,112.01 108.34,112.19 108.34,112.22 108.24,112.51 107.94,112.61 107.92,112.61 107.18,113.35 107.18,113.53 107.27,113.62 107.45,113.62 107.8,113.26 108.52,113.26 108.7,113.44 108.7,113.8 108.79,113.89 109.33,113.89
+VDDR3 on BOTTOM (solid shape): outline of 491 points within 96.29,112.03 109.88,116.22
GND on TOP (solid shape): 20.34,67.71 20.34,66.25 20.28,66.19 17.04,66.19 16.97,66.25 16.97,67.65 17.1,67.77 20.28,67.77
GND on TOP (solid shape): 20.34,47.9 20.34,46.44 20.28,46.37 17.04,46.37 16.97,46.44 16.97,47.83 17.1,47.96 20.28,47.96
GND on TOP (solid shape): 24.85,70.82 24.85,68.34 24.79,68.28 23.32,68.28 23.26,68.34 23.26,70.82 23.32,70.88 24.79,70.88
GND on TOP (solid shape): 30.5,96.6 30.5,96.03 30.31,95.84 28.28,95.84 27.71,96.41 27.71,97.62 27.83,97.74 29.36,97.74
GND on TOP (solid shape): 63.52,21.04 63.52,17.67 63.33,17.48 62.19,17.48 62.06,17.61 62.06,21.1 62.19,21.23 63.33,21.23
GND on TOP (solid shape): 95.08,131.21 95.08,128.29 94.95,128.16 87.02,128.16 86.95,128.22 86.95,130.32 88.48,131.84 94.44,131.84
GND on TOP (solid shape): 95.84,36.34 95.84,34.88 95.52,34.56 88.09,34.56 87.9,34.75 87.9,36.15 88.16,36.4 95.78,36.4
GND on TOP (solid shape): 143.09,130.26 143.09,128.99 142.7,128.61 133.37,128.61 133.18,128.8 133.18,130.19 133.37,130.38 142.96,130.38
GND on TOP (solid shape): 152.86,130.45 152.86,128.8 152.67,128.61 145.75,128.61 145.37,128.99 145.37,130.19 145.69,130.51 152.8,130.51
GND on TOP (solid shape): 160.55,8.84 160.55,6.75 160.29,6.5 158.9,6.5 158.64,6.75 158.64,8.78 158.77,8.91 160.48,8.91
GND on TOP (solid shape): 177.33,55.18 177.33,53.68 176.91,53.26 176.42,53.26 176.16,53.52 176.16,55.28 176.27,55.39 177.12,55.39
GND on TOP (solid shape): 193.44,37.99 193.44,34.88 193.38,34.82 192.23,34.82 191.85,35.2 191.85,37.93 192.04,38.12 193.31,38.12
GND on TOP (solid shape): 195.85,34.12 195.85,32.72 195.73,32.59 193.89,32.59 193.82,32.66 193.82,34.05 193.95,34.18 195.79,34.18
GND on TOP (solid shape): 197.54,42.22 197.54,41.69 197.37,41.52 196.44,41.52 196.32,41.64 196.32,42.33 196.38,42.39 197.37,42.39
GND on TOP (solid shape): 114.05,41.64 114.05,40.15 113.93,40.02 113.18,40.02 113.18,40.04 113.06,40.15 113.06,41.57 113.21,41.72 113.97,41.72
GND on TOP (solid shape): 35.6,99.4 36.17,99.4 36.34,99.23 36.34,97.24 36.22,97.11 35.07,97.11 35.01,97.17 35.01,99.33 35.07,99.4 35.6,99.4
GND on TOP (solid shape): 37.87,16.46 37.87,14.05 37.74,13.92 36.34,13.92 36.22,14.05 36.22,16.66 36.34,16.78 37.55,16.78
GND on TOP (solid shape): 59.08,20.08 59.08,17.16 58.69,16.78 53.3,16.78 51.77,18.31 51.77,19.07 52.09,19.39 56.73,19.39 57.61,20.27 58.88,20.27
GND on TOP (solid shape): 123.53,12.65 123.53,12.21 122.89,11.58 122.89,9.86 123.34,9.42 123.34,9.1 123.08,8.84 121.37,8.84 121.18,9.04 121.18,12.59 121.37,12.78 123.4,12.78
GND on TOP (solid shape): 125.31,25.06 125.31,25.06 125.38,24.98 125.38,24.17 125.28,24.07 124.93,24.07 124.85,24.15 122.59,24.15 122.32,24.42 122.32,24.88 122.59,25.15 125.22,25.15
GND on TOP (solid shape): 180.55,51.26 180.55,49.36 180.49,49.29 179.41,49.29 179.22,49.48 179.22,50.75 179.03,50.95 176.11,50.95 175.98,51.07 175.98,52.28 176.11,52.41 179.41,52.41
GND on TOP (solid shape): 66.25,107.65 68.41,107.65 68.66,107.4 68.66,106.7 68.41,106.44 67.52,106.44 67.27,106.7 63.9,106.7 63.77,106.83 63.77,108.16 63.9,108.29 65.62,108.29
GND on TOP (solid shape): 116.03,41.74 116.03,40.74 116.33,40.45 116.33,38.42 115.99,38.07 115.26,38.07 115.23,38.1 115.23,41.56 115.47,41.8 115.47,41.8 115.6,41.93 115.84,41.93
GND on TOP (solid shape): 165.91,122.12 165.91,119.36 165.65,119.11 162.67,119.11 162.29,119.49 162.29,120.8 163.43,121.94 163.85,121.94 164.4,122.48 165.54,122.48
GND on TOP (solid shape): 91.9,124.35 91.9,121.37 91.21,120.67 87.59,120.67 87.46,120.79 87.46,123.21 87.59,123.33 87.84,123.34 88.09,123.59 88.09,124.35 88.29,124.54 91.71,124.54
GND on TOP (solid shape): 168.42,50.31 168.42,44.47 166.71,44.47 166.71,49.41 166.71,49.48 166.52,49.68 165.25,49.68 164.68,49.1 161.56,49.1 161.5,49.17 161.5,50.56 161.63,50.69 168.04,50.69
GND on TOP (solid shape): 186.52,40.02 186.52,38.94 187.47,37.99 187.47,34.75 187.41,34.69 185.95,34.69 185.88,34.75 185.88,37.99 185.86,38.02 185.86,38.19 185.38,38.67 185.38,40.08 185.45,40.15 186.39,40.15
GND on TOP (solid shape): 72.54,24.72 72.54,23.07 72.35,22.88 71.01,22.88 70.82,22.69 70.82,21.16 70.51,20.85 70.51,18.5 70.31,18.31 69.43,18.31 69.24,18.5 69.24,18.88 69.43,19.07 69.43,24.59 69.68,24.85 72.41,24.85
GND on TOP (solid shape): 93.56,74.12 93.56,73.42 93.68,73.3 94.38,73.3 94.44,73.23 94.44,72.6 94,72.15 94,71.07 93.81,70.88 93.3,70.88 92.54,71.65 90.38,71.65 90.19,71.84 90.19,74.76 90.38,74.95 92.73,74.95
GND on TOP (solid shape): 111.21,113.38 111.21,111.79 111.21,111.71 111.27,111.65 111.27,111.4 111.15,111.27 110.89,111.27 110.45,111.71 110.45,112.15 110.45,112.29 110.26,112.48 109.62,112.48 109.56,112.54 109.56,113.87 109.68,114 110.58,114
GND on TOP (solid shape): 33.87,120.22 33.87,119.53 33.99,119.4 35.39,119.4 35.64,119.14 35.64,117.87 35.52,117.75 34.88,117.75 34.69,117.56 34.69,115.78 34.44,115.52 32.72,115.52 32.66,115.59 32.66,116.29 32.47,116.48 31.96,116.48 31.77,116.67 31.77,119.97 32.15,120.35 33.74,120.35
GND on TOP (solid shape): 110.76,50.56 110.76,50.12 110.5,49.86 110.5,48.97 110.51,48.96 110.51,48.93 110.15,48.57 109.45,48.57 109.14,48.26 109.14,48.24 109.11,48.21 109.11,47.71 108.99,47.58 108.54,47.58 108.48,47.64 108.48,48.48 109.09,49.1 109.09,50.23 109.49,50.63 110.7,50.63
GND on TOP (solid shape): 213.38,35.83 213.38,35.32 213.51,35.2 215.41,35.2 215.48,35.13 215.48,27.32 215.29,27.13 212.3,27.13 212.17,27.26 212.17,29.04 212.36,29.23 213.51,29.23 213.63,29.36 213.63,31.39 212.87,32.15 212.87,35.07 212.68,35.26 212.68,35.83 212.75,35.9 213.32,35.9
GND on TOP (solid shape): 117.94,41.55 117.94,39.9 118.37,39.47 118.37,38.24 118.81,37.8 118.81,36.94 118.65,36.78 118.22,36.78 117.72,37.28 117.72,38.21 117.72,38.21 117.72,39.01 117.34,39.39 117.34,39.74 117.33,39.74 117.33,41.61 117.39,41.67 117.81,41.67
GND on TOP (solid shape): 157.12,35.32 157.12,30.69 154.71,28.28 149.82,28.28 149.37,28.72 149.37,33.61 149.56,33.8 150.77,33.8 150.83,33.74 150.83,32.66 151.02,32.47 152.61,32.47 152.67,32.4 156.23,32.4 156.36,32.53 156.36,33.55 156.34,33.57 156.34,33.6 156.3,33.6 156.1,33.8 156.1,35.39 156.17,35.45 156.99,35.45
GND on TOP (solid shape): 115.35,117.25 115.71,117.25 115.74,117.22 116.43,117.22 116.61,117.04 116.61,116.32 116.87,116.05 116.87,114.79 116.7,114.61 115.8,114.61 115.53,114.34 114.99,114.34 114.81,114.52 114.81,114.96 114.57,115.19 114.57,115.45 114.9,115.78 114.9,116.41 114.9,116.41 114.76,116.54 114.45,116.54 114.32,116.67 114.32,117.07 114.5,117.25 115.35,117.25
GND on TOP (solid shape): 44.47,87.65 44.47,70.88 44.44,70.85 44.44,68.76 43.84,68.15 40.66,68.15 40.53,68.03 40.53,62.95 42.18,61.3 42.18,56.85 42.37,56.66 42.95,56.66 43.07,56.53 43.07,50.69 42.95,50.56 42.95,47.52 42.18,46.75 42.18,41.42 42.06,41.29 41.04,41.29 34.25,48.09 34.25,70.67 34.56,70.99 34.56,71.01 42.82,79.27 42.82,87.46 43.14,87.78 44.34,87.78
GND on TOP (solid shape): 163.09,38.88 163.09,38.33 163.06,38.31 162.86,38.04 162.98,37.72 163.02,37.65 162.99,37.57 162.26,36.85 160.68,36.85 160.23,37.29 160.23,37.73 160.23,37.73 160.23,38.56 160.61,38.94 163.02,38.94
GND on TOP (solid shape): 67.39,126.19 68.47,126.19 68.66,126 68.66,123.08 68.54,122.95 67.33,122.95 67.14,122.76 67.14,120.48 67.27,120.35 68.41,120.35 68.6,120.16 68.6,117.24 68.47,117.11 67.27,117.11 67.08,116.92 67.08,115.14 67.33,114.89 67.9,114.89 68.03,114.76 68.03,113.62 67.9,113.49 67.27,113.49 67.14,113.62 67.14,114.06 67.01,114.19 61.68,114.19 61.49,114.38 61.49,116.86 62,117.37 62,126.07 62.19,126.26 65.11,126.26 65.49,126.64 66.95,126.64
GND on TOP (solid shape): 157.56,67.33 157.56,58.76 157.06,58.25 155.91,58.25 155.79,58.37 151.79,58.37 150.23,59.93 148.01,59.93 147.53,60.41 147.53,63.71 147.66,63.84 148.61,63.84 148.83,63.61 148.83,63.23 149.12,62.95 149.56,62.95 149.69,63.07 149.69,63.29 149.7,63.39 149.69,63.49 149.69,63.93 149.7,64.03 149.69,64.12 149.69,64.28 149.82,64.41 152.74,64.41 152.93,64.22 152.93,62.82 153.06,62.69 154.83,62.69 155.02,62.88 155.02,67.2 155.34,67.52 157.37,67.52
GND on TOP (solid shape): 114.59,53.23 114.59,52.52 114.68,52.43 115.85,52.43 116.31,52.9 116.75,52.9 116.86,52.79 116.86,52.23 116.98,52.11 117.06,52.11 117.06,52.06 117.22,52.06 117.38,51.9 117.38,51.69 117.27,51.58 116.95,51.58 116.7,51.83 114.64,51.83 114.44,51.63 110.85,51.63 110.85,51.64 110.04,51.64 110.04,51.63 109.28,51.63 109.13,51.48 108.74,51.48 108.55,51.67 108.55,52.42 108.71,52.57 110.37,52.57 110.92,53.12 112.32,53.12 112.45,52.99 112.45,52.71 112.62,52.54 113.19,52.54 113.59,52.94 113.88,52.94 114,52.94 114,53.24 114.09,53.33 114.5,53.33
GND on TOP (solid shape): 145.64,66.81 145.64,65.45 145.23,65.04 144.33,65.04 144.32,65.05 144.26,65.05 143.13,65.55 141.9,65.72 141.9,65.71 141.77,65.71 140.61,65.53 139.54,65.05 138.25,65.05 137.73,65.58 137.73,66.5 137.85,66.63 141.49,66.63 142.23,67.38 145.07,67.38
GND on TOP (solid shape): 120.18,56.47 120.18,56.35 120.17,56.26 120.18,56.17 120.18,56.03 120.64,55.57 120.72,55.57 120.78,55.51 120.78,54.66 120.61,54.48 120.15,54.48 120.15,54.47 119.52,54.47 119.51,54.46 119.43,54.46 119.39,54.43 119.37,54.43 119.37,54.4 119.37,54.17 118.93,53.73 118.72,53.73 118.59,53.86 118.59,54.16 119.2,54.77 119.2,54.79 119.21,54.8 119.28,55 119.23,55.2 119.23,55.8 119.3,55.94 119.3,56.1 119.3,56.13 119.34,56.18 119.34,56.6 119.4,56.6 119.46,56.66 119.99,56.66
GND on TOP (solid shape): 120.85,51.22 120.85,49.03 120.61,48.79 119.83,48.79 119.7,48.91 119.7,49.15 119.61,49.24 119.36,49.24 119.36,49.24 119.25,49.26 119.15,49.24 119.14,49.24 117.5,49.24 117.25,49.48 116.03,49.48 115.84,49.29 115.84,48.47 115.08,48.47 114.31,49.24 114.09,49.24 114.08,49.23 113.28,49.23 113.28,49.87 113.43,50.01 113.43,50.58 113.62,50.77 115.11,50.77 115.21,50.67 115.21,50.11 115.27,50.04 115.34,50.04 115.34,50.03 116.05,50.03 116.05,50.04 116.2,50.04 116.2,50.03 116.91,50.03 116.91,50.11 117.06,50.26 117.06,50.69 117.11,50.74 117.42,50.74 117.55,50.88 118.34,50.88 118.51,50.7 118.57,50.64 119.23,50.64 119.35,50.76 119.35,51.21 119.42,51.28 120.79,51.28
GND on TOP (solid shape): 115.78,124.16 115.78,123.14 115.34,122.7 113.69,122.7 113.37,122.38 113.37,120.16 113.69,119.84 114.37,119.84 114.45,119.84 115.08,120.48 115.4,120.48 115.59,120.29 115.59,119.86 115.31,119.58 115.31,119.56 115.27,119.53 115.27,119.48 115.23,119.44 115.27,119.39 115.27,118.95 114.81,118.49 114.43,118.49 114.36,118.56 110.84,118.56 110.76,118.64 110.76,119.26 110.76,119.28 110.68,119.37 110.65,119.37 110.63,119.4 110.47,119.4 110.36,119.51 110.36,119.77 110.81,120.22 111.07,120.48 111.84,120.48 112.16,120.8 112.16,122.07 112.42,122.32 112.42,123.53 112.35,123.59 112.23,123.59 111.59,123.59 111.46,123.72 111.46,124.16 111.59,124.29 115.65,124.29
GND on TOP (solid shape): 44.79,22.75 44.79,22.68 44.79,21.87 44.79,21.86 44.91,21.74 44.93,21.73 45.74,21.73 46.06,21.42 46.06,19.51 46.25,19.32 46.25,19.07 46.06,18.88 45.3,18.88 44.34,19.83 44.34,20.85 43.79,21.4 43.76,21.49 43.81,21.56 43.97,22.02 43.53,22.21 43.43,22.22 43.39,22.31 43.39,23.07 43.52,23.2 44.34,23.2
GND on TOP (solid shape): 116.68,58.8 116.68,58 116.5,57.82 116.14,57.82 115.79,57.48 115.79,57.03 115.79,56.94 115.92,56.81 116.71,56.81 116.78,56.74 116.78,56.08 116.89,55.97 117.27,55.97 117.27,55.98 117.36,55.88 117.36,55.69 117.21,55.54 116.84,55.54 116.84,55.54 116.65,55.54 116.54,55.65 116.01,55.65 115.8,55.44 115.79,55.44 115.76,55.4 115.76,55.14 115.49,54.87 115.19,54.87 114.73,55.34 114.65,55.42 112.79,55.42 112.44,55.07 112.04,55.07 111.93,55.18 111.93,55.46 111.73,55.66 109.56,55.66 109.53,55.68 109.53,56.32 109.6,56.38 110.29,56.38 111.08,57.17 111.8,57.17 111.86,57.23 112.05,57.23 112.83,58.01 113.39,58.01 113.84,57.56 113.85,57.56 113.94,57.47 114.46,57.47 114.99,58.01 115.59,58.01 115.72,58.13 115.72,58.55 116.05,58.88 116.61,58.88
GND on TOP (solid shape): 14.88,32.28 14.88,27.77 13.29,26.18 5,26.18 5,26.19 4.44,26.19 4.44,26.18 2.33,26.18 2.5,26.52 2.55,26.9 2.55,30.17 2.77,30.69 3.3,30.91 12.28,30.91 13.02,31.54 12.53,32.38 12.53,32.91 14.24,32.91
GND on TOP (solid shape): 83.59,107.59 83.59,104.03 81.43,101.87 81.43,100.16 81.05,99.78 77.55,99.78 77.43,99.9 77.43,100.98 77.55,101.11 78.19,101.11 78.32,101.24 78.32,102.82 80.18,104.69 82.28,104.69 82.28,104.64 82.29,104.59 82.3,104.54 82.32,104.49 82.35,104.44 82.39,104.4 82.43,104.37 82.48,104.34 82.53,104.33 82.58,104.31 82.63,104.31 82.69,104.31 82.74,104.33 82.79,104.34 82.83,104.37 82.88,104.4 82.91,104.44 82.94,104.49 82.97,104.54 82.98,104.59 82.99,104.64 82.99,104.69 82.98,104.75 82.97,104.8 82.94,104.84 82.91,104.89 82.88,104.93 82.83,104.96 82.79,104.99 82.74,105.01 82.69,105.02 82.63,105.02 82.58,105.02 82.53,105.01 82.48,104.99 82.43,104.96 82.39,104.93 82.35,104.89 82.32,104.84 82.3,104.8 82.29,104.75 82.28,104.69 80.18,104.69 80.27,104.78 80.95,104.78 81.19,105.02 81.19,106.41 80.6,107 80.6,108.45 80.74,108.59 82.58,108.59
GND on TOP (solid shape): 113.94,61.87 113.94,61.65 113.93,61.64 113.9,61.48 113.93,61.33 113.94,61.32 113.94,61.23 114.16,61.01 114.31,61.01 114.94,60.38 114.97,60.31 114.95,60.24 114.89,60.13 114.86,60.01 114.5,59.64 113.99,59.64 113.21,60.42 113.21,60.63 113.16,61.22 112.63,60.96 112.63,60.94 112.29,60.6 111.53,60.6 111.46,60.66 111.46,61.11 111.53,61.17 112.16,61.17 112.42,61.42 112.42,61.61 112.73,61.93 113.88,61.93
GND on TOP (solid shape): 15.58,53.74 15.58,46.69 13.99,45.1 12.36,45.1 12.34,45.08 12.28,45.09 3.3,45.09 2.77,45.31 2.55,45.83 2.55,51.87 2.77,52.4 3.3,52.61 12.28,52.61 13.02,53.24 12.53,54.08 12.53,54.56 14.75,54.56
GND on TOP (solid shape): 6.1,6.6 1.6,6.6 1.6,7.1 1.89,7.81 2.6,8.1 3.65,8.1 4.6,9.05 3.65,10 2.3,10 1.8,10.21 1.6,10.7 1.6,11.5 6.1,11.5
GND on TOP (solid shape): 115.15,109.62 115.15,109.37 115.21,109.3 116.8,109.3 116.92,109.17 116.92,108.86 117.18,108.6 117.18,107.78 117.4,107.56 117.51,107.56 117.52,107.55 118.05,107.55 118.05,107.56 118.16,107.56 118.16,107.61 118.38,107.84 118.89,107.84 119.65,107.08 119.65,106.57 119.59,106.51 118.94,106.51 118.87,106.54 118.84,106.62 118.49,107.03 118.14,106.62 118.11,106.54 118.04,106.51 117.5,106.51 117.11,106.89 117.11,107.21 116.94,107.38 116.94,107.39 116.81,107.6 116.57,107.68 115.98,107.68 115.95,107.65 115.46,107.65 115.34,107.78 115.34,108.23 115.34,108.59 115.34,108.6 114.76,109.17 114.76,109.37 114.7,109.43 114.7,109.56 114.83,109.68 115.08,109.68
GND on TOP (solid shape): 11.7,80.6 12.75,80.6 13.73,79.62 13.73,79.39 14.69,78.43 14.69,67.26 14.15,66.72 12.58,66.72 12.43,66.77 12.28,66.79 4.3,66.79 3.77,67.01 3.55,67.53 3.55,75.1 3.22,75.95 1.91,76.59 1.71,77.09 1.71,78.25 1.93,78.78 2.46,79 8.24,79 9.08,78.51 9.7,79.25 9.7,81.74 10.56,81.74
GND on TOP (solid shape): 153.62,46.82 153.71,46.75 153.68,46.64 153.56,46.4 153.65,46.14 153.67,46.07 153.64,46 153.86,45.38 154.15,45.97 154.13,46.04 154.16,46.11 154.27,46.38 154.15,46.64 154.13,46.75 154.22,46.82 157.37,46.82 157.5,46.69 157.5,45.48 157.63,45.36 158.08,45.36 158.15,45.29 159.46,45.29 159.52,45.36 159.53,45.36 159.72,45.55 160.99,45.55 161.12,45.42 161.12,45.04 160.93,44.85 160.93,43.87 160.76,43.7 160.73,43.68 160.71,43.68 160.53,43.62 160.41,43.47 160.4,43.44 149.4,43.44 149.38,43.46 148.92,43.46 148.67,43.71 148.67,45.61 148.83,45.77 149.28,45.77 150.32,46.82
GND on TOP (solid shape): 12.1,96.21 13.23,95.08 13.23,93.81 12.91,93.49 10.4,93.49 10.21,93.3 10.21,92.41 9.7,92.41 9.7,94.75 9.08,95.49 8.24,95 1,95 0.47,95.22 0.25,95.75 0.25,96.9 0.47,97.43 1,97.65 1.8,97.65 2.55,97.95 2.85,98.7 2.85,99 2.55,99.75 1.8,100.05 1,100.05 0.47,100.27 0.25,100.8 0.25,101.42 0.47,101.95 1,102.17 5,102.17 5.17,102.1 5.25,101.92 5.25,101.52 5.47,100.99 6,100.77 6.8,100.77 7.33,100.99 7.55,101.52 7.55,101.92 7.63,102.1 7.8,102.17 11.4,102.17 11.51,102.18 11.63,102.2 12.1,102.2
GND on TOP (solid shape): outline of 207 points within 108.1,104.73 116.61,117.05
GND on TOP (solid shape): outline of 1807 points within 0.25,0.25 231.65,138.25
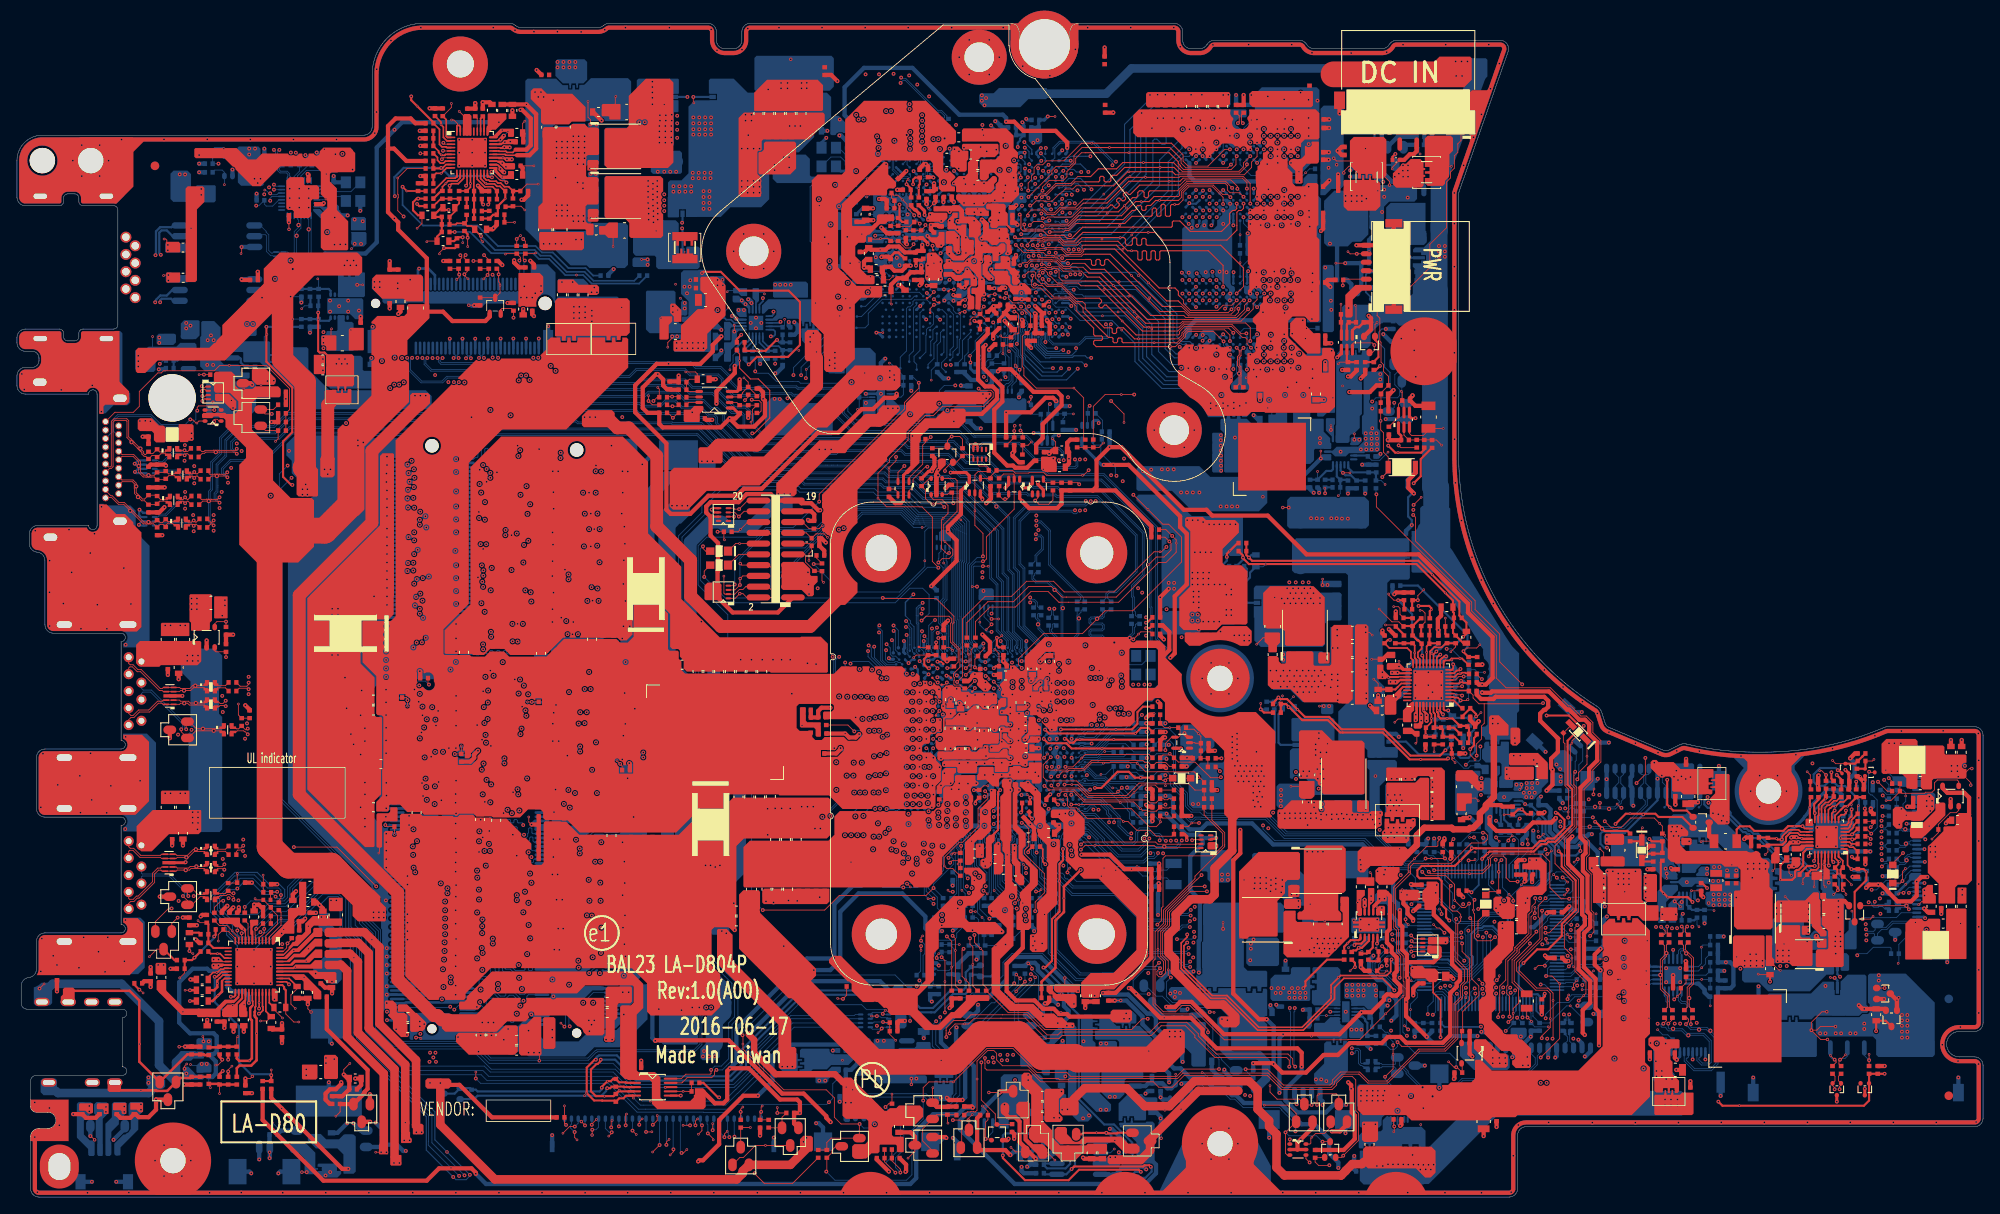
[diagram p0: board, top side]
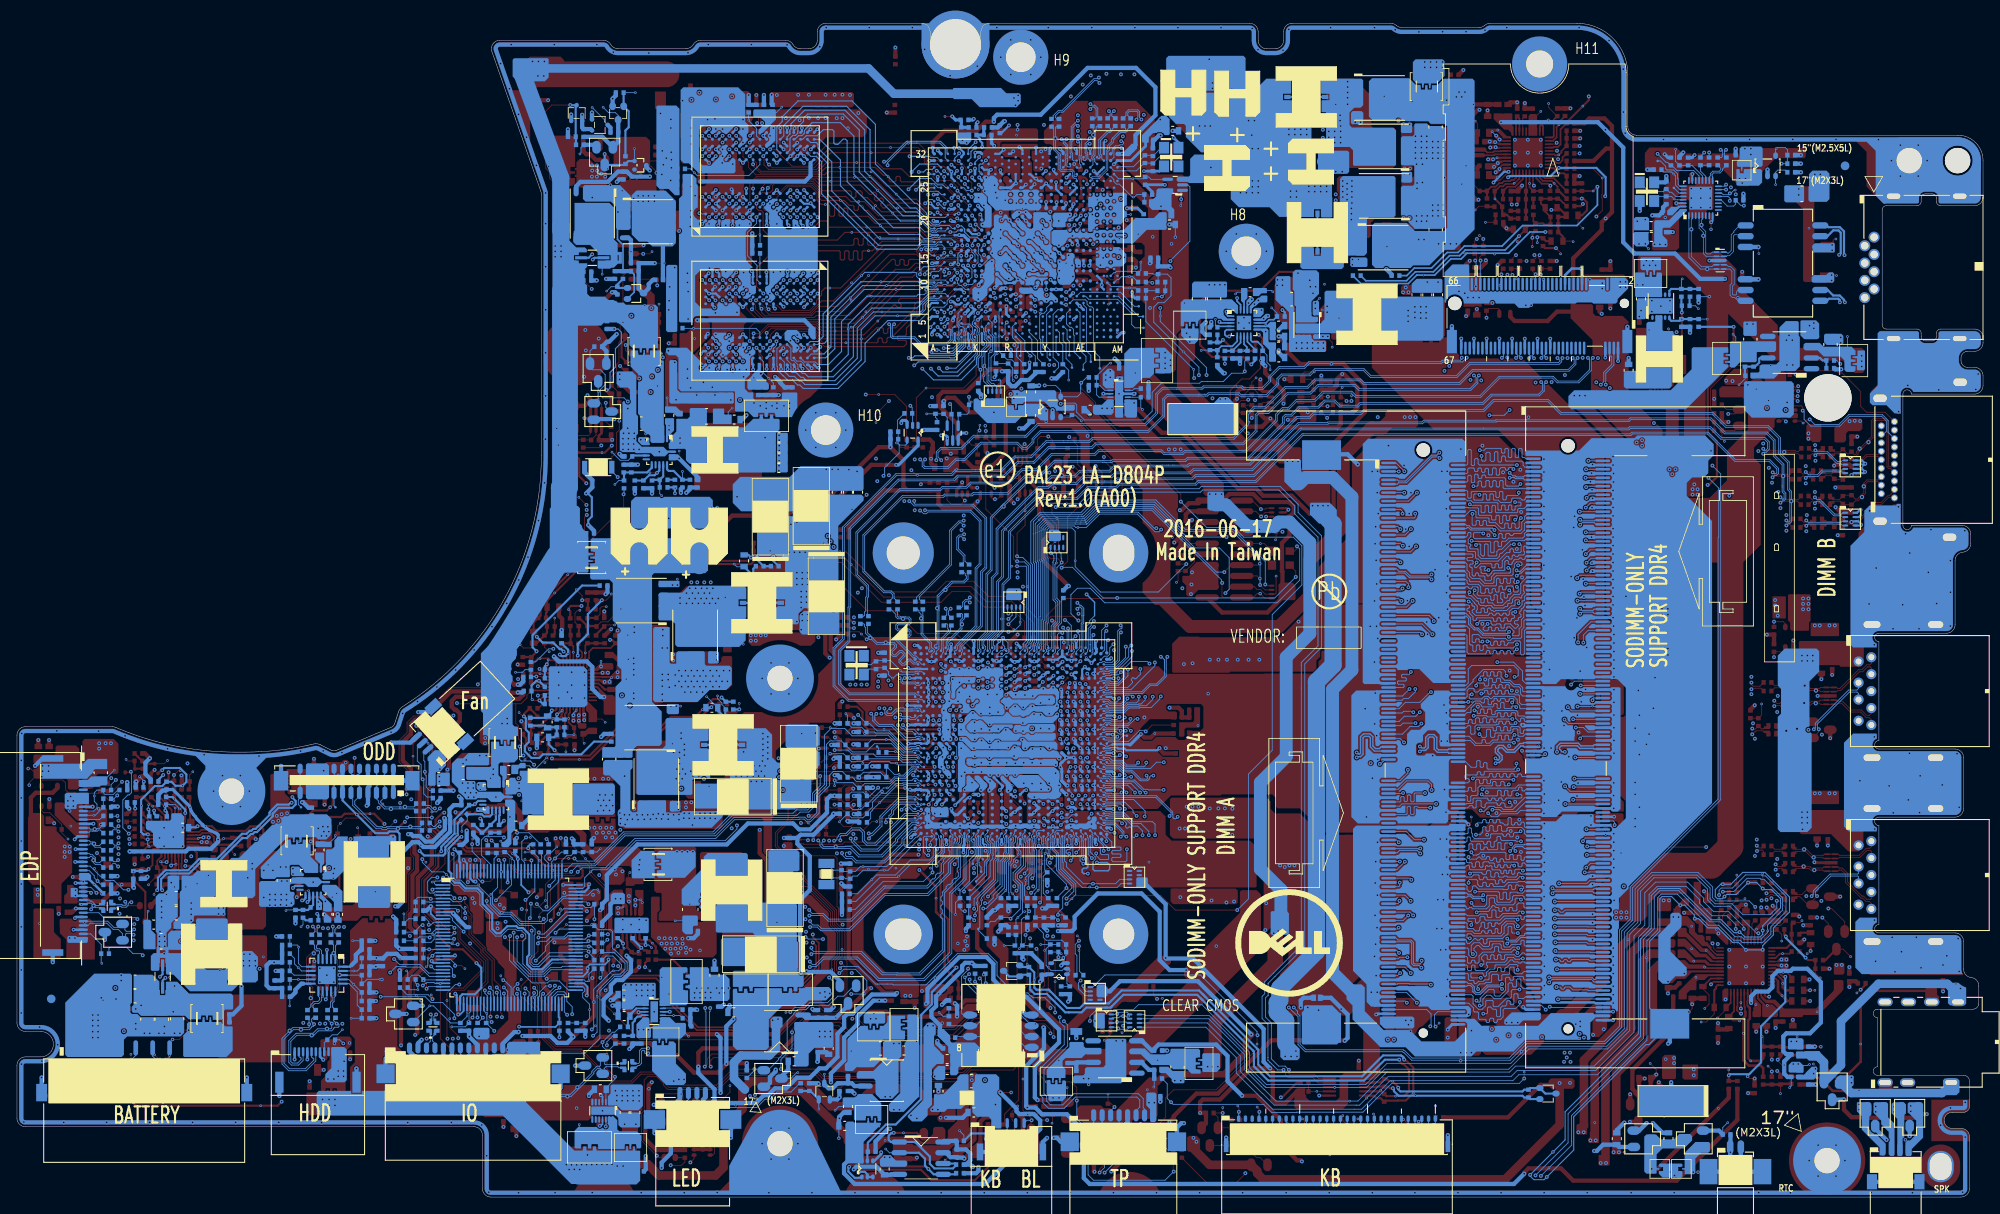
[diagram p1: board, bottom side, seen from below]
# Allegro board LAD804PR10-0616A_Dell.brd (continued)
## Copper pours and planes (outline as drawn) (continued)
GND on TOP (solid shape): outline of 2780 points within 50.44,61.87 95.65,89.74
GND on TOP (solid shape): outline of 3197 points within 43.26,21.42 95.91,47.14
GND on BOTTOM (solid shape): 28.28,103.21 28.28,101.75 28.15,101.62 26.82,101.62 26.69,101.75 26.69,103.27 26.75,103.33 28.15,103.33
GND on BOTTOM (solid shape): 41.17,115.46 41.17,114.13 41.1,114.06 39.45,114.06 39.39,114.13 39.39,115.46 39.58,115.65 40.98,115.65
GND on BOTTOM (solid shape): 67.39,107.78 67.39,106.83 67.27,106.7 63.9,106.7 63.77,106.83 63.77,108.22 63.9,108.35 66.82,108.35
GND on BOTTOM (solid shape): 78.44,123.21 78.44,120.92 78.25,120.73 75.01,120.73 74.76,120.99 74.76,123.27 74.95,123.46 78.19,123.46
GND on BOTTOM (solid shape): 93.3,107.78 93.3,106.19 93.24,106.13 89.3,106.13 89.17,106.25 89.17,107.9 89.3,108.03 93.05,108.03
GND on BOTTOM (solid shape): 104.92,21.42 104.92,20.15 104.67,19.89 103.65,19.89 103.59,19.96 103.59,21.67 103.65,21.74 104.6,21.74
GND on BOTTOM (solid shape): 115.21,71.65 115.21,70.5 115.15,70.44 113.49,70.44 113.43,70.5 113.43,71.65 113.62,71.84 115.02,71.84
GND on BOTTOM (solid shape): 142.26,90.06 142.26,85.62 142.13,85.49 141.12,85.49 140.99,85.62 140.99,90.12 141.05,90.19 142.13,90.19
GND on BOTTOM (solid shape): 151.98,48.72 151.98,45.99 151.85,45.87 148.86,45.87 148.57,46.16 148.57,48.47 148.88,48.79 151.91,48.79
GND on BOTTOM (solid shape): 161.44,32.85 161.44,31.26 161.31,31.13 157.5,31.13 157.37,31.26 157.37,32.85 157.5,32.97 161.31,32.97
GND on BOTTOM (solid shape): 18.75,101.68 18.75,100.86 18.44,100.54 16.66,100.54 16.47,100.73 16.47,101.62 16.72,101.87 18.56,101.87
GND on BOTTOM (solid shape): 169.19,62.44 169.19,58 168.99,57.8 164.93,57.8 164.61,58.12 164.61,62.18 165.06,62.63 168.99,62.63
GND on BOTTOM (solid shape): 96.35,134.38 96.35,131.02 95.87,130.54 87.11,130.54 86.98,130.67 86.98,134.42 87.24,134.67 96.06,134.67
GND on BOTTOM (solid shape): 148.87,30.37 148.87,27.45 148.67,27.26 146.2,27.26 146.19,27.26 145.32,27.26 144.99,27.58 144.99,30.36 145.25,30.63 148.61,30.63
GND on BOTTOM (solid shape): 181.95,49.99 182.27,49.99 182.39,49.87 182.39,48.66 182.23,48.5 180.96,48.5 180.87,48.6 180.87,49.99 180.93,50.06 180.93,50.09 181.85,50.09
GND on BOTTOM (solid shape): 20.53,120.71 20.53,119.27 20.59,119.21 20.59,117.62 20.4,117.43 18.44,117.43 18.1,117.77 18.1,120.76 18.46,121.12 20.12,121.12
GND on BOTTOM (solid shape): 80.09,22.5 80.09,22.05 80.35,21.8 80.35,18.13 80.22,18 76.21,18 75.78,18.43 75.78,21.62 76.79,22.63 79.96,22.63
GND on BOTTOM (solid shape): 90.73,93.71 91.81,93.71 91.84,93.68 96.1,93.68 96.22,93.55 96.22,90 96.1,89.87 88.48,89.87 88.22,90.12 88.22,93.55 89.05,94.38 90.06,94.38
GND on BOTTOM (solid shape): 155.33,109.82 155.33,108.64 155.33,107.82 155.34,107.82 155.34,102.25 155.15,102.06 154.13,102.06 154.01,102.19 154.01,109.87 154.13,110 155.15,110
GND on BOTTOM (solid shape): 156.48,128.67 156.48,119.33 156.1,118.95 155.04,118.95 154.3,118.22 153.78,118.22 153.75,118.24 153.75,122.33 153.75,128.42 154.13,128.8 156.36,128.8
GND on BOTTOM (solid shape): 37.88,106.06 40.66,106.06 40.85,105.87 40.85,103.65 40.79,103.59 39.9,103.59 39.33,104.16 39.32,104.16 39.24,104.23 36.65,104.23 36.6,104.29 36.6,106 36.66,106.06 37.88,106.06
GND on BOTTOM (solid shape): 85.17,103.65 86,103.65 86.06,103.59 86.06,103.46 86,103.4 84.73,103.4 84.41,103.71 84.35,103.71 84.32,103.75 84.18,103.75 84.09,103.84 84.09,104.09 84.22,104.22 84.6,104.22
GND on BOTTOM (solid shape): 97.18,15.32 97.18,14.75 97.05,14.62 96.41,14.62 95.71,13.92 95.71,13.67 95.46,13.42 94.32,13.42 94.19,13.54 94.19,14.81 94.25,14.88 95.59,14.88 96.1,15.39 97.11,15.39
GND on BOTTOM (solid shape): 143.28,40.79 143.28,37.48 142.9,37.1 140.8,37.1 140.42,37.48 140.42,38.31 140.29,38.44 139.78,38.44 139.59,38.63 139.59,40.66 139.86,40.93 143.13,40.93
GND on BOTTOM (solid shape): 93.52,122.51 93.52,120.58 93.69,120.42 94.92,120.42 95.11,120.23 95.11,119.96 94.94,119.78 93.8,119.78 93.67,119.65 89.64,119.65 89.15,120.14 89.15,120.57 89.11,120.6 89.11,122.26 89.87,123.02 93.02,123.02
GND on BOTTOM (solid shape): 103.53,18.5 103.53,15.58 103.78,15.32 105.75,15.32 105.94,15.13 105.94,14.56 106.13,14.37 107.14,14.37 107.34,14.18 107.34,13.54 107.21,13.42 101.68,13.42 101.05,14.05 101.05,18.56 101.18,18.69 103.33,18.69
GND on BOTTOM (solid shape): 213.7,45.17 213.7,44.6 213.89,44.4 216.56,44.4 216.68,44.28 216.68,43.45 216.49,43.26 216.17,43.26 215.86,42.94 215.86,41.61 215.41,41.17 212.3,41.17 212.17,41.29 212.17,44.91 212.55,45.29 213.57,45.29
GND on BOTTOM (solid shape): 129.75,18.24 129.75,16.02 130.89,14.88 132.61,14.88 132.86,14.62 132.86,14.12 132.74,13.99 130.89,13.99 130.64,13.73 130.64,12.15 130.07,11.58 128.67,11.58 127.91,12.34 127.91,16.27 127.59,16.59 127.59,18.31 127.72,18.43 129.56,18.43
GND on BOTTOM (solid shape): 24.02,102.6 24.02,98.63 24.4,98.25 26.12,98.25 26.37,98 26.37,97.43 26.5,97.3 27.39,97.3 27.45,97.24 27.45,96.7 27.33,96.57 24.65,96.57 23.76,97.46 22.15,97.46 21.61,98 21.61,101.49 21.74,101.62 21.74,103.24 21.86,103.36 23.26,103.36
GND on BOTTOM (solid shape): 136.5,86.23 136.9,86.25 139.47,86.25 140.74,84.98 146.59,84.98 147.48,84.1 147.48,81.91 146.48,80.92 138.64,80.92 136.23,83.33 132.23,83.33 132.04,83.52 132.04,85.93 132.35,86.25 136.1,86.25
GND on BOTTOM (solid shape): 214.14,37.8 214.14,36.28 214.59,35.83 215.16,35.83 215.54,35.45 215.54,31.32 215.35,31.13 215.35,29.42 215.29,29.36 214.33,29.36 214.27,29.42 214.27,31.2 213.7,31.77 213.7,32.34 212.94,33.1 212.94,36.15 212.75,36.34 212.75,37.86 212.81,37.93 214.02,37.93
GND on BOTTOM (solid shape): 156.87,67.07 156.87,58.63 156.64,58.41 151.63,58.41 150.2,59.84 148.23,59.84 147.59,60.47 147.59,62.44 147.85,62.69 150.58,62.69 150.77,62.88 150.77,64.28 150.9,64.41 153.94,64.41 154.13,64.22 154.13,63.01 154.2,62.95 154.77,62.95 154.9,63.07 154.9,67.2 154.96,67.26 156.67,67.26
GND on BOTTOM (solid shape): 155.6,82.63 155.85,82.48 156.1,82.63 158.96,82.63 159.47,82.12 159.47,79.27 159.09,78.89 150.11,78.89 149.82,79.18 149.82,82.24 150.2,82.63
GND on BOTTOM (solid shape): 154.96,98.63 154.96,94.43 154.96,94.42 154.93,94.32 154.96,94.21 154.96,94.2 154.96,93.81 154.77,93.62 147.47,93.62 147.34,93.74 147.34,94.82 147.47,94.95 153.62,94.95 153.69,94.95 154.01,95.27 154.01,98.57 154.2,98.76 154.83,98.76
GND on BOTTOM (solid shape): 83.46,108.48 83.46,105.87 82.76,105.17 82.63,105.17 81.87,104.41 81.87,99.84 81.74,99.71 77.62,99.71 77.49,99.84 77.49,100.92 77.62,101.05 78.89,101.05 79.2,101.36 79.2,101.62 79.33,101.75 81.17,101.75 81.24,101.81 81.24,102.01 81.24,102.01 81.24,103.07 81.24,103.07 81.24,105.05 81.36,105.17 81.36,106.7 81.68,107.02 81.68,108.54 81.81,108.67 83.27,108.67
GND on BOTTOM (solid shape): 102.26,96.73 102.26,96.35 102.38,96.22 102.38,93.12 102.38,93.07 102.38,93.02 102.38,92.09 102.26,91.97 101.49,91.97 101.43,92.03 101.43,94.51 101.3,94.63 100.41,94.63 100.35,94.57 99.97,94.57 99.84,94.7 99.84,94.95 99.91,95.01 100.22,95.01 100.23,95.01 100.29,95.01 100.35,94.95 101.3,94.95 101.43,95.08 101.43,96.79 101.49,96.86 102.13,96.86
GND on BOTTOM (solid shape): 162.76,51.35 162.76,49.93 162.57,49.74 162,49.74 160.74,48.49 160.74,45.87 160.99,45.61 160.99,43.9 160.83,43.74 160.33,43.74 160.17,43.58 149.94,43.58 148.67,44.85 148.67,45.42 148.8,45.55 153.37,45.55 153.56,45.36 154.53,45.36 154.58,45.35 155.28,45.36 155.34,45.42 155.34,46.75 155.4,46.82 158.52,46.82 158.71,46.63 158.71,45.55 158.83,45.42 159.34,45.42 159.53,45.61 159.53,50.37 159.28,50.63 159.28,51.52 159.34,51.58 162.53,51.58
GND on BOTTOM (solid shape): 135.29,69.17 135.59,69 135.89,69.17 139.09,69.17 139.59,68.66 139.59,68.06 139.59,68.05 139.55,67.9 139.59,67.75 139.59,67.74 139.59,66.69 139.28,66.38 137.53,66.38 137.52,66.38 137.37,66.41 137.22,66.38 137.21,66.38 135.08,66.38 134.89,66.57 134.89,69.04 135.02,69.17
GND on BOTTOM (solid shape): 198.09,37.74 199.41,37.74 199.6,37.55 201.24,37.55 201.49,37.29 203.14,37.29 203.35,37.09 203.35,34.44 203.16,34.24 199.47,34.24 199.46,34.26 199.16,34.56 199.16,35.14 199.26,35.39 199.16,35.64 199.16,35.9 199.28,36.02 199.6,36.02 199.73,36.15 199.73,36.78 199.54,36.98 197.95,36.98 197.57,36.59 196.43,36.59 195.98,37.04 195.03,37.04 194.97,37.1 194.97,37.23 195.03,37.29 195.92,37.29 196.36,37.74 198.09,37.74
GND on BOTTOM (solid shape): 141.24,55.52 141.24,53.19 140.99,52.93 140.44,52.93 138.01,50.5 137.69,50.5 137.21,50.98 137.21,52.46 137.24,52.53 137.31,52.56 137.68,52.91 137.31,53.27 137.24,53.3 137.21,53.37 137.21,55.45 137.53,55.77 140.99,55.77
GND on BOTTOM (solid shape): 161.55,10.68 161.63,10.67 161.72,10.68 161.73,10.69 161.94,10.69 161.95,10.68 162.03,10.67 162.12,10.68 162.13,10.69 163.54,10.69 163.55,10.68 163.63,10.67 163.72,10.68 163.73,10.69 163.94,10.69 164.02,10.67 164.08,10.67 164.11,10.68 164.17,10.62 164.17,9.8 164.1,9.73 161.37,9.73 160.99,9.35 160.99,9.15 160.96,9.12 160.96,8.5 160.68,8.21 158.52,8.21 158.39,8.34 158.39,9.86 158.52,9.99 160.55,9.99 161.25,10.69 161.54,10.69
GND on BOTTOM (solid shape): 179.28,51.77 179.98,51.77 180.61,51.14 180.61,48.98 179.85,48.21 179.85,47.83 179.64,47.62 179.63,47.62 179.56,47.58 179.49,47.53 179.1,47.14 179.1,47.08 178.93,46.91 177.72,46.91 177.57,47.07 176.42,47.07 175.98,46.63 174.84,46.63 174.39,47.07 173.5,47.07 173.38,47.2 173.38,47.26 173.5,47.39 174.39,47.39 174.84,47.83 176.56,47.83 176.56,47.83 177.49,47.83 177.5,47.83 177.82,48.15 177.82,48.84 177.82,48.98 177.95,49.1 178.96,49.1 179.09,49.23 179.09,50.75 178.96,50.88 178.9,50.95 176.35,50.95 176.22,51.07 176.22,52.23 176.4,52.41 178.65,52.41
GND on BOTTOM (solid shape): 138.3,8.05 141.8,10.3 145.41,8.22 147.9,3.66 147.9,0.25 134.52,0.25
GND on BOTTOM (solid shape): 121.75,61.3 121.75,60.87 121.71,60.83 121.71,60.79 121.71,60.78 121.67,60.63 121.71,60.49 121.71,60.48 121.71,59.78 121.65,59.58 121.71,59.38 121.71,58.86 121.71,58.86 121.35,58.86 121.22,58.99 121.22,59.69 121.18,59.73 121.18,59.84 120.42,60.6 120.33,60.6 120.31,60.6 120.16,60.64 120.01,60.6 120,60.6 119.23,60.6 119.21,60.6 119.14,60.63 119.06,60.64 119.04,60.64 118.86,60.82 118.86,60.85 118.86,60.96 118.83,61.06 118.83,61.07 118.83,61.3 118.89,61.36 121.69,61.36
GND on BOTTOM (solid shape): 15.07,32.47 15.07,27.07 14.31,26.31 2.4,26.31 2.52,26.59 2.55,26.9 2.55,30.17 2.77,30.69 3.3,30.91 12.28,30.91 13.02,31.54 12.53,32.38 12.53,32.97 14.56,32.97
GND on BOTTOM (solid shape): 161.18,97.3 161.18,95.97 160.74,95.52 159.85,95.52 159.6,95.27 159.6,94.12 159.7,93.55 160.2,93.84 160.24,93.91 160.31,93.93 160.36,93.93 160.48,93.81 160.48,90.7 160.8,90.38 160.8,88.09 160.78,88.07 160.66,88.03 160.56,87.96 160.5,87.9 159.02,87.9 158.9,87.78 157.12,87.78 156.74,87.39 155.47,87.39 155.02,87.84 154.26,87.84 154.2,87.9 154.2,88.03 154.26,88.09 155.21,88.09 155.66,88.54 158.2,88.54 158.83,89.17 158.83,89.87 158.64,90.06 158.64,92.16 158.83,92.35 158.83,96.46 158.84,96.46 158.86,96.59 158.84,96.71 158.83,96.72 158.83,96.92 159.34,97.43 161.06,97.43
GND on BOTTOM (solid shape): 67.08,126.57 67.08,125.37 67.27,125.18 68.47,125.18 68.66,124.99 68.66,121.87 68.54,121.75 67.2,121.75 67.08,121.62 67.08,119.53 67.27,119.33 68.47,119.33 68.66,119.14 68.66,115.93 68.61,115.84 68.51,115.84 68.28,115.87 68.07,115.75 68,115.72 67.92,115.75 67.32,115.66 67.67,115.17 67.77,115.11 67.75,115 67.01,114.25 63.71,114.25 63.39,114.57 63.39,126.07 63.71,126.38 65.3,126.38 65.62,126.7 66.95,126.7
GND on BOTTOM (solid shape): 110.15,59.2 110.26,59.18 110.37,59.2 110.38,59.2 111.24,59.2 111.3,59.19 111.36,59.18 111.79,58.76 111.83,58.76 111.86,58.72 114.49,58.72 114.53,58.76 114.57,58.76 114.83,59.01 114.9,59.04 114.97,59.01 115.21,58.91 115.46,59 115.84,58.61 115.84,58.46 115.39,58 115.39,57.7 115.36,57.65 115.34,57.58 115.3,57.54 115.04,57.54 114.99,57.58 114.99,57.6 114.97,57.62 114.97,57.63 114.89,57.74 114.78,57.82 114.77,57.82 114.35,58.24 113.92,58.24 113.46,57.77 113.43,57.74 113.4,57.71 113.24,57.56 113.08,57.56 112.65,57.99 112.62,57.99 112.38,58.24 112.25,58.24 112.24,58.24 112.12,58.26 112,58.24 112,58.24 111.93,58.24 111.74,58.06 111.07,58.06 111.03,58.1 109.71,58.1 109.47,58.34 109.47,58.92 109.75,59.2 110.14,59.2
GND on BOTTOM (solid shape): 16.4,53.61 16.4,43.71 15.83,43.13 12.53,43.13 12.53,43.62 13.02,44.46 12.28,45.09 3.3,45.09 2.77,45.31 2.55,45.83 2.55,51.87 2.77,52.4 3.3,52.61 12.28,52.61 13.02,53.24 12.53,54.08 12.53,54.69 15.32,54.69
GND on BOTTOM (solid shape): 105.13,44.76 105.13,44.74 105.23,44.48 105.49,44.38 105.52,44.38 105.81,44.09 106.72,44.09 106.96,43.98 107.2,44.09 107.82,44.09 107.93,44.01 108.06,43.98 108.08,43.98 108.29,43.77 108.29,43.52 108.16,43.39 107.76,43.39 107.51,43.54 107.26,43.39 106.66,43.39 106.41,43.54 106.16,43.39 105.56,43.39 105.31,43.54 105.06,43.39 104.6,43.39 104.54,43.45 104.54,43.91 104.69,44.16 104.54,44.41 104.54,44.79 104.67,44.91 104.99,44.91
GND on BOTTOM (solid shape): outline of 111 points within 212.17,16.53 226.21,26.37
GND on BOTTOM (solid shape): 123.34,53.61 123.34,53.31 123.31,53.3 123.2,53.21 123.13,53.09 123.12,53.08 122.83,52.79 122.83,52.65 122.75,52.31 123.01,52.08 123.03,52.08 123.19,51.91 123.19,51.9 123.22,51.79 123.27,51.7 123.27,50.69 123.12,50.54 123.09,50.54 122.83,50.44 122.73,50.18 122.73,50.15 121.94,49.36 121.81,49.36 121.69,49.48 121.69,49.97 121.75,50.05 121.78,50.14 121.79,50.16 122.03,50.4 122.06,50.4 122.31,50.51 122.42,50.76 122.42,50.79 122.58,50.95 122.58,51.21 122.59,51.31 122.58,51.41 122.58,51.58 122.29,51.86 122.3,51.88 122.23,52.11 122.04,52.24 122,52.25 122,52.58 122.03,52.59 122.19,52.75 122.23,52.98 122.22,53 122.48,53.26 122.51,53.29 122.96,53.74 123.21,53.74
GND on BOTTOM (solid shape): 10.21,81.62 13.38,81.62 14.01,80.99 14.01,78.48 15.64,76.85 15.64,65.17 15.32,64.85 12.53,64.85 12.53,65.32 13.02,66.16 12.28,66.79 4.3,66.79 3.77,67.01 3.55,67.53 3.55,75.1 3.22,75.95 1.91,76.59 1.71,77.09 1.71,78.25 1.93,78.78 2.46,79 8.24,79 9.08,78.51 9.7,79.25 9.7,81.81 10.21,81.81
GND on BOTTOM (solid shape): 5,102.17 5.17,102.1 5.25,101.92 5.25,101.52 5.28,101.3 5.38,101.1 5.58,100.9 5.78,100.8 6,100.77 6.8,100.77 7.33,100.99 7.55,101.52 7.55,101.92 7.63,102.1 7.8,102.17 12.2,102.17 12.44,101.93 12.44,95.75 13.36,94.83 13.36,93.74 13.04,93.43 11.39,93.43 10.43,92.47 9.7,92.47 9.7,94.75 9.08,95.49 8.24,95 1,95 0.47,95.22 0.25,95.75 0.25,96.9 0.47,97.43 1,97.65 1.8,97.65 2.55,97.95 2.85,98.7 2.85,99 2.55,99.75 1.8,100.05 1,100.05 0.47,100.27 0.25,100.8 0.25,101.42 0.47,101.95 1,102.17
GND on BOTTOM (solid shape): outline of 206 points within 0.25,119.3 11.7,125.05
GND on BOTTOM (solid shape): outline of 169 points within 108.96,53.59 120.92,57.36
GND on BOTTOM (solid shape): outline of 198 points within 108.67,46.94 120.92,53.74
GND on BOTTOM (solid shape): outline of 116 points within 111.21,43.45 124.86,45.99
GND on BOTTOM (solid shape): outline of 1792 points within 0.25,0.25 231.65,138.25
GND on BOTTOM (solid shape): outline of 1896 points within 60.41,21.29 74.32,44.07
GND on BOTTOM (solid shape): outline of 2800 points within 60.98,60.53 73.17,89.49
GND on BOTTOM (solid shape): outline of 5418 points within 31.77,21.9 54.01,89.87
GND on IN1 (solid shape): 15.2,32.4 15.2,27.96 13.42,26.18 2.33,26.18 2.5,26.52 2.55,26.9 2.55,30.17 2.77,30.69 3.3,30.91 12.28,30.91 13.02,31.54 12.53,32.38 12.53,32.97 14.63,32.97
GND on IN1 (solid shape): 15.13,53.99 15.13,43.33 14.94,43.13 12.53,43.13 12.53,43.62 13.02,44.46 12.28,45.09 3.3,45.09 2.77,45.31 2.55,45.83 2.55,51.87 2.77,52.4 3.3,52.61 12.28,52.61 13.02,53.24 12.53,54.08 12.53,54.5 14.63,54.5
GND on IN1 (solid shape): 13.32,80.79 13.32,78.75 14.88,77.18 14.88,65.3 14.5,64.92 12.53,64.92 12.53,65.32 13.02,66.16 12.28,66.79 4.3,66.79 3.77,67.01 3.55,67.53 3.55,75.1 3.22,75.95 1.91,76.59 1.71,77.09 1.71,78.25 1.93,78.78 2.46,79 8.24,79 9.08,78.51 9.7,79.25 9.7,81.68 12.43,81.68
GND on IN1 (solid shape): 12.44,101.93 12.44,95.91 13.29,95.06 13.29,93.93 12.85,93.49 10.4,93.49 10.21,93.3 10.21,92.47 9.7,92.47 9.7,94.75 9.08,95.49 8.24,95 1,95 0.47,95.22 0.25,95.75 0.25,96.9 0.47,97.43 1,97.65 1.8,97.65 2.55,97.95 2.85,98.7 2.85,99 2.55,99.75 1.8,100.05 1,100.05 0.47,100.27 0.25,100.8 0.25,101.42 0.47,101.95 1,102.17 5,102.17 5.17,102.1 5.25,101.92 5.25,101.52 5.47,100.99 6,100.77 6.8,100.77 7.33,100.99 7.55,101.52 7.55,101.92 7.63,102.1 7.8,102.17 11.4,102.17 11.52,102.18 11.63,102.21 12.16,102.21
GND on IN1 (solid shape): outline of 1805 points within 0.25,0.25 231.65,138.25
GND on IN2 (solid shape): 16.78,53.49 16.78,44.4 15.58,43.2 12.53,43.2 12.53,43.62 13.02,44.46 12.28,45.09 3.3,45.09 2.77,45.31 2.55,45.83 2.55,51.87 2.77,52.4 3.3,52.61 12.28,52.61 13.02,53.24 12.53,54.08 12.53,54.56 15.7,54.56
GND on IN2 (solid shape): 12.44,101.92 12.44,95.88 13.29,95.03 13.29,93.87 12.72,93.3 10.21,93.3 10.21,92.47 9.7,92.47 9.7,94.75 9.08,95.49 8.24,95 1,95 0.47,95.22 0.25,95.75 0.25,96.9 0.47,97.43 1,97.65 1.8,97.65 2.55,97.95 2.85,98.7 2.85,99 2.55,99.75 1.8,100.05 1,100.05 0.47,100.27 0.25,100.8 0.25,101.42 0.47,101.95 1,102.17 5,102.17 5.17,102.1 5.25,101.92 5.25,101.52 5.47,100.99 6,100.77 6.8,100.77 7.33,100.99 7.55,101.52 7.55,101.92 7.63,102.1 7.8,102.17 11.4,102.17 11.46,102.17 11.53,102.18 12.17,102.18
GND on IN2 (solid shape): outline of 224 points within 1.71,64.92 15.45,81.83
GND on IN2 (solid shape): outline of 1805 points within 0.25,0.25 231.65,138.25
GND on TOP: 199.66,36.63 199.66,37.42 199.79,37.55 201.19,37.55 201.44,37.29 203.05,37.29 203.16,37.18 203.16,36.47 202.97,36.28 202.47,36.28 202.47,36.28 202.39,36.28 202.33,36.21 202.33,34.31 202.2,34.18 199.41,34.18 199.22,34.37 199.22,35.18 199.28,35.39 199.22,35.6 199.22,35.83 199.66,36.28 199.66,36.31 199.67,36.32 199.7,36.47 199.67,36.62
GND on VCC: 2.6,0.26 2.07,0.47 1.85,1 1.85,7.1 2.07,7.63 2.6,7.85 3.65,7.85 3.7,7.85 4.85,9.05 3.7,10.25 3.65,10.25 2.3,10.25 1.99,10.39 1.85,10.7 1.85,11.45 6.52,11.45 6.77,11.19 15.37,11.19 15.94,11.77 18.73,11.77 19.3,12.34 27.05,12.34 27.62,12.91 35.47,12.91 35.83,12.55 35.83,0.26
GND on VCC: 209.04,38.75 208.17,39.62 208.17,42.06 208.53,42.06 209.42,42.94 210.18,42.94 212.75,45.51 212.75,41.27 210.23,38.75
GND on VCC: 161.69,20.59 161.69,22.23 161.95,22.37 162.02,22.66 168.3,28.93 168.3,31.85 169.61,33.17 174.75,33.17 177.42,35.83 184.45,35.83 185.31,34.96 185.31,23.24 184.04,21.97 184.04,18.96 184.3,18.71 184.3,18.41 184.06,18.18 183.64,18.18 183.39,18.43 171.36,18.43 170.6,17.67 162.94,17.67 162.58,18.03 162.58,18.45 162.96,18.84 162.96,20.19 162.56,20.59
GND on VCC: 196.62,13.23 196.62,16.51 193.06,20.06 193.06,32.15 193.31,32.4 197.66,32.4 197.89,32.17 197.89,25.88 198.52,25.25 198.52,20.11 200.43,18.2 200.43,13.71 199.94,13.23
GND on VCC: outline of 289 points within 0.26,15.51 189.57,138.25 ; 3 cut-outs
GND on VCC: 203.39,25.29 202.59,26.09 202.59,36.59 206.61,36.59 208.07,35.13 215.73,35.13 215.73,27.56 215.24,27.07 209.46,27.07 207.69,25.29
GND on GND: outline of 288 points within 0.26,0.26 231.64,138.25 ; 1 cut-out
GNDA on TOP (solid shape): 35.45,15.58 35.45,14.05 35.26,13.86 33.74,13.86 33.61,13.99 33.61,15.58 33.68,15.64 35.39,15.64
GNDA on VCC: 6.98,11.7 6.73,11.96 1.85,11.96 1.85,13.67 1.99,13.98 2.3,14.11 12.45,14.11 13.2,14.77 12.71,15.58 12.71,20.96 13.2,21.77 12.45,22.42 1.2,22.42 0.89,22.55 0.76,22.87 0.76,24.91 0.95,25.41 1.43,25.65 1.76,25.73 2.05,25.9 2.05,25.82 2.2,25.67 18.92,25.67 19.58,26.33 19.58,32.17 19.68,32.28 23.09,32.28 23.64,31.73 23.64,31.09 25.17,29.57 25.17,24.8 25.44,24.53 28.74,24.53 28.85,24.42 28.85,19.34 29.38,18.81 31.88,18.81 32.79,19.72 32.79,24 31.37,25.42 30.61,25.42 30.5,25.52 30.5,25.82 30.86,26.18 35.41,26.18 35.83,25.76 35.83,13.84 35.41,13.42 27.41,13.42 26.84,12.85 19.09,12.85 18.52,12.27 15.73,12.27 15.15,11.7
GNDA on GND: 6.98,11.7 6.73,11.96 1.85,11.96 1.85,13.67 1.99,13.98 2.3,14.11 12.45,14.11 13.2,14.77 12.71,15.58 12.71,20.96 13.2,21.77 12.45,22.42 1.2,22.42 0.89,22.55 0.76,22.87 0.76,24.91 0.95,25.41 1.43,25.65 1.76,25.73 2.05,25.9 2.05,25.82 2.2,25.67 18.92,25.67 19.58,26.33 19.58,32.17 19.68,32.28 23.09,32.28 23.64,31.73 23.64,31.09 25.17,29.57 25.17,24.8 25.44,24.53 28.74,24.53 28.85,24.42 28.85,19.34 29.38,18.81 31.88,18.81 32.79,19.72 32.79,24 31.37,25.42 30.61,25.42 30.5,25.52 30.5,25.82 30.86,26.18 35.83,26.18 35.83,13.42 27.41,13.42 26.84,12.85 19.09,12.85 18.52,12.27 15.73,12.27 15.15,11.7
VDD_1.2V on BOTTOM (solid shape): 86.06,102.44 86.06,102.32 86,102.25 85.17,102.25 84.92,102 84.92,100.67 84.22,99.97 84.22,98.63 84.16,98.57 83.46,98.57 83.4,98.63 83.4,99.43 83.46,99.49 83.46,99.9 83.44,100.01 83.4,100.11 83.4,100.79 83.46,100.86 84.16,100.86 84.28,100.98 84.28,102.32 84.48,102.51 86,102.51
VDDCR_FCH_S5 on BOTTOM (solid shape): 132.74,12.14 132.84,11.95 133.03,11.84 133.05,11.83 133.12,11.77 134.39,11.77 134.51,11.64 134.51,10.81 134.26,10.56 133.31,10.56 133.18,10.43 133.18,9.16 133.05,9.04 131.78,9.04 131.78,9.54 131.15,9.54 131.15,9.04 130.96,9.04 130.96,9.54 130.39,9.54 130.39,8.97 130,8.97 129.94,9.04 129.94,11.07 131.02,12.15 132.74,12.15
VSS_MECH on BOTTOM (solid shape): 101.37,123.34 102.19,123.34 102.32,123.21 102.32,122.95 102.19,122.83 100.67,122.83 99.78,123.72 99.78,124.22 99.84,124.29 100.41,124.29
+APU_CORE on TOP (solid shape): outline of 131 points within 137.09,66.9 145.14,80.26
+APU_CORE on TOP (solid shape): outline of 168 points within 108.34,52.67 115.82,60.41
+APU_CORE on BOTTOM (solid shape): 113.6,54.04 113.6,53.84 113.56,53.84 113.54,53.82 113.53,53.81 113.35,53.63 113.36,53.38 113.36,53.37 113.36,53.33 113.37,53.33 113.37,52.91 113.18,52.73 112.91,52.73 112.87,52.77 112.82,52.8 112.45,53.17 112.33,53.17 112.32,53.17 112.12,53.23 111.92,53.17 111.41,53.17 111.34,53.17 111.33,53.17 111.15,53.22 110.97,53.17 110.67,53.17 110.22,52.72 110,52.72 109.8,52.91 109.62,52.91 109.51,52.81 109.48,52.79 109.24,52.79 109.18,52.85 109.18,53.49 109.43,53.74 112.69,53.74 113.14,54.19 113.45,54.19
+APU_CORE on BOTTOM (solid shape): outline of 95 points within 109.43,54.63 114.38,55.83
+APU_CORE on BOTTOM (solid shape): outline of 186 points within 132.04,67.58 144.61,82.89
+APU_CORE on BOTTOM (solid shape): outline of 121 points within 108.99,56.66 114.89,60.34
+APU_CORE on IN1 (solid shape): outline of 4827 points within 108.54,52.6 134.13,63.26
+APU_CORE on VCC: 108.96,52.72 108.86,52.83 108.86,53 109.62,53.76 109.62,55.88 108.99,56.51 108.99,60.96 104.92,65.02 104.92,67.81 102.3,70.44 101.11,70.44 101.11,71.29 101.28,71.46 104.46,71.46 104.71,71.71 109.92,71.71 111.65,73.45 111.65,78.4 113.54,80.28 116.39,80.28 120.73,84.62 120.73,85.07 120.78,85.11 121.58,85.11 121.96,84.73 127.7,84.73 128.4,85.43 130.15,85.43 135.3,80.28 145.77,80.28 146.07,79.99 146.07,56.66 136.65,56.66 135.51,57.8 132.25,57.8 131.11,56.66 115.1,56.66 114.45,56 114.45,54.73 113.56,53.84 113.56,52.83 113.45,52.72
+APU_CORE_NB on TOP (solid shape): 144.19,21.18 144.19,20.41 143.8,20.02 142.3,20.02 141.8,20.52 141.8,21.13 142.01,21.33 144.04,21.33
+APU_CORE_NB on TOP (solid shape): 129.9,4.94 129.97,4.93 130.04,4.94 130.52,4.94 130.68,4.78 130.68,4.06 130.49,3.87 128.84,3.87 128.65,4.07 128.65,4.76 128.83,4.94
+APU_CORE_NB on TOP (solid shape): outline of 2479 points within 109.12,44.79 148.42,66.08
+APU_CORE_NB on BOTTOM (solid shape): 143,20.96 143,20.02 142.81,19.83 141.9,19.83 141.59,20.15 141.59,21.09 141.79,21.29 142.67,21.29
+APU_CORE_NB on BOTTOM (solid shape): 130.12,4.45 130.12,3.76 129.93,3.57 127.08,3.57 126.89,3.76 126.89,4.15 127.06,4.31 128.23,4.31 128.86,4.95 129.62,4.95
+APU_CORE_NB on BOTTOM (solid shape): 113.94,51.52 114.38,51.52 114.64,51.77 116.73,51.77 117.05,51.45 117.3,51.45 117.38,51.53 117.45,51.58 117.5,51.65 117.62,51.77 118.66,51.77 118.71,51.72 118.78,51.68 118.8,51.66 118.92,51.65 118.98,51.66 119.18,51.66 119.29,51.77 119.78,51.77 119.91,51.64 119.91,51.14 119.65,50.88 119.21,50.88 119.15,50.82 118.78,50.82 118.76,50.83 118.7,50.88 109.56,50.88 109.43,50.75 109.24,50.75 109.17,50.83 109.14,50.89 109.11,50.94 109.11,51.4 109.14,51.41 109.27,51.51 109.34,51.66 109.34,51.68 109.37,51.71 110.89,51.71 110.95,51.64 111.46,51.64 111.53,51.71 111.84,51.71 111.97,51.58 112.42,51.58 112.61,51.77 113.69,51.77
+APU_CORE_NB on BOTTOM (solid shape): 120.6,54.28 120.68,54.28 120.7,54.28 120.79,54.2 120.78,54.17 120.76,54.06 120.78,53.95 120.79,53.92 120.71,53.84 120.68,53.84 120.6,53.83 120.52,53.81 120.51,53.8 120.35,53.8 119.29,52.74 118.9,52.74 118.86,52.77 118.81,52.8 118.77,52.85 115.2,52.85 115.15,52.8 114.88,52.8 114.74,52.95 114.74,53.03 114.66,53.11 114.66,53.11 114.39,53.38 114.22,53.38 114.15,53.38 114,53.38 113.92,53.3 113.54,53.3 113.46,53.38 113.46,53.6 113.6,53.74 115.84,53.74 116.07,53.97 116.5,53.97 116.86,53.61 117.08,53.45 117.34,53.48 117.37,53.49 118,54.12 118.38,54.12 118.59,53.91 118.59,53.9 118.77,53.7 119.03,53.67 119.04,53.68 119.34,53.68 119.97,54.31 120.52,54.31
+APU_CORE_NB on BOTTOM (solid shape): 118.42,56.28 118.66,56.18 118.9,56.28 119.27,56.28 119.91,55.64 119.91,55.26 119.46,54.82 118.78,54.82 118.77,54.82 118.66,54.84 118.55,54.82 118.54,54.82 117.78,54.82 117.77,54.82 117.66,54.84 117.55,54.82 117.54,54.82 116.78,54.82 116.77,54.82 116.66,54.84 116.55,54.82 116.54,54.82 116.05,54.82 115.6,55.26 115.6,55.27 115.52,55.38 115.42,55.45 115.41,55.45 115.39,55.47 115.27,55.48 115.21,55.47 114.96,55.47 114.77,55.28 114.53,55.28 114.45,55.37 114.45,55.71 114.51,55.77 116.73,55.77 116.81,55.69 116.82,55.68 117.15,55.41 117.5,55.65 117.5,55.67 118.05,56.22 118.13,56.22 118.19,56.28
+APU_CORE_NB on BOTTOM (solid shape): outline of 193 points within 138.2,45.74 147.78,55.33
+APU_CORE_NB on BOTTOM (solid shape): outline of 803 points within 115.4,53.74 122.89,62.5
+APU_CORE_NB on IN2 (solid shape): outline of 169 points within 118.89,57.23 122.19,62.69
+APU_CORE_NB on IN2 (solid shape): outline of 1399 points within 112.03,50.82 123.4,62.63
+APU_CORE_NB on TOP: 144.22,13.04 145.04,13.04 145.7,12.38 145.7,11.59 145.52,11.41 144.58,11.41 143.85,12.15 143.85,12.67
+APU_CORE_NB on BOTTOM: 144.76,11.75 145.17,11.75 145.32,11.6 145.88,11.6 146.58,12.3 146.58,12.86 146.06,13.38 145.42,13.38 144.58,12.54 144.58,11.93
+APU_CORE_NB on VCC: 124.71,41.42 123.44,42.69 109.47,42.69 108.86,43.3 108.86,52.22 113.66,52.22 114.07,52.62 114.07,53.63 114.96,54.52 114.96,55.79 115.31,56.15 131.32,56.15 132.46,57.3 135.3,57.3 136.44,56.15 146.07,56.15 146.07,54.9 147.09,53.89 147.09,43.68 146.09,42.69 142.92,42.69 141.65,41.42
+BIF_VDDC on TOP (solid shape): 114.19,116.64 114.19,116.61 114.39,116.41 114.57,116.41 114.63,116.35 114.63,115.78 113.19,115.78 113.1,115.87 112.03,115.87 111.85,116.05 111.85,116.59 112.03,116.77 114.07,116.77
+BIF_VDDC on TOP (solid shape): 111.53,123.46 112.16,123.46 112.22,123.4 112.22,122.45 112.03,122.26 112.03,121.18 111.84,120.99 111.15,120.99 110.64,121.49 110.31,121.49 110.13,121.67 110.13,123.38 110.32,123.56 110.34,123.83 110.35,123.93 110.43,123.97 111.02,123.97
+BIF_VDDC on BOTTOM (solid shape): 112.99,116.48 113.04,116.42 113.12,116.35 113.16,116.35 113.3,116.32 113.44,116.35 113.45,116.35 113.49,116.35 113.56,116.41 114.01,116.41 114.14,116.29 114.19,116.29 114.57,115.91 114.57,115.59 114.38,115.4 114.18,115.4 114.17,115.41 114.09,115.56 113.94,115.65 113.86,115.66 113.62,115.91 113.57,115.97 113.51,116.02 113.48,116.04 113.15,116.05 112.93,115.8 112.93,115.78 112.54,115.4 112.35,115.4 112.16,115.59 112.16,115.84 112.69,116.37 112.75,116.42 112.81,116.48
+BIF_VDDC on IN2 (solid shape): outline of 338 points within 110.26,115.84 114,123.91
+CHGRTC on BOTTOM (solid shape): 35.2,5.23 35.2,2.75 35.14,2.69 34.12,2.69 33.93,2.88 33.93,4.53 33.23,5.23 32.41,5.23 32.21,5.42 32.21,6.37 32.34,6.5 33.93,6.5
+DCBAT_CAM on BOTTOM (solid shape): 223.54,49.23 224.56,49.23 224.62,49.17 224.62,48.53 224.49,48.41 222.17,48.41 222.02,48.56 221.41,48.56 221.22,48.75 221.22,49.55 221.3,49.64 223.13,49.64
+EC_VCCA on TOP (solid shape): 165.52,36.01 165.52,35.19 165.31,34.98 163.22,34.98 163.04,35.16 163.04,36.21 163.1,36.27 165.25,36.27
+FB0_VREFCL on BOTTOM (solid shape): 145.05,128.22 145.05,127.53 144.93,127.4 144.23,127.4 143.88,127.05 143.87,127.05 143.66,126.67 143.98,126.37 143.99,126.36 144.42,125.94 144.42,125.49 144.29,125.37 144.2,125.37 144.19,125.39 144.1,125.5 143.97,125.57 143.96,125.57 142.98,126.56 142.98,126.56 142.39,127.15 142.39,128.22 142.51,128.35 144.93,128.35
+FB0_VREFDL on TOP (solid shape): 153.56,124.48 153.56,122.13 153.37,121.94 152.1,121.94 151.66,121.49 151.66,119.72 151.53,119.59 150.9,119.59 150.77,119.72 150.77,121.11 150.01,121.87 150.01,122.19 150.29,122.47 150.36,122.48 150.43,122.51 150.91,122.51 150.92,122.5 151.07,122.47 151.22,122.5 151.23,122.51 151.47,122.51 151.91,122.95 151.91,123.95 151.98,124.05 152.09,124.02 152.55,123.95 152.69,124.4 152.69,124.49 152.78,124.54 153.5,124.54
+FB1_VREFCL on BOTTOM (solid shape): 144.55,98.38 144.55,97.68 144.76,97.47 144.82,97.39 144.89,97.33 145.18,97.05 145.18,96.94 145.75,96.37 145.75,95.46 145.56,95.27 143.34,95.27 143.21,95.4 143.21,95.97 144.1,96.86 144.1,97.05 144.15,97.1 144.15,97.42 144.16,97.42 144.16,97.99 144.15,98 144.15,98.37 144.23,98.44 144.48,98.44
+FB1_VREFDL on TOP (solid shape): 152.04,103.59 152.04,102.82 152.93,101.94 153.69,101.94 153.75,101.87 153.75,99.65 153.63,99.52 152.23,99.52 150.13,101.62 150.13,102 150.17,102.03 150.17,103.11 150.83,103.78 151.85,103.78
+FB1_VREFDL on BOTTOM (solid shape): 138.58,102.44 138.58,101.78 138.37,101.58 138.37,101.48 138.07,101.17 137.82,101.17 137.69,101.3 137.69,102.57 137.75,102.63 138.39,102.63
+INV_PWR_SRC on TOP (solid shape): 227.35,53.1 227.35,52.34 227.48,52.22 229.83,52.22 229.95,52.09 229.95,51.33 229.92,51.25 229.83,51.23 229.41,50.88 229.83,50.53 229.92,50.51 229.95,50.43 229.95,49.61 229.7,49.36 228.96,49.36 228.92,49.4 226.44,49.4 226.4,49.36 226.08,49.36 225.89,49.17 225.89,48.21 225.76,48.09 224.81,48.09 224.56,48.34 224.56,52.91 224.94,53.29 227.16,53.29
+INV_PWR_SRC on BOTTOM (solid shape): 224.11,51.14 228.97,51.14 229.19,50.91 229.19,49.48 229.06,49.36 224.61,49.36 224.61,49.36 223.67,49.36 222.91,50.12 222.91,50.3 222.7,50.5 221.29,50.5 221.25,50.54 221.25,51.64 221.32,51.71 223.54,51.71
+LAN_VDD33 on TOP (solid shape): outline of 228 points within 20.91,111.71 39.9,123.84
+LAN_VDD33 on BOTTOM (solid shape): 28.21,120.8 28.72,120.8 28.72,121.3 29.04,121.3 29.1,121.24 29.1,119.46 28.98,119.33 26.44,119.33 26.06,119.72 26.06,121.11 26.25,121.3 28.21,121.3
+LAN_VDD33 on BOTTOM (solid shape): 37.04,115.27 38.63,115.27 38.78,115.12 38.78,112.79 39,112.58 39,112.26 38.83,112.1 37.36,112.1 37.23,112.22 37.23,112.92 37.8,113.49 37.8,114.25 37.68,114.38 36.91,114.38 34.95,116.35 34.95,116.54 35.01,116.6 35.71,116.6
+LAN_VDDREG on BOTTOM (solid shape): 41.23,113.75 41.23,112.48 40.91,112.16 39.71,112.16 39.39,112.48 39.39,112.86 39.45,112.86 39.45,113.75 39.45,113.75 39.4,113.78 39.41,113.83 39.45,113.87 41.1,113.87
+LAN_VDDREG on IN1 (solid shape): outline of 286 points within 34.01,112.16 41.71,121.91
+LCDVDD on TOP (solid shape): 227.46,46.42 227.46,45.04 226.45,44.03 226.45,44.02 225.05,42.63 224.98,42.63 224.67,42.32 223.51,42.32 223.29,42.55 223.29,43.83 223.67,44.21 224.87,44.21 226.27,45.61 226.27,45.69 226.27,46.37 226.4,46.5 226.41,46.5 226.47,46.56 227.31,46.56
+LCDVDD_CONN on TOP (solid shape): 226.14,47.14 226.14,45.74 224.81,44.4 223.41,44.4 223.35,44.47 222.71,44.47 222.4,44.15 222.4,43.64 222.21,43.45 221.7,43.45 221.25,43.9 221.25,45.74 221.57,46.06 222.33,46.06 222.91,45.48 223.98,45.48 224.11,45.61 224.11,47.33 224.24,47.45 225.25,47.45 225.38,47.58 225.7,47.58
+LCDVDD_CONN on BOTTOM (solid shape): 226.27,47.52 226.27,45.93 226.14,45.8 224.94,45.8 224.87,45.87 224.87,46.25 224.75,46.37 223.48,46.37 223.41,46.44 223.41,47.64 223.48,47.71 226.08,47.71
+MEM_VREF on TOP (solid shape): 93.05,57.74 93.05,56.22 93.24,56.03 94.76,56.03 94.83,55.96 94.83,55.95 94.77,55.69 94.83,55.43 94.83,54.37 94.76,54.31 94.32,54.31 94.19,54.44 94.19,55.2 94,55.39 92.48,55.39 92.35,55.52 92.35,57.74 92.41,57.8 92.98,57.8
+PCIE_VDDC on TOP (solid shape): outline of 257 points within 110.76,116.92 118.2,126.11
+PCIE_VDDC on BOTTOM (solid shape): outline of 447 points within 111.08,116.41 118,120.54
+RTC_APU_R on IN1 (solid shape): 122.37,46.56 122.45,46.52 122.46,46.43 122.63,46 123.09,46.1 123.17,46.14 123.25,46.1 123.7,46 123.87,46.43 123.88,46.52 123.97,46.56 124,46.56 124.04,46.54 124.04,46.49 124.32,45.95 124.69,46.43 124.7,46.52 124.78,46.56 124.86,46.56 125.24,46.18 125.24,45.74 124.86,45.35 124.77,45.33 124.69,45.39 124.42,45.61 124.09,45.49 124.01,45.45 123.93,45.49 123.63,45.62 123.35,45.45 123.28,45.41 123.2,45.43 122.86,45.52 122.61,45.27 122.6,45.23 121.62,45.23 121.58,45.27 121.56,45.39 121.66,45.45 121.94,46.05 121.33,45.77 121.27,45.67 121.16,45.69 120.92,45.93 120.92,46.44 121.05,46.56
+RTCVCC on BOTTOM (solid shape): 36.47,6.81 37.99,6.81 38.56,7.38 39.71,7.38 39.96,7.13 39.96,3 39.71,2.75 38.56,2.75 38.5,2.81 38.5,5.03 37.8,5.73 35.26,5.73 34.31,6.69 34.31,7.19 34.56,7.45 35.83,7.45
+SPI_VCC on BOTTOM (solid shape): 123.32,19.7 123.32,19.01 122.07,17.76 122.07,17.06 121.81,16.81 121.81,14.43 121.75,14.36 121.11,14.36 120.86,14.62 120.86,15.26 120.73,15.39 118.45,15.39 118.32,15.51 118.32,17.64 118.92,18.24 121.66,18.24 121.81,18.39 121.81,19.04 122.6,19.83 123.2,19.83
+SPLL_VDDC on TOP (solid shape): 121.55,87.39 121.75,87.33 121.95,87.39 122.48,87.39 122.65,87.22 122.61,87.19 122.52,86.92 122.65,86.68 122.65,85.62 122.56,85.53 121.32,85.53 121.2,85.66 121.02,85.66 120.78,85.89 120.78,87.28 120.88,87.39
+VGA_CORE on TOP (solid shape): 95.27,127.78 95.27,126.64 93.43,124.8 88.03,124.8 87.84,124.61 87.84,123.59 87.71,123.46 87.46,123.46 87.33,123.34 87.33,120.73 87.78,120.29 87.78,118.13 87.65,118 85.36,118 85.11,118.26 85.11,127.34 85.75,127.97 95.08,127.97
+VGA_CORE on TOP (solid shape): 114.95,110.96 114.95,110.46 114.99,110.42 114.99,110.34 115.02,110.34 115.02,110.19 114.51,109.68 114.51,109.24 115.21,108.54 115.21,108.29 115.08,108.16 114.57,108.16 113.88,108.85 113.88,110.07 114.07,110.29 114.04,110.58 114.04,111.12 114.07,111.14 114.76,111.14
+VGA_CORE on TOP (solid shape): 110.95,116.1 110.95,115.59 110.89,115.53 110.64,115.52 110.51,115.4 110.51,114.95 110.83,114.64 111.34,114.64 111.46,114.76 111.91,114.76 111.97,114.7 111.97,113.37 112.16,113.18 112.16,113.17 112.17,113.17 112.35,112.98 112.73,112.98 112.86,112.86 112.86,111.33 112.73,111.21 112.42,111.21 112.18,110.97 112.15,110.97 111.91,110.73 111.84,110.67 111.69,110.51 110.38,110.51 109.56,111.33 109.56,112.16 109.62,112.22 110.19,112.22 110.32,112.1 110.32,111.52 110.76,111.08 111.27,111.08 111.4,111.21 111.4,111.78 111.34,111.84 111.34,113.43 110.57,114.19 109.88,114.19 109.75,114.32 109.75,115.27 110.32,115.84 110.32,116.04 110.32,116.08 110.34,116.11 110.38,116.16 110.89,116.16
+VGA_CORE on TOP (solid shape): 112.61,109.18 112.61,109.05 113.06,108.59 113.06,108.53 113.12,108.53 113.24,108.41 113.24,107.59 113.11,107.46 112.61,107.46 112.42,107.27 112.42,106.57 112.48,106.5 112.48,106.49 112.5,106.49 112.61,106.38 112.73,106.38 112.92,106.19 112.92,104.86 112.8,104.73 112.16,104.73 112.1,104.79 112.1,104.96 112.1,104.97 112.15,105.15 112.1,105.32 112.1,105.33 112.1,105.63 112.18,105.86 112.1,106.1 112.1,107.17 112.12,107.23 112.48,107.59 112.48,108.35 112.42,108.41 111.65,108.41 111.34,108.1 110.64,108.1 110.28,108.46 110.25,108.49 110.13,108.6 109.37,108.6 109.3,108.67 109.3,109.11 109.37,109.17 110.38,109.17 110.76,108.79 111.4,108.79 111.78,109.17 111.78,109.34 111.88,109.44 111.88,109.62 111.9,109.63 112.15,109.63
+VGA_CORE on TOP (solid shape): 114.45,115.08 114.45,115.06 114.64,114.87 114.64,114.32 114.74,114.21 115.61,114.21 115.78,114.38 116.73,114.38 116.86,114.25 116.86,113.81 117.09,113.58 117.07,113.55 117.02,113.14 117.22,112.77 117.25,112.74 117.23,112.71 117.13,112.27 117.33,111.86 117.37,111.82 117.37,111.4 117.11,111.14 116.67,111.14 116.66,111.16 116.54,111.27 116.54,111.4 116.67,111.52 116.67,111.53 116.73,111.59 116.73,112.42 116.48,112.67 115.92,112.67 115.6,112.35 114.96,112.35 114.45,112.86 113.78,112.86 113.56,113.08 113.56,113.24 113.7,113.38 113.8,113.38 113.8,113.48 113.94,113.62 113.94,114.76 113.8,114.9 113.8,114.99 113.79,115 113.79,115.06 113.73,115.06 113.56,115.23 113.56,115.46 113.69,115.59 113.94,115.59
+VGA_CORE on BOTTOM (solid shape): 86.19,130.32 95.52,130.32 96.03,129.81 96.03,127.46 95.21,126.64 94.25,126.64 94.03,126.41 94.03,125.08 92.22,123.27 89.81,123.27 88.73,122.19 88.73,117.75 87.78,116.79 84.16,116.79 83.01,115.65 79.01,115.65 78.95,115.72 78.95,116.6 78.06,116.6 78.06,115.65 78,115.59 76.86,115.59 76.79,115.65 76.79,119.72 77.05,119.97 78.38,119.97 79.2,120.8 79.2,128.67 79.9,129.37 79.91,129.37 79.95,129.41 82.58,129.41 82.59,129.43 82.59,130.21 81.66,130.21 81.61,130.26 81.61,131.78 81.79,131.97 84.54,131.97
+VGA_CORE on BOTTOM (solid shape): outline of 1236 points within 109.3,107.59 117.11,116.22
+VGA_CORE on IN1 (solid shape): outline of 5353 points within 77.11,105.68 117.43,135.91
+VGA_CORE on VCC: 99.57,105.05 96.86,107.76 96.86,110.87 96.2,111.52 93.09,111.52 89.03,115.59 77.85,115.59 77.17,116.26 77.17,119.42 78.82,121.07 78.82,127.67 79.56,128.42 94.02,128.42 99.99,122.45 117.11,122.45 117.11,105.05
+VGA_CORE_M70 on TOP (solid shape): 108.07,111.46 108.12,111.46 108.35,111.46 109.18,110.64 109.18,110.19 109.11,110.13 109.11,109.56 109.18,109.49 109.18,109.17 109.11,109.11 109.11,108.54 109.18,108.48 109.18,108.22 109.11,108.16 107.34,108.16 107.14,108.35 107.14,110.13 107.34,110.32 107.34,111.27 107.53,111.46 108.03,111.46
+VGA_CORE_M70 on BOTTOM (solid shape): 107.58,111.39 107.7,111.37 107.82,111.39 107.83,111.4 108.03,111.4 108.1,111.33 108.1,110.7 108.35,110.44 108.61,110.44 108.8,110.64 109.11,110.64 109.18,110.57 109.18,110.1 109.12,109.9 109.18,109.7 109.18,109.1 109.12,108.9 109.18,108.7 109.18,108.1 109.14,108.02 109.12,107.93 109.12,107.91 108.86,107.65 107.72,107.65 107.23,108.14 107.23,108.15 107.2,108.24 107.14,108.32 107.14,109.08 107.23,109.3 107.14,109.52 107.14,110 107.27,110.13 107.27,110.7 107.14,110.83 107.14,111.21 107.34,111.4 107.57,111.4
+VGA_CORE_M70 on BOTTOM (solid shape): 113.69,107.21 113.69,106.83 113.49,106.63 113.47,106.63 113.39,106.61 113.31,106.57 112.49,106.57 112.19,106.61 111.98,106.39 111.98,106.37 111.83,106.22 111.81,106.22 111.56,106.1 111.47,105.84 111.47,105.82 111.36,105.71 111.33,105.74 111.01,105.82 110.78,105.59 110.77,105.56 110.32,105.56 110.19,105.68 110.18,105.68 110.16,105.7 109.83,105.82 109.56,105.56 109.18,105.56 109.11,105.62 109.11,106 109.88,106.76 110.04,106.76 110.13,106.71 110.13,106.61 110.49,106.1 110.73,106.68 110.7,106.75 110.74,106.82 110.83,106.96 110.85,107.14 110.85,107.16 110.95,107.27 111.34,107.27 111.47,107.14 111.47,107.13 111.85,106.97 112.13,107.28 112.13,107.3 112.16,107.33 113.56,107.33
+VGA_CORE_M70 on IN2 (solid shape): outline of 392 points within 106.89,104.98 110.7,111.59
+VREFB_CA on TOP (solid shape): 44.9,45.88 44.9,44.39 44.84,44.33 43.25,44.33 43.07,44.15 43.07,41.35 42.95,41.22 42.53,41.22 42.4,41.36 42.4,45.16 42.54,45.3 43.84,45.3 43.96,45.42 43.96,45.42 44.03,45.48 44.03,45.93 44.09,45.99 44.79,45.99
AUD_PORTA_L_R_B on TOP (solid shape): 12.28,13.73 12.28,12.53 12.15,12.4 10.88,12.4 10.69,12.59 10.69,13.86 10.75,13.92 12.09,13.92
AUD_PORTA_R_R_B on TOP (solid shape): 6.81,24.53 6.81,22.94 6.56,22.69 5.35,22.69 5.16,22.88 5.16,23.64 5.42,23.89 5.42,24.53 5.61,24.72 6.62,24.72
BST1_APU on TOP (solid shape): 163.66,62.44 164.36,62.44 164.55,62.25 164.55,62.12 164.49,62.06 163.41,62.06 163.22,62.25 161.63,62.25 161.56,62.31 161.56,62.88 161.69,63.01 163.09,63.01
BST1_VGA on TOP (solid shape): 56.66,121.44 56.66,121.12 57.23,120.55 57.8,120.55 57.93,120.67 57.93,121.05 58.57,121.05 58.63,120.99 58.63,120.16 58.6,120.13 57.28,120.13 57.25,120.16 57.12,120.16 57.06,120.22 57.05,120.22 56.32,120.95 56.32,120.97 56.17,121.27 55.75,121.33 55.71,121.41 55.71,121.5 55.77,121.56 56.53,121.56
BST2_VGA on TOP (solid shape): 58.63,126.01 58.63,125.18 58.57,125.12 57.99,125.12 57.93,125.18 57.93,125.5 57.74,125.69 57.3,125.69 56.72,125.12 56.72,125.06 56.6,124.93 55.77,124.93 55.71,124.99 55.71,125.12 55.77,125.18 56.15,125.18 57.04,126.07 58.57,126.07
BST_1.2V on BOTTOM (solid shape): 87.52,107.21 87.52,105.75 87.27,105.49 87.27,104.28 87.24,104.25 87.12,104.25 87.06,104.31 87.06,105.76 86.76,106.06 86.76,107.21 86.82,107.27 87.46,107.27
BST_1.2V_R on BOTTOM (solid shape): 86.12,107.21 86.12,106.38 86.06,106.32 85.43,106.32 85.11,106.63 84.54,106.63 84.48,106.7 84.48,107.21 84.54,107.27 86.06,107.27
BST_3V on BOTTOM (solid shape): 174.92,50.84 174.92,49.93 174.65,49.65 174.65,48.41 174.58,48.34 174.45,48.34 174.39,48.41 174.39,49.17 174.13,49.43 174.13,50.77 174.25,50.89 174.87,50.89
BST_5V on BOTTOM (solid shape): 196.74,40.59 196.74,39.9 196.17,39.32 196.17,38.37 196.11,38.31 195.98,38.31 195.92,38.37 195.92,39.07 195.66,39.32 195.66,40.59 195.73,40.66 196.68,40.66
BST_+1.35VGPU on BOTTOM (solid shape): 155.47,91.84 155.47,91.2 155.34,91.08 155.34,89.17 155.28,89.11 155.15,89.11 155.09,89.17 155.09,89.74 154.39,90.44 154.39,91.84 154.45,91.9 155.4,91.9
BST_+1.35VGPU_R on BOTTOM (solid shape): 155.47,93.24 155.47,92.6 155.4,92.54 154.52,92.54 154.07,92.09 153.44,92.09 153.37,92.16 153.37,92.73 153.44,92.79 153.68,92.79 154.19,93.3 155.4,93.3
BST_NB on TOP (solid shape): 164.8,58.37 164.8,57.42 164.49,57.1 164.49,56.09 164.42,56.03 163.6,56.03 163.47,56.15 163.47,57.42 164.42,58.38 164.44,58.38 164.5,58.4 164.55,58.44 164.74,58.44
BST_VDDP_ALWP on TOP (solid shape): 158.96,36.22 158.96,35.58 158.58,35.2 158.58,34.12 158.64,34.05 158.64,33.29 158.52,33.17 158.2,33.17 158.01,33.36 158.01,36.21 158.04,36.24 158.94,36.24
DP_VSSR on BOTTOM (solid shape): outline of 312 points within 101.05,109.62 104.67,112.1
DP_VSSR on BOTTOM (solid shape): outline of 717 points within 100.99,113.94 105.56,118.51
DP_VSSR on IN1 (solid shape): outline of 113 points within 100.92,109.62 105.49,116.22
ECAGND on TOP (solid shape): 166.07,26.97 167.28,26.97 167.66,26.59 167.66,25.67 167.34,25.35 166.58,25.35 166.14,25.79 164.7,25.79 164.36,26.13 164.36,27.11 164.54,27.28 165.76,27.28
ENLDO_3V5V on BOTTOM (solid shape): 176.55,45.99 177.63,45.99 177.76,45.87 177.76,45.55 177.64,45.43 177.09,45.43 177.08,45.42 176.95,45.42 176.76,45.23 176.23,45.23 176.17,45.29 176.17,45.99 176.3,46.12 176.42,46.12
INT-SPK-L+ on TOP (solid shape): 36.02,27.88 36.02,27.01 35.95,26.94 32.72,26.94 32.66,26.88 30.69,26.88 30.62,26.88 30.56,26.94 30.56,27.05 30.64,27.13 32.53,27.13 32.85,27.45 34.63,27.45 35.14,27.96 35.94,27.96
INT-SPK-L- on TOP (solid shape): 36.02,29.16 36.02,28.28 35.96,28.21 35.07,28.21 34.5,27.64 32.85,27.64 32.5,27.29 30.63,27.29 30.57,27.35 30.57,27.45 30.63,27.51 32.21,27.51 32.72,28.02 33.99,28.02 35.2,29.23 35.96,29.23
INT-SPK-R+ on TOP (solid shape): 36.02,31.7 36.02,30.82 35.9,30.69 35.07,30.69 33.29,28.91 32.66,28.91 31.83,28.09 30.62,28.09 30.55,28.15 30.55,28.27 30.63,28.34 31.52,28.34 32.53,29.36 33.04,29.36 34.95,31.26 34.95,31.64 35.07,31.77 35.96,31.77
INT-SPK-R- on TOP (solid shape): 36.02,30.43 36.02,29.61 35.96,29.55 35.2,29.55 33.93,28.28 32.72,28.28 32.15,27.7 30.63,27.7 30.56,27.77 30.56,27.83 30.63,27.89 31.83,27.89 32.66,28.72 33.36,28.72 35.14,30.5 35.96,30.5
IR_GND on BOTTOM (solid shape): 224.56,38.18 224.56,37.48 224.43,37.36 223.29,37.36 223.16,37.48 223.16,37.99 223.41,38.25 224.49,38.25
JACK_PLUG_DET on IN2 (solid shape): 9.61,24.15 9.61,22.81 9.42,22.62 8.15,22.62 7.96,22.81 7.96,24.21 8.15,24.4 9.35,24.4
JACK_SENSE# on IN2 (solid shape): 12.97,23.64 12.97,22.75 12.85,22.62 10.88,22.62 10.69,22.81 10.69,23.64 10.82,23.77 12.85,23.77
LDO_+1.35VGPU on BOTTOM (solid shape): 155.02,87.58 155.02,87.01 154.96,86.95 153.94,86.95 151.98,84.98 151.98,84.47 151.85,84.35 151.34,84.35 151.28,84.41 151.28,84.98 152.94,86.64 152.95,86.64 152.95,86.66 153.94,87.65 154.96,87.65
LG1_APU on TOP (solid shape): 154.83,64.22 154.83,63.07 154.71,62.95 153.63,62.95 153.5,63.07 153.5,64.15 153.63,64.28 154.77,64.28
LG1_APU on TOP (solid shape): 164.55,61.04 164.55,60.91 164.49,60.85 163.15,60.85 162.77,60.47 161.75,60.47 161.69,60.53 161.69,60.98 161.79,61.07 163.02,61.07 163.12,61.17 164.42,61.17
LG1_APU on BOTTOM (solid shape): 150.39,64.28 150.39,63.07 150.26,62.95 149.25,62.95 149.12,63.07 149.12,64.28 149.25,64.41 150.26,64.41
LG1_APU on IN2 (solid shape): 155.53,64.22 155.53,63.2 155.4,63.07 149.25,63.07 149.12,63.2 149.12,64.22 149.18,64.28 155.47,64.28
LG1_APU on IN2 (solid shape): 162.9,60.98 162.9,60.34 162.77,60.22 161.31,60.22 161.25,60.28 161.25,60.98 161.37,61.11 162.77,61.11
LG1_VGA on TOP (solid shape): 68.6,116.48 68.6,115.21 68.47,115.08 67.46,115.08 67.33,115.21 67.33,116.48 67.46,116.6 68.47,116.6
LG1_VGA on TOP (solid shape): 57.55,122.71 57.57,122.71 58.44,122.71 58.57,122.58 58.57,122.32 58.44,122.2 57.68,122.2 57.42,122.45 56.79,122.45 56.72,122.52 55.71,122.52 55.64,122.58 55.64,122.71 55.71,122.77 57.49,122.77
LG1_VGA on BOTTOM (solid shape): 68.6,120.92 68.6,119.78 68.54,119.72 67.46,119.72 67.33,119.84 67.33,120.86 67.46,120.99 68.54,120.99
LG1_VGA on IN1 (solid shape): 68.73,120.8 68.73,115.46 68.6,115.33 67.52,115.33 67.33,115.52 67.33,120.8 67.46,120.92 68.6,120.92
LG1_VGA on IN2 (solid shape): 60.03,122.64 60.03,122.01 59.99,121.97 57.9,121.97 57.49,122.39 57.49,122.52 57.68,122.71 58.63,122.71 58.69,122.77 59.9,122.77
LG1_VGA on IN2 (solid shape): 67.27,120.99 68.47,120.99 68.6,120.86 68.6,120.29 68.47,120.16 66.7,120.16 66.57,120.29 66.57,121.11 66.7,121.24 67.01,121.24
LG2_VGA on TOP (solid shape): 68.6,122.26 68.6,121.3 68.41,121.11 67.33,121.11 67.27,121.18 67.27,122.26 67.39,122.38 68.47,122.38
LG2_VGA on TOP (solid shape): 58.31,123.98 58.31,123.79 58.18,123.66 56.98,123.66 56.91,123.72 55.71,123.72 55.64,123.79 55.64,123.85 55.71,123.91 57.17,123.91 57.36,124.1 58.18,124.1
LG2_VGA on BOTTOM (solid shape): 68.66,126.64 68.66,125.68 68.54,125.56 67.46,125.56 67.33,125.68 67.33,126.7 67.39,126.76 68.54,126.76
LG2_VGA on IN2 (solid shape): 59.58,123.98 59.58,123.47 59.45,123.34 57.55,123.34 57.3,123.59 57.3,123.98 57.42,124.1 59.45,124.1
LG2_VGA on IN2 (solid shape): 68.54,122.07 68.54,121.24 68.47,121.18 67.39,121.18 67.33,121.24 67.33,122.13 67.46,122.26 68.35,122.26
LG2_VGA on IN2 (solid shape): 68.6,126.76 68.6,125.75 68.41,125.56 67.01,125.56 66.82,125.75 66.82,126.7 66.95,126.83 68.54,126.83
LG_1.2V on BOTTOM (solid shape): 78.38,101.81 78.89,101.81 79.01,101.68 79.01,101.36 78.89,101.24 77.11,101.24 77.05,101.3 77.05,101.75 77.11,101.81 78.38,101.81
LG_1.2V on BOTTOM (solid shape): 86.06,104.73 86.06,103.9 86,103.84 85.24,103.84 84.86,104.22 84.86,104.86 84.92,104.92 85.87,104.92
LG_1.2V on IN2 (solid shape): 79.01,101.81 79.01,101.43 78.89,101.3 77.11,101.3 77.05,101.36 77.05,101.81 77.17,101.94 78.89,101.94
LG_1.2V on IN2 (solid shape): 85.75,104.92 85.87,104.92 86.06,104.73 86.06,104.54 85.94,104.41 85.17,104.41 85.11,104.35 84.03,104.35 83.71,104.03 83.46,104.03 83.21,104.29 83.21,104.92 83.4,105.11 84.54,105.11 84.56,105.11 85.55,105.11
LG_NB on TOP (solid shape): 159.47,46.69 159.47,45.48 159.41,45.42 158.93,45.42 158.92,45.43 158.77,45.46 158.62,45.43 158.61,45.42 158.3,45.42 158.23,45.45 158.16,45.46 158.07,45.55 158.07,46.69 158.2,46.82 159.34,46.82
LG_NB on TOP (solid shape): 166.04,58.34 166.04,58.32 166.04,57.51 166.08,57.38 166.19,57.3 166.2,57.29 166.44,57.05 166.44,57.04 166.52,56.97 166.52,56.09 166.39,55.96 166.14,55.96 166.01,56.09 166.01,57.03 166.01,57.04 165.76,57.29 165.76,58.37 165.82,58.44 165.95,58.44
LG_NB on BOTTOM (solid shape): 154.9,46.63 154.9,45.61 154.77,45.48 153.96,45.48 153.95,45.49 153.86,45.51 153.76,45.51 153.73,45.5 153.63,45.61 153.63,46.63 153.75,46.75 154.77,46.75
LG_NB on IN2 (solid shape): 166.77,56.91 166.77,55.26 166.64,55.14 166.26,55.14 166.01,55.39 166.01,57.04 166.07,57.1 166.58,57.1
LG_NB on IN2 (solid shape): 160.1,46.63 160.1,45.74 159.91,45.55 156.42,45.55 156.41,45.55 156.25,45.59 156.1,45.55 156.09,45.55 153.69,45.55 153.63,45.61 153.63,46.63 153.75,46.75 159.98,46.75
LG_VDDP_ALWP on TOP (solid shape): 151.47,35.07 151.47,34.18 151.28,33.99 149.63,33.99 149.44,34.18 149.44,35.01 149.63,35.2 151.34,35.2
LG_VDDP_ALWP on TOP (solid shape): 161.37,34.24 161.37,33.29 161.31,33.23 160.42,33.23 160.29,33.36 160.29,33.99 160.68,34.37 161.25,34.37
LG_VDDP_ALWP on IN2 (solid shape): 152.29,35.1 152.29,34.02 152.04,33.77 151.15,33.77 150.9,34.02 150.9,35.04 151.09,35.23 152.17,35.23
LG_VDDP_ALWP on IN2 (solid shape): 161.31,34.24 161.31,33.29 161.12,33.1 159.98,33.1 159.85,33.23 159.85,34.18 160.04,34.37 161.18,34.37
LGATE_CHG on TOP (solid shape): 212.55,30.88 212.55,30.69 212.75,30.5 213.38,30.5 213.44,30.43 213.44,29.48 213.38,29.42 212.43,29.42 212.3,29.55 212.3,30.18 211.92,30.56 211.92,30.88 212.11,31.07 212.36,31.07
LGATE_CHG on TOP (solid shape): 210.15,42.53 210.17,42.53 210.22,42.48 210.66,42.48 210.71,42.42 211.84,42.42 211.93,42.33 211.93,42.17 211.88,42.12 210.51,42.12 210.38,42.25 209.42,42.25 209.39,42.22 209.33,42.19 209.19,42.19 209.05,42.33 209.05,42.52 209.26,42.73 209.95,42.73
LGATE_CHG on IN2 (solid shape): 211.48,43.07 211.48,42.5 211.28,42.31 209.25,42.31 209.13,42.44 209.13,42.87 209.45,43.2 211.35,43.2
LGATE_CHG on IN2 (solid shape): 213.38,31.26 213.38,30.24 213.06,29.93 212.43,29.93 211.98,30.37 211.98,31.32 212.11,31.45 213.19,31.45
LX1_APU on TOP (solid shape): 154.26,70.76 154.26,65.3 154.01,65.04 149.69,65.04 149.56,65.17 149.56,66.76 149.25,67.07 147.44,67.07 146.99,67.52 146.99,71.3 147.78,72.09 152.93,72.09
LX1_APU on TOP (solid shape): 161.18,62.76 161.18,62.18 161.88,61.49 163.01,61.49 164.42,61.49 164.49,61.42 164.49,61.36 164.42,61.3 163.07,61.3 163.02,61.3 162.96,61.23 161.56,61.23 161.44,61.11 160.55,61.11 160.42,61.23 160.42,62.76 160.48,62.82 161.12,62.82
